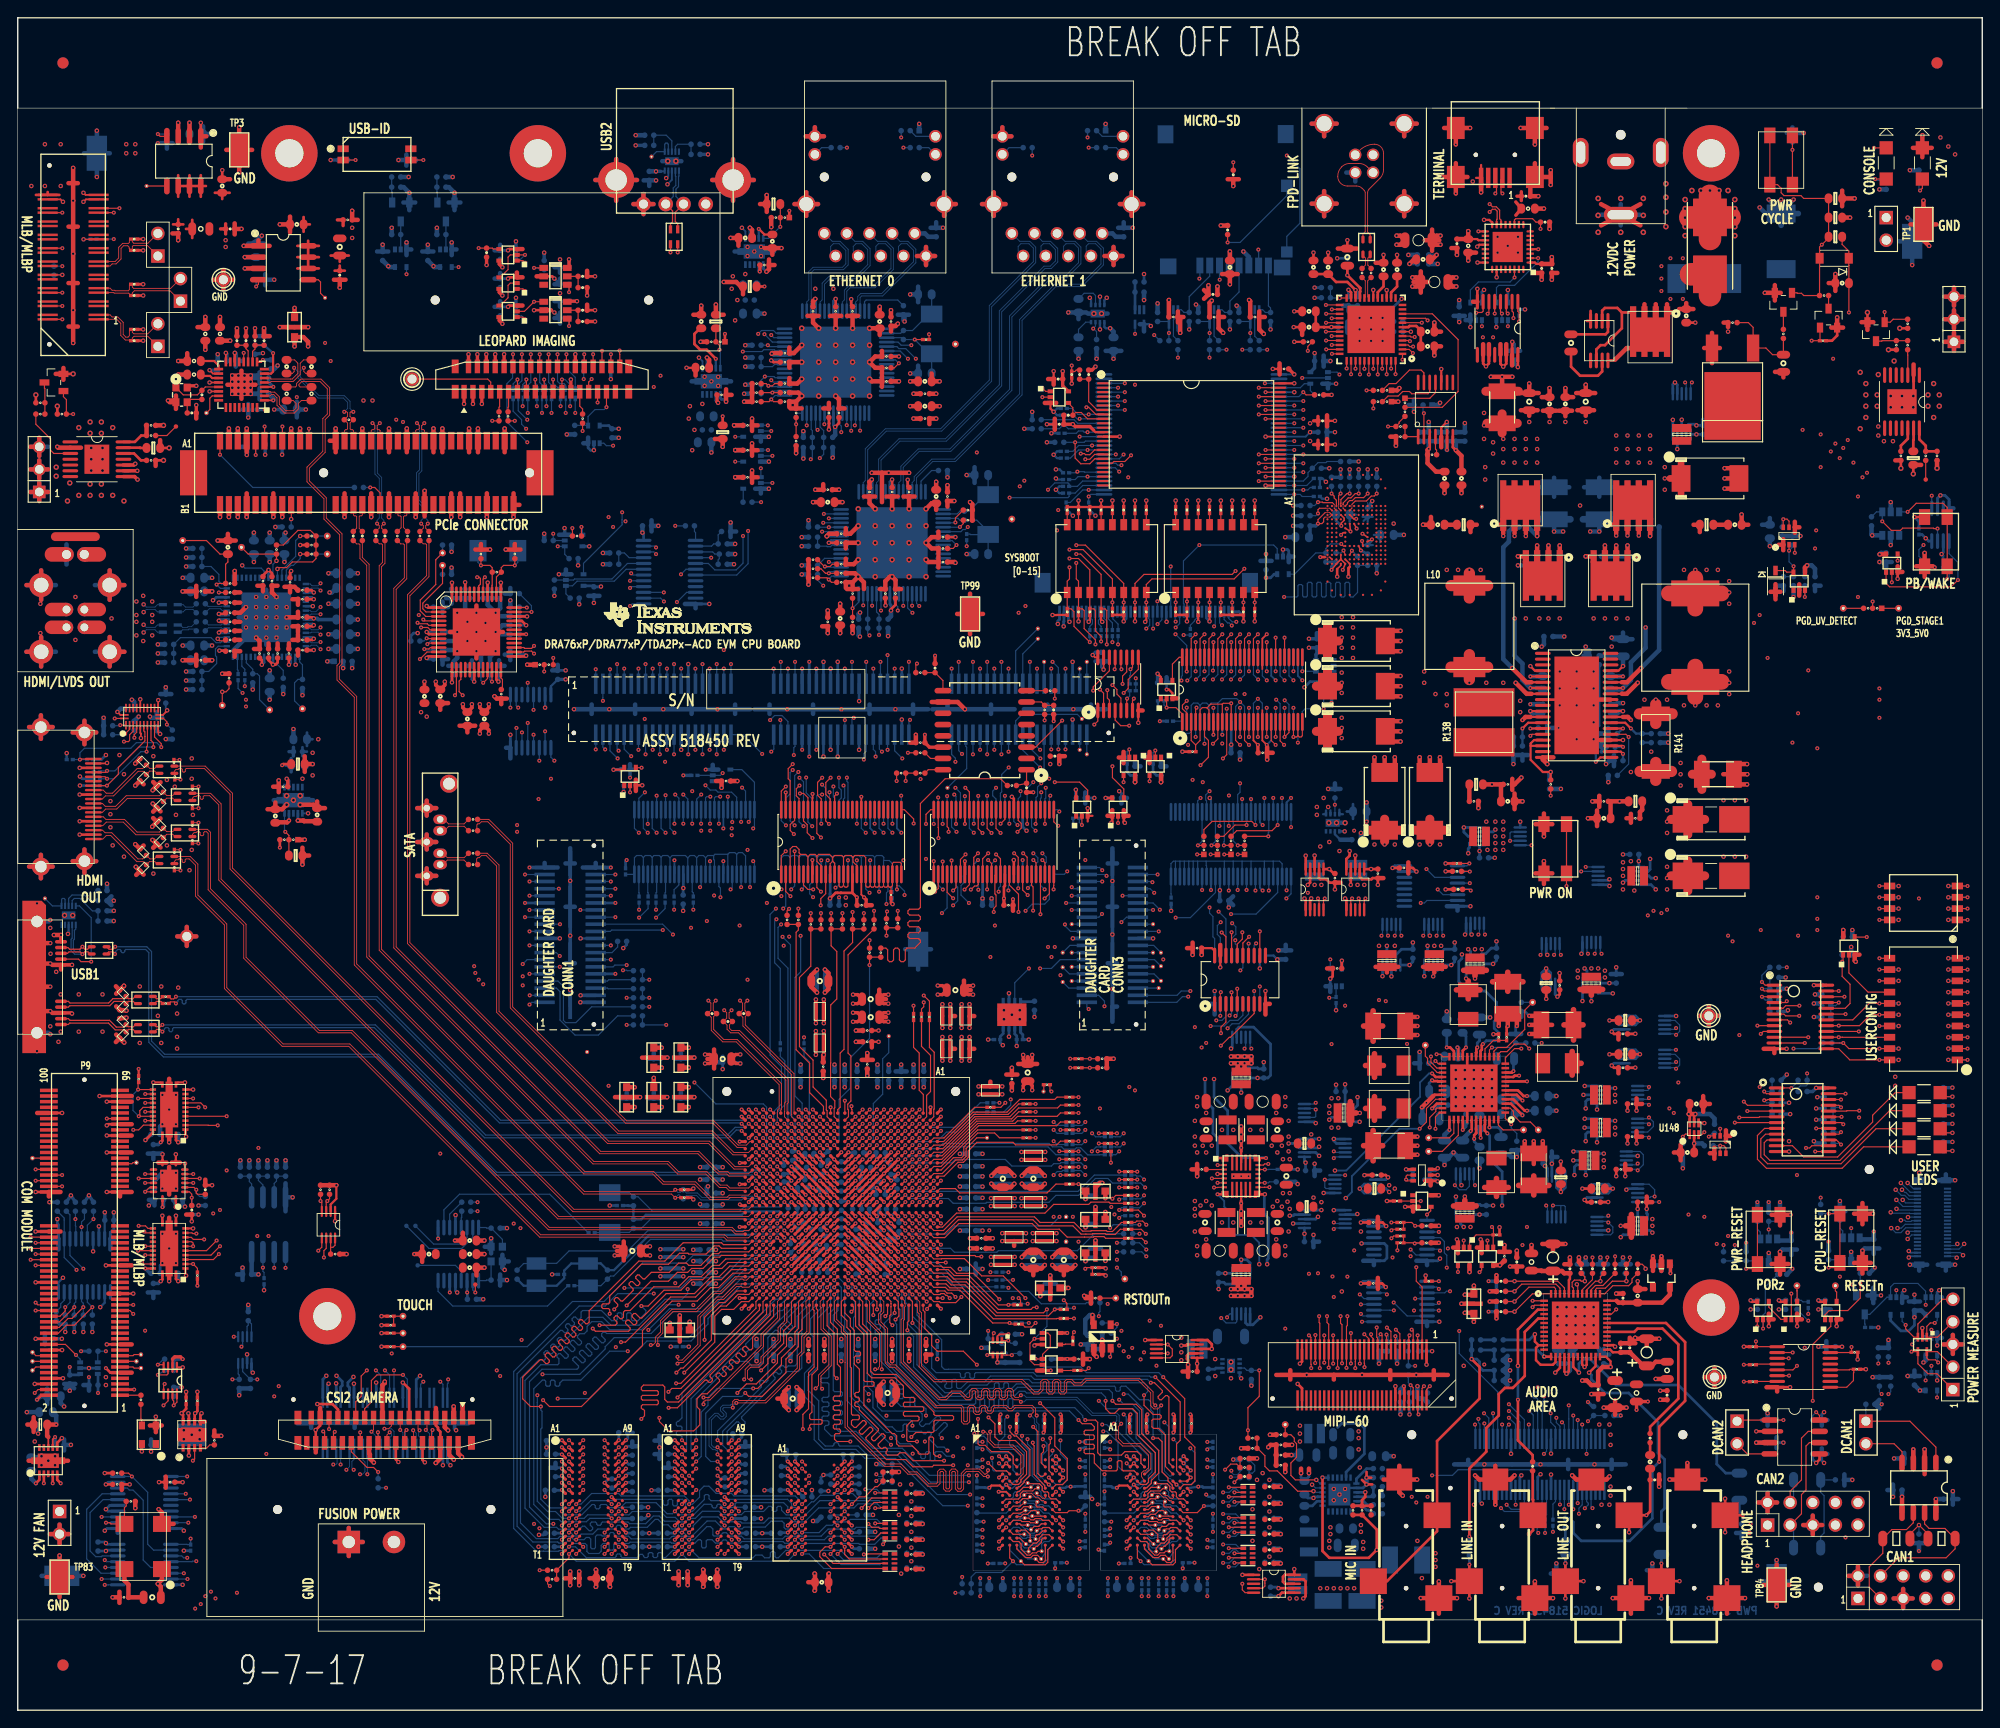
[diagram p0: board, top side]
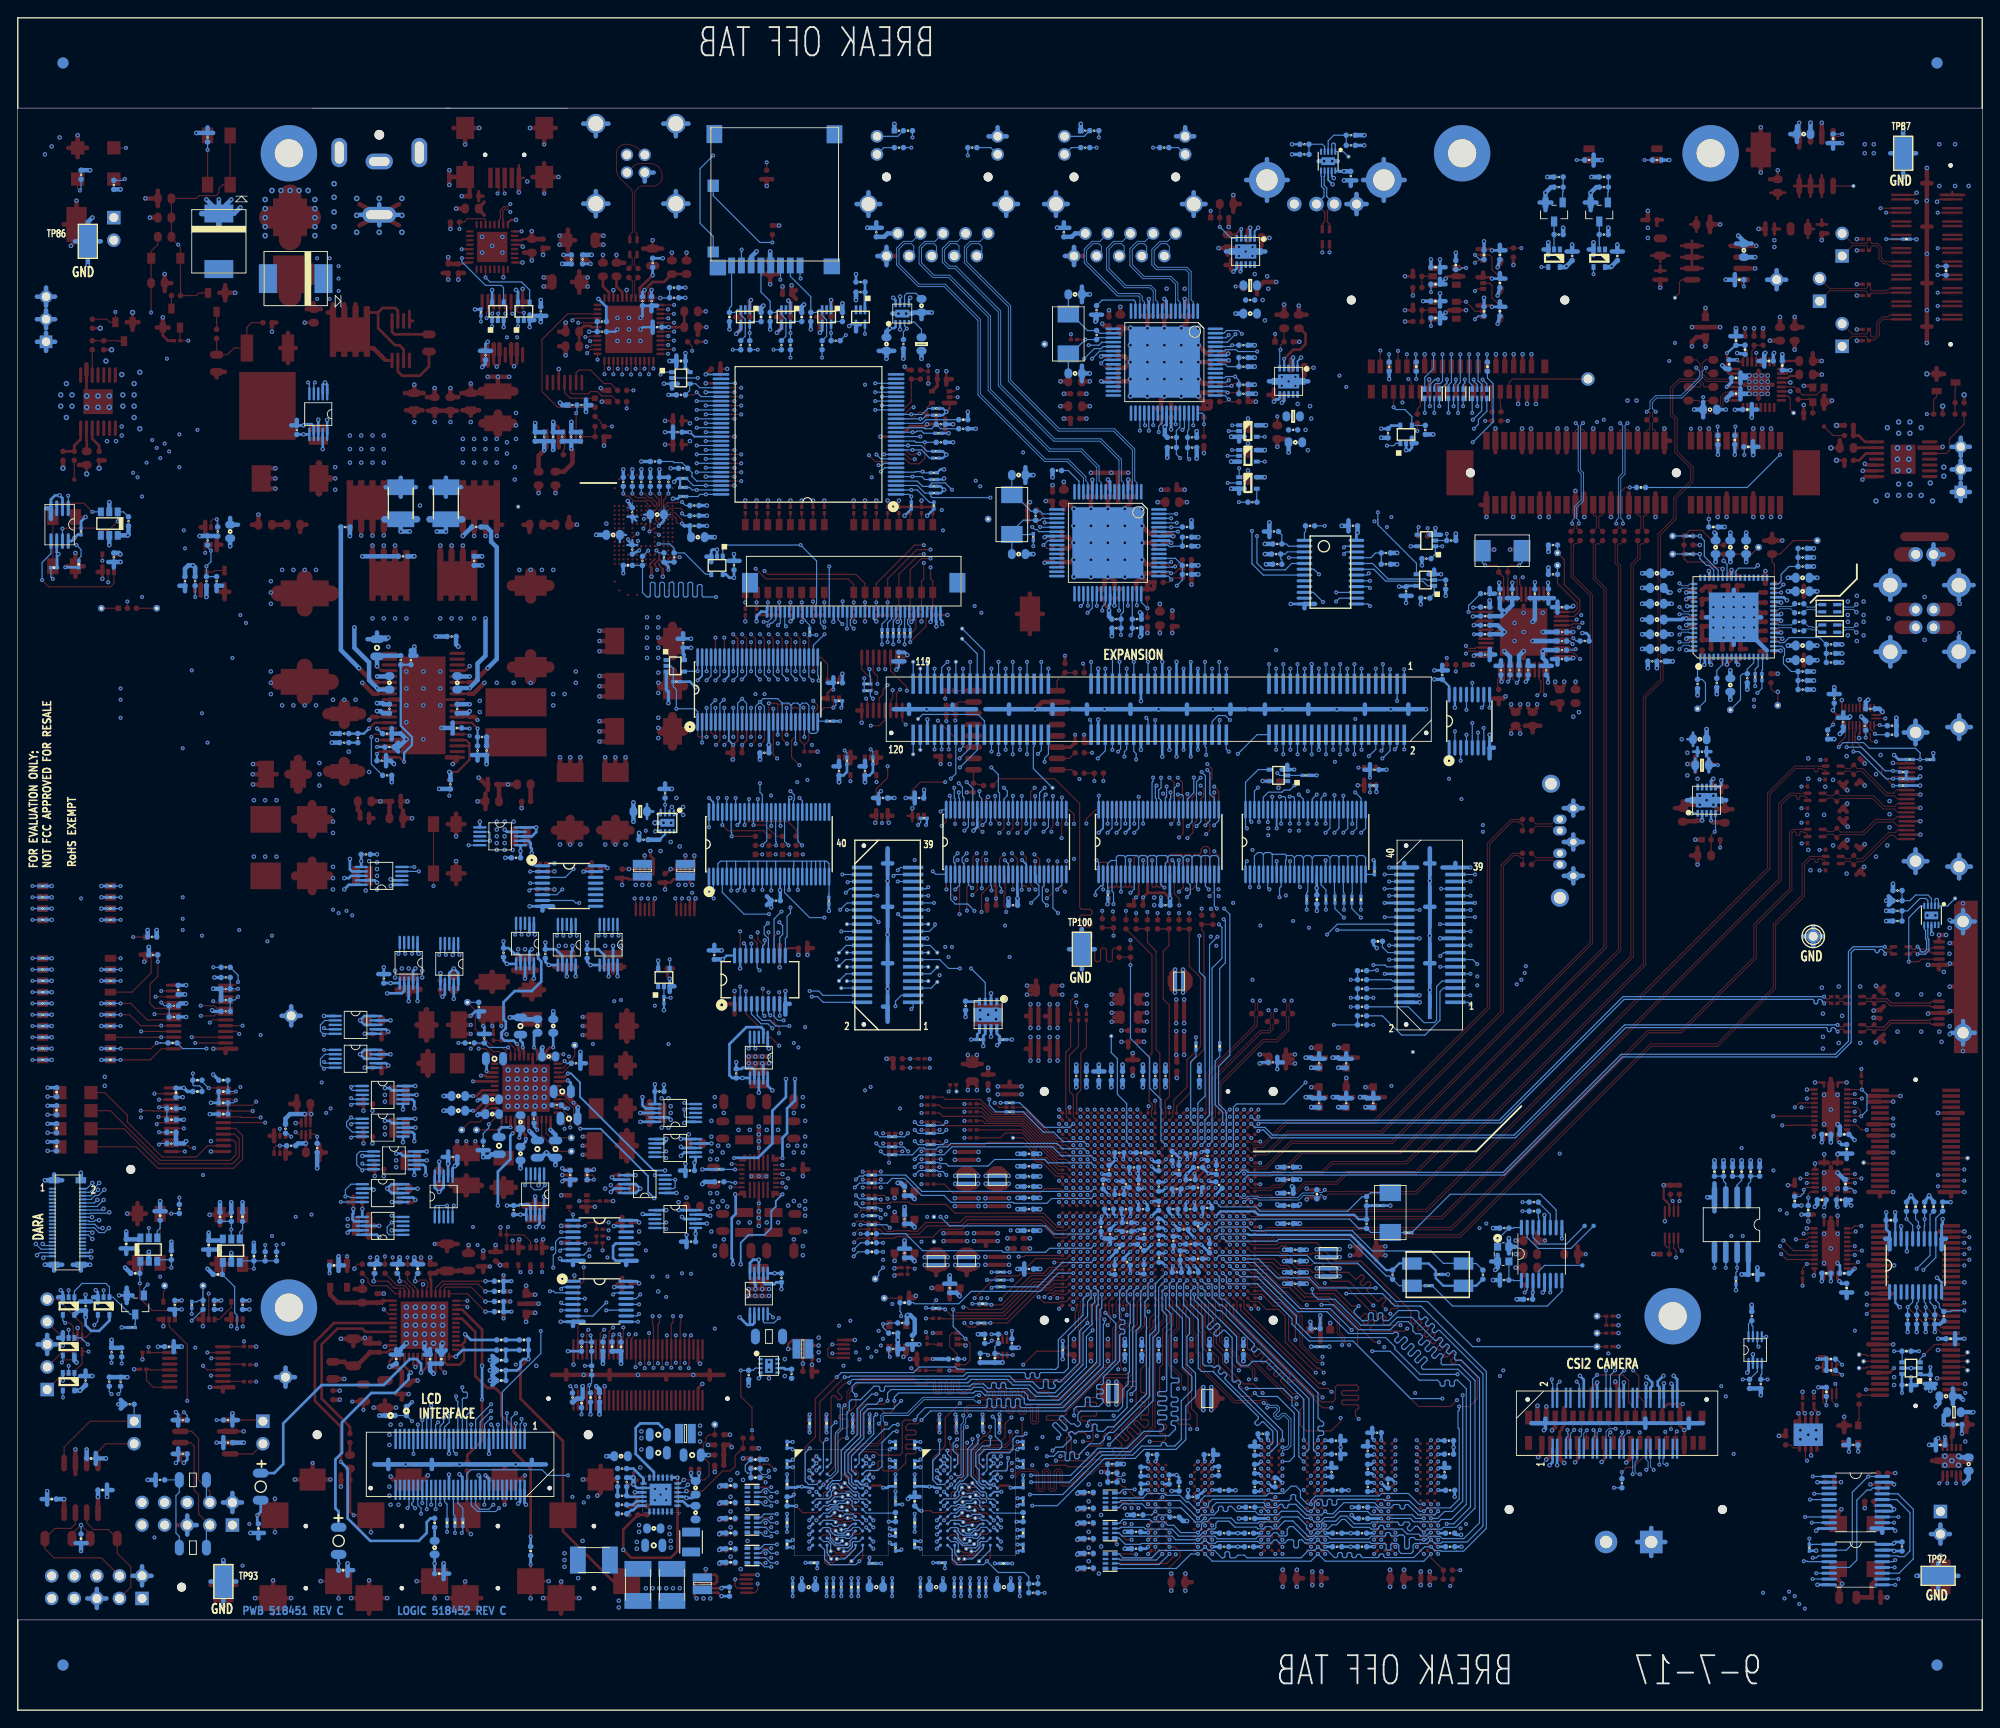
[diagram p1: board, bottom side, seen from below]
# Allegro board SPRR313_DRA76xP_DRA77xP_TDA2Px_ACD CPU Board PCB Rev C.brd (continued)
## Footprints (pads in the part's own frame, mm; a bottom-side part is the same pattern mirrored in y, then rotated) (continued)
JMP402-25
  rect 0.635x0.635 smd: 1(-0.508,0)
  round 0.635 smd: 2(0.508,0) 3(1.524,0)
JUMP1X2-6040
  rect 1.524x1.524 hole 1.016: 1(0,0)
  round 1.524 hole 1.016: 2(0,-2.54)
JUMP1X3-6040
  rect 1.422x1.422 hole 0.965: 1(0,0)
  round 1.422 hole 0.965: 2(2.54,0) 3(5.08,0)
JUMP1X5-6040
  rect 1.524x1.524 hole 1.016: 1(0,0)
  round 1.524 hole 1.016: 2(0,-2.54) 3(0,-5.08) 4(0,-7.62) 5(0,-10.16)
JUMP2X5-6040
  rect 1.524x1.524 hole 1.016: 1(0,0)
  round 1.524 hole 1.016: 2(2.54,0) 3(0,-2.54) 4(2.54,-2.54) 5(0,-5.08) 6(2.54,-5.08) 7(0,-7.62) 8(2.54,-7.62) 9(0,-10.16) 10(2.54,-10.16)
L603-35X45
  oval 0.889x1.143 smd: 1(-0.762,0) 2(0.762,0)
L805-35X60
  oval 0.889x1.524 smd: 1(-0.965,0) 2(0.965,0)
LED1206-59X59
  rect 1.499x1.499 smd: 1(-1.753,0) 2(1.753,0)
MEC6-150-RA1
  round 0.508 hole 1.549 unplated: (0,18.344) (0,-18.344)
  rect 2.007x0.399 smd: 1(-4,17.145) 2(4,17.145) 3(-4,16.51) 4(4,16.51) 5(-4,15.875) 6(4,15.875) 7(-4,15.24) 8(4,15.24) 9(-4,14.605) 10(4,14.605) 11(-4,13.97) 12(4,13.97) 13(-4,13.335) 14(4,13.335) 15(-4,12.7) 16(4,12.7) 17(-4,12.065) 18(4,12.065) 19(-4,11.43) 20(4,11.43) 21(-4,10.795) 22(4,10.795) 23(-4,10.16) 24(4,10.16) 25(-4,9.525) 26(4,9.525) 27(-4,8.89) 28(4,8.89) 29(-4,8.255) 30(4,8.255) 31(-4,7.62) 32(4,7.62) 33(-4,6.985) 34(4,6.985) 35(-4,6.35) 36(4,6.35) 37(-4,5.715) 38(4,5.715) 39(-4,5.08) 40(4,5.08) 41(-4,4.445) 42(4,4.445) 43(-4,3.81) 44(4,3.81) 45(-4,3.175) 46(4,3.175) 47(-4,2.54) 48(4,2.54) 49(-4,1.905) 50(4,1.905) 51(-4,1.27) 52(4,1.27) 53(-4,0.635) 54(4,0.635) 55(-4,0) 56(4,0) 57(-4,-0.635) 58(4,-0.635) 59(-4,-1.27) 60(4,-1.27) 61(-4,-1.905) 62(4,-1.905) 63(-4,-5.715) 64(4,-5.715) 65(-4,-6.35) 66(4,-6.35) 67(-4,-6.985) 68(4,-6.985) 69(-4,-7.62) 70(4,-7.62) 71(-4,-8.255) 72(4,-8.255) 73(-4,-8.89) 74(4,-8.89) 75(-4,-9.525) 76(4,-9.525) 77(-4,-10.16) 78(4,-10.16) 79(-4,-10.795) 80(4,-10.795) 81(-4,-11.43) 82(4,-11.43) 83(-4,-12.065) 84(4,-12.065) 85(-4,-12.7) 86(4,-12.7) 87(-4,-13.335) 88(4,-13.335) 89(-4,-13.97) 90(4,-13.97) 91(-4,-14.605) 92(4,-14.605) 93(-4,-15.24) 94(4,-15.24) 95(-4,-15.875) 96(4,-15.875) 97(-4,-16.51) 98(4,-16.51) 99(-4,-17.145) 100(4,-17.145)
MH62
  round 1.016 hole 2.362 unplated: (0,0)
MH93-125
  round 1.016 hole 2.362 unplated: (0,0)
MHP125-250
  round 6.35 hole 3.175: 1(0,0)
MOLEX-67491-002
  oval 1.067x1.524 hole 0.737: 1(0,0) 2(-1.27,1.508) 3(-2.54,1.508) 4(-3.81,0) 5(-5.08,1.508) 6(-6.35,1.508) 7(-7.62,0)
  round 2.032 hole 1.346: 8(2.464,1.508) 9(-10.363,2.509)
MOLEX-502774-0891
  rect 0.787x1.778 smd: 1(-2.784,7.366) 2(-1.684,7.366) 3(-0.584,7.366) 4(0.516,7.366) 5(1.615,7.366) 6(2.715,7.366) 7(3.815,7.366) 8(4.915,7.366)
  rect 1.295x1.397 smd: 9(6.985,-1.6)
  rect 1.295x1.245 smd: 10(6.985,5.842)
  rect 1.778x2.032 smd: 11(6.858,-7.417) 12(-6.655,-7.391)
  rect 1.854x1.778 smd: 13(-6.35,7.468) 14(6.452,7.595)
OSC4-71X79
  rect 1.803x2.007 smd: 1(-2.54,-2.108) 2(2.54,-2.108) 3(2.54,2.108) 4(-2.54,2.108)
PAP64-12X70
  oval 0.305x1.778 smd: 1(-3.749,-5.74) 2(-3.249,-5.74) 3(-2.749,-5.74) 4(-2.249,-5.74) 5(-1.75,-5.74) 6(-1.25,-5.74) 7(-0.75,-5.74) 8(-0.25,-5.74) 9(0.25,-5.74) 10(0.75,-5.74) 11(1.25,-5.74) 12(1.75,-5.74) 13(2.249,-5.74) 14(2.749,-5.74) 15(3.249,-5.74) 16(3.749,-5.74) 33(3.749,5.74) 34(3.249,5.74) 35(2.749,5.74) 36(2.249,5.74) 37(1.75,5.74) 38(1.25,5.74) 39(0.75,5.74) 40(0.25,5.74) 41(-0.25,5.74) 42(-0.75,5.74) 43(-1.25,5.74) 44(-1.75,5.74) 45(-2.249,5.74) 46(-2.749,5.74) 47(-3.249,5.74) 48(-3.749,5.74)
  oval 1.778x0.305 smd: 17(5.74,-3.749) 18(5.74,-3.249) 19(5.74,-2.749) 20(5.74,-2.249) 21(5.74,-1.75) 22(5.74,-1.25) 23(5.74,-0.75) 24(5.74,-0.25) 25(5.74,0.25) 26(5.74,0.75) 27(5.74,1.25) 28(5.74,1.75) 29(5.74,2.249) 30(5.74,2.749) 31(5.74,3.249) 32(5.74,3.749) 49(-5.74,3.749) 50(-5.74,3.249) 51(-5.74,2.749) 52(-5.74,2.249) 53(-5.74,1.75) 54(-5.74,1.25) 55(-5.74,0.75) 56(-5.74,0.25) 57(-5.74,-0.25) 58(-5.74,-0.75) 59(-5.74,-1.25) 60(-5.74,-1.75) 61(-5.74,-2.249) 62(-5.74,-2.749) 63(-5.74,-3.249) 64(-5.74,-3.749)
  rect 8.001x8.001 smd: 65(0,0)
PCIE_SMT_64
  rect 5.08x3.048 smd: (0,14.622) (0,-24.331)
  round 1.016 hole 1.194 unplated: (0,0) (0,-23.151)
  rect 1.981x0.711 smd: A1(3.607,11.65) A2(3.607,10.65) A3(3.607,9.65) A4(3.607,8.65) A5(3.607,7.65) A6(3.607,6.65) A7(3.607,5.65) A8(3.607,4.65) A9(3.607,3.65) A10(3.607,2.65) A11(3.607,1.65) A12(3.607,-1.35) A13(3.607,-2.35) A14(3.607,-3.35) A15(3.607,-4.35) A16(3.607,-5.35) A17(3.607,-6.35) A18(3.607,-7.35) A19(3.607,-8.35) A20(3.607,-9.35) A21(3.607,-10.35) A22(3.607,-11.35) A23(3.607,-12.35) A24(3.607,-13.35) A25(3.607,-14.35) A26(3.607,-15.35) A27(3.607,-16.35) A28(3.607,-17.35) A29(3.607,-18.35) A30(3.607,-19.35) A31(3.607,-20.35) A32(3.607,-21.35) B1(-3.607,11.65) B2(-3.607,10.65) B3(-3.607,9.65) B4(-3.607,8.65) B5(-3.607,7.65) B6(-3.607,6.65) B7(-3.607,5.65) B8(-3.607,4.65) B9(-3.607,3.65) B10(-3.607,2.65) B11(-3.607,1.65) B12(-3.607,-1.35) B13(-3.607,-2.35) B14(-3.607,-3.35) B15(-3.607,-4.35) B16(-3.607,-5.35) B17(-3.607,-6.35) B18(-3.607,-7.35) B19(-3.607,-8.35) B20(-3.607,-9.35) B21(-3.607,-10.35) B22(-3.607,-11.35) B23(-3.607,-12.35) B24(-3.607,-13.35) B25(-3.607,-14.35) B26(-3.607,-15.35) B27(-3.607,-16.35) B28(-3.607,-17.35) B29(-3.607,-18.35) B30(-3.607,-19.35) B31(-3.607,-20.35) B32(-3.607,-21.35)
PHP48-12X70
  oval 0.305x1.778 smd: 1(-2.748,-4.242) 2(-2.25,-4.242) 3(-1.75,-4.242) 4(-1.25,-4.242) 5(-0.749,-4.242) 6(-0.249,-4.242) 7(0.249,-4.242) 8(0.749,-4.242) 9(1.25,-4.242) 10(1.75,-4.242) 11(2.25,-4.242) 12(2.748,-4.242) 25(2.748,4.242) 26(2.25,4.242) 27(1.75,4.242) 28(1.25,4.242) 29(0.749,4.242) 30(0.249,4.242) 31(-0.249,4.242) 32(-0.749,4.242) 33(-1.25,4.242) 34(-1.75,4.242) 35(-2.25,4.242) 36(-2.748,4.242)
  oval 1.778x0.305 smd: 13(4.242,-2.748) 14(4.242,-2.25) 15(4.242,-1.75) 16(4.242,-1.25) 17(4.242,-0.749) 18(4.242,-0.249) 19(4.242,0.249) 20(4.242,0.749) 21(4.242,1.25) 22(4.242,1.75) 23(4.242,2.25) 24(4.242,2.748) 37(-4.242,2.748) 38(-4.242,2.25) 39(-4.242,1.75) 40(-4.242,1.25) 41(-4.242,0.749) 42(-4.242,0.249) 43(-4.242,-0.249) 44(-4.242,-0.749) 45(-4.242,-1.25) 46(-4.242,-1.75) 47(-4.242,-2.25) 48(-4.242,-2.748)
  rect 5.334x5.334 smd: 49(0,0)
PW14-12X70
  oval 0.305x1.778 smd: 1(-1.951,-3.048) 2(-1.3,-3.048) 3(-0.65,-3.048) 4(0,-3.048) 5(0.65,-3.048) 6(1.3,-3.048) 7(1.951,-3.048) 8(1.951,3.048) 9(1.3,3.048) 10(0.65,3.048) 11(0,3.048) 12(-0.65,3.048) 13(-1.3,3.048) 14(-1.951,3.048)
PW16-14X70
  oval 0.356x1.778 smd: 1(-2.276,-2.987) 2(-1.626,-2.987) 3(-0.975,-2.987) 4(-0.325,-2.987) 5(0.325,-2.987) 6(0.975,-2.987) 7(1.626,-2.987) 8(2.276,-2.987) 9(2.276,2.987) 10(1.626,2.987) 11(0.975,2.987) 12(0.325,2.987) 13(-0.325,2.987) 14(-0.975,2.987) 15(-1.626,2.987) 16(-2.276,2.987)
PW20-14X70
  oval 0.356x1.778 smd: 1(-2.926,-2.987) 2(-2.276,-2.987) 3(-1.626,-2.987) 4(-0.975,-2.987) 5(-0.325,-2.987) 6(0.325,-2.987) 7(0.975,-2.987) 8(1.626,-2.987) 9(2.276,-2.987) 10(2.926,-2.987) 11(2.926,2.987) 12(2.276,2.987) 13(1.626,2.987) 14(0.975,2.987) 15(0.325,2.987) 16(-0.325,2.987) 17(-0.975,2.987) 18(-1.626,2.987) 19(-2.276,2.987) 20(-2.926,2.987)
PW24-14X70
  oval 0.356x1.778 smd: 1(-3.576,-2.921) 2(-2.926,-2.921) 3(-2.276,-2.921) 4(-1.626,-2.921) 5(-0.975,-2.921) 6(-0.325,-2.921) 7(0.325,-2.921) 8(0.975,-2.921) 9(1.626,-2.921) 10(2.276,-2.921) 11(2.926,-2.921) 12(3.576,-2.921) 13(3.576,2.921) 14(2.926,2.921) 15(2.276,2.921) 16(1.626,2.921) 17(0.975,2.921) 18(0.325,2.921) 19(-0.325,2.921) 20(-0.975,2.921) 21(-1.626,2.921) 22(-2.276,2.921) 23(-2.926,2.921) 24(-3.576,2.921)
PWP14-14X70-PAD
  oval 0.356x1.778 smd: 1(-1.951,-2.987) 2(-1.3,-2.987) 3(-0.65,-2.987) 4(0,-2.987) 5(0.65,-2.987) 6(1.3,-2.987) 7(1.951,-2.987) 8(1.951,2.987) 9(1.3,2.987) 10(0.65,2.987) 11(0,2.987) 12(-0.65,2.987) 13(-1.3,2.987) 14(-1.951,2.987)
  rect 3.302x2.794 smd: 15(0,0)
PWR-Q5A-SLPS319
  rect 0.711x1.397 smd: 1(-1.905,0) 2(-0.635,0) 3(0.635,0) 4(1.905,0)
  custom 1.111x1.111 smd: 5(0,2.781)
PWRJACK-CUI-PJ063BH
  round 1.092 hole 1.6 unplated: (0,-3)
  oval 3.81x1.778 hole 2.997x1.016: 1(0,-12)
  oval 3.073x1.778 hole 2.311x1.016: 2(0,-6)
  oval 1.778x3.302 hole 1.016x2.489: MTG1(-4.5,-5) MTG2(4.5,-5)
QFN32_5X5
  oval 0.254x0.838 smd: 1(-1.753,-2.515) 8(1.753,-2.515) 17(1.753,2.515) 24(-1.753,2.515)
  rect 0.254x0.838 smd: 2(-1.252,-2.515) 3(-0.752,-2.515) 4(-0.251,-2.515) 5(0.251,-2.515) 6(0.752,-2.515) 7(1.252,-2.515) 18(1.252,2.515) 19(0.752,2.515) 20(0.251,2.515) 21(-0.251,2.515) 22(-0.752,2.515) 23(-1.252,2.515)
  oval 0.838x0.254 smd: 9(2.515,-1.753) 16(2.515,1.753) 25(-2.515,1.753) 32(-2.515,-1.753)
  rect 0.838x0.254 smd: 10(2.515,-1.252) 11(2.515,-0.752) 12(2.515,-0.251) 13(2.515,0.251) 14(2.515,0.752) 15(2.515,1.252) 26(-2.515,1.252) 27(-2.515,0.752) 28(-2.515,0.251) 29(-2.515,-0.251) 30(-2.515,-0.752) 31(-2.515,-1.252)
  rect 3.404x3.404 smd: 33(0,0)
QFN32_202SQ
  rect 0.305x1.016 smd: 1(-1.753,-2.565) 2(-1.252,-2.565) 3(-0.752,-2.565) 4(-0.251,-2.565) 5(0.251,-2.565) 6(0.752,-2.565) 7(1.252,-2.565) 8(1.753,-2.565) 17(1.753,2.565) 18(1.252,2.565) 19(0.752,2.565) 20(0.251,2.565) 21(-0.251,2.565) 22(-0.752,2.565) 23(-1.252,2.565) 24(-1.753,2.565)
  rect 1.016x0.305 smd: 9(2.565,-1.753) 10(2.565,-1.252) 11(2.565,-0.752) 12(2.565,-0.251) 13(2.565,0.251) 14(2.565,0.752) 15(2.565,1.252) 16(2.565,1.753) 25(-2.565,1.753) 26(-2.565,1.252) 27(-2.565,0.752) 28(-2.565,0.251) 29(-2.565,-0.251) 30(-2.565,-0.752) 31(-2.565,-1.252) 32(-2.565,-1.753)
  rect 2.54x2.54 smd: 33(0,0)
QSE-060-0X-X-D-A
  round 0.508 hole 1.016 unplated: (-30.069,2.667) (30.069,2.667)
  rect 0.406x2.286 smd: 1(-27.605,-2.865) 2(-27.605,2.865) 3(-26.805,-2.865) 4(-26.805,2.865) 5(-26.005,-2.865) 6(-26.005,2.865) 7(-25.204,-2.865) 8(-25.204,2.865) 9(-24.404,-2.865) 10(-24.404,2.865) 11(-23.604,-2.865) 12(-23.604,2.865) 13(-22.804,-2.865) 14(-22.804,2.865) 15(-22.004,-2.865) 16(-22.004,2.865) 17(-21.204,-2.865) 18(-21.204,2.865) 19(-20.404,-2.865) 20(-20.404,2.865) 21(-19.604,-2.865) 22(-19.604,2.865) 23(-18.804,-2.865) 24(-18.804,2.865) 25(-18.004,-2.865) 26(-18.004,2.865) 27(-17.203,-2.865) 28(-17.203,2.865) 29(-16.403,-2.865) 30(-16.403,2.865) 31(-15.603,-2.865) 32(-15.603,2.865) 33(-14.803,-2.865) 34(-14.803,2.865) 35(-14.003,-2.865) 36(-14.003,2.865) 37(-13.203,-2.865) 38(-13.203,2.865) 39(-12.403,-2.865) 40(-12.403,2.865) 41(-7.602,-2.865) 42(-7.602,2.865) 43(-6.802,-2.865) 44(-6.802,2.865) 45(-6.002,-2.865) 46(-6.002,2.865) 47(-5.202,-2.865) 48(-5.202,2.865) 49(-4.402,-2.865) 50(-4.402,2.865) 51(-3.602,-2.865) 52(-3.602,2.865) 53(-2.802,-2.865) 54(-2.802,2.865) 55(-2.002,-2.865) 56(-2.002,2.865) 57(-1.201,-2.865) 58(-1.201,2.865) 59(-0.401,-2.865) 60(-0.401,2.865) 61(0.401,-2.865) 62(0.401,2.865) 63(1.201,-2.865) 64(1.201,2.865) 65(2.002,-2.865) 66(2.002,2.865) 67(2.802,-2.865) 68(2.802,2.865) 69(3.602,-2.865) 70(3.602,2.865) 71(4.402,-2.865) 72(4.402,2.865) 73(5.202,-2.865) 74(5.202,2.865) 75(6.002,-2.865) 76(6.002,2.865) 77(6.802,-2.865) 78(6.802,2.865) 79(7.602,-2.865) 80(7.602,2.865) 81(12.403,-2.865) 82(12.403,2.865) 83(13.203,-2.865) 84(13.203,2.865) 85(14.003,-2.865) 86(14.003,2.865) 87(14.803,-2.865) 88(14.803,2.865) 89(15.603,-2.865) 90(15.603,2.865) 91(16.403,-2.865) 92(16.403,2.865) 93(17.203,-2.865) 94(17.203,2.865) 95(18.004,-2.865) 96(18.004,2.865) 97(18.804,-2.865) 98(18.804,2.865) 99(19.604,-2.865) 100(19.604,2.865) 101(20.404,-2.865) 102(20.404,2.865) 103(21.204,-2.865) 104(21.204,2.865) 105(22.004,-2.865) 106(22.004,2.865) 107(22.804,-2.865) 108(22.804,2.865) 109(23.604,-2.865) 110(23.604,2.865) 111(24.404,-2.865) 112(24.404,2.865) 113(25.204,-2.865) 114(25.204,2.865) 115(26.005,-2.865) 116(26.005,2.865) 117(26.805,-2.865) 118(26.805,2.865) 119(27.605,-2.865) 120(27.605,2.865)
  rect 2.794x0.432 smd: 121(-28.067,0) 124(-11.938,0) 125(-8.065,0) 128(8.067,0) 129(11.941,0) 132(28.07,0)
  rect 4.699x0.432 smd: 122(-23.177,0) 123(-16.828,0) 126(-3.175,0) 127(3.178,0) 130(16.83,0) 131(23.18,0)
QSE_020
  round 0.508 hole 1.041 unplated: (-10.058,-2.667) (10.058,-2.667)
  rect 0.406x2.286 smd: 1(7.569,2.87) 2(7.569,-2.87) 3(6.782,2.87) 4(6.782,-2.87) 5(5.969,2.87) 6(5.969,-2.87) 7(5.182,2.87) 8(5.182,-2.87) 9(4.369,2.87) 10(4.369,-2.87) 11(3.581,2.87) 12(3.581,-2.87) 13(2.769,2.87) 14(2.769,-2.87) 15(1.981,2.87) 16(1.981,-2.87) 17(1.168,2.87) 18(1.168,-2.87) 19(0.381,2.87) 20(0.381,-2.87) 21(-0.406,2.87) 22(-0.406,-2.87) 23(-1.219,2.87) 24(-1.219,-2.87) 25(-2.007,2.87) 26(-2.007,-2.87) 27(-2.819,2.87) 28(-2.819,-2.87) 29(-3.607,2.87) 30(-3.607,-2.87) 31(-4.42,2.87) 32(-4.42,-2.87) 33(-5.207,2.87) 34(-5.207,-2.87) 35(-6.02,2.87) 36(-6.02,-2.87) 37(-6.807,2.87) 38(-6.807,-2.87) 39(-7.595,2.87) 40(-7.595,-2.87)
  rect 2.794x0.432 smd: 41(-8.052,0) 44(8.052,0)
  rect 4.699x0.432 smd: 42(-3.175,0) 43(3.175,0)
QSH-020-DP-A
  round 0.508 hole 1.016 unplated: (-10.061,2.667) (10.061,2.667)
  rect 0.279x2.273 smd: 1(-7.249,-2.865) 2(-7.249,2.865) 3(-6.749,-2.865) 4(-6.749,2.865) 5(-5.748,-2.865) 6(-5.748,2.865) 7(-5.248,-2.865) 8(-5.248,2.865) 9(-4.249,-2.865) 10(-4.249,2.865) 11(-3.749,-2.865) 12(-3.749,2.865) 13(-2.748,-2.865) 14(-2.748,2.865) 15(-2.25,-2.865) 16(-2.25,2.865) 17(-1.25,-2.865) 18(-1.25,2.865) 19(-0.749,-2.865) 20(-0.749,2.865) 21(0.249,-2.865) 22(0.249,2.865) 23(0.749,-2.865) 24(0.749,2.865) 25(1.75,-2.865) 26(1.75,2.865) 27(2.25,-2.865) 28(2.25,2.865) 29(3.249,-2.865) 30(3.249,2.865) 31(3.749,-2.865) 32(3.749,2.865) 33(4.75,-2.865) 34(4.75,2.865) 35(5.248,-2.865) 36(5.248,2.865) 37(6.248,-2.865) 38(6.248,2.865) 39(6.749,-2.865) 40(6.749,2.865)
  rect 2.54x0.432 smd: 41(-8.065,0) 44(8.065,0)
  rect 4.699x0.432 smd: 42(-3.175,0) 43(3.175,0)
QSH-020-DP-A#2
  round 0.508 hole 1.016 unplated: (-10.06,2.667) (10.06,2.667)
  rect 0.279x2.273 smd: 1(-7.248,-2.864) 2(-7.248,2.864) 3(-6.748,-2.864) 4(-6.748,2.864) 5(-5.749,-2.864) 6(-5.749,2.864) 7(-5.249,-2.864) 8(-5.249,2.864) 9(-4.249,-2.864) 10(-4.249,2.864) 11(-3.749,-2.864) 12(-3.749,2.864) 13(-2.749,-2.864) 14(-2.749,2.864) 15(-2.249,-2.864) 16(-2.249,2.864) 17(-1.25,-2.864) 18(-1.25,2.864) 19(-0.75,-2.864) 20(-0.75,2.864) 21(0.25,-2.864) 22(0.25,2.864) 23(0.75,-2.864) 24(0.75,2.864) 25(1.75,-2.864) 26(1.75,2.864) 27(2.249,-2.864) 28(2.249,2.864) 29(3.249,-2.864) 30(3.249,2.864) 31(3.749,-2.864) 32(3.749,2.864) 33(4.749,-2.864) 34(4.749,2.864) 35(5.249,-2.864) 36(5.249,2.864) 37(6.248,-2.864) 38(6.248,2.864) 39(6.748,-2.864) 40(6.748,2.864)
  rect 2.54x0.432 smd: 41(-8.065,0) 44(8.065,0)
  rect 4.699x0.432 smd: 42(-3.175,0) 43(3.175,0)
QSH-030-01-F
  round 0.508 hole 1.016 unplated: (-10.061,2.667) (10.061,2.667)
  rect 0.279x2.273 smd: 1(-7.249,-2.865) 2(-7.249,2.865) 3(-6.749,-2.865) 4(-6.749,2.865) 5(-6.248,-2.865) 6(-6.248,2.865) 7(-5.748,-2.865) 8(-5.748,2.865) 9(-5.248,-2.865) 10(-5.248,2.865) 11(-4.75,-2.865) 12(-4.75,2.865) 13(-4.249,-2.865) 14(-4.249,2.865) 15(-3.749,-2.865) 16(-3.749,2.865) 17(-3.249,-2.865) 18(-3.249,2.865) 19(-2.748,-2.865) 20(-2.748,2.865) 21(-2.25,-2.865) 22(-2.25,2.865) 23(-1.75,-2.865) 24(-1.75,2.865) 25(-1.25,-2.865) 26(-1.25,2.865) 27(-0.749,-2.865) 28(-0.749,2.865) 29(-0.249,-2.865) 30(-0.249,2.865) 31(0.249,-2.865) 32(0.249,2.865) 33(0.749,-2.865) 34(0.749,2.865) 35(1.25,-2.865) 36(1.25,2.865) 37(1.75,-2.865) 38(1.75,2.865) 39(2.25,-2.865) 40(2.25,2.865) 41(2.748,-2.865) 42(2.748,2.865) 43(3.249,-2.865) 44(3.249,2.865) 45(3.749,-2.865) 46(3.749,2.865) 47(4.249,-2.865) 48(4.249,2.865) 49(4.75,-2.865) 50(4.75,2.865) 51(5.248,-2.865) 52(5.248,2.865) 53(5.748,-2.865) 54(5.748,2.865) 55(6.248,-2.865) 56(6.248,2.865) 57(6.749,-2.865) 58(6.749,2.865) 59(7.249,-2.865) 60(7.249,2.865)
  rect 2.54x0.432 smd: 61(-8.065,0) 64(8.065,0)
  rect 4.699x0.432 smd: 62(-3.175,0) 63(3.175,0)
R201-6P6SPC
  rect 0.47x0.381 smd: 1(-0.343,0) 2(0.343,0)
R402-25
  round 0.635 smd: 1(-0.508,0) 2(0.508,0)
R0508
  rect 2.184x0.914 smd: 1(0,0.711) 2(0,-0.711)
R603-35X45
  oval 0.889x1.143 smd: 1(-0.762,0) 2(0.762,0)
R1206-40X70
  oval 1.016x1.778 smd: 1(-1.524,0) 2(1.524,0)
R2512
  rect 1.651x3.175 smd: 1(-3.239,0) 2(3.239,0)
R2725-125X250
  rect 3.175x6.858 smd: 1(-2.248,0) 2(2.248,0)
RGC64-11X28
  rect 0.711x0.279 smd: 1(-4.445,3.749) 2(-4.445,3.249) 3(-4.445,2.749) 4(-4.445,2.249) 5(-4.445,1.75) 6(-4.445,1.25) 7(-4.445,0.75) 8(-4.445,0.25) 9(-4.445,-0.25) 10(-4.445,-0.75) 11(-4.445,-1.25) 12(-4.445,-1.75) 13(-4.445,-2.249) 14(-4.445,-2.749) 15(-4.445,-3.249) 16(-4.445,-3.749) 33(4.445,-3.749) 34(4.445,-3.249) 35(4.445,-2.749) 36(4.445,-2.249) 37(4.445,-1.75) 38(4.445,-1.25) 39(4.445,-0.75) 40(4.445,-0.25) 41(4.445,0.25) 42(4.445,0.75) 43(4.445,1.25) 44(4.445,1.75) 45(4.445,2.249) 46(4.445,2.749) 47(4.445,3.249) 48(4.445,3.749)
  rect 0.279x0.711 smd: 17(-3.749,-4.445) 18(-3.249,-4.445) 19(-2.749,-4.445) 20(-2.249,-4.445) 21(-1.75,-4.445) 22(-1.25,-4.445) 23(-0.75,-4.445) 24(-0.25,-4.445) 25(0.25,-4.445) 26(0.75,-4.445) 27(1.25,-4.445) 28(1.75,-4.445) 29(2.249,-4.445) 30(2.749,-4.445) 31(3.249,-4.445) 32(3.749,-4.445) 49(3.749,4.445) 50(3.249,4.445) 51(2.749,4.445) 52(2.249,4.445) 53(1.75,4.445) 54(1.25,4.445) 55(0.75,4.445) 56(0.25,4.445) 57(-0.25,4.445) 58(-0.75,4.445) 59(-1.25,4.445) 60(-1.75,4.445) 61(-2.249,4.445) 62(-2.749,4.445) 63(-3.249,4.445) 64(-3.749,4.445)
  rect 5.588x5.588 smd: 65(0,0)
RGE24-11X28-4MM
  rect 0.711x0.279 smd: 1(-1.905,1.245) 2(-1.905,0.747) 3(-1.905,0.249) 4(-1.905,-0.249) 5(-1.905,-0.747) 6(-1.905,-1.245) 13(1.905,-1.245) 14(1.905,-0.747) 15(1.905,-0.249) 16(1.905,0.249) 17(1.905,0.747) 18(1.905,1.245)
  rect 0.279x0.711 smd: 7(-1.245,-1.905) 8(-0.747,-1.905) 9(-0.249,-1.905) 10(0.249,-1.905) 11(0.747,-1.905) 12(1.245,-1.905) 19(1.245,1.905) 20(0.747,1.905) 21(0.249,1.905) 22(-0.249,1.905) 23(-0.747,1.905) 24(-1.245,1.905)
  rect 2.464x2.464 smd: 25(0,0)
RGY16-12X34
  oval 0.864x0.305 smd: 1(-2.032,-0.749) 8(2.032,-0.749) 9(2.032,0.749) 16(-2.032,0.749)
  oval 0.305x0.864 smd: 2(-1.252,-1.765) 3(-0.752,-1.765) 4(-0.251,-1.765) 5(0.249,-1.765) 6(0.749,-1.765) 7(1.25,-1.765) 10(1.25,1.765) 11(0.749,1.765) 12(0.249,1.765) 13(-0.251,1.765) 14(-0.752,1.765) 15(-1.252,1.765)
  rect 2.489x2.032 smd: 17(0,0)
RGZ48-11X34
  rect 0.279x0.864 smd: 1(-2.748,-3.531) 2(-2.25,-3.531) 3(-1.75,-3.531) 4(-1.25,-3.531) 5(-0.749,-3.531) 6(-0.249,-3.531) 7(0.249,-3.531) 8(0.749,-3.531) 9(1.25,-3.531) 10(1.75,-3.531) 11(2.25,-3.531) 12(2.748,-3.531) 25(2.748,3.531) 26(2.25,3.531) 27(1.75,3.531) 28(1.25,3.531) 29(0.749,3.531) 30(0.249,3.531) 31(-0.249,3.531) 32(-0.749,3.531) 33(-1.25,3.531) 34(-1.75,3.531) 35(-2.25,3.531) 36(-2.748,3.531)
  rect 0.864x0.279 smd: 13(3.531,-2.748) 14(3.531,-2.25) 15(3.531,-1.75) 16(3.531,-1.25) 17(3.531,-0.749) 18(3.531,-0.249) 19(3.531,0.249) 20(3.531,0.749) 21(3.531,1.25) 22(3.531,1.75) 23(3.531,2.25) 24(3.531,2.748) 37(-3.531,2.748) 38(-3.531,2.25) 39(-3.531,1.75) 40(-3.531,1.25) 41(-3.531,0.749) 42(-3.531,0.249) 43(-3.531,-0.249) 44(-3.531,-0.749) 45(-3.531,-1.25) 46(-3.531,-1.75) 47(-3.531,-2.25) 48(-3.531,-2.748)
  rect 5.334x5.334 smd: 49(0,0)
RHL24-PVQFN-TI
  rect 0.711x0.305 smd: 1(-2.819,-0.762) 12(2.819,-0.762) 13(2.819,0.762) 24(-2.819,0.762)
  rect 0.305x0.711 smd: 2(-2.25,-1.829) 3(-1.75,-1.829) 4(-1.25,-1.829) 5(-0.749,-1.829) 6(-0.249,-1.829) 7(0.249,-1.829) 8(0.749,-1.829) 9(1.25,-1.829) 10(1.75,-1.829) 11(2.25,-1.829) 14(2.25,1.829) 15(1.75,1.829) 16(1.25,1.829) 17(0.749,1.829) 18(0.249,1.829) 19(-0.249,1.829) 20(-0.749,1.829) 21(-1.25,1.829) 22(-1.75,1.829) 23(-2.25,1.829)
  custom 0.508x0.508 smd: 25(0,0)
RHS48-11X34
  rect 0.279x0.864 smd: 1(-2.748,-3.531) 2(-2.25,-3.531) 3(-1.75,-3.531) 4(-1.25,-3.531) 5(-0.749,-3.531) 6(-0.249,-3.531) 7(0.249,-3.531) 8(0.749,-3.531) 9(1.25,-3.531) 10(1.75,-3.531) 11(2.25,-3.531) 12(2.748,-3.531) 25(2.748,3.531) 26(2.25,3.531) 27(1.75,3.531) 28(1.25,3.531) 29(0.749,3.531) 30(0.249,3.531) 31(-0.249,3.531) 32(-0.749,3.531) 33(-1.25,3.531) 34(-1.75,3.531) 35(-2.25,3.531) 36(-2.748,3.531)
  rect 0.864x0.279 smd: 13(3.531,-2.748) 14(3.531,-2.25) 15(3.531,-1.75) 16(3.531,-1.25) 17(3.531,-0.749) 18(3.531,-0.249) 19(3.531,0.249) 20(3.531,0.749) 21(3.531,1.25) 22(3.531,1.75) 23(3.531,2.25) 24(3.531,2.748) 37(-3.531,2.748) 38(-3.531,2.25) 39(-3.531,1.75) 40(-3.531,1.25) 41(-3.531,0.749) 42(-3.531,0.249) 43(-3.531,-0.249) 44(-3.531,-0.749) 45(-3.531,-1.25) 46(-3.531,-1.75) 47(-3.531,-2.25) 48(-3.531,-2.748)
  rect 5.334x5.334 smd: 49(0,0)
RKT24
  rect 0.203x0.965 smd: 1(-1.806,-0.965) 2(-1.405,-0.965) 3(-1.003,-0.965) 4(-0.602,-0.965) 5(-0.201,-0.965) 6(0.201,-0.965) 7(0.602,-0.965) 8(1.003,-0.965) 9(1.405,-0.965) 10(1.806,-0.965) 13(1.806,0.965) 14(1.405,0.965) 15(1.003,0.965) 16(0.602,0.965) 17(0.201,0.965) 18(-0.201,0.965) 19(-0.602,0.965) 20(-1.003,0.965) 21(-1.405,0.965) 22(-1.806,0.965)
  rect 0.965x0.203 smd: 11(1.981,-0.201) 12(1.981,0.201) 23(-1.981,0.201) 24(-1.981,-0.201)
RPAK8-10X25-28V
  rect 0.406x0.635 smd: 1(-0.823,-0.521) 4(0.823,-0.521) 5(0.823,0.521) 8(-0.823,0.521)
  rect 0.254x0.635 smd: 2(-0.249,-0.521) 3(0.249,-0.521) 6(0.249,0.521) 7(-0.249,0.521)
SAMTEC-MUSB
  round 0.508 hole 0.889 unplated: (-2.197,-2.591) (2.197,-2.591)
  rect 0.508x2.286 smd: 1(-1.6,0) 2(-0.8,0) 3(0,0) 4(0.8,0) 5(1.6,0)
  rect 2.007x2.489 smd: 6(-4.445,-0.102) 7(4.445,-0.102) 8(-4.445,-5.613) 9(4.445,-5.613)
SKTBGA-ZKK-6334-P784
  round 1.016 hole 1.753 unplated: (-13.241,12.86) (-13.241,-12.873) (12.492,12.86) (12.492,-12.873)
  round 0.508 hole 0.864 unplated: (-13.241,-7.793) (12.492,10.32)
  round 0.4 smd: A1(-10.803,10.803) A2(-10.003,10.803) A3(-9.202,10.803) A4(-8.402,10.803) A5(-7.602,10.803) A6(-6.802,10.803) A7(-6.002,10.803) A8(-5.202,10.803) A9(-4.402,10.803) A10(-3.602,10.803) A11(-2.802,10.803) A12(-2.002,10.803) A13(-1.201,10.803) A14(-0.401,10.803) A15(0.401,10.803) A16(1.201,10.803) A17(2.002,10.803) A18(2.802,10.803) A19(3.602,10.803) A20(4.402,10.803) A21(5.202,10.803) A22(6.002,10.803) A23(6.802,10.803) A24(7.602,10.803) A25(8.402,10.803) A26(9.202,10.803) A27(10.003,10.803) A28(10.803,10.803) AA1(-10.803,-5.202) AA2(-10.003,-5.202) AA3(-9.202,-5.202) AA4(-8.402,-5.202) AA5(-7.602,-5.202) AA6(-6.802,-5.202) AA7(-6.002,-5.202) AA8(-5.202,-5.202) AA9(-4.402,-5.202) AA10(-3.602,-5.202) AA11(-2.802,-5.202) AA12(-2.002,-5.202) AA13(-1.201,-5.202) AA14(-0.401,-5.202) AA15(0.401,-5.202) AA16(1.201,-5.202) AA17(2.002,-5.202) AA18(2.802,-5.202) AA19(3.602,-5.202) AA20(4.402,-5.202) AA21(5.202,-5.202) AA22(6.002,-5.202) AA23(6.802,-5.202) AA24(7.602,-5.202) AA25(8.402,-5.202) AA26(9.202,-5.202) AA27(10.003,-5.202) AA28(10.803,-5.202) AB1(-10.803,-6.002) AB2(-10.003,-6.002) AB3(-9.202,-6.002) AB4(-8.402,-6.002) AB5(-7.602,-6.002) AB6(-6.802,-6.002) AB7(-6.002,-6.002) AB8(-5.202,-6.002) AB9(-4.402,-6.002) AB10(-3.602,-6.002) AB11(-2.802,-6.002) AB12(-2.002,-6.002) AB13(-1.201,-6.002) AB14(-0.401,-6.002) AB15(0.401,-6.002) AB16(1.201,-6.002) AB17(2.002,-6.002) AB18(2.802,-6.002) AB19(3.602,-6.002) AB20(4.402,-6.002) AB21(5.202,-6.002) AB22(6.002,-6.002) AB23(6.802,-6.002) AB24(7.602,-6.002) AB25(8.402,-6.002) AB26(9.201,-6.001) AB27(10.003,-6.002) AB28(10.803,-6.002) AC1(-10.803,-6.802) AC2(-10.003,-6.802) AC3(-9.202,-6.802) AC4(-8.402,-6.802) AC5(-7.602,-6.802) AC6(-6.802,-6.802) AC7(-6.002,-6.802) AC8(-5.202,-6.802) AC9(-4.402,-6.802) AC10(-3.602,-6.802) AC11(-2.802,-6.802) AC12(-2.002,-6.802) AC13(-1.201,-6.802) AC14(-0.401,-6.802) AC15(0.401,-6.802) AC16(1.201,-6.802) AC17(2.002,-6.802) AC18(2.802,-6.802) AC19(3.602,-6.802) AC20(4.402,-6.802) AC21(5.202,-6.802) AC22(6.002,-6.802) AC23(6.802,-6.802) AC24(7.602,-6.802) AC25(8.402,-6.802) AC26(9.202,-6.802) AC27(10.003,-6.802) AC28(10.803,-6.802) AD1(-10.803,-7.602) AD2(-10.003,-7.602) AD3(-9.202,-7.602) AD4(-8.402,-7.602) AD5(-7.602,-7.602) AD6(-6.802,-7.602) AD7(-6.002,-7.602) AD8(-5.202,-7.602) AD9(-4.402,-7.602) AD10(-3.602,-7.602) AD11(-2.802,-7.602) AD12(-2.002,-7.602) AD13(-1.201,-7.602) AD14(-0.401,-7.602) AD15(0.401,-7.602) AD16(1.201,-7.602) AD17(2.002,-7.602) AD18(2.802,-7.602) AD19(3.602,-7.602) AD20(4.402,-7.602) AD21(5.202,-7.602) AD22(6.002,-7.602) AD23(6.802,-7.602) AD24(7.602,-7.602) AD25(8.402,-7.602) AD26(9.202,-7.602) AD27(10.003,-7.602) AD28(10.803,-7.602) AE1(-10.803,-8.402) AE2(-10.003,-8.402) AE3(-9.202,-8.402) AE4(-8.401,-8.401) AE5(-7.602,-8.402) AE6(-6.802,-8.402) AE7(-6.002,-8.402) AE8(-5.202,-8.402) AE9(-4.402,-8.402) AE10(-3.602,-8.402) AE11(-2.802,-8.402) AE12(-2.002,-8.402) AE13(-1.201,-8.402) AE14(-0.401,-8.402) AE15(0.401,-8.402) AE16(1.201,-8.402) AE17(2.002,-8.402) AE18(2.802,-8.402) AE19(3.602,-8.402) AE20(4.402,-8.402) AE21(5.202,-8.402) AE22(6.002,-8.402) AE23(6.802,-8.402) AE24(7.602,-8.402) AE25(8.401,-8.401) AE26(9.202,-8.402) AE27(10.003,-8.402) AE28(10.803,-8.402) AF1(-10.803,-9.202) AF2(-10.003,-9.202) AF3(-9.202,-9.202) AF4(-8.402,-9.202) AF5(-7.602,-9.202) AF6(-6.802,-9.202) AF7(-6.001,-9.201) AF8(-5.202,-9.202) AF9(-4.402,-9.202) AF10(-3.6,-9.201) AF11(-2.802,-9.202) AF12(-2.002,-9.202) AF13(-1.2,-9.201) AF14(-0.401,-9.202) AF15(0.401,-9.202) AF16(1.2,-9.201) AF17(2.002,-9.202) AF18(2.802,-9.202) AF19(3.6,-9.201) AF20(4.402,-9.202) AF21(5.202,-9.202) AF22(6.002,-9.202) AF23(6.802,-9.202) AF24(7.602,-9.202) AF25(8.402,-9.202) AF26(9.202,-9.202) AF27(10.003,-9.202) AF28(10.803,-9.202) AG1(-10.803,-10.003) AG2(-10.003,-10.003) AG3(-9.202,-10.003) AG4(-8.402,-10.003) AG5(-7.602,-10.003) AG6(-6.802,-10.003) AG7(-6.002,-10.003) AG8(-5.202,-10.003) AG9(-4.402,-10.003) AG10(-3.602,-10.003) AG11(-2.802,-10.003) AG12(-2.002,-10.003) AG13(-1.201,-10.003) AG14(-0.401,-10.003) AG15(0.401,-10.003) AG16(1.201,-10.003) AG17(2.002,-10.003) AG18(2.802,-10.003) AG19(3.602,-10.003) AG20(4.402,-10.003) AG21(5.202,-10.003) AG22(6.002,-10.003) AG23(6.802,-10.003) AG24(7.602,-10.003) AG25(8.402,-10.003) AG26(9.202,-10.003) AG27(10.003,-10.003) AG28(10.803,-10.003) AH1(-10.803,-10.803) AH2(-10.003,-10.803) AH3(-9.202,-10.803) AH4(-8.402,-10.803) AH5(-7.602,-10.803) AH6(-6.802,-10.803) AH7(-6.002,-10.803) AH8(-5.202,-10.803) AH9(-4.402,-10.803) AH10(-3.602,-10.803) AH11(-2.802,-10.803) AH12(-2.002,-10.803) AH13(-1.201,-10.803) AH14(-0.401,-10.803) AH15(0.401,-10.803) AH16(1.201,-10.803) AH17(2.002,-10.803) AH18(2.802,-10.803) AH19(3.602,-10.803) AH20(4.402,-10.803) AH21(5.202,-10.803) AH22(6.002,-10.803) AH23(6.802,-10.803) AH24(7.602,-10.803) AH25(8.402,-10.803) AH26(9.202,-10.803) AH27(10.003,-10.803) AH28(10.803,-10.803) B1(-10.803,10.003) B2(-10.003,10.003) B3(-9.202,10.003) B4(-8.402,10.003) B5(-7.602,10.003) B6(-6.802,10.003) B7(-6.002,10.003) B8(-5.202,10.003) B9(-4.402,10.003) B10(-3.602,10.003) B11(-2.802,10.003) B12(-2.002,10.003) B13(-1.201,10.003) B14(-0.401,10.003) B15(0.401,10.003) B16(1.201,10.003) B17(2.002,10.003) B18(2.802,10.003) B19(3.602,10.003) B20(4.402,10.003) B21(5.202,10.003) B22(6.002,10.003) B23(6.802,10.003) B24(7.602,10.003) B25(8.402,10.003) B26(9.202,10.003) B27(10.003,10.003) B28(10.803,10.003) C1(-10.803,9.202) C2(-10.003,9.202) C3(-9.202,9.202) C4(-8.402,9.202) C5(-7.602,9.202) C6(-6.802,9.202) C7(-6.002,9.202) C8(-5.202,9.202) C9(-4.402,9.202) C10(-3.6,9.201) C11(-2.802,9.202) C12(-2.002,9.202) C13(-1.2,9.201) C14(-0.401,9.202) C15(0.401,9.202) C16(1.2,9.201) C17(2.002,9.202) C18(2.802,9.202) C19(3.6,9.201) C20(4.402,9.202) C21(5.202,9.202) C22(6.001,9.201) C23(6.802,9.202) C24(7.602,9.202) C25(8.402,9.202) C26(9.202,9.202) C27(10.003,9.202) C28(10.803,9.202) D1(-10.803,8.402) D2(-10.003,8.402) D3(-9.202,8.402) D4(-8.401,8.401) D5(-7.602,8.402) D6(-6.802,8.402) D7(-6.002,8.402) D8(-5.202,8.402) D9(-4.402,8.402) D10(-3.602,8.402) D11(-2.802,8.402) D12(-2.002,8.402) D13(-1.201,8.402) D14(-0.401,8.402) D15(0.401,8.402) D16(1.201,8.402) D17(2.002,8.402) D18(2.802,8.402) D19(3.602,8.402) D20(4.402,8.402) D21(5.202,8.402) D22(6.002,8.402) D23(6.802,8.402) D24(7.602,8.402) D25(8.401,8.401) D26(9.202,8.402) D27(10.003,8.402) D28(10.803,8.402) E1(-10.803,7.602) E2(-10.003,7.602) E3(-9.202,7.602) E4(-8.402,7.602) E5(-7.602,7.602) E6(-6.802,7.602) E7(-6.002,7.602) E8(-5.202,7.602) E9(-4.402,7.602) E10(-3.602,7.602) E11(-2.802,7.602) E12(-2.002,7.602) E13(-1.201,7.602) E14(-0.401,7.602) E15(0.401,7.602) E16(1.201,7.602) E17(2.002,7.602) E18(2.802,7.602) E19(3.602,7.602) E20(4.402,7.602) E21(5.202,7.602) E22(6.002,7.602) E23(6.802,7.602) E24(7.602,7.602) E25(8.402,7.602) E26(9.202,7.602) E27(10.003,7.602) E28(10.803,7.602) F1(-10.803,6.802) F2(-10.003,6.802) F3(-9.202,6.802) F4(-8.402,6.802) F5(-7.602,6.802) F6(-6.802,6.802) F7(-6.002,6.802) F8(-5.202,6.802) F9(-4.402,6.802) F10(-3.602,6.802) F11(-2.802,6.802) F12(-2.002,6.802) F13(-1.201,6.802) F14(-0.401,6.802) F15(0.401,6.802) F16(1.201,6.802) F17(2.002,6.802) F18(2.802,6.802) F19(3.602,6.802) F20(4.402,6.802) F21(5.202,6.802) F22(6.002,6.802) F23(6.802,6.802) F24(7.602,6.802) F25(8.402,6.802) F26(9.202,6.802) F27(10.003,6.802) F28(10.803,6.802) G1(-10.803,6.002) G2(-10.003,6.002) G3(-9.201,6.001) G4(-8.402,6.002) G5(-7.602,6.002) G6(-6.802,6.002) G7(-6.002,6.002) G8(-5.202,6.002) G9(-4.402,6.002) G10(-3.602,6.002) G11(-2.802,6.002) G12(-2.002,6.002) G13(-1.201,6.002) G14(-0.401,6.002) G15(0.401,6.002) G16(1.201,6.002) G17(2.002,6.002) G18(2.802,6.002) G19(3.602,6.002) G20(4.402,6.002) G21(5.202,6.002) G22(6.002,6.002) G23(6.802,6.002) G24(7.602,6.002) G25(8.402,6.002) G26(9.202,6.002) G27(10.003,6.002) G28(10.803,6.002) H1(-10.803,5.202) H2(-10.003,5.202) H3(-9.202,5.202) H4(-8.402,5.202) H5(-7.602,5.202) H6(-6.802,5.202) H7(-6.002,5.202) H8(-5.202,5.202) H9(-4.402,5.202) H10(-3.602,5.202) H11(-2.802,5.202) H12(-2.002,5.202) H13(-1.201,5.202) H14(-0.401,5.202) H15(0.401,5.202) H16(1.201,5.202) H17(2.002,5.202) H18(2.802,5.202) H19(3.602,5.202) H20(4.402,5.202) H21(5.202,5.202) H22(6.002,5.202) H23(6.802,5.202) H24(7.602,5.202) H25(8.402,5.202) H26(9.202,5.202) H27(10.003,5.202) H28(10.803,5.202) J1(-10.803,4.402) J2(-10.003,4.402) J3(-9.202,4.402) J4(-8.402,4.402) J5(-7.602,4.402) J6(-6.802,4.402) J7(-6.002,4.402) J8(-5.202,4.402) J9(-4.402,4.402) J10(-3.602,4.402) J11(-2.802,4.402) J12(-2.002,4.402) J13(-1.201,4.402) J14(-0.401,4.402) J15(0.401,4.402) J16(1.201,4.402) J17(2.002,4.402) J18(2.802,4.402) J19(3.602,4.402) J20(4.402,4.402) J21(5.202,4.402) J22(6.002,4.402) J23(6.802,4.402) J24(7.602,4.402) J25(8.402,4.402) J26(9.202,4.402) J27(10.003,4.402) J28(10.803,4.402) K1(-10.803,3.602) K2(-10.003,3.602) K3(-9.201,3.6) K4(-8.402,3.602) K5(-7.602,3.602) K6(-6.802,3.602) K7(-6.002,3.602) K8(-5.202,3.602) K9(-4.402,3.602) K10(-3.602,3.602) K11(-2.802,3.602) K12(-2.002,3.602) K13(-1.201,3.602) K14(-0.401,3.602) K15(0.401,3.602) K16(1.201,3.602) K17(2.002,3.602) K18(2.802,3.602) K19(3.602,3.602) K20(4.402,3.602) K21(5.202,3.602) K22(6.002,3.602) K23(6.802,3.602) K24(7.602,3.602) K25(8.402,3.602) K26(9.201,3.6) K27(10.003,3.602) K28(10.803,3.602) L1(-10.803,2.802) L2(-10.003,2.802) L3(-9.202,2.802) L4(-8.402,2.802) L5(-7.602,2.802) L6(-6.802,2.802) L7(-6.002,2.802) L8(-5.202,2.802) L9(-4.402,2.802) L10(-3.602,2.802) L11(-2.802,2.802) L12(-2.002,2.802) L13(-1.201,2.802) L14(-0.401,2.802) L15(0.401,2.802) L16(1.201,2.802) L17(2.002,2.802) L18(2.802,2.802) L19(3.602,2.802) L20(4.402,2.802) L21(5.202,2.802) L22(6.002,2.802) L23(6.802,2.802) L24(7.602,2.802) L25(8.402,2.802) L26(9.202,2.802) L27(10.003,2.802) L28(10.803,2.802) M1(-10.803,2.002) M2(-10.003,2.002) M3(-9.202,2.002) M4(-8.402,2.002) M5(-7.602,2.002) M6(-6.802,2.002) M7(-6.002,2.002) M8(-5.202,2.002) M9(-4.402,2.002) M10(-3.602,2.002) M11(-2.802,2.002) M12(-2.002,2.002) M13(-1.201,2.002) M14(-0.401,2.002) M15(0.401,2.002) M16(1.201,2.002) M17(2.002,2.002) M18(2.802,2.002) M19(3.602,2.002) M20(4.402,2.002) M21(5.202,2.002) M22(6.002,2.002) M23(6.802,2.002) M24(7.602,2.002) M25(8.402,2.002) M26(9.202,2.002) M27(10.003,2.002) M28(10.803,2.002) N1(-10.803,1.201) N2(-10.003,1.201) N3(-9.201,1.2) N4(-8.402,1.201) N5(-7.602,1.201) N6(-6.802,1.201) N7(-6.002,1.201) N8(-5.202,1.201) N9(-4.402,1.201) N10(-3.602,1.201) N11(-2.802,1.201) N12(-2.002,1.201) N13(-1.201,1.201) N14(-0.401,1.201) N15(0.401,1.201) N16(1.201,1.201) N17(2.002,1.201) N18(2.802,1.201) N19(3.602,1.201) N20(4.402,1.201) N21(5.202,1.201) N22(6.002,1.201) N23(6.802,1.201) N24(7.602,1.201) N25(8.402,1.201) N26(9.201,1.2) N27(10.003,1.201) N28(10.803,1.201) P1(-10.803,0.401) P2(-10.003,0.401) P3(-9.202,0.401) P4(-8.402,0.401) P5(-7.602,0.401) P6(-6.802,0.401) P7(-6.002,0.401) P8(-5.202,0.401) P9(-4.402,0.401) P10(-3.602,0.401) P11(-2.802,0.401) P12(-2.002,0.401) P13(-1.201,0.401) P14(-0.401,0.401) P15(0.401,0.401) P16(1.201,0.401) P17(2.002,0.401) P18(2.802,0.401) P19(3.602,0.401) P20(4.402,0.401) P21(5.202,0.401) P22(6.002,0.401) P23(6.802,0.401) P24(7.602,0.401) P25(8.402,0.401) P26(9.202,0.401) P27(10.003,0.401) P28(10.803,0.401) R1(-10.803,-0.401) R2(-10.003,-0.401) R3(-9.202,-0.401) R4(-8.402,-0.401) R5(-7.602,-0.401) R6(-6.802,-0.401) R7(-6.002,-0.401) R8(-5.202,-0.401) R9(-4.402,-0.401) R10(-3.602,-0.401) R11(-2.802,-0.401) R12(-2.002,-0.401) R13(-1.201,-0.401) R14(-0.401,-0.401) R15(0.401,-0.401) R16(1.201,-0.401) R17(2.002,-0.401) R18(2.802,-0.401) R19(3.602,-0.401) R20(4.402,-0.401) R21(5.202,-0.401) R22(6.002,-0.401) R23(6.802,-0.401) R24(7.602,-0.401) R25(8.402,-0.401) R26(9.202,-0.401) R27(10.003,-0.401) R28(10.803,-0.401) T1(-10.803,-1.201) T2(-10.003,-1.201) T3(-9.201,-1.2) T4(-8.402,-1.201) T5(-7.602,-1.201) T6(-6.802,-1.201) T7(-6.002,-1.201) T8(-5.202,-1.201) T9(-4.402,-1.201) T10(-3.602,-1.201) T11(-2.802,-1.201) T12(-2.002,-1.201) T13(-1.201,-1.201) T14(-0.401,-1.201) T15(0.401,-1.201) T16(1.201,-1.201) T17(2.002,-1.201) T18(2.802,-1.201) T19(3.602,-1.201) T20(4.402,-1.201) T21(5.202,-1.201) T22(6.002,-1.201) T23(6.802,-1.201) T24(7.602,-1.201) T25(8.402,-1.201) T26(9.201,-1.2) T27(10.003,-1.201) T28(10.803,-1.201) U1(-10.803,-2.002) U2(-10.003,-2.002) U3(-9.202,-2.002) U4(-8.402,-2.002) U5(-7.602,-2.002) U6(-6.802,-2.002) U7(-6.002,-2.002) U8(-5.202,-2.002) U9(-4.402,-2.002) U10(-3.602,-2.002) U11(-2.802,-2.002) U12(-2.002,-2.002) U13(-1.201,-2.002) U14(-0.401,-2.002) U15(0.401,-2.002) U16(1.201,-2.002) U17(2.002,-2.002) U18(2.802,-2.002) U19(3.602,-2.002) U20(4.402,-2.002) U21(5.202,-2.002) U22(6.002,-2.002) U23(6.802,-2.002) U24(7.602,-2.002) U25(8.402,-2.002) U26(9.202,-2.002) U27(10.003,-2.002) U28(10.803,-2.002) V1(-10.803,-2.802) V2(-10.003,-2.802) V3(-9.202,-2.802) V4(-8.402,-2.802) V5(-7.602,-2.802) V6(-6.802,-2.802) V7(-6.002,-2.802) V8(-5.202,-2.802) V9(-4.402,-2.802) V10(-3.602,-2.802) V11(-2.802,-2.802) V12(-2.002,-2.802) V13(-1.201,-2.802) V14(-0.401,-2.802) V15(0.401,-2.802) V16(1.201,-2.802) V17(2.002,-2.802) V18(2.802,-2.802) V19(3.602,-2.802) V20(4.402,-2.802) V21(5.202,-2.802) V22(6.002,-2.802) V23(6.802,-2.802) V24(7.602,-2.802) V25(8.402,-2.802) V26(9.202,-2.802) V27(10.003,-2.802) V28(10.803,-2.802) W1(-10.803,-3.602) W2(-10.003,-3.602) W3(-9.201,-3.6) W4(-8.402,-3.602) W5(-7.602,-3.602) W6(-6.802,-3.602) W7(-6.002,-3.602) W8(-5.202,-3.602) W9(-4.402,-3.602) W10(-3.602,-3.602) W11(-2.802,-3.602) W12(-2.002,-3.602) W13(-1.201,-3.602) W14(-0.401,-3.602) W15(0.401,-3.602) W16(1.201,-3.602) W17(2.002,-3.602) W18(2.802,-3.602) W19(3.602,-3.602) W20(4.402,-3.602) W21(5.202,-3.602) W22(6.002,-3.602) W23(6.802,-3.602) W24(7.602,-3.602) W25(8.402,-3.602) W26(9.201,-3.6) W27(10.003,-3.602) W28(10.803,-3.602) Y1(-10.803,-4.402) Y2(-10.003,-4.402) Y3(-9.202,-4.402) Y4(-8.402,-4.402) Y5(-7.602,-4.402) Y6(-6.802,-4.402) Y7(-6.002,-4.402) Y8(-5.202,-4.402) Y9(-4.402,-4.402) Y10(-3.602,-4.402) Y11(-2.802,-4.402) Y12(-2.002,-4.402) Y13(-1.201,-4.402) Y14(-0.401,-4.402) Y15(0.401,-4.402) Y16(1.201,-4.402) Y17(2.002,-4.402) Y18(2.802,-4.402) Y19(3.602,-4.402) Y20(4.402,-4.402) Y21(5.202,-4.402) Y22(6.002,-4.402) Y23(6.802,-4.402) Y24(7.602,-4.402) Y25(8.402,-4.402) Y26(9.202,-4.402) Y27(10.003,-4.402) Y28(10.803,-4.402)
SMC-80X128
  rect 2.032x3.251 smd: 1(-3.124,0) 2(3.124,0)
SO8-25X75
  oval 0.635x1.905 smd: 1(-1.905,-2.794) 2(-0.635,-2.794) 3(0.635,-2.794) 4(1.905,-2.794) 5(1.905,2.794) 6(0.635,2.794) 7(-0.635,2.794) 8(-1.905,2.794)
SO8-25X75-295
  oval 0.635x2.54 smd: 1(-1.905,-3.086) 2(-0.635,-3.086) 3(0.635,-3.086) 4(1.905,-3.086) 5(1.905,3.086) 6(0.635,3.086) 7(-0.635,3.086) 8(-1.905,3.086)
SO16-25X75-300
  oval 0.635x1.905 smd: 1(-4.445,-4.699) 2(-3.175,-4.699) 3(-1.905,-4.699) 4(-0.635,-4.699) 5(0.635,-4.699) 6(1.905,-4.699) 7(3.175,-4.699) 8(4.445,-4.699) 9(4.445,4.699) 10(3.175,4.699) 11(1.905,4.699) 12(0.635,4.699) 13(-0.635,4.699) 14(-1.905,4.699) 15(-3.175,4.699) 16(-4.445,4.699)
SOD123-36X48
  rect 0.914x1.219 smd: 1(-1.638,0) 2(1.638,0)
SOD323
  rect 1.092x0.508 smd: 1(-1.194,0) 2(1.194,0)
SOT23-28X44-GSD
  rect 0.711x1.118 smd: D(0,1.067) G(-0.965,-1.067) S(0.965,-1.067)
SOT363-16X45
  rect 0.406x0.635 smd: 1(-0.65,-0.978) 2(0,-0.978) 3(0.65,-0.978) 4(0.65,0.978) 5(0,0.978) 6(-0.65,0.978)
ST_3500
  round 0.508 hole 1.6 unplated: (0,3.797) (0,-3.188)
  rect 3.048x2.896 smd: 1(-3.683,4.915) 2(-3.48,-4.407) 3(3.683,3.01)
  rect 2.921x2.489 smd: 4(0.762,-8.42)
SW2-30X50-TDA
  rect 0.762x1.27 smd: 1(-0.635,-3.81) 2(0.635,-3.81) 3(0.635,3.81) 4(-0.635,3.81)
SW4-30X50-TDA
  rect 0.762x1.27 smd: 1(-1.905,-3.81) 2(-0.635,-3.81) 3(0.635,-3.81) 4(1.905,-3.81) 5(1.905,3.81) 6(0.635,3.81) 7(-0.635,3.81) 8(-1.905,3.81)
SW4-7914G
  rect 1.27x1.778 smd: 1(1.27,2.769) 2(1.27,-2.769) 3(-1.27,2.769) 4(-1.27,-2.769)
SW8-30X50
  rect 0.762x1.27 smd: 1(-4.445,-3.81) 2(-3.175,-3.81) 3(-1.905,-3.81) 4(-0.635,-3.81) 5(0.635,-3.81) 6(1.905,-3.81) 7(3.175,-3.81) 8(4.445,-3.81) 9(4.445,3.81) 10(3.175,3.81) 11(1.905,3.81) 12(0.635,3.81) 13(-0.635,3.81) 14(-1.905,3.81) 15(-3.175,3.81) 16(-4.445,3.81)
SW10-30X50
  rect 0.762x1.27 smd: 1(-5.715,-3.81) 2(-4.445,-3.81) 3(-3.175,-3.81) 4(-1.905,-3.81) 5(-0.635,-3.81) 6(0.635,-3.81) 7(1.905,-3.81) 8(3.175,-3.81) 9(4.445,-3.81) 10(5.715,-3.81) 11(5.715,3.81) 12(4.445,3.81) 13(3.175,3.81) 14(1.905,3.81) 15(0.635,3.81) 16(-0.635,3.81) 17(-1.905,3.81) 18(-3.175,3.81) 19(-4.445,3.81) 20(-5.715,3.81)
TO-252-D-PAK
  rect 1.397x3.048 smd: 1(-2.311,-6.413) 3(2.311,-6.413)
  rect 6.35x7.62 smd: 4(0,0.102)
TP1-18RD8
  round 0.457 hole 0.203: 1(0,0)
TP1-70X135
  rect 2.286x3.937 smd: 1(0,0)
TP1-6040
  round 1.524 hole 1.016: 1(0,0)
TP20
  round 0.508 smd: 1(0,0)
TP-20RD10
  round 0.508 hole 0.254: 1(0,0)
TP-30RD13
  round 0.762 hole 0.33: 1(0,0)
TSOP48-10X60-MICRON
  oval 0.254x1.524 smd: 1(-5.751,-9.87) 2(-5.251,-9.87) 3(-4.752,-9.87) 4(-4.252,-9.87) 5(-3.752,-9.87) 6(-3.252,-9.87) 7(-2.752,-9.87) 8(-2.252,-9.87) 9(-1.752,-9.87) 10(-1.252,-9.87) 11(-0.753,-9.87) 12(-0.253,-9.87) 13(0.247,-9.87) 14(0.747,-9.87) 15(1.247,-9.87) 16(1.747,-9.87) 17(2.247,-9.87) 18(2.747,-9.87) 19(3.246,-9.87) 20(3.746,-9.87) 21(4.246,-9.87) 22(4.746,-9.87) 23(5.246,-9.87) 24(5.746,-9.87) 25(5.752,9.87) 26(5.252,9.87) 27(4.752,9.87) 28(4.252,9.87) 29(3.752,9.87) 30(3.252,9.87) 31(2.752,9.87) 32(2.252,9.87) 33(1.753,9.87) 34(1.253,9.87) 35(0.753,9.87) 36(0.253,9.87) 37(-0.247,9.87) 38(-0.747,9.87) 39(-1.247,9.87) 40(-1.747,9.87) 41(-2.246,9.87) 42(-2.746,9.87) 43(-3.246,9.87) 44(-3.746,9.87) 45(-4.246,9.87) 46(-4.746,9.87) 47(-5.246,9.87) 48(-5.745,9.87)
TSOP56-12X75
  oval 0.305x1.905 smd: 1(-6.749,-9.842) 2(-6.248,-9.842) 3(-5.748,-9.842) 4(-5.248,-9.842) 5(-4.75,-9.842) 6(-4.249,-9.842) 7(-3.749,-9.842) 8(-3.249,-9.842) 9(-2.748,-9.842) 10(-2.25,-9.842) 11(-1.75,-9.842) 12(-1.25,-9.842) 13(-0.749,-9.842) 14(-0.249,-9.842) 15(0.249,-9.842) 16(0.749,-9.842) 17(1.25,-9.842) 18(1.75,-9.842) 19(2.25,-9.842) 20(2.748,-9.842) 21(3.249,-9.842) 22(3.749,-9.842) 23(4.249,-9.842) 24(4.75,-9.842) 25(5.248,-9.842) 26(5.748,-9.842) 27(6.248,-9.842) 28(6.749,-9.842) 29(6.749,9.842) 30(6.248,9.842) 31(5.748,9.842) 32(5.248,9.842) 33(4.75,9.842) 34(4.249,9.842) 35(3.749,9.842) 36(3.249,9.842) 37(2.748,9.842) 38(2.25,9.842) 39(1.75,9.842) 40(1.25,9.842) 41(0.749,9.842) 42(0.249,9.842) 43(-0.249,9.842) 44(-0.749,9.842) 45(-1.25,9.842) 46(-1.75,9.842) 47(-2.25,9.842) 48(-2.748,9.842) 49(-3.249,9.842) 50(-3.749,9.842) 51(-4.249,9.842) 52(-4.75,9.842) 53(-5.248,9.842) 54(-5.748,9.842) 55(-6.248,9.842) 56(-6.749,9.842)
TSSOP16-14X70
  oval 0.356x1.778 smd: 1(-2.276,-2.987) 2(-1.626,-2.987) 3(-0.975,-2.987) 4(-0.325,-2.987) 5(0.325,-2.987) 6(0.975,-2.987) 7(1.626,-2.987) 8(2.276,-2.987) 9(2.276,2.987) 10(1.626,2.987) 11(0.975,2.987) 12(0.325,2.987) 13(-0.325,2.987) 14(-0.975,2.987) 15(-1.626,2.987) 16(-2.276,2.987)
unnamed#2
  round 1.27 smd: 1(0,0)
unnamed#3
  round 1.016 hole 2.362 unplated: (0,0)
USB-AB-F-10PTH-RDPADS
  oval 0.406x1.346 smd: 1(-4.65,0) 2(-4,0) 3(-3.35,0) 4(-2.7,0) 5(-2.05,0) 6(2.05,0) 7(2.7,0) 8(3.35,0) 9(4,0) 10(4.65,0)
  rect 2.311x1.905 hole 1.295: 11(-6.931,-2.7) 16(5.591,-2.7)
  rect 1.803x1.905 smd: 12(-4.5,-2.7) 13(-2.2,-2.7) 15(3.15,-2.7)
  rect 2.311x1.905 smd: 14(0.4,-2.7)
USB_A_SH
  round 1.651 hole 1.016: 1(0,0) 2(2.499,0) 3(4.501,0) 4(7,0)
  round 4.064 hole 2.413: 5(-3.071,-2.71) 6(10.071,-2.71)
VQFNHR26
  custom 0.194x0.194 smd: 1(-1.816,2.038) 8(-1.816,-2.038) 14(1.81,-2.038) 21(1.81,2.038)
  rect 0.597x0.254 smd: 2(-1.899,1.25) 3(-1.899,0.749) 4(-1.899,0.249) 5(-1.899,-0.249) 6(-1.899,-0.749) 7(-1.899,-1.25) 15(1.899,-1.25) 16(1.899,-0.749) 17(1.899,-0.249) 18(1.899,0.249) 19(1.899,0.749) 20(1.899,1.25)
  rect 0.254x1.816 smd: 9(-1.001,-1.537) 10(-0.5,-1.537) 11(0,-1.537) 12(0.5,-1.537) 13(1.001,-1.537) 22(1.001,1.537) 23(0.5,1.537) 24(0,1.537) 25(-0.5,1.537) 26(-1.001,1.537)
  rect 2.235x0.66 smd: 27(0,0)
XTAL2-75X94
  rect 1.905x2.413 smd: 1(-2.235,0) 2(2.235,0)
XTAL4-32X35-ABM10
  rect 0.889x0.813 smd: 1(-0.826,-0.635) 2(0.826,-0.635) 3(0.826,0.635) 4(-0.826,0.635)
XTAL4-35X28
  rect 0.889x0.711 smd: 1(-1.041,-0.787) 2(1.041,-0.787) 3(1.041,0.787) 4(-1.041,0.787)
XTAL4-55X87
  rect 2.21x1.397 smd: 1(-2.896,-1.25) 2(2.896,-1.25) 3(2.896,1.25) 4(-2.896,1.25)

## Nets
1V8_DISP_SCL: R450.1 R740.2 U146.3(SCL1)
1V8_DISP_SDA: R449.1 R739.2 U146.4(SDA1)
1V8_I2C1_SCL: P9.31 R646.2 RJ5.3 U55.3(SCL1)
1V8_I2C1_SDA: P9.33 R639.2 RJ3.3 U55.4(SDA1)
3V3_REF_CLK: R569.1 U123.3(OUT) U124.12(B8)
3V3_SPI[1]_CS[0]N: R572.1 RU21.2(1B1) U124.20(B1)
3V3_SPI[1]_MISO: RU21.5(2B1) U124.18(B2)
3V3_SPI[1]_MOSI: RU21.14(4B1) U124.16(B4)
3V3_SPI[1]_SCLK: RU21.11(3B1) U124.17(B3)
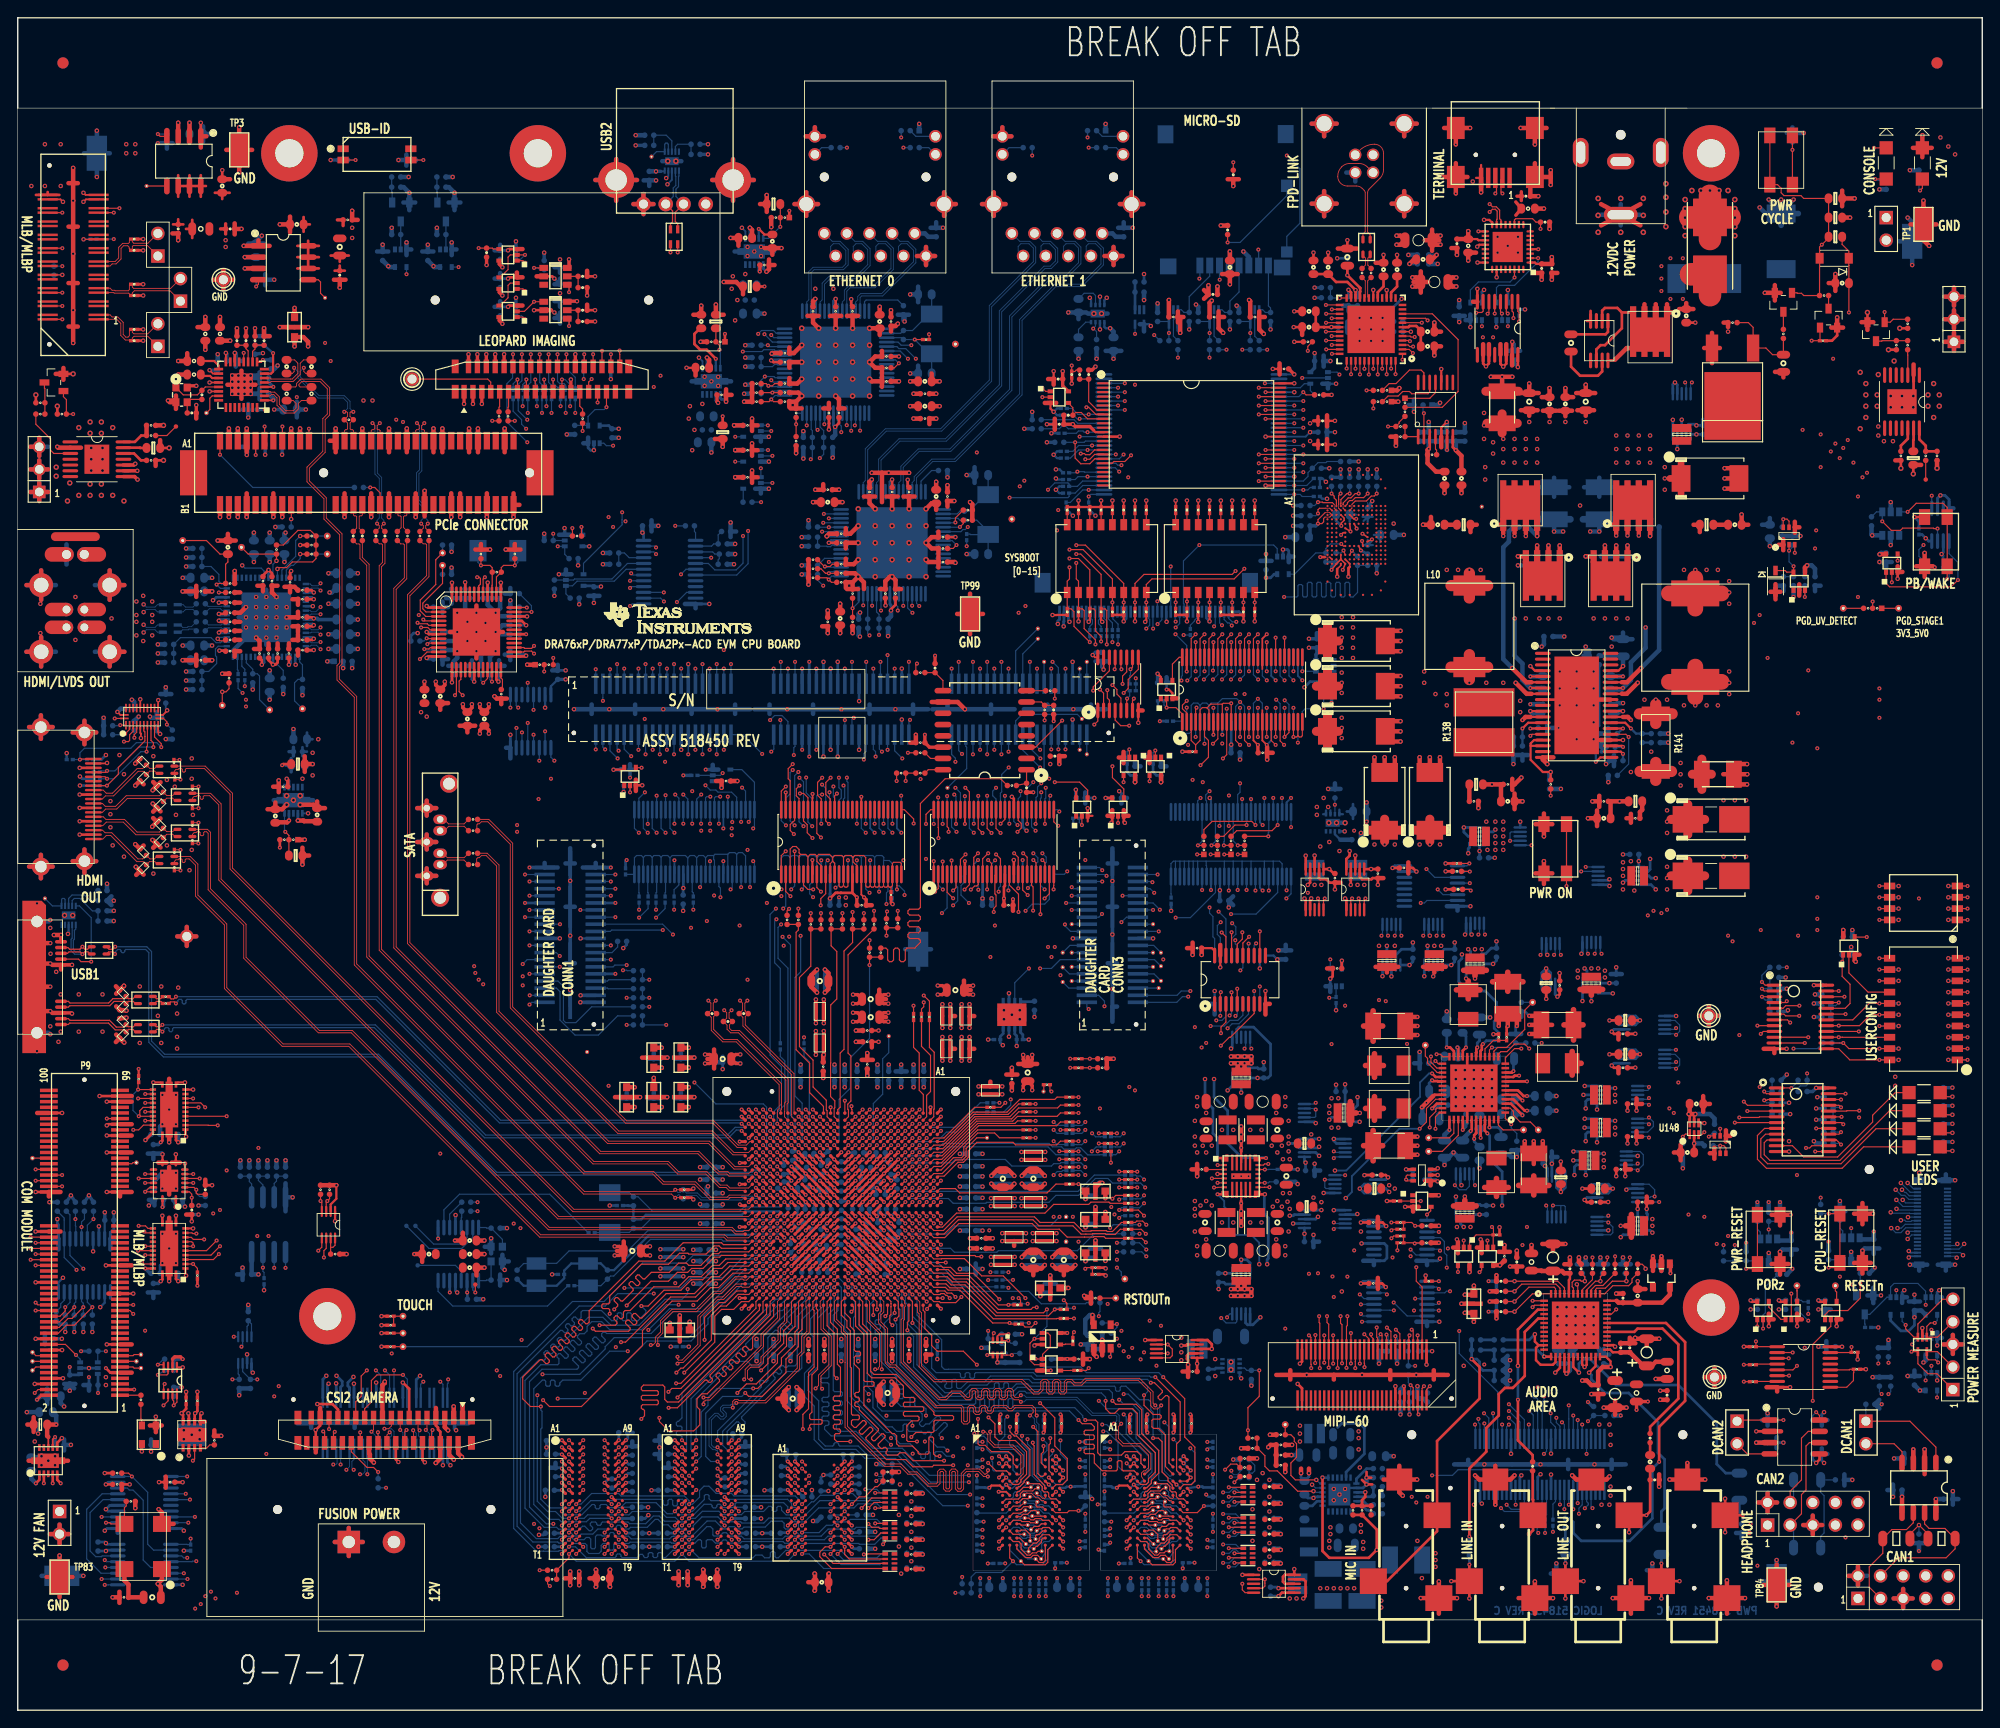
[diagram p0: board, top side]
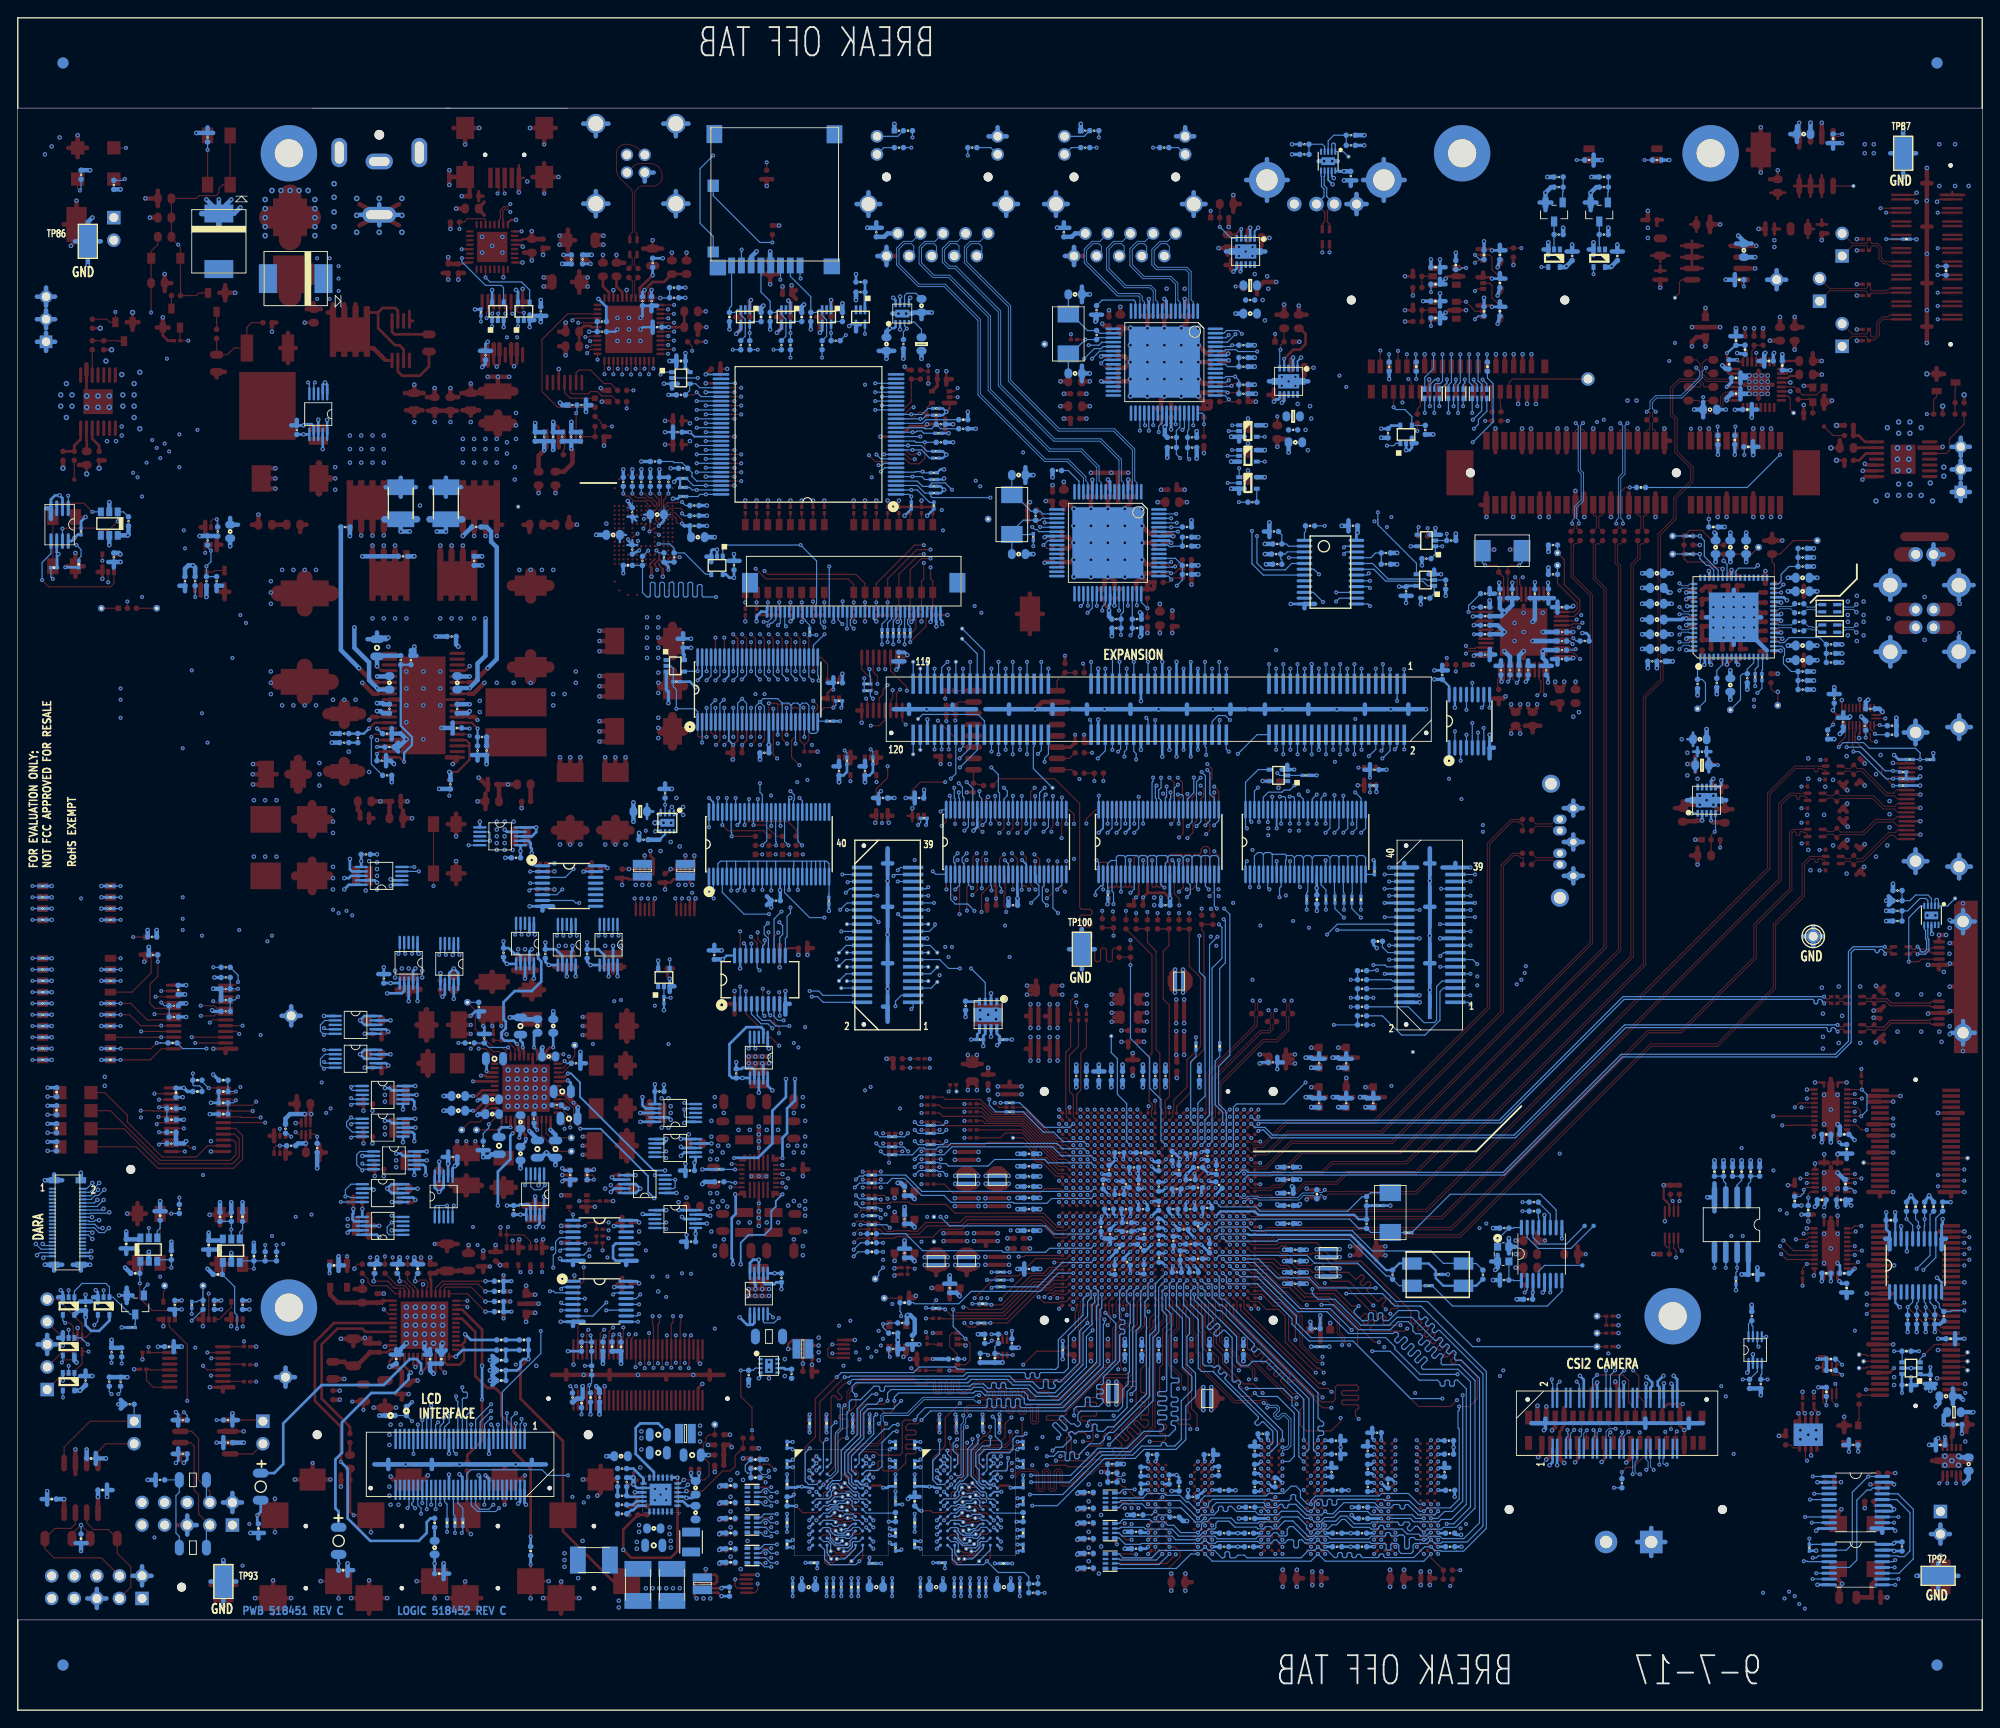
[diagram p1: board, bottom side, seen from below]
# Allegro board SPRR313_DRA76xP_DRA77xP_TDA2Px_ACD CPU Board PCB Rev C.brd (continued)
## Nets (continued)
GND: C1.2 C2.2 C3.2 C4.2 C5.2 C6.2 C7.2 C8.2 C9.2 C10.2 C11.2 C12.2 C13.2 C14.2 C15.2 C16.2 C17.2 C18.2 C21.2 C22.2 C23.2 C24.2 C25.2 C26.2 C27.2 C28.2 C29.2 C30.2 C31.2 C32.2 C33.2 C34.2 C35.2 C36.2 C37.2 C38.2 C39.2 C41.2 C42.2 C45.2 C46.2 C48.2 C49.2 C50.2 C51.2 C54.2 C56.2 C57.2 C58.2 C59.2 C60.2 C61.2 C62.2 C63.2 C64.2 C65.2 C66.2 C67.2 C68.2 C69.2 C70.2 C71.2 C72.2 C73.2 C74.2 C75.2 C76.2 C77.2 C78.2 C79.2 C80.1 C81.1 C83.2 C87.2 C88.2 C89.2 C90.2 C91.2 C92.2 C93.2 C94.2 C95.2 C96.2 C97.2 C98.2 C99.2 C100.2 C101.2 C102.2 C103.2 C104.2 C105.2 C106.2 C107.2 C108.2 C109.2 C110.2 C111.2 C112.2 C113.2 C114.2 C115.2 C116.2 C117.2 C118.2 C119.2 C120.2 C121.2 C122.2 C123.2 C124.2 C125.2 C126.2 C127.2 C128.1 C129.1 C131.2 C135.2 C136.2 C137.2 C138.2 C139.2 C140.2 C141.2 C143.2 C145.2 C146.2 C147.2 C148.2 C149.2 C150.2 C151.2 C152.2 C153.2 C154.2 C155.2 C156.2 C157.2 C158.2 C159.2 C160.2 C161.2 C162.2 C163.2 C164.2 C165.2 C166.2 C167.2 C168.2 C169.2 C170.2 C171.2 C172.2 C173.2 C174.2 C175.2 C176.2 C177.2 C178.2 C179.2 C180.2 C181.2 C182.2 C183.2 C184.2 C185.2 C186.2 C187.2 C188.2 C189.2 C190.2 C191.2 C192.2 C193.2 C194.2 C195.2 C196.2 C197.2 C198.2 C199.2 C201.2 C207.2 C211.1 C214.1 C215.1 C216.2 C217.2 C218.2 C219.2 C220.2 C223.2 C226.1 C227.1 C228.1 C229.1 C230.1 C231.1 C232.1 C233.1 C234.1 C235.1 C236.1 C237.1 C238.1 C239.1 C240.1 C241.1 C242.1 C243.1 C244.1 C245.1 C246.1 C247.1 C248.1 C249.1 C250.1 C251.1 C252.1 C254.2 C255.2 C256.2 C257.2 C258.2 C259.2 C260.2 C261.2 C262.2 C263.2 C264.2 C265.2 C266.2 C267.2 C268.2 C270.2 C271.2 C272.2 C273.2 C274.2 C275.2 C276.2 C277.2 C278.2 C279.2 C280.2 C281.2 C282.2 C283.2 C284.2 C285.2 C286.2 C287.2 C288.2 C290.2 C291.1 C292.2 C293.2 C294.2 C295.2 C296.2 C297.2 C298.2 C299.2 C300.1 C301.1 C302.2 C303.2 C304.2 C305.1 C306.2 C307.2 C308.2 C309.2 C310.2 C311.2 C312.2 C313.1 C314.2 C315.2 C316.1 C317.2 C320.2 C323.2 C324.2 C325.1 C326.2 C327.2 C328.2 C329.2 C330.2 C331.2 C332.2 C335.2 C336.2 C337.2 C340.2 C341.1 C342.2 C343.2 C344.1 C345.2 C346.2 C350.1 C351.2 C352.2 C353.2 C354.2 C355.2 C356.2 C357.1 C358.2 C359.2 C360.2 C361.2 C362.2 C363.2 C364.2 C365.2 C366.2 C367.2 C368.2 C369.2 C370.2 C371.2 C372.2 C373.2 C374.2 C375.1 C376.1 C377.1 C378.2 C379.2 C380.2 C381.2 C382.2 C383.2 C384.2 C385.1 C386.2 C387.2 C388.2 C389.2 C390.1 C391.2 C392.2 C393.2 C394.2 C395.2 C396.2 C397.2 C398.2 C399.2 C400.2 C401.2 C402.1 C403.1 C404.1 C405.2 C406.1 C407.1 C408.2 C409.1 C410.1 C411.2 C412.1 C413.1 C414.2 C415.2 C416.2 C417.2 C418.2 C419.2 C420.1 C421.2 C422.2 C423.2 C424.2 C425.2 C426.2 C427.2 C428.2 C429.2 C430.1 C431.2 C432.2 C433.2 C434.2 C435.2 C436.2 C437.2 C438.2 C439.2 C440.2 C441.2 C442.2 C443.2 C444.2 C445.2 C446.2 C447.2 C448.2 C449.2 C450.2 C451.2 C452.2 C453.2 C454.2 C455.2 C456.2 C458.2 C459.2 C460.2 C461.2 C462.2 C463.2 C464.2 C465.2 C466.2 C467.2 C468.2 C469.2 C470.1 C471.2 C472.2 C473.2 C475.2 C476.2 C477.2 C478.2 C479.2 C480.2 C481.2 C482.2 C483.2 C484.2 C485.2 C486.2 C487.2 C488.2 C489.2 C490.2 C491.2 C492.2 C493.2 C494.2 C495.2 C496.2 C497.2 C498.2 C499.2 C500.2 C501.2 C502.2 C503.2 C504.2 C505.2 C506.2 C507.2 C508.2 C509.2 C510.2 C511.2 C512.2 C513.2 C514.2 C515.2 C516.2 C519.2 C520.2 C521.2 C522.2 C523.2 C524.2 C525.2 C526.2 C529.2 C531.1 C532.2 C533.2 C534.2 C535.2 C536.2 C537.2 C538.2 C539.2 C540.2 C541.2 C542.2 C543.1 C544.2 C545.2 C546.2 C547.2 C548.2 C549.2 C550.2 C551.2 C553.2 C554.2 C555.2 C556.2 C557.2 C558.2 C559.2 C560.2 C561.2 C562.2 C563.2 C564.2 C565.2 C566.2 C567.2 C568.2 C569.2 C570.2 C571.2 C572.2 C573.2 C574.2 C575.2 C576.2 C577.2 C579.2 C580.2 C581.2 C582.2 C583.2 C584.2 C585.2 C586.2 C587.2 C588.2 C589.2 C590.2 C591.2 C592.2 C593.2 C595.2 C596.2 C597.2 C598.2 C599.2 C600.2 C603.2 C605.2 C606.2 C607.2 C608.2 C609.2 C614.2 C615.2 C617.2 C618.2 C619.2 C620.2 C621.2 C622.2 C623.2 C624.2 C626.2 C627.2 C628.2 C629.2 C630.2 C631.2 C632.2 C633.2 C634.2 C636.2 C640.2 C641.2 C646.1 C650.2 C651.2 C652.2 C655.2 C656.2 C657.2 C658.2 C659.2 C660.2 C661.2 C662.2 C663.2 C664.2 C665.2 C666.2 C667.2 C668.2 C669.2 C670.2 C671.2 C673.2 C674.2 C675.2 C676.2 C677.2 C678.2 C679.2 C680.2 C681.2 C682.2 C683.2 C684.2 C686.2 C687.2 C688.2 C689.2 C690.2 C691.2 C692.2 C693.2 C694.2 C695.2 C696.2 C697.2 C698.2 C699.2 C700.2 C701.2 C702.2 C703.2 C704.2 C705.2 C706.2 C707.2 C708.2 C709.2 C710.2 C711.2 C712.2 C713.1 D2.1(CATHODE) D24.2(ANODE) DS1.1(CATHODE) E1.2 E2.2 E3.2 E4.2 E5.2 E6.2 E7.2 E8.2 E9.2 E10.2 E11.2 E12.2 EXP_P1.2 EXP_P1.4 EXP_P1.10 EXP_P1.19 EXP_P1.20 EXP_P1.29 EXP_P1.30 EXP_P1.39 EXP_P1.40 EXP_P1.41(G1) EXP_P1.42(G2) EXP_P1.43(G3) EXP_P1.44(G4) EXP_P2.26 EXP_P2.27 EXP_P2.77 EXP_P2.78 EXP_P2.115 EXP_P2.116 EXP_P2.121(G1) EXP_P2.122(G2) EXP_P2.123(G3) EXP_P2.124(G4) EXP_P2.125(G5) EXP_P2.126(G6) EXP_P2.127(G7) EXP_P2.128(G8) EXP_P2.129(G9) EXP_P2.130(G10) EXP_P2.131(G11) EXP_P2.132(G12) EXP_P3.19 EXP_P3.20 EXP_P3.41(G1) EXP_P3.42(G2) EXP_P3.43(G3) EXP_P3.44(G4) J1.2 J2.2 J2.MTG1 J2.MTG2 J3.5(USBVSS) J3.6(SHIELD1) J3.7(SHIELD2) J3.8(SHIELD3) J3.9(SHIELD4) J8.6 J8.8 J8.10 J8.25 J8.26 J9.1 J9.2 J9.3 J10.1 J10.2 J10.3 J11.6(P2) J11.G1 J11.G2 J11.G3 J11.G4 J12.1 J12.4 J12.7 J13.16(GND16) J13.57(GND57) J13.58(GND58) J13.61(GNDCT1) J13.62(GNDCT2) J13.63(GNDCT3) J13.64(GNDCT4) J14.3 J15.6 J15.7 J15.10 J15.13 J15.16 J15.19 J15.22 J15.29 J15.33 J15.34 J16.1 J17.7 J17.16 J17.25 J17.34 J17.40 J18.38 J18.40 J18.41 J18.42 J18.43 J18.44 J19.17 J19.18 J19.22 J19.30 J19.35 J19.36 J19.61(GNDCT1) J19.62(GNDCT2) J19.63(GNDCT3) J19.64(GNDCT4) J20.2 J20.5 J21.2 J21.5 P1.4 P1.SH1 P1.SH2 P1.SH3 P1.SH4 P2.4(GND) P2.5(S2) P2.6(S1) P3.1(GND) P3.11(SHLD1) P3.12(SHLD2) P3.D4(LED2-KA) P4.1(GND) P4.11(SHLD1) P4.12(SHLD2) P4.D4(LED2-KA) P5.41(SH_GND.1) P5.42(SH_GND.2) P5.43(SH_GND.4) P5.44(SH_GND.3) P6.A4(GND.12) P6.A12(GND.13) P6.A15(GND.14) P6.A18(GND.15) P6.A20(GND.16) P6.A23(GND.17) P6.A24(GND.18) P6.A27(GND.19) P6.A28(GND.20) P6.A31(GND.21) P6.B4(GND.1) P6.B7(GND.2) P6.B13(GND.3) P6.B16(GND.4) P6.B18(GND.5) P6.B21(GND.6) P6.B22(GND.7) P6.B25(GND.8) P6.B26(GND.9) P6.B29(GND.10) P6.B32(GND.11) P7.2(D2 SHIELD) P7.5(D1 SHIELD) P7.8(D0 SHIELD) P7.11(CK SHIELD) P7.17(GND) P7.MTG1 P7.MTG2 P7.MTG3 P7.MTG4 P8.5(USBVSS) P8.8(CON8) P8.11(SHIELD1) P8.12(SHIELD2) P8.13(SHIELD3) P8.14(SHIELD4) P8.15(SHIELD5) P8.16(SHIELD6) P9.2 P9.3 P9.6 P9.9 P9.18 P9.19 P9.22 P9.37 P9.42 P9.47 P9.60 P9.63 P9.64 P9.77 P9.83 P9.87 P9.92 P9.95 P9.97 P10.1(SHIELD) P10.4(TIPB) P11.1(SHIELD) P11.4(TIPB) P12.1(SHIELD) P13.1(SHIELD) P14.6(VSS) P15.12 P15.16 P15.24 P15.41(SH_GND.1) P15.42(SH_GND.2) P15.43(SH_GND.4) P15.44(SH_GND.3) Q3.S Q4.S Q5.S Q6.S Q9.1(S1) Q9.2(S2) Q9.3(S3) Q10.1(S1) Q10.2(S2) Q10.3(S3) Q11.S Q12.S Q13.S Q16.1(S1) Q18.1(S2) Q18.4(S2) Q19.1(S2) Q19.4(S2) R1.2 R2.2 R3.2 R8.2 R10.2 R11.2 R13.1 R14.2 R15.2 R17.2 R18.1 R20.2 R21.1 R22.2 R25.2 R26.2 R29.2 R33.1 R38.2 R41.1 R44.1 R48.2 R49.2 R53.2 R63.1 R65.1 R66.2 R68.1 R95.1 R98.1 R100.1 R104.2 R106.1 R109.1 R111.2 R112.2 R113.2 R114.2 R115.2 R116.2 R117.2 R118.2 R119.2 R120.2 R121.2 R122.2 R123.2 R124.2 R125.2 R126.2 R127.2 R128.2 R140.2 R142.2 R143.1 R149.1 R155.1 R164.1 R193.2 R215.2 R217.2 R222.2 R233.2 R243.2 R244.1 R246.2 R251.2 R253.2 R254.2 R256.2 R259.2 R266.2 R267.1 R270.2 R277.1 R279.2 R283.2 R291.2 R298.1 R305.1 R307.2 R309.1 R310.1 R314.2 R315.2 R326.2 R327.1 R329.2 R337.2 R340.2 R350.2 R351.2 R357.2 R359.1 R360.1 R363.2 R366.1 R372.2 R373.2 R374.1 R375.1 R376.1 R378.2 R379.1 R380.1 R382.1 R383.1 R390.1 R391.1 R392.1 R393.1 R396.1 R397.1 R404.2 R405.2 R407.2 R410.1 R411.2 R412.2 R424.2 R432.2 R433.1 R443.2 R446.1 R447.1 R455.1 R456.1 R459.1 R462.1 R463.2 R465.1 R468.2 R469.1 R471.2 R476.1 R477.1 R479.1 R480.1 R481.1 R484.2 R485.1 R488.1 R490.1 R495.1 R503.2 R505.2 R506.2 R511.2 R515.2 R520.1 R521.1 R523.1 R541.1 R544.1 R546.2 R550.1 R551.1 R573.2 R576.2 R579.2 R595.1 R604.2 R605.2 R606.2 R630.2 R640.1 R645.2 R662.2 R663.2 R666.2 R670.2 R672.2 R673.2 R679.2 R681.2 R683.2 R685.2 R687.2 R688.2 R689.2 R690.2 R691.2 R693.2 R694.2 R695.2 R697.2 R700.2 R701.2 R704.2 R705.2 R706.2 R708.1 R709.1 R710.2 R711.1 R714.1 R716.1 R719.2 R722.1 R725.1 R731.1 R732.1 R744.2 R749.1 R750.1 R751.1 R752.1 RJ12.1 RJ13.1 RJ14.3 RU1.3(GND) RU2.8(GND) RU2.10(3B2) RU2.11(3B1) RU2.13(4B2) RU2.14(4B1) RU2.15(O\E\) RU3.3(GND) RU4.8(GND) RU4.15(O\E\) RU5.8(GND.1) RU5.19(GND.2) RU5.38(GND.3) RU5.49(GND.4) RU5.55(S2) RU6.1(OE) RU6.3(GND) RU7.8(GND.1) RU7.19(GND.2) RU7.38(GND.3) RU7.49(GND.4) RU7.55(S2) RU8.8(GND.1) RU8.19(GND.2) RU8.38(GND.3) RU8.49(GND.4) RU9.10(GND) RU9.19(O\E\) RU10.8(GND) RU11.3(GND) RU12.3(GND) RU13.8(GND.1) RU13.19(GND.2) RU13.38(GND.3) RU13.49(GND.4) RU13.55(S2) RU14.8(GND) RU14.15(O\E\) RU15.8(GND.1) RU15.19(GND.2) RU15.38(GND.3) RU15.49(GND.4) RU16.8(GND.1) RU16.19(GND.2) RU16.38(GND.3) RU16.49(GND.4) RU16.55(S2) RU17.8(GND.1) RU17.19(GND.2) RU17.38(GND.3) RU17.49(GND.4) RU17.55(S2) RU18.8(GND.1) RU18.19(GND.2) RU18.38(GND.3) RU18.49(GND.4) RU18.55(S2) RU19.8(GND) RU19.15(O\E\) RU20.10(GND) RU20.19(O\E\) RU21.8(GND) RU21.15(O\E\) RU22.8(GND) RU22.9(3A) RU22.12(4A) RU22.15(O\E\) RU23.8(GND) RU23.15(O\E\) RU24.3(GND) RU25.3(GND) SW5.1(A) SW5.2(AA) SW7.1(A) SW7.2(AA) SW8.1(A) SW8.2(AA) SW9.1(A) SW9.2(AA) TP1.1 TP2.1(TP) TP3.1 TP12.1(TP) TP83.1 TP84.1 TP85.1(TP) TP86.1 TP87.1 TP91.1(TP) TP92.1 TP93.1 TP99.1 TP100.1 U1.1(GND) U2.1(GND) U3.4(GND.1) U3.17(GND.2) U3.20(GND.3) U3.24(AGND) U3.26(TEST) U3.33(PWRPAD) U4.3(GND) U5.2(GND) U6.2(GND) U7.3(GND) U8.15(FSEL) U8.18(RES1) U8.49(DAP(PWRPAD)) U10.14(GND.1) U10.22(GND.2) U10.33(PWR_PAD) U11.5(GND#5) U11.10(GND#10) U12.13(GND1) U12.25(GND2) U12.36(GND3) U12.48(GND4) U13.2(GND) U13.15(TAB(GND)) U14.2(GND) U14.15(TAB(GND)) U15.C4(VSS.1) U15.E7(VSS.2) U15.G5(VSS.3) U15.H10(VSS.4) U15.K8(VSS.5) U15.N2(VSS.6) U15.N5(VSS.7) U15.P4(VSS.8) U15.P6(VSS.9) U16.3(GND) U17.3(GND) U18.9(PGNDA) U18.19(AGND.1) U18.23(AGND.2) U18.30(PGNDB) U18.39(PWR PAD) U19.5(GND1) U19.13(GND2) U19.18(GND3) U20.10(VSS) U21.12(GND) U22.2(GND) U23.3(GND) U24.2(GND) U25.2(GND) U26.2(GND) U27.3(GND) U28.2(GND) U29.2(GND) U30.12(GND) U31.2(GND) U32.2(GND) U33.2(GND) U34.2(GND) U35.2(GND) U36.2(GND) U37.2(GND) U38.20(VPROG) U38.28(SMPS2_FDBK) U38.41(REFGND) U38.49(PAD) U39.2(DIR) U39.11(GND#11) U39.12(GND#12) U39.13(GND#13) U39.25(PP) U40.4(AGND1) U40.11(PGND_B01) U40.14(FB_B1) U40.17(AGND2) U40.21(FB_B3) U40.24(PGND_B23) U40.27(AGND3) U41.7(2A2) U41.8(GND.1) U41.9(GND.2) U41.17(GND.3) U42.A1(VSS_1) U42.A2(VSS_2) U42.A28(VSS_3) U42.AA8(VSS_116) U42.AA10(VSS_117) U42.AA12(VSS_118) U42.AA16(VSS_119) U42.AA18(VSS_120) U42.AA20(VSS_121) U42.AA22(VSS_122) U42.AB9(VSS_123) U42.AB11(VSS_124) U42.AB13(VSS_125) U42.AB17(VSS_126) U42.AC12(VSS_127) U42.AC15(VSS_128) U42.AD10(VSS_129) U42.AD13(VSS_130) U42.AD16(VSS_131) U42.AD19(VSS_132) U42.AE11(VSS_133) U42.AE14(VSS_134) U42.AE17(VSS_135) U42.AF9(VSS_136) U42.AF12(VSS_137) U42.AF15(VSS_138) U42.AF18(VSS_139) U42.AG1(VSS_140) U42.AG4(VSS_141) U42.AG7(VSS_142) U42.AG10(VSS_143) U42.AG13(VSS_144) U42.AG16(VSS_145) U42.AG28(VSS_146) U42.AH1(VSS_147) U42.AH2(VSS_148) U42.AH5(VSS_149) U42.AH8(VSS_150) U42.AH11(VSS_151) U42.AH14(VSS_152) U42.AH17(VSS_153) U42.AH27(VSS_154) U42.AH28(VSS_155) U42.B1(VSS_4) U42.G8(VSS_5) U42.G12(VSS_6) U42.G16(VSS_7) U42.G18(VSS_8) U42.G20(VSS_9) U42.G22(VSS_10) U42.H7(VSS_11) U42.H9(VSS_12) U42.H13(VSS_13) U42.H15(VSS_14) U42.H17(VSS_15) U42.H19(VSS_16) U42.H21(VSS_17) U42.H23(VSS_18) U42.J8(VSS_19) U42.J10(VSS_20) U42.J12(VSS_21) U42.J14(VSS_22) U42.J18(VSS_23) U42.J20(VSS_24) U42.J22(VSS_25) U42.K7(VSS_26) U42.K9(VSS_27) U42.K11(VSS_28) U42.K13(VSS_29) U42.K15(VSS_30) U42.K17(VSS_31) U42.K19(VSS_32) U42.K21(VSS_33) U42.K23(VSS_34) U42.L8(VSS_35) U42.L10(VSS_36) U42.L12(VSS_37) U42.L14(VSS_38) U42.L16(VSS_39) U42.L18(VSS_40) U42.L20(VSS_41) U42.L22(VSS_42) U42.M7(VSS_43) U42.M9(VSS_44) U42.M11(VSS_45) U42.M13(VSS_46) U42.M15(VSS_47) U42.M17(VSS_48) U42.M19(VSS_49) U42.M21(VSS_50) U42.M23(VSS_51) U42.N8(VSS_52) U42.N10(VSS_53) U42.N12(VSS_54) U42.N14(VSS_55) U42.N16(VSS_56) U42.N18(VSS_57) U42.N20(VSS_58) U42.N22(VSS_59) U42.P7(VSS_60) U42.P9(VSS_61) U42.P11(VSS_62) U42.P13(VSS_63) U42.P15(VSS_64) U42.P17(VSS_65) U42.P19(VSS_66) U42.R8(VSS_67) U42.R10(VSS_68) U42.R12(VSS_69) U42.R16(VSS_70) U42.R18(VSS_71) U42.R22(VSS_72) U42.T7(VSS_73) U42.T9(VSS_74) U42.T11(VSS_75) U42.T13(VSS_76) U42.T15(VSS_77) U42.T17(VSS_78) U42.T19(VSS_79) U42.T21(VSS_80) U42.T23(VSS_81) U42.U8(VSS_82) U42.U10(VSS_83) U42.U12(VSS_84) U42.U14(VSS_85) U42.U16(VSS_86) U42.U18(VSS_87) U42.U20(VSS_88) U42.U22(VSS_89) U42.V7(VSS_90) U42.V9(VSS_91) U42.V11(VSS_92) U42.V13(VSS_93) U42.V15(VSS_94) U42.V17(VSS_95) U42.V19(VSS_96) U42.V21(VSS_97) U42.V23(VSS_98) U42.W8(VSS_99) U42.W10(VSS_100) U42.W12(VSS_101) U42.W14(VSS_102) U42.W16(VSS_103) U42.W18(VSS_104) U42.W20(VSS_105) U42.W22(VSS_106) U42.Y7(VSS_107) U42.Y9(VSS_108) U42.Y11(VSS_109) U42.Y13(VSS_110) U42.Y15(VSS_111) U42.Y17(VSS_112) U42.Y19(VSS_113) U42.Y21(VSS_114) U42.Y23(VSS_115) U43.11(GND#11) U43.12(GND#12) U43.13(GND#13) U43.25(PP) U44.3(GND) U45.2(GND) U45.3(ENN) U46.3(GND) U47.3(GND) U48.3(GND) U50.15(AVSS_ADC) U50.20(DRVSS.1) U50.21(DRVSS.2) U50.26(AVSS_DAC) U50.42(DVSS) U50.49(TPAD) U51.3(GND) U52.2(GND) U53.2(GND) U54.3(GND) U55.1(GND) U56.6(GND) U56.11(PP1) U57.2(GND) U58.2(GND) U59.A9(VSS.1) U59.B1(VSSQ.1) U59.B3(VSS.2) U59.B9(VSSQ.2) U59.D1(VSSQ.3) U59.D8(VSSQ.4) U59.E1(VSS.3) U59.E2(VSSQ.5) U59.E8(VSSQ.6) U59.F9(VSSQ.7) U59.G1(VSSQ.8) U59.G8(VSS.4) U59.G9(VSSQ.9) U59.J2(VSSDL) U59.J8(VSS.5) U59.M1(VSS.6) U59.M9(VSS.7) U59.P1(VSS.8) U59.P9(VSS.9) U59.T1(VSS.10) U59.T9(VSS.11) U60.A9(VSS.1) U60.B1(VSSQ.1) U60.B3(VSS.2) U60.B9(VSSQ.2) U60.D1(VSSQ.3) U60.D8(VSSQ.4) U60.E1(VSS.3) U60.E2(VSSQ.5) U60.E8(VSSQ.6) U60.F9(VSSQ.7) U60.G1(VSSQ.8) U60.G8(VSS.4) U60.G9(VSSQ.9) U60.J2(VSSDL) U60.J8(VSS.5) U60.M1(VSS.6) U60.M9(VSS.7) U60.P1(VSS.8) U60.P9(VSS.9) U60.T1(VSS.10) U60.T9(VSS.11) U61.A1(VSS.1) U61.A8(VSS.2) U61.B1(VSS.3) U61.B2(VSSQ#B2) U61.B8(VSSQ#B8) U61.C9(VSSQ#C9) U61.D1(VSSQ#D1) U61.D8(VSS.4) U61.D9(VSSQ#D9) U61.F2(VSS.5) U61.F8(VSS.6) U61.J1(VSS.7) U61.J9(VSS.8) U61.L1(VSS.9) U61.L9(VSS.10) U61.N1(VSS.11) U61.N9(VSS.12) U62.A1(VSS.1) U62.A8(VSS.2) U62.B1(VSS.3) U62.B2(VSSQ#B2) U62.B8(VSSQ#B8) U62.C9(VSSQ#C9) U62.D1(VSSQ#D1) U62.D8(VSS.4) U62.D9(VSSQ#D9) U62.F2(VSS.5) U62.F8(VSS.6) U62.J1(VSS.7) U62.J9(VSS.8) U62.L1(VSS.9) U62.L9(VSS.10) U62.N1(VSS.11) U62.N9(VSS.12) U63.A1(VSS.1) U63.A8(VSS.2) U63.B1(VSS.3) U63.B2(VSSQ#B2) U63.B8(VSSQ#B8) U63.C9(VSSQ#C9) U63.D1(VSSQ#D1) U63.D8(VSS.4) U63.D9(VSSQ#D9) U63.F2(VSS.5) U63.F8(VSS.6) U63.J1(VSS.7) U63.J9(VSS.8) U63.L1(VSS.9) U63.L9(VSS.10) U63.N1(VSS.11) U63.N9(VSS.12) U65.7(GND) U66.7(GND) U67.2(A0) U67.7(GND) U68.7(GND) U69.7(GND) U70.7(GND) U71.2(A0) U71.7(GND) U72.7(GND) U73.7(GND) U74.2(A0) U74.7(GND) U75.7(GND) U76.7(GND) U77.7(GND) U78.2(A0) U78.7(GND) U79.7(GND) U80.7(GND) U81.7(GND) U82.2(A0) U82.7(GND) U83.1(A1) U83.7(GND) U84.1(A1) U84.7(GND) U85.1(A1) U85.7(GND) U86.1(A1) U86.2(A0) U86.7(GND) U87.1(A1) U87.7(GND) U88.1(A1) U88.7(GND) U89.1(A1) U89.7(GND) U90.1(A1) U90.2(A0) U90.7(GND) U91.7(GND) U92.8(GND) U92.11(PWR_PAD) U93.6(GND) U93.11(PP1) U94.3(GND) U95.3(GND) U96.5(GND) U96.9(PWR_PAD) U97.4(GND) U98.4(GND) U99.4(GND) U100.4(GND) U101.65(GND) U102.6(GND) U102.11(PP1) U103.3(GND) U104.33(VSS1) U104.52(VSS2) U105.2(I) U105.3(GND) U106.3(GND) U107.3(GND) U108.65(GND) U109.2(I) U109.3(GND) U110.12(GND) U111.3(GND) U112.3(GND) U113.2(D) U113.4(GND) U114.2(GND) U115.2(RES0) U115.29(RES1) U115.65(DAP(PWRPAD)) U116.3(GND) U117.6(GND) U117.11(PP1) U118.3(GND) U119.5(GND) U119.9(PWR_PAD) U120.8(GND) U120.11(PWR_PAD) U121.3(GND) U122.2(D0) U122.5(GND) U122.PAD U123.2(GND) U124.11(GND1) U124.14(B6) U124.15(B5) U125.5(GND1) U125.12(GND2) U126.2(GND) U127.2(GND) U128.11(GND1) U128.17(B3) U128.18(B2) U128.20(B1) U129.3(GND) U130.3(GND) U131.3(GND) U132.2(GND) U132.5(DIR) U133.3(GND) U134.5(GND) U134.9(PWR_PAD) U135.1(GND) U136.A1(VSS.1) U136.A8(VSS.2) U136.B1(VSS.3) U136.B2(VSSQ#B2) U136.B8(VSSQ#B8) U136.C9(VSSQ#C9) U136.D1(VSSQ#D1) U136.D8(VSS.4) U136.D9(VSSQ#D9) U136.F2(VSS.5) U136.F8(VSS.6) U136.J1(VSS.7) U136.J9(VSS.8) U136.L1(VSS.9) U136.L9(VSS.10) U136.N1(VSS.11) U136.N9(VSS.12) U137.A1(VSS.1) U137.A8(VSS.2) U137.B1(VSS.3) U137.B2(VSSQ#B2) U137.B8(VSSQ#B8) U137.C9(VSSQ#C9) U137.D1(VSSQ#D1) U137.D8(VSS.4) U137.D9(VSSQ#D9) U137.F2(VSS.5) U137.F8(VSS.6) U137.J1(VSS.7) U137.J9(VSS.8) U137.L1(VSS.9) U137.L9(VSS.10) U137.N1(VSS.11) U137.N9(VSS.12) U138.10(VTTGND) U138.14(AGND) U138.19(PGND1) U138.20(PGND2) U138.25(PAD) U139.4(VSS) U140.2(D0) U140.5(GND) U140.PAD U141.49(GND(PAD)) U142.3(GND) U143.3(GND) U144.3(GND) U145.3(GND) U146.1(GND) U147.2(GND) U148.4(GND) Y1.2(GND1) Y1.4(GND2) Y2.2(GND) Y6.2(GND1) Y6.4(GND2)
VBUS_USB1: C5.1 L3.1 P8.1(USBVDD) R313.1 U120.9(VBUS.2) U120.10(VBUS.1)
VBUS_USB2: C1.1 C256.1 L1.1 P2.1(VBUS) R312.1 U92.9(VBUS.2) U92.10(VBUS.1)
VCC_1V1USB: C699.1 C700.1 C701.1 C702.1 C703.1 C704.1 C708.1 L33.1 RJ16.1 U141.1(VDD#1) U141.12(VDD#12) U141.18(VDD#18) U141.30(VDD#30) U141.34(VDD#34) U141.45(VDD#45)
VCC_1V1VIDEO: C346.1 C347.1 L25.2 L26.2 L29.2 L33.2 R473.1 U117.9(VOUT1) U117.10(VOUT2)
VCC_CSI2_IO: C429.1 R668.1 R669.1 U124.2(VCCA) U124.10(OE) U135.2(VREF1) U140.7(OUT)
VCC_VTERM: L28.2 RJ15.2
VDD18_DISP1: C94.1 C103.1 C110.1 C315.1 C324.1 L27.1 R110.2 R423.2 R442.2 R448.2 R453.2 U115.24(VDD18A) U115.51(VDD18B) U115.64(VDD18C)
VDD33_DSU921: C14.1 C270.1 L5.1 U8.22(VDD33)
VDD_CDCEL925: C159.1 C164.1 C458.1 L19.1 U125.3(VDD) U125.6(VDDOUT1) U125.9(VDDOUT2)
VDD_CDCM9102: C285.1 C286.1 C287.1 C288.1 E1.3 U10.1(VDD2_OUT1) U10.4(VDD1_OUT0)
VDD_CORE_APM: C146.1 J18.6 L14.1 R189.2 U83.8(VBUS) U83.10(VIN+)
VDD_CORE_AVS: C141.1 C372.1 C373.1 C383.1 C384.1 C435.1 C447.1 C459.1 C462.1 C498.1 J18.8 R189.1 U38.9(SMPS3_FDBK) U42.J9(VDD_1) U42.J15(VDD_2) U42.K14(VDD_3) U42.N11(VDD_4) U42.N15(VDD_5) U42.N17(VDD_6) U42.P10(VDD_7) U42.P12(VDD_8) U42.P14(VDD_9) U42.P21(VDD_10) U42.R9(VDD_11) U42.R11(VDD_12) U42.R13(VDD_13) U42.T10(VDD_14) U42.T12(VDD_15) U42.T14(VDD_16) U42.U9(VDD_17) U42.U11(VDD_18) U42.U17(VDD_19) U42.V16(VDD_20) U42.V20(VDD_21) U42.W19(VDD_22) U42.Y18(VDD_23) U42.Y20(VDD_24) U83.9(VIN-)
VDD_CORE_SW3: L14.2 U38.11(SMPS3_SW)
VDD_DSPEVE_APM: C148.1 C158.1 J18.2 L13.1 L17.1 R208.2 U84.8(VBUS) U84.10(VIN+)
VDD_DSPEVE_AVS: C162.1 C163.1 C428.1 C433.1 C438.1 C439.1 C440.1 C444.1 C446.1 C452.1 C455.1 C456.1 C464.1 J18.4 R208.1 U38.33(SMPS1_FDBK) U42.K10(VDD_DSPEVE_1) U42.K12(VDD_DSPEVE_2) U42.L9(VDD_DSPEVE_3) U42.L11(VDD_DSPEVE_4) U42.L13(VDD_DSPEVE_5) U42.M10(VDD_DSPEVE_6) U42.M12(VDD_DSPEVE_7) U42.M14(VDD_DSPEVE_8) U84.9(VIN-)
VDD_DSPEVE_SW1: L17.2 U38.31(SPMS1_SW)
VDD_DSPEVE_SW2: L13.2 U38.30(SPMS2_SW)
VDD_GPU_APM: C153.1 C154.1 J18.10 L15.1(P1) L16.1(P1) R191.2 U85.8(VBUS) U85.10(VIN+)
VDD_GPU_AVS: C140.1 C369.1 C374.1 C382.1 C396.1 C400.1 C434.1 C441.1 C448.1 C466.1 J18.12 R191.1 U40.1(FB_B2) U42.V10(VDD_GPU_1) U42.V12(VDD_GPU_2) U42.V14(VDD_GPU_3) U42.W9(VDD_GPU_4) U42.W11(VDD_GPU_5) U42.W13(VDD_GPU_6) U85.9(VIN-)
VDD_GPU_SW2: L15.2(P2) U40.25(SW_B2)
VDD_GPU_SW3: L16.2(P2) U40.23(SW_B3)
VDD_IVA_APM: C143.1 J18.14 L12.1 R179.2 U82.8(VBUS) U82.10(VIN+)
VDD_IVA_AVS: C172.1 C489.1 C495.1 C497.1 C502.1 C511.1 C516.1 J18.16 R179.1 U38.17(SMPS4_FDBK) U42.T18(VDD_IVA_1) U42.U19(VDD_IVA_2) U42.V18(VDD_IVA_3) U82.9(VIN-)
VDD_IVA_SW4: L12.2 U38.19(SPMS4_SW)
VDD_MPU_APM: C169.1 C170.1 J18.18 L20.1(P1) L21.1(P1) R249.2 U86.8(VBUS) U86.10(VIN+)
VDD_MPU_AVS: C173.1 C174.1 C463.1 C472.1 C482.1 C484.1 C485.1 C491.1 C492.1 C499.1 C503.1 C504.1 C505.1 J18.20 R249.1 R594.1 U40.8(FB_B0) U42.K16(VDD_MPU_1) U42.K18(VDD_MPU_2) U42.K20(VDD_MPU_3) U42.L15(VDD_MPU_4) U42.L17(VDD_MPU_5) U42.L19(VDD_MPU_6) U42.M16(VDD_MPU_7) U42.M18(VDD_MPU_8) U42.M20(VDD_MPU_9) U86.9(VIN-)
VDD_MPU_SW0: L20.2(P2) U40.10(SW_B0)
VDD_MPU_SW1: L21.2(P2) U40.12(SW_B1)
VDD_SDIO_APM: C404.2 R196.2 R753.2 U69.8(VBUS) U69.10(VIN+) U148.5(OUT2) U148.6(OUT1)
VDD_SDIO_DV: C401.1 R9.1 R196.1 R330.1 R331.1 R332.1 R333.1 R334.1 R335.1 U42.U7(VDDSHV8_1) U69.9(VIN-)
VDDA_CDCM9102: C34.1 C281.1 C282.1 C283.1 L7.2 R27.1 R28.1 R349.1 U10.9(VDD3) U10.16(VDD4) U10.18(VDD5) U10.20(VDD6)
VDDHA_DISP1: C98.1 C105.1 C108.1 C314.1 C327.1 L29.1 U115.52(VDDHA11A) U115.54(VDDHA11B) U115.58(VDDHA11C) U115.61(VDDHA11D)
VDDHS_DISP1: C95.1 C99.1 C100.1 C106.1 C111.1 C112.1 C116.1 C317.1 C330.1 L26.1 U115.9(VDDA11) U115.17(VDDP11) U115.21(VDDHS11A) U115.25(VDDS11) U115.28(VDDHS11B)
VDDI_MMC2: C304.1 C306.1 U15.C2(VDDI.1)
VDDIO_DSU921: C32.1 C277.1 L6.2 U8.30(VDDIO)
VDDL_DISP1: C91.1 C92.1 C113.1 C114.1 C309.1 C336.1 L25.1 U115.7(VDDL11A) U115.41(VDDL11B)
VDDR_APM: C575.1 C601.2 C650.1 C651.1 C652.1 J18.33 L31.1(P1) R280.1 R653.2 R692.1 R703.2 U80.8(VBUS) U80.10(VIN+) U134.1(VIN.1) U134.2(VIN.2) U138.7(VDDQSNS) U138.8(LDOIN)
VDDR_MEM_1V35: C194.1 C195.1 C196.1 C198.1 C199.1 C200.2 C202.2 C204.2 C205.2 C207.1 C208.2 C209.2 C210.2 C212.2 C213.2 C217.1 C218.1 C219.1 C220.1 C221.2 C222.2 C223.1 C224.2 C225.2 C553.1 C554.1 C556.1 C557.1 C558.1 C559.1 C560.1 C561.1 C562.1 C565.1 C566.1 C567.1 C568.1 C569.1 C570.1 C571.1 C572.1 C573.1 C574.1 C578.2 C581.1 C582.1 C583.1 C584.1 C585.1 C586.1 C588.1 C589.1 C590.1 C591.1 C592.1 C595.1 C596.1 C597.1 C602.2 C604.2 C607.1 C608.1 C611.2 C612.2 C613.2 C614.1 C615.1 C616.2 C617.1 C618.1 C619.1 C620.1 C621.1 C622.1 C625.2 C627.1 C628.1 C629.1 C630.1 C631.1 C632.1 C633.1 C634.1 C637.2 C640.1 C641.1 C642.2 C643.2 C644.2 C645.2 C647.2 C648.2 C649.2 C653.2 C654.2 C655.1 C656.1 C657.1 C658.1 C659.1 C660.1 C661.1 C662.1 C663.1 C664.1 C665.1 C666.1 C667.1 C668.1 C669.1 C670.1 C671.1 C672.2 C673.1 C674.1 C675.1 C676.1 C677.1 C678.1 C680.1 C681.1 C682.1 C683.1 C684.1 C685.2 C686.1 J18.35 R281.1 R703.1 U59.A1(VDDQ.1) U59.A8(VDDQ.2) U59.B2(VDD.1) U59.C1(VDDQ.3) U59.C9(VDDQ.4) U59.D2(VDDQ.5) U59.D9(VDD.2) U59.E9(VDDQ.6) U59.F1(VDDQ.7) U59.G7(VDD.3) U59.H2(VDDQ.8) U59.H9(VDDQ.9) U59.K2(VDDL) U59.K8(VDD.4) U59.N1(VDD.5) U59.N9(VDD.6) U59.R1(VDD.7) U59.R9(VDD.8) U60.A1(VDDQ.1) U60.A8(VDDQ.2) U60.B2(VDD.1) U60.C1(VDDQ.3) U60.C9(VDDQ.4) U60.D2(VDDQ.5) U60.D9(VDD.2) U60.E9(VDDQ.6) U60.F1(VDDQ.7) U60.G7(VDD.3) U60.H2(VDDQ.8) U60.H9(VDDQ.9) U60.K2(VDDL) U60.K8(VDD.4) U60.N1(VDD.5) U60.N9(VDD.6) U60.R1(VDD.7) U60.R9(VDD.8) U61.A2(VDD.1) U61.A9(VDD.2) U61.B9(VDDQ.1) U61.C1(VDDQ.2) U61.D7(VDD.3) U61.E2(VDDQ.3) U61.E9(VDDQ.4) U61.G2(VDD.4) U61.G8(VDD.5) U61.K1(VDD.6) U61.K9(VDD.7) U61.M1(VDD.8) U61.M9(VDD.9) U62.A2(VDD.1) U62.A9(VDD.2) U62.B9(VDDQ.1) U62.C1(VDDQ.2) U62.D7(VDD.3) U62.E2(VDDQ.3) U62.E9(VDDQ.4) U62.G2(VDD.4) U62.G8(VDD.5) U62.K1(VDD.6) U62.K9(VDD.7) U62.M1(VDD.8) U62.M9(VDD.9) U63.A2(VDD.1) U63.A9(VDD.2) U63.B9(VDDQ.1) U63.C1(VDDQ.2) U63.D7(VDD.3) U63.E2(VDDQ.3) U63.E9(VDDQ.4) U63.G2(VDD.4) U63.G8(VDD.5) U63.K1(VDD.6) U63.K9(VDD.7) U63.M1(VDD.8) U63.M9(VDD.9) U80.9(VIN-) U136.A2(VDD.1) U136.A9(VDD.2) U136.B9(VDDQ.1) U136.C1(VDDQ.2) U136.D7(VDD.3) U136.E2(VDDQ.3) U136.E9(VDDQ.4) U136.G2(VDD.4) U136.G8(VDD.5) U136.K1(VDD.6) U136.K9(VDD.7) U136.M1(VDD.8) U136.M9(VDD.9) U137.A2(VDD.1) U137.A9(VDD.2) U137.B9(VDDQ.1) U137.C1(VDDQ.2) U137.D7(VDD.3) U137.E2(VDDQ.3) U137.E9(VDDQ.4) U137.G2(VDD.4) U137.G8(VDD.5) U137.K1(VDD.6) U137.K9(VDD.7) U137.M1(VDD.8) U137.M9(VDD.9)
VDDR_SOC_1V35: C181.1 C182.1 C186.1 C187.1 C189.1 C193.1 C197.1 C501.1 C506.1 C509.1 C512.1 C513.1 C533.1 C534.1 C535.1 C536.1 C537.1 C538.1 C539.1 C551.1 J18.39 R642.1 U42.AA21(VDDS_DDR1_7) U42.AA23(VDDS_DDR1_8) U42.J23(VDDS_DDR2_1) U42.K22(VDDS_DDR2_2) U42.L21(VDDS_DDR2_3) U42.L23(VDDS_DDR2_4) U42.N21(VDDS_DDR2_5) U42.N23(VDDS_DDR2_6) U42.P22(VDDS_DDR2_7) U42.T22(VDDS_DDR1_1) U42.U23(VDDS_DDR1_2) U42.V22(VDDS_DDR1_3) U42.W21(VDDS_DDR1_4) U42.W23(VDDS_DDR1_5) U42.Y22(VDDS_DDR1_6) U79.9(VIN-)
VDDR_SOC_APM: J18.37 R642.2 R653.1 U79.8(VBUS) U79.10(VIN+) U134.7(VOUT.2) U134.8(VOUT.1)
VDDR_SOC_VREFSTL: C180.1 C216.1 C587.1 R282.2 U42.AB22(DDR1_VREF0) U42.M22(DDR2_VREF0) U138.12(VTTREF)
VDDR_VREFSTL: C201.1 C598.1 C599.1 C600.1 C605.1 C606.1 C612.1 C613.1 C642.1 C643.1 C647.1 C672.1 C679.1 C685.1 R277.2 R280.2 R282.1 U59.H1(VREFDQ) U59.M8(VREFCA) U60.H1(VREFDQ) U60.M8(VREFCA) U61.E1(VREFDQ) U61.J8(VREFCA) U62.E1(VREFDQ) U62.J8(VREFCA) U63.E1(VREFDQ) U63.J8(VREFCA) U136.E1(VREFDQ) U136.J8(VREFCA) U137.E1(VREFDQ) U137.J8(VREFCA)
VDDS_1V8: C150.1 C155.1 C379.1 C391.1 C392.1 C393.1 C394.1 C395.1 C411.1 C426.1 C436.1 C487.1 C493.1 J18.28 R219.1 U38.45(SMPS5_FDBK) U42.AA19(VDDS18V_DDR1_2) U42.AB8(VDDS18V_5) U42.H14(VDDS18V_1) U42.H20(VDDS18V_2) U42.H22(VDDS18V_DDR2_1) U42.M8(VDDS18V_3) U42.R7(VDDS_MLBP_1) U42.R21(VDDS18V_DDR2_2) U42.T8(VDDS_MLBP_2) U42.T20(VDDS18V_4) U42.U21(VDDS18V_DDR1_1) U70.9(VIN-) U122.6(IN2)
VDDS_1V8_APM: C160.1 J18.26 L18.1 R219.2 R220.2 U70.8(VBUS) U70.10(VIN+) U71.8(VBUS) U71.10(VIN+)
VDDS_1V8_SW5: L18.2 U38.47(SMPS5_SW)
VDDSHV11: C424.1 U42.H8(VDDSHV11_1) U122.7(OUT)
VDDSHV_3V3: C145.1 C149.1 C151.1 C152.1 C397.1 C398.1 C399.1 C421.1 C422.1 C425.1 C427.1 C432.1 C460.1 C476.1 J18.24 R514.2 U42.AA7(VDDSHV6_3) U42.AA14(VDDSHV5_1) U42.G7(VDDSHV1_1) U42.G9(VDDSHV1_2) U42.G11(VDDSHV2_1) U42.G13(VDDSHV2_2) U42.G15(VDDSHV3_1) U42.G17(VDDSHV3_2) U42.G19(VDDSHV3_3) U42.G21(VDDSHV4_1) U42.H12(VDDSHV2_3) U42.H16(VDDSHV3_4) U42.H18(VDDSHV3_5) U42.J7(VDDSHV10_1) U42.K8(VDDSHV10_2) U42.L7(VDDSHV10_3) U42.N7(VDDSHV9_1) U42.P8(VDDSHV9_2) U42.V8(VDDSHV7_1) U42.W7(VDDSHV6_1) U42.Y8(VDDSHV6_2) U81.9(VIN-)
VIN2_S0: R501.2 RU8.1(S0) U27.2(I) U110.6(P2)
VIN2_S0N: RU8.56(S1) U27.4(O)
VIN2_S2: R493.2 U23.2(I) U110.10(P6)
VIN2_S2N: RU4.1(S) RU8.55(S2) U23.4(O)
VIN6_SEL_S0: R538.2 RU18.1(S0) U110.5(P1) U121.2(I)
VIN[2]A_CLK: EXP_P2.61 RU4.2(1B1)
VIN[2]A_D[0]: EXP_P2.79 RU8.53(1B2)
VIN[2]A_D[1]: EXP_P2.80 RU8.51(2B2)
VIN[2]A_D[2]: EXP_P2.81 RU8.48(3B2)
VIN[2]A_D[3]: EXP_P2.82 RU8.46(4B2)
VIN[2]A_D[4]: EXP_P2.83 RU8.44(5B2)
VIN[2]A_D[5]: EXP_P2.84 RU8.42(6B2)
VIN[2]A_D[6]: EXP_P2.87 RU8.40(7B2)
VIN[2]A_D[7]: EXP_P2.88 RU8.37(8B2)
VIN[2]A_D[8]: EXP_P2.89 RU8.35(9B2)
VIN[2]A_D[9]: EXP_P2.90 RU8.33(10B2)
VIN[2]A_D[10]: EXP_P2.91 RU8.31(11B2)
VIN[2]A_D[11]: EXP_P2.92 RU8.29(12B2)
VIN[2]A_D[12]: EXP_P2.93 RU15.53(1B2)
VIN[2]A_D[13]: EXP_P2.94 RU15.51(2B2)
VIN[2]A_D[14]: EXP_P2.95 RU15.48(3B2)
VIN[2]A_D[15]: EXP_P2.96 RU15.46(4B2)
VIN[2]A_D[16]: EXP_P2.97 RU15.44(5B2)
VIN[2]A_D[17]: EXP_P2.98 RU15.42(6B2)
VIN[2]A_D[18]: EXP_P2.109 RU15.40(7B2)
VIN[2]A_D[19]: EXP_P2.110 RU15.37(8B2)
VIN[2]A_D[20]: EXP_P2.111 RU15.35(9B2)
VIN[2]A_D[21]: EXP_P2.112 RU15.33(10B2)
VIN[2]A_D[22]: EXP_P2.113 RU15.31(11B2)
VIN[2]A_D[23]: EXP_P2.114 RU15.29(12B2)
VIN[2]A_DE0: EXP_P2.63 RU4.5(2B1)
VIN[2]A_HSYNC: EXP_P2.62 RU4.11(3B1)
VIN[2]A_VSYNC: EXP_P2.64 RU4.14(4B1)
VIN[4]B_CLK1: EXP_P1.37 RU14.3(1B2)
VIN[4]B_D[0]: EXP_P1.27 RU14.6(2B2)
VIN[4]B_D[1]: EXP_P1.28 RU14.13(4B2)
VIN[4]B_D[2]: EXP_P1.25 RU14.10(3B2)
VIN[4]B_D[3]: EXP_P1.26 RU17.29(12B2)
VIN[4]B_D[4]: EXP_P1.23 RU17.31(11B2)
VIN[4]B_D[5]: EXP_P1.24 RU17.53(1B2)
VIN[4]B_D[6]: EXP_P1.21 RU17.51(2B2)
VIN[4]B_D[7]: EXP_P1.22 RU17.42(6B2)
VIN[4]B_HSYNC1: EXP_P1.31 RU17.35(9B2)
VIN[4]B_VSYNC1: EXP_P1.32 RU17.37(8B2)
VIN[6]A_D[0]: EXP_P2.13 RU18.47(4B1)
VIN[6]A_D[1]: EXP_P2.14 RU18.50(3B1)
VIN[6]A_D[2]: EXP_P2.15 RU18.52(2B1)
VIN[6]A_D[3]: EXP_P2.16 RU18.54(1B1)
VIN[6]A_D[7]: EXP_P2.17 RU18.45(5B1)
VIN[6]A_D[8]: EXP_P2.18 RJ10.1
VIN[6]A_D[9]: EXP_P2.19 RJ9.1
VIN[6]A_D[10]: EXP_P2.20 RJ8.1
VIN[6]A_D[11]: EXP_P2.21 RJ7.1
VIN_CONN: F1.2 J2.1 R441.2
VSSA_OSC0: C457.2 C474.2 R233.1 U42.AB15(VSSA_OSC0)
VSSA_OSC1: C517.2 C518.2 R243.1 U42.AC18(VSSA_OSC1) Y7.2(GND) Y7.4(GND1)
AIC_AVDD_DAC3.3: C183.1 C184.1 C185.1 L23.1 U50.25(AVDD_DAC)
AIC_BCLK: R240.2 R604.1 U50.38(BCLK)
AIC_DIN: R238.2 R605.1 U50.40(DIN)
AIC_DOUT: R237.2 U50.41(DOUT)
AIC_DRVDD3.3: C190.1 C191.1 C540.1 C541.1 C542.1 L24.1 U50.16(DRVDD.1) U50.17(DRVDD.2) U50.24(DRVDD.3)
AIC_DVDD3.3: C178.1 C179.1 U45.5(OUT) U50.36(DVDD.1)
AIC_IOVDD3.3: C171.1 C176.1 L22.2 U50.44(IOVDD)
AIC_MCA3_ACLKX: R240.1 RJ9.3 RU18.53(1B2)
AIC_MCA3_AFSX: R239.1 RJ10.3 RU18.51(2B2)
AIC_MCA3_AXR0: R238.1 RJ7.3 RU18.48(3B2)
AIC_MCA3_AXR1: R237.1 RJ8.3 RU18.46(4B2)
AIC_WCLK: R239.2 U50.39(WCLK)
APP_BD_PORZ: EXP_P2.76 R615.2 U141.11(GRSTZ)
AQSPI1_CS[0]: R135.1 R171.1
AQSPI1_D[0]: R144.1 R170.1
AQSPI1_D[1]: R133.2 R175.1
AQSPI1_D[2]: R131.2 R181.1
AQSPI1_D[3]: R151.1 R187.1
AQSPI1_RTCLK: R145.2 R173.1
AQSPI1_SCLK: R145.1 R146.2 R185.1
BT_EN: P9.89 U43.20(B2)
BT_UART_CTS: P9.70 U43.15(B7)
BT_UART_RTS: P9.72 U39.16(B6)
BT_UART_RX: P9.68 U43.14(B8)
BT_UART_TX: P9.66 U39.17(B5)
C_GPMC_A13: R172.1 R380.2 U104.6(A12)
C_GPMC_A14: R186.1 R383.2 U104.5(A13)
C_GPMC_A15: R180.1 R390.2 U104.4(A14)
C_GPMC_A16: R169.1 R392.2 U104.3(A15)
C_GPMC_A17: R174.1 R382.2 U104.54(A16)
C_GPMC_A18: R184.1 R359.2 U104.19(A17)
CAM_SPI[1]_SCLK: R272.1 RU21.9(3A)
CAMERA_CLK: R54.1 RU4.3(1B2)
CAMERA_D0: R355.1 RU8.3(1B3)
CAMERA_D1: R56.1 RU8.5(2B3)
CAMERA_D2: RN7.5(R4B) RU8.7(3B3)
CAMERA_D3: RN7.6(R3B) RU8.10(4B3)
CAMERA_D4: RN7.7(R2B) RU8.12(5B3)
CAMERA_D5: RN7.8(R1B) RU8.14(6B3)
CAMERA_D6: RN8.5(R4B) RU8.16(7B3)
CAMERA_D7: RN8.6(R3B) RU8.20(8B3)
CAMERA_D8: RN8.7(R2B) RU8.22(9B3)
CAMERA_D9: RN8.8(R1B) RU8.24(10B3)
CAMERA_D10: RN9.5(R4B) RU8.26(11B3)
CAMERA_D11: RN9.6(R3B) RU8.28(12B3)
CAMERA_D12: RN9.7(R2B) RU15.3(1B3)
CAMERA_D13: RN9.8(R1B) RU15.5(2B3)
CAMERA_HSYNC: R352.1 R457.2 R458.2
CAMERA_VSYNC: R55.1 RU4.13(4B2)
COMQ_MMC0_CLK: P9.20 U132.3(A)
COMQ_MMC0_CMD: P9.24 R620.2 U128.5(A4)
COMQ_MMC0_DAT0: P9.26 R621.2 U128.6(A5)
COMQ_MMC0_DAT1: P9.28 R622.2 U128.7(A6)
COMQ_MMC0_DAT2: P9.30 R623.2 U128.8(A7)
COMQ_MMC0_DAT3: P9.32 R619.2 U128.9(A8)
CON.PCIE_RXN0: P6.A17(PERN0) R90.2
CON.PCIE_RXN1: P6.A22(PERN1) R94.2
CON.PCIE_RXP0: P6.A16(PERP0) R89.2
CON.PCIE_RXP1: P6.A21(PERP1) R93.2
CON.PCIE_TXN0: C84.2 P6.B15(PETN0)
CON.PCIE_TXN1: C86.2 P6.B20(PETN1)
CON.PCIE_TXP0: C82.2 P6.B14(PETP0)
CON.PCIE_TXP1: C85.2 P6.B19(PETP1)
CON.SATA_RXN0: C132.1 J12.5
CON.SATA_RXP0: C130.1 J12.6
CON.SATA_TXN0: C133.1 J12.3
CON.SATA_TXP0: C134.1 J12.2
CON_LCD_GP0[31]: J19.38 R655.2
CON_LCD_I2C_SCL: J19.32 R657.2
CON_LCD_I2C_SDA: J19.34 R656.2
CON_LCD_PWR_DN: J19.40 R654.2 R666.1 U42.AD9(VIN1A_FLD0/VIN1B_VSYNC1/VOUT3_C)
CON_MMC1_CLK: P14.5(CLK) R332.2 R345.2 U98.3(IO1)
CON_MMC1_CMD: P14.3(CMD) R333.2 R346.2 U98.5(IO2)
CON_MMC1_DAT0: P14.7(DAT0) R331.2 R344.2 U97.5(IO2)
CON_MMC1_DAT1: P14.8(DAT1) R330.2 R343.2 U97.3(IO1)
CON_MMC1_DAT2: P14.1(DAT2) R335.2 R339.2 U99.5(IO2)
CON_MMC1_DAT3: P14.2(DAT3) R334.2 R347.2 U99.3(IO1)
CONN_USB1_DM: FL7.3 P8.2(D-) U120.6(D-)
CONN_USB1_DP: FL7.2 P8.3(D+) U120.7(D+)
CONN_USB2_DM: FL1.3 P2.2(D-) U92.6(D-)
CONN_USB2_DP: FL1.2 P2.3(D+) U92.7(D+)
CONN_USB_D+: J3.3(D+) U3.14(USBDP)
CONN_USB_D-: J3.2(D-) U3.15(USBDM)
CONN_USB_RXN0: FL9.3 P8.9(CON9) U35.1(IO)
CONN_USB_RXP0: FL9.2 P8.10(CON10) U36.1(IO)
CONN_USB_TXN0: FL8.3 P8.6(CON6) U33.1(IO)
CONN_USB_TXP0: FL8.2 P8.7(CON7) U34.1(IO)
CPU_POR_RESETN: R609.1 U46.2(A) U127.1(R\E\S\E\T)
CPU_RESETN: R608.1 U48.1(B) U126.1(R\E\S\E\T)
CSI2_I2C_SCL: J15.25 P15.2 R668.2 U135.3(SCL1)
CSI2_I2C_SDA: J15.24 P15.4 R669.2 U135.4(SDA1)
CSI2_REF_CLK: P15.10 R677.1 U124.9(A8)
CSI2_RESETN: J15.23 P15.14 U124.8(A7)
CSI2_SPI[1]_CS[0]N: J15.32 P15.22 U124.1(A1)
CSI2_SPI[1]_MISO: U124.3(A2)
CSI2_SPI[1]_MOSI: J15.30 P15.18 U124.5(A4)
CSI2_SPI[1]_SCLK: J15.31 P15.20 U124.4(A3)
D1_0N: FL10.3 J11.3
D1_0P: FL10.2 J11.1
D1_1N: FL11.3 J11.4
D1_1P: FL11.2 J11.2
D1_ACOUT0N: C319.2 FL10.4
D1_ACOUT0P: C318.2 FL10.1
D1_ACOUT1N: C322.2 FL11.4
D1_ACOUT1P: C321.2 FL11.1
D1_OUT0N: C319.1 U115.26(DOUT0-)
D1_OUT0P: C318.1 U115.27(DOUT0+)
D1_OUT1N: C322.1 U115.22(DOUT1-)
D1_OUT1P: C321.1 U115.23(DOUT1+)
DCAN2_MCAN_RX: JP1.2 RU22.6(2B2) U57.4(RXD)
DCAN2_MCAN_TX: JP1.1 R673.1 RU22.3(1B2) U57.1(TXD)
DET_USB1_VBUS: U30.20(P17) U95.4(O)
DET_USB2_VBUS: U30.19(P16) U94.4(O)
DISP1_CLK+: TP32.1 U115.50(IN_CLK+)
DISP1_CLK-: TP31.1 U115.49(IN_CLK-)
DISP1_D0+: TP34.1 U115.56(IN_D0+)
DISP1_D0-: TP33.1 U115.55(IN_D0-)
DISP1_D1+: TP36.1 U115.60(IN_D1+)
DISP1_D1-: TP35.1 U115.59(IN_D1-)
DISP1_D2+: TP38.1 U115.63(IN_D2+)
DISP1_D2-: TP37.1 U115.62(IN_D2-)
DISP1_VPOC_ONN: Q3.G R51.2 U110.16(P13)
DISP2_VPOC_ONN: Q5.G R47.2 RU7.44(5B2)
DISP_SCL: R657.1 R736.2 U8.8(SCL) U146.6(SCL2)
DISP_SDA: R656.1 R735.2 U8.9(SDA) U146.5(SDA2)
EMAC[0]_RXC: RU17.54(1B1) U101.43(RX_CLK)
EMAC[0]_RXCTL: R356.1 R357.1 RU17.52(2B1) U101.53(RX_DV/RX_CTRL)
EMAC[0]_RXD0: R367.2 R373.1 RU17.50(3B1) U101.44(RX_D0)
EMAC[0]_RXD1: RU17.47(4B1) U101.45(RX_D1)
EMAC[0]_RXD2: R368.1 R374.2 RU17.45(5B1) U101.46(RX_D2)
EMAC[0]_RXD3: RU17.43(6B1) U101.47(RX_D3)
EMAC[0]_TXC: RU17.30(12B1) U101.40(GTX_CLK)
EMAC[0]_TXCTL: RU17.32(11B1) U101.52(TX_EN/TX_CTRL)
EMAC[0]_TXD0: RU17.41(7B1) U101.38(TX_D0)
EMAC[0]_TXD1: RU17.39(8B1) U101.37(TX_D1)
EMAC[0]_TXD2: RU17.36(9B1) U101.36(TX_D2)
EMAC[0]_TXD3: RU17.34(10B1) U101.35(TX_D3)
EMAC[1]_RXC: RU15.41(7B1) U108.43(RX_CLK)
EMAC[1]_RXCTL: R421.1 R424.1 RU15.39(8B1) U108.53(RX_DV/RX_CTRL)
EMAC[1]_RXD0: R430.2 R432.1 RU15.30(12B1) U108.44(RX_D0)
EMAC[1]_RXD1: RU15.32(11B1) U108.45(RX_D1)
EMAC[1]_RXD2: R431.1 R433.2 RU15.34(10B1) U108.46(RX_D2)
EMAC[1]_RXD3: RU15.36(9B1) U108.47(RX_D3)
EMAC[1]_TXC: RU15.54(1B1) U108.40(GTX_CLK)
EMAC[1]_TXCTL: RU15.52(2B1) U108.52(TX_EN/TX_CTRL)
EMAC[1]_TXD0: RU15.43(6B1) U108.38(TX_D0)
EMAC[1]_TXD1: RU15.45(5B1) U108.37(TX_D1)
EMAC[1]_TXD2: RU15.47(4B1) U108.36(TX_D2)
EMAC[1]_TXD3: RU15.50(3B1) U108.35(TX_D3)
EMU_RSTN: J13.6(NRESET) R659.2 U48.2(A)
EN_TPS43351: R150.2 R492.1 U18.16(ENA) U18.17(ENB)
ENET_INT_P0: R348.2 U101.60(INT/PWDN) U107.1(B)
ENET_INT_P1: R403.2 U107.2(A) U108.60(INT/PWDN)
ENET_PORZ: R616.2 U103.1(B) U106.1(B)
EXP_ETH0_RSTN: U30.13(P10) U103.2(A)
EXP_ETH1_RSTN: U30.14(P11) U106.2(A)
EXVIN2_S0: R730.2 RU15.1(S0) U110.14(P11) U145.2(I)
EXVIN2_S0N: RU15.56(S1) U145.4(O)
EXVIN2_S2: R729.2 U110.15(P12) U144.2(I)
EXVIN2_S2N: RU15.55(S2) U144.4(O)
FLASH_BYTE: R377.2 R378.1 U104.53(B\Y\T\E)
FLASH_WP: R363.1 R364.2 U104.16(W\P\/ACC)
FPD_DOUT+: C19.2 FL2.1
FPD_DOUT-: C20.2 FL2.4
FTDI_ISO_ENN: Q13.D R625.2 U129.1(OE) U130.1(OE) U131.1(OE) U133.1(OE) U142.1(OE) U143.1(OE)
FTDI_UARTIN: U3.2(RXD) U142.4(O)
FTDI_UARTOUT: U3.30(TXD) U143.4(O)
GA1: R402.2 U18.6(GA1)
GA2: R417.2 U18.8(GA2)
GB1: R401.2 U18.33(GB1)
GB2: R414.2 U18.31(GB2)
GP5[22]: EXP_P1.33 RU17.33(10B2)
GP5[25]: EXP_P1.35 RU17.40(7B2)
GP5[29]: EXP_P1.34 RU17.44(5B2)
GP5[30]: EXP_P1.36 RU17.46(4B2)
GP5[31]: EXP_P1.38 RU17.48(3B2)
GPIO1_24: TP97.1 U42.AB7(MMC3_DAT6/SPI4_D0/UART10_CTSN/U)
GPIO_SPARE_EXP1_P15: J17.21 R745.2 SW10.5(B4) U30.18(P15)
GPIO_SPARE_EXP2_P2: J17.22 R748.2 SW10.8(B1) U21.6(P2)
GPIO_SPARE_EXP2_P6: J17.23 R747.2 SW10.7(B2) U21.10(P6)
GPIO_SPARE_EXP2_P7: J17.24 R746.2 SW10.6(B3) U21.11(P7)
GPMC_A1: RU16.43(6B1) U104.31(A0)
GPMC_A2: RU16.41(7B1) U104.26(A1)
GPMC_A3: RU16.39(8B1) U104.25(A2)
GPMC_A4: RU16.36(9B1) U104.24(A3)
GPMC_A5: RU16.34(10B1) U104.23(A4)
GPMC_A6: RU16.32(11B1) U104.22(A5)
GPMC_A7: RU16.30(12B1) U104.21(A6)
GPMC_A8: RU7.54(1B1) U104.20(A7)
GPMC_A9: RU7.52(2B1) U104.10(A8)
GPMC_A10: RU7.50(3B1) U104.9(A9)
GPMC_A11: RU7.47(4B1) U104.8(A10)
GPMC_A12: RU7.45(5B1) U104.7(A11)
GPMC_A19: R360.2 RU5.54(1B1) U104.18(A18)
GPMC_A20: R376.2 RU5.52(2B1) U104.11(A19)
GPMC_A21: R375.2 RU5.50(3B1) U104.12(A20)
GPMC_A22: R366.2 RU5.47(4B1) U104.15(A21)
GPMC_A23: R397.2 RU5.45(5B1) U104.2(A22)
GPMC_A24: R396.2 RU5.43(6B1) U104.1(A23)
GPMC_A25: R393.2 RU5.41(7B1) U104.56(A24)
GPMC_A26: R391.2 RU5.39(8B1) U104.55(A25/NC4)
GPMC_D00: R113.1 R440.2 RU16.47(4B1) SW3.1(A1) U12.29(I/O0) U104.35(DQ0)
GPMC_D01: R114.1 R439.2 RU16.50(3B1) SW3.2(A2) U12.30(I/O1) U104.37(DQ1)
GPMC_D02: R115.1 R438.2 RU16.52(2B1) SW3.3(A3) U12.31(I/O2) U104.39(DQ2)
GPMC_D03: R116.1 R437.2 RU16.54(1B1) SW3.4(A4) U12.32(I/O3) U104.41(DQ3)
GPMC_D04: R117.1 R436.2 RU13.30(12B1) SW3.5(A5) U12.41(I/O4) U104.44(DQ4)
GPMC_D05: R118.1 R435.2 RU13.32(11B1) SW3.6(A6) U12.42(I/O5) U104.46(DQ5)
GPMC_D06: R119.1 RU13.34(10B1) SW3.7(A7) U12.43(I/O6) U104.48(DQ6)
GPMC_D07: R120.1 RU13.36(9B1) SW3.8(A8) U12.44(I/O7) U104.50(DQ7)
GPMC_D08: R121.1 RU13.39(8B1) SW4.1(A1) U12.26(I/O8) U104.36(DQ8)
GPMC_D09: R122.1 RU13.41(7B1) SW4.2(A2) U12.27(I/O9) U104.38(DQ9)
GPMC_D10: R123.1 RU13.43(6B1) SW4.3(A3) U12.28(I/O10) U104.40(DQ10)
GPMC_D11: R124.1 RU13.45(5B1) SW4.4(A4) U12.33(I/O11) U104.42(DQ11)
GPMC_D12: R125.1 RU13.47(4B1) SW4.5(A5) U12.40(I/O12) U104.45(DQ12)
GPMC_D13: R126.1 RU13.50(3B1) SW4.6(A6) U12.45(I/O13) U104.47(DQ13)
GPMC_D14: R127.1 RU13.52(2B1) SW4.7(A7) U12.46(I/O14) U104.49(DQ14)
GPMC_D15: R128.1 RU13.54(1B1) SW4.8(A8) U12.47(I/O15) U104.51(DQ15/A-1)
GPMC_WPN: R134.2 SW6.12 U12.19(\\W\P)
GPS_PPS_OUT: P9.50 U39.19(B3)
GPS_TIME_STAMP: P9.48 U43.18(B4)
H_AIC3106_MCLK: R241.1 R252.2
H_CAM_SPI[1]_CS[0]N: R245.1 RU21.4(1A)
H_CAM_SPI[1]_MISO: R216.1 RU21.7(2A)
H_CAM_SPI[1]_MOSI: R235.1 RU21.12(4A)
H_CSI2_0_DX0: J15.8 P15.5 U42.AD17(CSI2_0_DX0)
H_CSI2_0_DX1: J15.11 P15.9 U42.AF16(CSI2_0_DX1)
H_CSI2_0_DX2: J15.14 P15.13 U42.AF19(CSI2_0_DX2)
H_CSI2_0_DX3: J15.17 P15.17 U42.AE15(CSI2_0_DX3)
H_CSI2_0_DX4: J15.20 P15.21 U42.AE19(CSI2_0_DX4)
H_CSI2_0_DY0: J15.9 P15.7 U42.AD18(CSI2_0_DY0)
H_CSI2_0_DY1: J15.12 P15.11 U42.AF17(CSI2_0_DY1)
H_CSI2_0_DY2: J15.15 P15.15 U42.AF20(CSI2_0_DY2)
H_CSI2_0_DY3: J15.18 P15.19 U42.AE16(CSI2_0_DY3)
H_CSI2_0_DY4: J15.21 P15.23 U42.AE18(CSI2_0_DY4)
H_CSI2_1_DX0: P15.25 U42.AC13(CSI2_1_DX0)
H_CSI2_1_DX1: P15.29 U42.AD15(CSI2_1_DX1)
H_CSI2_1_DX2: P15.33 U42.AC16(CSI2_1_DX2)
H_CSI2_1_DY0: P15.27 U42.AC14(CSI2_1_DY0)
H_CSI2_1_DY1: P15.31 U42.AD14(CSI2_1_DY1)
H_CSI2_1_DY2: P15.35 U42.AC17(CSI2_1_DY2)
H_DCAN1_MCAN_RX: JP2.2 U42.D19(DCAN1(MCAN)_RX/UART8_TXD/MMC2_S) U58.4(RXD)
H_DCAN1_MCAN_TX: JP2.1 R670.1 U42.E19(DCAN1(MCAN)_TX/UART8_RXD/MMC2_S) U58.1(TXD)
H_DDR1_A0: RN13.4(R4A) U42.AE22(DDR1_A0) U59.N3(A0) U60.N3(A0) U63.K3(A0)
H_DDR1_A1: RN4.4(R4A) U42.AD20(DDR1_A1) U59.P7(A1) U60.P7(A1) U63.L7(A1)
H_DDR1_A2: RN13.2(R2A) U42.AE21(DDR1_A2) U59.P3(A2) U60.P3(A2) U63.L3(A2)
H_DDR1_A3: RN13.3(R3A) U42.AD22(DDR1_A3) U59.N2(A3) U60.N2(A3) U63.K2(A3)
H_DDR1_A4: RN6.1(R1A) U42.AE23(DDR1_A4) U59.P8(A4) U60.P8(A4) U63.L8(A4)
H_DDR1_A5: RN13.1(R1A) U42.AH22(DDR1_A5) U59.P2(A5) U60.P2(A5) U63.L2(A5)
H_DDR1_A6: RN6.2(R2A) U42.AD24(DDR1_A6) U59.R8(A6) U60.R8(A6) U63.M8(A6)
H_DDR1_A7: RN15.4(R4A) U42.AC22(DDR1_A7) U59.R2(A7) U60.R2(A7) U63.M2(A7)
H_DDR1_A8: RN15.3(R3A) U42.AG23(DDR1_A8) U59.T8(A8) U60.T8(A8) U63.N8(A8)
H_DDR1_A9: RN6.3(R3A) U42.AF24(DDR1_A9) U59.R3(A9) U60.R3(A9) U63.M3(A9)
H_DDR1_A10: RN2.2(R2A) U42.AD21(DDR1_A10) U59.L7(A10) U60.L7(A10) U63.H7(A10/AP)
H_DDR1_A11: RN6.4(R4A) U42.AE24(DDR1_A11) U59.R7(A11) U60.R7(A11) U63.M7(A11)
H_DDR1_A12: RN4.2(R2A) U42.AG21(DDR1_A12) U59.N7(A12) U60.N7(A12) U63.K7(A12/B\C\)
H_DDR1_A13: RN15.1(R1A) U42.AF21(DDR1_A13) U59.T3(A13) U60.T3(A13) U63.N3(A13)
H_DDR1_A14: RN15.2(R2A) U42.AC23(DDR1_A14) U59.T7(A14) U60.T7(A14) U63.N7(A14/NC)
H_DDR1_A15: RN4.1(R1A) U42.AG20(DDR1_A15) U59.M7(NC.M7/A15) U60.M7(NC.M7/A15) U63.J7(A15/NC)
H_DDR1_BA0: RN2.3(R3A) U42.AE20(DDR1_BA0) U59.M2(BA0) U60.M2(BA0) U63.J2(BA0)
H_DDR1_BA1: RN4.3(R3A) U42.AC21(DDR1_BA1) U59.N8(BA1) U60.N8(BA1) U63.K8(BA1)
H_DDR1_BA2: RN2.4(R4A) U42.AH21(DDR1_BA2) U59.M3(BA2) U60.M3(BA2) U63.J3(BA2)
H_DDR1_CASN: RN11.3(R3A) U42.AG19(DDR1_CASN) U59.K3(CAS#) U60.K3(CAS#) U63.G3(C\A\S\)
H_DDR1_CKE: R685.1 R686.1 U42.AH23(DDR1_CKE) U59.K9(CKE) U60.K9(CKE) U63.G9(CKE)
H_DDR1_CLK_N: R684.1 U42.AH24(DDR1_NCK) U59.K7(CK#) U60.K7(CK#) U63.G7(C\K\)
H_DDR1_CLK_P: R675.1 U42.AG24(DDR1_CK) U59.J7(CK) U60.J7(CK) U63.F7(CK)
H_DDR1_CSN0: RN11.1(R1A) U42.AD23(DDR1_CSN0) U59.L2(CS#) U60.L2(CS#) U63.H2(C\S\)
H_DDR1_D0: U42.AE26(DDR1_D0) U59.H8(DQ5)
H_DDR1_D1: U42.AE27(DDR1_D1) U59.H3(DQ4)
H_DDR1_D2: U42.AF28(DDR1_D2) U59.H7(DQ7)
H_DDR1_D3: U42.AH26(DDR1_D3) U59.E3(DQ0)
H_DDR1_D4: U42.AF25(DDR1_D4) U59.F2(DQ2)
H_DDR1_D5: U42.AG27(DDR1_D5) U59.F7(DQ1)
H_DDR1_D6: U42.AF27(DDR1_D6) U59.F8(DQ3)
H_DDR1_D7: U42.AF26(DDR1_D7) U59.G2(DQ6)
H_DDR1_D8: U42.AB24(DDR1_D8) U59.D7(DQ8)
H_DDR1_D9: U42.AD27(DDR1_D9) U59.B8(DQ14)
H_DDR1_D10: U42.AE28(DDR1_D10) U59.A7(DQ12)
H_DDR1_D11: U42.AD28(DDR1_D11) U59.C8(DQ10)
H_DDR1_D12: U42.AD26(DDR1_D12) U59.C2(DQ11)
H_DDR1_D13: U42.AE25(DDR1_D13) U59.A2(DQ13)
H_DDR1_D14: U42.AD25(DDR1_D14) U59.C3(DQ9)
H_DDR1_D15: U42.AC26(DDR1_D15) U59.A3(DQ15)
H_DDR1_D16: U42.AA25(DDR1_D16) U60.F8(DQ3)
H_DDR1_D17: U42.AB25(DDR1_D17) U60.F2(DQ2)
H_DDR1_D18: U42.AA26(DDR1_D18) U60.H7(DQ7)
H_DDR1_D19: U42.AA28(DDR1_D19) U60.H3(DQ4)
H_DDR1_D20: U42.AA27(DDR1_D20) U60.E3(DQ0)
H_DDR1_D21: U42.AA24(DDR1_D21) U60.F7(DQ1)
H_DDR1_D22: U42.AC25(DDR1_D22) U60.G2(DQ6)
H_DDR1_D23: U42.Y26(DDR1_D23) U60.H8(DQ5)
H_DDR1_D24: U42.W26(DDR1_D24) U60.A7(DQ12)
H_DDR1_D25: U42.AB23(DDR1_D25) U60.A2(DQ13)
H_DDR1_D26: U42.V24(DDR1_D26) U60.B8(DQ14)
H_DDR1_D27: U42.Y24(DDR1_D27) U60.C2(DQ11)
H_DDR1_D28: U42.W25(DDR1_D28) U60.C8(DQ10)
H_DDR1_D29: U42.Y25(DDR1_D29) U60.C3(DQ9)
H_DDR1_D30: U42.W24(DDR1_D30) U60.A3(DQ15)
H_DDR1_D31: U42.Y28(DDR1_D31) U60.D7(DQ8)
H_DDR1_DQM0: U42.AG26(DDR1_DQM0) U59.E7(LDM)
H_DDR1_DQM1: U42.AC24(DDR1_DQM1) U59.D3(UDM)
H_DDR1_DQM2: U42.AB26(DDR1_DQM2) U60.E7(LDM)
H_DDR1_DQM3: U42.Y27(DDR1_DQM3) U60.D3(UDM)
H_DDR1_DQS0_N: U42.AG25(DDR1_DQSN0) U59.G3(LDQS#)
H_DDR1_DQS0_P: U42.AH25(DDR1_DQS0) U59.F3(LDQS)
H_DDR1_DQS1_N: U42.AC28(DDR1_DQSN1) U59.B7(UDQS#)
H_DDR1_DQS1_P: U42.AC27(DDR1_DQS1) U59.C7(UDQS)
H_DDR1_DQS2_N: U42.AB28(DDR1_DQSN2) U60.G3(LDQS#)
H_DDR1_DQS2_P: U42.AB27(DDR1_DQS2) U60.F3(LDQS)
H_DDR1_DQS3_N: U42.W27(DDR1_DQSN3) U60.B7(UDQS#)
H_DDR1_DQS3_P: U42.W28(DDR1_DQS3) U60.C7(UDQS)
H_DDR1_ECC_D0: U42.U25(DDR1_ECC_D0) U63.E8(DQ5)
H_DDR1_ECC_D1: U42.U26(DDR1_ECC_D1) U63.E7(DQ7)
H_DDR1_ECC_D2: U42.V25(DDR1_ECC_D2) U63.C2(DQ2)
H_DDR1_ECC_D3: U42.V26(DDR1_ECC_D3) U63.D2(DQ6)
H_DDR1_ECC_D4: U42.V27(DDR1_ECC_D4) U63.E3(DQ4)
H_DDR1_ECC_D5: U42.T28(DDR1_ECC_D5) U63.C8(DQ3)
H_DDR1_ECC_D6: U42.T26(DDR1_ECC_D6) U63.C7(DQ1)
H_DDR1_ECC_D7: U42.V28(DDR1_ECC_D7) U63.B3(DQ0)
H_DDR1_ECC_DQM: U42.T27(DDR1_DQM_ECC) U63.B7(DM/TDQS)
H_DDR1_ECC_DQS_N: U42.U28(DDR1_DQSN_ECC) U63.D3(D\Q\S\)
H_DDR1_ECC_DQS_P: U42.U27(DDR1_DQS_ECC) U63.C3(DQS)
H_DDR1_ODT0: RN2.1(R1A) U42.AF22(DDR1_ODT0) U59.K1(ODT) U60.K1(ODT) U63.G1(ODT)
H_DDR1_RASN: RN11.4(R4A) U42.AH20(DDR1_RASN) U59.J3(RAS#) U60.J3(RAS#) U63.F3(R\A\S\)
H_DDR1_RST: R292.1 R296.1 U59.T2(RSTN) U60.T2(RSTN) U63.N2(R\E\S\E\T\)
H_DDR1_WEN: RN11.2(R2A) U42.AG22(DDR1_WEN) U59.L3(WE#) U60.L3(WE#) U63.H3(W\E\)
H_DDR2_A0: RN12.1(R1A) TP2MA15.1 TP2MB15.1 U42.P25(DDR2_A0) U61.K3(A0) U62.K3(A0) U136.K3(A0) U137.K3(A0)
H_DDR2_A1: RN14.4(R4A) TP2MA19.1 TP2MB19.1 U42.P26(DDR2_A1) U61.L7(A1) U62.L7(A1) U136.L7(A1) U137.L7(A1)
H_DDR2_A2: RN3.3(R3A) TP2MA20.1 TP2MB20.1 U42.P28(DDR2_A2) U61.L3(A2) U62.L3(A2) U136.L3(A2) U137.L3(A2)
H_DDR2_A3: RN3.1(R1A) TP2MA14.1 TP2MB14.1 U42.P27(DDR2_A3) U61.K2(A3) U62.K2(A3) U136.K2(A3) U137.K2(A3)
H_DDR2_A4: RN3.4(R4A) TP2MA17.1 TP2MB17.1 U42.P24(DDR2_A4) U61.L8(A4) U62.L8(A4) U136.L8(A4) U137.L8(A4)
H_DDR2_A5: RN3.2(R2A) TP2MA18.1 TP2MB18.1 U42.P23(DDR2_A5) U61.L2(A5) U62.L2(A5) U136.L2(A5) U137.L2(A5)
H_DDR2_A6: RN5.3(R3A) TP2MA24.1 TP2MB24.1 U42.N26(DDR2_A6) U61.M8(A6) U62.M8(A6) U136.M8(A6) U137.M8(A6)
H_DDR2_A7: RN14.3(R3A) TP2MA23.1 TP2MB23.1 U42.M25(DDR2_A7) U61.M2(A7) U62.M2(A7) U136.M2(A7) U137.M2(A7)
H_DDR2_A8: RN14.1(R1A) TP2MA27.1 TP2MB27.1 U42.N28(DDR2_A8) U61.N8(A8) U62.N8(A8) U136.N8(A8) U137.N8(A8)
H_DDR2_A9: RN5.1(R1A) TP2MA21.1 TP2MB21.1 U42.M27(DDR2_A9) U61.M3(A9) U62.M3(A9) U136.M3(A9) U137.M3(A9)
H_DDR2_A10: RN1.1(R1A) TP2MA7.1 TP2MB7.1 U42.L25(DDR2_A10) U61.H7(A10/AP) U62.H7(A10/AP) U136.H7(A10/AP) U137.H7(A10/AP)
H_DDR2_A11: RN5.2(R2A) TP2MA22.1 TP2MB22.1 U42.N27(DDR2_A11) U61.M7(A11) U62.M7(A11) U136.M7(A11) U137.M7(A11)
H_DDR2_A12: RN12.3(R3A) TP2MA16.1 TP2MB16.1 U42.M28(DDR2_A12) U61.K7(A12/B\C\) U62.K7(A12/B\C\) U136.K7(A12/B\C\) U137.K7(A12/B\C\)
H_DDR2_A13: RN14.2(R2A) TP2MA26.1 TP2MB26.1 U42.R24(DDR2_A13) U61.N3(A13) U62.N3(A13) U136.N3(A13) U137.N3(A13)
H_DDR2_A14: RN5.4(R4A) TP2MA25.1 TP2MB25.1 U42.N24(DDR2_A14) U61.N7(A14/NC) U62.N7(A14/NC) U136.N7(A14/NC) U137.N7(A14/NC)
H_DDR2_A15: RN1.3(R3A) TP2MA12.1 TP2MB12.1 U42.R23(DDR2_A15) U61.J7(A15/NC) U62.J7(A15/NC) U136.J7(A15/NC) U137.J7(A15/NC)
H_DDR2_BA0: RN10.3(R3A) TP2MA10.1 TP2MB10.1 U42.L24(DDR2_BA0) U61.J2(BA0) U62.J2(BA0) U136.J2(BA0) U137.J2(BA0)
H_DDR2_BA1: RN12.2(R2A) TP2MA13.1 TP2MB13.1 U42.U24(DDR2_BA1) U61.K8(BA1) U62.K8(BA1) U136.K8(BA1) U137.K8(BA1)
H_DDR2_BA2: RN12.4(R4A) TP2MA11.1 TP2MB11.1 U42.M24(DDR2_BA2) U61.J3(BA2) U62.J3(BA2) U136.J3(BA2) U137.J3(BA2)
H_DDR2_CASN: RN10.2(R2A) TP2MA6.1 TP2MB6.1 U42.T25(DDR2_CASN) U61.G3(C\A\S\) U62.G3(C\A\S\) U136.G3(C\A\S\) U137.G3(C\A\S\)
H_DDR2_CKE: R276.1 R672.1 TP2MA1.1 TP2MB1.1 U42.R25(DDR2_CKE) U61.G9(CKE) U62.G9(CKE) U136.G9(CKE) U137.G9(CKE)
H_DDR2_CLK_N: R676.1 TP2MA5.1 TP2MB5.1 U42.R27(DDR2_NCK) U61.G7(C\K\) U62.G7(C\K\) U136.G7(C\K\) U137.G7(C\K\)
H_DDR2_CLK_P: R674.1 TP2MA4.1 TP2MB4.1 U42.R28(DDR2_CK) U61.F7(CK) U62.F7(CK) U136.F7(CK) U137.F7(CK)
H_DDR2_CSN0: RN10.1(R1A) TP2MA8.1 TP2MB8.1 U42.M26(DDR2_CSN0) U61.H2(C\S\) U62.H2(C\S\) U136.H2(C\S\) U137.H2(C\S\)
H_DDR2_D0: U42.C28(DDR2_D0) U136.C8(DQ3)
H_DDR2_D1: U42.A26(DDR2_D1) U136.E7(DQ7)
H_DDR2_D2: U42.E24(DDR2_D2) U136.D2(DQ6)
H_DDR2_D3: U42.D25(DDR2_D3) U136.C2(DQ2)
H_DDR2_D4: U42.D26(DDR2_D4) U136.C7(DQ1)
H_DDR2_D5: U42.B27(DDR2_D5) U136.E3(DQ4)
H_DDR2_D6: U42.B26(DDR2_D6) U136.E8(DQ5)
H_DDR2_D7: U42.C26(DDR2_D7) U136.B3(DQ0)
H_DDR2_D8: U42.F26(DDR2_D8) U62.C7(DQ1)
H_DDR2_D9: U42.E25(DDR2_D9) U62.C8(DQ3)
H_DDR2_D10: U42.E26(DDR2_D10) U62.E8(DQ5)
H_DDR2_D11: U42.G27(DDR2_D11) U62.B3(DQ0)
H_DDR2_D12: U42.E28(DDR2_D12) U62.E7(DQ7)
H_DDR2_D13: U42.G26(DDR2_D13) U62.D2(DQ6)
H_DDR2_D14: U42.G28(DDR2_D14) U62.C2(DQ2)
H_DDR2_D15: U42.F25(DDR2_D15) U62.E3(DQ4)
H_DDR2_D16: U42.G25(DDR2_D16) U137.B3(DQ0)
H_DDR2_D17: U42.G24(DDR2_D17) U137.C8(DQ3)
H_DDR2_D18: U42.F23(DDR2_D18) U137.D2(DQ6)
H_DDR2_D19: U42.F24(DDR2_D19) U137.C2(DQ2)
H_DDR2_D20: U42.H28(DDR2_D20) U137.C7(DQ1)
H_DDR2_D21: U42.H25(DDR2_D21) U137.E8(DQ5)
H_DDR2_D22: U42.H27(DDR2_D22) U137.E7(DQ7)
H_DDR2_D23: U42.H26(DDR2_D23) U137.E3(DQ4)
H_DDR2_D24: U42.K27(DDR2_D24) U61.D2(DQ6)
H_DDR2_D25: U42.K26(DDR2_D25) U61.E3(DQ4)
H_DDR2_D26: U42.J25(DDR2_D26) U61.C7(DQ1)
H_DDR2_D27: U42.K28(DDR2_D27) U61.B3(DQ0)
H_DDR2_D28: U42.H24(DDR2_D28) U61.E8(DQ5)
H_DDR2_D29: U42.J24(DDR2_D29) U61.C8(DQ3)
H_DDR2_D30: U42.K24(DDR2_D30) U61.E7(DQ7)
H_DDR2_D31: U42.L26(DDR2_D31) U61.C2(DQ2)
H_DDR2_DQM0: U42.C27(DDR2_DQM0) U136.B7(DM/TDQS)
H_DDR2_DQM1: U42.E27(DDR2_DQM1) U62.B7(DM/TDQS)
H_DDR2_DQM2: U42.G23(DDR2_DQM2) U137.B7(DM/TDQS)
H_DDR2_DQM3: U42.J26(DDR2_DQM3) U61.B7(DM/TDQS)
H_DDR2_DQS0_N: U42.D27(DDR2_DQSN0) U136.D3(D\Q\S\)
H_DDR2_DQS0_P: U42.D28(DDR2_DQS0) U136.C3(DQS)
H_DDR2_DQS1_N: U42.F28(DDR2_DQSN1) U62.D3(D\Q\S\)
H_DDR2_DQS1_P: U42.F27(DDR2_DQS1) U62.C3(DQS)
H_DDR2_DQS2_N: U42.J28(DDR2_DQSN2) U137.D3(D\Q\S\)
H_DDR2_DQS2_P: U42.J27(DDR2_DQS2) U137.C3(DQS)
H_DDR2_DQS3_N: U42.L27(DDR2_DQSN3) U61.D3(D\Q\S\)
H_DDR2_DQS3_P: U42.L28(DDR2_DQS3) U61.C3(DQS)
H_DDR2_ODT0: RN1.2(R2A) TP2MA3.1 TP2MB3.1 U42.K25(DDR2_ODT0) U61.G1(ODT) U62.G1(ODT) U136.G1(ODT) U137.G1(ODT)
H_DDR2_RASN: R278.1 TP2MA2.1 TP2MB2.1 U42.R26(DDR2_RASN) U61.F3(R\A\S\) U62.F3(R\A\S\) U136.F3(R\A\S\) U137.F3(R\A\S\)
H_DDR2_RST: R698.1 R699.1 U61.N2(R\E\S\E\T\) U62.N2(R\E\S\E\T\) U136.N2(R\E\S\E\T\) U137.N2(R\E\S\E\T\)
H_DDR2_WEN: RN1.4(R4A) TP2MA9.1 TP2MB9.1 U42.T24(DDR2_WEN) U61.H3(W\E\) U62.H3(W\E\) U136.H3(W\E\) U137.H3(W\E\)
H_EMU0: J13.19(TRD0.1) R593.1 R638.2
H_EMU1: J13.21(TRD0.2) R611.1 R637.2
H_ENET_INTSN: R394.1 U42.F18(GPIO6_16/MCASP1_AXR10/VOUT2_FLD)
H_GP1[2]_TOUCH_EVT: EXP_P1.13 R257.2 R259.1 R655.1 TP73.1(TP) U42.AB20(WAKEUP2/SYS_NIRQ2/GPIO1_2)
H_GP1[3]: EXP_P1.14 R253.1 R400.1 R497.1 R498.1 R502.2 TP72.1(TP) U42.AB21(WAKEUP3/SYS_NIRQ1/GPIO1_3)
H_GP2[22]: TP55.1 U42.L6(GPMC_CLK/GPMC_CS7/CLKOUT1/GPMC_)
H_GP2[27]: EXP_P2.108 U42.M4(GPMC_BEN1/GPMC_CS5/VIN1B_DE1/VI)
H_GP5[0]: EXP_P2.34 R434.2 U42.A13(MCASP1_ACLKR/MCASP7_AXR2/VOUT2_)
H_GP5[1]: EXP_P2.36 U42.F14(MCASP1_FSR/MCASP7_AXR3/VOUT2_D1)
H_GP5[4]: U42.E13(MCASP1_AXR2/MCASP6_AXR2/UART6_C) U43.4(A2)
H_GP5[5]: U39.5(A3) U42.E11(MCASP1_AXR3/MCASP6_AXR3/UART6_R)
H_GP5[6]: U42.E12(MCASP1_AXR4/MCASP4_AXR2/VOUT2_D) U43.6(A4)
H_GP5[7]: U39.3(A1) U42.D13(MCASP1_AXR5/MCASP4_AXR3/VOUT2_D)
H_GP5[8]: U42.C11(MCASP1_AXR6/MCASP5_AXR2/VOUT2_D) U43.5(A3)
H_GP5[9]: P5.34 U42.D12(MCASP1_AXR7/MCASP5_AXR3/VOUT2_D)
H_GP5[17]: EXP_P2.32 U42.U2(RMII_MHZ_50_CLK/VIN2A_D11/XX/GP)
H_GP6[17]: EXP_P1.15 U42.D18(XREF_CLK0/MCASP2_AXR8/MCASP1_AX)
H_GP6[20]: EXP_P3.13 U42.A22(XREF_CLK3/MCASP2_AXR11/MCASP1_A)
H_GP6[28]: P5.24 U42.V6(MMC1_SDWP/UART6_TXD/I2C4_SCL/GP)
H_GPMC_A0: RU16.11(5A1) U42.P6(GPMC_A0/VIN3A_D16/VOUT3_D16/VIN)
H_GPMC_A1: RU16.13(6A1) U42.J6(GPMC_A1/VIN3A_D17/VOUT3_D17/VIN)
H_GPMC_A2: RU16.15(7A1) U42.R4(GPMC_A2/VIN3A_D18/VOUT3_D18/VIN)
H_GPMC_A3: RU16.18(8A1) U42.R5(GPMC_A3/QSPI1_CS2/VIN3A_D19/VOU)
H_GPMC_A4: RU16.21(9A1) U42.M6(GPMC_A4/QSPI1_CS3/VIN3A_D20/VOU)
H_GPMC_A5: RU16.23(10A1) U42.K4(GPMC_A5/VIN3A_D21/VOUT3_D21/VIN)
H_GPMC_A6: RU16.25(11A1) U42.P5(GPMC_A6/VIN3A_D22/VOUT3_D22/VIN)
H_GPMC_A7: RU16.27(12A1) U42.N6(GPMC_A7/VIN3A_D23/VOUT3_D23/VIN)
H_GPMC_A8: RU7.2(1A1) U42.N4(GPMC_A8/VIN3A_HSYNC0/VOUT3_HSYN)
H_GPMC_A9: RU7.4(2A1) U42.R3(GPMC_A9/VIN3A_VSYNC0/VOUT3_VSYN)
H_GPMC_A10: RU7.6(3A1) U42.J5(GPMC_A10/VIN3A_DE0/VOUT3_DE/USB)
H_GPMC_A11: RU7.9(4A1) U42.K5(GPMC_A11/VIN3A_FLD0/VOUT3_FLD/V)
H_GPMC_A12: RU7.11(5A1) U42.P4(GPMC_A12/VIN4A_CLK0/GPMC_A0/VIN)
H_GPMC_A13: R172.2 R173.2 U42.R2(GPMC_A13/QSPI1_RTCLK/VIN4A_HSYN)
H_GPMC_A14: R186.2 R187.2 U42.R6(GPMC_A14/QSPI1_D3/VIN4A_VSYNC0/)
H_GPMC_A15: R180.2 R181.2 U42.T2(GPMC_A15/QSPI1_D2/VIN4A_D8/TIME)
H_GPMC_A16: R169.2 R170.2 U42.U1(GPMC_A16/QSPI1_D0/VIN4A_D9/GPIO)
H_GPMC_A17: R174.2 R175.2 U42.P3(GPMC_A17/QSPI1_D1/VIN4A_D10/GPI)
H_GPMC_A18: R184.2 R185.2 U42.R1(GPMC_A18/QSPI1_SCLK/VIN4A_D11/G)
H_GPMC_A19: RU5.2(1A1) U42.H6(GPMC_A19/MMC2_DAT4/GPMC_A13/VIN)
H_GPMC_A20: RU5.4(2A1) U42.G6(GPMC_A20/MMC2_DAT5/GPMC_A14/VIN)
H_GPMC_A21: RU5.6(3A1) U42.J4(GPMC_A21/MMC2_DAT6/GPMC_A15/VIN)
H_GPMC_A22: RU5.9(4A1) U42.F5(GPMC_A22/MMC2_DAT7/GPMC_A16/VIN)
H_GPMC_A23: RU5.11(5A1) U42.G5(GPMC_A23/MMC2_CLK/GPMC_A17/VIN4)
H_GPMC_A24: RU5.13(6A1) U42.J3(GPMC_A24/MMC2_DAT0/GPMC_A18/VIN)
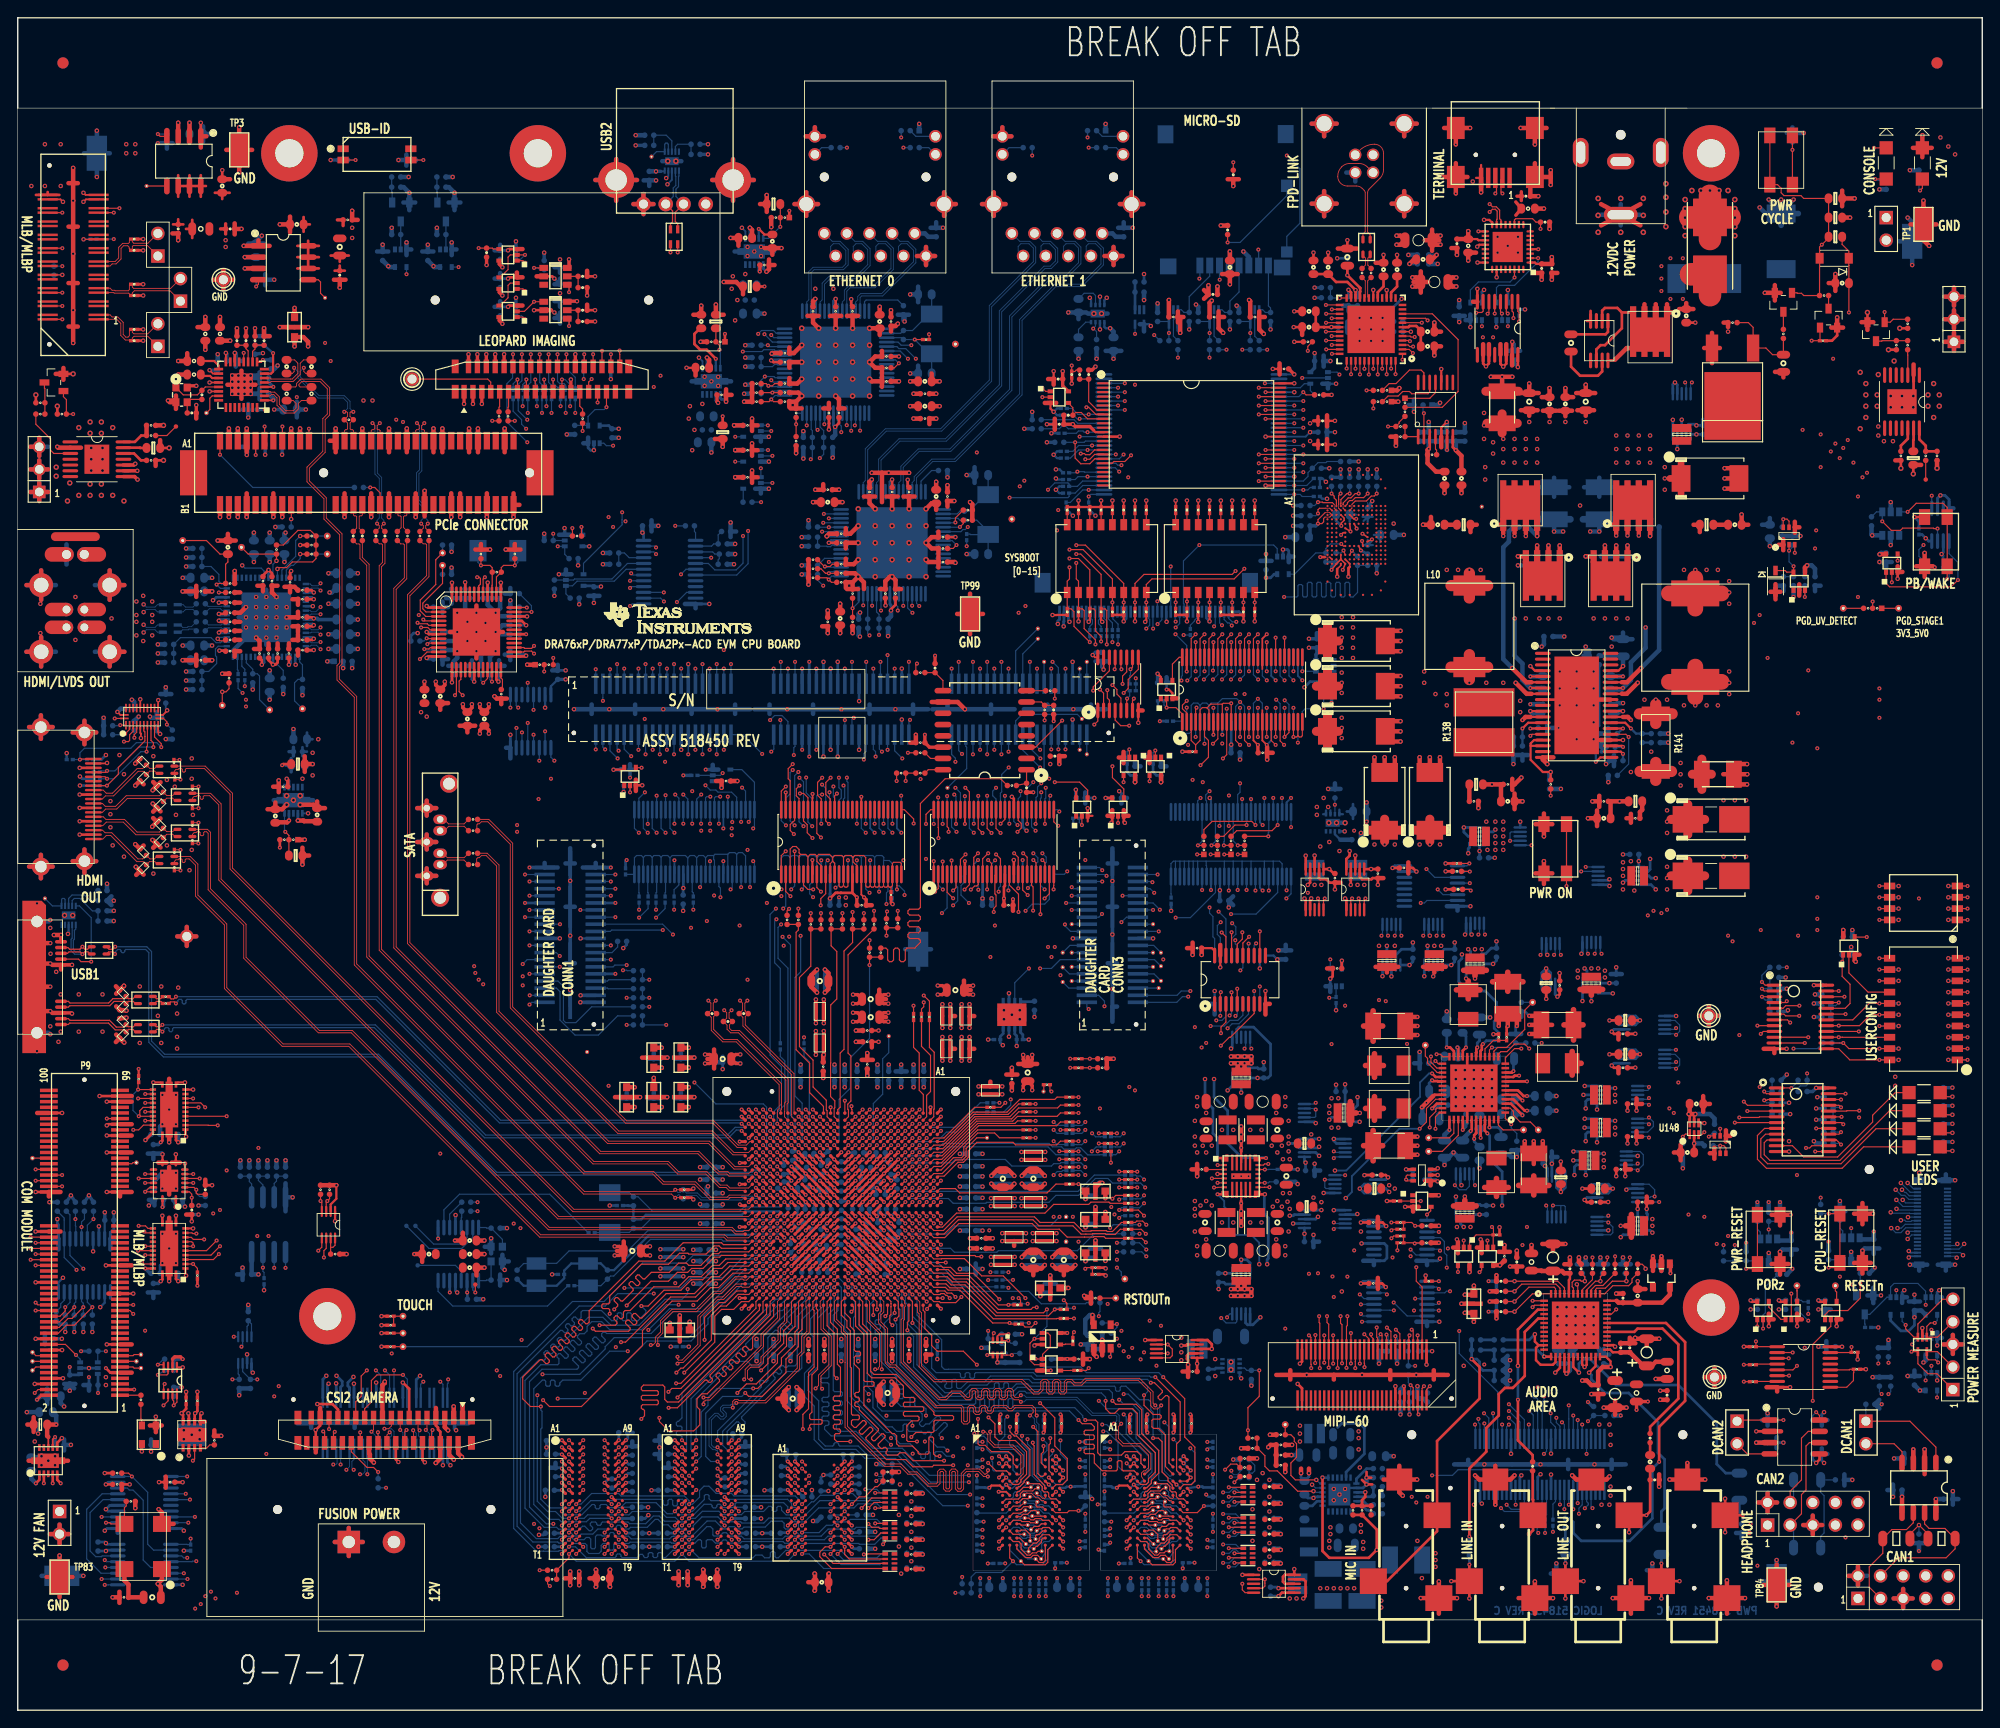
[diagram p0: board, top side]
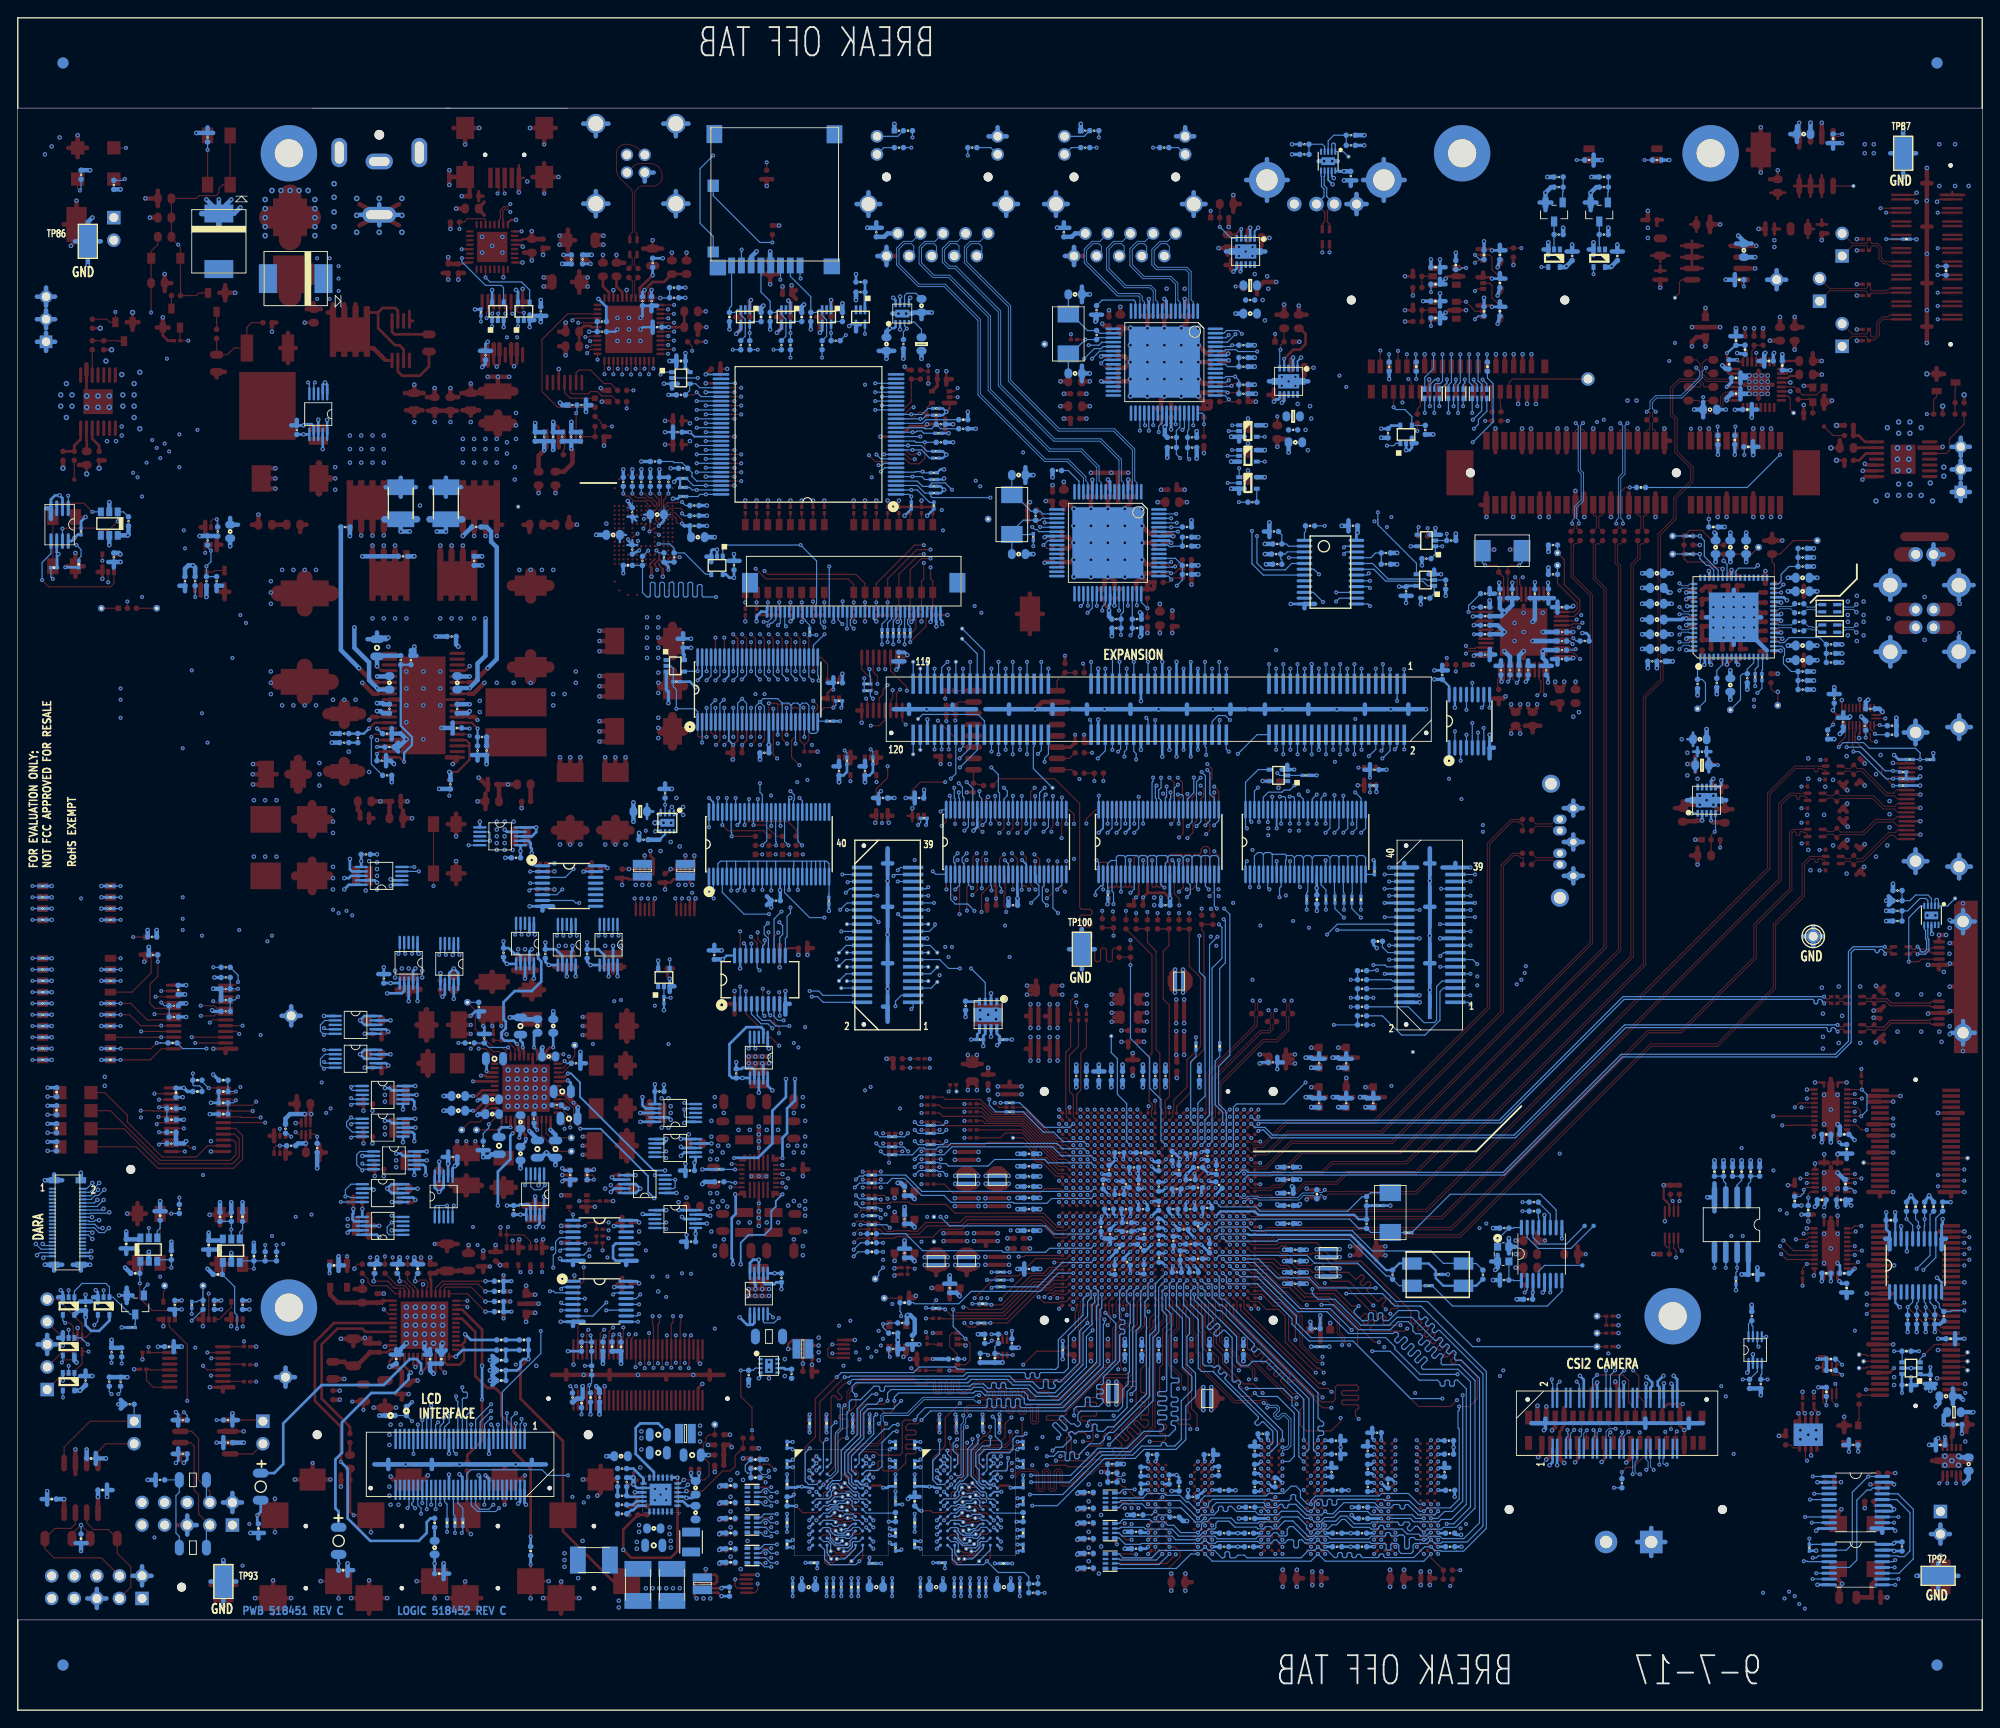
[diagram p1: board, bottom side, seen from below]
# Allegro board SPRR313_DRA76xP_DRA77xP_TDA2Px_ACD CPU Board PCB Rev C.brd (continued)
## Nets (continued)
H_GPMC_A25: RU5.15(7A1) U42.H4(GPMC_A25/MMC2_DAT1/GPMC_A19/VIN)
H_GPMC_A26: RU5.18(8A1) U42.H3(GPMC_A26/MMC2_DAT2/GPMC_A20/VIN)
H_GPMC_A27: RU5.21(9A1) U42.H5(GPMC_A27/MMC2_DAT3/GPMC_A21/VIN)
H_GPMC_AD0: RU16.9(4A1) U42.N5(GPMC_AD0/VIN3A_D0/VOUT3_D0/GPIO)
H_GPMC_AD1: RU16.6(3A1) U42.M2(GPMC_AD1/VIN3A_D1/VOUT3_D1/GPIO)
H_GPMC_AD2: RU16.4(2A1) U42.L5(GPMC_AD2/VIN3A_D2/VOUT3_D2/GPIO)
H_GPMC_AD3: RU16.2(1A1) U42.M1(GPMC_AD3/VIN3A_D3/VOUT3_D3/GPIO)
H_GPMC_AD4: RU13.27(12A1) U42.K6(GPMC_AD4/VIN3A_D4/VOUT3_D4/GPIO)
H_GPMC_AD5: RU13.25(11A1) U42.L4(GPMC_AD5/VIN3A_D5/VOUT3_D5/GPIO)
H_GPMC_AD6: RU13.23(10A1) U42.L3(GPMC_AD6/VIN3A_D6/VOUT3_D6/GPIO)
H_GPMC_AD7: RU13.21(9A1) U42.L2(GPMC_AD7/VIN3A_D7/VOUT3_D7/GPIO)
H_GPMC_AD8: RU13.18(8A1) U42.L1(GPMC_AD8/VIN3A_D8/VOUT3_D8/GPIO)
H_GPMC_AD9: RU13.15(7A1) U42.K1(GPMC_AD9/VIN3A_D9/VOUT3_D9/GPIO)
H_GPMC_AD10: RU13.13(6A1) U42.J1(GPMC_AD10/VIN3A_D10/VOUT3_D10/G)
H_GPMC_AD11: RU13.11(5A1) U42.J2(GPMC_AD11/VIN3A_D11/VOUT3_D11/G)
H_GPMC_AD12: RU13.9(4A1) U42.H1(GPMC_AD12/VIN3A_D12/VOUT3_D12/G)
H_GPMC_AD13: RU13.6(3A1) U42.K2(GPMC_AD13/VIN3A_D13/VOUT3_D13/G)
H_GPMC_AD14: RU13.4(2A1) U42.H2(GPMC_AD14/VIN3A_D14/VOUT3_D14/G)
H_GPMC_AD15: RU13.2(1A1) U42.K3(GPMC_AD15/VIN3A_D15/VOUT3_D15/G)
H_GPMC_ADVN_ALE: U12.17(ALE) U42.N1(GPMC_ADVN_ALE/GPMC_CS6/CLKOUT2/)
H_GPMC_BEN0: U12.16(CLE) U42.N3(GPMC_BEN0/GPMC_CS4/VIN1B_HSYNC1)
H_GPMC_CS0: RU3.2(I) RU12.2(I) U42.T1(GPMC_CS0/GPIO2_19)
H_GPMC_CS1: RU5.23(10A1) U42.G4(GPMC_CS1/MMC2_CMD/GPMC_A22/VIN4)
H_GPMC_CS2: R171.2 U42.P2(GPMC_CS2/QSPI1_CS0/GPIO2_20(GPM)
H_GPMC_CS3: RU7.27(12A1) U42.P1(GPMC_CS3/QSPI1_CS1/VIN3A_CLK0/V)
H_GPMC_OEN_REN: R42.1 U12.8(\\R\E) U42.M5(GPMC_OEN_REN/GPIO2_24) U104.34(O\E\)
H_GPMC_WAIT0: R34.1 R188.2 U42.N2(GPMC_WAIT0/GPIO2_28(GPMC_A25/GP)
H_GPMC_WEN: R371.1 U12.18(\\W\E) U42.M3(GPMC_WEN/GPIO2_25) U104.13(W\E\)
H_HDMI_CLKX: FL3.4 U42.AG14(HDMI1_CLOCKX)
H_HDMI_CLKY: FL3.1 U42.AH15(HDMI1_CLOCKY)
H_HDMI_DX0: FL4.4 U42.AG15(HDMI1_DATA0X)
H_HDMI_DX1: FL5.4 U42.AG17(HDMI1_DATA1X)
H_HDMI_DX2: FL6.4 U42.AG18(HDMI1_DATA2X)
H_HDMI_DY0: FL4.1 U42.AH16(HDMI1_DATA0Y)
H_HDMI_DY1: FL5.1 U42.AH18(HDMI1_DATA1Y)
H_HDMI_DY2: FL6.1 U42.AH19(HDMI1_DATA2Y)
H_I2C1_SCL: EXP_P2.30 P5.33 R618.2 U21.22(SCL) U30.22(SCL) U38.35(I2C1_SCL_SCK) U40.5(SCL) U42.C19(I2C1_SCL) U50.1(SCL) U53.1(SCL) U55.6(SCL2) U110.22(SCL) U139.6(SCL)
H_I2C1_SDA: EXP_P2.28 P5.35 R626.2 U21.23(SDA) U30.23(SDA) U38.36(I2C1_SDA_SDI) U40.6(SDA) U42.C20(I2C1_SDA) U50.2(SDA) U53.6(SDA) U55.5(SDA2) U110.23(SDA) U139.5(SDA)
H_I2C2_SCL: RU19.4(1A) U42.F15(I2C2_SCL/HDMI1_DDC_SDA)
H_I2C2_SDA: RU19.7(2A) U42.C24(I2C2_SDA/HDMI1_DDC_SCL)
H_I2C3_SCL_DCAN2_MCAN_RX: RU22.7(2A) U42.F17(GPIO6_15/MCASP1_AXR9/DCAN2(MCAN)
H_I2C3_SDA_DCAN2_MCAN_TX: RU22.4(1A) U42.E21(GPIO6_14/MCASP1_AXR8/DCAN2(MCAN)
H_I2C5_SCL: R230.1 U42.F11(MCASP1_AXR1/UART6_TXD/I2C5_SCL/)
H_I2C5_SDA: R226.1 U42.F10(MCASP1_AXR0/UART6_RXD/I2C5_SDA/)
H_LCD_B0: J19.51 R567.1
H_LCD_B1: J19.49 R198.1
H_LCD_B2: J13.13(TR_CLK0) J19.47 R206.1
H_LCD_B3: J13.25(TRD0.4) J19.45 R201.1
H_LCD_B4: J13.27(TRD0.5) J19.43 R568.1
H_LCD_B5: J13.29(TRD0.6) J19.41 R562.1
H_LCD_B6: J13.31(TRD0.7) J19.39 R565.1
H_LCD_B7: J13.33(TRD0.8) J19.37 R553.1
H_LCD_DE: J19.28 R210.1
H_LCD_G0: J19.33 R555.1
H_LCD_G1: J19.31 R564.1
H_LCD_G2: J13.17(TRD0.0) J19.29 R561.1
H_LCD_G3: J13.35(TRD0.9) J19.27 R557.1
H_LCD_G4: J13.37(TRD3.0) J19.25 R200.1
H_LCD_G5: J13.39(TRD3.1) J19.23 R559.1
H_LCD_G6: J13.41(TRD3.2) J19.21 R560.1
H_LCD_G7: J13.43(TRD3.3) J19.19 R563.1
H_LCD_HS: J19.26 R577.1
H_LCD_PCLK: J19.20 R574.1
H_LCD_R0: J19.15 R203.1
H_LCD_R1: J19.13 R195.1
H_LCD_R2: J13.23(TRD0.3) J19.11 R199.1
H_LCD_R3: J13.45(TRD3.4) J19.9 R202.1
H_LCD_R4: J13.47(TRD3.5) J19.7 R566.1
H_LCD_R5: J13.49(TRD3.6) J19.5 R197.1
H_LCD_R6: J13.51(TRD3.7) J19.3 R212.1
H_LCD_R7: J13.53(TRD3.8) J19.1 R207.1
H_LCD_VS: J19.24 R570.1
H_LJCB_CLKN: C53.1 R211.2 R576.1 U42.AF14(LJCB_CLKN)
H_LJCB_CLKP: C52.1 R211.1 R573.1 U42.AE13(LJCB_CLKP)
H_MCA2_ACLKX: R231.1 RU18.11(5A1)
H_MCA2_AFSX: R224.2 RU9.8(A7)
H_MCA2_AXR0: RU20.2(A1) U42.B14(MCASP2_AXR0/VOUT2_D10/VIN4A_D10)
H_MCA2_AXR1: RU20.3(A2) U42.A14(MCASP2_AXR1/VOUT2_D11/VIN4A_D11)
H_MCA2_AXR2: RU20.4(A3) U42.C14(MCASP2_AXR2/MCASP3_AXR2/VIN6A_D)
H_MCA2_AXR3: RU20.5(A4) U42.A15(MCASP2_AXR3/MCASP3_AXR3/VIN6A_D)
H_MCA2_AXR4: RU20.6(A5) U42.D15(MCASP2_AXR4/MCASP8_AXR0/VOUT2_D)
H_MCA2_AXR5: RU20.7(A6) U42.B15(MCASP2_AXR5/MCASP8_AXR1/VOUT2_D)
H_MCA2_AXR6: RU20.8(A7) U42.B16(MCASP2_AXR6/MCASP8_ACLKX/MCASP8)
H_MCA2_AXR7: RU20.9(A8) U42.A16(MCASP2_AXR7/MCASP8_FSX/MCASP8_F)
H_MCA3_ACLKX: R221.1 RU18.2(1A1)
H_MCA3_AFSX: R214.2 RU18.4(2A1)
H_MCA3_AXR0: R228.2 RU18.6(3A1)
H_MCA3_AXR1: R586.2 RU18.9(4A1)
H_MCA6_AXR0: RU9.4(A3) U42.B11(MCASP1_AXR8/MCASP6_AXR0/SPI3_SC)
H_MCA6_AXR1: RU9.5(A4) U42.A11(MCASP1_AXR9/MCASP6_AXR1/SPI3_D1)
H_MCA6_CLKX: R209.1 RU9.3(A2)
H_MCA6_FSX: R213.1 RU9.2(A1)
H_MCA7_AXR0: RU18.21(9A1) U42.D14(MCASP1_AXR12/MCASP7_AXR0/SPI3_C)
H_MCA7_AXR1: RU18.18(8A1) U42.B12(MCASP1_AXR13/MCASP7_AXR1/TIMER1)
H_MCA7_CLKX: R583.1 RU18.15(7A1)
H_MCA7_FSX: R218.1 RU18.13(6A1)
H_MDIO_D: RU14.7(2A) U42.U3(MDIO_D/UART3_CTSN/MII0_TXER/VIN)
H_MDIO_MCLK: RU14.4(1A) U42.V1(MDIO_MCLK/UART3_RTSN/MII0_COL/V)
H_MLBP_CLK: P5.2 R535.2
H_MLBP_CLKN: J4.1 P5.17 R11.1 R167.2 U42.AB2(MLBP_CLK_N)
H_MLBP_CLKP: J4.2 P5.19 R10.1 R167.1 U42.AB1(MLBP_CLK_P)
H_MLBP_DAT: P5.10 R190.2
H_MLBP_DN: J5.1 P5.9 R17.1 R166.2 U42.AA2(MLBP_DAT_N)
H_MLBP_DP: J5.2 P5.11 R14.1 R166.1 U42.AA1(MLBP_DAT_P)
H_MLBP_SIG: P5.6 R540.2
H_MLBP_SIGN: J6.1 P5.1 R25.1 R165.2 U42.AC2(MLBP_SIG_N)
H_MLBP_SIGP: J6.2 P5.3 R22.1 R165.1 U42.AC1(MLBP_SIG_P)
H_MMC1_CLK: R345.1 R525.2
H_MMC1_CMD: R346.1 U42.W5(MMC1_CMD/GPIO6_22)
H_MMC1_D0: R344.1 U42.V5(MMC1_DAT0/GPIO6_23)
H_MMC1_D1: R343.1 U42.Y4(MMC1_DAT1/GPIO6_24)
H_MMC1_D2: R339.1 U42.Y5(MMC1_DAT2/GPIO6_25)
H_MMC1_D3: R347.1 U42.Y3(MMC1_DAT3/GPIO6_26)
H_MMC1_SDCD: P14.9(INSERT) R9.2 U42.W4(MMC1_SDCD/UART6_RXD/I2C4_SDA/GP) U100.5(IO2)
H_MMC3_CLK: EXP_P3.25 R527.2
H_MMC3_CMD: EXP_P3.26 U42.AC7(MMC3_CMD/SPI3_SCLK/USB3_ULPI_D4)
H_MMC3_D0: EXP_P3.28 U42.Y6(MMC3_DAT0/SPI3_D1/UART5_RXD/USB)
H_MMC3_D1: EXP_P3.30 U42.W6(MMC3_DAT1/SPI3_D0/UART5_TXD/USB)
H_MMC3_D2: EXP_P3.27 U42.AC6(MMC3_DAT2/SPI3_CS0/UART5_CTSN/U)
H_MMC3_D3: EXP_P3.29 U42.AC4(MMC3_DAT3/SPI3_CS1/UART5_RTSN/U)
H_MMC3_D4: EXP_P3.32 U42.AA6(MMC3_DAT4/SPI4_SCLK/UART10_RXD/)
H_MMC3_D5: EXP_P3.34 U42.AB5(MMC3_DAT5/SPI4_D1/UART10_TXD/US)
H_MMC4_CLK: R624.1 R634.2 U132.4(B)
H_MMC4_CMD: R587.2 U42.E23(UART1_RTSN/UART9_TXD/MMC4_CMD/G) U128.16(B4)
H_MMC4_DAT0: R588.2 U42.D22(UART2_RXD/UART3_CTSN/UART3_RCTX) U128.15(B5)
H_MMC4_DAT1: R589.2 U42.E22(UART2_TXD/UART3_RTSN/UART3_SD/M) U128.14(B6)
H_MMC4_DAT2: R158.2 R590.2 U42.F20(UART2_CTSN/UART3_IRRX/MMC4_DAT2) U128.13(B7)
H_MMC4_DAT3: R157.2 R591.2 U42.C22(UART2_RTSN/UART3_TXD/UART3_IRTX) U128.12(B8)
H_MMC_PWR_ON: R341.2 TP57.1 U42.B10(VOUT1_FLD/VIN4A_CLK0/VIN3A_CLK0) U96.3(ON)
H_NMIN: R266.1 R269.2 U42.D21(NMIN)
H_PCIE_RXN0: R90.1 U42.AG11(PCIE_RXN0)
H_PCIE_RXN1: R94.1 U42.AG8(PCIE_RXN1)
H_PCIE_RXP0: R89.1 U42.AH12(PCIE_RXP0)
H_PCIE_RXP1: R93.1 U42.AH9(PCIE_RXP1)
H_PCIE_TXN0: C84.1 U42.AG12(PCIE_TXN0)
H_PCIE_TXN1: C86.1 U42.AG9(PCIE_TXN1)
H_PCIE_TXP0: C82.1 U42.AH13(PCIE_TXP0)
H_PCIE_TXP1: C85.1 U42.AH10(PCIE_TXP1)
H_PORZ: R615.1 R616.1 TP71.1(TP) U42.C25(PORZ) U47.4(Y)
H_POWERHOLD_CLK: R443.1 R571.1 U113.1(CLK)
H_RESETN: TP70.1(TP) U42.D24(RESETN) U48.4(Y)
H_RGMII0_RXC: RU17.2(1A1) U42.U4(RGMII0_RXC/RMII1_TXEN/MII0_TXCL)
H_RGMII0_RXCTL: RU17.4(2A1) U42.V4(RGMII0_RXCTL/RMII1_TXD1/MII0_TX)
H_RGMII0_RXD0: RU17.6(3A1) U42.W1(RGMII0_RXD0/RMII0_TXD0/MII0_TXD)
H_RGMII0_RXD1: RU17.9(4A1) U42.Y2(RGMII0_RXD1/RMII0_TXD1/MII0_TXD)
H_RGMII0_RXD2: RU17.11(5A1) U42.V3(RGMII0_RXD2/RMII0_TXEN/MII0_TXE)
H_RGMII0_RXD3: RU17.13(6A1) U42.W2(RGMII0_RXD3/RMII1_TXD0/MII0_TXD)
H_RGMII0_TXC: R526.1 RU17.27(12A1)
H_RGMII0_TXCTL: R524.1 RU17.25(11A1)
H_RGMII0_TXD0: R529.1 RU17.15(7A1)
H_RGMII0_TXD1: R530.1 RU17.18(8A1)
H_RGMII0_TXD2: R531.1 RU17.21(9A1)
H_RGMII0_TXD3: R532.1 RU17.23(10A1)
H_RSTOUTN: J17.29 R267.2 R316.1 TP82.1(TP) U10.12(RSTN) U20.3(R\E\S\E\T\/RFU) U38.13(GPIO_1) U42.D23(RSTOUTN) U50.33(R\E\S\E\T\) U104.14(R\E\S\E\T\) U105.1(OE) U109.1(OE) U124.13(B7)
H_RTCK: J13.7(RTCK) R599.1
H_SATA_RXN0: C132.2 U42.AH6(SATA1_RXN0)
H_SATA_RXP0: C130.2 U42.AG5(SATA1_RXP0)
H_SATA_TXN0: C133.2 U42.AG6(SATA1_TXN0)
H_SATA_TXP0: C134.2 U42.AH7(SATA1_TXP0)
H_SPI1_SCLK: U42.A24(SPI1_SCLK/GPIO7_7) U51.2(I) U54.2(I)
H_SPI2_CS0N: RU23.12(4A) U42.B23(SPI2_CS0/UART3_RTSN/UART5_TXD/G)
H_SPI2_MISO: RU23.7(2A) U42.B21(SPI2_D1/UART3_TXD/GPIO7_15)
H_SPI2_MOSI: RU23.9(3A) U42.E16(SPI2_D0/UART3_CTSN/UART5_RXD/GP)
H_SPI2_SCLK: R255.1 RU23.4(1A)
H_SPI[1]_CS[0]N: EXP_P3.36 R607.1
H_SPI[1]_CS[1]N: EXP_P3.39 U42.A21(SPI1_CS1/SATA1_LED/SPI2_CS1/GPI)
H_SPI[1]_MISO: EXP_P3.37 R578.1
H_SPI[1]_MOSI: EXP_P3.38 R603.1
H_TCK: J13.3(TCK) U42.E20(TCLK)
H_TDI: J13.5(TDI) U42.B22(TDI/GPIO8_27)
H_TDO: J13.4(TDO) R598.1
H_TMS: J13.2(TMS) R658.2 U42.F16(TMS)
H_TRSTN: R652.2 R664.2 U42.D20(TRSTN)
H_UART1_RXD: RU2.5(2B1) U42.F22(UART1_RXD/MMC4_SDCD/GPIO7_22)
H_UART1_TXD: RU2.2(1B1) U42.C21(UART1_TXD/MMC4_SDWP/GPIO7_23)
H_UART3_RXD: RU14.12(4A) U42.V2(UART3_RXD/RMII1_CRS/MII0_RXDV/V)
H_UART3_RXD_BOOT: R158.1 RU2.6(2B2)
H_UART3_TXD: RU14.9(3A) U42.Y1(UART3_TXD/RMII1_RXER/MII0_RXCLK)
H_UART3_TXD_BOOT: R157.1 RU2.3(1B2)
H_USB1_DN: FL7.4 U42.AE10(USB1_DM)
H_USB1_DP: FL7.1 U42.AF11(USB1_DP)
H_USB1_DRV_VBUS: R298.2 U1.4(EN) U42.AD12(USB1_DRVVBUS/TIMER16/GPIO6_12)
H_USB2_DN: U42.AF13(USB2_DM) U141.27(USB_DM_UP)
H_USB2_DP: U42.AE12(USB2_DP) U141.26(USB_DP_UP)
H_USB2_DRV_VBUS: RJ16.3 U42.AC11(USB2_DRVVBUS/TIMER15/GPIO6_13)
H_USB3_RXN: FL9.4 U42.AG3(USB_RXN0)
H_USB3_RXP: FL9.1 U42.AH4(USB_RXP0)
H_USB3_TXN: C142.1 U42.AG2(USB_TXN0)
H_USB3_TXP: C144.1 U42.AH3(USB_TXP0)
H_VIN1_D0: EXP_P2.40 U42.AE9(VIN1A_D0/VOUT3_D7/VOUT3_D23/UAR)
H_VIN1_D1: EXP_P2.41 U42.AF10(VIN1A_D1/VOUT3_D6/VOUT3_D22/UAR)
H_VIN1_D2: EXP_P2.42 U42.AE7(VIN1A_D2/VOUT3_D5/VOUT3_D21/UAR)
H_VIN1_D3: EXP_P2.43 U42.AE8(VIN1A_D3/VOUT3_D4/VOUT3_D20/UAR)
H_VIN1_D4: EXP_P2.44 U42.AE6(VIN1A_D4/VOUT3_D3/VOUT3_D19/EHR)
H_VIN1_D5: EXP_P2.45 U42.AF7(VIN1A_D5/VOUT3_D2/VOUT3_D18/EHR)
H_VIN1_D6: EXP_P2.46 U42.AF8(VIN1A_D6/VOUT3_D1/VOUT3_D17/EQE)
H_VIN1_D7: EXP_P2.47 U42.AF6(VIN1A_D7/VOUT3_D0/VOUT3_D16/EQE)
H_VIN1_D8: EXP_P2.68 U42.AF4(VIN1A_D8/VIN1B_D7/VOUT3_D15/KBD)
H_VIN1_D9: EXP_P2.67 U42.AF2(VIN1A_D9/VIN1B_D6/VOUT3_D14/KBD)
H_VIN1_D10: EXP_P2.70 U42.AF3(VIN1A_D10/VIN1B_D5/VOUT3_D13/KB)
H_VIN1_D11: EXP_P2.69 U42.AF5(VIN1A_D11/VIN1B_D4/VOUT3_D12/GP)
H_VIN1_D12: EXP_P2.72 U42.AE5(VIN1A_D12/VIN1B_D3/USB3_ULPI_D7)
H_VIN1_D13: EXP_P2.71 U42.AF1(VIN1A_D13/VIN1B_D2/USB3_ULPI_D6)
H_VIN1_D14: EXP_P2.74 U42.AD6(VIN1A_D14/VIN1B_D1/USB3_ULPI_D5)
H_VIN1_D15: EXP_P2.73 U42.AE3(VIN1A_D15/VIN1B_D0/USB3_ULPI_D4)
H_VIN1_D16: EXP_P2.3 U42.AE4(VIN1A_D16/VIN1B_D7/USB3_ULPI_D3)
H_VIN1_D17: EXP_P2.4 U42.AE1(VIN1A_D17/VIN1B_D6/USB3_ULPI_D2)
H_VIN1_D18: EXP_P2.5 U42.AD5(VIN1A_D18/VIN1B_D5/USB3_ULPI_D1)
H_VIN1_D19: EXP_P2.6 U42.AD3(VIN1A_D19/VIN1B_D4/USB3_ULPI_D0)
H_VIN1_D20: EXP_P2.7 U42.AD4(VIN1A_D20/VIN1B_D3/USB3_ULPI_NX)
H_VIN1_D21: EXP_P2.8 U42.AE2(VIN1A_D21/VIN1B_D2/USB3_ULPI_DI)
H_VIN1_D22: EXP_P2.9 U42.AD1(VIN1A_D22/VIN1B_D1/USB3_ULPI_ST)
H_VIN1_D23: EXP_P2.10 U42.AD2(VIN1A_D23/VIN1B_D0/USB3_ULPI_CL)
H_VIN1_DE: EXP_P2.25 U42.AC9(VIN1A_DE0/VIN1B_HSYNC1/VOUT3_D1)
H_VIN1_HSYNC: EXP_P2.1 U42.AC10(VIN1A_HSYNC0/VIN1B_FLD1/VOUT3_H)
H_VIN1_VSYNC: EXP_P2.2 U42.AD7(VIN1A_VSYNC0/VIN1B_DE1/VOUT3_VS)
H_VIN1A_CLK: EXP_P2.48 U42.AD8(VIN1A_CLK0/VOUT3_D16/VOUT3_FLD/)
H_VIN1B_CLK: EXP_P2.75 U42.AC8(VIN1B_CLK1/VIN3A_CLK0/GPIO2_31)
H_VIN2_CLK: RU4.4(1A) U42.F1(VIN2A_CLK0/VOUT2_FLD/EMU5/KBD_R)
H_VIN2_D0: RU8.2(1A) U42.F2(VIN2A_D0/VOUT2_D23/EMU10/UART9_)
H_VIN2_D1: RU8.4(2A) U42.E3(VIN2A_D1/VOUT2_D22/EMU11/UART9_)
H_VIN2_D2: RU8.6(3A) U42.E1(VIN2A_D2/VOUT2_D21/EMU12/UART10)
H_VIN2_D3: RU8.9(4A) U42.E2(VIN2A_D3/VOUT2_D20/EMU13/UART10)
H_VIN2_D4: RU8.11(5A) U42.D2(VIN2A_D4/VOUT2_D19/EMU14/UART10)
H_VIN2_D5: RU8.13(6A) U42.F3(VIN2A_D5/VOUT2_D18/EMU15/UART10)
H_VIN2_D6: RU8.15(7A) U42.D1(VIN2A_D6/VOUT2_D17/EMU16/MII1_R)
H_VIN2_D7: RU8.18(8A) U42.E4(VIN2A_D7/VOUT2_D16/EMU17/MII1_R)
H_VIN2_D8: RU8.21(9A) U42.G3(VIN2A_D8/VOUT2_D15/EMU18/MII1_R)
H_VIN2_D9: RU8.23(10A) U42.C5(VIN2A_D9/VOUT2_D14/EMU19/MII1_R)
H_VIN2_D10: RU8.25(11A) U42.D3(VIN2A_D10/MDIO_MCLK/VOUT2_D13/K)
H_VIN2_D11: RU8.27(12A) U42.F4(VIN2A_D11/MDIO_D/VOUT2_D12/KBD_)
H_VIN2_D12: R556.1 RU15.2(1A)
H_VIN2_D13: R176.1 RU15.4(2A)
H_VIN2_D14: R178.1 RU15.6(3A)
H_VIN2_D15: R554.1 RU15.9(4A)
H_VIN2_D16: R177.1 RU15.11(5A)
H_VIN2_D17: R558.1 RU15.13(6A)
H_VIN2_D18: RU15.15(7A) U42.D4(VIN2A_D18/VIN2B_D5/RGMII1_RXC/V)
H_VIN2_D19: RU15.18(8A) U42.A3(VIN2A_D19/VIN2B_D4/RGMII1_RXCTL)
H_VIN2_D20: RU15.21(9A) U42.B3(VIN2A_D20/VIN2B_D3/RGMII1_RXD3/)
H_VIN2_D21: RU15.23(10A) U42.B4(VIN2A_D21/VIN2B_D2/RGMII1_RXD2/)
H_VIN2_D22: RU15.25(11A) U42.C4(VIN2A_D22/VIN2B_D1/RGMII1_RXD1/)
H_VIN2_D23: RU15.27(12A) U42.A4(VIN2A_D23/VIN2B_D0/RGMII1_RXD0/)
H_VIN2_DE: RU4.7(2A) U42.G2(VIN2A_DE0/VIN2A_FLD0/VIN2B_FLD1)
H_VIN2_HSYNC: RU4.9(3A) U42.G1(VIN2A_HSYNC0/VIN2B_HSYNC1/VOUT2)
H_VIN2_VSYNC: RU4.12(4A) U42.E5(VIN2A_VSYNC0/VIN2B_VSYNC1/VOUT2)
H_VIN2B_CLK1: EXP_P1.17 U42.AA5(MMC3_DAT7/SPI4_CS0/UART10_RTSN/)
H_VIN2B_HSYNC1: EXP_P3.31 U42.AC5(GPIO6_10/MDIO_MCLK/I2C3_SDA/USB)
H_VIN2B_VSYNC1: EXP_P3.33 U42.AB4(GPIO6_11/MDIO_D/I2C3_SCL/USB3_U)
H_VIN[5]A_D[8]: EXP_P1.5 R543.2
H_VIN[5]A_D[9]: EXP_P1.6 R536.2
H_VIN[5]A_D[10]: EXP_P1.7 R542.2
H_VIN[5]A_D[11]: EXP_P1.8 R539.2
H_VIN[5]A_D[12]: EXP_P1.9 U42.D17(MCASP4_AXR1/SPI3_CS0/UART8_RTSN)
H_VIN[5]A_D[13]: EXP_P1.18 U42.D16(MCASP4_AXR0/SPI3_D0/UART8_CTSN/)
H_VIN[5]A_D[14]: EXP_P1.11 U42.A20(MCASP4_FSX/MCASP4_FSR/SPI3_D1/U)
H_VIN[5]A_D[15]: EXP_P1.12 U42.C17(MCASP4_ACLKX/MCASP4_ACLKR/SPI3_)
H_WKUP_0: R712.1 TP74.1(TP) U40.19(NINT) U42.AB19(WAKEUP0/DCAN1_RX/GPIO1_0)
H_WKUP_1: R242.1 TP69.1(TP) U38.26(INT) U42.AC20(WAKEUP1/DCAN2_RX/GPIO1_1)
H_X0_OSC1: C518.1 U42.AB18(XO_OSC1) Y7.1(X1)
H_XI_OSC0: C474.1 R234.1 U42.AB16(XI_OSC0) Y5.2
H_XI_OSC1: C517.1 R247.1 U42.AC19(XI_OSC1) Y7.3(X2)
H_XO_OSC0: C457.1 U42.AB14(XO_OSC0) Y5.1
H_XREF_CLK1: R596.2 RU6.2(I)
H_XREF_CLK2: R322.2 R613.2
HDMI_CEC_A: U19.24(CEC_A) U42.B19(SPI1_CS3/UART4_TXD/MMC3_SDWP/SP)
HDMI_CEC_B: P7.13(CE REMOTE) R494.1 U19.6(CEC_B)
HDMI_CT_HPD: R470.2 R582.1 U19.11(CT_HPD)
HDMI_DSCL: R467.1 RU19.6(2B2) U19.1(SCL_A)
HDMI_DSDA: R472.1 RU19.3(1B2) U19.2(SDA_A)
HDMI_HPD: U19.3(HPD_A) U42.B20(SPI1_CS2/UART4_RXD/MMC3_SDCD/SP)
HDMI_HPD_B: P7.19(HP DET) R483.2 R484.1 U19.9(HPD_B)
HDMI_LS_OE: R466.2 R580.1 U19.4(LS_OE)
HDMI_SCL_B: P7.15(DDC CLK) R491.1 U19.7(SCL_B)
HDMI_SDA_B: P7.16(DDC DATA) R487.1 U19.8(SDA_B)
HDMI_TX0+: FL4.2 P7.7(D0+) U26.1(IO)
HDMI_TX0-: FL4.3 P7.9(D0-) U25.1(IO)
HDMI_TX1+: FL5.2 P7.4(D1+) U29.1(IO)
HDMI_TX1-: FL5.3 P7.6(D1-) U28.1(IO)
HDMI_TX2+: FL6.2 P7.1(D2+) U32.1(IO)
HDMI_TX2-: FL6.3 P7.3(D2-) U31.1(IO)
HDMI_TXC+: FL3.2 P7.10(CK+) U24.1(IO)
HDMI_TXC-: FL3.3 P7.12(CK-) U22.1(IO)
I2C2_SCL_PM: R163.2 R268.2 RU19.2(1B1)
I2C2_SDA_PM: R168.2 R271.2 RU19.5(2B1)
I2C3_SCL: EXP_P1.1 RU24.4(O)
I2C3_SDA: EXP_P1.3 RU25.4(O)
I2C_EEPROM_WP: R702.2 SW6.11 U139.7(WP)
ISO_FTDI_UARTIN: RU2.4(1A) U142.2(I)
ISO_FTDI_UARTOUT: RU2.7(2A) U143.2(I)
LDO4_OUT: U38.7(LDO4_OUT)
LDOVANA: C423.1 U38.43(LDOVANA_OUT)
LDOVRTC: C414.1 R545.2 U38.44(LDOVRTC_OUT)
LP87565_REGEN_3V3: Q19.2(G2) R711.2 U40.15(EN2/GPIO2) U119.3(ON) U148.3(EN2)
LPD_SPI[1]_CS[0]N: J8.34 R354.1 RU21.3(1B2)
LPD_SPI[1]_MISO: J8.31 RU21.6(2B2)
LPD_SPI[1]_MOSI: J8.36 RU21.13(4B2)
LPD_SPI[1]_SCLK: J8.32 RU21.10(3B2)
MCA2_ACLKX: EXP_P2.29 RU18.44(5B2)
MCA2_AFSX: EXP_P2.31 RU9.12(B7)
MCA2_AXR0: EXP_P2.37 RU20.18(B1)
MCA2_AXR1: EXP_P2.33 RU20.17(B2)
MCA2_AXR2: EXP_P2.39 RU20.16(B3)
MCA2_AXR3: EXP_P2.35 RU20.15(B4)
MCA2_AXR4: EXP_P2.23 RU20.14(B5)
MCA2_AXR5: EXP_P2.24 RU20.13(B6)
MCA2_AXR6: EXP_P2.22 RU20.12(B7)
MCA2_AXR7: EXP_P2.38 RU20.11(B8)
MCA6_ACLKX: EXP_P2.104 RU9.17(B2)
MCA6_AFSX: EXP_P2.102 RU9.18(B1)
MCA6_AHCLKX: EXP_P2.106 RU6.4(O)
MCA6_AXR0: EXP_P2.103 RU9.16(B3)
MCA6_AXR1: EXP_P2.105 RU9.15(B4)
MCA7_AXR0: RU18.35(9B2) U39.9(A7)
MCA7_AXR1: RU18.37(8B2) U41.6(2A1)
MCA7_CLKX: RU18.40(7B2) U41.4(1A1)
MCA7_FSX: RU18.42(6B2) U41.5(1A2)
MCASP1_ENN: R139.2 SW6.15 U21.18(P15) U39.22(OEN) U43.22(OEN)
MDIO_MDCLK: R69.2 RU14.2(1B1) U101.20(MDC) U108.20(MDC)
MDIO_MDIO: R86.2 RU14.5(2B1) U101.21(MDIO) U108.21(MDIO)
MMC2_BOOT_OVR: R426.2 U110.18(P15) U112.2(I)
MMC2_BOOT_OVR_OEN: R428.2 U110.17(P14) U112.1(OE)
MMC2_BOOTN: R107.2 R460.2 RU5.1(S0) SW6.18 U17.2(I) U21.15(P12) U122.3(D1)
MMC2_CLK: R418.1 R420.2 RU5.44(5B2)
MMC2_CMD: R415.2 RU5.33(10B2) U15.M5(CMD)
MMC2_DAT0: R389.2 RU5.42(6B2) U15.A3(DAT0)
MMC2_DAT1: R387.2 RU5.40(7B2) U15.A4(DAT1)
MMC2_DAT2: R385.2 RU5.37(8B2) U15.A5(DAT2)
MMC2_DAT3: R398.2 RU5.35(9B2) U15.B2(DAT3)
MMC2_DAT4: R395.2 RU5.53(1B2) U15.B3(DAT4)
MMC2_DAT5: R388.2 RU5.51(2B2) U15.B4(DAT5)
MMC2_DAT6: R386.2 RU5.48(3B2) U15.B5(DAT6)
MMC2_DAT7: R384.2 RU5.46(4B2) U15.B6(DAT7)
NAND_BOOTN: R153.2 RU3.1(OE) SW6.20 U21.13(P10)
NOR_BOOTN: R147.2 R486.2 RU12.1(OE) SW6.19 U21.14(P11)
NOR_BOOTN_OVR: R425.2 U110.20(P17) U111.2(I)
NOR_BOOTN_OVR_OEN: R427.2 U110.19(P16) U111.1(OE)
NOR_CEN: R358.1 RU12.4(O) U104.32(C\E\)
NTRST: J13.9(NTRST) R651.2 R652.1
OLD_GPMC_NCS0: EXP_P1.16 R528.2
P0_CRS: R351.1 R353.1 U101.56(CRS/GPIO)
P0_LED_ACT: R302.2 U101.63(LED_0)
P0_LED_LINK10_100: RJ13.3 U101.61(LED_2)
P0_LED_LINK1000: R301.2 U101.62(LED_1)
P0_RBIAS: R327.2 U101.15(RBIAS)
P0_RX_D4: R49.1 R64.2 U101.48(RX_D4/GPIO)
P0_RX_D5: R43.1 R44.2 U101.49(RX_D5/GPIO)
P0_RX_D6: R40.1 R41.2 U101.50(RX_D6/GPIO)
P0_RX_D7: R37.1 R38.1 U101.51(RX_D7/GPIO)
P0_TRD[0]N: P3.10(T0-) U101.3(TD_M_A)
P0_TRD[0]P: P3.9(T0+) U101.2(TD_P_A)
P0_TRD[1]N: P3.8(T1-) U101.6(TD_M_B)
P0_TRD[1]P: P3.7(T1+) U101.5(TD_P_B)
P0_TRD[2]N: P3.6(T2-) U101.11(TD_M_C)
P0_TRD[2]P: P3.5(T2+) U101.10(TD_P_C)
P0_TRD[3]N: P3.4(T3-) U101.14(TD_M_D)
P0_TRD[3]P: P3.3(T3+) U101.13(TD_P_D)
P1_CRS: R407.1 R409.1 U108.56(CRS/GPIO)
P1_LED_ACT: R300.2 U108.63(LED_0)
P1_LED_LINK10_100: RJ12.3 U108.61(LED_2)
P1_LED_LINK1000: R299.2 U108.62(LED_1)
P1_RBIAS: R379.2 U108.15(RBIAS)
P1_RX_D4: R112.1 R129.2 U108.48(RX_D4/GPIO)
P1_RX_D5: R108.1 R109.2 U108.49(RX_D5/GPIO)
P1_RX_D6: R105.1 R106.2 U108.50(RX_D6/GPIO)
P1_RX_D7: R103.1 R104.1 U108.51(RX_D7/GPIO)
P1_TRD[0]N: P4.10(T0-) U108.3(TD_M_A)
P1_TRD[0]P: P4.9(T0+) U108.2(TD_P_A)
P1_TRD[1]N: P4.8(T1-) U108.6(TD_M_B)
P1_TRD[1]P: P4.7(T1+) U108.5(TD_P_B)
P1_TRD[2]N: P4.6(T2-) U108.11(TD_M_C)
P1_TRD[2]P: P4.5(T2+) U108.10(TD_P_C)
P1_TRD[3]N: P4.4(T3-) U108.14(TD_M_D)
P1_TRD[3]P: P4.3(T3+) U108.13(TD_P_D)
PB_ON: D1.2(ANODE) J7.2 Q4.G R21.2 R31.2 R39.1 R46.1 SW2.3(B) SW2.4(BB)
PCF_VPP_ENN: R647.2 RU11.1(OE) U21.20(P17)
PCI_CONN_REFN: C44.1 U10.5(OUT0N)
PCI_CONN_REFP: C43.1 U10.6(OUT0P)
PCI_PORZ: R12.1 U4.4(O) U47.2(A)
PCI_RESET_SEL: R137.2 RU1.1(OE) SW6.13 U4.1(OE)
PCI_SW_RESETN: R328.2 U7.1(B) U30.17(P14)
PCM_CLK: P9.52 U41.13(1B1)
PCM_DIN: P9.56 U41.11(2B1)
PCM_DOUT: P9.58 U39.15(B7)
PCM_FSYNC: P9.54 U41.12(1B2)
PGD_3V3_5V0: Q13.G R602.1 RJ17.2 U16.2(A)
PGD_STAGE1_3V3_5V0: R728.1 RJ17.1 TP96.1(TP) U18.15(PGA) U18.24(PGB)
PGD_UV_DETECT: Q18.3(D2) R756.1 RJ17.3 TP98.1(TP) U147.3(RESETN)
PHA: C334.1 L10.1 Q7.1(S1) Q7.2(S2) Q7.3(S3) Q9.5(D1) R87.2 U18.7(PHA)
PHB: C333.1 L11.1 Q8.1(S1) Q8.2(S2) Q8.3(S3) Q10.5(D1) R88.2 U18.32(PHB)
PM1_SCL: J17.36 R635.1 RU10.2(1B1) U65.1(A1) U65.5(SCL) U66.1(A1) U66.5(SCL) U67.1(A1) U67.5(SCL) U68.2(A0) U68.5(SCL) U69.5(SCL) U70.5(SCL) U71.5(SCL) U79.2(A0) U79.5(SCL) U80.5(SCL) U81.5(SCL) U82.5(SCL) U83.2(A0) U83.5(SCL) U84.5(SCL) U85.5(SCL) U86.5(SCL) U133.2(I)
PM1_SDA: J17.38 R636.1 RU10.5(2B1) U65.2(A0) U65.4(SDA) U66.4(SDA) U67.4(SDA) U68.1(A1) U68.4(SDA) U69.1(A1) U69.2(A0) U69.4(SDA) U70.1(A1) U70.4(SDA) U71.1(A1) U71.4(SDA) U79.4(SDA) U80.2(A0) U80.4(SDA) U81.4(SDA) U82.4(SDA) U83.4(SDA) U84.2(A0) U84.4(SDA) U85.4(SDA) U86.4(SDA) U131.2(I)
PM2_SCL: J17.37 R648.2 RU10.3(1B2) U72.5(SCL) U73.5(SCL) U74.5(SCL) U75.2(A0) U75.5(SCL) U76.5(SCL) U77.5(SCL) U78.5(SCL) U87.2(A0) U87.5(SCL) U88.5(SCL) U89.5(SCL) U90.5(SCL) U91.2(A0) U91.5(SCL) U130.2(I)
PM2_SDA: J17.39 R649.2 RU10.6(2B2) U72.1(A1) U72.2(A0) U72.4(SDA) U73.1(A1) U73.4(SDA) U74.1(A1) U74.4(SDA) U75.4(SDA) U76.2(A0) U76.4(SDA) U77.4(SDA) U78.4(SDA) U87.4(SDA) U88.2(A0) U88.4(SDA) U89.4(SDA) U90.4(SDA) U91.1(A1) U91.4(SDA) U129.2(I)
PM_BRD_PWR_OFF: J17.26 Q6.G R66.1
PM_OEN: R161.2 R264.2 RU10.15(O\E\) RU19.1(S) U110.4(P0)
PM_PORN: J17.27 R534.1
PM_RESETN: J17.28 R519.1
PM_SEL: R263.2 RU10.1(S) U110.7(P3)
PMIC2_PG_1V8: R496.2 U40.2(EN3/GPIO3) U40.16(PGOOD)
PMIC_REGEN_DDR: R285.1 R667.2 U38.12(GPIO_0) U134.3(ON) U138.5(ENLDO)
PMIC_REGEN_LP87565: R488.2 U38.1(GPIO_4) U40.7(EN1/GPIO1)
PMIC_RESET_OUT: R710.1 U38.25(RESET_OUT) U46.1(B)
POWERHOLD: R547.1 U16.4(Y)
PWREN#: DS6.1(CATHODE) R7.2 U3.11(CBUS3)
R_QSPI1_CS[0]: R135.2 R136.1 U20.7(C\S\)
R_QSPI1_D[0]: R144.2 U20.15(SI/IO0)
R_QSPI1_D[1]: R133.1 U20.8(SO/IO1)
R_QSPI1_D[2]: R130.2 R131.1 U20.9(W\P\/IO2)
R_QSPI1_D[3]: R151.2 R152.2 U20.1(H\O\L\D\/IO3)
R_QSPI1_SCLK: R146.1 U20.16(SCLK)
REFCLKN: C44.2 P6.A14(REFCLK-) R57.1
REFCLKP: C43.2 P6.A13(REFCLK+) R57.2
REGEN3_GPIO6: R755.1 TP58.1(TP) U38.27(GPIO_6) U148.1(EN1)
SEL_CSI2N: R597.2 RU21.1(S) U110.13(P10)
SEL_ENET_MUX_S0: R489.2 RU17.1(S0) U21.8(P4) U118.2(I)
SEL_ENET_MUX_S1: RU14.1(S) RU17.56(S1) U118.4(O)
SEL_EXP_I2C3_DCAN2: R737.2 RU24.1(OE) RU25.1(OE) U21.9(P5)
SEL_GPMC_AD_VID_S0: R452.2 RU7.1(S0) RU13.1(S0) RU16.1(S0) U21.4(P0) U116.2(I)
SEL_GPMC_AD_VID_S1: RU7.56(S1) RU13.56(S1) RU16.56(S1) U116.4(O)
SEL_I2C3_CAN2: R250.2 U21.7(P3) U44.2(I)
SEL_UART3_SPI2: R248.2 RU23.1(S) U21.19(P16)
SEL_VCC_CSI2_IO: R482.2 SW6.17 U140.3(D1)
SERDES_IN_REFN: C53.2 U10.2(OUT1N)
SERDES_IN_REFP: C52.2 U10.3(OUT1P)
SLEEP_CLK: P9.1 R273.2
SPI[1]_SCLK: EXP_P3.35 R265.1
SPI[2]_CS[0]N: EXP_P3.2 RU23.13(4B2)
SPI[2]_MISO: EXP_P3.3 RU23.6(2B2)
SPI[2]_MOSI: EXP_P3.4 RU23.10(3B2)
SPI[2]_SCLK: EXP_P3.1 RU23.3(1B2)
SW_VPP_EN: RU11.2(I) SW6.14
TMP102_ALERT: U21.16(P13) U53.3(ALERT)
TRSTPD: J13.8(TRSTPD) R663.1 R664.1
TS_LCD_GPIO1: J19.48 U30.4(P0)
TS_LCD_GPIO2: J19.46 U30.5(P1)
TS_LCD_GPIO3: J19.44 U30.6(P2)
TS_LCD_GPIO4: J19.42 U30.7(P3)
UART3_CTS: RU23.11(3B1) U39.8(A6)
UART3_RTS: RU23.14(4B1) U43.9(A7)
UART3_RXD: RU23.2(1B1) U39.7(A5)
UART3_TXD: RU23.5(2B1) U43.10(A8)
UART_SEL1_3: R329.1 R474.2 RU2.1(S) SW6.16 U21.17(P14)
USB1_ID: P8.4(ID) R308.2 SW1.2(A2) U21.5(P1) U120.5(ID)
USB1_VBUS_OCN: R516.1 TP5.1 U1.5(OCN) U30.15(P12)
USB2_VBUS_OCN: R512.1 TP6.1 U2.5(OCN) U30.16(P13) U141.5(OVERCUR1Z)
USB_AC_TXN0: C142.2 FL8.4
USB_AC_TXP0: C144.2 FL8.1
USB_DM_DN1: FL1.4 U141.42(USB_DM_DN1)
USB_DM_DN2: J19.52 U141.15(USB_DM_DN2)
USB_DP_DN1: FL1.1 U141.41(USB_DP_DN1)
USB_DP_DN2: J19.54 U141.14(USB_DP_DN2)
USB_HUB_PWRCLT1: R309.2 U2.4(EN) U141.4(PWRCLT1/BATEN1)
USB_HUB_PWRCLT2: J19.50 U141.6(PWRCTL2/BATEN2)
USER_LED1: DS5.1(CATHODE) U30.8(P4)
USER_LED2: DS4.1(CATHODE) U30.9(P5)
USER_LED3: DS3.1(CATHODE) U30.10(P6)
USER_LED4: DS2.1(CATHODE) U30.11(P7)
VCAP_VBBLDO_DSPEVE: C443.1 U42.J11(CAP_VBBLDO_DSPEVE)
VCAP_VBBLDO_GPU: C449.1 U42.U13(CAP_VBBLDO_GPU)
VCAP_VBBLDO_IVA: C486.1 U42.R19(CAP_VBBLDO_IVA)
VCAP_VBBLDO_MPU: C494.1 U42.J19(CAP_VBBLDO_MPU)
VCAP_VDDRAM_CORE1: C451.1 U42.H11(CAP_VDDRAM_CORE1)
VCAP_VDDRAM_CORE2: C478.1 U42.J17(CAP_VDDRAM_CORE2)
VCAP_VDDRAM_CORE3: C465.1 U42.U15(CAP_VDDRAM_CORE3)
VCAP_VDDRAM_CORE4: C473.1 U42.R17(CAP_VDDRAM_CORE4)
VCAP_VDDRAM_CORE5: C475.1 U42.Y16(CAP_VDDRAM_CORE5)
VCAP_VDDRAM_DSPEVE1: C437.1 U42.G10(CAP_VDDRAM_DSPEVE1)
VCAP_VDDRAM_DSPEVE2: C442.1 U42.H10(CAP_VDDRAM_DSPEVE2)
VCAP_VDDRAM_GPU: C477.1 U42.T16(CAP_VDDRAM_GPU)
VCAP_VDDRAM_IVA: C500.1 U42.R20(CAP_VDDRAM_IVA)
VCAP_VDDRAM_MPU1: C481.1 U42.J16(CAP_VDDRAM_MPU1)
VCAP_VDDRAM_MPU2: C510.1 U42.J21(CAP_VDDRAM_MPU2)
VDA_ABEPERMPU_F1V8: C431.1 C450.1 E7.3 U42.N9(VDDA_ABE_PER_1) U42.P16(VDDA_ABE_PER_2) U42.P18(VDDA_MPU)
VDA_CSI_F1V8: C388.1 C389.1 E5.3 U42.W17(VDDA_CSI)
VDA_DBGDSPEVE_F1V8: C483.1 C496.1 E9.3 U42.J13(VDDA_DSP_EVE) U42.N13(VDDA_DEBUG)
VDA_DDRGCOREVID_F1V8: C461.1 C469.1 E8.3 U42.N19(VDDA_DDR) U42.R14(VDDA_VIDEO) U42.R15(VDDA_GMAC_CORE)
VDA_GPUIVA_F1V8: C508.1 C521.1 E10.3 U42.P20(VDDA_IVA) U42.W15(VDDA_GPU)
VDA_HDMI_F1V8: C386.1 C387.1 E6.3 U42.AA17(VDDA_HDMI)
VDA_OSC_F1V8: C519.1 C526.1 E12.3 U42.AA15(VDDA_OSC)
VDA_PCIE_F1V8: C370.1 C371.1 E4.3 U42.AB12(VDDA_PCIE1) U42.Y12(VDDA_PCIE) U42.Y14(VDDA_PCIE0)
VDA_PHY1_1V8: E4.1 E5.1 R183.1 U65.9(VIN-)
VDA_PHY1_APM: C377.2 R183.2 U38.23(LDO1_OUT) U65.8(VBUS) U65.10(VIN+)
VDA_PHY2_1V8: E2.1 E3.1 E6.1 R182.1 U66.9(VIN-)
VDA_PHY2_APM: C376.2 R182.2 U38.21(LDO2_OUT) U66.8(VBUS) U66.10(VIN+)
VDA_PLL_1V8: E7.1 E8.1 E9.1 E10.1 E12.1 R204.1 U67.9(VIN-)
VDA_PLL_APM: C165.1 C410.2 L19.2 R204.2 U38.4(LDO5_OUT) U67.8(VBUS) U67.10(VIN+)
VDA_SATA_F1V8: C363.1 C364.1 E2.3 U42.AA13(VDDA_SATA)
VDA_USB_3V3: C147.1 C378.1 C445.1 R192.1 U42.AB10(VDDA33V_USB2) U42.AD11(VDDA33V_USB1) U68.9(VIN-)
VDA_USB_APM: C406.2 R192.2 U38.6(LDO3_OUT) U68.8(VBUS) U68.10(VIN+)
VDA_USB_F1V8: C367.1 C368.1 E3.3 U42.AA9(VDDA_USB_2) U42.AA11(VDDA_USB_3) U42.Y10(VDDA_USB_1)
VDAC_3V3: C175.1 C192.1 C507.1 E11.3 L22.1 L23.2 L24.2 R236.1 R610.1 R612.1 R614.1 R617.1 U45.1(IN)
VDISP1_12V0: J11.5(P1) U13.5(OUT5) U13.6(OUT6) U13.7(OUT7)
VDISP2_12V0: C21.1 C260.1 L4.2 U14.5(OUT5) U14.6(OUT6) U14.7(OUT7)
VFTDI_3V3: C15.1 C16.1 R7.1 R713.1 U3.1(VCCIO.1) U3.16(3V3OUT)
VHDMI_5V0: C337.1 P7.18(+5V) U19.12(5V_OUT)
VIDEO_SCL: EXP_P3.22 J8.29 R230.2 R734.2 U135.6(SCL2)
VIDEO_SDA: EXP_P3.21 J8.30 R226.2 R733.2 U135.5(SDA2)
VIO_1V8: C93.1 C115.1 C302.1 C303.1 C308.1 C416.1 C419.1 C454.1 C515.1 C520.1 C529.1 C546.1 C555.1 C688.1 EXP_P2.55 EXP_P2.56 J15.4 J15.5 J19.2 J19.4 L8.2 L27.2 P9.8 P15.38 P15.40 Q16.2(G1) R132.2 R220.1 R384.1 R385.1 R386.1 R387.1 R388.1 R389.1 R395.1 R398.1 R415.1 R416.2 R420.1 R451.2 R496.1 R619.1 R620.1 R621.1 R622.1 R623.1 R639.1 R646.1 R739.1 R740.1 R755.2 RJ1.3 RJ2.3 RJ3.1 RJ5.1 RJ6.3 RJ14.1 RJ15.3 U15.C6(VDD.1) U15.M4(VDD.2) U15.N4(VDD.3) U15.P3(VDD.4) U15.P5(VDD.5) U39.23(VCCB#23) U39.24(VCCB#24) U41.16(VCCB) U43.23(VCCB#23) U43.24(VCCB#24) U55.2(VREF1) U71.9(VIN-) U115.3(VDDIOA) U115.46(VDDIOB) U128.2(VCCA) U128.10(OE) U132.1(VCCA) U140.6(IN2) U146.2(VREF1) Y2.4(VCC)
VIO_3V3: C39.1 C42.1 C46.1 C49.1 C61.1 C64.1 C65.1 C66.1 C67.1 C68.1 C69.1 C70.1 C71.1 C87.1 C88.1 C97.1 C102.1 C104.1 C120.1 C122.1 C123.1 C135.1 C137.1 C139.1 C166.1 C177.1 C188.1 C259.1 C263.1 C265.1 C266.1 C274.1 C278.1 C279.1 C280.1 C290.1 C291.2 C305.2 C307.1 C310.1 C313.2 C316.2 C323.1 C329.1 C331.1 C335.1 C340.1 C341.2 C351.1 C353.1 C354.1 C355.1 C356.1 C357.2 C359.1 C360.1 C361.1 C365.1 C366.1 C380.1 C415.1 C430.2 C453.1 C470.2 C471.1 C514.1 C531.2 C532.1 C543.2 C549.1 C593.1 C609.1 C646.2 C687.1 C706.1 C707.1 C710.1 E1.1 E11.1 EXP_P2.57 EXP_P2.58 EXP_P2.59 EXP_P2.60 J8.1 J8.2 J8.3 J15.1 J15.2 J15.3 J17.1 J17.2 J17.3 J19.56 J19.58 J19.60 L5.2 L6.1 L7.1 L9.2 L30.2 L32.2 P5.37 P5.38 P5.39 P15.30 P15.32 P15.34 P15.36 R12.2 R19.1 R30.1 R35.2 R37.2 R40.2 R42.2 R43.2 R45.1 R47.1 R51.1 R52.2 R58.1 R60.1 R64.1 R69.1 R70.1 R71.1 R72.1 R73.1 R74.1 R75.1 R76.1 R77.1 R78.1 R79.1 R80.1 R81.1 R82.1 R83.1 R84.1 R85.1 R86.1 R97.1 R103.2 R105.2 R108.2 R129.1 R130.1 R134.1 R136.2 R137.1 R139.1 R147.1 R152.1 R153.1 R161.1 R163.1 R168.1 R188.1 R227.1 R232.1 R242.2 R248.1 R250.1 R257.1 R263.1 R264.1 R269.1 R306.2 R308.1 R311.2 R317.2 R318.1 R319.2 R320.1 R321.1 R325.1 R328.1 R336.1 R341.1 R348.1 R353.2 R354.2 R356.2 R358.2 R362.1 R364.1 R365.2 R367.1 R368.2 R369.1 R370.1 R371.2 R377.1 R403.1 R408.1 R409.2 R419.1 R421.2 R422.1 R425.1 R426.1 R427.1 R428.1 R430.1 R431.2 R452.1 R454.2 R460.1 R461.1 R464.1 R466.1 R467.2 R470.1 R472.2 R474.1 R475.1 R478.1 R482.1 R489.1 R493.1 R494.2 R499.1 R501.1 R502.1 R504.1 R507.1 R508.1 R509.1 R510.1 R512.2 R513.2 R516.2 R517.1 R518.2 R522.2 R528.1 R538.1 R569.2 R572.2 R585.1 R587.1 R588.1 R589.1 R590.1 R591.1 R592.1 R597.1 R618.1 R626.1 R634.1 R637.1 R638.1 R641.1 R643.1 R644.1 R647.1 R650.1 R651.1 R654.1 R658.1 R659.1 R665.1 R678.1 R680.1 R682.1 R702.1 R712.2 R724.2 R726.2 R727.2 R729.1 R730.1 R733.1 R734.1 R737.1 R738.1 R745.1 R746.1 R747.1 R748.1 RJ1.1 RJ2.1 RJ6.1 RJ15.1 RU1.5(VCC) RU2.16(VCC) RU3.5(VCC) RU4.16(VCC) RU5.17(VCC.1) RU6.5(VCC) RU7.17(VCC.1) RU9.20(VCC) RU10.16(VCC) RU11.5(VCC) RU12.5(VCC) RU13.17(VCC.1) RU14.16(VCC) RU16.17(VCC.1) RU17.17(VCC.1) RU18.17(VCC.1) RU19.16(VCC) RU20.20(VCC) RU21.16(VCC) RU22.16(VCC) RU23.16(VCC) RU24.5(VCC) RU25.5(VCC) U4.5(VCC) U7.5(VCC) U12.12(VCC) U12.34(VCC2) U12.37(VCC3) U12.39(VCC4) U15.E6(VFF.1) U15.F5(VFF.2) U15.J10(VFF.3) U15.K9(VFF.4) U17.5(VCC) U19.23(VCCA) U20.2(VCC) U20.14(VIO/RFU) U21.24(VDD) U23.5(VCC) U27.5(VCC) U30.24(VDD) U37.1(IN) U39.1(VCCA) U41.1(VCCA) U43.1(VCCA) U43.2(DIR) U44.5(VCC) U51.5(VCC) U53.5(V+) U54.5(VCC) U57.5(VIO/NC) U58.5(VIO/NC) U87.9(VIN-) U94.5(VCC) U95.5(VCC) U96.1(VIN.1) U96.2(VIN.2) U101.23(VDDIO#23) U101.41(VDDIO#41) U101.57(VDDIO#57) U103.5(VCC) U104.29(VIO) U104.43(VCC) U105.5(VCC) U106.5(VCC) U107.5(VCC) U108.23(VDDIO#23) U108.41(VDDIO#41) U108.57(VDDIO#57) U109.5(VCC) U110.24(VDD) U111.5(VCC) U112.5(VCC) U116.5(VCC) U118.5(VCC) U121.5(VCC) U122.8(IN1) U123.1(EN) U124.19(VCCB) U128.19(VCCB) U132.6(VCCB) U139.8(VCC) U140.8(IN1) U144.5(VCC) U145.5(VCC)
VIO_3V3_SD: C13.1 C22.1 C26.1 C27.1 C28.1 P14.4(VDD) R323.1 U96.7(VOUT.2) U96.8(VOUT.1) U97.1(VCC) U98.1(VCC) U99.1(VCC)
VIO_3V3USB: C691.1 C692.1 C693.1 C694.1 C695.1 C696.1 C697.1 C698.1 C709.1 L32.1 U141.7(VDD33#7) U141.13(VDD33#13) U141.23(VDD33#23) U141.25(VDD33#25) U141.33(VDD33#33) U141.37(VDD33#37) U141.40(VDD33#40) U141.48(VDD33#48)
VIO_3V6: C550.1 C552.1 P9.5 P9.7 R274.1 U56.9(VOUT1) U56.10(VOUT2)
VIO_IN_3V3: C408.1 Q16.3(D2) R667.1 R708.2 U38.34(VIO_IN)
VLIM_12V0: Q1.3(S) Q2.5(D1) R23.1 R39.2 U9.8(CATHODE)
VOUT3B_CLK: R59.2 RJ4.3 RU7.29(12B2)
VOUT3B_CLK_CLEANED: RJ4.2 U8.10(PCLK)
VOUT3B_D0: RU16.46(4B2) U8.43(B0/O4)
VOUT3B_D1: RU16.48(3B2) U8.44(B1/O5)
VOUT3B_D2: RU16.51(2B2) U8.45(B2)
VOUT3B_D3: RU16.53(1B2) U8.46(B3)
VOUT3B_D4: RU13.29(12B2) U8.47(B4)
VOUT3B_D5: RU13.31(11B2) U8.48(B5)
VOUT3B_D6: RU13.33(10B2) U8.1(B6)
VOUT3B_D7: RU13.35(9B2) U8.2(B7)
VOUT3B_D8: RU13.37(8B2) U8.35(G0/IO2)
VOUT3B_D9: RU13.40(7B2) U8.36(G1/IO3)
VOUT3B_D10: RU13.42(6B2) U8.37(G2)
VOUT3B_D11: RU13.44(5B2) U8.38(G3)
VOUT3B_D12: RU13.46(4B2) U8.39(G4)
VOUT3B_D13: RU13.48(3B2) U8.40(G5)
VOUT3B_D14: RU13.51(2B2) U8.41(G6)
VOUT3B_D15: RU13.53(1B2) U8.42(G7)
VOUT3B_D16: RU16.44(5B2) U8.25(R0/IO0)
VOUT3B_D17: RU16.42(6B2) U8.26(R1/IO1)
VOUT3B_D18: RU16.40(7B2) U8.27(R2)
VOUT3B_D19: RU16.37(8B2) U8.28(R3)
VOUT3B_D20: RU16.35(9B2) U8.29(R4)
VOUT3B_D21: RU16.33(10B2) U8.32(R5)
VOUT3B_D22: RU16.31(11B2) U8.33(R6)
VOUT3B_D23: RU16.29(12B2) U8.34(R7)
VOUT3B_DE: RU7.48(3B2) U8.5(DE)
VOUT3B_HSYNC: RU7.53(1B2) U8.3(HS)
VOUT3B_INTB: R30.2 RU7.46(4B2) U8.31(INTB)
VOUT3B_VSYNC: RU7.51(2B2) U8.4(VS)
VPHY_1V1: C24.1 C38.1 C50.1 C51.1 C54.1 C63.1 C73.1 C75.1 C79.1 C83.1 C90.1 C96.1 C269.1 C275.1 R324.1 U93.9(VOUT1) U93.10(VOUT2) U101.8(VDD1P1#8) U101.29(VDD1P1#29) U101.42(VDD1P1#42) U101.58(VDD1P1#58) U108.8(VDD1P1#8) U108.29(VDD1P1#29) U108.42(VDD1P1#42) U108.58(VDD1P1#58)
VPHY_2V5: C23.1 C25.1 C30.1 C31.1 C74.1 C76.1 C77.1 C78.1 C289.1 C298.1 R361.1 U101.4(VDDA2P5#4) U101.12(VDDA2P5#12) U102.9(VOUT1) U102.10(VOUT2) U108.4(VDDA2P5#4) U108.12(VDDA2P5#12)
VPIN_B01_3V3: C167.1 C168.1 R225.1 U40.9(VIN_B0) U40.13(VIN_B1) U78.9(VIN-)
VPIN_B23_3V3: C156.1 C157.1 R205.1 U40.22(VIN_B3) U40.26(VIN_B2) U77.9(VIN-)
VPIN_LDO_3V3: C385.2 C412.2 R537.1 U38.3(LDO5_IN) U38.22(LDO12_IN) U72.9(VIN-)
VPIN_LDO_5V0: C407.2 R194.1 U38.5(LDO3_IN) U38.8(LDO4_IN) U91.9(VIN-)
VPIN_S3_3V3: C390.2 R548.1 U38.10(SMPS3_IN) U75.9(VIN-)
VPIN_S4_3V3: C375.2 R533.1 U38.18(SMPS4_IN) U74.9(VIN-)
VPIN_S5_3V3: C420.2 R575.1 U38.46(SMPS5_IN) U73.9(VIN-)
VPIN_S12_3V3: C402.2 C409.2 R549.1 U38.29(SMPS2_IN) U38.32(SMPS1_IN) U76.9(VIN-)
VPO_DDR_SW: C610.1 L31.2(P2) U138.1(SW1) U138.23(SW2) U138.24(SW3)
VPO_DDR_VTT: C563.1 C580.1 R671.2 U138.9(VTT) U138.11(VTTSNS)
VPOC2_12V0: C7.1 C261.1 L4.1 P1.2
VPP: C405.1 R552.2 U37.5(OUT) U42.G14(VPP)
VPP_EN: R550.2 RU11.4(O) U37.3(EN)
VSW_3V3_APM: J18.22 R513.1 R514.1 U81.8(VBUS) U81.10(VIN+) U87.8(VBUS) U87.10(VIN+) U119.7(VOUT.2) U119.8(VOUT.1)
VSYS_3V3: C6.1 C45.1 C118.1 C161.1 C226.2 C227.2 C228.2 C229.2 C230.2 C231.2 C232.2 C233.2 C234.2 C235.2 C236.2 C237.2 C238.2 C239.2 C240.2 C241.2 C242.2 C243.2 C244.2 C245.2 C246.2 C247.2 C248.2 C249.2 C250.2 C251.2 C252.2 C320.1 C326.1 C417.1 C418.1 C488.1 C490.1 C522.1 C523.1 C524.1 C525.1 C547.1 C603.1 C626.1 C636.1 C705.1 C713.2 P6.A9(+3.3V.2) P6.A10(+3.3V.3) P6.B8(+3.3V.1) Q16.4(S2) R160.1 R205.2 R225.2 R284.2 R429.1 R444.1 R533.2 R537.2 R548.2 R549.2 R575.2 R600.1 R601.1 R608.2 R609.2 R625.1 R635.2 R636.2 R648.1 R649.1 R707.2 R728.2 R756.2 U16.5(VCC) U38.37(VCC_SENSE) U38.42(VCCA) U40.18(VANA) U40.20(NRST) U46.5(VCC) U47.5(VCC) U48.5(VCC) U65.6(VS) U66.2(A0) U66.6(VS) U67.6(VS) U68.6(VS) U69.6(VS) U70.2(A0) U70.6(VS) U71.6(VS) U72.6(VS) U72.8(VBUS) U72.10(VIN+) U73.2(A0) U73.6(VS) U73.8(VBUS) U73.10(VIN+) U74.6(VS) U74.8(VBUS) U74.10(VIN+) U75.1(A1) U75.6(VS) U75.8(VBUS) U75.10(VIN+) U76.1(A1) U76.6(VS) U76.8(VBUS) U76.10(VIN+) U77.1(A1) U77.2(A0) U77.6(VS) U77.8(VBUS) U77.10(VIN+) U78.1(A1) U78.6(VS) U78.8(VBUS) U78.10(VIN+) U79.1(A1) U79.6(VS) U80.1(A1) U80.6(VS) U81.1(A1) U81.2(A0) U81.6(VS) U82.1(A1) U82.6(VS) U83.6(VS) U84.6(VS) U85.2(A0) U85.6(VS) U86.6(VS) U87.6(VS) U88.6(VS) U88.9(VIN-) U89.2(A0) U89.6(VS) U90.6(VS) U91.6(VS) U93.1(IN1) U93.2(IN2) U102.1(IN1) U102.2(IN2) U113.6(CLR) U113.8(VCC) U114.5(SENSE1) U114.6(VDD) U117.1(IN1) U117.2(IN2) U119.1(VIN.1) U119.2(VIN.2) U126.6(VDD) U127.6(VDD) U129.5(VCC) U130.5(VCC) U131.5(VCC) U133.5(VCC) U138.3(AVIN) U138.21(PVIN1) U138.22(PVIN2) U142.5(VCC) U143.5(VCC) U147.4(VDD)
VSYS_3V3_APM: C109.1 C117.1 C119.1 C126.1 C127.1 C339.2 R138.1 R154.2 R160.2 U18.11(SA2) U88.8(VBUS) U88.10(VIN+)
VSYS_5V0: C8.1 C29.1 C124.1 C138.1 C254.1 C255.1 C262.1 C272.1 C342.1 C362.1 C403.2 C576.1 C577.1 C579.1 EXP_P2.65 EXP_P2.66 J8.4 J8.5 J19.55 J19.57 J19.59 R99.1 R162.1 R194.2 R342.1 R483.1 R487.2 R491.2 R500.1 R754.2 RU8.17(VCC.1) RU15.17(VCC.1) U1.2(IN1) U1.3(IN2) U2.2(IN1) U2.3(IN2) U5.6(VDD) U6.6(VDD) U19.10(VCC5V) U56.1(IN1) U56.2(IN2) U56.4(BIAS) U56.5(EN) U57.3(VCC) U58.3(VCC) U89.9(VIN-) U91.8(VBUS) U91.10(VIN+) U93.4(BIAS) U102.4(BIAS) U117.4(BIAS) U134.4(VBIAS) U148.2(IN)
VSYS_5V0_APM: C125.1 C131.1 C136.1 C338.2 R141.1 R159.2 R162.2 U18.28(SB2) U89.8(VBUS) U89.10(VIN+)
VSYS_12V0: C57.1 C58.1 C59.1 C60.1 C62.1 C72.1 C300.2 C301.2 C711.1 EXP_P2.49 EXP_P2.50 EXP_P2.51 EXP_P2.52 EXP_P2.53 EXP_P2.54 J1.1 J16.2 P5.40 P6.A2(+12V.4) P6.A3(+12V.5) P6.B1(+12V.1) P6.B2(+12V.2) P6.B3(+12V.3) P15.1 P15.3 Q7.5(D1) Q8.5(D1) R16.1 R32.1 R297.2 R492.2 R742.2 R743.2 U13.8(VS8) U13.9(VS9) U13.10(VS10) U14.8(VS8) U14.9(VS9) U14.10(VS10) U18.38(VIN) U90.9(VIN-)
VSYS_12V0_APM: C40.2 Q1.4(D) R32.2 U90.8(VBUS) U90.10(VIN+)
VTT: C202.1 C204.1 C205.1 C208.1 C209.1 C210.1 C212.1 C213.1 C221.1 C222.1 C224.1 C225.1 C602.1 C604.1 C611.1 C616.1 C625.1 C637.1 C644.1 C645.1 C648.1 C649.1 C653.1 C654.1 R276.2 R278.2 R671.1 R686.2 RN1.5(R4B) RN1.6(R3B) RN1.7(R2B) RN1.8(R1B) RN2.5(R4B) RN2.6(R3B) RN2.7(R2B) RN2.8(R1B) RN3.5(R4B) RN3.6(R3B) RN3.7(R2B) RN3.8(R1B) RN4.5(R4B) RN4.6(R3B) RN4.7(R2B) RN4.8(R1B) RN5.5(R4B) RN5.6(R3B) RN5.7(R2B) RN5.8(R1B) RN6.5(R4B) RN6.6(R3B) RN6.7(R2B) RN6.8(R1B) RN10.5(R4B) RN10.6(R3B) RN10.7(R2B) RN10.8(R1B) RN11.5(R4B) RN11.6(R3B) RN11.7(R2B) RN11.8(R1B) RN12.5(R4B) RN12.6(R3B) RN12.7(R2B) RN12.8(R1B) RN13.5(R4B) RN13.6(R3B) RN13.7(R2B) RN13.8(R1B) RN14.5(R4B) RN14.6(R3B) RN14.7(R2B) RN14.8(R1B) RN15.5(R4B) RN15.6(R3B) RN15.7(R2B) RN15.8(R1B)
WL_EN: P9.4 U43.19(B3)
WLAN_IRQ: P9.34 U39.21(B1)
XI_OSC0: R234.2 U125.10(Y3)
XI_OSC1: R247.2 U125.8(Y5)
XI_PHY0: R24.2 R584.2
XI_PHY1: R91.2 R581.2
XIN_PDIV1_25MHZ: R584.1 U125.13(Y1)
XIN_PDIV2_25MHZ: R581.1 U125.11(Y2)
ZQ_DBYTE1: R694.1 U136.H8(ZQ)
ZQ_DBYTE2: R705.1 U62.H8(ZQ)
ZQ_DBYTE3: R695.1 U137.H8(ZQ)
ZQ_DBYTE4: R704.1 U61.H8(ZQ)
ZQ_DBYTE4_1: R693.1 U63.H8(ZQ)
N16769336: TP9.1 U18.4(GC2)
N16769346: Q7.4(G) R402.1
N16769518: C339.1 L10.2 R138.2 U18.10(SA1)
N16769802: R148.2 R154.1
N16769806: C334.2 U18.5(CBA)
N16769822: C80.2 R87.1
N16769842: Q9.4(G) R417.1
N16769938: C128.2 R148.1 R149.2 U18.12(FBA)
N16769982: R441.1 U18.1(VBAT)
N16770060: C325.2 R445.2 U18.35(VREG)
N16770156: R445.1 R446.2 U18.20(SYNC)
N16770184: C348.2 C350.2 U18.13(COMPA)
N16770362: Q8.4(G) R401.1
N16770396: R479.2 U18.22(RT)
N16770460: C343.1 U18.14(SSA)
N16770544: C338.1 L11.2 R141.2 U18.29(SB1)
N16770796: R156.2 R159.1
N16770800: C333.2 U18.34(CBB)
N16770818: C81.2 R88.1
N16770854: Q10.4(G) R414.1
N16771006: C129.2 R155.2 R156.1 U18.27(FBB)
N16771022: C345.1 U18.25(SSB)
N16771108: C352.1 U18.21(DLYAB)
N16771210: C344.2 C349.2 U18.26(COMPB)
N16772449: Q2.4(G) U9.2(GT PULL DWN) U9.6(GATE DRV)
N16772477: C47.1 U9.1(VCAPL)
N16772485: C47.2 U9.7(VCAPH)
N16772555: C37.1 D3.1(CATHODE) F1.1 Q2.1(S1) Q2.2(S2) Q2.3(S3) U9.4(ANODE)
N16772927: D2.2(ANODE) D3.2(ANODE)
N16772931: DS1.2(ANODE) R297.1
N16773123: J7.1 R350.1 SW2.1(A) SW2.2(AA)
N16789072: C552.2 R274.2 R662.1 U56.8(FB)
N16789078: C564.1 U56.7(SS)
N16791668: EXP_P2.86 TP27.1
N16791764: EXP_P2.99 TP20.1
N16791766: EXP_P2.100 TP28.1
N16791773: EXP_P2.101 TP21.1
N16791815: EXP_P2.107 TP23.1
N16791884: EXP_P2.117 TP25.1
N16791886: EXP_P2.118 TP29.1
N16791893: EXP_P2.119 TP24.1
N16791895: EXP_P2.120 TP30.1
N16793461: EXP_P3.5 TP52.1
N16793463: EXP_P3.6 TP53.1
N16793477: EXP_P3.7 TP50.1
N16793479: EXP_P3.8 TP51.1
N16793493: EXP_P3.9 TP48.1
N16793495: EXP_P3.10 TP49.1
N16793503: EXP_P3.11 TP46.1
N16793510: EXP_P3.12 TP47.1
N16793526: EXP_P3.14 TP88.1
N16793540: EXP_P3.15 TP44.1
N16793542: EXP_P3.16 TP45.1
N16793550: EXP_P3.17 TP42.1
N16793552: EXP_P3.18 TP43.1
N16793588: EXP_P3.23 TP40.1
N16793595: EXP_P3.24 TP41.1
N16805684: J20.4 R290.1 U58.7(CANH)
N16805728: C624.1 R289.1 R290.2
N16805777: J20.3 R289.2 U58.6(CANL)
N16805799: R687.1 U58.8(STB)
N16808389: R273.1 Y2.3(OUT)
N16808436: P9.12 TP81.1(TP)
N16808440: P9.11 TP80.1(TP)
N16808466: P9.14 TP78.1(TP)
N16808470: P9.13 TP79.1(TP)
N16808488: P9.15 TP77.1(TP)
N16808492: P9.16 TP76.1(TP)
N16808754: P9.73 TP64.1(TP)
N16808763: P9.76 TP63.1(TP)
N16808859: R650.2 U55.7(VREF2) U55.8(EN)
N16817374: R244.2 U43.3(A1) U43.7(A5) U43.8(A6)
N16817668: R193.1 U39.14(B8) U39.18(B4) U39.20(B2)
N16817815: R222.1 R592.2 U41.2(1DIR)
N16817915: R579.1 U41.14(2O\E\) U41.15(1O\E\)
N16817953: R217.1 R585.2 U41.3(2DIR)
N16827008: TP4.1 U92.1(VBUS_OUT.1) U92.2(VBUS_OUT.2)
N16827026: R305.2 R306.1 U92.3(ENN)
N16827028: R310.2 R311.1 U92.4(ACKN)
N16827261: TP39.1 U120.1(VBUS_OUT.1) U120.2(VBUS_OUT.2)
N16827295: R518.1 R521.2 U120.3(ENN)
N16827297: R522.1 R523.2 U120.4(ACKN)
N16827351: R307.1 SW1.3(A3)
N16828309: C3.1 L3.2 R8.1 U1.6(OUT3) U1.7(OUT2) U1.8(OUT1)
N16828490: C2.1 L1.2 R1.1 U2.6(OUT3) U2.7(OUT2) U2.8(OUT1)
N16830127: C639.1 P11.3(RING)
N16830174: C206.1 P11.2(TIP)
N16830302: C530.1 C548.1 P10.2(TIP) P10.3(RING) R633.1 R645.1
N16830387: C594.1 U50.18(HPLOUT)
N16830391: C594.2 P13.2(TIP) R697.1
N16830429: C206.2 U50.3(LINE1L+)
N16830431: C638.1 U50.23(HPROUT)
N16830435: C638.2 P13.3(RING) R700.1
N16830493: C530.2 R628.1
N16830497: C639.2 U50.5(LINE1R+)
N16830507: C544.1 R632.1 R633.2
N16830573: R628.2 U50.11(MIC3L) U50.14(MIC3R)
N16830575: R632.2 U50.13(MICBIAS)
N16830603: R275.1 U50.29(LEFT_LO+)
N16830629: C203.1 R275.2
N16830631: C203.2 P12.2(TIP) R279.1
N16830653: R696.1 U50.31(RIGHT_LO+)
N16830655: C635.1 R696.2
N16830657: C635.2 P12.3(RING) R701.1
N16830743: R246.1 R610.2 U50.45(MFP0)
N16830771: R251.1 R612.2 U50.46(MFP1)
N16830784: R254.1 R614.2 U50.47(MFP2)
N16830793: R256.1 R617.2 U50.48(MFP3)
N16830868: R236.2 R606.1 U50.43(SELECT)
N16830872: R241.2 U50.37(MCLK)
N16832179: R13.2 R16.2 U5.5(SENSE1)
N16832191: P6.A11(PERSTN) R317.1 RU1.4(O) U4.2(I)
N16832201: R319.1 U5.1(R\E\S\E\T) U6.1(R\E\S\E\T) U7.2(A)
N16832203: RU1.2(I) U7.4(Y)
N16832211: C264.1 U5.4(CT)
N16832311: R18.2 R19.2 U6.5(SENSE1)
N16832327: C276.1 U6.4(CT)
N16832365: P6.A1(P\R\S\N\T\1\) R381.1
N16832405: P6.A5(TCK) R372.1
N16832557: P6.A6(TDI) R370.2
N16832559: P6.A8(TMS) R369.2
N16832585: P6.B9(TRSTN) R404.1
N16832754: P6.B17(P\R\S\N\T\2\) R381.2
N16833554: R26.1 R27.2 U10.11(OS0)
N16833556: R28.2 R29.1 U10.10(OS1)
N16833743: R340.1 R349.2 U10.7(0E)
N16833769: C55.2 U10.21(XIN) Y1.1(Y1)
N16833803: C41.1 U10.17(REG_CAP2)
N16833813: C48.1 U10.19(REG_CAP1)
N16833855: C55.1 R48.1 Y1.3(C1)
N16833862: TP11.1 U10.23(OSCOUT)
N16846683: R678.2 R679.1 U139.3(NC)
N16846685: R680.2 R681.1 U139.2(A1)
N16846687: R682.2 R683.1 U139.1(A0)
N16846806: R630.1 R641.2 U53.4(ADD0)
N16848026: R70.2 SW3.16(B1)
N16848051: R71.2 SW3.15(B2)
N16848076: R72.2 SW3.14(B3)
N16848101: R73.2 SW3.13(B4)
N16848126: R74.2 SW3.12(B5)
N16848151: R75.2 SW3.11(B6)
N16848176: R76.2 SW3.10(B7)
N16848196: R77.2 SW3.9(B8)
N16848352: R78.2 SW4.16(B1)
N16848377: R79.2 SW4.15(B2)
N16848402: R80.2 SW4.14(B3)
N16848427: R81.2 SW4.13(B4)
N16848452: R82.2 SW4.12(B5)
N16848477: R83.2 SW4.11(B6)
N16848502: R84.2 SW4.10(B7)
N16848522: R85.2 SW4.9(B8)
N16848818: R495.2 SW6.1
N16848841: R490.2 SW6.2
N16848864: R485.2 SW6.3
N16848887: R481.2 SW6.4
N16848910: R477.2 SW6.5
N16848933: R469.2 SW6.6
N16848956: R464.2 SW6.7
N16848979: R462.2 SW6.8
N16849002: R459.2 SW6.9
N16849020: R455.2 SW6.10
N16849958: R52.1 RU3.4(O) U12.9(\\C\E\)
N16849973: R34.2 R35.1 U12.7(R/\B\)
N16852703: R362.2 U104.17(RY/B\Y\)
N16856648: R418.2 U15.M6(CLK)
N16856897: R416.1 U15.K5(RSTN) U109.4(O)
N16868512: R465.2 RU13.3(1A2) RU13.5(2A2) RU13.7(3A2) RU13.10(4A2) RU13.12(5A2) RU13.14(6A2) RU13.16(7A2) RU13.20(8A2) RU13.22(9A2) RU13.24(10A2) RU13.26(11A2) RU13.28(12A2)
N16868523: R520.2 RU16.3(1A2) RU16.5(2A2) RU16.7(3A2) RU16.10(4A2) RU16.12(5A2) RU16.14(6A2) RU16.16(7A2) RU16.20(8A2) RU16.22(9A2) RU16.24(10A2) RU16.26(11A2) RU16.28(12A2)
N16869658: R164.2 RU7.3(1A2) RU7.5(2A2) RU7.7(3A2) RU7.10(4A2) RU7.12(5A2) RU7.13(6A1) RU7.14(6A2) RU7.15(7A1) RU7.16(7A2) RU7.18(8A1) RU7.20(8A2) RU7.21(9A1) RU7.22(9A2) RU7.23(10A1) RU7.24(10A2) RU7.25(11A1) RU7.26(11A2) RU7.28(12A2)
N16874153: RU5.56(S1) U17.4(O)
N16874429: R143.2 RU5.3(1A2) RU5.5(2A2) RU5.7(3A2) RU5.10(4A2) RU5.12(5A2) RU5.14(6A2) RU5.16(7A2) RU5.20(8A2) RU5.22(9A2) RU5.24(10A2) RU5.25(11A1) RU5.26(11A2) RU5.27(12A1) RU5.28(12A2)
N16880764: RU18.56(S1) U121.4(O)
N16880951: RJ10.2 RU18.43(6B1)
N16880965: RJ9.2 RU18.41(7B1)
N16880979: RJ8.2 RU18.39(8B1)
N16880993: RJ7.2 RU18.36(9B1)
N16881018: R511.1 RU18.3(1A2) RU18.5(2A2) RU18.7(3A2) RU18.10(4A2) RU18.12(5A2) RU18.14(6A2) RU18.16(7A2) RU18.20(8A2) RU18.22(9A2) RU18.23(10A1) RU18.24(10A2) RU18.25(11A1) RU18.26(11A2) RU18.27(12A1) RU18.28(12A2)
N16886591: R223.1 R227.2 R735.1 RU22.2(1B1)
N16886593: R229.1 R232.2 R736.1 RU22.5(2B1)
N16886703: RU22.1(S) U44.4(O)
N16888125: R506.1 R509.2 U30.21(A0)
N16888127: R499.2 R503.1 U30.2(A1)
N16888129: R505.1 R508.2 U30.3(A2)
N16888136: R498.2 U30.1(I\N\T\)
N16888524: R471.1 R478.2 U21.21(A0)
N16888526: R461.2 R463.1 U21.2(A1)
N16888528: R468.1 R475.2 U21.3(A2)
N16888536: R497.2 U21.1(I\N\T\)
N16888767: R486.1 U111.4(O)
N16888979: R411.1 R422.2 U110.21(A0)
N16888981: R405.1 R408.2 U110.2(A1)
N16888983: R412.1 R419.2 U110.3(A2)
N16888990: R107.1 U112.4(O)
N16889000: R400.2 U110.1(I\N\T\)
N16891345: P14.10(INSERT_COM) R2.1
N16891485: C267.1 R323.2 U100.1(VCC)
N16892015: C273.1 U96.6(CT)
N16892029: R342.2 U96.4(VBIAS)
N16916626: C578.1 R674.2 R676.2
N17023760: R92.2 R99.2 R101.2 R102.2 U115.43(RX_5V)
N17023786: R101.1 TP16.1(TP) U115.42(HPD)
N17023843: R92.1 R406.2 U115.44(DDC_SDA)
N17023899: R102.1 R413.2 U115.45(DDC_SCL)
N17023921: R454.1 TP26.1(TP) U115.1(CEC)
N17023993: R406.1 TP17.1(TP)
N17024012: R413.1 TP18.1(TP)
N17024054: R449.2 U115.14(SDA)
N17024079: R450.2 U115.15(SCL)
N17024117: C328.1 R442.1 R447.2 U115.19(IDX)
N17024178: R132.1 TP19.1(TP) U115.40(REM_INTB)
N17024186: R451.1 TP22.1(TP) U115.13(INTB)
N17024209: C332.1 R448.1 R456.2 U115.18(MODE_SEL0)
N17024222: C312.1 R410.2 R423.1 U115.32(MODE_SEL1)
N17024263: C89.1 R110.1 TP14.1(TP) U115.31(PDB)
N17024348: C101.1 L28.1 U115.57(VTERM)
N17024432: R453.1 U115.6(SCLK/I2CSEL)
N17024500: R111.1 U115.30(RES2)
N17024526: C107.1 U115.20(LFT)
N17024906: Q3.D R45.2 R50.1
N17025083: R50.2 U13.3(IN)
N17025101: R58.2 R62.2 U13.14(STN)
N17025155: R62.1 TP10.1(TP)
N17025181: R65.2 U13.13(CL)
N17025216: R68.2 U13.12(DIAG_EN)
N17027122: R644.2 U135.7(VREF2) U135.8(EN)
N17027318: J15.26 R677.2
N17029697: C258.1 P3.2(VCC)
N17029975: P3.D1(LED1-AK) R301.1
N17029983: P3.D2(LED1-KA) RJ13.2
N17030002: R33.2 U101.24(JTAG_TRSTN)
N17030015: P3.D3(LED2-AK) R302.1
N17030236: U101.59(RESETN) U103.4(Y)
N17030260: C284.1 R24.1 R338.2 U101.19(XI) Y3.1
N17030273: C268.1 R338.1 U101.18(XO) Y3.2
N17030313: TP7.1(TP) U101.22(CLK_OUT)
N17032286: C257.1 P4.2(VCC)
N17032564: P4.D1(LED1-AK) R299.1
N17032572: P4.D2(LED1-KA) RJ12.2
N17032591: R100.2 U108.24(JTAG_TRSTN)
N17032604: P4.D3(LED2-AK) R300.1
N17032833: U106.4(Y) U108.59(RESETN)
N17032852: C311.1 R91.1 R399.2 U108.19(XI) Y4.1
N17032862: C299.1 R399.1 U108.18(XO) Y4.2
N17032902: TP13.1(TP) U108.22(CLK_OUT)
N17035312: R394.2 U107.4(Y)
N17036157: J13.1(VREF_DBG) J13.12(VREF_TR) R665.2
N17036363: J13.15(TGT_DETECT) R640.2
N17038308: R268.1 RU10.4(1A)
N17038335: R271.1 RU10.7(2A)
N17038428: Q6.D R46.2
N17038575: J17.8 R440.1
N17038592: J17.9 R439.1
N17038609: J17.10 R438.1
N17038626: J17.11 R437.1
N17038643: J17.12 R436.1
N17038647: J17.13 R435.1
N17038700: J17.32 R434.1
N17039732: C269.2 R15.1 R324.2 U93.8(FB)
N17039746: C12.1 U93.7(SS)
N17039774: R3.1 RJ1.2 U93.5(EN)
N17040452: C289.2 R53.1 R361.2 U102.8(FB)
N17040466: C56.1 U102.7(SS)
N17040494: R20.1 RJ2.2 U102.5(EN)
N17127468: Q12.D R321.2 U95.2(I)
N17127513: Q12.G R313.2 R315.1
N17127575: Q11.D R320.2 U94.2(I)
N17127620: Q11.G R312.2 R314.1
N17128348: J14.1 U52.4(IO3) U133.4(O)
N17128443: J14.2 U52.5(IO4) U131.4(O)
N17128562: J14.4 U52.1(IO1) U129.4(O)
N17128571: J14.5 U52.3(IO2) U130.4(O)
N17132279: C18.1 U8.14(CAPP12)
N17132316: C33.1 C36.1 U8.7(CAPL12)
N17132397: C17.1 U8.17(CAPHS12)
N17132449: FL2.2 P1.1
N17132477: C19.1 U8.20(DOUT+)
N17132490: FL2.3 P1.3
N17132501: C20.1 U8.19(DOUT-)
N17132537: C271.1 U8.23(CMF)
N17132610: R325.2 R326.1 U8.24(MODE_SEL)
N17132637: R336.2 R337.1 U8.6(IDX)
N17132743: C11.1 R318.2 U8.21(PDB)
N17139258: Q5.D R60.2 R61.1
N17139366: R61.2 U14.3(IN)
N17139372: R96.2 R97.2 U14.14(STN)
N17139433: R98.2 U14.13(CL)
N17139447: R95.2 U14.12(DIAG_EN)
N17140327: C347.2 R140.1 R473.2 U117.8(FB)
N17140341: C121.1 U117.7(SS)
N17140369: R142.1 RJ6.2 U117.5(EN)
N17208527: J21.4 R288.1 U57.7(CANH)
N17208571: C623.1 R287.1 R288.2
N17208626: J21.3 R287.2 U57.6(CANL)
N17208671: R689.1 U57.8(STB)
N17213075: C292.1 C293.1 C294.1 L9.1 U11.6(VDDOUT#6) U11.7(VDDOUT#7)
N17213086: C295.1 C296.1 C297.1 L8.1 R67.2 U11.3(VDD)
N17213569: R67.1 U11.4(VCTRL)
N17213624: R59.1 R63.2 U11.1(XIN/CLK)
N17213889: RJ3.2 U11.13(SDA)
N17213902: RJ5.2 U11.12(SCL)
N17213969: RJ14.2 U11.2(S0)
N17214102: RJ4.1 U11.11(Y1)
N17240442: R458.1 RU4.6(2B2)
N17240462: R457.1 RU4.10(3B2)
N17269696: R96.1 TP15.1(TP)
N17464210: R596.1 U42.E17(XREF_CLK1/MCASP2_AXR9/MCASP1_AX)
N17464229: R252.1 R613.1 U42.B25(XREF_CLK2/MCASP2_AXR10/MCASP1_A)
N17468373: R567.2 U42.F9(VOUT1_D0/UART5_RXD/VIN4A_D16/VI)
N17468379: R198.2 U42.E10(VOUT1_D1/UART5_TXD/VIN4A_D17/VI)
N17468389: R206.2 U42.D9(VOUT1_D2/EMU2/VIN4A_D18/VIN3A_D)
N17468401: R201.2 U42.C6(VOUT1_D3/EMU5/VIN4A_D19/VIN3A_D)
N17468413: R568.2 U42.E9(VOUT1_D4/EMU6/VIN4A_D20/VIN3A_D)
N17468425: R562.2 U42.F8(VOUT1_D5/EMU7/VIN4A_D21/VIN3A_D)
N17468437: R565.2 U42.F7(VOUT1_D6/EMU8/VIN4A_D22/VIN3A_D)
N17468449: R553.2 U42.E7(VOUT1_D7/EMU9/VIN4A_D23/VIN3A_D)
N17468461: R555.2 U42.E8(VOUT1_D8/UART6_RXD/VIN4A_D8/VIN)
N17468473: R564.2 U42.D8(VOUT1_D9/UART6_TXD/VIN4A_D9/VIN)
N17468485: R561.2 U42.D6(VOUT1_D10/EMU3/VIN4A_D10/VIN3A_)
N17468497: R557.2 U42.D7(VOUT1_D11/EMU10/VIN4A_D11/VIN3A)
N17468509: R200.2 U42.A5(VOUT1_D12/EMU11/VIN4A_D12/VIN3A)
N17468521: R559.2 U42.B6(VOUT1_D13/EMU12/VIN4A_D13/VIN3A)
N17468533: R560.2 U42.C8(VOUT1_D14/EMU13/VIN4A_D14/VIN3A)
N17468545: R563.2 U42.C7(VOUT1_D15/EMU14/VIN4A_D15/VIN3A)
N17468557: R203.2 U42.B7(VOUT1_D16/UART7_RXD/VIN4A_D0/VI)
N17468569: R195.2 U42.B8(VOUT1_D17/UART7_TXD/VIN4A_D1/VI)
N17468581: R199.2 U42.A6(VOUT1_D18/EMU4/VIN4A_D2/VIN3A_D)
N17468593: R202.2 U42.A7(VOUT1_D19/EMU15/VIN4A_D3/VIN3A_)
N17468605: R566.2 U42.C9(VOUT1_D20/EMU16/VIN4A_D4/VIN3A_)
N17468617: R197.2 U42.A8(VOUT1_D21/EMU17/VIN4A_D5/VIN3A_)
N17468629: R212.2 U42.B9(VOUT1_D22/EMU18/VIN4A_D6/VIN3A_)
N17468641: R207.2 U42.A9(VOUT1_D23/EMU19/VIN4A_D7/VIN3A_)
N17468659: R574.2 U42.D11(VOUT1_CLK/VIN4A_FLD0/VIN3A_FLD0)
N17468667: R570.2 U42.D10(VOUT1_VSYNC/VIN4A_VSYNC0/VIN3A_)
N17468677: R577.2 U42.A10(VOUT1_HSYNC/VIN4A_HSYNC0/VIN3A_)
N17468701: R210.2 U42.C10(VOUT1_DE/VIN4A_DE0/VIN3A_DE0/SP)
N17468893: R571.2 TP56.1 U42.D5(VIN2A_FLD0/VIN2B_CLK1/VOUT2_CLK)
N17470760: R526.2 U42.T6(RGMII0_TXC/UART3_CTSN/RMII1_RXD)
N17470772: R524.2 U42.U5(RGMII0_TXCTL/UART3_RTSN/RMII1_R)
N17470784: R529.2 U42.T5(RGMII0_TXD0/RMII0_RXD0/MII0_RXD)
N17470792: R530.2 U42.U6(RGMII0_TXD1/RMII0_RXD1/MII0_RXD)
N17470802: R531.2 U42.T3(RGMII0_TXD2/RMII0_RXER/MII0_RXE)
N17470810: R532.2 U42.T4(RGMII0_TXD3/RMII0_CRS/MII0_CRS/)
N17470942: R245.2 R607.2 U42.A23(SPI1_CS0/GPIO7_10)
N17470980: R235.2 R603.2 U42.B24(SPI1_D0/GPIO7_9)
N17470990: R216.2 R578.2 U42.C15(SPI1_D1/GPIO7_8)
N17484787: R544.2 R545.1 U38.16(BOOT)
N17484833: SW7.3(B) SW7.4(BB) U38.24(PWRON)
N17484968: TP59.1(TP) U38.2(GPIO_2)
N17484976: R706.1 TP54.1(TP) U38.14(GPIO_3)
N17484985: R546.1 R547.2 U38.15(GPIO_5)
N17485041: TP60.1(TP) U38.48(SYNCCLKOUT)
N17485079: TP61.1(TP) U38.38(ADCIN1)
N17485083: TP62.1(TP) U38.39(ADCIN2)
N17485295: C413.2 U38.40(VBG)
N17493600: R691.1 U59.L8(ZQ)
N17493609: R690.1 U60.L8(ZQ)
N17495735: C200.1 R675.2 R684.2
N17514506: R270.1 RU10.9(3A) RU10.12(4A)
N17515494: C358.1 U119.6(CT)
N17515522: R500.2 U119.4(VBIAS)
N17523122: C545.1 U134.6(CT)
N17523181: R281.2 R296.2 R699.2 TP90.1(TP) U138.6(PGOOD)
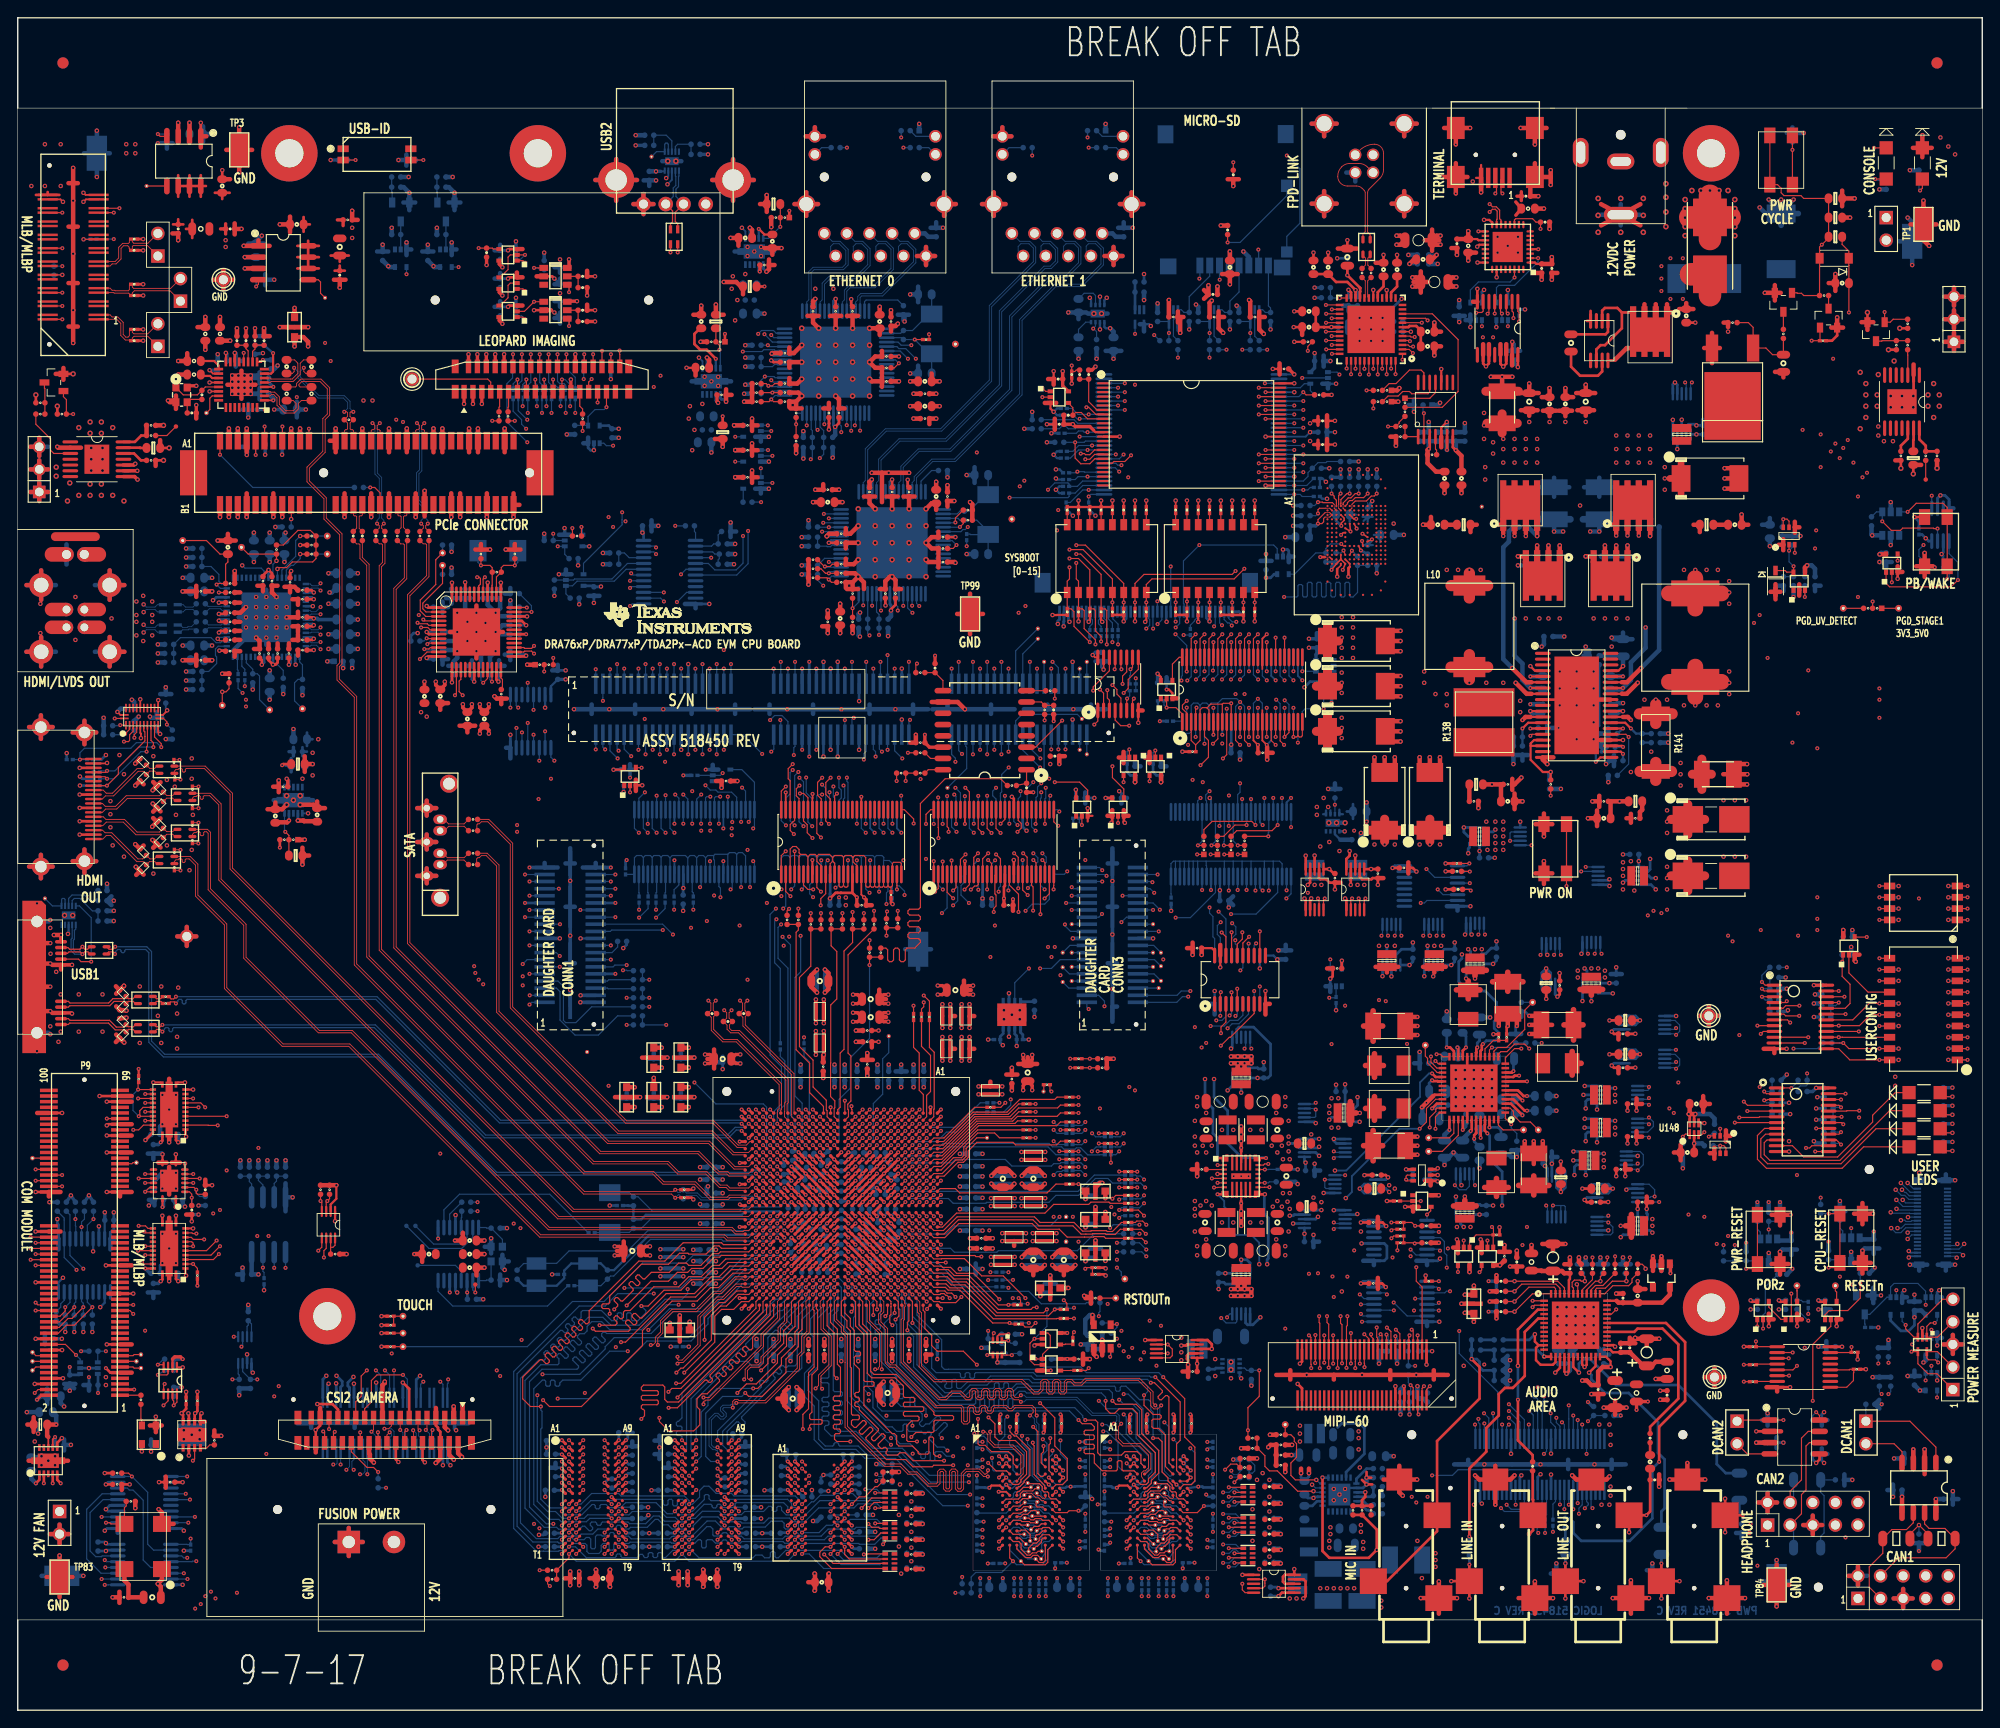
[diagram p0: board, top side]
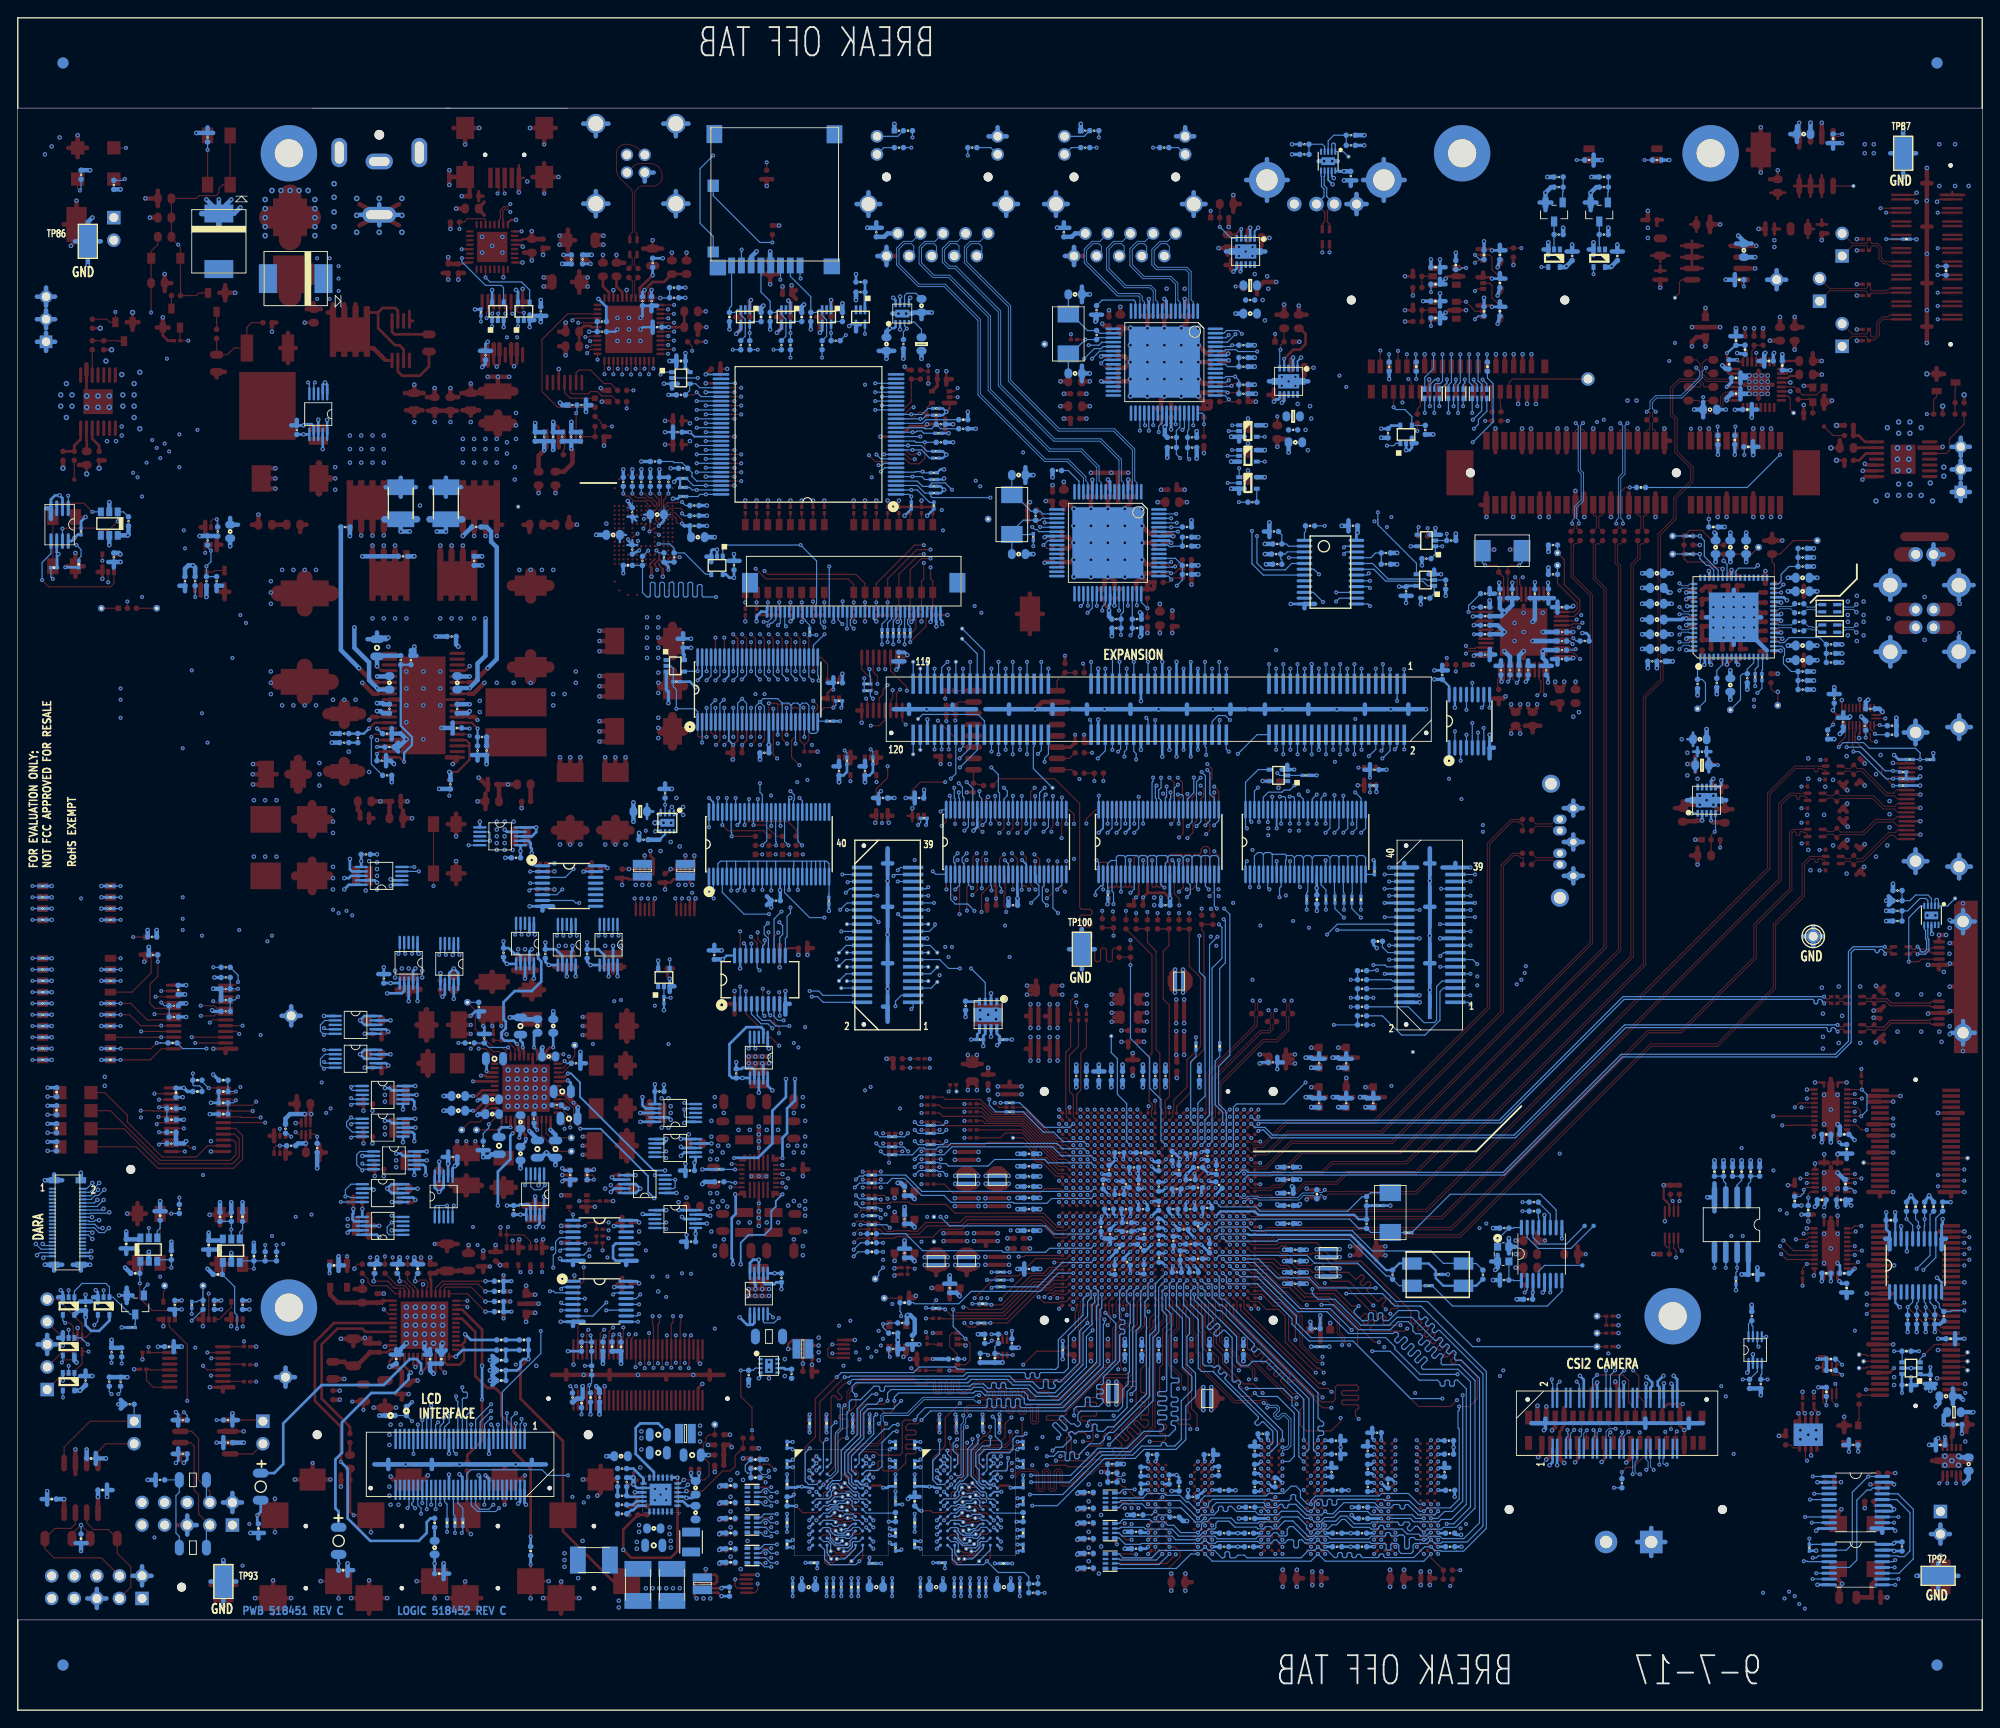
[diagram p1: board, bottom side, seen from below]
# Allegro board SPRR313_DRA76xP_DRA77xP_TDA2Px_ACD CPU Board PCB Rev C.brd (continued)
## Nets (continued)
N17523441: C610.2 U138.2(BOOT)
N17523556: R284.1 R285.2 U138.4(ENSW)
N17523683: R283.1 U138.13(ILIM)
N17523717: C211.2 U138.17(SS/TRK)
N17523739: C214.2 R286.1 U138.16(COMP)
N17523799: C601.1 R688.1 R692.2 U138.15(FB)
N17523845: R291.1 U138.18(RT/SYNC)
N17523889: C215.2 R286.2
N17526209: U46.4(Y) U47.1(B)
N17528197: R551.2 R552.1 U37.4(FB)
N17528796: C480.1 U125.1(XIN/CLK) Y6.3(C1)
N17528834: TP89.1(TP) U125.4(VCTR)
N17528966: C479.1 U125.16(XOUT) Y6.1(Y1)
N17529000: TP66.1(TP) U125.2(S0)
N17529020: TP68.1(TP) U125.15(S1/SDA)
N17529026: TP67.1(TP) U125.14(S2/SCL)
N17533979: C381.1 L30.1 U123.4(VCC)
N17534947: J8.7 TP8.1
N17534968: J8.9 R54.2
N17535002: J8.11 R55.2
N17535025: J8.12 R352.2
N17535034: J8.13 RN9.1(R1A)
N17535043: J8.14 RN9.2(R2A)
N17535052: J8.15 RN9.3(R3A)
N17535075: J8.16 RN9.4(R4A)
N17535084: J8.17 RN8.1(R1A)
N17535093: J8.18 RN8.2(R2A)
N17535102: J8.19 RN8.3(R3A)
N17535125: J8.20 RN8.4(R4A)
N17535134: J8.21 RN7.1(R1A)
N17535143: J8.22 RN7.2(R2A)
N17535152: J8.23 RN7.3(R3A)
N17535156: J8.24 RN7.4(R4A)
N17535194: J8.27 R56.2
N17535203: J8.28 R355.2
N17535228: J8.33 R365.1 U105.4(O)
N18019611: C35.1 D1.1(CATHODE) R31.1 R150.1
N18021291: C40.1 Q1.1(G) R23.2 R36.2
N18025110: Q4.D R36.1
N18135987: R698.2 U42.N25(DDR2_RST)
N18135998: R292.2 U42.AF23(DDR1_RST)
N18162661: R594.2 R595.2 U126.5(SENSE1) U127.5(SENSE1)
N18162692: C468.1 U127.4(CT)
N18162710: R534.2 R601.2 R602.2 SW9.3(B) SW9.4(BB) U127.3(M\R\)
N18162871: C467.1 U126.4(CT)
N18162895: R519.2 R600.2 SW8.3(B) SW8.4(BB) U126.3(M\R\)
N18164113: R541.2 U122.4(ILIM)
N18519231: R598.2 U42.C18(TDO/GPIO8_28)
N18519277: R599.2 U42.E18(RTCK/GPIO8_29)
N18519299: R593.2 U42.F19(EMU0/GPIO8_30)
N18519321: R611.2 U42.C23(EMU1/GPIO8_31)
N18551205: R525.1 U42.W3(MMC1_CLK/GPIO6_21)
N18551238: R527.1 U42.AC3(MMC3_CLK/USB3_ULPI_D5/VIN2B_D7/)
N18580498: R643.2 U51.1(OE) U54.1(OE)
N18580530: R272.2 U54.4(O)
N18580585: R265.2 U51.4(O)
N18582457: R624.2 U42.F21(UART1_CTSN/UART9_RXD/MMC4_CLK/G)
N18586695: R580.2 U42.B13(MCASP1_ACLKX/I2C3_SDA/PR2_MDIO_)
N18586717: R582.2 U42.C13(MCASP1_FSX/I2C3_SCL/PR2_MDIO_DA)
N18586871: R209.2 U42.C12(MCASP1_AXR10/MCASP6_ACLKX/MCASP)
N18586893: R213.2 U42.A12(MCASP1_AXR11/MCASP6_FSX/MCASP6_)
N18586939: R583.2 U42.F12(MCASP1_AXR14/MCASP7_ACLKX/MCASP)
N18586956: R218.2 U42.E14(MCASP1_AXR15/MCASP7_FSX/MCASP7_)
N18587563: TP65.1 U42.E15(MCASP2_ACLKR/MCASP8_AXR2/VOUT2_)
N18587580: R231.2 U42.A18(MCASP2_ACLKX/PR2_MII0_RXD2/XX)
N18587589: TP75.1 U42.A19(MCASP2_FSR/MCASP8_AXR3/VOUT2_D9)
N18587966: R221.2 U42.B17(MCASP3_ACLKX/MCASP3_ACLKR/MCASP)
N18587983: R214.1 U42.F13(MCASP3_FSX/MCASP3_FSR/MCASP2_AX)
N18588000: R228.1 U42.B18(MCASP3_AXR0/MCASP2_AXR14/UART7_)
N18588017: R586.1 U42.C16(MCASP3_AXR1/MCASP2_AXR15/UART7_)
N18588440: R535.1 R539.1 U42.AA3(MCASP5_ACLKX/MCASP5_ACLKR/SPI4_)
N18588483: R542.1 U42.AB6(MCASP5_FSX/MCASP5_FSR/SPI4_D1/U)
N18588505: R536.1 R540.1 U42.AB3(MCASP5_AXR0/SPI4_D0/UART9_CTSN/)
N18588548: R190.1 R543.1 U42.AA4(MCASP5_AXR1/SPI4_CS0/UART9_RTSN)
N18603445: R229.2 RU24.2(I)
N18603451: R223.2 RU25.2(I)
N18608535: R255.2 U42.A25(SPI2_SCLK/UART3_RXD/GPIO7_14)
N18608628: R224.1 U42.A17(MCASP2_FSX/PR2_MII0_RXD1/XX)
N19619900: Q16.5(G2) Q16.6(D1) R707.1
N20276117: R709.2 U140.4(ILIM)
N20585139: R714.2 RJ16.2 U141.9(USB_VBUS)
N20585277: R716.2 U141.24(USB_R1)
N20585453: C689.1 R717.2 U141.38(XI) Y8.1
N20585465: C690.1 R717.1 U141.39(XO) Y8.2
N20587089: R719.1 U141.10(TEST)
N20589015: R722.2 U141.36(FULLPWWRMGMTTZ/SMBA1)
N20589055: R724.1 U141.8(OVERCUR2Z)
N20595711: R726.1 TP94.1(TP) U141.2(SCL/SMBCLK)
N20595725: R727.1 TP95.1(TP) U141.3(SDA/SMBDAT)
N20609618: R725.2 U141.22(SMBUSZ)
N20753097: P5.16 R322.1
N20753149: P5.25 R316.2
N20753966: C9.1 C10.1 L2.2 U3.19(VCC)
N20753978: C4.1 J3.1(USBVDD) L2.1
N21029046: R731.2 U141.21(PWRCTL_POL)
N21030069: R732.2 U141.35(GANGED/SMBA2)
N21067838: R738.2 U146.7(VREF2) U146.8(EN)
N21093937: R515.1 RU17.3(1A2) RU17.5(2A2) RU17.7(3A2) RU17.10(4A2) RU17.12(5A2) RU17.14(6A2) RU17.16(7A2) RU17.20(8A2) RU17.22(9A2) RU17.24(10A2) RU17.26(11A2) RU17.28(12A2)
N21350306: R750.2 SW10.3(A3)
N21350307: R749.2 SW10.4(A4)
N21350308: R752.2 SW10.1(A1)
N21350309: R751.2 SW10.2(A2)
N21412134: Q19.3(D2) R753.1
N21412457: Q19.5(G2) Q19.6(D2) R754.1
N21462852: R215.1 U40.3(CLKIN)
N21464065: R429.2 U113.7(PRE) U114.1(R\E\S\E\T)
N21464089: R444.2 SW5.3(B) SW5.4(BB) U114.3(M\R\)
N21464106: U16.1(B) U113.5(Q)
N21464815: C712.1 D24.1(CATHODE) Q18.2(G2) R742.1 R744.1 U147.5(SENSE)
N21464817: Q18.5(G2) Q18.6(D2) R743.1
N167702540: C348.1 R480.2
N167712620: C349.1 R476.2
N168882401: DS5.2(ANODE) R517.2
N168882481: DS4.2(ANODE) R510.2
N168882561: DS3.2(ANODE) R507.2
N168882641: DS2.2(ANODE) R504.2
N207539901: DS6.2(ANODE) R713.2
N1746820385: R556.2 U42.E6(VIN2A_D12/RGMII1_TXC/VOUT2_D11/)
N1746820386: R176.2 U42.C1(VIN2A_D13/RGMII1_TXCTL/VOUT2_D1)
N1746820387: R178.2 U42.C2(VIN2A_D14/RGMII1_TXD3/VOUT2_D9/)
N1746820388: R554.2 U42.C3(VIN2A_D15/RGMII1_TXD2/VOUT2_D8/)
N1746820389: R177.2 U42.B2(VIN2A_D16/VIN2B_D7/RGMII1_TXD1/)
N1746820390: R558.2 U42.B5(VIN2A_D17/VIN2B_D6/RGMII1_TXD0/)

Pads without a net: EXP_P2 11 12 85; EXP_P3 40; J3 4; J8 35; J12 8 9; J13 10 11 14 18 20 22 24 26 28 30 32 34 36 38 40 42 44 46 48 50 52 54 55 56 59 60; J15 27 28 35 36; J17 4 5 6 14 15 17 18 19 20 30 31 33 35 41 42; J18 1 3 5 7 9 11 13 15 17 19 21 23 25 27 29 30 31 32 34 36; J19 6 8 10 12 14 16 53; J20 1 6 7 8 9 10; J21 1 6 7 8 9 10; NOREF#2 1; NOREF#4 1; NOREF#7 1; NOREF#8 1; NOREF#11 1; NOREF#14 1; NOREF#15 1; NOREF#17 1; NOREF#20 1; P5 4 5 7 8 12 13 14 15 18 20 21 22 23 26 27 28 29 30 31 32 36; P6 A7 A19 A25 A26 A29 A30 A32 B5 B6 B10 B11 B12 B23 B24 B27 B28 B30 B31; P7 14; P9 10 17 21 23 25 27 29 35 36 38 39 40 41 43 44 45 46 49 51 53 55 57 59 61 62 65 67 69 71 74 75 78 79 80 81 82 84 85 86 88 90 91 93 94 96 98 99 100; P12 4; P13 4; P14 11 12 13 14; P15 6 8 26 28 37 39; RN10 4; RU2 9 12; RU5 29 30 31 32 34 36; RU7 30 31 32 33 34 35 36 37 39 40 41 42 43; RU8 30 32 34 36 39 41 43 45 47 50 52 54; RU9 1 6 7 9 11 13 14; RU10 10 11 13 14; RU14 11 14; RU15 7 10 12 14 16 20 22 24 26 28; RU16 45; RU18 29 30 31 32 33 34; RU19 9 10 11 12 13 14; RU20 1; RU22 10 11 13 14; SW1 1 4; U3 3 5 6 7 8 9 10 12 13 18 21 22 23 25 27 28 29 31 32; U5 3; U6 3; U8 11 12 13 16; U9 3 5; U10 8 13 15 24 25 26 27 28 29 30 31 32; U11 8 9 14; U12 1 2 3 4 5 6 10 11 14 15 20 21 22 23 24 35 38; U13 1 4 11; U14 1 4 11; U15 A1 A2 A6 A7 A8 A9 A10 A11 A12 A13 A14 B1 B7 B8 B9 B10 B11 B12 B13 B14 C1 C3 C5 C7 C8 C9 C10 C11 C12 C13 C14 D1 D2 D3 D4 D12 D13 D14 E1 E2 E3 E5 E8 E9 E10 E12 E13 E14 F1 F2 F3 F10 F12 F13 F14 G1 G2 G3 G10 G12 G13 G14 H1 H2 H3 H5 H12 H13 H14 J1 J2 J3 J5 J12 J13 J14 K1 K2 K3 K6 K7 K10 K12 K13 K14 L1 L2 L3 L12 L13 L14 M1 M2 M3 M7 M8 M9 M10 M11 M12 M13 M14 MA4 MA6 MA9 MA11 MAE1 MAE14 MAG2 MAG13 MAH4 MAH6 MAH9 MAH11 MB2 MB13 MD1 MD14 N1 N3 N6 N7 N8 N9 N10 N11 N12 N13 N14 P1 P2 P7 P8 P9 P10 P11 P12 P13 P14; U17 1; U18 2 3 18 36 37; U19 14 15 16 17 19 20 21 22; U20 4 5 6 11 12 13; U23 1; U27 1; U39 4 6 10; U41 10; U42 A27 B28 F6; U43 16 17 21; U44 1; U45 4; U50 4 6 7 8 9 10 12 19 22 27 28 30 32 34 35; U56 3; U59 J1 J9 L1 L9; U60 J1 J9 L1 L9; U61 A3 A7 F1 F9 H1 H9; U62 A3 A7 F1 F9 H1 H9; U63 A3 A7 F1 F9 H1 H9; U65 3; U66 3; U67 3; U68 3; U69 3; U70 3; U71 3; U72 3; U73 3; U74 3; U75 3; U76 3; U77 3; U78 3; U79 3; U80 3; U81 3; U82 3; U83 3; U84 3; U85 3; U86 3; U87 3; U88 3; U89 3; U90 3; U91 3; U92 5; U93 3; U94 1; U95 1; U97 2; U98 2; U99 2; U100 2 3; U101 1 7 9 16 17 25 26 27 28 30 31 32 33 34 39 54 55 64; U102 3; U104 27 28 30; U108 1 7 9 16 17 25 26 27 28 30 31 32 33 34 39 54 55 64; U110 8 9 11; U113 3; U114 4; U115 4 5 8 10 11 12 16 33 34 35 36 37 38 39 47 48 53; U116 1; U117 3; U118 1; U121 1; U122 1; U124 6 7; U125 7; U128 1 3 4; U136 A3 A7 F1 F9 H1 H9; U137 A3 A7 F1 F9 H1 H9; U140 1; U141 16 17 19 20 28 29 31 32 43 44 46 47; U144 1; U145 1; U147 1; Y2 1; ZJ1 1; ZJ2 1; ZJ3 1; ZJ4 1

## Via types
v1: diameter 0.457, hole 0.203, TOP to BOTTOM, 3185 vias
v2: diameter 0.508, hole 0.254, TOP to BOTTOM, 2300 vias
v3: diameter 0.61, hole 0.305, TOP to BOTTOM, 54 vias
v4: diameter 0.635, hole 0.305, TOP to BOTTOM, 161 vias
v5: diameter 0.508, hole 0.305, TOP to BOTTOM, 16 vias

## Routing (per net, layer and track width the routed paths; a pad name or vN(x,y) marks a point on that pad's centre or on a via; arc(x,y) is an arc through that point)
1V8_DISP_SCL: length 66.4
  TOP w0.132: 35.05,58.04 35.05,57.53 v1(34.8,57.28) 34.68,57.16 U146.3
  L12-SIGNAL w0.089: v1(34.8,57.28) 34.29,56.77 33.78,56.77 33.02,57.53 33.02,61.56 26.29,68.3 26.29,113.79 25.65,114.43 v1(25.27,114.43)
  BOTTOM w0.132: R450.1 24.77,114.94 v1(25.27,114.43)
1V8_DISP_SDA: length 64.1
  TOP w0.132: 34.04,58.04 v1(34.04,57.28) 34.18,57.13 U146.4
  L12-SIGNAL w0.089: v1(34.04,57.28) 33.4,57.91 33.4,61.72 26.67,68.45 26.67,113.79 25.53,114.94 v1(25.53,115.19)
  BOTTOM w0.132: R449.1 v1(25.53,115.19)
1V8_I2C1_SCL: length 246.7
  TOP w0.132: RJ5.3 v1(152.4,146.43) ; v1(15.75,37.72) 16.76,37.72 16.9,37.85 U55.3 ; P9.31 12.6,44.96 v1(12.98,44.58)
  L3-SIGNAL w0.109: v1(15.75,37.72) 15.24,38.23 15.24,39.37 12.98,41.63 v1(12.98,44.58)
  L10-SIGNAL w0.089: v1(43.31,144.91) 42.93,144.53 42.93,142.24 40.77,140.08 40.77,134.49 39.75,133.48 39.75,116.97 38.04,115.25 28.77,115.25 26.42,112.9 v1(25.65,112.9)
  L12-SIGNAL w0.089: v1(25.65,112.9) 24.89,112.14 24.89,69.6 21.08,65.79 21.08,63.12 17.27,59.31 17.27,52.96 15.62,51.31 15.62,47.22 v1(12.98,44.58)
  L14-SIGNAL w0.109: v1(43.31,144.91) 43.94,145.54 56.26,145.54 57.04,144.76 57.44,144.76 57.46,144.78 67.94,144.78 68.2,144.53 79.25,144.53 80.64,145.92 104.39,145.92 105.66,147.19 118.49,147.19 120.52,149.22 123.19,149.22 124.84,150.88 139.32,150.88 139.83,150.37 141.99,150.37 142.49,150.88 144.53,150.88 146.81,148.59 148.21,148.59 150.37,146.43 v1(152.4,146.43)
  BOTTOM w0.132: v1(15.75,37.72) R646.2
1V8_I2C1_SDA: length 243.4
  TOP w0.132: P9.33 v1(12.98,45.59) ; v1(15.75,38.86) 16.4,38.86 U55.4 ; RJ3.3 v1(151.64,148.46)
  L3-SIGNAL w0.109: v1(15.75,38.86) 15.75,39.37 13.46,41.66 13.46,45.11 v1(12.98,45.59)
  L10-SIGNAL w0.089: v1(25.65,113.67) 26.54,113.67 28.7,115.82 37.59,115.82 38.99,117.22 38.99,139.06 42.55,142.62 v1(42.55,145.16)
  L12-SIGNAL w0.089: v1(25.65,113.67) 24.51,112.52 24.51,69.85 20.57,65.91 20.57,64.26 16.89,60.58 16.89,53.09 15.11,51.31 15.11,47.73 v1(12.98,45.59)
  L14-SIGNAL w0.109: v1(151.64,148.46) 149.86,148.46 148.59,149.73 146.69,149.73 145.12,151.3 124.63,151.3 123.06,149.73 120.14,149.73 118.73,148.32 104.5,148.32 103.63,147.45 97.66,147.45 96.65,146.43 77.6,146.43 77.09,145.92 68.33,145.92 67.56,145.16 58.93,145.16 57.77,146.32 57.17,146.32 56.78,145.92 43.31,145.92 v1(42.55,145.16)
  BOTTOM w0.132: v1(15.75,38.86) 16.38,39.5 R639.2
3V3_REF_CLK: length 6.1
  TOP w0.132: R569.1 12.19,22.98 11.99,22.78 U123.3 10.47,20.95 10.33,21.09 v1(9.92,21.09)
  BOTTOM w0.132: U124.12 v1(9.92,21.09)
3V3_SPI[1]_CS[0]N: length 14.1
  TOP w0.132: R572.1 12.45,26.67 v1(12.83,26.29)
  BOTTOM w0.132: RU21.2 15.27,18.01 14.61,18.67 14.61,24.51 v1(12.83,26.29) 12.42,26.29 12.41,26.29 U124.20
3V3_SPI[1]_MISO: length 13.6
  BOTTOM w0.132: U124.18 12.31,24.99 12.53,24.77 12.95,24.77 14.1,23.62 14.1,16.89 14.93,16.06 RU21.5
3V3_SPI[1]_MOSI: length 11.4
  BOTTOM w0.132: U124.16 9.6,23.69 8.13,22.23 8.13,17.91 8.76,17.27 9.4,17.27 9.48,17.36 RU21.14
3V3_SPI[1]_SCLK: length 14
  BOTTOM w0.132: RU21.11 9.36,15.41 7.75,17.02 7.75,22.61 9.48,24.34 U124.17
GND: length 4783.8
  TOP w0.076: 146.94,129.71 147.5,129.71
  TOP w0.127: U62.D9 U62.D8
  TOP w0.132: U50.42 175.38,47.8 v2(175.28,47.9)
  TOP w0.178: U15.P4 148.75,128.78 148.34,128.37 ; 149.75,128.61 U15.P6 U15.N5 ; v1(148.77,132.21) 149.02,132.46 U15.G5 ; v1(148.79,133.22) 148.79,133.53 149.12,133.86 149.12,134.08 U15.C4 ; U15.K8 v1(151,130.45) ; v1(151.18,132.33) U15.H10 ; U15.E7 v1(150.52,132.92) ; 147.5,129.71 U15.N2
  TOP w0.203: U62.J1 125.06,21.77 v1(124.66,21.37) ; v2(140.28,143.26) U12.36 ; v1(117.53,19.77) 117.12,20.17 U61.L9 ; v1(117.53,18.17) 117.12,18.57 U61.N9 ; RU7.49 89.33,102.6 89.35,102.62 v1(89.35,103.07) ; v2(119.25,122.48) R114.2 ; U62.D9 v1(131.87,26.17) U62.C9 ; U62.B2 125.87,27.38 v1(125.47,27.77) 125.07,27.37 U62.B1 ; 139.92,112.5 RU5.19 139.92,109.09 v1(140.42,108.58) ; v1(110.31,18.17) 110.71,18.57 U61.N1 ; U61.F2 111.11,24.57 v1(110.28,24.57) ; U62.F8 130.67,24.17 v1(131.07,24.57) ; U53.2 110.13,42.06 110.36,42.29 v1(111.38,42.29) ; U62.L9 131.48,20.17 v1(131.88,19.77) ; U61.J1 110.71,21.77 v1(110.31,21.37) ; U19.13 15.78,113.6 v2(15.79,113.61) ; v1(134.42,109.72) RU5.8 ; U62.A8 v1(131.07,27.77) ; U62.D1 v1(125.47,26.17) ; v1(124.67,28.57) U62.A1 ; RU7.19 94.83,91.75 v1(95.14,91.44) ; U61.D8 v1(115.92,26.17) ; v1(106.48,99.69) RU8.49 ; U62.F2 125.87,24.17 v1(125.47,24.57) ; v1(124.66,18.17) 125.06,18.57 U62.N1 ; U62.N9 131.48,18.57 v1(131.88,18.17) ; 139.92,117.12 RU5.38 139.92,120.53 v1(140.42,121.03) ; U61.B8 v1(116.72,26.97) ; U61.B1 110.72,27.37 v1(111.12,27.77) 111.52,27.38 U61.B2 ; U62.B8 v1(131.07,26.97) ; U61.F8 116.32,24.17 v1(116.72,24.57) ; v1(110.32,28.57) U61.A1 ; U62.J9 131.48,21.77 v1(131.88,21.37) ; U19.5 13.77,109.93 13.84,109.86 13.84,109.82 v2(13.84,109.35) ; v1(134.42,120.14) RU5.49 ; v1(94.83,102.74) RU7.38 ; v2(21.56,148.35) U10.22 ; v1(117.53,21.37) 117.12,21.77 U61.J9 ; RU4.8 v2(125.97,111.07) ; U61.D1 v1(111.12,26.17) ; U19.18 v2(13.77,113.71) ; U61.A8 v1(116.72,27.77) ; U61.C9 v1(117.52,26.17) U61.D9 ; RU4.15 v2(122.07,117.05) ; U61.L1 v1(111.12,20.57) ; U62.L1 v1(125.48,20.57) ; v1(86.33,103.24) RU7.55
  TOP w0.254: R193.2 v1(13.59,72.14) ; v2(120.4,122.43) 120.52,122.56 R115.2 ; U3.20 164.3,164.84 v2(164.08,164.63) ; v2(18.8,70.61) 18.01,70.61 U39.12 ; 35.69,54.99 v2(35.67,55.01) U146.1 ; R119.2 v2(125.6,122.48) ; U40.4 v2(134.88,60.32) ; v2(160.66,144.91) 160.04,144.29 U11.5 ; 137.54,57.28 U40.11 ; R128.2 v2(139.06,122.48) ; R116.2 121.79,122.56 v2(121.92,122.43) ; v2(116.46,146.05) 116.1,146.41 RU3.3 ; v2(17.77,62.53) U41.8 ; RU5.55 v1(131.42,116.84) ; 141.86,150.88 v2(141.1,150.88) ; 120.28,99.97 U27.3 120.82,100.61 ; R127.2 v2(137.79,122.48) ; U12.25 v2(140.28,137.76) ; U59.P1 v1(61.17,19.18) ; RU7.8 v1(89.33,95.63) ; U40.21 v1(140.33,62.11) ; v2(140.27,80.9) RU9.10 ; v1(129.16,114.81) 129.41,114.81 129.81,114.41 U17.3 ; 163.96,172.36 J3.5 164.52,173.81 ; C152.2 v2(96.77,75.18) ; C151.2 v2(96.77,76.45) ; R123.2 v2(132.72,122.43) ; P9.37 v2(12.98,46.86) ; U8.18 v2(152.39,159.76) ; C69.2 v2(148.08,142.37) ; U39.13 16.03,70.61 v2(15.24,70.61) ; U59.J2 v1(61.97,23.18) ; U55.1 17.92,38.56 v2(18.54,38.56) ; v2(126.75,122.43) 126.87,122.56 R120.2 ; U39.11 v2(19.71,69.81) ; C49.2 v2(116.46,150.62) ; U40.24 137.54,62.87 ; U59.B3 v1(63.57,29.58) ; v2(19.71,54.19) U43.11 ; U59.G8 v1(67.57,25.58) ; v2(16.27,62.53) U41.9 ; C67.2 v2(115.7,144.65) ; C66.2 v2(148.08,145.03) ; R124.2 v2(133.99,122.48) ; U8.15 v2(153.9,159.74) ; U3.4 v1(170.94,164.34) ; C45.2 v2(75.18,151) ; v2(116.33,123.19) 116.83,123.19 116.85,123.2 R113.2 ; v2(18.8,61.49) 18.8,60.83 U41.7 ; U12.48 v2(143.51,149.26) ; RU9.19 v2(135.19,83.57) ; R118.2 v2(124.33,122.48) ; U3.26 v2(166.26,161.18) ; U59.T1 v1(61.17,17.58) ; U60.G8 v1(80.27,25.58) ; R122.2 v2(131.44,122.48) ; U3.24 v2(164.11,162.84) ; v2(180.47,109.13) U18.23 ; U11.10 v2(160.04,150.86) ; U3.17 v1(164.21,166.34) ; U42.AH27 v1(81.16,46.36) ; U60.B3 v1(76.27,29.58) ; U59.M1 v1(61.17,20.78)
  TOP w0.279: U50.15 173.38,38.51 v2(172.85,37.97) ; U50.21 176.38,38.84 v2(176.15,38.61) 175.88,38.87 U50.20
  TOP w0.305: U42.P17 v1(93.38,53.96) U42.N18 U42.M19 U42.L20 v1(95.78,51.56) U42.K21 U42.J22 U42.H23 v1(98.18,49.16) ; C673.2 112.27,33.15 v1(112.39,33.27) ; P7.8 v2(6.96,101.5) ; U63.L9 v1(93.77,19.18) ; U42.M17 v1(94.98,53.96) U42.L18 v1(95.78,53.16) U42.K19 U42.J20 U42.H21 v1(98.18,50.76) U42.G22 v1(98.99,49.96) ; U42.R16 v1(91.78,54.76) U42.T17 ; U63.J9 v1(93.77,20.78) ; U42.AF9 v1(82.98,61.16) ; 152.27,25.4 v2(151.64,25.4) 151.13,25.91 ; v1(129.92,33.27) 130.05,33.15 C568.2 ; U60.A9 v1(81.07,30.38) ; R11.2 v2(14.1,164.21) ; 3.49,40.51 v2(4.98,40.51) ; v2(179.58,40.89) 179.42,41.06 U50.26 ; U42.AC12 v1(86.18,57.96) U42.AB13 ; v2(189.61,66.04) 189.59,66.07 U148.4 ; v2(42.79,27.92) 42.8,27.92 42.5,28.22 J15.16 ; v1(159,71.63) 159.41,71.23 U38.28 ; R17.2 v2(14.1,159.13) ; v1(87.78,62.76) U42.Y7 v1(88.58,61.96) U42.W8 v1(89.38,61.16) U42.V9 U42.U10 v1(90.98,59.56) U42.T11 v1(91.78,58.76) U42.R12 ; U42.J14 96.98,56.76 U42.K15 v1(96.58,55.56) ; U63.A1 86.97,27.58 v1(86.57,27.98) ; C243.1 176.4,57.15 v2(176.15,57.4) ; R125.2 R126.2 R127.2 ; v1(110.49,33.27) 110.36,33.15 C195.2 ; U42.AB11 v1(86.98,58.76) U42.AA12 v1(87.78,57.96) U42.Y13 v1(88.58,57.16) U42.W14 ; v1(86.57,25.58) 86.97,25.18 U63.D1 ; U42.U20 U42.V21 v1(89.38,50.76) U42.W22 v1(88.58,49.96) U42.Y23 ; U42.V23 v1(90.18,49.96) U42.U22 v1(90.98,50.76) U42.T21 ; U42.R8 v1(91.78,61.96) U42.T7 ; v2(98.35,90.68) 98.3,90.68 98.17,90.81 R164.1 ; v2(18.92,64.52) 18.85,64.59 U39.2 ; R25.2 v2(14.1,154.05) ; U59.B1 v1(61.17,29.58) ; U42.M7 v1(94.18,61.96) U42.N8 v1(93.38,61.16) U42.P9 ; U12.13 v2(123.88,143.26) ; v2(20.66,33.4) 20.66,33.36 20.53,33.23 U140.5 ; 11.49,58.29 v2(10.01,58.29) ; v1(2.16,34.92) 2.67,35.43 3.49,35.43 ; U52.2 v2(214.12,42.99) ; 11.49,65.91 10.13,65.91 v2(10.01,65.79) ; R143.1 v2(130.94,107.82) ; C14.2 v2(147.32,163.96) ; v1(94.98,49.16) U42.M23 U42.N22 ; U42.R22 v1(91.78,49.96) U42.T23 ; U42.T15 v1(90.98,55.56) U42.U16 v1(90.18,54.76) U42.V17 U42.W18 v1(88.58,53.16) U42.Y19 v1(87.78,52.36) U42.AA20 ; 3.49,58.29 v2(2.01,58.29) ; R266.2 122.21,49.78 v2(122.3,49.7) ; C687.2 v2(18.92,35.81) ; v2(168.02,153.92) 168,153.9 RU2.15 ; C194.2 v1(115.44,33.27) ; U60.D8 v1(80.27,27.98) ; 33.49,31.52 33.99,32.02 J15.33 ; 33.49,31.52 J15.34 ; 33.49,31.52 v2(33.48,31.52) ; U42.P11 v1(93.38,59.56) U42.N10 v1(94.18,60.36) U42.M9 ; R98.1 v3(213.11,139.06) ; J15.6 47.5,31.32 47.24,31.58 47.24,31.79 47,32.03 J15.7 ; U87.7 150.87,93.73 151.13,93.47 152.18,93.47 152.31,93.6 C229.1 v2(152.91,92.84) ; Y2.2 v2(15.52,33.02) ; U42.P13 v1(93.38,57.96) U42.N12 v1(94.18,58.76) U42.M11 U42.L10 v1(95.78,60.36) U42.K9 v1(96.58,61.16) U42.J8 v1(97.38,61.96) U42.H7 v1(98.18,62.76) ; v1(131.83,33.27) 131.95,33.15 C561.2 ; SW5.2 v2(213.23,134.21) ; C177.2 153.39,48.01 v2(153.8,47.6) ; U60.J2 v1(74.67,23.18) ; C429.2 v2(15.88,25.65) ; RU6.1 123.05,99.93 v2(122.94,99.82) ; U59.A9 v1(68.37,30.38) ; v1(9.91,38.48) 10.41,37.97 P9.9 ; U48.3 v2(204.49,43.2) ; U42.AE17 v1(83.78,53.96) ; U42.R18 v1(91.78,53.16) U42.T19 ; U60.F9 v1(81.07,26.38) ; v2(154.05,59.94) 153.8,60.2 153.29,60.2 ; RU10.8 v2(199.25,36.33) ; R121.2 R122.2 ; v1(81.18,56.9) 81.31,56.76 U42.AH14 ; U42.P19 v1(93.38,52.36) U42.N20 U42.M21 v1(94.98,50.76) U42.L22 U42.K23 v1(96.58,49.16) ; U42.H13 v1(98.18,57.96) U42.G12 ; U42.V7 v1(90.18,61.96) U42.U8 ; v2(148.34,127.51) 148.34,128.37 ; U42.P15 v1(93.38,55.56) U42.N16 ; v1(92.97,27.18) 92.57,26.78 U63.B8 ; v2(153.84,54.46) 153.44,54.86 C166.2 ; J15.29 36,33.82 35.37,34.44 v2(33.67,34.44) ; U38.41 162.95,67.45 v4(162.69,67.94) ; RU6.3 124.35,99.93 v2(124.46,99.82) ; C17.2 v2(153.54,163.7) ; v1(92.97,25.58) 92.57,25.18 U63.D8 ; U30.12 v2(199.14,62.84) ; v2(114.3,41.02) 114.41,41.13 U51.3 ; RU2.10 164.74,151.49 v2(165.06,151.17) 165.39,151.5 RU2.11 ; P7.5 v2(6.96,99.99) ; U42.AH1 v1(81.38,67.57) ; C615.2 117.35,33.15 v1(117.22,33.27) ; U60.G1 v1(73.87,25.58) ; U16.3 v2(211.34,127.27) ; R117.2 R118.2 ; U59.F9 v1(68.37,26.38) ; U21.12 v2(198.86,74.4) ; U18.9 174.61,113.68 v2(175.26,113.03) ; U60.P1 v1(73.87,19.18) ; C18.2 v2(155.07,163.7) ; R66.2 203.96,154.05 204.55,154.64 Q6.S ; v2(182.12,48.26) C178.2 ; U23.3 v2(70.21,104.04) ; 152.15,26.16 v2(151.64,26.16) 151.64,26.8 ; RU2.13 166.7,151.44 v2(167,151.13) 167.35,151.47 RU2.14 ; U60.E1 v1(73.87,27.18) ; Q3.S v3(6.22,150.32) ; R222.2 v2(19.56,54.99) ; v2(45.77,27.89) 45.5,28.15 J15.10 ; 156.34,94.74 156.84,94.74 v2(157.25,94.34) ; U42.AG10 v1(82.18,59.56) ; U63.B1 86.97,26.78 v1(86.57,27.18) ; U59.G1 v1(61.17,25.58) ; C365.2 147.83,82.55 v2(147.56,82.28) ; v1(93.77,26.38) 93.37,25.98 U63.C9 ; U42.N14 v1(94.18,57.16) U42.M13 v1(94.98,57.96) U42.L12 U42.K11 U42.J10 v1(97.38,60.36) U42.H9 U42.G8 v1(98.99,61.96) ; C250.1 v2(180.72,60.07) ; U14.2 213.14,148.46 213.11,148.42 v4(213.11,147.83) U14.15 ; R244.1 v1(20.19,47.75) ; U42.AG7 v1(82.18,61.96) ; U42.AB9 v1(86.98,60.36) U42.AA10 ; v2(4.95,30.61) 4.43,30.08 U56.6 ; RU1.3 55.26,161.18 v2(55.12,161.04) ; U42.B1 102.62,67.2 v1(102.62,67.82) ; U59.G9 v1(68.37,25.58) ; RU8.19 v2(111.98,95.63) ; 149.37,90.04 149.37,91.17 v2(149.22,91.31) ; U80.7 v2(141.74,13.72) ; C589.2 124.97,33.15 v1(125.09,33.27) ; U59.T9 v1(68.37,17.58) ; v2(9.91,50.04) P9.47 ; U63.F2 v1(87.37,23.18) ; U42.A28 v1(103.79,45.16) ; J15.13 44,36.15 43.3,36.86 v2(43.29,36.86) ; U42.L14 v1(95.78,57.16) U42.K13 ; v1(87.37,27.18) 87.77,26.78 U63.B2 ; U42.AA18 U42.Y17 U42.W16 v1(89.38,55.56) U42.V15 ; v2(60.33,161.04) 60.07,161.29 U5.2 ; U42.A2 v1(103.79,66.77) ; C32.2 v2(143.45,155.57) ; U42.P7 v1(93.38,62.76) ; U42.AC15 v1(85.38,55.56) ; U42.L8 v1(95.78,61.96) U42.K7 ; U42.AF18 v1(82.98,53.16) ; R65.1 v3(17.02,141.99) ; v2(173.1,80.26) 173.35,80.52 C242.1 ; v4(162.69,72.01) 162.95,72.26 U38.20 ; U42.AH5 v1(81.16,63.96) ; U42.AD10 v1(84.58,60.36) ; U59.D8 v1(67.57,27.98) ; P9.60 v2(2.01,53.85) ; U42.T13 v1(90.98,57.96) U42.U12 U42.V11 U42.W10 v1(88.58,60.36) U42.Y9 U42.AA8 ; U140.2 v2(19.23,28.65) ; P9.92 v2(4.98,67.18) ; U42.AG28 v1(82.18,45.16) ; C249.1 v2(181.99,63.75) ; U42.AE11 v1(83.78,59.56) ; U42.AH11 v1(81.16,59.16) ; R573.2 75.82,58.55 v2(75.95,58.67) ; R253.2 v2(40.89,40.89) ; U59.E2 v1(61.97,27.18) ; v1(92.97,27.98) 92.57,27.58 U63.A8 ; RU2.8 v2(164.09,159.88) ; U42.AD16 v1(84.58,54.76) ; U63.L1 v1(86.57,19.18) ; v2(159.62,59.49) 159.56,59.55 Q16.1 ; C688.2 v2(20.19,35.81) ; C11.2 v2(149.48,165.35) ; P7.11 v2(6.96,103) ; R13.1 v2(64.9,161.29) ; v2(55.12,164.21) 55.26,164.35 U4.3 ; U59.D1 v1(61.17,27.98) ; U81.7 146.3,93.61 146.43,93.47 147.1,93.47 147.49,93.09 C235.1 v2(148.08,92.33) ; U42.AH2 v1(81.38,66.77) ; U59.M9 v1(68.37,20.78) ; U42.AG4 v1(82.18,64.36) ; U60.B1 v1(73.87,29.58) ; U60.E8 v1(80.27,27.18) ; U42.AG16 v1(82.18,54.76) ; J13.57 144.38,39.23 v2(144.15,38.99) ; U42.AF15 v1(82.98,55.56) ; v2(111.76,102.74) 111.98,102.52 RU8.38 ; R217.2 v2(21.84,59.05) ; U63.F8 v1(92.17,23.98) ; P9.83 v2(10.01,64.64) ; P9.3 v1(13.08,36.07) ; P9.22 v2(2.01,41.78) ; v1(86.57,17.58) U63.N1 ; U59.B9 v1(68.37,29.58) ; U42.R10 v1(91.78,60.36) U42.T9 ; U60.M1 v1(73.87,20.78) ; P7.17 v2(6.96,106) ; U63.D9 93.37,25.18 v1(93.77,25.58) ; U47.3 v2(200.04,43.2) ; P9.77 v2(10.01,62.74) ; v2(179.2,76.33) 179.45,76.07 C241.1 ; v1(146.43,129.71) 146.94,129.71 ; P9.97 v2(9.19,69.09) ; U60.T9 v1(81.07,17.58) ; v2(179.2,72.52) 179.45,72.26 C245.1 ; v2(149.61,127.51) 149.61,128.47 149.75,128.61 ; R14.2 v2(14.1,160.4) ; U60.E2 v1(74.67,27.18) ; R270.2 v2(207.77,38.35) ; U59.E8 v1(67.57,27.18) ; U42.AH8 v1(81.17,61.56) ; U59.E1 v1(61.17,27.18) ; U43.13 v2(16.26,55.63) ; U59.J8 v1(66.77,23.98) ; v1(98.99,51.56) U42.G20 v1(98.18,52.36) U42.H19 v1(97.38,53.16) U42.J18 U42.K17 U42.L16 v1(94.98,55.56) U42.M15 ; C430.1 v2(12.57,25.4) ; U40.14 v2(140.2,58.03) ; R18.1 v2(64.9,157.48) ; U42.AF12 v1(82.98,58.76) ; v1(167.51,76.96) 167.39,76.83 R544.1 ; P9.95 v2(10.01,68.45) ; U42.AH28 v1(81.38,45.16) ; U60.G9 v1(81.07,25.58) ; 196.98,31.37 v2(195.45,31.37) ; U10.14 v2(24.39,152.68) ; v1(127,33.27) 126.87,33.15 C199.2 ; U60.P9 v1(81.07,19.18) ; U42.Y11 U42.W12 v1(89.38,57.96) U42.V13 v1(90.18,57.16) U42.U14 ; U42.J12 v1(96.58,58.76) ; U63.N9 v1(93.77,17.58) ; U7.3 55.26,158 v2(55.12,157.86) ; U42.Y15 v1(87.78,55.56) U42.AA16 v1(86.98,54.76) U42.AB17 ; U60.B9 v1(81.07,29.58) ; R576.2 75.75,57.66 v2(75.95,57.46) ; P9.6 v2(1.91,36.7) ; U42.U18 v1(90.18,53.16) U42.V19 U42.W20 v1(88.58,51.56) U42.Y21 U42.AA22 v1(86.98,49.96) ; C37.2 v2(188.59,156.08) ; U42.AD19 v1(84.58,52.36) ; P7.2 v2(6.96,98.49) ; U27.3 v2(120.28,101.46) ; U42.AG13 v1(82.18,57.16) ; RU8.8 v1(106.48,95.5) ; C3.2 v2(22.99,173.23) ; R68.1 v3(16.38,140.59) ; R22.2 v2(14.1,155.32) ; v1(86.57,20.78) U63.J1 ; R10.2 v2(14.1,165.48) ; R95.1 v3(211.71,139.7) ; U42.A1 v1(103.79,67.57) ; U46.3 v2(196.87,43.2) ; U6.2 v2(58.04,157.48) ; U42.G16 v1(98.18,55.56) U42.H15 ; U60.M9 v1(81.07,20.78) ; U43.12 v2(17.78,55.63) ; U1.1 v2(20.57,178.56) ; C246.1 v2(183.13,56.39) ; v1(98.99,53.16) U42.G18 U42.H17 ; P9.19 v2(10.01,41.15) ; v2(143.89,36.7) 144.38,36.21 J13.58 ; v2(131.57,38.86) 131.57,39.39 131.44,39.52 131.44,39.88 131.71,40.14 U79.7 ; P9.42 v2(2.01,48.13) ; C248.1 v2(181.99,67.44) ; Q5.S v3(207.95,157.23) ; U60.T1 v1(73.87,17.58) ; U42.AD13 v1(84.58,57.96) ; U59.P9 v1(68.37,19.18) ; U60.D1 v1(73.87,27.98) ; U42.AH17 v1(81.16,54.36) ; U44.3 v2(155.97,56.63) ; U42.AG1 v1(82.18,67.57) ; U60.J8 v1(79.47,23.98) ; J13.16 v2(154.88,36.45) ; U42.AE14 v1(83.78,57.16) ; R259.2 v2(40.89,43.31)
  TOP w0.356: v2(137.54,64.01) v1(137.54,63.26) 137.54,62.87 ; v2(137.54,56.13) v1(137.54,57.02) 137.54,57.28
  TOP w0.381: v2(52.67,152.53) J8.6 ; v2(54.67,152.53) J8.10 ; v2(97.87,80.49) 97.36,80.49 C145.2 97.36,79.48 v2(97.87,79.48) ; v2(113.03,73.71) 113.03,73.2 C155.2 114.05,73.2 v2(114.05,73.71) ; U54.3 v1(116.13,38.21) ; J8.25 v2(62.18,149.68) ; v2(107.39,80.49) 106.88,80.49 C141.2 106.88,81.51 v2(107.39,81.51) ; v2(77.27,72.75) 77.77,72.75 C147.2 77.77,73.76 v2(77.27,73.76) ; Y1.4 19.05,148.97 v2(20.07,148.97) ; v2(53.67,152.53) J8.8 ; J8.26 v2(62.68,152.53) ; P8.8 6.02,78.44 v2(6.1,78.36) ; v1(111.89,91.22) C138.2 ; v2(67.11,52.17) 67.61,52.17 C172.2 67.61,51.16 v2(67.11,51.16) ; C137.2 95.38,91.19 95.14,91.42 v1(95.14,91.44) ; R48.2 v2(20.07,146.81) ; v2(97.87,78.46) 97.36,78.46 C149.2 97.36,77.44 v2(97.87,77.44)
  TOP w0.406: v2(90.61,79.95) C374.2 v2(90.61,77.28) ; v2(104.84,79.41) C372.2 v2(104.84,76.75) ; v2(112.84,61.91) C428.2 v2(115.51,61.91) ; v2(107,79.41) C373.2 v2(107,76.75) ; v2(112.84,56.71) C455.2 v2(115.51,56.71) ; v2(108.01,70.17) C411.2 v2(110.68,70.17) ; v2(114.11,52.77) C484.2 v2(116.78,52.77) ; v2(104.84,73.06) C383.2 v2(104.84,75.73) ; P8.5 v2(6.1,83.84) ; v2(110.68,52.77) C485.2 v2(113.35,52.77) ; v2(112.08,50.1) C505.2 v2(109.41,50.1) ; v2(90.61,76.39) C382.2 v2(90.61,73.72) ; v2(109.41,56.71) C456.2 v2(112.08,56.71) ; v2(107,73.06) C384.2 v2(107,75.73)
  TOP w0.508: P3.D4 89.61,178.05 ; P3.D4 88.59,177.04 ; P3.D4 90.63,177.04 ; 131.46,85.72 C139.2 ; C139.2 132.08,86.35 ; C139.2 v2(132.08,84.96) ; P2.5 82.75,172.13 ; P2.5 80.41,169.79 ; P2.5 78.08,172.13 ; P2.5 80.41,174.47 ; 124.32,106.53 U145.3 ; U145.3 123.78,107.16 ; U145.3 124.32,107.8 ; v2(11.94,81.48) 11.94,81.47 U33.2 ; 4.7,18.74 J1.2 ; J1.2 4.7,20.88 ; J1.2 3.63,19.81 ; J1.2 5.77,19.81 ; 180.72,61.46 C250.1 181.34,60.83 ; 200.28,125.37 U147.2 200.28,126.64 ; C373.2 107.53,78.08 ; Q4.S v2(196.42,159.44) ; Q4.S 198.2,159.44 ; Q4.S 197.54,158.57 ; Q4.S 197.54,160.3 ; TP91.1 19,88.11 ; TP91.1 20.07,87.04 ; TP91.1 19,85.98 ; TP91.1 17.93,87.04 ; 14.86,32.03 Y2.2 ; Y2.2 15.52,31.28 ; Y2.2 16.18,32.03 ; 7.1,142.02 U13.2 4.54,142.02 v2(4.45,142.11) ; 16.73,61.59 U41.9 15.81,61.59 ; 147.19,142.99 C69.2 147.19,141.74 ; v2(62.1,15.6) 62.1,14.83 ; 62.1,14.83 v2(62.1,14.07) ; 62.1,14.83 61.48,14.83 ; 156.34,95.36 156.34,94.12 ; 6.17,109.98 P7.MTG1 ; P7.MTG1 8.82,109.98 ; P7.MTG1 7.5,108.66 ; P7.MTG1 7.5,111.3 ; v2(145.16,26.67) 145.16,27.18 ; 120.03,46.35 R267.1 ; R267.1 120.65,46.98 ; R267.1 120.65,45.73 ; R267.1 v2(119.89,46.61) ; 97.16,152.9 C39.2 96.39,152.27 v4(95.76,151.64) 96.39,151 R33.1 97.16,150.38 ; v2(73.03,73.41) E5.2 70.19,73.41 ; 174.87,147.7 C60.2 v2(173.99,148.72) ; R254.2 v1(165.48,45.97) ; P3.11 105.46,169.42 ; P3.11 102.82,169.42 ; P3.11 104.14,168.1 ; P3.11 104.14,170.74 ; 5.13,149.66 Q3.S ; Q3.S 4.27,150.32 ; Q3.S 5.13,150.98 ; 39.73,136.88 P6.B16 v2(39.73,134.21) ; 51.56,48.91 C164.2 v2(52.45,49.78) ; C220.2 77.09,13.92 v2(77.05,13.88) ; C220.2 76.34,14.83 ; C220.2 77.09,15.77 v2(77.05,15.8) ; 44.91,97.66 J12.4 ; J12.4 45.97,98.5 ; J12.4 47.04,97.66 ; J12.4 45.97,96.82 ; 158.84,59.04 Q16.1 158.22,59.55 ; J11.G2 10.33,128.21 ; J11.G2 11.98,126.56 ; J11.G2 10.33,124.9 ; 14.14,104.16 U24.2 v2(13.21,104.01) ; 168.53,49.91 v1(167.77,49.91) ; 168.53,49.91 168.53,49.29 ; 168.53,49.91 169.15,49.91 ; P11.4 167.81,25.95 v1(168.28,26.42) ; P11.4 166.12,27.5 ; P11.4 v1(166.12,23.11) ; P11.4 164.3,25.95 v1(163.83,26.42) ; C173.2 115.07,49.68 v2(115.46,50.08) ; C173.2 114.17,48.93 ; C173.2 113.28,49.68 v2(112.88,50.08) ; 79.36,156.97 R20.2 v2(78.49,158.12) ; R13.1 64.01,161.91 ; 49.67,110.74 C709.2 ; C709.2 51.42,110.74 ; C709.2 50.55,109.99 ; v4(91.95,147.83) 92.33,147.45 C64.2 92.95,146.43 ; 23.11,159.84 TP12.1 ; TP12.1 23.11,161.98 ; TP12.1 22.05,160.91 ; TP12.1 24.18,160.91 ; v2(18.03,151.76) C41.2 19.05,152.64 ; 4.7,12.71 TP83.1 ; TP83.1 v2(4.7,17.4) ; TP83.1 6.15,14.99 ; TP83.1 3.25,14.99 ; v2(97.35,34.37) 96.82,34.89 C197.2 96.82,36.43 v2(97.35,36.95) ; C121.2 v2(29.34,104.58) ; C121.2 28.71,103.89 ; C121.2 29.34,103.26 ; v4(95.76,149.73) 96.01,149.48 C50.2 ; 183.13,57.77 C246.1 183.76,57.15 ; v2(155.45,114.05) 153.75,114.05 C117.2 ; C184.2 181.85,41.27 ; C184.2 181.23,41.9 ; C184.2 C183.2 ; C184.2 v2(181.84,41.88) 181.94,41.78 C185.2 ; E2.2 v2(76.05,73.41) ; v2(174.5,50.93) C176.2 173.88,50.16 ; 133.37,159.75 C22.2 ; C22.2 v2(133.86,160.27) ; C22.2 133.37,158.77 ; 211.09,140.59 R95.1 ; C185.2 v2(184.53,41.78) ; C185.2 183.13,40.97 ; 172.59,51.64 C171.2 ; C171.2 171.4,52.45 ; C171.2 v1(173.99,52.45) ; 117.6,48.93 C174.2 ; C174.2 118.5,49.68 v2(118.89,50.08) ; C174.2 116.71,49.68 v2(116.31,50.08) ; 144.4,154.7 C32.2 ; 155.87,168.05 P1.SH3 ; P1.SH3 154.46,169.46 ; P1.SH3 157.28,169.46 ; P1.SH3 155.87,170.87 ; 145.46,178.46 P1.SH1 ; P1.SH1 146.87,177.05 ; P1.SH1 148.28,178.46 ; J3.6 170.56,174.02 ; J3.6 170.05,171.96 C4.2 v2(170.94,170.31) ; J3.6 172.34,172.47 ; 52.73,136.88 P6.B29 v2(52.73,134.21) ; RU2.10 164.74,153.66 ; J15.33 33.99,34 ; 141.49,37.72 J13.64 ; J13.64 143.07,38.24 ; J13.64 v2(144.91,37.72) 147.96,37.72 ; J13.64 143.07,37.2 ; 97.68,136.53 C75.2 ; C75.2 v4(98.3,135.13) ; C75.2 98.92,136.53 ; Q18.4 200.29,133.06 ; Q18.4 199.79,133.68 ; Q18.4 199.79,132.44 ; 3.88,83.84 P8.5 4.86,83.33 ; 217.55,40.08 J14.3 ; J14.3 218.62,41.15 ; J14.3 216.48,41.15 ; J14.3 217.55,42.22 ; SW9.2 v2(198.12,51.56) ; SW9.2 199.06,50.19 ; SW9.2 198.12,49 ; SW9.2 197.18,50.19 ; 74.42,41.46 E12.2 v2(74.42,44.41) ; C57.2 170.99,148.16 ; C57.2 v2(169.93,149.22) ; C57.2 168.86,148.16 ; C70.2 v2(82.55,142.49) ; C70.2 83.17,141.73 ; C70.2 82.55,141.11 ; v2(26.8,120.65) 27.18,120.27 C112.2 26.56,119.38 ; 20.07,125.23 C95.2 ; C95.2 v2(18.54,125.86) ; C95.2 20.07,126.48 ; TP99.1 107.06,125.59 ; TP99.1 107.06,121.04 ; TP99.1 105.61,123.32 ; TP99.1 108.51,123.32 ; v2(106.48,112.6) 105.66,113.41 U20.10 102.76,113.41 ; P6.A12 v2(35.73,144.17) ; P6.A12 35.73,141.5 ; P6.A12 35.07,142.8 ; 147.96,37.72 v2(151.13,37.72) J13.62 ; 147.96,37.72 147.96,37.2 ; C21.2 158.55,160.66 ; C21.2 156.92,160.66 ; C21.2 157.23,161.16 v2(156.79,161.16) ; C21.2 157.73,159.46 ; C21.2 157.73,161.85 ; C21.2 157.23,160.15 v2(156.79,160.15) ; 31.5,123.56 C101.2 v2(30.23,122.94) ; 205.82,15.11 J20.2 ; J20.2 206.88,14.05 ; J20.2 206.88,16.18 ; C117.2 153.75,116.33 v2(155.45,116.33) ; C117.2 v2(155.45,115.19) ; 207.95,155.27 Q5.S ; Q5.S 207.29,156.13 ; Q5.S 208.61,156.13 ; v4(88.14,153.54) 87.25,152.65 C38.2 86.74,153.28 ; 148.41,164.41 C11.2 150.55,164.41 ; R49.2 87.5,147.19 v4(88.14,147.83) 87.76,148.21 R41.1 ; R49.2 86.88,146.43 ; R49.2 88.13,146.43 ; C25.2 v4(93.85,155.45) ; C25.2 93.23,156.84 ; C25.2 94.48,156.84 ; 106.38,82.07 C141.2 107.13,81 ; J11.G3 11.98,119.06 ; J11.G3 10.33,117.4 ; J11.G3 10.33,120.71 ; C107.2 25.01,120.4 ; 1.4,142.11 2.41,142.11 ; 2.41,142.11 2.41,143.13 ; 2.41,142.11 2.41,141.1 ; 27.56,125.87 C91.2 26.94,126.49 ; J11.G4 2.63,120.71 ; J11.G4 2.63,117.4 ; J11.G4 0.97,119.06 ; P4.D4 111.71,177.04 ; P4.D4 109.68,177.04 ; P4.D4 110.69,178.05 ; C23.2 90.03,156.84 ; C23.2 88.79,156.84 ; C23.2 89.41,156.08 v4(90.04,155.45) ; 37.21,17.35 J16.1 ; J16.1 35.64,18.92 ; J16.1 37.21,20.5 ; J16.1 38.79,18.92 ; R1.2 36.84,160.91 ; R1.2 35.55,160.91 ; R1.2 v2(36.2,160.02) ; Y1.2 17.78,147.88 ; Y1.2 17.78,146.38 ; Y1.2 17.59,147.32 v2(16.89,147.32) ; Y1.2 17.07,147.13 ; RU25.3 164.58,52.68 ; RU25.3 164.58,51.41 ; RU25.3 164.04,52.04 ; v2(157.61,107.19) 157.61,105.49 C127.2 ; J9.3 217.68,160.02 ; J9.3 217.68,157.99 ; J9.3 218.69,159 ; J9.3 216.66,159 ; J15.6 47.5,28.32 47,27.81 v2(46.99,27.81) ; C118.2 34.53,101.47 ; C118.2 33.27,101.85 v4(31.75,101.85) ; C118.2 33.66,102.22 ; 17.02,71.02 v2(17.02,67.56) 17.02,64.11 ; C148.2 155.98,77.5 156.47,77.98 v1(157.35,77.98) ; C148.2 v1(157.35,76.96) ; C148.2 155.98,76.43 156.46,75.95 v1(157.35,75.95) ; 5.7,155.64 6.22,155.64 ; 6.22,155.64 6.74,155.64 ; 6.22,155.64 v2(6.22,153.8) ; 6.22,155.64 v2(6.22,157.48) P5.42 ; C126.2 152.53,105.49 v2(152.53,107.19) ; C126.2 154.81,105.49 v2(154.81,107.19) ; C126.2 v2(153.67,107.19) ; 45.97,100.63 J12.7 ; J12.7 47.04,101.47 ; J12.7 44.91,101.47 ; J12.7 45.97,102.31 ; U17.3 130.34,113.82 ; U48.3 205.02,43.97 ; v2(21.08,156.72) C34.2 20.21,155.57 ; C710.2 v2(167.13,52.32) ; C710.2 167.75,51.56 ; C710.2 166.51,51.56 ; 179.96,71.64 C245.1 ; v2(49.73,134.21) P6.B26 49.73,136.88 ; J13.61 159.19,38.24 ; J13.61 v2(157.23,37.72) J13.62 ; J13.61 159.19,37.2 ; J13.61 160.77,37.72 ; 28.73,136.88 P6.B7 v2(28.73,134.21) ; 205.1,169.18 R21.1 ; R21.1 205.1,170.93 ; R21.1 v2(206.5,170.05) ; v2(206.63,84.2) 206.52,84.31 RU11.3 207.05,84.99 ; 213.07,175.74 DS1.1 ; DS1.1 215.18,175.74 ; DS1.1 214.12,174.69 ; DS1.1 v2(214.12,177.16) ; P7.MTG3 3.92,110.59 ; P7.MTG3 2.6,111.91 ; P7.MTG3 2.6,109.27 ; P7.MTG3 1.27,110.59 ; 152.91,48.63 C177.2 152.91,47.38 ; P7.MTG4 3.92,94.89 ; P7.MTG4 2.6,96.22 ; P7.MTG4 1.27,94.89 ; P7.MTG4 2.6,93.57 ; 83.96,164.47 C8.2 ; C8.2 84.84,163.72 ; C8.2 v2(85.85,164.47) ; 38.21,167.64 C1.2 v2(37.59,168.66) ; C56.2 80.25,147.96 ; C56.2 79.63,148.58 ; C56.2 v2(79.63,147.19) ; 109.73,168.1 P4.12 ; P4.12 108.41,169.42 ; P4.12 109.73,170.74 ; P4.12 111.05,169.42 ; J9.1 217.68,154.94 ; J9.1 218.69,153.92 ; J9.1 217.68,152.91 ; J9.1 216.66,153.92 ; 179.96,75.45 C241.1 ; 207.39,49.12 SW8.2 ; SW8.2 v2(207.39,51.69) ; SW8.2 206.45,50.32 ; SW8.2 208.33,50.32 ; v2(51.56,121.28) 51.56,124.26 ; v2(51.56,121.28) 54.53,121.28 ; v2(51.56,121.28) 48.59,121.28 ; v2(51.56,121.28) 51.56,118.31 ; P4.1 124.21,163.58 ; P4.1 122.17,163.58 ; P4.1 123.19,164.59 ; P4.1 123.19,162.56 ; 20.57,175.78 U1.1 21.2,177.04 ; 197.49,73.92 U21.12 196.29,74.4 ; 4.8,58.29 3.49,58.29 3.49,57.79 ; P9.9 12.8,37.97 ; 86.74,151.02 C42.2 v4(88.14,151.64) ; 81.53,159.27 R15.2 81.28,160.15 80.77,160.66 v2(79.38,160.66) ; 194.55,133.35 C81.1 v2(193.8,134.49) ; 177.67,34.94 C190.2 ; C190.2 v2(176.91,35.56) ; C190.2 178.3,35.56 ; 200.74,20.83 J21.5 ; J21.5 201.8,21.9 ; J21.5 201.8,19.76 ; J21.5 202.87,20.83 ; J15.7 47,34 ; 190.23,62.65 Q19.4 ; Q19.4 190.74,63.27 ; Q19.4 190.74,62.03 ; 25.73,136.88 P6.B4 v2(25.73,134.21) ; C58.2 177.34,148.16 ; C58.2 v2(176.28,149.1) ; C58.2 175.21,148.16 ; C143.2 166.98,78.33 166.5,77.85 v1(166.5,76.96) ; C143.2 v1(167.51,76.96) ; C143.2 168.05,78.33 168.53,77.85 v1(168.53,76.97) ; 152.67,162.81 C17.2 ; C690.2 v2(53.09,130.56) ; C690.2 51.45,130.56 ; C690.2 52.07,131.18 ; C128.1 168.28,103.11 ; C128.1 v2(169.16,102.23) ; C128.1 168.28,101.36 ; C12.2 85.08,162.56 ; C12.2 84.45,162.09 v2(84.18,161.81) ; C12.2 84.45,163.18 ; 88.65,168.1 P3.12 ; P3.12 87.32,169.42 ; P3.12 89.97,169.42 ; P3.12 88.65,170.74 ; C403.1 186.94,63.61 ; C403.1 186.19,62.74 ; C403.1 186.94,61.86 ; 90.44,121.92 C104.2 v2(91.06,121.16) ; 73.67,14.83 C219.2 ; C219.2 v2(74.3,14.07) ; C219.2 v2(74.3,15.6) ; P5.44 v2(6.22,173.48) ; P5.44 6.74,171.77 ; P5.44 5.7,171.77 ; P5.44 v2(6.22,169.8) P5.43 ; P2.6 69.61,172.13 ; P2.6 64.93,172.13 ; P2.6 67.27,169.79 ; P2.6 67.27,174.47 ; C537.2 v2(100.2,39.27) ; C137.2 96,90.55 ; v2(64.99,15.8) 65.02,15.77 C218.2 ; v2(157.31,25.95) P10.4 ; P10.4 155.32,24.51 v2(155.7,24.13) ; P10.4 155.32,27.5 ; P10.4 153.56,25.95 ; C155.2 114.61,72.69 ; C155.2 113.54,73.44 ; C155.2 112.47,72.69 ; C160.2 v1(170.43,64.01) ; C160.2 170.97,62.64 171.45,63.12 v1(171.45,64.01) ; C160.2 169.9,62.64 169.41,63.12 v1(169.41,64) ; C160.2 170.43,61.44 ; 50.73,141.5 P6.A27 v2(50.73,144.17) ; R217.2 21.08,59.68 ; 68.12,50.6 C172.2 ; C172.2 68.12,52.73 ; C172.2 67.37,51.66 ; C99.2 25.01,124.59 ; 45.73,134.29 P6.B22 v2(45.73,137.16) ; P9.95 12.8,68.45 ; SW8.1 v2(208.56,55.85) ; SW8.1 207.39,57.05 ; SW8.1 206.45,55.85 ; SW8.1 207.39,54.66 ; v2(12.21,78.69) U34.2 11.07,79.17 ; R251.2 v1(165.48,47.12) ; C122.2 141.08,107.7 ; C122.2 140.46,108.32 ; C122.2 v2(140.46,106.93) ; P6.B32 v2(55.73,134.21) ; P6.B32 55.73,136.88 ; P6.B32 56.4,135.59 ; v2(25.73,144.17) P6.A4 25.73,141.5 ; R2.2 137.27,172.21 ; R2.2 v2(136.65,171.45) ; R2.2 136.03,172.21 ; 116.08,46.19 E10.2 v2(116.08,48.9) ; C150.2 112.38,71.5 ; C150.2 v2(111.76,72.26) ; C150.2 111.14,71.5 ; J3.8 171.87,177.98 ; J3.8 v2(168.96,177.98) ; J3.8 v2(170.56,176.12) ; v2(15.11,99.38) U28.2 ; U28.2 16.05,100.31 ; U28.2 15.22,100.35 ; 2.41,136.02 J10.1 ; J10.1 2.41,138.05 ; J10.1 1.4,137.03 ; J10.1 3.43,137.03 ; 90.55,137.91 C73.2 v2(89.66,137.29) ; v2(161.8,163.7) C9.2 161.18,164.47 ; Q10.2 v2(179.71,131.01) ; 88.87,14.4 C223.2 ; C223.2 89.62,13.48 v2(89.59,13.44) ; C223.2 89.62,15.33 v2(89.59,15.37) ; 168,151.27 RU2.15 ; J13.62 154.31,37.2 ; J13.62 154.31,38.24 ; J9.2 218.69,156.46 ; J9.2 217.68,155.45 ; J9.2 216.66,156.46 ; J9.2 217.68,157.48 ; C71.2 83.17,138.68 ; C71.2 v2(82.55,139.45) ; C71.2 82.55,138.06 ; 17.51,20.95 U123.2 16.21,22.24 v2(15.84,22.61) ; C54.2 v2(103.25,148.08) ; U32.2 v2(13.27,94.87) ; U32.2 13.32,93.96 ; U32.2 14.14,94 ; v2(154.94,142.24) R63.1 154.32,143.26 ; v2(48.73,134.21) P6.B25 48.73,136.88 ; v2(155.45,111.25) 153.75,111.25 C119.2 ; v2(194.18,12.61) 192.15,12.61 ; 192.15,12.61 v2(192.15,14.61) ; 192.15,12.61 192.15,10.86 ; 192.15,12.61 v2(190.12,12.61) ; v2(103.63,149.48) C51.2 102.74,150.36 ; 16.64,26.28 C429.2 16.64,25.03 ; 131.57,37.48 C237.1 ; C237.1 v2(131.57,38.86) ; C237.1 130.95,38.1 ; 103.5,128.54 103.5,129.16 ; 103.5,129.16 102.36,129.16 v4(102.11,129.41) ; 103.5,129.16 103.5,129.78 ; v2(159.77,14.48) P10.1 ; P10.1 v2(157.73,12.61) ; P10.1 159.77,10.86 ; P10.1 v2(161.8,12.61) ; v2(214.88,164.72) 214.25,165.35 TP1.1 ; v2(168.02,149.99) v2(166.88,149.99) ; v2(166.88,149.99) C62.2 ; v2(166.88,149.99) v2(165.61,149.99) ; 30.87,121.92 C105.2 31.5,121.3 ; 86.74,149.85 R38.2 87.63,149.22 v4(88.14,149.73) ; 86.74,146.57 R44.1 87.36,147.19 ; 123.05,101.24 RU6.1 122.51,100.61 ; 33.49,28.99 J15.34 ; 213.44,128.68 SW5.1 ; SW5.1 v2(214.38,130.18) ; SW5.1 215.32,128.68 ; SW5.1 214.38,127.48 ; C26.2 130.43,157.34 ; C26.2 131.05,156.72 ; C26.2 130.43,156.1 ; C26.2 130.68,156.46 v2(130.68,154.94) ; 168.02,104.14 168.02,104.76 ; 168.02,104.14 168.02,103.52 ; 168.02,104.14 168.28,104.14 v2(169.04,104.9) ; C50.2 97.16,148.86 ; C50.2 97.16,150.1 ; U36.2 11.86,75.2 ; U36.2 11.03,75.16 ; U36.2 11.07,75.99 ; U36.2 11.48,75.6 v2(11.96,75.11) ; 192.04,63.98 Q19.1 ; Q19.1 192.55,64.6 ; Q19.1 192.04,65.23 ; 198.12,54.53 SW9.1 ; SW9.1 197.18,55.73 ; SW9.1 v2(199.29,55.73) ; SW7.2 v2(171.58,98.3) ; SW7.2 172.52,99.67 ; SW7.2 171.58,100.86 ; SW7.2 170.64,99.67 ; 171.58,92.94 SW7.1 ; SW7.1 172.52,94.13 ; SW7.1 170.64,94.13 ; SW7.1 v2(171.58,95.5) ; v2(47.73,144.17) P6.A24 47.73,141.5 ; C491.2 v2(109.6,53.09) ; P7.MTG2 7.5,96.83 ; P7.MTG2 8.82,95.5 ; P7.MTG2 7.5,94.18 ; P7.MTG2 6.17,95.5 ; 45.97,93.01 J12.1 ; J12.1 45.97,94.69 ; J12.1 44.91,93.85 ; J12.1 47.04,93.85 ; 76.2,150.13 C45.2 ; 103.5,130.06 103.5,130.68 102.74,130.68 v4(102.11,131.32) 102.74,131.95 103.5,131.95 103.5,132.58 ; TP1.1 v2(214.25,169.8) ; TP1.1 215.7,167.13 ; TP1.1 212.8,167.13 ; C129.1 177.55,101.21 ; C129.1 177.55,99.45 ; C129.1 v2(176.53,100.33) ; C158.2 v1(157.35,63.5) ; C158.2 155.98,64.03 156.47,64.52 v1(157.35,64.52) ; C158.2 155.98,62.97 156.46,62.48 v1(157.35,62.48) ; 94.88,73.15 C396.2 ; C396.2 96.13,73.15 ; C396.2 v2(95.5,73.91) ; v2(18.03,165.35) R8.2 17.39,166.12 ; 30.61,125.74 30.61,126.36 ; 30.61,126.36 29.98,126.36 ; 30.61,126.36 31.11,126.36 C94.2 ; R18.1 64.01,158.1 ; C24.2 92.57,156.84 ; C24.2 91.33,156.84 ; C24.2 v4(91.95,155.45) ; 24.38,118.5 C111.2 25.01,119.13 ; 78.37,143 R53.2 v2(79.25,142.11) ; 96.85,81.05 C145.2 97.6,79.98 ; v2(112.88,59.22) 113.28,58.83 C163.2 115.07,58.83 v2(115.46,59.22) ; U33.2 11.07,80.6 ; U33.2 11.03,81.43 ; v1(184.78,51.07) U45.2 184.78,49.42 ; 157.51,56.63 U44.3 156.87,56.09 ; 197.4,43.97 U46.3 196.87,44.6 ; 211.34,128.68 U16.3 211.88,128.04 ; v2(171.96,106.43) 171.45,106.93 U18.19 172.64,107.18 ; v2(183.39,12.61) P12.1 ; P12.1 v2(181.36,14.61) ; P12.1 v2(179.32,12.61) ; P12.1 181.36,10.86 ; 78.28,72.19 C147.2 ; C147.2 77.53,73.25 ; C147.2 78.28,74.32 ; v1(49.15,52.83) C165.2 50.04,53.71 ; 20.07,145.3 R48.2 ; 163.61,158.44 RU2.8 ; R277.1 v2(143.19,28.7) ; R155.1 177.8,102.86 ; R155.1 v2(177.04,102.23) ; R155.1 177.8,101.61 ; 38.73,141.5 P6.A15 v2(38.73,144.17) ; 177.88,109.13 U18.23 ; 17.02,58.01 U41.17 17.02,61.11 ; 41.25,36.81 41,36.56 J15.19 ; 41.25,36.81 v2(41.26,36.96) ; 41.25,36.81 41.25,36.82 ; 189.69,37.47 TP85.1 ; TP85.1 190.75,36.4 ; TP85.1 190.75,38.53 ; TP85.1 191.82,37.47 ; 82.55,143.9 C68.2 ; C68.2 83.17,144.53 ; C68.2 v2(82.55,145.29) ; v2(40.03,27.86) 39.59,28.31 39.59,28.77 39.5,28.85 J15.22 ; C5.2 24.38,167.25 ; C5.2 v2(25.15,166.62) ; C5.2 24.38,166 ; C372.2 105.37,78.08 ; 54.73,141.5 P6.A31 v2(54.73,144.17) ; C35.2 v2(204.34,161.54) ; C35.2 204.34,159.65 ; C35.2 203.59,160.53 ; 93.85,126.11 93.85,126.87 v4(94.49,127.51) ; 93.85,126.11 93.23,126.11 ; 93.85,126.11 94.48,126.11 ; U2.1 v2(25.4,164.72) ; U2.1 28.31,164.72 ; U2.1 27.05,165.34 ; TP84.1 197.74,16.37 ; TP84.1 199.19,14.1 ; TP84.1 v2(197.74,11.68) ; TP84.1 196.29,14.1 ; 18.94,55.75 R222.2 ; 95.12,126.11 95.12,126.87 v4(94.49,127.51) ; 116.74,147.05 RU3.3 115.47,147.05 ; C7.2 159.51,165.86 v2(159.94,165.86) ; C7.2 158.19,165.35 ; C7.2 159.82,165.35 ; C7.2 159,166.55 ; C7.2 159,164.16 ; C7.2 159.51,164.85 v2(159.94,164.85) ; C127.2 v2(158.75,107.19) ; C127.2 159.89,105.49 v2(159.89,107.19) ; 102.73,40.01 C186.2 v2(102.11,39.27) ; 145.46,169.46 P1.SH2 ; P1.SH2 146.87,168.05 ; P1.SH2 148.28,169.46 ; P1.SH2 146.87,170.87 ; C27.2 135.62,156.72 ; C27.2 135,157.34 ; C27.2 135,155.45 v2(135.51,154.94) ; C499.2 v2(109.6,51.94) ; 203.89,155.52 Q6.S ; Q6.S 205.21,155.52 ; Q6.S v2(204.55,156.67) ; 12.8,58.29 11.49,58.29 11.49,57.79 ; C689.2 v2(54.86,130.56) ; C689.2 56.5,130.56 ; C689.2 55.88,131.18 ; 119.76,38.87 C188.2 ; C188.2 119.76,40.12 ; C188.2 v2(120.52,39.5) ; C411.2 109.35,70.7 ; J21.2 197.79,23.37 ; J21.2 196.72,22.3 ; J21.2 196.72,24.44 ; J21.2 195.66,23.37 ; 181.99,65.14 C249.1 182.61,64.52 ; v4(94.49,127.51) 94.11,127.89 R106.1 ; v2(46.73,144.17) P6.A23 46.73,141.5 ; U29.2 16.05,97.04 ; U29.2 v2(15.14,97.89) ; U29.2 15.26,97.84 ; U29.2 15.22,97.01 ; C79.2 v2(89.41,135.89) ; v4(96.39,135.13) 95.76,135.76 C74.2 ; C89.2 v2(22.48,131.57) ; C89.2 23.62,132.32 ; C89.2 24.5,131.57 ; 69.48,103.4 U23.3 69.48,104.67 ; R685.2 v2(99.06,26.8) ; C119.2 153.75,108.97 v2(155.45,108.97) ; C119.2 v2(155.45,110.11) ; v4(94.49,129.41) 93.98,128.91 R104.2 93.09,129.53 ; v2(41.73,144.17) P6.A18 41.73,141.5 ; 1.4,139.57 J10.2 ; J10.2 2.41,140.59 ; J10.2 2.41,138.56 ; J10.2 3.43,139.57 ; 31.5,118.63 C110.2 ; v2(172.47,160.91) C16.2 173.09,161.67 ; v2(36.73,134.21) P6.B13 36.73,136.88 ; v2(86.68,36.34) 86.16,35.82 C193.2 ; v2(137.54,54.48) v2(137.54,55.37) v2(137.54,56.13) ; 23.44,175.51 TP3.1 ; TP3.1 v2(24.89,172.97) ; TP3.1 v2(24.89,178.05) ; TP3.1 26.34,175.51 ; C116.2 v2(18.54,118.11) ; C116.2 20.07,117.49 ; C116.2 20.07,118.73 ; C229.1 153.53,93.6 ; 155.87,177.05 P1.SH4 ; P1.SH4 154.46,178.46 ; P1.SH4 157.28,178.46 ; v4(94.49,133.22) 93.6,132.33 C83.2 93.09,132.96 ; R111.2 25.01,125.73 ; P3.1 103.12,163.58 ; P3.1 102.11,164.59 ; P3.1 102.11,162.56 ; P3.1 101.09,163.58 ; U35.2 v2(12.21,77.9) ; 170.7,161.67 C15.2 v2(171.32,160.91) ; 100.34,108.84 C120.2 v1(100.97,109.73) ; C235.1 148.7,93.09 ; 171.34,147.7 C59.2 v2(172.21,148.72) ; 11.49,65.91 12.8,65.91 ; 189.48,67.32 C404.1 ; C404.1 189.48,69.08 ; C404.1 190.23,68.2 ; Q9.2 v2(172.09,131.01) ; 29.2,126.49 C92.2 28.57,125.73 v2(29.08,125.22) ; C114.2 29.21,120 ; 18.23,61.59 U41.8 17.31,61.59 ; v1(183.84,51.07) U45.3 183.84,49.42 ; C28.2 139.57,155.32 v2(140.08,154.81) ; C28.2 140.2,156.72 ; C28.2 139.57,157.34 ; 112.01,52.23 C485.2 ; v1(161.67,170.61) J3.7 ; J3.7 161.67,174.02 ; J3.7 v2(160.07,172.47) ; J3.7 162.98,172.47 ; v2(144.27,26.67) 144.27,27.18 ; v2(137.54,64.01) v2(137.54,64.77) v2(137.54,65.66) ; U14.2 213.14,151.37 ; C13.2 137.15,161.54 ; C13.2 135.39,161.54 ; C13.2 v2(136.27,160.4) ; C178.2 182.99,47.37 ; 127.24,106.53 U144.3 ; U144.3 126.7,107.16 ; U144.3 127.24,107.8 ; P5.42 6.74,160.53 ; P5.42 5.7,160.53 ; P5.42 v2(6.22,163.83) P5.43 ; v2(76.83,157.99) C29.2 75.96,156.97 ; C125.2 v2(194.44,105.28) ; C125.2 192.94,106.43 v2(194.41,106.43) ; C125.2 192.94,104.14 v2(194.41,104.14) ; C125.2 191.74,105.28 ; 48.37,113.28 C708.2 47.5,112.53 ; J20.5 213.03,12.57 ; J20.5 210.9,12.57 ; J20.5 211.96,11.51 ; J20.5 211.96,13.64 ; v4(95.76,155.45) C30.2 96.9,154.7 ; R65.1 16,142.86 ; C381.2 11.43,13.32 ; C381.2 v2(10.67,12.7) ; C381.2 11.43,12.08 ; v2(69.95,68.96) E6.2 67.14,68.96 ; v2(25.65,124.08) 25.02,123.44 C100.2 ; C72.2 193.5,139.7 v2(191.9,139.7) ; C72.2 v2(191.9,138.56) ; C72.2 193.5,137.41 v2(191.9,137.41) ; v2(100.2,139.19) v2(97.92,139.19) 97.16,139.19 ; 197.98,131.1 Q18.1 ; Q18.1 198.49,131.72 ; Q18.1 198.49,130.48 ; v2(170.56,14.48) P11.1 ; P11.1 168.73,12.61 ; P11.1 v2(172.59,12.61) ; P11.1 170.56,10.86 ; 98.17,155.08 C31.2 98.68,155.7 v2(98.93,155.96) ; 45.47,50.43 C159.2 ; C159.2 v1(44.58,51.31) ; C159.2 45.47,52.18 ; 197.61,124.95 D24.2 ; D24.2 198.17,125.81 ; D24.2 197.05,125.81 ; D24.2 197.61,126.66 ; 152.91,55.49 C166.2 152.91,54.24 ; 41.73,136.88 P6.B18 v2(41.73,134.21) ; C218.2 65.02,13.92 v2(64.99,13.88) ; C218.2 64.27,14.83 ; P9.97 12.8,69.09 ; 28.08,101.35 C124.2 ; C124.2 29.72,101.35 v4(30.23,101.85) ; C124.2 28.96,102.1 ; 22.1,31.48 R709.1 v2(22.86,30.86) ; 1.22,28.07 v4(3.43,28.07) 5.64,28.07 ; v2(27.69,155.45) R29.2 28.31,154.56 ; 160.01,153.42 C36.2 v2(159.26,152.4) ; v2(175.26,113.03) 175.91,113.68 U18.30 ; J11.G1 2.63,128.21 ; J11.G1 2.63,124.9 ; J11.G1 0.97,126.56 ; 58.33,161.29 U5.2 ; 182.61,68.2 C248.1 181.99,68.82 ; 31.5,121.02 C108.2 30.87,120.4 ; 15.49,139.97 R68.1 ; 32.26,105.55 R140.2 ; R140.2 32.26,107.3 ; R140.2 v2(33.15,106.43) ; P8.12 3.42,86.29 ; RU2.11 165.39,153.66 ; v2(184.53,25.15) R279.2 184.53,26.53 ; R142.2 32.75,96.14 ; R142.2 v2(32,95.12) ; R142.2 32,97.02 ; U10.33 26.72,149.1 ; U10.33 25.15,150.67 ; U10.33 23.57,149.1 ; U10.33 25.15,147.52 ; 70.34,168.29 P2.4 ; P2.4 71.47,169.42 ; P2.4 70.34,170.55 ; P2.4 69.21,169.42 ; 158.88,134.23 C80.1 v2(157.99,133.35) ; 99.3,126.11 98.68,126.11 98.68,127.13 v4(98.3,127.51) 98.04,127.51 97.54,127 97.54,126.11 96.91,126.11 ; C533.2 v2(88.9,39.27) ; 111.89,89.93 C138.2 ; 147.21,83.44 C365.2 ; 96.01,74.56 C152.2 ; P8.14 3.42,81.39 ; C191.2 179.58,34.85 ; C191.2 v2(178.31,34.04) ; C191.2 v2(180.85,34.04) ; C191.2 179.58,33.22 ; C146.2 172.49,77.09 ; C146.2 171.3,77.62 170.81,78.11 v1(169.93,78.11) ; C146.2 v1(169.93,77.09) ; C146.2 171.3,76.56 170.81,76.07 v1(169.93,76.07) ; 78.5,104.52 79.12,104.52 v2(79.12,103.76) ; C48.2 v2(18.03,150.24) ; 85.41,35.05 C193.2 ; C193.2 86.16,34.28 v2(86.68,33.76) ; P8.13 3.42,83.99 ; R26.2 v2(24.64,155.45) ; v2(163.07,163.07) C10.2 163.94,163.96 ; v2(121.16,56.6) E9.2 ; 103.25,135.01 C77.2 102.74,135.76 v4(102.11,135.13) ; 147.19,145.66 C66.2 147.19,144.41 ; v2(121.92,59.31) 121.67,59.31 121.16,58.8 E7.2 ; R3.2 v2(84.2,170.43) ; R3.2 83.45,169.42 ; R3.2 84.2,168.54 ; v1(161.67,176.12) J3.9 ; J3.9 160.36,177.98 ; J3.9 v2(163.27,177.98) ; 115.84,149.73 C49.2 116.46,149.11 ; 114.58,38.21 U54.3 ; 160.04,142.06 U11.5 ; 116.59,145.28 C67.2 116.59,144.03 ; 17.02,55.4 v2(17.02,51.94) 17.02,48.49 ; v2(112.03,59.22) 111.64,58.83 C162.2 109.85,58.83 v2(109.45,59.22) ; 56.11,161.71 RU1.3 56.74,161.18 ; R256.2 v1(166.24,44.07) ; v2(13.21,106.49) U22.2 ; 121.92,39.92 U37.2 v2(121.92,41.66) ; E4.2 v2(73,68.96) ; 196.61,36.33 RU10.8 197.8,35.85 ; v2(43.73,144.17) P6.A20 43.73,141.5 ; C61.2 v2(103.63,146.69) ; v2(214.38,29.34) U58.2 214.38,26.56 ; C2.2 v2(29.46,167.13) ; C2.2 30.61,168.01 ; C2.2 30.61,166.26 ; 2.18,67.18 P9.92 ; 30.87,124.97 C98.2 31.5,124.35 ; 172.34,172.47 v2(172.34,173.23) ; 172.34,172.47 v2(172.34,171.58) ; v2(32.64,155.57) E1.2 v2(29.46,155.57) ; P8.15 3.42,78.64 ; 97.16,139.19 97.16,135.89 ; 97.16,139.19 v2(96.01,139.19) ; 10.18,46.86 P9.37 ; v2(80.14,165.61) C6.2 81.03,164.73 ; R98.1 213.98,140.08 ; C383.2 105.37,74.4 ; 44.73,136.88 P6.B21 v2(44.73,134.21) ; P5.43 6.74,166.88 ; P5.43 5.7,166.88 ; Q9.3 v2(170.81,131.01) ; 140.75,79.45 RU9.10 140.27,78.26 ; R215.2 v2(132.59,60.07) ; R215.2 132.59,61.46 ; R215.2 131.97,60.83 ; U4.3 56.74,164.35 ; P4.11 126.54,169.42 ; P4.11 125.22,168.1 ; P4.11 125.22,170.74 ; P4.11 123.9,169.42 ; v1(117.09,106.43) C123.2 117.72,107.31 ; 93.09,130.7 C88.2 v4(94.49,131.32) ; v2(90.74,83.31) 91.14,82.91 C140.2 91.14,81.12 v2(90.74,80.73) ; P9.77 12.8,62.74 ; C384.2 107.53,74.4 ; U26.2 v2(15.17,101.98) ; U26.2 15.22,101.07 ; U26.2 16.05,101.11 ; P9.60 4.8,53.85 ; 11.68,24.78 C430.1 ; RU9.19 135.19,86.08 ; 196.98,31.37 198.23,31.37 ; C113.2 28.19,120 ; R672.2 v2(139.32,28.32) ; C109.2 153.75,119.13 v2(155.45,119.13) ; C109.2 153.75,121.41 v2(155.45,121.41) ; C109.2 v2(155.45,120.27) ; 141.86,150.25 141.86,151.5 ; C74.2 96.38,136.53 ; C74.2 95.14,136.53 ; 15.26,103.59 U25.2 ; U25.2 15.22,104.41 ; U25.2 16.05,104.38 ; U25.2 v2(15.16,103.48) ; U6.2 59.93,157.48 ; 161.91,51.41 RU24.3 ; RU24.3 161.91,52.68 ; RU24.3 161.37,52.04 ; v2(90.61,73.72) 90.55,73.66 C400.2 ; E11.2 v2(162.31,45.72) ; R716.1 54.98,113.79 ; R716.1 54.36,113.17 ; R716.1 53.85,113.79 v2(53.59,114.05) ; C106.2 25.01,121.41 ; P9.83 12.8,64.64 ; RU4.8 126.46,112.46 ; C115.2 30.48,120 ; TP2.1 191.19,78.11 ; TP2.1 190.12,79.17 ; TP2.1 189.05,78.11 ; TP2.1 190.12,77.04 ; C76.2 100.83,136.53 ; C76.2 99.58,136.53 ; C76.2 v4(100.2,135.13) ; v2(159.26,156.08) C33.2 160.01,155.07 ; v2(179.71,46.86) C179.2 ; RU2.13 166.7,153.66 ; U7.3 56.74,158 ; C192.2 v2(184.66,34.92) ; C102.2 v2(92.46,121.16) ; Q9.1 v2(173.35,131.01) ; RU2.14 167.35,153.66 ; C536.2 v2(90.68,39.27) ; 51.73,141.5 P6.A28 v2(51.73,144.17) ; 124.88,100.61 RU6.3 124.35,101.24 ; 200.04,44.6 U47.3 200.58,43.97 ; v2(103.25,145.29) C65.2 102.49,144.67 ; C149.2 97.6,77.95 ; J3.5 v2(164.52,170.74) ; E8.2 v2(121.16,52.83) ; 3.88,78.44 P8.8 ; P9.19 12.8,41.15 ; 14.14,97.27 U31.2 v2(13.21,97.41) ; v2(105.28,136.02) C78.2 104.52,135.39 ; C538.2 v2(98.3,39.27) ; Q10.1 v2(180.97,131.01) ; 93.09,126.25 R109.1 93.71,126.87 ; 90.56,146.43 C63.2 91.19,147.05 ; C3.2 23.86,172.21 ; Q10.3 v2(178.44,131.01) ; R246.2 v1(166.24,48.93) ; E3.2 v2(76.05,68.96) ; U140.5 21.02,32.46 ; P9.47 12.8,50.04 ; C103.2 25.01,122.43
  TOP w1.016: 168.71,148.36 C62.2 165.05,148.36
  L2-GND1 w0.508: J12.4 45.97,98.37 ; J12.4 45.97,96.95 ; J12.4 46.91,97.66 ; J12.4 45.03,97.66 ; P1.SH3 155.87,170.74 ; P1.SH3 155.87,168.18 ; P1.SH3 157.15,169.46 ; P1.SH3 154.58,169.46 ; 2.41,142.11 3.3,142.11 ; 2.41,142.11 1.52,142.11 ; 2.41,142.11 2.41,141.22 ; 2.41,142.11 2.41,143 ; J11.G2 10.33,128.09 ; J11.G2 11.86,126.56 ; J11.G2 8.8,126.56 ; J11.G2 10.33,125.03 ; J20.2 207.82,15.11 ; J20.2 206.88,16.05 ; J20.2 205.94,15.11 ; J20.2 206.88,14.17 ; P2.6 69.48,172.13 ; P2.6 65.06,172.13 ; P2.6 67.27,169.92 ; P2.6 67.27,174.34 ; 124.03,169.42 P4.11 ; P4.11 126.42,169.42 ; P4.11 125.22,168.22 ; P4.11 125.22,170.61 ; P3.1 102.11,164.47 ; P3.1 102.11,162.69 ; P3.1 103,163.58 ; P3.1 101.22,163.58 ; 178.5,174.21 J2.2 ; J2.2 180.21,173.15 ; J2.2 180.21,175.28 ; J2.2 181.93,174.21 ; 1.52,137.03 J10.1 ; J10.1 3.3,137.03 ; J10.1 2.41,137.92 ; J10.1 2.41,136.14 ; 189.18,78.11 TP2.1 ; TP2.1 191.06,78.11 ; TP2.1 190.12,77.16 ; TP2.1 190.12,79.05 ; 80.41,169.92 P2.5 ; P2.5 78.2,172.13 ; P2.5 82.62,172.13 ; P2.5 80.41,174.34 ; TP91.1 19.94,87.04 ; TP91.1 18.06,87.04 ; TP91.1 19,86.1 ; TP91.1 19,87.98 ; J11.G1 4.16,126.56 ; J11.G1 1.1,126.56 ; J11.G1 2.63,128.09 ; J11.G1 2.63,125.03 ; J12.7 45.97,102.18 ; J12.7 45.03,101.47 ; J12.7 46.91,101.47 ; J12.7 45.97,100.76 ; J2.MTG1 176.78,175.21 ; J2.MTG1 175.71,177.04 ; J2.MTG1 175.71,173.38 ; J2.MTG1 174.65,175.21 ; 217.68,155.57 J9.2 ; J9.2 217.68,157.35 ; J9.2 216.79,156.46 ; J9.2 218.57,156.46 ; J16.1 37.21,20.37 ; J16.1 38.66,18.92 ; J16.1 35.76,18.92 ; J16.1 37.21,17.47 ; TP85.1 191.69,37.47 ; TP85.1 190.75,36.52 ; TP85.1 190.75,38.41 ; TP85.1 189.81,37.47 ; 6.3,95.5 P7.MTG2 ; P7.MTG2 7.5,94.31 ; P7.MTG2 7.5,96.7 ; P7.MTG2 8.69,95.5 ; 104.14,168.22 P3.11 ; P3.11 105.33,169.42 ; P3.11 104.14,170.61 ; P3.11 102.95,169.42 ; P8.11 3.35,88.72 ; P8.11 0.96,88.72 ; P8.11 2.16,89.91 ; P8.11 2.16,87.53 ; P2.4 71.35,169.42 ; P2.4 69.34,169.42 ; P2.4 70.34,170.42 ; P2.4 70.34,168.41 ; 200.86,20.83 J21.5 ; J21.5 201.8,21.77 ; J21.5 201.8,19.89 ; J21.5 202.74,20.83 ; J12.1 46.91,93.85 ; J12.1 45.03,93.85 ; J12.1 45.97,93.14 ; J12.1 45.97,94.56 ; J20.5 211.96,13.51 ; J20.5 211.02,12.57 ; J20.5 212.9,12.57 ; J20.5 211.96,11.63 ; 10.33,117.53 J11.G3 ; J11.G3 10.33,120.59 ; J11.G3 11.86,119.06 ; J11.G3 8.8,119.06 ; P4.D4 110.69,177.93 ; P4.D4 109.8,177.04 ; P4.D4 110.69,176.15 ; P4.D4 111.58,177.04 ; 154.58,178.46 P1.SH4 ; P1.SH4 157.15,178.46 ; P1.SH4 155.87,177.18 ; J9.3 218.57,159 ; J9.3 216.79,159 ; J9.3 217.68,158.11 ; J9.3 217.68,159.89 ; 87.45,169.42 P3.12 ; P3.12 89.84,169.42 ; P3.12 88.65,170.61 ; P3.12 88.65,168.22 ; 1.4,110.59 P7.MTG3 ; P7.MTG3 3.79,110.59 ; P7.MTG3 2.6,111.79 ; P7.MTG3 2.6,109.4 ; 184.71,173.38 J2.MTG2 ; J2.MTG2 185.78,175.21 ; J2.MTG2 183.65,175.21 ; J2.MTG2 184.71,177.04 ; 217.68,153.03 J9.1 ; J9.1 217.68,154.81 ; J9.1 218.57,153.92 ; J9.1 216.79,153.92 ; P7.MTG1 8.69,109.98 ; P7.MTG1 7.5,108.79 ; P7.MTG1 6.3,109.98 ; P7.MTG1 7.5,111.18 ; 217.55,40.21 J14.3 ; J14.3 218.49,41.15 ; J14.3 217.55,42.09 ; J14.3 216.61,41.15 ; J1.2 5.64,19.81 ; J1.2 3.76,19.81 ; J1.2 4.7,18.87 ; J1.2 4.7,20.75 ; P3.D4 89.61,177.93 ; P3.D4 89.61,176.15 ; P3.D4 88.72,177.04 ; P3.D4 90.5,177.04 ; 1.4,94.89 P7.MTG4 ; P7.MTG4 2.6,93.7 ; P7.MTG4 3.79,94.89 ; P7.MTG4 2.6,96.09 ; J10.2 2.41,140.46 ; J10.2 1.52,139.57 ; J10.2 3.3,139.57 ; J10.2 2.41,138.68 ; 1.1,119.06 J11.G4 ; J11.G4 2.63,117.53 ; J11.G4 2.63,120.59 ; J11.G4 4.16,119.06 ; P8.16 3.35,76.2 ; P8.16 2.16,77.39 ; P8.16 2.16,75 ; P8.16 0.96,76.2 ; 109.73,168.22 P4.12 ; P4.12 108.53,169.42 ; P4.12 110.92,169.42 ; P4.12 109.73,170.61 ; 145.58,178.46 P1.SH1 ; P1.SH1 148.15,178.46 ; P1.SH1 146.87,177.18 ; 145.58,169.46 P1.SH2 ; P1.SH2 146.87,170.74 ; P1.SH2 146.87,168.18 ; P1.SH2 148.15,169.46 ; J21.2 196.72,24.31 ; J21.2 197.66,23.37 ; J21.2 195.78,23.37 ; J21.2 196.72,22.43 ; P1.4 150.37,173.84 ; P1.4 151.24,172.96 ; P1.4 149.49,172.96 ; P1.4 150.37,172.08 ; 23.11,159.97 TP12.1 ; TP12.1 22.17,160.91 ; TP12.1 24.05,160.91 ; TP12.1 23.11,161.85 ; 122.3,163.58 P4.1 ; P4.1 123.19,164.47 ; P4.1 123.19,162.69 ; P4.1 124.08,163.58 ; J11.6 5.48,131.01 ; J11.6 5.48,129.01 ; J11.6 4.47,130.01
  L4-GND2 w0.508: 4.47,130.01 J11.6 ; J11.6 5.48,131.01 ; J11.6 5.48,129.01 ; J16.1 38.66,18.92 ; J16.1 37.21,20.37 ; J16.1 37.21,17.47 ; J16.1 35.76,18.92 ; 108.53,169.42 P4.12 ; P4.12 109.73,170.61 ; P4.12 109.73,168.22 ; P4.12 110.92,169.42 ; 1.4,94.89 P7.MTG4 ; P7.MTG4 3.79,94.89 ; P7.MTG4 2.6,96.09 ; P7.MTG4 2.6,93.7 ; TP91.1 19,87.98 ; TP91.1 18.06,87.04 ; TP91.1 19,86.1 ; TP91.1 19.94,87.04 ; 205.94,15.11 J20.2 ; J20.2 206.88,14.17 ; J20.2 206.88,16.05 ; J20.2 207.82,15.11 ; 7.5,94.31 P7.MTG2 ; P7.MTG2 8.69,95.5 ; P7.MTG2 7.5,96.7 ; P7.MTG2 6.3,95.5 ; 1.52,142.11 2.41,142.11 ; 2.41,142.11 2.41,143 ; 2.41,142.11 2.41,141.22 ; 2.41,142.11 3.3,142.11 ; P3.1 103,163.58 ; P3.1 101.22,163.58 ; P3.1 102.11,162.69 ; P3.1 102.11,164.47 ; 217.68,158.11 J9.3 ; J9.3 217.68,159.89 ; J9.3 216.79,159 ; J9.3 218.57,159 ; J10.2 2.41,140.46 ; J10.2 3.3,139.57 ; J10.2 2.41,138.68 ; J10.2 1.52,139.57 ; 201.8,19.89 J21.5 ; J21.5 202.74,20.83 ; J21.5 201.8,21.77 ; J21.5 200.86,20.83 ; P2.5 80.41,174.34 ; P2.5 80.41,169.92 ; P2.5 78.2,172.13 ; P2.5 82.62,172.13 ; 2.41,136.14 J10.1 ; J10.1 3.3,137.03 ; J10.1 2.41,137.92 ; J10.1 1.52,137.03 ; P1.4 150.37,173.84 ; P1.4 151.24,172.96 ; P1.4 150.37,172.08 ; P1.4 149.49,172.96 ; 174.65,175.21 J2.MTG1 ; J2.MTG1 175.71,177.04 ; J2.MTG1 176.78,175.21 ; J2.MTG1 175.71,173.38 ; 183.65,175.21 J2.MTG2 ; J2.MTG2 184.71,177.04 ; J2.MTG2 184.71,173.38 ; J2.MTG2 185.78,175.21 ; P3.D4 90.5,177.04 ; P3.D4 88.72,177.04 ; P3.D4 89.61,176.15 ; P3.D4 89.61,177.93 ; 102.95,169.42 P3.11 ; P3.11 105.33,169.42 ; P3.11 104.14,170.61 ; P3.11 104.14,168.22 ; 45.03,93.85 J12.1 ; J12.1 45.97,93.14 ; J12.1 45.97,94.56 ; J12.1 46.91,93.85 ; TP2.1 191.06,78.11 ; TP2.1 190.12,77.16 ; TP2.1 189.18,78.11 ; TP2.1 190.12,79.05 ; 10.33,117.53 J11.G3 ; J11.G3 11.86,119.06 ; J11.G3 8.8,119.06 ; J11.G3 10.33,120.59 ; P2.6 69.48,172.13 ; P2.6 67.27,169.92 ; P2.6 67.27,174.34 ; P2.6 65.06,172.13 ; 45.03,101.47 J12.7 ; J12.7 45.97,102.18 ; J12.7 46.91,101.47 ; J12.7 45.97,100.76 ; P3.12 89.84,169.42 ; P3.12 88.65,170.61 ; P3.12 88.65,168.22 ; P3.12 87.45,169.42 ; P8.16 3.35,76.2 ; P8.16 2.16,75 ; P8.16 0.96,76.2 ; P8.16 2.16,77.39 ; J9.1 217.68,154.81 ; J9.1 218.57,153.92 ; J9.1 216.79,153.92 ; J9.1 217.68,153.03 ; P7.MTG3 2.6,111.79 ; P7.MTG3 3.79,110.59 ; P7.MTG3 1.4,110.59 ; P7.MTG3 2.6,109.4 ; 123.19,162.69 P4.1 ; P4.1 123.19,164.47 ; P4.1 124.08,163.58 ; P4.1 122.3,163.58 ; 69.34,169.42 P2.4 ; P2.4 70.34,168.41 ; P2.4 70.34,170.42 ; P2.4 71.35,169.42 ; P1.SH1 148.15,178.46 ; P1.SH1 145.58,178.46 ; P1.SH1 146.87,177.18 ; P1.SH3 155.87,170.74 ; P1.SH3 155.87,168.18 ; P1.SH3 154.58,169.46 ; P1.SH3 157.15,169.46 ; P1.SH2 146.87,170.74 ; P1.SH2 146.87,168.18 ; P1.SH2 145.58,169.46 ; P1.SH2 148.15,169.46 ; 154.58,178.46 P1.SH4 ; P1.SH4 155.87,177.18 ; P1.SH4 157.15,178.46 ; 125.22,168.22 P4.11 ; P4.11 126.42,169.42 ; P4.11 124.03,169.42 ; P4.11 125.22,170.61 ; J2.2 181.93,174.21 ; J2.2 180.21,173.15 ; J2.2 180.21,175.28 ; J2.2 178.5,174.21 ; 196.72,22.43 J21.2 ; J21.2 195.78,23.37 ; J21.2 197.66,23.37 ; J21.2 196.72,24.31 ; J9.2 218.57,156.46 ; J9.2 216.79,156.46 ; J9.2 217.68,155.57 ; J9.2 217.68,157.35 ; 10.33,125.03 J11.G2 ; J11.G2 10.33,128.09 ; J11.G2 11.86,126.56 ; J11.G2 8.8,126.56 ; 1.1,126.56 J11.G1 ; J11.G1 2.63,125.03 ; J11.G1 2.63,128.09 ; J11.G1 4.16,126.56 ; J20.5 211.96,13.51 ; J20.5 211.02,12.57 ; J20.5 211.96,11.63 ; J20.5 212.9,12.57 ; TP12.1 23.11,161.85 ; TP12.1 22.17,160.91 ; TP12.1 23.11,159.97 ; TP12.1 24.05,160.91 ; 110.69,176.15 P4.D4 ; P4.D4 109.8,177.04 ; P4.D4 110.69,177.93 ; P4.D4 111.58,177.04 ; 216.61,41.15 J14.3 ; J14.3 217.55,42.09 ; J14.3 218.49,41.15 ; J14.3 217.55,40.21 ; TP85.1 191.69,37.47 ; TP85.1 190.75,36.52 ; TP85.1 189.81,37.47 ; TP85.1 190.75,38.41 ; 1.1,119.06 J11.G4 ; J11.G4 2.63,117.53 ; J11.G4 2.63,120.59 ; J11.G4 4.16,119.06 ; J12.4 46.91,97.66 ; J12.4 45.97,96.95 ; J12.4 45.03,97.66 ; J12.4 45.97,98.37 ; 2.16,87.53 P8.11 ; P8.11 3.35,88.72 ; P8.11 0.96,88.72 ; P8.11 2.16,89.91 ; J1.2 4.7,20.75 ; J1.2 4.7,18.87 ; J1.2 3.76,19.81 ; J1.2 5.64,19.81 ; P7.MTG1 7.5,111.18 ; P7.MTG1 8.69,109.98 ; P7.MTG1 7.5,108.79 ; P7.MTG1 6.3,109.98
  L6-GND3 w0.508: 88.65,168.22 P3.12 ; P3.12 88.65,170.61 ; P3.12 89.84,169.42 ; P3.12 87.45,169.42 ; 2.6,93.7 P7.MTG4 ; P7.MTG4 1.4,94.89 ; P7.MTG4 2.6,96.09 ; P7.MTG4 3.79,94.89 ; 216.61,41.15 J14.3 ; J14.3 218.49,41.15 ; J14.3 217.55,42.09 ; J14.3 217.55,40.21 ; P4.12 110.92,169.42 ; P4.12 109.73,168.22 ; P4.12 108.53,169.42 ; P4.12 109.73,170.61 ; 18.06,87.04 TP91.1 ; TP91.1 19.94,87.04 ; TP91.1 19,86.1 ; TP91.1 19,87.98 ; 45.03,93.85 J12.1 ; J12.1 45.97,93.14 ; J12.1 46.91,93.85 ; J12.1 45.97,94.56 ; J20.5 212.9,12.57 ; J20.5 211.02,12.57 ; J20.5 211.96,13.51 ; J20.5 211.96,11.63 ; 45.97,96.95 J12.4 ; J12.4 45.97,98.37 ; J12.4 46.91,97.66 ; J12.4 45.03,97.66 ; P1.SH3 155.87,170.74 ; P1.SH3 155.87,168.18 ; P1.SH3 157.15,169.46 ; P1.SH3 154.58,169.46 ; P1.SH4 157.15,178.46 ; P1.SH4 155.87,177.18 ; P1.SH4 154.58,178.46 ; 7.5,108.79 P7.MTG1 ; P7.MTG1 7.5,111.18 ; P7.MTG1 8.69,109.98 ; P7.MTG1 6.3,109.98 ; J10.1 3.3,137.03 ; J10.1 2.41,136.14 ; J10.1 2.41,137.92 ; J10.1 1.52,137.03 ; 70.34,168.41 P2.4 ; P2.4 69.34,169.42 ; P2.4 71.35,169.42 ; P2.4 70.34,170.42 ; J9.1 217.68,154.81 ; J9.1 217.68,153.03 ; J9.1 218.57,153.92 ; J9.1 216.79,153.92 ; P1.SH2 146.87,170.74 ; P1.SH2 148.15,169.46 ; P1.SH2 146.87,168.18 ; P1.SH2 145.58,169.46 ; J16.1 38.66,18.92 ; J16.1 37.21,20.37 ; J16.1 35.76,18.92 ; J16.1 37.21,17.47 ; P3.11 104.14,170.61 ; P3.11 105.33,169.42 ; P3.11 102.95,169.42 ; P3.11 104.14,168.22 ; J11.G1 2.63,128.09 ; J11.G1 2.63,125.03 ; J11.G1 4.16,126.56 ; J11.G1 1.1,126.56 ; 180.21,173.15 J2.2 ; J2.2 181.93,174.21 ; J2.2 180.21,175.28 ; J2.2 178.5,174.21 ; 150.37,172.08 P1.4 ; P1.4 151.24,172.96 ; P1.4 149.49,172.96 ; P1.4 150.37,173.84 ; P3.D4 89.61,177.93 ; P3.D4 89.61,176.15 ; P3.D4 88.72,177.04 ; P3.D4 90.5,177.04 ; 80.41,169.92 P2.5 ; P2.5 82.62,172.13 ; P2.5 80.41,174.34 ; P2.5 78.2,172.13 ; 2.63,117.53 J11.G4 ; J11.G4 4.16,119.06 ; J11.G4 1.1,119.06 ; J11.G4 2.63,120.59 ; 2.41,142.11 2.41,143 ; 2.41,142.11 3.3,142.11 ; 2.41,142.11 1.52,142.11 ; 2.41,142.11 2.41,141.22 ; 7.5,94.31 P7.MTG2 ; P7.MTG2 6.3,95.5 ; P7.MTG2 7.5,96.7 ; P7.MTG2 8.69,95.5 ; J20.2 207.82,15.11 ; J20.2 205.94,15.11 ; J20.2 206.88,16.05 ; J20.2 206.88,14.17 ; 45.97,100.76 J12.7 ; J12.7 45.03,101.47 ; J12.7 45.97,102.18 ; J12.7 46.91,101.47 ; P4.1 124.08,163.58 ; P4.1 122.3,163.58 ; P4.1 123.19,162.69 ; P4.1 123.19,164.47 ; TP2.1 190.12,79.05 ; TP2.1 189.18,78.11 ; TP2.1 191.06,78.11 ; TP2.1 190.12,77.16 ; 110.69,176.15 P4.D4 ; P4.D4 109.8,177.04 ; P4.D4 111.58,177.04 ; P4.D4 110.69,177.93 ; P8.16 3.35,76.2 ; P8.16 0.96,76.2 ; P8.16 2.16,77.39 ; P8.16 2.16,75 ; 67.27,169.92 P2.6 ; P2.6 69.48,172.13 ; P2.6 67.27,174.34 ; P2.6 65.06,172.13 ; J21.5 202.74,20.83 ; J21.5 200.86,20.83 ; J21.5 201.8,21.77 ; J21.5 201.8,19.89 ; 183.65,175.21 J2.MTG2 ; J2.MTG2 184.71,177.04 ; J2.MTG2 184.71,173.38 ; J2.MTG2 185.78,175.21 ; 216.79,156.46 J9.2 ; J9.2 217.68,157.35 ; J9.2 217.68,155.57 ; J9.2 218.57,156.46 ; J1.2 5.64,19.81 ; J1.2 3.76,19.81 ; J1.2 4.7,20.75 ; J1.2 4.7,18.87 ; 5.48,129.01 J11.6 ; J11.6 5.48,131.01 ; J11.6 4.47,130.01 ; 175.71,173.38 J2.MTG1 ; J2.MTG1 174.65,175.21 ; J2.MTG1 175.71,177.04 ; J2.MTG1 176.78,175.21 ; TP85.1 190.75,38.41 ; TP85.1 190.75,36.52 ; TP85.1 191.69,37.47 ; TP85.1 189.81,37.47 ; P1.SH1 148.15,178.46 ; P1.SH1 146.87,177.18 ; P1.SH1 145.58,178.46 ; 0.96,88.72 P8.11 ; P8.11 2.16,89.91 ; P8.11 2.16,87.53 ; P8.11 3.35,88.72 ; J11.G2 11.86,126.56 ; J11.G2 10.33,125.03 ; J11.G2 10.33,128.09 ; J11.G2 8.8,126.56 ; 101.22,163.58 P3.1 ; P3.1 102.11,162.69 ; P3.1 102.11,164.47 ; P3.1 103,163.58 ; J21.2 197.66,23.37 ; J21.2 196.72,22.43 ; J21.2 195.78,23.37 ; J21.2 196.72,24.31 ; 23.11,159.97 TP12.1 ; TP12.1 24.05,160.91 ; TP12.1 22.17,160.91 ; TP12.1 23.11,161.85 ; 125.22,168.22 P4.11 ; P4.11 124.03,169.42 ; P4.11 125.22,170.61 ; P4.11 126.42,169.42 ; 8.8,119.06 J11.G3 ; J11.G3 10.33,120.59 ; J11.G3 11.86,119.06 ; J11.G3 10.33,117.53 ; P7.MTG3 2.6,111.79 ; P7.MTG3 2.6,109.4 ; P7.MTG3 3.79,110.59 ; P7.MTG3 1.4,110.59 ; J9.3 218.57,159 ; J9.3 217.68,158.11 ; J9.3 217.68,159.89 ; J9.3 216.79,159 ; 2.41,138.68 J10.2 ; J10.2 2.41,140.46 ; J10.2 3.3,139.57 ; J10.2 1.52,139.57
  L8-PWR1 w0.127: 104.22,45.57 103.97,45.57 103.96,45.58 103.61,45.58 103.6,45.57 102.35,45.57 102.35,45.57 102.02,45.57 102.02,45.57 101.09,45.57 100.18,46.48 100.18,46.92 99.95,47.15 99.63,47.15 99.38,47.41 99.38,47.72 99.14,47.97 98.82,47.97 98.58,48.21 98.58,48.52 98.18,48.92 v1(98.18,49.16) ; 98.86,56.49 98.58,56.77 98.58,57.57 v1(98.18,57.96)
  L8-PWR1 w0.203: v2(148.08,60.71) 146.94,60.71 144.91,58.67 141.6,58.67 140.21,57.28 139.19,57.28 138.56,57.91 137.03,57.91 136.53,57.4 134.9,57.4 134.14,58.17 131.7,58.17 130.05,56.52 125.6,56.52 124.05,58.06 122.07,58.06 121.16,57.15 120.65,57.15 120.14,56.64 116.2,56.64 115.42,55.85 105.28,55.85 104.65,56.49 98.86,56.49 ; 104.22,45.57 106.03,45.57 107.66,43.94 111.28,43.94 111.33,43.99 117.78,43.99 118.29,44.5 119.33,44.5 119.94,43.89 126.31,43.89 126.75,44.32 127.38,44.32 127.89,43.81 134.98,43.81 135.12,43.68 136.05,43.68 136.24,43.87 137.97,43.87 140.46,46.35 v2(140.46,50.16)
  L9-PWR2 w0.203: v2(134.49,70.99) 133.99,71.5 96.9,71.5 96.65,71.75 v2(96.65,72.62)
  L11-GND4 w0.508: TP85.1 190.75,38.41 ; TP85.1 189.81,37.47 ; TP85.1 191.69,37.47 ; TP85.1 190.75,36.52 ; J20.5 211.96,13.51 ; J20.5 212.9,12.57 ; J20.5 211.02,12.57 ; J20.5 211.96,11.63 ; 109.73,168.22 P4.12 ; P4.12 109.73,170.61 ; P4.12 110.92,169.42 ; P4.12 108.53,169.42 ; P4.D4 111.58,177.04 ; P4.D4 110.69,177.93 ; P4.D4 110.69,176.15 ; P4.D4 109.8,177.04 ; 201.8,19.89 J21.5 ; J21.5 202.74,20.83 ; J21.5 200.86,20.83 ; J21.5 201.8,21.77 ; J10.1 3.3,137.03 ; J10.1 2.41,137.92 ; J10.1 1.52,137.03 ; J10.1 2.41,136.14 ; 80.41,169.92 P2.5 ; P2.5 80.41,174.34 ; P2.5 78.2,172.13 ; P2.5 82.62,172.13 ; J9.1 218.57,153.92 ; J9.1 217.68,153.03 ; J9.1 216.79,153.92 ; J9.1 217.68,154.81 ; P7.MTG1 8.69,109.98 ; P7.MTG1 7.5,108.79 ; P7.MTG1 7.5,111.18 ; P7.MTG1 6.3,109.98 ; 45.03,97.66 J12.4 ; J12.4 45.97,98.37 ; J12.4 45.97,96.95 ; J12.4 46.91,97.66 ; P1.SH3 157.15,169.46 ; P1.SH3 155.87,168.18 ; P1.SH3 154.58,169.46 ; P1.SH3 155.87,170.74 ; J16.1 37.21,20.37 ; J16.1 37.21,17.47 ; J16.1 38.66,18.92 ; J16.1 35.76,18.92 ; J9.3 217.68,159.89 ; J9.3 217.68,158.11 ; J9.3 216.79,159 ; J9.3 218.57,159 ; P1.4 151.24,172.96 ; P1.4 149.49,172.96 ; P1.4 150.37,173.84 ; P1.4 150.37,172.08 ; J12.7 46.91,101.47 ; J12.7 45.03,101.47 ; J12.7 45.97,100.76 ; J12.7 45.97,102.18 ; J11.G3 11.86,119.06 ; J11.G3 10.33,117.53 ; J11.G3 8.8,119.06 ; J11.G3 10.33,120.59 ; TP2.1 191.06,78.11 ; TP2.1 190.12,77.16 ; TP2.1 190.12,79.05 ; TP2.1 189.18,78.11 ; 1.4,94.89 P7.MTG4 ; P7.MTG4 2.6,93.7 ; P7.MTG4 3.79,94.89 ; P7.MTG4 2.6,96.09 ; TP91.1 19.94,87.04 ; TP91.1 18.06,87.04 ; TP91.1 19,87.98 ; TP91.1 19,86.1 ; J11.6 5.48,131.01 ; J11.6 4.47,130.01 ; J11.6 5.48,129.01 ; 216.79,156.46 J9.2 ; J9.2 218.57,156.46 ; J9.2 217.68,155.57 ; J9.2 217.68,157.35 ; 88.65,168.22 P3.12 ; P3.12 88.65,170.61 ; P3.12 87.45,169.42 ; P3.12 89.84,169.42 ; 45.97,93.14 J12.1 ; J12.1 45.97,94.56 ; J12.1 45.03,93.85 ; J12.1 46.91,93.85 ; 6.3,95.5 P7.MTG2 ; P7.MTG2 7.5,94.31 ; P7.MTG2 7.5,96.7 ; P7.MTG2 8.69,95.5 ; 175.71,173.38 J2.MTG1 ; J2.MTG1 175.71,177.04 ; J2.MTG1 176.78,175.21 ; J2.MTG1 174.65,175.21 ; P2.6 69.48,172.13 ; P2.6 67.27,169.92 ; P2.6 67.27,174.34 ; P2.6 65.06,172.13 ; 145.58,169.46 P1.SH2 ; P1.SH2 148.15,169.46 ; P1.SH2 146.87,168.18 ; P1.SH2 146.87,170.74 ; J20.2 206.88,16.05 ; J20.2 205.94,15.11 ; J20.2 207.82,15.11 ; J20.2 206.88,14.17 ; 1.52,142.11 2.41,142.11 ; 2.41,142.11 2.41,143 ; 2.41,142.11 3.3,142.11 ; 2.41,142.11 2.41,141.22 ; P4.11 126.42,169.42 ; P4.11 124.03,169.42 ; P4.11 125.22,168.22 ; P4.11 125.22,170.61 ; P3.11 104.14,170.61 ; P3.11 102.95,169.42 ; P3.11 105.33,169.42 ; P3.11 104.14,168.22 ; 184.71,173.38 J2.MTG2 ; J2.MTG2 184.71,177.04 ; J2.MTG2 185.78,175.21 ; J2.MTG2 183.65,175.21 ; 1.1,126.56 J11.G1 ; J11.G1 4.16,126.56 ; J11.G1 2.63,125.03 ; J11.G1 2.63,128.09 ; 154.58,178.46 P1.SH4 ; P1.SH4 157.15,178.46 ; P1.SH4 155.87,177.18 ; 2.16,87.53 P8.11 ; P8.11 3.35,88.72 ; P8.11 2.16,89.91 ; P8.11 0.96,88.72 ; 3.76,19.81 J1.2 ; J1.2 5.64,19.81 ; J1.2 4.7,20.75 ; J1.2 4.7,18.87 ; P3.D4 90.5,177.04 ; P3.D4 89.61,177.93 ; P3.D4 89.61,176.15 ; P3.D4 88.72,177.04 ; J14.3 217.55,42.09 ; J14.3 218.49,41.15 ; J14.3 217.55,40.21 ; J14.3 216.61,41.15 ; P4.1 123.19,164.47 ; P4.1 123.19,162.69 ; P4.1 122.3,163.58 ; P4.1 124.08,163.58 ; 2.16,75 P8.16 ; P8.16 3.35,76.2 ; P8.16 0.96,76.2 ; P8.16 2.16,77.39 ; J2.2 181.93,174.21 ; J2.2 180.21,175.28 ; J2.2 180.21,173.15 ; J2.2 178.5,174.21 ; J10.2 2.41,140.46 ; J10.2 1.52,139.57 ; J10.2 2.41,138.68 ; J10.2 3.3,139.57 ; TP12.1 23.11,161.85 ; TP12.1 23.11,159.97 ; TP12.1 22.17,160.91 ; TP12.1 24.05,160.91 ; P3.1 103,163.58 ; P3.1 102.11,162.69 ; P3.1 101.22,163.58 ; P3.1 102.11,164.47 ; 1.4,110.59 P7.MTG3 ; P7.MTG3 2.6,109.4 ; P7.MTG3 2.6,111.79 ; P7.MTG3 3.79,110.59 ; J11.G2 11.86,126.56 ; J11.G2 8.8,126.56 ; J11.G2 10.33,125.03 ; J11.G2 10.33,128.09 ; 195.78,23.37 J21.2 ; J21.2 196.72,24.31 ; J21.2 196.72,22.43 ; J21.2 197.66,23.37 ; 146.87,177.18 P1.SH1 ; P1.SH1 145.58,178.46 ; P1.SH1 148.15,178.46 ; J11.G4 4.16,119.06 ; J11.G4 1.1,119.06 ; J11.G4 2.63,117.53 ; J11.G4 2.63,120.59 ; P2.4 70.34,170.42 ; P2.4 69.34,169.42 ; P2.4 70.34,168.41 ; P2.4 71.35,169.42
  L13-GND5 w0.508: 2.6,93.7 P7.MTG4 ; P7.MTG4 1.4,94.89 ; P7.MTG4 3.79,94.89 ; P7.MTG4 2.6,96.09 ; 2.16,75 P8.16 ; P8.16 0.96,76.2 ; P8.16 2.16,77.39 ; P8.16 3.35,76.2 ; 108.53,169.42 P4.12 ; P4.12 109.73,170.61 ; P4.12 110.92,169.42 ; P4.12 109.73,168.22 ; 5.48,129.01 J11.6 ; J11.6 5.48,131.01 ; J11.6 4.47,130.01 ; P4.1 123.19,164.47 ; P4.1 123.19,162.69 ; P4.1 122.3,163.58 ; P4.1 124.08,163.58 ; 205.94,15.11 J20.2 ; J20.2 206.88,16.05 ; J20.2 207.82,15.11 ; J20.2 206.88,14.17 ; 217.68,158.11 J9.3 ; J9.3 217.68,159.89 ; J9.3 216.79,159 ; J9.3 218.57,159 ; J21.5 201.8,21.77 ; J21.5 201.8,19.89 ; J21.5 202.74,20.83 ; J21.5 200.86,20.83 ; TP12.1 24.05,160.91 ; TP12.1 23.11,161.85 ; TP12.1 23.11,159.97 ; TP12.1 22.17,160.91 ; 125.22,168.22 P4.11 ; P4.11 124.03,169.42 ; P4.11 125.22,170.61 ; P4.11 126.42,169.42 ; 35.76,18.92 J16.1 ; J16.1 37.21,20.37 ; J16.1 37.21,17.47 ; J16.1 38.66,18.92 ; P2.4 71.35,169.42 ; P2.4 70.34,168.41 ; P2.4 70.34,170.42 ; P2.4 69.34,169.42 ; 217.55,40.21 J14.3 ; J14.3 217.55,42.09 ; J14.3 216.61,41.15 ; J14.3 218.49,41.15 ; J20.5 211.96,13.51 ; J20.5 212.9,12.57 ; J20.5 211.02,12.57 ; J20.5 211.96,11.63 ; 150.37,172.08 P1.4 ; P1.4 149.49,172.96 ; P1.4 150.37,173.84 ; P1.4 151.24,172.96 ; P8.11 3.35,88.72 ; P8.11 0.96,88.72 ; P8.11 2.16,89.91 ; P8.11 2.16,87.53 ; J11.G3 10.33,120.59 ; J11.G3 11.86,119.06 ; J11.G3 10.33,117.53 ; J11.G3 8.8,119.06 ; P4.D4 111.58,177.04 ; P4.D4 109.8,177.04 ; P4.D4 110.69,176.15 ; P4.D4 110.69,177.93 ; TP2.1 190.12,79.05 ; TP2.1 191.06,78.11 ; TP2.1 189.18,78.11 ; TP2.1 190.12,77.16 ; 102.11,162.69 P3.1 ; P3.1 101.22,163.58 ; P3.1 103,163.58 ; P3.1 102.11,164.47 ; J12.1 46.91,93.85 ; J12.1 45.03,93.85 ; J12.1 45.97,93.14 ; J12.1 45.97,94.56 ; 1.1,119.06 J11.G4 ; J11.G4 2.63,117.53 ; J11.G4 2.63,120.59 ; J11.G4 4.16,119.06 ; 2.41,138.68 J10.2 ; J10.2 1.52,139.57 ; J10.2 3.3,139.57 ; J10.2 2.41,140.46 ; P1.SH3 155.87,170.74 ; P1.SH3 155.87,168.18 ; P1.SH3 157.15,169.46 ; P1.SH3 154.58,169.46 ; 145.58,169.46 P1.SH2 ; P1.SH2 146.87,168.18 ; P1.SH2 148.15,169.46 ; P1.SH2 146.87,170.74 ; J10.1 3.3,137.03 ; J10.1 2.41,137.92 ; J10.1 1.52,137.03 ; J10.1 2.41,136.14 ; 78.2,172.13 P2.5 ; P2.5 80.41,174.34 ; P2.5 82.62,172.13 ; P2.5 80.41,169.92 ; 45.97,96.95 J12.4 ; J12.4 46.91,97.66 ; J12.4 45.03,97.66 ; J12.4 45.97,98.37 ; P7.MTG3 2.6,111.79 ; P7.MTG3 2.6,109.4 ; P7.MTG3 1.4,110.59 ; P7.MTG3 3.79,110.59 ; J2.MTG2 184.71,177.04 ; J2.MTG2 184.71,173.38 ; J2.MTG2 185.78,175.21 ; J2.MTG2 183.65,175.21 ; 3.76,19.81 J1.2 ; J1.2 5.64,19.81 ; J1.2 4.7,18.87 ; J1.2 4.7,20.75 ; P3.11 105.33,169.42 ; P3.11 104.14,170.61 ; P3.11 102.95,169.42 ; P3.11 104.14,168.22 ; 216.79,156.46 J9.2 ; J9.2 217.68,155.57 ; J9.2 218.57,156.46 ; J9.2 217.68,157.35 ; 2.63,125.03 J11.G1 ; J11.G1 4.16,126.56 ; J11.G1 1.1,126.56 ; J11.G1 2.63,128.09 ; J9.1 217.68,154.81 ; J9.1 218.57,153.92 ; J9.1 217.68,153.03 ; J9.1 216.79,153.92 ; 18.06,87.04 TP91.1 ; TP91.1 19,87.98 ; TP91.1 19.94,87.04 ; TP91.1 19,86.1 ; P7.MTG2 8.69,95.5 ; P7.MTG2 6.3,95.5 ; P7.MTG2 7.5,96.7 ; P7.MTG2 7.5,94.31 ; 174.65,175.21 J2.MTG1 ; J2.MTG1 175.71,173.38 ; J2.MTG1 176.78,175.21 ; J2.MTG1 175.71,177.04 ; P3.D4 89.61,177.93 ; P3.D4 90.5,177.04 ; P3.D4 89.61,176.15 ; P3.D4 88.72,177.04 ; 180.21,173.15 J2.2 ; J2.2 180.21,175.28 ; J2.2 181.93,174.21 ; J2.2 178.5,174.21 ; 190.75,36.52 TP85.1 ; TP85.1 189.81,37.47 ; TP85.1 190.75,38.41 ; TP85.1 191.69,37.47 ; 6.3,109.98 P7.MTG1 ; P7.MTG1 7.5,108.79 ; P7.MTG1 7.5,111.18 ; P7.MTG1 8.69,109.98 ; P1.SH1 148.15,178.46 ; P1.SH1 146.87,177.18 ; P1.SH1 145.58,178.46 ; 10.33,125.03 J11.G2 ; J11.G2 11.86,126.56 ; J11.G2 10.33,128.09 ; J11.G2 8.8,126.56 ; 45.97,100.76 J12.7 ; J12.7 45.03,101.47 ; J12.7 46.91,101.47 ; J12.7 45.97,102.18 ; 196.72,22.43 J21.2 ; J21.2 195.78,23.37 ; J21.2 197.66,23.37 ; J21.2 196.72,24.31 ; P2.6 69.48,172.13 ; P2.6 67.27,169.92 ; P2.6 67.27,174.34 ; P2.6 65.06,172.13 ; 2.41,141.22 2.41,142.11 ; 2.41,142.11 3.3,142.11 ; 2.41,142.11 2.41,143 ; 2.41,142.11 1.52,142.11 ; P3.12 89.84,169.42 ; P3.12 88.65,170.61 ; P3.12 88.65,168.22 ; P3.12 87.45,169.42 ; P1.SH4 157.15,178.46 ; P1.SH4 154.58,178.46 ; P1.SH4 155.87,177.18
  L15-GND6 w0.508: P7.MTG1 8.69,109.98 ; P7.MTG1 7.5,111.18 ; P7.MTG1 6.3,109.98 ; P7.MTG1 7.5,108.79 ; J21.2 197.66,23.37 ; J21.2 195.78,23.37 ; J21.2 196.72,24.31 ; J21.2 196.72,22.43 ; J12.7 45.97,102.18 ; J12.7 45.03,101.47 ; J12.7 45.97,100.76 ; J12.7 46.91,101.47 ; J10.1 2.41,137.92 ; J10.1 1.52,137.03 ; J10.1 3.3,137.03 ; J10.1 2.41,136.14 ; J11.G3 10.33,120.59 ; J11.G3 8.8,119.06 ; J11.G3 10.33,117.53 ; J11.G3 11.86,119.06 ; 124.03,169.42 P4.11 ; P4.11 126.42,169.42 ; P4.11 125.22,168.22 ; P4.11 125.22,170.61 ; 2.41,138.68 J10.2 ; J10.2 3.3,139.57 ; J10.2 2.41,140.46 ; J10.2 1.52,139.57 ; P3.11 104.14,170.61 ; P3.11 102.95,169.42 ; P3.11 104.14,168.22 ; P3.11 105.33,169.42 ; TP85.1 191.69,37.47 ; TP85.1 189.81,37.47 ; TP85.1 190.75,38.41 ; TP85.1 190.75,36.52 ; 19,86.1 TP91.1 ; TP91.1 19,87.98 ; TP91.1 19.94,87.04 ; TP91.1 18.06,87.04 ; J12.1 46.91,93.85 ; J12.1 45.03,93.85 ; J12.1 45.97,93.14 ; J12.1 45.97,94.56 ; P1.SH3 155.87,170.74 ; P1.SH3 154.58,169.46 ; P1.SH3 157.15,169.46 ; P1.SH3 155.87,168.18 ; 217.68,153.03 J9.1 ; J9.1 217.68,154.81 ; J9.1 216.79,153.92 ; J9.1 218.57,153.92 ; TP2.1 190.12,79.05 ; TP2.1 189.18,78.11 ; TP2.1 190.12,77.16 ; TP2.1 191.06,78.11 ; 146.87,168.18 P1.SH2 ; P1.SH2 146.87,170.74 ; P1.SH2 145.58,169.46 ; P1.SH2 148.15,169.46 ; J20.5 212.9,12.57 ; J20.5 211.96,13.51 ; J20.5 211.02,12.57 ; J20.5 211.96,11.63 ; 175.71,173.38 J2.MTG1 ; J2.MTG1 174.65,175.21 ; J2.MTG1 175.71,177.04 ; J2.MTG1 176.78,175.21 ; 2.41,141.22 2.41,142.11 ; 2.41,142.11 3.3,142.11 ; 2.41,142.11 1.52,142.11 ; 2.41,142.11 2.41,143 ; 88.72,177.04 P3.D4 ; P3.D4 89.61,177.93 ; P3.D4 90.5,177.04 ; P3.D4 89.61,176.15 ; 7.5,94.31 P7.MTG2 ; P7.MTG2 8.69,95.5 ; P7.MTG2 6.3,95.5 ; P7.MTG2 7.5,96.7 ; 155.87,177.18 P1.SH4 ; P1.SH4 157.15,178.46 ; P1.SH4 154.58,178.46 ; 1.1,119.06 J11.G4 ; J11.G4 4.16,119.06 ; J11.G4 2.63,117.53 ; J11.G4 2.63,120.59 ; 205.94,15.11 J20.2 ; J20.2 206.88,16.05 ; J20.2 207.82,15.11 ; J20.2 206.88,14.17 ; 149.49,172.96 P1.4 ; P1.4 150.37,173.84 ; P1.4 151.24,172.96 ; P1.4 150.37,172.08 ; 0.96,76.2 P8.16 ; P8.16 2.16,77.39 ; P8.16 2.16,75 ; P8.16 3.35,76.2 ; 78.2,172.13 P2.5 ; P2.5 80.41,174.34 ; P2.5 82.62,172.13 ; P2.5 80.41,169.92 ; P4.12 110.92,169.42 ; P4.12 109.73,170.61 ; P4.12 109.73,168.22 ; P4.12 108.53,169.42 ; J12.4 46.91,97.66 ; J12.4 45.97,98.37 ; J12.4 45.97,96.95 ; J12.4 45.03,97.66 ; 23.11,159.97 TP12.1 ; TP12.1 24.05,160.91 ; TP12.1 22.17,160.91 ; TP12.1 23.11,161.85 ; J2.2 180.21,175.28 ; J2.2 180.21,173.15 ; J2.2 178.5,174.21 ; J2.2 181.93,174.21 ; P2.6 67.27,174.34 ; P2.6 69.48,172.13 ; P2.6 67.27,169.92 ; P2.6 65.06,172.13 ; J9.2 218.57,156.46 ; J9.2 217.68,155.57 ; J9.2 216.79,156.46 ; J9.2 217.68,157.35 ; P3.12 88.65,170.61 ; P3.12 89.84,169.42 ; P3.12 87.45,169.42 ; P3.12 88.65,168.22 ; P4.1 124.08,163.58 ; P4.1 123.19,162.69 ; P4.1 122.3,163.58 ; P4.1 123.19,164.47 ; P8.11 2.16,89.91 ; P8.11 0.96,88.72 ; P8.11 3.35,88.72 ; P8.11 2.16,87.53 ; J11.G2 11.86,126.56 ; J11.G2 10.33,125.03 ; J11.G2 10.33,128.09 ; J11.G2 8.8,126.56 ; J21.5 202.74,20.83 ; J21.5 201.8,19.89 ; J21.5 200.86,20.83 ; J21.5 201.8,21.77 ; 3.76,19.81 J1.2 ; J1.2 4.7,18.87 ; J1.2 5.64,19.81 ; J1.2 4.7,20.75 ; 1.1,126.56 J11.G1 ; J11.G1 2.63,128.09 ; J11.G1 4.16,126.56 ; J11.G1 2.63,125.03 ; J16.1 38.66,18.92 ; J16.1 37.21,20.37 ; J16.1 35.76,18.92 ; J16.1 37.21,17.47 ; 184.71,173.38 J2.MTG2 ; J2.MTG2 185.78,175.21 ; J2.MTG2 184.71,177.04 ; J2.MTG2 183.65,175.21 ; 110.69,176.15 P4.D4 ; P4.D4 110.69,177.93 ; P4.D4 111.58,177.04 ; P4.D4 109.8,177.04 ; J14.3 217.55,42.09 ; J14.3 217.55,40.21 ; J14.3 218.49,41.15 ; J14.3 216.61,41.15 ; 69.34,169.42 P2.4 ; P2.4 71.35,169.42 ; P2.4 70.34,170.42 ; P2.4 70.34,168.41 ; P7.MTG4 3.79,94.89 ; P7.MTG4 1.4,94.89 ; P7.MTG4 2.6,93.7 ; P7.MTG4 2.6,96.09 ; P7.MTG3 3.79,110.59 ; P7.MTG3 1.4,110.59 ; P7.MTG3 2.6,111.79 ; P7.MTG3 2.6,109.4 ; 102.11,162.69 P3.1 ; P3.1 102.11,164.47 ; P3.1 103,163.58 ; P3.1 101.22,163.58 ; 146.87,177.18 P1.SH1 ; P1.SH1 145.58,178.46 ; P1.SH1 148.15,178.46 ; 4.47,130.01 J11.6 ; J11.6 5.48,131.01 ; J11.6 5.48,129.01 ; 216.79,159 J9.3 ; J9.3 218.57,159 ; J9.3 217.68,159.89 ; J9.3 217.68,158.11
  BOTTOM w0.102: 152.39,135.25 C302.2 151.76,135.88 ; 148.21,135.37 C303.2 147.46,134.49
  BOTTOM w0.203: U62.B8 v1(131.07,26.97) ; U136.A1 v1(131.07,27.77) U136.B1 ; v2(143.51,138.76) U104.52 ; v1(112.98,95.63) RU15.8 ; v1(131.88,18.17) U62.N9 ; RU13.38 v1(135.42,116.87) ; U137.D8 111.52,25.77 v1(111.12,26.17) ; v1(82.18,99.92) 82.32,100.07 RU17.55 ; RU13.19 v1(135.42,109.72) ; U61.L9 v1(117.53,19.77) ; RU16.38 v1(90.33,99.72) ; RU18.49 139.65,99.88 v1(139.95,99.57) ; v1(95.83,95.61) RU16.8 ; v1(110.31,21.37) 110.71,21.77 U61.J1 ; v2(134.01,102.62) 134.15,102.47 RU18.38 ; v1(110.28,24.57) 111.11,24.57 U61.F2 ; v1(99.33,98.7) 98.83,99.2 RU16.55 ; U137.A8 v1(111.12,27.77) 111.52,27.38 U61.B2 ; U61.B8 v1(116.72,27.77) ; v1(116.72,27.77) U137.B1 ; v1(116.72,27.77) U137.A1 ; v1(139.95,92.2) 139.65,92.51 RU18.8 ; U62.J9 v1(131.88,21.37) ; U61.J9 v1(117.53,21.37) ; v1(140.42,108.58) 140.92,109.08 RU13.8 ; v1(96.33,98.7) 95.83,99.2 RU16.49 ; U61.L1 110.72,20.17 v1(111.12,20.57) ; v1(141.42,115.85) 140.92,116.35 RU13.49 ; v1(111.12,26.17) U137.C9 ; v1(111.12,26.17) U61.D1 ; RU18.55 142.65,102.12 v1(143.15,102.62) ; U62.J1 125.06,21.77 v1(124.66,21.37) ; v2(212.6,50.93) 212.74,51.07 J18.40 ; U62.F8 v1(131.07,24.57) ; v2(148.08,60.71) 149.35,60.71 157.65,69 157.65,70.61 158.66,71.63 v1(159,71.63) ; v1(125.48,20.57) 125.07,20.17 U62.L1 ; v1(125.47,24.57) 125.87,24.17 U62.F2 ; RU15.38 v1(107.48,99.72) ; v2(143.51,148.26) U104.33 ; RU17.38 v1(73.82,99.72) ; U92.8 73.53,172.14 v2(73.04,171.64) ; v2(212.6,51.65) 212.64,51.65 212.82,51.47 J18.38 ; U62.B2 125.87,27.38 v1(125.47,27.77) U136.A8 ; U61.N1 v1(110.31,18.17) ; v1(107.95,95.63) 107.48,95.16 RU15.19 ; RU16.19 v1(90.33,95.61) ; U62.N1 v1(124.66,18.17) ; U62.L9 v1(131.88,19.77) ; U62.D9 v1(131.87,26.17) ; RU17.8 v1(79.32,95.5) ; v1(117.53,18.17) U61.N9 ; v1(144.42,115.85) 143.92,116.35 RU13.55 ; U61.F8 v1(116.72,24.57) ; v1(134.15,92.26) RU18.19 ; RU17.49 v1(79.32,99.19) ; RU17.19 v1(73.82,95.61)
  BOTTOM w0.254: v1(122.81,30.19) 122.8,30.19 C569.2 ; v1(115.44,33.27) 115.32,33.15 C562.2 ; C658.2 v1(129.92,12.83) ; C663.2 v1(122.56,12.83) ; v2(116.71,139.57) 117.13,139.57 R380.1 ; C675.2 122.64,28.03 v1(122.81,28.19) ; J17.16 124.62,122.76 v2(124.33,122.48) ; v1(108.46,28.19) 108.29,28.03 C590.2 ; C196.2 v1(125.09,33.27) ; v1(125.47,26.17) 125.47,26.17 U136.D8 ; v1(125.47,26.17) 125.46,26.17 U136.C9 ; v1(125.47,26.17) 125.07,25.78 U62.D1 ; C686.2 v1(127,33.27) ; R390.1 117.09,137.67 v2(116.71,137.29) 117.09,136.91 R392.1 ; v2(153.44,155.32) 153.7,155.07 R337.2 ; R360.1 116.84,145.67 v2(116.46,146.05) 116.84,146.43 R359.1 ; C614.2 v1(131.83,33.27) ; C329.2 121.79,117.33 v2(122.07,117.05) ; v1(133.73,28.19) 133.9,28.03 C683.2 ; v2(129.16,122.43) 129.12,122.47 J17.25 ; v2(8.47,51.62) U128.17 ; C678.2 108.45,23.84 v1(108.46,23.84) ; RU20.19 v2(139.64,83.44) ; U100.4 127.18,155.91 v2(127.38,155.7) ; C682.2 125.11,17.14 v1(125.1,17.14) ; C668.2 v1(112.78,12.83) ; J17.7 120.12,122.7 v2(120.4,122.43) ; C556.2 v1(129.92,33.27) ; C290.2 v2(148.08,143.76) ; R376.1 116.84,140.84 v2(116.46,141.22) 116.84,141.6 R375.1 ; v1(108.46,30.19) 108.45,30.19 C608.2 ; C380.2 v2(109.09,75.44) ; R397.1 117.86,135.12 118.22,134.76 118.23,134.76 v2(118.62,134.37) ; C606.2 v1(120.02,26.54) ; v2(116.71,138.56) 116.84,138.43 R383.1 ; C656.2 v1(133.73,12.83) ; R694.2 v1(122.94,21.21) ; v1(117.52,26.17) 117.12,25.77 U61.D9 ; R378.2 v2(147.45,139.7) ; C679.2 v1(107.82,26.42) ; C641.2 117.94,16.59 v1(117.94,16.59) ; v1(133.73,18.32) 133.74,18.33 C684.2 ; v1(133.73,30.18) 133.74,30.19 C676.2 ; C201.2 v1(122.17,26.54) ; v2(120.52,158.88) 120.66,158.74 U96.5 ; v1(119.38,28.19) 119.55,28.03 C567.2 ; v2(150.85,155.32) 150.6,155.57 C277.2 ; C207.2 v1(117.22,33.27) ; C607.2 v1(122.17,24.62) ; U138.14 149.34,25 v2(149.22,24.89) v2(148.59,24.26) ; R310.1 v2(77.6,176.15) ; v2(121.16,134.37) 120.77,134.76 120.76,134.76 120.4,135.12 R396.1 ; R705.2 133.86,24 v1(133.6,24.26) ; U120.8 5.71,87.4 v2(5.64,87.33) ; R391.1 R382.1 146.69,138.56 v2(147.07,138.18) ; v1(119.38,30.18) 119.39,30.19 C557.2 ; v1(108.46,17.78) 108.29,17.95 C628.2 ; 129.16,115.57 v1(129.16,114.81) ; v1(109.05,16.5) 109.06,16.51 C680.2 ; C669.2 v1(112.01,12.83) ; C664.2 v1(119.38,12.83) ; R366.1 v2(116.2,143.64) ; v2(133.99,122.48) 133.62,122.84 J17.34 ; RU14.15 v2(59.28,112.78) ; v2(147.19,136.27) 146.65,136.27 R393.1 ; R630.2 v1(111.38,42.29) ; v2(159.82,43.7) RU23.8 ; C681.2 v1(128.27,12.83) ; RU20.10 v2(134.56,80.9) ; C666.2 v1(115.57,12.83) ; RU12.3 v2(148.21,149.21) ; C640.2 132.29,16.59 v1(132.3,16.59) ; C677.2 v1(113.79,12.83) ; C198.2 v1(112.39,33.27) ; v2(157.25,94.34) RU19.15 ; C660.2 v1(127.13,12.83) ; C674.2 119.55,18.33 v1(119.38,18.16) ; C671.2 v1(108.2,12.83) ; C605.2 v1(134.37,26.54) ; C570.2 v1(110.49,33.27) ; C659.2 v1(129.16,12.83) ; C531.1 v1(109.09,42.67) ; C667.2 v1(114.81,12.83) ; v2(63.27,86.82) EXP_P1.20 ; C661.2 v1(126.36,12.83)
  BOTTOM w0.305: C555.2 v2(14.99,29.08) ; v2(150.6,55.82) 150.53,55.75 U78.2 ; U117.6 29.56,103.84 29.34,104.06 v2(29.34,104.58) ; U109.2 v2(142.24,130.56) 142.75,130.56 142.89,130.41 U109.3 ; v2(146.3,62.36) 145.92,62.75 U77.7 ; v2(151.07,52.51) RU22.12 153.62,52.51 153.92,52.21 153.92,50.86 153.62,50.56 RU22.9 ; C596.2 68.42,25.63 v1(68.37,25.58) ; v2(43.29,36.86) 43.3,36.86 P15.16 ; v2(156.84,86.36) C252.1 155.57,85.6 154.93,84.96 U65.7 ; U84.1 145.78,66.18 v2(145.92,66.04) ; C444.2 94.3,58.65 v1(94.18,58.76) ; RU14.8 v2(55.38,109.72) ; U68.7 176.51,65.03 176.28,64.8 v2(176.28,64.01) ; v2(20.57,178.56) 20.57,177.55 C254.2 ; v1(89.38,50.76) 89.37,50.77 C501.2 ; C493.2 86.96,51.54 v1(87.78,52.36) 87.85,52.43 C489.2 ; C434.2 87.63,61.01 v1(86.98,60.36) 86.2,60.36 C436.2 ; C588.2 v2(90.58,26.46) 90.3,26.18 C655.2 ; R751.1 v2(217.04,90.17) ; EXP_P1.29 v1(57.02,90.81) ; C487.2 90.31,53.29 v1(90.18,53.16) ; C598.2 v2(83.95,24.74) ; v2(212.09,47.24) 211.85,47.01 U130.3 ; v2(84.18,161.81) 83.8,162.18 U93.6 ; C454.2 v2(14.73,56.77) ; v2(98.35,90.68) 98.3,90.73 R520.1 ; U99.4 130.42,155.2 v2(130.68,154.94) ; C216.2 v2(103.38,39.5) ; U67.2 v2(182.12,62.35) ; v1(90.98,57.96) 90.98,58.55 C449.2 ; C422.2 93.44,62.71 v1(93.38,62.76) ; U88.1 v2(168.91,99.95) ; C279.2 168.28,153.67 v2(168.02,153.92) ; v1(98.99,53.16) 99.06,53.24 C476.2 ; v2(171.2,26.54) 170.88,26.23 J19.30 ; EXP_P2.27 v2(75.38,117.67) ; U70.7 163.19,56.63 163.45,56.9 164.38,56.9 164.51,56.77 v2(165.86,56.77) ; v1(140.33,62.11) 140.3,62.14 137.63,62.14 136.02,63.75 136.02,67.44 134.49,68.96 v2(134.49,70.99) ; C441.2 88.49,60.28 v1(88.58,60.36) ; C447.2 92.15,58.39 v1(91.78,58.76) ; U74.2 171.84,85.08 v2(171.96,84.96) ; C459.2 92.71,56.24 v1(93.38,55.56) ; v2(137.79,122.48) 137.79,123.06 137.29,123.57 J17.40 ; C572.2 v2(59.44,29.57) C560.2 ; U143.3 v2(163.31,155.57) ; C432.2 92.9,60.68 v1(93.38,61.16) ; C515.2 16,50.04 v2(16.26,50.29) ; v2(140.08,154.81) 139.57,155.33 U97.4 ; R689.2 202.82,33.27 v2(203.07,33.53) ; J19.36 v2(172.38,26.5) ; C592.2 66.99,24.99 v1(67.57,25.58) ; C618.2 v2(83.69,19.91) C619.2 ; U128.11 4.57,54.6 4.45,54.72 v2(4.45,55.24) ; v1(98.18,57.96) 98.81,58.59 C442.2 ; v2(216.03,47.24) 215.79,47.01 U129.3 ; v2(173.1,80.26) 172.84,80.53 U74.7 ; U83.7 177.41,80.91 177.67,80.64 179.31,80.64 v2(179.32,80.63) ; v1(67.18,82.83) EXP_P1.10 ; v2(166.24,86.49) C234.1 165.65,85.72 165.02,85.09 164.59,85.09 164.33,84.83 U82.7 ; v1(121.5,18.07) 121.63,17.95 C627.2 ; C313.1 v2(140.34,130.05) ; C227.1 v2(180.47,96.27) ; v1(93.38,52.36) 94.06,51.69 C492.2 ; v2(199.14,68.33) R505.2 R503.2 ; C355.2 v2(121.03,102.62) ; C463.2 96.77,55.75 v1(96.58,55.56) 96.65,55.5 C472.2 ; R469.1 v2(217.04,79.5) ; R490.1 v2(217.04,74.42) ; J19.22 168.88,26.26 v2(169.04,26.42) ; U76.7 153.79,59.68 v2(154.05,59.94) ; v2(183.13,56.39) 183.13,55.87 183.22,55.79 183.22,55.2 183,54.98 U71.7 ; v1(95.78,60.36) 95.89,60.46 C433.2 ; C509.2 94.95,49.12 v1(94.98,49.16) ; U110.12 v2(77.74,124.44) ; v1(93.77,25.58) 93.9,25.45 C597.2 ; v1(91.78,53.16) 92.01,53.39 C486.2 ; C583.2 86.34,27.41 v1(86.57,27.18) ; C465.2 91.44,56.02 v1(90.98,55.56) ; C271.2 C270.2 150.62,156.84 v2(150.85,156.62) ; 93.85,56.36 93.85,56.83 v1(94.18,57.16) ; RU15.49 112.98,99.37 v2(113.41,98.93) ; C512.2 90.04,49.82 v1(90.18,49.96) 90.17,49.97 C498.2 ; C523.2 v2(197.99,45.09) ; 138.56,43.35 138.86,43.35 v2(139.7,44.2) ; 138.56,43.35 138.26,43.35 138.04,43.57 U86.2 ; 138.56,43.35 138.54,43.37 U86.1 ; v1(97.38,53.16) 97.49,53.06 C481.2 ; v2(163.07,96.39) 163.07,96.91 163.19,97.04 163.19,97.54 163.46,97.8 U88.7 ; P15.12 44.8,37.18 45.24,37.62 v2(45.23,37.62) ; RU21.15 10.01,18.01 v2(9.91,17.91) C470.1 ; v2(58.6,19.73) 59.12,19.73 C622.2 ; C558.2 v2(89.28,24.77) ; v1(92.97,27.98) 92.8,28.15 C573.2 ; U86.7 137.04,48.14 136.82,47.92 135.8,47.92 135.59,48.13 C230.1 v2(135,47.37) ; v1(61.17,27.18) 61.07,27.28 C586.2 ; v2(144.27,26.67) 144.27,26.16 C603.2 145.16,26.29 v2(145.16,26.67) ; v1(86.18,57.96) 85.49,58.65 C445.2 ; v1(86.57,27.98) 86.45,28.1 C574.2 ; C357.1 v2(202.31,68.96) ; R243.2 v2(60.07,49.02) ; C526.2 74.45,43.52 74.42,43.54 v2(74.42,44.41) ; RU21.8 v2(18.53,14.11) ; J19.17 v2(167.88,28.84) ; v1(68.37,26.38) 68.64,26.64 C582.2 ; v1(81.07,26.38) 81.34,26.64 C581.2 ; C553.2 68.58,30.59 v1(68.37,30.38) ; C320.2 213.74,133.71 v2(213.23,134.21) ; v1(68.37,29.58) 68.49,29.69 C566.2 ; v1(87.78,57.96) 87.78,58.65 C448.2 ; v2(21.95,124.85) 21.98,124.85 22.32,125.19 U115.29 ; C263.2 v2(55.12,161.04) ; C310.2 v1(151,130.45) ; U124.15 10.34,23.04 v2(9.91,22.61) 10.12,22.39 U124.14 ; C233.1 v2(179.71,83.57) ; v2(175.01,60.2) 175.01,61.11 175.24,61.35 U67.7 ; U78.7 v2(143.38,54.74) ; C631.2 v2(83.69,18.39) C630.2 ; RU23.15 v2(153.8,47.6) ; v2(150.62,68.96) 150.62,68.05 150.26,67.68 U84.7 ; C632.2 v2(70.99,18.39) C633.2 ; U73.7 176.41,57.67 v2(176.15,57.4) ; C356.2 124.08,103.12 v2(123.83,103.38) ; U89.1 178.8,92.85 v2(178.94,92.71) ; C232.1 v2(148.21,70.36) ; C451.2 96.49,58.67 v1(96.58,58.76) 96.55,58.8 C443.2 ; C473.2 92.29,55.27 v1(91.78,54.76) ; v1(148.79,133.22) 148.21,133.81 C303.2 ; EXP_P2.116 v2(118.59,111.43) ; v1(88.58,61.96) 88.58,62.55 C425.2 ; C591.2 79.81,25.12 v1(80.27,25.58) ; C554.2 81.41,30.71 v1(81.07,30.38) ; C599.2 v2(71.25,24.74) ; R506.2 v2(202.18,67.69) ; C529.2 v2(2.01,41.78) ; C600.2 v2(59.31,24) ; R465.1 v1(128.4,111.25) ; v2(161.54,86.36) C251.1 160.37,85.6 159.63,84.86 U66.7 ; v1(81.07,29.58) 81.67,29.58 C565.2 ; U75.7 179.46,76.59 v2(179.2,76.33) ; v1(88.58,53.16) 89.28,53.86 C477.2 ; v2(31.24,117.6) 31.19,117.65 U115.2 ; v1(86.98,54.76) 87.09,54.76 87.78,54.07 ; C331.2 v2(61.59,116.97) ; U83.1 175.91,85.21 v2(175.79,85.09) ; R326.2 v2(145.8,158.88) ; v2(183.51,95.76) 183.51,94.59 183.28,94.35 U89.7 ; v2(40.29,36.86) 40.3,36.86 40.3,35.15 P15.24 ; v1(98.18,50.76) 97.36,51.58 C494.2 ; C620.2 v2(70.99,19.91) C621.2 ; C514.2 v2(17.02,48.26) ; U121.3 v2(147.56,82.28) ; R752.1 v2(217.04,88.9) ; v2(159.89,50.8) 159.65,50.56 RU22.8 ; U138.14 151.24,25 v2(151.64,25.4) ; EXP_P2.26 v2(74.58,108.03) ; C609.2 202.82,28.07 v2(203.07,27.81) ; C226.1 v2(188.72,144.53) 188.59,144.65 187.83,144.65 187.57,144.39 U90.7 ; R750.1 v2(217.04,91.44) ; v1(68.45,95.63) 68.33,95.5 R515.2 ; v2(10.79,56.01) C471.2 10.79,54.11 10.42,53.74 U128.20 ; v2(136.4,74.42) 136.54,74.56 U85.1 ; C506.2 96.5,50.85 v1(95.78,51.56) ; U105.3 64.12,142 64.39,141.73 v2(64.77,141.73) U105.2 ; v1(87.78,55.56) 87.63,55.71 C460.2 ; R690.2 v2(83.57,22.83) ; C180.2 v2(73.41,40.89) ; C421.2 97.54,62.12 v1(97.38,61.96) 98.06,61.29 C437.2 ; C236.1 141.62,13.84 v2(141.74,13.72) ; v2(111.43,80.64) U122.2 ; v1(98.18,55.56) 98.68,56.06 C462.2 ; U85.7 138.04,72 138.3,72.26 139.36,72.26 139.49,72.14 C231.1 v2(140.08,72.9) ; R459.1 v2(217.04,83.31) ; C262.2 v2(60.96,163.19) ; EXP_P2.77 v2(99.39,117.17) ; v2(64.77,124.56) C316.1 ; R477.1 v2(217.04,78.23) ; R443.2 v1(215.52,128.56) ; U119.5 v2(149.17,98.86) ; R462.1 v2(217.04,82.04) ; v2(49.4,46.99) 49.2,47.19 U125.5 ; R695.2 v1(108.58,21.21) ; C500.2 92.21,50.39 v1(91.78,49.96) ; C571.2 v2(72.14,29.57) C559.2 ; U102.6 78.98,147.59 79.12,147.45 79.38,147.45 v2(79.63,147.19) ; R495.1 v2(217.04,73.15) ; U128.18 v2(9.12,54.43) ; C427.2 87.68,62.87 v1(87.78,62.76) ; v2(179.2,72.52) 179.46,72.78 U91.7 ; C510.2 98.05,49.02 v1(98.18,49.16) ; U131.3 v2(215.79,41.02) ; C634.2 v2(58.55,18.39) ; v2(135.51,154.94) 134.99,155.46 U98.4 ; U132.2 v2(8,38.48) U132.5 ; v2(9.78,20.19) 10.03,20.44 U124.11 ; v1(73.87,27.18) 73.77,27.28 C585.2 ; C595.2 81.12,25.63 v1(81.07,25.58) ; U125.12 49.2,55.68 v2(49.22,55.7) ; C228.1 v2(166.05,95.89) ; C524.2 v2(194.82,45.09) ; v2(176.28,67.69) 176.28,68.48 176.51,68.71 U69.7 ; v1(93.77,26.38) 93.81,26.33 C584.2 ; J19.35 v2(172.38,28.87) ; C513.2 88.14,49.52 v1(88.58,49.96) ; v2(140.2,58.03) 140.14,57.98 140.14,55.82 140.59,55.37 140.59,50.81 140.46,50.69 v2(140.46,50.16) ; 54.23,157.86 v2(55.12,157.86) ; v1(168.53,76.97) 168.4,76.83 R546.2 ; v2(163.45,87.25) 163.33,87.37 U82.2 ; U72.7 v2(172.47,61.47) ; C259.2 v2(55.12,164.21) ; U135.1 26.27,38.12 v2(26.42,37.97) ; v2(166.23,155.57) U142.3 ; U113.2 215.83,136.33 v2(216.15,136.65) 216.66,136.65 217.13,136.18 U113.4 ; R485.1 v2(217.04,75.69) ; C264.2 v2(60.33,161.04) ; C238.1 v2(145.67,53.47) ; R481.1 v2(217.04,76.96) ; C466.2 88.52,57.1 v1(88.58,57.16) ; C525.2 v2(213.23,46.74) ; 8,36.58 v1(8,37.47) ; C522.2 v2(202.44,45.09) ; C577.2 v2(198.5,30.1) ; R511.2 v2(129.67,89.92) ; v2(159.62,59.49) 159.62,59.49 159.42,59.69 R708.1 ; U71.2 v2(178.82,53.98) ; v1(67.18,90.81) EXP_P1.30 ; v1(169.93,78.11) 169.42,78.61 R706.2 ; EXP_P2.115 v2(118.59,117.93) ; U122.5 112.74,76.24 112.99,75.98 C379.2 v2(113.67,75.44) ; C426.2 90.86,62.64 90.74,62.64 90.18,62.08 v1(90.18,61.96) 90.3,61.85 C435.2 ; C359.2 v2(74.8,89.92) ; v1(168.28,26.42) 167.88,26.02 J19.18 ; R233.2 v2(66.55,56.77) ; R484.2 v2(5.5,107.66) ; R455.1 v2(217.04,84.58) ; C478.2 95.54,53.96 v1(94.98,53.96) 94.87,54.08 C482.2 ; R749.1 v2(217.04,92.71) ; EXP_P2.78 v2(99.39,111.43) ; RU22.15 v2(153.84,54.46) ; Q13.S v2(209.47,46.66) ; C276.2 v2(60.33,157.23) ; RU19.8 v2(163.31,90.43) ; C378.2 v2(79.25,72.11) ; C239.1 v2(145.8,61.47) ; R329.2 v2(169.46,157.57) ; R663.2 v2(156.46,33.27) ; C272.2 v2(60.96,159.38) ; U90.1 186.07,149.11 v2(186.31,149.35) 186.57,149.09 U90.2 ; R691.2 v2(70.87,22.83) ; U133.3 v2(215.79,37.1)
  BOTTOM w0.381: v2(147.7,113.28) 147.7,114.55 147.93,114.78 U116.3 ; C353.2 v1(68.83,104.9) ; C657.2 v1(132.72,14.86) ; U112.3 61.49,132.94 v2(61.47,132.97) ; v1(92.33,91.44) 92.33,90.56 C361.2 ; C304.2 v2(143.38,133.22) ; C665.2 v1(118.36,14.86) ; R541.1 v2(114.3,77.98) ; C302.2 v2(152.27,136.02) ; C67.2 v2(115.7,144.65) ; v2(60.83,127.78) U111.3 ; v1(77.34,105.81) U118.3 ; v2(145.16,120.52) C323.2 ; C670.2 v1(109.22,14.86) ; C662.2 v1(123.57,14.86)
  BOTTOM w0.406: EXP_P1.40 v1(66.67,94.79) ; v2(97.35,34.37) C551.2 v2(97.35,36.95) ; v2(86.68,33.76) C189.2 v2(86.68,36.34) ; v2(72.24,50.97) C497.2 v2(74.82,50.97) ; v2(49.28,31.5) 49.11,31.66 P15.41 P15.42 P15.43 P15.44 ; v2(112.88,59.22) C439.2 v2(115.46,59.22) ; EXP_P1.39 v1(57.53,94.79) ; v2(90.74,83.31) C369.2 v2(90.74,80.73) ; v2(109.45,59.22) C440.2 v2(112.03,59.22) ; EXP_P3.41 v2(123.06,93.27) EXP_P3.42 v2(123.06,87.25) EXP_P3.43 v2(123.06,81.13) EXP_P3.44 ; v2(116.31,50.08) C503.2 v2(118.89,50.08) ; v2(112.88,50.08) C504.2 v2(115.46,50.08) ; v2(74.82,48.81) C516.2 v2(72.24,48.81) ; EXP_P1.2 v2(63.25,79.63) ; EXP_P3.19 v2(118.62,86.82) ; C360.2 v2(136.14,90.3) ; EXP_P3.20 v2(127.64,86.82) ; EXP_P1.4 v2(63.27,80.42) ; EXP_P1.19 v2(60.93,86.82) ; EXP_P1.44 v2(62.1,81.03) EXP_P1.43 v2(62.1,87.12) EXP_P1.42 v2(62.1,93.29) EXP_P1.41
  BOTTOM w0.508: 217.61,135.19 U113.4 217.13,134 ; 171.96,109.87 C343.2 ; C343.2 171.96,111.11 ; C343.2 v1(173.23,110.49) ; Y6.2 55.19,50.48 ; Y6.2 54.48,51.23 ; Y6.2 54.48,49.78 v2(54.74,49.53) ; v2(53.72,123.44) 54.1,123.06 C699.2 ; v2(53.72,123.44) 54.23,123.95 C698.2 ; v2(53.72,123.44) 52.83,124.33 C697.2 ; C547.2 213.23,38.21 ; C547.2 213.86,37.59 ; C547.2 v2(212.47,37.59) ; 15.24,61.99 C419.2 ; C419.2 14.62,62.61 ; C419.2 16.19,62.61 v2(16.27,62.53) ; EXP_P2.131 v2(118.67,112.6) EXP_P2.132 ; EXP_P2.131 113.11,112.6 ; EXP_P2.131 115.76,113.12 ; v2(165.53,77.93) C375.1 164.13,77.72 C376.1 ; P7.MTG1 7.5,111.3 ; P7.MTG1 7.5,108.66 ; P7.MTG1 8.82,109.98 ; P7.MTG1 6.17,109.98 ; R711.1 148.7,103.63 ; R711.1 v2(147.32,103.63) ; R711.1 148.08,104.25 ; TP85.1 191.82,37.47 ; TP85.1 189.69,37.47 ; TP85.1 190.75,36.4 ; TP85.1 190.75,38.53 ; 27.81,160.29 R309.1 ; R309.1 27.81,161.53 ; R309.1 v2(28.83,160.91) ; 69.46,105.79 C353.2 68.83,106.41 ; R374.1 v2(88.32,140.79) ; C297.2 C296.2 v2(158.62,144.91) ; 168.9,152.91 C279.2 167.65,152.91 ; 122.54,84.02 EXP_P3.43 123.58,84.02 ; v2(173.74,132.59) v2(172.72,132.59) C301.1 ; 160.67,90.43 RU19.8 161.86,89.95 ; P2.5 80.41,174.47 ; P2.5 82.75,172.13 ; P2.5 80.41,169.79 ; P2.5 78.08,172.13 ; 142.54,85.47 v2(141.73,85.47) ; 142.54,85.47 143.17,85.47 ; 142.54,85.47 142.54,86.09 ; 25.92,164.97 C255.2 ; C255.2 26.8,165.23 v2(27.43,165.86) ; C255.2 27.67,164.97 ; v2(27.94,122.94) v2(26.8,121.79) 24.22,119.21 ; v2(27.94,122.94) 31.04,122.94 ; v2(27.94,122.94) 27.94,119.84 ; v2(27.94,122.94) 24.84,122.94 ; v2(27.94,122.94) 27.94,126.04 ; C280.2 v2(147.57,151.76) ; C280.2 146.81,151.14 ; C280.2 146.81,152.39 ; v2(177.93,50.93) 177.93,50.42 R605.2 ; 99.77,85.6 TP100.1 ; TP100.1 101.22,87.87 ; TP100.1 102.67,85.6 ; TP100.1 101.22,83.32 ; EXP_P2.129 104.52,113.12 ; EXP_P2.129 104.52,112.08 ; EXP_P2.129 102.82,112.6 ; EXP_P2.129 v2(106.48,112.6) EXP_P2.130 ; TP87.1 10.34,175.13 ; TP87.1 v2(8.89,177.67) ; TP87.1 7.44,175.13 ; TP87.1 v2(8.89,172.47) ; J9.2 217.68,157.48 ; J9.2 216.66,156.46 ; J9.2 218.69,156.46 ; J9.2 217.68,155.45 ; 1.27,110.59 P7.MTG3 ; P7.MTG3 2.6,111.91 ; P7.MTG3 2.6,109.27 ; P7.MTG3 3.92,110.59 ; P1.SH4 157.28,178.46 ; P1.SH4 154.46,178.46 ; P1.SH4 155.87,177.05 ; C623.2 205.36,26.53 ; C623.2 v2(206.25,25.91) ; C623.2 205.36,25.29 ; R405.2 v2(80.14,133.6) ; R405.2 80.76,132.59 ; R405.2 80.14,131.97 ; 2.16,74.88 P8.16 ; P8.16 2.16,77.52 ; P8.16 3.48,76.2 ; P8.16 0.84,76.2 ; 203.44,32.64 R689.2 202.82,32.02 ; 26.56,148.08 C286.2 ; C286.2 27.17,148.07 v5(26.17,148.07) ; C286.2 27.18,147.46 ; C286.2 27.18,148.7 ; U107.3 v2(84.44,137.4) ; U107.3 82.91,137.4 ; U107.3 83.54,136.86 ; C364.2 75.3,73.28 75.43,73.41 v2(76.05,73.41) ; C364.2 74.55,73.9 ; C364.2 73.93,73.28 ; R471.2 202.56,79.5 v2(201.93,79.5) ; P2.6 67.27,174.47 ; P2.6 64.93,172.13 ; P2.6 67.27,169.79 ; P2.6 69.61,172.13 ; 72.14,30.87 C559.2 71.59,30.33 ; C458.2 v2(52.32,46.23) ; 202.06,125.87 C713.1 202.68,126.49 ; 120.02,101.99 C355.2 120.02,103.24 ; P7.MTG2 8.82,95.5 ; P7.MTG2 6.17,95.5 ; P7.MTG2 7.5,94.18 ; P7.MTG2 7.5,96.83 ; 126.23,106.17 C707.2 125.6,106.79 ; P1.SH3 155.87,170.87 ; P1.SH3 155.87,168.05 ; P1.SH3 154.46,169.46 ; P1.SH3 157.28,169.46 ; 3.05,42.41 C529.2 3.05,41.16 ; J19.64 v2(177.26,27.65) J19.63 ; J19.64 179.19,27.13 ; J19.64 179.19,28.17 ; J19.64 180.77,27.65 ; C420.1 167.6,62.53 167.91,62.23 v2(168.53,62.23) R488.1 ; 178.07,108.82 R479.1 ; R479.1 178.07,107.84 ; R479.1 178.05,108.33 v2(177.16,109.22) 177.8,109.86 C345.2 ; J19.61 v2(164.88,27.65) J19.62 v2(171.2,27.65) J19.63 ; J19.61 163.06,28.17 ; J19.61 161.49,27.65 ; C377.1 v2(160.66,78.61) ; 216.32,41.88 U131.3 215.79,42.52 ; 59.91,27.28 C586.2 60.45,27.83 ; 109.73,168.1 P4.12 ; P4.12 108.41,169.42 ; P4.12 111.05,169.42 ; P4.12 109.73,170.74 ; Q12.S v2(44.02,170.69) 43.38,171.32 43.05,171.32 ; Q12.S 43.36,169.6 ; Q12.S 44.02,168.73 ; Q12.S 44.68,169.6 ; 123.9,169.42 P4.11 ; P4.11 125.22,170.74 ; P4.11 125.22,168.1 ; P4.11 126.54,169.42 ; P4.D4 111.71,177.04 ; P4.D4 109.68,177.04 ; P4.D4 110.69,178.05 ; R432.2 v2(97.84,120.83) ; 48.78,163.68 U94.3 ; U94.3 49.32,164.31 ; U94.3 v2(48.78,165.1) ; R606.2 176.28,50.55 v2(176.28,50.93) ; R606.2 175.27,50.16 ; R606.2 176.52,50.16 ; 14.99,30.47 C555.2 15.61,29.84 ; 64.12,143.15 U105.3 63.58,142.52 ; 120.54,51.92 C469.2 ; C469.2 v2(121.16,52.83) ; C469.2 121.78,51.92 ; 43.69,173.75 R307.2 ; R307.2 v2(42.8,174.37) ; R307.2 43.69,174.99 ; 64.97,95.3 EXP_P1.40 63.52,94.79 ; P1.SH1 148.28,178.46 ; P1.SH1 145.46,178.46 ; P1.SH1 146.87,177.05 ; v2(196.85,169.93) 198.25,168.53 ; 198.25,168.53 v2(198.25,169.93) ; 198.25,168.53 D2.1 196.52,168.35 v2(195.83,169.04) ; 198.25,168.53 v2(199.64,169.93) ; 19.68,115.82 v2(18.92,115.82) ; v2(30.1,132.46) 29.97,132.33 C308.2 ; C295.2 C294.2 v2(160.66,144.91) ; 177.56,50.16 R605.2 ; R605.2 178.8,50.16 ; 146.29,52.7 C238.1 145.67,52.08 ; 69.21,169.42 P2.4 ; P2.4 71.47,169.42 ; P2.4 70.34,170.55 ; P2.4 70.34,168.29 ; C410.1 v2(172.97,67.44) ; U114.2 v2(210.57,135.89) ; 217.55,23.13 R687.2 ; R687.2 218.17,23.75 ; R687.2 v2(217.55,24.64) ; 212.61,45.97 C525.2 213.86,45.97 ; J20.2 206.88,16.18 ; J20.2 207.95,15.11 ; J20.2 206.88,14.05 ; J20.2 205.82,15.11 ; C406.1 v2(172.97,69.09) ; 201.8,19.76 J21.5 ; J21.5 201.8,21.9 ; J21.5 200.74,20.83 ; 101.22,149.49 C284.2 ; C284.2 101.22,151.24 ; C284.2 v2(100.33,150.37) ; 172.35,15.37 R701.2 ; R701.2 v2(172.97,16.51) ; R701.2 172.97,14.74 ; 204.23,56.13 C467.2 ; C467.2 v2(204.85,57.28) ; C467.2 205.47,56.13 ; 45.97,100.63 J12.7 ; J12.7 44.91,101.47 ; J12.7 45.97,102.31 ; J12.7 47.04,101.47 ; C700.2 53.98,121.03 v2(53.72,121.28) 54.48,122.05 C696.2 ; 31.37,145.43 C287.2 ; C287.2 31.37,147.18 ; C287.2 v2(32.38,146.3) ; 1.27,94.89 P7.MTG4 ; P7.MTG4 2.6,96.22 ; P7.MTG4 3.92,94.89 ; P7.MTG4 2.6,93.57 ; J19.63 174.3,27.13 ; J19.63 174.3,28.17 ; R298.1 v1(15.75,176.28) ; R298.1 16.76,175.65 ; R298.1 17.39,176.28 ; 211.96,11.51 J20.5 ; J20.5 211.96,13.64 ; J20.5 210.9,12.57 ; J20.5 213.03,12.57 ; C401.2 v2(88.01,72.62) ; 10.33,124.9 J11.G2 ; J11.G2 10.33,128.21 ; J11.G2 8.67,126.56 ; J11.G2 11.98,126.56 ; 98.69,71.86 C393.2 ; C393.2 v2(99.31,72.62) ; C393.2 99.94,71.86 ; 78.13,106.34 U118.3 78.77,105.81 ; 123.71,166.75 C257.2 ; C257.2 v2(125.35,166.75) ; C257.2 124.33,167.37 ; 0.84,88.72 P8.11 ; P8.11 2.16,90.04 ; P8.11 3.48,88.72 ; P8.11 2.16,87.4 ; v2(69.95,68.96) 69.33,68.96 69.2,68.83 C386.2 ; 142.89,129.13 U109.3 143.43,129.77 ; C388.2 71.5,73.9 ; C388.2 70.88,73.28 ; C388.2 72.28,73.28 72.4,73.41 v2(73.03,73.41) ; P3.1 102.11,164.59 ; P3.1 103.12,163.58 ; P3.1 102.11,162.56 ; 197.74,12.2 TP93.1 ; TP93.1 v2(197.74,16.89) ; TP93.1 196.29,14.48 ; TP93.1 199.19,14.48 ; v2(137.79,164.08) 138.4,163.48 P14.6 138.4,162.48 ; 179.45,106.18 C352.2 ; C352.2 178.94,106.81 v2(178.56,106.43) ; C352.2 179.45,107.43 ; J11.G3 11.98,119.06 ; J11.G3 10.33,117.4 ; J11.G3 8.67,119.06 ; J11.G3 10.33,120.71 ; 122.52,157.1 U96.9 120.31,157.1 ; 1.4,139.57 J10.2 ; J10.2 2.41,140.59 ; J10.2 2.41,138.56 ; J10.2 3.43,139.57 ; C258.2 103.25,167.37 ; C258.2 v2(104.01,166.75) ; C258.2 102.63,166.75 ; 70.99,171.46 C256.2 ; C256.2 70.37,172.09 ; C256.2 v2(71.75,172.09) ; 31.41,32.28 P15.44 ; P15.44 32.98,32.8 ; P15.44 32.98,31.76 ; v2(207.39,51.69) 207.65,51.94 C488.2 ; RJ12.1 v2(122.3,178.44) ; v2(99.69,156.21) 99.69,156.84 R327.1 ; 64.52,112.08 EXP_P2.121 ; EXP_P2.121 64.52,113.12 ; EXP_P2.121 v2(66.5,112.6) EXP_P2.122 ; EXP_P2.121 v2(62.53,112.6) ; 10.03,91.06 10.52,91.55 ; 10.03,91.06 10.52,90.57 ; 10.03,91.06 v2(10.79,91.06) ; 216.76,49.45 J18.44 ; J18.44 215.86,50.11 ; J18.44 v2(217.81,50.11) ; R725.1 53.09,118.49 v2(53.72,119.13) ; J1.2 5.77,19.81 ; J1.2 4.7,18.74 ; J1.2 3.63,19.81 ; J1.2 4.7,20.88 ; v5(26.17,150.13) 26.91,150.13 C285.2 ; C325.1 180.47,121.22 ; C325.1 181.53,120.47 ; C325.1 180.29,120.65 v2(179.2,120.65) ; C325.1 179.4,120.47 ; C565.2 82.33,29.69 ; C565.2 81.79,30.24 ; C565.2 81.24,29.69 ; 84.52,112.08 EXP_P2.125 ; EXP_P2.125 84.52,113.12 ; EXP_P2.125 82.82,112.6 ; EXP_P2.125 v2(86.5,112.6) EXP_P2.126 ; C575.2 v2(143.19,28.7) ; EXP_P2.123 75.76,113.12 ; EXP_P2.123 v2(72.57,112.6) EXP_P2.122 ; EXP_P2.123 75.76,112.08 ; EXP_P2.123 v2(78.66,112.6) EXP_P2.124 ; v4(2.67,28.57) 2.54,28.45 C579.2 ; 86.45,29.29 C574.2 85.9,28.75 ; C350.1 R480.1 v2(168.15,106.43) ; C350.1 169.16,106.82 ; C350.1 169.79,107.44 ; J14.3 218.62,41.15 ; J14.3 216.48,41.15 ; J14.3 217.55,40.08 ; J14.3 217.55,42.22 ; 61.58,90.37 EXP_P1.42 62.62,90.37 ; C702.2 48.37,124.08 ; C702.2 47.75,124.7 ; C702.2 47.75,123.46 ; C367.2 75.3,68.83 75.43,68.96 v2(76.05,68.96) ; C367.2 74.55,69.46 ; C367.2 73.93,68.83 ; R681.2 v2(27.05,61.85) ; R710.2 v2(157.61,74.04) ; R710.2 156.98,72.77 ; R710.2 157.61,72.15 ; 88.59,177.04 P3.D4 ; P3.D4 90.63,177.04 ; P3.D4 89.61,178.05 ; 196.1,133.35 C711.2 196.98,134.1 ; P4.1 123.19,164.59 ; P4.1 124.21,163.58 ; P4.1 123.19,162.56 ; EXP_P2.126 v2(92.59,112.6) EXP_P2.127 ; EXP_P2.126 89.41,112.08 ; EXP_P2.126 89.41,113.12 ; C697.2 53.45,125.09 ; C697.2 52.21,125.09 ; 48.15,125.09 C691.2 ; C691.2 49.39,125.09 ; C691.2 48.77,124.47 ; C541.2 174.5,40.63 ; C541.2 175.12,40.01 ; C541.2 175.13,40.64 v4(175.13,41.27) ; C576.2 212.09,28.94 ; C576.2 212.09,27.7 ; C576.2 v2(210.95,28.32) ; 178.82,109.23 C345.2 ; C345.2 178.82,110.48 ; 167,38.23 167.5,37.74 ; 167,38.23 167.5,38.72 ; 167,38.23 v2(167.77,38.23) ; v2(18.8,56.64) 18.54,56.9 C453.2 ; R433.1 94.54,120.9 v2(94.68,120.76) ; 212.39,46.46 U130.3 211.85,45.82 ; C495.2 v2(75.95,50.52) ; R29.2 28.31,154.56 ; R29.2 27.06,154.56 ; R29.2 v2(27.69,155.45) ; 14.74,57.4 C454.2 15.37,56.78 ; 198.89,177.42 R350.2 ; R350.2 199.52,178.04 ; R350.2 v2(200.79,177.42) ; 121.92,40.02 R550.1 ; R550.1 121.3,40.64 ; R550.1 v2(121.92,41.66) R551.1 ; 25.78,141.49 25.78,142.11 ; 25.78,142.11 25.78,142.74 ; 25.78,142.11 25.16,142.11 ; 25.78,142.11 25.75,142.08 v2(25.75,141.2) ; C266.2 v2(41.02,164.85) ; C266.2 41.64,164.08 ; C266.2 40.4,164.08 ; 62.62,84.02 EXP_P1.43 61.58,84.02 ; v2(198.88,81.15) 197.99,81.15 197.99,79.88 ; C336.2 v2(28.32,113.67) ; 197.88,126.49 C712.2 198.5,125.87 ; 139.71,129.29 C313.1 140.96,129.29 ; J16.1 38.79,18.92 ; J16.1 37.21,20.5 ; J16.1 37.21,17.35 ; J16.1 35.64,18.92 ; 216.66,153.92 J9.1 ; J9.1 218.69,153.92 ; J9.1 217.68,154.94 ; J9.1 217.68,152.91 ; C387.2 v2(76.71,54.74) ; 71.59,28.8 C571.2 72.14,28.26 ; 196.72,32.64 v2(196.72,33.4) ; 196.72,32.64 196.72,32.02 ; 196.72,32.64 196.1,32.64 ; R314.2 48.46,171.32 v2(49.1,170.69) Q11.S ; 24.51,151.14 C281.2 ; C281.2 25.13,151.76 ; C281.2 24.51,152.56 v2(24.39,152.68) ; v4(173.1,41.27) 173.23,41.15 C542.2 ; P3.12 89.97,169.42 ; P3.12 88.65,170.74 ; P3.12 87.32,169.42 ; P3.12 88.65,168.1 ; C479.2 v2(54.99,54.23) ; 207.95,46.66 Q13.S ; Q13.S 208.61,45.8 ; Q13.S 208.61,47.52 ; C617.2 v2(96.39,20.07) ; 215.79,45.82 U129.3 216.32,46.46 ; C405.2 v2(119.51,41.15) ; C405.2 120.89,41.15 ; C405.2 120.27,40.53 ; C450.2 121.56,59.31 v2(121.92,59.31) ; v2(76.71,56.93) 76.87,56.77 C389.2 ; C305.1 v2(72.01,133.22) ; C305.1 71.25,133.85 ; C305.1 71.25,132.6 ; RJ13.1 v2(101.35,178.44) ; 54.23,161.66 C263.2 53.61,161.04 ; C340.2 13.08,113.41 v2(12.83,113.67) ; C182.2 v2(92.58,39.27) ; 2.63,117.4 J11.G4 ; J11.G4 0.97,119.06 ; J11.G4 2.63,120.71 ; J11.G4 4.28,119.06 ; 61.62,128.31 U111.3 62.26,127.78 ; 122.54,95.25 EXP_P3.41 ; EXP_P3.41 123.06,96.95 ; EXP_P3.41 123.58,95.25 ; Y6.4 v2(53.21,53.09) ; Y6.4 53.21,51.38 ; Y6.4 52.5,52.13 ; C391.2 v2(101.85,72.62) ; C254.2 20.83,178.17 ; C254.2 20.83,176.42 ; C254.2 21.58,177.29 ; 147.56,80.8 U121.3 147.02,81.43 ; C692.2 v2(49.4,121.28) ; 28.78,102.36 v4(30.99,102.36) 33.2,102.36 ; 5.48,128.88 J11.6 ; J11.6 4.35,130.01 ; J11.6 5.48,131.14 ; C542.2 173.72,40.5 ; C542.2 172.74,40.5 ; R412.2 v2(80.64,130.05) ; 15.24,46.37 C520.2 ; C520.2 14.62,46.99 ; C520.2 15.86,46.99 ; 80.19,149.48 v2(77.98,149.48) 75.77,149.48 ; J18.41 v2(213.77,60.45) ; U139.4 v2(30.9,57.7) ; U139.4 30.1,56.12 ; U139.4 30.1,59.27 ; R579.2 15.49,59.69 v2(16.26,60.45) ; v2(120.78,23.77) 120.54,24 R704.2 ; 196.72,22.3 J21.2 ; J21.2 195.66,23.37 ; J21.2 196.72,24.44 ; J21.2 197.79,23.37 ; 126.15,155.91 U100.4 126.61,155.09 ; R670.2 209.28,33.93 ; R670.2 209.28,34.91 ; R670.2 v1(209.55,34.42) ; EXP_P2.124 80.64,113.12 ; EXP_P2.124 82.35,112.6 ; EXP_P2.124 80.64,112.08 ; 85.01,164.08 v2(82.8,164.08) 80.59,164.08 ; 54.75,125.6 R732.1 55.37,126.23 ; 19.68,114.81 v2(18.92,114.81) ; C540.2 178.31,40.63 ; C540.2 177.82,40.49 177.82,40.62 v4(177.16,41.27) ; C540.2 177.69,40.01 ; C540.2 178.93,40.01 ; C398.2 v2(92.96,72.62) ; 167,37.08 v2(167.77,37.08) ; 167,37.08 167.5,36.59 ; 167,37.08 167.5,37.58 ; 107.7,49.01 C508.2 ; C508.2 107.7,50.25 ; C508.2 v2(108.46,49.63) ; R704.2 120.02,24.55 ; R704.2 119.47,24 ; C370.2 71.5,69.46 ; C370.2 72.25,68.83 72.38,68.96 v2(73,68.96) ; C370.2 70.88,68.83 ; C480.2 v2(54.99,48.39) ; C480.2 54.23,47.76 ; C480.2 54.23,49.01 ; 12.43,20.44 U124.11 11.24,19.96 ; J9.3 217.68,160.02 ; J9.3 218.69,159 ; J9.3 217.68,157.99 ; J9.3 216.66,159 ; 37.87,31.76 P15.43 37.87,32.8 ; 213.77,49.45 J18.43 ; J18.43 v2(212.72,50.11) ; J18.43 214.67,50.11 ; U106.3 v2(84.44,140.45) ; C309.2 v2(26.54,132.46) ; P1.SH2 146.87,170.87 ; P1.SH2 148.28,169.46 ; P1.SH2 146.87,168.05 ; P1.SH2 145.46,169.46 ; 61.58,95.25 EXP_P1.41 ; EXP_P1.41 62.62,95.25 ; EXP_P1.41 62.1,96.95 ; C535.2 v2(83.06,39.27) ; 60.71,117.59 C331.2 60.08,116.97 ; 83.54,142.71 U103.3 ; U103.3 82.91,143.24 ; U103.3 v2(84.44,143.24) ; C306.2 v2(142.49,131.95) ; EXP_P2.127 95.76,113.12 ; EXP_P2.127 95.76,112.08 ; EXP_P2.127 v2(98.67,112.6) EXP_P2.128 ; C327.2 v2(38.23,119.38) ; R700.2 v2(183.77,16.51) ; R700.2 183.77,15.13 ; R700.2 183.15,15.75 ; TP91.1 20.07,87.04 ; TP91.1 17.93,87.04 ; TP91.1 19,88.11 ; TP91.1 19,85.98 ; v2(96.39,18.16) C629.2 ; C488.2 209.28,51.94 ; C488.2 208.66,51.32 ; C288.2 25.91,146.93 ; C288.2 25.29,146.3 ; C288.2 v2(25.91,145.41) ; C368.2 v2(76.71,61.09) ; J12.1 47.04,93.85 ; J12.1 45.97,94.69 ; J12.1 44.91,93.85 ; J12.1 45.97,93.01 ; 24.65,49.02 C646.1 ; C646.1 25.27,48.4 ; C646.1 v2(25.27,49.78) ; 98.69,53.06 C481.2 98.07,52.44 ; 99.57,156.35 R327.1 ; R327.1 100.19,156.97 ; R327.1 98.95,156.97 ; C624.2 v1(213.74,17.91) ; C624.2 213.12,18.8 ; C624.2 214.36,18.8 ; U95.3 44.24,164.31 ; U95.3 v2(43.7,165.1) ; U95.3 43.7,163.68 ; RJ14.3 v2(156.97,146.05) ; RJ14.3 156.35,146.81 ; RJ14.3 156.97,147.43 ; 5.84,36.7 6.33,36.21 ; 5.84,36.7 5.35,36.21 ; 5.84,36.7 5.22,36.7 ; 5.84,36.7 v2(5.84,35.94) ; 5.84,36.7 6.46,36.7 ; R679.2 v2(29.08,61.85) ; C424.2 v2(108.46,62.59) ; R488.1 167.91,62.99 ; R488.1 169.15,62.99 ; 190.11,144.53 C226.1 189.48,145.15 ; 60.86,132.22 U112.3 62.13,132.22 ; 79.25,73.5 C378.2 78.63,72.87 ; 104.14,168.1 P3.11 ; P3.11 105.46,169.42 ; P3.11 102.82,169.42 ; P3.11 104.14,170.74 ; 54.9,108.26 RU14.8 55.38,107.07 ; 23.11,159.84 TP12.1 ; TP12.1 22.05,160.91 ; TP12.1 24.18,160.91 ; TP12.1 23.11,161.98 ; C363.2 v2(76.71,59.69) ; C268.2 101.22,160.13 ; C268.2 v2(100.33,159.26) ; C268.2 101.22,158.38 ; R407.2 v2(88.14,131.95) ; 122.31,152.91 C278.2 ; C278.2 124.07,152.91 ; C278.2 v2(123.19,152.02) ; 50.43,117.47 C704.2 51.05,118.1 ; 27.18,149.24 C285.2 ; C285.2 26.56,149.86 ; C285.2 27.18,150.48 ; C705.2 162.67,156.84 ; C705.2 v2(162.05,156.15) ; C705.2 161.43,156.84 ; R683.2 v2(25.02,61.85) ; 48.44,169.6 Q11.S ; Q11.S 49.76,169.6 ; Q11.S 49.1,168.73 ; C452.2 v2(108.46,57.63) ; 123.58,79.15 EXP_P3.44 123.06,77.44 ; 2.68,15.11 TP92.1 ; TP92.1 v2(7.37,15.11) ; TP92.1 4.95,13.66 ; TP92.1 4.95,16.56 ; 202.82,29.45 C609.2 203.44,28.83 ; 193.8,19.32 R697.2 ; R697.2 193.18,19.94 ; R697.2 v2(194.69,19.94) ; U127.2 v2(196.85,51.44) ; C362.2 v2(109.47,91.31) ; 4.57,51.83 U128.11 4.08,53.03 ; C358.2 v2(151,98.68) ; C307.2 v2(155.83,132.21) ; 60.68,94.79 EXP_P1.39 59.23,95.3 ; C416.2 16,65.66 v2(16.26,65.91) ; C342.2 16.24,111.63 ; C342.2 15.62,112.26 ; C342.2 14.99,111.63 v2(14.86,111.76) ; 150.37,171.96 P1.4 149.36,172.96 ; C543.1 v2(206.25,87.76) ; 64.15,125.35 C316.1 65.39,125.35 ; 5.21,29.22 C564.2 ; C564.2 5.21,30.47 ; C564.2 v2(5.97,29.84) ; C423.2 v2(164.34,60.96) ; C587.2 v2(154.69,28.57) ; 190.12,77.04 TP2.1 ; TP2.1 191.19,78.11 ; TP2.1 189.05,78.11 ; TP2.1 190.12,79.17 ; 53.61,157.86 54.23,157.86 54.23,158.48 ; R604.2 180.47,50.42 v2(180.47,50.93) ; R604.2 180.1,50.16 ; R604.2 181.34,50.16 ; 167.78,76.07 R546.2 169.02,76.07 ; 179.08,82.8 C233.1 180.33,82.8 ; J11.G1 4.28,126.56 ; J11.G1 2.63,124.9 ; J11.G1 0.97,126.56 ; J11.G1 2.63,128.21 ; C394.2 v2(97.92,72.62) ; 149.48,156.2 C277.2 149.48,154.95 ; R714.1 v2(50.55,120.27) ; R446.1 176.66,119.24 ; R446.1 176.28,119 v2(176.28,119.63) ; R446.1 176.03,118.62 ; 45.97,96.82 J12.4 ; J12.4 44.91,97.66 ; J12.4 47.04,97.66 ; J12.4 45.97,98.5 ; C244.1 172.47,61.48 v2(172.47,61.47) ; C244.1 173.09,62.23 ; C244.1 172.47,62.85 ; 115.46,47.98 C521.2 ; C521.2 116.7,47.98 ; C521.2 v2(116.08,48.9) ; v2(162.69,144.78) C292.2 C293.2 ; EXP_P2.130 112.07,112.6 ; EXP_P2.130 109.41,113.12 ; EXP_P2.130 109.41,112.08 ; C314.2 v2(38.23,127.89) ; R411.2 v2(65.79,130.18) ; 54.75,118.75 C695.2 ; C695.2 55.37,118.12 ; C695.2 55.37,119.37 ; 19.68,130.68 v2(18.92,130.68) ; 10.03,88.77 v2(10.79,88.77) ; 158.62,162.69 v2(159.64,162.69) ; C273.2 120.13,157.23 ; C273.2 v2(118.11,157.23) ; C273.2 119.25,156.48 ; 167,39.37 167.5,38.88 ; 167,39.37 167.5,39.86 ; 167,39.37 v2(167.77,39.37) ; 163.31,157 U143.3 162.77,156.36 ; 147.29,148.67 RU12.3 146.66,149.21 ; C326.2 v2(209.3,129.16) ; C326.2 210.68,129.16 ; C326.2 210.06,128.54 ; v2(77.6,58.93) 77.47,58.8 C371.2 ; 151.27,50.56 RU22.9 152.46,50.07 ; 123.58,90.37 EXP_P3.42 122.54,90.37 ; R379.1 v2(104.52,138.68) ; C291.1 v2(67.56,143.13) ; v2(106.68,130.05) C311.2 ; C330.2 v2(18.54,118.11) ; 203.2,44.46 C522.2 203.82,45.09 ; 1.4,137.03 J10.1 ; J10.1 2.41,136.02 ; J10.1 3.43,137.03 ; J10.1 2.41,138.05 ; 60.34,160.4 C264.2 60.96,161.02 ; R662.2 v2(1.02,33.53) ; 49.11,32.8 P15.41 50.69,32.28 ; C468.2 v1(195.58,57.15) ; C275.2 v2(83.95,157.1) ; R731.1 52.07,118.62 v2(51.56,119.13) ; 146.05,121.15 C323.2 146.67,120.52 ; C386.2 68.45,69.46 ; C386.2 67.83,68.83 ; 122.42,117.98 C329.2 121.17,117.98 ; J18.42 v2(217.81,59.61) ; J18.42 216.76,60.27 ; J18.42 215.86,59.61 ; 158.75,59.07 R708.1 158.13,59.69 ; v2(106.68,138.94) C299.2 ; C299.2 107.57,139.81 ; C299.2 107.57,138.06 ; 134.07,79.45 RU20.10 134.56,78.26 ; 69.41,112.08 EXP_P2.122 ; EXP_P2.122 69.41,113.12 ; 145.8,60.08 C239.1 146.42,60.71 ; C593.2 v2(210.82,24) ; C593.2 210.2,24.77 ; C593.2 210.82,25.39 ; C328.2 v2(15.75,118.87) ; 54.23,164.83 C259.2 53.61,164.21 ; C214.1 v2(151.64,26.16) v2(151.64,25.4) ; 60.96,155.97 C276.2 ; C276.2 60.96,157.21 ; C276.2 60.34,156.59 ; C344.1 v2(185.55,109.86) ; 8,35.95 8,36.58 7.38,36.58 ; 60.96,161.68 C262.2 60.34,162.31 ; C550.2 2.54,35.31 v1(2.16,34.92) ; C550.2 3.3,34.43 ; C550.2 3.3,36.18 ; 75.01,124.44 U110.12 76.2,123.96 ; v2(160.4,61.33) C418.2 160.83,62.15 v2(161.42,62.74) 162,62.15 C417.2 ; 211.53,165.23 TP86.1 ; TP86.1 v2(212.98,162.56) ; TP86.1 212.98,167.39 v2(212.47,167.89) ; TP86.1 214.43,165.23 ; 45.48,164.08 C265.2 ; C265.2 v2(46.1,164.85) ; C265.2 46.72,164.08 ; C300.1 v2(177.8,132.59) v2(176.78,132.59) ; C502.2 v2(75.95,49.25) ; EXP_P2.128 102.35,112.6 ; EXP_P2.128 100.65,113.12 ; EXP_P2.128 100.65,112.08 ; C346.2 v2(30.99,110.36) ; R357.2 v2(81.66,148.08) ; 184.16,50.04 C507.2 ; C507.2 v1(184.78,51.07) ; C507.2 184.78,49.42 ; R476.1 v2(185.55,108.84) ; 74.6,174.24 U92.11 72.47,174.24 ; C446.2 v2(108.46,58.9) ; 1.4,142.11 2.41,142.11 ; 2.41,142.11 2.41,143.13 ; 2.41,142.11 2.41,141.1 ; 2.41,142.11 3.43,142.11 ; R373.2 v2(91.62,140.89) ; C701.2 50.91,125.09 ; C701.2 49.67,125.09 ; C701.2 50.29,122.68 v2(50.55,122.43) ; 68.58,31.76 C553.2 69.13,31.22 ; R719.2 49.28,119.25 v2(49.4,119.13) 49.4,118.36 49.02,117.98 C693.2 ; v3(149.22,99.82) v3(148.26,99.82) U119.9 ; C399.2 v2(91.82,72.62) ; C351.2 v2(137.41,106.93) ; R447.1 v2(15.75,117.86) ; v2(55.37,124.84) R722.1 ; 157.24,43.7 RU23.8 158.44,43.22 ; 16.01,114.3 C337.2 ; C337.2 v2(16.64,115.06) ; C337.2 17.26,114.3 ; C341.1 v2(202.06,80.52) ; C187.2 v2(96.39,39.27) ; C532.2 203.33,41.52 ; C532.2 v2(202.44,40.89) ; C532.2 203.33,40.27 ; 197.74,30.72 C577.2 197.74,29.48 ; C511.2 v2(75.95,47.98) ; R305.1 v2(69.47,177.16) ; EXP_P2.132 120.65,113.12 ; EXP_P2.132 122.35,112.6 ; EXP_P2.132 120.65,112.08 ; 136.64,90.57 C360.2 136.64,91.55 ; R693.2 96.14,21.97 v2(96.14,21.97) ; 60.34,158.5 C272.2 60.96,157.87 ; 147.19,144.39 C290.2 147.19,143.14 ; 168.41,78.61 R706.2 169.04,77.99 ; C693.2 48.4,117.47 ; C693.2 49.64,117.47 ; 72.61,27.28 C585.2 73.15,27.83 ; C315.2 v2(38.23,126.24) ; 48.37,118.24 C703.2 47.75,117.61 ; C431.2 v2(108.46,61.19) ; R351.2 v2(81.79,152.15) ; 10.9,53.03 U128.20 10.42,51.83 ; C483.2 v2(108.46,56.36) ; C324.2 v2(18.54,119.76) ; R424.2 v2(88.14,127.76) ; v2(121.16,56.6) C496.2 ; C438.2 v2(108.46,60.05) ; C539.2 v2(94.49,39.27) ; C395.2 v2(96.65,72.62) ; C490.2 198.37,51.82 v2(198.12,51.56) ; C490.2 200.01,51.82 ; C490.2 199.39,51.19 ; 129.15,106.17 C706.2 128.52,106.79 ; v2(29.21,151.26) 28.83,150.88 C282.2 ; R640.1 v2(155.07,38.99) ; 54.1,118.1 C694.2 54.72,117.47 ; C534.2 v2(84.96,39.27) ; 148.98,157.99 C271.2 149.61,157.37 ; 124.7,102.62 C356.2 124.08,101.99 ; 129.16,116.19 129.16,115.57 129.78,115.57 ; C298.2 v2(77.98,141.48) ; 69.09,30.24 C566.2 69.63,29.69 ; C415.2 v2(17.02,63.88) ; C397.2 v2(94.36,72.62) ; 19.68,129.67 v2(18.92,129.67) ; C519.2 v2(75.95,51.79) ; U126.2 v2(206.12,51.56) ; C267.2 v2(126.62,158.62) ; R404.2 v2(28.96,133.1) ; C261.2 v2(156.34,163.7) ; C392.2 v2(100.71,72.62) ; R666.2 v1(180.21,33.15) ; 22.48,151.76 v2(22.48,152.53) ; C317.2 v2(18.54,125.86) ; 157.24,50.56 RU22.8 158.44,50.07 ; C181.2 v2(86.87,39.27) ; R595.1 v1(196.85,57.15) ; C461.2 v2(108.46,53.95) ; R744.2 v2(199.64,125.22)
  BOTTOM w0.635: 200.18,168.35 D2.1 198.25,167.03
  BOTTOM w0.762: 179.63,133.96 C300.1 175.97,133.96 ; 170.89,133.96 C301.1 174.55,133.96
  vias: v1(31.37,147.7) v1(136.7,60.07) v1(137.54,60.07) v1(138.38,60.07) v2(2.16,90.76) v2(2.16,74.14) v2(2.54,124.46) v2(2.54,121.16) v2(3.65,88.89) v2(3.65,88) v2(3.65,86.29) v2(3.65,83.99) v2(3.65,81.39) v2(3.65,78.64) v2(3.65,76.93) v2(3.65,76.04) v2(3.68,85.09) v2(4.32,83.06) v2(4.57,75.18) v2(4.83,80.52) v2(4.83,76.33) v2(6.48,125.22) v2(6.48,120.4) v2(6.86,80.52) v2(6.86,76.33) v2(9.53,80.52) v2(9.53,76.33) v2(10.41,102.26) v2(10.41,100.79) v2(10.41,99.31) v2(10.54,122.81) v2(10.67,97.28) v2(11.43,107.44) v2(11.94,105.28) v2(11.94,96.01) v2(13.34,124.71) v2(13.34,123.19) v2(13.34,122.43) v2(13.34,120.9) v2(13.72,81.41) v2(13.72,75.06) v2(14.1,125.35) v2(14.1,120.27) v2(15.11,124.71) v2(15.11,123.19) v2(15.11,122.43) v2(15.11,120.9) v2(15.24,107.31) v2(15.24,94.11) v2(15.75,78.11) v2(16.13,81.41) v2(16.13,75.06) v2(16.26,69.22) v2(16.26,58.67) v2(16.26,53.59) v2(16.76,104.65) v2(16.76,97.28) v2(17.65,103.89) v2(17.78,100.71) v2(17.78,69.22) v2(17.78,65.91) v2(17.78,60.45) v2(17.78,58.67) v2(17.78,53.59) v2(17.78,50.29) v2(17.91,78.36) v2(17.91,75.74) v2(17.91,74.42) v2(18.03,81.28) v2(19.3,94.49) v2(19.56,107.06) v2(19.56,104.78) v2(19.56,96.77) v2(19.68,100.71) v2(25.65,122.94) v2(25.65,121.79) v2(26.8,125.22) v2(26.8,124.08) v2(26.8,122.94) v2(27.94,125.22) v2(27.94,124.08) v2(27.94,121.79) v2(27.94,120.65) v2(29.08,124.08) v2(29.08,122.94) v2(29.08,121.79) v2(29.08,120.65) v2(30.23,124.08) v2(30.23,121.79) v2(49.4,123.44) v2(51.56,123.44) v2(52.58,122.3) v2(52.58,120.27) v2(77.22,149.99) v2(77.22,148.97) v2(78.74,149.99) v2(78.74,148.97) v2(82.04,164.59) v2(82.04,163.58) v2(83.57,164.59) v2(83.57,163.58) v2(89.66,159.89) v2(91.69,159.89) v2(132.33,66.29) v2(132.33,53.85) v2(132.59,68.96) v2(132.59,67.94) v2(132.59,52.2) v2(132.59,51.18) v2(133.6,67.18) v2(133.6,52.96) v2(134.62,37.59) v2(135.38,65.28) v2(135.38,54.86) v2(136.4,37.34) v2(136.65,65.28) v2(136.65,54.86) v2(138.56,65.28) v2(138.56,54.86) v2(139.83,65.28) v2(139.83,54.86) v2(141.48,67.18) v2(141.48,52.96) v2(142.24,58.17) v2(142.49,68.96) v2(142.49,67.94) v2(142.49,52.2) v2(142.49,51.18) v2(142.88,66.29) v2(142.88,53.85) v2(143,58.17) v2(146.43,13.72) v2(147.19,13.72) v2(147.96,24.89) v2(147.96,23.62) v2(147.96,13.72) v2(148.72,13.72) v2(149.22,23.62) v2(149.48,13.72) v2(150.24,13.72) v2(150.75,31.37) v2(150.75,30.61) v2(150.75,29.34) v2(150.85,154.03) v2(151,20.83) v2(151,20.07) v2(151.26,18.92) v2(151.26,18.16) v2(152.15,156.62) v2(152.15,155.32) v2(152.15,154.03) v2(153.29,12.32) v2(153.29,11.56) v2(153.44,156.62) v2(153.44,154.03) v2(157.35,19.05) v2(157.86,14.86) v2(159.38,17.65) v2(159.38,16.89) v2(159.38,16.13) v2(161.8,52.96) v2(163.58,171.96) v2(164.47,52.96) v2(166.37,165.74) v2(166.37,163.96) v2(167.51,164.72) v2(168.66,165.74) v2(168.66,163.96) v2(173.35,116.84) v2(173.35,114.94) v2(173.35,113.03) v2(175.26,116.84) v2(175.26,114.94) v2(175.26,109.22) v2(177.16,116.84) v2(177.16,114.94) v2(177.16,113.03) v2(177.16,111.12) v2(191.77,102.36) v2(191.77,96.01) v2(193.04,102.36) v2(193.04,96.01) v2(194.31,102.36) v2(194.31,96.01) v2(199.14,64.01) v3(5.26,89.41) v3(5.59,136.02) v3(6.17,89.41) v3(6.86,144.27) v3(6.86,136.65) v3(8.13,144.91) v3(8.13,143.64) v3(8.13,137.92) v3(8.13,136.65) v3(9.4,144.91) v3(9.4,143.64) v3(9.4,137.92) v3(9.4,136.65) v3(10.67,144.27) v3(10.67,136.65) v3(11.94,136.02) v3(120.98,157.1) v3(121.84,157.1) v3(136.4,39.17) v3(136.4,38.3) v3(147.4,99.82) v3(207.14,150.5) v3(207.14,144.15) v3(207.77,149.22) v3(207.77,147.96) v3(207.77,146.69) v3(207.77,145.41) v3(209.04,147.96) v3(209.04,146.69) v3(214.76,147.96) v3(214.76,146.69) v3(215.39,149.22) v3(215.39,145.41) v3(216.03,147.96) v3(216.03,146.69) v4(2.67,27.56) v4(4.19,28.57) v4(4.19,27.56) v4(8.26,141.99) v4(8.26,140.72) v4(8.26,139.45) v4(9.53,141.99) v4(9.53,140.72) v4(9.53,139.45) v4(18.67,31.5) v4(18.67,30.48) v4(19.56,30.99) v4(20.45,31.5) v4(20.45,30.48) v4(30.23,102.87) v4(31.75,102.87) v4(73.08,174.24) v4(73.99,174.24) v4(88.14,155.45) v4(90.04,153.54) v4(90.04,151.64) v4(90.04,149.73) v4(90.04,147.83) v4(91.95,153.54) v4(91.95,151.64) v4(91.95,149.73) v4(93.85,153.54) v4(93.85,151.64) v4(93.85,149.73) v4(93.85,147.83) v4(94.49,135.13) v4(95.76,153.54) v4(95.76,147.83) v4(96.39,133.22) v4(96.39,131.32) v4(96.39,129.41) v4(96.39,127.51) v4(98.3,133.22) v4(98.3,131.32) v4(98.3,129.41) v4(100.2,133.22) v4(100.2,131.32) v4(100.2,129.41) v4(100.2,127.51) v4(102.11,133.22) v4(102.11,127.51) v4(110.87,78.74) v4(110.87,77.72) v4(111.76,78.23) v4(112.65,78.74) v4(112.65,77.72) v4(161.67,72.01) v4(161.67,70.99) v4(161.67,69.98) v4(161.67,68.96) v4(161.67,67.94) v4(162.69,70.99) v4(162.69,69.98) v4(162.69,68.96) v4(163.7,72.01) v4(163.7,70.99) v4(163.7,69.98) v4(163.7,68.96) v4(163.7,67.94) v4(164.72,72.01) v4(164.72,70.99) v4(164.72,69.98) v4(164.72,68.96) v4(164.72,67.94) v4(165.74,72.01) v4(165.74,70.99) v4(165.74,69.98) v4(165.74,68.96) v4(165.74,67.94) v4(173.1,45.34) v4(173.1,44.32) v4(173.1,43.31) v4(173.1,42.29) v4(174.12,45.34) v4(174.12,44.32) v4(174.12,43.31) v4(174.12,42.29) v4(174.12,41.27) v4(175.13,45.34) v4(175.13,44.32) v4(175.13,43.31) v4(175.13,42.29) v4(176.15,45.34) v4(176.15,44.32) v4(176.15,43.31) v4(176.15,42.29) v4(176.15,41.27) v4(177.16,45.34) v4(177.16,44.32) v4(177.16,43.31) v4(177.16,42.29) v4(210.57,147.83) v4(210.57,146.56) v4(211.84,147.83) v4(211.84,146.56) v4(213.11,146.56) v5(24.12,150.13) v5(24.12,149.44) v5(24.12,148.76) v5(24.12,148.07) v5(24.8,150.13) v5(24.8,149.44) v5(24.8,148.76) v5(24.8,148.07) v5(25.49,150.13) v5(25.49,149.44) v5(25.49,148.76) v5(25.49,148.07) v5(26.17,149.44) v5(26.17,148.76)
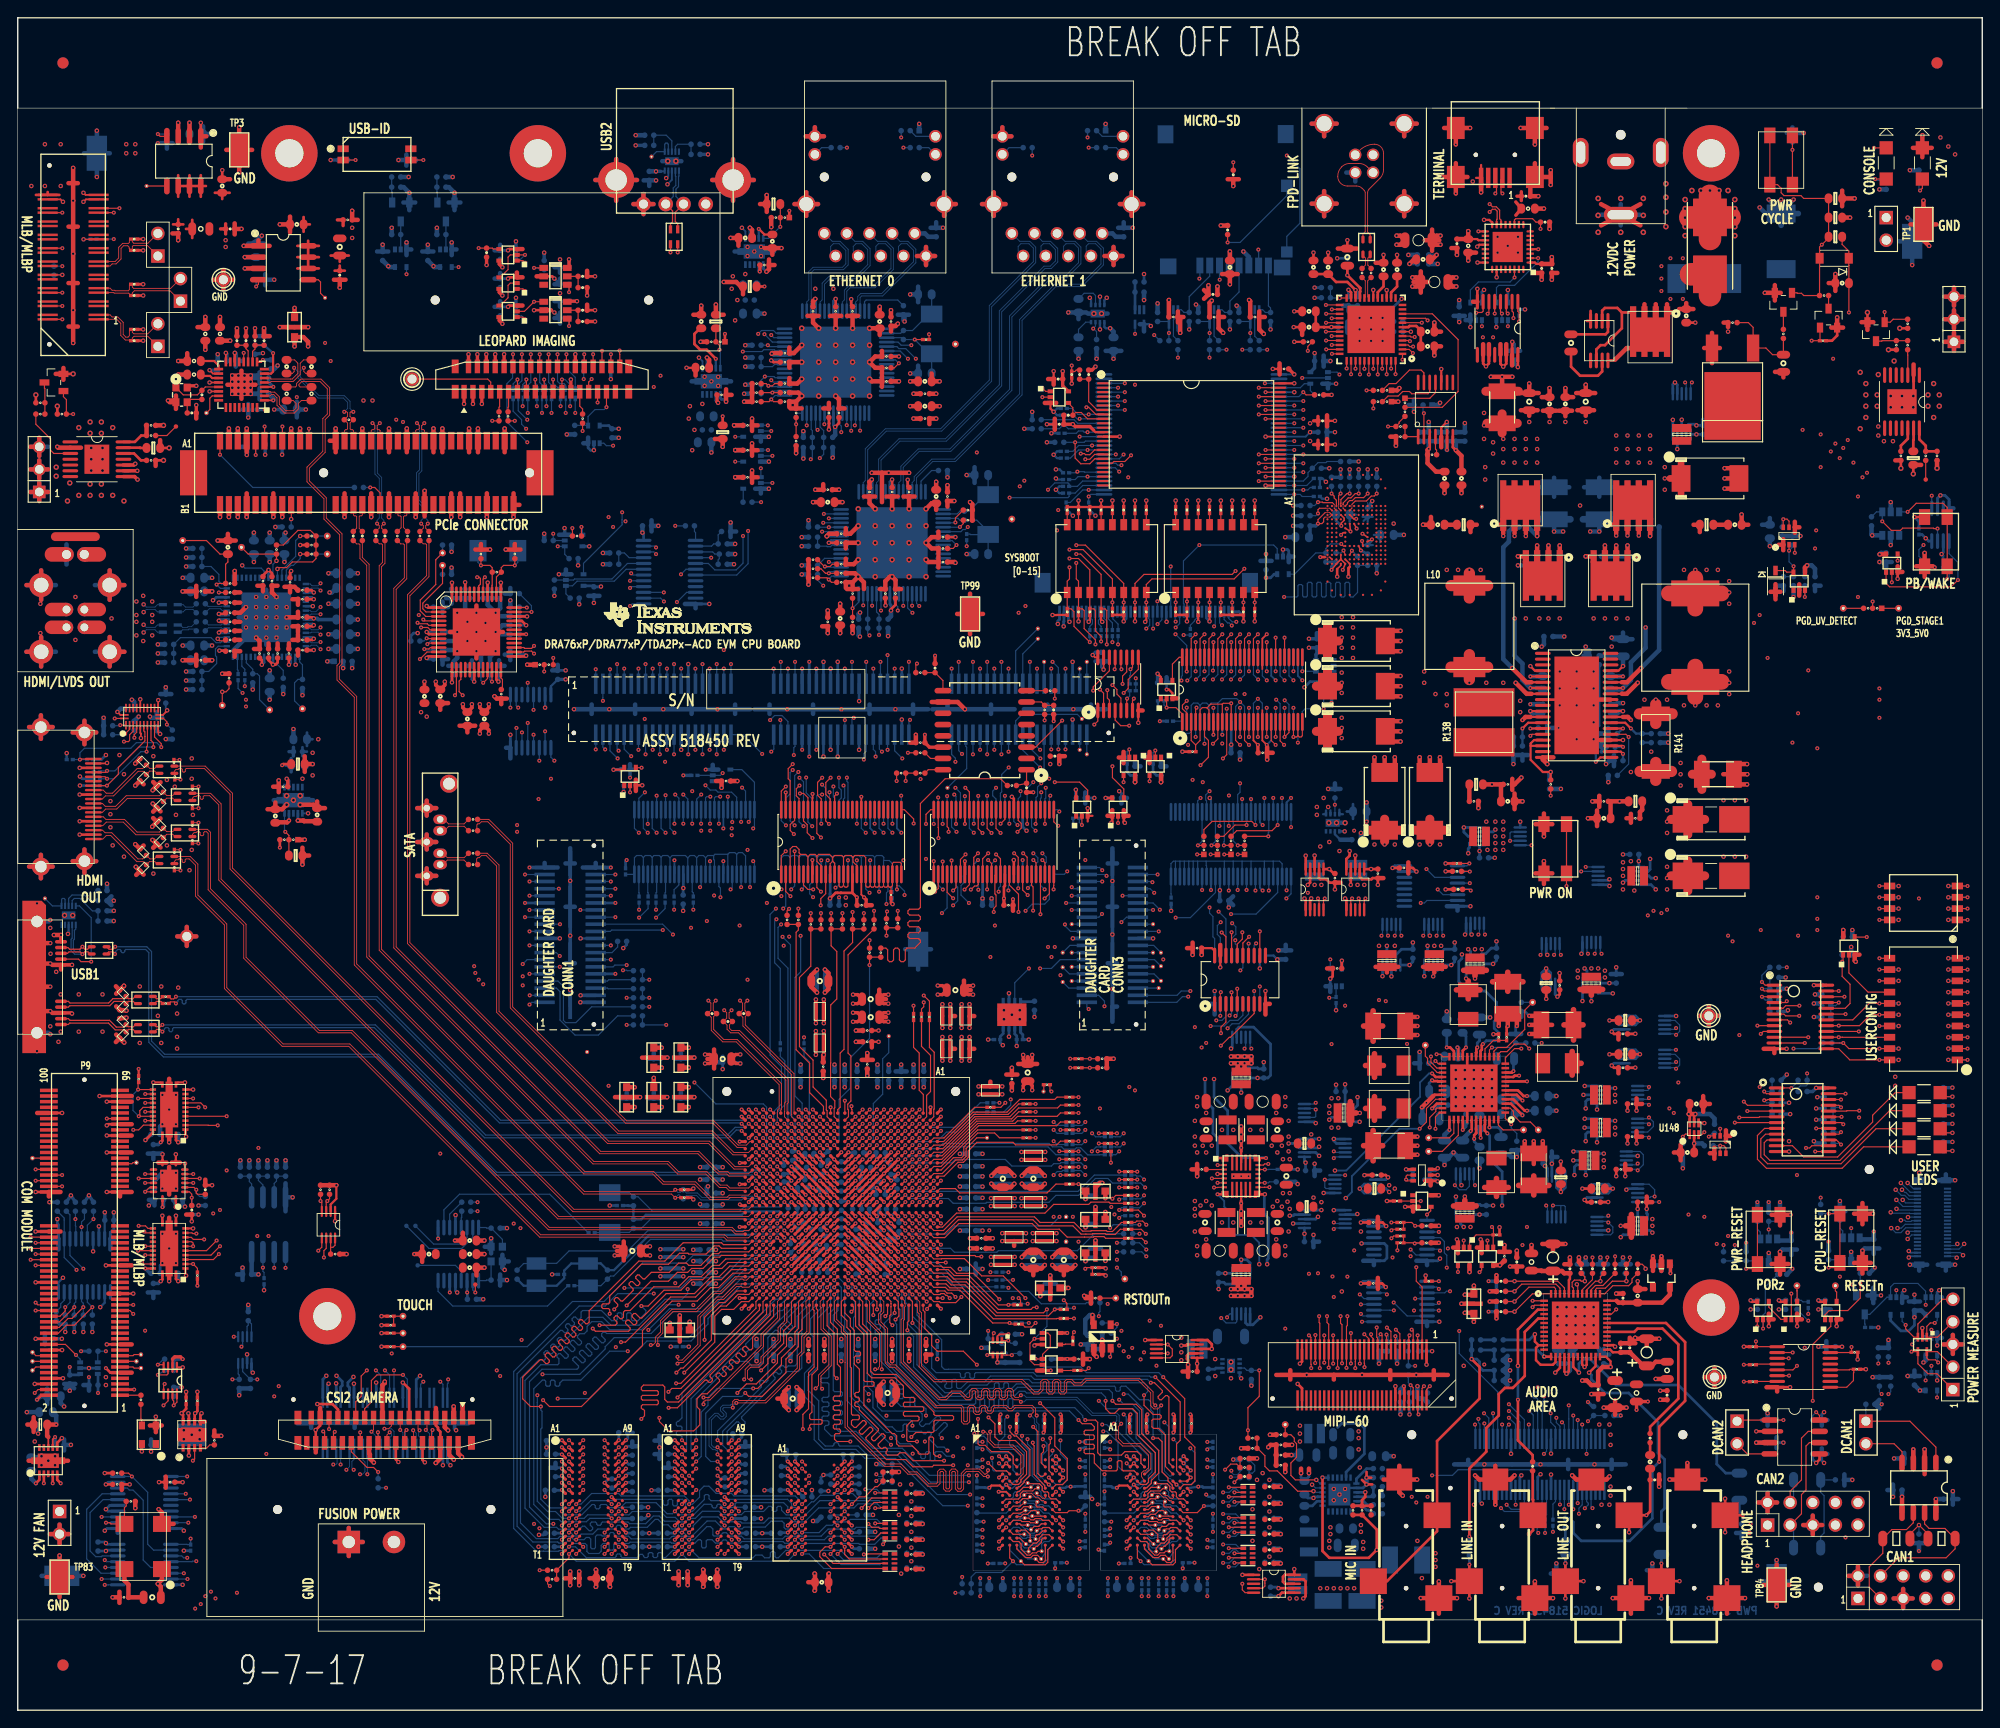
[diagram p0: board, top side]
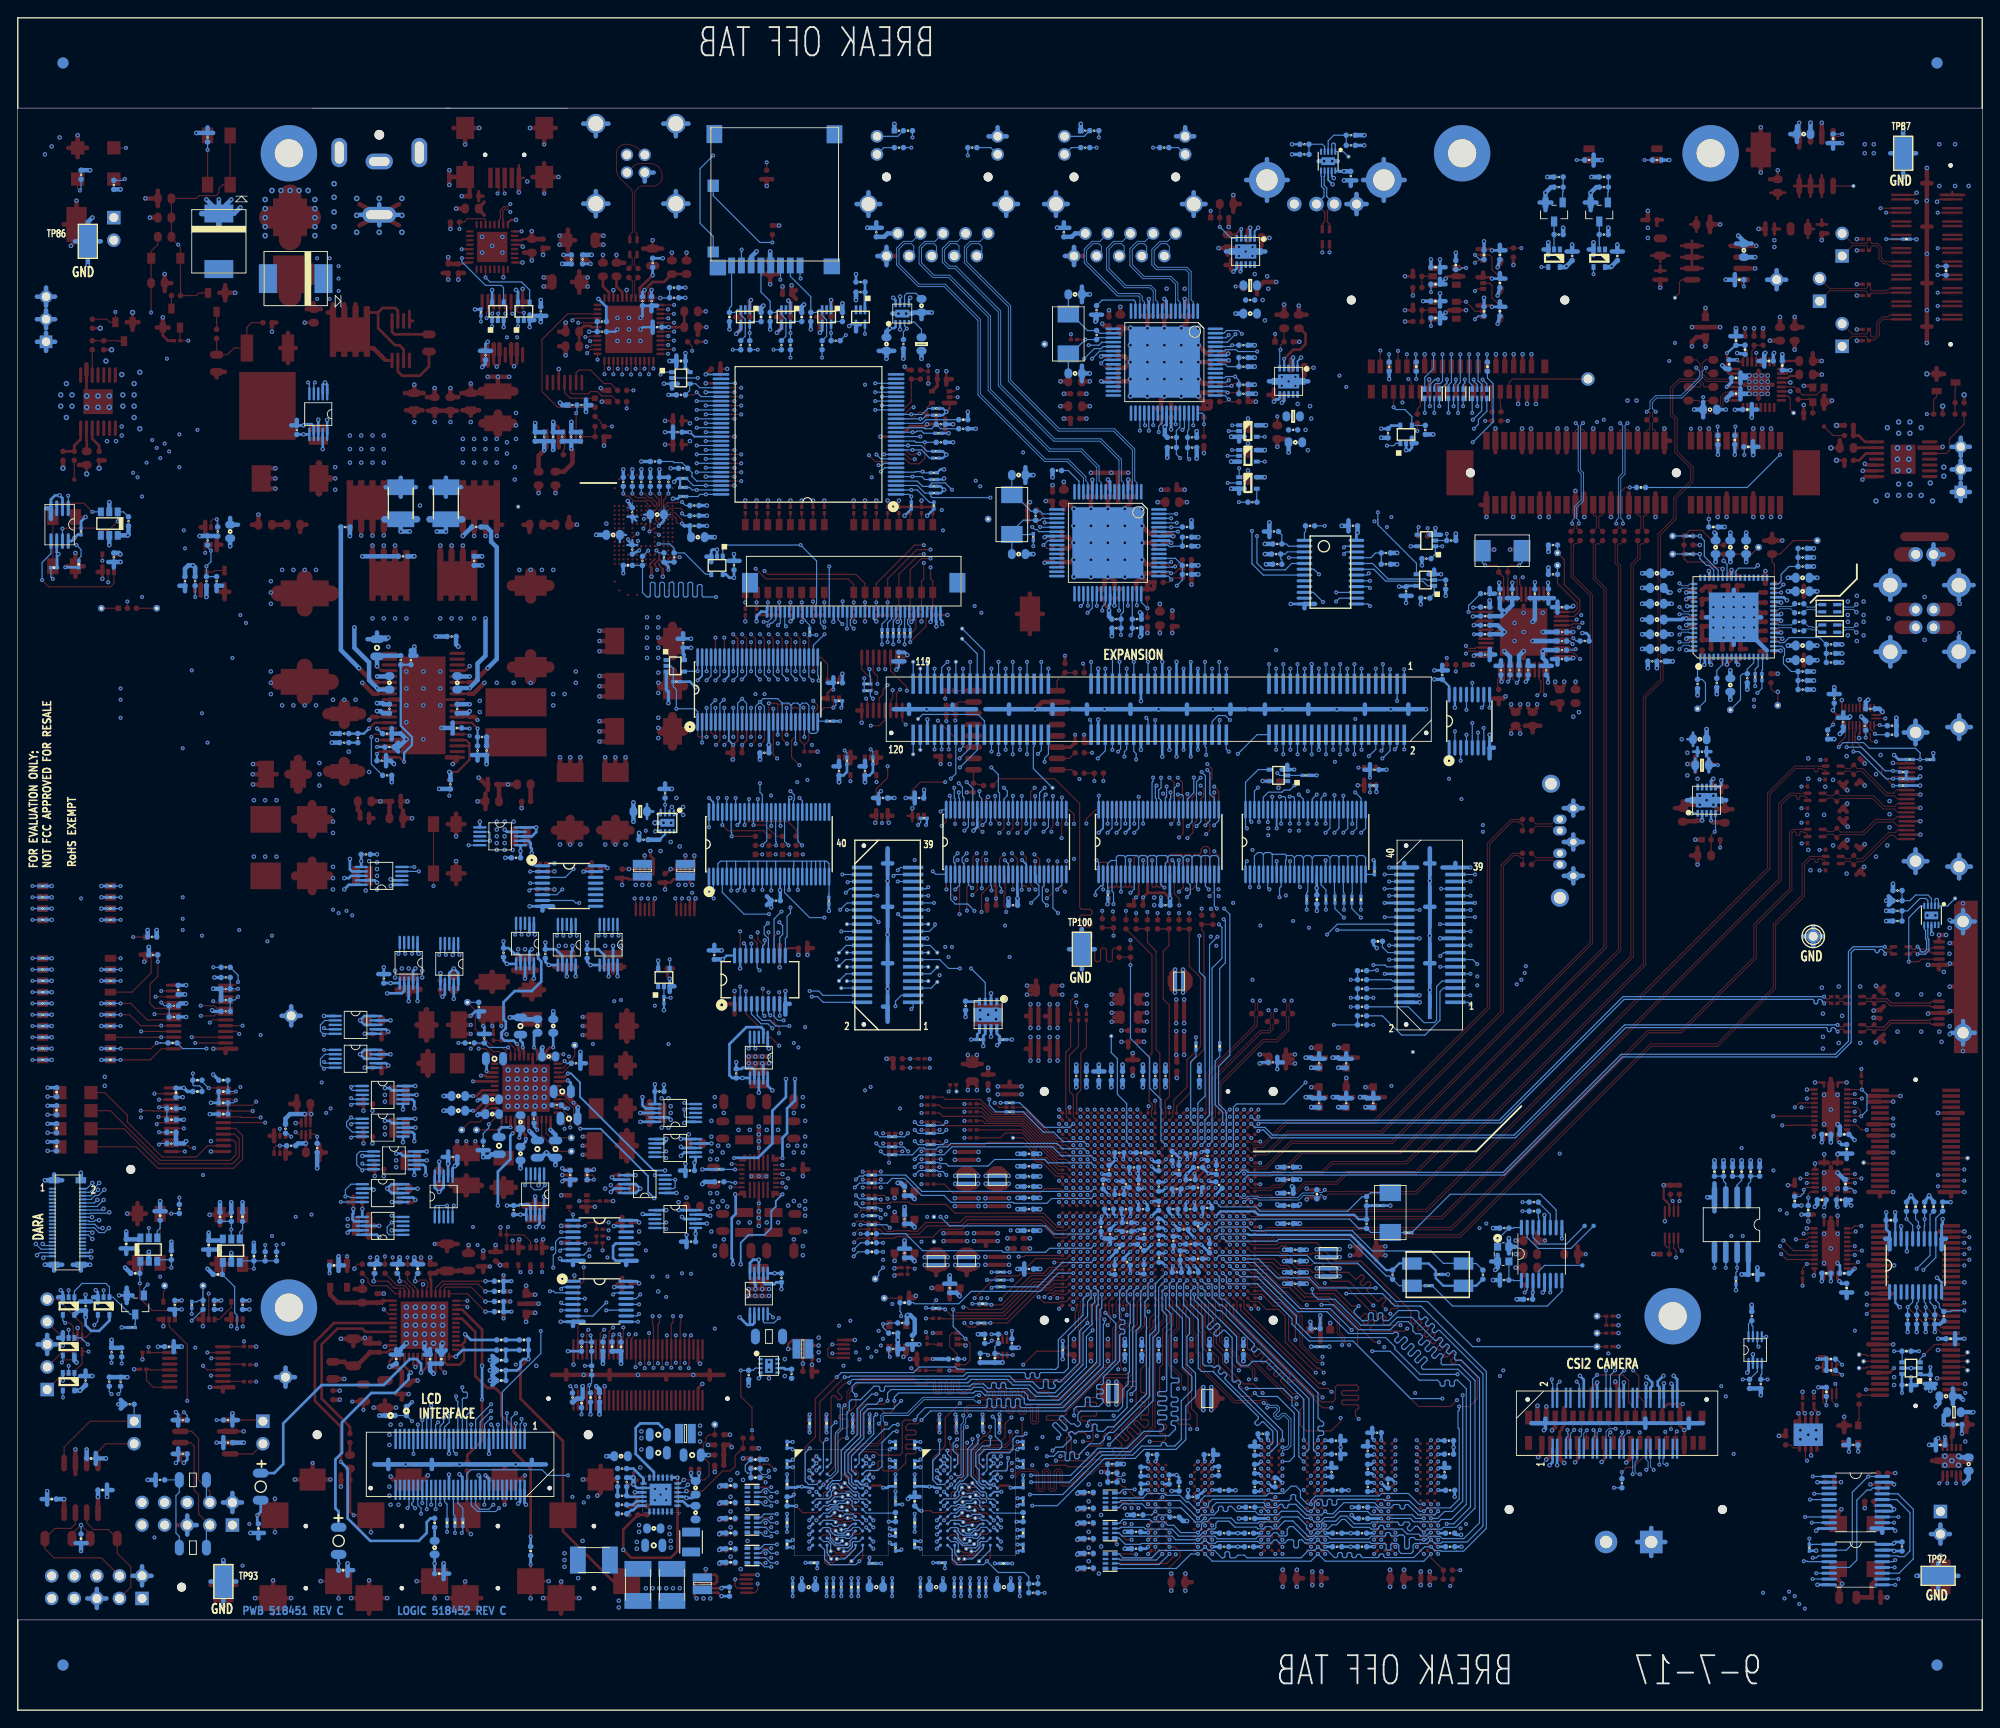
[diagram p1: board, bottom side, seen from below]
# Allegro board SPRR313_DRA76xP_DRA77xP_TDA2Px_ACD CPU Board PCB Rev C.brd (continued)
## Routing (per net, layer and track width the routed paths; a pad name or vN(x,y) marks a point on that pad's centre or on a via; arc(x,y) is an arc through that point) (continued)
VBUS_USB1: length 4.2
  TOP w0.381: C5.1 23.37,167.2 ; C5.1 22.8,166.62 ; C5.1 23.37,166.05
  TOP w0.432: v2(4.86,87.2) P8.1
  TOP w0.508: v2(4.06,87.2) v2(4.86,87.2)
  BOTTOM w0.508: 43.05,172.47 v2(43.94,172.47)
  vias: v2(23.37,165.35) v2(23.37,164.59)
VBUS_USB2: length 6.8
  TOP w0.381: 36.58,166.99 C1.1 35.93,167.64
  L12-SIGNAL w0.508: 76.34,169.42 P2.1 77.34,170.42
  BOTTOM w0.203: v2(72.9,172.34) 73.13,172.58 U92.9 ; 72.29,173.1 72.66,173.1 U92.10
  BOTTOM w0.381: v2(71.75,173.1) 72.29,173.1
  BOTTOM w0.508: R312.1 v2(48.9,172.47) ; C256.1 v2(71.75,173.1)
  vias: v2(37.59,166.75) v2(37.59,165.61)
VCC_1V1USB: length 17.2
  TOP w0.305: v1(57.15,121.03) 57.14,121.04 U141.30 ; v2(45.97,118.36) 46.15,118.54 U141.12 ; v2(45.97,124.21) 46.15,124.03 U141.1 ; U141.18 v2(51.31,115.7) ; U141.34 v2(57.25,123.04) ; U141.45 50.31,126.85 v2(50.29,126.87)
  TOP w0.406: v2(48.01,115.7) 48.01,115.32 C708.1 46.99,115.32 v2(46.99,115.7) ; L33.1 v2(45.72,115.7)
  TOP w0.508: RJ16.1 v2(57.28,117.6)
  BOTTOM w0.305: v2(51.31,115.7) 51.05,115.96 C704.1 ; v2(45.97,118.36) 46.1,118.24 C703.1 ; C699.1 57.22,123.06 v2(57.25,123.04) ; C702.1 46.1,124.08 v2(45.97,124.21) ; C700.1 v1(57.15,121.03) ; 50.29,126.11 v2(50.29,126.87)
VCC_1V1VIDEO: length 7.8
  BOTTOM w0.305: C346.1 33.13,109.22 ; C346.1 32.51,109.97 ; C346.1 32.51,108.47 ; C347.1 32.5,107.82 ; C347.1 32,107.33 ; C347.1 32,108.32 ; 32.26,107.05 R473.1 32.26,105.55
  BOTTOM w0.508: L29.2 v2(38.23,121.03) ; L26.2 v2(18.54,127.38) ; L25.2 v2(28.32,132.46)
  vias: v2(32,104.78) v2(33.15,107.7) v2(33.15,105.16) v2(33.78,109.22) v2(45.34,112.27) v2(45.97,111.76)
VCC_CSI2_IO: length 13.5
  TOP w0.305: U140.7 19.23,33.34 v2(19.17,33.4) ; C429.1 17.66,25.64 v2(18.53,25.64)
  L3-SIGNAL w0.305: v2(18.53,25.64) 18.24,25.35 18.24,20.62 v2(18.67,20.19)
  BOTTOM w0.305: U124.2 v2(18.53,25.64) ; U135.2 v2(25.78,40.03) ; U124.10 18.42,20.44 v2(18.67,20.19)
  BOTTOM w0.508: v2(24.89,35.43) R669.1 R668.1
VCC_VTERM: length 1.7
  BOTTOM w0.508: RJ15.2 v2(36.58,117.22) ; L28.2 v2(38.23,122.68)
VDD18_DISP1: length 12.4
  TOP w0.305: v2(33.27,125.73) 33.02,125.98 C94.1 ; C103.1 22.73,122.43 v2(22.61,122.56) ; v2(33.27,119.25) C110.1
  TOP w0.508: R110.2 v2(24.38,128.14)
  BOTTOM w0.305: 32.38,125.69 32.43,125.73 v2(33.27,125.73) ; 32.38,119.19 33.21,119.19 v2(33.27,119.25) ; U115.24 22.74,122.69 v2(22.61,122.56)
  BOTTOM w0.508: R442.2 v2(15.75,119.89) ; C315.1 35.31,125.73 v2(35.05,125.73) ; R453.2 v2(29.84,114.3) ; 19.68,128.65 v2(18.92,128.65) ; L27.1 v2(34.92,124.46) ; 19.68,116.84 v2(18.92,116.84) ; C324.1 v2(21.84,119.76)
VDD33_DSU921: length 7.2
  TOP w0.305: L5.1 C14.1 148.21,160.66 149.48,160.66 v2(150.4,159.74) U8.22
  BOTTOM w0.305: C270.1 150.62,159.51 v2(150.4,159.74)
VDD_CDCEL925: length 4.7
  BOTTOM w0.305: U125.9 v1(47.25,53.05) ; C458.1 50.55,46.96 v1(50.52,46.99) 50.51,47.01 U125.3 ; U125.6 48.55,47.01 v1(48.57,46.99)
VDD_CDCM9102: length 9.4
  TOP w0.203: v1(28.73,147.35) U10.1 ; v1(28.73,148.85) U10.4
  TOP w0.508: v2(31.11,153.42) E1.3 32.11,154.46 32.64,153.92 v2(32.64,153.42)
  BOTTOM w0.381: C288.1 27.79,146.3 v2(27.81,146.28) ; C287.1 v2(28.83,146.3) ; C285.1 28.19,149.38 v1(28.73,148.85)
  BOTTOM w0.508: C286.1 28.73,147.55 v1(28.73,147.35)
VDD_CORE_APM: length 75.8
  TOP w0.635: 174.9,75.39 C146.1 ; C146.1 175.97,77.09 ; C146.1 173.84,77.09 ; C146.1 174.9,78.79 ; 175.64,81.08 R189.2 ; R189.2 176.91,80.44 ; R189.2 178.18,81.08 ; L14.1 174.75,74.09 ; L14.1 174.75,71.45 ; L14.1 175.76,72.77
  L7-SIGNAL w0.127: v2(175.91,79.77) 175.91,80.53 176.44,81.06 189.7,81.06 198.5,72.26 211.2,72.26 213.36,70.1 213.36,62.36 214.63,61.09 214.63,59.69 213.31,58.37 212.43,58.37 212.26,58.55 v2(211.84,58.55)
  BOTTOM w0.132: J18.6 212.65,57.86 212.27,58.24 212.14,58.24 v2(211.84,58.55)
  BOTTOM w0.305: U83.10 v2(175.91,79.77) ; U83.8 v2(176.91,79.76)
VDD_CORE_AVS: length 178.8
  TOP w0.305: v1(89.38,54.76) U42.V16 ; U42.K14 v1(96.58,57.16) ; v1(87.78,53.16) U42.Y18 ; U42.J15 v1(97.38,55.56) ; U42.P14 v1(93.38,57.16) ; v1(87.78,51.56) U42.Y20 U42.W19 ; v1(90.98,53.96) U42.U17 ; v1(168.78,71.37) 168.28,71.37 168.13,71.23 U38.9 ; U42.T14 v1(90.98,57.16) ; U42.U9 v1(90.98,60.36) U42.T10 v1(91.78,59.56) U42.R11 ; v1(94.18,59.56) U42.N11 v1(93.38,58.76) U42.P12 ; U42.N17 v1(94.18,54.76) ; U42.N15 v1(94.18,55.56) ; U42.J9 v1(97.38,61.16) ; U42.R13 v1(91.78,57.96) U42.T12 U42.U11 v1(90.18,59.56) ; U42.P21 v1(93.38,50.76) ; U42.P10 v1(93.38,60.36) ; U42.V20 v1(89.38,51.56) ; U42.R9 v1(91.78,61.16)
  TOP w0.381: v2(103.43,80.49) 103.94,80.49 C141.1 103.94,81.51 v2(103.43,81.51)
  TOP w0.406: v2(106.11,79.41) C373.1 v2(106.11,76.75) ; v2(103.95,73.06) C383.1 v2(103.95,75.73) ; v2(106.11,75.73) C384.1 v2(106.11,73.06) ; v2(103.95,79.41) C372.1 v2(103.95,76.75)
  L7-SIGNAL w0.127: v2(211.12,58.55) 211.56,58.12 213.4,58.12 213.45,58.17 213.49,58.17 214.88,59.56 214.88,61.17 213.6,62.46 213.6,70.2 211.3,72.5 198.6,72.5 189.8,81.31 176.5,81.31 v2(175.39,82.42)
  L8-PWR1 w0.127: v1(97.38,61.16) 97.94,61.16 98.58,61.8 98.58,62.12 98.82,62.36 99.72,62.36 99.73,62.37 99.95,62.37 100.19,62.61 100.19,62.93 100.42,63.16 100.74,63.16 100.98,63.4 100.98,63.62 100.99,63.63 100.99,63.73 101.22,63.96 101.32,63.96 101.33,63.97 101.55,63.97 101.78,64.2 101.78,64.67 101.88,64.77 103.12,64.77 103.38,64.52 103.89,64.52 104.39,65.02 104.39,66.14 107.06,68.81
  L8-PWR1 w0.203: v1(168.78,71.37) 168.78,72.15 168.29,72.64 161.04,72.64 160.53,72.14 158.62,72.14 157.35,70.87 140.97,70.87 140.46,70.36 132.46,70.36 132.08,70.74 107.77,70.74 107.06,70.03 107.06,68.81
  BOTTOM w0.132: J18.8 212.6,57.46 212.15,57.91 211.76,57.91 v2(211.12,58.55)
  BOTTOM w0.305: C447.1 91.94,59.41 v1(91.78,59.56) ; v1(89.38,51.56) 89.48,51.66 C498.1 ; v1(90.98,60.36) 90.39,60.36 C435.1 ; C462.1 97.66,55.84 v1(97.38,55.56) ; v2(176.15,83.44) 176.41,83.18 U83.9 ; C459.1 93.3,57.25 v1(93.38,57.16)
  vias: v2(175.39,83.19) v2(176.91,83.44) v2(177.67,83.44) v2(178.44,83.19) v2(178.44,82.42)
VDD_DSPEVE_APM: length 96.3
  TOP w0.635: C158.1 153.44,63.5 ; C158.1 152.37,61.8 ; C158.1 152.37,65.2 ; C158.1 151.31,63.5 ; 151.31,76.96 C148.1 ; C148.1 152.37,78.66 ; C148.1 152.37,75.26 ; C148.1 153.44,76.96 ; 152.53,71.2 L13.1 ; L13.1 153.53,72.52 ; L13.1 152.53,73.84 ; L13.1 151.52,72.52 ; R208.2 150.44,67.18 ; R208.2 149.81,65.91 ; R208.2 149.81,68.45 ; 152.53,66.37 L17.1 ; L17.1 153.53,67.69 ; L17.1 152.53,69.01 ; L17.1 151.52,67.69
  L7-SIGNAL w0.127: v2(150.86,66.18) 150.86,65.67 152.53,64.01 157.48,64.01 157.73,63.75 168.66,63.75 169.04,63.37 173.48,63.37 174.88,64.77 178.56,64.77 179.2,64.14 179.96,64.14 180.34,64.52 182.5,64.52 185.29,61.72 205.1,61.72 206.76,63.37 209.17,63.37 212.09,60.45 212.09,59.68 v2(212.47,59.31)
  BOTTOM w0.132: J18.2 213.11,58.66 v2(212.47,59.31)
  BOTTOM w0.305: U84.10 v2(150.86,66.18) ; U84.8 v2(150.88,67.18)
VDD_DSPEVE_AVS: length 181.7
  TOP w0.132: v1(157.61,65.41) 158.37,66.17 158.37,67.69 159.41,68.73 U38.33
  TOP w0.305: U42.K12 v1(95.78,57.96) U42.L13 v1(94.98,57.16) U42.M14 ; U42.M12 U42.L11 v1(95.78,59.56) U42.K10 v1(96.58,60.36) ; U42.L9 v1(94.98,60.36) U42.M10
  TOP w0.406: v2(115.51,57.59) C455.1 v2(112.84,57.59) ; v2(115.51,62.8) C428.1 v2(112.84,62.8) ; v2(109.41,57.59) C456.1 v2(112.08,57.59)
  TOP w0.508: v2(112.88,60.11) 113.53,60.76 C163.1 114.81,60.76 v2(115.46,60.11) ; v2(109.45,60.11) 110.1,60.76 C162.1 111.39,60.76 v2(112.03,60.11)
  L7-SIGNAL w0.127: v2(147.45,66.42) 149.73,66.42 152.4,63.75 156.52,63.75 157.18,63.09 157.52,63.09 157.93,63.5 168.57,63.5 168.94,63.13 173.58,63.13 174.98,64.53 178.46,64.53 179.1,63.89 180.06,63.89 180.44,64.27 182.4,64.27 185.19,61.48 205.21,61.48 206.86,63.13 209.07,63.13 211.84,60.36 211.84,59.69 211.71,59.56 v2(211.71,59.31)
  L8-PWR1 w0.127: v1(95.78,57.96) 96.12,57.63 97.54,57.63 97.78,57.39 97.78,57.33 97.78,56.99 98.04,56.72 98.04,56.62
  L8-PWR1 w0.203: 98.04,56.62 98.55,56.11 104.11,56.11 104.85,55.37 115.57,55.37 116.48,56.28 120.12,56.28 120.4,56.01 121.41,56.01 122.44,57.04 123.43,57.04 123.7,56.77 124.46,56.77 125.09,56.13 130.43,56.13 132.03,57.73 134.04,57.73 134.75,57.02 136.78,57.02 137.29,57.53 138.43,57.53 139.06,56.9 140.46,56.9 141.35,57.78 141.97,57.78 142.1,57.66 144.15,57.66 144.91,56.9 145.67,56.9 146.1,57.33 146.1,57.34 146.37,57.61 146.62,57.61 146.62,57.6 v2(149.3,57.6)
  BOTTOM w0.132: v2(211.71,59.31) 212.76,58.26 J18.4
  BOTTOM w0.203: v2(149.3,57.6) 149.99,58.29 149.99,60.07 155.32,65.41 v1(157.61,65.41)
  BOTTOM w0.305: v2(147.45,66.42) 147.71,66.68 U84.9 ; v1(94.98,57.16) 94.87,57.05 C464.1 ; C433.1 94.87,60.48 v1(94.98,60.36) 94.87,60.25 C444.1
  BOTTOM w0.406: v2(115.46,60.11) C439.1 v2(112.88,60.11) ; v2(112.03,60.11) C440.1 v2(109.45,60.11)
  BOTTOM w0.508: C446.1 v2(105.92,58.9) ; C452.1 v2(105.92,57.63) ; C438.1 v2(105.92,60.05)
  vias: v2(147.45,67.94) v2(147.45,67.18) v2(147.7,68.83) v2(147.7,65.53) v2(148.46,68.83) v2(148.46,65.53)
VDD_GPU_APM: length 92.2
  L7-SIGNAL w0.127: v2(136.02,69.72) 136.53,70.23 145.41,70.23 146.69,68.96 146.69,65.28 147.07,64.9 147.07,61.72 147.45,61.34 158.75,61.34 159.38,61.98 166.12,61.98 167.64,60.45 173.99,60.45 174.5,60.96 177.04,60.96 177.67,60.33 178.82,60.33 179.32,60.83 180.85,60.83 181.99,59.69 198.75,59.69 199.14,59.31 205.99,59.31 207.77,57.53 210.44,57.53 211,56.97 211.48,56.97 v2(211.91,57.4)
  BOTTOM w0.132: v2(211.91,57.4) 212.25,57.06 J18.10
  BOTTOM w0.305: v2(136.02,69.72) 136.54,70.25 U85.10 ; U85.8 v2(137.54,69.47)
VDD_GPU_AVS: length 166.5
  TOP w0.305: U42.V10 v1(89.38,60.36) U42.W9 ; U42.W13 v1(89.38,57.16) U42.V14 ; U40.1 v1(134.88,62.11) ; U42.V12 v1(89.38,58.76) U42.W11
  TOP w0.406: v2(89.73,79.95) C374.1 v2(89.73,77.28) ; v2(89.73,73.72) C382.1 v2(89.73,76.39)
  TOP w0.508: v2(136.4,72.77) v2(137.16,72.77) ; v2(137.16,72.77) 137.16,72.21 R191.1 137.92,72.21 v2(137.92,72.77) ; v2(137.16,72.77) v2(137.92,72.77) ; v2(137.92,72.77) v2(138.68,72.77) v2(138.68,73.53) v2(137.92,73.53) v2(137.16,73.53) v2(136.4,73.53) ; C400.1 v2(90.55,71.12) ; C396.1 v2(95.5,71.37) ; v2(89.85,80.73) 89.2,81.38 C140.1 89.2,82.66 v2(89.85,83.31)
  L7-SIGNAL w0.127: v2(137.16,72.77) 137.16,70.99 137.67,70.48 145.52,70.48 146.94,69.07 146.94,65.38 147.32,65 147.32,61.83 147.55,61.59 158.64,61.59 159.28,62.23 166.22,62.23 167.75,60.71 173.88,60.71 174.39,61.21 177.14,61.21 177.78,60.58 178.71,60.58 179.22,61.09 180.95,61.09 182.1,59.94 198.86,59.94 199.24,59.56 206.1,59.56 207.88,57.78 210.82,57.78 v2(211.2,57.4)
  L9-PWR2 w0.203: v2(95.5,71.37) 95.85,71.03 104.75,71.03 104.82,71.1 106.67,71.1 106.78,70.99 v2(133.48,70.99)
  BOTTOM w0.132: v2(211.2,57.4) 211.94,56.66 J18.12
  BOTTOM w0.305: U85.9 137.04,72.65 v2(137.16,72.77) ; v1(89.38,58.76) 89.37,58.78 C448.1 ; v1(89.38,57.16) 89.53,57.01 C466.1 ; v1(134.88,62.11) 134.88,64.38 134.37,64.9 134.37,67.69 133.48,68.58 v2(133.48,70.99) ; C434.1 89.37,60.36 v1(89.38,60.36) 89.53,60.21 C441.1
  BOTTOM w0.406: v2(89.85,83.31) C369.1 v2(89.85,80.73)
VDD_IVA_APM: length 97.6
  TOP w0.635: 165.81,81.94 C143.1 ; C143.1 167.51,80.87 ; C143.1 167.51,83.01 ; C143.1 169.22,81.94 ; 163.83,82.6 R179.2 ; R179.2 162.56,83.24 ; R179.2 165.1,83.24 ; L12.1 164.39,81.03 ; L12.1 163.07,80.02 ; L12.1 161.75,81.03 ; L12.1 163.07,82.03
  L7-SIGNAL w0.127: v2(211.22,56.4) 211.72,56.4 212.22,56.9 214.63,56.9 215.77,58.04 215.77,61.85 214.5,63.12 214.5,71.63 212.47,73.66 207.14,73.66 206.63,73.15 204.34,73.15 203.58,73.91 203.58,74.42 201.68,76.33 197.87,76.33 190.06,84.14 170.12,84.14 169.8,84.45 163.96,84.45 162.83,83.33 v2(162.83,82.3)
  BOTTOM w0.132: J18.14 211.36,56.26 v2(211.22,56.4)
  BOTTOM w0.305: U82.10 v2(162.83,82.3) ; U82.8 v2(163.83,82.3)
VDD_IVA_AVS: length 267.6
  TOP w0.305: U38.17 164.45,74.17 164.59,74.31 164.59,74.8 v1(164.72,74.93) ; v1(89.38,53.16) U42.V18 ; v1(90.18,52.36) U42.U19 U42.T18
  TOP w0.381: v2(71.07,51.16) 70.56,51.16 C172.1 70.56,52.17 v2(71.07,52.17)
  L7-SIGNAL w0.127: v2(163.07,85.6) 163.96,84.71 169.9,84.71 170.22,84.39 190.16,84.39 197.97,76.58 201.78,76.58 203.84,74.53 203.84,74.02 204.45,73.41 206.52,73.41 207.03,73.91 212.58,73.91 214.76,71.73 214.76,63.22 216.03,61.95 216.03,57.93 214.74,56.64 212.3,56.64 211.67,56.01 211.44,56.01 211.4,55.97 211.04,55.97 211,56.01 v2(210.57,56.01)
  L9-PWR2 w0.127: v1(89.38,53.16) 88.98,53.56 82.56,53.56
  L9-PWR2 w0.203: v2(162.36,85.01) 162.36,85.04 162,85.39 162,86.14 162.02,86.16 162.02,86.67 160.93,87.76 158.83,87.76 154.25,92.33 149.15,92.33 148.16,93.31 144.49,93.31 143.97,92.79 131.75,92.79 131.66,92.69 121.43,92.69 121.03,93.09 72.64,93.09 70.1,90.55 69.72,90.55 69.22,90.04 69.22,83.57 68.65,83 68.65,83 68.39,82.74 68.38,82.74 68.33,82.68 68.33,81.03 68,80.7 68,76.27 68.33,75.95 68.33,57.78 72.55,53.56 82.56,53.56
  BOTTOM w0.132: v2(210.57,56.01) 210.67,55.91 212.69,55.91 212.73,55.86 J18.16
  BOTTOM w0.305: U82.9 163.33,85.34 v2(163.07,85.6) ; v1(90.18,52.36) 90.12,52.43 C489.1 ; v1(164.72,74.93) 165.1,75.31 166.12,75.31 166.46,75.65 166.46,76.24 165.99,76.71 165.99,77.47 166.24,77.72 166.24,79.63 164.97,80.9 163.07,80.9 162,81.97 162,84.21 162.36,84.57 v2(162.36,85.01)
  BOTTOM w0.406: v2(72.24,49.7) C516.1 v2(74.82,49.7) ; v2(72.24,51.85) C497.1 v2(74.82,51.85)
  BOTTOM w0.508: C502.1 v2(78.49,49.25) ; C511.1 v2(78.49,47.98) ; C495.1 v2(78.49,50.52)
  vias: v2(163.83,85.6) v2(164.59,85.6)
VDD_MPU_APM: length 87.2
  L7-SIGNAL w0.127: v2(212.51,55.46) 211.97,55.46 211.89,55.55 211.53,55.55 211.35,55.37 210.27,55.37 208.74,56.91 208.39,56.91 207.04,56.91 205.41,58.53 205.21,58.53 182.23,58.53 181.7,58 177.16,58 177,58.17 175.51,58.17 174.5,59.18 165.82,59.18 165.19,58.55 161.16,58.55 159.37,56.76 158.14,56.76 157.27,55.88 153.92,55.88 151.38,53.34 147.87,53.34 143.68,49.15 138.3,49.15 137.54,49.91 v2(137.54,50.67)
  BOTTOM w0.132: J18.18 v2(212.51,55.46)
  BOTTOM w0.305: U86.10 138.54,50.31 138.18,50.67 v2(137.54,50.67) U86.8
VDD_MPU_AVS: length 257.7
  TOP w0.305: U42.M18 v1(94.98,53.16) U42.L19 v1(95.78,52.36) U42.K20 v1(96.58,51.56) ; U42.L15 v1(95.78,55.56) U42.K16 ; U42.M20 v1(94.98,51.56) ; v1(96.58,53.16) U42.K18 U42.L17 v1(94.98,54.76) U42.M16 ; U40.8 v1(134.88,58.03)
  TOP w0.406: v2(109.41,50.99) C505.1 v2(112.08,50.99) ; v2(114.11,53.66) C484.1 v2(116.78,53.66) ; v2(110.68,53.66) C485.1 v2(113.35,53.66)
  TOP w0.508: v2(136.4,46.61) v2(137.16,46.61) v2(137.92,46.61) v2(138.68,46.61) v2(138.68,47.37) v2(137.92,47.37) ; v2(137.16,47.37) v2(137.92,47.37) ; v2(137.16,47.37) v2(136.4,47.37) ; v2(137.16,47.37) 137.16,47.93 R249.1 137.92,47.93 v2(137.92,47.37) ; v2(116.31,50.97) 116.96,51.61 C174.1 118.24,51.61 v2(118.89,50.97) ; v2(112.88,50.97) 113.53,51.61 C173.1 114.81,51.61 v2(115.46,50.97) ; C499.1 v2(107.06,51.94) ; C491.1 v2(107.06,53.09)
  L7-SIGNAL w0.127: v2(211.71,55.12) 210.19,55.12 208.64,56.67 206.94,56.67 205.31,58.29 182.33,58.29 181.8,57.76 177.06,57.76 176.91,57.91 175.77,57.91 175.76,57.92 175.41,57.92 174.4,58.94 165.92,58.94 165.28,58.29 161.25,58.29 159.47,56.52 158.24,56.52 157.37,55.64 154.06,55.64 151.51,53.09 147.96,53.09 143.76,48.9 139.45,48.9 138.68,48.13 v2(138.68,47.37)
  L8-PWR1 w0.127: v1(96.58,51.56) 96.58,51 98.03,49.55 98.35,49.55 98.59,49.31 98.59,49 98.83,48.75 99.15,48.75 99.39,48.51 99.39,48.2 99.63,47.95 99.95,47.95 100.18,47.72 100.18,47.41 100.43,47.15 100.75,47.15 100.98,46.92 100.98,46.82 100.99,46.81 100.99,46.6 101.22,46.37 102.6,46.37 103,45.97
  L8-PWR1 w0.203: v2(139.57,50.16) 140.08,49.66 140.08,46.61 137.79,44.32 136.63,44.32 136.25,44.7 135.25,44.7 134.75,44.2 128.14,44.2 127.64,44.7 126.49,44.7 126.11,44.32 122.3,44.32 121.72,44.91 120.63,44.91 120.56,44.83 117.86,44.83 117.35,44.33 107.74,44.33 106.17,45.9 103.07,45.9 103,45.97
  L10-SIGNAL w0.305: v2(148.86,47.1) 148.86,51.7 v2(151,53.85)
  L14-SIGNAL w0.305: v2(148.86,47.1) 147.05,47.1 146.56,46.61 v2(138.68,46.61) ; v2(151,53.85) 152.02,53.85 153.8,55.63 157.48,55.63 157.99,55.12 170.18,55.12 170.94,54.36 177.04,54.36 178.05,53.34 179.32,53.34 179.83,53.85 181.48,53.85 184.02,56.39 197.36,56.39 v1(198.12,57.15)
  BOTTOM w0.132: J18.20 212.93,55.06 212.84,54.97 212.29,54.97 212.14,55.12 v2(211.71,55.12)
  BOTTOM w0.203: v1(134.88,58.03) 135.64,57.28 135.64,56.64 136.14,56.13 136.14,54.23 136.91,53.47 138.68,53.47 139.57,52.58 v2(139.57,50.16)
  BOTTOM w0.305: C472.1 95.06,54.84 v1(94.98,54.76) ; C482.1 94.88,53.06 v1(94.98,53.16) ; U86.9 138.04,48.01 137.92,47.89 v2(137.92,47.37) ; C492.1 95.74,52.4 v1(95.78,52.36) ; v1(95.78,55.56) 95.76,55.59 C463.1
  BOTTOM w0.406: v2(112.88,50.97) C504.1 v2(115.46,50.97) ; v2(116.31,50.97) C503.1 v2(118.89,50.97)
  BOTTOM w0.508: R594.1 v1(198.12,57.15)
VDD_SDIO_APM: length 9.9
  TOP w0.305: U148.6 187.97,66.95 v2(187.86,67.06) ; v2(188.59,67.06) 188.47,66.93 U148.5
  TOP w0.508: C404.2 187.96,67.15 v2(187.86,67.06) v2(188.59,67.06)
  BOTTOM w0.305: U69.8 v2(176.02,69.22) ; U69.10 v2(176.16,70.22)
  BOTTOM w0.508: R753.2 190.75,66.55 190.25,67.06 v2(188.59,67.06)
VDD_SDIO_DV: length 9.8
  TOP w0.305: U42.U7 v1(90.18,62.76)
  TOP w0.508: 136.02,167 v2(135.25,167)
  BOTTOM w0.305: v2(179.58,69.98) 179.06,69.98 178.8,69.72 U69.9
  BOTTOM w0.381: R330.1 v2(140.84,155.32) ; R334.1 v2(131.7,155.32) ; R332.1 v2(136.27,155.32)
  BOTTOM w0.508: v2(132.46,158.12) 132.72,157.86 R333.1 ; v2(137.03,157.99) 137.29,157.73 R331.1 ; C401.1 v2(88.01,70.08) ; R335.1 v2(128.14,158.24)
  vias: v2(179.58,69.22) v2(179.58,68.45) v2(211.07,71.25) v2(211.07,70.23)
VDDA_CDCM9102: length 11.6
  TOP w0.203: v2(23.39,152.68) U10.16 ; v2(21.56,150.73) 21.95,150.35 U10.18 ; v2(21.56,149.35) U10.20
  TOP w0.254: U10.9 27.33,151.66 v1(27.56,151.89)
  TOP w0.381: R28.1 v2(26.67,155.45) ; R27.1 v2(25.65,155.45)
  TOP w0.508: C34.1 v2(21.08,153.03) ; L7.2 v2(23.88,154.05)
  BOTTOM w0.381: C282.1 v1(27.56,151.89) ; C281.1 23.5,152.58 v2(23.39,152.68) ; R349.1 v2(27.56,152.65) ; v2(21.56,150.73) 22.46,150.73 C283.1
VDDHA_DISP1: length 8.7
  TOP w0.305: C108.1 33.15,120.4 v2(33.27,120.52) ; v2(33.27,124.97) C98.1 ; C105.1 33.15,121.92 v2(33.27,122.05)
  BOTTOM w0.305: 32.38,120.69 33.11,120.69 v2(33.27,120.52) ; 32.38,124.19 v2(33.17,124.19) ; v2(33.27,124.97) 33.06,125.19 32.38,125.19 ; v2(33.27,122.05) 33.13,122.19 32.38,122.19
  BOTTOM w0.508: C327.1 v2(34.92,119.38) ; C314.1 v2(34.92,127.89) ; L29.1 v2(34.92,121.03)
VDDHS_DISP1: length 12.8
  TOP w0.305: v2(22.61,123.32) 23.24,123.32 C100.1 ; C99.1 v2(22.61,124.59) ; v2(22.67,119.19) 23.31,119.19 C111.1 ; v2(22.61,121.22) 22.8,121.41 C106.1 ; v2(27.44,117.6) 27.44,118.11 C112.1
  TOP w0.508: C95.1 v2(21.84,125.86) ; C116.1 v2(21.84,118.11)
  BOTTOM w0.305: U115.25 22.74,123.19 v2(22.61,123.32) ; U115.17 v2(22.67,119.19) ; v2(27.44,117.6) 27.69,117.86 U115.9 ; U115.28 22.7,124.69 v2(22.61,124.59) ; U115.21 22.65,121.19 v2(22.61,121.22)
  BOTTOM w0.508: C317.1 v2(21.84,125.86) ; L26.1 v2(21.84,127.38) ; C330.1 v2(21.84,118.11)
VDDI_MMC2: length 6.9
  TOP w0.076: 147.5,134.21 147.07,134.21 ; 147.07,134.71 147.5,134.71
  TOP w0.102: 147.07,134.21 146.96,134.21 ; 146.96,134.71 147.07,134.71
  TOP w0.132: 147.5,134.21 U15.C2 147.5,134.71 ; 146.96,134.21 146.81,134.06 146.81,133.68 146.61,133.48 v1(146.18,133.48) 146.18,133.92 146.96,134.71
  BOTTOM w0.381: C306.1 145.29,132.08 C304.1 145.92,133.22 v1(146.18,133.48)
VDDIO_DSU921: length 5.3
  TOP w0.305: U8.30 147.68,155.57 v2(147.68,155.58) 147.67,155.57 146.87,155.57 146.87,155.57 146.84,155.57 146.84,155.57 C32.1 L6.2
  BOTTOM w0.305: v2(147.68,155.58) 148.21,155.58 C277.1
VDDL_DISP1: length 8.4
  TOP w0.305: C91.1 27.56,127.64 v2(28.19,128.27) 28.57,127.88 C92.1 ; C113.1 28.19,118.11 v2(28.69,117.61) 28.97,117.61 29.21,117.86 C114.1
  BOTTOM w0.305: U115.7 v2(28.69,117.61) ; U115.41 v2(28.19,128.27)
  BOTTOM w0.508: C336.1 v2(28.32,116.97) ; C309.1 v2(26.54,129.16) ; L25.1 v2(28.32,129.16)
VDDR_APM: length 139.4
  TOP w0.305: U80.8 142.47,14.22 142.24,14.45 142.24,15.01 142.47,15.24 143.49,15.24 U80.10 v2(143.51,15.88) ; v2(146.69,26.16) 146.69,17.91 147.45,17.14 151.89,17.14 v2(152.78,18.03) 152.78,20.32 R692.1 C601.2
  TOP w0.508: R280.1 v2(142.49,26.8)
  L7-SIGNAL w0.127: v2(143.51,15.88) 143.51,14.99 143.89,14.61 153.16,14.61 154.43,15.88 158.62,15.88 159.13,15.37 163.96,15.37 166.5,17.91 210.69,17.91 211.96,19.18 216.79,19.18 219.58,21.97 219.58,51.69 219.33,51.94 218.57,51.94 v2(218.06,52.45)
  BOTTOM w0.132: v2(218.06,52.45) 217.87,52.27 J18.33
  BOTTOM w0.305: v2(146.69,26.16) U138.7
VDDR_MEM_1V35: length 278.5
  TOP w0.203: v1(131.88,20.57) 131.48,20.97 U62.K9 ; U61.M1 v1(110.31,18.97) ; U62.C1 125.07,26.57 v1(124.67,26.17) ; v1(110.32,26.17) 110.72,26.57 U61.C1 ; v1(116.73,22.97) 116.32,23.37 U61.G8 ; U62.M1 v1(124.66,18.97) ; v1(110.31,20.57) 110.71,20.97 U61.K1 ; U61.E9 v1(117.52,24.56) ; v1(125.47,28.56) U62.A2 ; U61.M9 117.12,19.37 v1(117.53,18.97) ; U62.E9 v1(131.87,24.56) ; v1(131.88,18.97) 131.48,19.37 U62.M9 ; U62.G2 v1(125.47,22.97) ; U62.B9 v1(131.87,26.97) ; U61.B9 v1(117.52,26.97) ; U62.K1 125.06,20.97 v1(124.66,20.57) ; U61.G2 v1(111.12,22.97) ; v1(111.12,25.37) 111.52,24.97 U61.E2 ; U61.A9 v1(116.72,28.57) ; v1(131.07,28.57) U62.A9 ; U62.E2 125.87,24.97 v1(125.47,25.37) ; v1(111.12,28.56) U61.A2 ; U62.D7 v1(130.27,25.37) ; U62.G8 130.68,23.37 v1(131.08,22.97) ; U61.K9 117.12,20.97 v1(117.53,20.57) ; U61.D7 v1(115.92,25.37)
  TOP w0.254: U59.G7 v1(65.97,25.58) ; U59.R1 v1(61.17,18.38) ; U59.K2 v1(61.97,22.38) ; U59.N1 v1(61.17,19.98) ; U60.G7 v1(78.67,25.58)
  TOP w0.305: v1(86.57,26.38) 86.97,25.98 U63.C1 ; U59.H2 v1(61.97,24.78) ; U60.C9 v1(81.07,28.78) ; U59.N9 v1(68.37,19.98) ; U63.K9 v1(93.77,19.98) ; U60.A8 v1(80.27,30.38) ; U59.A1 v1(61.17,30.38) ; U59.C9 v1(68.37,28.78) ; U59.K8 v1(67.57,23.18) ; U63.E9 93.37,24.38 v1(93.77,24.78) ; U60.N9 v1(81.07,19.98) ; v1(86.57,18.38) U63.M1 ; U63.D7 91.77,25.18 v1(92.17,25.58) ; U60.C1 v1(73.87,28.78) ; v1(117.22,31.24) 117.35,31.37 C615.1 ; U60.H9 v1(81.07,24.78) ; U60.K2 v1(74.67,22.38) ; U63.A2 87.77,27.58 v1(87.37,27.98) ; v1(87.37,24.78) 87.77,24.38 U63.E2 ; v1(131.83,31.24) 131.95,31.37 C561.1 ; U59.C1 v1(61.17,28.78) ; C195.1 110.36,31.37 v1(110.49,31.24) ; v2(144.53,12.57) 144.78,12.83 144.78,14.5 144.55,14.72 U80.9 ; U63.A9 93.37,27.58 v1(93.77,27.98) ; v1(127,31.24) 126.87,31.37 C199.1 ; U60.D9 v1(81.07,27.98) ; U63.G8 v1(92.97,23.18) ; U63.K1 v1(86.57,19.98) ; C673.1 v1(112.27,31.26) ; U63.M9 v1(93.77,18.38) ; v1(93.77,27.18) 93.37,26.78 U63.B9 ; v1(129.92,31.24) 130.05,31.37 C568.1 ; U60.K8 v1(80.27,23.18) ; U59.E9 v1(68.37,27.18) ; U59.A8 v1(67.57,30.38) ; U59.F1 v1(61.17,26.38) ; v1(87.37,22.38) U63.G2 ; U60.E9 v1(81.07,27.18) ; U60.F1 v1(73.87,26.38) ; C194.1 115.44,31.37 v1(115.32,31.24) ; U59.R9 v1(68.37,18.38) ; U60.H2 v1(74.67,24.78) ; C589.1 124.97,31.37 v1(125.09,31.24) ; U60.R1 v1(73.87,18.38) ; U60.R9 v1(81.07,18.38) ; U59.B2 v1(61.97,29.58) ; U60.D2 v1(74.67,27.98) ; U60.A1 v1(73.87,30.38) ; U59.H9 v1(68.37,24.78) ; U60.N1 v1(73.87,19.98) ; U60.B2 v1(74.67,29.58) ; U59.D9 v1(68.37,27.98) ; U59.D2 v1(61.97,27.98)
  TOP w0.508: v2(91.19,13.44) 91.15,13.48 C223.1 91.15,15.33 v2(91.19,15.37) ; C212.2 v2(141.99,19.81) ; C202.2 v2(101.73,24.38) ; C225.2 v2(101.73,15.88) ; C213.2 v2(101.73,20.95) ; v2(75.31,14.07) C219.1 v2(75.31,15.6) ; C209.2 v2(101.73,22.61) ; v2(63.12,15.6) C217.1 v2(63.12,14.07) ; v2(66.59,15.8) 66.55,15.77 C218.1 66.55,13.92 v2(66.59,13.88) ; C222.2 v2(141.99,25.15) ; R281.1 v2(140.78,30.99) ; C204.2 v2(141.99,18.03) ; C224.2 v2(101.73,17.53) ; C205.2 v2(141.99,23.24) ; v2(78.65,15.8) 78.61,15.77 C220.1 78.61,13.92 v2(78.65,13.88) ; C221.2 v2(141.99,16.51) ; C210.2 v2(101.73,19.18) ; C208.2 v2(141.99,21.46)
  L7-SIGNAL w0.127: v2(144.53,12.57) 144.53,13.72 145.16,14.35 151.12,14.35 151.13,14.36 153.26,14.36 154.53,15.63 158.48,15.63 158.99,15.13 164.06,15.13 166.6,17.67 210.79,17.67 212.06,18.94 216.89,18.94 219.82,21.87 219.82,51.96 219.33,52.45 v2(218.82,52.45)
  BOTTOM w0.132: v2(218.82,52.45) 218.24,51.87 J18.35
  BOTTOM w0.203: v1(125.47,28.56) U136.A9 ; U136.E9 v1(125.47,25.37) 126.03,25.37 126.43,25.77 U136.D7 ; U137.C1 v1(117.52,26.97) ; U136.C1 v1(131.87,26.97) ; U137.E2 v1(115.92,25.37) ; U61.M1 v1(110.31,18.97) ; U62.M9 v1(131.88,18.97) ; U62.G8 v1(131.08,22.97) ; v1(111.12,28.56) U137.A9 ; v1(124.67,27.77) U136.B9 ; U61.G8 v1(116.73,22.97) ; U62.K9 v1(131.88,20.57) ; v1(125.47,22.97) U62.G2 ; v1(124.66,18.97) U62.M1 ; v1(110.31,20.57) 110.71,20.97 U61.K1 ; U136.E2 v1(130.27,25.37) ; v1(131.07,28.57) U136.A2 ; U137.D7 112.08,25.77 111.68,25.37 v1(111.12,25.37) U137.E9 ; U61.K9 v1(117.53,20.57) ; U61.G2 v1(111.12,22.97) ; U137.B9 v1(110.32,27.77) ; v1(124.66,20.57) 125.06,20.97 U62.K1 ; U137.A2 v1(116.72,28.57) ; U61.M9 v1(117.53,18.97)
  BOTTOM w0.254: C661.1 v1(126.36,14.86) ; C667.1 v1(114.81,14.86) ; C677.1 v1(113.79,14.86) ; C672.2 108.29,19.6 v1(108.46,19.43) ; C567.1 119.39,27.34 v1(119.38,27.34) ; v1(108.46,29.34) 108.29,29.5 C608.1 ; v1(108.46,18.64) 108.45,18.63 C628.1 ; C674.1 119.39,19.01 v1(119.38,19.01) ; C669.1 v1(112.01,14.86) ; C660.1 v1(127.13,14.86) ; C640.1 v1(130.98,15.96) ; C614.1 v1(131.83,31.24) ; v1(112.27,31.26) 112.39,31.39 C198.1 ; v1(119.38,29.34) 119.55,29.5 C557.1 ; C641.1 v1(116.62,15.96) ; C196.1 v1(125.09,31.24) ; v1(123.79,16.5) 123.79,16.51 C682.1 ; v1(108.46,22.99) 108.29,23.15 C678.1 ; v1(133.73,27.34) 133.74,27.34 C683.1 ; C562.1 v1(115.32,31.24) ; C607.1 v1(121.41,23.15) ; C671.1 v1(108.2,14.86) ; v1(122.81,19.68) 122.72,19.6 C685.2 ; C659.1 v1(129.16,14.86) ; C207.1 v1(117.22,31.24) ; C658.1 v1(129.92,14.86) ; C676.1 133.9,29.5 v1(133.73,29.34) ; v1(122.81,27.35) 122.8,27.34 C675.1 ; C570.1 v1(110.49,31.24) ; C642.2 v1(134.37,20.07) ; C663.1 v1(122.56,14.86) ; v1(111.01,16.52) 111,16.51 C680.1 ; C666.1 v1(115.57,14.86) ; v1(133.74,19.17) 133.9,19.01 C684.1 ; v1(108.46,27.35) 108.45,27.34 C590.1 ; C656.1 v1(133.73,14.86) ; C686.1 v1(127,31.24) ; C681.1 v1(128.27,14.86) ; C664.1 v1(119.38,14.86) ; C668.1 v1(112.78,14.86) ; v1(122.81,29.34) 122.64,29.5 C569.1 ; C643.2 v1(120.02,20.07) ; C556.1 v1(129.92,31.24)
  BOTTOM w0.305: v1(81.07,27.98) 81.39,27.66 C581.1 ; v1(73.87,26.38) 73.76,26.26 C585.1 ; v1(87.37,27.98) 87.47,28.07 C574.1 ; C632.1 73.86,18.39 v1(73.87,18.38) ; v1(93.77,27.18) 93.94,27.35 C584.1 ; v1(122.81,18.84) 122.6,18.63 C627.1 ; v1(93.77,27.98) 93.82,28.02 C573.1 ; v1(67.57,30.38) 67.56,30.38 C553.1 ; C621.1 68.43,19.91 v1(68.37,19.98) ; v1(87.37,24.78) 87.75,24.4 87.86,24.4 C558.1 ; C554.1 80.39,30.5 v1(80.27,30.38) ; C572.1 61.14,28.8 v1(61.17,28.78) ; v1(68.37,18.38) 68.38,18.39 C633.1 ; C612.2 v2(83.57,21.56) ; v1(61.17,26.38) 61.06,26.26 C586.1 ; v2(70.89,21.95) 70.51,21.56 C613.2 ; C588.1 92.04,25.45 v1(92.17,25.58) ; C596.1 68.53,24.61 v1(68.37,24.78) ; v1(61.17,18.38) 61.16,18.39 C634.1 ; C591.1 79.23,26.14 v1(78.67,25.58) ; C618.1 85.79,19.98 v1(86.57,19.98) ; C622.1 61.11,19.91 v1(61.17,19.98) ; v1(93.77,19.98) 94.53,19.98 C617.1 ; C565.1 81.17,28.68 v1(81.07,28.78) ; C566.1 68.47,28.68 v1(68.37,28.78) ; v1(81.07,18.38) 81.08,18.39 C631.1 ; C559.1 73.82,30.33 v1(73.87,30.38) ; v1(81.07,24.78) 81.23,24.61 C595.1 ; C629.1 93.99,18.16 v1(93.77,18.38) ; v1(65.97,25.58) 66.4,26.01 C592.1 ; v1(93.77,24.78) 94.23,24.78 C597.1 ; v1(61.17,30.38) 61.12,30.33 C560.1 ; v2(91.14,24.66) C655.1 ; C583.1 85.86,26.38 v1(86.57,26.38) ; C582.1 68.69,27.66 v1(68.37,27.98) ; C630.1 86.56,18.39 v1(86.57,18.38) ; C619.1 81.13,19.91 v1(81.07,19.98) ; C620.1 73.81,19.91 v1(73.87,19.98) ; v1(73.87,28.78) 73.84,28.8 C571.1
  BOTTOM w0.381: C670.1 v1(110.74,14.86) ; C657.1 v1(131.19,14.86) ; C665.1 v1(116.84,14.86) ; C662.1 v1(125.09,14.86)
  BOTTOM w0.508: 90.3,21.72 89.87,21.29 v2(89.41,21.29) ; v2(141.99,21.46) 141.86,21.59 C611.2 ; v2(141.99,19.81) 141.86,19.94 C644.2 ; v2(141.99,23.24) 141.86,23.37 C649.2 ; v2(101.73,20.95) 101.6,21.08 C653.2 ; v2(101.73,15.88) 101.6,16 C637.2 ; C604.2 101.6,24.51 v2(101.73,24.38) ; v2(101.73,17.53) 101.6,17.65 C645.2 ; C602.2 141.86,16.64 v2(141.99,16.51) ; C200.2 v2(96.52,27.69) ; v2(141.99,18.03) 141.86,18.16 C648.2 ; v2(101.73,22.61) 101.6,22.73 C616.2 ; C578.2 v2(136.65,28.19) ; v2(141.99,25.15) 141.86,25.27 C625.2 ; C654.2 101.6,19.3 v2(101.73,19.18)
  vias: v2(143,12.57) v2(143.76,12.57)
VDDR_SOC_1V35: length 134.6
  TOP w0.305: U42.U23 v1(90.98,49.96) U42.T22 ; U42.N21 v1(94.18,50.76) ; U42.P22 v1(93.38,49.96) U42.N23 ; v2(130.81,41.02) 131.34,41.02 131.46,41.14 U79.9 ; v1(86.98,49.16) U42.AA23 v1(87.78,49.96) U42.Y22 U42.W21 ; U42.L21 v1(95.78,50.76) U42.K22 v1(96.58,49.96) U42.J23 ; U42.V22 v1(89.38,49.96) U42.W23 ; U42.AA21 v1(86.98,50.76) ; U42.L23 v1(95.78,49.16)
  TOP w0.508: C533.1 v2(88.9,41.76) ; v2(98.23,34.37) 98.76,34.89 C197.1 98.76,36.43 v2(98.23,36.95) ; v2(87.57,33.76) 88.09,34.28 C193.1 88.09,35.82 v2(87.57,36.34) ; C537.1 v2(100.2,41.76) ; C186.1 v2(102.11,41.76) ; C536.1 v2(90.68,41.76) ; C538.1 v2(98.3,41.76)
  L7-SIGNAL w0.127: v2(217.99,50.9) 218.44,50.44 218.44,49.53 218.19,49.28 216.66,49.28 213.61,52.32 209.55,52.32 209.3,52.58 205.49,52.58 202.95,55.12 191.77,55.12 189.36,52.7 177.55,52.7 176.53,53.72 160.77,53.72 160.44,53.39 155.63,53.39 152.27,50.04 147.96,50.04 140.08,42.16 133.1,42.16 131.95,41.02 v2(130.81,41.02)
  BOTTOM w0.132: v2(217.99,50.9) 217.96,50.93 217.94,50.93 217.81,51.07 J18.39
  BOTTOM w0.305: v1(86.98,50.76) 87,50.77 C501.1 ; C506.1 95.78,49.17 v1(95.78,49.16) ; C509.1 94.23,50.71 v1(94.18,50.76) ; C512.1 91.06,49.88 v1(90.98,49.96) ; v1(89.38,49.96) 89.15,49.73 C513.1
  BOTTOM w0.406: v2(87.57,36.34) C189.1 v2(87.57,33.76) ; v2(98.23,34.37) C551.1 v2(98.23,36.95)
  BOTTOM w0.508: C535.1 v2(83.06,41.76) ; C534.1 v2(84.96,41.76) ; C187.1 v2(96.39,41.76) ; C181.1 v2(86.87,41.76) ; C539.1 v2(94.49,41.76) ; C182.1 v2(92.58,41.76)
  vias: v2(130.81,41.91) v2(130.81,40.26) v2(130.81,39.37)
VDDR_SOC_APM: length 104.3
  TOP w0.305: U79.8 v2(134.24,40.64) 134.24,41.17 133.77,41.64 U79.10
  L7-SIGNAL w0.127: v2(218.69,51.18) 218.69,49.42 218.29,49.02 216.56,49.02 213.5,52.08 209.43,52.08 209.19,52.32 205.38,52.32 202.84,54.86 191.88,54.86 189.46,52.45 177.44,52.45 176.42,53.47 160.86,53.47 160.54,53.15 155.74,53.15 152.38,49.78 148.06,49.78 140.19,41.91 133.35,41.91 132.97,41.53 132.97,40.89 133.22,40.64 v2(134.24,40.64)
  BOTTOM w0.132: J18.37 218.41,51.47 v2(218.69,51.18)
  vias: v2(134.62,39.5)
VDDR_SOC_VREFSTL: length 3.2
  TOP w0.305: U42.AB22 v1(86.18,49.96) ; U42.M22 v1(94.98,49.96)
  TOP w0.508: R282.2 v2(143.26,29.84)
  BOTTOM w0.305: C180.1 v2(75.44,40.89) ; C216.1 v2(103.38,41.53)
  vias: v2(150.88,27.3)
VDDR_VREFSTL: length 31.5
  TOP w0.203: v1(131.08,21.37) 130.68,21.77 U62.J8 ; U61.J8 116.32,21.77 v1(116.73,21.37)
  TOP w0.254: U60.M8 v1(80.27,21.58) ; U63.J8 v1(92.97,21.58) ; U59.M8 v1(67.57,21.57) ; U62.E1 124.76,25.27 123.83,25.27 v1(123.57,25.02) ; v1(109.22,25.02) 109.47,25.27 110.41,25.27 U61.E1
  TOP w0.305: U63.E1 86.97,24.38 v1(86.57,24.78) ; U60.H1 v1(73.87,24.78) ; U59.H1 v1(61.17,24.78)
  TOP w0.508: R280.2 R277.2 R282.1 140.84,29.84 v2(140.59,29.59)
  BOTTOM w0.132: C647.1 91.55,21.96 92.59,21.96 v1(92.97,21.58)
  BOTTOM w0.203: U136.J8 v1(125.46,21.37) ; U137.J8 v1(111.11,21.37)
  BOTTOM w0.254: C643.1 v1(120.02,22.1) ; v1(132.72,25.15) U136.E1 ; v1(118.36,25.15) 117.91,25.15 117.79,25.02 117.17,25.02 U137.E1 ; C642.1 v1(134.37,22.1) ; C672.1 108.45,20.28 v1(108.46,20.29)
  BOTTOM w0.305: C685.1 122.64,20.28 v1(122.81,20.45) ; v1(73.87,24.78) 73.83,24.74 C599.1 ; C201.1 122.93,25.18 123.09,25.02 v1(123.57,25.02) ; C679.1 108.71,25.06 108.74,25.02 v1(109.22,25.02) ; C612.1 80.27,21.56 v1(80.27,21.58) ; v1(118.36,25.15) 118.84,25.15 118.88,25.18 C606.1 ; C600.1 61.13,24.74 v1(61.17,24.78) ; v1(67.57,21.57) 67.57,21.56 C613.1 ; v1(86.57,24.78) 85.76,24.78 C598.1 ; v1(132.72,25.15) 133.19,25.15 133.28,25.06 C605.1
VDDS_1V8: length 162.9
  TOP w0.305: U42.T8 v1(90.98,61.16) ; U42.R7 v1(92.58,62.76) ; U42.AA19 v1(86.98,53.16) ; U42.M8 v1(94.98,61.96) ; U42.T20 v1(90.98,51.56) U42.U21 ; U42.H14 v1(98.18,57.16) ; v1(165.22,64.89) 165.22,64.9 164.92,65.2 164.92,65.84 164.95,65.87 U38.45 ; U42.H22 v1(98.18,49.96) ; U42.R21 v1(91.78,50.76) ; U42.AB8 v1(86.18,61.96) ; U42.H20 v1(98.18,51.56)
  TOP w0.381: v2(113.03,69.75) 113.03,70.26 C155.1 114.05,70.26 v2(114.05,69.75)
  TOP w0.406: v2(110.68,69.28) C411.1 v2(108.01,69.28)
  TOP w0.508: C150.1 v2(111.76,69.72)
  L3-SIGNAL w0.203: v2(166.88,56.77) 166.24,57.4 165.1,57.4 164.34,56.64 158.12,56.64 157.61,56.13 151.89,56.13 151.13,55.37 150.75,55.37 148.59,53.21 147.57,53.21 146.72,54.06 144.46,54.06 143.77,53.38 142.2,53.38 141.86,53.72 137.03,53.72 136.02,54.74 136.02,55.12 135.51,55.63 133.86,55.63 133.35,55.12 125.86,55.12 125.67,54.93 121.09,54.93 119.73,56.29 115.98,56.29 115.82,56.13 113.28,56.13 112.78,55.63 104.78,55.63 104.27,56.13 98.55,56.13 98.18,56.5 v1(98.18,57.16)
  L7-SIGNAL w0.127: v2(212.47,53.01) 212.33,53.15 210.37,53.15 208.91,54.61 207.52,54.61 205.74,56.39 186.27,56.39 185.99,56.11 183.87,56.11 183.39,55.63 181.23,55.63 180.72,56.13 178.05,56.13 177.55,55.63 165.65,55.63 164.89,56.39 163.32,56.39 162.56,55.63 v2(162.56,54.36)
  BOTTOM w0.127: J18.28 212.93,53.46 v2(212.47,53.01)
  BOTTOM w0.305: U122.6 112.09,76.07 112.31,75.85 C379.1 v2(112.31,74.71) ; C487.1 90.93,51.61 v1(90.98,51.56) ; U70.9 162.19,54.73 v2(162.56,54.36) ; v1(90.98,61.16) 90.98,61.75 C426.1 ; C436.1 86.11,61.89 v1(86.18,61.96) ; C493.1 86.87,53.05 v1(86.98,53.16) ; v1(165.22,64.89) 165.48,64.63 165.48,61.98 166.88,60.58 v2(166.88,56.77)
  BOTTOM w0.508: C394.1 v2(97.92,70.08) ; C391.1 v2(101.85,70.08) ; C395.1 v2(96.65,70.08) ; C392.1 v2(100.71,70.08) ; C393.1 v2(99.31,70.08)
  vias: v2(161.8,54.36) v2(163.32,54.36)
VDDS_1V8_APM: length 79.8
  TOP w0.635: L18.1 166.24,59.8 ; L18.1 167.56,58.8 ; L18.1 166.24,57.8 ; L18.1 164.92,58.8 ; R219.2 162.69,57.35 ; R219.2 161.42,56.72 ; R219.2 163.96,56.72 ; 180.77,54.48 R220.2 ; R220.2 181.41,55.75 ; R220.2 181.41,53.21 ; 168.73,59.03 C160.1 ; C160.1 170.43,57.96 ; C160.1 172.14,59.03 ; C160.1 170.43,60.1
  L7-SIGNAL w0.127: v2(212.47,53.72) 212.14,53.39 210.49,53.39 209.02,54.86 207.62,54.86 205.85,56.64 186.18,56.64 185.93,56.39 183.79,56.39 183.28,55.88 181.33,55.88 180.83,56.39 177.95,56.39 177.44,55.88 165.74,55.88 164.97,56.64 162.18,56.64 161.69,57.13 v2(161.69,57.77)
  BOTTOM w0.127: v2(212.47,53.72) 212.47,53.74 212.6,53.87 J18.26
  BOTTOM w0.305: U71.10 180.48,53.48 v2(180.21,53.21) ; U71.8 v2(180.21,54.48) ; U70.8 v2(162.69,57.78) ; U70.10 v2(161.69,57.77)
VDDSHV11: length 2.3
  TOP w0.305: U42.H8 v1(98.18,61.96)
  BOTTOM w0.305: U122.7 v2(111.43,75.76)
  BOTTOM w0.508: C424.1 v2(105.92,62.59)
VDDSHV_3V3: length 138.7
  TOP w0.305: v2(145.03,92.84) 145.3,93.1 U81.9 ; U42.AA7 v1(87.78,61.96) U42.Y8 ; U42.V8 v1(89.38,61.96) U42.W7 ; U42.L7 v1(95.78,62.76) ; U42.AA14 v1(86.98,57.16) ; U42.J7 v1(96.58,61.96) U42.K8 ; U42.G9 v1(98.99,61.16) ; U42.G17 v1(98.18,54.76) U42.H16 ; v1(98.99,52.36) U42.G19 U42.H18 ; U42.P8 v1(93.38,61.96) U42.N7 ; U42.G21 v1(98.99,50.76) ; U42.H12 v1(98.18,58.76) U42.G11 ; U42.G15 v1(98.99,55.56) ; U42.G7 v1(98.99,62.76) ; U42.G13 v1(98.99,57.96)
  TOP w0.381: v2(93.9,78.46) 94.41,78.46 C149.1 94.41,77.44 v2(93.9,77.44) ; v2(93.9,79.48) 94.41,79.48 C145.1 94.41,80.49 v2(93.9,80.49)
  TOP w0.508: C151.1 v2(94.23,76.45) ; C152.1 v2(94.23,75.18)
  L7-SIGNAL w0.127: v2(145.03,92.84) 145.03,93.34 145.54,93.85 155.96,93.85 156.26,93.55 164.01,93.55 170.82,86.74 190.9,86.74 192.93,84.71 201.7,84.71 205.89,80.52 212.75,80.52 215.77,77.49 215.77,63.39 216.92,62.25 216.92,56.87 214.52,54.48 211.84,54.48 211.71,54.61 211.56,54.61 211.51,54.66 211.15,54.66 211.1,54.61 211,54.61 v2(210.62,54.23)
  BOTTOM w0.132: J18.24 212.25,54.26 211.71,53.72 211.12,53.72 v2(210.62,54.23)
  BOTTOM w0.305: v1(98.99,55.56) 99.06,55.49 C476.1 ; C421.1 96.52,62.03 v1(96.58,61.96) ; C425.1 89.38,62.51 v1(89.38,61.96) ; v1(87.78,61.96) 87.21,61.96 C427.1 ; C432.1 93.12,61.7 v1(93.38,61.96) ; C422.1 95.73,62.71 v1(95.78,62.76) ; v1(86.98,57.16) 86.61,56.8 C460.1
  BOTTOM w0.508: C397.1 v2(94.36,70.08) ; C398.1 v2(92.96,70.08) ; C399.1 v2(91.82,70.08)
  vias: v2(93.09,91.41) v2(93.09,90.55) v2(145.8,92.84) v2(146.56,92.84)
VIN2_S0: length 81.6
  TOP w0.132: v1(102.98,95.5) RU8.1 ; U27.2 v1(119.63,99.57)
  L7-SIGNAL w0.089: v1(102.98,95.5) 104.38,96.9 116.97,96.9 v1(119.63,99.57)
  L14-SIGNAL w0.109: v1(74.56,127.77) 76.6,125.73 92.46,125.73 93.22,124.97 93.22,121.03 99.82,114.43 99.82,112.65 98.93,111.76 98.93,107.57 96.9,105.54 96.9,98.17 99.07,96 99.73,96 100.51,95.22 102.7,95.22 v1(102.98,95.5)
  BOTTOM w0.132: v1(74.56,127.77) 75.13,128.34 U110.6 ; R501.2 119.34,99.86 v1(119.63,99.57)
VIN2_S0N: length 27.5
  TOP w0.132: U27.4 120.28,103.49 119.38,104.39 v1(116.59,104.39) ; v1(102.11,99.69) 102.11,100.77 102.63,101.3 RU8.56
  L7-SIGNAL w0.089: v1(102.11,99.69) 102.49,99.31 103.07,99.31 103.08,99.32 105.91,99.32 106.96,98.27 114.78,98.27 115.95,99.44 115.95,100.97 115.7,101.22 115.7,103.25 115.94,103.5 115.94,103.75 v1(116.59,104.39)
VIN2_S2: length 27.7
  TOP w0.132: U23.2 v1(68.83,103.25)
  L7-SIGNAL w0.089: v1(74.1,124.65) 74.1,121.48 71.75,119.13 71.75,111.76 70.2,110.21 70.2,107.42 69.6,106.81 69.6,104.78 68.83,104.01 v1(68.83,103.25)
  BOTTOM w0.132: R493.2 68.83,103.97 v1(68.83,103.25) ; v1(74.1,124.65) 75.19,125.74 U110.10
VIN2_S2N: length 71.5
  TOP w0.132: RU4.1 121.42,111.26 v1(121.03,110.87) ; RU8.55 103.48,99.29 103.5,99.26 v1(103.5,98.1) ; U23.4 v1(70.13,106.02)
  L10-SIGNAL w0.089: v1(103.5,98.1) 100.51,98.1 100.2,97.79 90.55,97.79 90.42,97.66 89.15,97.66 89.03,97.79 83.69,97.79 83.45,98.04 76.21,98.04 75.31,98.93 75.31,100.46 73.41,102.36 73.41,103.76 71.15,106.02 v1(70.13,106.02)
  L14-SIGNAL w0.109: v1(103.5,98.1) 106.24,98.1 106.43,97.92 115.32,97.92 116.33,98.93 116.33,99.69 121.03,104.39 v1(121.03,110.87)
VIN6_SEL_S0: length 126.7
  L10-SIGNAL w0.089: v1(142.62,91.31) 142.62,90.42 146.94,86.11 146.94,82.17 147.45,81.66 v1(147.45,80.14)
  L14-SIGNAL w0.109: v1(142.62,91.31) 142.11,91.82 142.11,95.63 142.52,96.04 142.52,105.89 141.86,106.55 141.86,111.12 140.97,112.01 140.97,117.35 139.57,118.75 133.86,118.75 132.97,119.63 132.97,121.28 132.08,122.17 132.08,128.78 128.65,132.21 118.24,132.21 117.22,133.22 109.22,133.22 108.08,134.36 92.59,134.36 91.98,134.96 85.31,134.96 82.42,132.08 v1(81.53,132.08)
  BOTTOM w0.132: RU18.1 143.15,91.84 v1(142.62,91.31) ; U121.2 R538.2 148.12,80.14 v1(147.45,80.14) ; U110.5 77.64,128.99 78.36,128.27 80.77,128.27 81.53,129.03 v1(81.53,132.08)
VIN[2]A_CLK: length 40.3
  TOP w0.132: RU4.2 122.07,114.4 v1(121.67,114.81)
  L10-SIGNAL w0.089: v1(92.98,117.17) 92.98,116.31 94.11,115.19 111.11,115.19 111.24,115.06 111.24,114.18 111.37,114.05 111.56,114.05 111.69,114.18 111.69,115.06 111.82,115.19 112,115.19 112.13,115.06 112.13,114.18 112.26,114.05 112.45,114.05 112.58,114.18 112.58,115.06 112.71,115.19 112.89,115.19 113.02,115.06 113.02,114.18 113.15,114.05 113.34,114.05 113.47,114.18 113.47,115.06 113.6,115.19 121.28,115.19 v1(121.67,114.81)
  BOTTOM w0.132: EXP_P2.61 v1(92.98,117.17)
VIN[2]A_D[0]: length 76.1
  TOP w0.132: RU8.53 104.48,99.39 104.65,99.22 v1(104.65,98.81)
  L14-SIGNAL w0.109: v1(104.65,98.81) 103.38,98.81 103.11,98.54 103.11,97.81 103.25,97.66 105.79,97.66 106.05,97.41 106.05,96.9 105.41,96.27 104.95,96.27 104.79,96.43 104.79,97.12 104.63,97.28 104.4,97.28 104.24,97.12 104.24,96.43 104.08,96.27 103.86,96.27 103.7,96.43 103.7,97.12 103.54,97.28 103.31,97.28 103.15,97.12 103.15,96.43 102.99,96.27 102.77,96.27 102.61,96.43 102.61,99.03 102.45,99.19 102.22,99.19 102.06,99.03 102.06,96.43 101.9,96.27 101.67,96.27 101.51,96.43 101.51,99.03 101.35,99.19 101.13,99.19 100.97,99.03 100.97,96.43 100.81,96.27 100.58,96.27 99.85,97 99.85,97.22 100.52,97.88 100.52,98.11 100.36,98.27 100.13,98.27 99.47,97.61 99.24,97.61 98.81,98.04 98.81,99.13 98.97,99.29 100.04,99.29 100.2,99.45 100.2,99.68 100.04,99.84 98.97,99.84 98.81,100 98.81,100.26 98.97,100.42 106.14,100.42 106.3,100.58 106.3,100.8 106.14,100.97 98.97,100.97 98.81,101.13 98.81,103.5 98.17,104.14 98.17,105.23 99.84,106.9 99.84,107.37 99.31,107.9 99.31,110.24 99.81,110.73 99.81,111.62 100.19,112 100.19,115.68 100.03,115.84 99.16,115.84 99,116 99,116.23 99.16,116.39 100.03,116.39 100.19,116.55 v1(100.19,117.93)
  BOTTOM w0.132: EXP_P2.79 v1(100.19,117.93)
VIN[2]A_D[1]: length 72.6
  TOP w0.132: v1(105.48,99.69) RU8.51
  L5-SIGNAL w0.089: v1(105.48,99.69) 104.72,100.46 100.8,100.46 100.71,100.55 100.71,100.76 100.84,100.89 102.87,100.89 103,101.02 103,101.21 102.87,101.34 100.84,101.34 100.71,101.47 100.71,101.65 100.84,101.78 102.87,101.78 103,101.91 103,102.1 102.87,102.23 100.84,102.23 100.71,102.36 100.71,102.57 100.84,102.7 102.87,102.7 103,102.83 103,103.02 102.87,103.15 100.84,103.15 100.71,103.28 100.71,103.46 100.84,103.59 102.87,103.59 103,103.72 103,103.91 102.87,104.04 100.84,104.04 100.71,104.17 100.71,105.13 100.84,105.26 104.14,105.26 104.27,105.39 104.27,105.58 104.14,105.71 100.84,105.71 100.71,105.84 100.71,106.02 100.84,106.15 104.14,106.15 104.27,106.28 104.27,106.46 104.14,106.59 100.84,106.59 100.71,106.72 100.71,106.91 100.84,107.04 104.14,107.04 104.27,107.17 104.27,107.35 104.14,107.48 100.84,107.48 100.71,107.61 100.71,107.8 100.84,107.93 104.14,107.93 104.27,108.06 104.27,108.24 104.14,108.37 100.84,108.37 100.71,108.5 100.71,109.34 100.58,109.47 100.44,109.47 100.31,109.6 100.31,109.65 100.18,109.78 95.89,109.78 95.76,109.91 95.76,110.09 95.89,110.22 100.18,110.22 100.31,110.35 v1(100.31,111.4)
  BOTTOM w0.132: EXP_P2.80 100.19,111.23 100.31,111.36 v1(100.31,111.4)
VIN[2]A_D[2]: length 74.9
  TOP w0.132: v1(106.53,103.76) 106.98,103.31 RU8.48
  L5-SIGNAL w0.089: v1(106.53,103.76) 104.9,105.38 104.9,108.75 104.81,108.84 102.75,108.84 102.62,108.97 102.62,109.15 102.75,109.28 104.86,109.28 104.99,109.41 104.99,109.6 104.86,109.73 102.75,109.73 102.62,109.86 102.62,110.04 102.75,110.17 104.86,110.17 104.99,110.3 104.99,110.52 104.86,110.65 101.1,110.65 100.97,110.78 100.97,110.96 101.1,111.09 104.86,111.09 104.99,111.22 104.99,111.44 104.86,111.57 100.97,111.57 100.84,111.7 100.84,111.88 100.97,112.01 104.86,112.01 104.99,112.14 104.99,112.33 104.86,112.46 100.97,112.46 100.84,112.59 100.84,112.77 100.97,112.9 104.86,112.9 104.99,113.03 104.99,113.22 104.86,113.35 100.97,113.35 100.84,113.48 100.84,113.66 100.97,113.79 104.86,113.79 104.99,113.92 104.99,114.11 104.86,114.24 100.97,114.24 100.84,114.37 100.84,114.55 100.97,114.68 104.86,114.68 104.99,114.81 104.99,115 104.86,115.13 100.97,115.13 100.84,115.26 100.84,115.44 100.97,115.57 104.86,115.57 104.99,115.7 v1(104.99,117.17)
  BOTTOM w0.132: EXP_P2.81 v1(104.99,117.17)
VIN[2]A_D[3]: length 74.4
  TOP w0.132: v1(108.46,98.68) 107.98,99.16 RU8.46
  L5-SIGNAL w0.089: v1(108.46,98.68) 110.11,97.03 113.41,97.03 116.59,100.2 116.59,101.6 117.22,102.24 117.22,105.16 116.46,105.92 115.82,105.92 115.57,106.17 115.57,109.6 114.05,111.12 112.44,111.12 112.31,111.26 112.31,112.01 112.18,112.14 112,112.14 111.87,112.01 111.87,111.26 111.73,111.12 111.55,111.12 111.42,111.26 111.42,112.01 111.29,112.14 111.11,112.14 110.98,112.01 110.98,111.26 110.85,111.12 105.66,111.12 105.41,110.87 105.41,107.7 106.05,107.06 106.86,107.06 106.99,106.93 106.99,104.65 107.12,104.52 107.3,104.52 107.43,104.65 107.43,106.93 107.56,107.06 107.75,107.06 107.88,106.93 107.88,104.65 108.01,104.52 108.19,104.52 108.32,104.65 108.32,106.93 108.45,107.06 108.64,107.06 108.77,106.93 108.77,104.65 108.9,104.52 109.08,104.52 109.21,104.65 109.21,106.93 109.34,107.06 110.24,107.06 110.74,106.55 110.74,106.05 110.11,105.41 110.11,104.65 109.47,104.01 109.47,103.39 109.33,103.25 107.82,103.25 105.41,105.66 v1(105.41,106.68)
  BOTTOM w0.132: EXP_P2.82 104.99,107.51 105.41,107.09 v1(105.41,106.68)
VIN[2]A_D[4]: length 73.3
  TOP w0.132: v1(109.47,98.68) 108.98,99.17 RU8.44
  L7-SIGNAL w0.089: v1(105.79,117.93) 105.79,118.3 105.79,118.31 105.79,123.7 105.41,124.08 104.9,124.08 103.5,122.68 103.5,118.78 103.51,118.78 103.51,118.46 103.5,118.45 103.5,107.32 102.36,106.17 102.36,105.97 102.49,105.84 103.54,105.84 103.63,105.75 103.63,105.48 103.54,105.39 102.49,105.39 102.36,105.26 102.36,104.39 101.98,104.01 101.98,103.81 102.11,103.68 103.5,103.68 103.63,103.55 103.63,103.37 103.5,103.24 102.11,103.24 101.98,103.1 101.98,100.58 102.36,100.2 102.56,100.2 102.7,100.33 102.7,102.1 102.83,102.23 103.01,102.23 103.14,102.1 103.14,100.33 103.27,100.2 103.45,100.2 103.58,100.33 103.58,102.1 103.71,102.23 103.9,102.23 104.03,102.1 104.03,100.33 104.16,100.2 104.34,100.2 104.47,100.33 104.47,102.1 104.6,102.23 104.79,102.23 104.92,102.1 104.92,100.33 105.05,100.2 105.23,100.2 105.36,100.33 105.36,102.1 105.49,102.23 105.68,102.23 105.81,102.1 105.81,100.33 105.94,100.2 106.12,100.2 106.25,100.33 106.25,102.1 106.38,102.23 106.57,102.23 106.7,102.1 106.7,100.33 106.83,100.2 107.01,100.2 107.14,100.33 107.14,102.1 107.27,102.23 107.45,102.23 107.58,102.1 107.58,100.33 107.72,100.2 108.58,100.2 108.97,99.82 108.97,99.19 v1(109.47,98.68)
  BOTTOM w0.132: EXP_P2.83 v1(105.79,117.93)
VIN[2]A_D[5]: length 74.2
  TOP w0.132: v1(110.49,98.68) 109.98,99.19 RU8.42
  L5-SIGNAL w0.089: v1(110.49,98.68) 110.49,97.66 110.74,97.41 111.44,97.41 111.57,97.54 111.57,98.04 111.7,98.17 111.89,98.17 112.02,98.04 112.02,97.54 112.15,97.41 112.33,97.41 112.46,97.54 112.46,98.04 112.59,98.17 112.78,98.17 112.91,98.04 112.91,97.54 113.04,97.41 113.22,97.41 113.35,97.54 113.35,98.04 113.48,98.17 113.67,98.17 114.05,98.55 114.05,98.76 114.04,98.77 114.04,99.09 114.04,99.1 114.04,99.86 113.67,100.23 113.67,100.45 113.8,100.58 116.12,100.58 116.2,100.67 116.2,100.93 116.12,101.02 113.8,101.02 113.67,101.15 113.67,101.34 113.8,101.47 116.12,101.47 116.2,101.55 116.2,101.82 116.12,101.91 113.8,101.91 113.67,102.04 113.67,104.78 113.8,104.91 115.35,104.91 115.44,105 115.44,105.27 115.35,105.36 113.8,105.36 113.67,105.49 113.67,105.7 113.8,105.84 114.3,105.84 114.43,105.97 114.43,106.15 114.3,106.28 113.8,106.28 113.67,106.41 113.67,106.59 113.8,106.72 114.3,106.72 114.43,106.85 114.43,107.04 114.3,107.17 113.8,107.17 113.67,107.3 113.67,107.48 113.8,107.61 114.3,107.61 114.43,107.74 114.43,107.93 114.3,108.06 113.8,108.06 113.67,108.19 113.67,108.58 113.28,108.97 112.39,108.97 112.26,109.1 112.26,110.61 112.13,110.74 111.95,110.74 111.82,110.61 111.82,109.1 111.69,108.97 111.5,108.97 111.37,109.1 111.37,110.61 111.24,110.74 111.06,110.74 110.93,110.61 110.93,109.1 110.8,108.97 110.61,108.97 110.48,109.1 110.48,110.61 110.35,110.74 110.17,110.74 110.04,110.61 110.04,109.1 109.91,108.97 109.72,108.97 109.59,109.1 109.59,110.61 109.46,110.74 109.28,110.74 109.15,110.61 109.15,109.1 109.02,108.97 108.84,108.97 108.71,109.1 108.71,110.61 108.57,110.74 108.39,110.74 108.26,110.61 108.26,109.1 108.13,108.97 107.95,108.97 107.82,109.1 107.82,110.61 107.69,110.74 107.5,110.74 107.37,110.61 107.37,109.1 107.24,108.97 107.06,108.97 106.93,109.1 106.93,110.61 106.8,110.74 105.92,110.74 105.79,110.62 105.79,110.4 105.92,110.27 106.3,110.27 106.43,110.14 106.43,109.96 106.3,109.83 105.92,109.83 105.79,109.7 105.79,109.51 105.92,109.38 106.3,109.38 106.43,109.25 106.43,109.07 106.3,108.94 105.92,108.94 105.79,108.81 105.79,107.93 v1(106.16,107.57)
  BOTTOM w0.132: v1(106.16,107.57) 105.79,107.94 EXP_P2.84
VIN[2]A_D[6]: length 74.3
  TOP w0.132: v1(110.49,99.72) 110.98,100.21 RU8.40
  L7-SIGNAL w0.089: v1(107.39,117.93) 107.39,125.15 107.19,125.35 106.55,125.35 106.3,125.09 106.3,117.6 106.17,117.47 105.66,117.47 105.41,117.73 105.41,122.94 105.03,123.32 104.65,123.32 103.89,122.56 103.89,111.61 104.14,111.35 105.53,111.35 105.66,111.22 105.66,111.04 105.53,110.91 104.14,110.91 104.01,110.77 104.01,110.59 104.14,110.46 105.53,110.46 105.66,110.33 105.66,110.15 105.53,110.02 104.14,110.02 104.01,109.89 104.01,109.7 104.14,109.57 105.53,109.57 105.66,109.44 105.66,109.26 105.53,109.13 104.14,109.13 104.01,109 104.01,108.81 104.14,108.68 105.53,108.68 105.66,108.55 105.66,108.37 105.53,108.24 104.14,108.24 104.01,108.11 104.01,107.92 104.14,107.79 105.53,107.79 105.66,107.66 105.66,107.48 105.53,107.35 104.14,107.35 104.01,107.22 104.01,107.02 104.14,106.89 104.77,106.89 104.9,106.75 104.9,106.57 104.77,106.44 104.14,106.44 104.01,106.31 104.01,106.11 104.14,105.98 105.03,105.98 105.16,105.85 105.16,105.66 105.03,105.53 104.14,105.53 104.01,105.4 104.01,104.78 104.52,104.27 105.66,104.27 105.92,104.01 105.92,103.63 106.17,103.38 108.2,103.38 108.46,103.12 108.46,101.75 v1(110.49,99.72)
  BOTTOM w0.132: EXP_P2.87 v1(107.39,117.93)
VIN[2]A_D[7]: length 70.3
  TOP w0.132: RU8.37 112.48,100.09 112.81,99.75 112.81,99.22 v1(112.39,98.81)
  L5-SIGNAL w0.089: v1(112.39,98.81) 112.9,99.31 112.9,100.67 112.77,100.8 104.02,100.8 103.89,100.93 103.89,101.12 104.02,101.25 112.77,101.25 112.9,101.38 112.9,101.56 112.77,101.69 104.02,101.69 103.89,101.82 103.89,102.01 104.02,102.14 112.77,102.14 112.9,102.27 112.9,102.99 113.13,103.22 113.13,103.83 113,103.96 110.62,103.96 110.49,104.09 110.49,104.27 110.62,104.4 113,104.4 113.13,104.53 113.13,104.71 113,104.84 110.62,104.84 110.49,104.97 110.49,105.16 110.62,105.29 113,105.29 113.13,105.42 113.13,105.64 113,105.77 112.14,105.77 112.01,105.9 112.01,106.08 112.14,106.21 113,106.21 113.13,106.34 113.13,106.52 113,106.65 112.14,106.65 112.01,106.78 112.01,106.97 112.14,107.1 113,107.1 113.13,107.23 113.13,107.73 112.39,108.46 107.57,108.46 107.39,108.28 v1(107.39,107.52)
  BOTTOM w0.132: EXP_P2.88 v1(107.39,107.52)
VIN[2]A_D[8]: length 66.5
  TOP w0.132: v1(113.48,99.69) RU8.35
  L7-SIGNAL w0.089: v1(113.48,99.69) 112.97,100.2 110.62,100.2 109.35,101.47 109.35,103.01 108.61,103.76 107.19,103.76 106.3,104.65 104.68,104.65 104.55,104.78 104.55,104.97 104.68,105.1 106.55,105.1 106.68,105.23 106.68,105.43 106.55,105.56 105.67,105.56 105.54,105.69 105.54,105.87 105.67,106 106.55,106 106.68,106.13 106.68,106.34 106.55,106.47 106.05,106.47 105.92,106.6 105.92,106.78 106.05,106.91 106.46,106.91 106.55,107 106.55,107.99 106.46,108.08 106.18,108.08 106.05,108.21 106.05,108.39 106.18,108.52 106.55,108.52 106.68,108.65 106.68,108.83 106.55,108.96 106.18,108.96 106.05,109.1 106.05,109.28 106.18,109.41 106.55,109.41 106.68,109.54 106.68,109.72 106.55,109.85 106.18,109.85 106.05,109.98 106.05,110.17 106.18,110.3 106.55,110.3 106.68,110.43 106.68,110.87 105.66,111.89 104.52,111.89 104.27,112.14 104.27,112.34 104.4,112.47 105.79,112.47 105.92,112.6 105.92,112.79 105.79,112.92 104.4,112.92 104.27,113.05 104.27,113.23 104.4,113.36 105.79,113.36 105.92,113.49 105.92,113.68 105.79,113.81 104.4,113.81 104.27,113.94 104.27,114.12 104.4,114.25 105.79,114.25 105.92,114.38 105.92,114.57 105.79,114.7 104.4,114.7 104.27,114.83 104.27,115.01 104.4,115.14 105.79,115.14 105.92,115.27 105.92,115.46 105.79,115.59 104.4,115.59 104.27,115.72 104.27,115.9 104.4,116.03 105.79,116.03 105.92,116.16 105.92,116.34 105.79,116.48 104.4,116.48 104.27,116.61 104.27,122.43 104.52,122.68 104.78,122.68 105.03,122.43 105.03,117.66 105.52,117.17 v1(108.19,117.17)
  BOTTOM w0.132: EXP_P2.89 v1(108.19,117.17)
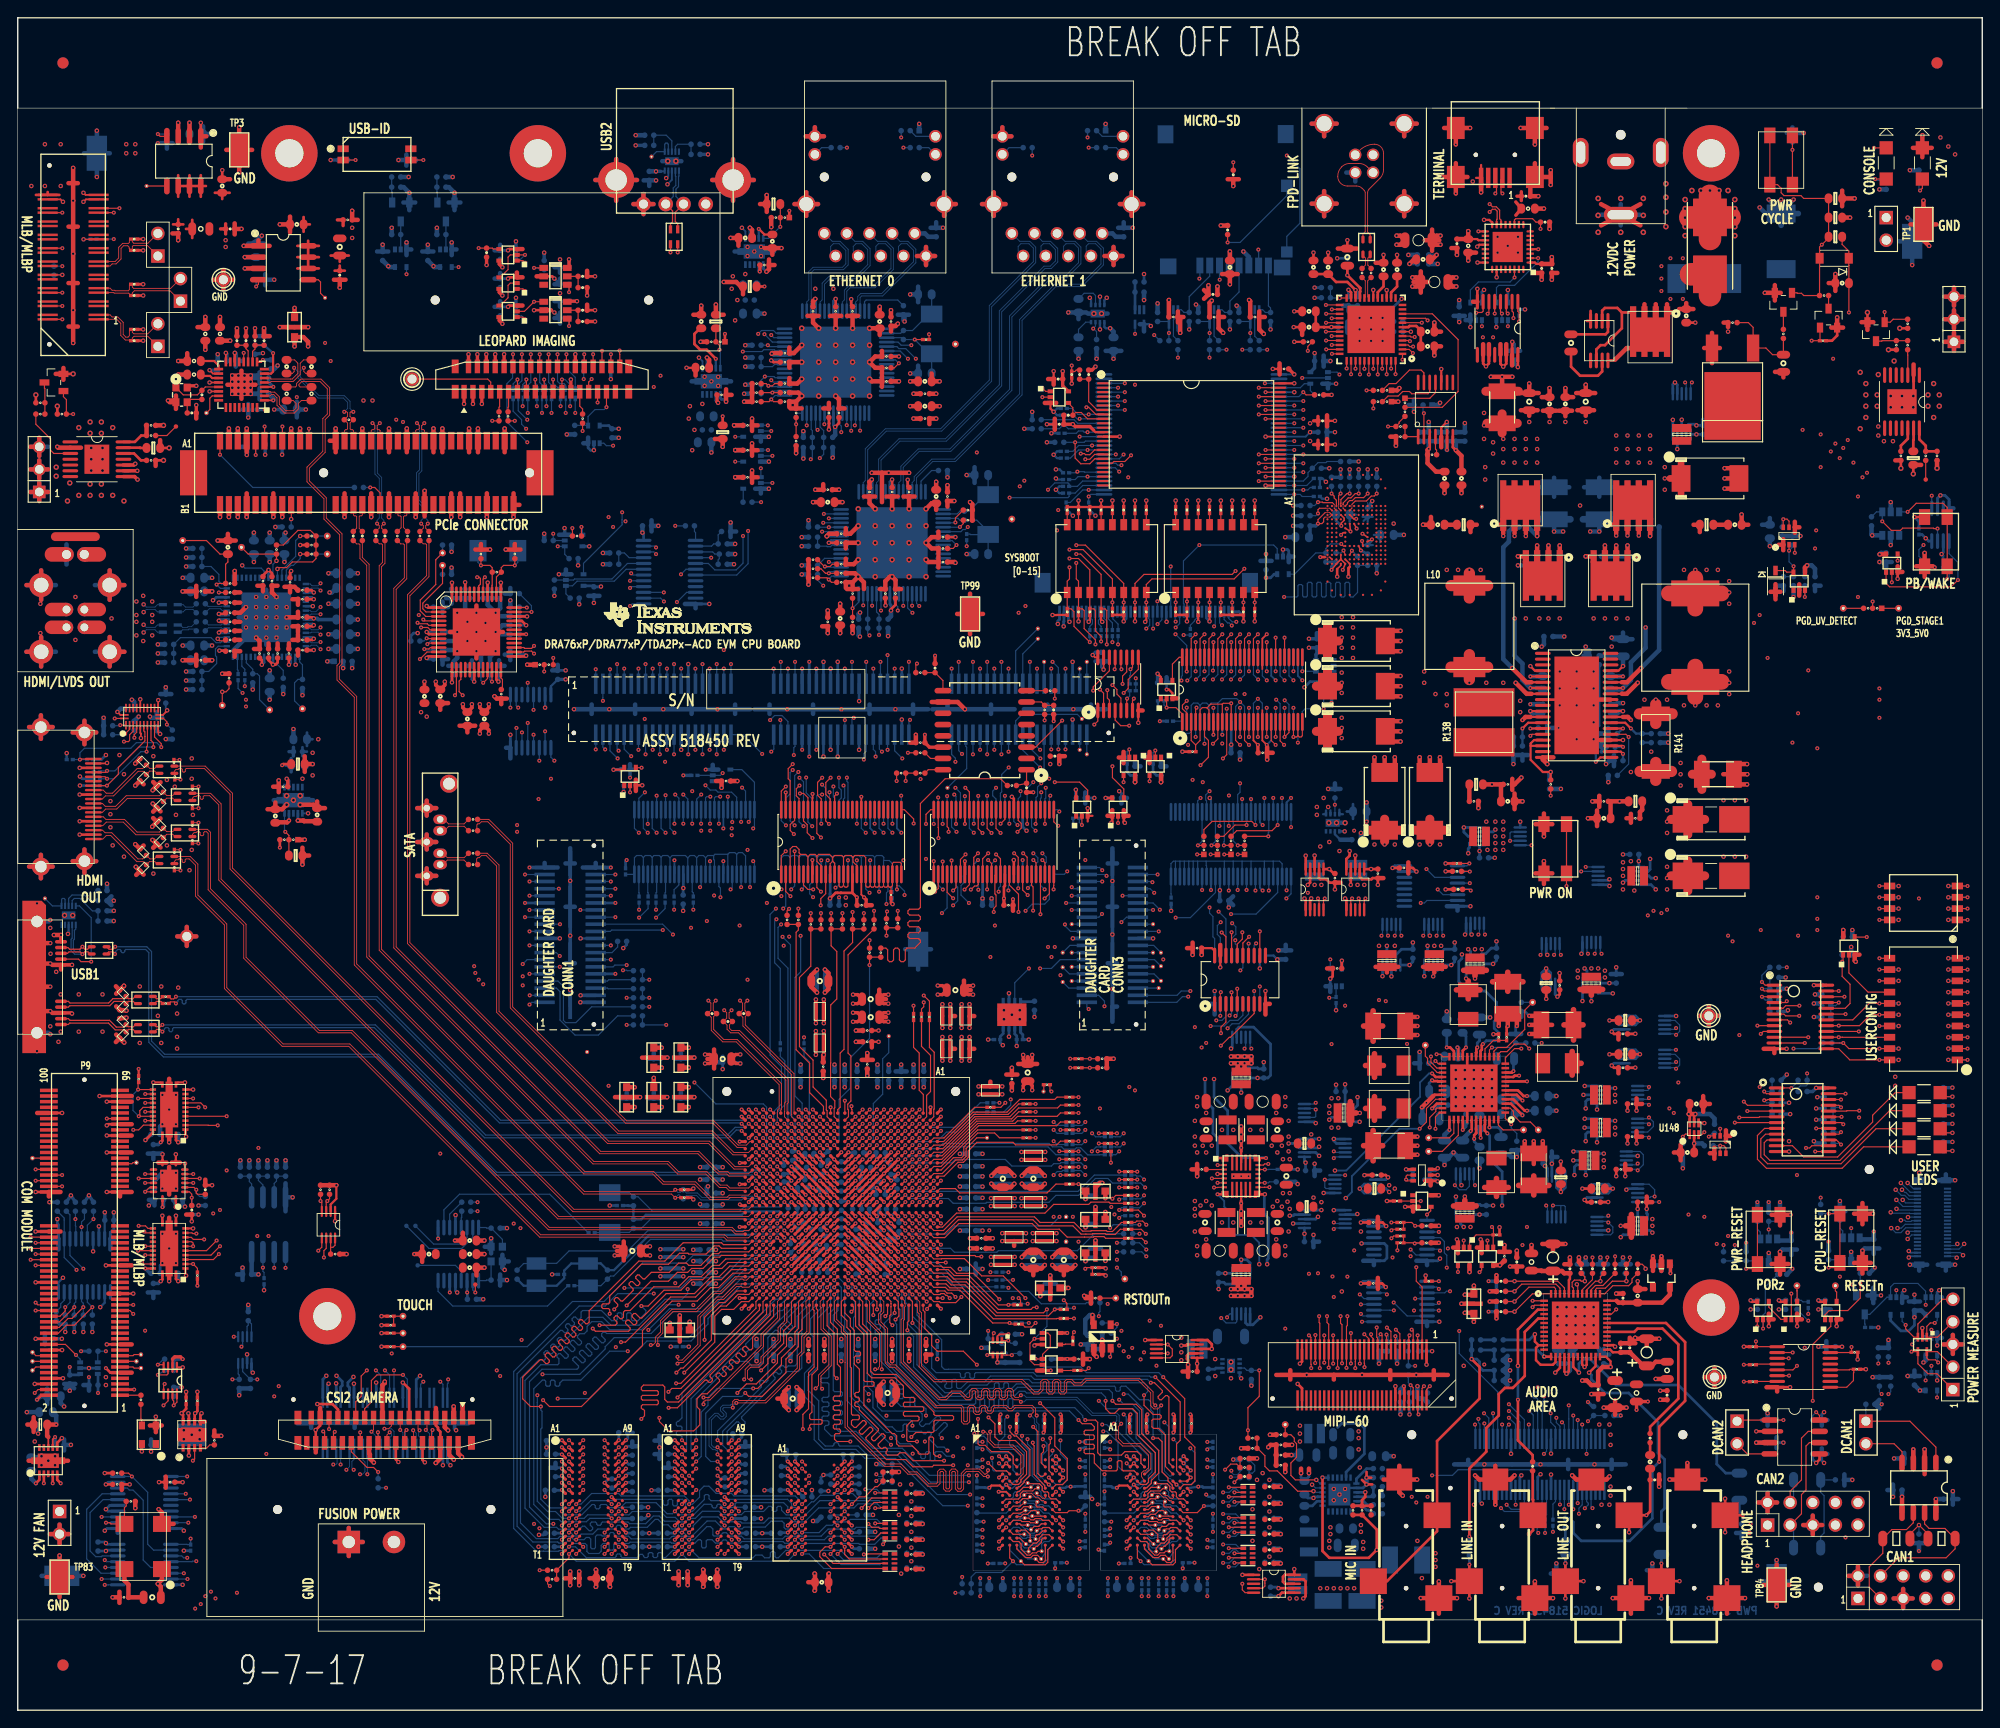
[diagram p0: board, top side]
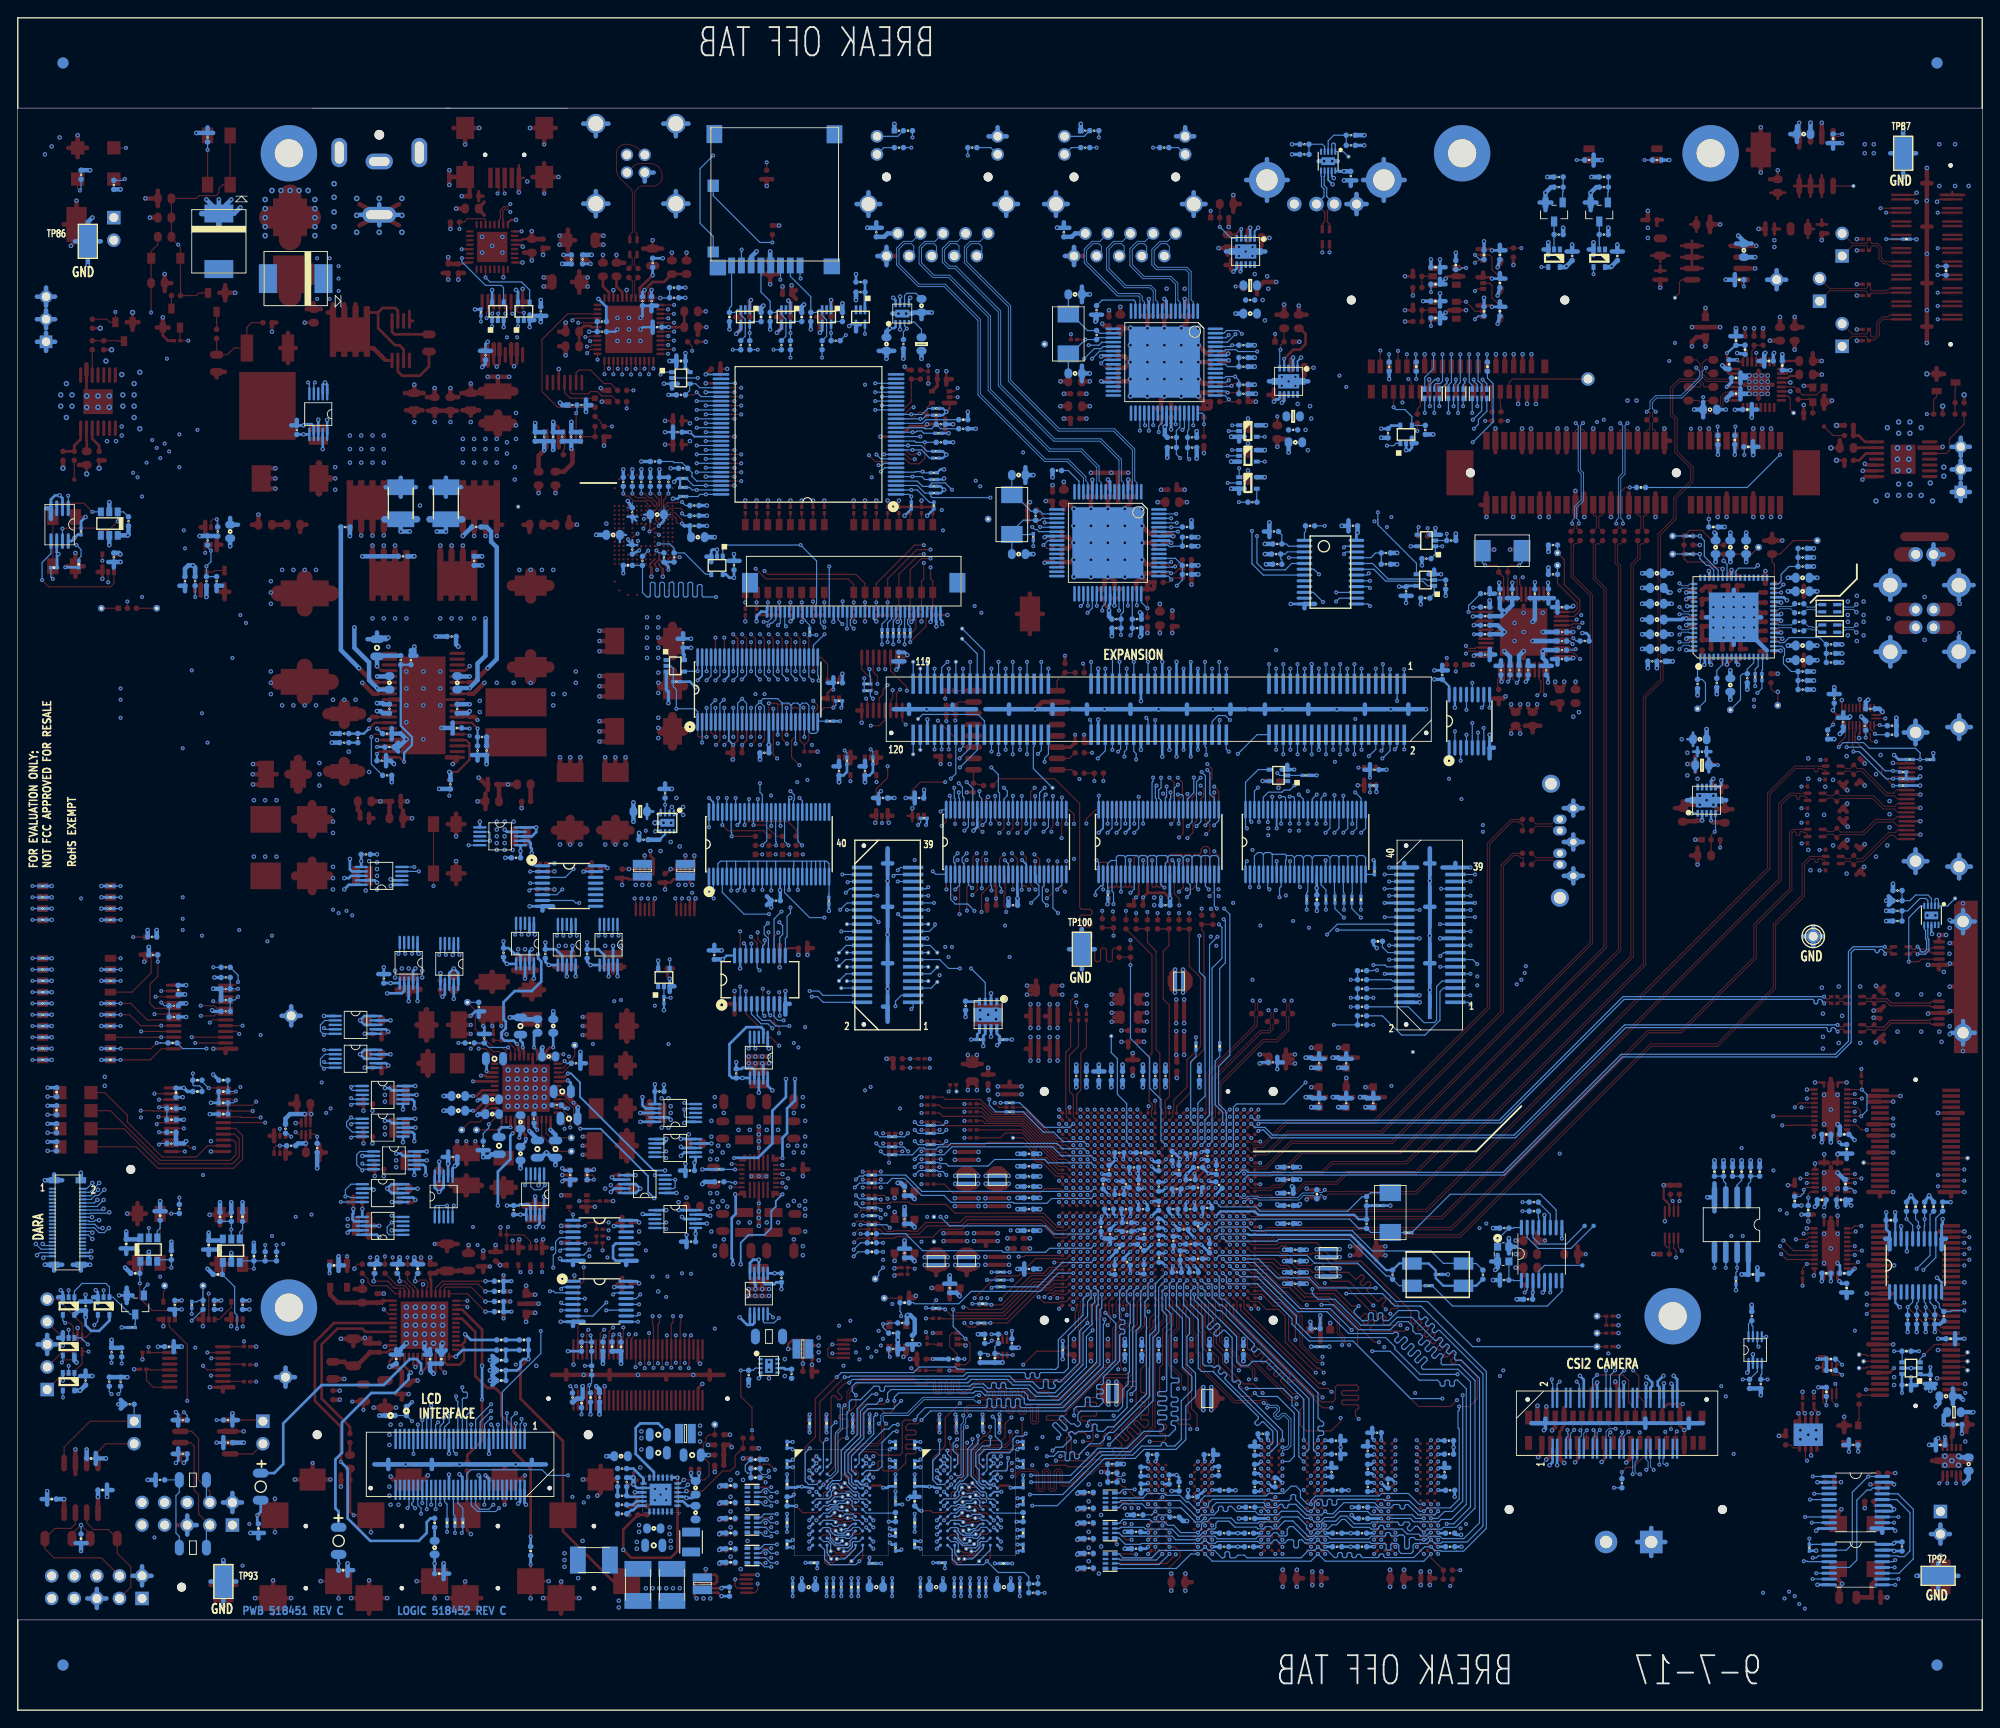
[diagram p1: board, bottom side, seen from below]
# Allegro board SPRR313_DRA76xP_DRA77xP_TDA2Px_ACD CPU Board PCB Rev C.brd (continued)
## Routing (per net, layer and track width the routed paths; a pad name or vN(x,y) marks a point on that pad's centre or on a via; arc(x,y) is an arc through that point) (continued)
VIN[2]A_D[9]: length 64.8
  TOP w0.132: RU8.33 114.48,99.75 v1(114.43,99.69)
  L7-SIGNAL w0.089: v1(114.43,99.69) 113.54,100.58 110.74,100.58 109.7,101.62 109.7,103.28 109.61,103.37 109.61,104.01 109.47,104.14 109.45,104.14 109.32,104.27 109.32,104.77 109.19,104.9 109.01,104.9 108.88,104.77 108.88,104.27 108.75,104.14 108.56,104.14 108.43,104.27 108.43,104.77 108.3,104.9 108.12,104.9 107.99,104.77 107.99,104.27 107.86,104.14 107.31,104.14 106.93,104.52 106.93,105.36 107.06,105.49 108.07,105.49 108.2,105.62 108.2,105.81 108.07,105.94 107.06,105.94 106.93,106.07 106.93,106.25 107.06,106.38 108.07,106.38 108.2,106.51 108.2,106.7 108.07,106.83 107.06,106.83 106.93,106.96 106.93,112.65 106.89,112.69 106.89,112.77 106.65,113.01 106.57,113.01 106.43,113.16 106.43,113.42 106.56,113.55 108.07,113.55 108.2,113.68 108.2,113.86 108.07,113.99 106.56,113.99 106.43,114.12 106.43,114.31 106.56,114.44 108.07,114.44 108.2,114.57 108.2,114.75 108.07,114.88 106.56,114.88 106.43,115.01 106.43,115.2 106.56,115.33 108.07,115.33 108.2,115.46 108.2,115.64 108.07,115.77 106.56,115.77 106.43,115.9 106.43,116.2 106.93,116.71 108.08,116.71 108.58,116.2 108.58,113.24 108.45,113.11 107.45,113.11 107.31,112.98 107.31,112.8 107.45,112.67 108.45,112.67 108.58,112.54 108.58,112.35 108.45,112.22 107.45,112.22 107.31,112.09 107.31,111.91 107.45,111.78 108.45,111.78 108.58,111.65 108.58,111.47 108.45,111.34 107.45,111.34 107.31,111.21 107.31,111.02 107.45,110.89 108.45,110.89 108.58,110.76 108.58,110.58 108.45,110.45 107.45,110.45 107.31,110.32 107.31,110.13 107.45,110 108.45,110 108.58,109.87 108.58,109.69 108.45,109.56 107.45,109.56 107.31,109.43 107.31,109.24 107.45,109.11 108.45,109.11 108.58,108.98 108.58,108.43 v1(108.19,108.03)
  BOTTOM w0.132: EXP_P2.90 v1(108.19,108.03)
VIN[2]A_D[10]: length 70
  TOP w0.132: v1(115.48,99.69) RU8.31
  L7-SIGNAL w0.089: v1(115.48,99.69) 115.2,99.98 115.2,100.16 115.57,100.53 115.57,100.72 115.44,100.85 115.25,100.85 114.88,100.47 114.7,100.47 114.21,100.97 114,100.97 113.87,101.1 113.87,101.98 113.74,102.11 113.56,102.11 113.43,101.98 113.43,101.1 113.3,100.97 113.11,100.97 112.98,101.1 112.98,101.98 112.85,102.11 112.67,102.11 112.54,101.98 112.54,101.1 112.41,100.97 112.22,100.97 112.09,101.1 112.09,101.98 111.96,102.11 111.78,102.11 111.65,101.98 111.65,101.1 111.52,100.97 110.87,100.97 110.49,101.35 110.49,104.9 108.58,106.81 108.58,107.95 108.99,108.35 108.99,117.2 107.82,118.36 107.82,118.73 107.95,118.86 108.71,118.86 108.84,118.99 108.84,119.17 108.71,119.3 107.95,119.3 107.82,119.43 107.82,119.61 107.95,119.74 108.71,119.74 108.84,119.88 108.84,120.06 108.71,120.19 107.95,120.19 107.82,120.32 107.82,120.5 107.95,120.63 108.71,120.63 108.84,120.76 108.84,120.95 108.71,121.08 107.95,121.08 107.82,121.21 107.82,121.39 107.95,121.52 108.71,121.52 108.84,121.65 108.84,121.84 108.71,121.97 107.95,121.97 107.82,122.1 107.82,122.28 107.95,122.41 108.71,122.41 108.84,122.54 108.84,122.73 108.71,122.86 107.95,122.86 107.82,122.99 107.82,123.17 107.95,123.3 108.71,123.3 108.84,123.43 108.84,123.62 108.71,123.75 107.95,123.75 107.82,123.88 107.82,124.06 107.95,124.19 108.71,124.19 108.84,124.32 108.84,124.5 108.71,124.63 107.95,124.63 107.82,124.76 107.82,124.95 107.95,125.08 108.71,125.08 108.84,125.21 108.84,125.39 108.71,125.52 107.95,125.52 107.82,125.65 107.82,125.84 107.95,125.97 108.71,125.97 108.84,126.1 108.84,126.28 108.71,126.41 107.95,126.41 107.82,126.54 107.82,126.75 108.2,127.13 108.97,127.13 109.22,126.87 109.22,118.54 108.99,118.3 v1(108.99,117.93)
  BOTTOM w0.132: EXP_P2.91 v1(108.99,117.93)
VIN[2]A_D[11]: length 66.1
  TOP w0.132: v1(116.97,99.48) 116.92,99.48 116.48,99.93 RU8.29
  L3-SIGNAL w0.109: v1(108.99,107.52) 108.99,107.97 109.44,108.43 110.39,108.43 110.99,107.83 110.99,107.45 111.38,107.06 112.52,107.06 114.05,108.58 129.54,108.58 131.32,106.81 131.32,102.49 130.81,101.98 130.05,101.98 129.89,102.14 129.89,103.47 129.73,103.63 129.5,103.63 129.34,103.47 129.34,102.14 129.18,101.98 128.95,101.98 128.79,102.14 128.79,103.52 128.68,103.63 128.35,103.63 128.24,103.52 128.24,102.14 128.08,101.98 127.86,101.98 127.7,102.14 127.7,103.65 127.59,103.76 127.26,103.76 127.15,103.65 127.15,102.14 126.99,101.98 126.76,101.98 126.6,102.14 126.6,103.65 126.49,103.76 126.17,103.76 126.06,103.65 126.06,102.14 125.9,101.98 125.67,101.98 125.51,102.14 125.51,103.65 125.4,103.76 125.07,103.76 124.97,103.65 124.97,102.14 124.81,101.98 123.99,101.98 123.83,102.14 123.83,102.58 123.67,102.74 123.45,102.74 123.29,102.58 123.29,102.14 123.13,101.98 119.47,101.98 v1(116.97,99.48)
  BOTTOM w0.132: EXP_P2.92 v1(108.99,107.52)
VIN[2]A_D[12]: length 64.5
  L7-SIGNAL w0.089: v1(109.79,117.17) 109.79,128.84 113.79,132.84 115.32,132.84 115.7,132.46 115.7,132.26 115.57,132.13 114.94,132.13 114.81,132 114.81,131.81 114.94,131.68 115.57,131.68 115.7,131.55 115.7,131.37 115.57,131.24 114.94,131.24 114.81,131.11 114.81,130.92 114.94,130.79 115.57,130.79 115.7,130.66 115.7,130.48 115.57,130.35 114.94,130.35 114.81,130.22 114.81,130.04 114.94,129.9 115.57,129.9 115.7,129.77 115.7,129.59 115.57,129.46 114.94,129.46 114.81,129.33 114.81,129.15 114.94,129.02 115.57,129.02 115.7,128.89 115.7,128.7 115.57,128.57 114.94,128.57 114.81,128.44 114.81,128.26 114.94,128.13 115.57,128.13 115.7,128 115.7,127.81 115.57,127.68 114.94,127.68 114.81,127.55 114.81,127.37 114.94,127.24 115.57,127.24 115.7,127.11 115.7,126.92 115.57,126.79 114.94,126.79 114.81,126.66 114.81,126.48 114.94,126.35 115.57,126.35 115.7,126.22 115.7,124.21 115.32,123.83 115.32,122.17 116.71,120.78 116.71,114.55 116.08,113.92 116.08,112.9 114.55,111.38 114.55,103.76 v1(115.06,103.25)
  BOTTOM w0.132: v1(115.06,103.25) 115.06,102.63 114.98,102.54 RU15.53 ; EXP_P2.93 v1(109.79,117.17)
VIN[2]A_D[13]: length 65
  L3-SIGNAL w0.109: v1(114.42,98.93) 115.84,98.93 116.2,99.3 116.2,99.86 115.71,100.35 111.79,100.35 111.63,100.51 111.63,100.73 111.79,100.89 115.28,100.89 115.57,101.18 115.57,101.41 115.41,101.57 111.79,101.57 111.63,101.73 111.63,101.96 111.79,102.12 115.41,102.12 115.57,102.28 115.57,103 116.08,103.5 117.01,103.5 117.17,103.67 117.17,105.12 117.33,105.28 117.55,105.28 117.71,105.12 117.71,103.67 117.87,103.5 118.11,103.5 118.75,104.14 119.63,104.14 121.28,105.79 121.28,106.17 121.03,106.43 120.05,106.43 119.89,106.27 119.89,105.19 119.73,105.03 119.5,105.03 119.34,105.19 119.34,106.27 119.18,106.43 118.96,106.43 118.8,106.27 118.8,105.19 118.64,105.03 118.41,105.03 118.25,105.19 118.25,106.27 118.09,106.43 117.86,106.43 117.35,105.92 115.81,105.92 115.06,106.66 113.84,106.66 113.68,106.5 113.68,104.95 113.52,104.79 113.29,104.79 113.13,104.95 113.13,106.5 112.97,106.66 112.74,106.66 112.58,106.5 112.58,104.95 112.42,104.79 112.2,104.79 112.04,104.95 112.04,106.5 111.88,106.66 110.86,106.66 110.7,106.5 110.7,104.43 110.54,104.27 110.32,104.27 110.16,104.43 110.16,106.5 109.79,106.88 v1(109.79,108.03)
  BOTTOM w0.132: EXP_P2.94 v1(109.79,108.03) ; RU15.51 113.98,99.38 v1(114.42,98.93)
VIN[2]A_D[14]: length 68.9
  L7-SIGNAL w0.089: v1(112.74,103.38) 112.74,104.48 113.54,105.28 113.54,105.49 113.41,105.62 112.14,105.62 112.01,105.75 112.01,105.93 112.14,106.06 113.41,106.06 113.54,106.19 113.54,106.38 113.41,106.51 112.14,106.51 112.01,106.64 112.01,106.82 112.14,106.95 113.41,106.95 113.54,107.08 113.54,107.26 113.41,107.39 112.14,107.39 112.01,107.52 112.01,107.71 112.14,107.84 113.41,107.84 113.54,107.97 113.54,108.15 113.41,108.28 112.14,108.28 112.01,108.41 112.01,108.6 112.14,108.73 113.41,108.73 113.54,108.86 113.54,109.04 113.41,109.17 112.14,109.17 112.01,109.3 112.01,109.49 112.14,109.62 113.41,109.62 113.54,109.75 113.54,109.93 113.41,110.06 112.14,110.06 112.01,110.19 112.01,110.38 112.14,110.51 113.41,110.51 113.54,110.64 113.54,110.82 113.41,110.95 112.14,110.95 112.01,111.08 112.01,111.26 112.14,111.4 113.41,111.4 113.54,111.53 113.54,111.71 113.41,111.84 112.14,111.84 112.01,111.97 112.01,112.15 112.14,112.28 113.41,112.28 113.54,112.41 113.54,112.6 113.41,112.73 112.14,112.73 112.01,112.86 112.01,113.04 112.14,113.17 113.41,113.17 113.54,113.3 113.54,116.97 114.3,117.73 114.3,118.24 113.92,118.62 113.92,128.02 113.16,128.78 111.25,128.78 110.59,128.11 v1(110.59,117.93)
  BOTTOM w0.132: v1(112.74,103.38) 112.74,102.8 112.48,102.54 RU15.48 ; EXP_P2.95 v1(110.59,117.93)
VIN[2]A_D[15]: length 71.7
  L12-SIGNAL w0.089: v1(110.59,107.52) 110.92,107.19 111.63,107.19 112.01,107.57 112.01,108.46 111.63,108.84 111.63,110.11 112.28,110.75 112.46,110.75 113.29,109.92 113.48,109.92 113.61,110.05 113.61,110.24 112.78,111.07 112.78,111.25 112.91,111.38 113.09,111.38 113.92,110.55 114.11,110.55 114.24,110.68 114.24,110.87 113.41,111.7 113.41,111.88 113.54,112.01 113.72,112.01 114.55,111.18 114.74,111.18 114.87,111.31 114.87,111.5 114.03,112.33 114.03,112.51 114.16,112.64 114.35,112.64 115.18,111.81 115.36,111.81 115.49,111.94 115.49,112.12 114.66,112.96 114.66,113.14 114.81,113.28 116.84,113.28 117.47,113.92 117.68,113.92 117.81,113.79 117.81,113.14 117.94,113.01 118.12,113.01 118.25,113.14 118.25,113.79 118.38,113.92 118.57,113.92 118.7,113.79 118.7,113.14 118.83,113.01 119.01,113.01 119.14,113.14 119.14,113.79 119.27,113.92 120.82,113.92 121.03,113.7 121.03,113.12 120.82,112.9 120.4,112.9 119.13,111.63 119.13,111 117.98,109.86 117.98,109.09 117.47,108.58 117.27,108.58 117.14,108.72 117.14,110.61 117.01,110.74 116.83,110.74 116.7,110.61 116.7,108.72 116.57,108.58 116.38,108.58 116.25,108.72 116.25,110.61 116.12,110.74 115.94,110.74 115.81,110.61 115.81,108.72 115.68,108.58 114.68,108.58 114.54,108.44 114.35,108.44 113.39,109.4 113.21,109.4 113.08,109.27 113.08,109.08 114.04,108.13 114.04,107.94 113.91,107.81 113.72,107.81 112.76,108.77 112.58,108.77 112.45,108.64 112.45,108.46 113.41,107.5 113.41,107.31 112.27,106.17 112.27,104.92 112.14,104.79 110.87,104.79 110.74,104.66 110.74,104.48 110.87,104.35 112.14,104.35 112.27,104.22 112.27,104.03 112.14,103.9 110.87,103.9 110.74,103.77 110.74,103.59 110.87,103.46 112.14,103.46 112.27,103.33 112.27,101.85 111.48,101.06 v1(111.48,99.72)
  BOTTOM w0.132: EXP_P2.96 v1(110.59,107.52) ; RU15.46 v1(111.48,99.72)
VIN[2]A_D[16]: length 72.1
  L7-SIGNAL w0.089: v1(111.39,117.17) 110.67,117.17 110.21,117.63 110.21,128.5 111.12,129.41 113.67,129.41 114.43,128.65 114.43,122.47 115.77,121.12 115.77,120.12 115.64,119.99 114.43,119.99 114.3,119.86 114.3,119.67 114.43,119.54 115.64,119.54 115.77,119.41 115.77,119.23 115.64,119.1 114.43,119.1 114.3,118.97 114.3,118.78 114.43,118.65 115.64,118.65 115.77,118.52 115.77,115.92 115.64,115.79 114.18,115.79 114.05,115.66 114.05,115.48 114.18,115.35 115.64,115.35 115.77,115.22 115.77,115.03 115.64,114.9 114.18,114.9 114.05,114.77 114.05,114.59 114.18,114.46 115.64,114.46 115.77,114.33 115.77,114.14 115.64,114.01 114.18,114.01 114.05,113.88 114.05,113.7 114.18,113.57 115.64,113.57 115.77,113.44 115.77,113.23 114.96,112.42 114.78,112.42 114.33,112.87 114.14,112.87 114.01,112.74 114.01,112.56 114.46,112.11 114.46,111.92 114.05,111.51 114.05,105.03 113.67,104.65 113.67,103.12 113.41,102.87 112.39,102.87 111.41,103.86 v1(111.41,106.05)
  BOTTOM w0.132: EXP_P2.97 v1(111.39,117.17) ; RU15.44 110.48,102.83 110.47,102.83 110.47,103.16 110.62,103.3 110.62,105.26 v1(111.41,106.05)
VIN[2]A_D[17]: length 70.8
  L12-SIGNAL w0.089: v1(109.48,99.72) 109,100.2 107.31,100.2 106.93,99.82 106.93,99.44 106.68,99.19 105.7,99.19 105.7,99.19 105.07,99.19 104.94,99.32 104.94,99.82 104.81,99.95 104.63,99.95 104.5,99.82 104.5,99.32 104.37,99.19 104.27,99.19 104.01,98.93 104.01,98.06 102.6,96.65 101.98,96.65 101.22,95.89 101.22,94.61 100.97,94.36 100.69,94.36 100.46,94.59 100.46,96.5 100.59,96.63 101.34,96.63 101.47,96.76 101.47,96.95 101.34,97.08 100.59,97.08 100.46,97.21 100.46,97.41 100.98,97.93 101.16,97.93 101.99,97.1 102.18,97.1 102.31,97.23 102.31,97.41 101.48,98.24 101.48,98.43 101.61,98.56 101.79,98.56 102.62,97.73 102.81,97.73 102.94,97.86 102.94,98.04 102.11,98.87 102.11,99.06 102.5,99.45 102.5,99.86 102.49,99.86 102.49,100.2 102.87,100.58 103.05,100.58 103.44,100.19 103.62,100.19 103.75,100.32 103.75,100.51 103.37,100.9 103.37,101.08 103.89,101.6 104.09,101.6 104.22,101.47 104.22,100.59 104.35,100.46 104.53,100.46 104.66,100.59 104.66,101.47 104.79,101.6 104.98,101.6 105.11,101.47 105.11,100.59 105.24,100.46 105.44,100.46 105.57,100.59 105.57,102.1 105.7,102.23 105.89,102.23 106.02,102.1 106.02,100.59 106.15,100.46 106.71,100.46 107.06,100.81 109.98,100.81 110.11,100.94 110.11,101.12 109.98,101.25 107.06,101.25 106.93,101.38 106.93,101.57 107.06,101.7 109.98,101.7 110.11,101.83 110.11,102.01 109.98,102.14 107.06,102.14 106.93,102.27 106.93,102.47 107.06,102.6 107.44,102.6 107.57,102.73 107.57,102.92 107.44,103.05 107.06,103.05 106.93,103.18 106.93,103.38 107.06,103.51 108.96,103.51 109.09,103.64 109.09,103.83 108.96,103.96 107.06,103.96 106.93,104.09 106.93,104.42 110.61,108.1 111.11,108.1 v1(111.39,107.82)
  BOTTOM w0.132: RU15.42 v1(109.48,99.72) ; EXP_P2.98 v1(111.39,107.82)
VIN[2]A_D[18]: length 65.7
  L3-SIGNAL w0.109: v1(116.19,117.17) 117.27,116.08 125.13,116.08 125.53,115.68 127.65,115.68 128.05,115.28 128.49,115.28 128.65,115.12 128.65,114.9 128.49,114.74 128.05,114.74 127.89,114.58 127.89,114.35 128.05,114.19 128.49,114.19 128.65,114.03 128.65,113.8 128.49,113.64 128.05,113.64 127.87,113.47 127.87,112 127.37,111.5 125.8,111.5 125.57,111.27 120.87,111.27 120.63,111.04 120.63,109.58 120.02,108.97 113.67,108.97 113.13,108.43 111.51,108.43 110.44,109.5 109.75,109.5 108.58,108.33 108.58,107.87 108.48,107.76 108.48,106.95 108.64,106.79 109.19,106.79 109.35,106.63 109.35,106.41 109.19,106.25 108.64,106.25 108.48,106.09 108.48,105.86 108.64,105.7 109.19,105.7 109.35,105.54 109.35,105.31 109.19,105.15 108.64,105.15 108.48,104.99 108.48,104.77 108.64,104.61 109.19,104.61 109.35,104.45 109.35,104.22 108.48,103.35 108.48,102.33 108.64,102.17 110.84,102.17 111,102.01 111,101.79 110.84,101.63 108.64,101.63 108.48,101.47 108.48,101.24 108.64,101.08 110.84,101.08 111,100.92 111,100.69 110.84,100.53 108.64,100.53 108.48,100.37 v1(108.48,99.72)
  BOTTOM w0.132: RU15.40 v1(108.48,99.72) ; EXP_P2.109 v1(116.19,117.17)
VIN[2]A_D[19]: length 78.6
  L14-SIGNAL w0.109: v1(107.48,98.7) 106.98,99.2 102.91,99.2 102.58,99.53 102.58,99.91 102.76,100.09 106.7,100.09 106.93,100.33 106.93,102.11 107.19,102.36 107.41,102.36 107.57,102.2 107.57,100.36 107.73,100.2 107.96,100.2 108.12,100.36 108.12,102.2 108.28,102.36 108.5,102.36 108.66,102.2 108.66,100.36 108.82,100.2 109.05,100.2 109.21,100.36 109.21,102.2 109.37,102.36 109.6,102.36 109.76,102.2 109.76,100.36 109.92,100.2 110.14,100.2 110.3,100.36 110.3,102.2 110.46,102.36 111.51,102.36 111.89,101.98 111.89,98.52 112,98.41 114.79,98.41 115.06,98.68 115.06,100.97 116.31,102.21 116.54,102.21 116.79,101.96 116.94,101.96 117.18,102.19 117.18,102.34 116.92,102.6 116.92,102.83 117.08,102.99 117.31,102.99 117.72,102.58 117.94,102.58 118.11,102.74 118.11,103.38 119.7,104.97 119.7,105.32 119.54,105.48 118.4,105.48 118.24,105.64 118.24,105.86 118.4,106.02 119.54,106.02 119.7,106.18 119.7,106.41 119.54,106.57 118.4,106.57 118.24,106.73 118.24,106.95 118.4,107.11 119.54,107.11 119.7,107.27 119.7,107.63 120.14,108.08 120.14,113.79 119.89,114.05 117.35,114.05 117.09,113.79 117.09,113.28 117.35,113.03 119,113.03 119.25,112.78 119.25,112.27 119,112.01 119,111.62 119.01,111.61 119.01,111.01 118.36,110.36 118.36,107.82 117.98,107.44 116.82,107.44 v1(116.19,108.08)
  BOTTOM w0.132: v1(107.48,98.7) 106.98,99.2 RU15.37 ; EXP_P2.110 v1(116.19,108.08)
VIN[2]A_D[20]: length 74.9
  L3-SIGNAL w0.109: v1(116.33,117.93) 115.57,117.17 115.57,115.95 116.08,115.44 122.63,115.44 122.9,115.71 123.3,115.71 124.08,114.94 126.87,114.94 127.38,114.43 127.38,112.14 127.13,111.89 120.9,111.89 120.14,111.12 120.14,109.98 119.51,109.35 115.72,109.35 115.56,109.51 115.56,110.33 115.4,110.49 115.18,110.49 115.02,110.33 115.02,109.51 114.86,109.35 114.63,109.35 114.47,109.51 114.47,110.33 114.31,110.49 114.08,110.49 113.92,110.33 113.92,109.51 113.76,109.35 113.54,109.35 113.38,109.51 113.38,110.33 113.22,110.49 112.99,110.49 112.83,110.33 112.83,109.51 112.67,109.35 112.45,109.35 112.29,109.51 112.29,110.33 112.13,110.49 111.9,110.49 111.74,110.33 111.74,109.51 111.58,109.35 111.25,109.35 110.62,109.98 109.47,109.98 107.79,108.3 107.79,107.87 107.82,107.83 107.82,106.32 107.66,106.16 106.71,106.16 106.55,106 106.55,105.77 106.71,105.61 107.66,105.61 107.82,105.45 107.82,105.21 107.66,105.05 105.9,105.05 105.74,104.89 105.74,104.67 105.9,104.51 107.66,104.51 107.82,104.35 107.82,103.63 107.31,103.12 107.31,100.58 107.06,100.33 106.17,100.33 105.76,100.74 105.06,100.74 104.9,100.9 104.9,101.13 105.06,101.29 105.76,101.29 105.92,101.45 105.92,101.68 105.76,101.84 105.06,101.84 104.9,102 104.9,102.22 105.06,102.38 105.76,102.38 105.92,102.54 105.92,103.25 v1(105.41,103.76)
  BOTTOM w0.132: v1(105.41,103.76) 105.98,103.19 RU15.35 ; v1(116.33,117.93) 116.99,117.27 EXP_P2.111
VIN[2]A_D[21]: length 79.3
  L14-SIGNAL w0.109: v1(116.99,108.08) 116.99,108.56 116.71,108.84 115.19,108.84 114.94,109.09 114.94,109.32 115.1,109.48 115.66,109.48 115.82,109.64 115.82,109.86 115.66,110.02 115.1,110.02 114.94,110.18 114.94,111.76 115.1,111.92 117.95,111.92 118.11,112.08 118.11,112.3 117.95,112.46 115.1,112.46 114.94,112.62 114.94,112.85 115.1,113.01 116.04,113.01 116.2,113.17 116.2,113.39 116.04,113.55 115.1,113.55 114.94,113.71 114.94,116.2 115.32,116.59 116.11,116.59 116.27,116.43 116.27,114.59 116.43,114.43 116.65,114.43 116.81,114.59 116.81,116.43 116.97,116.59 117.2,116.59 117.36,116.43 117.36,114.59 117.52,114.43 117.74,114.43 117.9,114.59 117.9,116.43 118.06,116.59 118.29,116.59 118.45,116.43 118.45,114.59 118.61,114.43 118.84,114.43 119,114.59 119,116.43 119.16,116.59 120.02,116.59 120.4,116.2 120.4,114.43 120.94,113.89 123.28,113.89 123.44,113.73 123.44,113.5 123.28,113.34 120.94,113.34 120.78,113.18 120.78,112.95 120.94,112.79 121.94,112.79 122.05,112.68 122.05,112.36 121.94,112.25 120.94,112.25 120.78,112.09 120.78,111.51 120.63,111.36 120.63,104.63 119.38,103.37 119.38,103.36 119.13,103.11 119.11,103.11 117.6,101.6 116.97,101.6 115.95,100.58 115.95,99.06 115.06,98.17 107.06,98.17 106.43,98.81 v1(105.54,98.81)
  BOTTOM w0.132: RU15.33 104.98,99.36 v1(105.54,98.81) ; v1(116.99,108.08) EXP_P2.112
VIN[2]A_D[22]: length 74.4
  L3-SIGNAL w0.109: v1(117.79,117.17) 117.79,116.75 118.08,116.46 125.51,116.46 125.53,116.48 127.52,116.48 127.72,116.67 127.72,117.52 127.51,117.73 126.63,117.73 126.47,117.89 126.47,118.71 126.31,118.87 126.08,118.87 125.92,118.71 125.92,117.89 125.76,117.73 125.54,117.73 125.38,117.89 125.38,118.71 125.22,118.87 124.99,118.87 124.83,118.71 124.83,117.89 124.67,117.73 124.44,117.73 124.28,117.89 124.28,118.71 124.12,118.87 123.9,118.87 123.74,118.71 123.74,117.89 123.58,117.73 123.35,117.73 123.19,117.89 123.19,118.71 123.03,118.87 122.81,118.87 122.65,118.71 122.65,117.89 122.49,117.73 122.26,117.73 122.1,117.89 122.1,118.71 121.94,118.87 121.71,118.87 121.55,118.71 121.55,117.89 121.39,117.73 121.16,117.73 120.02,118.87 117.76,118.87 117.6,118.71 117.6,117.76 117.44,117.6 117.22,117.6 117.06,117.76 117.06,118.71 116.9,118.87 115.75,118.87 114.98,118.1 114.98,117.34 114.98,117.33 114.98,117 114.98,116.99 114.98,116.97 114.72,116.71 114.43,116.71 114.26,116.55 114.26,116.32 114.6,115.97 114.6,115.75 114.44,115.59 114.22,115.59 113.87,115.93 113.65,115.93 113.49,115.77 113.49,115.55 113.83,115.2 113.83,114.97 113.67,114.81 113.45,114.81 113.1,115.16 112.87,115.16 112.71,115 112.71,114.77 113.06,114.43 113.06,114.2 112.9,114.04 112.67,114.04 112.33,114.39 112.1,114.39 111.94,114.23 111.94,114 112.29,113.66 112.29,113.43 112.13,113.27 111.9,113.27 111.55,113.61 111.33,113.61 111.17,113.45 111.17,113.23 111.51,112.88 111.51,112.66 111.35,112.5 111.13,112.5 110.78,112.84 110.56,112.84 110.4,112.68 110.4,112.46 110.74,112.11 110.74,111.88 110.58,111.72 110.35,111.72 110.01,112.07 109.78,112.07 109.62,111.91 109.62,111.68 109.97,111.34 109.97,111.11 109.81,110.95 109.58,110.95 109.24,111.3 109.01,111.3 108.85,111.14 108.85,110.91 109.2,110.56 109.2,110.34 109.04,110.18 108.81,110.18 108.46,110.52 108.24,110.52 108.08,110.36 108.08,110.14 108.42,109.79 108.42,109.57 108.26,109.41 108.04,109.41 107.69,109.75 107.47,109.75 106.68,108.97 106.68,106.81 103.98,104.11 v1(103.98,99.69)
  BOTTOM w0.132: RU15.31 v1(103.98,99.69) ; EXP_P2.113 v1(117.79,117.17)
VIN[2]A_D[23]: length 70.2
  L5-SIGNAL w0.089: v1(117.79,108.08) 117.79,107.68 117.73,107.62 117.73,107.39 117.86,107.26 119.63,107.26 119.76,107.13 119.76,106.95 119.63,106.82 117.86,106.82 117.73,106.69 117.73,106.5 117.86,106.37 119.63,106.37 119.76,106.24 119.76,106.06 119.63,105.93 117.86,105.93 117.73,105.8 117.73,105.62 117.86,105.49 119.63,105.49 119.76,105.35 119.76,105.17 119.63,105.04 117.86,105.04 117.73,104.91 117.73,104.73 117.86,104.6 119.63,104.6 119.76,104.47 119.76,104.28 119.63,104.15 117.86,104.15 117.73,104.02 117.73,103.12 117.86,102.99 118.87,102.99 119,102.86 119,102.68 118.87,102.55 117.86,102.55 117.73,102.42 117.73,102.23 117.86,102.1 118.87,102.1 119,101.97 119,101.79 118.87,101.66 117.86,101.66 117.73,101.53 117.73,100.84 113.54,96.65 113.54,95.38 112.9,94.74 111.24,94.74 111.11,94.87 111.11,96.26 110.98,96.39 110.8,96.39 110.67,96.26 110.67,94.87 110.54,94.74 105.82,94.74 105.69,94.61 105.69,93.98 105.56,93.85 105.38,93.85 105.25,93.98 105.25,94.61 105.12,94.74 104.93,94.74 104.8,94.61 104.8,93.98 104.67,93.85 104.49,93.85 104.36,93.98 104.36,94.61 104.23,94.74 104.01,94.74 103.5,95.25 103.5,95.93 103.64,96.06 104.68,96.06 104.81,96.19 104.81,96.38 104.68,96.51 103.64,96.51 103.5,96.64 103.5,96.85 103.64,96.98 108.33,96.98 108.46,97.11 108.46,97.3 108.33,97.43 103.64,97.43 103.35,97.71 103.34,97.71 103.12,97.94 103.12,98.54 102.98,98.68 v1(102.98,99.69)
  BOTTOM w0.132: RU15.29 v1(102.98,99.69) ; EXP_P2.114 v1(117.79,108.08)
VIN[2]A_DE0: length 37.9
  TOP w0.132: v1(123.06,115.32) 123.57,114.81 123.57,114.3 124.02,113.85 RU4.5
  L10-SIGNAL w0.089: v1(93.78,117.93) 93.78,116.53 94.61,115.7 94.82,115.7 94.95,115.83 94.95,116.2 95.08,116.33 95.26,116.33 95.39,116.2 95.39,115.83 95.52,115.7 122.68,115.7 v1(123.06,115.32)
  BOTTOM w0.132: EXP_P2.63 v1(93.78,117.93)
VIN[2]A_HSYNC: length 38
  TOP w0.132: v1(124.21,115.44) 124.21,116.33 124.67,116.8 RU4.11
  L10-SIGNAL w0.089: v1(124.21,115.44) 121.92,113.16 118.36,113.16 118.11,112.9 114.17,112.9 113.14,111.87 99.17,111.87 98.4,111.1 93.26,111.1 v1(92.98,111.38)
  BOTTOM w0.132: EXP_P2.62 v1(92.98,111.38)
VIN[2]A_VSYNC: length 34.7
  TOP w0.132: v1(120.9,114.69) 120.9,115.1 122.72,116.92 RU4.14
  L10-SIGNAL w0.089: v1(93.98,111.63) 98.32,111.63 99.85,113.16 113.67,113.16 114.81,114.3 120.52,114.3 120.63,114.41 120.63,114.41 v1(120.9,114.69)
  BOTTOM w0.132: EXP_P2.64 93.78,111.43 v1(93.98,111.63)
VIN[4]B_CLK1: length 17.1
  L7-SIGNAL w0.089: v1(58.63,106.81) 58.04,106.21 58.04,98.04 57.02,97.03 v1(57.02,94.01)
  BOTTOM w0.132: RU14.3 v1(58.63,106.81) ; EXP_P1.37 v1(57.02,94.01)
VIN[4]B_D[0]: length 25
  L7-SIGNAL w0.089: v1(56.68,109.98) 57.28,109.39 57.28,98.04 56.13,96.9 56.13,90.81 56.92,90.02 v1(57.53,90.02)
  BOTTOM w0.132: EXP_P1.27 v1(57.53,90.02) ; RU14.6 v1(56.68,109.98)
VIN[4]B_D[1]: length 28.1
  L12-SIGNAL w0.089: v1(63.25,90.02) 63.25,93.09 59.31,97.03 59.31,109.35 57.98,110.67 v1(57.98,112.52)
  BOTTOM w0.132: v1(63.25,90.02) EXP_P1.28 ; RU14.13 v1(57.98,112.52)
VIN[4]B_D[2]: length 29.1
  L7-SIGNAL w0.089: v1(57.02,89.2) 55.75,90.47 55.75,97.28 56.9,98.42 56.9,108.97 55.63,110.24 55.63,111.25 56.26,111.89 v1(56.26,112.78)
  BOTTOM w0.132: RU14.10 56.03,113 v1(56.26,112.78) ; EXP_P1.25 v1(57.02,89.2)
VIN[4]B_D[3]: length 49.7
  L7-SIGNAL w0.089: v1(67.18,89.2) 66.64,89.2 66.51,89.07 66.51,87.51 66.38,87.38 66.2,87.38 66.07,87.51 66.07,89.07 65.94,89.2 65.75,89.2 65.62,89.07 65.62,87.51 65.49,87.38 65.31,87.38 65.18,87.51 65.18,89.07 65.05,89.2 64.87,89.2 64.74,89.07 64.74,87.51 64.6,87.38 64.42,87.38 64.29,87.51 64.29,89.07 64.16,89.2 63.98,89.2 63.85,89.07 63.85,87.51 63.72,87.38 63.53,87.38 63.4,87.51 63.4,89.07 63.27,89.2 63.07,89.2 62.61,89.66 62.61,91.19 61.85,91.95 61.85,92.71 61.21,93.34 60.58,93.34 60.2,93.73 60.2,93.93 60.33,94.06 61.21,94.06 61.34,94.19 61.34,94.37 61.21,94.5 60.33,94.5 60.2,94.63 60.2,94.82 60.33,94.95 61.21,94.95 61.34,95.08 61.34,95.26 61.21,95.39 60.33,95.39 60.2,95.52 60.2,95.71 60.33,95.84 61.21,95.84 61.34,95.97 61.34,96.15 61.21,96.28 60.33,96.28 60.2,96.41 60.2,96.94 63.33,100.08 69.22,100.08 69.82,99.47 v1(69.82,98.7)
  BOTTOM w0.132: RU17.29 69.32,99.2 v1(69.82,98.7) ; v1(67.18,89.2) EXP_P1.26
VIN[4]B_D[4]: length 56
  L7-SIGNAL w0.089: v1(60.96,88.42) 61.47,87.91 61.47,86.61 61.72,86.36 61.72,84.58 61.47,84.33 59.82,84.33 59.18,84.96 59.18,85.18 59.31,85.31 59.69,85.31 59.82,85.44 59.82,85.62 59.69,85.75 59.31,85.75 59.18,85.88 59.18,86.07 59.31,86.2 59.69,86.2 59.82,86.33 59.82,86.51 59.69,86.64 59.31,86.64 59.18,86.77 59.18,86.96 59.31,87.09 59.69,87.09 59.82,87.22 59.82,87.4 59.69,87.53 59.31,87.53 59.18,87.66 59.18,87.85 59.31,87.98 59.69,87.98 59.82,88.11 59.82,88.29 59.69,88.42 59.31,88.42 59.18,88.55 59.18,88.73 59.31,88.86 59.69,88.86 59.82,88.99 59.82,89.18 59.69,89.31 59.31,89.31 59.18,89.44 59.18,89.64 59.31,89.77 61.97,89.77 62.1,89.9 62.1,90.09 61.97,90.22 59.31,90.22 59.18,90.35 59.18,90.53 59.31,90.66 61.97,90.66 62.1,90.79 62.1,90.98 61.97,91.11 59.31,91.11 59.18,91.24 59.18,91.44 59.69,91.95 61.11,91.95 61.28,92.12 61.28,92.77 61.09,92.96 60.2,92.96 59.69,93.47 59.69,97.03 63.25,100.58 69.32,100.58 70.83,99.08 v1(70.83,98.7)
  BOTTOM w0.132: RU17.31 70.32,99.2 v1(70.83,98.7) ; EXP_P1.23 v1(60.96,88.42)
VIN[4]B_D[5]: length 67.6
  L12-SIGNAL w0.089: v1(81.32,99.92) 81.32,93.89 80.77,93.34 80.77,90.42 79.1,88.75 79.1,83.82 78.97,83.69 78.78,83.69 78.65,83.82 78.65,86.84 78.52,86.97 78.34,86.97 78.21,86.84 78.21,83.82 78.08,83.69 77.89,83.69 77.76,83.82 77.76,86.84 77.63,86.97 77.45,86.97 77.32,86.84 77.32,83.82 77.19,83.69 77.01,83.69 76.87,83.82 76.87,86.84 76.74,86.97 76.56,86.97 76.43,86.84 76.43,83.82 76.3,83.69 76.12,83.69 75.99,83.82 75.99,86.84 75.86,86.97 75.67,86.97 75.54,86.84 75.54,83.82 75.41,83.69 75.23,83.69 75.1,83.82 75.1,86.84 74.97,86.97 74.78,86.97 74.65,86.84 74.65,83.82 74.52,83.69 74.34,83.69 74.21,83.82 74.21,86.84 74.08,86.97 73.93,86.97 v1(73.66,87.25)
  BOTTOM w0.132: EXP_P1.24 72.49,88.42 v1(73.66,87.25) ; v1(81.32,99.92) RU17.53
VIN[4]B_D[6]: length 63.1
  L3-SIGNAL w0.109: v1(80.32,99.91) 79.72,99.3 79.72,99.02 79.12,98.42 74.93,98.42 74.06,99.3 70.25,99.3 67.06,102.49 66.38,102.49 66.22,102.65 66.22,103.98 66.06,104.14 65.83,104.14 65.67,103.98 65.67,102.65 65.51,102.49 65.28,102.49 65.12,102.65 65.12,103.98 64.96,104.14 64.74,104.14 64.58,103.98 64.58,102.65 64.42,102.49 64.19,102.49 64.03,102.65 64.03,103.98 63.87,104.14 63.65,104.14 63.49,103.98 63.49,102.65 63.33,102.49 63.1,102.49 62.94,102.65 62.94,103.98 62.78,104.14 62.55,104.14 62.39,103.98 62.39,102.65 62.23,102.49 62.01,102.49 61.85,102.65 61.85,103.98 61.69,104.14 61.46,104.14 61.3,103.98 61.3,102.65 61.14,102.49 60.92,102.49 60.76,102.65 60.76,103.98 60.6,104.14 60.37,104.14 60.21,103.98 60.21,102.65 60.05,102.49 59.82,102.49 59.66,102.65 59.66,103.98 59.5,104.14 59.28,104.14 59.12,103.98 59.12,102.65 58.96,102.49 v1(58.55,102.49)
  L12-SIGNAL w0.089: v1(57.53,87.6) 58.55,88.62 v1(58.55,102.49)
  BOTTOM w0.132: EXP_P1.21 v1(57.53,87.6) ; v1(80.32,99.91) RU17.51
VIN[4]B_D[7]: length 61.5
  L12-SIGNAL w0.089: v1(72.52,87.76) 72.52,90.04 71.88,90.68 71.88,90.88 72.01,91.01 75.56,91.01 75.69,91.14 75.69,91.33 75.56,91.46 72.01,91.46 71.88,91.59 71.88,91.79 72.01,91.92 74.16,91.92 74.3,92.05 74.3,92.23 74.16,92.36 72.01,92.36 71.88,92.49 71.88,92.68 72.01,92.81 74.16,92.81 74.3,92.94 74.3,93.12 74.16,93.25 72.01,93.25 71.88,93.38 71.88,93.57 72.01,93.7 74.16,93.7 74.3,93.83 74.3,94.01 74.16,94.14 72.01,94.14 71.88,94.27 71.88,94.46 72.01,94.59 74.16,94.59 74.3,94.72 74.3,94.9 74.16,95.03 72.01,95.03 71.88,95.16 71.88,95.36 72.01,95.5 73.28,95.5 73.41,95.63 73.41,95.81 73.28,95.94 72.01,95.94 71.88,96.07 71.88,96.25 72.01,96.38 73.28,96.38 73.41,96.51 73.41,96.7 73.28,96.83 72.01,96.83 71.88,96.96 71.88,97.79 72.39,98.3 72.39,100.97 73.03,101.6 73.23,101.6 73.36,101.47 73.36,100.97 73.49,100.84 73.67,100.84 73.8,100.97 73.8,101.47 73.93,101.6 74.12,101.6 74.25,101.47 74.25,100.97 74.38,100.84 74.56,100.84 74.69,100.97 74.69,101.47 74.82,101.6 75.31,101.6 75.82,101.09 75.82,99.73 v1(75.82,99.72)
  BOTTOM w0.132: v1(72.52,87.76) 66.77,87.76 66.62,87.6 EXP_P1.22 ; RU17.42 v1(75.82,99.72)
VIN[4]B_HSYNC1: length 58.3
  L7-SIGNAL w0.089: v1(57.53,91.62) 58.04,91.11 58.04,81.41 58.55,80.9 59.82,80.9 60.2,81.28 60.2,81.48 60.33,81.61 61.72,81.61 61.85,81.74 61.85,81.93 61.72,82.06 60.33,82.06 60.2,82.19 60.2,82.37 60.33,82.5 61.72,82.5 61.85,82.63 61.85,82.82 61.72,82.95 59.93,82.95 58.67,84.2 58.67,97.16 62.87,101.35 72.14,101.35 72.82,100.66 v1(72.82,98.7)
  BOTTOM w0.132: RU17.35 72.32,99.2 v1(72.82,98.7) ; EXP_P1.31 v1(57.53,91.62)
VIN[4]B_VSYNC1: length 54.4
  L7-SIGNAL w0.089: v1(66.67,91.62) 71.83,91.62 72.39,91.06 72.39,88.39 71.88,87.88 71.88,86.61 71.63,86.36 71.42,86.36 71.29,86.49 71.29,87.37 71.16,87.5 70.98,87.5 70.85,87.37 70.85,86.49 70.72,86.36 70.54,86.36 70.41,86.49 70.41,87.37 70.28,87.5 70.09,87.5 69.96,87.37 69.96,86.49 69.83,86.36 69.65,86.36 69.52,86.49 69.52,87.37 69.39,87.5 69.2,87.5 69.07,87.37 69.07,86.49 68.94,86.36 67.94,86.36 67.82,86.49 67.82,89.41 67.31,89.92 64.39,89.92 62.74,91.57 62.74,93.47 61.85,94.36 61.85,97.79 63.63,99.57 68.2,99.57 69.72,98.04 73.16,98.04 v1(73.83,98.7)
  BOTTOM w0.132: v1(66.67,91.62) EXP_P1.32 ; RU17.37 73.32,99.2 v1(73.83,98.7)
VIN[6]A_D[0]: length 78.4
  L10-SIGNAL w0.089: v1(69.78,117.17) 71.75,115.19 77.09,115.19 83.06,109.22 91.31,109.22 91.69,108.84 99.44,108.84 100.08,108.2 107.47,108.2 108.86,106.81 113.28,106.81 114.55,105.54 118.75,105.54 122.17,102.11 138.27,102.11 v1(138.65,102.49)
  BOTTOM w0.132: RU18.47 v1(138.65,102.49) ; EXP_P2.13 v1(69.78,117.17)
VIN[6]A_D[1]: length 81.9
  L10-SIGNAL w0.089: v1(140.15,102.62) 139.26,101.73 121.16,101.73 120.4,102.49 120.4,103 119.44,103.95 117.79,103.95 117.73,103.89 116.33,103.89 115.19,102.74 114.05,102.74 112.01,104.78 102.36,104.78 100.07,102.48 98.94,102.48 98.29,103.13 94.24,103.13 93.72,102.61 86.41,102.61 81.15,107.87 81.15,108.46 80.01,109.6 71.35,109.6 v1(69.78,108.03)
  BOTTOM w0.132: EXP_P2.14 v1(69.78,108.03) ; RU18.50 v1(140.15,102.62)
VIN[6]A_D[2]: length 81
  L10-SIGNAL w0.089: v1(141.15,102.62) 140.39,103.38 137.16,103.38 133.73,106.81 121.79,106.81 120.65,107.95 120.01,107.95 119.69,107.63 113.6,107.63 113.4,107.44 111.23,107.44 109.7,108.97 100.46,108.97 99.82,109.6 91.95,109.6 91.57,109.98 83.44,109.98 77.09,116.33 72.77,116.33 71.43,117.67 v1(70.58,117.67)
  BOTTOM w0.132: EXP_P2.15 v1(70.58,117.67) ; RU18.52 v1(141.15,102.62)
VIN[6]A_D[3]: length 82.5
  L10-SIGNAL w0.089: v1(142.12,102.62) 140.85,101.35 121.03,101.35 120.14,102.23 112.9,102.23 110.74,104.39 103.12,104.39 100.97,102.23 98.81,102.23 98.69,102.36 94.67,102.36 94.67,102.36 86.23,102.36 80.77,107.82 80.77,108.33 79.76,109.35 71.63,109.35 70.58,108.3 v1(70.58,107.52)
  BOTTOM w0.132: RU18.54 142.15,102.59 v1(142.12,102.62) ; EXP_P2.16 v1(70.58,107.52)
VIN[6]A_D[7]: length 75.7
  L10-SIGNAL w0.089: v1(71.38,117.17) 72.85,115.7 77.09,115.7 83.19,109.6 91.44,109.6 91.82,109.22 99.57,109.22 100.2,108.58 108.68,108.58 110.21,107.06 114.17,107.06 114.68,106.55 115.44,106.55 115.73,106.84 116.25,106.84 116.26,106.83 119.99,106.83 121.41,105.41 132.59,105.41 132.84,105.16 133.35,105.16 136.01,102.5 v1(137.65,102.5)
  BOTTOM w0.132: v1(137.65,102.5) RU18.45 ; EXP_P2.17 v1(71.38,117.17)
VIN[6]A_D[8]: length 74.6
  TOP w0.132: RJ10.1 v1(137.16,96.27)
  L10-SIGNAL w0.089: v1(137.16,96.27) 136.27,97.16 136.27,97.92 135.64,98.55 132.59,98.55 131.83,99.31 121.54,99.31 118.87,101.98 86.11,101.98 80.39,107.7 80.39,108.2 79.63,108.97 72.31,108.97 v1(71.38,108.03)
  BOTTOM w0.132: EXP_P2.18 v1(71.38,108.03)
VIN[6]A_D[9]: length 86.4
  TOP w0.132: RJ9.1 v1(135.64,96.27)
  L10-SIGNAL w0.089: v1(72.18,117.67) 72.18,118.27 72.95,119.04 78.06,119.04 85.21,111.89 86.23,111.89 87,111.12 92.2,111.12 92.58,110.74 112.78,110.74 114.22,112.19 118.84,112.19 119.22,112.56 126.58,112.56 128.01,111.13 128.01,111.09 128.24,110.86 128.28,110.86 128.78,110.36 132.84,110.36 133.92,109.28 134.87,109.28 v1(135.41,108.74)
  L14-SIGNAL w0.109: v1(135.41,108.74) 135.41,108.1 134.87,107.57 134.87,106.55 135.38,106.05 135.38,102.49 135.7,102.17 135.7,98.74 135.13,98.17 135.13,96.77 v1(135.64,96.27)
  BOTTOM w0.132: EXP_P2.19 v1(72.18,117.67)
VIN[6]A_D[10]: length 71.2
  TOP w0.132: RJ8.1 v1(134.11,96.27)
  L10-SIGNAL w0.089: v1(134.11,96.27) 133.6,96.77 130.56,96.77 128.4,98.93 121.41,98.93 118.62,101.73 85.85,101.73 80.01,107.57 80.01,108.08 79.5,108.58 72.52,108.58 72.18,108.25 v1(72.18,107.52)
  BOTTOM w0.132: EXP_P2.20 v1(72.18,107.52)
VIN[6]A_D[11]: length 80.7
  TOP w0.132: RJ7.1 v1(132.59,96.27)
  L10-SIGNAL w0.089: v1(72.98,117.17) 72.98,117.94 73.28,118.24 77.34,118.24 78.36,117.22 78.36,116.2 83.82,110.74 91.95,110.74 92.33,110.36 113.41,110.36 114.94,111.89 119.13,111.89 119.25,112.01 126.49,112.01 128.65,109.86 130.3,109.86 v1(131.57,108.58)
  L14-SIGNAL w0.109: v1(132.59,96.27) 131.57,97.28 v1(131.57,108.58)
  BOTTOM w0.132: EXP_P2.21 v1(72.98,117.17)
VIN_CONN: length 65.2
  TOP w0.508: J2.1 182.42,167.02 ; J2.1 178,169.41 ; J2.1 182.42,169.41 ; J2.1 178,167.02
  TOP w2.54: F1.2 190.25,170.35 ; F1.2 192.46,167.92 ; F1.2 188.04,167.92 ; F1.2 190.25,165.49
  L3-SIGNAL w0.305: J2.1 182.3,168.21 ; J2.1 178.13,168.21 ; J2.1 180.21,169.28 ; J2.1 180.21,167.15
  L5-SIGNAL w0.305: J2.1 182.3,168.21 ; J2.1 180.21,169.28 ; J2.1 178.13,168.21 ; J2.1 180.21,167.15
  L7-SIGNAL w0.305: J2.1 182.3,168.21 ; J2.1 180.21,167.15 ; J2.1 178.13,168.21 ; J2.1 180.21,169.28
  L8-PWR1 w0.508: J2.1 180.21,169.28 ; J2.1 180.21,167.15 ; J2.1 182.3,168.21 ; J2.1 178.13,168.21
  L12-SIGNAL w0.508: 180.21,167.15 J2.1 ; J2.1 178.13,168.21 ; J2.1 180.21,169.28 ; J2.1 182.3,168.21
  L14-SIGNAL w0.305: 178.13,168.21 J2.1 ; J2.1 182.3,168.21 ; J2.1 180.21,169.28 ; J2.1 180.21,167.15
  BOTTOM w0.508: J2.1 182.42,168.21 ; J2.1 180.21,169.41 ; J2.1 180.21,167.02 ; J2.1 178,168.21 ; 172.59,120.78 v2(173.86,120.78)
  vias: v4(177.67,170.05) v4(177.67,168.15) v4(177.67,166.24) v4(180.21,170.05) v4(180.21,166.24) v4(182.75,170.05) v4(182.75,168.15) v4(182.75,166.24) v4(185.29,171.7) v4(185.29,170.18) v4(185.29,168.53) v4(185.29,166.88) v4(187.45,169.93) v4(187.45,168.91) v4(187.45,167.89) v4(187.45,166.88) v4(187.45,165.86) v4(188.21,170.94) v4(189.23,170.94) v4(190.25,170.94) v4(191.26,170.94) v4(192.28,170.94) v4(193.04,169.93) v4(193.04,168.91) v4(193.04,167.89) v4(193.04,166.88) v4(193.04,165.86)
VSSA_OSC0: length 20.8
  TOP w0.305: U42.AB15 v1(86.18,55.56)
  BOTTOM w0.254: C457.2 C474.2 70.1,55.22 70.61,55.73 81.41,55.73 81.79,56.11 85.63,56.11 v1(86.18,55.56)
  BOTTOM w0.305: C457.2 68.63,56.74 68.61,56.77 R233.1
VSSA_OSC1: length 34.6
  TOP w0.305: U42.AC18 v1(86.18,53.16)
  BOTTOM w0.127: 82.55,53.57 82.82,53.57 82.82,53.57 85.54,53.57 85.55,53.57 85.77,53.57 v1(86.18,53.16)
  BOTTOM w0.254: C518.2 56.88,47.75 Y7.4 60.59,47.75 61.43,48.59 R243.1 61.43,49.45 62.22,50.25 Y7.2 64.13,50.27 65.53,50.27 C517.2 67.03,49.5 70.99,53.47 82.45,53.47 82.55,53.57
AIC_AVDD_DAC3.3: length 7.7
  TOP w0.279: C183.1 179.32,40.26 179.02,40.56 U50.25
  TOP w0.508: C183.1 C184.1 182.75,38.73 C185.1 183.69,38.73 184.15,39.19 L23.1
AIC_BCLK: length 6.1
  TOP w0.132: U50.38 177.38,47.34 177.52,47.47 178.49,47.47 179.27,48.26 v2(180.85,48.26) R240.2
  BOTTOM w0.132: v2(180.85,48.26) R604.1
AIC_DIN: length 4.4
  TOP w0.132: R238.2 177.93,48.77 v2(177.93,48.26) 177.37,48.26 176.38,47.27 U50.40
  BOTTOM w0.132: R605.1 177.93,48.77 v2(177.93,48.26)
AIC_DOUT: length 2.8
  TOP w0.132: U50.41 175.88,47.28 177.04,48.44 R237.2
AIC_DRVDD3.3: length 16.8
  TOP w0.254: U50.24 178.54,39.78 178.81,39.5 179.07,39.25 v2(179.07,38.61)
  TOP w0.279: U50.16 173.88,38.08 v2(174.12,37.85) 174.38,38.11 U50.17
  TOP w0.508: v2(179.07,38.61) 178.18,38.61 177.67,38.1 C190.1 176.91,36.58 176.4,37.08 v2(175.9,37.08)
  L14-SIGNAL w0.508: v2(174.12,37.85) 174.88,37.08 v2(175.9,37.08)
  BOTTOM w0.508: v2(174.12,37.85) 174.5,38.23 C541.1 C542.1 ; C540.1 v2(179.07,38.61)
AIC_DVDD3.3: length 8.4
  TOP w0.279: U50.36 179.75,46.06
  TOP w0.508: U45.5 185.73,46.74 184.85,45.85 C178.1 179.96,45.85 179.75,46.06
AIC_IOVDD3.3: length 6.8
  TOP w0.279: U50.44 174.38,48.39 174.5,48.5 C176.1
  TOP w0.508: C176.1 173.86,49.15 173.61,49.4 C171.1 171.32,49.4 171.27,49.45 L22.2
AIC_MCA3_ACLKX: length 99.3
  TOP w0.132: RJ9.3 137.03,98.93 141.01,98.93 v1(141.65,99.57) ; R240.1 181.23,50.55 v1(181.23,50.93)
  L3-SIGNAL w0.109: v1(181.23,50.93) 181.77,51.46 184.18,51.46 186.18,53.47 186.18,66.29 185.17,67.31 185.17,87.38 185.42,87.63 v1(185.42,90.04)
  L7-SIGNAL w0.089: v1(141.65,99.57) 142.53,98.68 147.96,98.68 148.72,97.92 163.96,97.92 164.72,97.16 164.72,96.85 164.75,96.82 164.75,96.52 170.53,90.74 184.72,90.74 v1(185.42,90.04)
  BOTTOM w0.132: RU18.53 v1(141.65,99.57)
AIC_MCA3_AFSX: length 97.9
  TOP w0.132: RJ10.3 v1(140.59,98.3) ; R239.1 v1(179.58,51.05)
  L3-SIGNAL w0.109: v1(179.58,51.05) 180.36,51.83 184.04,51.83 185.8,53.59 185.8,66.14 184.78,67.15 v1(184.78,89.66)
  L7-SIGNAL w0.089: v1(184.78,89.66) 184.02,90.42 170.43,90.42 164.69,96.16 163.93,96.16 163.3,96.79 163.25,96.79 163.24,96.81 151.35,96.81 150.62,97.54 148.46,97.54 147.7,98.3 v1(140.59,98.3)
  BOTTOM w0.132: RU18.51 140.65,98.77 140.59,98.71 v1(140.59,98.3)
AIC_MCA3_AXR0: length 103.2
  TOP w0.132: RJ7.3 133.35,99.06 134.27,99.98 138.73,99.98 v1(139.15,99.57) ; R238.1 178.7,50.56 v1(178.7,50.93)
  L3-SIGNAL w0.109: v1(183.9,89.92) 183.9,89.28 184.4,88.77 184.4,66.99 185.42,65.98 185.42,53.72 183.9,52.2 179.97,52.2 v1(178.7,50.93)
  L7-SIGNAL w0.089: v1(183.9,89.92) 170.43,89.92 164.59,95.76 163.96,95.76 163.7,96.01 163.27,96.01 163.24,95.98 162.9,95.98 162.61,96.27 151.38,96.27 150.49,97.16 147.31,97.16 146.81,97.66 140.68,97.66 139.15,99.19 v1(139.15,99.57)
  BOTTOM w0.132: v1(139.15,99.57) RU18.48
AIC_MCA3_AXR1: length 101
  TOP w0.132: R237.1 v1(177.04,50.93) ; v1(138.15,99.57) 136.84,99.57 135.57,98.3 RJ8.3
  L3-SIGNAL w0.109: v1(183.26,89.41) 184.02,88.65 184.02,66.84 185.04,65.82 185.04,53.85 183.77,52.58 178.69,52.58 v1(177.04,50.93)
  L7-SIGNAL w0.089: v1(183.26,89.41) 170.43,89.41 164.36,95.48 163.72,95.48 163.45,95.76 160.02,95.76 159.89,95.63 147.37,95.63 145.97,97.03 140.69,97.03 v1(138.15,99.57)
  BOTTOM w0.132: v1(138.15,99.57) RU18.46
AIC_WCLK: length 3.9
  TOP w0.132: R239.2 178.21,47.78 177.37,47.78 176.88,47.29 U50.39
APP_BD_PORZ: length 225.2
  TOP w0.132: v1(45.21,118.24) 46.01,119.03 U141.11
  L3-SIGNAL w0.109: v1(195.96,87.76) 194.94,88.77 188.34,88.77 185.67,91.44 171.45,91.44 169.42,93.47 160.4,93.47 158.62,95.25 125.09,95.25 122.94,97.41 118.62,97.41 115.95,94.74 102.71,94.74 102.11,95.35 v1(102.11,95.76)
  L10-SIGNAL w0.089: v1(70.48,111.51) 71.63,110.36 80.52,110.36 82.42,108.46 90.17,108.46 91.31,107.31 91.64,107.31 92.01,107.68 92.35,107.68 92.71,107.32 95.5,107.32 95.94,106.88 96.6,106.88 96.78,107.06 v1(99.44,107.06) ; v1(201.29,44.58) 200.91,44.96 200.91,56.39 197.61,59.69 197.61,86.11 v1(195.96,87.76)
  L14-SIGNAL w0.109: v1(99.44,107.06) 97.79,105.41 97.79,98.42 100.46,95.76 v1(102.11,95.76) ; v1(45.21,118.24) 46.86,116.59 55.12,116.59 57.02,114.68 61.47,114.68 64.64,111.51 v1(70.48,111.51)
  BOTTOM w0.132: v1(99.44,107.06) 98.59,107.92 EXP_P2.76 ; R615.2 v1(201.29,44.58)
AQSPI1_CS[0]: length 45
  TOP w0.132: v1(115.44,111.34) R135.1 ; R171.1 v1(96.27,89.92)
  L7-SIGNAL w0.089: v1(115.44,111.34) 115.44,106.17 117.22,104.39 117.22,102.49 116.46,101.73 116.46,99.44 114.94,97.92 104.52,97.92 103.76,98.68 101.73,98.68 98.81,95.76 98.81,95.38 100.08,94.11 100.08,90.17 99.19,89.28 96.9,89.28 v1(96.27,89.92)
AQSPI1_D[0]: length 45.6
  TOP w0.132: R170.1 v1(87.76,90.17) ; R144.1 v1(100.08,107.7)
  L7-SIGNAL w0.089: v1(87.76,90.17) 87.76,89.15 87.5,88.9 87.5,83.27 87.72,83.06 88.27,83.06 88.52,83.31 88.52,83.64 88.65,83.77 89.15,83.77 89.28,83.9 89.28,84.08 89.15,84.21 88.65,84.21 88.52,84.34 88.52,84.53 88.65,84.66 89.15,84.66 89.28,84.79 89.28,84.97 89.15,85.1 88.65,85.1 88.52,85.23 88.52,85.41 88.65,85.55 89.15,85.55 89.28,85.68 89.28,85.86 89.15,85.99 88.65,85.99 88.52,86.12 88.52,86.3 88.65,86.43 89.15,86.43 89.28,86.56 89.28,86.75 89.15,86.88 88.65,86.88 88.52,87.01 88.52,87.19 88.65,87.32 89.15,87.32 89.28,87.45 89.28,87.64 89.15,87.77 88.65,87.77 88.52,87.9 88.52,89.92 88.9,90.3 88.9,92.71 91.69,95.5 91.69,100.2 99.19,107.7 v1(100.08,107.7)
AQSPI1_D[1]: length 34.8
  TOP w0.132: R175.1 v1(98.93,89.92) ; R133.2 v1(116.59,113.79)
  L12-SIGNAL w0.089: v1(98.93,89.92) 99.19,90.17 99.19,91.95 99.44,92.2 99.44,94.49 100.08,95.12 100.08,97.79 101.1,98.82 101.1,99.33 103.76,101.98 104.9,101.98 105.92,103 105.92,104.01 108.33,106.43 108.33,107.44 114.68,113.79 v1(116.59,113.79)
AQSPI1_D[2]: length 42.5
  TOP w0.132: R131.2 100.97,117.6 v1(101.09,117.73) ; R181.1 v1(90.3,89.66)
  L7-SIGNAL w0.089: v1(90.3,89.66) 90.68,89.28 90.68,86.74 90.42,86.49 89.92,86.49 89.66,86.74 89.66,90.55 90.42,91.31 90.42,91.57 90.81,91.95 90.81,93.69 92.46,95.34 92.46,98.81 97.92,104.27 97.92,104.77 98.55,105.41 98.93,105.41 100.84,107.31 100.84,108.71 100.33,109.22 100.33,110.36 101.09,111.13 v1(101.09,117.73)
AQSPI1_D[3]: length 43.8
  TOP w0.132: R187.1 97.6,85.72 97.8,85.53 97.8,84.39 97.99,84.2 98.26,84.2 98.46,84.39 98.46,85.53 98.65,85.72 98.92,85.72 99.12,85.53 99.12,84.39 99.31,84.2 99.58,84.2 99.78,84.39 99.78,85.53 99.97,85.72 100.84,85.72 101.47,86.36 101.47,86.61 101.28,86.8 100.27,86.8 100.08,86.99 100.08,87.27 100.27,87.46 101.28,87.46 101.47,87.65 101.47,87.93 101.28,88.12 100.27,88.12 100.08,88.31 100.08,88.59 100.27,88.78 101.28,88.78 101.47,88.97 101.47,89.25 101.28,89.44 100.27,89.44 100.08,89.64 100.08,89.91 100.27,90.1 101.28,90.1 101.47,90.3 101.47,101.98 104.27,104.78 110.49,104.78 R151.1
AQSPI1_RTCLK: length 43.9
  TOP w0.132: R173.1 v1(92.71,89.66) ; R145.2 v1(98.81,104.52)
  L7-SIGNAL w0.089: v1(98.81,104.52) 98.81,103.89 96.9,101.98 96.9,98.55 95,96.65 95,94.87 94.79,94.66 94.79,94.48 94.99,94.28 94.99,94.1 94.86,93.97 94.67,93.97 94.47,94.16 94.29,94.16 94.16,94.03 94.16,93.85 94.36,93.65 94.36,93.47 94.23,93.34 94.04,93.34 93.85,93.53 93.66,93.53 93.53,93.4 93.53,93.22 93.73,93.02 93.73,92.84 93.6,92.71 93.41,92.71 93.22,92.91 93.03,92.91 91.82,91.69 91.82,90.3 92.08,90.04 92.08,88.52 91.74,88.19 91.32,88.19 91.19,88.06 91.19,87.87 91.32,87.74 91.56,87.74 91.69,87.61 91.69,87.43 91.56,87.3 91.32,87.3 91.19,87.17 91.19,86.98 91.32,86.85 91.56,86.85 91.69,86.72 91.69,86.54 91.56,86.41 91.32,86.41 91.19,86.28 91.19,86.09 91.32,85.96 91.56,85.96 91.69,85.83 91.69,85.54 91.56,85.41 89.92,85.41 89.79,85.28 89.79,85.1 89.92,84.97 91.56,84.97 91.69,84.84 91.69,84.65 91.56,84.52 89.92,84.52 89.79,84.39 89.79,84.21 89.92,84.08 91.56,84.08 91.95,83.69 92.46,83.69 92.71,83.95 v1(92.71,89.66)
AQSPI1_SCLK: length 46.2
  TOP w0.132: R146.2 R145.1 v1(99.82,104.52) ; R185.1 v1(95.12,89.66)
  L7-SIGNAL w0.089: v1(95.12,89.66) 95.12,88.52 95.25,88.39 95.25,83.19 95.06,82.99 94.68,82.99 94.49,83.19 94.49,83.48 94.36,83.61 93.22,83.61 93.09,83.74 93.09,83.92 93.22,84.05 94.36,84.05 94.49,84.18 94.49,84.37 94.36,84.5 93.22,84.5 93.09,84.63 93.09,84.81 93.22,84.94 94.36,84.94 94.49,85.07 94.49,85.26 94.36,85.39 93.22,85.39 93.09,85.52 93.09,85.7 93.22,85.83 94.36,85.83 94.49,85.96 94.49,86.14 94.36,86.27 93.22,86.27 93.09,86.4 93.09,86.59 93.22,86.72 94.36,86.72 94.49,86.85 94.49,87.03 94.36,87.16 93.22,87.16 93.09,87.29 93.09,87.48 93.22,87.61 94.36,87.61 94.49,87.74 94.49,89.92 94.74,90.17 94.74,91.82 97.16,94.23 97.16,95.92 99.82,98.58 v1(99.82,104.52)
BT_EN: length 19.5
  TOP w0.132: v1(10.01,66.55) P9.89 ; v1(14.33,51.19) U43.20
  L3-SIGNAL w0.109: v1(10.01,66.55) 12.19,64.36 12.19,54.23 13.84,52.58 13.84,52.07 14.33,51.59 v1(14.33,51.19)
BT_UART_CTS: length 14.8
  TOP w0.132: P9.70 v1(4.98,60.2) ; U43.15 14.38,53.69 v1(14.22,53.85)
  L5-SIGNAL w0.089: v1(4.98,60.2) 8.03,57.15 11.56,57.15 14.22,54.48 v1(14.22,53.85)
BT_UART_RTS: length 18
  TOP w0.132: 3.49,60.83 v1(2.01,60.83) ; v1(13.53,68.81) U39.16
  L14-SIGNAL w0.109: v1(13.53,68.81) 11.54,68.81 10.41,67.69 8.86,67.69 v1(2.01,60.83)
BT_UART_RX: length 16.9
  TOP w0.132: U43.14 14.64,54.19 14.35,54.48 v1(13.59,54.48) ; P9.68 v1(2.01,59.56)
  L5-SIGNAL w0.089: v1(13.59,54.48) 13.19,54.48 11.16,56.52 5.05,56.52 v1(2.01,59.56)
BT_UART_TX: length 18.1
  TOP w0.132: v1(14.33,68.31) U39.17 ; P9.66 v1(4.98,58.93)
  L14-SIGNAL w0.109: v1(14.33,68.31) 13.96,67.94 12.32,67.94 10.67,66.29 10.67,61.98 7.62,58.93 v1(4.98,58.93)
C_GPMC_A13: length 67.5
  TOP w0.132: R172.1 v1(91.44,89.66)
  L7-SIGNAL w0.089: v1(119.13,139.32) 119.13,138.81 117.09,136.78 115.57,136.78 101.47,122.68 101.47,107.44 99.06,105.03 98.78,105.03 98.3,104.54 98.3,104.01 95.89,101.6 95.89,98.3 93.85,96.27 93.85,95.38 91.31,92.84 91.31,92.08 90.81,91.57 90.81,90.3 v1(91.44,89.66)
  BOTTOM w0.132: R380.2 119,139.19 v1(119.13,139.32) 119.87,139.32 119.93,139.26 U104.6
C_GPMC_A14: length 68.8
  TOP w0.132: R186.1 v1(95.76,86.61)
  L7-SIGNAL w0.089: v1(95.76,86.61) 95.76,88.49 95.63,88.61 95.63,90.55 96.27,91.19 96.27,92.2 97.54,93.47 97.54,95.89 100.2,98.55 100.2,99.95 100.84,100.58 100.84,105.66 102.74,107.57 102.74,110.49 102.23,111 102.23,122.43 115.82,136.02 117.53,136.02 v1(120.27,138.76)
  BOTTOM w0.132: R383.2 118.87,138.43 119.2,138.76 v1(120.27,138.76) U104.5
C_GPMC_A15: length 68.6
  TOP w0.132: R180.1 v1(89.15,89.66)
  L7-SIGNAL w0.089: v1(89.15,89.66) 89.15,90.42 89.92,91.19 89.92,93.22 92.08,95.38 92.08,99.19 97.54,104.65 97.54,104.9 98.55,105.92 99.06,105.92 100.45,107.31 100.45,108.21 99.82,108.84 99.82,117.76 99.81,117.77 99.81,118.08 99.82,118.09 99.82,121.54 109.6,131.32 109.6,133.1 113.79,137.29 v1(115.82,137.29)
  BOTTOM w0.132: v1(115.82,137.29) 116.59,138.05 118.07,138.05 118.2,137.92 R390.2 119.13,137.67 119.72,138.26 U104.4
C_GPMC_A16: length 70
  TOP w0.132: v1(86.71,90.14) 86.49,89.92 R169.1
  L7-SIGNAL w0.089: v1(86.71,90.14) 86.74,90.17 86.74,90.55 87.5,91.31 87.5,93.34 88.66,94.5 88.66,95.79 88.52,95.92 88.52,97.92 89.79,99.19 89.79,99.95 90.3,100.46 91.44,100.46 98.81,107.82 98.81,109.22 98.3,109.73 98.3,112.39 98.26,112.43 98.26,112.77 98.3,112.81 98.3,115.32 98.97,115.99 98.97,121.2 109.22,131.44 109.22,134.11 v1(111.51,136.4)
  BOTTOM w0.132: v1(111.51,136.4) 118.06,136.4 118.2,136.54 R392.2 118.87,136.91 119.73,137.76 U104.3
C_GPMC_A17: length 89.8
  TOP w0.132: R174.1 97.66,89.79 v1(97.73,89.85)
  L7-SIGNAL w0.089: v1(97.73,89.85) 97.16,90.42 97.16,90.93 98.3,92.08 98.3,95.76 101.6,99.06 101.6,104.14 101.98,104.52 101.98,106.3 103.12,107.44 103.12,110.87 102.62,111.38 102.62,122.3 115.82,135.51 123.19,135.51 124.33,136.65 124.33,138.18 v1(124.84,138.68)
  L14-SIGNAL w0.109: v1(124.84,138.68) 138.18,138.68 139.57,137.29 143.04,137.29 v1(143.51,137.76)
  BOTTOM w0.132: R382.2 144.91,137.76 v1(143.51,137.76) U104.54
C_GPMC_A18: length 74.6
  TOP w0.132: R184.1 v1(93.85,89.79)
  L7-SIGNAL w0.089: v1(93.85,89.79) 94.12,90.05 94.12,90.79 93.89,91.02 93.89,91.86 96.77,94.74 96.77,96.14 98.81,98.17 98.81,103.25 99.31,103.76 99.31,104.65 102.36,107.7 102.36,109.56 102.37,109.57 102.37,109.89 102.36,109.89 102.36,110.24 101.85,110.74 101.85,122.56 115.7,136.4 117.22,136.4 119.63,138.81 119.63,139.45 121.41,141.22 121.41,144.74 v1(120.4,145.76)
  BOTTOM w0.132: R359.2 118.52,146.43 119.19,145.76 v1(120.4,145.76) U104.19
CAM_SPI[1]_SCLK: length 123.2
  TOP w0.132: R272.1 120.14,38.23 v1(120.4,38.48)
  L10-SIGNAL w0.089: v1(9.78,14.1) 13.34,14.1 15.11,15.88 29.97,15.88 37.08,22.99 42.55,22.99 45.34,25.78 53.98,25.78 59.44,31.24 88.1,31.24 88.1,31.24 89.19,31.24 89.19,31.24 96.52,31.24 99.82,34.54 111.12,34.54 113.16,36.58 116.71,36.58 118.62,38.48 v1(120.4,38.48)
  BOTTOM w0.132: v1(9.78,14.1) 10.16,14.1 10.17,14.11 RU21.9
CAMERA_CLK: length 94.5
  TOP w0.132: v1(122.49,114.74) 122.49,113.86 122.72,113.62 RU4.3 ; R54.1 v1(53.34,145.03)
  L14-SIGNAL w0.109: v1(122.49,114.74) 119.25,117.98 119.25,118.49 118.24,119.51 111.38,119.51 102.74,128.14 93.6,128.14 92.19,129.56 87.9,129.56 86.61,128.27 77.6,128.27 74.68,131.19 69.09,131.19 68.45,131.83 66.17,131.83 64.01,133.99 63.12,133.99 62.03,135.07 61.37,135.07 60.7,134.4 60.54,134.4 60.39,134.56 60.39,134.71 61.06,135.38 61.06,135.54 60.9,135.69 60.75,135.69 60.08,135.02 59.92,135.02 59.77,135.18 59.77,135.33 60.44,136 60.44,136.16 60.28,136.31 60.13,136.31 59.46,135.64 59.3,135.64 59.15,135.8 59.15,136.03 59.62,136.5 59.62,136.72 59.46,136.88 59.23,136.88 58.76,136.41 58.53,136.41 53.34,141.6 v1(53.34,145.03)
CAMERA_D0: length 127.1
  TOP w0.132: RU8.3 v1(103.98,95.47)
  L10-SIGNAL w0.089: v1(103.98,95.47) 103.56,95.89 102.82,95.89 102.15,95.22 97.44,95.22 96.67,95.99 95.69,95.99 95.54,96.14 88.01,96.14 87.76,95.89 86.49,95.89 85.99,96.39 74.56,96.39 72.44,98.51 72.44,100.28 67.56,105.16 67.56,105.79 66.67,106.68 66.67,110.74 66.93,111 66.93,113.79 66.17,114.55 66.17,118.11 70.87,122.81 70.87,126.75 72.77,128.65 72.77,145.29 71.25,146.81 70.76,146.81 70.63,146.68 70.63,146.18 70.5,146.05 70.31,146.05 70.18,146.18 70.18,146.68 70.05,146.81 69.87,146.81 69.74,146.68 69.74,146.18 69.61,146.05 69.43,146.05 69.29,146.18 69.29,146.68 69.16,146.81 68.98,146.81 68.85,146.68 68.85,146.18 68.72,146.05 68.54,146.05 68.41,146.18 68.41,146.68 68.28,146.81 68.09,146.81 67.96,146.68 67.96,146.18 67.83,146.05 67.65,146.05 67.52,146.18 67.52,146.68 67.39,146.81 67.18,146.81 66.42,146.05 64.26,146.05 64.01,145.8 64.01,145.1 64.14,144.97 66.93,144.97 67.06,144.84 67.06,144.66 66.93,144.53 64.14,144.53 64.01,144.4 64.01,144.22 64.14,144.09 66.93,144.09 67.06,143.95 67.06,143.77 66.93,143.64 64.14,143.64 63.75,143.26 63.25,143.26 62.87,143.64 62.87,144.91 62.1,145.67 62.1,146.05 61.47,146.69 61.47,147.57 62.65,148.75 62.83,148.75 63.22,148.36 63.4,148.36 63.53,148.49 63.53,148.68 63.14,149.07 63.14,149.25 v1(63.63,149.73)
  BOTTOM w0.132: R355.1 v1(63.63,149.73)
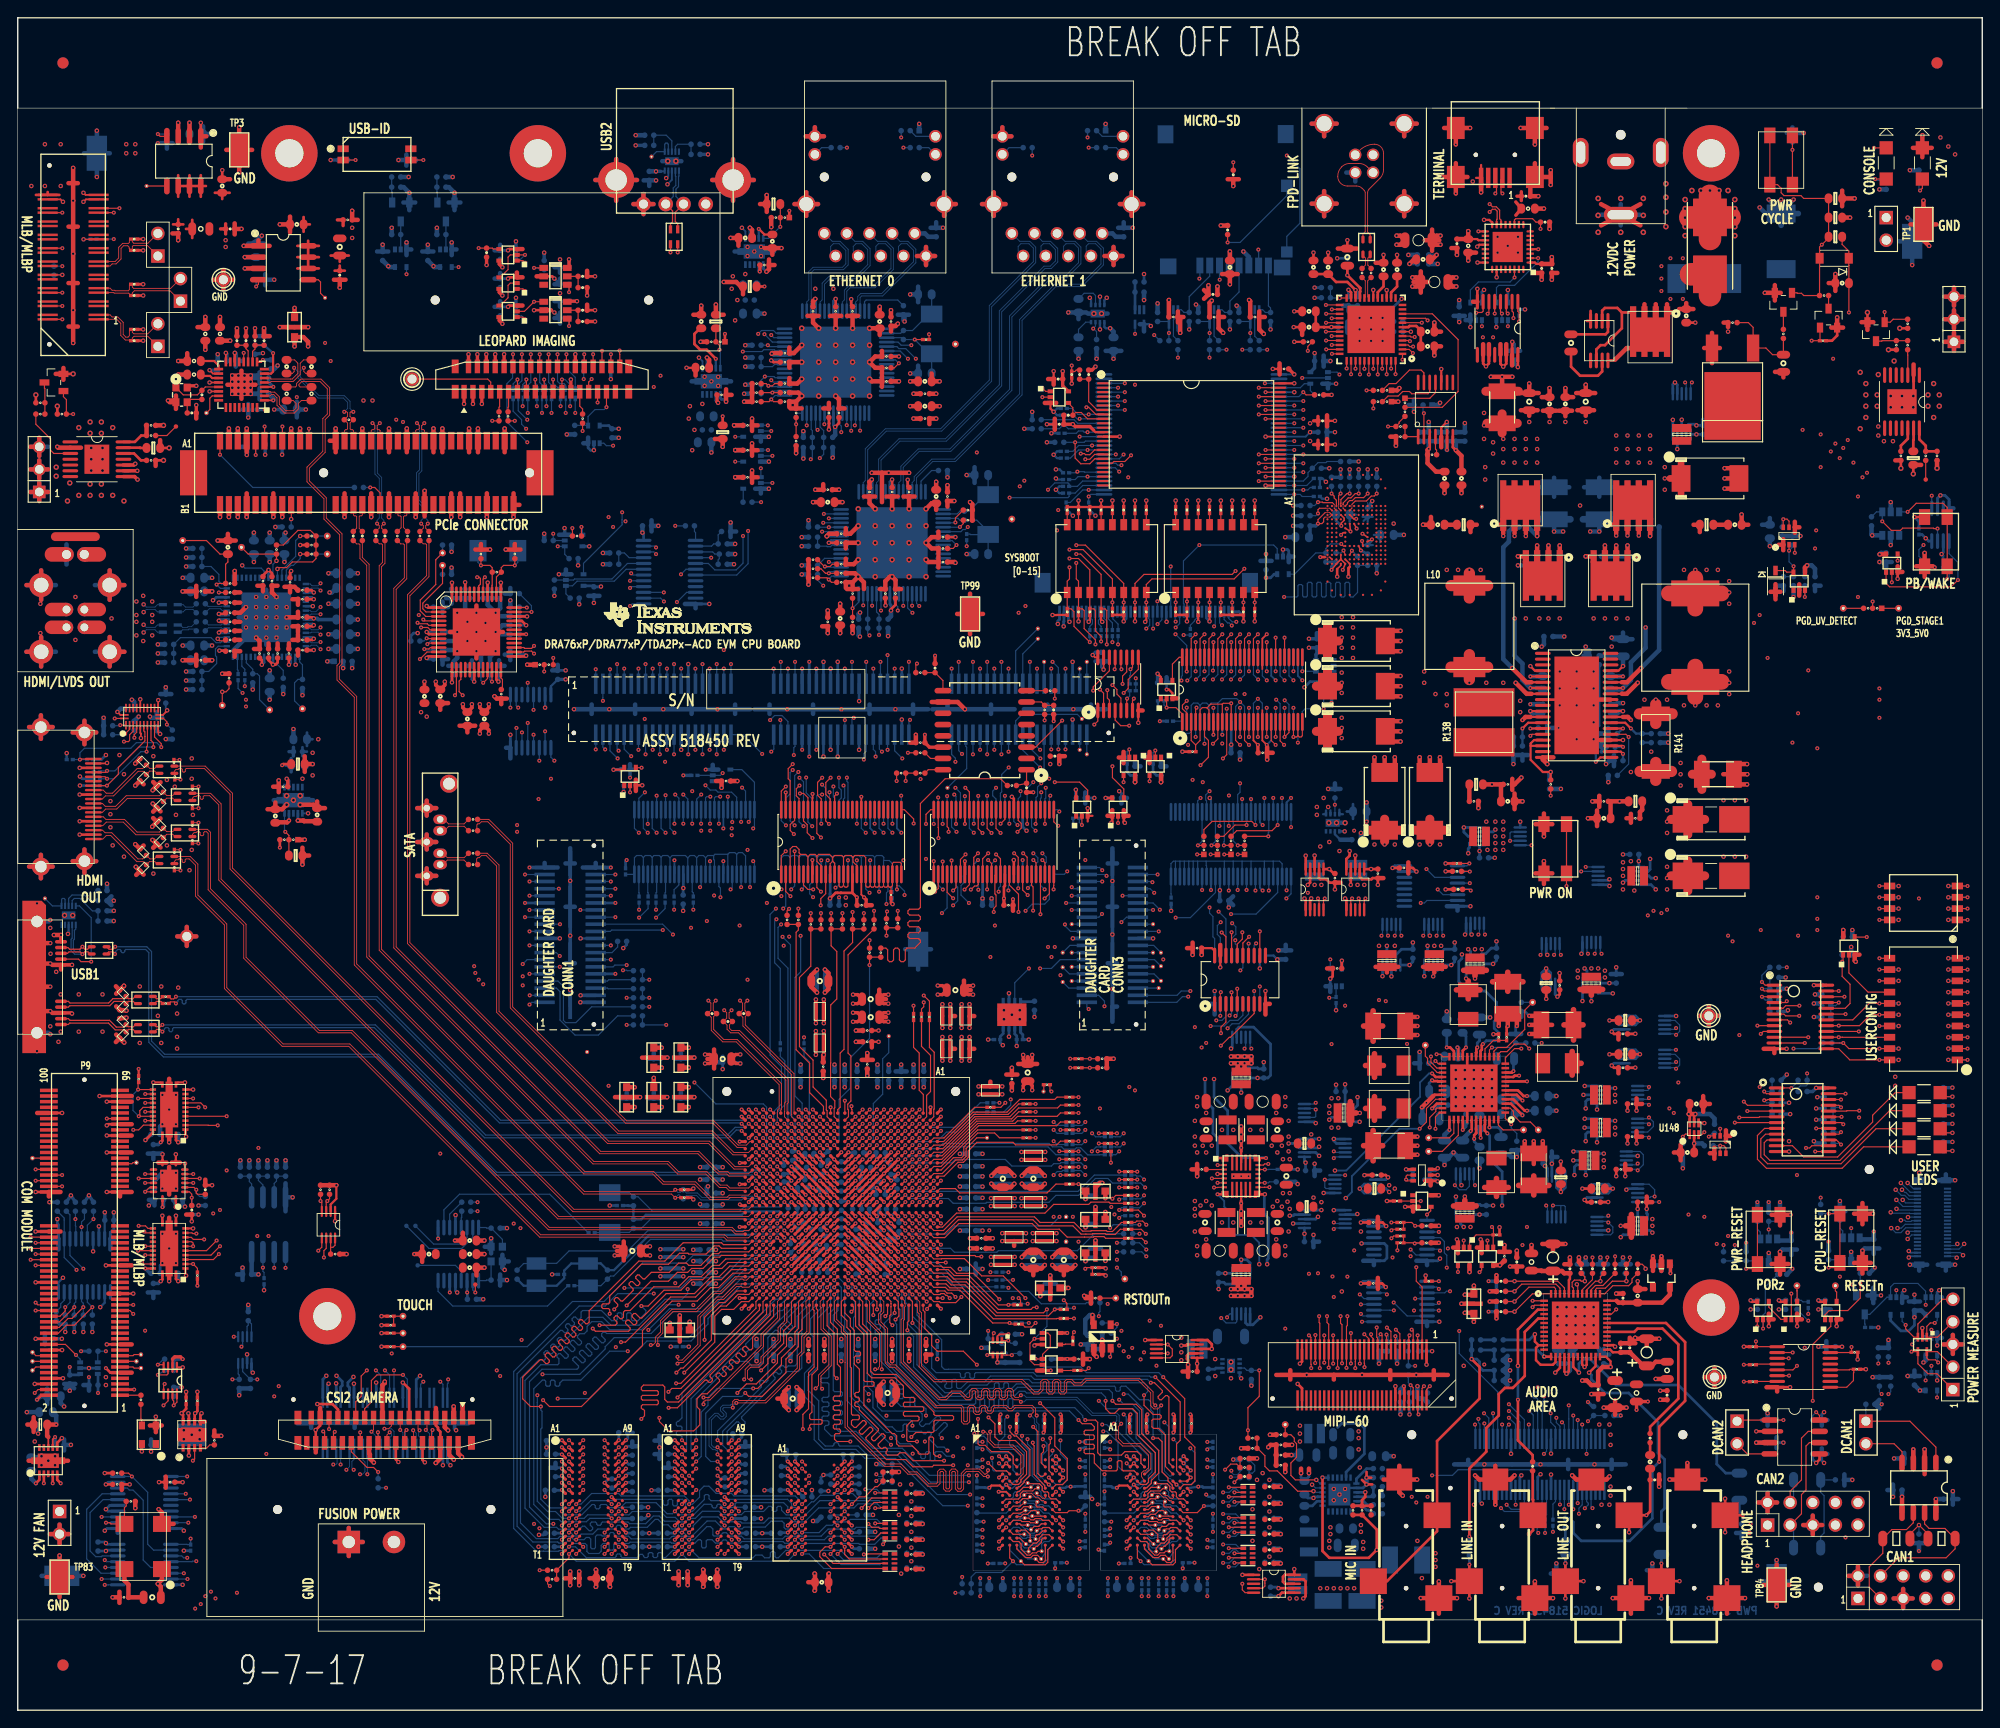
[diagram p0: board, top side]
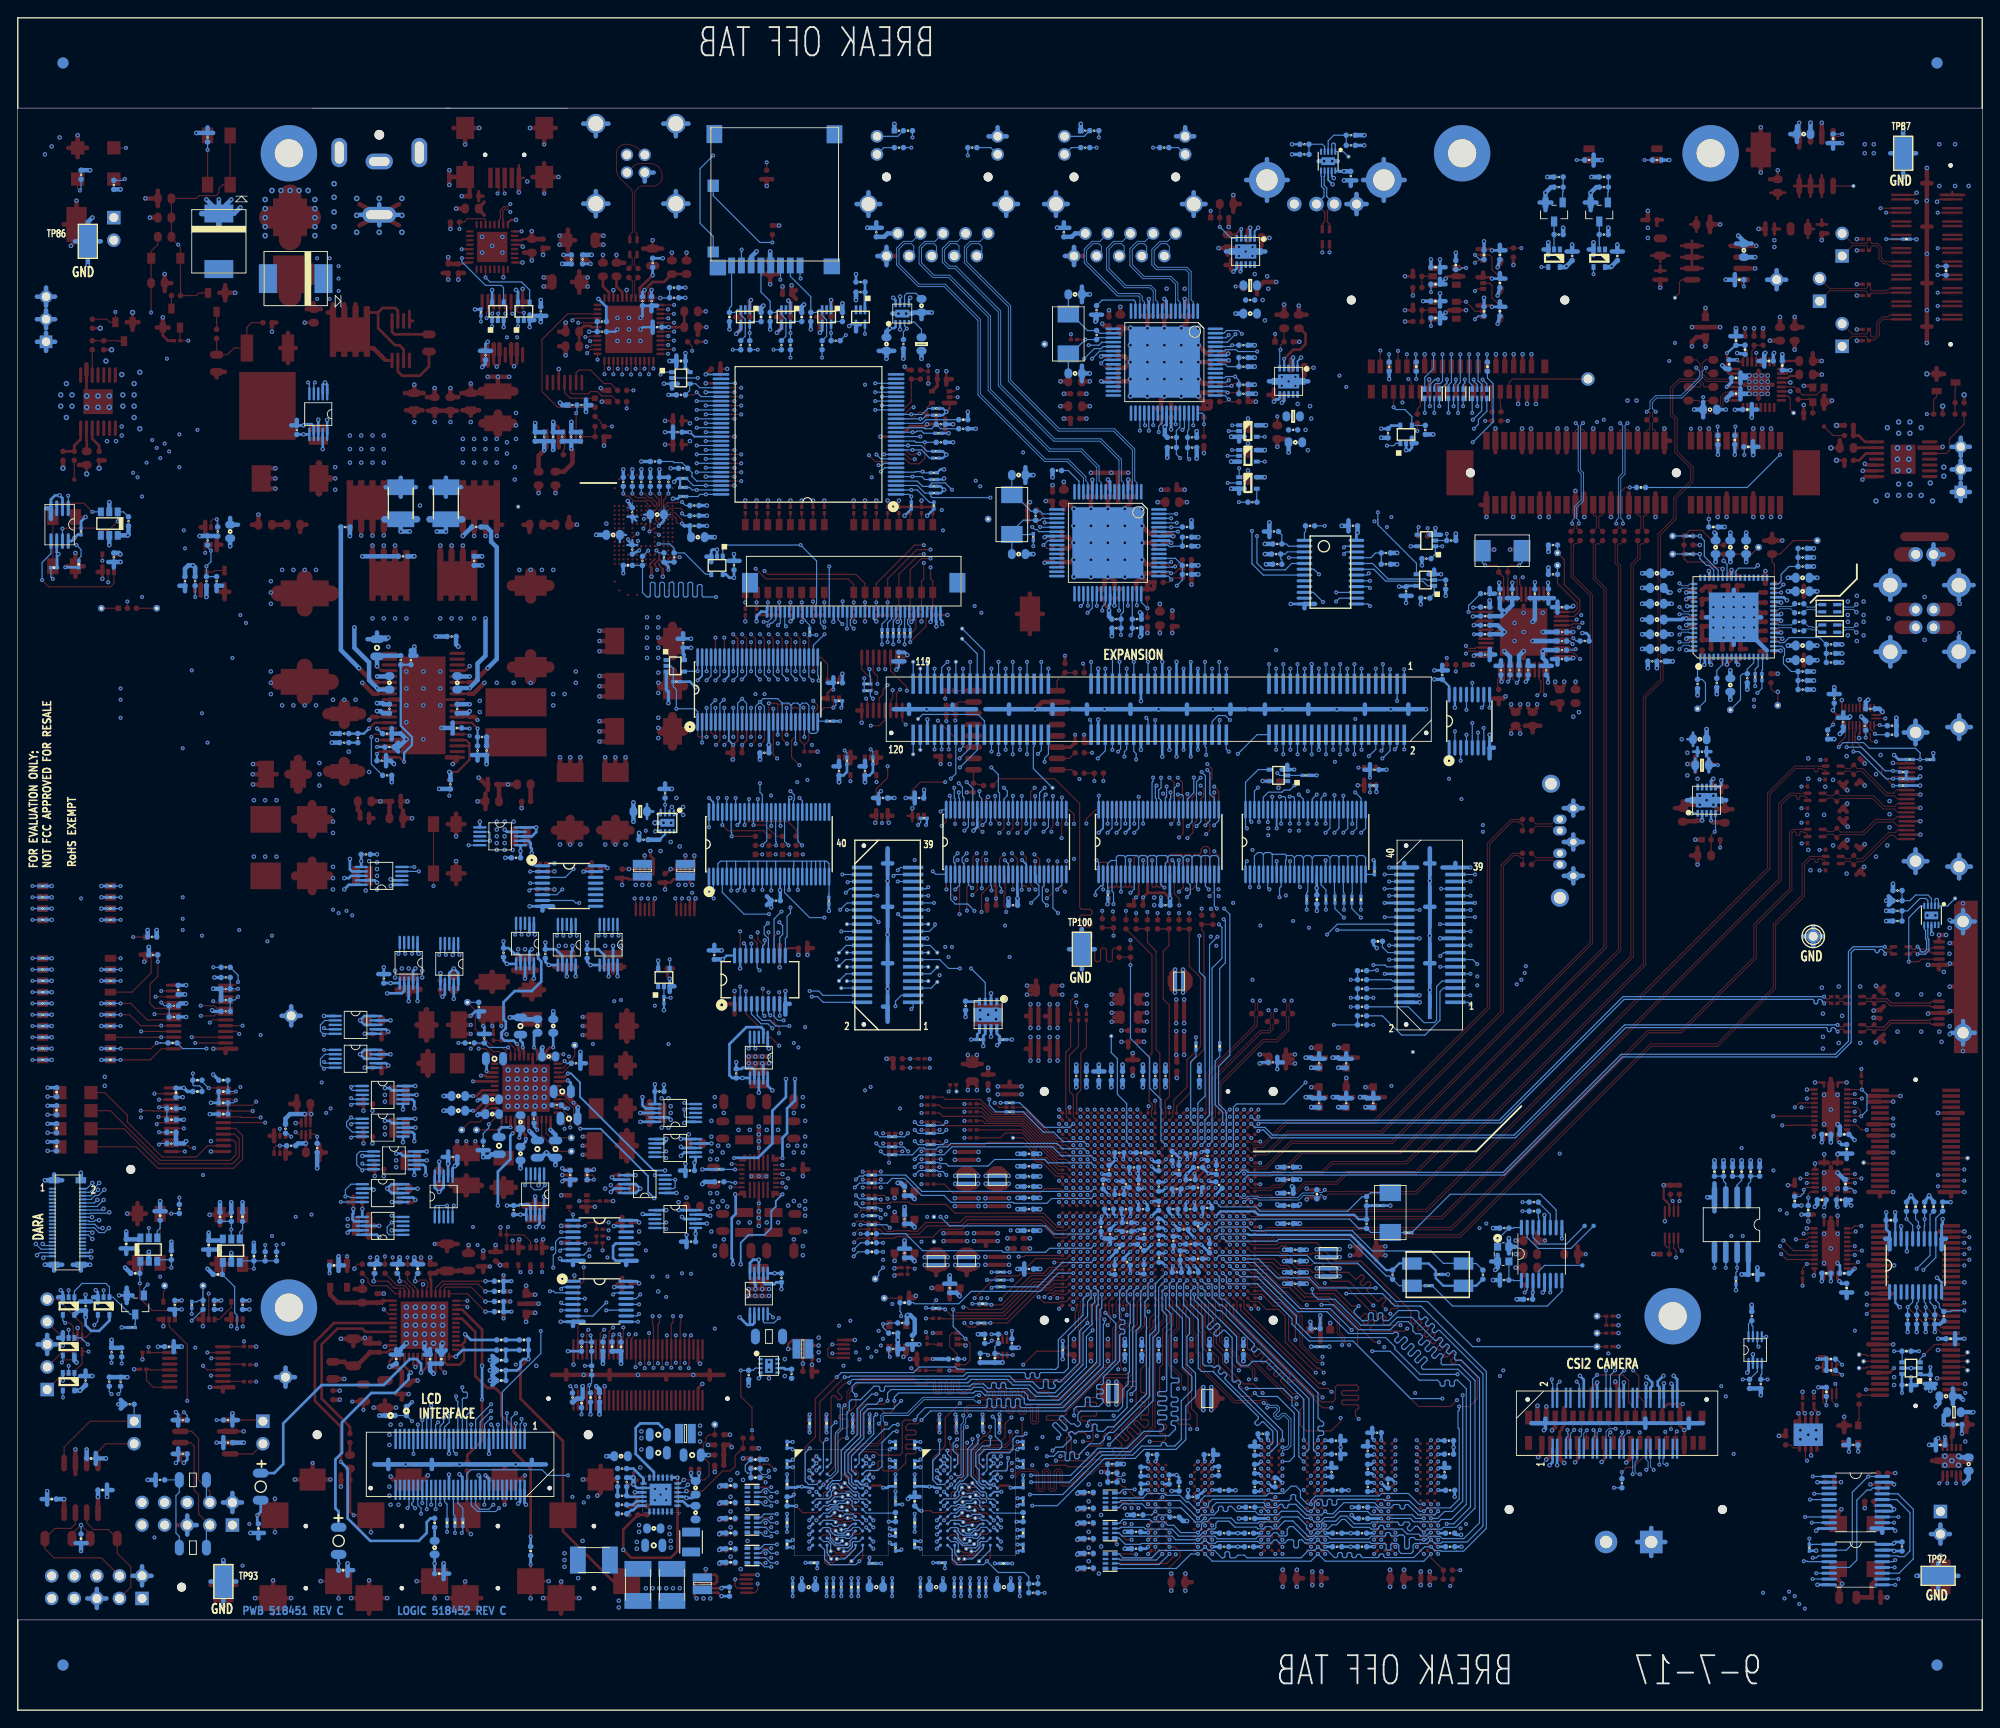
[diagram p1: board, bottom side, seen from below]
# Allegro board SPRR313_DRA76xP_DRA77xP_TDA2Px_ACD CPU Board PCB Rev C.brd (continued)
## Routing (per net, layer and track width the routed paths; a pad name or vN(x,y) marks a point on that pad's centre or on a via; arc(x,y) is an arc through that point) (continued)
CAMERA_D1: length 128.5
  TOP w0.132: R56.1 v1(63.5,143.89) ; RU8.5 v1(104.98,95.58)
  L10-SIGNAL w0.089: v1(63.5,143.89) 63.5,145.92 64.29,146.71 65.43,146.71 65.91,147.19 71.37,147.19 73.15,145.41 73.15,139.24 73.28,139.11 74.8,139.11 74.93,138.98 74.93,138.79 74.8,138.66 73.28,138.66 73.15,138.53 73.15,138.33 73.28,138.2 75.82,138.2 75.95,138.07 75.95,137.88 75.82,137.75 73.28,137.75 73.15,137.62 73.15,137.42 73.28,137.29 76.32,137.29 76.45,137.16 76.45,136.97 76.32,136.84 73.28,136.84 73.15,136.71 73.15,136.53 73.28,136.4 76.32,136.4 76.45,136.27 76.45,136.09 76.32,135.96 73.28,135.96 73.15,135.82 73.15,135.64 73.28,135.51 76.32,135.51 76.45,135.38 76.45,135.2 76.32,135.07 73.28,135.07 73.15,134.94 73.15,128.52 71.25,126.62 71.25,122.3 66.99,118.04 66.99,117.41 67.31,117.09 67.31,108.46 67.05,108.2 67.05,106.9 68.07,105.88 68.07,105.16 68.45,104.78 68.45,104.74 68.67,104.51 68.69,104.51 72.9,100.31 72.9,99.57 73.41,99.06 73.41,98.42 74.55,97.28 82.55,97.28 82.8,97.03 88.52,97.03 88.9,96.65 95.35,96.65 95.72,97.02 96.78,97.02 97.54,96.27 100.71,96.27 101.02,96.57 103.99,96.57 v1(104.98,95.58)
CAMERA_D2: length 123.9
  TOP w0.132: v1(106.55,96.27) 105.98,95.69 RU8.7
  L10-SIGNAL w0.089: v1(106.55,96.27) 104.9,96.27 103.89,97.28 94.87,97.28 94.62,97.03 88.9,97.03 88.65,97.28 83.06,97.28 82.8,97.54 75.69,97.54 73.89,99.33 73.66,99.33 73.28,99.72 73.28,100.71 71.25,102.74 71.25,103.58 68.2,106.63 68.2,115.95 67.79,116.36 67.79,117.96 71.63,121.79 71.63,126.49 73.53,128.4 73.53,130.68 74.42,131.57 76.91,131.57 77.09,131.76 77.09,132.08 76.89,132.28 73.79,132.28 73.66,132.41 73.66,132.59 73.79,132.72 77.21,132.72 77.34,132.85 77.34,133.04 77.21,133.17 74.64,133.17 74.48,133.33 74.48,133.45 74.64,133.61 76.7,133.61 76.83,133.74 76.83,133.93 76.7,134.06 73.79,134.06 73.66,134.19 73.66,134.37 73.79,134.5 76.7,134.5 76.83,134.63 76.83,137.93 73.79,140.97 73.79,145.41 71.63,147.57 64.32,147.57 v1(62.67,145.92)
  BOTTOM w0.132: v1(62.67,145.92) RN7.5
CAMERA_D3: length 125.7
  TOP w0.132: RU8.10 107.48,95.92 v1(107.95,96.39)
  L10-SIGNAL w0.089: v1(62.1,146.69) 63.37,147.96 71.88,147.96 74.17,145.67 74.17,141.22 77.85,137.54 77.85,131.57 77.46,131.18 75.15,131.18 75.06,131.09 75.06,130.82 75.15,130.73 77.09,130.73 77.22,130.6 77.22,130.42 77.09,130.29 74.04,130.29 73.91,130.16 73.91,129.98 74.04,129.85 77.09,129.85 77.22,129.71 77.22,129.53 77.09,129.4 74.04,129.4 73.91,129.27 73.91,129.09 74.04,128.96 77.09,128.96 77.22,128.83 77.22,128.64 77.09,128.51 74.04,128.51 73.91,128.38 73.91,128.14 72.01,126.24 72.01,121.41 68.59,117.99 68.59,116.7 69.85,115.44 69.85,109.98 68.57,108.71 68.57,106.81 72.44,102.95 72.44,102.57 74.3,100.71 74.3,99.31 75.82,97.79 83.06,97.79 83.31,97.54 88.9,97.54 89.03,97.41 93.98,97.41 94.11,97.54 104.39,97.54 105.16,96.77 107.57,96.77 v1(107.95,96.39)
  BOTTOM w0.132: v1(62.1,146.69) RN7.6
CAMERA_D4: length 121.7
  TOP w0.132: v1(109.09,96.39) 108.48,95.78 RU8.12
  L10-SIGNAL w0.089: v1(109.09,96.39) 108.71,96.01 108.71,95.24 108.33,94.87 97.54,94.87 97.39,95.02 97.36,95.02 97.15,95.22 86.77,95.22 85.98,96.01 73.66,96.01 71.44,98.24 71.44,100.52 69.6,102.36 68.45,102.36 66.43,104.39 66.43,109.85 66.04,110.24 66.04,112.78 66.29,113.03 66.29,113.79 65.79,114.3 65.79,118.24 70.48,122.94 70.48,127 72.42,128.94 72.42,142.33 72.14,142.62 71.43,142.62 71.3,142.75 71.3,144.4 71.17,144.53 70.99,144.53 70.86,144.4 70.86,142.75 70.73,142.62 70.54,142.62 70.41,142.75 70.41,144.4 70.28,144.53 70.1,144.53 69.97,144.4 69.97,142.75 69.84,142.62 69.65,142.62 69.52,142.75 69.52,144.4 69.39,144.53 69.21,144.53 69.08,144.4 69.08,142.75 68.95,142.62 68.77,142.62 68.64,142.75 68.64,144.4 68.51,144.53 68.32,144.53 68.19,144.4 68.19,142.75 68.06,142.62 67.31,142.62 67.18,142.75 63.12,142.75 62.23,143.64 62.23,144.4 61.6,145.03 v1(61.6,145.92)
  BOTTOM w0.132: v1(61.6,145.92) RN7.7
CAMERA_D5: length 126.5
  TOP w0.132: RU8.14 109.48,95.24 v1(109.09,95.63)
  L10-SIGNAL w0.089: v1(109.09,95.63) 109.09,95.1 108.61,94.61 97.5,94.61 97.31,94.81 97.27,94.81 97.09,95 73.66,95 70.44,98.22 70.44,99.36 65.53,104.27 65.53,110.36 65.38,110.52 65.38,118.34 70.1,123.06 70.1,127.13 71.25,128.27 71.25,130.94 71.6,131.29 71.6,133.57 72.01,133.98 72.01,134.19 71.88,134.32 70.74,134.32 70.61,134.45 70.61,134.63 70.74,134.76 71.88,134.76 72.01,134.89 72.01,135.08 71.88,135.21 70.74,135.21 70.61,135.34 70.61,135.52 70.74,135.65 71.88,135.65 72.01,135.78 72.01,135.97 71.88,136.1 70.74,136.1 70.61,136.23 70.61,136.41 70.74,136.54 71.88,136.54 72.01,136.67 72.01,136.85 71.88,136.99 70.74,136.99 70.61,137.12 70.61,137.3 70.74,137.43 71.88,137.43 72.01,137.56 72.01,137.74 71.88,137.87 70.74,137.87 70.61,138 70.61,138.19 70.74,138.32 71.88,138.32 72.01,138.45 72.01,138.63 71.88,138.76 70.74,138.76 70.61,138.89 70.61,139.08 70.74,139.21 71.88,139.21 72.01,139.34 72.01,139.52 71.88,139.65 70.74,139.65 70.61,139.78 70.61,139.97 70.74,140.1 71.88,140.1 72.01,140.23 72.01,140.41 71.88,140.54 70.74,140.54 70.61,140.67 70.61,140.86 70.74,140.99 71.88,140.99 72.01,141.12 72.01,141.48 71.76,141.73 66.8,141.73 66.17,142.37 62.28,142.37 61.03,143.62 v1(61.03,146.69)
  BOTTOM w0.132: v1(61.03,146.69) RN7.8
CAMERA_D6: length 125.7
  TOP w0.132: RU8.16 110.48,95.77 v1(109.98,96.27)
  L10-SIGNAL w0.089: v1(109.98,96.27) 109.49,95.78 109.49,95.11 109.12,94.74 109.02,94.74 108.64,94.36 97.47,94.36 97.22,94.61 97.19,94.61 97.05,94.74 73.15,94.74 64.59,103.3 64.59,118.06 69.72,123.19 69.72,127.25 70.87,128.4 70.87,133.6 70.23,134.24 70.23,134.6 70.1,134.73 68.96,134.73 68.83,134.86 68.83,135.05 68.96,135.18 70.1,135.18 70.23,135.31 70.23,135.49 70.1,135.62 68.96,135.62 68.83,135.75 68.83,135.93 68.96,136.06 70.1,136.06 70.23,136.19 70.23,136.38 70.1,136.51 68.96,136.51 68.83,136.64 68.83,136.82 68.96,136.95 70.1,136.95 70.23,137.08 70.23,137.27 70.1,137.4 68.96,137.4 68.83,137.53 68.83,137.71 68.96,137.84 70.1,137.84 70.23,137.97 70.23,138.16 70.1,138.29 68.96,138.29 68.83,138.42 68.83,138.6 68.96,138.73 70.1,138.73 70.23,138.86 70.23,139.05 70.1,139.18 68.96,139.18 68.83,139.31 68.83,139.49 68.96,139.62 70.1,139.62 70.23,139.75 70.23,139.93 70.1,140.06 68.96,140.06 68.83,140.2 68.83,140.38 68.96,140.51 70.1,140.51 70.23,140.64 70.23,140.84 69.75,141.32 64.29,141.32 63.63,141.99 61.85,141.99 60,143.83 v1(60,145.92)
  BOTTOM w0.132: v1(60,145.92) RN8.5
CAMERA_D7: length 122.5
  TOP w0.132: RU8.20 112.48,95.93 v1(112.01,96.39)
  L10-SIGNAL w0.089: v1(59.43,146.69) 59.43,143.52 61.34,141.6 63.37,141.6 64.14,140.84 64.24,140.84 64.37,140.71 64.37,139.32 64.5,139.19 64.69,139.19 64.82,139.32 64.82,140.71 64.95,140.84 65.13,140.84 65.26,140.71 65.26,139.32 65.39,139.19 65.58,139.19 65.71,139.32 65.71,140.71 65.84,140.84 66.02,140.84 66.15,140.71 66.15,139.32 66.28,139.19 66.47,139.19 66.6,139.32 66.6,140.71 66.73,140.84 66.91,140.84 67.04,140.71 67.04,139.32 67.17,139.19 67.35,139.19 67.48,139.32 67.48,140.71 67.62,140.84 67.82,140.84 68.45,140.21 68.45,134.62 69.82,133.26 69.82,132.11 70.48,131.45 70.48,128.52 69.34,127.38 69.34,123.32 64.14,118.11 64.14,103.12 72.77,94.49 96.9,94.49 97.28,94.11 110.36,94.11 111.38,95.12 111.38,95.76 v1(112.01,96.39)
  BOTTOM w0.132: v1(59.43,146.69) RN8.6
CAMERA_D8: length 117.3
  TOP w0.132: RU8.22 113.48,95.95 v1(113.03,96.39)
  L10-SIGNAL w0.089: v1(58.93,145.92) 58.93,143.25 60.96,141.22 62.48,141.22 63.75,139.95 63.75,139.32 64.26,138.81 67.31,138.81 67.82,138.3 67.82,135.38 67.56,135.12 67.56,133.86 68.46,132.97 69.34,132.97 69.47,132.84 69.47,132.65 69.34,132.52 68.46,132.52 68.33,132.39 68.33,132.21 68.46,132.08 69.34,132.08 69.47,131.95 69.47,131.76 69.34,131.63 68.46,131.63 68.33,131.5 68.33,131.3 68.46,131.17 69.85,131.17 69.98,131.04 69.98,130.85 69.85,130.72 68.46,130.72 68.33,130.59 68.33,122.81 63.75,118.24 63.75,102.87 72.39,94.23 96.65,94.23 97.03,93.85 111.12,93.85 112.59,95.32 112.59,95.95 v1(113.03,96.39)
  BOTTOM w0.132: v1(58.93,145.92) RN8.7
CAMERA_D9: length 117.5
  TOP w0.132: RU8.24 114.48,95.33 v1(114.17,95.63)
  L10-SIGNAL w0.089: v1(114.17,95.63) 111.89,93.34 96.52,93.34 96.14,93.73 71.76,93.73 62.99,102.49 62.99,107.06 60.83,109.22 60.83,111.63 62.99,113.79 62.99,118.62 67.44,123.06 67.44,131.95 65.91,133.48 65.91,134.62 65.91,134.8 66.24,135.13 66.24,135.31 66.11,135.44 65.92,135.44 65.6,135.12 65.41,135.12 65.28,135.25 65.28,135.43 65.61,135.76 65.61,135.94 65.48,136.07 65.29,136.07 64.97,135.75 64.79,135.75 64.65,135.88 64.65,136.06 64.98,136.39 64.98,136.57 64.85,136.7 64.66,136.7 64.34,136.38 64.16,136.38 64.03,136.51 64.03,136.69 64.35,137.01 64.35,137.2 64.22,137.33 64.04,137.33 63.71,137.01 63.53,137.01 63.4,137.14 63.4,137.32 63.72,137.64 63.72,137.83 63.59,137.96 63.41,137.96 63.08,137.63 62.9,137.63 56.64,143.89 56.64,144.4 57.02,144.77 57.52,144.77 58.36,145.61 v1(58.36,146.69)
  BOTTOM w0.132: v1(58.36,146.69) RN8.8
CAMERA_D10: length 119.4
  TOP w0.132: RU8.26 115.48,95.34 v1(115.19,95.63)
  L10-SIGNAL w0.089: v1(57.34,145.92) 56.01,145.92 55.49,145.41 55.49,144.66 55.88,144.27 55.88,142.62 56.77,141.73 57.53,141.73 65.15,134.11 65.15,132.97 66.67,131.44 66.67,127.27 66.54,127.14 66.17,127.14 66.04,127.01 66.04,126.82 66.17,126.69 66.54,126.69 66.67,126.56 66.67,126.38 66.54,126.25 66.17,126.25 66.04,126.12 66.04,125.93 66.17,125.8 66.54,125.8 66.67,125.67 66.67,124.23 66.54,124.1 66.04,124.1 65.91,123.96 65.91,123.78 66.04,123.65 66.54,123.65 66.67,123.52 66.67,123.32 62.23,118.87 62.23,114.05 60.07,111.89 60.07,108.97 62.23,106.81 62.23,102.11 67.82,96.52 67.82,95.5 70.1,93.22 95.5,93.22 95.89,92.84 112.31,92.84 113.07,93.6 113.54,93.6 115.19,95.24 v1(115.19,95.63)
  BOTTOM w0.132: v1(57.34,145.92) RN9.5
CAMERA_D11: length 120.9
  TOP w0.132: v1(116.45,92.33) 116.45,92.74 116.48,92.77 RU8.28
  L10-SIGNAL w0.089: v1(116.45,92.33) 115.82,91.7 115.28,91.7 114.42,90.84 107.85,90.84 107.44,90.42 106.56,90.42 106.04,90.93 102.49,90.93 101.25,92.17 99.41,92.17 99.18,91.94 98.43,91.94 97.79,92.58 95.76,92.58 95.38,92.96 83.31,92.96 82.17,91.82 79.63,91.82 79.37,92.08 76.83,92.08 76.58,91.82 70.87,91.82 66.8,95.89 64.13,95.89 61.85,98.17 61.85,106.68 59.69,108.84 59.69,112.01 61.09,113.41 61.09,118.24 65.18,122.33 65.18,126.19 65.15,126.23 65.15,126.57 65.18,126.6 65.18,131.29 64.52,131.95 64.52,132.97 60.07,137.41 57.66,137.41 56.39,138.68 56.39,141.48 55.5,142.37 55.5,144.15 55.12,144.53 55.12,145.67 56.13,146.69 v1(56.76,146.69)
  BOTTOM w0.132: v1(56.76,146.69) RN9.6
CAMERA_D12: length 115.7
  L10-SIGNAL w0.089: v1(57.28,145.16) 56.77,145.16 56.26,144.65 56.26,142.88 57.02,142.11 57.78,142.11 65.53,134.37 65.53,133.22 67.06,131.7 67.06,123.19 62.61,118.75 62.61,113.92 60.45,111.76 60.45,109.09 62.61,106.93 62.61,102.23 71.37,93.47 95.76,93.47 96.11,93.12 112.17,93.12 113.28,94.23 113.67,94.23 114.8,95.37 114.8,96.01 v1(115.19,96.39)
  BOTTOM w0.132: RN9.7 56.27,146.17 v1(57.28,145.16) ; v1(115.19,96.39) 115.63,95.96 115.63,95.38 115.48,95.23 RU15.3
CAMERA_D13: length 120.7
  L10-SIGNAL w0.089: v1(57.15,144.15) 60.45,140.84 61.34,140.84 64.66,137.53 64.84,137.53 65.74,138.42 65.92,138.42 66.05,138.29 66.05,138.11 65.15,137.21 65.15,137.03 65.29,136.9 65.47,136.9 66.36,137.79 66.55,137.79 66.68,137.66 66.68,137.48 65.78,136.58 65.78,136.4 65.91,136.27 66.1,136.27 66.99,137.17 67.18,137.17 67.31,137.03 67.31,136.85 66.41,135.96 66.41,135.77 67.18,135 67.18,133.6 67.82,132.97 67.82,122.94 63.37,118.49 63.37,112.78 61.34,110.74 61.34,109.22 63.37,107.19 63.37,102.74 72.14,93.98 96.39,93.98 96.77,93.6 111.63,93.6 113.79,95.75 113.79,96.01 v1(114.17,96.39)
  BOTTOM w0.132: RN9.8 55.69,146.11 56.64,145.16 56.64,144.65 v1(57.15,144.15) ; v1(114.17,96.39) 114.68,95.89 114.68,95.43 114.48,95.23 RU15.5
CAMERA_HSYNC: length 91.2
  L14-SIGNAL w0.109: v1(125.69,116.08) 125.69,117.39 123.7,119.38 120.14,119.38 118.6,120.92 112.63,120.92 103.38,130.18 84.84,130.18 84.54,130.47 79.46,130.47 77.98,131.95 69.6,131.95 68.96,132.59 66.55,132.59 65.15,133.99 65.15,134.75 v1(57.28,142.63)
  BOTTOM w0.132: R352.1 55.63,149.86 54.99,149.22 54.99,144.91 v1(57.28,142.63) ; v1(125.69,116.08) R457.2 R458.2
CAMERA_VSYNC: length 89
  TOP w0.132: R55.1 v1(55.88,145.03) ; v1(123.32,117.09) 123.32,117.13 123.37,117.18 RU4.13
  L14-SIGNAL w0.109: v1(123.32,117.09) 122.3,118.11 120.65,118.11 118.87,119.89 118.87,119.91 118.76,120.02 111.89,120.02 103.38,128.52 93.85,128.52 92.51,129.87 87.45,129.87 86.99,129.41 79.5,129.41 77.3,131.61 69.3,131.61 68.71,132.21 66.29,132.21 64.64,133.86 64.64,134.62 64.39,134.87 63.93,134.87 63.47,134.42 63.32,134.42 63.17,134.57 63.17,134.73 63.65,135.21 63.65,135.36 63.49,135.52 63.34,135.52 62.86,135.04 62.7,135.04 62.55,135.19 62.55,135.35 63.03,135.83 63.03,135.98 62.87,136.14 62.64,136.14 62.23,135.73 62.01,135.73 61.85,135.89 61.85,136.12 62.26,136.53 62.26,136.75 62.1,136.91 61.87,136.91 61.46,136.5 61.24,136.5 61.08,136.66 61.08,136.89 61.48,137.3 61.48,137.52 55.88,143.13 v1(55.88,145.03)
COMQ_MMC0_CLK: length 4.6
  TOP w0.132: v1(6.54,39.96) 5.35,41.15 P9.20
  BOTTOM w0.132: v1(6.54,39.96) 7.01,39.49 U132.3
COMQ_MMC0_CMD: length 8.9
  TOP w0.132: P9.24 4.57,42.42 5.46,43.31 6.35,43.31 v1(8.38,45.34)
  BOTTOM w0.132: U128.5 7.82,45.9 v1(8.38,45.34) R620.2
COMQ_MMC0_DAT0: length 7.5
  TOP w0.132: v1(7.37,45.34) 6.1,44.07 5.65,44.07 4.64,43.05 3.49,43.05
  BOTTOM w0.132: U128.6 7.17,45.97 7.37,45.78 v1(7.37,45.34) R621.2
COMQ_MMC0_DAT1: length 6.2
  TOP w0.132: P9.28 4.7,43.69 v1(6.35,45.34)
  BOTTOM w0.132: U128.7 6.52,45.92 6.35,45.76 v1(6.35,45.34) R622.2
COMQ_MMC0_DAT2: length 5.3
  TOP w0.132: P9.30 4.75,44.32 5.33,44.91 v1(5.33,45.34)
  BOTTOM w0.132: U128.8 5.87,45.87 v1(5.33,45.34) R623.2
COMQ_MMC0_DAT3: length 6.4
  TOP w0.132: P9.32 v1(2.01,44.96)
  BOTTOM w0.132: v1(2.01,44.96) 3.43,44.96 3.56,44.83 R619.2 4.83,45.34 4.83,45.72 5.22,46.11 U128.9
CON.PCIE_RXN0: length 15.2
  TOP w0.099: R90.2 40.91,132.96 40.91,133.24 v1(41.15,133.48) ; v1(40.7,144.78) 40.4,144.48 40.4,144.1 40.47,144.04 40.64,144.04 40.73,143.94 P6.A17
  BOTTOM w0.099: v1(40.7,144.78) 40.42,144.5 40.42,139.15 40.9,138.67 40.9,134.09 41.15,133.85 v1(41.15,133.48)
CON.PCIE_RXN1: length 15.5
  TOP w0.099: P6.A22 45.73,143.94 45.64,144.04 45.47,144.04 45.4,144.1 45.4,144.48 v1(45.7,144.78) ; R94.2 45.86,132.96 45.86,133.24 v1(46.1,133.48)
  BOTTOM w0.099: v1(45.7,144.78) 45.42,144.5 45.42,139.41 45.1,139.08 45.1,136.13 45.86,135.37 45.86,134.08 46.1,133.84 v1(46.1,133.48)
CON.PCIE_RXP0: length 15.2
  TOP w0.099: v1(39.88,144.78) 39.89,144.78 40.13,144.54 40.13,144.17 40,144.04 39.83,144.04 39.73,143.94 P6.A16 ; R89.2 40.64,132.97 40.64,133.23 v1(40.4,133.48)
  BOTTOM w0.099: v1(40.4,133.48) 40.4,133.85 40.64,134.09 40.64,138.56 40.16,139.04 40.16,144.5 v1(39.88,144.78)
CON.PCIE_RXP1: length 15.5
  TOP w0.099: v1(44.88,144.78) 44.89,144.78 45.13,144.54 45.13,144.17 45,144.04 44.83,144.04 44.73,143.94 P6.A21 ; v1(45.35,133.48) 45.59,133.23 45.59,132.97 R93.2
  BOTTOM w0.099: v1(44.88,144.78) 45.16,144.5 45.16,139.52 44.83,139.19 44.83,136.02 45.59,135.26 45.59,134.08 45.35,133.84 v1(45.35,133.48)
CON.PCIE_TXN0: length 3.4
  TOP w0.099: C84.2 38.39,132.94 38.39,134.27 38.47,134.35 38.64,134.35 38.73,134.45 P6.B15
CON.PCIE_TXN1: length 3.4
  TOP w0.099: P6.B20 43.73,134.45 43.64,134.35 43.47,134.35 43.37,134.25 43.37,133.03 C86.2
CON.PCIE_TXP0: length 3.4
  TOP w0.099: P6.B14 37.73,134.45 37.83,134.35 38,134.35 38.1,134.25 38.1,132.97 C82.2
CON.PCIE_TXP1: length 3.4
  TOP w0.099: C85.2 43.1,133.02 43.1,134.25 43,134.35 42.83,134.35 42.73,134.45 P6.B19
CON.SATA_RXN0: length 3.6
  TOP w0.099: C132.1 50.18,99.43 48.45,99.43 47.96,98.93 J12.5
CON.SATA_RXP0: length 3.6
  TOP w0.099: 47.48,100.2 47.92,100.2 48.43,99.7 50.17,99.7 C130.1
CON.SATA_TXN0: length 3.6
  TOP w0.099: C133.1 50.18,95.9 48.29,95.9 47.79,96.39 J12.3
CON.SATA_TXP0: length 3.6
  TOP w0.099: 47.48,95.12 47.79,95.12 48.3,95.63 50.16,95.63 C134.1
CON_LCD_GP0[31]: length 3.5
  BOTTOM w0.132: R655.2 172.59,23.19 172.88,23.47 J19.38
CON_LCD_I2C_SCL: length 3.6
  BOTTOM w0.132: R657.2 170.81,22.73 171.38,23.29 J19.32
CON_LCD_I2C_SDA: length 3.4
  BOTTOM w0.132: R656.2 171.7,21.84 171.88,22.01 J19.34
CON_LCD_PWR_DN: length 207.8
  TOP w0.132: U42.AD9 v1(84.58,61.16)
  L5-SIGNAL w0.089: v1(55.75,54.74) 61.34,60.33 79.63,60.33 80.08,60.78 84.19,60.78 v1(84.58,61.16)
  L7-SIGNAL w0.089: v1(55.75,54.74) 55.75,53.34 57.91,51.18 57.91,41.15 57.02,40.26 57.02,15.88 58.42,14.48 61.93,14.48 61.93,14.48 75.48,14.48 75.49,14.48 102.49,14.48 103.5,15.49 136.65,15.49 137.79,16.64 141.1,16.64 141.99,17.53 156.97,17.53 160.78,21.34 163.58,21.34 166.12,23.88 169.67,23.88 170.41,23.14 v1(173.38,23.14)
  L10-SIGNAL w0.089: v1(173.38,23.14) 173.38,23.52 173.35,23.55 173.35,28.32 176.53,31.5 v1(176.53,32.51)
  BOTTOM w0.132: v1(176.53,32.51) R654.2 R666.1 ; J19.40 v1(173.38,23.14)
CON_MMC1_CLK: length 11
  BOTTOM w0.132: R345.2 134.49,154.56 134.49,156.46 134.99,156.96 U98.3 135.38,157.53 135.69,157.23 R332.2 136.27,158.5 137.3,159.53 P14.5
CON_MMC1_CMD: length 11.8
  L3-SIGNAL w0.109: v1(135.13,160.91) 135.51,160.53 135.51,157.73 133.99,156.21 133.99,155.33 133.99,155.33 v1(133.99,154.91)
  BOTTOM w0.132: v1(135.13,160.91) 135.1,160.93 P14.3 ; R333.2 133.99,156.21 U98.5 v1(133.99,154.91) 133.99,154.06 R346.2
CON_MMC1_DAT0: length 15
  L3-SIGNAL w0.109: v1(138.56,154.91) 138.56,157.49 139.45,158.37 139.45,163.86 139.47,163.89 v1(139.47,164.3)
  BOTTOM w0.132: R344.2 138.56,154.19 v1(138.56,154.91) U97.5 138.56,156.21 R331.2 ; 139.5,162.48 P14.7 139.5,163.96 139.47,163.99 v1(139.47,164.3)
CON_MMC1_DAT1: length 10.7
  BOTTOM w0.132: P14.8 140.6,157.97 140.84,157.72 R330.2 140.26,157.23 139.95,157.53 U97.3 139.57,156.96 139.06,156.46 139.06,154.56 R343.2
CON_MMC1_DAT2: length 12.5
  L3-SIGNAL w0.109: v1(129.42,154.91) 129.42,157.61 v1(132.84,161.04)
  BOTTOM w0.132: R335.2 129.42,156.21 U99.5 v1(129.42,154.91) 129.42,154.06 R339.2 ; P14.1 132.9,161.1 v1(132.84,161.04)
CON_MMC1_DAT3: length 11.5
  BOTTOM w0.132: P14.2 134,161.31 131.7,159 R334.2 131.11,157.23 130.81,157.53 U99.3 130.42,156.89 129.92,156.39 129.92,154.56 R347.2
CONN_USB1_DM: length 8.3
  TOP w0.137: P8.2 5.63,85.79 5.82,85.6 6.98,85.6 v1(7.27,85.88) 7.55,85.6 7.85,85.6 8.13,85.88 FL7.3
  BOTTOM w0.137: U120.6 6.52,87.87 6.37,87.72 6.37,86.73 6.25,86.61 6.25,85.55 6.5,85.29 6.86,85.29 6.97,85.41 6.97,85.59 v1(7.27,85.88)
CONN_USB1_DP: length 8.2
  TOP w0.137: P8.3 5.59,85.14 5.75,85.29 7.02,85.29 v1(7.27,85.04) 7.52,85.29 7.9,85.29 8.13,85.06 FL7.2
  BOTTOM w0.137: v1(7.27,85.04) 6.4,85.04 5.99,85.45 5.99,86.72 6.11,86.83 U120.7
CONN_USB2_DM: length 7.6
  TOP w0.137: P2.2 73.91,168.49 73.91,167.47 74.19,167.19 FL1.3
  BOTTOM w0.137: P2.2 74,170.27 74,171.1 74.28,171.39 74.28,172.53 74.33,172.58 U92.6
CONN_USB2_DP: length 7.5
  TOP w0.137: FL1.2 73.38,167.19 73.61,167.41 73.61,168.61 73.63,168.63 P2.3
  BOTTOM w0.137: U92.7 73.93,172.58 73.98,172.53 73.98,171.52 73.69,171.23 73.69,170.27 P2.3
CONN_USB_D+: length 7.5
  TOP w0.137: U3.14 166.76,167.6 166.6,167.77 166.6,168.73 166.22,169.11 165.79,169.11 v1(165.48,169.42) ; J3.3 166.24,172.24 166.24,170.74 v1(166.12,170.61)
  L3-SIGNAL w0.127: v1(166.12,170.61) 166.4,170.33 166.4,169.34 166.19,169.14 165.76,169.14 v1(165.48,169.42)
CONN_USB_D-: length 7.5
  TOP w0.137: J3.2 166.75,172.2 166.75,170.78 v1(166.92,170.61) ; U3.15 166.26,167.67 166.32,167.73 166.32,168.62 166.11,168.83 165.79,168.83 v1(165.48,168.53)
  L3-SIGNAL w0.127: v1(165.48,168.53) 165.79,168.83 166.32,168.83 166.7,169.22 166.7,170.4 v1(166.92,170.61)
CONN_USB_RXN0: length 9.4
  TOP w0.137: FL9.3 13.23,77.11 13,76.89 12.4,76.89 U35.1 11.88,76.84 11.09,76.84 10.32,77.6 5.87,77.6 5.68,77.79 P8.9
CONN_USB_RXP0: length 9.4
  TOP w0.137: P8.10 5.68,77.14 5.84,77.29 10.19,77.29 10.96,76.53 11.93,76.53 U36.1 12.44,76.58 12.96,76.58 13.23,76.3 FL9.2
CONN_USB_TXN0: length 9.2
  TOP w0.137: P8.6 5.68,79.74 5.87,79.55 10.21,79.55 10.7,80.04 11.9,80.04 U33.1 12.42,80.04 12.96,80.04 13.21,80.29 FL8.3
CONN_USB_TXP0: length 9.2
  TOP w0.137: P8.7 5.68,79.09 5.84,79.25 10.34,79.25 10.82,79.73 11.9,79.73 U34.1 12.42,79.73 12.98,79.73 13.23,79.48 FL8.2
CPU_POR_RESETN: length 9.2
  TOP w0.132: U46.2 v1(196.22,42.93)
  BOTTOM w0.132: U127.1 197.87,50.3 R609.1 196.47,47.62 196.47,44.7 196.22,44.45 v1(196.22,42.93)
CPU_RESETN: length 9.4
  TOP w0.132: v1(207.14,48.01) 207.14,46.35 205.74,44.96 203.65,44.96 203.18,44.49 U48.1
  BOTTOM w0.132: U126.1 207.14,50.43 R608.1 v1(207.14,48.01)
CSI2_I2C_SCL: length 33.6
  TOP w0.132: v1(39.24,38.23) 38.61,37.59 38.61,35.31 38,34.7 J15.25
  L10-SIGNAL w0.089: v1(48.39,37.21) 46.86,38.73 39.75,38.73 v1(39.24,38.23) 29.72,38.23 28.7,37.21 v1(26.92,37.21)
  BOTTOM w0.132: v1(26.92,37.21) R668.2 25.28,38.09 U135.3 ; P15.2 48.29,36.71 48.39,36.8 v1(48.39,37.21)
CSI2_I2C_SDA: length 38.6
  TOP w0.132: v1(38.5,31.25) J15.24
  L10-SIGNAL w0.089: v1(27.94,28.83) 28.45,29.34 35.69,29.34 37.6,31.25 v1(38.5,31.25) 39.25,32 40.13,32 41.66,33.53 44.07,33.53 v1(47.5,36.96)
  L14-SIGNAL w0.109: v1(27.94,28.83) 27.94,33.4 v1(24.13,37.21)
  BOTTOM w0.132: v1(24.13,37.21) R669.2 24.89,37.71 24.78,37.82 U135.4 ; v1(47.5,36.96) 47.79,36.66 P15.4
CSI2_REF_CLK: length 42.3
  L10-SIGNAL w0.089: v1(41.4,25.02) 26.8,25.02 22.87,21.09 v1(19.17,21.09)
  L14-SIGNAL w0.109: v1(45.59,36.96) 45.59,35.31 42.55,32.26 42.55,29.46 41.78,28.7 41.78,25.4 v1(41.4,25.02)
  BOTTOM w0.132: P15.10 45.3,36.66 v1(45.59,36.96) ; R677.1 v1(41.4,25.02) ; U124.9 v1(19.17,21.09)
CSI2_RESETN: length 44.8
  TOP w0.132: J15.23 39,33.92 39.75,34.67 39.75,37.08 40.39,37.72 v1(43.31,37.72)
  L10-SIGNAL w0.089: v1(43.31,37.72) 42.55,36.96 42.55,35.18 39.75,32.38 37.72,32.38 35.23,29.9 28.07,29.9 v1(19.91,21.74)
  BOTTOM w0.132: v1(43.31,37.72) 43.8,37.23 P15.14 ; U124.8 v1(19.91,21.74)
CSI2_SPI[1]_CS[0]N: length 34.5
  TOP w0.132: v1(34.34,31.36) 34.38,31.36 34.49,31.24 J15.32
  L10-SIGNAL w0.089: v1(19.04,26.29) 20.07,26.29 24.64,30.86 33.84,30.86 v1(34.34,31.36) 34.34,32.05 36.2,33.91 38.35,33.91 39.62,35.18 39.62,37.59 v1(40.26,38.23)
  BOTTOM w0.132: v1(40.26,38.23) 40.8,37.69 P15.22 ; U124.1 v1(19.04,26.29)
CSI2_SPI[1]_MOSI: length 37
  TOP w0.132: v1(35.64,31.31) 35.5,31.17 J15.30
  L10-SIGNAL w0.089: v1(19.36,23.69) 25.77,30.1 34.42,30.1 v1(35.64,31.31) 37.09,32.77 39.37,32.77 41.91,35.31 41.91,37.84 v1(42.3,38.22)
  BOTTOM w0.132: P15.18 v1(42.3,38.22) ; U124.5 v1(19.36,23.69)
CSI2_SPI[1]_SCLK: length 36.3
  TOP w0.132: J15.31 v1(34.99,31.62)
  L10-SIGNAL w0.089: v1(18.88,24.34) 25.02,30.48 34.24,30.48 34.99,31.24 v1(34.99,31.62) 36.65,33.27 39.12,33.27 40.77,34.92 40.77,37.72 v1(41.27,38.23)
  BOTTOM w0.132: P15.20 41.8,37.71 v1(41.27,38.23) ; U124.4 v1(18.88,24.34)
D1_0N: length 13.6
  L12-SIGNAL w0.086: v2(14.15,123.52) 13.75,123.52 13.47,123.79 10.41,123.79 arc(9.7,123.65) 9.1,123.25 arc(8.94,123.02) 8.89,122.75 8.89,121.95 arc(8.79,121.45) 8.51,121.03 8.49,121.01 arc(8.09,120.74) 7.62,120.65 arc(6.71,120.83) 5.94,121.35 J11.3
  BOTTOM w0.095: v2(14.15,123.52) 14.45,123.82 14.6,123.82 14.6,123.82 15.43,123.82 15.7,123.55 FL10.3
D1_0P: length 13.7
  L12-SIGNAL w0.086: v2(14.15,124.39) 13.75,124.39 13.47,124.11 10.64,124.11 arc(8.99,124.44) 7.6,125.37 7.6,125.37 arc(7.09,125.71) 6.5,125.83 6.5,125.83 arc(6.3,125.79) 6.12,125.67 6.12,125.67 arc(6.01,125.5) 5.97,125.3 arc(6.05,124.88) 6.29,124.52 6.66,124.15 arc(7.04,123.9) J11.1
  BOTTOM w0.095: v2(14.15,124.39) 14.45,124.09 15.43,124.09 15.7,124.36 FL10.2
D1_1N: length 13.8
  L14-SIGNAL w0.089: v2(14.15,121.23) 13.83,121.55 9.95,121.55 arc(9.1,121.38) 8.38,120.9 7.82,120.34 arc(7.32,120) 6.73,119.89 6.4,119.89 arc(6.24,119.92) 6.1,120.02 arc(5.94,120.4) 6.1,120.78 6.88,121.56 arc(7.15,121.74) J11.4
  BOTTOM w0.095: v2(14.15,121.23) 14.45,121.54 15.42,121.54 15.7,121.26 FL11.3
D1_1P: length 13.6
  L14-SIGNAL w0.089: J11.2 6.03,124.36 arc(6.77,124.86) 7.65,125.03 arc(8.06,124.97) 8.42,124.78 arc(8.95,124.14) 9.14,123.34 9.14,123.04 arc(9.21,122.71) 9.4,122.43 9.88,121.95 arc(10.06,121.82) 10.29,121.78 13.83,121.78 v2(14.15,122.1)
  BOTTOM w0.095: FL11.2 15.7,122.07 15.44,121.8 14.44,121.8 v2(14.15,122.1)
D1_ACOUT0N: length 2.4
  BOTTOM w0.095: FL10.4 18.59,123.55 18.86,123.82 19.69,123.82 C319.2
D1_ACOUT0P: length 2.4
  BOTTOM w0.095: C318.2 19.69,124.09 18.86,124.09 18.59,124.36 FL10.1
D1_ACOUT1N: length 2.3
  BOTTOM w0.095: FL11.4 18.26,121.26 18.53,121.53 19.16,121.53 19.25,121.62 19.86,121.62 C322.2
D1_ACOUT1P: length 2.5
  BOTTOM w0.095: FL11.1 18.26,122.07 18.54,121.79 19.05,121.79 19.14,121.88 19.52,121.88 C321.2
D1_OUT0N: length 2.7
  BOTTOM w0.095: C319.1 21.54,123.9 22.78,123.9 22.99,123.69 U115.26
D1_OUT0P: length 2.5
  BOTTOM w0.095: C318.1 21.36,124.19 21.41,124.19 21.43,124.17 22.89,124.17 22.91,124.19 U115.27
D1_OUT1N: length 2.6
  BOTTOM w0.095: C322.1 21.43,121.76 22.89,121.76 22.96,121.69 U115.22
D1_OUT1P: length 2.6
  BOTTOM w0.095: U115.23 22.96,122.19 22.85,122.07 21.44,122.07 C321.1
DCAN2_MCAN_RX: length 63
  TOP w0.132: JP1.2 194.44,28.83 U57.4
  L10-SIGNAL w0.089: v1(191.01,52.45) 191.01,51.31 193.93,48.39 193.93,42.16 192.91,41.15 192.91,34.92 192.02,34.04 192.02,31.24 JP1.2
  L14-SIGNAL w0.109: v1(191.01,52.45) 181.86,52.45 181.61,52.2 177.55,52.2 176.66,53.09 168.91,53.09 167.37,51.54 160.04,51.54 v1(159.89,51.69)
  BOTTOM w0.132: RU22.6 159.73,51.86 v1(159.89,51.69)
DCAN2_MCAN_TX: length 62.6
  TOP w0.132: v1(198.5,32.64) U57.1 193.42,32.64 JP1.1
  L10-SIGNAL w0.089: JP1.1 193.29,40.89 194.18,41.78 194.18,48.9 192.28,50.8 v1(192.28,53.34)
  L14-SIGNAL w0.109: v1(159.77,53.8) 176.71,53.8 177.8,52.7 180.85,52.7 181.23,53.09 189.36,53.09 189.61,53.34 v1(192.28,53.34)
  BOTTOM w0.132: v1(159.77,53.8) 159.69,53.8 159.68,53.81 RU22.3 ; v1(198.5,32.64) R673.1
DET_USB1_VBUS: length 257.5
  TOP w0.132: U30.20 205.61,67.4 205.65,67.44 v1(207.03,67.44)
  L3-SIGNAL w0.109: v1(205.74,142.88) 205.74,127.13 207.39,125.48 207.39,67.82 207.03,67.45 v1(207.03,67.44)
  L14-SIGNAL w0.109: v1(43.7,161.53) 47.61,161.53 52.2,166.12 59.31,166.12 59.69,165.74 78.61,165.74 80.77,167.89 85.6,167.89 86.11,167.39 101.35,167.39 102.49,166.24 110.36,166.24 111.38,167.26 122.68,167.26 123.83,166.12 146.69,166.12 148.46,164.34 149.1,164.34 153.16,160.27 155.7,160.27 156.46,159.51 162.31,159.51 163.19,160.4 165.48,160.4 165.61,160.27 169.67,160.27 170.43,159.51 182.5,159.51 199.14,142.88 v1(205.74,142.88)
  BOTTOM w0.132: U95.4 v1(43.7,161.53)
DET_USB2_VBUS: length 247
  TOP w0.132: U30.19 v1(205.03,66.75)
  L3-SIGNAL w0.109: v1(205.03,66.75) 204.22,67.56 204.22,138.68 204.34,138.81 v1(204.34,142.48)
  L14-SIGNAL w0.109: v1(49.56,162.33) 49.56,162.84 52.45,165.74 59.05,165.74 59.44,165.35 78.87,165.35 81.03,167.51 83.06,167.51 84.45,166.12 88.77,166.12 89.92,164.97 123.06,164.97 123.7,165.61 146.56,165.61 148.34,163.83 149.1,163.83 153.8,159.13 154.56,159.13 154.81,159.38 155.96,159.38 156.21,159.13 182.25,159.13 198.9,142.48 v1(204.34,142.48)
  BOTTOM w0.132: U94.4 v1(49.56,162.33)
DISP1_CLK+: length 36.6
  TOP w0.099: TP32.1 v1(18.29,104.69)
  L3-SIGNAL w0.089: v1(34.04,125.95) 33.74,126.24 25.27,126.24 24.51,125.48 24.51,119.51 21.63,116.62 21.63,107.35 20.02,105.74 18.54,105.74 18.28,105.48 v1(18.29,104.69)
  BOTTOM w0.099: v1(34.04,125.95) 33.76,126.22 33.02,126.22 32.99,126.19 32.38,126.19
DISP1_CLK-: length 36.6
  TOP w0.099: TP31.1 v1(18.19,106.9)
  L3-SIGNAL w0.089: v1(18.19,106.9) 18.19,106.3 18.52,105.97 19.92,105.97 21.4,107.45 21.4,116.72 24.28,119.6 24.28,125.57 25.18,126.47 33.74,126.47 v1(34.04,126.76)
  BOTTOM w0.099: 32.38,126.69 32.88,126.69 33.07,126.49 33.76,126.49 v1(34.04,126.76)
DISP1_D0+: length 33.1
  TOP w0.099: TP34.1 v1(20.32,101.46)
  L3-SIGNAL w0.089: v1(20.32,101.46) 20.32,102.44 20.55,102.67 21.64,102.67 24.75,105.77 24.75,116.69 27.56,119.51 29.34,119.51 31.5,121.67 31.5,122.94 32,123.44 33.49,123.44 33.62,123.57 33.74,123.57 v1(34.04,123.28)
  BOTTOM w0.099: 32.38,123.19 32.88,123.19 32.99,123.3 34.01,123.3 v1(34.04,123.28)
DISP1_D0-: length 33.1
  TOP w0.099: TP33.1 v1(20.32,103.9)
  L3-SIGNAL w0.089: v1(20.32,103.9) 20.32,103.12 20.55,102.9 21.55,102.9 24.52,105.87 24.52,116.79 27.46,119.74 29.24,119.74 31.27,121.76 31.27,123.03 31.91,123.67 33.4,123.67 33.52,123.8 33.74,123.8 v1(34.04,124.09)
  BOTTOM w0.099: v1(34.04,124.09) 33.51,123.57 32.99,123.57 32.88,123.69 32.38,123.69
DISP1_D1+: length 34
  TOP w0.099: v1(20.3,97.5) 20.28,97.52 TP36.1
  L3-SIGNAL w0.089: v1(20.3,97.5) 20.31,98.44 20.45,98.58 20.8,98.58 20.9,98.57 27.3,104.98 27.3,116.53 28.28,117.51 28.28,118.35 28.67,118.75 30.23,118.75 32.77,121.28 33.74,121.28 v1(34.04,120.99)
  BOTTOM w0.099: 32.38,121.19 32.94,121.19 33.02,121.27 33.76,121.27 v1(34.04,120.99)
DISP1_D1-: length 34
  TOP w0.099: TP35.1 v1(20.32,99.83)
  L3-SIGNAL w0.089: v1(20.32,99.83) 20.31,98.94 20.45,98.81 20.45,98.81 20.81,98.8 27.08,105.07 27.08,116.63 28.05,117.6 28.05,118.45 28.58,118.97 30.13,118.97 32.67,121.51 33.74,121.51 v1(34.04,121.81)
  BOTTOM w0.099: 32.38,121.69 32.88,121.69 33.03,121.53 33.76,121.53 v1(34.04,121.81)
DISP1_D2+: length 36.4
  TOP w0.099: TP38.1 18.28,94.48 v1(18.29,94.46)
  L3-SIGNAL w0.089: v1(18.29,94.46) 18.29,95.27 18.44,95.43 20.06,95.43 28.45,103.82 28.45,111.12 30.73,113.41 30.73,115.12 32.26,116.64 32.26,119.51 32.51,119.76 33.4,119.76 33.52,119.63 33.74,119.63 v1(34.04,119.34)
  BOTTOM w0.099: 32.38,119.69 32.88,119.69 32.99,119.8 33.57,119.8 v1(34.04,119.34)
DISP1_D2-: length 36.4
  TOP w0.099: v1(18.29,96.77) 18.28,96.79 TP37.1
  L3-SIGNAL w0.089: v1(34.04,120.15) 33.74,119.86 33.62,119.86 33.49,119.99 32.42,119.99 32.03,119.6 32.03,116.74 30.51,115.21 30.51,113.51 28.22,111.22 28.22,103.91 19.96,95.66 18.45,95.66 18.29,95.82 v1(18.29,96.77)
  BOTTOM w0.099: 32.38,120.19 32.88,120.19 32.99,120.07 33.95,120.07 v1(34.04,120.15)
DISP1_VPOC_ONN: length 75.8
  TOP w0.132: Q3.G 5.13,147.75 5.46,147.42 R51.2 v1(6.22,145.8)
  L12-SIGNAL w0.089: v1(6.22,145.8) 10.29,145.8 20.7,135.38 33.27,135.38 36.83,131.83 55.37,131.83 60.2,127 66.29,127 67.06,126.24 v1(68.83,126.24)
  BOTTOM w0.132: v1(68.83,126.24) 68.99,126.39 U110.16
DISP2_VPOC_ONN: length 167.9
  TOP w0.132: RU7.44 91.83,102.85 v1(92.09,103.11) ; v1(209.88,157.28) Q5.G 210.52,156.13 210.85,156.46 R47.2
  L7-SIGNAL w0.089: v1(107.82,141.48) 105.41,139.06 105.41,137.54 103.89,136.02 103.89,128.27 99.95,124.33 99.95,123.32 98.42,121.79 98.42,117.86 95.25,114.68 95.25,107.82 92.84,105.41 92.84,104.65 92.09,103.9 v1(92.09,103.11)
  L10-SIGNAL w0.089: v1(209.88,157.28) 209.17,157.99 173.23,157.99 172.09,159.13 157.23,159.13 156.21,158.12 147.66,158.12 147.15,157.61 146.43,157.61 144.65,155.83 144.65,153.8 143.38,152.53 134.15,152.53 134.15,152.53 126.87,152.53 123.44,155.96 120.4,155.96 120.14,155.7 120.14,151.26 118.75,149.86 115.44,149.86 111.76,146.18 111.76,145.41 v1(107.82,141.48)
DISP_SCL: length 374.5
  TOP w0.132: v1(34.42,50.93) 34.42,51.69 34.68,51.95 U146.6 ; R736.2 v1(155.11,51.73) ; U8.8 v1(157.85,156.07)
  L10-SIGNAL w0.089: v1(164.72,154.43) 163.94,153.65 163.94,141.44 163.43,140.93 163.43,133.77 164.88,132.32 164.88,125.87 161.52,122.52 161.52,97.83 162.72,96.63 162.66,96.56 162.66,96.22 162.9,95.98 163.4,95.98 165.52,93.85 173.78,93.85 174.5,93.13 174.5,92.55 169.54,87.59 169.54,83.61 170.94,82.21 170.94,80.42 170.92,80.4 170.92,78.68 171.96,77.64 171.96,74 171.45,73.49 171.45,66.08 171.96,65.58 171.96,63.46 169.16,60.66 v1(169.16,52.32) 169.16,35.56 170.94,33.78 170.94,31.11 170.05,30.23 170.05,25.4 170.94,24.51 v1(170.94,19.94)
  L12-SIGNAL w0.089: v1(155.11,51.73) 155.49,51.73 155.96,52.2 156.75,52.2 156.98,51.98 158.66,51.98 158.87,52.19 159.93,52.19 160.19,52.45 162.39,52.45 162.4,52.44 165.39,52.44 165.39,52.45 166.12,52.45 166.5,52.83 168.66,52.83 v1(169.16,52.32)
  L14-SIGNAL w0.109: v1(164.72,154.43) 159.49,154.43 v1(157.85,156.07) ; v1(34.42,50.93) 30.35,46.86 30.35,40.13 32.89,37.59 32.89,31.5 26.8,25.4 26.8,18.67 34.2,11.26 152.99,11.26 153.11,11.13 153.63,11.13 154.05,11.56 168.91,11.56 170.98,13.63 170.98,14.65 170.94,14.7 v1(170.94,19.94)
  BOTTOM w0.132: R657.1 170.81,20.07 v1(170.94,19.94)
DISP_SDA: length 378.4
  TOP w0.132: R735.2 154.56,54.1 154.44,53.98 v1(154.43,53.98) ; v1(158.5,156.34) 158.26,156.57 U8.9 ; v1(33.78,51.69) 34.18,52.09 U146.5
  L10-SIGNAL w0.089: v1(165.86,154.43) 164.34,152.91 164.34,141.1 163.96,140.72 163.96,133.99 165.23,132.72 165.23,125.48 162.05,122.3 162.05,98.04 165.74,94.36 173.99,94.36 175.01,93.34 175.01,92.33 170.05,87.38 170.05,83.82 171.45,82.42 171.45,80.21 171.43,80.19 171.43,78.89 172.47,77.85 172.47,73.79 171.96,73.28 171.96,66.29 172.47,65.79 172.47,63.25 169.67,60.45 v1(169.67,54.36) 169.67,51.62 169.93,51.37 169.93,46.22 169.92,46.22 169.92,35.88 171.7,34.1 171.7,30.8 170.78,29.88 170.78,25.75 171.7,24.83 v1(171.7,19.94)
  L12-SIGNAL w0.089: v1(154.43,53.98) 154.44,53.98 156.46,53.98 157.1,53.34 160.66,53.34 161.04,53.72 168.4,53.72 169.04,54.36 v1(169.67,54.36)
  L14-SIGNAL w0.109: v1(171.7,19.94) 171.7,13.27 169.34,10.91 33.92,10.91 26.42,18.41 26.42,25.55 32.51,31.64 32.51,37.32 30,39.83 30,47.15 33.78,50.93 v1(33.78,51.69) ; v1(165.86,154.43) 165.35,154.94 159.38,154.94 158.5,155.83 v1(158.5,156.34)
  BOTTOM w0.132: R656.1 v1(171.7,19.94)
EMAC[0]_RXC: length 55.2
  L3-SIGNAL w0.109: v1(81.43,103.78) 81.43,104.98 81.32,105.08 80.88,105.08 80.77,105.19 80.77,105.41 80.88,105.52 81.32,105.52 81.43,105.63 81.43,122.32 86.23,127.13 86.23,135.64 90.68,140.08 90.68,141.32 90.79,141.43 92.09,141.43 92.2,141.54 92.2,141.75 92.09,141.86 90.79,141.86 90.68,141.97 90.68,142.19 90.79,142.3 92.09,142.3 92.2,142.41 92.2,142.63 92.09,142.74 90.79,142.74 90.68,142.85 v1(90.68,144.65)
  BOTTOM w0.132: v1(81.43,103.78) 81.82,103.39 RU17.54 ; U101.43 90.7,144.67 v1(90.68,144.65)
EMAC[0]_RXCTL: length 60.7
  L3-SIGNAL w0.109: v1(83.99,150.02) 85.06,150.02 85.72,149.35 85.72,140.34 82.55,137.16 82.55,127.13 78.18,122.75 78.18,107.77 77.98,107.57 77.98,104.7 v1(77.31,104.04)
  BOTTOM w0.132: v1(77.31,104.04) 77.84,103.5 78.49,103.5 78.72,103.27 80.25,103.27 80.82,102.69 RU17.52 ; U101.53 85.14,149.89 85.01,150.02 v1(83.99,150.02) 83.57,149.6 R356.1 R357.1
EMAC[0]_RXD0: length 58.4
  L3-SIGNAL w0.109: v1(90.17,140.84) 90.17,140.21 85.72,135.76 85.72,130.95 85.62,130.84 84.56,130.84 84.45,130.73 84.45,130.51 84.56,130.4 85.62,130.4 85.72,130.29 85.72,130.07 85.62,129.96 84.56,129.96 84.45,129.85 84.45,129.63 84.56,129.53 85.62,129.53 85.72,129.42 85.72,129.2 85.62,129.09 84.56,129.09 84.45,128.98 84.45,128.76 84.56,128.65 85.62,128.65 85.72,128.54 85.72,128.32 85.62,128.22 84.56,128.22 84.45,128.11 84.45,127.89 84.56,127.78 85.62,127.78 85.72,127.67 85.72,127.25 81.03,122.56 81.03,107.32 80.26,106.55 80.26,103.2 v1(79.82,102.76)
  BOTTOM w0.132: v1(90.17,140.84) 90.6,141.27 R373.1 R367.2 90.6,143.94 90.2,144.34 U101.44 ; RU17.50 v1(79.82,102.76)
EMAC[0]_RXD1: length 57.9
  L3-SIGNAL w0.109: v1(89.92,144.02) 89.92,141.73 89.66,141.48 89.66,140.34 84.07,134.75 84.07,134.51 84.18,134.4 85.11,134.4 85.22,134.29 85.22,134.07 85.11,133.96 84.18,133.96 84.07,133.86 84.07,133.64 84.18,133.53 85.11,133.53 85.22,133.42 85.22,133.2 85.11,133.09 84.18,133.09 84.07,132.98 84.07,132.75 84.18,132.64 85.11,132.64 85.22,132.53 85.22,132.31 85.11,132.2 84.18,132.2 84.07,132.09 84.07,131.87 84.18,131.76 85.11,131.76 85.22,131.65 85.22,131.43 85.11,131.33 84.18,131.33 84.07,131.22 84.07,126.24 80.64,122.81 80.64,107.82 79.76,106.93 79.76,103.55 v1(78.97,102.76)
  BOTTOM w0.132: RU17.47 78.32,102.63 78.46,102.76 v1(78.97,102.76) ; v1(89.92,144.02) 89.7,144.24 U101.45
EMAC[0]_RXD2: length 52.7
  L3-SIGNAL w0.109: v1(89.15,140.72) 88.11,139.67 87.96,139.67 87.54,140.09 87.38,140.09 87.23,139.93 87.23,139.78 87.65,139.36 87.65,139.21 87.49,139.05 87.34,139.05 86.92,139.47 86.77,139.47 86.61,139.32 86.61,139.16 87.03,138.74 87.03,138.59 83.57,135.13 83.57,126.75 80.26,123.44 80.26,118.87 79.76,118.36 79.76,117.53 79.88,117.41 79.88,107.7 78.85,106.66 78.85,104.38 77.86,103.38 v1(77.86,102.76)
  BOTTOM w0.132: U101.46 89.2,144.07 89.33,143.94 R368.1 R374.2 89.33,140.89 v1(89.15,140.72) ; v1(77.86,102.76) 77.45,102.76 77.32,102.63 RU17.45
EMAC[0]_RXD3: length 54.2
  L3-SIGNAL w0.109: v1(76.83,103) 78.36,104.52 78.36,106.68 78.98,107.3 78.98,108.2 79.25,108.46 79.25,116.73 78.98,117 78.98,119.08 78.98,119.09 78.98,119.42 78.98,119.42 78.98,122.8 83.04,126.85 83.04,137.14 86.11,140.21 86.11,145.67 86.61,146.18 88.27,146.18 88.7,145.74 v1(88.7,144.53)
  BOTTOM w0.132: v1(76.83,103) 76.32,102.48 RU17.43 ; U101.47 v1(88.7,144.53)
EMAC[0]_TXC: length 61.6
  L3-SIGNAL w0.109: v1(92.58,143.76) 92.58,141.1 86.74,135.25 86.74,127 81.92,122.17 81.92,103.63 80.64,102.36 76.2,102.36 75.03,103.53 70.78,103.53 v1(70.5,103.25)
  BOTTOM w0.132: RU17.30 69.82,102.57 v1(70.5,103.25) ; v1(92.58,143.76) 92.58,144.44 92.2,144.83 U101.40
EMAC[0]_TXCTL: length 65.4
  L3-SIGNAL w0.109: v1(84.71,149.61) 85.34,148.97 85.34,140.59 81.03,136.27 79.87,136.27 79.76,136.16 79.76,135.94 79.87,135.84 81.03,135.84 81.14,135.73 81.14,135.51 81.03,135.4 79.87,135.4 79.76,135.29 79.76,135.07 79.87,134.96 81.03,134.96 81.14,134.85 81.14,126.35 77.6,122.81 77.6,117.73 77.09,117.22 77.09,111.58 73.14,107.63 73.09,107.63 69.63,104.17 69.63,100.89 v1(70.83,99.69)
  BOTTOM w0.132: U101.52 84.93,149.39 v1(84.71,149.61) ; RU17.32 v1(70.83,99.69)
EMAC[0]_TXD0: length 69.9
  L3-SIGNAL w0.109: v1(74.82,103) 74.82,101.71 75.06,101.47 75.29,101.47 75.4,101.58 75.4,101.87 75.51,101.98 75.73,101.98 75.84,101.87 75.84,101.58 75.95,101.47 76.17,101.47 76.28,101.58 76.28,101.87 76.39,101.98 76.6,101.98 76.71,101.87 76.71,101.58 76.82,101.47 77.04,101.47 77.15,101.58 77.15,101.87 77.26,101.98 77.48,101.98 77.59,101.87 77.59,101.58 77.7,101.47 77.91,101.47 78.02,101.58 78.02,101.87 78.13,101.98 78.35,101.98 78.46,101.87 78.46,101.58 78.57,101.47 78.79,101.47 78.9,101.58 78.9,101.87 79.01,101.98 79.23,101.98 79.33,101.87 79.33,101.58 79.44,101.47 79.66,101.47 79.77,101.58 79.77,101.87 79.88,101.98 80.1,101.98 80.21,101.87 80.21,101.58 80.32,101.47 80.54,101.47 80.64,101.58 80.64,101.87 80.75,101.98 80.97,101.98 81.08,101.87 81.08,101.58 81.19,101.47 82.04,101.47 82.93,102.36 82.93,102.6 82.82,102.71 82.41,102.71 82.3,102.82 82.3,103.04 82.41,103.14 82.82,103.14 82.93,103.25 82.93,103.47 82.82,103.58 82.41,103.58 82.3,103.69 82.3,103.91 82.41,104.02 82.82,104.02 82.93,104.13 82.93,104.35 82.82,104.45 82.41,104.45 82.3,104.56 82.3,104.78 82.41,104.89 82.82,104.89 82.93,105 82.93,105.22 82.82,105.33 82.41,105.33 82.3,105.44 82.3,105.66 82.41,105.77 82.82,105.77 82.93,105.87 82.93,106.17 82.42,106.68 82.42,121.92 87.25,126.75 87.25,135 88.9,136.65 89.79,136.65 90.3,137.16 90.3,138.18 93.2,141.08 v1(93.2,144.55)
  BOTTOM w0.132: U101.38 v1(93.2,144.55) ; v1(74.82,103) 75.32,102.49 RU17.41
EMAC[0]_TXD1: length 62.9
  L3-SIGNAL w0.109: v1(73.91,103) 73.91,101.47 74.3,101.09 82.55,101.09 83.31,101.85 83.31,106.55 82.8,107.06 82.8,107.95 83.31,108.46 83.31,116.97 89.03,122.68 89.03,125.6 88.48,126.15 88.48,127.08 88.9,127.51 88.9,132.84 88.39,133.35 88.39,134.11 90.68,136.4 90.68,138.05 93.7,141.07 v1(93.7,143.92)
  BOTTOM w0.132: RU17.39 74.32,102.59 v1(73.91,103) ; U101.37 v1(93.7,143.92)
EMAC[0]_TXD2: length 67.8
  L3-SIGNAL w0.109: v1(94.11,144.53) 94.11,140.97 91.06,137.92 91.06,136.27 89.53,134.75 89.53,122.43 83.69,116.59 83.69,116.35 83.85,116.19 84.42,116.19 84.58,116.03 84.58,115.8 84.42,115.64 83.85,115.64 83.69,115.48 83.69,115.26 83.85,115.1 84.42,115.1 84.58,114.94 84.58,114.71 84.42,114.55 83.85,114.55 83.69,114.39 83.69,108.14 83.29,107.73 83.29,107.4 83.69,107 83.69,101.47 82.93,100.71 72.52,100.71 72.01,101.22 72.01,102.11 v1(72.82,102.92)
  BOTTOM w0.132: RU17.36 v1(72.82,102.92) ; v1(94.11,144.53) 94.2,144.62 U101.36
EMAC[0]_TXD3: length 67.3
  L3-SIGNAL w0.109: v1(94.7,143.94) 94.7,141.05 91.44,137.79 91.44,136.14 89.92,134.62 89.92,121.41 85.09,116.59 85.09,114.3 84.18,113.39 84.18,101.08 83.44,100.33 71.25,100.33 70.66,100.92 70.66,101.71 v1(71.82,102.87)
  BOTTOM w0.132: U101.35 v1(94.7,143.94) ; RU17.34 v1(71.82,102.87)
EMAC[1]_RXC: length 31.5
  L14-SIGNAL w0.109: v1(97.05,123.7) 98.57,122.17 102.1,122.17 106.18,118.09 106.18,117.76 106.17,117.75 106.17,117.47 105.92,117.22 105.92,110.11 106.87,109.16 106.87,105.99 108.98,103.87 v1(108.98,102.86)
  BOTTOM w0.132: RU15.41 v1(108.98,102.86) ; U108.43 v1(97.05,123.7)
EMAC[1]_RXCTL: length 42
  L14-SIGNAL w0.109: v1(107.98,102.84) 107.98,104.24 106.55,105.66 106.55,107.95 105.54,108.97 105.54,117.35 101.09,121.79 98.3,121.79 96.65,123.44 96.65,124.46 95.89,125.22 94.61,125.22 93.34,126.49 v1(90.55,126.49)
  BOTTOM w0.132: v1(90.55,126.49) 89.92,127.13 R424.1 R421.1 90.71,129.57 U108.53 ; RU15.39 v1(107.98,102.84)
EMAC[1]_RXD0: length 35.5
  L14-SIGNAL w0.109: v1(103.47,102.67) 103.47,103.06 103.48,103.07 103.48,110.99 103.32,111.15 102.85,111.15 102.69,111.31 102.69,111.53 102.85,111.69 103.32,111.69 103.48,111.85 103.48,112.08 103.32,112.24 102.01,112.24 101.85,112.4 101.85,112.62 102.01,112.78 103.32,112.78 103.48,112.94 103.48,113.17 103.32,113.33 102.01,113.33 101.85,113.49 101.85,113.72 102.01,113.88 103.32,113.88 103.48,114.04 103.48,116.61 99.82,120.27 97.51,120.27 v1(96.82,120.95)
  BOTTOM w0.132: v1(96.82,120.95) R432.1 R430.2 96.82,123.27 96.55,123.54 U108.44 ; v1(103.47,102.67) 103.48,102.66 RU15.30
EMAC[1]_RXD1: length 39.8
  L14-SIGNAL w0.109: v1(96.05,124.24) 96.05,121.76 96.39,121.41 99.31,121.41 99.79,120.93 100.02,120.93 100.43,121.34 100.65,121.34 100.81,121.18 100.81,120.96 100.4,120.55 100.4,120.32 100.56,120.16 100.79,120.16 101.33,120.7 101.55,120.7 101.71,120.54 101.71,120.31 101.18,119.78 101.18,119.55 101.34,119.39 101.56,119.39 102.1,119.93 102.32,119.93 102.48,119.77 102.48,119.54 101.95,119 101.95,118.78 102.92,117.8 103.15,117.8 103.68,118.34 103.91,118.34 104.07,118.18 104.07,117.95 103.53,117.42 103.53,117.19 103.89,116.84 103.89,116.62 104.05,116.46 104.36,116.46 104.52,116.3 104.52,116.07 104.36,115.91 104.05,115.91 103.89,115.75 103.89,115.52 104.05,115.36 104.36,115.36 104.52,115.2 104.52,114.98 104.36,114.82 104.05,114.82 103.89,114.66 103.89,114.43 104.05,114.27 104.36,114.27 104.52,114.11 104.52,113.89 104.36,113.73 104.05,113.73 103.89,113.57 103.89,113.34 104.05,113.18 104.36,113.18 104.52,113.02 104.52,112.79 104.36,112.63 104.05,112.63 103.89,112.47 103.89,103.42 v1(104.48,102.83)
  BOTTOM w0.132: RU15.32 v1(104.48,102.83) ; U108.45 v1(96.05,124.24)
EMAC[1]_RXD2: length 39.8
  L14-SIGNAL w0.109: v1(105.28,103) 105.28,102.49 104.9,102.11 103.38,102.11 103,102.49 103,110.36 101.09,112.27 101.09,115.88 101.29,116.08 102.49,116.08 102.71,116.3 102.71,116.49 102.49,116.71 101.38,116.71 101.22,116.87 101.22,117.09 101.6,117.47 101.6,117.86 100.33,119.13 99.67,119.13 99.51,119.29 99.51,119.73 99.35,119.89 99.12,119.89 98.96,119.73 98.96,119.29 98.8,119.13 98.57,119.13 98.41,119.29 98.41,119.73 98.25,119.89 98.03,119.89 97.87,119.73 97.87,119.29 97.71,119.13 97.48,119.13 97.32,119.29 97.32,119.73 97.16,119.89 96.94,119.89 96.78,119.73 96.78,119.29 96.62,119.13 96.39,119.13 95.76,119.76 v1(95.76,120.9)
  BOTTOM w0.132: v1(105.28,103) 105.48,102.8 RU15.34 ; v1(95.76,120.9) 95.55,121.11 R433.2 R431.1 95.55,125.57 U108.46
EMAC[1]_RXD3: length 40.1
  L14-SIGNAL w0.109: v1(106.48,102.82) 106.48,101.91 106.3,101.73 103.25,101.73 102.49,102.49 102.49,102.71 102.33,102.87 102.05,102.87 101.89,103.03 101.89,103.26 102.05,103.42 102.33,103.42 102.49,103.58 102.49,103.81 102.33,103.97 102.05,103.97 101.89,104.13 101.89,104.35 102.05,104.51 102.33,104.51 102.49,104.67 102.49,110.24 100.69,112.03 100.69,118.13 100.33,118.49 99.95,118.49 99.19,117.73 97.79,117.73 97.03,118.49 96.39,118.49 95.16,119.73 95.16,122.16 95,122.32 93.89,122.32 93.73,122.48 93.73,122.71 93.89,122.87 95,122.87 95.16,123.03 95.16,123.77 95.05,123.88 v1(95.05,124.28)
  BOTTOM w0.132: U108.47 v1(95.05,124.28) ; RU15.36 v1(106.48,102.82)
EMAC[1]_TXC: length 39.1
  L14-SIGNAL w0.109: v1(98.93,123.7) 98.3,124.33 98.3,125.35 99.19,126.24 102.11,126.24 109.98,118.36 109.98,117.86 114.05,113.79 114.05,105.28 114.57,104.76 114.57,104.11 114.92,103.76 v1(115.57,103.76)
  BOTTOM w0.132: U108.40 98.55,124.51 98.93,124.12 v1(98.93,123.7) ; RU15.54 115.48,102.52 115.57,102.62 v1(115.57,103.76)
EMAC[1]_TXCTL: length 44.5
  L14-SIGNAL w0.109: v1(91.19,129.16) 91.95,129.16 94.36,126.75 102.33,126.75 111.51,117.56 111.55,117.56 111.78,117.33 111.78,117.29 114.43,114.65 114.43,105.54 115.06,104.9 v1(115.06,104.27)
  BOTTOM w0.132: v1(91.19,129.16) 91.28,129.07 U108.52 ; RU15.52 114.48,102.67 114.65,102.83 114.65,103.85 v1(115.06,104.27)
EMAC[1]_TXD0: length 43.9
  L14-SIGNAL w0.109: v1(109.98,103.76) 109.98,104.27 108.08,106.17 108.08,107.58 107.79,107.87 107.79,111.5 107.95,111.66 109.57,111.66 109.73,111.82 109.73,112.04 109.57,112.2 107.95,112.2 107.79,112.36 107.79,112.59 107.95,112.75 109.57,112.75 109.73,112.91 109.73,113.13 109.57,113.29 107.95,113.29 107.79,113.45 107.79,113.68 107.95,113.84 109.57,113.84 109.73,114 109.73,114.23 109.57,114.39 107.95,114.39 107.79,114.55 107.79,114.77 107.95,114.93 109.57,114.93 109.73,115.09 109.73,115.32 109.57,115.48 107.95,115.48 107.79,115.64 107.79,116.24 107.06,116.97 107.06,117.35 106.68,117.73 106.68,118.24 102.36,122.56 100.71,122.56 99.55,123.72 v1(99.55,124.23)
  BOTTOM w0.132: RU15.43 109.98,102.49 109.6,102.87 109.6,103.38 v1(109.98,103.76) ; U108.38 v1(99.55,124.23)
EMAC[1]_TXD1: length 46.9
  L14-SIGNAL w0.109: v1(110.98,102.85) 110.98,104.41 110.19,105.2 110.19,106.26 110.03,106.42 108.75,106.42 108.58,106.58 108.58,106.81 108.75,106.97 110.03,106.97 110.19,107.13 110.19,107.78 111.38,108.97 111.38,109.19 111.22,109.35 108.87,109.35 108.71,109.51 108.71,109.74 108.87,109.9 111.22,109.9 111.38,110.06 111.38,110.28 111.22,110.44 108.87,110.44 108.71,110.6 108.71,110.83 108.87,110.99 111.22,110.99 111.38,111.15 111.38,112.37 111.54,112.53 112.62,112.53 112.78,112.69 112.78,112.92 112.62,113.08 111.54,113.08 111.38,113.24 111.38,114.68 110.11,115.95 108.84,115.95 107.79,117 107.79,117 107.7,117.09 107.7,117.47 107.82,117.6 107.82,118.11 102.87,123.06 100.97,123.06 v1(100.58,123.44)
  BOTTOM w0.132: U108.37 100.05,123.98 v1(100.58,123.44) ; RU15.45 v1(110.98,102.85)
EMAC[1]_TXD2: length 44.6
  L14-SIGNAL w0.109: v1(100.55,124.24) 100.97,123.83 101.16,123.83 101.18,123.81 101.51,123.81 101.53,123.83 103.25,123.83 108.46,118.62 108.46,117.47 109.6,116.33 110.36,116.33 113.28,113.41 113.28,112.24 113.12,112.08 112.05,112.08 111.89,111.92 111.89,111.69 112.05,111.53 113.12,111.53 113.28,111.37 113.28,111.15 113.12,110.99 112.05,110.99 111.89,110.83 111.89,110.6 112.05,110.44 113.12,110.44 113.28,110.28 113.28,110.06 113.12,109.9 112.05,109.9 111.89,109.74 111.89,109.51 112.05,109.35 113.12,109.35 113.28,109.19 113.28,108.97 112.78,108.46 112.2,108.46 112.18,108.48 111.85,108.48 111.83,108.46 111.46,108.46 110.99,107.99 110.99,107.66 111,107.65 111,105.16 112.27,103.89 112.27,103 112.39,102.87 v1(112.39,99.57)
  BOTTOM w0.132: RU15.47 111.98,99.98 v1(112.39,99.57) ; U108.36 v1(100.55,124.24)
EMAC[1]_TXD3: length 44.5
  L14-SIGNAL w0.109: v1(114.17,104.39) 113.79,104.39 113.5,104.68 112.05,104.68 111.89,104.84 111.89,105.07 112.05,105.23 113.5,105.23 113.67,105.39 113.67,105.61 113.5,105.77 112.05,105.77 111.89,105.93 111.89,106.16 112.05,106.32 113.5,106.32 113.67,106.48 113.67,106.71 113.5,106.87 112.05,106.87 111.89,107.03 111.89,107.25 112.05,107.41 113.5,107.41 113.67,107.57 113.67,113.67 110.56,116.77 109.62,116.77 109.39,117 109.39,117.33 109.6,117.54 109.6,118.11 101.85,125.86 101.35,125.86 100.84,125.35 100.84,124.71 v1(101.35,124.21)
  BOTTOM w0.132: v1(101.35,124.21) 101.05,124.5 U108.35 ; RU15.50 113.48,103.7 v1(114.17,104.39)
EMU_RSTN: length 59.5
  TOP w0.132: v1(157.48,33.27) 157.38,33.38 J13.6 ; v1(201.8,34.8) 201.8,41.15 203.84,43.18 U48.2
  L14-SIGNAL w0.109: v1(201.8,34.8) 192.15,34.8 191.39,34.04 182.88,34.04 182.63,34.29 181.7,34.29 181.02,33.61 178.9,33.61 178.69,33.4 178.18,33.4 175.77,30.99 159.77,30.99 v1(157.48,33.27)
  BOTTOM w0.132: v1(157.48,33.27) R659.2
EN_TPS43351: length 9.4
  TOP w0.254: 170.08,108.48 170.08,108.74 170.47,109.13 U18.16 ; 170.08,108.48 U18.17 ; 170.08,108.48 170.08,106.91 171.45,105.54 v2(172.34,105.54) R150.2
  BOTTOM w0.508: R492.1 172.21,105.41 v2(172.34,105.54)
ENET_INT_P0: length 17.9
  L3-SIGNAL w0.109: v1(84.33,153.54) 83.54,152.76 v1(83.54,139.7)
  BOTTOM w0.132: R348.2 v1(84.33,153.54) 84.48,153.39 U101.60 ; U107.1 v1(83.54,139.7)
ENET_INT_P1: length 13
  L10-SIGNAL w0.089: v1(91.19,133.07) 88.67,133.07 85.85,135.89 85.85,137.03 v1(84.84,138.05)
  BOTTOM w0.132: U108.60 v1(91.19,133.07) 89.94,133.07 R403.2 ; U107.2 v1(84.84,138.05)
ENET_PORZ: length 222.9
  L3-SIGNAL w0.109: v1(206.88,125.22) 206.88,124.33 207.05,124.16 207.05,78.02 206.12,77.09 206.12,63.25 203.58,60.71 203.58,56.9 203.2,56.52 203.2,53.21 201.93,51.94 201.93,44.45 v1(201.29,43.81) ; v1(84.34,141.75) 83.95,142.14 83.95,144.15 v1(84.33,144.53)
  L14-SIGNAL w0.109: v1(84.34,141.75) 86.38,141.75 86.74,142.11 91.44,142.11 93.09,140.46 111.76,140.46 115.57,136.65 119.51,136.65 120.27,135.89 120.65,135.89 121.41,136.65 139.45,136.65 140.08,136.02 144.53,136.02 145.84,137.33 163.15,137.33 164.21,136.27 182.75,136.27 183.77,135.25 198.75,135.25 202.95,131.06 202.95,129.16 v1(206.88,125.22)
  BOTTOM w0.132: v1(84.33,144.53) 84.31,144.54 U103.1 ; R616.2 v1(201.29,43.81) ; U106.1 v1(84.34,141.75)
EXP_ETH0_RSTN: length 197.1
  TOP w0.132: U30.13 v1(202.08,62.84)
  L3-SIGNAL w0.109: v1(202.18,132.72) 202.82,132.08 202.82,67.73 202.36,67.27 202.02,67.27 201.76,67.01 201.76,65.07 202.44,64.39 202.44,63.21 v1(202.08,62.84)
  L14-SIGNAL w0.109: v1(202.18,132.72) 199.14,135.76 184.28,135.76 183.26,136.78 164.47,136.78 163.58,137.67 145.67,137.67 144.27,136.27 140.46,136.27 139.67,137.06 122.78,137.06 121.92,137.92 115.57,137.92 112.52,140.97 93.34,140.97 91.69,142.62 88.01,142.62 86.74,143.89 v1(84.71,143.89)
  BOTTOM w0.132: U103.2 v1(84.71,143.89)
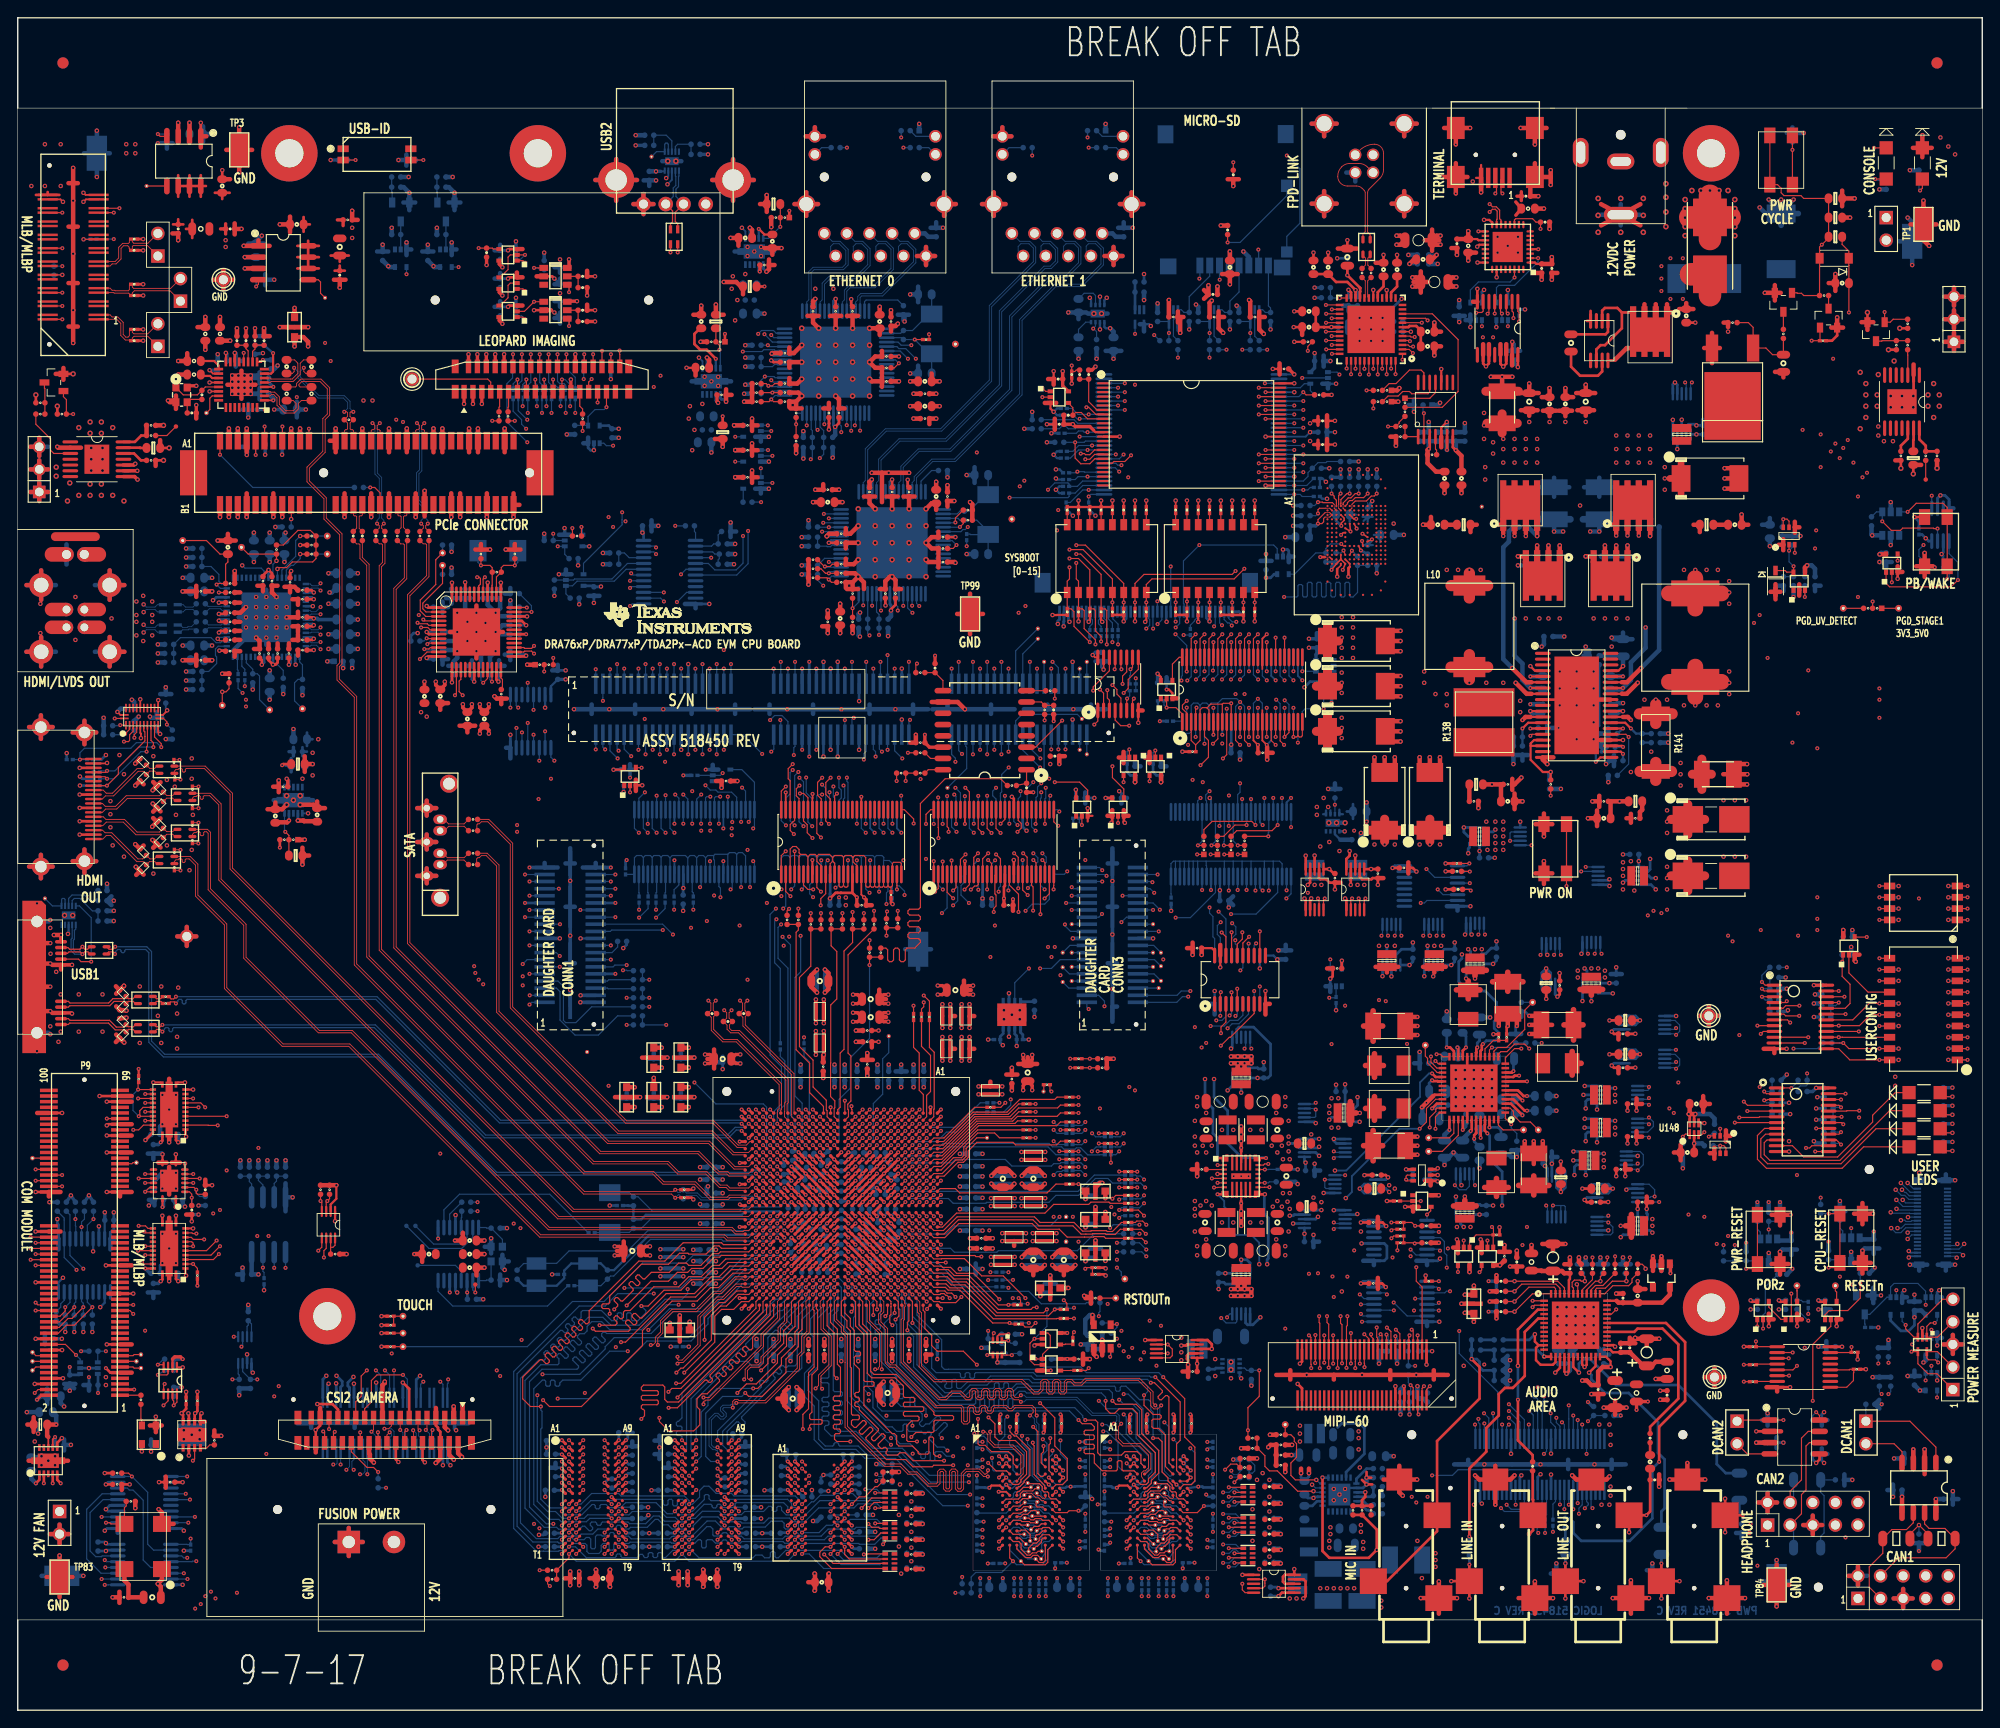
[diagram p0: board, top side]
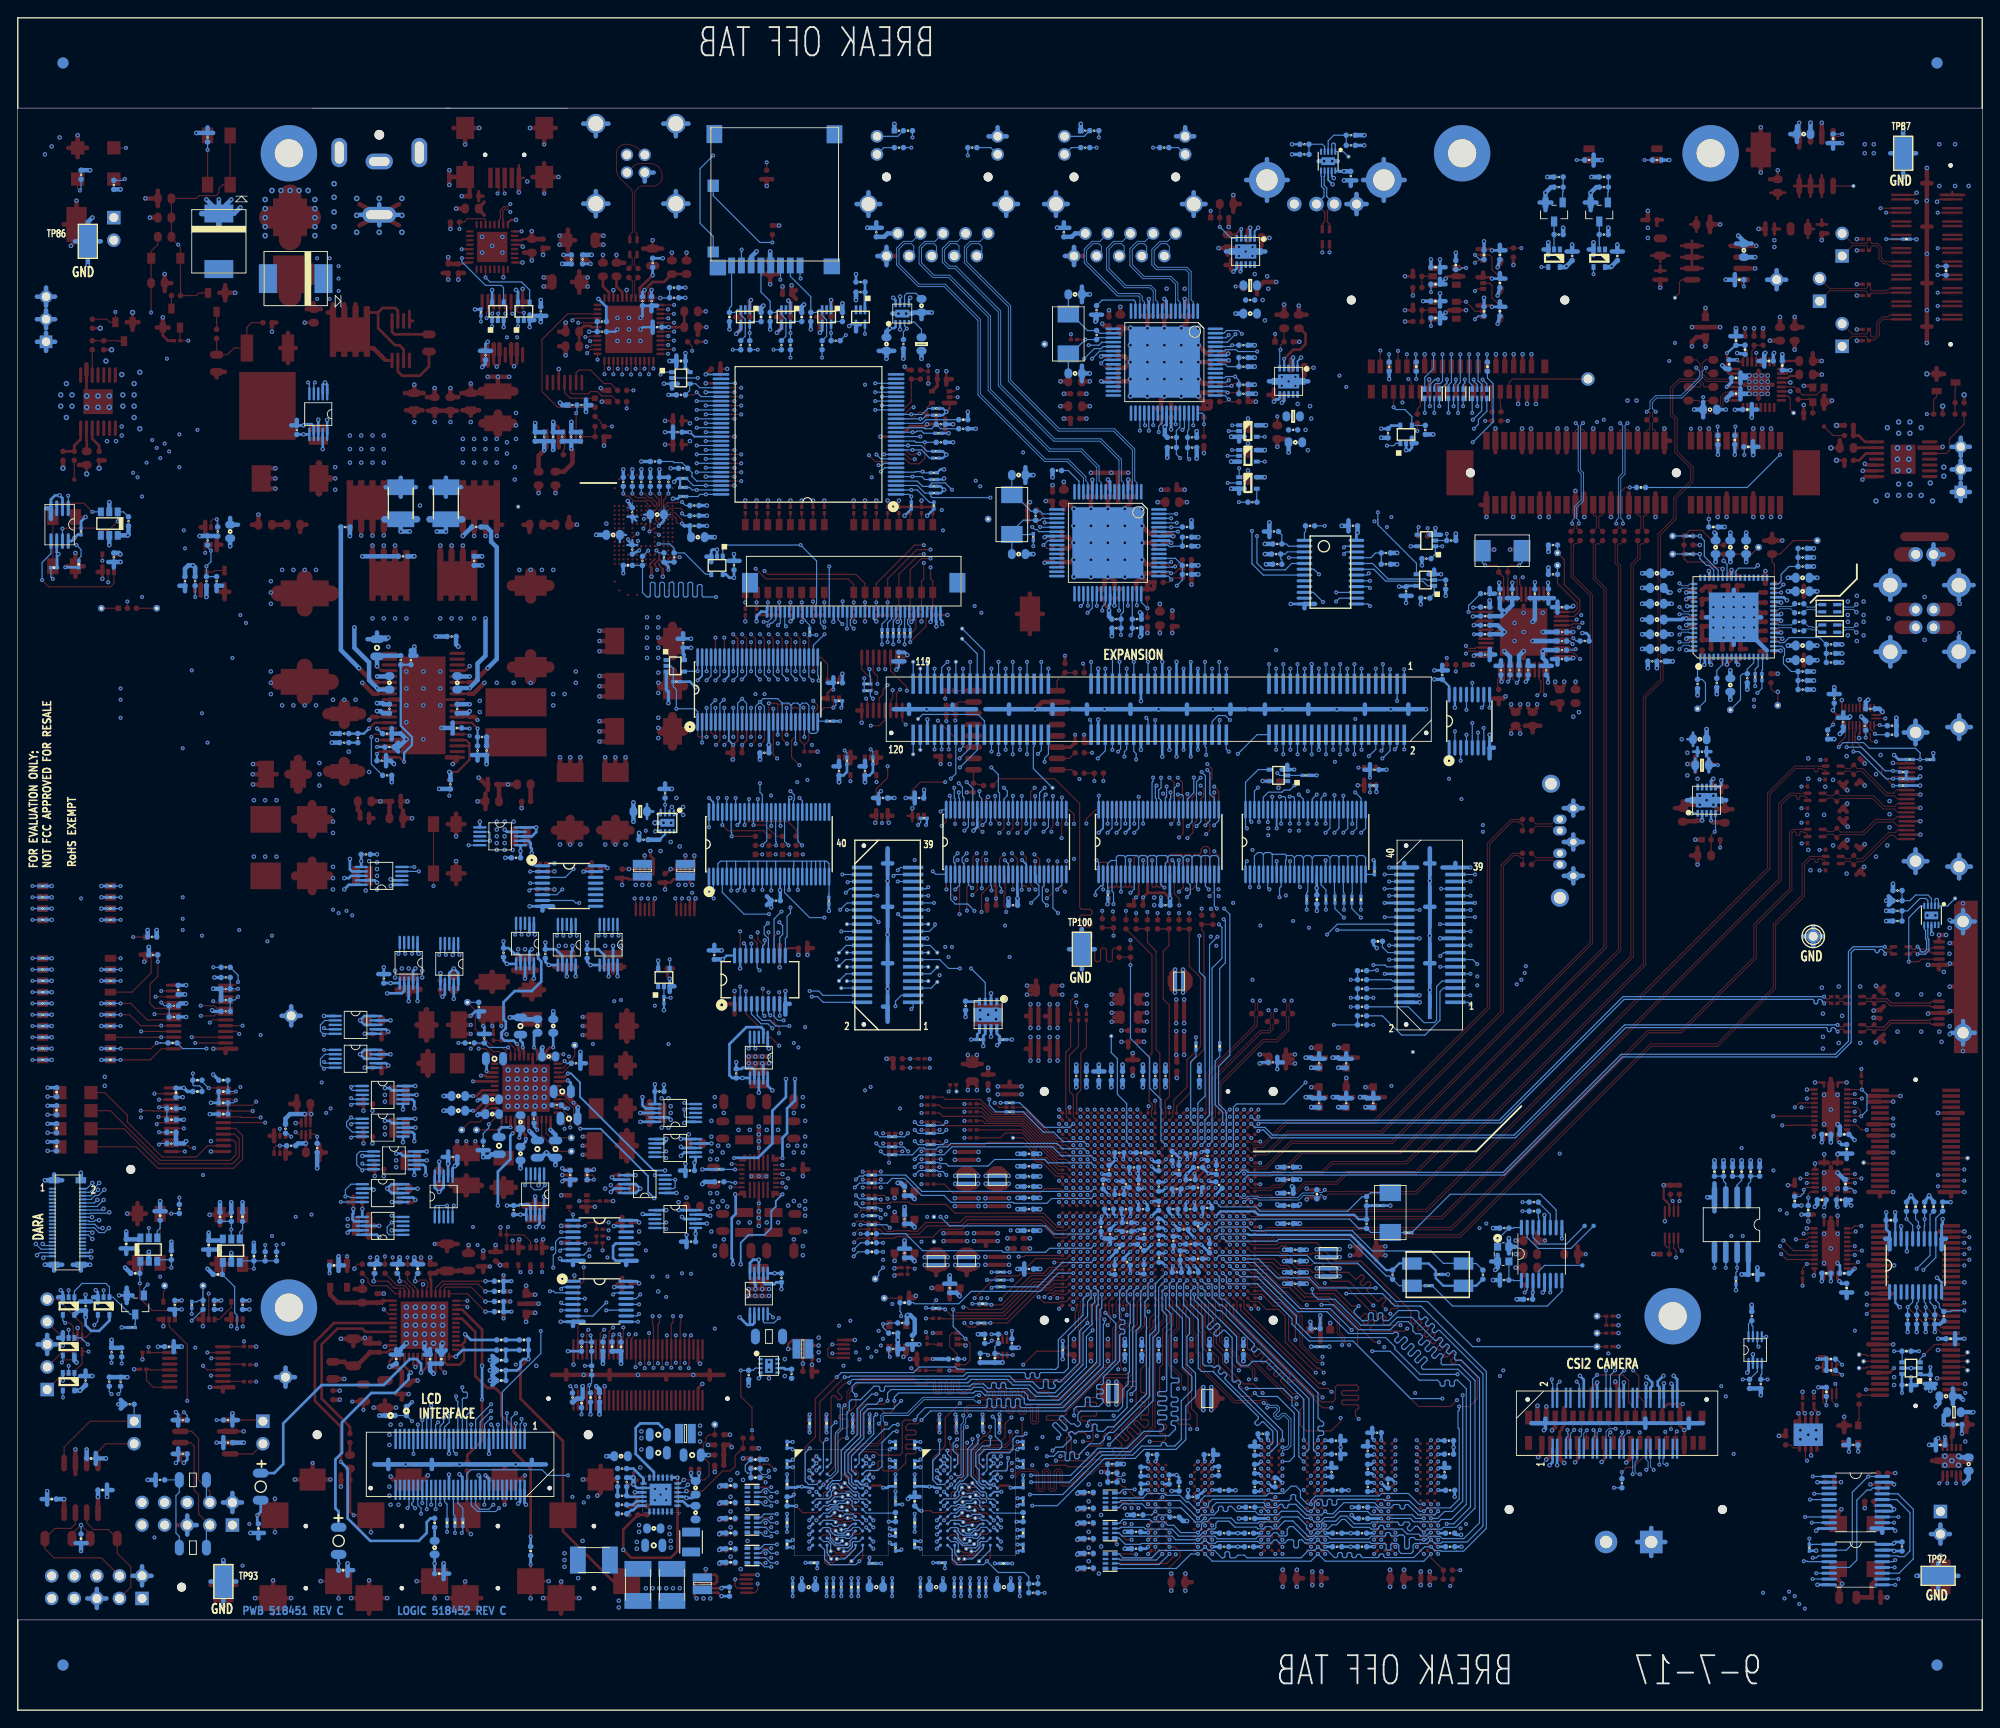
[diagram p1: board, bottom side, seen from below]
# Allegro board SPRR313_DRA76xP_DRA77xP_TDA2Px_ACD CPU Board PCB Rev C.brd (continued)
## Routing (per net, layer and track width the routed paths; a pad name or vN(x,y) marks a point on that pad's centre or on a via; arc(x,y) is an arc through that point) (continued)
EXP_ETH1_RSTN: length 195.5
  TOP w0.132: U30.14 201.71,63.49 201.46,63.25 v1(201.04,63.25)
  L3-SIGNAL w0.109: v1(202.06,130.68) 202.06,109.35 201.8,109.09 201.8,82.68 202.48,82 202.48,71.16 201.44,70.12 201.44,65.66 201.04,65.26 v1(201.04,63.25)
  L14-SIGNAL w0.109: v1(202.06,130.68) 202.06,131.19 200.15,133.1 193.17,133.1 191.9,134.37 163.7,134.37 161.61,136.46 152.62,136.46 152.55,136.53 152.02,136.53 151.34,135.85 146.9,135.85 146.39,135.34 144.74,135.34 144.4,135 143,135 142.6,135.4 116.8,135.4 116.79,135.38 114.17,135.38 109.47,140.08 87,140.08 85.98,141.1 v1(84.84,141.1)
  BOTTOM w0.132: U106.2 v1(84.84,141.1)
EXVIN2_S0: length 91.4
  TOP w0.132: U145.2 v1(124.97,108.08)
  L10-SIGNAL w0.089: v1(72.64,124.71) 73.03,125.09 103.63,125.09 105.28,123.44 v1(112.52,123.44)
  L14-SIGNAL w0.109: v1(112.52,123.44) 114.55,123.44 115.19,124.08 121.41,124.08 126.62,118.87 126.62,109.73 v1(124.97,108.08) 124.97,106.3 122.94,104.27 122.94,100.97 117.98,96.01 v1(117.98,94.36)
  BOTTOM w0.132: U110.14 72.27,125.09 v1(72.64,124.71) ; v1(117.98,94.36) 117.65,94.03 RU15.1 ; R730.2 124.71,107.82 v1(124.97,108.08)
EXVIN2_S0N: length 10.1
  TOP w0.132: U145.4 v1(124.32,104.39)
  L3-SIGNAL w0.109: v1(124.32,104.39) 121.28,104.39 117.98,101.09 v1(117.09,101.09)
  BOTTOM w0.132: RU15.56 116.89,101.3 v1(117.09,101.09)
EXVIN2_S2: length 72.9
  TOP w0.132: U144.2 v1(127.89,107.95)
  L10-SIGNAL w0.089: v1(113.28,124.21) 111.75,125.74 v1(72.63,125.74)
  L14-SIGNAL w0.109: v1(127.89,107.95) 127.89,109.73 127.25,110.36 127.25,118.87 121.54,124.59 113.67,124.59 v1(113.28,124.21)
  BOTTOM w0.132: R729.2 127.64,107.7 v1(127.89,107.95) ; U110.15 v1(72.63,125.74)
EXVIN2_S2N: length 14.6
  TOP w0.132: U144.4 v1(127.24,104.5)
  L3-SIGNAL w0.109: v1(127.24,104.5) 126.71,105.03 121.28,105.03 119.13,102.87 v1(116.08,102.87)
  BOTTOM w0.132: RU15.55 115.98,102.77 v1(116.08,102.87)
FLASH_BYTE: length 8.1
  BOTTOM w0.132: R377.2 147.19,140.46 147.07,140.34 146.18,140.34 R378.1 145.05,139.21 145.05,138.79 144.53,138.26 U104.53
FLASH_WP: length 7.5
  BOTTOM w0.132: R364.2 117.09,144.15 R363.1 118.11,144.15 118.87,144.15 118.99,144.26 U104.16
FPD_DOUT+: length 1.9
  TOP w0.099: C19.2 151.51,162.56 151.51,163.35 151.41,163.45 151.39,163.45 151.23,163.6 FL2.1
FPD_DOUT-: length 1.8
  TOP w0.099: FL2.4 152.04,163.6 151.78,163.33 151.78,162.55 C20.2
FTDI_ISO_ENN: length 178.2
  L4-GND2 w0.102: v1(214.5,45.59) 214.5,87 212.22,89.28 212.22,132.84 211.58,133.48 211.58,138.3 205.23,144.65 205.23,150.88 v1(204.09,152.02)
  L10-SIGNAL w0.089: v1(214.49,37.1) 213.84,37.75 213.84,40.29 v1(212.98,41.15) 212.98,42.8 214.5,44.32 v1(214.5,45.59) ; v1(167.53,155.68) 168.55,155.68 172.21,152.02 v1(204.09,152.02)
  L14-SIGNAL w0.109: v1(164.61,155.68) 165.01,156.08 167.12,156.08 v1(167.53,155.68)
  BOTTOM w0.132: U133.1 v1(214.49,37.1) ; v1(212.98,41.15) 213.72,41.88 U131.1 ; U142.1 v1(167.53,155.68) ; R625.2 207.68,43.43 207.65,43.47 Q13.D 208.21,44.53 210.14,46.46 U130.1 210.55,47.61 210.95,48.01 213.61,48.01 214.49,47.13 U129.1 214.49,45.61 v1(214.5,45.59) ; U143.1 v1(164.61,155.68)
FTDI_UARTIN: length 8.9
  TOP w0.132: U3.2 v1(170.92,163.34)
  BOTTOM w0.132: U142.4 166.24,158.36 166.24,160.02 166.5,160.27 168.28,160.27 170.92,162.92 v1(170.92,163.34)
FTDI_UARTOUT: length 7.9
  TOP w0.132: U3.30 168.26,161.17 v1(168.28,161.16)
  BOTTOM w0.132: U143.4 163.31,159.75 164.21,160.66 167.77,160.66 v1(168.28,161.16)
GA1: length 21.5
  TOP w0.254: 170.18,115.63 U18.6
  TOP w0.508: v2(168.02,117.22) 169.61,115.63 170.18,115.63
  BOTTOM w0.508: R402.2 168.15,133.1 167.64,132.59 167.64,131.44 167,130.81 167,118.24 v2(168.02,117.22)
GA2: length 17.9
  TOP w0.254: 170.18,114.33 U18.8
  TOP w0.508: v2(168.4,115.57) 169.64,114.33 170.18,114.33
  L5-SIGNAL w0.508: v2(168.66,128.78) 168.91,128.4 168.91,116.08 v2(168.4,115.57)
  BOTTOM w0.508: v2(168.66,128.78) R417.2
GB1: length 20.8
  TOP w0.254: 180.34,115.63 U18.33
  TOP w0.508: 180.34,115.63 180.91,115.63 v2(182.5,117.22)
  BOTTOM w0.508: R401.2 184.53,119.25 v2(182.5,117.22)
GB2: length 22.5
  TOP w0.254: 180.34,114.33 U18.31
  TOP w0.508: v2(182.12,115.57) 180.88,114.33 180.34,114.33
  L5-SIGNAL w0.508: v2(182.12,115.57) 181.36,116.33 181.36,121.79 182.12,122.56 v2(182.12,129.79)
  BOTTOM w0.508: v2(182.12,129.79) R414.2
GP5[22]: length 26.6
  L7-SIGNAL w0.089: v1(60.83,92.41) 59.61,92.41 59.18,92.84 59.18,97.16 62.99,100.97 71.12,100.97 71.82,100.26 v1(71.82,98.7)
  BOTTOM w0.132: EXP_P1.33 v1(60.83,92.41) ; v1(71.82,98.7) 71.32,99.2 RU17.33
GP5[25]: length 27
  L7-SIGNAL w0.089: v1(74.82,99.72) 72.69,101.85 62.74,101.85 58.04,97.16 58.04,93.73 v1(57.53,93.22)
  BOTTOM w0.132: RU17.40 v1(74.82,99.72) ; EXP_P1.35 v1(57.53,93.22)
GP5[29]: length 19.9
  L7-SIGNAL w0.089: v1(76.82,99.72) 74.26,97.16 67.94,97.16 66.17,95.38 66.17,93.05 66.81,92.41 v1(67.18,92.41)
  BOTTOM w0.132: v1(67.18,92.41) EXP_P1.34 ; RU17.44 v1(76.82,99.72)
GP5[30]: length 19.1
  L7-SIGNAL w0.089: v1(77.82,99.72) 77.48,99.37 77.48,97.92 76.33,96.77 68.42,96.77 67.44,95.79 67.44,94.87 66.55,93.98 66.55,93.72 66.67,93.59 v1(66.67,93.22)
  BOTTOM w0.132: RU17.46 v1(77.82,99.72) ; v1(66.67,93.22) EXP_P1.36
GP5[31]: length 18.9
  L7-SIGNAL w0.089: v1(78.82,99.72) 78.82,97.74 75.69,94.61 67.79,94.61 v1(67.18,94.01)
  BOTTOM w0.132: RU17.48 v1(78.82,99.72) ; v1(67.18,94.01) EXP_P1.38
GPIO1_24: length 29
  TOP w0.132: U42.AB7 v1(86.18,62.76)
  L5-SIGNAL w0.089: TP97.1 65.41,72.64 65.41,69.85 72.08,63.18 85.77,63.18 v1(86.18,62.76)
GPIO_SPARE_EXP1_P15: length 139.8
  TOP w0.132: U30.18 205.05,66.1 v1(205.23,65.91) ; SW10.5 v1(209.3,92.71)
  L3-SIGNAL w0.109: v1(209.3,92.71) v1(209.3,111.63)
  L7-SIGNAL w0.089: v1(209.3,111.63) 182.88,111.63 182.63,111.89 179.71,111.89 177.55,114.05 169.67,114.05 168.78,114.94 157.61,114.94 156.72,115.82 154.81,115.82 154.43,116.2 148.08,116.2 146.43,117.86 143.89,117.86 143.38,118.36 130.18,118.36 v1(126.87,121.67)
  L10-SIGNAL w0.089: v1(209.3,92.71) 208.53,91.95 208.53,85.34 207.52,84.33 207.52,75.95 207.26,75.69 207.26,69.22 205.99,67.94 205.99,66.67 v1(205.23,65.91)
  BOTTOM w0.132: R745.2 v1(209.3,92.71) ; v1(126.87,121.67) 127.25,122.05 127.25,122.68 127.12,122.82 J17.21
GPIO_SPARE_EXP2_P2: length 127.4
  TOP w0.132: v1(200.28,78.11) 198.75,78.11 198.56,78.3 U21.6 ; SW10.8 v1(209.3,88.9)
  L3-SIGNAL w0.109: v1(200.28,78.11) 199.9,78.49 199.9,80.14 200.15,80.39 v1(200.15,87.12) v1(200.15,112.14)
  L7-SIGNAL w0.089: v1(200.15,87.12) 203.84,87.12 205.61,88.9 v1(209.3,88.9) ; v1(127.64,121.67) 127.64,121.66 130.56,118.75 143.64,118.75 144.15,118.24 147.45,118.24 148.21,117.47 165.99,117.47 167.13,116.33 168.66,116.33 169.62,115.37 178.51,115.37 179.96,113.92 181.61,113.92 183.39,112.14 v1(200.15,112.14)
  BOTTOM w0.132: v1(127.64,121.67) 127.62,121.69 J17.22 ; R748.2 v1(209.3,88.9)
GPIO_SPARE_EXP2_P6: length 139.6
  TOP w0.132: U21.10 v1(201.29,75.7) ; SW10.7 v1(209.3,90.17)
  L3-SIGNAL w0.109: v1(209.3,90.17) 208.41,91.06 208.41,114.05 v1(209.3,114.94)
  L7-SIGNAL w0.089: v1(128.12,124.74) 128.12,123.72 128.65,123.19 128.65,121.67 130.81,119.51 144.15,119.51 144.65,119 154.56,119 154.94,118.62 167.77,118.62 169.42,116.97 172.09,116.97 172.85,116.2 179.58,116.2 180.09,115.7 180.97,115.7 181.74,114.94 v1(209.3,114.94) ; v1(209.3,90.17) 205.99,90.17 203.58,87.76 v1(202.31,87.76)
  L10-SIGNAL w0.089: v1(202.31,87.76) 202.31,83.69 201.29,82.68 v1(201.29,75.7)
  BOTTOM w0.132: R747.2 v1(209.3,90.17) ; J17.23 v1(128.12,124.74)
GPIO_SPARE_EXP2_P7: length 138.7
  TOP w0.132: SW10.6 v1(209.3,91.44) ; U21.11 v1(200.91,75.05)
  L3-SIGNAL w0.109: v1(209.3,113.67) 208.79,113.16 208.79,91.95 v1(209.3,91.44)
  L7-SIGNAL w0.089: v1(128.14,122.17) 128.14,121.67 130.68,119.13 143.89,119.13 144.4,118.62 147.7,118.62 148.46,117.86 166.24,117.86 167.39,116.71 168.78,116.71 169.8,115.7 178.82,115.7 180.09,114.43 189.05,114.43 189.81,113.67 v1(209.3,113.67) ; v1(202.31,91.44) v1(209.3,91.44)
  L10-SIGNAL w0.089: v1(202.31,91.44) 200.91,90.04 200.91,76.33 200.65,76.07 200.65,75.31 v1(200.91,75.05)
  BOTTOM w0.132: J17.24 128.62,122.65 v1(128.14,122.17) ; R746.2 v1(209.3,91.44)
GPMC_A1: length 97.8
  L3-SIGNAL w0.109: v1(125.6,149.1) 124.86,149.1 124.62,148.86 124.16,148.86 123.86,149.16 119.18,149.16 118.49,148.46 117.35,148.46 114.17,145.29 113.67,145.29 108.33,139.95 108.33,130.18 98.04,119.89 94.74,119.89 92.08,117.22 92.08,116.59 85.34,109.86 85.34,103 85.98,102.36 88.27,102.36 88.77,102.87 88.77,103.12 89.37,103.72 90.64,103.72 91.31,104.39 92.45,104.39 v1(92.83,104.01)
  L10-SIGNAL w0.089: v1(140.21,149.26) 139.93,148.98 139.84,148.98 139.68,149.14 139.36,149.14 139.32,149.1 v1(125.6,149.1)
  BOTTOM w0.132: RU16.43 92.83,102.48 92.96,102.62 92.96,103.88 v1(92.83,104.01) ; U104.31 v1(140.21,149.26)
GPMC_A2: length 83.9
  L3-SIGNAL w0.109: v1(91.69,103.9) 91.2,103.9 90.78,103.48 90.15,103.48 89.92,103.25 89.92,102.87 88.77,101.73 85.85,101.73 84.96,102.62 84.96,107.51 85.11,107.66 85.11,107.99 84.96,108.13 84.96,109.98 90.68,115.7 90.68,117.2 93.75,120.27 98.04,120.27 107.86,130.09 107.86,140.63 114.05,146.81 115.19,146.81 118.11,149.73 123.99,149.73 v1(124.46,149.26)
  BOTTOM w0.132: v1(91.69,103.9) 91.69,102.74 91.83,102.6 RU16.41 ; U104.26 v1(124.46,149.26)
GPMC_A3: length 76.7
  L3-SIGNAL w0.109: v1(90.42,104.11) 89.28,104.11 88.33,103.17 88.33,102.96 88.1,102.73 86.12,102.73 85.72,103.12 85.72,109.73 92.46,116.46 92.46,117.2 94.76,119.51 98.04,119.51 108.84,130.3 108.84,139.06 113.79,144.02 113.79,144.4 117.47,148.08 118.62,148.08 119.29,148.76 v1(123.7,148.76)
  BOTTOM w0.132: RU16.39 90.83,103.7 v1(90.42,104.11) ; U104.25 v1(123.7,148.76)
GPMC_A4: length 73.3
  L3-SIGNAL w0.109: v1(124.46,148.26) 119.43,148.26 116.46,145.29 115.7,145.29 109.35,138.94 109.35,130.43 98,119.09 95.51,119.09 86.02,109.6 86.02,105.12 86.71,104.43 88.15,104.43 v1(88.64,104.91)
  BOTTOM w0.132: U104.24 v1(124.46,148.26) ; v1(88.64,104.91) 88.64,103.19 89.33,102.49 RU16.36
GPMC_A5: length 69.3
  L3-SIGNAL w0.109: v1(123.7,147.76) 119.44,147.76 109.86,138.18 109.86,130.43 98.18,118.76 98.18,118.52 97.95,118.29 97.62,118.29 97.55,118.36 95.25,118.36 86.25,109.37 86.25,105.39 86.75,104.89 v1(87.88,104.89)
  BOTTOM w0.132: U104.23 v1(123.7,147.76) ; RU16.34 88.33,104.44 v1(87.88,104.89)
GPMC_A6: length 70.1
  L3-SIGNAL w0.109: v1(124.46,147.26) 119.94,147.26 116.63,143.95 116.63,143.46 116.38,143.21 115.66,143.21 110.24,137.79 110.24,130.3 98.55,118.62 98.55,118.49 97.59,117.53 96.59,117.53 96.52,117.6 95.89,117.6 95.81,117.53 95.3,117.53 86.49,108.71 86.49,105.66 86.9,105.25 87.47,105.25 v1(87.76,105.54)
  BOTTOM w0.132: RU16.32 87.34,105.12 v1(87.76,105.54) ; U104.22 v1(124.46,147.26)
GPMC_A7: length 66.5
  L3-SIGNAL w0.109: v1(123.7,146.76) 121.49,146.76 120.89,146.16 119.36,146.16 117.6,144.4 117.6,143.93 115.66,141.99 115.32,141.99 110.62,137.29 110.62,130.11 97.27,116.77 95.05,116.77 86.72,108.44 86.72,106.16 v1(87.12,105.76)
  BOTTOM w0.132: U104.21 v1(123.7,146.76) ; v1(87.12,105.76) 86.83,105.47 86.83,103.09 86.33,102.59 RU16.30
GPMC_A8: length 67
  TOP w0.132: v1(87.12,106.42) 86.61,105.91 86.61,104.77 86.83,104.55 RU7.54
  L3-SIGNAL w0.109: v1(124.46,146.26) 122.38,146.26 120.35,144.23 118.32,144.23 111,136.91 111,129.92 98.64,117.56 98.42,117.56 97.06,116.2 95,116.2 88.9,110.11 88.9,107.82 87.5,106.42 v1(87.12,106.42)
  BOTTOM w0.132: U104.20 v1(124.46,146.26)
GPMC_A9: length 60.9
  TOP w0.132: v1(87.88,104.01) 87.52,103.65 87.52,102.85 87.83,102.54 RU7.52
  L3-SIGNAL w0.109: v1(87.88,104.01) 88.39,104.01 89.38,105 89.38,110.08 95.09,115.79 98.9,115.79 100.58,117.48 100.58,119 113.79,132.21 113.79,135.13 114.55,135.89 118.07,135.89 v1(123.44,141.26)
  BOTTOM w0.132: U104.10 v1(123.44,141.26)
GPMC_A10: length 63
  TOP w0.132: RU7.50 88.83,102.64 88.35,103.12 v1(87.94,103.12)
  L3-SIGNAL w0.109: v1(87.94,103.12) 89.79,104.98 89.79,107.31 90.55,108.08 90.55,109.6 93.09,112.14 94.49,112.14 97.79,115.44 99.44,115.44 101.49,117.49 101.49,117.89 101.47,117.91 101.47,118.87 114.05,131.44 114.05,134.75 114.94,135.64 120.27,135.64 122.68,138.05 122.68,139.61 v1(124.32,141.24)
  BOTTOM w0.132: v1(124.32,141.24) 123.84,140.76 U104.9
GPMC_A11: length 59.9
  TOP w0.132: RU7.47 90.33,102.5 89.92,102.92 89.92,104.37 v1(90.43,104.89)
  L3-SIGNAL w0.109: v1(124.08,140.05) 123.61,140.05 123.06,139.5 123.06,137.03 122.43,136.4 122.43,135.89 121.94,135.4 115.84,135.4 114.3,133.86 114.3,131.19 101.85,118.75 101.85,117.22 99.69,115.06 98.04,115.06 92.46,109.47 92.46,108.33 91.57,107.44 91.57,106.93 90.43,105.8 v1(90.43,104.89)
  BOTTOM w0.132: v1(124.08,140.05) 123.67,140.05 123.46,140.26 U104.8
GPMC_A12: length 57.5
  TOP w0.132: RU7.45 91.33,102.5 90.84,103 90.84,104.36 v1(91.38,104.9)
  L3-SIGNAL w0.109: v1(123.83,139.32) 123.83,135.64 121.67,133.48 116.84,133.48 116.08,132.72 116.08,132.08 103.89,119.89 103.89,118.75 99.82,114.68 98.3,114.68 92.84,109.22 92.84,106.35 v1(91.38,104.9)
  BOTTOM w0.132: U104.7 123.38,139.76 v1(123.83,139.32)
GPMC_A19: length 37
  TOP w0.132: RU5.54 131.92,120.53 v1(132.42,121.03)
  L12-SIGNAL w0.089: v1(132.42,121.03) 131.95,121.03 130.81,122.17 130.81,126.75 122.26,135.3 122.26,137.33 120.9,138.68 120.9,140.46 119.88,141.48 119.88,143.6 119.38,144.1 v1(119.38,145.26)
  BOTTOM w0.132: U104.18 v1(119.38,145.26) 119.1,145.26 118.69,145.67 R360.2
GPMC_A20: length 33.5
  TOP w0.132: RU5.52 132.92,120.53 v1(133.42,121.03)
  L12-SIGNAL w0.089: v1(120.27,141.76) 121.41,140.62 121.41,139.06 123.76,136.72 123.76,135.19 131.95,127 131.95,122.5 v1(133.42,121.03)
  BOTTOM w0.132: R376.2 118.34,140.84 119.25,141.76 v1(120.27,141.76) U104.11
GPMC_A21: length 34.1
  TOP w0.132: v1(134.42,121.03) 133.92,120.53 RU5.50
  L12-SIGNAL w0.089: v1(134.42,121.03) 133.22,122.23 133.22,127.25 124.97,135.51 124.97,136.4 121.92,139.45 121.92,141.12 v1(120.78,142.26)
  BOTTOM w0.132: R375.2 118.62,141.6 119.27,142.26 v1(120.78,142.26) U104.12
GPMC_A22: length 36.6
  TOP w0.132: v1(135.42,120.14) RU5.47
  L12-SIGNAL w0.089: v1(120.27,143.76) 122.43,141.6 122.43,140.08 126.24,136.27 126.24,135.51 135.89,125.86 135.89,120.61 v1(135.42,120.14)
  BOTTOM w0.132: U104.15 v1(120.27,143.76) 119.89,143.76 119.76,143.89 119.25,143.89 119,143.64 R366.2
GPMC_A23: length 34.3
  TOP w0.132: v1(136.42,120.14) RU5.45
  L12-SIGNAL w0.089: v1(136.42,120.14) 135.91,119.63 130.81,119.63 129.57,120.87 129.57,126.71 121.22,135.06 121.22,136.44 v1(120.4,137.26)
  BOTTOM w0.132: U104.2 v1(120.4,137.26) 119.74,137.26 118.33,135.85 R397.2
GPMC_A24: length 32.9
  TOP w0.132: v1(137.42,120.14) RU5.43
  L12-SIGNAL w0.089: v1(120.4,136.53) 120.4,133.86 128.65,125.6 128.65,121.16 130.56,119.25 136.53,119.25 v1(137.42,120.14)
  BOTTOM w0.132: R396.2 v1(120.4,136.53) 120.63,136.76 U104.1
GPMC_A25: length 25
  TOP w0.132: v1(138.42,120.14) RU5.41
  L10-SIGNAL w0.089: v1(138.42,120.14) 138.43,120.14 138.94,120.65 138.94,121.55 138.56,121.93 138.56,123.66 138.3,123.92 138.3,131.55 v1(143.51,136.76)
  BOTTOM w0.132: U104.56 v1(143.51,136.76) 144.16,136.76 144.4,136.53 R393.2
GPMC_A26: length 26.5
  TOP w0.132: v1(139.42,120.14) RU5.39
  L10-SIGNAL w0.089: v1(139.42,120.14) 139.83,120.55 139.83,123.06 138.56,124.33 138.56,131.32 143.38,136.14 144.15,136.14 144.53,136.53 v1(144.53,137.26)
  BOTTOM w0.132: R391.2 145.31,137.54 145.03,137.26 v1(144.53,137.26) U104.55
GPMC_D00: length 95.8
  TOP w0.132: v1(140.28,139.76) U12.29 ; v1(120.52,120.14) 118.75,121.92 118.75,123.57 118.43,123.89 R113.1 SW3.1 117.98,127 118.24,127.25 v1(118.24,128.55)
  L10-SIGNAL w0.089: v1(118.24,128.55) 119.92,128.55 124.97,133.6 127,133.6 133.15,139.76 v1(140.28,139.76) 140.91,139.76 142.37,138.3 143.89,138.3 144.4,138.81 144.91,138.81 145.8,139.7 145.8,140.69 146.94,141.83 146.94,144.85 v1(144.53,147.26)
  L12-SIGNAL w0.089: v1(120.52,120.14) 119.63,120.14 119.51,120.02 114.17,120.02 112.65,118.49 112.65,117.47 101.22,106.05 100.71,106.05 99.31,104.65 99.31,104.01 98.04,102.74 98.04,102.11 95.94,100.01 95.94,99.32 v1(95.33,98.7)
  BOTTOM w0.132: v1(144.53,147.26) U104.35 ; RU16.47 94.83,99.2 v1(95.33,98.7) ; R440.2 v1(120.52,120.14)
GPMC_D01: length 91.6
  TOP w0.132: v1(139.52,140.26) U12.30 ; v1(119,129.05) 119,127.25 119.25,127 SW3.2 R114.1 119.7,123.89 119.89,123.7 119.89,121.67 121.16,120.4 v1(121.16,119.89)
  L10-SIGNAL w0.089: v1(144.53,146.26) 144.95,146.26 146.56,144.65 146.56,142.06 145.24,140.74 145.24,140.23 144.7,139.7 144.15,139.7 143.64,139.19 142.75,139.19 141.68,140.26 v1(139.52,140.26) 133.11,140.26 126.84,133.99 124.71,133.99 119.78,129.05 v1(119,129.05)
  L12-SIGNAL w0.089: v1(121.16,119.89) 120.88,119.61 114.28,119.61 113.03,118.36 113.03,117.35 100.21,104.53 100.21,104.36 98.55,102.7 98.55,101.94 v1(96.33,99.72)
  BOTTOM w0.132: RU16.50 v1(96.33,99.72) ; v1(144.53,146.26) U104.37 ; R439.2 v1(121.16,119.89)
GPMC_D02: length 90.5
  TOP w0.132: v1(140.28,140.76) U12.31 ; v1(118.24,129.55) 119.24,129.55 120.52,128.27 SW3.3 R115.1 120.97,123.89 121.16,123.7 121.16,121.41 121.79,120.78 v1(121.79,120.22)
  L10-SIGNAL w0.089: v1(118.24,129.55) 118.62,129.55 118.64,129.54 119.63,129.54 124.46,134.37 126.75,134.37 133.14,140.76 v1(140.28,140.76) 142.33,140.76 142.75,140.34 143.85,140.34 144.27,140.76 144.65,140.76 146.18,142.28 146.18,144.53 145.44,145.26 v1(144.53,145.26)
  L12-SIGNAL w0.089: v1(121.79,120.22) 121.79,119.76 121.16,119.13 114.3,119.13 113.4,118.23 113.4,117.21 100.84,104.65 100.84,103.76 97.33,100.25 v1(97.33,99.72)
  BOTTOM w0.132: R438.2 v1(121.79,120.22) ; v1(144.53,145.26) U104.39 ; RU16.52 v1(97.33,99.72)
GPMC_D03: length 88.2
  TOP w0.132: v1(122.43,119.89) 122.43,123.7 122.24,123.89 R116.1 SW3.4 121.79,127.76 119.5,130.05 v1(119,130.05) ; v1(139.52,141.26) U12.32
  L10-SIGNAL w0.089: v1(119,130.05) 119.51,130.05 124.21,134.75 126.49,134.75 133,141.26 v1(139.52,141.26) 143.8,141.26 144.27,141.73 144.98,141.73 145.8,142.54 145.8,143.89 145.43,144.26 v1(144.53,144.26)
  L12-SIGNAL w0.089: v1(122.43,119.89) 122.43,119.51 121.2,118.28 120.68,118.28 120.59,118.36 115.19,118.36 103,106.17 103,105.41 98.33,100.74 v1(98.33,99.72)
  BOTTOM w0.132: R437.2 v1(122.43,119.89) ; RU16.54 v1(98.33,99.72) ; v1(144.53,144.26) U104.41
GPMC_D04: length 65.4
  TOP w0.132: v1(118.24,130.55) 119.77,130.55 123.06,127.25 SW3.5 v1(123.06,124.61) R117.1 ; v1(139.52,145.76) U12.41
  L3-SIGNAL w0.109: v1(123.06,120.14) v1(123.06,124.61)
  L10-SIGNAL w0.089: v1(123.06,120.14) 123.95,121.03 v1(130.16,121.03) ; v1(143.51,142.76) 131.58,142.76 125.09,136.27 125.09,135.89 124.65,135.45 123.63,135.45 119.76,131.57 118.75,131.57 118.24,131.06 v1(118.24,130.55)
  L14-SIGNAL w0.109: v1(139.52,145.76) 140.51,145.76 v1(143.51,142.76)
  BOTTOM w0.132: v1(130.16,121.03) 131.42,119.77 RU13.30 ; R436.2 v1(123.06,120.14) ; U104.44 v1(143.51,142.76)
GPMC_D05: length 70.1
  TOP w0.132: v1(140.28,146.26) U12.42 ; R118.1 v1(124.33,124.61) SW3.6 124.33,126.75 120.03,131.05 v1(119,131.05)
  L3-SIGNAL w0.109: v1(124.33,124.61) 124.33,123.44 123.7,122.81 v1(123.7,119.89)
  L5-SIGNAL w0.089: v1(124.33,124.61) 124.33,123.7 124.97,123.06 124.97,122.05 129.67,117.35 131.94,117.35 v1(132.42,116.87)
  L10-SIGNAL w0.089: v1(140.28,146.26) 141.02,146.26 143,144.27 143.76,144.27 144.02,144.02 144.02,142.27 v1(143.51,141.76) 142.34,141.76 141.86,142.24 131.7,142.24 126.11,136.65 126.11,135.89 125.35,135.13 123.95,135.13 119.88,131.05 v1(119,131.05)
  BOTTOM w0.132: R435.2 v1(123.7,119.89) ; U104.46 v1(143.51,141.76) ; RU13.32 v1(132.42,116.87)
GPMC_D06: length 56.7
  TOP w0.132: v1(136.91,128.14) 136.53,127.76 126.62,127.76 125.6,126.75 SW3.7 v1(125.6,124.61) R119.1 ; v1(139.52,146.76) U12.43
  L3-SIGNAL w0.109: v1(136.91,128.14) 136.91,129.41 142.11,134.62 142.11,140.08 142.79,140.76 v1(143.51,140.76)
  L5-SIGNAL w0.089: v1(125.6,124.61) 125.6,123.7 126.24,123.06 126.24,121.54 130.05,117.73 132.55,117.73 v1(133.42,116.87)
  L14-SIGNAL w0.109: v1(139.52,146.76) 138.94,146.17 138.94,145.36 143.51,140.79 v1(143.51,140.76)
  BOTTOM w0.132: U104.48 v1(143.51,140.76) ; RU13.34 v1(133.42,116.87)
GPMC_D07: length 56.2
  TOP w0.132: R120.1 v1(126.87,124.61) SW3.8 126.87,126.62 127.51,127.25 136.75,127.25 v1(137.9,128.4) ; v1(140.28,147.26) U12.44
  L3-SIGNAL w0.109: v1(143.51,139.76) 142.94,139.76 142.62,139.45 142.62,133.86 137.9,129.13 v1(137.9,128.4)
  L5-SIGNAL w0.089: v1(134.37,116.94) 133.2,118.11 131.95,118.11 128.65,121.41 128.65,122.83 v1(126.87,124.61)
  L14-SIGNAL w0.109: v1(140.28,147.26) 139.13,147.26 138.43,146.56 138.43,144.27 140.08,142.62 140.65,142.62 v1(143.51,139.76)
  BOTTOM w0.132: U104.50 v1(143.51,139.76) ; RU13.36 134.42,116.99 v1(134.37,116.94)
GPMC_D08: length 48.8
  TOP w0.132: SW4.1 v1(130.18,124.61) R121.1 ; v1(139.52,138.26) U12.26
  L3-SIGNAL w0.109: v1(143.51,146.76) 140.64,143.89 140.08,143.89 138.18,141.99 138.18,139.19 139.11,138.26 v1(139.52,138.26) 139.52,135.84 130.18,126.49 v1(130.18,124.61)
  L10-SIGNAL w0.089: v1(130.18,124.61) 130.81,123.98 130.81,122.3 131.95,121.16 131.95,120.06 135.03,116.98 135.03,116.3 v1(135.38,115.94)
  BOTTOM w0.132: RU13.39 135.92,116.48 v1(135.38,115.94) ; U104.36 v1(143.51,146.76)
GPMC_D09: length 47.8
  TOP w0.132: v1(140.28,138.76) U12.27 ; SW4.2 v1(131.44,124.71) R122.1
  L3-SIGNAL w0.109: v1(131.44,124.71) 131.44,127.13 140.28,135.97 140.28,137.14 139.85,137.58 139.85,137.94 140.28,138.38 v1(140.28,138.76) 139.32,138.76 138.56,139.52 138.56,141.73 139.57,142.75 140.5,142.75 v1(143.51,145.76)
  L10-SIGNAL w0.089: v1(131.44,124.71) 132.21,123.95 132.21,122.17 132.97,121.41 132.97,119.63 135.13,117.47 135.51,117.47 135.89,117.09 135.89,116.45 v1(136.4,115.94)
  BOTTOM w0.132: v1(136.4,115.94) 136.69,116.23 136.69,116.24 136.92,116.47 RU13.41 ; U104.38 v1(143.51,145.76)
GPMC_D10: length 47
  TOP w0.132: SW4.3 v1(132.72,124.61) R123.1 ; v1(139.52,139.26) U12.28
  L3-SIGNAL w0.109: v1(132.72,124.61) 132.72,127.76 140.72,135.77 140.72,139.06 140.52,139.26 v1(139.52,139.26) 138.94,139.84 138.94,141.48 139.83,142.37 141.12,142.37 v1(143.51,144.76)
  L10-SIGNAL w0.089: v1(132.72,124.61) 133.35,123.98 133.35,122.17 133.99,121.54 133.99,119.38 136.02,117.35 136.65,117.35 136.91,117.09 136.91,116.45 v1(137.41,115.94)
  BOTTOM w0.132: U104.40 v1(143.51,144.76) ; RU13.43 137.92,116.45 137.7,116.24 137.7,116.23 v1(137.41,115.94)
GPMC_D11: length 43.8
  TOP w0.132: v1(140.28,141.76) U12.33 ; R124.1 v1(133.99,124.61) SW4.4
  L3-SIGNAL w0.109: v1(133.99,124.61) 133.99,128.4 140.97,135.38 140.97,141.07 v1(140.28,141.76) 141.51,141.76 v1(143.51,143.76)
  L10-SIGNAL w0.089: v1(133.99,124.61) 134.49,124.1 134.49,123.57 135.81,122.25 135.81,119.58 137.29,118.11 138.43,118.11 139.03,117.51 139.03,116.36 v1(139.45,115.94)
  BOTTOM w0.132: RU13.45 138.92,116.48 139.16,116.24 139.16,116.23 v1(139.45,115.94) ; U104.42 v1(143.51,143.76)
GPMC_D12: length 48.8
  TOP w0.132: SW4.5 v1(135.25,124.61) R125.1 ; v1(140.28,145.26) U12.40
  L3-SIGNAL w0.109: v1(135.25,124.61) 135.25,129.03 141.35,135.13 141.35,140.84 142.77,142.26 v1(144.53,142.26)
  L10-SIGNAL w0.089: v1(135.25,124.61) 135.25,123.7 136.02,122.94 136.02,119.89 137.54,118.36 138.68,118.36 139.83,117.22 139.83,116.44 v1(140.42,115.85)
  L14-SIGNAL w0.109: v1(144.53,142.26) 142.73,142.26 140.28,144.7 v1(140.28,145.26)
  BOTTOM w0.132: RU13.47 139.92,116.35 v1(140.42,115.85) ; v1(144.53,142.26) U104.45
GPMC_D13: length 50.3
  TOP w0.132: SW4.6 v1(136.53,124.61) R126.1 ; v1(139.52,147.76) U12.45
  L3-SIGNAL w0.109: v1(136.53,124.61) SW4.6 136.27,125.98 136.27,129.41 141.73,134.87 141.73,140.34 142.66,141.26 v1(144.53,141.26)
  L10-SIGNAL w0.089: v1(141.42,116.87) 141.42,117.41 139.57,119.25 138.18,119.25 137.82,119.61 137.82,121.87 137.38,122.31 137.38,123.22 136.53,124.08 v1(136.53,124.61)
  L14-SIGNAL w0.109: v1(144.53,141.26) 145.03,141.77 145.03,142.34 144.4,142.97 144.4,143.51 143.64,144.27 143.26,144.27 142.11,145.41 142.11,146.43 140.79,147.76 v1(139.52,147.76)
  BOTTOM w0.132: v1(144.53,141.26) U104.47 ; RU13.50 v1(141.42,116.87)
GPMC_D14: length 52.2
  TOP w0.132: R127.1 v1(137.79,124.61) SW4.7 ; v1(140.28,148.26) U12.46
  L3-SIGNAL w0.109: v1(137.79,124.61) 137.79,125.86 137.41,126.24 137.41,129.29 142.37,134.24 142.37,139.7 142.93,140.26 v1(144.53,140.26)
  L10-SIGNAL w0.089: v1(142.42,116.87) 139.65,119.63 138.35,119.63 138.02,119.96 138.02,121.89 138.3,122.18 138.3,123.32 137.79,123.83 v1(137.79,124.61)
  L14-SIGNAL w0.109: v1(144.53,140.26) 145.08,140.26 145.36,140.54 145.36,141.35 146.46,142.44 146.46,146.28 145.03,147.7 142.62,147.7 142.07,148.26 v1(140.28,148.26)
  BOTTOM w0.132: RU13.52 v1(142.42,116.87) ; v1(144.53,140.26) U104.49
GPMC_D15: length 52.9
  TOP w0.132: SW4.8 v1(139.06,124.61) R128.1 ; v1(139.52,148.76) U12.47
  L3-SIGNAL w0.109: v1(139.06,124.61) 139.06,129.67 142.96,133.56 142.96,139.02 143.2,139.26 v1(144.53,139.26)
  L10-SIGNAL w0.089: v1(139.06,124.61) 140.84,122.83 140.84,119.44 v1(143.42,116.87)
  L14-SIGNAL w0.109: v1(139.52,148.76) 144.87,148.76 146.94,146.69 146.94,142.21 145.92,141.2 145.92,139.7 145.48,139.26 v1(144.53,139.26)
  BOTTOM w0.132: RU13.54 v1(143.42,116.87) ; v1(144.53,139.26) U104.51
GPMC_WPN: length 143.7
  TOP w0.132: v1(125.16,141.16) 124.46,140.46 123.24,140.46 123.04,140.26 U12.19 ; v1(209.3,83.31) SW6.12
  L3-SIGNAL w0.109: v1(206.88,136.53) 206.88,127.64 209.04,125.48 209.04,122.81 209.8,122.05 209.8,83.82 v1(209.3,83.31)
  L14-SIGNAL w0.109: v1(125.16,141.16) 137.73,141.16 139.06,139.83 139.65,139.83 140.16,139.32 143.91,139.32 144.41,138.81 163.32,138.81 164.59,137.54 183.51,137.54 184.53,136.53 v1(206.88,136.53)
  BOTTOM w0.132: R134.2 v1(209.3,83.31)
GPS_PPS_OUT: length 28.6
  TOP w0.132: P9.50 v1(1.45,50.67) ; v1(14.33,67.32) U39.19
  L14-SIGNAL w0.109: v1(1.45,50.67) 6.48,50.67 10.29,54.48 10.29,56.77 11.05,57.53 11.05,65.41 12.95,67.31 13.92,67.31 13.93,67.32 v1(14.33,67.32)
GPS_TIME_STAMP: length 15.8
  TOP w0.132: P9.48 v1(2.01,50.04) ; v1(14.33,52.19) U43.18
  L12-SIGNAL w0.089: v1(2.01,50.04) 2.67,50.04 4.72,52.1 13.11,52.1 13.46,52.45 14.07,52.45 v1(14.33,52.19)
H_AIC3106_MCLK: length 78.8
  TOP w0.132: R252.2 112.91,43.43 113.24,43.11 113.97,43.11 v1(114.43,43.56) ; v2(183.01,49.66) 183.01,49.78 182.63,50.16 R241.1
  L14-SIGNAL w0.109: v2(183.01,49.66) 183.01,47.37 180.09,44.45 179.32,44.45 177.67,46.1 172.34,46.1 169.29,43.05 163.45,43.05 162.05,44.45 152.27,44.45 152,44.18 150.38,44.18 149.73,44.83 134.11,44.83 133.86,44.58 121.92,44.58 121.62,44.87 120.56,44.87 119.25,43.56 v1(114.43,43.56)
H_CAM_SPI[1]_CS[0]N: length 117.5
  TOP w0.132: R245.1 112.74,46.14 v1(112.52,46.35)
  L10-SIGNAL w0.089: v1(112.52,46.35) 113.03,45.85 113.03,45.46 114.04,44.45 114.68,44.45 115.44,43.69 115.44,38.61 114.17,37.34 112.9,37.34 111,35.43 97.41,35.43 94.87,32.89 91.44,32.89 91.05,32.5 70.39,32.5 70.26,32.38 64.76,32.38 64.39,32 59.18,32 53.59,26.42 44.2,26.42 41.91,24.13 36.7,24.13 29.34,16.76 v1(20.07,16.76)
  BOTTOM w0.132: v1(20.07,16.76) 19.66,16.76 19.6,16.71 RU21.4
H_CAM_SPI[1]_MISO: length 139.6
  TOP w0.132: R216.1 125.98,56.26 v1(126.62,55.63)
  L10-SIGNAL w0.089: v1(126.62,55.63) 126.23,55.24 126.06,55.24 125.71,54.89 125.71,50.94 126.65,50.01 126.65,45.69 127.76,44.58 127.76,40.13 125.22,37.59 118.49,37.59 117.09,36.2 115.32,36.2 113.28,34.16 99.95,34.16 96.65,30.86 59.56,30.86 54.17,25.46 46.04,25.46 42.93,22.35 37.16,22.35 29.57,14.76 v1(19.08,14.76)
  BOTTOM w0.132: RU21.7 v1(19.08,14.76)
H_CAM_SPI[1]_MOSI: length 127.2
  TOP w0.132: R235.1 117.94,45.76 117.9,45.81 117.9,45.82 v1(117.6,46.12)
  L10-SIGNAL w0.089: v1(117.6,46.12) 117.6,45.73 117.47,45.6 117.47,38.48 115.95,36.96 113.03,36.96 111,34.92 99.69,34.92 98.42,33.66 97.41,33.66 96.27,32.52 91.57,32.52 91.19,32.13 70.49,32.13 70.46,32.11 70.46,32.11 69.97,31.62 59.31,31.62 53.78,26.1 44.77,26.1 42.16,23.5 36.83,23.5 29.67,16.34 10.12,16.34 v1(9.84,16.07)
  BOTTOM w0.132: v1(9.84,16.07) 9.85,16.06 RU21.12
H_CSI2_0_DX0: length 70.9
  TOP w0.099: U42.AD17 v1(84.58,53.96) ; v1(46.63,31.52) 46.5,31.4 J15.8
  L3-SIGNAL w0.089: v1(84.58,53.96) 84.25,54.29 83.99,54.29 83.94,54.35 82.82,54.35 82.29,53.82 65.56,53.82 50.2,38.46 50.2,38.09 50.62,37.67 50.62,37.49 50.49,37.35 50.31,37.35 49.89,37.77 49.52,37.77 49.17,37.43 49.17,35.53 48.69,35.05 48.51,35.05 47.11,36.45 46.73,36.45 46.47,36.18 46.47,35.81 47.87,34.41 47.87,34.22 47.65,34 47.65,33.71 47.52,33.58 43.83,33.58 43.56,33.32 43.56,32.94 43.83,32.68 47.52,32.68 47.65,32.55 47.65,30.7 47.2,30.25 46.4,30.25 46.1,30.55 46.1,31.16 46.19,31.25 46.36,31.25 v1(46.63,31.52)
  BOTTOM w0.099: v1(46.63,31.52) 46.63,31.13 46.56,31.06 46.56,30.87 46.79,30.63 P15.5
H_CSI2_0_DX1: length 70
  TOP w0.099: v1(45.17,31.49) 45.17,31.49 ; 45.17,31.49 45.16,31.49 ; 45.17,31.49 45,31.66 J15.11 ; U42.AF16 v1(82.98,54.76)
  L5-SIGNAL w0.086: v1(82.98,54.76) 82.73,54.76 82.56,54.59 82.56,54.41 82.41,54.27 81.7,54.27 81.31,53.87 69.3,53.87 69.3,53.87 65.05,53.87 60.78,49.61 60.78,49.02 60.2,48.44 59.56,48.44 56.68,45.55 56.68,45.12 57.07,44.73 57.07,44.55 56.94,44.42 56.77,44.42 56.37,44.81 55.94,44.81 55.63,44.51 55.63,44.08 56.03,43.68 56.03,43.51 55.9,43.38 55.72,43.38 55.33,43.77 54.9,43.77 54.59,43.47 54.59,43.03 54.99,42.64 54.99,42.46 54.86,42.33 54.68,42.33 54.29,42.73 53.85,42.73 53.55,42.42 53.55,41.99 53.94,41.6 53.94,41.42 53.81,41.29 53.64,41.29 53.24,41.68 52.81,41.68 52.32,41.2 52.32,37.02 52.63,36.71 53.8,36.71 53.92,36.59 53.92,36.41 53.8,36.28 52.63,36.28 52.32,35.98 52.32,35.54 52.63,35.24 53.8,35.24 53.92,35.11 53.92,34.93 53.8,34.81 52.63,34.81 52.32,34.5 52.32,33.4 49.33,30.4 45.03,30.4 44.76,30.68 44.76,31.14 44.84,31.22 44.9,31.22 v1(45.17,31.49)
  BOTTOM w0.099: 45.16,31.49 v1(45.17,31.49) 45.06,31.38 45.06,30.86 45.3,30.62 P15.9
H_CSI2_0_DX2: length 70.6
  TOP w0.099: J15.14 43.5,31.32 v1(43.7,31.52) ; U42.AF19 v1(82.98,52.36)
  L3-SIGNAL w0.089: v1(82.98,52.36) 82.69,52.08 82.57,52.08 79.44,52.08 78.7,52.81 66.46,52.81 52.86,39.21 52.86,32.94 51.91,31.99 51.72,31.99 50.49,33.23 50.12,33.23 49.85,32.96 49.85,32.59 51.09,31.36 51.09,31.17 50.88,30.96 50.69,30.96 50.35,31.31 49.98,31.31 49.71,31.04 49.71,30.67 50.06,30.33 50.06,30.14 49.85,29.93 49.66,29.93 49,30.6 48.63,30.6 48.36,30.33 48.36,29.96 49.03,29.3 49.03,29.11 48.82,28.91 44.6,28.91 44.38,29.12 44.38,29.3 45.33,30.24 45.33,30.62 45.06,30.88 44.69,30.88 43.75,29.94 43.56,29.94 43.22,30.28 43.22,30.6 43.31,30.68 43.31,30.82 43.22,30.91 43.22,31.2 43.38,31.36 43.38,31.37 43.39,31.37 43.56,31.37 v1(43.7,31.52)
  BOTTOM w0.099: P15.13 43.8,30.63 43.56,30.86 43.56,31.34 43.56,31.34 43.56,31.38 v1(43.7,31.52)
H_CSI2_0_DX3: length 71.1
  TOP w0.099: v1(41.22,31.66) 41.69,31.66 42,31.97 J15.17 ; U42.AE15 v1(83.78,55.56)
  L3-SIGNAL w0.089: v1(83.78,55.56) 83.53,55.56 83.14,55.95 82.12,55.95 81.57,55.4 65.23,55.4 51.2,41.36 51.02,41.36 50.88,41.49 50.51,41.49 50.25,41.23 50.25,40.86 50.38,40.72 50.38,40.54 50.25,40.41 50.06,40.41 49.93,40.54 49.56,40.54 49.29,40.28 49.29,39.9 49.42,39.77 49.42,39.59 49.29,39.46 49.11,39.46 48.98,39.59 48.61,39.59 48.34,39.32 48.34,38.95 48.47,38.82 48.47,38.63 48.19,38.35 47.06,38.35 46.8,38.09 46.8,37.7 46.67,37.57 46.48,37.57 46.35,37.7 46.35,38.09 46.09,38.35 44.83,38.35 44.22,37.74 44.22,36.47 43.28,35.52 43.09,35.52 42.16,36.45 41.79,36.45 41.52,36.19 41.52,35.82 42.45,34.89 42.45,34.7 42.25,34.49 42.06,34.49 40.5,36.06 40.12,36.06 39.86,35.79 39.86,35.42 41.43,33.86 41.43,33.67 41.22,33.46 v1(41.22,31.66)
  BOTTOM w0.099: 42.3,29.42 P15.17 42.3,31.37 42,31.66 v1(41.22,31.66)
H_CSI2_0_DX4: length 69.8
  TOP w0.099: J15.20 40.5,31.27 v1(40.49,31.27) ; U42.AE19 v1(83.78,52.36)
  L5-SIGNAL w0.086: v1(40.49,31.27) 40.49,32.2 40.11,32.59 38.56,32.59 37.81,31.84 37.81,30.67 39.59,28.88 49.89,28.88 55.04,34.04 55.04,40.94 66.73,52.63 82.57,52.63 82.72,52.77 83.37,52.77 v1(83.78,52.36)
  BOTTOM w0.099: P15.21 40.8,29.42 40.8,30.68 40.49,30.99 v1(40.49,31.27)
H_CSI2_0_DY0: length 70.9
  TOP w0.099: J15.9 46,31.66 v1(45.87,31.53) ; U42.AD18 v1(84.58,53.16)
  L3-SIGNAL w0.089: v1(45.87,31.53) 45.87,31.26 45.87,30.45 46.3,30.02 47.11,30.02 47.29,30.02 47.88,30.61 47.88,32.64 47.61,32.91 43.92,32.91 43.79,33.04 43.79,33.22 43.92,33.35 47.61,33.35 47.88,33.62 47.88,33.91 48.1,34.13 48.1,34.5 46.7,35.9 46.7,36.09 46.83,36.22 47.01,36.22 48.41,34.82 48.79,34.82 49.4,35.43 49.4,37.34 49.61,37.55 49.79,37.55 50.21,37.13 50.59,37.13 50.85,37.39 50.85,37.76 50.43,38.18 50.43,38.37 65.66,53.59 82.4,53.59 82.5,53.7 82.7,53.7 82.82,53.57 84.17,53.57 v1(84.58,53.16)
  BOTTOM w0.099: v1(45.87,31.53) 46.15,31.25 46.16,31.25 46.29,31.12 46.29,30.76 46.29,30.76 46.29,30.73 46.3,30.73 P15.7
H_CSI2_0_DY1: length 70
  TOP w0.099: v1(44.45,31.5) 44.46,31.5 44.5,31.45 J15.12 ; U42.AF17 v1(82.98,53.96)
  L5-SIGNAL w0.086: v1(44.45,31.5) 44.45,30.56 44.91,30.1 49.45,30.1 52.63,33.27 52.63,34.38 52.76,34.5 53.92,34.5 54.23,34.81 54.23,35.24 53.92,35.54 52.76,35.54 52.63,35.67 52.63,35.85 52.76,35.98 53.92,35.98 54.23,36.28 54.23,36.71 53.92,37.02 52.76,37.02 52.63,37.14 52.63,41.07 52.94,41.38 53.12,41.38 53.51,40.99 53.94,40.99 54.25,41.29 54.25,41.72 53.85,42.12 53.85,42.3 53.98,42.42 54.16,42.42 54.55,42.03 54.98,42.03 55.29,42.34 55.29,42.77 54.9,43.16 54.9,43.34 55.02,43.47 55.2,43.47 55.6,43.07 56.03,43.07 56.33,43.38 56.33,43.81 55.94,44.2 55.94,44.38 56.07,44.51 56.25,44.51 56.64,44.12 57.07,44.12 57.38,44.42 57.38,44.85 56.98,45.25 56.98,45.43 59.69,48.13 60.33,48.13 61.09,48.9 61.09,49.48 65.18,53.57 69.31,53.57 69.31,53.57 72.61,53.57 81.43,53.57 81.82,53.96 v1(82.98,53.96)
  BOTTOM w0.099: v1(44.45,31.5) 44.46,31.5 44.8,31.16 P15.11 44.8,29.42
H_CSI2_0_DY2: length 70.5
  TOP w0.099: U42.AF20 v1(82.98,51.56) ; v1(42.99,31.52) 42.99,32.91 J15.15
  L3-SIGNAL w0.089: v1(82.98,51.56) 82.69,51.85 82.57,51.85 79.34,51.85 78.61,52.58 66.55,52.58 53.09,39.12 53.09,32.85 52,31.77 51.63,31.77 50.4,33 50.21,33 50.08,32.87 50.08,32.68 51.31,31.45 51.31,31.08 50.97,30.74 50.6,30.74 50.26,31.08 50.07,31.08 49.94,30.95 49.94,30.76 50.28,30.42 50.28,30.05 49.94,29.71 49.57,29.71 48.91,30.37 48.72,30.37 48.59,30.24 48.59,30.05 49.25,29.39 49.25,29.02 48.91,28.68 44.5,28.68 44.16,29.02 44.16,29.4 45.1,30.34 45.1,30.52 44.97,30.65 44.78,30.65 43.84,29.71 43.47,29.71 42.99,30.19 v1(42.99,31.52)
  BOTTOM w0.099: P15.15 43.3,31.23 43,31.52 v1(42.99,31.52)
H_CSI2_0_DY3: length 70.6
  TOP w0.099: J15.18 41.5,30.96 v1(41.81,31.26) 41.82,31.25 ; U42.AE16 v1(83.78,54.76)
  L3-SIGNAL w0.089: v1(41.81,31.26) 41.61,31.46 41.61,31.82 41.45,31.98 41.45,32.27 41.52,32.35 41.76,32.35 41.83,32.43 41.83,32.54 41.76,32.62 41.52,32.62 41.45,32.7 41.45,33.37 41.65,33.58 41.65,33.95 40.09,35.52 40.09,35.7 40.22,35.83 40.4,35.83 41.97,34.27 42.34,34.27 42.68,34.61 42.68,34.98 41.75,35.91 41.75,36.1 41.88,36.23 42.07,36.23 43,35.3 43.37,35.3 44.45,36.37 44.45,37.65 44.93,38.13 45.99,38.13 46.12,38 46.12,37.61 46.39,37.34 46.76,37.34 47.03,37.61 47.03,38 47.16,38.13 48.29,38.13 48.7,38.54 48.7,38.91 48.57,39.04 48.57,39.23 48.7,39.36 48.88,39.36 49.01,39.23 49.39,39.23 49.65,39.49 49.65,39.87 49.52,40 49.52,40.18 49.65,40.31 49.84,40.31 49.97,40.18 50.34,40.18 50.61,40.45 50.61,40.82 50.47,40.95 50.47,41.13 50.61,41.26 50.79,41.26 50.92,41.13 51.29,41.13 65.33,55.17 81.66,55.17 82.21,55.72 82.5,55.72 82.59,55.63 82.59,55.4 82.82,55.17 83.37,55.17 v1(83.78,54.76)
  BOTTOM w0.099: 41.82,31.26 41.81,31.26 ; 41.81,31.26 v1(41.81,31.26) ; 41.81,31.26 42.03,31.04 42.03,30.88 41.8,30.65 P15.19
H_CSI2_0_DY4: length 70.3
  TOP w0.099: J15.21 40,31.55 39.78,31.33 v1(39.77,31.33) ; U42.AE18 v1(83.78,53.16)
  L5-SIGNAL w0.086: v1(39.77,31.33) 40.01,31.33 40.19,31.51 40.19,32.08 39.98,32.28 39.69,32.28 39.61,32.21 39.61,31.88 39.54,31.8 39.43,31.8 39.36,31.88 39.36,32.21 39.28,32.28 38.68,32.28 38.11,31.71 38.11,30.8 39.72,29.19 49.76,29.19 54.74,34.16 54.74,41.07 66.6,52.93 82.45,52.93 82.59,53.08 82.59,53.32 82.82,53.55 83.14,53.55 83.53,53.16 v1(83.78,53.16)
  BOTTOM w0.099: v1(39.77,31.33) 40.3,30.8 40.3,29.42 P15.23
H_CSI2_1_DX0: length 85.9
  TOP w0.099: U42.AC13 v1(85.38,57.96)
  L5-SIGNAL w0.086: v1(39.3,26.54) 39.3,25.3 38.89,24.89 33.22,24.89 31.19,26.92 31.19,33.27 33.4,35.48 45.09,35.48 46.43,36.83 46.43,38.48 64.21,56.26 81.2,56.26 81.71,56.77 84.73,56.77 84.97,57 84.97,57.47 84.98,57.48 84.98,57.56 v1(85.38,57.96)
  BOTTOM w0.099: P15.25 v1(39.3,26.54)
H_CSI2_1_DX1: length 86.7
  TOP w0.099: U42.AD15 v1(84.58,55.56)
  L3-SIGNAL w0.089: v1(37.76,27.04) 37.58,27.04 37.17,27.45 37.17,28.81 36.26,29.72 34.29,29.72 32.89,31.11 32.89,32.22 33.02,32.35 35.55,32.35 35.81,32.62 35.81,32.99 35.55,33.25 33.02,33.25 32.89,33.38 32.89,34.9 33.02,35.03 35.17,35.03 35.43,35.29 35.43,35.67 35.17,35.93 33.02,35.93 32.89,36.06 32.89,37.13 35,39.24 47.62,39.24 64.39,56.01 80.47,56.01 80.71,56.25 84.49,56.25 84.58,56.16 v1(84.58,55.56)
  BOTTOM w0.099: v1(37.76,27.04) 37.56,27.24 37.56,27.99 37.8,28.22 P15.29
H_CSI2_1_DX2: length 85.6
  TOP w0.099: U42.AC16 v1(85.38,54.76)
  L5-SIGNAL w0.086: v1(85.38,54.76) 85.38,55 84.97,55.42 84.97,55.72 84.74,55.95 82.06,55.95 81.66,55.55 76.2,55.55 75.69,55.04 64.57,55.04 49.02,39.5 49.02,38.94 49.33,38.64 50.88,38.64 51,38.51 51,38.33 50.88,38.21 49.33,38.21 49.02,37.9 49.02,37.47 49.33,37.17 50.88,37.17 51,37.04 51,36.86 50.88,36.73 49.33,36.73 49.02,36.43 49.02,35.74 46.99,33.71 34.16,33.71 32.33,31.88 32.33,27.53 33.78,26.09 35.97,26.09 36.3,26.42 v1(36.3,27.64)
  BOTTOM w0.099: P15.33 36.3,27.64 v1(36.3,27.64)
H_CSI2_1_DY0: length 85.8
  TOP w0.099: U42.AC14 v1(85.38,57.16)
  L5-SIGNAL w0.086: v1(38.47,26.54) 38.75,26.54 38.99,26.3 38.99,25.43 38.76,25.2 38.52,25.2 38.45,25.27 38.45,25.73 38.37,25.81 38.19,25.81 38.11,25.73 38.11,25.27 38.03,25.2 33.35,25.2 31.5,27.05 31.5,33.15 33.53,35.18 45.21,35.18 46.74,36.7 46.74,38.35 64.34,55.96 81.33,55.96 81.84,56.46 84.86,56.46 85.27,56.88 85.27,57.08 85.36,57.16 v1(85.38,57.16)
  BOTTOM w0.099: P15.27 38.8,28.15 39.03,27.91 39.03,26.81 38.76,26.54 v1(38.47,26.54)
H_CSI2_1_DY1: length 86.7
  TOP w0.099: U42.AD14 v1(84.58,57.16)
  L3-SIGNAL w0.089: v1(84.58,57.16) 84.58,56.57 84.49,56.48 80.61,56.48 80.37,56.24 64.29,56.24 47.53,39.47 34.91,39.47 32.66,37.23 32.66,35.97 32.93,35.7 35.07,35.7 35.2,35.57 35.2,35.39 35.07,35.26 32.93,35.26 32.66,34.99 32.66,33.29 32.93,33.03 35.46,33.03 35.59,32.9 35.59,32.71 35.46,32.58 32.93,32.58 32.66,32.32 32.66,31.02 34.2,29.49 36.17,29.49 36.94,28.72 v1(36.94,27.04)
  BOTTOM w0.099: v1(36.94,27.04) 37.3,27.4 P15.31
H_CSI2_1_DY2: length 85.6
  TOP w0.099: U42.AC17 v1(85.38,53.96)
  L5-SIGNAL w0.086: v1(85.38,53.96) 85.38,54.22 84.99,54.6 84.99,54.96 84.78,55.18 84.74,55.18 82.82,55.18 82.59,55.4 82.59,55.56 82.51,55.64 82.19,55.64 81.79,55.24 76.33,55.24 75.82,54.74 64.69,54.74 49.33,39.37 49.33,39.07 49.45,38.94 51,38.94 51.31,38.64 51.31,38.21 51,37.9 49.45,37.9 49.33,37.78 49.33,37.6 49.45,37.47 51,37.47 51.31,37.17 51.31,36.73 51,36.43 49.45,36.43 49.33,36.3 49.33,35.61 47.12,33.4 34.29,33.4 32.64,31.75 32.64,27.66 33.91,26.39 35.14,26.39 35.22,26.47 35.22,26.62 35.29,26.7 35.4,26.7 35.47,26.62 35.47,26.47 35.55,26.39 35.84,26.39 35.99,26.54 35.99,27.39 35.75,27.64 v1(35.47,27.64)
  BOTTOM w0.099: v1(35.47,27.64) 35.76,27.64 35.89,27.77 35.89,28.32 35.8,28.41 P15.35
H_DCAN1_MCAN_RX: length 136.6
  TOP w0.132: U42.D19 v1(101.39,52.36) ; JP2.2 210.95,29.97 211.84,29.08 U58.4
  L12-SIGNAL w0.089: v1(101.39,52.36) 101.77,51.97 105.57,51.97 105.95,52.36 109.82,52.36 110.36,51.82 122.43,51.82 v1(123.57,50.67)
  L14-SIGNAL w0.109: JP2.2 206.5,31.24 206.5,38.23 207.65,39.37 207.65,48.39 206.76,49.28 202.31,49.28 200.77,50.82 196.54,50.82 195.92,51.44 186.31,51.44 185.93,51.82 182.75,51.82 180.34,49.4 169.54,49.4 168.4,50.55 160.66,50.55 160.4,50.29 157.1,50.29 156.97,50.16 144.27,50.16 143.85,49.74 137.2,49.74 136.65,50.29 125.35,50.29 124.97,50.67 v1(123.57,50.67)
H_DCAN1_MCAN_TX: length 141.4
  TOP w0.132: U58.1 215.65,29.59 212.72,32.51 JP2.1 ; U42.E19 v1(100.59,52.36)
  L14-SIGNAL w0.109: v1(100.59,52.36) 100.98,51.96 106.32,51.96 106.72,52.37 109.94,52.37 110.49,51.82 122.3,51.82 123.05,51.07 125.21,51.07 125.62,50.66 133.33,50.66 133.86,51.18 140.52,51.18 141.41,50.29 143.64,50.29 143.87,50.53 156.7,50.53 157.39,51.22 168.95,51.22 169.29,51.56 181.74,51.56 182.24,52.07 186.56,52.07 186.82,51.82 195.84,51.82 196.09,52.07 203.45,52.07 205.61,49.91 207.01,49.91 208.28,48.64 208.28,37.97 207.77,37.47 JP2.1
  BOTTOM w0.132: R670.1 JP2.1
H_DDR1_A0: length 103.8
  TOP w0.132: U42.AE22 v1(83.78,49.96) ; U59.N3 v1(62.77,19.98) ; U63.K3 v1(88.17,19.98) ; U60.N3 v1(75.47,19.98)
  L12-SIGNAL w0.089: v1(74.3,45.61) 74.79,46.1 77.98,46.1 81.44,49.56 83.38,49.56 v1(83.78,49.96)
  BOTTOM w0.132: RN13.4 97.04,21.02 96.6,21.46 93.6,21.46 93.32,21.18 91.95,21.18 91.57,20.8 90.91,20.8 90.08,19.98 v1(88.17,19.98) 87.77,20.37 87.77,20.91 87.77,20.92 87.77,20.94 87.51,21.2 87.16,21.2 86.74,21.62 84.43,21.62 83.87,21.06 81.41,21.06 81.27,21.2 79.26,21.2 78.71,21.74 76.91,21.74 75.95,20.78 75.95,20.45 v1(75.47,19.98) 75.1,20.35 74.86,20.35 74.83,20.37 74.46,20.37 74.27,20.57 74.27,20.94 73.95,21.26 72.69,21.26 72.11,21.84 71.45,21.84 70.59,20.98 68.78,20.98 68.59,21.17 65.74,21.17 65.6,21.04 65.6,20.93 65.47,20.8 65.21,20.8 65.08,20.93 65.08,21.04 64.94,21.17 64.53,21.17 64.37,21.01 64.37,20.82 64.62,20.56 64.62,20.38 64.44,20.19 64.25,20.19 63.74,20.7 63.49,20.7 v1(62.77,19.98) 62.39,20.36 60.79,20.36 60.58,20.57 59.18,20.57 57.02,22.73 57.02,37.08 58.8,38.86 60.7,38.86 60.83,38.99 60.83,39.53 60.62,39.74 60.62,39.92 60.81,40.11 61,40.11 61.51,39.6 61.7,39.6 61.88,39.78 61.88,39.97 61.37,40.48 61.37,40.67 61.56,40.86 61.74,40.86 62.26,40.34 62.44,40.34 62.63,40.53 62.63,40.72 62.12,41.23 62.12,41.42 62.3,41.6 62.49,41.6 63,41.09 63.19,41.09 63.38,41.28 63.38,41.47 62.93,41.91 62.93,42.1 63.18,42.35 63.69,42.35 64.01,42.67 64.01,43.18 64.53,43.7 65.64,43.7 66.55,42.8 70.1,42.8 72.91,45.61 v1(74.3,45.61)
H_DDR1_A1: length 92.7
  TOP w0.132: v1(97.28,18.67) 97.52,18.91 RN4.4 ; U59.P7 v1(65.97,19.18) ; U42.AD20 v1(84.58,51.56) ; U60.P7 v1(78.67,19.18) ; U63.L7 v1(91.37,19.18)
  L12-SIGNAL w0.089: v1(67.23,40.84) 66.96,41.12 66.96,43.08 70.72,46.85 70.72,46.97 70.6,47.1 70.6,47.23 70.72,47.35 70.85,47.35 70.98,47.23 71.1,47.23 71.25,47.37 74.3,47.37 75.44,48.51 76.2,48.51 76.52,48.84 79.19,48.84 81.53,51.18 82.81,51.18 82.82,51.17 84.19,51.17 v1(84.58,51.56)
  L14-SIGNAL w0.109: v1(67.23,40.84) 66.93,40.54 66.93,40.26 62.61,35.94 62.61,34.42 59.01,30.82 59.01,24.47 58.89,24.34 58.89,23.54 59.18,23.24 59.18,20.45 60.83,18.8 61.34,18.8 61.34,18.8 64.52,18.8 64.9,19.18 v1(65.97,19.18) 67.01,19.18 67.43,19.6 69,19.6 69.85,20.45 72.49,20.45 73.34,19.6 75.86,19.6 76.3,20.04 77.77,20.04 78.03,19.78 78.03,19.43 78.28,19.18 v1(78.67,19.18) 79.53,19.18 79.91,19.56 80.09,19.56 80.1,19.58 81.82,19.58 82.04,19.35 84.02,19.35 84.25,19.58 89.61,19.58 90.02,19.18 v1(91.37,19.18) 92.08,19.18 92.47,19.58 96.38,19.58 v1(97.28,18.67)
H_DDR1_A2: length 103.5
  TOP w0.132: U59.P3 v1(62.77,19.18) ; U42.AE21 v1(83.78,50.76) ; U63.L3 v1(88.17,19.18) ; U60.P3 v1(75.47,19.18)
  L14-SIGNAL w0.109: v1(75.31,47.37) 75.95,47.37 78.36,49.78 79.63,49.78 80.2,50.36 83.38,50.36 v1(83.78,50.76)
  BOTTOM w0.132: RN13.2 97.04,19.94 96.68,19.58 91.08,19.58 90.68,19.18 v1(88.17,19.18) 87.98,19.18 87.59,19.57 86.27,19.57 85.98,19.28 81.66,19.28 81.36,19.58 80.04,19.58 79.65,19.96 79.3,19.96 78.93,19.6 78.28,19.6 78.14,19.73 78.14,20.38 77.88,20.65 77.47,20.65 76,19.18 75.86,19.18 75.86,19.18 v1(75.47,19.18) 75.28,19.18 74.91,19.55 74.86,19.55 74.83,19.57 73.71,19.57 73.68,19.55 73.55,19.55 73.28,19.28 68.96,19.28 68.66,19.58 67.19,19.58 67.05,19.71 67.05,19.86 66.92,19.99 66.66,19.99 66.53,19.86 66.53,19.73 66.39,19.6 65.7,19.6 65.58,19.71 65.13,19.71 64.94,19.53 64.94,18.29 64.81,18.16 64.55,18.16 64.41,18.29 64.41,19.25 64.23,19.43 63.91,19.43 63.66,19.18 v1(62.77,19.18) 62.51,19.18 62.13,19.56 60.96,19.56 60.71,19.3 58.29,19.3 56.52,21.08 56.52,37.34 58.55,39.37 59.18,39.37 59.31,39.5 59.31,39.91 59.16,40.05 59.16,40.24 59.35,40.43 59.54,40.43 59.86,40.11 60.04,40.11 60.23,40.29 60.23,40.48 59.91,40.8 59.91,40.99 60.1,41.17 60.28,41.17 60.6,40.85 60.79,40.85 60.98,41.04 60.98,41.23 60.66,41.55 60.66,41.73 60.84,41.92 61.03,41.92 61.35,41.6 61.54,41.6 64.14,44.2 65.79,44.2 66.67,43.31 69.85,43.31 72.77,46.23 74.68,46.23 75.31,46.86 v1(75.31,47.37)
H_DDR1_A3: length 104.6
  TOP w0.132: U60.N2 v1(74.67,19.98) ; U59.N2 61.97,19.98 v1(61.97,19.98) ; U42.AD22 v1(84.58,49.96) ; U63.K2 v1(87.37,19.98)
  L14-SIGNAL w0.109: v1(61.97,19.98) 61.59,20.36 60.82,20.36 v1(60.21,20.97)
  BOTTOM w0.132: v1(60.21,20.97) 59.43,20.97 57.53,22.86 57.53,36.96 58.93,38.35 62.87,38.35 63.04,38.53 63.04,38.72 62.4,39.35 62.4,39.54 62.59,39.73 62.77,39.73 63.41,39.09 63.6,39.09 63.79,39.28 63.79,39.46 63.15,40.1 63.15,40.29 63.34,40.48 63.52,40.48 64.16,39.84 64.35,39.84 64.53,40.02 64.53,40.21 63.9,40.85 63.9,41.04 64.08,41.22 64.27,41.22 64.91,40.58 65.09,40.58 65.28,40.77 65.28,40.96 64.64,41.6 64.64,41.78 64.83,41.97 65.02,41.97 65.66,41.33 65.84,41.33 66.03,41.52 66.03,41.7 65.64,42.09 65.64,42.35 65.81,42.52 66.07,42.52 66.21,42.38 71.2,42.38 73.66,44.83 76.96,44.83 81.69,49.56 84.18,49.56 v1(84.58,49.96) ; RN13.3 97.03,20.44 96.9,20.57 94.26,20.57 94.06,20.37 91.11,20.37 90.32,19.58 88.04,19.58 88.04,19.58 88.01,19.58 87.61,19.98 v1(87.37,19.98) 86.97,20.38 86.32,20.38 86.16,20.55 86.16,21.03 85.93,21.26 84.68,21.26 84.02,20.6 81.64,20.6 81.43,20.4 80.82,20.4 80.57,20.65 79.98,20.65 79.73,20.4 79.31,20.4 78.42,21.29 77.5,21.29 75.77,19.56 75.28,19.56 74.86,19.98 74.67,19.98 v1(74.67,19.98) 74.43,19.98 74.03,20.37 73.96,20.37 73.95,20.38 73.57,20.38 73.1,20.85 72.59,20.85 71.98,21.46 71.65,21.46 70.76,20.57 68.88,20.57 68.69,20.38 67.96,20.38 67.82,20.51 67.82,20.67 67.69,20.8 67.43,20.8 67.3,20.67 67.3,20.51 67.16,20.38 65.21,20.38 64.64,19.81 63.35,19.81 63.13,19.6 62.54,19.6 62.16,19.98 v1(61.97,19.98)
H_DDR1_A4: length 92.8
  TOP w0.132: RN6.1 95.58,17.59 95.52,17.53 v1(95.12,17.53) ; U60.P8 v1(80.27,19.18) ; U59.P8 v1(67.57,19.18) ; U63.L8 v1(92.97,19.18) ; U42.AE23 v1(83.78,49.16)
  L12-SIGNAL w0.089: v1(95.12,17.53) 95.12,17.9 94.25,18.77 93.38,18.77 v1(92.97,19.18) 92.36,19.18 91.95,18.77 84.45,18.77 84.33,18.89 82.95,18.89 82.83,18.77 80.68,18.77 v1(80.27,19.18) 79.5,19.18 79.08,19.6 78.29,19.6 77.95,19.94 77.27,19.94 76.1,18.77 73.46,18.77 73.08,19.15 68.96,19.15 68.58,18.77 68,18.77 67.86,18.91 67.84,18.91 v1(67.57,19.18) 67.19,19.56 60.58,19.56 57.28,22.86 57.28,36.7 58.36,37.78 v1(58.99,37.78)
  BOTTOM w0.132: v1(83.78,49.16) 83.38,48.76 81.53,48.76 77.09,44.32 77.09,43.56 75.44,41.91 67.06,41.91 66.04,40.89 66.04,40.64 63.18,37.78 v1(58.99,37.78)
H_DDR1_A5: length 106
  TOP w0.132: U60.P2 v1(74.67,19.18) ; v1(61.97,19.18) 61.97,19.18 U59.P2 ; U63.L2 v1(87.37,19.18) ; U42.AH22 79.82,50.36 79.16,49.69 78.27,49.69 77,48.42 75.76,48.42 75.73,48.39 75.69,48.39 74.55,47.24 72.64,47.24 70.87,45.47 v1(70.1,45.47)
  BOTTOM w0.132: RN13.1 97.04,19.37 96.34,18.67 94.62,18.67 94.53,18.76 87.77,18.76 87.65,18.88 87.65,18.9 v1(87.37,19.18) 86.97,18.78 86.22,18.78 86.03,18.97 81.4,18.97 81.23,18.8 79.96,18.8 79.6,19.15 79.32,19.15 78.97,18.8 78.43,18.8 78.05,19.18 77.53,19.18 77.4,19.04 77.4,18.39 77.27,18.26 77,18.26 76.87,18.39 76.87,19.04 76.74,19.18 76.5,19.18 76.12,18.8 75.05,18.8 v1(74.67,19.18) 74.3,18.8 74.06,18.8 74.03,18.78 73.71,18.78 73.68,18.8 73.5,18.8 73.41,18.9 68.83,18.9 68.7,18.76 67.14,18.76 67.01,18.63 67.01,18.14 66.88,18.01 66.62,18.01 66.48,18.14 66.48,18.63 66.35,18.76 65.81,18.76 65.59,18.54 65.59,17.89 65.33,17.63 64.21,17.63 63.98,17.86 63.98,18.57 63.79,18.76 62.39,18.76 v1(61.97,19.18) 61.59,18.8 60.83,18.8 60.71,18.92 57.91,18.92 56.13,20.7 56.13,37.85 61.02,42.73 61.2,42.73 61.46,42.47 61.65,42.47 61.83,42.66 61.83,42.84 61.58,43.1 61.58,43.29 61.76,43.48 61.95,43.48 62.21,43.22 62.39,43.22 62.58,43.4 62.58,43.59 62.32,43.85 62.32,44.04 62.51,44.22 62.7,44.22 62.96,43.97 63.14,43.97 63.33,44.15 63.33,44.79 63.5,44.96 65.62,44.96 66.76,43.81 67.27,43.81 67.4,43.95 67.4,44.57 67.53,44.7 67.8,44.7 67.93,44.57 67.93,43.95 68.06,43.81 68.32,43.81 68.46,43.95 68.46,44.57 68.59,44.7 68.85,44.7 68.98,44.57 68.98,43.95 69.12,43.81 69.72,43.81 70.61,44.7 70.61,44.96 v1(70.1,45.47)
H_DDR1_A6: length 90.2
  TOP w0.132: U63.M8 v1(92.97,18.38) 92.97,17.98 92.96,17.98 92.96,17.53 93.48,17.01 RN6.2 ; U59.R8 v1(67.57,18.38) ; U60.R8 v1(80.27,18.38) ; U42.AD24 v1(84.58,48.36)
  L12-SIGNAL w0.089: v1(58.65,20.46) 59.05,20.05 59.05,19.56 60.66,17.96 64.31,17.96 65.11,18.75 67.2,18.75 v1(67.57,18.38)
  L14-SIGNAL w0.109: v1(58.65,20.46) 58.65,22.25 58.55,22.35 58.55,30.99 62.1,34.54 62.1,36.07 66.42,40.39 66.42,40.77 69.22,43.56 70.61,43.56 71.03,43.98 74.97,43.98 75.31,44.32 77.6,44.32 81.26,47.99 82.79,47.99 82.82,47.96 84.18,47.96 v1(84.58,48.36) ; v1(67.57,18.38) 67.95,18 70.81,18 70.83,17.99 71.16,17.99 71.17,18 76.29,18 77.29,19 77.9,19 78.1,18.8 79.85,18.8 v1(80.27,18.38) 80.69,18.8 82.69,18.8 82.74,18.75 83.48,18.75 83.53,18.79 83.86,18.79 83.9,18.76 91.51,18.76 91.55,18.8 92.55,18.8 v1(92.97,18.38)
H_DDR1_A7: length 104
  TOP w0.132: v1(87.37,18.38) U63.M2 ; U42.AC22 v1(85.38,49.96) ; U60.R2 v1(74.67,18.38) ; U59.R2 v1(61.97,18.38)
  L14-SIGNAL w0.109: v1(85.38,49.96) 84.98,49.56 80.67,49.56 77.98,46.86 v1(71.5,46.86)
  BOTTOM w0.132: RN15.4 97.04,17.59 96.6,17.14 93.34,17.14 92.51,17.98 87.77,17.98 v1(87.37,18.38) 87,18 86.76,18 86.73,17.98 86.33,17.98 85.5,17.14 85.27,17.14 85.14,17.28 85.14,17.7 85.01,17.83 84.74,17.83 84.61,17.7 84.61,17.28 84.48,17.14 83.97,17.14 83.67,17.45 82.96,17.45 82.65,17.14 76.58,17.14 75.75,17.98 75.07,17.98 v1(74.67,18.38) 74.3,18 74.06,18 74.03,17.98 73.63,17.98 72.82,17.17 72.59,17.17 72.46,17.3 72.46,17.6 72.33,17.73 72.07,17.73 71.93,17.6 71.93,17.3 71.8,17.17 71.54,17.17 71.41,17.3 71.41,17.6 71.27,17.73 71.01,17.73 70.88,17.6 70.88,17.3 70.75,17.17 70.48,17.17 70.35,17.3 70.35,17.39 70.22,17.53 69.95,17.53 69.82,17.39 69.82,17.3 69.69,17.17 67.94,17.17 67.81,17.3 67.81,17.44 67.68,17.58 67.41,17.58 67.28,17.44 67.28,17.3 67.15,17.17 63.91,17.17 62.7,18.38 v1(61.97,18.38) 61.55,17.96 60.88,17.96 60.81,17.88 59.1,17.88 59.08,17.89 58.31,17.89 55.75,20.45 55.75,38.1 63.12,45.47 66.04,45.47 67.44,46.86 v1(71.5,46.86)
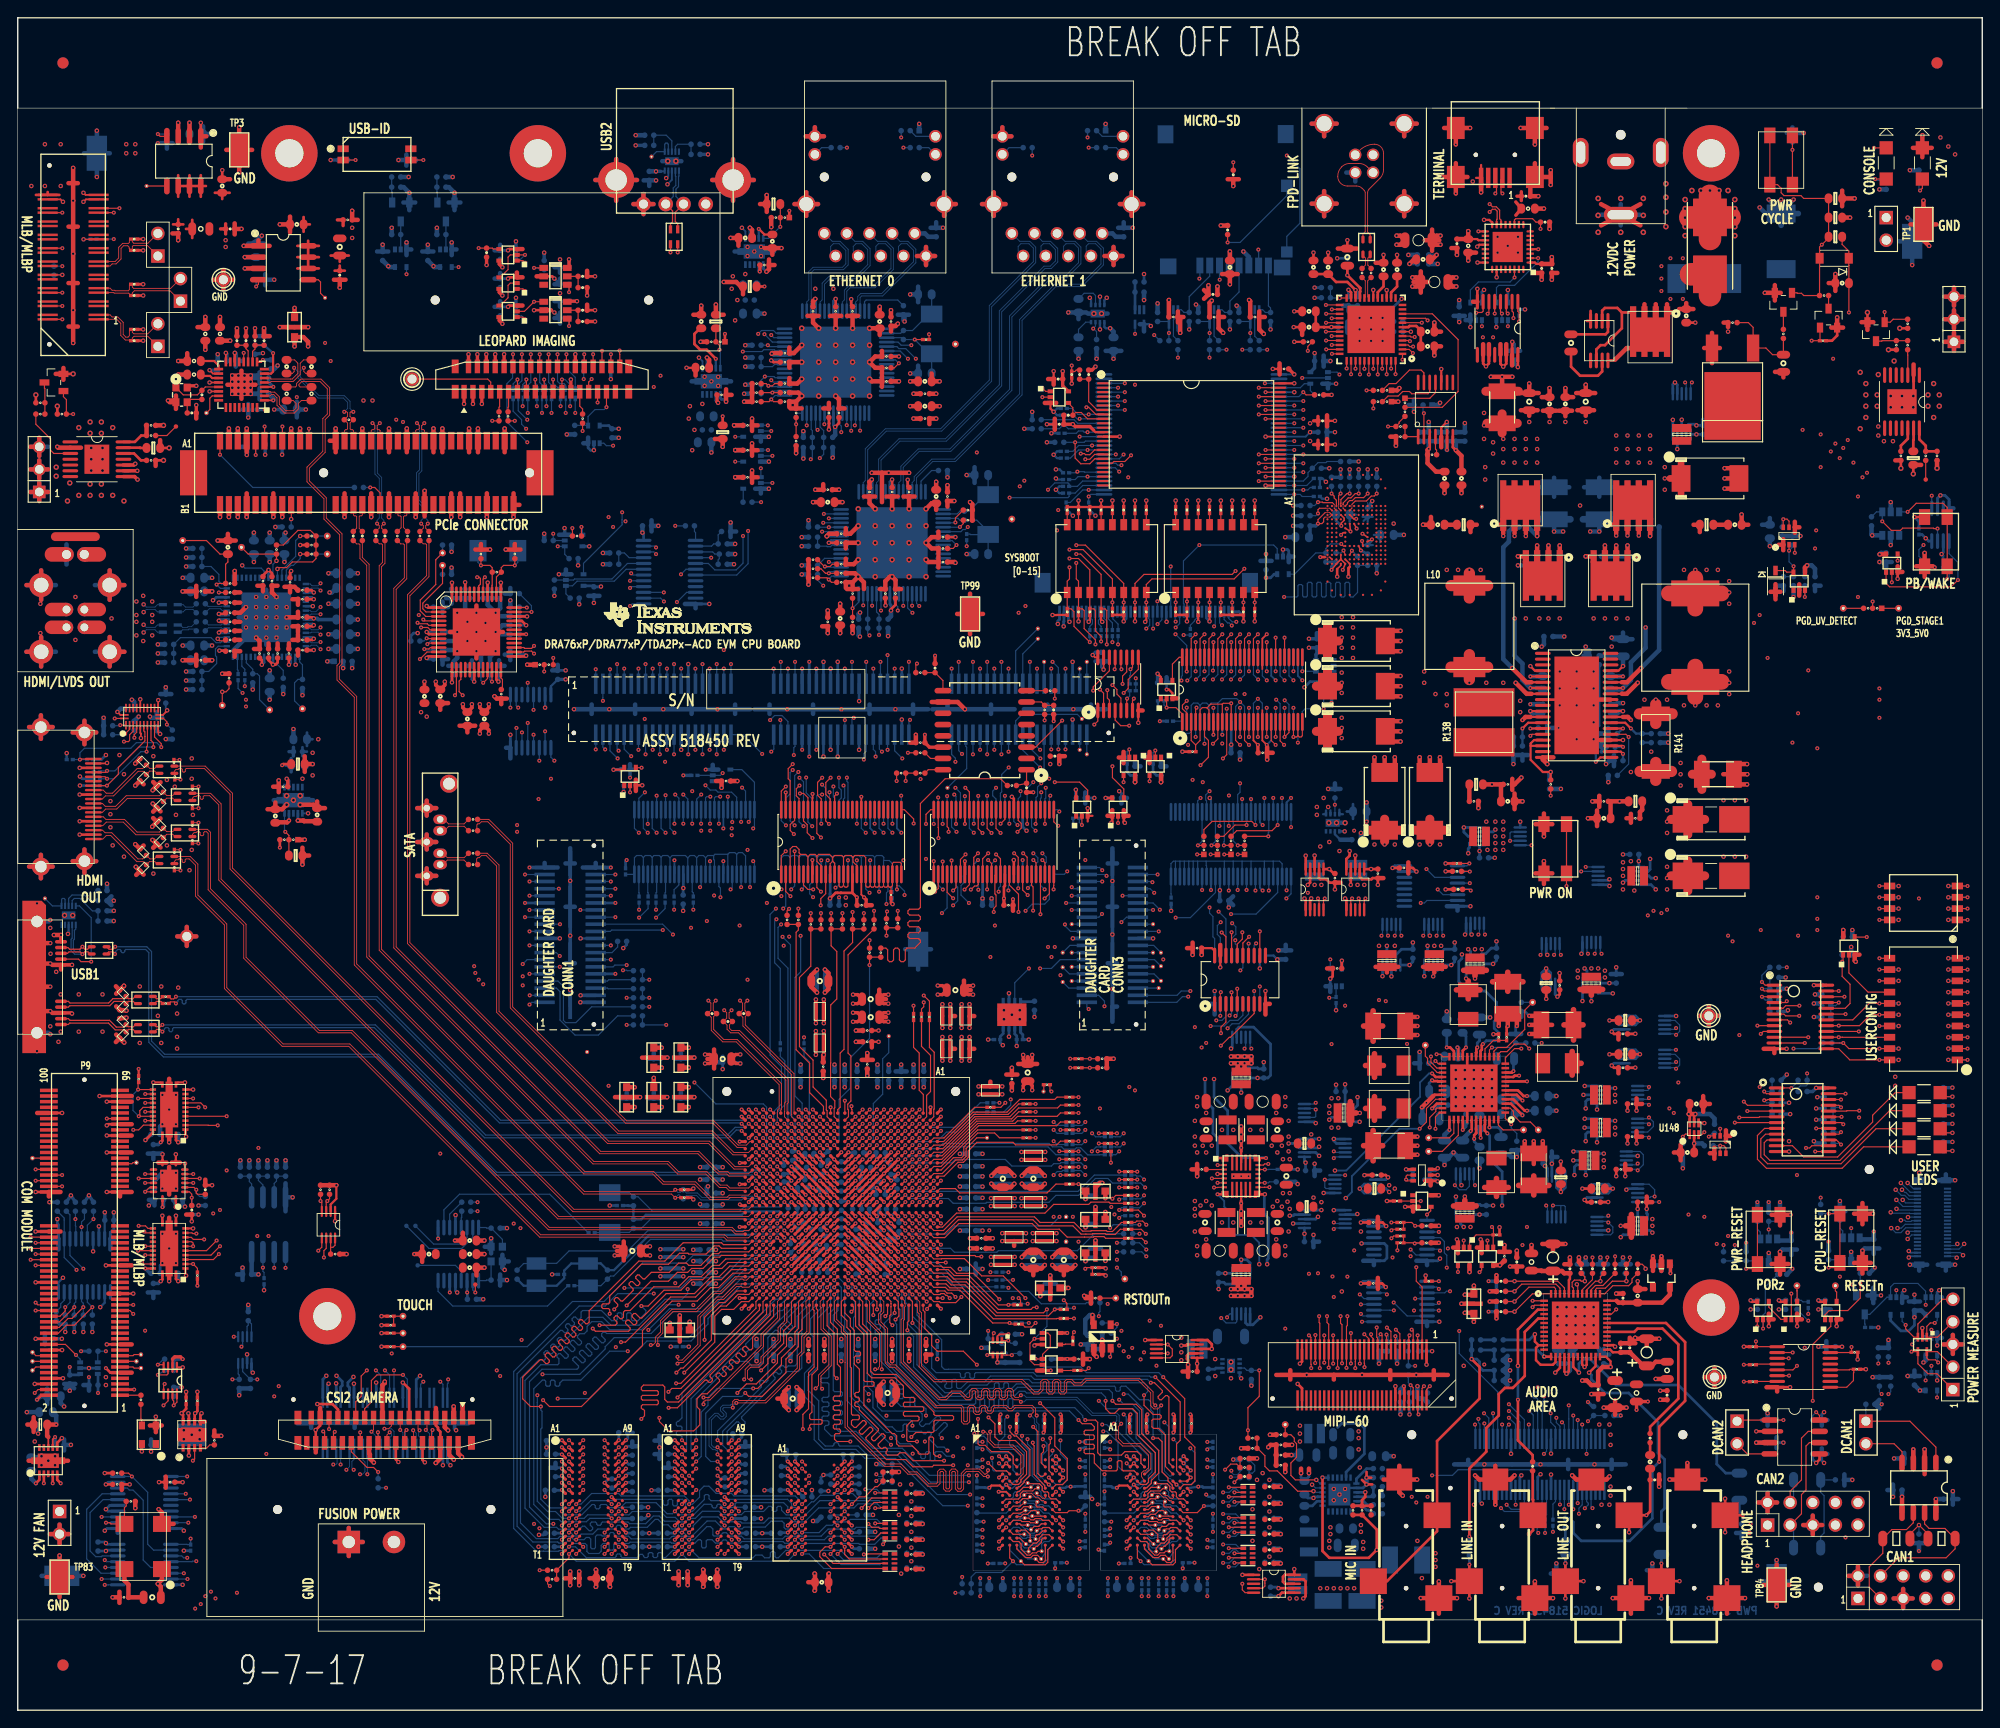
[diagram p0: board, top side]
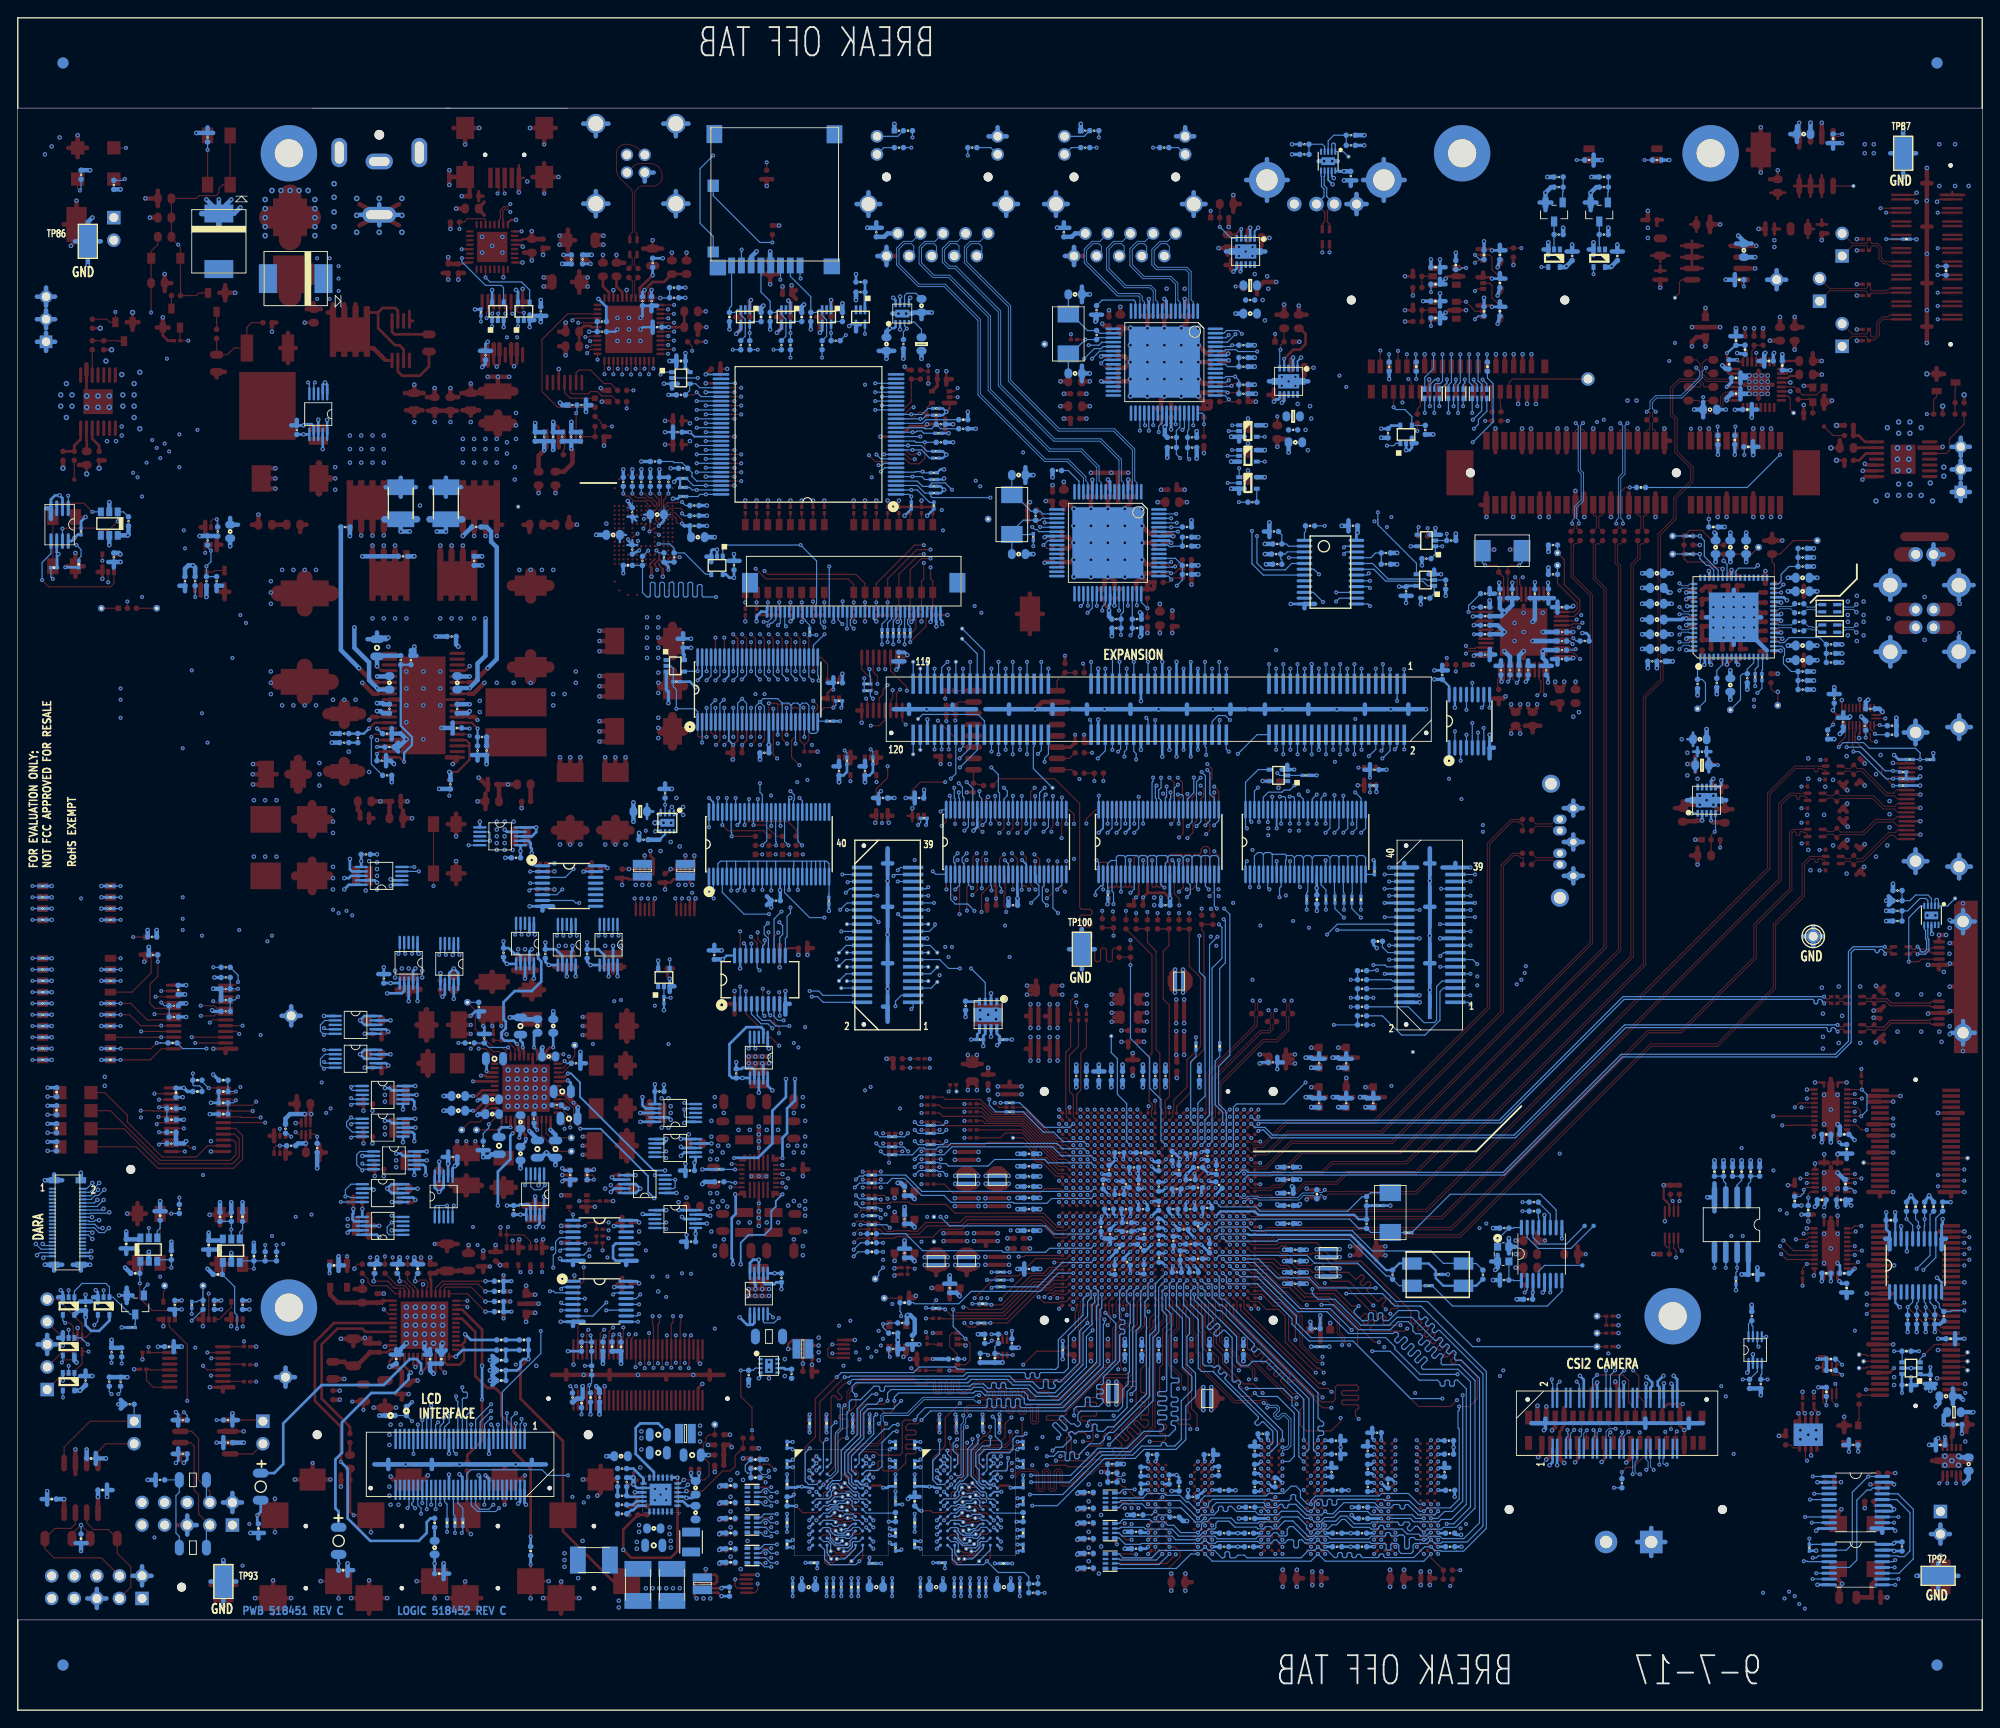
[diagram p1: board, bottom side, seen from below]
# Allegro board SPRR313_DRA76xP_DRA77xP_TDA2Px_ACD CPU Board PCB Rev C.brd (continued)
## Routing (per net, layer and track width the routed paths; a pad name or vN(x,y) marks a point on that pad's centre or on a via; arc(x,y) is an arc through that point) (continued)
H_DDR1_A8: length 94.8
  TOP w0.132: U63.N8 v1(92.17,17.58) ; v1(59.05,34.88) 59.77,34.16 63.37,34.16 70.23,41.02 70.23,42.7 73.56,46.02 76.38,46.02 77.89,47.54 78.78,47.54 80.4,49.16 82.18,49.16 U42.AG23 ; U60.T8 v1(79.47,17.58) ; U59.T8 v1(66.77,17.58)
  L14-SIGNAL w0.109: v1(92.17,17.58) 91.41,16.81 80.23,16.81 v1(79.47,17.58) 78.43,16.54 74.4,16.54 73.69,15.82 68.52,15.82 v1(66.77,17.58) 65.88,16.69 58.75,16.69 56.64,18.8 56.64,32.89 58.63,34.88 v1(59.05,34.88)
  BOTTOM w0.132: RN15.3 97.04,17.01 96.92,16.89 92.86,16.89 v1(92.17,17.58)
H_DDR1_A9: length 94.8
  TOP w0.132: U63.M3 v1(88.17,18.38) ; v1(90.66,17.52) 91.67,16.52 RN6.3 ; U42.AF24 v1(82.98,48.36) ; U59.R3 v1(63.57,18.38) ; U60.R3 v1(75.47,18.38)
  L12-SIGNAL w0.089: v1(58.04,20.95) 58.7,20.95 60.85,18.8 62.35,18.8 62.77,18.38 v1(63.57,18.38) ; v1(90.66,17.52) 89.81,18.38 v1(88.17,18.38) 87.74,17.95 87.21,17.95 80.14,17.95 79.32,18.77 76.84,18.77 76.44,18.38 v1(75.47,18.38)
  L14-SIGNAL w0.109: v1(63.57,18.38) 64.61,18.38 65.01,18.78 68.77,18.78 69.72,19.74 70.46,19.74 70.79,19.41 71.2,19.41 71.58,19.79 72.39,19.79 73.38,18.8 75.05,18.8 v1(75.47,18.38) ; v1(82.98,48.36) 81.13,48.36 77.6,44.83 71.12,44.83 70.74,44.45 68.96,44.45 65.46,40.94 65.46,40.79 65.56,40.69 65.56,40.54 65.4,40.38 65.25,40.38 65.15,40.48 64.99,40.48 64.83,40.32 64.83,40.17 65.12,39.88 65.12,39.72 64.97,39.57 64.81,39.57 64.52,39.86 64.37,39.86 64.22,39.7 64.22,39.55 64.51,39.26 64.51,39.11 64.35,38.95 64.2,38.95 63.91,39.24 63.75,39.24 63.6,39.09 63.6,38.93 63.89,38.64 63.89,38.49 63.73,38.33 63.58,38.33 63.29,38.62 63.13,38.62 62.98,38.47 62.98,38.31 63.27,38.02 63.27,37.87 63.11,37.71 62.96,37.71 62.67,38 62.52,38 62.36,37.85 62.36,37.7 62.65,37.41 62.65,37.25 62.5,37.1 62.34,37.1 62.05,37.39 61.9,37.39 61.72,37.21 61.72,34.8 58.04,31.11 v1(58.04,20.95)
H_DDR1_A10: length 94.5
  TOP w0.132: U60.L7 v1(79.47,21.58) ; v1(94.87,22.73) 96.01,23.87 RN2.2 ; v1(92.17,21.58) U63.H7 ; U42.AD21 v1(84.58,50.76) ; U59.L7 v1(66.77,21.58)
  L12-SIGNAL w0.089: v1(84.58,50.76) 84.17,50.35 81.21,50.35 79.38,48.51 77.22,48.51 75.56,46.86 72.52,46.86 68.58,42.93 v1(68.58,40.39) ; v1(94.87,22.73) 94.09,21.95 92.55,21.95 v1(92.17,21.58) 90.36,21.58 89.99,21.95 88.33,21.95 83.74,21.95 83.73,21.96 83.4,21.96 83.39,21.95 79.84,21.95 v1(79.47,21.58) 79.1,21.58 77.84,22.83 76.73,22.83 75.9,22 73.27,22 72.9,22.38 70.23,22.38 69.8,21.95 67.14,21.95 v1(66.77,21.58)
  BOTTOM w0.132: v1(66.77,21.58) 64.3,21.58 63.92,21.2 61.1,21.2 60.83,21.46 59.69,21.46 58.01,23.14 58.01,36.16 58.97,37.13 59.22,37.13 59.35,37 59.35,36.58 59.48,36.45 59.75,36.45 59.88,36.58 59.88,37 60.01,37.13 60.28,37.13 60.41,37 60.41,36.58 60.54,36.45 60.8,36.45 60.94,36.58 60.94,36.81 61.26,37.13 63.29,37.13 66.55,40.39 v1(68.58,40.39)
H_DDR1_A11: length 95.5
  TOP w0.132: U42.AE24 v1(83.78,48.36) ; RN6.4 91.5,15.94 90.17,17.27 90.17,17.78 90.77,18.38 v1(91.37,18.38) U63.M7 ; U60.R7 v1(78.67,18.38) ; U59.R7 v1(65.97,18.38)
  L12-SIGNAL w0.089: v1(83.78,48.36) 83.39,47.97 80.87,47.97 78.47,45.58 v1(75.95,45.58)
  L14-SIGNAL w0.109: v1(75.95,45.58) 75.58,45.21 70.87,45.21 70.48,44.83 68.71,44.83 62.61,38.73 61.72,38.73 61.21,38.23 61.21,34.92 57.51,31.23 57.51,20.21 59.76,17.97 64.7,17.97 65.11,18.38 v1(65.97,18.38) 66.97,18.38 68.76,16.59 73.56,16.59 73.99,17.02 76.33,17.02 77.69,18.38 v1(78.67,18.38) 79.54,18.38 79.96,17.96 81.54,17.96 81.81,17.68 85.9,17.68 86.18,17.96 87.21,17.96 89.33,17.96 89.75,18.38 v1(91.37,18.38)
H_DDR1_A12: length 94.5
  TOP w0.132: U42.AG21 82.18,50.76 79.59,50.76 78.87,50.04 78.11,50.04 76.83,48.77 75.44,48.77 74.3,47.62 71.5,47.62 68.83,44.96 68.27,44.96 68.09,44.78 68.09,44.22 67.92,44.04 67.73,44.04 67.41,44.36 67.22,44.36 67.04,44.18 67.04,43.99 67.36,43.67 67.36,43.48 67.18,43.31 v1(65.41,43.31) ; U60.N7 v1(78.67,19.98) ; v1(95.63,20.95) 96.01,20.57 96.77,20.57 96.9,20.44 RN4.2 ; U59.N7 v1(65.97,19.98) ; U63.K7 v1(91.37,19.98)
  L12-SIGNAL w0.089: v1(65.41,43.31) 65.41,41.91 63.16,39.67 63.04,39.67 62.53,40.18 62.4,40.18 62.28,40.05 62.28,39.93 62.79,39.42 62.79,39.29 62.66,39.17 62.54,39.17 62.03,39.68 61.9,39.68 61.78,39.55 61.78,39.42 62.29,38.92 62.29,38.79 62.16,38.66 62.03,38.66 61.52,39.17 61.4,39.17 61.27,39.05 61.27,38.92 61.78,38.41 61.78,38.29 59.44,35.95 59.44,34.17 58.8,33.53 58.8,28.83 59.69,27.94 59.69,27.29 59.78,27.2 60.11,27.2 60.2,27.11 60.2,26.94 60.11,26.85 59.78,26.85 59.69,26.76 59.69,26.58 59.78,26.49 60.11,26.49 60.2,26.4 60.2,26.23 60.11,26.14 59.78,26.14 59.69,26.05 59.69,25.87 59.78,25.78 60.11,25.78 60.2,25.69 60.2,25.51 60.11,25.43 59.78,25.43 59.69,25.34 59.69,25.15 60.07,24.77 60.07,23.65 60.93,22.78 63.16,22.78 v1(65.97,19.98)
  L14-SIGNAL w0.109: v1(65.97,19.98) 66.97,19.98 67.39,20.4 68.79,20.4 69.21,20.83 73.03,20.83 73.45,20.4 78.25,20.4 v1(78.67,19.98) 79.57,19.98 79.99,20.4 84.38,20.4 84.61,20.62 85.85,20.62 86.08,20.4 89.66,20.4 90.08,19.98 v1(91.37,19.98) 91.65,20.26 91.69,20.26 91.81,20.38 94.55,20.38 95.12,20.95 v1(95.63,20.95)
H_DDR1_A13: length 95.9
  TOP w0.132: U60.T3 v1(75.47,17.58) ; U63.N3 v1(88.17,17.58) ; U42.AF21 v1(82.98,50.76) ; U59.T3 v1(62.77,17.58)
  L12-SIGNAL w0.089: v1(88.17,17.58) 87.79,17.2 80.39,17.2 79.63,17.96 76.78,17.96 76.4,17.58 v1(75.47,17.58) 75.04,18 73.33,18 72.62,18.72 72.19,18.72 71.3,17.83 70.64,17.83 70,18.47 69.49,18.47 69.01,17.98 65.23,17.98 64.82,17.58 v1(62.77,17.58) 62.33,17.14 60.58,17.14 58.8,18.92 58.17,18.92 56.77,20.32 56.77,36.96 67.31,47.5 v1(68.2,47.5)
  BOTTOM w0.132: RN15.1 90.61,15.94 88.97,17.58 v1(88.17,17.58) ; v1(82.98,50.76) 81.37,50.76 79.25,48.64 75.69,48.64 74.55,47.5 v1(68.2,47.5)
H_DDR1_A14: length 94.5
  TOP w0.132: U59.T7 v1(65.97,17.58) ; U63.N7 v1(91.37,17.58) ; U42.AC23 v1(85.38,49.16) ; U60.T7 v1(78.67,17.58)
  L12-SIGNAL w0.089: v1(91.37,17.58) 90.71,16.92 79.33,16.92 v1(78.67,17.58) 77.27,17.58 75.84,16.15 67.39,16.15 v1(65.97,17.58)
  L14-SIGNAL w0.109: v1(65.97,17.58) 65.33,17.58 64.9,17.14 59.18,17.14 57.15,19.18 57.15,31.5 v1(60.7,35.05)
  BOTTOM w0.132: RN15.2 97.04,16.52 96.91,16.38 92.56,16.38 v1(91.37,17.58) ; v1(85.38,49.16) 84.98,48.76 84.98,48.2 84.74,47.96 81.49,47.96 77.6,44.07 77.6,43.43 75.69,41.53 70.74,41.53 64.26,35.05 v1(60.7,35.05)
H_DDR1_A15: length 94.3
  TOP w0.132: v1(67.06,45.09) 67.44,45.47 67.44,45.66 67.06,46.04 67.06,46.23 67.24,46.42 67.43,46.42 67.82,46.03 68,46.03 69.18,47.21 69.18,47.39 68.73,47.84 68.73,48.03 68.92,48.22 69.1,48.22 69.55,47.77 69.74,47.77 69.93,47.95 69.93,48.14 69.48,48.59 69.48,48.78 69.66,48.96 69.85,48.96 70.3,48.51 70.49,48.51 71.23,49.25 73.26,49.25 74.3,50.29 75.18,50.29 75.44,50.04 76.79,50.04 78.11,51.35 78.78,51.35 78.99,51.56 82.18,51.56 U42.AG20 ; v1(92.17,20.78) U63.J7 ; U59.M7 v1(66.77,20.78) ; RN4.1 v1(96.39,21.02) ; U60.M7 v1(79.47,20.78)
  L12-SIGNAL w0.089: v1(96.39,21.02) 95.78,20.4 92.81,20.4 92.54,20.4 v1(92.17,20.78) 90.86,20.78 90.48,20.4 86.41,20.4 86.04,20.78 81.92,20.78 81.54,20.4 79.84,20.4 v1(79.47,20.78) 76.61,20.78 76.23,20.4 73.55,20.4 72.01,21.95 71.6,21.95 71.07,21.41 68.07,21.41 67.44,20.78 v1(66.77,20.78) 66.09,20.78 62.87,24 61.41,24 60.8,24.62 60.8,26.22 60.8,30.79 60.88,30.87 61.25,30.87 61.34,30.96 61.34,31.14 61.25,31.23 60.88,31.23 60.8,31.32 60.8,31.5 60.88,31.59 61.25,31.59 61.34,31.67 61.34,31.85 61.25,31.94 60.88,31.94 60.8,32.03 60.8,32.22 61.16,32.59 61.16,32.93 61,33.1 59.65,33.1 59.56,33.18 59.56,33.36 59.65,33.45 61,33.45 61.09,33.54 61.09,33.74 61,33.83 60.54,33.83 60.45,33.92 60.45,34.1 60.54,34.19 61,34.19 61.09,34.28 61.09,35.69 62.1,36.7 62.1,37.59 66.42,41.91 66.42,43.05 67.44,44.07 67.44,44.7 v1(67.06,45.09)
H_DDR1_BA0: length 95.6
  TOP w0.132: U60.M2 v1(74.67,20.78) ; U42.AE20 v1(83.78,51.56) ; U59.M2 v1(61.97,20.78) ; RN2.3 96.27,23.37 v1(95.63,22.73) ; v1(87.37,20.78) U63.J2
  L12-SIGNAL w0.089: v1(61.97,20.78) 61.77,20.78 61.59,20.95 61.59,21.03 61.47,21.15 60.64,21.15 60.33,21.46 59.31,21.46 57.66,23.11 57.66,35.9 59.94,38.19 59.94,39.5 67.56,47.11 69.46,47.11 69.99,47.63 69.99,48.55 70.08,48.64 70.25,48.64 70.34,48.55 70.34,48.13 70.43,48.04 70.61,48.04 70.7,48.13 70.7,48.55 70.79,48.64 70.96,48.64 71.05,48.55 71.05,48.13 71.14,48.04 71.32,48.04 71.41,48.13 71.41,48.55 71.5,48.64 71.68,48.64 71.76,48.55 71.76,48.13 71.85,48.04 72.63,48.04 72.72,48.13 72.72,48.17 72.81,48.26 72.98,48.26 73.07,48.17 73.07,48.13 73.16,48.04 v1(73.91,48.04) ; v1(95.63,22.73) 94.1,21.2 90.93,21.2 90.6,20.88 89.03,20.88 88.72,21.18 87.76,21.18 87.64,21.06 87.64,21.04 v1(87.37,20.78) 86.86,21.29 84.1,21.29 83.95,21.13 83.43,21.13 83.36,21.2 75.1,21.2 v1(74.67,20.78)
  L14-SIGNAL w0.109: v1(61.97,20.78) 62.37,20.38 62.94,20.38 62.94,20.38 66.93,20.38 67.36,20.8 67.82,20.8 68.17,21.15 68.18,21.15 68.21,21.18 72.64,21.18 72.64,21.18 74.07,21.18 74.47,20.78 v1(74.67,20.78) ; v1(73.91,48.04) 73.91,48.64 74.55,49.27 75.18,49.27 75.82,49.91 76.83,49.91 78.09,51.16 83.38,51.16 v1(83.78,51.56)
H_DDR1_BA1: length 91.4
  TOP w0.132: v1(95.63,19.18) 96.27,19.18 97.03,19.94 RN4.3 ; U63.K8 v1(92.97,19.98) ; U42.AC21 v1(85.38,50.76) ; U60.N8 v1(80.27,19.98) ; U59.N8 v1(67.57,19.98)
  L12-SIGNAL w0.089: v1(67.57,19.98) 67.94,19.6 68.8,19.6 69.14,19.94 70.08,19.94 70.5,19.51 71.41,19.51 71.98,20.09 72.72,20.09 73.26,19.55 76.25,19.55 77.05,20.35 79.09,20.35 79.46,19.98 v1(80.27,19.98) 80.7,19.55 83.49,19.55 83.53,19.51 83.86,19.51 83.9,19.55 91.92,19.55 92.34,19.98 v1(92.97,19.98) 93.4,19.55 95.26,19.55 v1(95.63,19.18)
  L14-SIGNAL w0.109: v1(67.57,19.98) 67.35,19.98 66.93,19.56 62.93,19.56 62.93,19.56 61.81,19.56 61.81,19.56 60.71,19.56 59.69,20.57 59.69,23.81 59.84,23.96 59.84,30.1 59.71,30.23 59.71,31.01 63.12,34.42 63.12,35.81 68.33,41.02 68.33,42.04 69.06,42.77 69.28,42.77 69.39,42.66 69.39,41.51 69.5,41.4 69.72,41.4 69.83,41.51 69.83,42.66 69.94,42.77 v1(70.89,42.77)
  BOTTOM w0.132: v1(85.38,50.76) 84.98,50.36 81.86,50.36 76.68,45.18 73.3,45.18 v1(70.89,42.77)
H_DDR1_BA2: length 97
  TOP w0.132: RN2.4 97.04,22.8 96.98,22.73 v1(96.39,22.73) ; U60.M3 v1(75.47,20.78) ; U59.M3 v1(62.77,20.78) ; U42.AH21 79.1,51.16 78.9,50.96 78.3,50.96 77.03,49.69 75.75,49.69 75.31,49.25 74.15,49.25 73.15,48.26 71.18,48.26 v1(68.45,45.53) ; U63.J3 v1(88.17,20.78)
  L12-SIGNAL w0.089: v1(68.45,45.53) 68.18,45.8 66.76,45.8 60.33,39.37 60.33,37.97 58.02,35.67 58.02,27.71 58.13,27.6 58.84,27.6 58.93,27.51 58.93,27.33 58.84,27.24 58.13,27.24 58.04,27.15 58.04,26.97 58.13,26.89 58.84,26.89 58.93,26.8 58.93,26.62 58.84,26.53 58.13,26.53 58.04,26.44 58.04,26.26 58.13,26.17 58.84,26.17 58.93,26.09 58.93,25.91 58.84,25.82 58.13,25.82 58.04,25.73 58.04,25.55 58.13,25.46 58.84,25.46 58.93,25.37 58.93,25.2 58.84,25.11 58.13,25.11 58.04,25.02 58.04,24.84 58.13,24.75 58.84,24.75 58.93,24.66 58.93,24.49 58.84,24.4 58.13,24.4 58.04,24.31 58.04,24.1 58.13,24.02 58.71,24.02 58.8,23.93 58.8,23.75 58.71,23.66 58.13,23.66 58.04,23.57 58.04,23.37 59.56,21.84 60.45,21.84 60.83,21.46 61.56,21.46 61.87,21.15 62.4,21.15 v1(62.77,20.78)
  L14-SIGNAL w0.109: v1(62.77,20.78) 63.53,20.78 63.9,21.16 67.77,21.16 68.15,21.54 74.09,21.54 74.47,21.16 75.09,21.16 v1(75.47,20.78) 75.86,20.78 75.86,20.78 76.51,20.78 76.89,21.17 79.3,21.17 79.31,21.18 81.42,21.18 81.76,20.83 83.85,20.83 84.2,21.18 87.77,21.18 v1(88.17,20.78) 91.16,20.78 91.56,21.18 94.58,21.18 95.76,22.35 96.01,22.35 v1(96.39,22.73)
H_DDR1_CASN: length 105.7
  TOP w0.132: U42.AG19 82.19,52.37 79.33,52.37 79.12,52.58 74.8,52.58 72.75,50.52 69.83,50.52 64.24,44.93 64.24,43.66 64.05,43.48 63.86,43.48 63.41,43.92 63.23,43.92 63.04,43.74 63.04,43.55 63.49,43.1 63.49,42.92 63.3,42.73 63.12,42.73 62.67,43.18 62.48,43.18 62.29,42.99 62.29,42.8 62.74,42.36 62.74,42.17 62.56,41.98 62.37,41.98 61.92,42.43 61.73,42.43 61.55,42.24 61.55,42.06 61.99,41.61 61.99,41.42 61.81,41.23 61.62,41.23 61.17,41.68 60.99,41.68 60.8,41.5 60.8,41.31 61.25,40.86 61.25,40.67 61.06,40.49 60.87,40.49 60.43,40.93 60.24,40.93 60.05,40.75 60.05,40.56 60.5,40.11 60.5,39.93 60.31,39.74 60.13,39.74 59.68,40.19 59.49,40.19 59.3,40 59.3,39.81 59.75,39.37 59.75,39.18 59.57,38.99 59.38,38.99 58.93,39.44 58.74,39.44 56.77,37.47 56.77,35.03 57.63,34.16 v1(58.81,34.16) ; U60.K3 v1(75.47,22.38) ; U59.K3 v1(62.77,22.38) ; U63.G3 v1(88.17,22.38)
  BOTTOM w0.132: v1(58.81,34.16) 58.81,33.75 58.93,33.63 58.93,31.76 58.8,31.62 58.8,23.75 59.79,22.76 62.39,22.76 v1(62.77,22.38) 63.22,22.38 64.42,23.58 67.16,23.58 67.31,23.72 72.44,23.72 72.57,23.59 72.57,23.2 72.7,23.06 72.97,23.06 73.1,23.2 73.1,23.59 73.23,23.72 73.5,23.72 73.63,23.59 73.63,23.12 73.76,22.99 74.03,22.99 74.16,23.12 74.16,23.59 74.29,23.72 74.73,23.72 75.09,23.36 75.09,22.76 v1(75.47,22.38) 75.86,22.38 77.19,23.7 77.19,24.12 77.32,24.26 77.58,24.26 77.71,24.12 77.71,23.78 77.93,23.57 79.86,23.57 80.01,23.72 86.54,23.72 86.99,23.27 86.99,23.02 87.21,22.8 87.75,22.8 v1(88.17,22.38) 89.24,23.44 89.48,23.44 90.22,24.18 91.75,24.18 91.94,24.38 93.86,24.38 94.37,23.87 RN11.3
H_DDR1_CKE: length 93.3
  TOP w0.132: U59.K9 v1(68.37,22.38) ; R685.1 R686.1 96.65,25.15 96.39,25.15 95.25,24 94.59,24 v1(93.77,23.18) U63.G9 ; v1(67.82,41.4) 68.33,41.4 73.41,46.48 76.2,46.48 78.14,48.42 79.1,48.42 80.24,49.56 U42.AH23 ; U60.K9 v1(81.07,22.38)
  L12-SIGNAL w0.089: v1(93.77,23.18) 93.4,22.8 85.72,22.8 85.29,22.38 v1(81.07,22.38) 80.64,22.8 79.83,22.8 79.1,22.8 78.16,23.75 76.99,23.75 76.04,22.8 74.51,22.8 74,23.32 70.21,23.32 69.27,22.38 v1(68.37,22.38) 68,22.75 66.61,22.75 65.64,22.75 64.01,24.38 61.68,24.38 61.6,24.47 61.6,30.61 61.72,30.73 61.72,31.52 61.81,31.61 62.14,31.61 62.23,31.7 62.23,31.88 62.14,31.97 61.81,31.97 61.72,32.05 61.72,32.23 61.81,32.32 62.14,32.32 62.23,32.41 62.23,32.59 62.14,32.68 61.81,32.68 61.72,32.77 61.72,32.94 61.81,33.03 62.14,33.03 62.23,33.12 62.23,33.3 62.14,33.39 61.81,33.39 61.72,33.48 61.72,33.66 61.81,33.74 62.14,33.74 62.23,33.83 62.23,34.01 62.14,34.1 61.81,34.1 61.72,34.19 61.72,34.37 61.81,34.46 62.14,34.46 62.23,34.54 62.23,34.72 62.14,34.81 61.81,34.81 61.72,34.9 61.72,35.08 61.81,35.17 62.14,35.17 62.23,35.26 62.23,35.43 62.14,35.52 61.81,35.52 61.72,35.61 61.72,35.81 62.48,36.58 62.48,37.47 62.87,37.85 63,37.85 63.51,37.34 63.63,37.34 63.76,37.47 63.76,37.59 63.25,38.1 63.25,38.23 63.37,38.36 63.5,38.36 64.01,37.85 64.14,37.85 64.26,37.97 64.26,38.1 63.75,38.61 63.75,38.73 63.88,38.86 64,38.86 64.51,38.35 64.64,38.35 64.76,38.48 64.76,38.6 64.25,39.11 64.25,39.24 64.38,39.36 64.51,39.36 65.02,38.85 65.14,38.85 65.27,38.98 65.27,39.1 64.76,39.61 64.76,39.74 64.88,39.86 65.01,39.86 65.52,39.36 65.64,39.36 65.77,39.48 65.77,39.61 65.26,40.12 65.26,40.24 65.41,40.39 67.69,40.39 67.94,40.64 67.94,40.89 67.82,41.01 v1(67.82,41.4)
H_DDR1_CLK_N: length 96.1
  TOP w0.099: U59.K7 v1(66.77,22.38) ; U42.AH24 80.64,48.76 79.01,47.13 78.25,47.13 76.22,45.1 73.55,45.1 72.25,43.8 72.25,42.53 71.68,41.96 71.68,41.36 71.4,41.08 v1(71.17,41.08) ; U60.K7 v1(79.47,22.38) ; U63.G7 v1(91.37,22.38)
  L14-SIGNAL w0.089: v1(96.52,25.78) 96.34,25.96 95.24,25.96 94.59,25.31 94.59,24.54 94.07,24.03 93.29,24.03 92.02,22.76 91.75,22.76 v1(91.37,22.38) 91.14,22.61 89.59,22.61 88.06,24.13 84.22,24.13 84.21,24.12 83.69,24.12 83.68,24.13 81.39,24.13 80.64,23.38 80.64,23.03 80.42,22.81 79.9,22.81 v1(79.47,22.38) 77.63,22.38 76.11,23.9 68.17,23.9 67.94,23.67 67.94,23.03 67.66,22.75 67.14,22.75 v1(66.77,22.38) 66.62,22.53 65.79,22.53 64.52,23.8 60.71,23.8 60.48,24.04 60.48,30.7 65,35.23 65,35.35 64.3,36.05 64.3,36.36 64.57,36.63 64.88,36.63 65.58,35.93 65.7,35.93 65.83,36.05 65.83,36.18 65.13,36.88 65.13,37.19 65.39,37.45 65.71,37.45 66.4,36.75 66.53,36.75 66.66,36.88 66.66,37.01 65.96,37.7 65.96,38.02 66.22,38.28 66.53,38.28 67.23,37.58 67.36,37.58 67.48,37.71 67.48,37.83 66.79,38.53 66.79,38.85 67.05,39.11 67.36,39.11 68.06,38.41 68.18,38.41 68.31,38.53 68.31,38.66 67.61,39.36 67.61,39.67 67.87,39.93 68.19,39.93 69.79,38.33 71.15,38.33 71.4,38.58 71.4,39.03 71.31,39.12 70.86,39.12 70.54,39.44 70.54,39.75 71.41,40.61 71.41,40.84 v1(71.17,41.08)
  BOTTOM w0.099: v1(96.52,25.78) 96.77,26.03 97.18,26.03 97.28,25.93 R684.1
H_DDR1_CLK_P: length 96.1
  TOP w0.099: U60.J7 v1(79.47,23.18) ; v1(71.97,41.08) 71.97,41.22 71.95,41.25 71.95,41.85 72.52,42.42 72.52,43.69 73.66,44.83 76.33,44.83 78.36,46.86 79.12,46.86 80.75,48.49 81.51,48.49 81.62,48.38 81.94,48.38 82.32,48.76 U42.AG24 ; U59.J7 v1(66.77,23.18) ; U63.F7 v1(91.37,23.18)
  L14-SIGNAL w0.089: v1(71.97,41.08) 71.64,40.75 71.64,40.52 70.77,39.66 70.77,39.53 70.95,39.35 71.41,39.35 71.63,39.13 71.63,38.48 71.25,38.1 69.7,38.1 68.09,39.7 67.97,39.7 67.84,39.58 67.84,39.45 68.54,38.75 68.54,38.44 68.28,38.18 67.96,38.18 67.27,38.88 67.14,38.88 67.01,38.75 67.01,38.63 67.71,37.93 67.71,37.61 67.45,37.35 67.14,37.35 66.44,38.05 66.31,38.05 66.19,37.92 66.19,37.8 66.88,37.1 66.88,36.79 66.62,36.53 66.31,36.53 65.61,37.22 65.49,37.22 65.36,37.1 65.36,36.97 66.06,36.27 66.06,35.96 65.8,35.7 65.48,35.7 64.79,36.4 64.66,36.4 64.53,36.27 64.53,36.14 65.23,35.45 65.23,35.13 60.71,30.61 60.71,24.13 60.81,24.03 64.62,24.03 65.89,22.76 66.35,22.76 v1(66.77,23.18) 66.91,23.04 67.11,23.04 67.2,23.13 67.2,23.33 67.42,23.55 67.5,23.55 68.08,24.13 76.2,24.13 77.72,22.61 79.13,22.61 79.47,22.94 v1(79.47,23.18) 79.65,23 79.77,23 79.9,23.13 79.9,23.33 80.12,23.55 80.49,23.55 81.3,24.36 83.77,24.36 83.78,24.35 84.11,24.35 84.12,24.36 88.16,24.36 89.68,22.83 91.28,22.83 91.37,22.92 v1(91.37,23.18) 91.56,22.99 91.93,22.99 93.2,24.26 93.98,24.26 94.36,24.64 94.36,25.4 95.15,26.19 96.16,26.19 v1(96.52,26.54)
  BOTTOM w0.099: v1(96.52,26.54) 96.77,26.3 97.18,26.3 97.28,26.39 R675.1
H_DDR1_CSN0: length 97.6
  TOP w0.132: U63.H2 v1(87.37,21.58) ; U60.L2 v1(74.67,21.58) ; U42.AD23 v1(84.58,49.16) ; U59.L2 v1(61.97,21.58)
  L14-SIGNAL w0.109: v1(58.41,35.43) 58.41,35.45 58.3,35.57 57.89,35.57 57.78,35.68 57.78,35.9 57.89,36 58.3,36 58.4,36.11 58.4,36.33 58.3,36.44 57.89,36.44 57.78,36.55 57.78,36.77 57.89,36.88 58.3,36.88 58.4,36.99 58.4,37.21 58.3,37.32 57.89,37.32 57.78,37.42 57.78,37.64 57.89,37.75 58.3,37.75 58.4,37.86 58.4,38.19 58.62,38.4 59.74,38.4 59.94,38.6 59.94,38.76 59.59,39.11 59.59,39.27 59.74,39.42 59.9,39.42 60.25,39.07 60.4,39.07 60.56,39.22 60.56,39.38 60.21,39.73 60.21,39.89 60.36,40.04 60.51,40.04 60.87,39.69 61.02,39.69 61.18,39.84 61.18,40 60.82,40.35 60.82,40.5 60.98,40.66 61.14,40.66 61.24,40.56 61.39,40.56 61.55,40.72 61.55,40.87 61.45,40.97 61.45,41.13 66.33,46.01 78.27,46.01 81.02,48.76 84.18,48.76 v1(84.58,49.16) ; v1(87.37,21.58) 85.69,21.58 85.14,22.12 82.17,22.12 82.04,22 80.43,22 80.43,22 80.11,22 80.11,22 75.09,22 74.95,21.86 v1(74.67,21.58) 74.28,21.97 73.66,21.97 72.39,23.24 69.88,23.24 68.6,21.96 65.54,21.96 65.1,22.4 63.96,22.4 63.55,22 62.39,22 v1(61.97,21.58)
  BOTTOM w0.132: v1(58.41,35.43) 58.41,34.64 58.4,34.63 58.4,23.51 59.56,22.35 60.45,22.35 61.23,21.58 v1(61.97,21.58) ; v1(87.37,21.58) 87.49,21.58 87.89,21.18 88.46,21.18 90.04,22.76 92.81,22.76 92.81,22.76 94.01,22.76 94.46,23.22 96.63,23.22 97.04,22.8 RN11.1
H_DDR1_D0: length 34.4
  TOP w0.132: U42.AE26 v1(83.78,46.76) ; U59.H8 v1(67.57,24.78)
  L12-SIGNAL w0.089: v1(67.57,24.78) 67.94,25.15 68.75,25.15 68.84,25.24 68.84,25.57 68.92,25.65 69.1,25.65 69.19,25.57 69.19,25.24 69.28,25.15 70.11,25.15 71.63,26.67 71.63,26.86 71.54,26.95 71.39,26.95 71.3,27.04 71.3,27.22 71.39,27.3 71.54,27.3 71.63,27.39 71.63,27.58 71.72,27.67 72.05,27.67 72.14,27.76 72.14,27.94 72.05,28.03 71.72,28.03 71.63,28.12 71.63,28.3 71.72,28.38 72.05,28.38 72.14,28.47 72.14,28.65 72.05,28.74 71.72,28.74 71.63,28.83 71.63,33.02 73.66,35.05 73.66,35.81 77.6,39.75 78.36,39.75 83.78,45.17 v1(83.78,46.76)
H_DDR1_D1: length 36.3
  TOP w0.132: U59.H3 v1(63.57,24.78) ; v1(74.17,35.18) 83.78,44.79 83.78,45.96 U42.AE27
  L12-SIGNAL w0.089: v1(63.57,24.78) 64.73,24.78 65.15,24.36 69.95,24.36 72.54,26.94 72.54,30.02 72.45,30.11 72.1,30.11 72.01,30.2 72.01,30.38 72.1,30.47 72.45,30.47 72.54,30.56 72.54,30.73 72.45,30.82 72.28,30.82 72.19,30.91 72.19,31.42 72.77,32 72.77,32.89 74.17,34.29 v1(74.17,35.18)
H_DDR1_D2: length 36.1
  TOP w0.132: v1(73.15,35.81) 73.53,36.2 74.55,36.2 83.38,45.03 U42.AF28 ; U59.H7 v1(65.97,24.78)
  L12-SIGNAL w0.089: v1(73.15,35.81) 72.88,35.54 72.75,35.54 72.61,35.4 72.61,35.27 72.86,35.01 72.86,34.89 72.74,34.76 72.61,34.76 72.35,35.02 72.23,35.02 71.88,34.67 71.88,33.78 70.87,32.77 70.87,32.23 70.95,32.14 71.09,32.14 71.25,31.98 71.25,28.66 71.16,28.58 70.83,28.58 70.74,28.49 70.74,28.31 70.83,28.22 71.16,28.22 71.25,28.13 71.25,27.69 71.11,27.55 70.99,27.55 70.35,28.19 70.22,28.19 70.1,28.06 70.1,27.94 70.73,27.3 70.73,26.28 70.45,26 70.05,26 69.96,26.09 69.96,26.2 69.87,26.29 69.7,26.29 69.61,26.2 69.61,26.09 69.52,26 69.33,26 69.24,26.09 69.24,26.33 69.15,26.42 68.97,26.42 68.88,26.33 68.88,26.09 68.79,26 67.18,26 66.24,25.06 66.24,25.04 v1(65.97,24.78)
H_DDR1_D3: length 35.4
  TOP w0.132: U59.E3 v1(63.57,27.18) ; U42.AH26 80.82,47.16 79.5,45.85 78.87,45.85 77.22,44.2 v1(77.22,41.66)
  L12-SIGNAL w0.089: v1(63.57,27.18) 64.01,27.62 64.01,33.15 64.15,33.29 64.28,33.29 64.53,33.04 64.66,33.04 64.78,33.16 64.78,33.29 64.53,33.54 64.53,33.67 64.66,33.79 64.78,33.79 65.04,33.54 65.16,33.54 65.29,33.66 65.29,33.79 65.03,34.05 65.03,34.17 65.16,34.3 65.28,34.3 65.67,33.92 65.79,33.92 66.04,34.16 66.04,35.18 71.58,40.72 71.58,41.51 72.36,42.29 76.58,42.29 v1(77.22,41.66)
H_DDR1_D4: length 34.5
  TOP w0.132: U42.AF25 v1(82.98,47.56) ; U59.F2 v1(61.97,26.38)
  L12-SIGNAL w0.089: v1(61.97,26.38) 63.12,27.53 63.12,32.89 70.48,40.26 70.48,41.02 72.26,42.8 76.33,42.8 81.09,47.56 v1(82.98,47.56)
H_DDR1_D5: length 35.9
  TOP w0.132: U59.F7 v1(65.97,26.38) ; v1(74.93,37.97) 78.36,41.4 78.36,44.32 79.12,45.09 80.48,45.09 81.35,45.96 82.18,45.96 U42.AG27
  L12-SIGNAL w0.089: v1(65.97,26.38) 66.27,26.68 66.4,26.68 66.73,26.35 66.86,26.35 66.99,26.47 66.99,26.6 66.78,26.81 66.78,27.18 67.15,27.56 67.82,27.56 68,27.74 68,29.86 68.08,29.95 68.69,29.95 69.26,29.38 69.38,29.38 69.51,29.51 69.51,29.63 68.94,30.2 68.94,30.33 69.06,30.46 69.19,30.46 69.76,29.88 69.89,29.88 70.01,30.01 70.01,30.13 69.44,30.71 69.44,30.83 69.85,31.24 69.85,32.26 69.67,32.44 69.67,32.97 70.23,33.53 70.23,34.16 70.38,34.31 70.5,34.31 70.92,33.88 71.07,33.88 71.19,34 71.19,34.13 70.75,34.56 70.75,34.68 73.53,37.47 74.42,37.47 v1(74.93,37.97)
H_DDR1_D6: length 36.1
  TOP w0.132: v1(74.01,36.77) 74.54,36.77 82.99,45.21 82.99,45.97 U42.AF27 ; U59.F8 v1(67.57,26.38)
  L12-SIGNAL w0.089: v1(67.57,26.38) 67.57,26.4 67.94,26.77 69.57,26.77 69.72,26.92 69.72,27.38 69.63,27.47 68.83,27.47 68.74,27.56 68.74,28.23 68.97,28.46 69.1,28.46 69.55,28.02 69.67,28.02 69.8,28.14 69.8,28.27 69.35,28.71 69.35,28.84 69.48,28.96 69.6,28.96 70.05,28.52 70.17,28.52 70.3,28.64 70.3,28.77 69.85,29.22 69.85,29.34 69.98,29.47 70.11,29.47 70.55,29.02 70.68,29.02 70.8,29.15 70.8,29.27 70.36,29.72 70.36,29.91 70.45,30 70.78,30 70.87,30.09 70.87,30.27 70.78,30.35 70.45,30.35 70.36,30.44 70.36,30.62 70.45,30.71 70.78,30.71 70.87,30.8 70.87,30.98 70.78,31.07 70.45,31.07 70.23,31.28 70.23,31.62 70.49,31.88 70.49,33.13 70.89,33.53 71.12,33.53 71.5,33.91 71.5,34.93 73.34,36.77 v1(74.01,36.77)
H_DDR1_D7: length 34.6
  TOP w0.132: U59.G2 v1(61.97,25.58) ; U42.AF26 v1(82.98,46.76)
  L12-SIGNAL w0.089: v1(82.98,46.76) 82.98,45.01 78.23,40.26 73.41,40.26 71.5,38.35 70.99,38.35 70.23,37.59 70.23,37.08 64.52,31.37 64.52,27.3 63.96,26.75 63.15,26.75 v1(61.97,25.58)
H_DDR1_D8: length 33.8
  TOP w0.132: U42.AB24 v1(86.18,48.36) ; U59.D7 v1(65.97,27.98)
  L14-SIGNAL w0.109: v1(86.18,48.36) 86.58,47.96 86.58,46.57 77.6,37.59 77.6,33.4 75.31,31.11 72.92,31.11 70.21,28.4 67.01,28.4 66.59,27.98 v1(65.97,27.98)
H_DDR1_D9: length 36
  TOP w0.132: v1(73.17,34.02) 74.15,34.02 77.27,37.14 77.46,37.14 77.71,36.88 77.9,36.88 78.09,37.07 78.09,37.25 77.83,37.51 77.83,37.7 84.58,44.45 84.58,45.96 U42.AD27 ; U59.B8 v1(67.57,29.58)
  L14-SIGNAL w0.109: v1(73.17,34.02) 71.45,34.02 71.22,33.79 71.22,33.38 71.36,33.24 71.52,33.24 71.63,33.13 71.63,32.91 71.52,32.8 71.1,32.8 70.99,32.69 70.99,32.47 71.1,32.36 71.52,32.36 71.63,32.25 71.63,31.5 71.48,31.35 71.32,31.35 70.46,32.21 70.31,32.21 70.15,32.05 70.15,31.9 71.01,31.04 71.01,30.88 70.86,30.73 70.71,30.73 69.84,31.59 69.69,31.59 69.54,31.44 69.54,31.28 70.4,30.42 70.4,30.26 70.13,30 69.44,30 69.33,30.11 69.33,30.5 69.22,30.61 69,30.61 68.89,30.5 68.89,30.11 68.78,30 67.99,30 v1(67.57,29.58)
H_DDR1_D10: length 37.5
  TOP w0.132: U59.A7 v1(65.97,30.38) ; U42.AE28 84.18,44.56 74.3,34.67 73.02,34.67 72.74,34.96 72.74,36.36 72.52,36.58 70.36,36.58 70.1,36.32 70.1,36.08 70.24,35.94 71.88,35.94 72.01,35.81 72.01,35.55 71.88,35.42 70.24,35.42 70.1,35.28 70.1,35.02 70.24,34.89 71.88,34.89 72.01,34.75 72.01,34.49 71.88,34.36 70.24,34.36 70.1,34.23 70.1,33.98 70.24,33.85 70.33,33.85 70.46,33.72 70.46,33.12 v1(70.1,32.77)
  L14-SIGNAL w0.109: v1(65.97,30.38) 68.36,32.77 v1(70.1,32.77)
H_DDR1_D11: length 37.5
  TOP w0.132: v1(72.14,32.89) 72.14,32.47 73.19,31.42 76,31.42 76.67,32.1 76.67,33.81 76.37,34.12 76.37,35.04 76.92,35.59 77.5,35.59 78.89,36.98 78.89,37.17 78.51,37.55 78.51,37.74 78.7,37.93 78.88,37.93 79.27,37.54 79.45,37.54 79.64,37.73 79.64,37.92 79.26,38.3 79.26,38.49 79.44,38.68 79.63,38.68 80.01,38.29 80.2,38.29 80.39,38.48 80.39,38.66 80,39.05 80,39.24 80.19,39.42 80.38,39.42 80.76,39.04 80.95,39.04 81.13,39.22 81.13,39.41 80.75,39.8 80.75,39.98 80.94,40.17 81.12,40.17 81.51,39.79 81.7,39.79 81.88,39.97 81.88,40.16 81.5,40.54 81.5,40.73 81.68,40.92 81.87,40.92 82.26,40.53 82.44,40.53 82.62,40.71 82.62,41.94 84.98,44.3 U42.AD28 ; U59.C8 v1(67.57,28.78)
  L14-SIGNAL w0.109: v1(72.14,32.89) 72.14,31.32 69.97,29.16 67.95,29.16 v1(67.57,28.78)
H_DDR1_D12: length 34
  TOP w0.132: U59.C2 v1(61.97,28.78) ; U42.AD26 v1(84.58,46.76)
  L14-SIGNAL w0.109: v1(61.97,28.78) 62.61,29.42 62.61,31.11 68.07,36.58 70.19,36.58 70.3,36.69 70.3,36.72 70.41,36.83 70.63,36.83 70.74,36.72 70.74,36.69 70.85,36.58 72.26,36.58 72.64,36.96 72.64,37.35 72.75,37.46 73.04,37.46 73.15,37.57 73.15,37.78 73.04,37.89 72.75,37.89 72.64,38 72.64,38.23 72.9,38.48 74.8,38.48 78.61,42.29 80.26,42.29 84.3,46.33 84.3,46.48 v1(84.58,46.76)
H_DDR1_D13: length 34
  TOP w0.132: U59.A2 v1(61.97,30.38) ; U42.AE25 v1(83.78,47.56)
  L14-SIGNAL w0.109: v1(61.97,30.38) 61.97,31.11 68.49,37.63 71.29,37.63 74.52,40.86 74.52,41.02 74.17,41.37 74.17,41.53 74.32,41.68 74.47,41.68 74.83,41.33 74.98,41.33 75.14,41.48 75.14,41.64 74.78,41.99 74.78,42.14 74.94,42.3 75.09,42.3 75.45,41.95 75.6,41.95 75.76,42.1 75.76,42.25 75.4,42.61 75.4,42.76 75.56,42.92 75.71,42.92 76.06,42.56 76.22,42.56 77.47,43.81 77.6,43.81 80.94,47.16 83.38,47.16 v1(83.78,47.56)
H_DDR1_D14: length 33.9
  TOP w0.132: U42.AD25 v1(84.58,47.56) ; U59.C3 v1(63.57,28.78)
  L14-SIGNAL w0.109: v1(84.58,47.56) 84.98,47.16 84.98,46.5 80.26,41.78 78.74,41.78 78.58,41.62 78.58,41.47 78.68,41.37 78.68,41.22 78.53,41.06 78.37,41.06 78.27,41.16 78.12,41.16 75.44,38.48 75.44,37.85 75.06,37.47 73.66,37.47 72.39,36.2 68.33,36.2 63.12,30.99 63.12,29.23 v1(63.57,28.78)
H_DDR1_D15: length 33.9
  TOP w0.132: U42.AC26 v1(85.38,46.76) ; U59.A3 v1(63.57,30.38)
  L14-SIGNAL w0.109: v1(63.57,30.38) 63.57,30.8 63.78,31.01 63.93,31.01 64.16,30.79 64.31,30.79 64.47,30.94 64.47,31.1 64.24,31.32 64.24,31.48 64.4,31.63 64.55,31.63 64.78,31.4 64.93,31.4 65.09,31.56 65.09,31.71 64.86,31.94 64.86,32.09 65.02,32.25 65.17,32.25 65.4,32.02 65.55,32.02 65.7,32.18 65.7,32.33 65.48,32.56 65.48,32.71 65.63,32.87 65.79,32.87 66.01,32.64 66.17,32.64 66.32,32.8 66.32,32.95 66.1,33.18 66.1,33.33 66.25,33.49 66.89,33.49 67.18,33.78 67.18,34.42 68.58,35.81 72.57,35.81 73.13,36.37 74.47,36.37 79.5,41.4 80.42,41.4 85.38,46.36 v1(85.38,46.76)
H_DDR1_D16: length 27.7
  TOP w0.132: U60.F8 v1(80.27,26.38) ; U42.AA25 v1(86.98,47.56)
  L12-SIGNAL w0.089: v1(86.98,47.56) 87.38,47.17 87.38,43.05 86.23,41.91 86.23,38.73 85.22,37.72 85.22,35.94 81.92,32.64 81.92,32 82.04,31.88 82.04,31.75 81.92,31.62 81.79,31.62 81.41,32.01 81.28,32.01 81.16,31.88 81.16,31.76 81.54,31.37 81.54,31.25 81.41,31.12 81.29,31.12 80.91,31.5 80.78,31.5 80.64,31.37 80.64,26.75 v1(80.27,26.38)
H_DDR1_D17: length 27.6
  TOP w0.132: U60.F2 v1(74.67,26.38) ; U42.AB25 v1(86.18,47.56)
  L12-SIGNAL w0.089: v1(86.18,47.56) 85.77,47.15 85.77,43.86 83.06,41.15 82.42,41.15 74.96,33.68 74.96,30.96 75.18,30.73 75.18,26.89 v1(74.67,26.38)
H_DDR1_D18: length 27.7
  TOP w0.132: U42.AA26 v1(86.98,46.76) ; U60.H7 v1(78.67,24.78)
  L12-SIGNAL w0.089: v1(86.98,46.76) 86.98,43.29 85.85,42.16 85.85,38.99 84.84,37.97 84.84,36.2 79.76,31.11 79.76,25.74 79.67,25.65 79.44,25.65 79.35,25.57 79.35,25.39 79.44,25.3 79.67,25.3 79.76,25.21 79.76,25.02 79.51,24.78 v1(78.67,24.78)
H_DDR1_D19: length 29.2
  TOP w0.132: v1(80.9,35.69) 81.92,36.7 83.02,36.7 85.4,39.09 85.4,39.94 86.43,40.96 86.43,42.23 87.38,43.19 U42.AA28 ; U60.H3 v1(76.27,24.78)
  L12-SIGNAL w0.089: v1(80.9,35.69) 79.1,33.88 79.1,32.87 78.89,32.66 78.72,32.66 78.36,33.02 78.24,33.02 78.11,32.9 78.11,32.77 78.49,32.39 78.49,32.26 78.37,32.14 78.24,32.14 77.86,32.52 77.73,32.52 77.6,32.38 77.6,25.27 77.1,24.78 v1(76.27,24.78)
H_DDR1_D20: length 28.8
  TOP w0.132: v1(83.57,38.23) 84.33,38.99 84.33,39.5 86.11,41.27 86.11,42.67 86.98,43.55 86.98,45.96 U42.AA27 ; U60.E3 v1(76.27,27.18)
  L12-SIGNAL w0.089: v1(83.57,38.23) 83.18,38.23 82.04,39.37 81.15,39.37 77.6,35.81 77.6,34.29 77.22,33.91 76.17,33.91 75.56,33.3 75.56,27.43 75.82,27.18 v1(76.27,27.18)
H_DDR1_D21: length 27.7
  TOP w0.132: U60.F7 v1(78.67,26.38) ; U42.AA24 v1(86.98,48.36)
  L12-SIGNAL w0.089: v1(86.98,48.36) 86.59,47.97 86.59,43.41 85.47,42.29 85.47,39.12 84.45,38.1 84.45,36.58 81.03,33.15 80.52,33.15 80.18,32.81 80.18,32.68 80.37,32.49 80.37,32.37 80.25,32.24 80.12,32.24 79.93,32.43 79.8,32.43 79.68,32.31 79.68,32.18 79.81,32.05 79.81,31.78 79.12,31.09 79.12,26.83 v1(78.67,26.38)
H_DDR1_D22: length 27.9
  TOP w0.132: U60.G2 v1(74.67,25.58) ; U42.AC25 v1(85.38,47.56)
  L12-SIGNAL w0.089: v1(74.67,25.58) 74.3,25.95 74.3,33.78 84.97,44.46 84.97,47.15 v1(85.38,47.56)
H_DDR1_D23: length 27.7
  TOP w0.132: U42.Y26 v1(87.78,46.76) ; U60.H8 v1(80.27,24.78)
  L12-SIGNAL w0.089: v1(87.78,46.76) 87.78,42.82 87.38,42.42 87.38,39.12 85.6,37.34 85.6,35.69 82.55,32.64 82.55,26.42 82.41,26.28 82.29,26.28 81.97,26.6 81.82,26.6 81.72,26.5 81.72,26.35 82.04,26.03 82.04,25.9 81.34,25.2 81.23,25.2 81.23,25.2 80.91,25.2 80.91,25.2 80.7,25.2 v1(80.27,24.78)
H_DDR1_D24: length 26.4
  TOP w0.132: U60.A7 v1(78.67,30.38) ; U42.W26 v1(88.58,46.76)
  BOTTOM w0.132: v1(88.58,46.76) 88.58,46.16 86.46,44.04 86.46,43.86 87.1,43.22 87.1,43.03 86.91,42.84 86.73,42.84 86.09,43.48 85.9,43.48 85.71,43.3 85.71,43.11 86.35,42.47 86.35,42.28 86.17,42.1 85.98,42.1 85.34,42.74 85.15,42.74 84.33,41.91 84.33,37.08 84.15,36.91 83.97,36.91 83.77,37.1 83.59,37.1 83.4,36.92 83.4,36.73 83.59,36.54 83.59,36.35 78.67,31.43 v1(78.67,30.38)
H_DDR1_D25: length 26.6
  TOP w0.132: U60.A2 v1(74.67,30.38) ; U42.AB23 v1(86.18,49.16)
  BOTTOM w0.132: v1(86.18,49.16) 85.78,48.76 85.78,46.53 85.47,46.23 85.22,46.23 74.67,35.68 74.67,32.89 74.27,32.49 74.17,32.49 74.04,32.35 74.04,32.09 74.17,31.96 74.54,31.96 74.67,31.83 74.67,31.56 74.54,31.43 74.17,31.43 74.04,31.3 74.04,31.03 74.17,30.9 74.54,30.9 74.67,30.77 v1(74.67,30.38)
H_DDR1_D26: length 26.5
  TOP w0.132: U42.V24 v1(89.38,48.36) ; U60.B8 v1(80.27,29.58)
  BOTTOM w0.132: v1(89.38,48.36) 89.78,47.96 89.78,45.58 88.14,43.94 88.14,38.48 87.76,38.1 86.49,38.1 81.38,32.99 81.38,32.8 81.76,32.42 81.76,32.23 81.57,32.04 81.39,32.04 81,32.43 80.81,32.43 79.76,31.37 79.76,30.09 v1(80.27,29.58)
H_DDR1_D27: length 26.7
  TOP w0.132: U60.C2 v1(74.67,28.78) ; U42.Y24 v1(87.78,48.36)
  BOTTOM w0.132: v1(74.67,28.78) 75.18,29.29 75.18,35.31 85.47,45.59 85.73,45.59 86.58,46.45 86.58,47.82 86.71,47.96 87.38,47.96 v1(87.78,48.36)
H_DDR1_D28: length 26.5
  TOP w0.132: U60.C8 v1(80.27,28.78) ; U42.W25 v1(88.58,47.56)
  BOTTOM w0.132: v1(80.27,28.78) 79.25,29.8 79.25,31.37 85.13,37.25 85.13,37.44 84.94,37.63 84.94,37.82 85.12,38.01 85.31,38.01 85.51,37.81 85.69,37.81 85.88,38 85.88,38.19 85.68,38.38 85.68,38.57 85.87,38.75 86.06,38.75 86.25,38.56 86.44,38.56 86.61,38.73 87.38,38.73 87.63,38.99 87.63,44.32 88.99,45.68 88.99,47.16 v1(88.58,47.56)
H_DDR1_D29: length 26.5
  TOP w0.132: U42.Y25 v1(87.78,47.56) ; U60.C3 v1(76.27,28.78)
  BOTTOM w0.132: v1(87.78,47.56) 87.38,47.16 87.38,46.36 85.98,44.96 85.6,44.96 81.83,41.19 81.83,41 82.15,40.68 82.15,40.49 81.96,40.31 81.77,40.31 81.45,40.63 81.27,40.63 75.69,35.05 75.69,29.36 v1(76.27,28.78)
H_DDR1_D30: length 26.6
  TOP w0.132: U60.A3 v1(76.27,30.38) ; U42.W24 v1(88.58,48.36)
  BOTTOM w0.132: v1(88.58,48.36) 88.18,47.96 88.18,46.39 83.82,42.04 83.82,39.24 83.31,38.73 82.55,38.73 82.04,39.24 80.52,39.24 76.27,34.99 v1(76.27,30.38)
H_DDR1_D31: length 26.5
  TOP w0.132: U42.Y28 88.18,42.84 87.76,42.42 87.76,40.89 86.36,39.5 86.36,37.97 83.69,35.31 82.17,35.31 v1(81.79,35.69) ; U60.D7 v1(78.67,27.98)
  BOTTOM w0.132: v1(81.79,35.69) 81.39,35.29 79.23,35.29 77.34,33.4 77.34,28.55 77.92,27.98 v1(78.67,27.98)
H_DDR1_DQM0: length 36.1
  TOP w0.132: U59.E7 v1(65.97,27.18) ; v1(74.04,37.97) 74.55,38.48 74.8,38.48 77.98,41.66 77.98,44.45 78.99,45.47 79.68,45.47 80.74,46.53 80.74,46.54 80.98,46.78 81.6,46.78 81.62,46.77 82.19,46.77 U42.AG26
  L12-SIGNAL w0.089: v1(74.04,37.97) 73.53,37.97 69.74,34.18 69.74,34.05 69.86,33.92 69.86,33.8 69.74,33.67 69.3,33.67 69.22,33.58 69.22,32.26 69.33,32.15 69.33,31.99 69.2,31.86 69.07,31.86 68.82,32.12 68.69,32.12 68.57,31.99 68.57,31.87 68.82,31.61 68.82,31.49 68.7,31.36 68.57,31.36 68.32,31.61 68.19,31.61 68.06,31.49 68.06,31.36 68.32,31.11 68.32,30.98 68.19,30.86 68.07,30.86 67.81,31.11 67.69,31.11 67.56,30.99 66.55,30.99 66.35,30.79 66.35,29.88 66.43,29.79 66.97,29.79 67.06,29.7 67.06,29.52 66.97,29.43 66.43,29.43 66.35,29.35 66.35,29.17 66.43,29.08 66.97,29.08 67.06,28.99 67.06,28.81 66.97,28.72 66.43,28.72 66.35,28.63 66.35,28.46 66.43,28.37 66.97,28.37 67.06,28.28 67.06,28.1 66.97,28.01 66.43,28.01 66.35,27.92 66.35,27.56 66.24,27.45 66.24,27.44 v1(65.97,27.18)
H_DDR1_DQM1: length 34.1
  TOP w0.132: U42.AC24 v1(85.38,48.36) ; U59.D3 v1(63.57,27.98)
  L14-SIGNAL w0.109: v1(85.38,48.36) 85.78,47.96 85.78,46.28 75.31,35.81 74.04,35.81 73.53,35.31 69.34,35.31 64.39,30.35 64.39,28.8 v1(63.57,27.98)
H_DDR1_DQM2: length 27.7
  TOP w0.132: U42.AB26 v1(86.18,46.76) ; U60.E7 v1(78.67,27.18)
  L12-SIGNAL w0.089: v1(86.18,46.76) 86.18,43.64 84.07,41.53 84.07,36.83 80.77,33.53 80.14,33.53 79.79,33.87 79.67,33.87 79.54,33.75 79.54,33.62 79.89,33.28 79.89,33.15 79.12,32.38 79.12,32.26 79.38,32 79.38,31.88 79.25,31.75 79.12,31.75 78.87,32.01 78.74,32.01 78.62,31.88 78.62,31.76 78.87,31.5 78.87,31.37 78.75,31.25 78.62,31.25 78.37,31.5 78.24,31.5 78.11,31.37 78.11,27.37 78.3,27.18 v1(78.67,27.18)
H_DDR1_DQM3: length 26.6
  TOP w0.132: U60.D3 v1(76.27,27.98) ; v1(82.68,36.2) 83.19,36.2 85.85,38.86 85.85,39.62 87.38,41.15 87.38,42.55 87.78,42.95 87.78,45.96 U42.Y27
  BOTTOM w0.132: v1(82.68,36.2) 78.61,36.2 77.6,35.18 77.6,34.29 76.83,33.53 76.83,28.54 v1(76.27,27.98)
H_DDR1_DQS0_N: length 36.2
  TOP w0.099: U42.AG25 82.2,47.58 81.45,47.58 81.36,47.67 80.82,47.67 79.36,46.22 78.72,46.22 76.72,44.21 76.72,41.04 74.8,39.12 74.3,39.12 v1(74.17,38.99) ; U59.G3 v1(63.57,25.58)
  L12-SIGNAL w0.086: v1(63.57,25.58) 64.49,25.58 65.33,26.42 65.33,30.99 66.04,31.7 66.91,31.7 67.15,31.46 67.53,31.46 67.83,31.76 67.83,32.14 67.44,32.52 67.44,32.64 67.56,32.77 67.69,32.77 67.97,32.48 68.35,32.48 68.75,32.88 68.75,34.23 70.96,36.44 70.96,37.25 71.2,37.5 71.84,37.5 73.33,38.99 v1(74.17,38.99)
H_DDR1_DQS0_P: length 36.2
  TOP w0.099: v1(74.17,39.75) 74.17,39.48 74.27,39.38 74.69,39.38 76.45,41.15 76.45,44.32 78.61,46.48 79.25,46.48 80.71,47.94 81.36,47.94 81.38,47.96 U42.AH25 ; U59.F3 v1(63.57,26.38)
  L12-SIGNAL w0.086: v1(74.17,39.75) 74.17,39.47 74.07,39.38 74.01,39.38 73.93,39.29 73.2,39.29 71.71,37.8 71.08,37.8 70.66,37.38 70.66,36.57 68.44,34.36 68.44,33.01 68.22,32.79 68.1,32.79 67.81,33.07 67.44,33.07 67.14,32.77 67.14,32.4 67.52,32.01 67.52,31.89 67.4,31.76 67.28,31.76 67.04,32 65.91,32 65.02,31.11 65.02,26.54 64.36,25.88 63.79,25.88 63.57,26.11 v1(63.57,26.38)
H_DDR1_DQS1_N: length 35.7
  TOP w0.099: U59.B7 v1(65.97,29.58) ; v1(77.09,34.42) 77.06,34.44 77.06,34.68 77.16,34.78 77.25,34.78 77.36,34.88 77.81,34.88 83.83,40.91 83.83,42.18 85.67,44.02 85.67,45.45 U42.AC28
  L14-SIGNAL w0.089: v1(77.09,34.42) 77.09,34.7 77,34.79 76.93,34.79 76.77,34.95 76.35,34.95 75.84,34.44 74.74,34.44 74.65,34.35 74.65,33.7 74.43,33.48 74.06,33.48 73.84,33.7 73.84,34.24 73.63,34.44 70.56,34.44 70.47,34.35 70.47,33.6 70.25,33.38 69.88,33.38 69.66,33.6 69.66,34.35 69.57,34.44 69.37,34.44 65.02,30.1 65.02,29.28 65.3,29.01 65.68,29.01 65.82,29.15 65.88,29.15 65.97,29.23 v1(65.97,29.58)
H_DDR1_DQS1_P: length 35.7
  TOP w0.099: U42.AC27 85.4,45.98 85.4,44.13 83.57,42.29 83.57,41.02 77.73,35.18 v1(77.09,35.18) ; U59.C7 v1(65.97,28.78)
  L14-SIGNAL w0.089: v1(77.09,35.18) 76.26,35.18 75.75,34.67 74.65,34.67 74.43,34.45 74.43,33.79 74.34,33.71 74.16,33.71 74.07,33.79 74.07,34.33 73.73,34.67 70.47,34.67 70.24,34.45 70.24,33.69 70.15,33.6 69.98,33.6 69.89,33.69 69.89,34.45 69.67,34.67 69.27,34.67 64.8,30.19 64.8,29.18 65.2,28.78 v1(65.97,28.78)
H_DDR1_DQS2_N: length 29.1
  TOP w0.099: U60.G3 v1(75.47,25.58) ; U42.AB28 86.47,45.45 86.47,43.68 85.74,42.94 85.74,41.55 83.82,39.63 83.82,39.05 83.34,38.58 82.39,38.58 82.04,38.23 82.04,37.34 82.17,37.21 v1(82.45,37.21)
  L12-SIGNAL w0.086: v1(82.45,37.21) 82.16,36.91 82.16,36.46 81.89,36.2 80.57,36.2 79.49,35.11 79.11,35.11 78.65,35.58 78.53,35.58 78.4,35.45 78.4,35.33 78.89,34.84 78.89,34.42 77.01,32.54 77.01,26.34 76.58,25.91 75.8,25.91 v1(75.47,25.58)
H_DDR1_DQS2_P: length 29.1
  TOP w0.099: U42.AB27 86.2,45.98 86.2,43.79 85.47,43.05 85.47,41.66 83.55,39.74 83.55,39.16 83.23,38.84 82.28,38.84 81.78,38.34 81.78,37.33 81.66,37.21 v1(81.66,37.21) ; U60.F3 v1(75.47,26.38)
  L12-SIGNAL w0.086: v1(81.66,37.21) 81.85,37.02 81.85,36.59 81.77,36.5 80.44,36.5 79.36,35.42 79.24,35.42 78.78,35.88 78.4,35.88 78.1,35.58 78.1,35.2 78.59,34.72 78.59,34.54 76.71,32.66 76.71,26.47 76.45,26.21 75.63,26.21 v1(75.47,26.38)
H_DDR1_DQS3_N: length 26.7
  TOP w0.099: U60.B7 v1(78.67,29.58) ; U42.W27 88.6,45.98 88.6,45.38 88.71,45.27 88.71,42.61 88.13,42.02 88.13,40.37 87.63,39.87 87.63,38.48 83.99,34.84 81.08,34.84 80.95,34.97 80.62,34.97 80.38,34.73 80.38,34.04 v1(80.39,34.04)
  BOTTOM w0.099: v1(80.39,34.04) 79.38,34.04 79.27,33.93 79.27,33.79 79.65,33.41 79.65,33.04 79.35,32.75 78.99,32.75 78.61,33.13 78.47,33.13 77.98,32.64 77.98,29.84 78.25,29.58 v1(78.67,29.58)
H_DDR1_DQS3_P: length 26.7
  TOP w0.099: v1(80.78,34.57) 84.1,34.57 87.9,38.37 87.9,39.76 88.39,40.26 88.39,41.91 88.98,42.5 U42.W28 ; U60.C7 v1(78.67,28.78)
  BOTTOM w0.099: v1(78.67,28.78) 78.67,29.15 78.61,29.21 78.52,29.21 78.42,29.31 78.14,29.31 77.71,29.73 77.71,32.75 78.36,33.4 78.72,33.4 79.1,33.01 79.24,33.01 79.38,33.16 79.38,33.3 79,33.68 79,34.04 79.26,34.3 80.12,34.3 80.23,34.42 80.63,34.42 v1(80.78,34.57)
H_DDR1_ECC_D0: length 25.5
  TOP w0.132: U63.E8 v1(92.97,24.78) ; U42.U25 v1(90.18,47.56)
  L12-SIGNAL w0.089: v1(90.18,47.56) 90.6,47.15 90.6,45.17 91.19,44.58 91.19,25.91 91.94,25.15 92.6,25.15 v1(92.97,24.78)
H_DDR1_ECC_D1: length 25.3
  TOP w0.132: U63.E7 v1(92.17,24.78) ; U42.U26 v1(90.18,46.76)
  L12-SIGNAL w0.089: v1(92.17,24.78) 91.76,24.78 91.24,25.3 90.63,25.3 89.92,26.01 89.92,26.8 90.81,27.69 90.81,37.97 90.18,38.6 v1(90.18,46.76)
H_DDR1_ECC_D2: length 25.3
  TOP w0.132: U42.V25 v1(89.38,47.56) ; U63.C2 v1(87.37,26.38)
  L12-SIGNAL w0.089: v1(87.37,26.38) 86.99,26.75 86.28,26.75 85.98,27.05 85.98,31.37 87.5,32.89 87.93,32.89 88.77,33.73 88.77,38.1 89.41,38.73 89.41,45.85 89.79,46.23 89.79,47.15 v1(89.38,47.56)
H_DDR1_ECC_D3: length 25.3
  TOP w0.132: U63.D2 v1(87.37,25.58) ; U42.V26 v1(89.38,46.76)
  L12-SIGNAL w0.089: v1(89.38,46.76) 88.27,45.64 88.27,36.2 87.76,35.69 87.4,35.69 85.47,33.76 85.47,26.82 86.29,26 86.94,26 v1(87.37,25.58)
H_DDR1_ECC_D4: length 27.2
  TOP w0.132: v1(88.27,31.62) 88.27,33.27 88.9,33.91 88.9,37.97 89.53,38.6 89.53,44.97 89.39,45.1 89.39,45.97 U42.V27 ; U63.E3 v1(88.17,24.78)
  L12-SIGNAL w0.089: v1(88.17,24.78) 88.17,26.38 87.76,26.8 87.76,28.35 87.67,28.44 86.7,28.44 86.61,28.53 86.61,28.71 86.7,28.8 87.67,28.8 87.76,28.89 87.76,29.07 87.67,29.15 86.75,29.15 86.66,29.24 86.66,30.66 87.63,31.62 v1(88.27,31.62)
H_DDR1_ECC_D5: length 28.1
  TOP w0.132: v1(93.6,30.23) 92.07,30.23 91.82,30.48 91.82,30.97 91.95,31.11 92.36,31.11 92.49,31.24 92.49,31.5 92.36,31.63 91.83,31.63 91.69,31.77 91.69,32.03 91.83,32.16 92.36,32.16 92.49,32.29 92.49,32.56 92.36,32.69 91.83,32.69 91.69,32.82 91.69,33.09 91.83,33.22 92.36,33.22 92.49,33.35 92.49,33.62 92.36,33.75 91.83,33.75 91.69,33.88 91.69,34.14 91.83,34.28 92.36,34.28 92.49,34.41 92.49,34.67 92.36,34.8 91.83,34.8 91.69,34.94 91.69,35.2 91.83,35.33 92.36,35.33 92.49,35.46 92.49,38.57 92.14,38.92 92.14,42.86 91.38,43.62 U42.T28 ; U63.C8 v1(92.97,26.38)
  L12-SIGNAL w0.089: v1(92.97,26.38) 93.35,26.75 93.35,28.32 94.03,29.01 94.03,29.79 v1(93.6,30.23)
H_DDR1_ECC_D6: length 25.2
  TOP w0.132: U63.C7 v1(92.17,26.38) ; U42.T26 v1(90.98,46.76)
  L12-SIGNAL w0.089: v1(92.17,26.38) 91.69,26.85 91.69,31.6 92.04,31.94 92.42,31.94 92.51,32.03 92.51,32.21 92.42,32.3 92.04,32.3 91.95,32.39 91.95,32.56 92.04,32.65 92.49,32.65 92.58,32.74 92.58,32.92 92.49,33.01 92.04,33.01 91.95,33.1 91.95,33.27 92.04,33.36 92.49,33.36 92.58,33.45 92.58,33.63 92.49,33.72 92.04,33.72 91.95,33.81 91.95,36.58 91.57,36.96 91.57,44.83 90.98,45.42 v1(90.98,46.76)
H_DDR1_ECC_D7: length 27.3
  TOP w0.132: v1(89.03,31.62) 89.03,32.04 89.16,32.17 90.29,32.17 90.42,32.3 90.42,32.57 90.29,32.7 89.16,32.7 89.03,32.83 89.03,33.27 89.28,33.53 89.28,37.72 89.92,38.35 89.92,45.03 89.78,45.17 U42.V28 ; U63.B3 v1(88.17,27.18)
  L12-SIGNAL w0.089: v1(89.03,31.62) 88.55,31.14 88.55,30.99 88.17,30.61 87.21,30.61 87.12,30.52 87.12,30.34 87.21,30.25 88.46,30.25 88.55,30.17 88.55,29.99 88.46,29.9 87.21,29.9 87.12,29.81 87.12,29.63 87.21,29.54 88.46,29.54 88.55,29.45 88.55,27.56 88.17,27.19 v1(88.17,27.18)
H_DDR1_ECC_DQM: length 26.4
  TOP w0.132: U42.T27 90.99,45.97 90.99,43.25 91.78,42.46 91.78,37.63 v1(92.08,37.34) ; U63.B7 v1(92.17,27.18)
  L12-SIGNAL w0.089: v1(92.17,27.18) 92.6,27.6 92.6,28.13 93.09,28.63 93.09,28.82 93,28.91 92.42,28.91 92.33,29 92.33,29.17 92.42,29.26 93,29.26 93.09,29.35 93.09,29.53 93,29.62 92.42,29.62 92.33,29.71 92.33,29.89 92.42,29.97 93,29.97 93.09,30.06 93.09,30.24 93,30.33 92.42,30.33 92.33,30.42 92.33,30.6 92.42,30.69 93,30.69 93.09,30.77 93.09,30.95 93,31.04 92.52,31.04 92.43,31.13 92.43,31.31 92.52,31.4 93,31.4 93.34,31.74 93.34,36.07 v1(92.08,37.34)
H_DDR1_ECC_DQS_N: length 26.6
  TOP w0.099: U63.D3 88.57,25.18 v1(88.97,25.58) ; v1(90.42,36.16) 90.3,36.28 90.3,37.6 91.45,38.75 91.45,42.08 90.56,42.97 90.56,45.54 U42.U28
  L12-SIGNAL w0.086: v1(90.42,36.16) 90.17,35.9 90.17,33.35 89.6,32.79 89.16,32.79 89.08,32.7 89.08,32.53 89.16,32.44 90.03,32.44 90.3,32.17 90.3,31.5 89.33,30.53 89.33,30.28 89.42,30.19 89.91,30.19 90.17,29.93 90.17,29.5 89.91,29.24 89.37,29.24 89.28,29.15 89.28,28.98 89.37,28.89 89.91,28.89 90.17,28.63 90.17,28.2 89.91,27.94 89.37,27.94 89.28,27.85 89.28,26.6 89.34,26.53 89.34,26.22 89.13,26 89.06,26 88.97,25.92 v1(88.97,25.58)
H_DDR1_ECC_DQS_P: length 26.6
  TOP w0.099: U42.U27 90.2,45.98 90.2,45.4 90.3,45.31 90.3,42.86 91.18,41.97 91.18,38.86 90.03,37.71 90.03,36.53 v1(89.7,36.2) ; U63.C3 v1(88.97,26.38)
  L12-SIGNAL w0.086: v1(88.97,26.38) 88.97,26.38 88.97,26.47 88.98,26.47 88.98,27.98 89.24,28.24 89.78,28.24 89.87,28.33 89.87,28.5 89.78,28.59 89.24,28.59 88.98,28.85 88.98,29.28 89.24,29.54 89.78,29.54 89.87,29.63 89.87,29.8 89.78,29.89 89.29,29.89 89.03,30.15 89.03,30.66 89.99,31.62 89.99,32.05 89.91,32.13 89.04,32.13 88.77,32.4 88.77,32.83 89.04,33.09 89.48,33.09 89.87,33.48 89.87,36.03 v1(89.7,36.2)
H_DDR1_ODT0: length 100
  TOP w0.132: U42.AF22 v1(82.98,49.96) ; RN2.1 v1(96.39,24.44) ; U63.G1 v1(86.57,22.38) ; U59.K1 v1(61.17,22.38) ; U60.K1 v1(73.87,22.38)
  L12-SIGNAL w0.089: v1(82.98,49.96) 81.33,49.96 77.85,46.48 73.41,46.48 69.09,42.16 69.09,40.13 68.83,39.88 66.67,39.88 66.53,39.73 66.53,39.61 67.17,38.97 67.17,38.85 67.04,38.72 66.92,38.72 66.28,39.36 66.15,39.36 66.03,39.23 66.03,39.11 66.66,38.47 66.66,38.34 66.54,38.22 66.41,38.22 65.78,38.85 65.65,38.85 65.52,38.73 65.52,38.6 66.16,37.97 66.16,37.84 66.04,37.71 65.91,37.71 65.27,38.35 65.15,38.35 65.02,38.22 65.02,38.1 65.66,37.46 65.66,37.34 65.53,37.21 65.41,37.21 64.77,37.85 64.64,37.85 64.52,37.72 64.52,37.6 65.16,36.96 65.16,36.83 65.03,36.71 64.9,36.71 64.27,37.34 64.14,37.34 64.02,37.22 64.02,37.09 64.65,36.46 64.65,36.33 64.53,36.21 64.4,36.21 63.76,36.84 63.13,36.84 62.99,36.7 62.99,35.94 63.25,35.69 v1(63.75,35.69)
  L14-SIGNAL w0.109: v1(63.75,35.69) 63.75,34.54 60.07,30.86 60.07,23.48 v1(61.17,22.38) ; v1(86.57,22.38) 86.97,21.98 92.8,21.98 92.81,21.98 93.13,21.98 93.14,21.97 93.98,21.97 94.49,22.48 94.49,22.99 95.95,24.44 v1(96.39,24.44)
  BOTTOM w0.132: v1(86.57,22.38) 86.57,22.88 86.11,23.34 80.77,23.34 80.65,23.22 80.65,23.02 80.43,22.8 79.63,22.8 79.63,22.8 79.31,22.8 78.94,23.16 78.72,23.16 78.58,23.03 78.58,22.89 78.45,22.76 78.19,22.76 78.06,22.89 78.06,23.03 77.92,23.16 77.17,23.16 75.98,21.98 74.27,21.98 v1(73.87,22.38) 73.59,22.1 73,22.1 71.75,23.34 68.33,23.34 67.79,22.8 67.76,22.8 67.73,22.78 66.93,22.78 66.5,22.78 66.14,23.14 65.59,23.14 65.45,23.01 65.45,22.79 65.32,22.66 65.06,22.66 64.93,22.79 64.93,23.01 64.79,23.14 64.57,23.14 63.41,21.98 61.57,21.98 v1(61.17,22.38)
H_DDR1_RASN: length 100
  TOP w0.132: U63.F3 v1(88.17,23.18) ; U59.J3 v1(62.77,23.18) ; v1(66.55,44.59) 66.55,45.05 66.42,45.18 65.79,45.18 65.66,45.31 65.66,45.58 65.79,45.71 66.42,45.71 66.55,45.84 66.55,46.61 70.1,50.16 73.15,50.16 74.39,51.41 75.34,51.41 75.44,51.31 77.38,51.31 78.3,52.23 78.83,52.23 79.1,51.96 U42.AH20 ; U60.J3 v1(75.47,23.18)
  L12-SIGNAL w0.089: v1(88.17,23.18) 89.95,23.18 90.37,23.6 94.04,23.6 v1(95.29,24.84) ; v1(66.55,44.59) 66.04,44.08 66.04,42.04 61.34,37.34 61.34,37.22 61.66,36.9 61.66,36.77 61.54,36.65 61.41,36.65 61.09,36.96 60.97,36.96 60.84,36.84 60.84,36.71 61.16,36.39 61.16,36.27 61.03,36.14 60.91,36.14 60.59,36.46 60.46,36.46 60.34,36.34 60.34,36.21 60.66,35.89 60.66,35.77 60.53,35.64 60.41,35.64 60.09,35.96 59.96,35.96 59.82,35.81 59.82,35.28 59.91,35.19 60.11,35.19 60.2,35.1 60.2,34.93 60.11,34.84 59.91,34.84 59.82,34.75 59.82,34.57 59.91,34.48 60.11,34.48 60.2,34.39 60.2,34.21 60.11,34.13 59.91,34.13 59.18,33.4 59.18,32.77 59.27,32.68 60.36,32.68 60.45,32.59 60.45,32.41 60.36,32.32 59.27,32.32 59.18,32.23 59.18,32.05 59.27,31.97 60.36,31.97 60.45,31.88 60.45,31.7 60.36,31.61 59.27,31.61 59.18,31.52 59.18,31.34 59.27,31.25 60.36,31.25 60.45,31.17 60.45,30.99 60.36,30.9 59.27,30.9 59.18,30.81 59.18,30.61 59.85,29.94 59.85,29.39 59.56,29.11 59.56,28.7 60.45,27.81 60.45,24.51 61.41,23.55 62.4,23.55 v1(62.77,23.18)
  BOTTOM w0.132: v1(95.29,24.84) 96.57,24.84 96.97,24.44 RN11.4 ; v1(62.77,23.18) 63.31,23.18 64.51,24.38 67.54,24.38 67.82,24.1 74.93,24.1 75.47,23.57 v1(75.47,23.18) 75.86,23.18 76.65,23.97 76.65,24.71 77.14,25.2 77.71,25.2 78.51,24.4 80.23,24.4 80.52,24.1 87.4,24.1 87.89,23.61 87.89,23.45 v1(88.17,23.18)
H_DDR1_RST: length 31.9
  TOP w0.132: v1(87.37,17.58) U63.N2 ; U60.T2 v1(74.67,17.58) ; R296.1 R292.1 61.97,17.14 v1(61.97,17.58) U59.T2
  BOTTOM w0.132: v1(87.37,17.58) 86.56,16.76 75.48,16.76 v1(74.67,17.58) 73.86,16.76 62.78,16.76 v1(61.97,17.58)
H_DDR1_WEN: length 100.6
  TOP w0.132: U63.H3 v1(88.17,21.58) ; v1(64.64,42.93) 64.94,42.63 68.67,42.63 68.84,42.81 68.84,42.99 68.33,43.51 68.33,43.69 68.52,43.88 68.7,43.88 69.22,43.37 69.4,43.37 69.59,43.55 69.59,43.74 69.08,44.25 69.08,44.44 69.26,44.63 69.45,44.63 69.96,44.11 70.15,44.11 72.9,46.86 76.07,46.86 77.98,48.77 78.87,48.77 80.06,49.96 82.18,49.96 U42.AG22 ; U60.L3 v1(75.47,21.58) ; U59.L3 v1(62.77,21.58)
  L12-SIGNAL w0.089: v1(64.64,42.93) 64.37,42.65 64.37,42.53 64.88,42.02 64.88,41.89 64.75,41.76 64.63,41.76 64.12,42.27 63.99,42.27 63.87,42.15 63.87,42.02 64.38,41.51 64.38,41.39 64.25,41.26 64.12,41.26 63.61,41.77 63.49,41.77 63.36,41.65 63.36,41.52 63.87,41.01 63.87,40.89 63.75,40.76 63.62,40.76 63.11,41.27 62.99,41.27 62.86,41.14 62.86,41.02 63.37,40.51 63.37,40.38 63.24,40.26 63.12,40.26 62.61,40.77 62.48,40.77 60.71,38.99 60.71,37.85 58.8,35.94 58.8,35.18 58.42,34.8 58.42,28.19 58.67,27.94 59.05,27.94 59.31,27.69 59.31,25.02 59.72,24.61 59.72,23.48 59.63,23.39 58.89,23.39 58.8,23.3 58.8,23.12 58.89,23.03 59.63,23.03 59.72,22.94 59.72,22.45 59.94,22.23 60.58,22.23 60.85,21.95 62.4,21.95 v1(62.77,21.58)
  BOTTOM w0.132: v1(62.77,21.58) 63.67,21.58 64.07,21.98 68.71,21.98 69.09,22.35 72.26,22.35 72.92,21.69 73.91,21.69 74.42,21.18 74.5,21.18 74.51,21.18 74.83,21.18 74.84,21.18 75.08,21.18 v1(75.47,21.58) 76.16,21.58 76.96,22.38 78.82,22.38 79.2,22 80.11,22 81.36,22 81.72,22.36 83.84,22.36 84.42,22.94 84.68,22.94 84.81,22.8 84.81,22.49 84.94,22.36 85.21,22.36 85.34,22.49 85.34,22.8 85.47,22.94 85.74,22.94 85.87,22.8 85.87,22.49 86.38,21.97 87.77,21.97 v1(88.17,21.58) 90.17,23.58 96.84,23.58 97.04,23.37 RN11.2
H_DDR2_A0: length 77
  TOP w0.132: U62.K3 127,20.97 127.14,20.83 TP2MB15.1 ; U42.P25 v1(93.38,47.56) ; U61.K3 112.65,20.97 112.79,20.83 TP2MA15.1
  L12-SIGNAL w0.089: TP2MA15.1 113.16,20.83 113.03,20.7 112.52,20.7 111.38,21.84 106.43,21.84 104.52,23.75 104.52,26.92 103.12,28.32 103.12,29.47 102.37,30.23 v1(101.98,30.23)
  L14-SIGNAL w0.109: v1(101.98,30.23) 100.97,31.24 99.82,31.24 99.57,31.5 97.9,31.5 97.79,31.61 97.79,32.02 97.68,32.13 97.47,32.13 97.36,32.02 97.36,31.57 97.03,31.24 96.39,31.24 93.6,34.04 93.6,44.07 94.23,44.7 94.23,45.09 93.79,45.53 93.79,47.16 v1(93.38,47.56) ; TP2MA15.1 114.17,20.83 114.33,20.68 116.99,20.68 117.27,20.95 122.65,20.95 122.78,20.83 123.7,20.83 124.34,20.19 125.63,20.19 126.27,20.83 TP2MB15.1 128.52,20.83 128.65,20.7 131.19,20.7 131.44,20.95 133.35,20.95 133.74,20.57 134.5,20.57 134.87,20.19 134.87,19.94 135.25,19.56 v1(136.14,19.56)
  BOTTOM w0.132: U137.K3 115.07,20.97 114.78,20.68 114.38,20.68 114.22,20.83 TP2MA15.1 ; U136.K3 129.43,20.97 129.13,20.68 128.73,20.68 128.57,20.83 TP2MB15.1 ; v1(136.14,19.56) 136.91,19.56 137.36,20.01 RN12.1
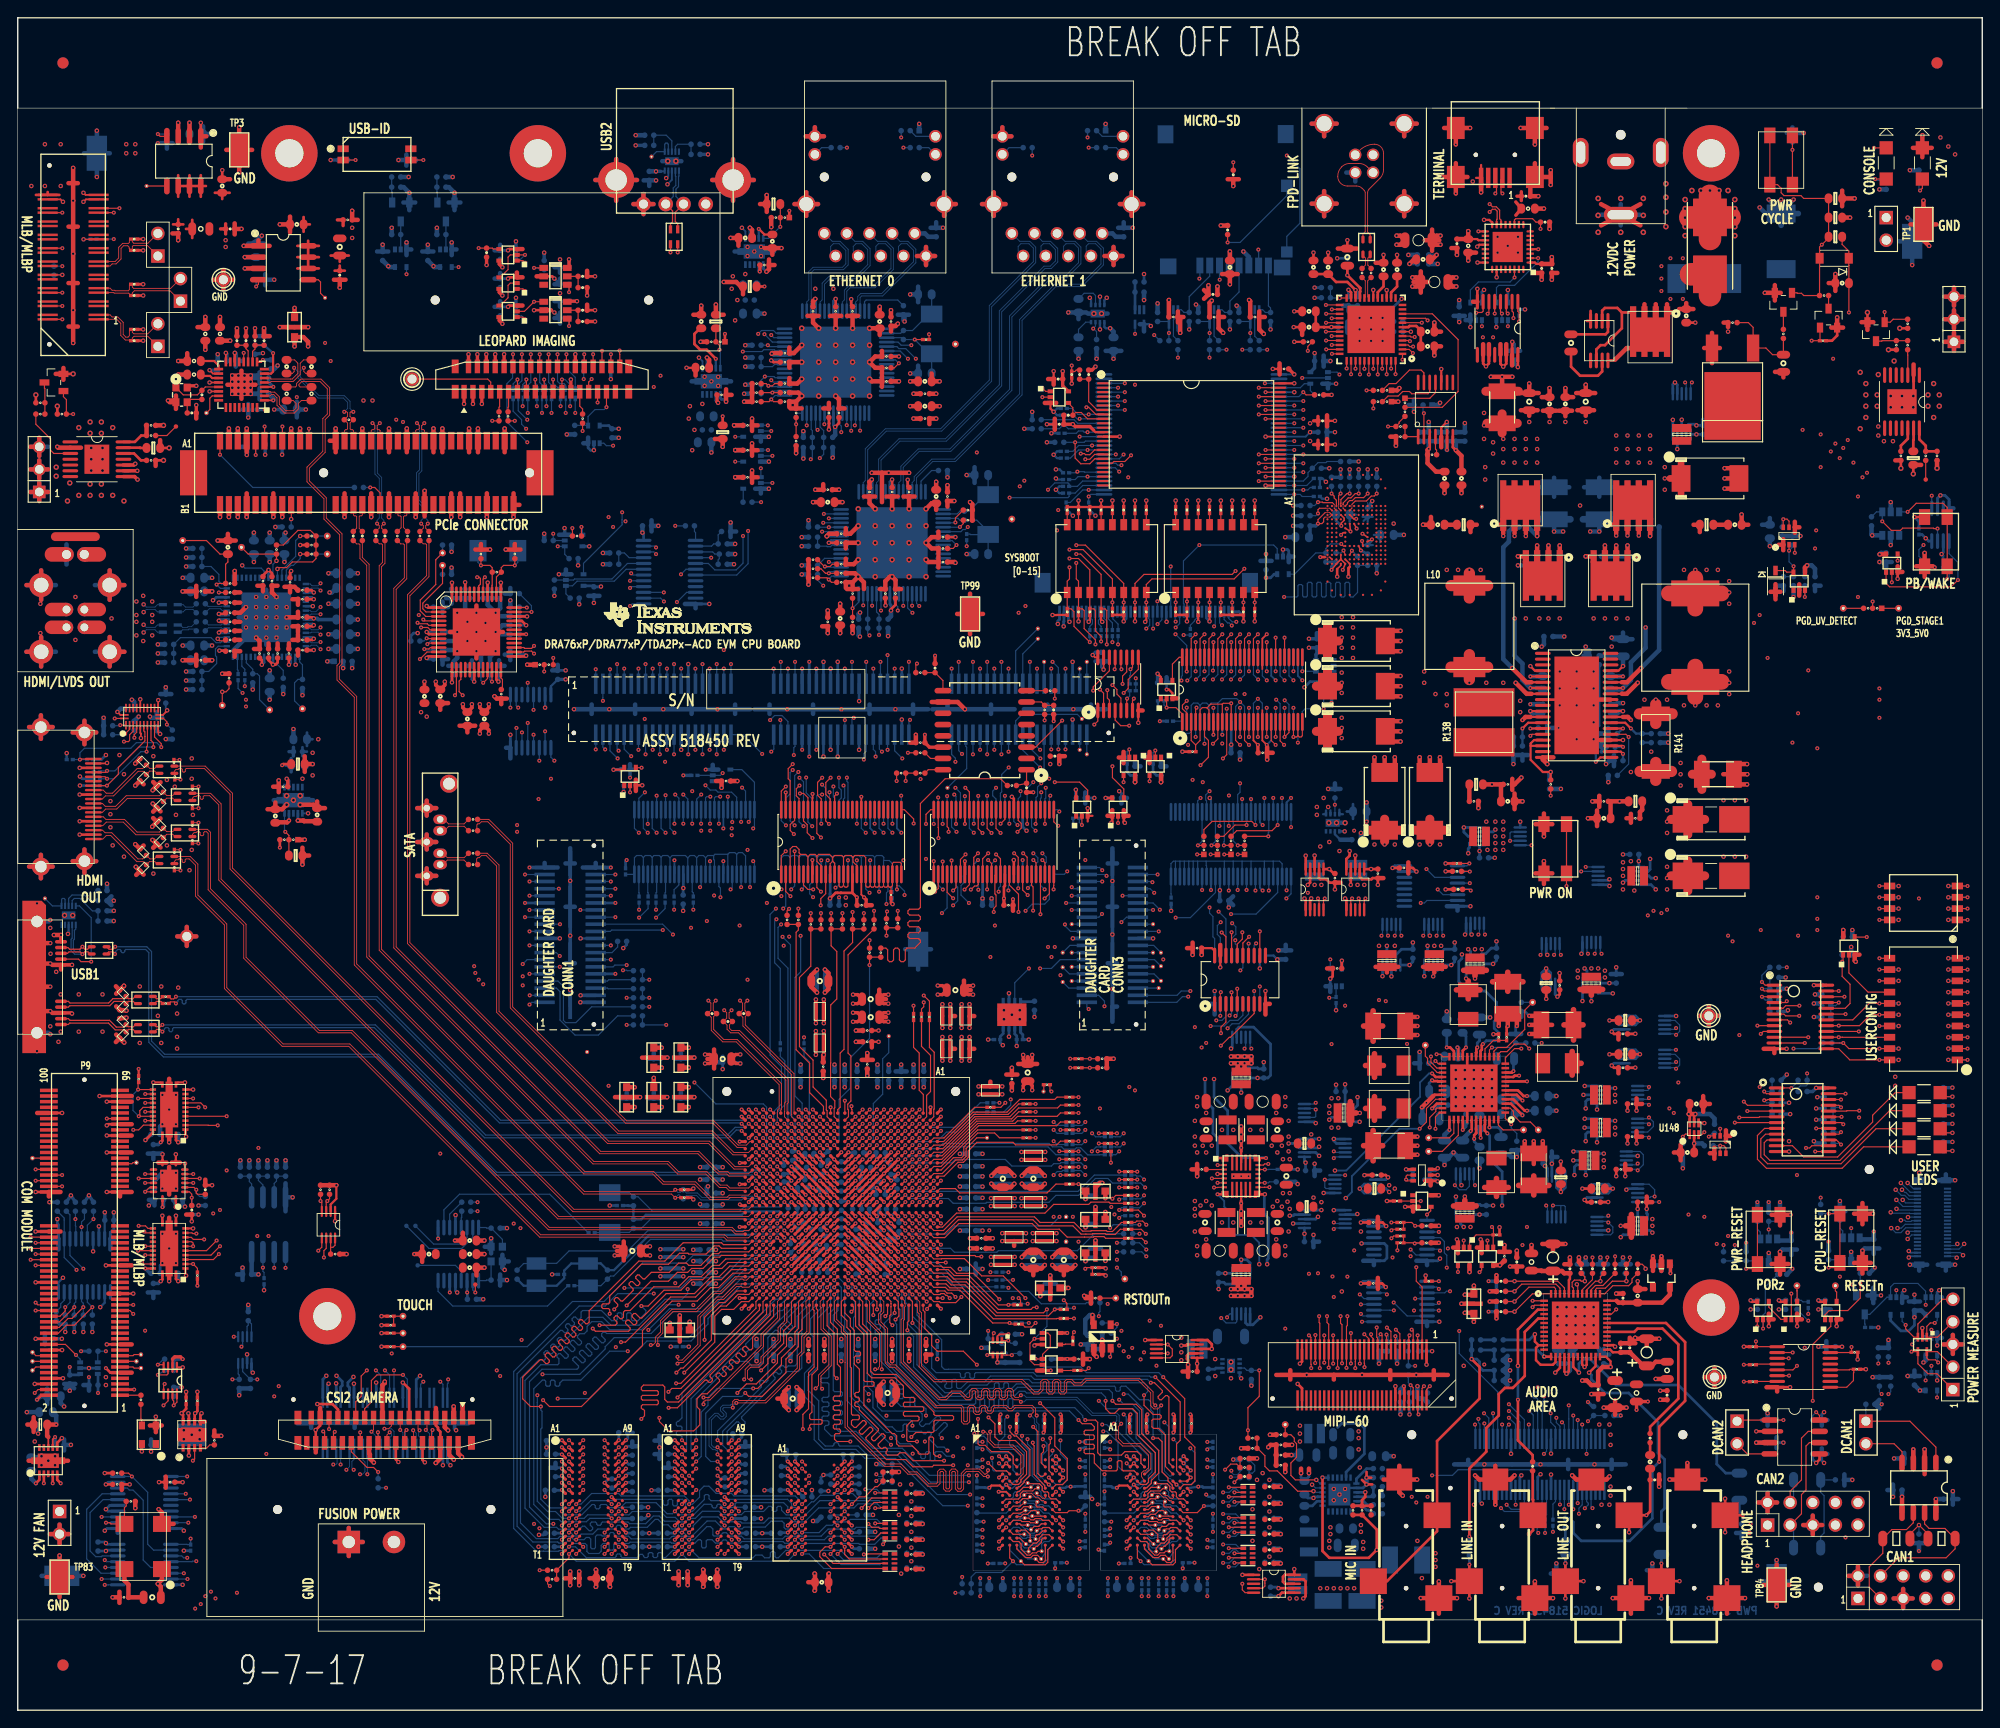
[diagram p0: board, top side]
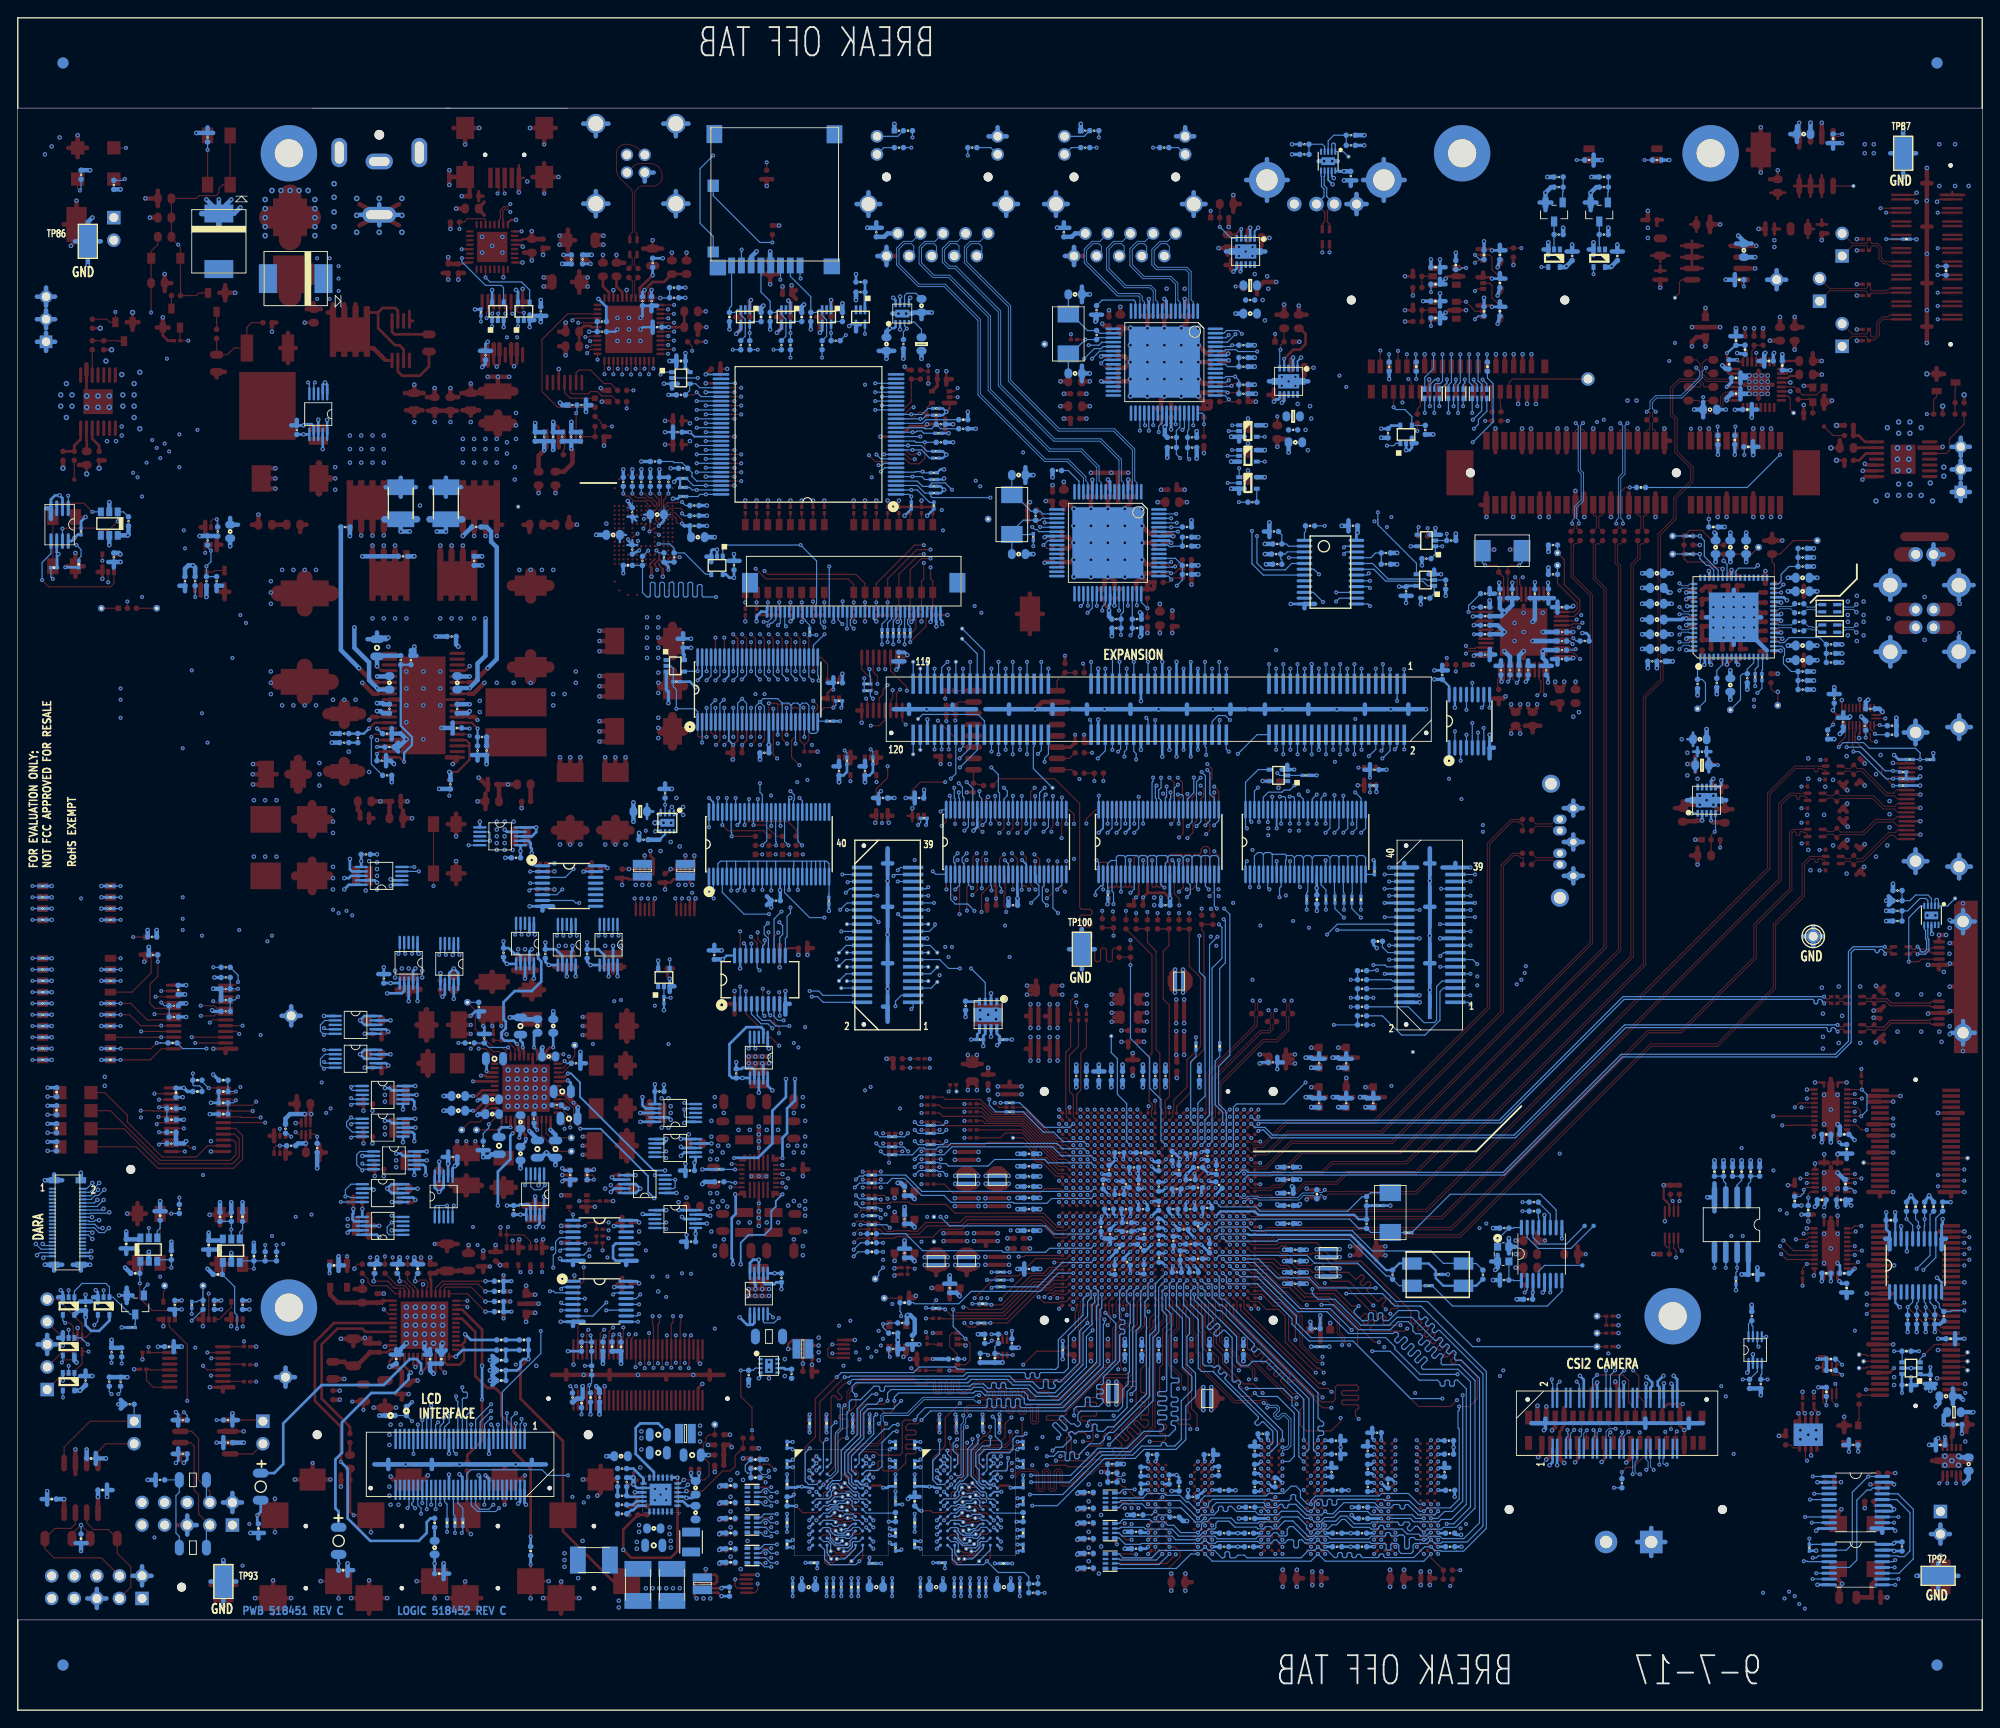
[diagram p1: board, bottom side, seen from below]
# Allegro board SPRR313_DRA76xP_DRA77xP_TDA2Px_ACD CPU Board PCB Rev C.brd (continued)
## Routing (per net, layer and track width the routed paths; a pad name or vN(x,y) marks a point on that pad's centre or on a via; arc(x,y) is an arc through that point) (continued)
H_DDR2_A1: length 77.4
  TOP w0.132: TP2MB19.1 128.78,19.63 128.91,19.76 129.18,19.76 129.58,20.17 U62.L7 ; U42.P26 v1(93.38,46.76) ; TP2MA19.1 114.43,19.63 114.55,19.76 114.82,19.76 115.23,20.17 U61.L7
  L12-SIGNAL w0.089: v1(100.61,28.86) 103.76,25.71 103.76,23.11 107.06,19.81 111.63,19.81 112.06,19.38 113.49,19.38 113.67,19.56 114.12,19.56 TP2MA19.1
  L14-SIGNAL w0.109: v1(135.51,18.64) 133.94,18.64 133.89,18.7 132.88,18.7 132.23,19.35 129.91,19.35 129.82,19.25 TP2MB19.1 128.4,19.43 127.89,19.43 127.76,19.3 127.3,19.3 126.95,19.66 126.59,19.66 126.32,19.39 123.65,19.39 123.49,19.23 119.87,19.23 119.71,19.39 117.14,19.39 116.84,19.68 114.86,19.68 TP2MA19.1 ; v1(93.38,46.76) 93.38,45.38 92.16,44.15 92.16,38.4 92.58,37.97 92.58,33.78 97.79,28.57 100.33,28.57 v1(100.61,28.86)
  BOTTOM w0.132: RN14.4 137.35,18.22 136.93,18.64 v1(135.51,18.64) ; U137.L7 112.65,19.84 112.65,19.68 113,19.33 113.37,19.33 113.5,19.46 114.22,19.46 TP2MA19.1 ; TP2MB19.1 128.57,19.46 127.85,19.46 127.72,19.33 127.36,19.33 127,19.68 127,19.84 U136.L7
H_DDR2_A2: length 84.8
  TOP w0.132: TP2MA20.1 113.82,19.76 113.31,20.27 112.8,20.27 112.7,20.17 U61.L3 ; U42.P28 92.98,44.68 93.6,44.07 93.6,43.18 94.05,42.73 94.05,40.5 94.18,40.37 94.61,40.37 94.74,40.24 94.74,39.97 94.61,39.84 94.18,39.84 94.05,39.71 94.05,38.92 94.61,38.35 94.61,35.88 94.48,35.75 94.24,35.75 94.11,35.61 94.11,35.35 94.24,35.22 94.48,35.22 94.61,35.09 94.61,34.82 94.48,34.69 94.24,34.69 94.11,34.56 94.11,34.29 94.24,34.16 94.48,34.16 94.61,34.03 94.61,33.78 96.75,31.65 96.75,31.46 95.99,30.69 95.99,30.51 96.17,30.32 96.36,30.32 97.12,31.09 97.31,31.09 97.5,30.9 97.5,30.71 96.73,29.95 96.73,29.76 97.05,29.44 97.24,29.44 97.37,29.57 97.56,29.57 97.75,29.38 97.75,29.19 97.62,29.06 97.62,28.88 97.79,28.7 98.91,28.7 99.16,28.96 99.77,28.96 100.66,28.07 v1(104.14,28.07) ; U62.L3 127.05,20.17 127.15,20.27 127.66,20.27 128.17,19.76 TP2MB20.1 ; RN3.3 v1(136.15,20.58)
  L12-SIGNAL w0.089: TP2MA20.1 114.05,18.82 116.56,18.82 117.11,19.37 118,19.37 118.09,19.28 118.09,19.15 118.2,19.05 118.4,19.05 118.5,19.15 118.5,19.28 118.6,19.38 119.96,19.38 120.78,20.19 121.11,20.19 122,19.3 123.85,19.3 124.05,19.51 125.02,19.51 125.32,19.2 127.76,19.2 TP2MB20.1 128.41,18.81 131.32,18.81 131.55,18.58 132.62,18.58 133.6,19.56 135.6,19.56 136.15,20.11 v1(136.15,20.58)
  L14-SIGNAL w0.109: TP2MA20.1 113.59,19.27 112.42,19.27 111.79,19.91 107.98,19.91 104.9,22.99 104.9,26.42 104.14,27.18 v1(104.14,28.07)
  BOTTOM w0.132: U137.L3 115.14,19.79 115.14,19.39 114.54,18.8 114.07,18.8 TP2MA20.1 ; U136.L3 129.49,19.79 129.49,19.39 128.9,18.8 128.42,18.8 TP2MB20.1
H_DDR2_A3: length 84.7
  TOP w0.132: U61.K2 111.91,21.36 112.75,21.36 112.89,21.22 113.72,21.22 113.86,21.08 114.48,21.08 TP2MA14.1 ; U42.P27 92.59,45.97 92.59,44.44 93.22,43.81 93.22,43.05 93.6,42.67 93.6,38.61 93.73,38.48 93.73,33.33 93.86,33.2 94.48,33.2 94.61,33.07 94.61,32.8 94.48,32.67 93.86,32.67 93.73,32.54 93.73,32.13 94.05,31.81 94.23,31.81 95,32.58 95.19,32.58 95.37,32.39 95.37,32.2 94.61,31.44 94.61,31.25 94.79,31.06 94.98,31.06 95.75,31.83 95.93,31.83 96.12,31.64 96.12,31.45 95.35,30.69 95.35,30.5 97.66,28.19 99.83,28.19 100.65,27.38 102.81,27.38 102.98,27.56 v1(105.16,27.56) ; U62.K2 126.26,21.36 127.08,21.36 127.22,21.22 128.07,21.22 128.21,21.08 128.83,21.08 TP2MB14.1 ; RN3.1 v1(136.15,21.65)
  L12-SIGNAL w0.089: v1(105.16,27.56) 105.16,23.87 106.81,22.23 111.51,22.23 112.6,21.13 113.18,21.13 113.26,21.21 113.77,21.21 113.82,21.16 TP2MA14.1 115.39,21.16 116.01,21.77 117.47,21.77 117.67,21.97 118.36,21.97 118.62,21.72 120.4,21.72 120.78,22.1 123.44,22.1 123.72,22.38 124.08,22.38 124.68,21.77 125.72,21.77 126.67,20.83 127.33,20.83 127.75,21.25 128.23,21.25 128.32,21.16 TP2MB14.1 129.46,21.16 129.67,20.95 132.97,20.95 133.66,21.65 v1(136.15,21.65)
  BOTTOM w0.132: U136.K2 130.28,21.36 129.18,21.36 TP2MB14.1 ; TP2MA14.1 114.83,21.36 115.93,21.36 U137.K2
H_DDR2_A4: length 82.9
  TOP w0.132: U62.L8 130.29,20.55 129.62,20.55 129.46,20.4 129.11,20.4 TP2MB17.1 ; TP2MA17.1 114.76,20.4 115.11,20.4 115.27,20.55 115.94,20.55 U61.L8 ; U42.P24 v1(93.38,48.36) ; RN3.4 v1(136.78,20.01)
  L14-SIGNAL w0.109: v1(104.52,29.21) 105.16,29.21 105.66,28.7 105.66,23.37 107.19,21.84 111.51,21.84 113.03,20.32 113.38,20.32 113.78,19.92 114.28,19.92 TP2MA17.1 114.94,20.19 114.96,20.17 118.21,20.17 118.62,20.57 121.54,20.57 122.05,20.07 123.57,20.07 123.83,19.81 125.98,19.81 126.34,20.17 127.67,20.17 127.91,19.92 128.64,19.92 TP2MB17.1 129.29,20.19 129.3,20.19 133.61,20.19 134.67,19.13 136.55,19.13 136.78,19.36 v1(136.78,20.01)
  BOTTOM w0.132: U136.L8 126.28,20.57 126.9,20.57 127.28,20.19 127.69,20.19 127.97,19.91 128.63,19.91 TP2MB17.1 ; U137.L8 111.93,20.57 112.55,20.57 112.93,20.19 113.33,20.19 113.61,19.91 114.27,19.91 TP2MA17.1 ; v1(104.52,29.21) 104.14,29.59 103.38,29.59 102.43,30.54 102.43,30.72 102.69,30.98 102.69,31.17 102.5,31.36 102.32,31.36 102.06,31.1 101.87,31.1 101.6,31.37 100.19,31.37 100.06,31.5 100.06,32.05 99.92,32.18 99.66,32.18 99.53,32.05 99.53,31.5 99.4,31.37 98.81,31.37 98.3,31.88 97.66,31.88 93.96,35.58 93.96,44.18 94.12,44.34 94.12,45.96 93.78,46.3 93.78,47.96 v1(93.38,48.36)
H_DDR2_A5: length 82.4
  TOP w0.132: TP2MA18.1 111.9,19.79 U61.L2 ; RN3.2 v1(136.78,21.08) ; TP2MB18.1 126.25,19.79 U62.L2 ; U42.P23 v1(93.38,49.16)
  L12-SIGNAL w0.089: v1(93.38,49.16) 92.96,48.74 92.96,43.05 93.22,42.8 93.22,38.86 96.9,35.18 96.9,33.89 v1(97.66,33.13) ; v1(136.78,21.08) 136.06,21.08 135.52,20.54 133.85,20.54 132.66,19.35 131.5,19.35 131.22,19.63 128.94,19.63 128.94,19.64 128.62,19.64 128.61,19.63 128.07,19.63 127.91,19.79 TP2MB18.1 125.76,19.79 125.48,20.07 122.53,20.07 121.89,20.7 119.03,20.7 118.93,20.6 118.93,20.42 118.83,20.32 118.62,20.32 118.52,20.42 118.52,20.6 118.42,20.7 118.22,20.7 118.09,20.57 118.09,20.27 118,20.18 117.69,20.18 117.69,20.18 117.37,20.18 117.36,20.18 117.05,20.18 116.43,19.56 114.65,19.56 114.36,19.85 113.54,19.85 113.47,19.79 TP2MA18.1
  L14-SIGNAL w0.109: v1(97.66,33.13) 101.36,33.13 102.36,32.13 102.87,32.13 103.63,31.37 103.63,31.11 103.38,30.86 103.38,29.59 104.76,28.2 104.76,27.19 105.28,26.67 105.28,23.11 107.57,20.83 110.04,20.83 110.16,20.94 110.97,20.94 110.97,20.95 111.51,20.95 112.67,19.79 TP2MA18.1
  BOTTOM w0.132: U136.L2 130.29,20.55 129.62,20.55 129.46,20.4 129.46,20.16 128.99,19.68 127.61,19.68 TP2MB18.1 ; TP2MA18.1 113.26,19.68 114.63,19.68 115.11,20.16 115.11,20.4 115.27,20.55 115.94,20.55 U137.L2
H_DDR2_A6: length 83.6
  TOP w0.132: U62.M8 130.3,19.74 129.57,19.74 129.18,19.35 129.18,19.08 128.9,18.8 128.55,18.8 127.99,18.24 TP2MB24.1 ; TP2MA24.1 113.64,18.24 114.2,18.8 114.54,18.8 114.83,19.08 114.83,19.35 115.21,19.74 115.95,19.74 U61.M8 ; RN5.3 v1(136.15,17.15) ; U42.N26 v1(94.18,46.76)
  L14-SIGNAL w0.109: v1(136.15,17.15) 134.21,17.15 133.86,17.5 131.57,17.5 131.33,17.74 130.14,17.74 129.9,17.5 128.35,17.5 TP2MB24.1 125.07,17.86 124.9,17.69 120.97,17.69 120.62,18.03 120.02,18.03 119.76,17.78 116.84,17.78 116.36,18.26 114.96,18.26 114.39,17.69 114.13,17.69 113.97,17.86 TP2MA24.1 111.07,17.86 110.99,17.77 109.74,17.77 109.27,18.24 108,18.24 104.14,22.1 104.14,25.91 103,27.05 103,30.86 101.35,32.51 96.27,32.51 94.07,34.71 94.07,43.14 94.61,43.69 94.61,46.33 v1(94.18,46.76)
  BOTTOM w0.132: U137.M8 111.91,18.97 112.57,18.97 112.67,18.87 112.67,18.36 113.18,17.86 TP2MA24.1 ; U136.M8 126.26,18.97 126.92,18.97 127.03,18.87 127.03,18.36 127.53,17.86 TP2MB24.1
H_DDR2_A7: length 84.7
  TOP w0.132: TP2MB23.1 129.06,17.88 128.88,17.7 128.41,17.7 128.16,17.45 127.81,17.45 127.15,18.11 127.15,18.69 126.87,18.97 126.26,18.97 U62.M2 ; U61.M2 111.91,18.97 112.52,18.97 112.8,18.69 112.8,18.11 113.46,17.45 113.81,17.45 114.06,17.7 114.53,17.7 114.71,17.88 TP2MA23.1 ; U42.M25 v1(94.98,47.56)
  L12-SIGNAL w0.089: v1(135.51,17.65) 135.12,17.65 134.74,17.27 131.63,17.27 131.01,17.88 TP2MB23.1 129.18,17.6 128.47,17.6 128.34,17.47 127.79,17.47 127.41,17.86 125.07,17.86 124.87,17.65 124.49,17.65 124.1,18.03 122.26,18.03 121.89,17.67 121.12,17.67 121.03,17.75 121.03,18.16 120.78,18.41 120.4,18.41 119.71,17.73 116.97,17.73 116.81,17.88 TP2MA23.1
  L14-SIGNAL w0.109: v1(100.58,32) 101.22,32 102.62,30.61 102.62,26.67 103.76,25.53 103.76,21.94 108.3,17.4 108.33,17.4 108.33,17.4 114.63,17.4 TP2MA23.1
  BOTTOM w0.132: v1(135.51,17.65) 136.21,17.65 136.62,18.05 136.95,18.05 137.36,17.65 RN14.3 ; TP2MB23.1 129.46,18.69 129.74,18.97 130.28,18.97 U136.M2 ; v1(94.98,47.56) 95.39,47.16 95.39,43.17 95.5,43.05 95.5,36.45 96.14,35.81 96.14,34.04 97.54,32.64 100.36,32.64 100.58,32.41 v1(100.58,32) ; U137.M2 115.93,18.97 115.39,18.97 115.11,18.69 TP2MA23.1
H_DDR2_A8: length 86.8
  TOP w0.132: U61.N8 115.8,18.05 115.8,16.64 115.52,16.36 113.18,16.36 TP2MA27.1 ; U62.N8 130.15,18.05 130.15,16.64 129.87,16.36 127.53,16.36 TP2MB27.1 ; U42.N28 93.94,45.41 93.94,45.04 v1(93.73,44.83)
  L12-SIGNAL w0.089: v1(98.17,30.61) 97.66,30.1 97.66,29.72 102.62,24.77 102.62,20.7 107.19,16.13 112.14,16.13 TP2MA27.1 114,15.54 118.92,15.54 119.58,16.21 122.73,16.21 123.32,15.62 125.98,15.62 TP2MB27.1 127.77,16.12 130.49,16.12 130.71,16.35 131.22,16.35 131.7,15.88 133.48,15.88 133.73,16.13 v1(136.14,16.13)
  L14-SIGNAL w0.109: v1(93.73,44.83) 92.58,43.69 92.58,42.71 93.09,42.2 93.09,33.91 97.03,29.97 97.54,29.97 v1(98.17,30.61)
  BOTTOM w0.132: v1(136.14,16.13) 136.91,16.13 137.36,16.58 RN14.1 ; U137.N8 111.52,18.02 TP2MA27.1 ; TP2MB27.1 125.87,18.02 U136.N8
H_DDR2_A9: length 81.3
  TOP w0.132: U42.M27 94.99,45.95 94.99,43.44 95.89,42.55 95.89,38.15 96.26,37.78 98.75,37.78 103,33.53 103,33.28 103.13,33.15 105.07,33.15 105.21,33.02 105.21,32.75 105.07,32.62 103.13,32.62 103,32.49 103,31.37 102.86,31.24 100.97,31.24 v1(100.46,30.73) ; U62.M3 127.01,19.37 TP2MB21.1 ; U61.M3 112.66,19.37 TP2MA21.1 ; RN5.1 v1(136.15,18.22)
  L12-SIGNAL w0.089: TP2MA21.1 111.15,18.69 111.05,18.59 109.42,18.59 108.97,19.05 107.19,19.05 103.38,22.86 103.38,25.27 100.18,28.47 100.18,30.46 v1(100.46,30.73)
  L14-SIGNAL w0.109: TP2MA21.1 113.64,18.69 113.66,18.67 114.56,18.67 114.94,19.05 116.71,19.05 117.18,18.59 117.9,18.59 118.26,18.95 118.67,18.95 119.07,18.55 122.3,18.55 122.38,18.47 123.75,18.47 123.83,18.55 126.8,18.55 126.95,18.69 TP2MB21.1 128.22,18.55 132.03,18.55 132.67,17.91 134.87,17.91 135.13,18.16 135.7,18.16 135.76,18.22 v1(136.15,18.22)
  BOTTOM w0.132: U136.M3 129.79,19.37 128.99,18.57 127.81,18.57 TP2MB21.1 ; U137.M3 115.44,19.37 114.64,18.57 113.46,18.57 TP2MA21.1
H_DDR2_A10: length 81.8
  TOP w0.132: TP2MB7.1 128.84,23.33 128.84,22.97 128.96,22.86 129.58,22.86 U62.H7 ; U42.L25 v1(95.78,47.56) ; U61.H7 115.23,22.86 114.6,22.86 114.49,22.97 114.49,23.33 TP2MA7.1 ; RN1.1 v1(136.15,25.08)
  L12-SIGNAL w0.089: v1(136.15,25.08) 135.32,25.08 133.6,23.36 129.57,23.36 129.46,23.47 TP2MB7.1 128.24,23.47 127.75,22.97 127.34,22.97 126.57,23.75 126.24,23.75 125.98,23.5 124.97,23.5 124.59,23.88 123.06,23.88 122.43,23.24 121.85,23.24 121.57,23.53 121.19,23.53 121.03,23.37 120.52,23.37 120.05,23.84 118.33,23.84 117.93,23.44 TP2MA7.1 114.43,23.65 114.12,23.65 114.05,23.57 113.61,23.57 113.44,23.75 109.22,23.75 108.2,24.77 106.43,24.77 106.05,25.15 106.05,28.45 104.56,29.94 104.43,29.94 104.37,29.87 104.24,29.87 104.11,30 104.11,30.12 104.18,30.19 104.18,30.31 v1(103.89,30.61)
  BOTTOM w0.132: v1(95.78,47.56) 96.19,47.16 96.19,46.02 95.79,45.62 95.79,43.53 95.87,43.45 95.87,38.01 96.01,37.87 96.01,36.7 96.65,36.07 96.65,34.16 97.15,33.66 101.35,33.66 101.67,33.33 101.67,32.63 101.38,32.34 101.38,32.15 101.61,31.92 101.8,31.92 102.08,32.2 102.48,32.2 103.37,33.1 103.55,33.1 103.74,32.91 103.74,32.72 102.85,31.83 102.85,31.64 103.04,31.46 103.22,31.46 104.12,32.35 104.3,32.35 104.49,32.16 104.49,31.98 103.6,31.08 103.6,30.9 v1(103.89,30.61) ; U136.H7 127.05,22.95 127.05,23.55 127.3,23.8 127.79,23.8 128.04,23.55 128.91,23.55 TP2MB7.1 ; U137.H7 112.7,22.95 112.7,23.55 112.95,23.8 113.44,23.8 113.69,23.55 114.53,23.55 TP2MA7.1
H_DDR2_A11: length 82.6
  TOP w0.132: TP2MB22.1 128.85,18.44 128.98,18.44 129.44,18.9 129.44,19.18 129.63,19.37 U62.M7 ; U61.M7 115.28,19.37 115.09,19.18 115.09,18.9 114.63,18.44 114.5,18.44 TP2MA22.1 ; U42.N27 94.19,45.95 94.19,43.22 95.12,42.29 95.12,37.1 95.26,36.97 96.13,36.97 96.27,36.84 96.27,36.58 96.13,36.44 95.26,36.44 95.12,36.31 95.12,34.29 98.3,31.11 98.55,31.11 98.81,30.86 98.81,29.97 99.06,29.72 100.58,29.72 101.22,29.08 101.22,28.94 101.35,28.8 102.3,28.8 102.43,28.94 102.43,30.6 102.56,30.73 102.83,30.73 102.96,30.6 102.96,28.83 103.22,28.57 v1(103.63,28.57) ; RN5.2 v1(136.78,17.65)
  L12-SIGNAL w0.089: v1(136.78,17.65) 136.17,17.65 135.72,18.1 134.43,18.1 134.11,17.78 132.04,17.78 132.04,17.78 131.72,17.78 131.72,17.78 131.67,17.78 131.04,18.41 129.16,18.41 128.91,18.16 TP2MB22.1 128.3,18.44 127.98,18.44 127.83,18.29 127,18.29 126.75,18.54 125.86,18.54 125.61,18.29 125.22,18.29 124.97,18.54 124.33,18.54 124.21,18.41 122.56,18.41 122.12,18.85 121.87,18.85 121.16,19.56 120.73,19.56 119.72,18.55 117.23,18.55 117.03,18.35 114.78,18.35 114.59,18.16 TP2MA22.1
  L14-SIGNAL w0.109: v1(103.63,28.57) 103.63,27.05 104.52,26.16 104.52,22.73 108.2,19.05 109.35,19.05 109.81,18.59 112.88,18.59 113.16,18.31 113.81,18.31 TP2MA22.1
  BOTTOM w0.132: TP2MB22.1 128.47,18.26 127.53,18.26 127.28,18.52 127.28,19.02 126.94,19.37 U136.M7 ; TP2MA22.1 114.12,18.26 113.18,18.26 112.93,18.52 112.93,19.02 112.59,19.37 U137.M7
H_DDR2_A12: length 82.2
  TOP w0.132: TP2MB16.1 128.63,20.68 129.13,20.68 129.43,20.97 U62.K7 ; TP2MA16.1 114.27,20.68 114.78,20.68 115.07,20.97 U61.K7 ; U42.M28 94.58,43.34 95.5,42.42 95.5,37.9 96.01,37.39 98.62,37.39 99.57,36.45 99.57,35.31 99.7,35.18 100.71,35.18 100.84,35.04 100.84,34.78 100.71,34.65 99.7,34.65 99.57,34.51 99.57,34.27 99.7,34.14 101.72,34.14 101.85,34 101.85,33.74 101.72,33.61 99.7,33.61 99.57,33.48 99.57,33.21 99.7,33.08 101.19,33.08 101.32,32.95 101.32,32.68 101.19,32.55 100.5,32.55 99.95,32 99.95,30.36 100.08,30.23 v1(101.09,30.23)
  L12-SIGNAL w0.089: v1(101.09,30.23) 102.62,28.7 102.62,28.19 104.14,26.67 104.14,23.5 106.86,20.78 109.42,20.78 109.63,20.98 111.51,20.98 112.17,20.32 TP2MA16.1 114.18,20.59 114.92,20.59 115.19,20.32 116.57,20.32 117.2,20.95 117.86,20.95 118.11,21.21 120.78,21.21 121.26,21.69 121.82,21.69 122.17,21.34 122.43,21.34 122.68,21.59 123.19,21.59 123.81,20.97 125.74,20.97 126.39,20.32 TP2MB16.1 128.56,20.61 129.25,20.61 129.68,20.18 131.72,20.18 132.73,20.18 133.62,21.08 v1(135.51,21.08)
  BOTTOM w0.132: TP2MA16.1 113.58,20.32 113.48,20.42 113.2,20.42 112.65,20.97 U137.K7 ; RN12.3 137.36,21.08 136.95,21.48 136.62,21.48 136.21,21.08 v1(135.51,21.08) ; TP2MB16.1 127.93,20.32 127.83,20.42 127.55,20.42 127,20.97 U136.K7
H_DDR2_A13: length 80.5
  TOP w0.132: U62.N3 126.67,18.14 127.64,17.17 128.24,17.17 128.5,17.42 129.01,17.42 TP2MB26.1 ; U42.R24 v1(91.78,48.36) ; TP2MA26.1 114.66,17.42 114.15,17.42 113.89,17.17 113.28,17.17 112.32,18.14 U61.N3
  L12-SIGNAL w0.089: TP2MA26.1 114.68,17.4 108.2,17.4 103,22.61 103,25.03 v1(98.17,29.86)
  L14-SIGNAL w0.109: TP2MA26.1 116.46,17.02 116.67,17.23 123.99,17.23 124.46,16.76 125.63,16.76 126.01,17.14 127.51,17.14 128.04,16.61 129.01,16.61 TP2MB26.1 130.3,17.02 130.43,16.89 131.95,16.89 132.08,17.02 132.91,17.02 133.35,16.58 v1(135.51,16.58)
  BOTTOM w0.132: v1(91.78,48.36) 92.58,47.56 92.58,42.55 93.22,41.91 93.22,34.81 v1(98.17,29.86) ; U136.N3 129.87,17.73 TP2MB26.1 ; TP2MA26.1 115.52,17.73 U137.N3 ; v1(135.51,16.58) 136.21,16.58 136.78,17.15 RN14.2
H_DDR2_A14: length 82.2
  TOP w0.132: U62.N7 129.87,16.84 129.64,16.61 129.18,16.61 TP2MB25.1 ; TP2MA25.1 114.83,16.61 115.29,16.61 115.52,16.84 U61.N7 ; RN5.4 v1(136.78,16.58) ; U42.N24 v1(94.18,48.36)
  L12-SIGNAL w0.089: v1(136.78,16.58) 136.43,16.58 136.3,16.71 135.99,16.71 135.71,16.99 135.13,16.99 134.77,16.64 133.22,16.64 132.8,16.22 131.99,16.22 131.32,16.89 129.92,16.89 129.63,16.6 129.2,16.6 TP2MB25.1 127.66,17.02 127.28,17.4 126.05,17.4 125.41,16.76 124.59,16.76 123.85,17.5 123.06,17.5 122.58,17.02 117.35,17.02 116.97,17.4 116.38,17.4 115.61,16.62 114.82,16.62 TP2MA25.1 ; v1(99.53,30.85) 99.53,32.29 97.79,34.04 97.79,35.18 95.12,37.85 95.12,41.91 94.61,42.42 94.61,46.58 94.6,46.6 94.6,47.72 94.61,47.74 94.61,47.93 v1(94.18,48.36)
  L14-SIGNAL w0.109: v1(99.53,30.85) 101.98,28.4 101.98,26.67 102.87,25.78 102.87,22.2 108.05,17.02 111.38,17.02 111.5,17.14 112.93,17.14 113.06,17.02 TP2MA25.1
  BOTTOM w0.132: U137.N7 112.32,18.24 113.54,17.02 TP2MA25.1 ; U136.N7 126.67,18.24 127.89,17.02 TP2MB25.1
H_DDR2_A15: length 79.7
  TOP w0.132: U62.J7 129.81,21.83 128.41,21.83 TP2MB12.1 ; TP2MA12.1 114.06,21.83 115.46,21.83 U61.J7 ; U42.R23 v1(91.78,49.16) ; RN1.3 v1(136.15,24.01)
  L12-SIGNAL w0.089: v1(136.15,24.01) 135.51,24.01 133.29,21.78 128.84,21.78 128.78,21.84 TP2MB12.1 127.89,21.84 127.69,22.05 127.37,22.05 127.04,21.72 126.49,21.72 126.03,22.18 124.94,22.18 124.21,22.91 123.75,22.91 123.32,22.48 119.82,22.48 119.49,22.81 118.59,22.81 118.21,22.43 117.42,22.43 117.17,22.18 115.51,22.18 115,21.67 114.55,21.67 114.38,21.84 TP2MA12.1 113.51,21.84 113.36,21.99 113.14,21.99 111.76,23.37 107.44,23.37 107.31,23.5 106.3,23.5 105.66,24.13 105.66,28.07 v1(105.16,28.57)
  BOTTOM w0.132: TP2MB12.1 128.04,21.84 127.83,22.06 126.96,22.06 U136.J7 ; U137.J7 112.59,22.03 113.5,22.03 113.69,21.84 TP2MA12.1 ; v1(91.78,49.16) 92.96,47.98 92.96,42.8 93.6,42.16 93.6,35.31 97.66,31.24 98.17,31.24 98.68,30.73 98.68,30.48 99.19,29.97 100.33,29.97 101.52,28.78 101.52,28.43 101.65,28.3 101.91,28.3 102.05,28.43 102.05,28.95 102.18,29.08 102.44,29.08 102.58,28.95 102.58,28.2 102.71,28.07 102.97,28.07 103.1,28.2 103.1,28.95 103.24,29.08 103.89,29.08 104.39,28.57 v1(105.16,28.57)
H_DDR2_BA0: length 82.5
  TOP w0.132: TP2MA10.1 112.71,22.16 111.91,22.16 U61.J2 ; U62.J2 126.26,22.16 127.06,22.16 TP2MB10.1 ; U42.L24 v1(95.78,48.36)
  L12-SIGNAL w0.089: v1(95.78,48.36) 96.17,47.97 96.17,45.63 95.8,45.25 95.8,43.88 95.89,43.79 96.56,43.79 96.65,43.7 96.65,43.52 96.56,43.43 95.89,43.43 95.8,43.34 95.8,43.14 96.81,42.13 96.81,41.37 96.95,41.23 96.95,41.1 96.69,40.84 96.69,40.72 96.82,40.59 96.95,40.59 97.2,40.85 97.33,40.85 97.79,40.39 97.79,39.12 98.63,38.28 98.63,38.15 98.25,37.77 98.25,37.64 98.37,37.52 98.5,37.52 98.88,37.9 99.01,37.9 100.58,36.32 100.97,36.32 106.17,31.11 106.17,30.23 106.69,29.71 106.69,29.34 106.9,29.13 107.23,29.13 107.31,29.04 107.31,28.86 107.23,28.77 106.9,28.77 106.81,28.68 106.81,28.48 106.9,28.39 107.86,28.39 107.95,28.3 107.95,28.12 107.86,28.04 106.9,28.04 106.81,27.95 v1(106.81,27.56) ; v1(135.51,24.51) 133.36,22.35 130.35,22.35 130.07,22.63 128.85,22.63 128.66,22.44 127.67,22.44 TP2MB10.1 126.95,22.48 126.86,22.57 125.17,22.57 124.33,23.41 123.1,23.41 122.47,22.78 121.24,22.78 121.16,22.86 120.27,22.86 119.82,23.3 118.43,23.3 118.01,22.89 117.24,22.89 116.92,22.57 116.56,22.57 116.24,22.89 115.65,22.89 115.49,22.73 115.11,22.73 114.96,22.89 114.5,22.89 114.09,22.47 113.29,22.47 TP2MA10.1
  L14-SIGNAL w0.109: v1(106.81,27.56) 106.43,27.18 106.43,24.26 106.93,23.75 107.16,23.75 108.32,22.59 112.15,22.59 112.26,22.48 TP2MA10.1
  BOTTOM w0.132: TP2MB10.1 128.46,22.42 128.68,22.63 129.2,22.63 129.66,22.17 130.26,22.17 U136.J2 ; U137.J2 115.91,22.17 115.31,22.17 114.87,22.61 114.3,22.61 114.11,22.42 TP2MA10.1 ; v1(135.51,24.51) 136.21,24.51 136.62,24.91 136.95,24.91 137.36,24.51 RN10.3
H_DDR2_BA1: length 85.1
  TOP w0.132: U42.U24 v1(90.18,48.36) ; U62.K8 130.28,21.36 129.57,21.36 129.36,21.56 128.74,21.56 128.59,21.41 128.24,21.41 128.04,21.62 TP2MB13.1 ; TP2MA13.1 113.69,21.62 113.89,21.41 114.24,21.41 114.38,21.55 115.02,21.55 115.21,21.36 115.93,21.36 U61.K8
  L12-SIGNAL w0.089: TP2MA13.1 112.75,21.62 111.76,22.61 111.28,22.61 111.27,22.6 110.96,22.6 110.96,22.61 107.2,22.61 v1(106.81,23)
  L14-SIGNAL w0.109: TP2MA13.1 113.49,21.34 114.17,21.34 114.37,21.54 114.86,21.54 115.06,21.34 116.08,21.34 116.49,21.74 118.59,21.74 119,21.34 120.65,21.34 121.06,21.74 125.7,21.74 125.83,21.62 TP2MB13.1 127.84,21.34 128.52,21.34 128.73,21.54 130.71,21.54 130.92,21.75 133.19,21.75 133.99,20.95 134.56,20.95 v1(135.51,20.01)
  BOTTOM w0.132: TP2MB13.1 127,21.59 126.77,21.36 126.26,21.36 U136.K8 ; RN12.2 136.78,20.58 136.21,20.01 v1(135.51,20.01) ; v1(90.18,48.36) 90.58,47.96 90.58,45.49 89.13,44.04 89.13,42.32 89.41,42.04 89.41,38.86 88.44,37.9 88.44,35.31 89.53,34.21 89.53,30.43 90.63,29.34 94.23,29.34 95.25,28.32 98.68,28.32 104,23 v1(106.81,23) ; U137.K8 111.91,21.36 112.42,21.36 112.65,21.59 TP2MA13.1
H_DDR2_BA2: length 76
  TOP w0.132: U42.M24 v1(94.98,48.36) ; TP2MA11.1 114.45,22.45 113.94,22.45 113.53,22.03 113.03,22.03 112.76,21.77 U61.J3 ; TP2MB11.1 128.8,22.45 128.3,22.45 127.88,22.03 127.38,22.03 127.11,21.77 U62.J3
  L12-SIGNAL w0.089: v1(94.98,48.36) 95.38,47.97 95.38,42.93 95.98,42.32 95.98,40.42 96.9,39.5 96.9,39.37 97.92,38.35 97.92,37.59 97.76,37.43 97.76,36.48 98.3,35.94 98.65,35.94 98.74,36.03 98.74,37.12 98.83,37.21 99,37.21 99.09,37.12 99.09,36.03 99.18,35.94 99.38,35.94 99.47,36.03 99.47,36.49 99.56,36.58 99.74,36.58 99.83,36.49 99.83,36.03 99.92,35.94 100.84,35.94 105.66,31.12 105.66,30.75 v1(105.64,30.73)
  L14-SIGNAL w0.109: v1(135.51,22.07) 134.98,22.07 134.62,21.72 134.52,21.72 134.52,21.72 133.96,21.72 133.45,22.23 TP2MB11.1 128.14,22.23 128.02,22.1 124.97,22.1 124.71,22.35 123.7,22.35 123.44,22.1 120.78,22.1 120.4,21.72 119.25,21.72 118.59,22.38 117.63,22.38 117.42,22.17 115.62,22.17 115.57,22.23 TP2MA11.1 114.67,22.23 113.84,22.23 113.64,22.03 111.95,22.03 111.76,22.23 108.15,22.23 106.97,23.4 106.77,23.4 106.03,24.14 106.03,28.97 105.64,29.36 v1(105.64,30.73)
  BOTTOM w0.132: U137.J3 115.14,21.77 TP2MA11.1 ; RN12.4 137.35,21.65 136.93,22.07 v1(135.51,22.07) ; TP2MB11.1 129.49,21.77 U136.J3
H_DDR2_CASN: length 76.7
  TOP w0.132: U62.G3 126.93,23.37 127.35,23.79 127.93,23.79 TP2MB6.1 ; U61.G3 112.55,23.37 112.98,23.8 113.59,23.8 TP2MA6.1 ; U42.T25 v1(90.98,47.56)
  L12-SIGNAL w0.089: v1(95.67,34.84) 94.87,35.64 94.87,35.76 95.15,36.05 95.15,36.17 95.02,36.3 94.9,36.3 94.61,36.02 94.49,36.02 94.36,36.14 94.36,36.27 94.64,36.55 94.64,36.67 94.52,36.8 94.39,36.8 94.11,36.52 93.99,36.52 93.86,36.64 93.86,36.77 94.14,37.05 94.14,37.18 94.02,37.3 93.89,37.3 93.61,37.02 93.48,37.02 93.36,37.15 93.36,37.27 93.64,37.55 93.64,37.68 93.51,37.81 93.39,37.81 93.11,37.52 92.98,37.52 92.08,38.43 92.08,44.96 91.37,45.66 91.37,47.17 v1(90.98,47.56)
  L14-SIGNAL w0.109: v1(135.51,23.43) 135.22,23.72 129.36,23.72 129.08,24 TP2MB6.1 128.02,23.88 127.71,23.88 127.66,23.83 127.35,23.83 127.3,23.88 127.13,23.88 127,24 126.11,24 125.88,23.77 121.77,23.77 121.37,24.17 118.41,24.17 118.01,23.77 116.05,23.77 115.82,24 115.54,24 115.34,23.8 115.09,23.8 114.88,24 TP2MA6.1 113.56,23.77 112.57,23.77 112.45,23.9 112.45,24.08 112.34,24.19 109.42,24.19 108.33,25.27 108.33,26.54 107.57,27.3 107.57,29.59 103.5,33.66 96.85,33.66 v1(95.67,34.84)
  BOTTOM w0.132: TP2MB6.1 129.03,24 129.59,23.44 129.79,23.44 U136.G3 ; U137.G3 115.44,23.44 115.24,23.44 114.68,24 TP2MA6.1 ; RN10.2 136.78,24.01 136.21,23.43 v1(135.51,23.43)
H_DDR2_CKE: length 92.3
  TOP w0.132: U62.G9 131.06,23.77 130.51,23.77 130.25,24.03 130.25,24.43 130.12,24.56 129.72,24.56 129.52,24.76 129.52,25.17 129.21,25.48 127.97,25.48 TP2MB1.1 ; v1(135.73,27.06) 136.36,27.69 137.03,27.69 R276.1 R672.1 ; U61.G9 116.71,23.77 116.15,23.77 115.9,24.03 115.9,24.43 115.77,24.56 115.37,24.56 115.17,24.76 115.17,25.17 114.86,25.48 113.61,25.48 TP2MA1.1 ; U42.R25 v1(91.78,47.56)
  L12-SIGNAL w0.089: TP2MA1.1 111.94,25.55 111.71,25.78 108.58,25.78 108.33,26.04 107.99,26.04 107.98,26.03 107.32,26.03 v1(106.93,26.42)
  L14-SIGNAL w0.109: TP2MA1.1 114.07,25.55 114.3,25.78 116.2,25.78 116.33,25.65 117.6,25.65 117.98,26.04 121.05,26.04 121.34,25.74 122.01,25.74 122.3,26.04 123.95,26.04 124.23,25.76 125.81,25.76 126.01,25.55 TP2MB1.1 128.44,26.1 129.6,26.1 129.92,25.78 134.46,25.78 v1(135.73,27.06)
  BOTTOM w0.132: v1(91.78,47.56) 92.2,47.14 92.2,44.96 91.68,44.43 91.68,35.97 91.81,35.84 92.58,35.84 92.71,35.71 92.71,35.45 92.58,35.31 91.81,35.31 91.68,35.18 91.68,34.92 91.81,34.79 92.58,34.79 92.71,34.65 92.71,34.39 92.58,34.26 91.81,34.26 91.68,34.12 91.68,33.86 91.81,33.73 92.58,33.73 92.71,33.6 92.71,33.33 92.58,33.2 91.81,33.2 91.68,33.07 91.68,32.8 91.81,32.67 92.58,32.67 92.71,32.54 92.71,32.28 92.58,32.14 92.16,32.14 92.02,32.01 92.02,31.62 92.28,31.37 94.23,31.37 96.14,29.46 99.44,29.46 102.49,26.42 v1(106.93,26.42) ; TP2MA1.1 112.55,24.56 112.14,24.56 111.94,24.36 111.94,24 111.68,23.75 111.1,23.75 U137.G9 ; U136.G9 125.45,23.75 126.03,23.75 126.29,24 126.29,24.36 126.49,24.56 126.9,24.56 TP2MB1.1
H_DDR2_CLK_N: length 86.4
  TOP w0.099: U42.R27 91.8,45.98 91.8,43.83 92.58,43.06 92.58,42.55 93.01,42.12 93.01,39.09 93.01,39.09 93.01,31.83 97.41,27.43 99.19,27.43 100.08,26.54 100.97,26.54 102.32,25.2 103.38,25.2 103.68,25.5 103.68,26.75 103.78,26.85 103.98,26.85 104.08,26.75 104.08,24.89 104.34,24.64 104.75,24.64 105.01,24.89 105.01,26.76 105.11,26.86 105.31,26.86 105.41,26.76 105.41,24.89 105.67,24.63 106.07,24.63 106.34,24.89 106.34,26.53 106.67,26.86 108.01,26.86 108.59,26.28 v1(109.06,26.28) ; TP2MB5.1 127.72,24.41 128.31,24.41 128.83,23.89 129.12,23.89 129.44,23.57 129.67,23.57 U62.G7 ; TP2MA5.1 113.37,24.41 113.96,24.41 114.48,23.89 114.77,23.89 115.09,23.57 115.32,23.57 U61.G7
  L12-SIGNAL w0.086: v1(136.38,26.23) 135.24,26.23 134.8,25.78 134.47,25.78 132.56,23.88 130.61,23.88 130.5,23.98 128.8,23.98 128.39,24.38 127.98,24.38 127.81,24.21 TP2MB5.1 127.23,24.49 126.34,24.49 125.75,23.9 125.11,23.9 124.75,24.26 122.81,24.26 122.42,23.87 121.8,23.87 121.28,24.38 120.59,24.38 120.42,24.21 118.24,24.21 117.91,23.88 116.3,23.88 116.03,24.16 115.42,24.16 115.17,23.9 114.53,23.9 114.05,24.38 113.33,24.38 TP2MA5.1
  L14-SIGNAL w0.089: v1(109.06,26.28) 109.48,26.28 109.6,26.16 109.6,25.92 110.83,24.69 111.68,24.69 111.79,24.79 113.26,24.79 113.41,24.64 113.41,24.33 113.28,24.21 TP2MA5.1
  BOTTOM w0.099: U136.G7 126.42,23.37 126.29,23.5 126.29,23.64 126.42,23.77 126.87,23.77 127.17,24.07 127.37,24.07 TP2MB5.1 ; TP2MA5.1 113.02,24.07 112.81,24.07 112.53,23.79 112.09,23.79 111.93,23.64 111.93,23.47 112.03,23.37 U137.G7 ; R676.1 137.35,26.23 v1(136.38,26.23)
H_DDR2_CLK_P: length 84.8
  TOP w0.099: TP2MA4.1 114.55,24.25 114.65,24.16 114.88,24.16 115.2,23.84 115.46,23.84 115.58,23.96 115.58,24.1 U61.F7 ; v1(109.07,26.99) 109.06,26.98 109.06,26.77 108.96,26.66 108.9,26.66 108.79,26.55 108.7,26.55 108.12,27.13 106.56,27.13 106.07,26.64 106.07,25 105.96,24.89 105.78,24.89 105.67,25 105.67,26.87 105.42,27.13 105,27.13 104.74,26.87 104.74,25 104.64,24.9 104.45,24.9 104.35,25 104.35,26.86 104.09,27.11 103.67,27.11 103.42,26.86 103.42,25.61 103.27,25.46 102.43,25.46 101.08,26.81 100.19,26.81 99.3,27.7 97.52,27.7 93.27,31.94 93.27,38.98 93.27,42.24 92.85,42.66 92.85,43.17 92.07,43.95 92.07,45.45 U42.R28 ; TP2MB4.1 128.91,24.25 129,24.16 129.23,24.16 129.55,23.84 129.83,23.84 129.93,23.94 129.93,24.1 U62.F7
  L12-SIGNAL w0.086: v1(136.43,26.94) 136.03,26.53 135.12,26.53 134.67,26.09 134.34,26.09 132.44,24.18 130.73,24.18 130.63,24.28 129.92,24.28 129.82,24.38 129.82,24.63 129.73,24.71 129.56,24.71 129.47,24.63 129.47,24.38 129.37,24.28 129.03,24.28 TP2MB4.1 128.91,24.54 128.75,24.69 127.81,24.69 127.71,24.59 127.56,24.59 127.36,24.79 126.21,24.79 125.62,24.2 125.24,24.2 124.88,24.56 122.68,24.56 122.29,24.17 121.93,24.17 121.41,24.69 120.47,24.69 120.29,24.51 118.11,24.51 117.79,24.19 116.43,24.19 116.15,24.46 115.3,24.46 115.04,24.21 114.76,24.21 TP2MA4.1
  L14-SIGNAL w0.089: v1(109.07,26.99) 109.06,26.98 109.06,26.8 109.35,26.51 109.57,26.51 109.83,26.26 109.83,26.02 110.93,24.92 111.59,24.92 111.69,25.02 113.35,25.02 113.64,24.73 113.67,24.71 113.96,24.41 TP2MA4.1
  BOTTOM w0.099: TP2MA4.1 113.51,24.41 113.35,24.57 112.94,24.57 112.53,24.17 U137.F7 ; TP2MB4.1 127.82,24.41 127.66,24.57 127.29,24.57 126.89,24.17 U136.F7 ; v1(136.43,26.94) 136.5,26.87 136.5,26.7 136.7,26.49 137.09,26.49 137.41,26.82 R674.1
H_DDR2_CSN0: length 80.7
  TOP w0.132: TP2MB8.1 127.08,22.96 126.26,22.96 U62.H2 ; U61.H2 111.91,22.96 112.68,22.96 TP2MA8.1 ; U42.M26 v1(94.98,46.76)
  L12-SIGNAL w0.089: v1(94.98,46.76) 94.98,42.68 95.63,42.04 95.63,37.97 98.04,35.56 99.14,35.56 99.23,35.47 99.23,33.36 99.31,33.27 99.49,33.27 99.58,33.36 99.58,35.47 99.67,35.56 99.85,35.56 99.94,35.47 99.94,33.36 100.03,33.27 100.2,33.27 100.29,33.36 100.29,35.47 100.38,35.56 100.58,35.56 104.9,31.24 104.9,30.86 v1(106.3,29.46)
  L14-SIGNAL w0.109: v1(136.14,22.99) 135.08,22.99 134.7,23.37 130.94,23.37 130.66,23.09 128.82,23.09 128.54,23.37 TP2MB8.1 127.17,23.37 127.16,23.36 121.81,23.36 121.63,23.53 121.19,23.53 121.02,23.36 120.28,23.36 119.89,23.75 118.62,23.75 118.22,23.36 115.44,23.36 115.1,23.01 114.43,23.01 114.07,23.37 TP2MA8.1 112.14,23.37 111.73,23.77 109.19,23.77 107.43,25.54 107.43,26.69 107.2,26.91 107.2,28.56 v1(106.3,29.46)
  BOTTOM w0.132: TP2MA8.1 113.54,23.27 114.2,23.27 114.4,23.06 114.86,23.06 114.94,23.14 115.21,23.14 115.37,22.99 115.9,22.99 U137.H2 ; v1(136.14,22.99) 136.91,22.99 137.36,23.43 RN10.1 ; U136.H2 130.25,22.99 129.72,22.99 129.57,23.14 129.19,23.14 129.14,23.09 128.73,23.09 128.55,23.27 127.89,23.27 TP2MB8.1
H_DDR2_D0: length 48.2
  TOP w0.132: v1(107.82,38.86) 106.3,40.39 103.38,40.39 102.74,41.02 102.74,42.16 101.98,42.93 101.98,44.79 101.79,44.99 U42.C28
  L12-SIGNAL w0.089: v1(107.82,38.86) 108.46,38.86 108.6,38.72 108.6,38.59 108.47,38.46 108.47,38.34 108.6,38.21 108.73,38.21 108.85,38.34 108.98,38.34 111.25,36.07 114.68,36.07 116.46,34.29 117.12,34.29 117.21,34.2 117.21,33.87 117.3,33.78 117.47,33.78 117.56,33.87 117.56,34.2 117.65,34.29 117.86,34.29 117.94,34.2 117.94,33.12 118.03,33.03 118.21,33.03 118.3,33.12 118.3,34.2 118.39,34.29 118.57,34.29 118.66,34.2 118.66,33.12 118.75,33.03 118.92,33.03 119.01,33.12 119.01,34.2 119.1,34.29 119.28,34.29 119.37,34.2 119.37,33.12 119.46,33.03 119.63,33.03 119.72,33.12 119.72,34.2 119.81,34.29 120.02,34.29 120.65,33.66 121.41,33.66 121.53,33.53 121.53,33.14 121.44,33.05 120.74,33.05 120.65,32.96 120.65,32.78 120.74,32.69 121.44,32.69 121.53,32.6 121.53,32.4 121.44,32.31 120.61,32.31 120.52,32.22 120.52,32.05 120.61,31.96 121.44,31.96 v1(122.03,31.37)
  BOTTOM w0.132: v1(122.03,31.37) 122.43,31.37 123.7,30.1 123.7,27.43 124.16,26.97 125.46,26.97 U136.C8
H_DDR2_D1: length 48
  TOP w0.132: v1(105.42,46.48) 104.99,46.92 104.47,46.92 104.22,47.16 U42.A26
  L12-SIGNAL w0.089: v1(123.83,34.92) 123.83,35.69 123.7,35.81 123.04,35.81 122.95,35.73 122.95,35.27 122.87,35.19 122.69,35.19 122.6,35.27 122.6,35.73 122.51,35.81 122.33,35.81 122.24,35.73 122.24,35.27 122.15,35.19 121.98,35.19 121.89,35.27 121.89,35.73 121.8,35.81 121.62,35.81 121.53,35.73 121.53,35.27 121.44,35.19 121.26,35.19 121.18,35.27 121.18,35.73 121.09,35.81 120.43,35.81 120.34,35.9 120.34,36.49 120.25,36.58 120.07,36.58 119.98,36.49 119.98,35.9 119.89,35.81 119.71,35.81 119.63,35.9 119.63,36.49 119.54,36.58 119.36,36.58 119.27,36.49 119.27,35.9 119.18,35.81 119,35.81 118.91,35.9 118.91,36.49 118.83,36.58 118.65,36.58 118.56,36.49 118.56,35.9 118.47,35.81 118.29,35.81 118.2,35.9 118.2,36.49 118.11,36.58 117.91,36.58 117.82,36.49 117.82,36.16 117.73,36.07 117.56,36.07 117.47,36.16 117.47,36.49 117.38,36.58 116.2,36.58 114.43,38.35 112.27,38.35 108.71,41.92 108.71,43.57 106.57,45.71 106.2,45.71 v1(105.42,46.48)
  BOTTOM w0.132: v1(123.83,34.92) 124.33,34.42 125.35,34.42 126.11,33.66 126.11,30.73 127.89,28.96 127.89,26.54 127.43,26.09 127.43,25.58 126.82,24.97 U136.E7
H_DDR2_D2: length 47
  TOP w0.132: U42.E24 v1(100.59,48.36)
  L12-SIGNAL w0.089: v1(131.83,29.46) 130.94,30.35 130.94,32.89 127.51,36.32 127.25,36.32 125.48,38.09 117.86,38.09 115.44,40.51 113.79,40.51 106.68,47.62 103.12,47.62 102.78,47.97 101.13,47.97 100.74,48.36 v1(100.59,48.36)
  BOTTOM w0.132: v1(131.83,29.46) 132.33,28.96 132.33,25.78 131.95,25.4 131.04,25.4 U136.D2
H_DDR2_D3: length 46.7
  TOP w0.132: U42.D25 v1(101.38,47.56)
  L12-SIGNAL w0.089: v1(129.92,30.48) 129.66,30.21 129.04,30.21 128.65,30.61 128.65,30.88 128.87,31.09 129.32,31.09 129.41,31.18 129.41,31.36 129.32,31.45 128.49,31.45 128.4,31.54 128.4,31.72 128.49,31.8 129.32,31.8 129.41,31.89 129.41,33.97 127.45,35.94 127.13,35.94 125.35,37.72 117.73,37.72 115.32,40.13 113.54,40.13 112.65,41.02 111.25,41.02 110.87,41.4 110.87,42.93 106.58,47.22 102.39,47.22 102.35,47.17 101.77,47.17 v1(101.38,47.56)
  BOTTOM w0.132: v1(129.92,30.48) 130.28,30.12 130.28,26.96 U136.C2
H_DDR2_D4: length 47.2
  TOP w0.132: U42.D26 v1(101.39,46.76)
  L12-SIGNAL w0.089: v1(101.39,46.76) 101.76,46.39 102.01,46.39 102.02,46.37 103.36,46.37 104.27,45.47 104.27,44.96 103.9,44.59 103.9,43.29 105.37,41.82 105.5,41.82 106.2,42.52 106.32,42.52 106.45,42.39 106.45,42.27 105.75,41.57 105.75,41.44 106.17,41.02 107.31,41.02 109.07,39.26 109.2,39.26 109.32,39.38 109.45,39.38 109.57,39.26 109.57,39.13 109.45,39.01 109.45,38.89 109.97,38.37 110.1,38.37 110.54,38.81 110.67,38.81 110.79,38.69 110.79,38.56 110.35,38.11 110.35,37.99 110.74,37.59 110.95,37.59 111.04,37.68 111.04,38.14 111.12,38.23 111.3,38.23 111.39,38.14 111.39,37.68 111.48,37.59 114.17,37.59 116.71,35.05 120.27,35.05 120.91,34.41 125.61,34.41 125.86,34.16 125.86,33.91 125.61,33.66 124.93,33.66 124.93,33.66 124.71,33.66 v1(124.33,33.27)
  BOTTOM w0.132: U136.C7 127.13,27.03 127.13,28.57 124.62,31.08 124.62,32.98 v1(124.33,33.27)
H_DDR2_D5: length 48.2
  TOP w0.132: v1(106.08,46.48) 105.45,45.85 103.73,45.85 103.62,45.96 102.99,45.96 U42.B27
  L12-SIGNAL w0.089: v1(124.33,35.56) 124.33,36.77 124.24,36.86 124,36.86 123.91,36.77 123.91,36.28 123.83,36.2 123.65,36.2 123.56,36.28 123.56,36.87 123.47,36.96 123.29,36.96 123.2,36.87 123.2,36.28 123.11,36.2 122.94,36.2 122.85,36.28 122.85,36.87 122.76,36.96 122.58,36.96 122.49,36.87 122.49,36.28 122.4,36.2 122.22,36.2 122.14,36.28 122.14,36.87 122.05,36.96 121.87,36.96 121.78,36.87 121.78,36.28 121.69,36.2 121.51,36.2 121.42,36.28 121.42,36.87 121.34,36.96 121.16,36.96 121.07,36.87 121.07,36.41 120.98,36.32 120.8,36.32 120.71,36.41 120.71,36.87 120.62,36.96 116.33,36.96 114.55,38.73 112.39,38.73 110.11,41.02 110.11,42.25 110.12,42.26 110.12,42.58 109.89,42.81 109.76,42.81 v1(106.08,46.48)
  BOTTOM w0.132: v1(124.33,35.56) 124.84,35.56 126.49,33.91 126.49,30.99 128.27,29.21 128.27,25.98 128.42,25.83 129.24,25.83 129.79,25.27 129.79,25.04 U136.E3
H_DDR2_D6: length 48.2
  TOP w0.132: v1(104.78,46.35) 104.47,46.66 104.34,46.66 104.14,46.86 103.78,46.86 103.68,46.76 102.99,46.76 U42.B26
  L12-SIGNAL w0.089: v1(104.78,46.35) 105.79,45.34 106.43,45.34 107.81,43.96 107.81,43.83 107.73,43.75 107.73,43.63 107.86,43.5 107.98,43.5 108.06,43.58 108.19,43.58 108.33,43.43 108.33,42.7 108.24,42.61 107.02,42.61 106.93,42.53 106.93,42.35 107.02,42.26 108.24,42.26 108.33,42.17 108.33,41.97 108.24,41.88 106.51,41.88 106.43,41.79 106.43,41.61 106.51,41.52 108.24,41.52 108.33,41.43 108.33,41.4 108.46,41.27 108.84,41.27 109.06,41.05 109.06,40.93 108.87,40.74 108.87,40.61 108.99,40.48 109.12,40.48 109.31,40.68 109.44,40.68 109.64,40.48 109.64,40.35 109.45,40.16 109.45,40.03 109.57,39.91 109.7,39.91 109.89,40.1 110.02,40.1 112.14,37.97 114.3,37.97 116.84,35.43 120.4,35.43 121.03,34.8 v1(121.54,34.8)
  BOTTOM w0.132: U136.E8 126.19,24.97 126.59,25.37 126.85,25.37 127.1,25.63 127.1,26.39 127.51,26.8 127.51,28.83 125.73,30.61 125.73,33.4 125.22,33.91 122.43,33.91 v1(121.54,34.8)
H_DDR2_D7: length 46.7
  TOP w0.132: U42.C26 v1(102.19,46.76)
  L12-SIGNAL w0.089: v1(102.19,46.76) 103.66,46.76 103.77,46.87 105.26,46.87 105.26,46.87 106.42,46.87 110.49,42.8 110.49,41.27 111.25,40.51 111.85,40.51 113.24,39.12 115.31,39.12 115.74,38.69 115.74,38.05 116.45,37.34 125.26,37.34 125.71,36.89 125.71,36.77 125.37,36.43 125.37,36.3 125.49,36.18 125.62,36.18 125.96,36.52 126.08,36.52 126.21,36.39 126.21,36.27 125.87,35.93 125.87,35.8 126,35.68 126.12,35.68 126.46,36.01 126.59,36.01 127.5,35.1 127.5,34.45 127.41,34.36 126.71,34.36 126.62,34.27 126.62,34.09 126.71,34 127.41,34 127.76,33.66 128.78,33.66 128.91,33.53 128.91,33.33 128.82,33.24 128.1,33.24 128.02,33.15 128.02,32.6 128.23,32.38 v1(128.91,32.38)
  BOTTOM w0.132: U136.B3 129.41,27.83 129.41,31.88 v1(128.91,32.38)
H_DDR2_D8: length 50.6
  TOP w0.132: U42.F26 v1(99.79,46.76) ; v1(126.62,35.43) 126.62,34.29 127.64,33.27 128.38,33.27 128.55,33.1 128.55,32.91 128.38,32.74 127.64,32.74 127.51,32.61 127.51,31.88 127.68,31.7 128.27,31.7 129.03,30.94 129.03,27.41 U62.C7
  BOTTOM w0.132: v1(126.62,35.43) 127.03,35.85 127.03,36.42 126.62,36.83 114.05,36.83 113.67,37.21 109.6,37.21 108.97,36.58 107.06,36.58 106.2,35.71 104.24,35.71 101.09,38.86 101.09,42.42 100.08,43.43 100.08,45.59 99.79,45.88 v1(99.79,46.76)
H_DDR2_D9: length 50.6
  TOP w0.132: v1(127.89,37.47) 130.68,34.67 130.68,30.35 130.28,29.95 130.28,26.96 U62.C8 ; U42.E25 v1(100.59,47.56)
  BOTTOM w0.132: v1(100.59,47.56) 100.19,47.16 100.19,46.37 100.58,45.97 100.58,44.32 102.74,42.16 102.74,38.48 103.25,37.97 105.85,37.97 105.98,37.84 105.98,37.52 106.12,37.39 106.38,37.39 106.51,37.52 106.51,37.84 106.64,37.97 106.91,37.97 107.04,37.84 107.04,37.47 107.17,37.34 107.44,37.34 107.57,37.47 107.57,37.84 107.7,37.97 114.17,37.97 114.55,37.59 127.25,37.59 127.38,37.47 v1(127.89,37.47)
H_DDR2_D10: length 50.8
  TOP w0.132: U62.E8 130.67,24.97 131.07,25.37 131.93,25.37 132.33,25.78 132.33,29.59 131.19,30.73 131.19,35.05 v1(128.78,37.47) ; U42.E26 v1(100.59,46.76)
  BOTTOM w0.132: v1(128.78,37.47) 128.27,37.97 120.14,37.97 119.51,38.61 115.44,38.61 115.19,38.35 104.63,38.35 104.61,38.34 104.18,38.34 103.87,38.65 103.87,41.67 101.09,44.45 101.09,46.25 v1(100.59,46.76)
H_DDR2_D11: length 50.5
  TOP w0.132: v1(98.68,43.94) 99.06,44.32 99.06,45.09 98.99,45.15 98.99,45.95 U42.G27 ; v1(120.02,32.64) 121.16,32.64 121.41,32.38 121.41,28.96 121.67,28.7 124.08,28.7 124.46,29.08 125.86,29.08 126.26,28.68 126.26,27.77 U62.B3
  BOTTOM w0.132: v1(120.02,32.64) 119.73,32.93 119.73,33.13 118.82,34.04 112,34.04 111.87,34.17 111.87,34.92 111.74,35.05 111.47,35.05 111.34,34.92 111.34,34.17 111.21,34.04 110.94,34.04 110.81,34.17 110.81,34.92 110.68,35.05 110.42,35.05 110.28,34.92 110.28,34.17 110.15,34.04 109.89,34.04 109.75,34.17 109.75,34.92 109.62,35.05 109.36,35.05 109.23,34.92 109.23,34.17 109.09,34.04 108.83,34.04 108.7,34.17 108.7,34.92 108.57,35.05 108.3,35.05 108.17,34.92 108.17,34.17 108.04,34.04 103.38,34.04 98.81,38.61 98.81,43.41 98.68,43.53 v1(98.68,43.94)
H_DDR2_D12: length 50.6
  TOP w0.132: v1(100.01,42.74) 100.01,43.62 100.19,43.8 U42.E28 ; U62.E7 129.79,25.04 129.79,25.32 129.31,25.81 129.31,26.14 128.65,26.8 128.65,30.19 128.24,30.61 v1(127.64,30.61)
  BOTTOM w0.132: v1(100.01,42.74) 100.71,42.04 100.71,38.61 104.01,35.31 106.45,35.31 107.34,36.2 109.66,36.2 109.8,36.33 109.8,36.7 109.93,36.83 110.19,36.83 110.32,36.7 110.32,36.33 110.46,36.2 110.72,36.2 110.85,36.33 110.85,36.7 110.99,36.83 111.25,36.83 111.38,36.7 111.38,36.33 111.51,36.2 111.76,36.2 112.27,36.7 113.54,36.7 113.79,36.45 123.28,36.45 123.41,36.32 123.41,36.01 123.55,35.88 123.81,35.88 123.94,36.01 123.94,36.32 124.07,36.45 124.59,36.45 126.11,34.92 127.13,34.92 127.38,34.67 127.38,33.78 127.64,33.53 v1(127.64,30.61)
H_DDR2_D13: length 50.6
  TOP w0.132: U62.D2 126.24,25.4 126.87,25.4 127.13,25.65 127.13,26.04 127.89,26.8 127.89,28.96 125.86,30.99 125.86,33.4 125.35,33.91 123.83,33.91 123.32,33.4 122.81,33.4 122.3,33.91 v1(122.3,34.8) ; U42.G26 v1(98.99,46.76)
  BOTTOM w0.132: v1(122.3,34.8) 122.3,35.21 121.82,35.69 113.41,35.69 113.22,35.88 112.59,35.88 112.14,35.43 108.1,35.43 107.7,35.03 107.7,34.55 107.56,34.42 103.63,34.42 99.19,38.86 99.19,45.09 98.99,45.29 v1(98.99,46.76)
H_DDR2_D14: length 50.7
  TOP w0.132: v1(119.25,32.64) 119.67,32.22 120.68,32.22 121.03,31.88 121.03,31.63 120.9,31.5 120.02,31.5 119.89,31.37 119.89,31.1 120.02,30.97 120.9,30.97 121.03,30.84 121.03,30.57 120.9,30.44 120.02,30.44 119.89,30.31 119.89,30.05 120.02,29.91 120.9,29.91 121.03,29.78 121.03,29.52 120.9,29.39 120.02,29.39 119.89,29.25 119.89,28.99 120.02,28.86 120.9,28.86 121.03,28.72 121.03,27.81 121.9,26.94 122.34,26.94 122.35,26.92 123.48,26.92 123.61,27.06 123.61,27.93 123.74,28.07 124.01,28.07 124.14,27.93 124.14,27.06 124.27,26.92 125.51,26.92 U62.C2 ; U42.G28 98.59,45.11 98.58,45.1 v1(98.58,44.69)
  BOTTOM w0.132: v1(119.25,32.64) 118.22,33.67 110.33,33.67 110.31,33.66 103.12,33.66 97.41,39.37 97.41,43.52 v1(98.58,44.69)
H_DDR2_D15: length 50.6
  TOP w0.132: U42.F25 v1(99.79,47.56) ; v1(123.06,34.8) 123.44,34.42 125.73,34.42 126.36,33.78 126.36,31.11 128.27,29.21 128.27,26.67 127.44,25.84 127.44,25.53 126.94,25.02 126.72,25.02 U62.E3
  BOTTOM w0.132: v1(99.79,47.56) 99.39,47.16 99.39,45.65 99.57,45.47 99.57,39.12 103.81,34.87 107.13,34.87 107.31,35.06 107.31,35.41 107.72,35.81 111.89,35.81 112.39,36.32 113.41,36.32 113.67,36.07 122.68,36.07 123.06,35.69 v1(123.06,34.8)
H_DDR2_D16: length 35.5
  TOP w0.132: U42.G25 v1(98.99,47.56)
  L12-SIGNAL w0.089: v1(98.99,47.56) 98.57,47.15 98.57,46.46 99.82,45.21 99.82,43.31 99.63,43.11 99.63,42.49 99.82,42.29 100.46,42.29 100.84,41.91 100.84,40.99 101.47,40.35 101.47,39.12 101.85,38.73 102.36,38.73 104.01,37.08 106.81,37.08 108.59,35.3 108.59,35.17 108.47,35.04 108.47,34.92 108.59,34.79 108.72,34.79 108.85,34.92 108.97,34.92 109.1,34.79 109.1,34.67 108.97,34.54 108.97,34.41 109.09,34.29 109.22,34.29 109.35,34.42 110.87,34.42 111.16,34.12 111.16,33.82 111,33.66 110.24,33.66 110.1,33.52 110.1,33.03 110.49,32.64 112.27,32.64 114.05,30.86 114.86,30.86 v1(115.24,30.48)
  BOTTOM w0.132: U137.B3 115.19,27.7 115.19,28.7 115.7,29.21 115.7,30.02 v1(115.24,30.48)
H_DDR2_D17: length 35.5
  TOP w0.132: U42.G24 v1(98.99,48.36)
  L12-SIGNAL w0.089: v1(109.52,28.38) 109.07,28.83 108.2,28.83 107.82,29.21 107.82,30.1 107.68,30.24 107.55,30.24 107.23,29.92 107.11,29.92 106.98,30.05 106.98,30.18 107.3,30.49 107.3,30.62 106.16,31.76 106.16,31.88 106.6,32.32 106.6,32.44 106.47,32.57 106.35,32.57 105.91,32.13 105.79,32.13 103.58,34.34 103.58,34.47 104.07,34.97 104.07,35.09 103.95,35.22 103.82,35.22 103.33,34.72 103.2,34.72 101.22,36.7 100.84,36.7 98.93,38.61 98.93,39.75 97.16,41.53 97.16,43.94 97,44.1 97,47.72 97.22,47.95 97.24,47.95 97.27,47.97 98.6,47.97 v1(98.99,48.36)
  BOTTOM w0.132: U137.C8 111.16,26.92 109.73,26.92 109.6,27.06 109.6,27.91 109.52,27.99 v1(109.52,28.38)
H_DDR2_D18: length 36.2
  TOP w0.132: U42.F23 v1(99.79,49.16)
  L12-SIGNAL w0.089: v1(117.22,30.35) 116.84,30.73 116.84,31.11 114.94,33.01 114.94,33.31 113.96,34.29 112.52,34.29 111.12,35.69 110.36,35.69 107.82,38.23 105.54,38.23 105.03,38.73 105.03,39.12 102.87,41.27 102.87,42.04 101.47,43.43 101.47,46.1 101,46.58 101,47.4 101,47.4 101,47.69 100.97,47.72 100.97,47.72 100.75,47.95 100.74,47.95 100.72,47.97 100.42,47.97 100.2,48.2 100.2,48.52 100.21,48.53 100.21,48.73 v1(99.79,49.16)
  BOTTOM w0.132: v1(117.22,30.35) 117.22,28.83 117.98,28.07 117.98,25.91 117.47,25.4 116.69,25.4 U137.D2
H_DDR2_D19: length 35.6
  TOP w0.132: U42.F24 v1(99.79,48.36)
  L12-SIGNAL w0.089: v1(116.33,29.21) 116.71,29.21 116.95,28.96 117.61,28.96 117.86,29.21 117.86,29.72 117.6,29.98 116.83,29.98 116.59,30.23 116.59,30.86 114.94,32.51 113.79,32.51 111.12,35.18 110.36,35.18 107.7,37.85 104.65,37.85 103.89,38.61 103.89,39.62 103.6,39.91 103,39.91 102.52,40.39 102.52,41.93 101.09,43.36 101.09,45.71 100.2,46.6 100.2,47.73 99.79,48.14 v1(99.79,48.36)
  BOTTOM w0.132: U137.C2 115.95,26.94 115.95,28.44 116.33,28.82 v1(116.33,29.21)
H_DDR2_D20: length 36.4
  TOP w0.132: U42.H28 97.78,44.57 v1(97.54,44.32)
  L12-SIGNAL w0.089: v1(107.53,31.11) 107.06,31.59 107.06,33.02 106.81,33.27 106.42,33.27 105.98,32.83 105.85,32.83 105.73,32.96 105.73,33.08 106.43,33.78 106.43,33.91 106.3,34.03 106.18,34.03 105.48,33.33 105.35,33.33 105.23,33.46 105.23,33.58 105.93,34.28 105.93,34.41 105.8,34.54 105.67,34.54 104.97,33.84 104.85,33.84 104.72,33.96 104.72,34.09 105.42,34.79 105.42,34.91 105.3,35.04 105.17,35.04 104.47,34.34 104.35,34.34 104.22,34.46 104.22,34.59 104.92,35.29 104.92,35.42 104.78,35.56 103.51,35.56 101.85,37.21 100.97,37.21 99.31,38.86 99.31,40.01 97.54,41.78 v1(97.54,44.32)
  BOTTOM w0.132: U137.C7 111.89,27 111.89,28.7 111.63,28.96 109.35,28.96 108.97,29.34 108.97,30.47 108.62,30.83 107.82,30.83 v1(107.53,31.11)
H_DDR2_D21: length 36.2
  TOP w0.132: U42.H25 v1(98.18,47.56)
  L12-SIGNAL w0.089: v1(111.51,30.73) 111.13,30.73 111.04,30.65 111.04,30.19 110.95,30.1 110.77,30.1 110.69,30.19 110.69,30.65 110.6,30.73 110.42,30.73 110.33,30.65 110.33,30.19 110.24,30.1 110.06,30.1 109.43,30.73 109.19,30.73 108.91,31.01 108.91,31.8 108.34,32.38 107.79,32.38 107.56,32.61 107.56,33.28 104.94,35.9 103.67,35.9 101.98,37.59 101.09,37.59 99.69,38.99 99.69,40.51 99.06,41.15 99.06,41.58 97.92,42.72 97.92,43.69 98.17,43.94 98.17,45.59 97.79,45.97 97.79,47.17 v1(98.18,47.56)
  BOTTOM w0.132: U137.E8 111.84,24.97 112.24,25.37 112.5,25.37 112.78,25.65 112.78,27.05 113.16,27.43 113.16,28.96 112.39,29.72 111.64,29.72 111.51,29.85 v1(111.51,30.73)
H_DDR2_D22: length 36.4
  TOP w0.132: v1(98.33,43.31) 98.04,43.6 98.04,44.39 98.17,44.52 98.17,45.39 98.18,45.4 98.18,45.72 98.17,45.73 98.17,45.98 U42.H27
  L12-SIGNAL w0.089: v1(112.9,30.86) 112.01,30.86 111,31.88 109.86,31.88 109.74,31.99 109.62,31.99 109.49,31.86 109.36,31.86 109.24,31.99 109.24,32.11 109.36,32.24 109.36,32.37 109.22,32.51 108.84,32.51 108.71,32.64 108.71,33.02 108.46,33.27 108.08,33.27 107.68,33.67 107.68,33.79 107.94,34.05 107.94,34.18 107.81,34.3 107.69,34.3 107.43,34.05 107.3,34.05 107.18,34.17 107.18,34.3 107.43,34.55 107.43,34.68 107.31,34.8 107.18,34.8 106.93,34.55 106.8,34.55 106.68,34.68 106.68,34.8 106.93,35.06 106.93,35.18 106.81,35.31 106.68,35.31 106.42,35.05 106.3,35.05 106.17,35.18 106.17,35.3 106.43,35.56 106.43,35.68 106.3,35.81 106.18,35.81 105.92,35.56 105.8,35.56 105.67,35.68 105.67,35.81 105.93,36.06 105.93,36.19 105.8,36.31 105.67,36.31 105.42,36.06 105.29,36.06 105.03,36.32 103.76,36.32 102.11,37.97 101.35,37.97 100.71,38.61 100.71,40.01 99.44,41.27 99.44,41.66 98.81,42.29 98.81,42.83 v1(98.33,43.31)
  BOTTOM w0.132: v1(112.9,30.86) 112.9,29.97 113.67,29.21 113.67,26.34 113.03,25.7 113.03,25.53 112.47,24.97 U137.E7
H_DDR2_D23: length 36
  TOP w0.132: U42.H26 v1(98.18,46.76)
  L12-SIGNAL w0.089: v1(98.18,46.76) 98.18,46.34 99.19,45.34 99.19,42.42 99.79,41.81 99.79,41.43 101.09,40.13 101.09,38.99 101.73,38.35 102.23,38.35 103.89,36.7 106.05,36.7 106.56,36.19 106.68,36.19 106.87,36.38 107,36.38 107.12,36.26 107.12,36.13 106.93,35.94 106.93,35.82 107.06,35.69 107.18,35.69 107.38,35.88 107.5,35.88 107.63,35.76 107.63,35.63 107.44,35.44 107.44,35.31 107.56,35.19 107.69,35.19 107.88,35.38 108,35.38 108.13,35.25 108.13,35.13 107.94,34.93 107.94,34.81 108.46,34.29 108.46,34.16 108.14,33.84 108.14,33.72 108.27,33.59 108.39,33.59 108.71,33.91 109.47,33.91 109.73,33.66 109.73,32.51 109.98,32.26 111.71,32.26 111.71,32.26 112.14,32.26 113.52,30.88 v1(113.52,30.49)
  BOTTOM w0.132: U137.E3 115.44,25.04 115.44,25.27 114.94,25.78 114.63,25.78 114.05,26.37 114.05,29.43 113.52,29.96 v1(113.52,30.49)
H_DDR2_D24: length 37.3
  TOP w0.132: v1(109.14,32.94) 109.86,32.22 109.86,30.73 110.25,30.34 112.16,30.34 113.41,29.08 113.41,26.54 112.78,25.91 112.78,25.68 112.5,25.4 111.89,25.4 U61.D2 ; U42.K27 96.58,45.96 96.58,45.1 v1(96.6,45.09)
  L14-SIGNAL w0.109: v1(109.14,32.94) 109.14,34.12 107.52,35.73 107.37,35.73 107.13,35.49 106.97,35.49 106.82,35.65 106.82,35.8 107.06,36.04 107.06,36.2 106.9,36.35 106.75,36.35 106.46,36.06 106.31,36.06 106.15,36.22 106.15,36.37 106.44,36.66 106.44,36.82 106.29,36.97 106.13,36.97 105.84,36.68 105.69,36.68 105.53,36.83 105.53,36.99 105.79,37.25 105.79,37.47 105.66,37.59 100.08,37.59 99.06,38.61 98.3,38.61 97.28,39.62 97.28,42.16 96.6,42.85 v1(96.6,45.09)
H_DDR2_D25: length 36.7
  TOP w0.132: U61.E3 112.5,25.15 112.65,25.15 113.16,25.65 113.16,25.78 113.79,26.42 113.79,29.34 112.28,30.85 112.03,30.85 111.55,31.33 v1(111.55,31.88) ; U42.K26 v1(96.58,46.76)
  L14-SIGNAL w0.109: v1(111.55,31.88) 111.55,32.42 111.65,32.53 111.65,33.64 111.22,34.07 111.07,34.07 110.78,33.78 110.62,33.78 110.47,33.93 110.47,34.08 110.76,34.37 110.76,34.53 110.6,34.68 110.45,34.68 110.16,34.39 110.01,34.39 109.85,34.55 109.85,34.7 110.14,34.99 110.14,35.15 109.98,35.31 109.46,35.31 109.35,35.2 109.35,35.16 109.25,35.05 108.84,35.05 105.92,37.97 100.33,37.97 97.66,40.64 97.66,42.42 97,43.08 97,45.25 96.58,45.66 v1(96.58,46.76)
H_DDR2_D26: length 36.5
  TOP w0.132: U42.J25 v1(97.38,47.56) ; U61.C7 115.24,26.29 115.01,26.29 114.68,26.62 114.68,31.34 v1(114.15,31.87)
  L14-SIGNAL w0.109: v1(114.15,31.87) 115.13,31.87 115.44,32.18 115.44,32.71 115.05,33.11 115.05,33.42 114.68,33.78 114.43,33.78 113.92,34.29 112.61,34.29 112.38,34.52 112.38,35.83 111.25,36.96 109.98,36.96 108.59,38.35 107.7,38.35 107.43,38.62 107.43,39.51 106.81,40.13 101.85,40.13 100.71,41.27 100.71,42.67 100.08,43.31 100.08,44.32 98.04,46.36 98.02,46.36 97.79,46.6 97.79,46.99 97.78,47 97.78,47.16 v1(97.38,47.56)
H_DDR2_D27: length 36.8
  TOP w0.132: v1(96.18,44.45) U42.K28 ; U61.B3 111.92,27.76 111.92,28.54 111.38,29.08 109.47,29.08 108.76,29.8 108.12,29.8 107.95,29.97 v1(107.95,32.77)
  L14-SIGNAL w0.109: v1(107.95,32.77) 108.35,32.77 108.69,33.1 108.69,34.06 108.32,34.43 108.16,34.43 107.81,34.08 107.66,34.08 107.5,34.23 107.5,34.39 107.85,34.74 107.85,34.89 107.7,35.05 106.68,35.05 106.38,35.35 106.23,35.35 105.74,34.87 105.59,34.87 105.44,35.03 105.44,35.18 105.92,35.66 105.92,35.82 105.76,35.97 105.61,35.97 105.13,35.49 104.97,35.49 104.82,35.64 104.82,35.8 105.3,36.28 105.3,36.43 105.14,36.59 104.99,36.59 104.51,36.11 104.35,36.11 104.2,36.26 104.2,36.42 104.68,36.9 104.68,37.05 104.52,37.21 99.82,37.21 98.93,38.1 98.17,38.1 96.9,39.37 96.9,42.04 96.18,42.75 v1(96.18,44.45)
H_DDR2_D28: length 37.3
  TOP w0.132: U61.E8 116.32,24.97 116.72,25.37 117.45,25.37 117.98,25.91 117.98,28.32 116.59,29.72 116.59,32.89 v1(114.94,34.54) ; U42.H24 v1(98.18,48.36)
  L14-SIGNAL w0.109: v1(98.18,48.36) 98.42,48.36 98.82,47.96 99.1,47.96 99.1,47.96 99.15,47.96 99.38,47.73 99.38,46.39 101.6,44.17 101.6,41.53 102.23,40.89 107.31,40.89 110.49,37.72 111.76,37.72 v1(114.94,34.54)
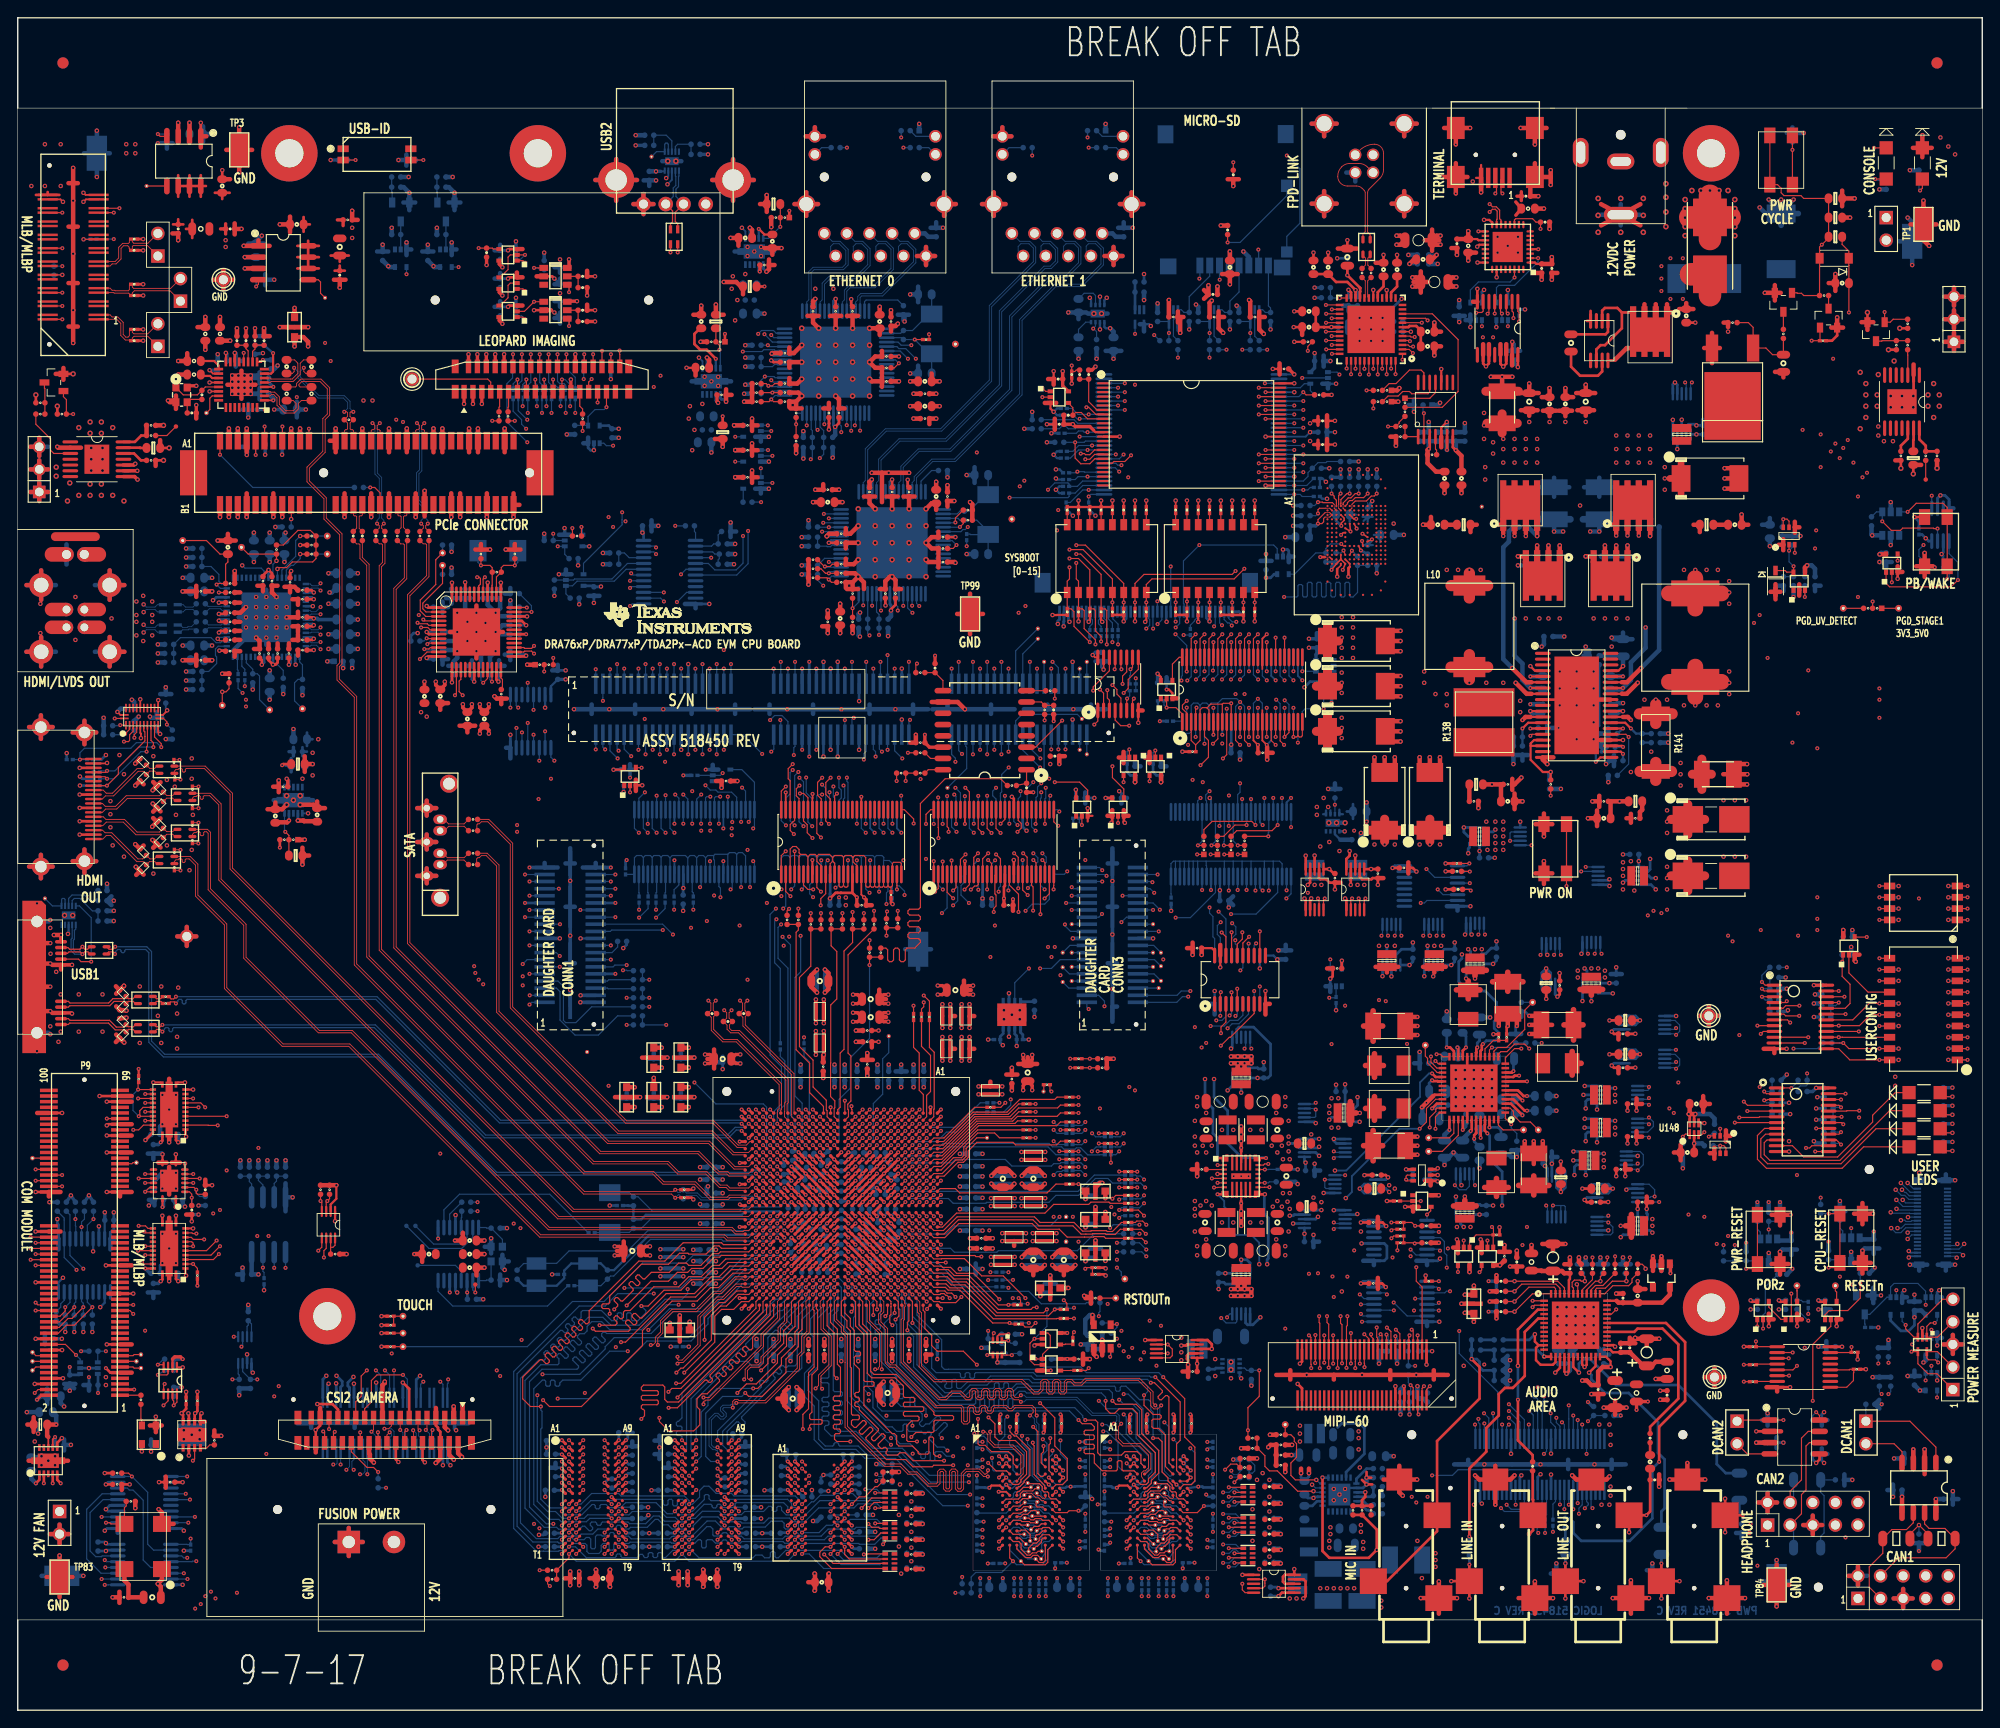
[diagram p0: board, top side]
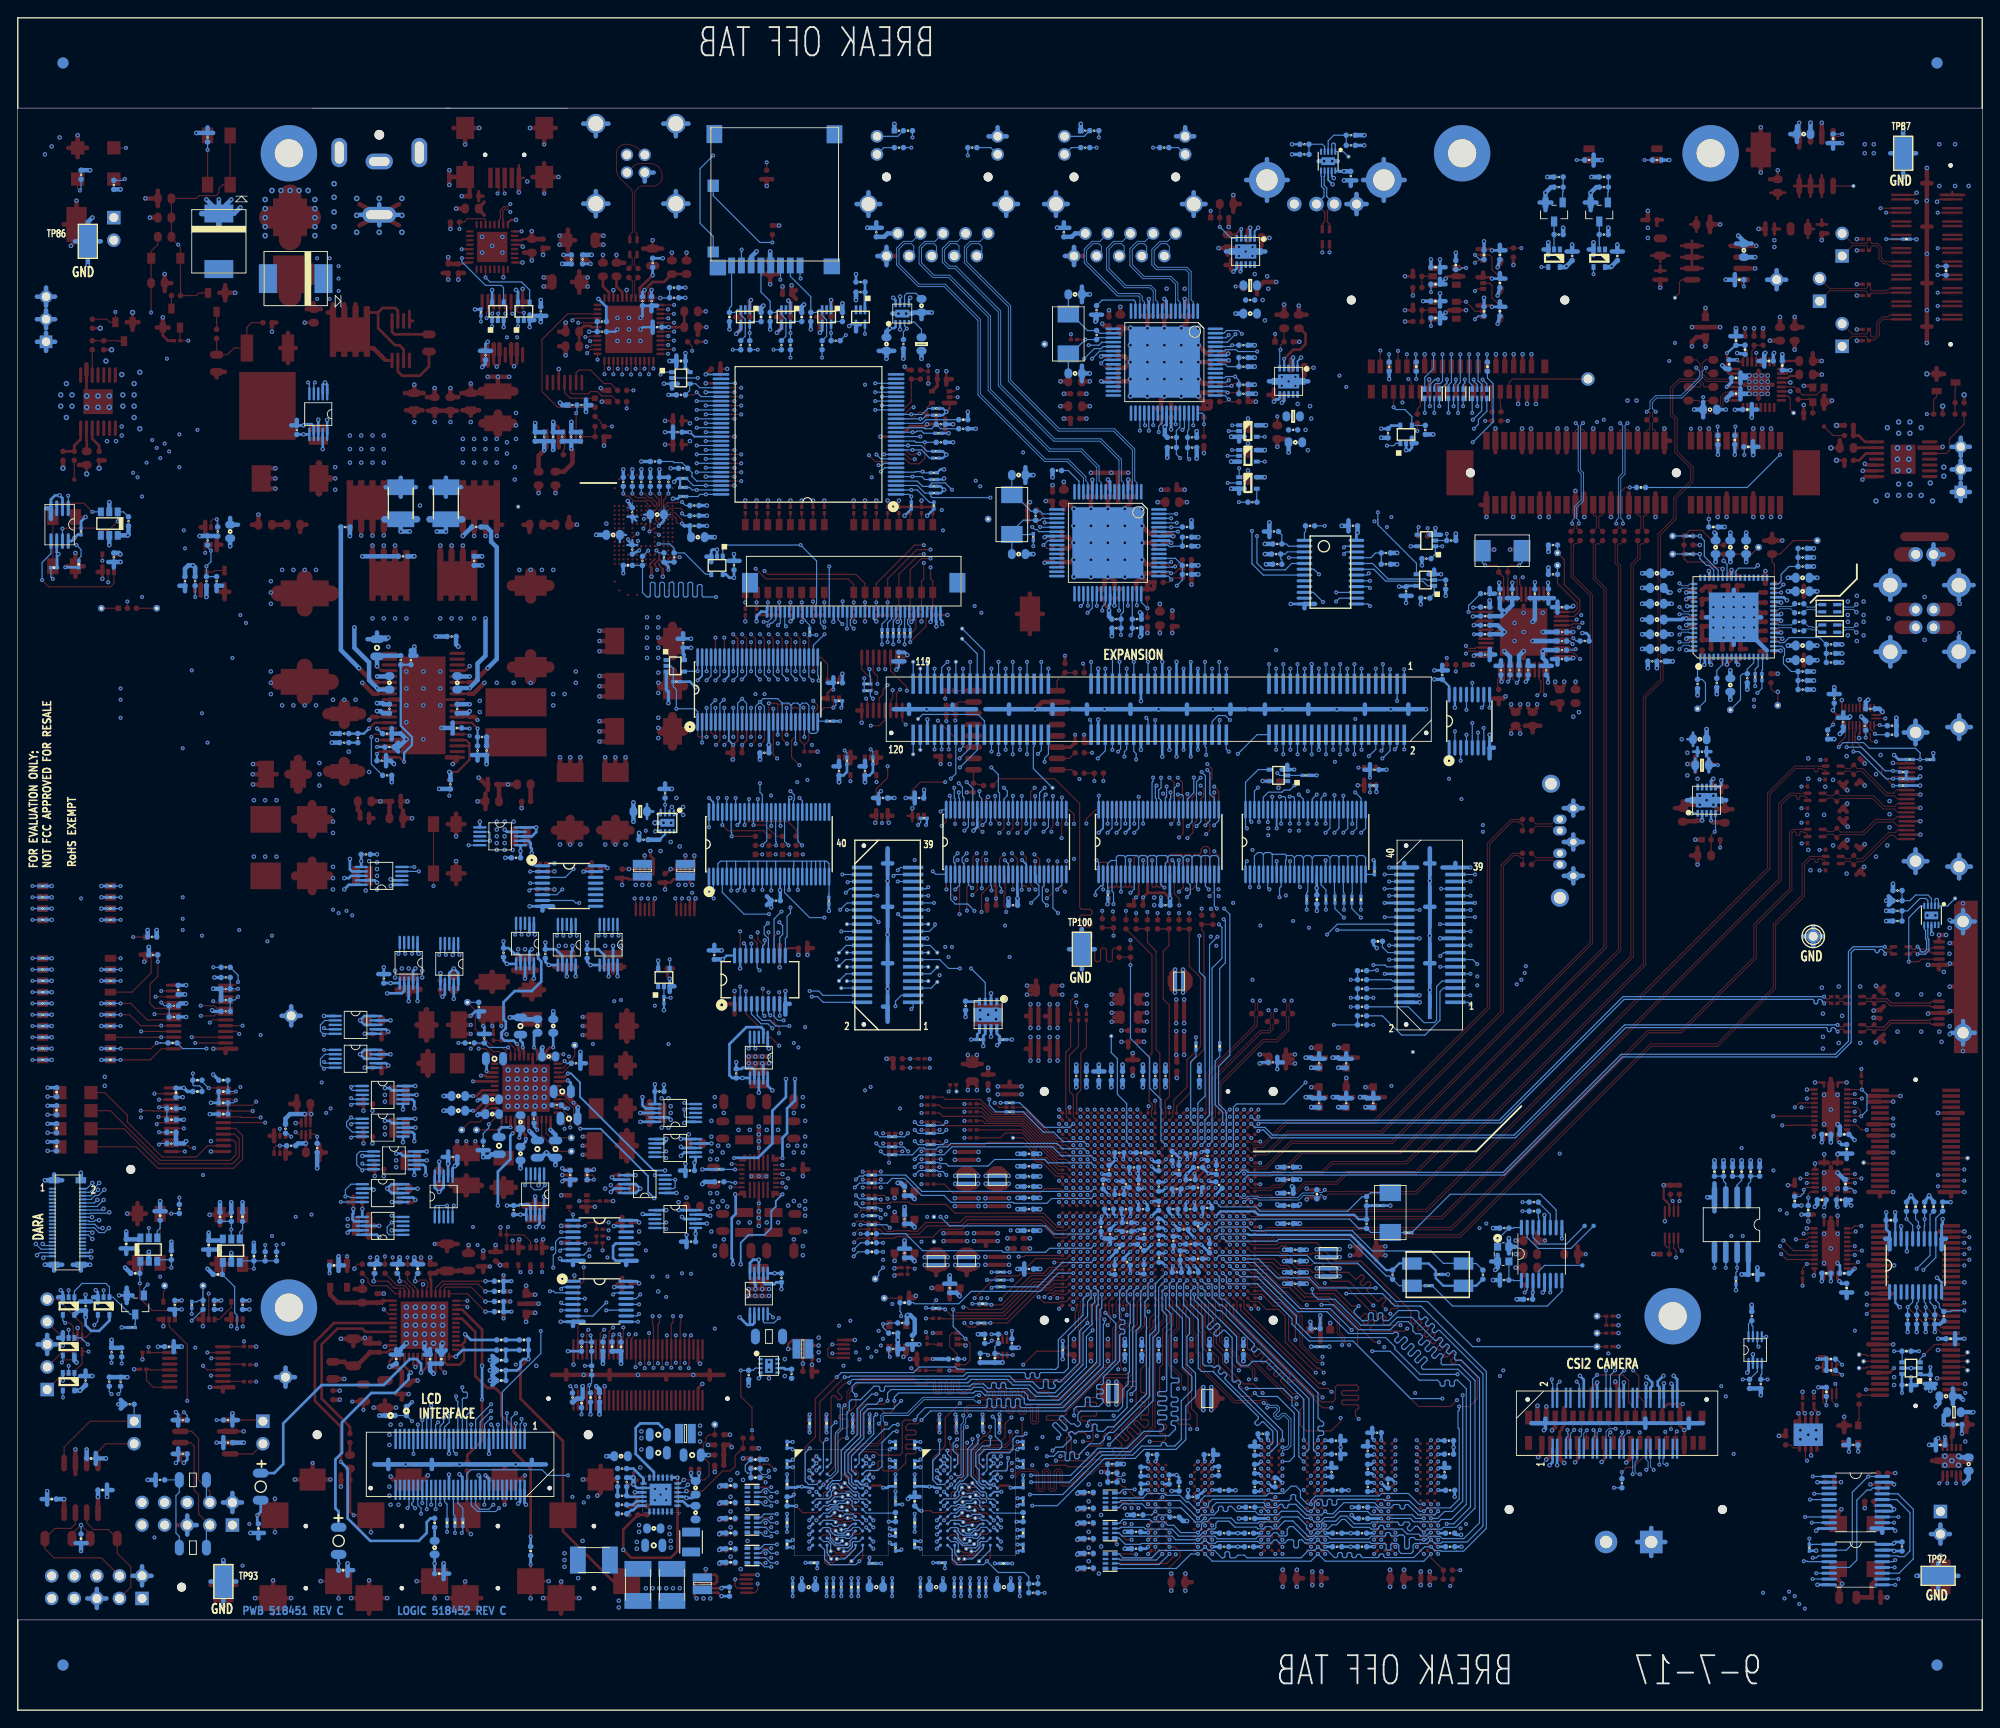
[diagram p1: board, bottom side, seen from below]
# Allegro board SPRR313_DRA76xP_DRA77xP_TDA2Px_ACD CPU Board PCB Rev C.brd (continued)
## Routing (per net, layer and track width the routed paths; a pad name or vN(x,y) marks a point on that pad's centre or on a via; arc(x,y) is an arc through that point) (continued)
H_DDR2_D29: length 36.2
  TOP w0.132: U61.C8 115.93,26.96 115.93,29.84 116.08,30 v1(116.08,30.61) ; U42.J24 v1(97.38,48.36)
  L14-SIGNAL w0.109: v1(116.08,30.61) 116.46,30.61 116.81,30.96 116.81,33.68 116.35,34.15 114.7,34.15 111.51,37.34 110.24,37.34 107.06,40.51 101.98,40.51 101.09,41.4 101.09,43.94 98.58,46.45 98.58,47.73 98.35,47.96 97.96,47.96 97.93,47.98 97.79,47.98 97.41,48.36 v1(97.38,48.36)
H_DDR2_D30: length 36.4
  TOP w0.132: U61.E7 115.44,25.04 115.44,25.27 114.26,26.51 114.26,29.74 114.11,29.9 v1(114.11,30.1) ; U42.K24 v1(96.58,48.36)
  L14-SIGNAL w0.109: v1(96.58,48.36) 96.98,47.96 96.98,47.4 96.98,47.39 96.98,45.89 97.93,44.94 97.93,42.78 101.22,39.5 101.22,38.73 101.6,38.35 106.17,38.35 108.84,35.69 110.37,35.69 110.48,35.58 110.48,35.42 110.62,35.28 110.78,35.28 110.92,35.42 110.92,35.58 111.03,35.69 111.25,35.69 111.63,35.31 111.63,34.16 112,33.8 112,33.11 113.03,32.08 113.03,31.75 114.11,30.67 v1(114.11,30.1)
H_DDR2_D31: length 36.2
  TOP w0.132: v1(109.09,27.81) 109.98,26.92 111.16,26.92 U61.C2 ; U42.L26 v1(95.78,46.76)
  L14-SIGNAL w0.109: v1(109.09,27.81) 109.09,30.23 108.71,30.61 107.19,30.61 106.55,31.24 106.55,32.38 104.27,34.67 103.54,34.67 103.44,34.78 103.44,35.45 103.33,35.56 103.11,35.56 103,35.45 103,34.78 102.89,34.67 102.67,34.67 102.56,34.78 102.56,35.45 102.45,35.56 102.23,35.56 102.13,35.45 102.13,34.78 102.02,34.67 98.81,34.67 98.42,35.06 98.42,35.21 98.64,35.44 98.64,35.59 98.49,35.75 98.34,35.75 98.11,35.52 97.95,35.52 95.5,37.97 95.5,46.48 v1(95.78,46.76)
H_DDR2_DQM0: length 47.1
  TOP w0.132: U42.C27 v1(102.19,45.96)
  L12-SIGNAL w0.089: v1(102.19,45.96) 101.84,45.62 101.84,43.43 102.6,42.67 104.01,42.67 106.05,40.64 107.19,40.64 110.62,37.21 111.89,37.21 111.98,37.12 111.98,36.54 112.06,36.45 112.24,36.45 112.33,36.54 112.33,37.12 112.42,37.21 112.6,37.21 112.69,37.12 112.69,36.54 112.78,36.45 112.95,36.45 113.04,36.54 113.04,37.12 113.13,37.21 113.31,37.21 113.4,37.12 113.4,36.54 113.49,36.45 113.67,36.45 113.75,36.54 113.75,37.12 113.84,37.21 114.05,37.21 116.59,34.67 120.14,34.67 120.78,34.04 123.48,34.04 123.57,33.95 123.57,33.52 123.48,33.43 122.01,33.43 121.92,33.34 121.92,33.17 122.01,33.08 123.74,33.08 123.83,32.99 123.83,32.81 123.74,32.72 122.01,32.72 121.92,32.63 v1(121.92,32.13)
  BOTTOM w0.132: U136.B7 126.26,27.77 126.26,28.8 123.44,31.62 122.94,31.62 122.43,32.13 v1(121.92,32.13)
H_DDR2_DQM1: length 50.6
  TOP w0.132: v1(100.58,43.56) 100.58,45.96 U42.E27 ; v1(127.38,36.84) 127.8,36.84 128.68,35.96 128.68,35.77 128.21,35.3 128.21,35.11 128.4,34.93 128.58,34.93 129.05,35.39 129.24,35.39 129.41,35.22 129.41,27.83 U62.B7
  BOTTOM w0.132: v1(127.38,36.84) 127.01,37.21 114.3,37.21 113.92,37.59 109.35,37.59 108.71,36.96 106.78,36.96 106.02,36.2 105.67,36.2 105.54,36.33 105.54,37.08 105.41,37.21 105.14,37.21 105.01,37.08 105.01,36.33 104.88,36.2 104.39,36.2 104.22,36.37 104.22,36.56 104.41,36.75 104.41,36.94 104.23,37.12 104.04,37.12 103.85,36.93 103.66,36.93 101.47,39.12 101.47,42.67 v1(100.58,43.56)
H_DDR2_DQM2: length 36.3
  TOP w0.132: U42.G23 v1(98.99,49.16)
  L12-SIGNAL w0.089: v1(111.25,33.03) 111.8,33.03 112.01,33.24 112.01,33.79 111,34.8 110.24,34.8 109.6,35.43 109.47,35.43 109.28,35.24 109.16,35.24 109.03,35.37 109.03,35.49 109.22,35.69 109.22,35.81 109.1,35.94 108.97,35.94 108.78,35.75 108.65,35.75 108.53,35.87 108.53,36 108.72,36.19 108.72,36.31 108.59,36.44 108.47,36.44 108.28,36.25 108.15,36.25 108.02,36.37 108.02,36.5 108.22,36.69 108.22,36.82 108.09,36.94 107.96,36.94 107.77,36.75 107.65,36.75 107.52,36.88 107.52,37 107.71,37.19 107.71,37.32 107.57,37.47 104.14,37.47 102.74,38.86 102.74,39.62 101.22,41.15 101.22,42.16 100.2,43.19 100.2,45.6 99.4,46.4 99.4,48.52 99.41,48.53 99.41,48.77 99.02,49.16 v1(98.99,49.16)
  BOTTOM w0.132: U137.B7 112.78,27.83 112.78,28.7 112.14,29.34 110.49,29.34 110.24,29.59 110.24,30.1 110.96,30.83 110.96,32.74 v1(111.25,33.03)
H_DDR2_DQM3: length 36
  TOP w0.132: U61.B7 115.06,27.82 115.06,28.83 115.32,29.08 v1(115.32,29.72) ; U42.J26 v1(97.38,46.76)
  L14-SIGNAL w0.109: v1(97.38,46.76) 97.38,46.25 98.42,45.21 98.72,45.21 99.57,44.36 99.57,41.66 101.53,39.69 102.42,39.69 103.04,39.07 103.72,39.07 104.14,39.5 105.92,39.5 106.3,39.12 106.3,38.73 107.06,37.97 108.33,37.97 108.49,37.81 108.49,37.66 108.07,37.24 108.07,37.09 108.23,36.93 108.38,36.93 108.8,37.35 108.95,37.35 109.11,37.2 109.11,37.04 108.69,36.62 108.69,36.47 108.85,36.32 109,36.32 109.42,36.73 109.57,36.73 109.73,36.58 109.95,36.58 110.06,36.47 110.06,36.18 110.17,36.07 110.39,36.07 110.5,36.18 110.5,36.47 110.61,36.58 111,36.58 112.01,35.56 112.01,34.42 112.52,33.91 113.16,33.91 113.39,33.67 113.39,32.02 114.55,30.86 114.55,30.48 v1(115.32,29.72)
H_DDR2_DQS0_N: length 53
  TOP w0.099: v1(127.89,34.29) 127.64,34.54 127.64,35.81 126.11,37.34 120.01,37.34 119.51,36.83 118.87,36.83 118.49,37.21 117.91,37.21 117.65,36.96 117.65,35.93 117.56,35.83 117.36,35.83 117.26,35.93 117.26,36.96 117,37.21 116.58,37.21 116.33,36.96 116.33,35.93 116.23,35.83 116.03,35.83 115.93,35.93 115.93,36.96 115.68,37.21 115.26,37.21 115,36.96 115,36.14 114.69,35.83 114.31,35.83 112.92,37.21 103.12,37.21 101.6,38.73 101.6,44.7 101.41,44.9 101.41,45.94 U42.D27
  BOTTOM w0.099: U136.D3 129.57,26.07 129.38,26.07 128.64,26.81 128.64,31.13 128.13,31.64 128.13,34.05 v1(127.89,34.29)
H_DDR2_DQS0_P: length 53
  TOP w0.099: U42.D28 101.14,45.4 101.14,44.79 101.33,44.59 101.33,38.62 103.01,36.94 112.81,36.94 114.2,35.56 114.8,35.56 115.27,36.03 115.27,36.85 115.37,36.94 115.57,36.94 115.67,36.85 115.67,35.82 115.92,35.56 116.34,35.56 116.6,35.82 116.6,36.85 116.69,36.94 116.89,36.94 116.99,36.85 116.99,35.82 117.25,35.56 117.67,35.56 117.92,35.82 117.92,36.85 118.02,36.94 118.38,36.94 118.76,36.56 119.62,36.56 120.13,37.07 126,37.07 127.37,35.7 127.37,34.25 127.72,33.89 128.15,33.89 v1(128.55,34.29)
  BOTTOM w0.099: U136.C3 129.64,26.33 129.5,26.33 128.91,26.92 128.91,31.24 128.4,31.75 128.4,34.14 v1(128.55,34.29)
H_DDR2_DQS1_N: length 51.1
  TOP w0.099: U42.F28 99.43,45.52 99.43,44.05 99.3,43.93 99.3,39.13 103.51,34.92 104.39,34.92 105.1,35.64 105.91,35.64 106.62,34.92 107.04,34.92 107.29,35.18 107.29,35.83 107.39,35.93 107.59,35.93 107.69,35.83 107.69,35.18 107.94,34.92 108.36,34.92 108.62,35.18 108.62,35.83 108.72,35.93 108.91,35.93 109.01,35.83 109.01,35.18 109.27,34.92 109.69,34.92 109.94,35.18 109.94,35.83 110.04,35.93 110.24,35.93 110.34,35.83 110.34,35.18 110.59,34.92 111.01,34.92 111.27,35.18 111.27,35.83 111.37,35.93 111.57,35.93 111.66,35.83 111.66,35.28 112.02,34.92 112.54,34.92 v1(112.78,34.69) ; v1(123.22,32.23) 123.47,31.98 123.47,30.45 124.21,29.72 126.11,29.72 127.11,28.71 127.11,27.26 126.78,26.92 126.58,26.92 126.33,26.68 126.33,26.29 U62.D3
  BOTTOM w0.099: v1(123.22,32.23) 123.56,32.56 123.56,33.05 123.46,33.15 120.76,33.15 118.97,34.93 113.37,34.93 113.13,34.69 v1(112.78,34.69)
H_DDR2_DQS1_P: length 51
  TOP w0.099: v1(112.78,35.43) 112.53,35.19 112.13,35.19 111.93,35.39 111.93,35.94 111.68,36.2 111.26,36.2 111,35.94 111,35.29 110.9,35.19 110.7,35.19 110.61,35.29 110.61,35.94 110.35,36.2 109.93,36.2 109.68,35.94 109.68,35.29 109.58,35.19 109.38,35.19 109.28,35.29 109.28,35.94 109.02,36.2 108.61,36.2 108.35,35.94 108.35,35.29 108.25,35.19 108.05,35.19 107.95,35.29 107.95,35.94 107.7,36.2 107.28,36.2 107.02,35.94 107.02,35.29 106.93,35.19 106.73,35.19 106.02,35.9 104.99,35.9 104.28,35.19 103.62,35.19 99.57,39.24 99.57,43.81 99.69,43.94 99.69,45.34 99.76,45.4 99.76,45.72 99.69,45.78 99.69,46.05 U42.F27 ; U62.C3 126.8,26.57 127.38,27.15 127.38,28.83 126.22,29.98 124.32,29.98 123.74,30.57 123.74,31.92 v1(124.05,32.23)
  BOTTOM w0.099: v1(112.78,35.43) 113.13,35.43 113.37,35.19 119.09,35.19 120.87,33.41 123.57,33.41 123.83,33.16 123.83,32.45 v1(124.05,32.23)
H_DDR2_DQS2_N: length 40.4
  TOP w0.099: U42.J28 97.09,45.45 97.09,44.89 96.77,44.57 96.77,43.56 97.52,42.82 97.52,39.06 98.01,38.58 98.59,38.58 103.14,34.02 105.99,34.02 106.09,33.92 106.09,32.45 106.34,32.19 106.76,32.19 107.02,32.45 107.02,33.92 107.12,34.02 107.33,34.02 107.43,33.92 107.43,33.53 107.68,33.27 108.1,33.27 108.36,33.53 108.36,33.92 108.46,34.02 108.67,34.02 108.77,33.92 108.77,33.66 109.02,33.4 109.44,33.4 109.7,33.66 109.7,33.92 109.8,34.02 111.02,34.02 111.37,33.67 111.79,33.67 112.14,34.02 113.94,34.02 114.16,33.8 114.16,33.52 v1(113.79,33.15)
  BOTTOM w0.099: v1(113.79,33.15) 113.92,33.15 114.29,32.78 114.29,32.27 114.54,32.02 114.54,26.41 114.8,26.15 115.14,26.15 U137.D3
H_DDR2_DQS2_P: length 40.4
  TOP w0.099: v1(114.55,33.15) 114.43,33.27 114.43,33.91 114.05,34.29 112.03,34.29 111.68,33.94 111.48,33.94 111.13,34.29 109.69,34.29 109.43,34.03 109.43,33.77 109.33,33.67 109.13,33.67 109.04,33.77 109.04,34.03 108.78,34.29 108.35,34.29 108.09,34.03 108.09,33.64 107.99,33.54 107.79,33.54 107.69,33.64 107.69,34.03 107.44,34.29 107.01,34.29 106.75,34.03 106.75,32.56 106.65,32.46 106.45,32.46 106.35,32.56 106.35,34.03 106.1,34.29 103.25,34.29 98.7,38.84 98.12,38.84 97.79,39.17 97.79,42.93 97.04,43.68 97.04,44.46 97.36,44.78 97.36,45.98 U42.J27
  BOTTOM w0.099: v1(114.55,33.15) 114.55,32.38 114.81,32.13 114.81,26.52 114.91,26.42 115.37,26.42 U137.C3
H_DDR2_DQS3_N: length 38
  TOP w0.099: v1(109.32,31.33) 109.32,30.38 109.86,29.84 111.88,29.84 113.03,28.7 113.03,26.57 112.54,26.09 112.54,25.99 U61.D3 ; v1(97.14,38.35) 97.14,42.49 95.76,43.86 95.76,45.98 U42.L27
  L14-SIGNAL w0.089: v1(97.14,38.35) 97.14,38.02 97.46,37.69 98.65,37.69 99.51,36.83 99.71,36.83 99.94,36.61 99.94,35.37 100.03,35.28 100.2,35.28 100.29,35.37 100.29,36.61 100.51,36.83 100.88,36.83 101.1,36.61 101.1,35.37 101.19,35.28 101.37,35.28 101.46,35.37 101.46,35.85 102.45,36.83 103.07,36.83 107.52,32.38 107.79,32.38 108.85,32.38 109.32,31.9 v1(109.32,31.33)
H_DDR2_DQS3_P: length 38
  TOP w0.099: v1(108.53,31.33) 108.76,31.33 109.06,31.03 109.06,30.27 109.74,29.58 111.77,29.58 112.76,28.59 112.76,26.68 112.55,26.47 112.41,26.47 U61.C3 ; U42.L28 95.4,45.56 95.49,45.46 95.49,43.75 96.87,42.38 96.87,38.65 96.74,38.51 96.74,38.4 96.69,38.35 v1(96.39,38.35)
  L14-SIGNAL w0.089: v1(108.53,31.33) 108.85,31.33 108.93,31.41 108.93,31.49 109.09,31.64 109.09,31.81 108.75,32.15 107.42,32.15 102.97,36.6 102.54,36.6 101.69,35.75 101.69,35.27 101.47,35.05 101.1,35.05 100.88,35.27 100.88,36.51 100.79,36.6 100.61,36.6 100.52,36.51 100.52,35.27 100.3,35.05 99.93,35.05 99.71,35.27 99.71,36.51 99.62,36.6 99.42,36.6 98.55,37.47 97.37,37.47 96.75,38.08 96.75,38.28 96.69,38.35 v1(96.39,38.35)
H_DDR2_ODT0: length 87.1
  TOP w0.132: U61.G1 111.1,23.75 112.5,23.75 112.71,23.96 112.71,24.35 113.03,24.66 114.1,24.66 114.35,24.92 114.58,24.92 TP2MA3.1 ; TP2MB3.1 128.93,24.92 128.7,24.92 128.45,24.66 127.38,24.66 127.06,24.35 127.06,23.96 126.85,23.75 125.45,23.75 U62.G1 ; U42.K25 v1(96.58,47.56) ; RN1.2 v1(136.78,24.51)
  L12-SIGNAL w0.089: TP2MA3.1 114.48,24.82 114.25,24.82 114.13,24.7 113.48,24.7 113.41,24.77 112.8,24.77 112.17,24.13 109.47,24.13 108.46,25.15 106.81,25.15 106.42,25.53 106.42,28.58 104.52,30.48 104.52,30.99 103.4,32.12 103.27,32.12 102.63,31.48 102.51,31.48 102.38,31.6 102.38,31.73 103.02,32.37 103.02,32.49 102.88,32.64 102.62,32.64 v1(102.11,33.15)
  L14-SIGNAL w0.109: TP2MA3.1 115.3,24.45 116.19,24.45 116.46,24.18 117.91,24.18 118.24,24.51 121.67,24.51 121.98,24.19 125.67,24.19 126.06,24.59 128.42,24.59 128.63,24.79 128.8,24.79 TP2MB3.1 129.98,24.12 132.84,24.12 133.6,24.89 135.72,24.89 136.11,24.51 v1(136.78,24.51)
  BOTTOM w0.132: TP2MB3.1 129.18,24.92 129.18,24.74 129.39,24.54 129.39,24.14 129.76,23.77 131.06,23.77 U136.G1 ; TP2MA3.1 114.83,24.92 114.83,24.74 115.04,24.54 115.04,24.16 115.42,23.77 116.71,23.77 U137.G1 ; v1(96.58,47.56) 96.96,47.19 96.96,46.95 96.98,46.93 96.98,45.27 97,45.25 97,44.92 96.98,44.9 96.98,44.04 96.85,43.91 96.53,43.91 96.39,43.78 96.39,43.51 96.53,43.38 96.85,43.38 96.98,43.25 96.98,42.98 96.85,42.85 96.53,42.85 96.39,42.72 96.39,42.46 96.53,42.32 96.85,42.32 96.98,42.19 96.98,39.29 98.81,37.46 98.81,36.77 98.94,36.63 99.44,36.63 99.57,36.5 99.57,36.24 99.44,36.11 98.94,36.11 98.81,35.97 98.81,35.71 98.94,35.58 99.44,35.58 99.57,35.45 99.57,35.18 99.44,35.05 98.94,35.05 98.81,34.92 98.81,34.67 99.31,34.16 100.18,34.16 100.31,34.3 100.31,35.08 100.44,35.21 100.71,35.21 100.84,35.08 100.84,34.3 100.97,34.16 101.83,34.16 102.11,33.88 v1(102.11,33.15)
H_DDR2_RASN: length 82.8
  TOP w0.132: v1(136.78,25.64) 137.08,25.93 137.08,25.95 R278.1 ; TP2MB2.1 127.41,25.07 126.95,24.61 126.8,24.61 126.67,24.49 U62.F3 ; U42.R26 v1(91.78,46.76) ; TP2MA2.1 113.06,25.07 112.6,24.61 112.45,24.61 112.32,24.49 U61.F3
  L12-SIGNAL w0.089: v1(106.93,25.65) 107.95,25.65 108.2,25.4 110.36,25.4 110.87,24.89 111.48,24.89 111.66,25.07 TP2MA2.1
  L14-SIGNAL w0.109: v1(136.78,25.64) 134.96,25.64 134.52,25.2 133.4,25.2 132.94,24.74 132.33,24.74 132.08,24.99 129.87,24.99 129.26,25.6 128.77,25.6 TP2MB2.1 125.91,25.07 125.83,24.99 124.36,24.99 123.83,25.53 122.94,25.53 122.81,25.4 119.63,25.4 119.51,25.53 118.11,25.53 117.73,25.15 116.44,25.15 116.29,24.99 115.36,24.99 114.94,25.42 114.55,25.42 114.2,25.07 TP2MA2.1
  BOTTOM w0.132: U136.F3 129.87,24.41 129.52,24.76 129.52,25.17 129.21,25.48 128.65,25.48 TP2MB2.1 ; v1(106.93,25.65) 102.62,25.65 99.19,29.08 95.76,29.08 93.98,30.86 91.44,30.86 90.7,31.6 90.7,31.9 90.84,32.03 91.05,32.03 91.19,32.16 91.19,32.43 91.05,32.56 90.56,32.56 90.42,32.69 90.42,32.95 90.56,33.09 91.05,33.09 91.19,33.22 91.19,33.48 91.05,33.61 90.56,33.61 90.42,33.75 90.42,34.01 90.56,34.14 91.05,34.14 91.19,34.27 91.19,34.54 91.05,34.67 90.56,34.67 90.42,34.8 90.42,35.07 90.56,35.2 91.05,35.2 91.19,35.33 91.19,36.7 91.05,36.83 90.43,36.83 90.3,36.96 90.3,37.22 90.43,37.36 91.05,37.36 91.19,37.49 91.19,44.58 91.78,45.17 v1(91.78,46.76) ; U137.F3 115.52,24.41 115.17,24.76 115.17,25.17 114.86,25.48 114.3,25.48 TP2MA2.1
H_DDR2_RST: length 39.3
  TOP w0.132: U62.N2 125.87,17.13 v1(126.24,16.76) ; U61.N2 111.52,17.13 v1(111.89,16.76)
  L12-SIGNAL w0.089: v1(111.89,16.76) 112.26,17.14 112.93,17.14 113.94,16.13 116.08,16.13 116.31,16.36 116.87,16.36 117.09,16.13 118.34,16.13 118.87,16.66 122.91,16.66 123.57,16 125.48,16 v1(126.24,16.76)
  BOTTOM w0.132: v1(126.24,16.76) 126.63,16.37 129.53,16.37 130.15,16.99 130.15,18.05 U136.N2 ; R699.1 R698.1 107.19,14.99 107.7,15.49 110.62,15.49 v1(111.89,16.76) 112.28,16.37 115.18,16.37 115.8,16.99 115.8,18.05 U137.N2
H_DDR2_WEN: length 80.3
  TOP w0.132: U42.T24 v1(90.98,48.36) ; RN1.4 v1(136.78,23.43) ; TP2MA9.1 113.82,22.9 113.09,22.9 112.76,22.57 U61.H3 ; U62.H3 127.11,22.57 127.46,22.91 128.16,22.91 TP2MB9.1
  L14-SIGNAL w0.109: v1(136.78,23.43) 136.78,22.83 136.42,22.47 135.88,22.47 135.76,22.59 132.48,22.59 132.26,22.81 131.87,22.81 131.65,22.59 130.63,22.59 130.53,22.68 128.78,22.68 128.6,22.86 TP2MB9.1 126.11,22.86 125.81,22.56 125.15,22.56 124.87,22.83 123.66,22.83 123.39,22.56 120.95,22.56 120.62,22.89 117.37,22.89 117.08,22.59 116.57,22.59 116.55,22.6 114.3,22.6 114.28,22.59 114.13,22.59 TP2MA9.1 113.78,22.94 111.94,22.94 111.51,23.37 108.35,23.37 107.46,24.26 v1(107.06,24.26)
  BOTTOM w0.132: v1(107.06,24.26) 103.38,24.26 98.93,28.7 95.5,28.7 94.49,29.72 92.42,29.72 92.28,29.85 92.28,29.97 92.15,30.1 91.89,30.1 91.76,29.97 91.76,29.85 91.62,29.72 90.78,29.72 90.04,30.45 90.04,34.8 88.85,35.99 88.85,37.54 89.92,38.61 89.92,44.07 91.38,45.53 91.38,47.96 v1(90.98,48.36) ; U136.H3 129.63,22.57 129.34,22.86 TP2MB9.1 ; U137.H3 115.28,22.57 115.01,22.83 114.27,22.83 114.25,22.86 TP2MA9.1
H_EMU0: length 41.6
  TOP w0.132: J13.19 v1(153.88,42.25)
  L10-SIGNAL w0.089: v1(126.11,53.59) 126.11,51.05 127,50.17 127,45.85 128.52,44.32 v1(128.52,43.25)
  L14-SIGNAL w0.109: v1(153.88,42.25) 153.03,41.4 150.11,41.4 148.46,43.05 145.29,43.05 144.53,43.81 141.22,43.81 140.65,43.24 129.73,43.24 129.73,43.25 v1(128.52,43.25)
  BOTTOM w0.132: R638.2 154.05,42.07 v1(153.88,42.25) ; R593.1 v1(126.11,53.59)
H_EMU1: length 38.2
  TOP w0.132: J13.21 153.38,42.14 v1(153.22,42.3)
  L14-SIGNAL w0.109: v1(153.22,42.3) 152.71,41.78 151.26,41.78 149.61,43.43 145.29,43.43 144.53,44.2 141.1,44.2 140.37,43.46 133.95,43.46 133.73,43.69 128.14,43.69 127.76,43.31 124.97,43.31 124.23,44.04 121.82,44.04 v1(121.54,44.32)
  BOTTOM w0.132: R637.2 153.03,42.04 153.22,42.22 v1(153.22,42.3) ; R611.1 121.67,44.86 121.54,44.73 v1(121.54,44.32)
H_ENET_INTSN: length 123.2
  TOP w0.132: U42.F18 v1(99.79,53.16)
  L3-SIGNAL w0.109: v1(109.86,88.27) 98.76,88.27 98.73,88.29 87.02,88.29 86.23,87.5 81.92,87.5 v1(81.15,88.27)
  L12-SIGNAL w0.089: v1(99.79,53.16) 100.17,53.55 100.17,63.7 100.45,63.98 100.75,63.98 101,64.23 101,64.55 101.22,64.77 101.54,64.77 101.8,65.03 101.8,65.35 102,65.55 104.03,65.55 105.54,67.06 107.06,67.06 109.09,69.09 109.09,72.26 108.08,73.28 108.08,86.49 v1(109.86,88.27) ; v1(83.57,135.89) 83.57,125.22 82.17,123.83 82.17,106.68 83.41,105.44 83.41,92.68 81.15,90.42 v1(81.15,88.27)
  BOTTOM w0.132: R394.1 v1(83.57,135.89)
H_GP1[2]_TOUCH_EVT: length 256.5
  TOP w0.132: U42.AB20 v1(86.18,51.56) ; R259.1 R257.2 TP73.1
  L12-SIGNAL w0.089: v1(56.77,83.93) 43.18,70.34 43.18,44.99 43.31,44.86 TP73.1 42.67,43.69 42.67,40.64 44.07,39.24 44.07,35.43 47.01,32.49 47.01,30.5 46.35,29.84 46.35,22.73 57.28,11.81 149.86,11.81 156.34,18.29 157.61,18.29 158.5,19.18 163.03,19.18 163.03,19.17 163.36,19.17 163.36,19.18 171.7,19.18 v1(172.59,20.07)
  L14-SIGNAL w0.109: v1(86.18,51.56) 85.78,51.96 79.11,51.96 78.85,52.21 75.77,52.21 75.24,51.69 75.24,51.68 75,51.43 72.11,51.43 70.46,49.78 66.17,49.78 60.71,44.32 54.04,44.32 53.18,45.18 44.17,45.18 TP73.1
  BOTTOM w0.132: R655.1 v1(172.59,20.07) ; EXP_P1.13 57.27,84.43 v1(56.77,83.93)
H_GP1[3]: length 432.6
  TOP w0.132: U42.AB21 v1(86.18,50.76) ; R253.1 TP72.1
  L3-SIGNAL w0.109: v1(201.17,71.63) 200.03,70.48 200.03,61.72 199.14,60.83 199.14,56.9 198.69,56.45 198.69,41.85 197.61,40.77 197.61,28.19 194.44,25.02 194.44,21.46 194.18,21.21 194.18,17.65 v1(195.58,16.26)
  L7-SIGNAL w0.089: v1(66.67,84.43) 70.84,84.43 73.03,86.61 73.03,91.44 72.39,92.08 67.38,92.08 67.34,92.03 66.47,92.03 65.66,92.84 65.66,95.38 67.94,97.66 73.79,97.66 75.31,99.19 75.31,100.97 74.42,101.85 74.42,107.57 74.04,107.95 74.04,117.35 74.55,117.86 74.55,125.6 70.99,129.16 70.99,130.81 71.75,131.57 72.26,131.57 v1(73.91,133.22) ; TP72.1 46.61,37.59 46.61,35.18 50.16,31.62 50.16,29.59 50.55,29.21 50.55,27.3 50.04,26.8 50.04,17.02 55.91,11.14 190.47,11.14 v1(195.58,16.26)
  L10-SIGNAL w0.089: v1(201.17,71.63) 201.17,74.04 199.77,75.44 199.77,82.68 v1(198.88,83.57)
  L12-SIGNAL w0.089: v1(66.67,84.43) 61.7,84.43 61.47,84.2 60.58,84.2 43.94,67.56 43.94,41.53 TP72.1
  BOTTOM w0.132: v1(201.17,71.63) R498.1 201.17,70.36 201.04,70.23 200.41,70.23 200.15,69.98 R502.2 ; v1(86.18,50.76) 85.78,51.16 75.92,51.16 75.06,50.29 70.23,50.29 65.91,45.97 62.36,45.97 57.28,40.89 TP72.1 ; 197.99,83.57 v1(198.88,83.57) ; v1(66.67,84.43) EXP_P1.14 ; R400.1 v1(73.91,133.22)
H_GP2[22]: length 13.7
  TOP w0.132: U42.L6 v1(95.78,63.56)
  BOTTOM w0.132: v1(95.78,63.56) 96.18,63.96 96.18,68.24 97.23,69.29 97.23,73.28 97.92,73.96 TP55.1
H_GP2[27]: length 63.4
  TOP w0.132: U42.M4 v1(94.98,65.16)
  L7-SIGNAL w0.089: v1(101.49,104.74) 101.22,104.47 101.22,99.06 97.92,95.76 97.92,92.33 95.89,90.3 95.89,88.65 96.27,88.27 96.27,72.82 96.23,72.79 96.23,71.09 94.61,69.47 94.61,67.73 94.61,67.72 94.61,65.81 94.61,65.8 94.61,65.53 v1(94.98,65.16)
  L10-SIGNAL w0.089: v1(101.49,104.74) 101.91,105.16 115.57,105.16 115.94,104.78 v1(115.96,104.78)
  BOTTOM w0.132: EXP_P2.108 115.39,105.35 v1(115.96,104.78)
H_GP5[0]: length 155.2
  TOP w0.132: U42.A13 v1(103.79,57.96)
  L7-SIGNAL w0.089: v1(79.38,119.25) 79.38,117.86 78.74,117.22 78.74,115.95 77.78,114.99 v1(77.78,108.03)
  L10-SIGNAL w0.089: v1(79.38,119.25) 81.79,119.25 81.79,119.26 109.13,119.26 109.13,119.25 129.38,119.25 v1(131.07,120.94)
  L14-SIGNAL w0.109: v1(103.79,57.96) 105.21,57.96 105.41,58.17 118.62,58.17 118.86,58.4 124.19,58.4 124.84,59.05 124.84,67.69 126.24,69.09 126.24,73.15 130.81,77.72 130.81,87.76 131.32,88.27 131.32,91.12 130.43,92.01 130.43,109.47 131.86,110.9 131.86,114.14 130.43,115.57 130.43,120.3 v1(131.07,120.94)
  BOTTOM w0.132: R434.2 v1(131.07,120.94) ; EXP_P2.34 v1(77.78,108.03)
H_GP5[1]: length 115.9
  TOP w0.132: U42.F14 v1(99.79,57.16)
  L3-SIGNAL w0.109: v1(120.02,95.63) 118.11,93.73 86.49,93.73 85.72,94.49 81.79,94.49 80.39,93.09 79.73,93.09 v1(78.28,91.64)
  L7-SIGNAL w0.089: v1(120.02,95.63) 120.02,77.47 114.94,72.39 114.94,69.78 114.92,69.76 114.92,69.32 108.84,63.25 103.5,63.25 102.65,62.39 99.6,62.39 99.37,62.16 99.37,57.58 v1(99.79,57.16)
  L12-SIGNAL w0.089: v1(78.28,91.64) 78.28,92.38 79.76,93.85 79.76,102.28 79.35,102.68 79.35,102.92 78.58,103.69 v1(78.58,107.52)
  BOTTOM w0.132: EXP_P2.36 v1(78.58,107.52)
H_GP5[4]: length 85.4
  TOP w0.132: U43.4 21.99,50.69 v1(22.61,51.31) ; U42.E13 v1(100.59,57.96)
  L10-SIGNAL w0.089: v1(100.59,57.96) 100.17,57.55 81.17,57.55 79.76,56.13 55.39,56.13 53.48,54.23 28.86,54.23 28.79,54.31 27.6,54.31 27.53,54.23 25.53,54.23 v1(22.61,51.31)
H_GP5[5]: length 88.9
  TOP w0.132: U42.E11 v1(100.59,59.56) ; U39.5 v1(23.48,66.81)
  L10-SIGNAL w0.089: v1(23.48,60.72) 43.55,60.72 43.94,60.33 82.47,60.33 82.82,59.98 83.14,59.98 83.14,59.98 100.17,59.98 v1(100.59,59.56)
  L14-SIGNAL w0.109: v1(23.48,66.81) v1(23.48,60.72)
H_GP5[6]: length 88
  TOP w0.132: U43.6 21.21,51.69 v1(22.35,52.83) ; U42.E12 v1(100.59,58.76)
  L10-SIGNAL w0.089: v1(100.59,58.76) 100.17,59.18 82.16,59.18 81.66,58.67 78.36,58.67 77.72,58.04 75.69,58.04 74.55,56.9 70.99,56.9 70.23,57.66 46.99,57.66 45.59,56.26 22.74,56.26 v1(22.73,56.27)
  L14-SIGNAL w0.109: v1(22.73,56.27) 22.73,55.37 22.35,54.99 v1(22.35,52.83)
H_GP5[7]: length 95.6
  TOP w0.132: U42.D13 v1(101.39,57.96) ; U39.3 21.4,65.81 21.43,65.79 v1(22.48,65.79)
  L10-SIGNAL w0.089: v1(21.97,55.88) 47.12,55.88 47.88,56.64 52.58,56.64 53.21,57.28 69.72,57.28 70.49,56.52 78.23,56.52 80.07,58.35 101,58.35 v1(101.39,57.96)
  L14-SIGNAL w0.109: v1(21.97,55.88) 21.97,58.04 22.48,58.55 v1(22.48,65.79)
H_GP5[8]: length 95.2
  TOP w0.132: v1(22.73,52.2) 21.73,51.19 U43.5 ; U42.C11 v1(102.19,59.56)
  L10-SIGNAL w0.089: v1(102.19,59.56) 101.8,59.95 101.8,61.4 101.62,61.58 81.93,61.58 81.28,62.23 50.67,62.23 49.66,63.25 v1(27.05,63.25)
  L14-SIGNAL w0.109: v1(22.73,52.2) 23.11,52.58 23.11,54.74 26.46,58.08 26.46,62.65 v1(27.05,63.25)
H_GP5[9]: length 195.6
  TOP w0.132: v1(5,168.45) P5.34 ; U42.D12 v1(101.39,58.76)
  L10-SIGNAL w0.089: v1(101.39,58.76) 101,59.15 101,60.5 100.75,60.75 82.82,60.75 82.78,60.71 80.9,60.71 80.01,61.59 49.91,61.59 48.9,62.61 v1(47.5,62.61)
  L14-SIGNAL w0.109: v1(5,168.45) 5,166.29 2.41,163.7 2.41,152.65 3.3,151.76 9.65,151.76 14.1,147.32 14.1,136.14 17.53,132.72 17.53,132.7 17.76,132.46 24.38,132.46 26.29,130.56 29.85,130.56 32,128.4 33.53,128.4 34.67,127.25 35.31,127.25 36.32,126.24 36.32,118.75 35.69,118.11 35.69,116.84 37.08,115.44 37.08,90.68 47.5,80.26 v1(47.5,62.61)
H_GP5[17]: length 49.6
  TOP w0.132: U42.U2 v1(90.18,66.77)
  L5-SIGNAL w0.089: v1(90.18,66.77) 90.18,70.6 90.04,70.74 90.04,72.01 88.9,73.15 88.9,80.52 82.93,86.49 82.93,90.04 81.93,91.04 81.93,92.52 80.09,94.36 79.5,94.36 78.21,95.65 78.21,95.66 77.98,95.89 77.97,95.89 77.34,96.52 77.34,100.33 77.47,100.46 77.47,103.12 76.83,103.76 76.83,106.43 76.98,106.57 v1(76.98,107.52)
  BOTTOM w0.132: EXP_P2.32 v1(76.98,107.52)
H_GP6[17]: length 112.5
  TOP w0.132: U42.D18 v1(101.39,53.16)
  L3-SIGNAL w0.109: v1(116.59,85.85) 116.08,85.34 111.63,85.34 111.38,85.6 89.03,85.6 88.77,85.34 87.12,85.34 85.98,84.2 68.96,84.2 68.33,84.84 v1(60.93,84.84)
  L5-SIGNAL w0.089: v1(116.59,85.85) 116.71,85.72 116.71,84.33 116.59,84.2 116.59,79.88 116.97,79.5 116.97,71.12 118.49,69.6 118.49,58.04 119.76,56.77 119.76,54.99 119.25,54.48 v1(119.25,52.7)
  L12-SIGNAL w0.089: v1(119.25,52.7) 119.25,52.67 118.78,52.2 110.49,52.2 110.01,52.67 106.89,52.67 106.81,52.75 102.35,52.75 102.34,52.75 101.8,52.75 v1(101.39,53.16)
  BOTTOM w0.132: EXP_P1.15 60.55,85.22 v1(60.93,84.84)
H_GP6[20]: length 45.6
  TOP w0.132: U42.A22 v1(104.33,50.36)
  L5-SIGNAL w0.089: v1(114.94,83.44) 114.94,69.78 114.92,69.76 114.92,69.43 114.94,69.41 114.94,66.25 114.47,65.79 113.92,65.79 111,62.87 111,54.99 109.6,53.59 109.35,53.59 106.81,51.05 105.02,51.05 v1(104.33,50.36)
  BOTTOM w0.132: v1(114.94,83.44) 116.2,83.44 117.2,84.43 EXP_P3.13
H_GP6[28]: length 164.7
  TOP w0.132: U42.V6 v1(89.38,63.56) ; v1(5,164.45) P5.24
  L10-SIGNAL w0.089: v1(66.42,70.23) 66.42,68.2 71.37,63.25 82.3,63.25 82.36,63.18 88.99,63.18 v1(89.38,63.56)
  L14-SIGNAL w0.109: v1(66.42,70.23) 59.94,70.23 37.47,92.71 37.47,115.7 36.07,117.09 36.07,117.6 36.7,118.24 36.7,127.76 36.07,128.4 34.04,128.4 33.53,128.91 32.13,128.91 29.97,131.06 26.42,131.06 24.64,132.84 18.16,132.84 14.48,136.53 14.48,147.57 7.49,154.56 4.57,154.56 2.92,156.21 2.92,162.37 v1(5,164.45)
H_GPMC_A0: length 35.7
  TOP w0.132: U42.P6 v1(93.38,63.56)
  L14-SIGNAL w0.109: v1(93.38,63.56) 92.84,64.11 92.84,67.94 92.54,68.24 92.54,87.46 94.25,89.17 94.25,90.53 93.73,91.06 93.73,92.71 94.33,93.32 v1(94.33,95.61)
  BOTTOM w0.132: RU16.11 v1(94.33,95.61)
H_GPMC_A1: length 43.4
  TOP w0.132: U42.J6 v1(97.38,63.56)
  L14-SIGNAL w0.109: v1(97.38,63.56) 96.98,63.97 96.98,67.26 96.99,67.27 96.99,68.99 97.41,69.41 97.41,73.79 98.42,74.8 98.42,87.25 100.33,89.15 100.33,93.98 97.41,96.9 93.73,96.9 93.33,96.51 v1(93.33,95.61)
  BOTTOM w0.132: RU16.13 v1(93.33,95.61)
H_GPMC_A2: length 31.4
  TOP w0.132: U42.R4 v1(91.78,65.16)
  L14-SIGNAL w0.109: v1(91.78,65.16) 92.2,65.59 92.2,67.69 91.4,68.49 91.4,74 91.82,74.42 91.82,86.36 90.81,87.38 90.81,91.8 91.53,92.53 v1(91.93,92.53)
  BOTTOM w0.132: v1(91.93,92.53) 92,92.53 92.33,92.86 RU16.15
H_GPMC_A3: length 34.8
  TOP w0.132: U42.R5 v1(91.78,64.36)
  L14-SIGNAL w0.109: v1(91.06,95.61) 91.06,94.61 92.46,93.22 92.46,92.33 91.94,91.81 91.94,88.78 92.24,88.48 92.24,69.9 92.2,69.86 92.2,68.07 92.46,67.82 92.46,65.04 v1(91.78,64.36)
  BOTTOM w0.132: v1(91.06,95.61) 90.83,95.38 RU16.18
H_GPMC_A4: length 34.9
  TOP w0.132: U42.M6 v1(94.98,63.56)
  L10-SIGNAL w0.089: v1(94.98,63.56) 95.38,63.96 95.38,68.96 95.92,69.5 95.92,81.88 91.05,86.75 91.05,90.61 90.21,91.46 v1(89.41,91.46)
  BOTTOM w0.132: v1(89.41,91.46) 89.03,91.84 89.03,92.86 89.33,93.17 RU16.21
H_GPMC_A5: length 35.9
  TOP w0.132: U42.K4 v1(96.58,65.16)
  L7-SIGNAL w0.089: v1(96.58,65.16) 96.19,64.77 94.05,64.77 93.81,65.01 93.81,66.12 93.81,66.12 93.81,66.59 92.33,68.07 92.33,76.45 87.12,81.66 87.12,90.17 88.14,91.19 v1(88.14,92.33)
  BOTTOM w0.132: RU16.23 88.33,92.52 v1(88.14,92.33)
H_GPMC_A6: length 34.1
  TOP w0.132: U42.P5 v1(93.38,64.36)
  L10-SIGNAL w0.089: v1(93.38,64.36) 93,64.75 93,67.85 93.58,68.43 93.58,75.71 93.09,76.2 93.09,77.22 91.31,78.99 91.31,81.03 89.28,83.06 89.28,87.12 87.25,89.15 87.25,90.17 86.36,91.06 86.36,91.81 86.88,92.33 v1(86.95,92.33)
  BOTTOM w0.132: RU16.25 87.34,92.71 v1(86.95,92.33)
H_GPMC_A7: length 36.5
  TOP w0.132: U42.N6 v1(94.18,63.56)
  L10-SIGNAL w0.089: v1(94.18,63.56) 93.77,63.98 93.12,63.98 92.79,64.31 92.79,68.11 92.46,68.45 92.46,68.99 93.38,69.91 93.38,73.5 92.71,74.17 92.71,76.96 90.42,79.25 89.28,79.25 87.25,81.28 87.25,88.02 85.85,89.41 85.85,89.92 86.05,90.12 v1(86.05,90.17)
  BOTTOM w0.132: v1(86.05,90.17) 86.33,90.45 RU16.27
H_GPMC_A8: length 35
  TOP w0.132: U42.N4 v1(94.18,65.16) ; RU7.2 86.33,92.1 v1(86.87,91.57)
  L10-SIGNAL w0.089: v1(86.87,91.57) 87.5,90.93 90.42,90.93 90.73,90.63 90.73,86.66 94.87,82.52 94.87,68 94.6,67.73 94.6,65.58 v1(94.18,65.16)
H_GPMC_A9: length 36.1
  TOP w0.132: U42.R3 v1(91.78,65.97) ; v1(87.34,96.62) RU7.4
  L14-SIGNAL w0.109: v1(91.78,65.97) 91.78,66.46 90.81,67.44 90.81,69.6 91.04,69.83 91.04,74.15 91.31,74.42 91.31,84.45 88.52,87.25 88.52,90.81 87.63,91.69 87.63,92.71 87.34,93 v1(87.34,96.62)
H_GPMC_A10: length 36.8
  TOP w0.132: U42.J5 v1(97.38,64.36) ; v1(89.42,92.33) 88.83,92.33 88.33,92.82 RU7.6
  L10-SIGNAL w0.089: v1(97.38,64.36) 97,64.75 97,68.42 97.41,68.83 97.41,76.83 96.65,77.6 96.65,83.95 94.49,86.11 94.49,90.68 93.34,91.83 92.17,91.83 92.17,91.82 91.57,91.82 90.93,92.46 90.14,92.46 90,92.33 v1(89.42,92.33)
H_GPMC_A11: length 33
  TOP w0.132: RU7.9 89.83,92.54 v1(90.3,92.08) ; U42.K5 v1(96.58,64.36)
  L10-SIGNAL w0.089: v1(90.3,92.08) 90.81,91.57 90.81,91.24 92.08,89.97 92.08,86.11 96.2,81.98 96.2,64.75 v1(96.58,64.36)
H_GPMC_A12: length 31.9
  TOP w0.132: v1(90.27,90.54) 90.28,90.54 90.28,91.29 90.83,91.85 RU7.11 ; U42.P4 v1(93.38,65.16)
  L10-SIGNAL w0.089: v1(93.38,65.16) 93.77,65.55 93.77,66.13 93.73,66.17 93.73,67.06 94.11,67.44 94.11,69.74 93.82,70.03 93.82,76.1 93.34,76.58 93.34,82.42 89.91,85.86 89.91,90.16 90.27,90.52 v1(90.27,90.54)
H_GPMC_A13: length 23.7
  TOP w0.132: U42.R2 91.78,66.77 91.78,67.7 91.86,67.77 91.86,68.55 91.38,69.02 91.38,72.8 91.4,72.82 91.4,79.33 92.08,80.01 92.08,85.34 91.44,85.98 R172.2 R173.2
H_GPMC_A14: length 24.6
  TOP w0.132: R187.2 R186.2 v1(95.76,83.82) ; U42.R6 v1(91.78,63.56)
  BOTTOM w0.132: v1(91.78,63.56) 92.33,64.11 92.33,68.71 93.6,69.98 93.6,73.41 95.76,75.56 v1(95.76,83.82)
H_GPMC_A15: length 24.6
  TOP w0.132: U42.T2 90.99,66.76 90.99,67.43 90.9,67.52 90.9,68.61 89.41,70.1 89.41,73.13 87.88,74.65 87.88,82.42 89.15,83.69 R180.2 R181.2
H_GPMC_A16: length 23.9
  TOP w0.132: U42.U1 90.58,67.91 89.03,69.47 89.03,72.77 87.5,74.3 87.5,87.5 87.76,87.76 R170.2 R169.2
H_GPMC_A17: length 25.7
  TOP w0.132: R175.2 R174.2 v1(97.66,87.12) ; U42.P3 v1(93.38,65.97)
  L12-SIGNAL w0.089: v1(93.38,65.97) 93.38,67.52 93.34,67.57 93.34,68.37 93.37,68.4 93.37,68.45 94.87,69.95 94.87,84.33 v1(97.66,87.12)
H_GPMC_A18: length 22.7
  TOP w0.132: U42.R1 92.18,67.56 92.46,67.83 92.46,73.91 92.89,74.35 92.89,85.39 93.85,86.36 R184.2 R185.2
H_GPMC_A19: length 79.6
  TOP w0.132: RU5.2 131.42,112.17 130.94,112.65 130.94,113.06 v1(131.42,113.54) ; U42.H6 v1(98.18,63.56)
  L10-SIGNAL w0.089: v1(98.18,63.56) 98.57,63.95 107.13,63.95 108.84,65.66 110.87,65.66 114.22,69.01 117.02,69.01 118.11,70.1 v1(124.97,70.1)
  L14-SIGNAL w0.109: v1(131.42,113.54) 131.02,113.14 131.02,110.96 129.79,109.73 129.79,91.57 130.57,90.79 130.57,88.99 130.05,88.46 130.05,78.36 124.97,73.28 v1(124.97,70.1)
H_GPMC_A20: length 73.9
  TOP w0.132: U42.G6 v1(98.99,63.56) ; RU5.4 132.42,112.61 132.52,112.71 v1(132.52,112.78)
  L7-SIGNAL w0.089: v1(98.99,63.56) 99.36,63.19 102.56,63.19 103,63.63 108.84,63.63 114.6,69.39 114.6,72.57 119.51,77.47 119.51,96.01 122.17,98.68 126.11,98.68 v1(132.08,104.65)
  L14-SIGNAL w0.109: v1(132.08,104.65) 132.08,106.55 132.84,107.31 132.84,110.24 132.52,110.56 v1(132.52,112.78)
H_GPMC_A21: length 71.4
  TOP w0.132: U42.J4 v1(97.38,65.16) ; RU5.6 133.42,109.53 133.86,109.09 133.86,107.19 v1(132.97,106.31)
  L7-SIGNAL w0.089: v1(97.38,65.16) 97.78,64.77 108.23,64.77 112.52,69.07 112.52,71.5 116.71,75.69 116.71,85.22 117.09,85.6 117.09,94.87 122.56,100.33 126.62,100.33 131.95,105.66 132.33,105.66 v1(132.97,106.31)
H_GPMC_A22: length 72.8
  TOP w0.132: v1(134.37,108.71) 134.92,109.27 RU5.9 ; U42.F5 v1(99.79,64.36)
  L12-SIGNAL w0.089: v1(134.37,108.71) 132.72,107.06 124.71,107.06 122.43,104.78 121.67,104.78 120.62,103.73 120.62,102.76 118.24,100.38 118.24,95.5 116.46,93.73 106.68,93.73 105.79,92.84 105.79,90.3 105.03,89.53 105.03,84.58 102.74,82.3 102.74,71.75 101.44,70.45 101.44,69.31 100.17,68.04 100.17,64.75 v1(99.79,64.36)
H_GPMC_A23: length 71.8
  TOP w0.132: RU5.11 135.92,107.49 v1(135.49,107.06) ; U42.G5 v1(98.99,64.36)
  L7-SIGNAL w0.089: v1(135.49,107.06) 133.71,105.28 132.08,105.28 125.86,99.06 121.79,99.06 119.12,96.39 119.12,77.59 113.54,72.01 113.54,69.51 108.02,63.99 99.36,63.99 v1(98.99,64.36)
H_GPMC_A24: length 74.8
  TOP w0.132: RU5.13 136.92,109.09 v1(137.42,108.58) ; U42.J3 v1(97.38,65.97)
  L7-SIGNAL w0.089: v1(137.42,108.58) 136.91,108.08 134.24,108.08 133.35,107.19 132.46,107.19 126.36,101.09 122.56,101.09 115.82,94.36 102.36,94.36 101.6,93.6 101.6,89.66 99.31,87.38 99.31,73.79 98.68,73.15 98.68,69.72 97.79,68.83 97.79,66.37 v1(97.38,65.97)
H_GPMC_A25: length 84
  TOP w0.132: RU5.15 137.92,109.09 v1(138.42,108.58) ; U42.H4 v1(98.18,65.16)
  L10-SIGNAL w0.089: v1(133.6,75.06) 132.59,75.06 129.16,71.63 110.87,71.63 110.49,72.01 100.2,72.01 98.68,70.48 98.68,69.09 97.8,68.21 97.8,65.55 v1(98.18,65.16)
  L14-SIGNAL w0.109: v1(133.6,75.06) 135.89,77.34 137.03,77.34 138.18,78.49 138.18,81.53 139.06,82.42 139.06,84.58 140.21,85.72 140.21,89.15 139.56,89.81 139.56,99.73 139.57,99.75 139.57,105.28 138.43,106.43 138.43,108.17 138.42,108.19 v1(138.42,108.58)
H_GPMC_A26: length 76.5
  TOP w0.132: v1(139.42,109.47) RU5.18 ; U42.H3 v1(98.18,65.97)
  L7-SIGNAL w0.089: v1(139.42,109.47) 139.04,109.86 138.18,109.86 137.92,109.6 137.92,108.2 137.41,107.7 134.37,107.7 133.6,106.93 132.72,106.93 126.49,100.71 122.56,100.71 115.82,93.98 102.62,93.98 101.98,93.34 101.98,89.53 99.82,87.38 99.82,69.72 98.61,68.51 98.61,66.39 v1(98.18,65.97)
H_GPMC_A27: length 85.7
  TOP w0.132: RU5.21 140.92,109.09 v1(141.42,108.58) ; U42.H5 v1(98.18,64.36)
  L10-SIGNAL w0.089: v1(98.18,64.36) 98.57,64.75 98.57,67.97 100.08,69.47 100.08,70.61 101.09,71.63 110.11,71.63 111,70.74 129.29,70.74 v1(133.1,74.55)
  L14-SIGNAL w0.109: v1(141.42,108.58) 141.42,105.48 140.59,104.65 140.59,99.19 141.22,98.55 141.22,85.98 140.08,84.84 140.08,82.8 138.56,81.28 138.56,77.85 137.16,76.45 137.16,75.82 135.51,74.17 133.48,74.17 v1(133.1,74.55)
H_GPMC_AD0: length 31.6
  TOP w0.132: U42.N5 v1(94.18,64.36)
  L14-SIGNAL w0.109: v1(94.18,64.36) 93.79,64.76 93.79,65.8 93.79,66.13 93.79,66.13 93.79,67.44 94.12,67.78 94.12,68.11 93.82,68.41 93.82,73.5 95,74.68 95,87.88 95.76,88.65 v1(95.76,91.95)
  BOTTOM w0.132: v1(95.76,91.95) 95.33,92.37 RU16.9
H_GPMC_AD1: length 28.9
  TOP w0.132: U42.M2 v1(94.98,66.77)
  L14-SIGNAL w0.109: v1(96.83,92.08) 96.83,90.86 96.66,90.69 96.66,89.3 96.27,88.9 96.27,82.04 95.5,81.28 95.5,74.68 94.87,74.04 94.87,69.47 94.59,69.19 94.59,67.16 v1(94.98,66.77)
  BOTTOM w0.132: RU16.6 v1(96.83,92.08)
H_GPMC_AD2: length 31.6
  TOP w0.132: U42.L5 v1(95.78,64.36)
  L14-SIGNAL w0.109: v1(97.66,90.68) 97.27,90.28 97.27,88.88 97.03,88.65 97.03,77.15 97.28,76.9 97.28,74.42 96.24,73.38 96.24,72.81 96.22,72.79 96.22,72.44 96.24,72.43 96.24,70.77 95.76,70.3 95.76,68.83 95.38,68.46 95.38,65 95.38,65 95.38,64.77 v1(95.78,64.36)
  BOTTOM w0.132: RU16.4 97.83,92.12 97.66,91.95 v1(97.66,90.68)
H_GPMC_AD3: length 30.4
  TOP w0.132: U42.M1 v1(94.98,67.57)
  L14-SIGNAL w0.109: v1(94.98,67.57) 94.98,68.7 95.25,68.96 95.25,70.36 96.01,71.12 96.01,72.34 96,72.35 96,72.89 96.01,72.9 96.01,81.03 96.65,81.66 96.65,88.77 96.9,89.03 96.9,90.52 98.08,91.69 v1(99.69,91.69)
  BOTTOM w0.132: v1(99.69,91.69) 99.69,92.13 99.1,92.73 98.92,92.73 98.83,92.81 RU16.2
H_GPMC_AD4: length 80.2
  TOP w0.132: U42.K6 v1(96.58,63.56)
  L10-SIGNAL w0.089: v1(125.6,69.72) 125.33,69.45 118.47,69.45 117.73,68.71 114.3,68.71 111,65.41 108.97,65.41 106.68,63.12 102.38,63.12 102.35,63.15 98.02,63.15 97.99,63.12 97.03,63.12 v1(96.58,63.56)
  L14-SIGNAL w0.109: v1(125.6,69.72) 125.6,73.28 130.43,78.11 130.43,88.14 130.94,88.65 130.94,90.93 130.18,91.69 130.18,109.73 131.42,110.97 v1(131.42,112.78)
  BOTTOM w0.132: v1(131.42,112.78) RU13.27
H_GPMC_AD5: length 74.7
  TOP w0.132: U42.L4 v1(95.78,65.16)
  L7-SIGNAL w0.089: v1(132.42,109.47) 132.05,109.1 125.36,109.1 118.36,102.1 118.36,99.05 116.46,97.16 102.49,97.16 100.46,95.12 100.46,90.17 98.55,88.27 97.66,88.27 97.28,87.88 97.28,71.75 95.38,69.85 95.38,65.57 v1(95.78,65.16)
  BOTTOM w0.132: RU13.25 v1(132.42,109.47)
H_GPMC_AD6: length 72
  TOP w0.132: U42.L3 v1(95.78,65.97)
  L7-SIGNAL w0.089: v1(133.42,108.71) 132.66,107.95 132.21,107.95 131.44,107.19 130.56,107.19 125.09,101.73 122.43,101.73 115.8,95.1 101.7,95.1 100.89,94.28 100.89,90.09 98.3,87.51 98.3,75.19 97.54,74.42 97.54,72.82 97.5,72.79 97.5,72.45 97.54,72.42 97.54,71.63 96.21,70.3 96.21,67.41 96.27,67.35 96.27,67.06 96.16,66.95 96.16,66.34 v1(95.78,65.97)
  BOTTOM w0.132: v1(133.42,108.71) RU13.23
H_GPMC_AD7: length 77.6
  TOP w0.132: U42.L2 v1(95.78,66.77)
  L12-SIGNAL w0.089: v1(134.42,112.75) 133.12,114.05 126.49,114.05 125.73,113.28 122.43,113.28 118.87,109.73 118.87,106.93 117.09,105.16 117.09,103.25 113.92,100.08 113.92,98.42 113.28,97.79 104.72,97.79 102.59,95.66 102.59,94.72 100.58,92.71 100.58,84.84 98.68,82.93 98.68,72.14 97.28,70.74 97.28,69.6 96.17,68.49 96.17,67.15 v1(95.78,66.77)
  BOTTOM w0.132: RU13.21 v1(134.42,112.75)
H_GPMC_AD8: length 80.3
  TOP w0.132: U42.L1 v1(95.78,67.57)
  L12-SIGNAL w0.089: v1(135.92,112.65) 133.25,115.32 124.84,115.32 124.46,114.94 123.66,114.94 118.49,109.77 118.49,107.19 116.59,105.28 115.32,105.28 114.56,104.53 114.56,103.09 114.55,103.08 114.55,102.11 112.9,100.46 112.9,98.42 112.65,98.17 104.65,98.17 102.74,96.27 102.07,96.27 101.6,95.8 101.6,94.23 100.2,92.84 100.2,84.96 98.33,83.09 98.33,72.14 97.08,70.89 97.08,69.77 95.78,68.48 v1(95.78,67.57)
  BOTTOM w0.132: v1(135.92,112.65) RU13.18
H_GPMC_AD9: length 78.7
  TOP w0.132: U42.K1 v1(96.58,67.57)
  L12-SIGNAL w0.089: v1(137.42,112.75) 136.81,112.14 121.75,112.14 119.77,110.16 119.77,107.2 117.47,104.9 117.47,103.25 115.06,100.84 115.06,98.08 114.39,97.41 104.77,97.41 103.38,96.01 103.38,94.87 100.97,92.46 100.97,84.71 99.06,82.8 99.06,73.41 98.9,73.25 98.9,71.85 97.5,70.45 97.5,69.31 96.58,68.39 v1(96.58,67.57)
  BOTTOM w0.132: RU13.15 v1(137.42,112.75)
H_GPMC_AD10: length 77.4
  TOP w0.132: U42.J1 v1(97.38,67.57)
  L12-SIGNAL w0.089: v1(97.38,67.57) 97.38,68.3 98.68,69.6 98.68,70.74 99.93,71.99 99.93,82.66 101.73,84.45 101.73,92.2 104.65,95.12 106.31,95.12 106.32,95.12 106.64,95.12 106.65,95.12 115.44,95.12 116.2,95.89 116.2,101.22 118.24,103.25 118.24,104.14 122.17,108.08 122.56,108.08 124.83,110.36 125.11,110.36 125.37,110.62 128.91,110.62 129.41,111.12 136.79,111.12 v1(138.42,112.75)
  BOTTOM w0.132: RU13.13 v1(138.42,112.75)
H_GPMC_AD11: length 79.1
  TOP w0.132: U42.J2 v1(97.38,66.77)
  L12-SIGNAL w0.089: v1(97.38,66.77) 97.79,67.17 97.79,68.33 98.9,69.44 98.9,70.58 100.2,71.88 100.2,82.42 102.11,84.33 102.11,92.08 104.9,94.87 115.57,94.87 116.59,95.89 116.59,101.22 117.98,102.62 118.74,102.62 119.51,103.38 119.51,104.65 124.97,110.11 125.35,110.11 125.6,110.36 129.16,110.36 129.54,110.74 137.41,110.74 v1(139.42,112.75)
  BOTTOM w0.132: RU13.11 v1(139.42,112.75)
H_GPMC_AD12: length 78.4
  TOP w0.132: U42.H1 v1(98.18,67.57)
  L12-SIGNAL w0.089: v1(140.42,112.75) 138.16,110.49 129.79,110.49 129.16,109.86 125.09,109.86 119.76,104.52 119.76,103.12 117.47,100.84 117.47,96.27 115.82,94.61 105.12,94.61 102.49,91.99 102.49,84.2 101.12,82.84 101.12,72.29 99.82,70.99 99.82,69.6 98.18,67.96 v1(98.18,67.57)
  BOTTOM w0.132: RU13.9 v1(140.42,112.75)
H_GPMC_AD13: length 84.2
  TOP w0.132: U42.K2 v1(96.58,66.77)
  L12-SIGNAL w0.089: v1(96.58,66.77) 96.97,67.15 96.97,68.4 98.42,69.85 98.42,70.87 99.73,72.17 99.73,73.5 99.57,73.66 99.57,82.8 101.35,84.58 101.35,92.29 104.37,95.31 104.37,95.6 105.79,97.03 114.55,97.03 115.86,98.34 115.86,101.26 117.86,103.25 117.86,104.52 120.65,107.31 120.65,109.85 122.56,111.76 137.03,111.76 137.92,112.65 137.92,113.03 138.18,113.28 141.1,113.28 v1(141.48,113.67)
  BOTTOM w0.132: RU13.6 141.92,113.23 v1(141.48,113.67)
H_GPMC_AD14: length 82.6
  TOP w0.132: U42.H2 v1(98.18,66.77)
  L12-SIGNAL w0.089: v1(142.43,113.6) 141.99,113.16 141.99,112.52 139.57,110.11 129.92,110.11 129.29,109.47 125.22,109.47 120.02,104.27 120.02,103 117.73,100.71 117.73,96.01 116.08,94.36 105.41,94.36 103.51,92.46 103.51,91.7 102.87,91.06 102.87,84.07 101.44,82.65 101.44,71.72 100.2,70.49 100.2,69.47 98.57,67.84 98.57,67.15 v1(98.18,66.77)
  BOTTOM w0.132: RU13.4 142.92,113.12 v1(142.43,113.6)
H_GPMC_AD15: length 84.2
  TOP w0.132: U42.K3 v1(96.58,65.96)
  L7-SIGNAL w0.089: v1(96.58,65.96) 96.96,66.34 96.96,69.65 97.5,70.2 97.5,70.45 98.35,71.3 98.35,73.33 98.68,73.66 98.68,87.25 101.22,89.79 101.22,93.85 102.11,94.74 115.82,94.74 122.43,101.35 126.11,101.35 132.33,107.57 133.1,107.57 133.86,108.33 133.86,109.73 134.37,110.24 143.64,110.24 143.92,109.96 v1(143.92,108.84)
  BOTTOM w0.132: RU13.2 v1(143.92,108.84)
H_GPMC_ADVN_ALE: length 94.3
  TOP w0.132: U12.17 121.07,141.26 120.52,140.72 v1(120.02,140.72) ; U42.N1 93.78,67.56 93.73,67.62 v1(93.73,67.94)
  L3-SIGNAL w0.109: v1(120.02,140.72) 117.86,140.72 117.47,140.34 115.95,140.34 113.28,137.67 v1(112.65,137.67)
  L12-SIGNAL w0.089: v1(93.73,67.94) 93.73,68.33 95.09,69.7 95.09,74.26 95.38,74.55 95.38,82.68 98.17,85.47 98.17,87.25 97.79,87.63 97.28,87.63 95.51,89.4 95.51,90.29 94.74,91.06 94.74,92.58 92.46,94.87 92.46,100.2 94.36,102.11 94.36,102.87 96.01,104.52 96.01,105.41 99.57,108.97 99.57,109.6 102.62,112.65 102.62,118.91 111.38,127.67 111.38,132.08 112.65,133.35 v1(112.65,137.67)
H_GPMC_BEN0: length 96.8
  TOP w0.132: v1(119.51,141.35) 119.92,141.35 120.05,141.22 120.52,141.22 121.06,141.76 U12.16 ; U42.N3 v1(94.18,65.96)
  L3-SIGNAL w0.109: v1(119.51,141.35) 117.86,141.35 117.22,140.72 115.57,140.72 v1(113.16,138.3)
  L12-SIGNAL w0.089: v1(113.16,138.3) 113.16,133.35 111.76,131.95 111.76,127.51 103.71,119.46 103.71,113.31 100.37,109.97 100.37,109.26 97.03,105.92 97.03,104.27 92.84,100.08 92.84,95.42 96.15,92.11 96.15,90.68 95.88,90.42 95.88,89.54 97.41,88.01 97.92,88.01 98.42,87.5 98.42,85.22 96.01,82.8 96.01,71.25 95.38,70.61 95.38,69.6 94.11,68.33 94.11,67.78 93.73,67.4 93.73,66.42 v1(94.18,65.96)
H_GPMC_CS0: length 125.9
  TOP w0.132: v1(91.38,67.82) U42.T1 ; RU3.2 v1(115.19,147.7)
  L10-SIGNAL w0.089: v1(115.19,147.7) 118.49,147.7 120.46,149.67 143.68,149.67 143.76,149.59 144.12,149.59 v1(144.4,149.86)
  L12-SIGNAL w0.089: v1(91.38,67.82) 91.38,83.62 91.05,83.95 91.05,90.47 91.73,91.14 91.73,91.53 91.38,91.88 91.38,93.16 92.08,93.85 92.08,100.33 93.98,102.23 93.98,103 95.63,104.65 95.63,107.19 98.93,110.49 99.95,110.49 102.29,112.83 102.29,119 111,127.71 111,144.15 114.55,147.7 v1(115.19,147.7)
  BOTTOM w0.132: RU12.2 v1(144.4,149.86)
H_GPMC_CS1: length 82.7
  TOP w0.132: RU5.23 141.92,109.03 v1(142.37,108.58) ; U42.G4 v1(98.99,65.16)
  L12-SIGNAL w0.089: v1(98.99,65.16) 99.37,65.55 99.37,67.88 101.14,69.65 101.14,70.79 102.27,71.91 102.27,82.45 104.65,84.84 104.65,85.33 104.52,85.46 104.14,85.46 104.01,85.59 104.01,85.78 104.14,85.91 104.52,85.91 104.65,86.04 104.65,92.84 105.92,94.11 116.33,94.11 117.98,95.76 117.98,100.58 120.27,102.87 120.27,104.14 125.22,109.09 132.58,109.09 132.71,109.22 136.52,109.22 136.66,109.09 141.58,109.09 141.58,109.09 141.86,109.09 v1(142.37,108.58)
H_GPMC_CS2: length 23.2
  TOP w0.132: R171.2 93.34,84.96 93.34,73.91 93.67,73.59 93.67,68.52 93.31,68.16 93.31,67.6 93.39,67.52 93.39,66.77 U42.P2
H_GPMC_CS3: length 31.7
  TOP w0.132: U42.P1 v1(92.98,68.56) ; RU7.27 98.83,92.75 98.84,92.74 v1(98.84,92.33)
  L14-SIGNAL w0.109: v1(98.84,92.33) 98.46,92.71 95.63,92.71 94.74,91.82 94.74,90.17 94.61,90.04 94.61,88.52 93.47,87.38 93.47,69.47 92.98,68.98 v1(92.98,68.56)
H_GPMC_OEN_REN: length 131.3
  TOP w0.132: U42.M5 v1(94.98,64.36) ; v1(144.53,148.26) 144.83,147.96 R42.1 ; v1(120.14,146.56) 120.4,146.56 121.19,145.76 U12.8
  L10-SIGNAL w0.089: v1(120.14,146.56) 120.9,147.32 123.95,147.32 124.46,147.83 124.97,147.83 125.35,148.21 139.7,148.21 140.08,147.83 144.15,147.83 144.53,148.21 v1(144.53,148.26)
  L12-SIGNAL w0.089: v1(94.98,64.36) 94.57,64.78 94.57,66.63 94.6,66.66 94.6,68.05 95.89,69.34 95.89,70.48 97.19,71.79 97.19,76.8 97.03,76.96 97.03,82.8 99.19,84.96 99.19,87.76 97.22,89.72 97.22,92.9 95,95.12 95,96.27 93.64,97.62 93.64,100.12 97.79,104.27 97.79,104.65 104.39,111.25 104.39,119.13 112.52,127.25 112.52,131.7 114.94,134.11 114.94,143.13 118.36,146.56 v1(120.14,146.56)
  BOTTOM w0.132: U104.34 144.03,147.76 v1(144.53,148.26)
H_GPMC_WAIT0: length 101.4
  TOP w0.132: 119.38,150.75 119,150.75 118.84,150.58 R188.2 v1(118.49,151.26) ; U42.N2 v1(94.18,66.77)
  L12-SIGNAL w0.089: v1(118.49,151.26) 118.49,150.37 116.84,148.72 116.84,147.45 114.55,145.16 114.55,134.24 112.11,131.8 112.11,127.35 104.01,119.25 104.01,112.9 101.47,110.36 101.47,109.69 97.41,105.62 97.41,104.27 93.22,100.08 93.22,97.54 93.92,96.83 93.92,95.31 96.35,92.88 96.35,90.72 96.9,90.17 96.9,89.54 98.81,87.63 98.81,85.09 96.65,82.93 96.65,77.09 96.36,76.8 96.36,72.92 96.23,72.79 96.23,71.18 95.63,70.58 95.63,69.47 94.36,68.2 94.36,67.49 94.18,67.31 v1(94.18,66.77)
H_GPMC_WEN: length 103.2
  TOP w0.132: v1(118.87,142.62) 118.87,140.84 119.51,140.21 120.52,140.21 121.08,140.76 U12.18 ; U42.M3 v1(94.98,65.97)
  L12-SIGNAL w0.089: v1(94.98,65.97) 95.38,66.36 95.38,68.45 96.23,69.31 96.23,70.45 97.39,71.61 97.39,82.66 99.57,84.84 99.57,88.26 98.42,89.41 98.42,90.04 98.76,90.38 98.76,91.1 97.92,91.95 97.92,92.96 95.38,95.5 95.38,96.65 93.95,98.08 93.95,99.88 98.3,104.23 98.3,104.65 104.78,111.12 104.78,116.08 106.43,117.73 106.43,120.65 112.9,127.13 112.9,131.57 115.32,133.99 115.32,140.97 116.97,142.62 v1(118.87,142.62)
  BOTTOM w0.132: U104.13 120.03,142.76 119.89,142.62 v1(118.87,142.62) R371.1
H_HDMI_CLKX: length 90.7
  TOP w0.099: U42.AG14 82.18,56.37 81.79,56.37 81.77,56.34 62.52,56.34 24.13,94.74 24.13,103.15 21.08,106.2 FL3.4
H_HDMI_CLKY: length 90.8
  TOP w0.099: FL3.1 17.6,105.64 17.79,105.82 18.02,105.82 18.13,105.93 18.4,105.93 18.5,105.83 18.5,105.62 18.6,105.52 18.74,105.52 18.83,105.62 18.83,105.83 18.93,105.93 20.97,105.93 23.86,103.04 23.86,94.63 62.41,56.08 81.66,56.08 U42.AH15
H_HDMI_DX0: length 87.8
  TOP w0.099: FL4.4 19.65,103.14 21.68,103.14 22.86,101.95 22.86,93.49 60.82,55.54 82.16,55.54 U42.AG15
H_HDMI_DX1: length 87.8
  TOP w0.099: FL5.4 21.33,99.09 21.67,98.75 21.67,92.4 25.67,88.4 25.67,84.7 33.9,76.47 37.6,76.47 59.75,54.31 80.31,54.31 80.78,53.84 81.52,53.84 81.66,53.98 82.19,53.98 U42.AG17
H_HDMI_DX2: length 89.2
  TOP w0.099: U42.AG18 82.16,53.14 79.83,53.14 79.49,53.48 58.78,53.48 37.32,74.94 29.83,74.94 23.5,81.28 23.5,88.44 20.24,91.69 20.24,95.17 19.38,96.04 FL6.4
H_HDMI_DY0: length 87.8
  TOP w0.099: U42.AH16 81.67,55.27 60.7,55.27 22.59,93.38 22.59,101.84 21.56,102.87 20.95,102.87 20.85,102.77 20.85,102.56 20.75,102.46 20.61,102.46 20.51,102.56 20.51,102.77 20.42,102.87 20.15,102.87 20.06,102.78 19.82,102.78 19.63,102.59 FL4.1
H_HDMI_DY1: length 87.8
  TOP w0.099: U42.AH18 81.77,53.57 80.67,53.57 80.2,54.05 59.64,54.05 37.49,76.2 33.79,76.2 25.4,84.59 25.4,88.29 21.4,92.29 21.4,98.64 21.22,98.82 21,98.82 20.9,98.72 20.9,98.47 20.8,98.37 20.61,98.37 20.51,98.47 20.51,98.72 20.41,98.82 20.15,98.82 20.05,98.72 19.83,98.72 19.63,98.53 FL5.1
H_HDMI_DY2: length 89.2
  TOP w0.099: U42.AH19 81.67,52.87 79.72,52.87 79.37,53.21 58.67,53.21 37.21,74.68 29.72,74.68 23.23,81.17 23.23,88.33 19.98,91.58 19.98,95.06 19.28,95.76 18.92,95.76 18.82,95.66 18.82,95.45 18.72,95.35 18.58,95.35 18.48,95.45 18.48,95.66 18.38,95.76 18.12,95.76 18.02,95.66 17.79,95.66 17.6,95.48 FL6.1
H_I2C1_SCL: length 485.7
  TOP w0.132: U53.1 v1(111.35,41.58) ; U38.35 159.55,67.73 159.42,67.6 159.42,67.34 158.74,66.67 v1(158.74,65.56) ; U21.22 v1(205.36,80.25) ; U42.C19 v1(102.18,52.36) ; U55.6 16.9,34.8 v1(16.38,34.29) ; U50.1 v1(170.31,46.06) ; U40.5 134.67,59.82 134.66,59.82 v1(134.25,59.82) ; v1(204.98,68.69) 204.97,68.7 U30.22 ; v1(10.79,168.45) P5.33
  L7-SIGNAL w0.089: v1(71.75,130.05) 76.2,125.6 76.2,117.73 76.71,117.22 76.71,116.71 76.18,116.18 v1(76.18,108.03) 76.44,107.77 76.44,107.53 80.7,103.28 80.7,95.56 76.38,91.24 76.38,89.59 74.55,87.76 74.55,65.02 80.14,59.44 80.14,56.13 81.92,54.36 92.2,54.36 92.96,53.59 93.2,53.59 93.22,53.57 93.54,53.57 93.57,53.59 93.85,53.59 94.23,53.21 94.23,53.09 94.55,52.77 99.15,52.77 99.16,52.79 101.76,52.79 v1(102.18,52.36) 102.56,52.74 105.63,52.74 105.79,52.58 109.86,52.58 110.49,53.21 118.75,53.21 119.25,53.72 119.38,53.72 119.38,53.72 125.22,53.72 125.48,53.98 127.25,53.98 133.1,59.82 v1(134.25,59.82)
  L10-SIGNAL w0.089: v1(204.98,68.69) 205.47,68.69 206.5,69.72 206.5,79.11 v1(205.36,80.25) ; v1(28.83,49.76) 29.49,50.42 33.53,50.42 33.91,50.04 45.09,50.04 46.81,51.76 71.44,51.76 72.14,52.45 78.87,52.45 79.34,51.97 101.8,51.97 v1(102.18,52.36) 102.58,51.97 102.58,51.4 102.8,51.17 103.95,51.17 104.21,51.44 107.19,51.44 108.05,50.58 110.2,50.58 110.87,49.91 110.87,42.06 v1(111.35,41.58) ; v1(185.68,67.69) 185.17,67.18 185.17,53.21 184.02,52.07 183.26,52.07 181.23,50.04 174.29,50.04 v1(170.31,46.06) ; v1(16.38,34.29) 17.02,34.92 26.16,34.92 26.54,35.31 v1(28.83,35.31)
  L14-SIGNAL w0.109: v1(134.25,59.82) 135.13,59.82 140.84,65.53 146.43,65.53 146.85,65.11 152.23,65.11 153.03,65.91 158.39,65.91 v1(158.74,65.56) 160.11,66.93 168.28,66.93 168.78,66.42 174.24,66.42 174.96,67.14 180.25,67.14 180.59,66.8 182.25,66.8 183.13,67.69 v1(185.68,67.69) 187.08,69.09 200.53,69.09 201.08,68.54 203.41,68.54 203.56,68.69 v1(204.98,68.69) ; v1(10.79,168.45) 15.95,168.45 18.67,165.74 18.67,162.69 24.77,156.59 32.89,156.59 41.27,148.21 41.27,143.76 42.54,142.49 50.67,142.49 60.07,133.1 60.32,133.1 61.72,131.7 64.52,131.7 65.02,131.19 67.82,131.19 68.96,130.05 v1(71.75,130.05) ; v1(28.83,49.76) v1(28.83,35.31)
  BOTTOM w0.132: U110.22 71.51,130.29 v1(71.75,130.05) ; v1(111.35,41.58) 111.66,41.27 R618.2 ; EXP_P2.30 v1(76.18,108.03) ; U139.6 v1(28.83,49.76)
H_I2C1_SDA: length 485.1
  TOP w0.132: U30.23 v1(205.49,69.35) ; v1(16.51,36.7) 16.4,36.59 U55.5 ; U50.2 170.53,45.56 v1(170.31,45.34) ; U38.36 159.88,67.23 159.38,66.73 v1(159.38,65.41) ; v1(11.43,168.95) P5.35 ; U53.6 111.18,39.95 111.19,39.94 v1(111.76,39.94) ; U42.C20 v1(102.19,51.56) ; U21.23 v1(204.72,80.9) ; U40.6 v1(134.89,59.32)
  L7-SIGNAL w0.089: v1(71.75,130.79) 71.37,130.41 71.37,129.67 75.82,125.22 75.82,117.33 75.38,116.9 v1(75.38,107.52) 75.38,107.12 78.49,104.01 78.49,102.36 79.76,101.09 79.76,96.77 75.44,92.46 75.44,89.28 74.17,88.01 74.17,64.64 78.49,60.33 78.49,56.39 81.28,53.59 82.82,53.59 82.83,53.59 83.61,53.59 83.62,53.57 86.32,53.57 86.34,53.59 86.8,53.59 86.82,53.57 87.14,53.57 87.16,53.59 88.4,53.59 88.42,53.57 88.74,53.57 88.76,53.59 90.42,53.59 91.19,52.83 91.56,52.83 91.62,52.77 91.94,52.77 92,52.83 92.2,52.83 93.05,51.99 93.21,51.99 93.22,51.97 95.95,51.97 95.96,51.99 96.98,51.99 97.04,51.94 98.01,51.94 98.02,51.95 99.15,51.95 99.16,51.94 101.81,51.94 v1(102.19,51.56) 102.57,51.18 107.7,51.18 107.95,51.44 118.75,51.44 120.65,53.34 122.05,53.34 122.3,53.09 127,53.09 133.24,59.32 v1(134.89,59.32)
  L10-SIGNAL w0.089: v1(16.51,36.7) 16.89,37.08 22.61,37.08 23.24,36.45 v1(29.34,36.45) ; v1(170.31,45.34) 174.62,49.66 181.36,49.66 183.39,51.69 184.15,51.69 185.67,53.21 185.67,66.67 v1(186.18,67.18) ; v1(204.72,80.9) 204.72,80.34 206.12,78.94 206.12,73.53 205.49,72.9 v1(205.49,69.35) ; v1(30.1,49.76) 30.49,49.76 30.59,49.66 45.97,49.66 46.74,50.42 54.48,50.42 55.12,51.05 66.29,51.05 66.8,50.55 75.06,50.55 75.56,51.05 82.3,51.05 82.39,51.15 101.57,51.15 101.98,51.56 102.18,51.56 v1(102.19,51.56) 102.19,51.31 102.57,50.93 103.99,50.93 104.11,51.05 107.06,51.05 107.82,50.29 108.64,50.29 109.24,49.69 109.57,49.69 109.97,49.29 109.97,45.1 110.49,44.58 110.49,41.21 v1(111.76,39.94)
  L14-SIGNAL w0.109: v1(11.43,168.95) 11.83,168.95 11.87,168.91 16.26,168.91 19.18,165.99 19.18,162.69 24.77,157.1 33.02,157.1 42.04,148.08 42.04,144.65 43.69,143 50.93,143 60.33,133.6 63.88,133.6 65.97,131.51 68.13,131.51 68.85,130.79 v1(71.75,130.79) ; v1(30.1,49.76) 29.34,49 v1(29.34,36.45) ; v1(205.49,69.35) 205.49,68.45 205.25,68.22 200.93,68.22 200.53,67.82 186.82,67.82 v1(186.18,67.18) 183.13,67.18 182.37,66.42 180.34,66.42 179.96,66.8 178.05,66.8 177.29,66.04 168.59,66.04 168.09,66.55 160.53,66.55 v1(159.38,65.41) 158.99,65.01 153.08,65.01 152.89,64.81 146.52,64.81 146.05,65.28 141.24,65.28 135.28,59.32 v1(134.89,59.32)
  BOTTOM w0.132: EXP_P2.28 v1(75.38,107.52) ; U139.5 v1(30.1,49.76) ; v1(111.76,39.94) 111.95,40.13 R626.2 ; v1(71.75,130.79) 71.61,130.94 U110.23
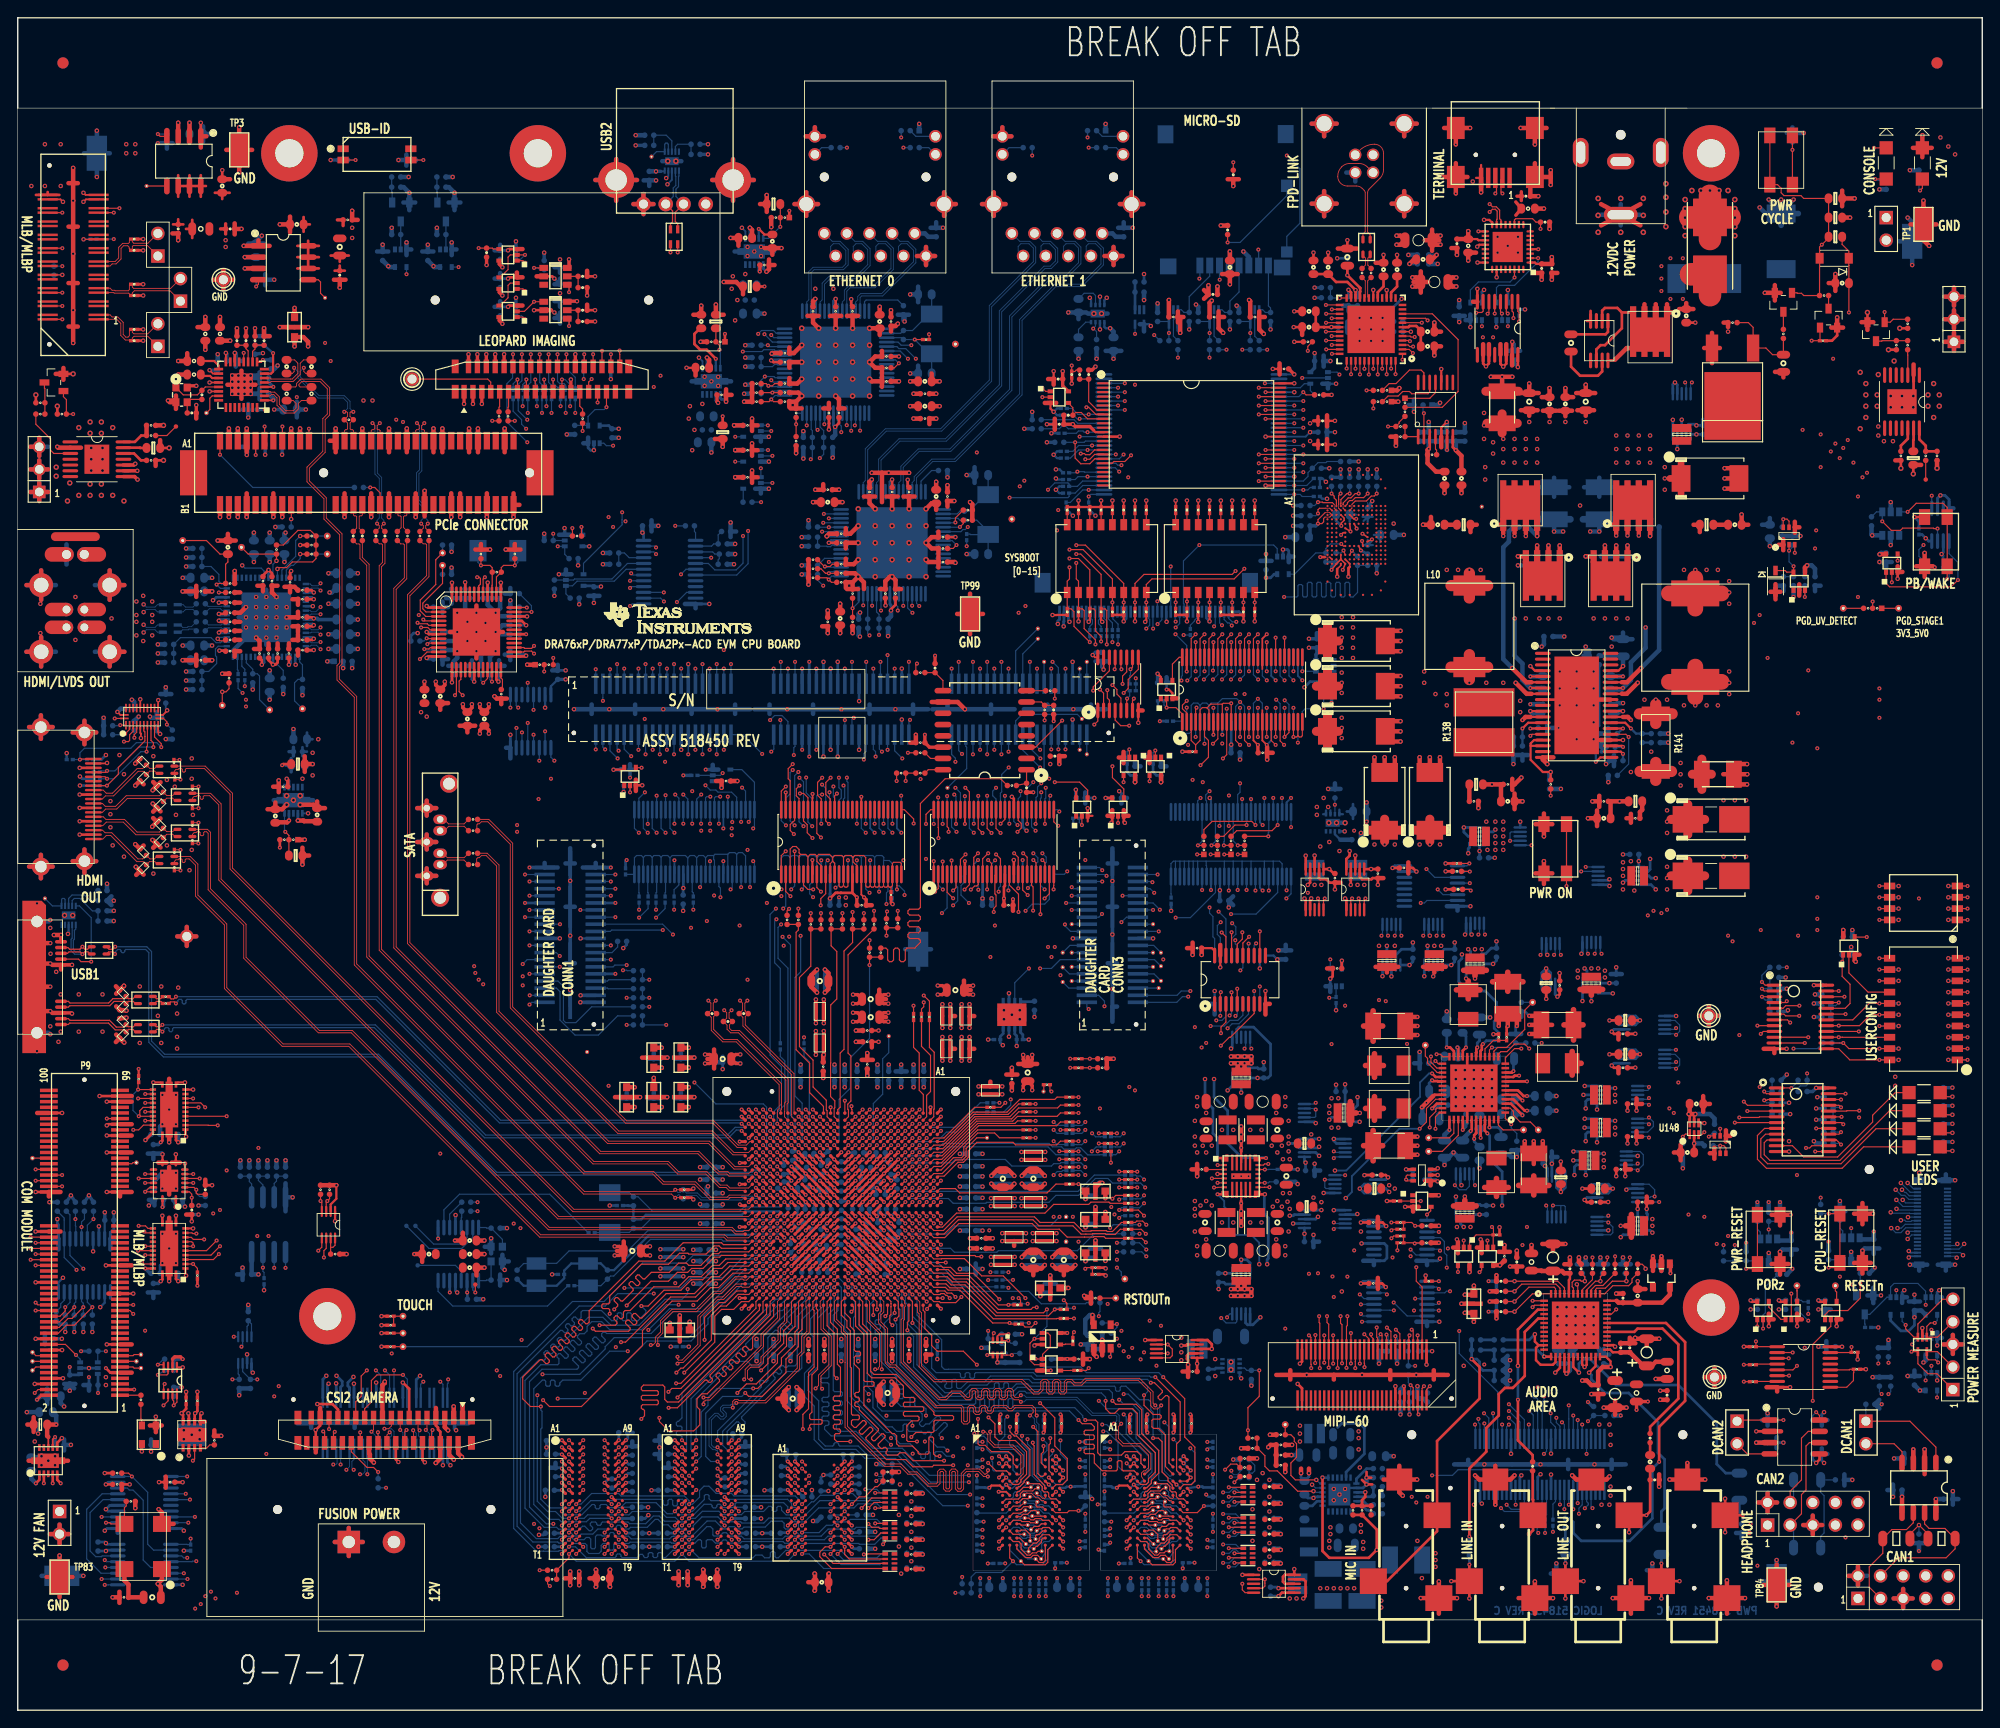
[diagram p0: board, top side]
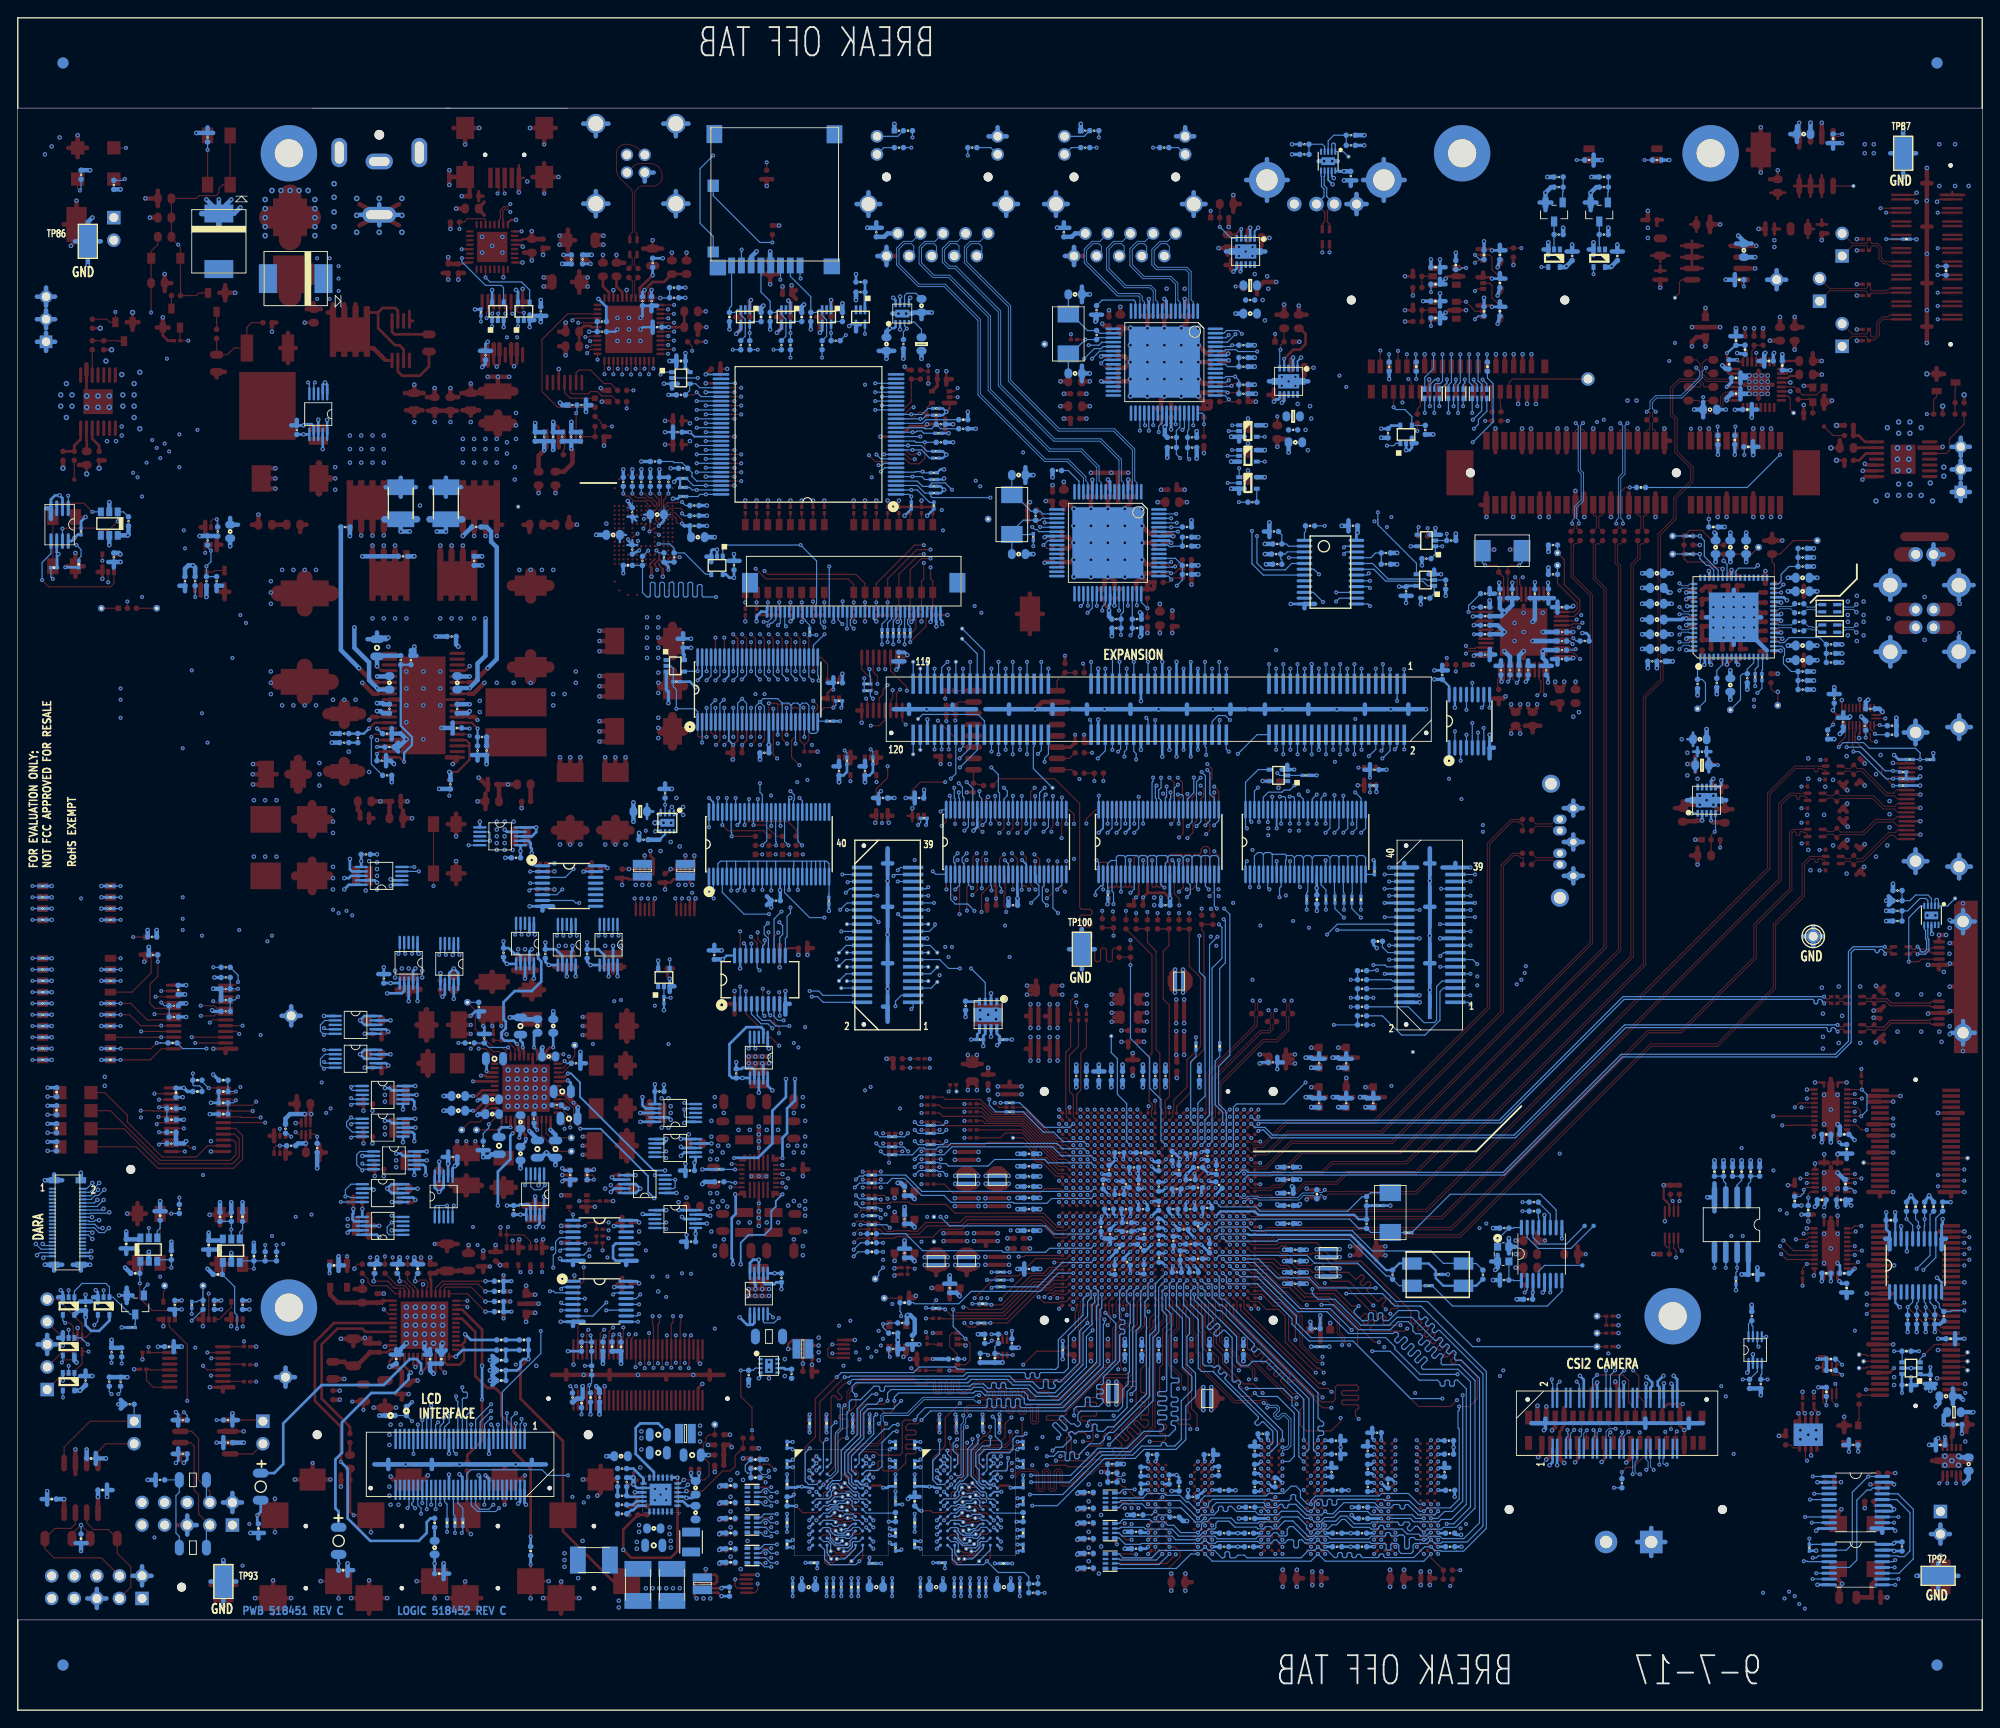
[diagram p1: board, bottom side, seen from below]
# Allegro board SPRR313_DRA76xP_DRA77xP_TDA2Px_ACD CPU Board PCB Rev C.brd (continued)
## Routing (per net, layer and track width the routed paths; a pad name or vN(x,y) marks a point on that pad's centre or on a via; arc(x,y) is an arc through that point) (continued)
H_I2C2_SCL: length 89.4
  TOP w0.132: U42.F15 v1(99.79,55.56)
  L7-SIGNAL w0.089: v1(99.79,55.56) 100.61,56.39 105.38,56.39 105.51,56.52 105.51,56.53 105.75,56.78 108.63,56.78 108.64,56.76 108.72,56.76 109.18,56.31 109.23,56.31 109.24,56.29 109.58,56.29 109.59,56.31 110.28,56.31 111.12,57.15 115.82,57.15 116.59,57.91 119.86,57.91 119.87,57.92 120.21,57.92 120.22,57.91 120.52,57.91 121.41,58.8 122.05,58.8 123.44,60.2 123.82,60.2 123.85,60.22 123.98,60.22 124.2,60.44 124.2,61.08 126.75,63.63 126.75,70.61 135,78.87 143.26,78.87 144.91,80.52 144.91,86.61 148.21,89.92 160.13,89.92 v1(163.25,93.04)
  BOTTOM w0.132: v1(163.25,93.04) RU19.4
H_I2C2_SDA: length 100.2
  TOP w0.132: U42.C24 v1(102.19,48.36)
  L10-SIGNAL w0.089: v1(149.48,48.77) 149.48,51.56 151.51,53.59 151.51,56.9 152.62,58.01 152.62,87.6 155.83,90.81 v1(157.73,90.81)
  L14-SIGNAL w0.109: v1(149.48,48.77) 149.1,48.39 126.24,48.39 125.59,47.74 123.33,47.74 122.82,48.25 121.63,48.25 120.99,48.9 117.6,48.9 116.71,48.01 110.62,48.01 110.49,47.88 108.33,47.88 107.85,48.36 v1(102.19,48.36)
  BOTTOM w0.132: v1(157.73,90.81) 158.14,90.81 158.42,91.08 RU19.7
H_I2C3_SCL_DCAN2_MCAN_RX: length 62.4
  TOP w0.132: U42.F17 v1(99.79,53.96)
  L14-SIGNAL w0.109: v1(117.12,55.5) 117.54,55.08 123.11,55.08 124.08,54.1 131.32,54.1 131.57,54.36 133.99,54.36 134.83,53.51 141.69,53.51 142.11,53.09 143.64,53.09 144.53,52.2 150.62,52.2 150.88,51.94 153.67,51.94 153.92,52.2 156.21,52.2 v1(156.59,51.82)
  BOTTOM w0.132: v1(99.79,53.96) 100.18,53.56 104.39,53.56 105.31,54.48 116.1,54.48 v1(117.12,55.5) ; v1(156.59,51.82) 157.2,51.21 RU22.7
H_I2C3_SDA_DCAN2_MCAN_TX: length 68.2
  TOP w0.132: U42.E21 v1(100.59,50.76)
  L14-SIGNAL w0.109: v1(100.59,50.76) 100.98,50.36 102.94,50.36 103.38,50.8 105.54,50.8 105.82,50.52 109.23,50.52 109.24,50.52 112.25,50.52 112.26,50.52 117.12,50.52 118.11,49.53 119,49.53 119.57,50.1 120.22,50.1 120.24,50.12 122.6,50.12 123.44,49.28 134.49,49.28 134.87,49.66 136.27,49.66 136.91,49.02 144.4,49.02 144.92,49.55 147.81,49.55 148.08,49.28 157.61,49.28 158.12,49.78 v1(160.66,49.78)
  BOTTOM w0.132: RU22.4 159.95,53.16 160.38,52.72 160.38,51.45 160.66,51.18 v1(160.66,49.78)
H_I2C5_SCL: length 26.4
  TOP w0.132: U42.F11 v1(99.79,59.56) ; R230.1 v1(118.32,72.26)
  L7-SIGNAL w0.089: v1(99.79,59.56) 100.16,59.94 103.25,59.94 105.16,61.85 108.84,61.85 113.67,66.67 115.19,66.67 117.09,68.58 117.09,71.04 v1(118.32,72.26)
H_I2C5_SDA: length 26.5
  TOP w0.132: U42.F10 v1(99.79,60.36) ; R226.1 v1(118.32,73.28)
  L7-SIGNAL w0.089: v1(118.32,73.28) 116.71,71.67 116.71,69.22 115.19,67.69 113.79,67.69 109.09,62.99 108.64,62.99 108.63,63 104.65,63 102.4,60.74 100.16,60.74 v1(99.79,60.36)
H_LCD_B0: length 84.2
  L10-SIGNAL w0.089: v1(120.02,61.09) 121.16,61.09 123.06,59.18 123.66,59.18 123.66,59.19 124.2,59.19 124.59,58.8 124.59,49.4 125.09,48.9 125.09,44.07 125.29,43.88 v1(125.29,40.75)
  L14-SIGNAL w0.109: v1(176.38,28.83) 175.23,29.97 158.75,29.97 157.61,28.83 155.83,28.83 152.4,32.26 148.46,32.26 147.32,33.4 137.54,33.4 132.59,38.35 131.06,38.35 129.79,39.62 129.23,39.62 128.11,40.75 v1(125.29,40.75)
  BOTTOM w0.132: J19.51 v1(176.38,28.83) ; v1(120.02,61.09) 119.52,61.58 119.09,61.58 119.07,61.59 R567.1
H_LCD_B1: length 80.1
  TOP w0.132: R198.1 v1(119.23,60.2)
  L10-SIGNAL w0.089: v1(119.23,60.2) 119.66,59.77 119.66,58.07 119.51,57.91 119.51,56.9 119.66,56.74 119.66,55.27 119.51,55.12 119.51,53.47 121.28,51.69 121.28,46.35 124.08,43.56 v1(124.08,42.67)
  L14-SIGNAL w0.109: v1(175.88,32.13) 174.62,32.13 172.72,34.04 172.09,34.04 169.46,36.66 167.59,36.66 167.13,37.12 167.13,37.59 164.08,40.64 163.86,40.64 163.75,40.53 163.75,40.11 163.64,40.01 163.42,40.01 163.31,40.11 163.31,40.53 163.2,40.64 160.02,40.64 159.34,39.96 158.67,39.96 158.37,40.26 145.29,40.26 143.16,42.39 124.36,42.39 v1(124.08,42.67)
  BOTTOM w0.132: v1(175.88,32.13) J19.49
H_LCD_B2: length 80.1
  TOP w0.132: v1(154.93,42.8) 155.38,42.35 J13.13 ; R206.1 v1(123.57,63.75)
  L10-SIGNAL w0.089: v1(123.57,63.75) 124.71,62.61 126.62,62.61 128.52,60.71 128.52,47.12 133.22,42.42 140.21,42.42 141.48,41.15 153.54,41.15 154.31,41.91 154.31,42.17 v1(154.93,42.8)
  L14-SIGNAL w0.109: v1(175.38,32.64) 174.75,32.64 172.59,34.8 172.59,35.56 166.37,41.78 159.13,41.78 157.72,43.2 155.33,43.2 v1(154.93,42.8)
  BOTTOM w0.132: v1(175.38,32.64) J19.47
H_LCD_B3: length 84.1
  TOP w0.132: J13.25 152.38,41.8 152.15,42.04 v1(152.15,42.29) ; R201.1 v1(119.25,65.28)
  L10-SIGNAL w0.089: v1(152.15,42.29) 151.76,42.68 151.01,42.68 150.24,41.91 148.84,41.91 147.45,43.31 145.54,43.31 144.24,44.61 134.08,44.61 132.21,46.48 132.21,50.16 131.44,50.93 131.44,54.23 130.94,54.74 130.94,60.58 125.98,65.53 120.82,65.53 120.18,64.89 119.64,64.89 v1(119.25,65.28)
  L14-SIGNAL w0.109: v1(152.15,42.29) 152.58,42.29 153.84,43.55 157.83,43.55 159.21,42.16 166.5,42.16 173.35,35.31 173.35,34.67 v1(174.88,33.15)
  BOTTOM w0.132: v1(174.88,33.15) J19.45
H_LCD_B4: length 76.9
  TOP w0.132: v1(151.38,42.29) 151.88,41.8 J13.27 ; R568.1 v1(125.86,59.69)
  L10-SIGNAL w0.089: v1(127.25,43.81) 127.25,44.58 126.26,45.57 126.26,49.88 125.47,50.68 125.47,59.3 v1(125.86,59.69)
  L14-SIGNAL w0.109: v1(127.25,43.81) 127.54,44.1 134.47,44.1 134.87,43.69 140.08,43.69 140.91,44.52 144.71,44.52 145.41,43.81 149.86,43.81 v1(151.38,42.29) 153.21,44.12 161.75,44.12 163.32,42.55 166.62,42.55 174.37,34.8 v1(174.37,34.29)
  BOTTOM w0.132: v1(174.37,34.29) 174.37,32.77 174.38,32.76 J19.43
H_LCD_B5: length 109.7
  TOP w0.132: v1(151.41,38.59) 151.41,39 151.38,39.03 J13.29
  L10-SIGNAL w0.089: v1(120.02,61.98) 123.06,61.98 123.44,61.59 125.98,61.59 127.51,60.07 127.51,46.36 132.72,41.15 139.45,41.15 139.59,41 139.59,40.88 138.83,40.11 138.83,39.99 138.95,39.86 139.08,39.86 139.84,40.63 139.97,40.63 140.09,40.5 140.09,40.38 139.33,39.61 139.33,39.49 139.46,39.36 139.58,39.36 140.34,40.12 140.47,40.12 140.6,40 140.6,39.87 139.83,39.11 139.83,38.98 139.96,38.86 140.08,38.86 140.85,39.62 140.97,39.62 141.1,39.49 141.1,39.37 140.34,38.61 140.34,38.48 140.46,38.35 140.59,38.35 141.35,39.12 141.48,39.12 141.6,38.99 141.6,38.87 140.84,38.1 140.84,37.98 140.96,37.85 141.09,37.85 141.85,38.61 141.98,38.61 142.11,38.49 142.11,38.36 141.34,37.6 141.34,37.47 141.47,37.35 141.59,37.35 142.36,38.11 142.48,38.11 142.61,37.99 142.61,37.86 141.84,37.1 141.84,36.97 141.97,36.85 142.1,36.85 142.86,37.61 142.98,37.61 143.38,37.21 144.53,37.21 144.62,37.12 144.62,35.9 144.71,35.81 144.89,35.81 144.98,35.9 144.98,37.12 145.07,37.21 145.24,37.21 145.33,37.12 145.33,35.9 145.42,35.81 145.6,35.81 145.69,35.9 145.69,37.12 145.78,37.21 145.96,37.21 146.04,37.12 146.04,35.9 146.13,35.81 146.31,35.81 146.4,35.9 146.4,37.12 146.49,37.21 146.67,37.21 146.76,37.12 146.76,35.9 146.84,35.81 147.02,35.81 147.11,35.9 147.11,37.12 147.2,37.21 147.38,37.21 147.47,37.12 147.47,35.9 147.56,35.81 147.73,35.81 147.82,35.9 147.82,37.12 147.91,37.21 148.77,37.21 149.05,37.5 150.31,37.5 v1(151.41,38.59)
  L14-SIGNAL w0.109: v1(151.41,38.59) 151.91,38.59 153.29,37.21 162.43,37.21 163.86,35.78 168.81,35.78 172.21,32.38 v1(173.61,32.38)
  BOTTOM w0.132: R562.1 119.07,62.48 119.09,62.47 119.42,62.47 119.43,62.48 119.51,62.48 v1(120.02,61.98) ; v1(173.61,32.38) 173.88,32.12 J19.41
H_LCD_B6: length 81
  TOP w0.132: v1(150.88,38.99) J13.31 ; R565.1 v1(119.25,62.87)
  L10-SIGNAL w0.089: v1(119.25,62.87) 120.02,62.87 120.52,62.36 122.96,62.36 123.47,61.85 126.24,61.85 127.76,60.33 127.76,46.61 132.97,41.4 139.7,41.4 142.37,38.73 142.5,38.73 142.69,38.92 142.82,38.92 142.94,38.79 142.94,38.67 142.75,38.48 142.75,38.35 142.97,38.13 145.08,38.13 145.36,37.85 150.37,37.85 150.88,38.36 v1(150.88,38.99)
  L14-SIGNAL w0.109: v1(172.97,32.89) 172.21,32.89 169.1,36.01 164.02,36.01 161.68,38.34 152.67,38.34 152.02,38.99 v1(150.88,38.99)
  BOTTOM w0.132: J19.39 173.38,31.95 172.97,32.36 v1(172.97,32.89)
H_LCD_B7: length 83
  TOP w0.132: J13.33 150.38,39.21 150.37,39.2 v1(150.37,38.48)
  L10-SIGNAL w0.089: v1(150.37,38.48) 150.37,39.98 150.46,40.07 153.2,40.07 153.29,40.16 153.29,40.34 153.2,40.42 150.46,40.42 150.11,40.77 141.35,40.77 140.08,42.04 133.22,42.04 128.27,46.99 128.27,60.58 126.49,62.36 124.33,62.36 v1(123.83,62.87)
  L14-SIGNAL w0.109: v1(172.34,33.4) 171.83,33.91 171.7,33.91 169.38,36.23 164.3,36.23 161.12,39.41 150.62,39.41 150.37,39.16 v1(150.37,38.48)
  BOTTOM w0.132: J19.37 172.88,31.85 172.34,32.38 v1(172.34,33.4) ; R553.1 123.44,62.48 v1(123.83,62.87)
H_LCD_DE: length 84.7
  TOP w0.132: R210.1 v1(119.25,61.98)
  L10-SIGNAL w0.089: v1(119.25,61.98) 119.64,61.59 120.18,61.59 120.18,61.59 121.28,61.59 121.9,60.98 124.44,60.98 124.97,60.45 124.97,50.16 125.48,49.66 125.48,44.32 125.73,44.07 125.73,39.97 v1(126.24,39.46)
  L14-SIGNAL w0.109: v1(159,26.42) 157.76,26.42 157.6,26.58 157.6,27.53 157.44,27.69 157.21,27.69 157.05,27.53 157.05,26.58 156.89,26.42 156.66,26.42 156.5,26.58 156.5,27.53 156.34,27.69 156.12,27.69 155.96,27.53 155.96,26.58 155.8,26.42 155.57,26.42 152.2,29.79 149.41,29.79 147.66,31.54 141.69,31.54 140.84,32.38 137.03,32.38 132.21,37.21 130.68,37.21 129.41,38.48 129.03,38.48 128.05,39.46 v1(126.24,39.46)
  BOTTOM w0.132: v1(159,26.42) 161.29,26.42 161.93,27.05 169.93,27.05 170.38,26.6 J19.28
H_LCD_G0: length 73.8
  TOP w0.132: R555.1 v1(125.86,60.58)
  L10-SIGNAL w0.089: v1(125.86,60.58) 125.22,59.94 125.22,50.42 125.86,49.78 125.86,44.7 126.11,44.45 126.11,41.53 126.62,41.02 v1(126.62,40.26)
  L14-SIGNAL w0.109: v1(126.62,40.26) 128.14,40.26 129.16,39.24 129.67,39.24 130.94,37.97 132.46,37.97 137.36,33.08 147.2,33.08 148.4,31.88 152.15,31.88 155.58,28.45 166.5,28.45 166.62,28.32 171.07,28.32 v1(171.58,28.83)
  BOTTOM w0.132: v1(171.58,28.83) 171.88,29.13 J19.33
H_LCD_G1: length 77
  TOP w0.132: R564.1 v1(123.57,64.9)
  L10-SIGNAL w0.089: v1(142.49,42.93) 142.49,43.31 142.12,43.69 138.52,43.69 138.43,43.78 138.43,44.11 138.34,44.2 138.16,44.2 138.07,44.11 138.07,43.78 137.99,43.69 137.81,43.69 137.72,43.78 137.72,44.11 137.63,44.2 137.45,44.2 137.36,44.11 137.36,43.78 137.27,43.69 137.1,43.69 137.01,43.78 137.01,44.11 136.92,44.2 136.74,44.2 136.65,44.11 136.65,43.78 136.56,43.69 134.49,43.69 131.95,46.23 131.95,50.04 131.19,50.8 131.19,54.1 130.68,54.61 130.68,60.45 125.85,65.28 123.96,65.28 v1(123.57,64.9)
  L14-SIGNAL w0.109: v1(142.49,42.93) 143.76,42.93 146.05,40.64 157.23,40.64 157.61,41.02 164.34,41.02 167.64,37.72 169.29,37.72 170.48,36.53 170.48,36 171.18,35.31 v1(171.58,35.31)
  BOTTOM w0.132: J19.31 171.38,34.7 171.58,34.9 v1(171.58,35.31)
H_LCD_G2: length 86.2
  TOP w0.132: J13.17 154.38,42.6 154.23,42.74 154.22,42.74 v1(153.92,43.04)
  L10-SIGNAL w0.089: v1(153.92,43.04) 153.4,43.04 153.02,42.66 152.29,42.66 151.89,43.05 150.62,43.05 150.11,43.56 148.21,43.56 147.83,43.94 146.06,43.94 144.65,45.34 134.37,45.34 132.72,46.99 132.72,50.47 131.92,51.26 131.92,54.52 131.44,54.99 131.44,61.09 126.36,66.17 v1(120.02,66.17)
  L14-SIGNAL w0.109: v1(153.92,43.04) 154.28,42.69 154.28,42.07 154.69,41.66 156.59,41.66 156.97,42.04 156.97,42.42 157.12,42.56 157.84,42.56 159,41.4 166.24,41.4 166.64,41.01 166.64,40.85 165.97,40.18 165.97,40.03 166.12,39.87 166.27,39.87 166.95,40.54 167.1,40.54 167.26,40.39 167.26,39.28 167.66,38.88 167.88,38.88 168.53,38.23 169.37,38.23 170.88,36.72 v1(170.88,36.32)
  BOTTOM w0.132: J19.29 170.88,34.99 170.75,35.12 170.44,35.12 170.31,35.25 170.31,35.65 170.44,35.78 170.75,35.78 170.88,35.91 v1(170.88,36.32) ; v1(120.02,66.17) 119.62,65.77 119.09,65.77 119.07,65.79 R561.1
H_LCD_G3: length 79.3
  TOP w0.132: v1(149.88,39.01) J13.35 v1(149.88,42.42)
  L10-SIGNAL w0.089: v1(149.88,42.42) 148.84,42.42 148.69,42.57 148.69,42.69 148.82,42.82 148.82,42.95 148.7,43.07 148.57,43.07 148.44,42.95 148.32,42.95 147.65,43.61 145.84,43.61 144.49,44.96 134.24,44.96 132.46,46.74 132.46,50.29 131.7,51.05 131.7,54.36 131.19,54.86 131.19,60.83 126.16,65.86 120.6,65.86 v1(120.02,65.28)
  L14-SIGNAL w0.109: v1(149.88,39.01) 149.88,38.41 150.31,37.97 150.79,37.97 150.95,38.14 151.72,38.14 152.91,36.96 162.18,36.96 163.58,35.56 168.66,35.56 169.29,34.92 169.29,34.29 169.64,33.94 169.64,33.94 v1(169.92,33.66)
  BOTTOM w0.132: v1(169.92,33.66) 170.21,33.37 170.22,33.37 170.38,33.2 J19.27 ; v1(120.02,65.28) 119.62,64.88 119.09,64.88 119.07,64.9 R557.1
H_LCD_G4: length 86.7
  TOP w0.132: v1(149.48,44.32) 149.48,43.27 149.38,43.17 J13.37 v1(149.38,38.51) ; R200.1 v1(119.25,68.96)
  L10-SIGNAL w0.089: v1(119.25,68.96) 128.14,68.96 128.23,69.05 128.23,69.76 128.32,69.85 128.5,69.85 128.59,69.76 128.59,69.05 128.68,68.96 128.85,68.96 128.94,69.05 128.94,69.76 129.03,69.85 129.21,69.85 129.3,69.76 129.3,69.05 129.39,68.96 129.57,68.96 129.65,69.05 129.65,69.76 129.74,69.85 129.92,69.85 130.01,69.76 130.01,69.05 130.1,68.96 130.28,68.96 130.37,69.05 130.37,69.76 130.45,69.85 130.63,69.85 130.72,69.76 130.72,69.05 132.81,66.96 132.81,63.32 133.19,62.94 133.19,62.39 133.73,61.85 133.73,58.63 136.14,56.22 136.14,50.42 137.92,48.64 145.16,48.64 v1(149.48,44.32)
  L14-SIGNAL w0.109: v1(149.38,38.51) 150.68,37.21 151.89,37.21 153.17,35.93 159.5,35.93 160.12,36.55 162.08,36.55 163.31,35.32 167.5,35.32 169.88,32.94 v1(169.88,32.13)
  BOTTOM w0.132: J19.25 v1(169.88,32.13)
H_LCD_G5: length 90.4
  TOP w0.132: v1(148.72,44.32) 148.72,43.53 148.88,43.36 J13.39 v1(148.88,39.02) ; R559.1 v1(114.43,68.2)
  L10-SIGNAL w0.089: v1(148.72,44.32) 144.78,48.26 137.8,48.26 135.79,50.26 135.79,56.21 133.48,58.53 133.48,61.09 131.92,62.64 131.92,64.42 130.19,66.15 130.19,66.28 130.7,66.79 130.7,66.91 130.57,67.04 130.45,67.04 129.94,66.53 129.81,66.53 129.69,66.65 129.69,66.78 130.2,67.29 130.2,67.41 130.07,67.54 129.95,67.54 129.44,67.03 129.31,67.03 129.19,67.16 129.19,67.28 129.69,67.79 129.69,67.92 129.57,68.04 129.44,68.04 128.93,67.53 128.81,67.53 128.68,67.66 128.68,67.78 129.19,68.29 129.19,68.42 129.07,68.55 128.94,68.55 128.43,68.04 128.31,68.04 127.88,68.46 118.5,68.46 118.24,68.2 v1(114.43,68.2)
  L14-SIGNAL w0.109: v1(148.88,39.02) 148.88,37.43 149.9,36.41 150.06,36.41 150.28,36.63 150.44,36.63 150.67,36.4 150.67,36.25 150.44,36.02 150.44,35.87 150.6,35.71 159.79,35.71 160.4,36.32 161.8,36.32 163.07,35.05 167,35.05 v1(167.64,34.42)
  BOTTOM w0.132: J19.23 169.38,32.68 v1(167.64,34.42)
H_LCD_G6: length 87.1
  TOP w0.132: J13.41 v1(148.38,38.48)
  L10-SIGNAL w0.089: v1(148.38,38.48) 148.38,40.09 148.08,40.39 147.88,40.39 147.79,40.3 147.79,39.71 147.7,39.62 147.52,39.62 147.43,39.71 147.43,40.3 147.35,40.39 147.17,40.39 147.08,40.3 147.08,39.71 146.99,39.62 146.81,39.62 146.72,39.71 146.72,40.3 146.63,40.39 146.46,40.39 146.37,40.3 146.37,39.71 146.28,39.62 146.1,39.62 146.01,39.71 146.01,40.3 145.92,40.39 145.75,40.39 145.66,40.3 145.66,39.71 145.57,39.62 145.39,39.62 145.3,39.71 145.3,40.3 145.21,40.39 145.03,40.39 144.95,40.3 144.95,39.71 144.86,39.62 144.68,39.62 144.59,39.71 144.59,40.3 144.5,40.39 144.32,40.39 144.23,40.3 144.23,39.71 144.15,39.62 143.97,39.62 143.88,39.71 143.88,40.3 143.79,40.39 143.61,40.39 143.52,40.3 143.52,39.71 143.43,39.62 143.26,39.62 143.17,39.71 143.17,40.3 143.08,40.39 141.22,40.39 139.95,41.66 133.17,41.66 128.02,46.81 128.02,60.45 126.36,62.1 123.83,62.1 123.37,62.56 122.48,62.56 121.79,63.25 120.77,63.25 v1(120.02,64.01)
  L14-SIGNAL w0.109: v1(167.64,33.66) 166.62,34.67 163.07,34.67 162.18,33.78 160.78,33.78 159.08,35.49 150.32,35.49 148.38,37.42 v1(148.38,38.48)
  BOTTOM w0.132: v1(120.02,64.01) 119.62,63.61 119.09,63.61 119.07,63.63 R560.1 ; J19.21 168.88,32.42 v1(167.64,33.66)
H_LCD_G7: length 75.8
  TOP w0.132: v1(147.88,42.16) J13.43 v1(147.88,38.99)
  L10-SIGNAL w0.089: v1(124.33,64.9) 125.86,64.9 130.43,60.33 130.43,54.48 130.94,53.98 130.94,50.67 131.7,49.91 131.7,46.1 134.37,43.43 141.22,43.43 142.12,42.54 142.74,42.54 143.09,42.89 143.09,43.73 143.18,43.81 143.36,43.81 143.45,43.73 143.45,42.89 143.54,42.8 143.71,42.8 143.8,42.89 143.8,43.73 143.89,43.81 144.07,43.81 144.16,43.73 144.16,42.89 144.25,42.8 147.25,42.8 v1(147.88,42.16)
  L14-SIGNAL w0.109: v1(167.64,32.89) 166.12,34.42 163.32,34.42 162.43,33.53 160.66,33.53 158.92,35.26 150.03,35.26 147.88,37.41 v1(147.88,38.99)
  BOTTOM w0.132: J19.19 168.38,32.15 v1(167.64,32.89) ; v1(124.33,64.9) 123.94,64.5 123.41,64.5 123.39,64.52 R563.1
H_LCD_HS: length 90.4
  TOP w0.132: R577.1 v1(119.25,64.01)
  L10-SIGNAL w0.089: v1(124.89,39.75) 124.89,40.53 124.9,40.54 124.9,43.76 124.71,43.94 124.71,46.86 123.7,47.88 123.7,48.9 124.21,49.4 124.21,55.21 124.21,55.21 124.21,57.78 123.83,58.17 122.04,58.17 120.65,59.56 120.65,60.33 120.28,60.7 119.01,60.7 118.75,60.96 118.75,63.5 v1(119.25,64.01)
  L14-SIGNAL w0.109: v1(124.89,39.75) 127.41,37.23 127.55,37.23 128.33,36.45 131.57,36.45 137.46,30.57 141.52,30.57 142.75,29.34 143.38,29.34 144.27,28.45 152.27,28.45 155.7,25.02 159.13,25.02 161.8,22.35 162.31,22.35 162.56,22.61 162.56,25.4 162.8,25.64 162.95,25.64 163.19,25.41 163.19,22.61 163.45,22.35 166.37,22.35 v1(166.75,22.73)
  BOTTOM w0.132: J19.26 169.88,23.07 169.16,22.35 167.13,22.35 v1(166.75,22.73)
H_LCD_PCLK: length 84.5
  L10-SIGNAL w0.089: v1(124.33,40.39) 124.61,40.66 124.61,43.54 123.19,44.96 123.19,45.59 121.66,47.12 121.66,53.85 120.45,55.06 120.45,58.36 120.02,58.8 v1(120.02,60.2)
  L14-SIGNAL w0.109: v1(168.4,23.11) 168.4,24.12 168.51,24.23 169.44,24.23 169.54,24.34 169.54,24.56 169.44,24.67 168.51,24.67 168.4,24.78 168.4,25 168.51,25.11 169.44,25.11 169.54,25.22 169.54,25.44 169.44,25.54 168.51,25.54 165.99,28.07 165.06,28.07 165.05,28.08 164.7,28.08 164.69,28.07 154.56,28.07 154.18,28.45 154.18,29.08 153.16,30.1 152.02,30.1 151.91,30.21 151.91,31.2 151.8,31.31 151.58,31.31 151.48,31.2 151.48,30.21 151.37,30.1 149.73,30.1 147.07,32.77 137.16,32.77 132.33,37.59 130.81,37.59 129.47,38.93 129.03,38.93 128.1,39.86 125.49,39.86 124.97,40.39 v1(124.33,40.39)
  BOTTOM w0.132: v1(120.02,60.2) 119.51,60.71 R574.1 ; J19.20 168.38,23.14 v1(168.4,23.11)
H_LCD_R0: length 94.1
  TOP w0.132: R203.1 v1(114.43,67.31)
  L10-SIGNAL w0.089: v1(123.57,41.78) 122.05,43.31 122.05,44.36 120.52,45.89 120.52,47.37 118.27,49.62 118.27,51.4 117.19,52.48 117.19,53.83 116.79,54.23 116.46,54.23 113.54,57.15 113.54,66.42 v1(114.43,67.31)
  L14-SIGNAL w0.109: v1(167.64,32.13) 167.13,32.64 166.62,32.64 165.72,31.73 160.04,31.73 157.85,33.92 148.2,33.92 145.92,36.2 143.32,36.2 143.21,36.3 143.21,37.74 143.1,37.85 142.88,37.85 142.77,37.74 142.77,36.3 142.66,36.2 142.44,36.2 142.34,36.3 142.34,37.74 142.23,37.85 142.01,37.85 141.9,37.74 141.9,36.3 141.79,36.2 141.57,36.2 141.46,36.3 141.46,37.74 141.35,37.85 141.13,37.85 141.03,37.74 141.03,36.3 140.92,36.2 140.7,36.2 140.59,36.3 140.59,37.74 140.48,37.85 140.26,37.85 140.15,37.74 140.15,36.3 140.04,36.2 139.45,36.2 139.19,35.94 137.16,35.94 131.66,41.44 130.01,41.44 129.39,42.06 123.85,42.06 v1(123.57,41.78)
  BOTTOM w0.132: v1(167.64,32.13) 167.38,31.87 J19.15
H_LCD_R1: length 94.4
  TOP w0.132: R195.1 v1(114.43,66.29)
  L10-SIGNAL w0.089: v1(114.43,66.29) 113.92,65.79 113.92,57.4 116.68,54.65 118.45,54.65 119,54.1 119,53.47 118.75,53.21 118.75,52.07 118.74,51.94 119.38,51.31 119.38,49.28 120.9,47.75 120.9,45.97 122.43,44.45 122.43,43.69 124.1,42.02 124.1,41.3 v1(123.83,41.02)
  L14-SIGNAL w0.109: v1(166.88,32.13) 166.12,31.37 160.02,31.37 157.69,33.7 154.81,33.7 154.7,33.59 154.7,32.75 154.6,32.64 154.38,32.64 154.27,32.75 154.27,33.59 154.16,33.7 153.94,33.7 153.83,33.59 153.83,32.75 153.72,32.64 153.5,32.64 153.39,32.75 153.39,33.59 153.28,33.7 153.07,33.7 152.96,33.59 152.96,32.75 152.85,32.64 152.63,32.64 152.52,32.75 152.52,33.59 152.41,33.7 152.19,33.7 152.08,33.59 152.08,32.75 151.97,32.64 151.76,32.64 151.65,32.75 151.65,33.59 151.54,33.7 151.32,33.7 151.21,33.59 151.21,32.75 151.1,32.64 150.88,32.64 150.77,32.75 150.77,33.59 150.66,33.7 150.45,33.7 150.34,33.59 150.34,32.75 150.23,32.64 150.01,32.64 149.9,32.75 149.9,33.59 149.79,33.7 149.57,33.7 149.46,33.59 149.46,32.75 149.35,32.64 149.13,32.64 149.03,32.75 149.03,33.59 148.92,33.7 137.75,33.7 133.99,37.47 133.99,38.35 132.5,39.84 130.34,39.84 129.54,40.64 128.65,40.64 128.14,41.15 124.83,41.15 124.71,41.02 v1(123.83,41.02)
  BOTTOM w0.132: J19.13 v1(166.88,32.13)
H_LCD_R2: length 94.2
  TOP w0.132: v1(152.78,43.05) 152.78,41.96 152.88,41.86 J13.23 ; R199.1 v1(119.25,68.07)
  L10-SIGNAL w0.089: v1(119.25,68.07) 121.5,68.07 121.51,68.08 127.76,68.08 127.9,67.93 127.9,67.81 127.14,67.04 127.14,66.92 127.26,66.79 127.39,66.79 128.15,67.56 128.28,67.56 128.4,67.43 128.4,67.31 127.64,66.54 127.64,66.42 127.77,66.29 127.89,66.29 128.65,67.05 128.78,67.05 128.91,66.93 128.91,66.8 128.14,66.04 128.14,65.91 128.27,65.79 128.39,65.79 129.16,66.55 129.28,66.55 129.41,66.43 129.41,66.3 128.65,65.54 128.65,65.41 128.77,65.28 128.9,65.28 129.66,66.05 129.79,66.05 129.91,65.92 129.91,65.8 129.15,65.03 129.15,64.91 129.27,64.78 129.4,64.78 130.16,65.55 130.29,65.55 130.41,65.42 130.41,65.29 129.65,64.53 129.65,64.4 129.78,64.28 129.9,64.28 130.67,65.04 130.79,65.04 130.92,64.92 130.92,64.79 130.15,64.03 130.15,63.9 130.28,63.78 130.41,63.78 131.17,64.54 131.29,64.54 131.57,64.26 131.57,62.61 133.22,60.96 133.22,58.37 134.87,56.72 134.87,49.02 135.89,48.01 144.27,48.01 148.46,43.81 150.34,43.81 150.84,43.31 152.14,43.31 152.39,43.05 v1(152.78,43.05)
  L14-SIGNAL w0.109: v1(152.78,43.05) 153.57,43.85 157.96,43.85 159.15,42.66 v1(162.05,42.66)
  BOTTOM w0.132: v1(162.05,42.66) 162.05,40.13 166.38,35.81 J19.11
H_LCD_R3: length 86.7
  TOP w0.132: R202.1 v1(119.25,67.18) ; v1(147.38,38.54) J13.45 147.38,43.42 147.19,43.61 v1(147.19,44.32)
  L10-SIGNAL w0.089: v1(147.19,44.32) 145.41,46.1 143.55,46.1 143.46,46.19 143.46,47.03 143.37,47.12 143.19,47.12 143.1,47.03 143.1,46.19 143.02,46.1 142.84,46.1 142.75,46.19 142.75,47.03 142.66,47.12 142.48,47.12 142.39,47.03 142.39,46.19 142.3,46.1 142.13,46.1 142.04,46.19 142.04,47.03 141.95,47.12 141.77,47.12 141.68,47.03 141.68,46.19 141.59,46.1 141.42,46.1 141.33,46.19 141.33,47.03 141.24,47.12 141.06,47.12 140.97,47.03 140.97,46.19 140.88,46.1 140.7,46.1 140.62,46.19 140.62,47.03 140.53,47.12 140.35,47.12 140.26,47.03 140.26,46.19 140.17,46.1 139.99,46.1 139.9,46.19 139.9,47.03 139.82,47.12 139.64,47.12 139.55,47.03 139.55,46.19 139.46,46.1 135.51,46.1 134.49,47.12 134.49,52.83 131.92,55.4 131.92,61.63 126.36,67.18 v1(119.25,67.18)
  L14-SIGNAL w0.109: v1(165.86,33.4) 165.23,34.04 163.45,34.04 162.69,33.27 160.53,33.27 158.76,35.04 149.75,35.04 147.38,37.4 v1(147.38,38.54)
  BOTTOM w0.132: v1(165.86,33.4) 165.86,32.99 165.88,32.97 J19.9
H_LCD_R4: length 76.1
  TOP w0.132: v1(146.88,39.09) J13.47 v1(146.88,42.16)
  L10-SIGNAL w0.089: v1(124.33,63.75) 125.22,62.87 126.75,62.87 128.91,60.71 128.91,51.42 128.99,51.33 129.32,51.33 129.41,51.24 129.41,51.06 129.32,50.97 128.99,50.97 128.91,50.89 128.91,49.65 128.99,49.56 129.83,49.56 129.92,49.47 129.92,49.3 129.83,49.21 128.99,49.21 128.91,49.12 128.91,48.94 128.99,48.85 129.83,48.85 129.92,48.76 129.92,48.58 129.83,48.5 128.99,48.5 128.91,48.41 128.91,48.23 128.99,48.14 129.83,48.14 129.92,48.05 129.92,47.87 129.83,47.78 128.99,47.78 128.91,47.7 128.91,47.24 133.48,42.67 140.46,42.67 141.6,41.53 146.63,41.53 146.88,41.78 v1(146.88,42.16)
  L14-SIGNAL w0.109: v1(146.88,39.09) 146.88,37.4 149.46,34.81 158.61,34.81 160.4,33.02 162.94,33.02 163.6,33.68 164.56,33.68 v1(164.85,33.4)
  BOTTOM w0.132: J19.7 165.38,32.87 v1(164.85,33.4) ; R566.1 123.39,63.37 123.41,63.36 123.94,63.36 v1(124.33,63.75)
H_LCD_R5: length 86.4
  TOP w0.132: v1(146.38,38.48) J13.49 146.38,43.53 146.3,43.61 v1(146.3,44.32) ; R197.1 v1(119.25,66.17)
  L10-SIGNAL w0.089: v1(146.3,44.32) 144.91,45.72 135.38,45.72 134.02,47.08 133.18,47.08 133.1,47.17 133.1,47.35 133.18,47.43 134.02,47.43 134.11,47.52 134.11,47.7 134.02,47.79 133.18,47.79 133.1,47.88 133.1,48.06 133.18,48.15 134.02,48.15 134.11,48.23 134.11,48.41 134.02,48.5 133.18,48.5 133.1,48.59 133.1,48.77 133.18,48.86 134.02,48.86 134.11,48.95 134.11,49.12 134.02,49.21 133.18,49.21 133.1,49.3 133.1,49.48 133.18,49.57 134.02,49.57 134.11,49.66 134.11,49.83 134.02,49.92 133.18,49.92 133.1,50.01 133.1,50.19 133.18,50.28 134.02,50.28 134.11,50.37 134.11,50.55 134.02,50.63 133.18,50.63 133.1,50.72 133.1,50.9 133.18,50.99 134.02,50.99 134.11,51.08 134.11,51.87 133.83,52.15 133.7,52.15 133.36,51.81 133.23,51.81 133.1,51.94 133.1,52.06 133.45,52.41 133.45,52.53 133.19,52.79 133.19,53.63 131.7,55.12 131.7,61.34 126.36,66.67 119.76,66.67 v1(119.25,66.17)
  L14-SIGNAL w0.109: v1(146.38,38.48) 146.38,37.39 149.18,34.59 158.37,34.59 160.32,32.64 163.07,32.64 163.7,33.27 164.34,33.27 164.88,32.73 v1(164.88,32.26)
  BOTTOM w0.132: J19.5 v1(164.88,32.26)
H_LCD_R6: length 90
  TOP w0.132: v1(145.88,42.2) J13.51 145.88,39.08 v1(145.86,39.05) ; R212.1 v1(114.43,65.28)
  L10-SIGNAL w0.089: v1(114.43,65.28) 115.06,64.64 120.48,64.64 120.62,64.51 125.86,64.51 130.18,60.2 130.18,54.36 130.68,53.85 130.68,53.65 130.59,53.56 130.14,53.56 130.05,53.47 130.05,53.29 130.14,53.2 130.59,53.2 130.68,53.11 130.68,52.93 130.59,52.84 130.14,52.84 130.05,52.76 130.05,52.58 130.14,52.49 130.59,52.49 130.68,52.4 130.68,52.22 130.59,52.13 130.14,52.13 130.05,52.04 130.05,51.87 130.14,51.78 130.59,51.78 130.68,51.69 130.68,51.51 130.59,51.42 130.14,51.42 130.05,51.33 130.05,51.16 130.14,51.07 130.59,51.07 130.68,50.98 130.68,50.55 131.44,49.78 131.44,49.58 131.36,49.49 130.52,49.49 130.43,49.4 130.43,49.23 130.52,49.14 131.36,49.14 131.44,49.05 131.44,48.87 131.36,48.78 130.52,48.78 130.43,48.69 130.43,48.51 130.52,48.43 131.36,48.43 131.44,48.34 131.44,48.16 131.36,48.07 130.52,48.07 130.43,47.98 130.43,47.8 130.52,47.71 131.36,47.71 131.44,47.62 131.44,47.45 131.36,47.36 130.64,47.36 130.56,47.27 130.56,47.09 130.64,47 131.36,47 131.44,46.91 131.44,46.74 131.36,46.65 130.77,46.65 130.68,46.56 130.68,46.38 130.77,46.29 131.36,46.29 131.44,46.2 131.44,45.85 134.11,43.18 140.97,43.18 141.99,42.16 142.87,42.16 143.26,42.55 145.54,42.55 v1(145.88,42.2)
  L14-SIGNAL w0.109: v1(164.21,32.77) 163.7,32.77 163.32,32.38 160.15,32.38 158.16,34.37 148.89,34.37 145.86,37.4 v1(145.86,39.05)
  BOTTOM w0.132: J19.3 164.38,32.19 164.21,32.36 v1(164.21,32.77)
H_LCD_R7: length 89.8
  TOP w0.132: v1(145.16,42.16) 145.38,41.94 J13.53 145.38,38.93 145.41,38.9 v1(145.41,38.48) ; R207.1 v1(114.43,64.39)
  L10-SIGNAL w0.089: v1(114.43,64.39) 116.29,64.39 116.3,64.4 120.39,64.4 120.65,64.14 121.37,64.14 121.38,64.14 125.85,64.14 129.79,60.2 129.79,59.99 129.71,59.91 129.25,59.91 129.16,59.82 129.16,59.64 129.25,59.55 129.71,59.55 129.79,59.46 129.79,59.28 129.71,59.19 129.25,59.19 129.16,59.11 129.16,58.93 129.25,58.84 129.71,58.84 129.79,58.75 129.79,58.57 129.71,58.48 129.25,58.48 129.16,58.39 129.16,58.22 129.25,58.13 129.71,58.13 129.79,58.04 129.79,57.86 129.71,57.77 129.25,57.77 129.16,57.68 129.16,57.51 129.25,57.42 129.71,57.42 129.79,57.33 129.79,57.15 129.71,57.06 129.25,57.06 129.16,56.97 129.16,56.79 129.25,56.71 129.71,56.71 129.79,56.62 129.79,56.44 129.71,56.35 129.25,56.35 129.16,56.26 129.16,56.08 129.25,55.99 129.71,55.99 129.79,55.91 129.79,55.73 129.71,55.64 129.25,55.64 129.16,55.55 129.16,55.37 129.25,55.28 129.71,55.28 129.79,55.19 129.79,55.02 129.71,54.93 129.25,54.93 129.16,54.84 129.16,54.66 129.25,54.57 129.71,54.57 129.79,54.48 129.79,54.31 129.71,54.22 129.25,54.22 129.16,54.13 129.16,53.95 129.25,53.86 129.71,53.86 129.79,53.77 129.79,53.59 129.71,53.51 129.25,53.51 129.16,53.42 129.16,53.24 129.25,53.15 129.71,53.15 129.79,53.06 129.79,52.88 129.71,52.79 129.25,52.79 129.16,52.7 129.16,52.53 129.25,52.44 129.71,52.44 129.79,52.35 129.79,52.17 129.71,52.08 129.25,52.08 129.16,51.99 129.16,51.82 129.25,51.73 129.71,51.73 129.79,51.64 129.79,50.93 130.18,50.55 130.18,50.34 130.09,50.25 129.5,50.25 129.41,50.17 129.41,49.99 129.5,49.9 130.09,49.9 130.18,49.81 130.18,46.48 133.73,42.93 140.72,42.93 141.73,41.91 143.13,41.91 143.38,42.16 v1(145.16,42.16)
  L14-SIGNAL w0.109: v1(163.83,32.13) 160.02,32.13 158.01,34.14 148.61,34.14 145.41,37.34 v1(145.41,38.48)
  BOTTOM w0.132: v1(163.83,32.13) 163.88,32.08 J19.1
H_LCD_VS: length 79.3
  TOP w0.132: R570.1 v1(122.9,61.59)
  L10-SIGNAL w0.089: v1(122.9,61.59) 123.2,61.29 125.78,61.29 127.26,59.81 127.26,46.09 129.03,44.32 129.03,41.78 128.4,41.15 128.4,39.13 v1(128.02,38.75)
  L14-SIGNAL w0.109: v1(167.39,23.11) 165.48,25.02 164.34,25.02 163.07,26.29 160.4,26.29 159.51,25.4 155.83,25.4 152.4,28.83 148.84,28.83 146.98,30.69 142.03,30.69 140.72,32 136.65,32 131.83,36.83 130.43,36.83 129.41,37.85 128.92,37.85 v1(128.02,38.75)
  BOTTOM w0.132: v1(167.39,23.11) 167.89,22.61 168.91,22.61 169.38,23.07 J19.24
H_LJCB_CLKN: length 131.7
  TOP w0.099: R576.1 73.94,57.66 v1(73.91,57.63) 73.48,58.06 63.61,58.06 37.83,83.84 37.83,113.93 35.89,115.88 35.89,117.51 36.18,117.8 36.18,132.22 34.42,133.99 34.42,136.27 32.51,138.18 32.51,139.83 34.29,141.6 34.29,145.29 34.8,145.8 34.8,148.64 33.97,149.47 31.94,149.47 31.61,149.14 31.61,148.98 31.75,148.84 C53.1 ; U42.AF14 v1(82.98,57.16)
  BOTTOM w0.099: v1(82.98,57.16) 82.92,57.16 82.76,57.32 82.71,57.32 82.48,57.55 81.55,57.55 81.39,57.39 76.82,57.39 76.3,57.91 75.18,57.91 R211.2 74.36,57.98 74.26,57.98 v1(73.91,57.63)
H_LJCB_CLKP: length 132.5
  TOP w0.099: U42.AE13 v1(83.78,57.96) ; R573.1 73.92,58.55 v1(73.91,58.54) 73.88,58.54 73.67,58.33 63.72,58.33 38.1,83.95 38.1,114.04 36.15,115.99 36.15,117.4 36.45,117.69 36.45,132.33 34.68,134.1 34.68,136.38 32.78,138.29 32.78,139.72 34.56,141.49 34.56,145.18 35.06,145.69 35.06,148.75 34.08,149.73 31.83,149.73 31.34,149.25 31.34,148.97 31.22,148.84 C52.1
  BOTTOM w0.099: v1(73.91,58.54) 74.21,58.24 74.5,58.24 R211.1 75.17,58.18 76.41,58.18 76.93,57.66 81.28,57.66 81.44,57.81 82.59,57.81 82.82,57.58 83.14,57.58 83.37,57.81 83.63,57.81 v1(83.78,57.96)
H_MCA2_ACLKX: length 48.4
  TOP w0.132: v1(126.82,53.58) 126.3,54.1 R231.1
  L12-SIGNAL w0.089: v1(126.82,53.58) 130.3,57.06 130.3,85.34 133.99,89.03 136.78,89.03 138.15,90.4 v1(138.15,92.26)
  BOTTOM w0.132: RU18.11 v1(138.15,92.26)
H_MCA2_AFSX: length 29.1
  TOP w0.132: RU9.8 139,78.37 136.32,75.69 136.2,75.69 v1(135.25,74.75) ; R224.2 v1(125.86,57.02)
  L7-SIGNAL w0.089: v1(125.86,57.02) 126.23,57.4 126.99,57.4 129.41,59.82 129.41,68.91 v1(135.25,74.75)
H_MCA2_AXR0: length 54.7
  TOP w0.132: U42.B14 v1(102.99,57.16)
  L7-SIGNAL w0.089: v1(102.99,57.16) 103.36,57.54 104.78,57.54 105.73,58.49 108.63,58.49 108.81,58.67 119.63,58.67 120.73,59.77 120.73,60.27 122.43,61.98 123.7,61.98 124.84,63.12 124.84,65.02 124.08,65.79 124.08,70.1 133.6,79.63 137.16,79.63 138.94,81.41 v1(139.64,81.41)
  BOTTOM w0.132: RU20.2 v1(139.64,81.41)
H_MCA2_AXR1: length 51.6
  TOP w0.132: U42.A14 v1(103.79,57.16)
  L7-SIGNAL w0.089: v1(103.79,57.16) 104.79,57.16 105.79,58.17 108.71,58.17 108.97,58.42 119.76,58.42 122.43,61.09 123.19,61.09 123.82,61.72 123.95,61.72 125.22,62.99 125.22,68.71 125.98,69.46 125.98,71.49 133.73,79.25 137.35,79.25 v1(139,80.9)
  BOTTOM w0.132: v1(139,80.9) RU20.3
H_MCA2_AXR2: length 54.2
  TOP w0.132: U42.C14 v1(102.19,57.16)
  L7-SIGNAL w0.089: v1(122.94,56.61) 122.96,56.63 123,56.63 123.01,56.64 123.98,56.64 124.11,56.52 127,56.52 129.79,59.31 129.79,68.58 135.64,74.42 135.64,76 135.64,76.01 135.64,76.34 v1(136.02,76.71)
  L12-SIGNAL w0.089: v1(102.19,57.16) 102.71,56.64 104.65,56.64 105.19,57.18 119.6,57.18 119.69,57.09 121.6,57.09 122.08,56.61 v1(122.94,56.61)
  BOTTOM w0.132: RU20.4 138.37,78.3 137.29,77.22 136.53,77.22 v1(136.02,76.71)
H_MCA2_AXR3: length 50.1
  TOP w0.132: U42.A15 v1(103.79,55.56)
  L7-SIGNAL w0.089: v1(134.11,76.96) 127.51,70.36 127.51,63.5 124.71,60.71 124.71,59.16 123.85,58.29 121.7,58.29 120.21,56.8 116.75,56.8 115.51,55.56 v1(103.79,55.56)
  BOTTOM w0.132: RU20.5 137.73,78.17 137.16,77.6 136.27,77.6 135.64,76.96 v1(134.11,76.96)
H_MCA2_AXR4: length 55.3
  TOP w0.132: U42.D15 v1(101.39,55.56)
  L7-SIGNAL w0.089: v1(136.9,78.09) 136.9,76.58 136.02,75.69 136.02,74.62 135.99,74.59 135.99,74.26 130.18,68.45 130.18,59.18 127.13,56.13 125.35,56.13 124.97,55.75 123.69,55.75 123.67,55.77 v1(123.3,55.77)
  L12-SIGNAL w0.089: v1(123.3,55.77) 122.83,55.3 121.1,55.3 119.96,56.44 116.26,56.44 115.44,55.63 104.65,55.63 104.17,55.15 101.8,55.15 v1(101.39,55.56)
  BOTTOM w0.132: RU20.6 137.1,78.29 v1(136.9,78.09)
H_MCA2_AXR5: length 55.4
  TOP w0.132: U42.B15 v1(102.99,55.56)
  L7-SIGNAL w0.089: v1(102.99,55.56) 103.36,55.94 103.94,55.94 104.01,55.87 113.43,55.87 113.61,56.05 113.61,56.81 113.7,56.9 113.96,56.9 114.05,56.81 114.05,56.05 114.14,55.96 114.41,55.96 114.5,56.05 114.5,56.81 114.59,56.9 114.85,56.9 114.94,56.81 114.94,56.05 115.03,55.96 115.43,55.96 117,57.53 117.27,57.53 117.35,57.44 117.35,57.09 117.44,57 117.71,57 117.8,57.09 117.8,57.44 117.89,57.53 118.15,57.53 118.24,57.44 118.24,57.09 118.33,57 118.6,57 118.69,57.09 118.69,57.44 118.78,57.53 119.04,57.53 119.13,57.44 119.13,57.09 119.22,57 120.12,57 121.72,58.6 122.35,58.6 122.93,59.18 123.95,59.18 124.46,59.69 124.46,60.96 127.13,63.63 127.13,70.61 135,78.49 135.91,78.49 v1(136.24,78.15)
  BOTTOM w0.132: v1(136.24,78.15) 136.24,78.16 136.46,78.38 RU20.7
H_MCA2_AXR6: length 54.8
  TOP w0.132: U42.B16 v1(102.99,54.76)
  L7-SIGNAL w0.089: v1(134.75,77.6) 134.75,76.96 127.89,70.1 127.89,63.31 127.56,62.98 127.56,62.85 127.97,62.44 127.97,62.31 127.78,62.12 127.66,62.12 127.24,62.54 127.12,62.54 126.93,62.35 126.93,62.22 127.47,61.68 127.47,61.56 127.28,61.37 127.15,61.37 126.62,61.91 126.49,61.91 126.3,61.72 126.3,61.59 126.84,61.05 126.84,60.93 126.65,60.74 126.53,60.74 125.99,61.28 125.86,61.28 125.09,60.51 125.09,59.18 123.95,58.04 121.92,58.04 120.52,56.64 120.52,56.01 119.38,54.86 104.27,54.86 103.99,55.14 103.36,55.14 v1(102.99,54.76)
  BOTTOM w0.132: v1(134.75,77.6) 135.38,77.6 135.83,78.04 RU20.8
H_MCA2_AXR7: length 61.6
  TOP w0.132: U42.A16 v1(103.79,54.76)
  L7-SIGNAL w0.089: v1(135.19,78.11) 135.19,76.77 134.3,75.88 134.3,75.24 133.98,74.92 133.98,74.9 132.77,73.7 132.65,73.7 132.38,73.96 132.26,73.96 132.07,73.77 132.07,73.65 132.33,73.38 132.33,73.26 132.15,73.07 132.02,73.07 131.75,73.33 131.63,73.33 131.44,73.15 131.44,73.02 131.71,72.75 131.71,72.63 131.52,72.44 131.39,72.44 131.12,72.71 131,72.71 130.81,72.52 130.81,72.39 131.08,72.13 131.08,72 130.89,71.81 130.76,71.81 130.5,72.08 130.37,72.08 130.18,71.89 130.18,71.76 130.45,71.5 130.45,71.37 130.26,71.18 130.13,71.18 129.87,71.45 129.74,71.45 129.55,71.26 129.55,71.13 129.82,70.87 129.82,70.74 129.63,70.55 129.5,70.55 129.24,70.82 129.11,70.82 128.92,70.63 128.92,70.5 129.19,70.24 129.19,70.11 129,69.92 128.88,69.92 128.61,70.19 128.48,70.19 128.29,70 128.29,69.88 128.56,69.61 128.56,69.48 128.27,69.19 128.27,61.85 126.63,60.2 125.74,60.2 125.35,59.82 125.35,58.23 125.26,58.14 124.55,58.14 124.46,58.05 124.46,57.78 124.55,57.7 125.26,57.7 125.35,57.61 125.35,57.4 124.97,57.02 122.56,57.02 121.65,56.11 121.65,55.08 121.56,54.99 121.29,54.99 121.2,55.08 121.2,56.05 121.11,56.13 120.85,56.13 120.76,56.05 120.76,55.08 120.54,54.86 119.89,54.86 119.52,54.5 118.12,54.5 117.99,54.37 117.99,53.98 117.86,53.85 117.67,53.85 117.54,53.98 117.54,54.37 117.41,54.5 104.05,54.5 v1(103.79,54.76)
  BOTTOM w0.132: v1(135.19,78.11) RU20.9
H_MCA3_ACLKX: length 52.4
  TOP w0.132: v1(126.87,54.61) 126.46,55.03 125.81,55.03 125.65,54.86 R221.1
  L12-SIGNAL w0.089: v1(126.87,54.61) 129.92,57.66 129.92,85.6 135.73,91.41 135.73,92.42 136.27,92.96 141.91,92.96 v1(142.65,92.23)
  BOTTOM w0.132: RU18.2 v1(142.65,92.23)
H_MCA3_AFSX: length 44.6
  L14-SIGNAL w0.109: v1(126.75,58.8) 127.28,59.34 127.28,70.58 133.1,76.39 133.1,82.68 135.99,85.57 135.99,87.12 136.06,87.19 136.06,87.78 135.99,87.85 135.99,89.14 v1(136.4,89.55)
  BOTTOM w0.132: R214.2 125.68,59.31 125.69,59.29 126.24,59.29 126.44,59.09 126.46,59.09 v1(126.75,58.8) ; v1(136.4,89.55) 139.21,89.55 141.65,91.99 RU18.4
H_MCA3_AXR0: length 51.2
  TOP w0.132: v1(126.82,52.63) 126.36,53.09 R228.2
  L12-SIGNAL w0.089: v1(126.82,52.63) 130.2,56.01 130.21,56.01 130.68,56.48 130.68,85.09 133.73,88.14 137.92,88.14 140.65,90.86 v1(140.65,92.2)
  BOTTOM w0.132: v1(140.65,92.2) RU18.6
H_MCA3_AXR1: length 44.3
  L14-SIGNAL w0.109: v1(125.86,55.63) 128.02,57.78 128.02,70.1 135.76,77.85 135.76,82.17 138.82,85.23 138.82,86.63 139.15,86.95 v1(139.15,92.2)
  BOTTOM w0.132: R586.2 v1(125.86,55.63) ; RU18.9 v1(139.15,92.2)
H_MCA6_AXR0: length 45.5
  TOP w0.132: U42.B11 v1(102.99,59.56) ; RU9.4 136.46,80.75 v1(136.45,80.76)
  L7-SIGNAL w0.089: v1(102.99,59.56) 103.36,59.19 104.91,59.19 105.28,59.57 105.28,59.99 105.87,60.58 108.97,60.58 112.14,63.75 114.43,63.75 115.82,65.15 115.82,65.28 116.33,65.79 116.84,65.79 118.75,67.7 120.15,67.7 134.11,81.66 135.55,81.66 v1(136.45,80.76)
H_MCA6_AXR1: length 45.4
  TOP w0.132: RU9.5 v1(137.1,81.15) ; U42.A11 v1(103.79,59.56)
  L7-SIGNAL w0.089: v1(137.1,81.15) 136.33,81.92 133.86,81.92 120.52,68.58 118.11,68.58 115.06,65.53 115.06,65.15 114.68,64.77 112.65,64.77 109.47,61.59 108.64,61.59 108.63,61.6 105.75,61.6 105.51,61.36 105.51,61.28 v1(103.79,59.56)
H_MCA6_CLKX: length 25.8
  TOP w0.132: RU9.3 135.83,77.41 135.27,76.85 v1(135.27,76.16) ; R209.1 v1(125.86,58.8)
  L7-SIGNAL w0.089: v1(125.86,58.8) 126.36,59.31 127,59.31 128.65,60.96 128.65,69.09 134.59,75.02 134.59,75.48 v1(135.27,76.16)
H_MCA6_FSX: length 31.1
  TOP w0.132: R213.1 v1(119.25,59.18) ; RU9.2 135.19,80.71 v1(135.25,80.77)
  L7-SIGNAL w0.089: v1(119.25,59.18) 119.76,59.18 120.52,59.94 120.52,60.58 122.81,62.87 122.81,65.02 123.7,65.91 123.7,70.23 133.48,80.01 134.49,80.01 v1(135.25,80.77)
H_MCA7_AXR0: length 63.9
  TOP w0.132: U42.D14 v1(101.39,57.16)
  L7-SIGNAL w0.089: v1(101.39,57.16) 101.85,56.7 105.21,56.7 105.66,57.15 106.32,57.15 106.41,57.24 106.41,57.7 106.5,57.78 106.76,57.78 106.85,57.7 106.85,57.24 106.94,57.15 107.21,57.15 107.3,57.24 107.3,57.7 107.38,57.78 107.65,57.78 107.74,57.7 107.74,57.24 107.83,57.15 109.98,57.15 111,58.17 120.02,58.17 122.56,60.71 123.32,60.71 125.6,62.99 125.6,68.45 126.36,69.22 126.36,71.37 131.83,76.83 v1(132.33,76.83)
  L14-SIGNAL w0.109: v1(133.15,92.26) 133.15,89.59 132.59,89.03 132.59,84.58 132.33,84.33 v1(132.33,76.83)
  BOTTOM w0.132: RU18.21 v1(133.15,92.26)
H_MCA7_AXR1: length 63.1
  TOP w0.132: U42.B12 v1(102.99,58.76)
  L14-SIGNAL w0.109: v1(130.18,89.15) 129.67,88.65 129.67,78.61 123.17,72.12 123.17,62.5 124.46,61.21 124.46,59.56 124.1,59.2 123.21,59.2 122.79,58.78 118.47,58.78 118.17,58.48 103.27,58.48 v1(102.99,58.76)
  BOTTOM w0.132: RU18.18 134.65,91.98 131.83,89.15 v1(130.18,89.15)
H_MCA7_CLKX: length 39.8
  L14-SIGNAL w0.109: v1(136.15,92.2) 135.64,91.69 135.64,88.27 135.67,88.23 135.67,87.72 135.74,87.65 135.74,87.32 135.67,87.25 135.67,85.7 132.75,82.78 132.75,76.62 126.62,70.48 v1(126.62,59.69)
  BOTTOM w0.132: RU18.15 v1(136.15,92.2) ; R583.1 125.68,60.2 125.79,60.09 126.22,60.09 v1(126.62,59.69)
H_MCA7_FSX: length 41.7
  TOP w0.132: v1(125.86,57.92) 125.86,57.92 125.85,57.91 R218.1
  L14-SIGNAL w0.109: v1(137.15,92.26) 137.15,91.86 137.27,91.74 137.27,86.78 137.27,86.78 137.27,86.45 137.27,86.45 137.27,86.22 135.89,84.84 135.89,83.57 133.48,81.15 133.48,76.33 127.64,70.48 127.64,59.05 126.98,58.4 126.34,58.4 v1(125.86,57.92)
  BOTTOM w0.132: RU18.13 v1(137.15,92.26)
H_MDIO_D: length 72.7
  TOP w0.132: U42.U3 v1(90.18,65.97)
  L10-SIGNAL w0.089: v1(56.06,110.49) 58.08,110.49 58.42,110.15 58.42,108.97 57.02,107.57 57.02,107.21 57.15,107.08 57.53,107.08 57.66,106.95 57.66,106.76 57.53,106.63 57.15,106.63 57.02,106.5 57.02,106.32 57.15,106.19 57.53,106.19 57.66,106.06 57.66,105.88 57.53,105.75 57.15,105.75 57.02,105.61 57.02,105.43 57.15,105.3 57.53,105.3 57.66,105.17 57.66,104.99 57.53,104.86 57.15,104.86 57.02,104.73 57.02,104.54 57.15,104.41 57.53,104.41 57.66,104.28 57.66,104.1 57.53,103.97 57.15,103.97 57.02,103.84 57.02,103.65 57.15,103.52 57.53,103.52 57.66,103.39 57.66,103.21 57.53,103.08 57.15,103.08 57.02,102.95 57.02,100.08 64.39,92.71 64.39,89.79 66.17,88.01 67.82,88.01 80.35,75.48 84.32,75.48 84.36,75.44 85.09,75.44 87.25,73.28 87.93,73.28 89.77,71.44 89.77,66.38 v1(90.18,65.97)
  BOTTOM w0.132: v1(56.06,110.49) 56.03,110.46 RU14.7
H_MDIO_MCLK: length 80.8
  TOP w0.132: U42.V1 v1(89.38,67.57)
  L10-SIGNAL w0.089: v1(57.98,109.73) 55.26,107.01 55.26,106.71 55.39,106.58 56.51,106.58 56.64,106.45 56.64,106.27 56.51,106.14 55.39,106.14 55.26,106.01 55.26,105.83 55.39,105.69 56.51,105.69 56.64,105.56 56.64,105.38 56.51,105.25 55.39,105.25 55.26,105.12 55.26,104.94 55.39,104.81 56.51,104.81 56.64,104.68 56.64,104.49 56.51,104.36 55.39,104.36 55.26,104.23 55.26,104.05 55.39,103.92 56.51,103.92 56.64,103.79 56.64,103.6 56.51,103.47 55.39,103.47 55.26,103.34 55.26,103.16 55.39,103.03 56.51,103.03 56.64,102.9 56.64,102.71 56.51,102.58 55.39,102.58 55.26,102.45 55.26,102.27 55.39,102.14 56.51,102.14 56.64,102.01 56.64,101.82 56.51,101.69 55.39,101.69 55.26,101.56 55.26,101.38 55.39,101.25 56.51,101.25 56.64,101.12 56.64,100.94 56.51,100.81 55.39,100.81 55.26,100.68 55.26,98.92 59.31,94.87 59.31,92.96 65.02,87.25 67.94,87.25 80.01,75.18 84.2,75.18 89.38,70 v1(89.38,67.57)
  BOTTOM w0.132: RU14.4 v1(57.98,109.73)
H_MLBP_CLK: length 122.2
  TOP w0.132: v1(5,156.45) P5.2
  L14-SIGNAL w0.109: v1(68.04,83.24) 67.71,83.57 62.36,83.57 61.59,84.33 59.18,84.33 58.42,85.09 48.39,85.09 39.31,94.17 39.31,128.08 36.07,131.32 34.67,131.32 30.86,135.13 18.41,135.13 15.62,137.92 15.62,148.34 7.49,156.46 5.41,156.46 5.4,156.45 v1(5,156.45)
  BOTTOM w0.132: R535.2 68.52,83.19 68.46,83.24 v1(68.04,83.24)
H_MLBP_CLKN: length 154.3
  TOP w0.099: v1(79.42,78.74) 79.7,78.46 79.7,77.84 R167.2 79.74,77.05 79.74,76.59 80.14,76.2 81.03,76.2 86.35,70.88 86.35,68.44 86.22,68.31 86.22,67.34 86.2,67.32 86.2,67.13 86.2,66.74 U42.AB2 ; P5.17 10.38,162.45 10.61,162.69 11.05,162.69 11.61,163.25 11.61,164.44 11.9,164.73 12.36,164.73 12.52,164.57 12.52,164.43 R11.1 12.88,164.35 12.88,164.65 12.98,164.74 14.58,164.74 J4.1
  L14-SIGNAL w0.089: J4.1 14.69,164.64 14.69,164.64 14.59,164.74 13.74,164.74 13.34,164.34 13.34,153.03 17.91,148.46 17.91,143.51 25.17,136.25 32.61,136.25 40.49,128.36 40.49,115.92 55.72,100.69 64.23,100.69 67.94,96.97 67.94,87.5 77.62,77.83 79.41,77.83 79.72,78.14 79.72,78.44 v1(79.42,78.74)
H_MLBP_CLKP: length 154.3
  TOP w0.099: 80.34,77.44 80.34,77.48 79.97,77.86 79.97,78.46 v1(80.24,78.74) ; 80.34,77.44 80.01,77.11 80.01,76.7 80.25,76.47 81.14,76.47 86.62,70.99 86.62,68.33 86.49,68.2 86.49,67.26 U42.AB1 ; 80.34,77.44 R167.1 ; J4.2 15.74,166.12 14.63,165.01 13.04,165.01 12.88,165.18 12.88,165.34 R10.1 12.62,165.48 12.55,165.4 12.55,165.1 12.45,165 11.79,165 11.34,164.55 11.34,163.36 10.94,162.95 P5.19
  L14-SIGNAL w0.089: J4.2 14.61,164.97 13.65,164.97 13.11,164.43 13.11,152.94 17.68,148.37 17.68,143.42 25.08,136.02 32.51,136.02 40.26,128.27 40.26,115.82 55.63,100.46 64.14,100.46 67.72,96.88 67.72,87.41 77.53,77.6 79.5,77.6 79.95,78.04 79.95,78.44 v1(80.24,78.74)
H_MLBP_DAT: length 131.2
  TOP w0.132: v1(5,159.45) P5.10
  L14-SIGNAL w0.109: v1(5,159.45) 3.81,158.26 3.81,156.34 4.83,155.32 7.37,155.32 14.86,147.83 14.86,137.16 18.41,133.6 29.84,133.6 30.86,132.59 32,132.59 34.04,130.56 34.04,129.67 34.42,129.29 36.7,129.29 37.59,128.4 37.59,118.87 38.35,118.11 38.35,93.73 47.75,84.33 57.78,84.33 59.69,82.42 64.9,82.42 68.45,78.87 v1(68.45,77.09)
  BOTTOM w0.132: R190.2 v1(68.45,77.09)
H_MLBP_DN: length 144.1
  TOP w0.099: J5.1 17.12,159.67 13.11,159.67 12.88,159.44 12.88,159.27 R17.1 12.47,159.4 10.85,159.4 10.79,159.45 P5.9 ; v1(81.2,79.82) 81.48,79.54 81.48,78.73 R166.2 81.52,77.94 81.52,76.97 87,71.49 87,67.01 87.01,67 87.01,66.73 U42.AA2
  L14-SIGNAL w0.089: v1(81.2,79.82) 81.53,80.16 81.53,80.64 80.14,82.04 77.02,82.04 70.64,88.42 70.64,96.62 64.14,103.12 56.7,103.12 42.8,117.02 42.8,129.16 34.26,137.69 27.66,137.69 22.1,143.26 22.1,146.43 20.7,147.83 20.7,149.48 19.94,150.24 19.94,159.55 19.85,159.64 19.43,159.64 J5.1
H_MLBP_DP: length 144.1
  TOP w0.099: U42.AA1 87.27,67.28 87.27,71.6 81.79,77.09 81.79,78.03 R166.1 82.03,78.36 81.79,78.6 81.79,78.69 81.74,78.73 81.74,79.54 v1(82.02,79.82) ; P5.11 10.38,159.95 10.61,159.72 10.9,159.72 10.96,159.66 12.42,159.66 12.55,159.79 12.55,160.32 12.62,160.4 R14.1 12.88,160.26 12.88,160.08 13.02,159.93 17.19,159.93 J5.2
  L14-SIGNAL w0.089: J5.2 19.46,159.87 19.94,159.87 20.17,159.64 20.17,150.34 20.93,149.57 20.93,147.92 22.33,146.53 22.33,143.35 27.76,137.92 34.36,137.92 43.03,129.25 43.03,117.12 56.79,103.35 64.23,103.35 70.87,96.72 70.87,88.52 77.11,82.27 80.23,82.27 81.76,80.74 81.76,80.08 81.79,80.06 81.79,80.05 v1(82.02,79.82)
H_MLBP_SIG: length 126.1
  TOP w0.132: v1(5,157.95) P5.6
  L14-SIGNAL w0.109: v1(68.45,80.14) 65.53,83.06 59.82,83.06 58.17,84.71 48.01,84.71 38.86,93.85 38.86,127.89 35.94,130.81 34.67,130.81 30.73,134.75 18.03,134.75 15.24,137.54 15.24,148.08 7.49,155.83 4.83,155.83 4.32,156.34 4.32,157.27 v1(5,157.95)
  BOTTOM w0.132: v1(68.45,80.14) R540.2
H_MLBP_SIGN: length 138.9
  TOP w0.099: P5.1 11.13,156.45 11.58,156 11.58,154.64 12.09,154.13 12.66,154.13 R25.1 12.88,154.19 12.88,154.36 13.07,154.55 14.61,154.55 J6.1 ; U42.AC2 85.4,66.74 85.4,67.5 85.6,67.69 85.6,70.36 80.77,75.18 79.25,75.18 77.97,76.47 77.97,77.94 R165.2 77.92,78.73 77.92,79.54 v1(77.64,79.82)
  L14-SIGNAL w0.089: v1(77.64,79.82) 77.66,79.82 77.98,80.14 77.98,80.39 77.34,81.03 76.26,81.03 68.98,88.31 68.98,97.01 64.52,101.47 57.02,101.47 41.55,116.94 41.55,128.18 32.93,136.8 25.69,136.8 18.67,143.82 18.67,153.35 17.33,154.69 17.02,154.69 J6.1
H_MLBP_SIGP: length 138.9
  TOP w0.099: v1(78.47,79.82) 78.19,79.54 78.19,78.73 R165.1 78.23,78.03 78.23,76.58 79.36,75.45 80.88,75.45 85.86,70.47 85.86,67.58 85.78,67.5 U42.AC1 ; P5.3 10.38,156.95 10.61,156.72 11.24,156.72 11.85,156.11 11.85,154.75 12.15,154.45 12.39,154.45 12.55,154.61 12.55,155.24 12.62,155.32 R22.1 12.88,155.18 12.88,155 13.06,154.82 14.61,154.82 J6.2
  L14-SIGNAL w0.089: v1(78.47,79.82) 78.21,80.08 78.21,80.49 77.44,81.25 76.35,81.25 69.21,88.4 69.21,97.11 64.61,101.7 57.12,101.7 41.78,117.04 41.78,128.27 33.02,137.03 25.78,137.03 18.9,143.92 18.9,153.44 17.42,154.91 16.79,154.91 J6.2
H_MMC1_CLK: length 115.4
  L12-SIGNAL w0.089: v1(88.39,75.69) 88.39,84.29 88.4,84.29 88.4,91.45 88.72,91.77 88.72,100.28 90.81,102.37 90.81,103.51 91.19,103.89 91.19,104.14 91.93,104.89 91.93,105.39 93.34,106.81 93.34,108.84 96.39,111.89 96.39,114.17 98.97,116.75 98.97,117.77 109.47,128.27 109.47,145.92 117.22,153.67 123.7,153.67 125.35,155.32 126.11,155.32 128.35,153.08 128.48,153.08 128.86,153.46 128.99,153.46 129.18,153.27 129.18,153.15 128.79,152.76 128.79,152.64 128.98,152.45 129.11,152.45 129.49,152.83 129.62,152.83 129.8,152.64 129.8,152.52 129.42,152.14 129.42,152.01 129.79,151.64 131.95,151.64 133.35,153.03 v1(135.89,153.03)
  BOTTOM w0.132: R345.1 v1(135.89,153.03) ; R525.2 v1(88.39,75.69)
H_MMC1_CMD: length 120.3
  TOP w0.132: U42.W5 v1(88.58,64.36)
  L12-SIGNAL w0.089: v1(88.58,64.36) 88.99,64.77 89.53,64.77 89.79,65.02 89.79,68.33 89.28,68.83 89.28,86.49 89.87,87.07 89.87,96.34 90.72,97.2 90.72,99.99 93.22,102.49 93.22,103.25 94.11,104.14 94.11,108.58 97.16,111.63 97.16,113.16 101.6,117.6 101.6,119.38 110.24,128.02 110.24,145.67 117.47,152.91 127.64,152.91 129.29,151.26 133.1,151.26 v1(133.99,152.15)
  BOTTOM w0.132: R346.1 v1(133.99,152.15)
H_MMC1_D0: length 123.6
  TOP w0.132: U42.V5 v1(89.38,64.36)
  L12-SIGNAL w0.089: v1(137.67,153.03) 135.51,150.88 128.65,150.88 127,152.53 117.6,152.53 110.62,145.54 110.62,127.87 101.96,119.21 101.96,114.78 94.49,107.31 94.49,104.01 93.6,103.12 93.6,102.36 91.69,100.46 91.69,94.23 90.68,93.22 90.68,89.5 90.3,89.11 90.3,80.59 90.14,80.43 90.14,68.87 90.57,68.43 90.57,65 90.33,64.77 90.04,64.77 89.63,64.36 v1(89.38,64.36)
  BOTTOM w0.132: R344.1 v1(137.67,153.03)
H_MMC1_D1: length 130.9
  TOP w0.132: U42.Y4 v1(87.78,65.16)
  L12-SIGNAL w0.089: v1(140.46,153.03) R343.1 135.97,156.64 118.54,156.64 108.33,146.43 108.33,128.65 95.25,115.57 95.25,112.14 92.33,109.22 92.33,108.08 89.15,104.9 89.15,104.52 88.39,103.76 88.39,102.49 85.95,100.04 85.95,95.92 86.36,95.5 86.36,91.19 87.11,90.43 87.11,86.58 87.05,86.51 87.05,73.96 86.74,73.66 86.74,66.93 87.38,66.29 87.38,65.57 v1(87.78,65.16)
  BOTTOM w0.132: R343.1 v1(140.46,153.03)
H_MMC1_D2: length 119.6
  TOP w0.132: U42.Y5 v1(87.78,64.36)
  L12-SIGNAL w0.089: v1(87.78,64.36) 88.17,64.75 88.17,67.73 87.38,68.52 87.38,72.77 87.62,73.02 87.62,88.39 88.14,88.91 88.14,90.67 87.72,91.09 87.72,100.3 89.79,102.36 89.79,102.91 90.82,103.94 90.82,105.05 92.08,106.3 92.46,106.3 92.96,106.81 92.96,108.97 96.01,112.01 96.01,115.32 109.09,128.4 109.09,146.05 119,155.96 123.42,155.96 123.51,155.87 123.51,154.39 123.6,154.31 123.87,154.31 123.96,154.39 123.96,155.87 124.05,155.96 126.49,155.96 v1(127.76,154.69)
  BOTTOM w0.132: R339.1 v1(127.76,154.69)
H_MMC1_D3: length 125.9
  TOP w0.132: U42.Y3 v1(87.78,65.97)
  L12-SIGNAL w0.089: v1(87.78,65.97) 87.78,66.22 87,67 87,73.15 87.34,73.5 87.34,95.67 86.86,96.15 86.86,100.2 88.77,102.11 88.77,103.38 89.53,104.14 89.53,104.65 91.44,106.55 92.2,106.55 92.71,107.06 92.71,109.09 95.63,112.01 95.63,115.44 108.71,128.52 108.71,146.18 118.87,156.34 129.16,156.34 130.15,155.34 130.15,154.83 130.43,154.56 130.43,154.36 130.52,154.27 131.61,154.27 131.7,154.18 131.7,153.91 131.61,153.82 130.52,153.82 130.43,153.73 130.43,153.47 130.52,153.38 131.61,153.38 131.7,153.29 131.7,153.02 131.61,152.93 130.52,152.93 130.43,152.84 v1(130.43,152.15)
  BOTTOM w0.132: R347.1 v1(130.43,152.15)
H_MMC1_SDCD: length 137
  TOP w0.132: v1(136.02,165.1) R9.2 ; U42.W4 v1(88.58,65.16)
  L3-SIGNAL w0.109: v1(136.02,165.1) 129.84,158.93 129.84,158.45 129.6,158.2 129,158.2 v1(125.61,154.81)
  L12-SIGNAL w0.089: v1(125.61,154.81) 124.09,153.29 117.35,153.29 109.86,145.8 109.86,128.14 100.58,118.87 100.58,117.48 96.77,113.67 96.77,111.76 93.73,108.71 93.73,104.27 92.84,103.38 92.84,102.74 90.3,100.2 89.53,100.2 88.92,99.6 88.92,89.98 88.77,89.82 88.77,89.5 88.92,89.34 88.92,68.17 88.97,68.13 88.97,65.55 v1(88.58,65.16)
  BOTTOM w0.132: v1(136.02,165.1) 137.41,165.1 142.67,170.36 P14.9 ; U100.5 v1(125.61,154.81)
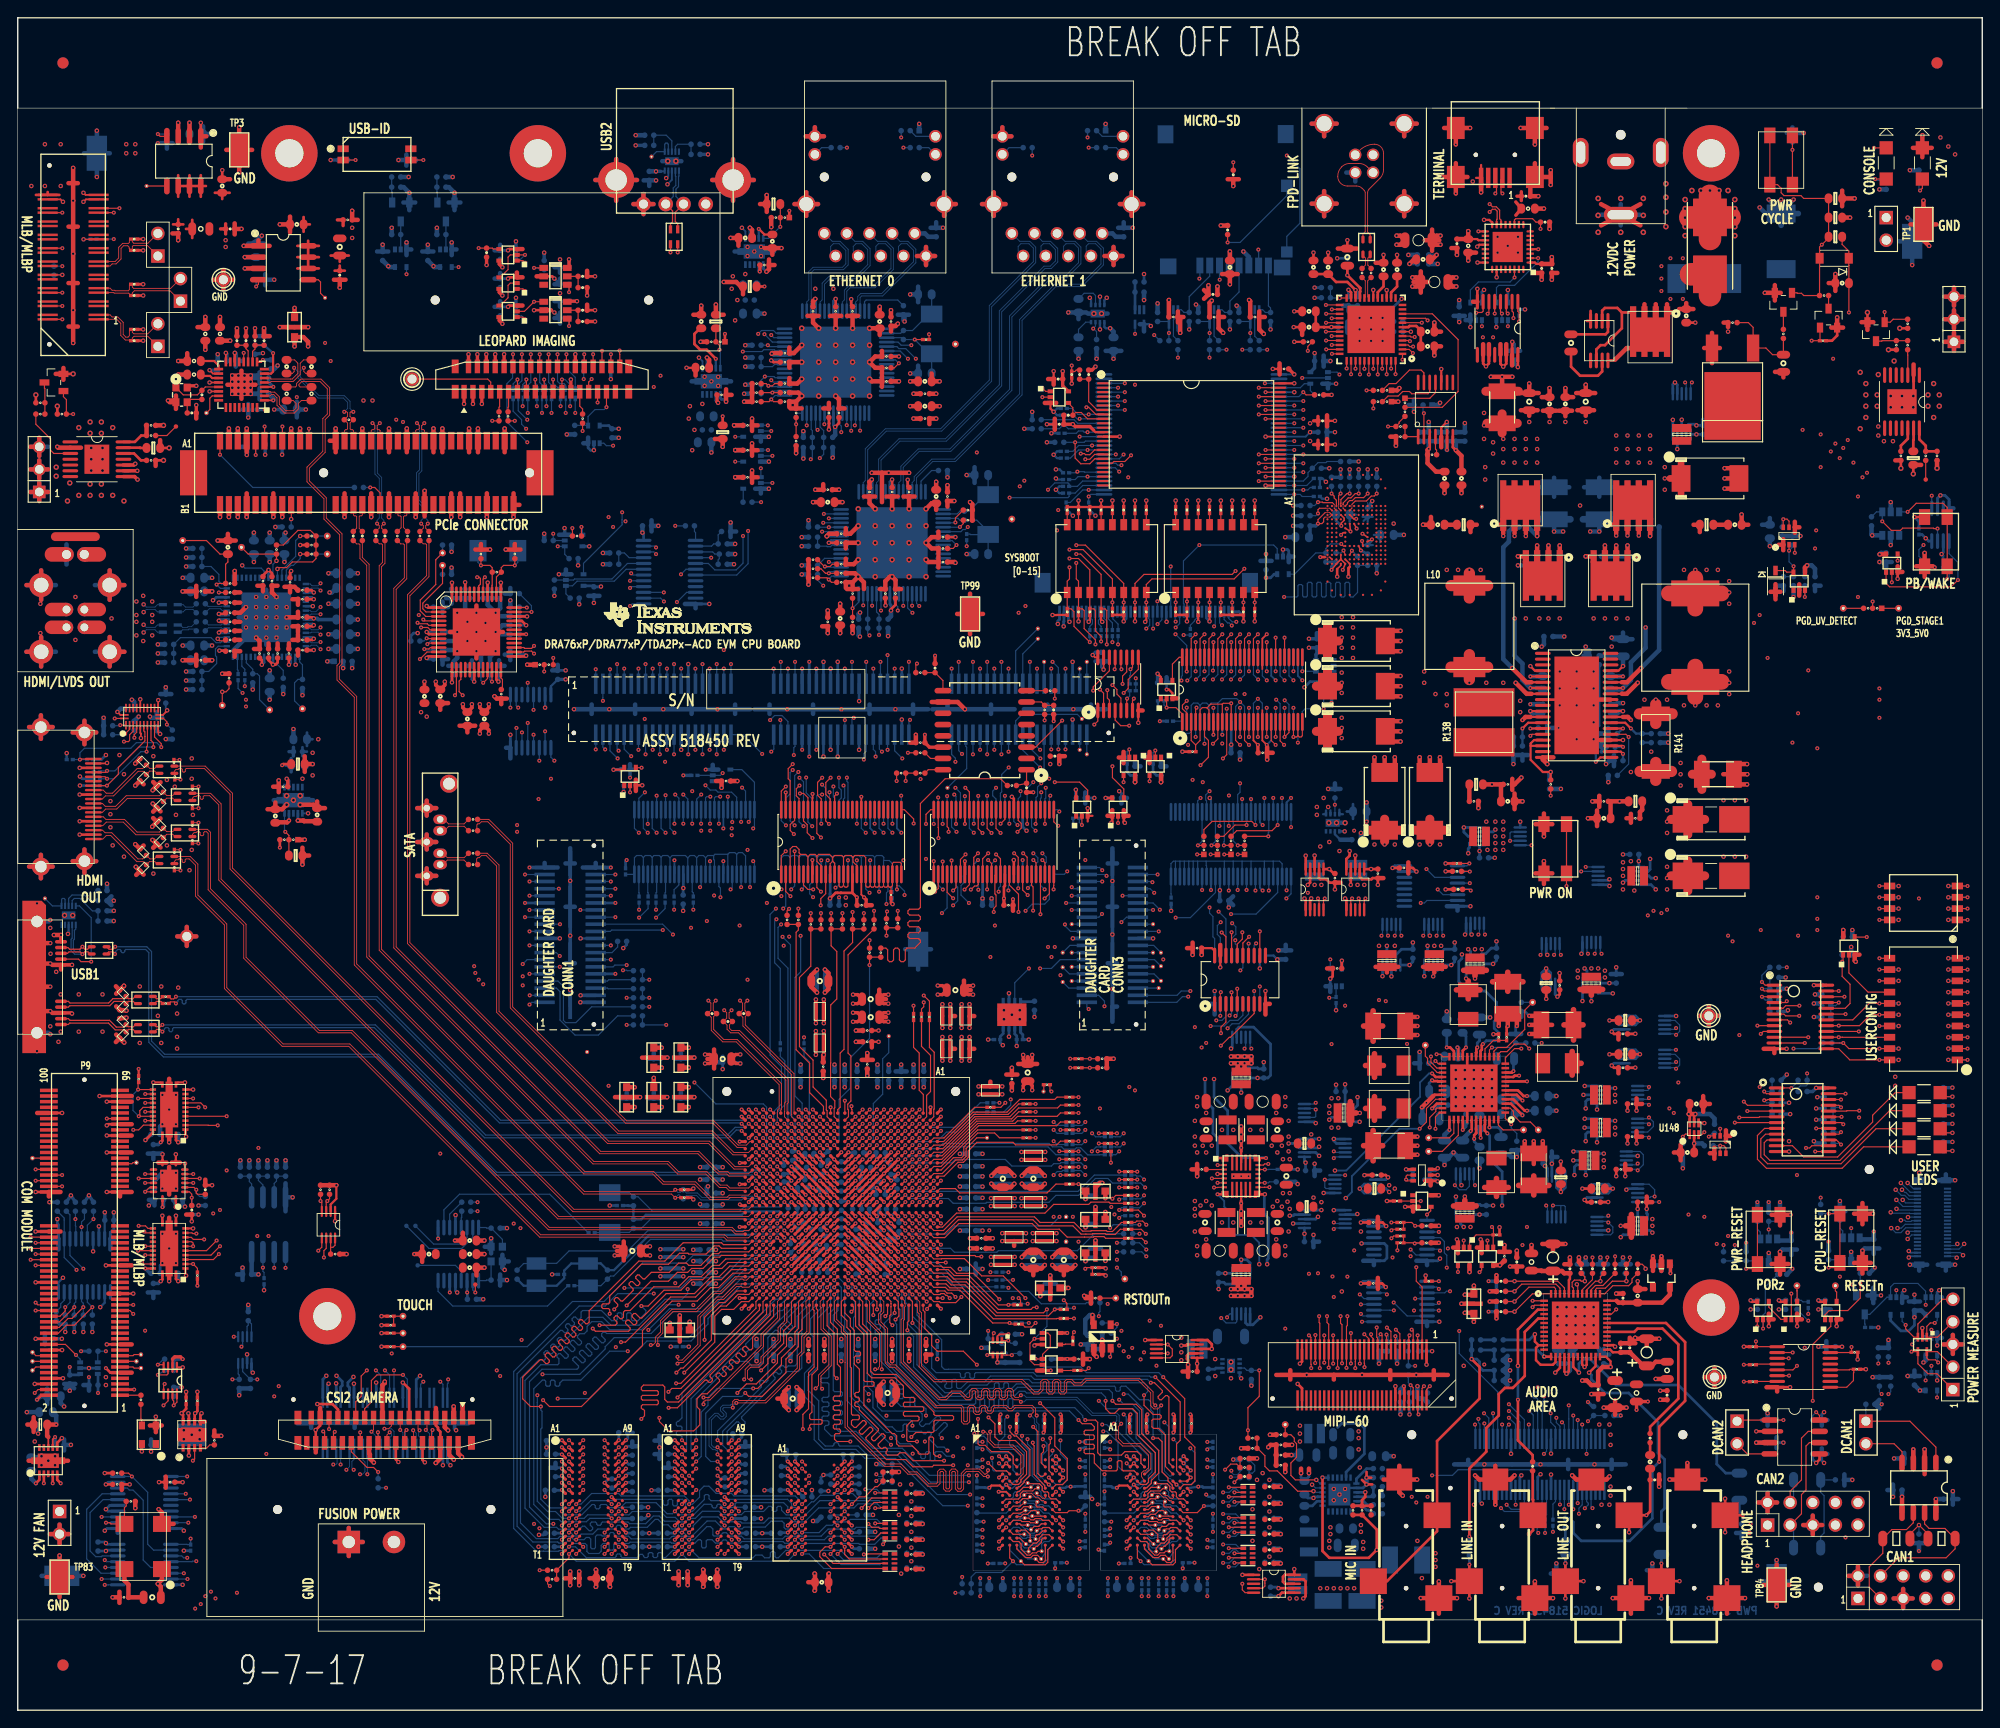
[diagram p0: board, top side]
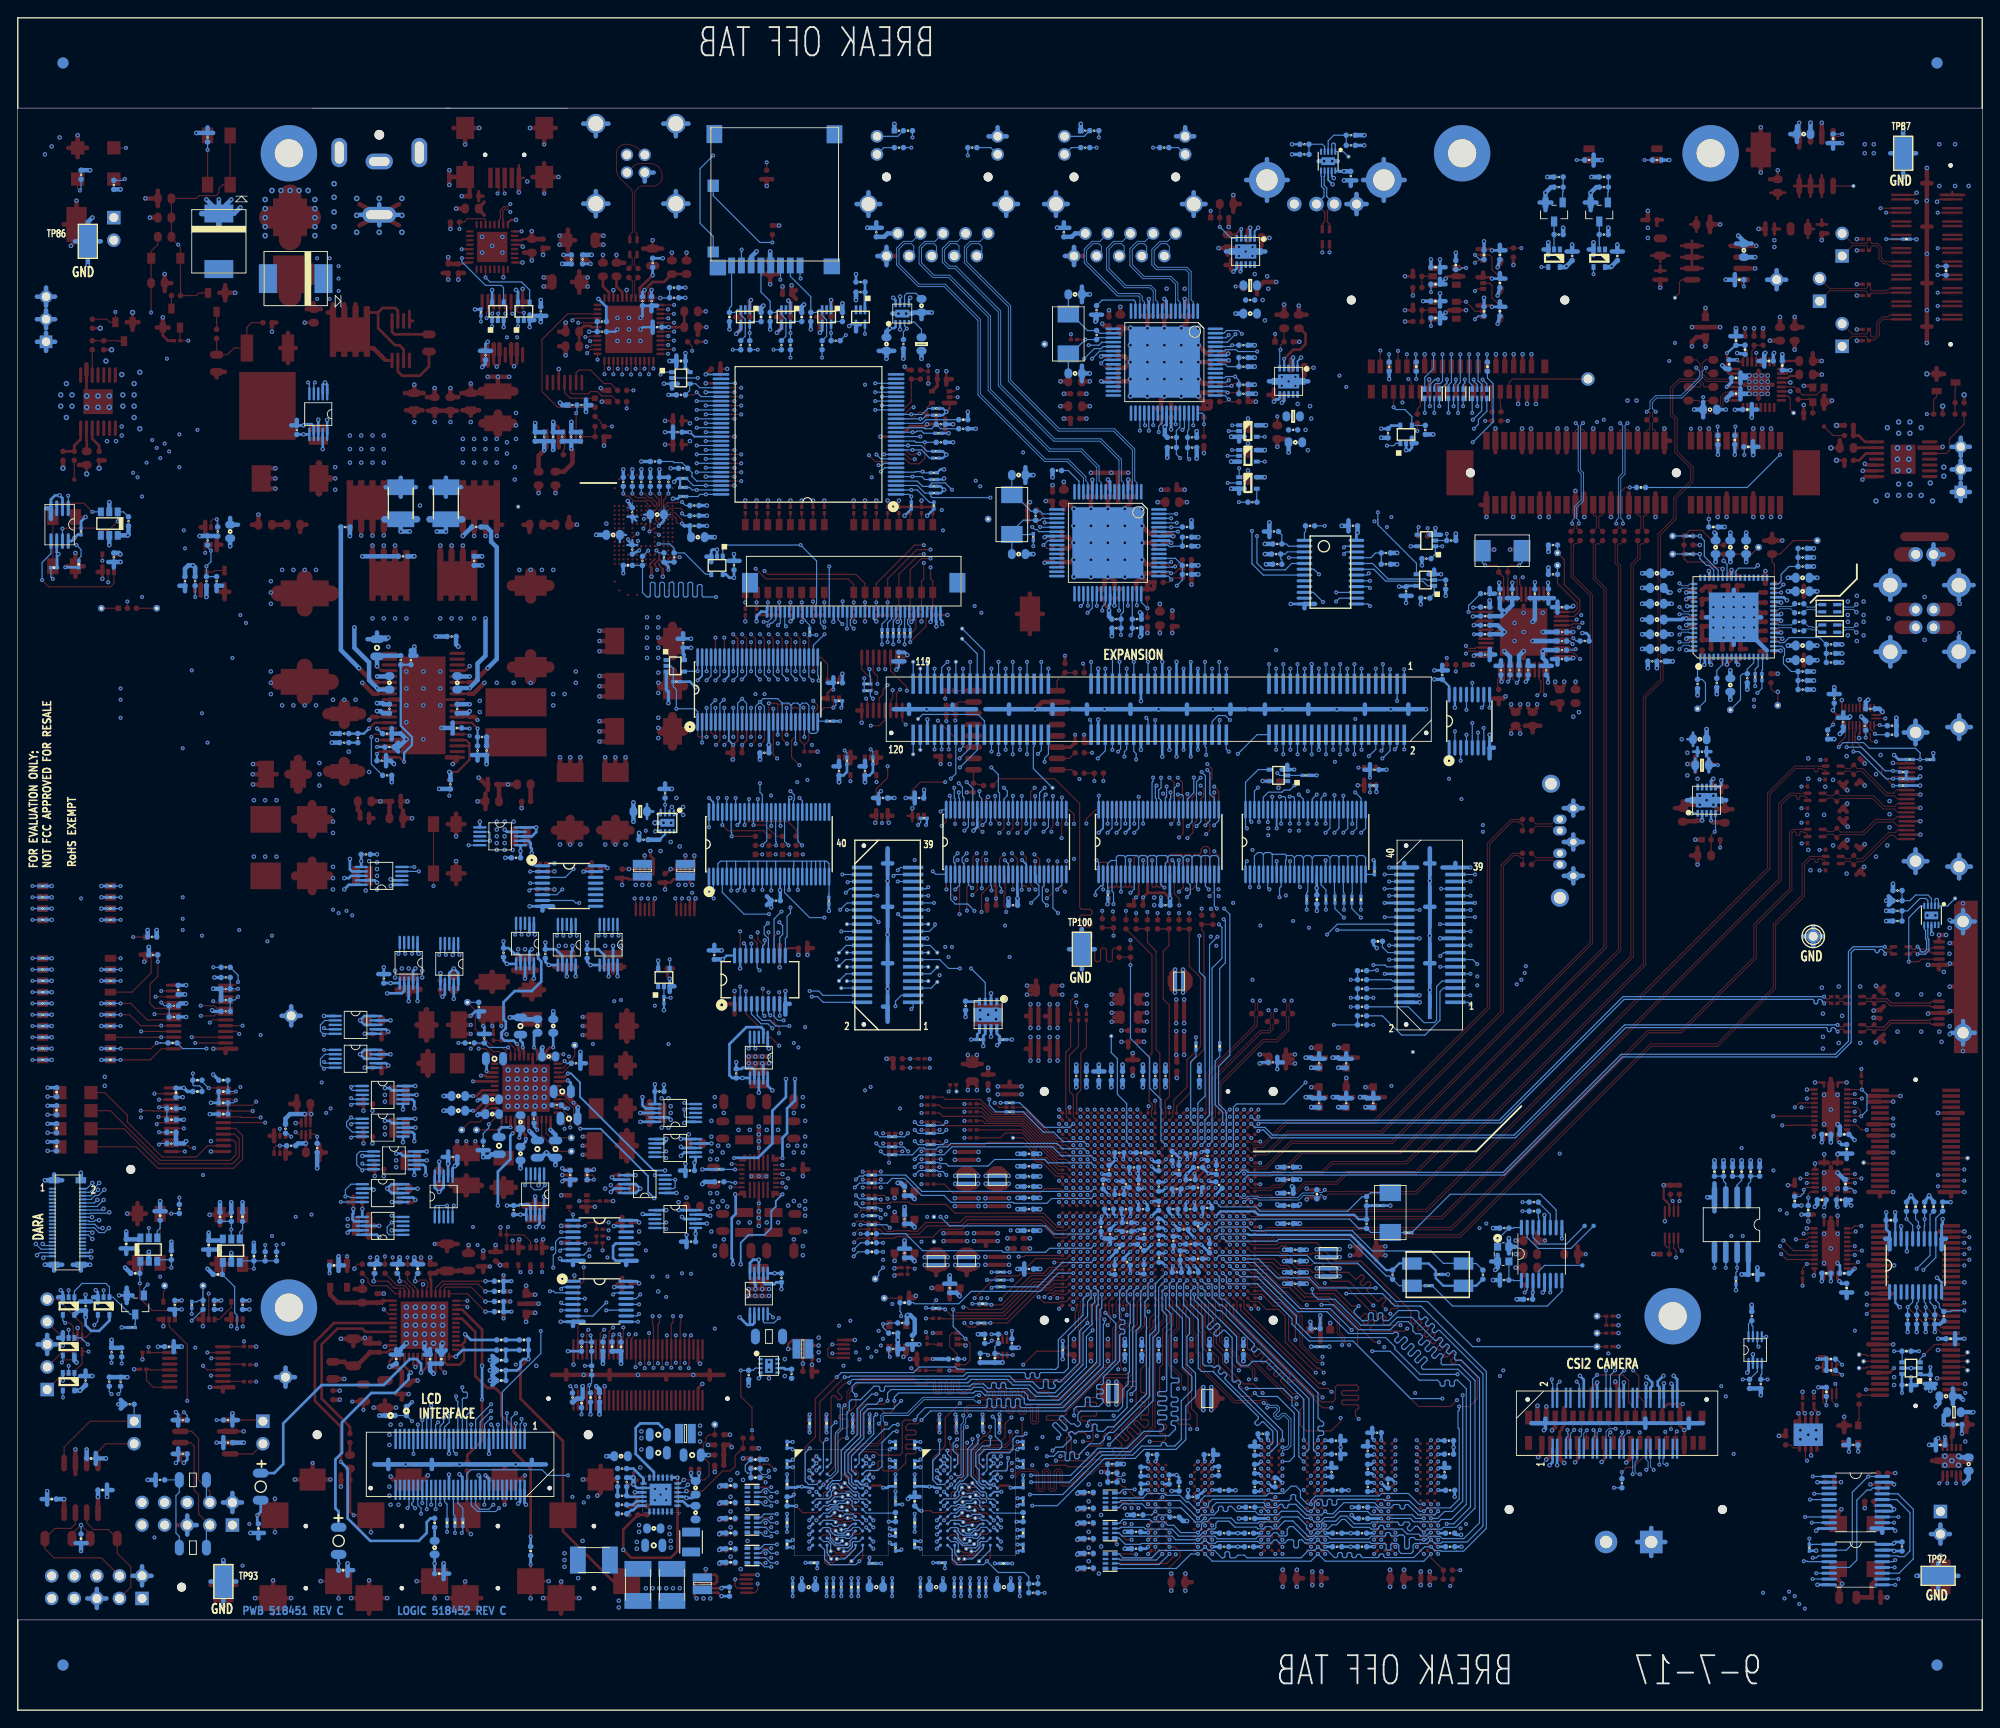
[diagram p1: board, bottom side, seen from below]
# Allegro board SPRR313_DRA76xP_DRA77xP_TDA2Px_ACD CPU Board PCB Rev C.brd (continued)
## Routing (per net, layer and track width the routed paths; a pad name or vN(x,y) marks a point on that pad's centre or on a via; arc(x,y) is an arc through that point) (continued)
H_MMC3_CLK: length 54.8
  L3-SIGNAL w0.109: v1(121.89,89.56) 121.31,89.56 121.15,89.72 121.15,90.26 120.99,90.42 120.77,90.42 120.61,90.26 120.61,89.77 120.45,89.62 115.99,89.62 115.47,90.15 114.91,90.15 114.16,89.39 104.89,89.39 104.76,89.26 86.09,89.26 85.8,88.97 v1(85.29,88.97)
  BOTTOM w0.132: v1(85.29,88.97) 85.09,88.77 85.09,84.07 85.72,83.44 R527.2 ; v1(121.89,89.56) 121.54,89.2 EXP_P3.25
H_MMC3_CMD: length 66.2
  TOP w0.132: U42.AC7 v1(85.38,62.76)
  L3-SIGNAL w0.109: v1(124.08,88.65) 123.44,88.01 122.94,88.01 122.17,87.24 115.69,87.24 115.17,86.72 97.3,86.72 96.67,87.35 89.25,87.35 88.27,86.36 86.49,86.36 86.12,86 v1(86.11,86)
  L14-SIGNAL w0.109: v1(86.11,86) 86.61,85.49 86.61,67.82 85.78,66.98 85.78,63.16 v1(85.38,62.76)
  BOTTOM w0.132: v1(124.08,88.65) 124.64,89.2 EXP_P3.26
H_MMC3_D0: length 69.9
  TOP w0.132: U42.Y6 v1(87.78,63.56)
  L3-SIGNAL w0.109: v1(127.64,90.02) 124.56,90.02 122.02,87.48 115.42,87.48 115.19,87.25 98.42,87.25 98.09,87.58 89.11,87.58 88.14,86.61 86.36,86.61 v1(85.98,87)
  BOTTOM w0.132: EXP_P3.28 v1(127.64,90.02) ; v1(85.98,87) 86.87,86.11 86.87,66.93 87.38,66.41 87.38,63.96 v1(87.78,63.56)
H_MMC3_D1: length 70
  TOP w0.132: U42.W6 v1(88.58,63.56)
  L3-SIGNAL w0.109: v1(88.01,87.11) 88.73,87.82 98.36,87.82 98.7,87.49 114.92,87.49 115.14,87.71 121.88,87.71 124.79,90.63 127.81,90.63 v1(128.4,90.04)
  BOTTOM w0.132: EXP_P3.30 127.64,90.81 v1(128.4,90.04) ; v1(88.01,87.11) 88.01,83.06 87.38,82.42 87.38,69.09 88.18,68.28 88.18,63.96 v1(88.58,63.56)
H_MMC3_D2: length 66.4
  TOP w0.132: U42.AC6 v1(85.38,63.56)
  L3-SIGNAL w0.109: v1(118.49,90.02) 117.75,90.02 116.97,90.81 107.82,90.81 107.43,90.41 106.44,90.41 105.92,90.93 102.23,90.93 100.97,92.2 99.44,92.2 99.17,91.93 98.67,91.93 98.13,92.47 93.87,92.47 93.24,91.84 91.2,91.84 90.68,91.31 90.3,91.31 89.41,90.42 88.77,90.42 88.01,89.66 85.72,89.66 85.23,90.15 v1(85.23,90.17)
  BOTTOM w0.132: EXP_P3.27 v1(118.49,90.02) ; v1(85.38,63.56) 84.98,63.96 84.98,67.2 85.05,67.27 85.05,67.39 85.85,68.2 85.85,72.39 84.58,73.66 84.58,89.52 v1(85.23,90.17)
H_MMC3_D3: length 65.5
  TOP w0.132: U42.AC4 v1(85.38,65.16)
  L3-SIGNAL w0.109: v1(84.22,90.81) 85.67,90.81 85.67,90.81 89.32,90.81 90.19,91.68 90.53,91.68 90.93,92.08 92.46,92.08 93.26,92.88 114.13,92.88 115.19,91.82 116.84,91.82 v1(117.86,90.81)
  L12-SIGNAL w0.089: v1(85.38,65.16) 84.98,65.56 84.98,67.93 84.71,68.2 84.2,68.2 83.22,69.18 83.22,72.05 84.22,73.04 v1(84.22,90.81)
  BOTTOM w0.132: EXP_P3.29 v1(117.86,90.81)
H_MMC3_D4: length 68
  TOP w0.132: U42.AA6 v1(86.98,63.56)
  L3-SIGNAL w0.109: v1(124.21,91.62) 123.92,91.33 123.92,90.9 122.18,89.16 121.27,89.16 121.15,89.28 115.44,89.28 115.24,89.08 105.08,89.08 104.95,88.95 86.37,88.95 v1(85.81,88.39)
  BOTTOM w0.132: EXP_P3.32 v1(124.21,91.62) ; v1(85.81,88.39) 85.47,88.05 85.47,84.58 86.58,83.47 86.58,63.96 v1(86.98,63.56)
H_MMC3_D5: length 69
  TOP w0.132: U42.AB5 v1(86.18,64.36)
  L3-SIGNAL w0.109: v1(86.72,87.01) 86.76,87.01 87.8,88.06 98.63,88.06 98.93,87.76 114.68,87.76 114.87,87.95 121.73,87.95 124.71,90.93 125.86,90.93 126.87,91.95 v1(127.76,91.95)
  L14-SIGNAL w0.109: v1(86.72,87.01) 87.01,86.73 87.01,66.81 86.58,66.39 86.58,64.77 v1(86.18,64.36)
  BOTTOM w0.132: EXP_P3.34 127.3,92.41 v1(127.76,91.95)
H_MMC4_CLK: length 116
  L10-SIGNAL w0.089: v1(111.38,47.51) 111.38,46.19 112.15,45.42 112.15,39.63 110.24,37.72 96.01,37.72 95.89,37.85 91.06,37.85 90.93,37.72 81.03,37.72 80.77,37.47 73.66,37.47 72.9,38.23 65.79,38.23 63.88,40.13 43.05,40.13 42.42,40.77 41.66,40.77 41.33,40.44 25.05,40.44 24.85,40.64 19.94,40.64 19.72,40.42 13.67,40.42 13.64,40.39 v1(9.91,40.39)
  BOTTOM w0.132: R624.1 111.25,47.62 111.36,47.51 v1(111.38,47.51) ; U132.4 8.99,40.36 R634.2 v1(9.91,40.39)
H_MMC4_CMD: length 121.3
  TOP w0.132: U42.E23 v1(100.59,49.16)
  L10-SIGNAL w0.089: v1(100.59,49.16) 100.2,48.77 100.2,48.2 100.42,47.97 105.25,47.97 107.19,46.04 107.19,43.31 104.78,40.89 78.99,40.89 77.6,42.29 69.85,42.29 68.45,43.69 65.57,43.69 65.57,43.69 65.24,43.69 65.24,43.69 49.15,43.69 43.56,49.28 28.7,49.28 27.18,50.8 20.83,50.8 20.19,51.44 18.67,51.44 17.4,52.7 15.88,52.7 15.24,53.34 11.05,53.34 9.14,55.24 v1(8.51,55.24)
  BOTTOM w0.132: U128.16 7.82,54.55 v1(8.51,55.24) R587.2
H_MMC4_DAT0: length 122.9
  TOP w0.132: U42.D22 v1(101.39,49.96)
  L10-SIGNAL w0.089: v1(7.17,54.36) 8.82,52.7 10.16,52.7 13.56,49.31 14.49,49.31 14.49,49.31 26,49.31 26.8,48.51 43.18,48.51 48.9,42.8 63.63,42.8 64.52,41.91 69.09,41.91 69.47,41.53 76.07,41.53 77.34,40.26 105.28,40.26 107.95,42.93 107.95,46.1 104.5,49.55 101.8,49.55 v1(101.39,49.96)
  BOTTOM w0.132: U128.15 v1(7.17,54.36) 7.17,54.92 7.49,55.24 R588.2
H_MMC4_DAT1: length 124
  TOP w0.132: U42.E22 v1(100.59,49.96)
  L10-SIGNAL w0.089: v1(100.59,49.96) 100.97,49.57 100.97,48.9 101.11,48.77 104.9,48.77 107.57,46.1 107.57,43.05 105.03,40.51 77.72,40.51 76.33,41.91 69.72,41.91 69.34,42.29 64.64,42.29 63.75,43.18 49.15,43.18 43.43,48.9 27.81,48.9 26.29,50.42 20.7,50.42 20.07,51.05 16.89,51.05 14.86,53.09 9.27,53.09 7.51,54.85 6.88,54.85 v1(6.48,55.24)
  BOTTOM w0.132: R589.2 v1(6.48,55.24) 6.48,54.48 6.52,54.44 U128.14
H_MMC4_DAT2: length 133.1
  TOP w0.132: U42.F20 v1(99.79,51.56)
  L10-SIGNAL w0.089: v1(7.37,49.66) 8.13,48.9 14.48,48.9 15.62,47.75 19.05,47.75 19.56,48.26 42.93,48.26 48.77,42.42 63.37,42.42 65.91,39.88 70.99,39.88 71.37,40.26 76.58,40.26 76.96,39.88 103.18,39.88 103.21,39.91 103.55,39.91 103.58,39.88 105.54,39.88 108.26,42.6 108.26,47.55 v1(109.09,48.39)
  L12-SIGNAL w0.089: v1(99.79,51.56) 100.2,51.15 100.2,49.79 100.44,49.55 102.85,49.55 104.01,48.39 v1(109.09,48.39)
  BOTTOM w0.132: R158.2 v1(109.09,48.39) ; v1(7.37,49.66) 5.87,51.16 U128.13 5.87,55.73 R590.2
H_MMC4_DAT3: length 133.1
  TOP w0.132: U42.C22 v1(102.18,49.96)
  L10-SIGNAL w0.089: v1(102.18,49.96) 103.31,49.96 104.1,50.75 106.48,50.75 108.2,49.02 109.09,49.02 109.34,49.27 ; 109.34,49.27 v1(109.35,49.27) ; 109.34,49.27 109.6,49.01 109.6,43.73 108.71,42.83 108.71,42.41 105.66,39.37 104.14,39.37 103.5,38.73 74.75,38.73 74.5,38.48 73.84,38.48 73.69,38.63 66.53,38.63 63.1,42.06 48.62,42.06 42.8,47.88 21.46,47.88 20.95,47.36 15.5,47.36 14.35,48.51 7.62,48.51 v1(6.6,49.53)
  BOTTOM w0.132: R157.2 109.35,49.28 v1(109.35,49.27) ; v1(6.6,49.53) 5.22,50.92 U128.12 5.22,55.14 5.21,55.14 5.21,55.36 R591.2
H_MMC_PWR_ON: length 130.3
  TOP w0.132: U42.B10 102.99,60.36 103.93,60.36 105.45,61.89 106.21,61.89 106.61,62.3 106.61,63.18 107.82,64.39 TP57.1
  L10-SIGNAL w0.089: v1(120.9,155.41) 120.9,153.42 120.52,153.03 120.52,150.37 118.36,148.21 114.81,148.21 114.46,147.86 114.46,145.88 114.43,145.85 114.43,136.53 116.84,134.11 v1(116.84,132.72) ; v1(121.67,67.69) 121.28,67.69 121.27,67.68 119.09,67.68 119.08,67.7 114.18,67.7 110.87,64.39 TP57.1
  L14-SIGNAL w0.109: v1(121.67,67.69) 121.67,75.95 125.86,80.14 125.86,92.71 129.57,96.42 129.57,109.82 129.79,110.04 129.79,119.76 128.65,120.9 128.65,126.11 123.06,131.7 117.86,131.7 v1(116.84,132.72)
  BOTTOM w0.132: R341.2 121.28,155.07 120.94,155.41 v1(120.9,155.41) 120.9,155.45 121.16,155.71 U96.3
H_NMIN: length 21.4
  TOP w0.132: R269.2 R266.1 120.14,49.78 v1(120.02,49.66) ; U42.D21 v1(101.39,50.76)
  L12-SIGNAL w0.089: v1(120.02,49.66) 109.09,49.66 108.58,50.16 105.54,50.16 105.35,49.97 103.95,49.97 103.57,50.35 101.8,50.35 v1(101.39,50.76)
H_PCIE_RXN0: length 99.1
  TOP w0.099: U42.AG11 82.16,58.74 80.07,58.74 79.74,59.07 78.98,59.07 77.47,60.58 74.3,60.58 73.15,61.72 64.77,61.72 40.9,85.59 40.9,128.63 41.27,129.01 R90.1
H_PCIE_RXN1: length 95.2
  TOP w0.099: R94.1 46.23,127.51 44.08,125.36 44.08,86.35 66.42,64.01 77.77,64.01 80.64,61.14 82.16,61.14 U42.AG8
H_PCIE_RXP0: length 99.1
  TOP w0.099: U42.AH12 81.67,58.47 79.96,58.47 79.63,58.8 78.87,58.8 77.36,60.31 74.18,60.31 73.04,61.46 64.66,61.46 40.63,85.48 40.63,128.74 41.01,129.12 41.01,131.1 40.91,131.2 40.63,131.2 R89.1
H_PCIE_RXP1: length 95.2
  TOP w0.099: U42.AH9 81.67,60.87 80.53,60.87 77.66,63.74 66.31,63.74 43.81,86.24 43.81,125.47 45.96,127.62 45.96,131.1 45.86,131.2 45.58,131.2 R93.1
H_PCIE_TXN0: length 101.6
  TOP w0.099: C84.1 38.73,129.66 39.5,128.9 39.5,84.84 63.74,60.59 71.49,60.59 72.64,59.44 76.2,59.44 77.92,57.71 79.76,57.71 79.99,57.94 82.16,57.94 U42.AG12
H_PCIE_TXN1: length 97
  TOP w0.099: U42.AG9 82.16,60.34 80.07,60.34 79.83,60.58 78.86,60.58 76.58,62.87 65.53,62.87 42.54,85.86 42.54,126.08 43.73,127.27 43.73,131.48 C86.1
H_PCIE_TXP0: length 101.6
  TOP w0.099: C82.1 38.1,131.19 38.37,131.19 38.47,131.09 38.47,129.55 39.23,128.79 39.23,84.73 63.63,60.33 71.38,60.33 72.53,59.17 76.09,59.17 77.81,57.44 79.87,57.44 80.1,57.67 81.68,57.67 81.78,57.57 U42.AH13
H_PCIE_TXP1: length 97
  TOP w0.099: C85.1 43.05,131.19 43.36,131.19 43.46,131.09 43.46,127.38 42.27,126.19 42.27,85.75 65.42,62.6 76.47,62.6 78.75,60.31 79.72,60.31 79.96,60.07 81.67,60.07 U42.AH10
H_PORZ: length 108.4
  TOP w0.132: TP71.1 200.03,47.18 200.04,47.16 U47.4 ; U42.C25 v1(102.19,47.56)
  L14-SIGNAL w0.109: v1(102.19,47.56) 105.86,47.56 106.55,46.86 114.43,46.86 114.57,47.01 119.4,47.01 119.42,47.03 126.07,47.03 126.24,46.86 135.26,46.86 136.19,47.79 149.06,47.79 149.61,47.24 153.55,47.24 153.62,47.18 159.07,47.18 159.64,46.61 161.93,46.61 162.31,46.23 163.45,46.23 164.21,45.47 168.91,45.47 170.43,46.99 179.07,46.99 179.58,47.5 180.85,47.5 181.48,48.13 181.48,48.89 182.75,50.16 192.66,50.16 195.07,47.75 TP71.1
  BOTTOM w0.132: R615.1 200.69,45.94 200.52,46.1 200.03,46.1 TP71.1
H_POWERHOLD_CLK: length 172.4
  TOP w0.132: R571.1 116.04,69.68 116.13,69.6 v1(116.21,69.6)
  L7-SIGNAL w0.089: v1(116.21,69.6) 116.21,72.14 118.62,74.55 124.97,74.55 129.54,79.12 129.54,89.15 130.18,89.79 130.18,91.69 131.57,93.09 140.21,93.09 143.76,96.65 145.92,96.65 147.32,95.25 158.62,95.25 159.1,94.77 163.93,94.77 170.43,88.27 202.95,88.27 205.49,90.81 213.23,90.81 v1(213.74,91.31)
  L10-SIGNAL w0.089: v1(215.18,136.61) 214.09,135.52 214.09,131.65 214.25,131.5 v1(214.25,131.06) 213.74,130.56 v1(213.74,91.31)
  BOTTOM w0.132: R443.1 214,129.54 213.74,129.79 213.74,130.56 v1(214.25,131.06) ; U113.1 v1(215.18,136.61)
H_RESETN: length 110.8
  TOP w0.132: U42.D24 v1(101.39,48.36) ; TP70.1 204.34,47.18 204.49,47.04 U48.4
  L14-SIGNAL w0.109: TP70.1 202.44,47.75 201.68,48.51 194.82,48.51 192.79,50.55 182.5,50.55 179.83,47.88 179.32,47.88 178.82,47.37 169.54,47.37 168.66,46.48 164.08,46.48 162.7,47.86 158.39,47.86 158.12,48.13 152.78,48.13 152.22,47.57 149.79,47.57 149.22,48.13 126.49,48.13 125.73,47.37 123.19,47.37 122.57,47.99 117.33,47.99 116.71,47.37 114.43,47.37 114.17,47.12 107.44,47.12 106.6,47.96 101.78,47.96 v1(101.39,48.36)
H_RGMII0_RXC: length 33.3
  TOP w0.132: U42.U4 v1(90.18,65.16)
  L5-SIGNAL w0.089: v1(90.18,65.16) 90.57,65.55 90.57,69.11 90.96,69.5 90.96,71.72 89.19,73.49 89.19,80.86 84.2,85.85 84.2,89.53 82.32,91.41 v1(82.32,92.58)
  BOTTOM w0.132: RU17.2 v1(82.32,92.58)
H_RGMII0_RXCTL: length 33.1
  TOP w0.132: U42.V4 v1(89.38,65.16)
  L5-SIGNAL w0.089: v1(89.38,65.16) 89.79,65.57 89.79,68.58 89.53,68.83 89.53,72.01 87.88,73.66 87.88,80.52 82.55,85.85 82.55,89.79 81.32,91.02 v1(81.32,92.58)
  BOTTOM w0.132: RU17.4 v1(81.32,92.58)
H_RGMII0_RXD0: length 30.6
  TOP w0.132: U42.W1 v1(88.58,67.57)
  L5-SIGNAL w0.089: v1(80.14,92.33) 80.14,86.11 87.25,78.99 87.25,72.26 88.58,70.93 v1(88.58,67.57)
  BOTTOM w0.132: v1(80.14,92.33) 80.32,92.51 RU17.6
H_RGMII0_RXD1: length 31.5
  TOP w0.132: U42.Y2 v1(87.78,66.77)
  L5-SIGNAL w0.089: v1(78.99,91.45) 78.99,83.44 86.61,75.82 86.61,67.93 v1(87.78,66.77)
  BOTTOM w0.132: RU17.9 78.82,92.66 78.99,92.48 v1(78.99,91.45)
H_RGMII0_RXD2: length 36.4
  TOP w0.132: U42.V3 v1(89.38,65.97)
  L5-SIGNAL w0.089: v1(77.82,95.5) 80.64,92.68 80.64,86.61 87.5,79.76 87.5,72.52 88.97,71.05 88.97,66.38 v1(89.38,65.97)
  BOTTOM w0.132: RU17.11 v1(77.82,95.5)
H_RGMII0_RXD3: length 39
  TOP w0.132: U42.W2 v1(88.58,66.77)
  L5-SIGNAL w0.089: v1(88.58,66.77) 88.19,67.15 88.19,68.65 87,69.85 87,78.74 81.64,84.1 81.46,84.1 80.97,83.61 80.78,83.61 80.65,83.74 80.65,83.92 81.14,84.41 81.14,84.59 81.01,84.72 80.83,84.72 80.34,84.24 80.15,84.24 80.02,84.37 80.02,84.55 80.51,85.04 80.51,85.22 80.38,85.35 80.2,85.35 79.71,84.86 79.52,84.86 79.39,85 79.39,85.18 79.88,85.67 79.88,91.82 79.12,92.58 v1(76.71,92.58)
  BOTTOM w0.132: RU17.13 76.82,92.7 v1(76.71,92.58)
H_RGMII0_TXC: length 2.5
  BOTTOM w0.132: R526.1 69.85,91.94 69.82,91.97 RU17.27
H_RGMII0_TXCTL: length 2.5
  BOTTOM w0.132: RU17.25 70.83,91.98 70.87,91.94 R524.1
H_RGMII0_TXD0: length 2.6
  BOTTOM w0.132: R529.1 75.95,91.94 75.82,92.07 RU17.15
H_RGMII0_TXD1: length 2.7
  BOTTOM w0.132: R530.1 73.79,92.3 74.32,92.83 RU17.18
H_RGMII0_TXD2: length 2.5
  BOTTOM w0.132: RU17.21 72.82,92 72.77,91.94 R531.1
H_RGMII0_TXD3: length 2.5
  BOTTOM w0.132: R532.1 71.75,91.94 71.82,92.01 RU17.23
H_RSTOUTN: length 549.8
  TOP w0.132: R267.2 TP82.1 ; v1(179.71,45.09) 179.18,44.56 U50.33 ; v1(25.4,152.68) U10.12 ; U38.13 166.45,73.8 166.73,74.08 167.42,74.08 168.28,74.93 169.42,74.93 v1(169.93,74.42) ; U20.3 114.43,108.33 v1(117.41,111.32) ; U42.D23 v1(101.39,49.16)
  L7-SIGNAL w0.089: v1(116.97,135) 116.08,134.11 116.08,123.95 115.7,123.57 115.7,122.56 117.09,121.16 117.09,111.63 v1(117.41,111.32)
  L10-SIGNAL w0.089: v1(149.22,79.25) 149.73,79.76 149.73,85.6 145.16,90.17 144.53,90.17 143.76,90.93 143.76,100.97 142.76,101.97 142.76,102.99 141.99,103.76 139.57,103.76 135.67,107.66 134.97,107.66 134.72,107.41 122.59,107.41 120.27,109.73 119,109.73 v1(117.41,111.32) ; v1(111.86,46.35) 112.65,45.57 112.65,45.09 113.67,44.07 114.55,44.07 114.94,43.69 114.94,38.73 114.05,37.85 112.9,37.85 111,35.94 95.83,35.94 95.83,35.95 91.83,35.95 90.3,34.42 85.85,34.42 84.71,33.27 64.9,33.27 64.01,32.38 59.05,32.38 53.47,26.8 43.94,26.8 41.66,24.51 36.58,24.51 32.51,20.45 19.18,20.45 17.88,21.74 v1(9.42,21.74) ; v1(186.69,70.61) 186.69,66.93 186.06,66.29 186.06,53.09 184.28,51.31 184.28,50.29 182.63,48.64 182.63,48.01 v1(179.71,45.09)
  L12-SIGNAL w0.089: v1(101.39,49.16) 101.8,48.75 102.89,48.75 103.63,48.01 107.06,48.01 108.2,46.86 110.62,46.86 111.12,46.35 v1(111.86,46.35) 112.62,47.12 117.09,47.12 117.6,46.61 118.49,46.61 119,46.1 121.03,46.1 121.28,46.35 TP82.1 ; v1(119.38,143.26) 119.38,142.11 117.73,140.46 117.73,135.76 v1(116.97,135) ; v1(66.93,142.24) 50.8,142.24 47.62,145.41 44.32,145.41 35.31,154.43 27.15,154.43 v1(25.4,152.68) 25.4,154.31 25.15,154.56 25.15,161.04 23.88,162.31 13.97,162.31 v1(10.79,165.48)
  L14-SIGNAL w0.109: TP82.1 125.6,46.35 125.87,46.08 149.84,46.08 150.13,46.37 154.32,46.37 154.69,46.74 158.75,46.74 159.26,46.23 161.04,46.23 162.05,45.21 163.45,45.21 165.1,43.56 169.16,43.56 172.09,46.48 178.31,46.48 v1(179.71,45.09) ; v1(186.69,70.61) 185.17,70.61 184.15,71.63 178.94,71.63 176.15,74.42 v1(169.93,74.42) 168.53,75.82 166.88,75.82 165.99,76.71 157.66,76.71 157.52,76.56 151.91,76.56 v1(149.22,79.25) ; v1(132.84,131.06) 129.03,134.87 129.03,134.89 128.92,135 v1(116.97,135) 113.92,135 109.22,139.7 84.33,139.7 83.06,140.97 75.31,140.97 74.04,142.24 v1(66.93,142.24)
  BOTTOM w0.132: U109.1 141.59,130.67 141.19,131.06 v1(132.84,131.06) 131.05,129.27 131.05,124.5 131.12,124.42 J17.29 ; v1(66.93,142.24) 66.17,142.24 65.89,142.52 U105.1 ; v1(10.79,165.48) R316.1 ; U104.14 v1(119.38,143.26) ; U124.13 v1(9.42,21.74)
H_RTCK: length 41.5
  TOP w0.132: J13.7 156.88,42.67 156.75,42.8 v1(156.71,42.8)
  L10-SIGNAL w0.089: v1(154.56,50.93) 154.56,49.02 155.96,47.62 155.96,44.83 156.71,44.08 v1(156.71,42.8)
  L14-SIGNAL w0.109: v1(154.56,50.93) 143.76,50.93 143.51,50.67 141.73,50.67 140.72,51.69 132.08,51.69 131.45,51.05 v1(126.87,51.05)
  BOTTOM w0.132: R599.1 126.36,51.56 v1(126.87,51.05)
H_SATA_RXN0: length 57
  TOP w0.099: C132.2 51.61,99.01 51.61,99.59 51.73,99.71 51.89,99.71 52.12,99.94 52.85,99.94 55.37,97.41 55.37,79 68.34,66.03 78.15,66.03 80.88,63.3 81.65,63.3 U42.AH6
H_SATA_RXP0: length 57
  TOP w0.099: U42.AG5 82.31,63.96 81.91,63.57 80.99,63.57 78.26,66.29 68.45,66.29 55.64,79.11 55.64,97.52 52.96,100.2 C130.2
H_SATA_TXN0: length 54.6
  TOP w0.099: C133.2 52.78,96.39 54.1,95.07 54.1,78.61 67.56,65.15 78.11,65.15 80.51,62.74 82.16,62.74 U42.AG6
H_SATA_TXP0: length 54.6
  TOP w0.099: C134.2 51.59,95.22 51.59,95.76 51.73,95.9 51.89,95.9 52.12,96.13 52.67,96.13 53.84,94.96 53.84,78.5 67.45,64.88 77.99,64.88 80.4,62.47 81.67,62.47 U42.AH7
H_SPI1_SCLK: length 23.2
  TOP w0.132: U54.2 114.3,38.86 113.79,39.37 113.79,41.27 v1(114.3,41.78) U51.2 ; U42.A24 104.49,48.76 105.07,48.17 106.64,48.17 110.11,44.7 115.32,44.7 v1(115.7,45.09)
  BOTTOM w0.132: v1(114.3,41.78) 115.7,43.18 v1(115.7,45.09)
H_SPI2_CS0N: length 52.7
  TOP w0.132: v1(114.55,45.32) 114.14,45.32 113.9,45.09 110.24,45.09 106.81,48.51 105.21,48.51 104.56,49.16 102.99,49.16 U42.B23
  L14-SIGNAL w0.109: v1(151,45.65) 150.61,45.65 150.38,45.42 123.02,45.42 122.84,45.24 122.15,45.24 121.95,45.44 119.8,45.44 118.94,44.58 115.3,44.58 v1(114.55,45.32)
  BOTTOM w0.132: v1(151,45.65) RU23.12
H_SPI2_MISO: length 59.4
  TOP w0.132: U42.B21 102.98,50.77 103.85,50.77 103.89,50.8 106.43,50.8 108.37,48.85 110.78,48.85 v1(113.28,46.35)
  L14-SIGNAL w0.109: v1(154.69,45.86) 151.88,45.86 151.64,46.1 150.37,46.1 149.99,45.72 123.19,45.72 122.72,46.19 119.3,46.19 118.97,46.52 116.49,46.52 116.08,46.1 114.05,46.1 113.79,46.35 v1(113.28,46.35)
  BOTTOM w0.132: RU23.7 156.2,44.35 v1(154.69,45.86)
H_SPI2_MOSI: length 61.8
  TOP w0.132: U42.E16 v1(100.59,54.76)
  L10-SIGNAL w0.089: v1(151.13,43.7) 150.24,44.59 v1(150.24,51.72)
  L14-SIGNAL w0.109: v1(100.59,54.76) 100.99,55.16 104.19,55.16 104.39,55.37 112.65,55.37 113.28,54.74 119.86,54.74 119.87,54.75 122.92,54.75 124.49,53.18 132.78,53.18 133.43,52.54 142.23,52.54 142.32,52.62 143.47,52.62 144.37,51.72 v1(150.24,51.72)
  BOTTOM w0.132: v1(151.13,43.7) RU23.9
H_SPI2_SCLK: length 41.6
  TOP w0.132: R255.1 v1(118.75,44.07)
  L14-SIGNAL w0.109: v1(118.75,44.07) 119.14,44.07 120.2,45.12 121.82,45.12 122.02,44.93 123.16,44.93 123.29,45.05 152.88,45.05 153.29,45.47 155.07,45.47 155.9,46.3 v1(157.1,46.3)
  BOTTOM w0.132: v1(157.1,46.3) RU23.4
H_SPI[1]_CS[0]N: length 63.8
  L5-SIGNAL w0.089: v1(122.53,45.7) 123.93,45.7 129.29,51.05 129.29,89.71 129.25,89.74 129.25,90.09 129.29,90.12 129.29,91.81 127.96,93.14 v1(127.56,93.14)
  L14-SIGNAL w0.109: v1(113.54,45.72) 116.84,45.72 117.09,45.47 117.98,45.47 118.36,45.85 121.99,45.85 122.14,45.7 v1(122.53,45.7)
  BOTTOM w0.132: R607.1 v1(113.54,45.72) ; EXP_P3.36 127.48,93.22 v1(127.56,93.14)
H_SPI[1]_CS[1]N: length 57.9
  TOP w0.132: U42.A21 103.6,51.16 103.61,51.15 107.6,51.15 107.73,51.02 v1(108.33,51.02)
  L5-SIGNAL w0.089: v1(121.92,94.49) 119.25,91.82 119.25,91.44 114.94,87.12 114.94,84.33 115.44,83.82 115.44,70.36 115.82,69.98 115.82,67.56 115.7,67.44 115.7,64.39 113.67,62.36 113.67,54.99 110.87,52.2 110.24,52.2 109.98,52.45 109.35,52.45 108.33,51.44 v1(108.33,51.02)
  BOTTOM w0.132: EXP_P3.39 121.62,94.79 v1(121.92,94.49)
H_SPI[1]_MISO: length 43.8
  L12-SIGNAL w0.089: v1(122.4,93.85) 122.4,91.85 126.11,88.14 126.11,80.9 128.14,78.87 128.14,58.55 v1(126.62,57.02)
  BOTTOM w0.132: EXP_P3.37 122.25,94.01 v1(122.4,93.85) ; R578.1 126.11,56.52 v1(126.62,57.02)
H_SPI[1]_MOSI: length 60.8
  L5-SIGNAL w0.089: v1(118.75,45.27) 119.06,44.96 123.95,44.96 129.67,50.67 129.67,89.28 130.18,89.79 130.18,91.97 v1(128.14,94.01)
  BOTTOM w0.132: v1(118.75,45.27) 118.69,45.21 R603.1 ; v1(128.14,94.01) EXP_P3.38
H_TCK: length 68
  TOP w0.132: U42.E20 v1(100.59,51.56) ; v1(157.23,49.83) 157.23,48.26 157.88,47.61 J13.3
  L14-SIGNAL w0.109: v1(157.23,49.83) 144.7,49.83 144.27,49.4 137.03,49.4 136.53,49.91 124.84,49.91 124.49,50.26 123.32,50.26 122.14,51.44 104.52,51.44 104.25,51.16 100.98,51.16 v1(100.59,51.56)
H_TDI: length 62
  TOP w0.132: J13.5 v1(157.38,42.16) ; v1(110.36,46.23) 110.36,46.23 107.44,49.15 105.54,49.15 104.87,49.81 103.98,49.81 103.84,49.95 102.99,49.95 U42.B22
  L14-SIGNAL w0.109: v1(157.38,42.16) 157.38,41.55 156.84,41.02 149.99,41.02 148.34,42.67 145.16,42.67 144.4,43.43 141.73,43.43 141.1,42.8 124.51,42.8 124.24,43.07 123.91,43.07 123.77,42.93 123.19,42.93 122.97,43.15 113.51,43.15 113.48,43.18 112.9,43.18 110.36,45.72 110.36,46.22 v1(110.36,46.23)
H_TDO: length 49.6
  TOP w0.132: v1(158.09,36.45) 158.09,36.42 157.88,36.21 J13.4
  L10-SIGNAL w0.089: v1(156.59,51.07) 157.86,49.8 157.86,37.21 158.09,36.98 v1(158.09,36.45)
  L14-SIGNAL w0.109: v1(156.59,51.07) 155.18,51.07 154.81,51.44 153.67,51.44 153.54,51.31 144.02,51.31 143.64,51.69 141.35,51.69 140.97,52.07 133.35,52.07 132.8,52.62 131.87,52.62 131.06,51.82 v1(126.87,51.82)
  BOTTOM w0.132: R598.1 126.11,52.58 v1(126.87,51.82)
H_TMS: length 84.6
  TOP w0.132: v1(158.75,36.45) 158.38,36.08 J13.2 ; U42.F16 v1(99.79,54.76)
  L12-SIGNAL w0.089: v1(160.78,51.94) 161.16,51.56 161.16,48.9 160.4,48.13 160.4,39.75 158.75,38.1 v1(158.75,36.45)
  L14-SIGNAL w0.109: v1(160.78,51.94) 160.54,52.18 158.35,52.18 158.24,52.07 156.93,52.07 156.31,52.69 154.07,52.69 153.8,52.96 150.11,52.96 149.73,52.58 144.78,52.58 143.93,53.43 142.54,53.43 141.86,54.1 137.76,54.1 137.72,54.06 135.3,54.06 134.24,55.12 125.22,55.12 125.08,54.97 123.66,54.97 123.26,55.37 121.29,55.37 120.37,56.28 109.24,56.28 108.73,56.79 105.3,56.79 104.9,56.39 100.71,56.39 100.19,55.86 100.19,55.16 v1(99.79,54.76)
  BOTTOM w0.132: v1(158.75,36.45) 158.5,36.2 R658.2
H_TRSTN: length 68.9
  TOP w0.132: U42.D20 v1(101.39,51.56)
  L10-SIGNAL w0.089: v1(157.1,38.73) 157.1,39.88 156.97,40.01 156.97,42.42 157.1,42.55 157.1,44.2 156.97,44.32 v1(156.97,44.96)
  L12-SIGNAL w0.089: v1(156.97,44.96) 156.46,45.47 153.92,45.47 153.54,45.09 149.99,45.09 148.08,46.99 147.32,46.99 146.43,46.1 134.24,46.1 130.68,49.66 124.59,49.66 124.07,50.17 123.44,50.17 122.2,51.41 104.5,51.41 104.25,51.16 101.78,51.16 v1(101.39,51.56)
  BOTTOM w0.132: v1(157.1,38.73) R664.2 R652.2
H_UART1_RXD: length 168.2
  TOP w0.132: v1(166.04,157.1) RU2.5 ; U42.F22 v1(99.79,49.96)
  L10-SIGNAL w0.089: v1(147.81,48.79) 147.81,51.92 149.61,53.72 149.61,56.13 151.89,58.42 151.89,87.88 156.34,92.33 156.34,107.19 157.35,108.2 157.35,136.02 163.19,141.86 163.19,154.88 164.53,156.21 165.16,156.21 v1(166.04,157.1)
  L14-SIGNAL w0.109: v1(99.79,49.96) 100.18,49.56 104.61,49.56 105.28,48.9 108.33,48.9 109.11,49.68 112.25,49.68 112.36,49.78 112.58,49.78 112.71,49.65 115.64,49.65 115.64,49.66 116.2,49.66 116.6,49.26 121.17,49.26 121.96,48.47 123.23,48.47 123.74,47.96 124.8,47.96 125.6,48.77 133.6,48.77 133.73,48.64 147.19,48.64 147.34,48.79 v1(147.81,48.79)
H_UART1_TXD: length 170.4
  TOP w0.132: v1(168.15,156.59) 168.15,157.23 168,157.38 RU2.2 ; U42.C21 v1(102.19,50.76)
  L10-SIGNAL w0.089: v1(147.96,46.48) 147.96,48.01 148.34,48.39 148.34,51.94 150.11,53.72 150.11,56.13 152.27,58.29 152.27,87.76 156.72,92.2 156.72,107.06 157.61,107.95 157.61,133.15 157.58,133.18 157.58,133.52 157.61,133.55 157.61,135.76 163.45,141.6 163.45,153.92 166.12,156.59 v1(168.15,156.59)
  L12-SIGNAL w0.089: v1(147.96,46.48) 147.07,45.59 133.99,45.59 130.3,49.28 123.44,49.28 122.61,50.11 119.87,50.11 119.46,50.51 108.11,50.51 107.86,50.76 v1(102.19,50.76)
H_UART3_RXD: length 72.2
  TOP w0.132: U42.V2 v1(89.38,66.77)
  L10-SIGNAL w0.089: v1(57.33,115.57) 57.33,112.58 54.97,110.21 54.97,98.07 58.42,94.61 58.42,93.09 66.42,85.09 69.47,85.09 79.76,74.8 84.07,74.8 89.09,69.79 89.09,69 88.96,68.87 88.14,68.87 88.01,68.74 88.01,68.56 88.14,68.43 88.96,68.43 89.09,68.3 89.09,67.88 88.99,67.78 88.99,67.15 v1(89.38,66.77)
  BOTTOM w0.132: RU14.12 v1(57.33,115.57)
H_UART3_RXD_BOOT: length 159.7
  TOP w0.132: RU2.6 165.39,157.23 v1(165.25,157.08)
  L7-SIGNAL w0.089: v1(111.89,48.4) 118.22,48.4 118.62,48.01 121.67,48.01 122.43,47.24 130.43,47.24 134.49,43.18 140.21,43.18 145.16,48.13 v1(145.16,49.09)
  L10-SIGNAL w0.089: v1(165.25,157.08) 164.76,156.59 163.19,156.59 161.8,155.19 161.8,143.73 160.27,142.21 160.27,139.54 157.1,136.37 157.1,108.3 155.96,107.16 155.96,92.55 151.64,88.23 151.64,62.07 150.37,60.8 150.37,57.53 149.22,56.39 149.22,53.85 146.94,51.56 146.94,49.02 146.56,48.64 145.61,48.64 v1(145.16,49.09)
  BOTTOM w0.132: R158.1 111.87,48.39 v1(111.89,48.4)
H_UART3_TXD: length 67.8
  TOP w0.132: U42.Y1 v1(87.78,67.57)
  L10-SIGNAL w0.089: v1(87.78,67.57) 87.78,68.3 87.38,68.71 87.38,70.23 83.19,74.42 79.5,74.42 69.72,84.21 67.19,84.21 66.93,83.95 62.99,83.95 54.61,92.33 54.61,110.74 55.38,111.52 v1(55.38,112.78)
  BOTTOM w0.132: RU14.9 v1(55.38,112.78)
H_UART3_TXD_BOOT: length 162.9
  TOP w0.132: RU2.3 167.35,157.27 v1(167.51,157.1)
  L7-SIGNAL w0.089: v1(111.38,49.27) 111.39,49.28 115.88,49.28 115.91,49.31 117.82,49.31 118.75,48.39 121.79,48.39 122.56,47.62 130.68,47.62 134.75,43.56 140.08,43.56 144.65,48.13 144.65,49.15 145.16,49.66 145.67,49.66 v1(146.18,49.15)
  L10-SIGNAL w0.089: v1(146.18,49.15) 146.18,51.31 148.84,53.98 148.84,56.52 149.99,57.66 149.99,60.96 151.29,62.26 151.29,88.42 155.57,92.71 155.57,107.31 156.72,108.46 156.72,136.53 159.89,139.7 159.89,142.37 161.42,143.89 161.42,156.34 162.69,157.61 167,157.61 v1(167.51,157.1)
  BOTTOM w0.132: R157.1 111.37,49.28 v1(111.38,49.27)
H_USB1_DN: length 91.3
  TOP w0.137: FL7.4 10.26,85.6 10.67,85.6 v1(10.95,85.88) ; U42.AE10 v1(83.78,60.36)
  BOTTOM w0.137: v1(10.95,85.88) 14.5,85.88 15.04,85.34 15.04,75.26 16.51,73.79 40.56,73.79 53.85,60.5 82.56,60.5 82.81,60.76 83.15,60.76 83.54,60.36 v1(83.78,60.36)
H_USB1_DP: length 91.3
  TOP w0.137: v1(10.92,85.06) 10.69,85.29 10.21,85.29 FL7.1 ; U42.AF11 v1(82.98,59.56)
  BOTTOM w0.137: v1(10.92,85.06) 10.92,85.26 11.24,85.57 11.49,85.57 11.61,85.45 11.61,85.34 11.73,85.22 11.9,85.22 12.02,85.34 12.02,85.45 12.14,85.57 14.38,85.57 14.73,85.22 14.73,75.13 16.38,73.48 40.44,73.48 53.72,60.2 82.55,60.2 82.98,59.77 v1(82.98,59.56)
H_USB1_DRV_VBUS: length 203.7
  TOP w0.132: U42.AD12 v1(84.58,58.76) ; U1.4 16,177.04 v1(15.75,177.29)
  L14-SIGNAL w0.109: v1(84.58,58.76) 84.18,58.37 80.32,58.37 79.76,58.93 78.99,58.93 77.6,60.33 44.83,60.33 22.48,82.68 8.51,82.68 6.6,84.58 6.6,86.36 6.99,86.74 6.99,90.04 4.57,92.46 2.65,92.46 0.75,94.36 0.75,176.14 3.17,178.56 14.48,178.56 v1(15.75,177.29)
  BOTTOM w0.132: R298.2 v1(15.75,177.29)
H_USB2_DN: length 92
  TOP w0.137: U141.27 56.89,119.53 56.99,119.44 57.76,119.44 v1(58.04,119.72) ; U42.AF13 v1(82.98,57.96)
  L12-SIGNAL w0.102: v1(82.98,57.96) 82.55,58.39 81.13,58.39 80.09,57.35 77.98,57.35 76.2,59.13 68.6,59.13 64.97,62.75 64.97,72.39 69.16,76.58 69.16,83.87 68.2,84.84 65.86,84.84 64.14,86.56 64.14,93.98 60.83,97.28 60.83,112.78 58.85,114.76 57.02,114.76 55.83,115.95 55.83,118.49 56.83,119.49 57.81,119.49 v1(58.04,119.72)
H_USB2_DP: length 92
  TOP w0.137: v1(58.04,118.85) 57.76,119.13 56.99,119.13 56.89,119.03 U141.26 ; U42.AE12 v1(83.78,58.76)
  L12-SIGNAL w0.102: v1(58.04,118.85) 58.04,118.86 57.71,119.18 56.95,119.18 56.13,118.36 56.13,116.08 57.15,115.06 58.98,115.06 61.14,112.9 61.14,97.41 64.44,94.11 64.44,86.69 65.99,85.14 68.33,85.14 69.47,84 69.47,76.45 65.28,72.26 65.28,62.88 68.72,59.44 76.33,59.44 78.11,57.66 79.96,57.66 81,58.7 82.32,58.7 82.79,59.17 83.37,59.17 v1(83.78,58.76)
H_USB2_DRV_VBUS: length 72.7
  TOP w0.132: v1(60.2,118.36) RJ16.3 ; U42.AC11 v1(85.38,59.56)
  L12-SIGNAL w0.089: v1(85.38,59.56) 84.99,59.95 81.4,59.95 73.79,67.56 73.79,69.85 71.75,71.88 71.75,83.69 69.34,86.11 69.34,90.17 68.07,91.44 68.07,94.61 67.18,95.5 67.18,97.79 64.26,100.71 64.26,112.01 60.2,116.08 v1(60.2,118.36)
H_USB3_RXN: length 73.4
  TOP w0.137: U42.AG3 v1(82.18,65.97) ; FL9.4 15.34,77.11 15.57,76.89 16.05,76.89 v1(16.26,77.09)
  BOTTOM w0.137: v1(16.26,77.09) 40.21,77.09 52.6,64.69 79.78,64.69 80.65,65.57 81.78,65.57 v1(82.18,65.97)
H_USB3_RXP: length 73.4
  TOP w0.137: v1(16.26,76.33) 16,76.58 15.62,76.58 15.34,76.3 FL9.1 ; U42.AH4 v1(81.38,65.16)
  BOTTOM w0.137: v1(16.26,76.33) 16.48,76.56 16.48,76.65 16.62,76.78 16.87,76.78 16.99,76.66 16.99,76.45 17.11,76.33 17.28,76.33 17.41,76.45 17.41,76.66 17.53,76.78 40.08,76.78 52.48,64.39 79.91,64.39 80.78,65.26 81.28,65.26 v1(81.38,65.16)
H_USB3_TXN: length 71.9
  TOP w0.137: U42.AG2 v1(82.18,66.77) ; C142.1 17.23,80.01 17.53,80.01 v1(17.78,80.26)
  BOTTOM w0.137: v1(17.78,80.26) 40.39,80.26 54.29,66.36 81.47,66.36 81.48,66.37 81.78,66.37 v1(82.18,66.77)
H_USB3_TXP: length 71.9
  TOP w0.137: v1(17.78,79.5) 17.61,79.68 17.15,79.68 C144.1 ; U42.AH3 v1(81.38,65.97)
  BOTTOM w0.137: v1(17.78,79.5) 17.98,79.71 17.98,79.82 18.12,79.96 18.37,79.96 18.49,79.84 18.49,79.57 18.61,79.45 18.78,79.45 18.9,79.57 18.9,79.84 19.02,79.96 40.26,79.96 54.16,66.06 81.29,66.06 v1(81.38,65.97)
H_VIN1_D0: length 70.5
  TOP w0.132: U42.AE9 v1(83.78,61.16)
  L7-SIGNAL w0.089: v1(83.78,61.16) 83.35,61.59 83.14,61.59 83.14,61.59 82.35,61.59 82.34,61.58 82.02,61.58 82,61.59 81.92,61.59 81.41,62.1 79.5,62.1 76.58,65.02 76.58,65.69 76.45,65.82 75.7,65.82 75.56,65.95 75.56,66.14 75.7,66.27 76.45,66.27 76.58,66.4 76.58,66.58 76.45,66.71 75.7,66.71 75.56,66.84 75.56,67.03 75.7,67.16 76.45,67.16 76.58,67.29 76.58,71.2 76.45,71.33 76.08,71.33 75.95,71.46 75.95,71.65 76.08,71.78 76.45,71.78 76.58,71.91 76.58,72.09 76.45,72.22 76.08,72.22 75.95,72.35 75.95,72.54 76.08,72.67 76.45,72.67 76.58,72.8 76.58,73.97 76.45,74.1 75.97,74.1 75.84,74.23 75.84,74.42 75.97,74.55 76.45,74.55 76.58,74.68 76.58,74.86 76.45,74.99 75.97,74.99 75.84,75.12 75.84,75.31 75.97,75.44 76.45,75.44 76.58,75.57 76.58,75.77 76.45,75.9 75.57,75.9 75.44,76.03 75.44,76.22 75.57,76.35 76.45,76.35 76.58,76.48 76.58,76.66 76.45,76.79 75.57,76.79 75.44,76.92 75.44,85.98 79.5,90.04 79.5,93.22 83.44,97.15 83.44,101.73 83.34,101.83 83.34,107.22 v1(83.69,107.57)
  BOTTOM w0.132: v1(83.69,107.57) 81.52,109.73 EXP_P2.40
H_VIN1_D1: length 70.8
  TOP w0.132: U42.AF10 v1(82.98,60.36)
  L7-SIGNAL w0.089: v1(82.98,60.36) 80.61,60.36 74.93,66.04 74.93,86.49 76.83,88.39 76.83,90.97 83.06,97.19 83.06,101.22 82.55,101.73 82.55,117.6 83.06,118.11 84.04,118.11 v1(84.98,117.17)
  BOTTOM w0.132: EXP_P2.41 v1(84.98,117.17)
H_VIN1_D2: length 70.3
  TOP w0.132: U42.AE7 v1(83.78,62.76)
  L12-SIGNAL w0.089: v1(84.71,107.82) 84.71,92.84 83.44,91.57 83.44,87.12 82.95,86.63 80.65,86.63 80.52,86.5 80.52,86.32 80.65,86.19 81.78,86.19 81.92,86.06 81.92,85.87 81.78,85.74 80.65,85.74 80.52,85.61 80.52,85.43 80.65,85.3 81.78,85.3 81.92,85.17 81.92,84.98 81.78,84.85 80.65,84.85 80.52,84.72 80.52,84.54 80.65,84.41 81.78,84.41 81.92,84.28 81.92,84.09 81.78,83.96 80.65,83.96 80.52,83.83 80.52,83.65 80.65,83.52 81.78,83.52 81.92,83.39 81.92,83.19 81.41,82.68 81.41,81.41 81.26,81.26 81.08,81.26 80.37,81.97 80.19,81.97 80.06,81.84 80.06,81.65 80.76,80.95 80.76,80.76 80.63,80.63 80.45,80.63 79.75,81.34 79.56,81.34 79.43,81.21 79.43,81.02 80.14,80.32 80.14,80.13 79.99,79.99 79.99,79.8 80.25,79.54 80.25,79.36 80.12,79.23 79.93,79.23 79.67,79.49 79.49,79.49 77.98,77.98 77.98,66.04 80.85,63.16 83.38,63.16 v1(83.78,62.76)
  BOTTOM w0.132: v1(84.71,107.82) 85,108.11 85,109.72 EXP_P2.42
H_VIN1_D3: length 71.2
  TOP w0.132: U42.AE8 v1(83.78,61.96)
  L12-SIGNAL w0.089: v1(83.78,61.96) 83.37,62.38 81.13,62.38 77.72,65.79 77.72,78.36 78.99,79.63 78.99,82.8 80.01,83.82 80.01,86.49 81.79,88.27 81.79,90.42 84.07,92.71 84.07,114.65 83.94,114.78 83.32,114.78 83.19,114.91 83.19,115.1 83.32,115.23 83.94,115.23 84.07,115.36 84.07,115.54 83.94,115.67 83.32,115.67 83.19,115.8 83.19,115.99 83.32,116.12 83.94,116.12 84.07,116.25 84.07,116.43 83.94,116.56 83.32,116.56 83.19,116.69 83.19,116.88 83.32,117.01 83.94,117.01 84.07,117.14 84.07,117.35 84.65,117.93 v1(85.78,117.93)
  BOTTOM w0.132: EXP_P2.43 v1(85.78,117.93)
H_VIN1_D4: length 71.2
  TOP w0.132: U42.AE6 v1(83.78,63.56)
  L7-SIGNAL w0.089: v1(85.72,111.38) 85.72,110.94 85.86,110.81 86.74,110.81 86.87,110.68 86.87,110.5 86.74,110.37 85.86,110.37 85.72,110.24 85.72,110.05 85.86,109.92 86.74,109.92 86.87,109.79 86.87,109.61 86.74,109.48 85.86,109.48 85.72,109.35 85.72,109.16 85.86,109.03 86.74,109.03 86.87,108.9 86.87,108.72 86.74,108.59 85.86,108.59 85.72,108.46 85.72,108.27 85.86,108.14 86.74,108.14 86.87,108.01 86.87,107.83 86.74,107.7 85.86,107.7 84.61,106.45 84.61,95.53 82.8,93.73 82.8,92.08 78.99,88.27 78.99,87.25 76.58,84.84 76.58,84.35 76.71,84.22 77.34,84.22 77.47,84.09 77.47,83.9 77.34,83.77 76.71,83.77 76.58,83.64 76.58,83.46 76.71,83.33 77.34,83.33 77.47,83.2 77.47,83.01 77.34,82.88 76.71,82.88 76.58,82.75 76.58,82.57 76.71,82.44 77.34,82.44 77.47,82.31 77.47,82.13 77.34,81.99 76.71,81.99 76.58,81.86 76.58,81.66 78.02,80.23 78.02,77.3 78.23,77.09 78.23,65.79 79.76,64.26 80.91,64.26 81,64.35 81.32,64.35 81.41,64.26 81.53,64.26 81.81,63.99 82.01,63.99 82.02,63.98 82.34,63.98 82.35,63.99 83.36,63.99 v1(83.78,63.56)
  BOTTOM w0.132: v1(85.72,111.38) 85.78,111.32 EXP_P2.44
H_VIN1_D5: length 71.1
  TOP w0.132: U42.AF7 v1(82.98,62.76)
  L7-SIGNAL w0.089: v1(86.58,117.17) 85.62,116.2 84.81,116.2 84.45,115.85 84.45,115.11 84.54,115.02 85.09,115.02 85.22,114.89 85.22,114.71 85.09,114.58 84.08,114.58 83.95,114.45 83.95,114.26 84.08,114.13 85.09,114.13 85.22,114 85.22,113.82 85.09,113.69 84.08,113.69 83.95,113.56 83.95,113.38 84.08,113.25 85.09,113.25 85.22,113.11 85.22,107.57 84.2,106.55 84.2,95.63 81.79,93.22 81.79,91.44 76.2,85.85 76.2,80.77 77.22,79.76 77.22,77.34 77.72,76.84 77.72,65.53 80.49,62.76 v1(82.98,62.76)
  BOTTOM w0.132: EXP_P2.45 v1(86.58,117.17)
H_VIN1_D6: length 71.5
  TOP w0.132: U42.AF8 v1(82.98,61.96)
  L7-SIGNAL w0.089: v1(84.58,111.38) 83.93,110.73 83.06,110.73 82.93,110.6 82.93,110.41 83.06,110.28 83.93,110.28 84.06,110.15 84.06,109.97 83.93,109.84 83.06,109.84 82.93,109.71 82.93,109.52 83.06,109.39 83.93,109.39 84.06,109.26 84.06,109.08 83.93,108.95 83.06,108.95 82.93,108.82 82.93,108.64 83.06,108.51 83.93,108.51 84.06,108.38 84.06,107.41 83.81,107.16 83.81,97.14 82.54,95.88 82.52,95.88 82.3,95.66 82.3,95.64 80.64,93.98 80.64,90.68 75.82,85.85 75.82,79.78 75.95,79.65 76.7,79.65 76.83,79.51 76.83,79.33 76.7,79.2 75.95,79.2 75.82,79.07 75.82,78.89 75.95,78.76 76.7,78.76 76.83,78.63 76.83,78.44 76.7,78.31 75.95,78.31 75.82,78.18 75.82,77.98 76.96,76.83 76.96,74.04 76.85,73.93 76.85,72.57 77.09,72.34 77.09,65.28 80.01,62.36 82.59,62.36 v1(82.98,61.96)
  BOTTOM w0.132: EXP_P2.46 86.58,111.22 85.91,111.89 85.09,111.89 v1(84.58,111.38)
H_VIN1_D7: length 70.2
  TOP w0.132: U42.AF6 v1(82.98,63.56)
  L12-SIGNAL w0.089: v1(87.38,117.93) 87.38,116.85 86.66,116.13 84.59,116.13 84.45,116 84.45,115.81 84.59,115.68 85.09,115.68 85.22,115.55 85.22,115.37 85.09,115.24 84.59,115.24 84.45,115.11 84.45,114.92 84.59,114.79 85.09,114.79 85.22,114.66 85.22,114.48 85.09,114.35 84.59,114.35 84.45,114.22 84.45,114.03 84.59,113.9 85.09,113.9 85.22,113.77 85.22,113.59 85.09,113.46 84.59,113.46 84.45,113.33 84.45,113.14 84.59,113.01 85.09,113.01 85.22,112.88 85.22,112.7 85.09,112.57 84.59,112.57 84.45,112.44 84.45,112.26 84.59,112.13 85.09,112.13 85.22,111.99 85.22,110.9 85.09,110.77 84.59,110.77 84.45,110.64 84.45,110.46 84.59,110.33 85.09,110.33 85.22,110.2 85.22,110.01 85.09,109.88 84.59,109.88 84.45,109.75 84.45,109.57 84.59,109.44 85.09,109.44 85.22,109.31 85.22,109.13 85.09,109 84.59,109 84.45,108.87 84.45,108.68 84.59,108.55 85.09,108.55 85.22,108.42 85.22,92.84 83.83,91.45 83.83,73.8 82.57,72.54 82.57,63.98 v1(82.98,63.56)
  BOTTOM w0.132: EXP_P2.47 v1(87.38,117.93)
H_VIN1_D8: length 72.1
  TOP w0.132: U42.AF4 v1(82.98,65.16)
  L14-SIGNAL w0.109: v1(82.98,65.16) 82.41,65.16 81.78,65.79 81.78,71.75 82.17,72.14 82.17,78.68 82.99,79.5 82.99,82.68 82.17,83.5 82.17,91.57 82.72,92.12 82.72,93.3 81.92,94.11 81.92,96.01 82.68,96.77 82.68,97.54 83.95,98.81 83.95,101.93 84.11,102.09 85.56,102.09 85.72,102.25 85.72,102.48 85.56,102.64 84.11,102.64 83.95,102.8 83.95,103.02 84.11,103.18 85.56,103.18 85.72,103.34 85.72,103.57 85.56,103.73 84.11,103.73 83.95,103.89 83.95,104.12 84.11,104.28 85.56,104.28 85.72,104.44 85.72,104.66 85.56,104.82 84.11,104.82 83.95,104.98 83.95,105.21 84.11,105.37 85.56,105.37 85.72,105.53 85.72,105.76 85.56,105.92 84.11,105.92 83.95,106.08 83.95,106.3 84.58,106.93 88.39,106.93 88.67,106.65 94.84,106.65 v1(95.12,106.93)
  BOTTOM w0.132: v1(95.12,106.93) 95.12,107.6 95.38,107.86 EXP_P2.68
H_VIN1_D9: length 70.9
  TOP w0.132: U42.AF2 v1(82.98,66.77)
  L7-SIGNAL w0.089: v1(95.38,117.93) 91.82,114.36 91.82,108.2 91.79,108.18 91.79,107.86 91.55,107.62 91.51,107.62 90.75,106.86 90.73,106.86 89.92,106.05 88.79,106.05 88.26,105.51 88.26,104.73 88.04,104.51 87.73,104.51 87.72,104.52 85.3,104.52 84.96,104.18 84.96,95.38 83.19,93.6 83.19,91.95 79.38,88.14 79.38,87 78.87,86.49 78.87,84.17 78.74,84.04 78.11,84.04 77.98,83.91 77.98,83.72 78.11,83.59 78.74,83.59 78.87,83.46 78.87,83.28 78.74,83.15 78.11,83.15 77.98,83.02 77.98,82.83 78.11,82.7 78.74,82.7 78.87,82.57 78.87,82.39 78.74,82.26 78.11,82.26 77.98,82.13 77.98,81.95 78.11,81.81 78.74,81.81 78.87,81.68 78.87,81.5 78.74,81.37 78.11,81.37 77.98,81.24 77.98,81.06 78.11,80.93 78.74,80.93 78.87,80.8 78.87,73.28 82.55,69.6 82.55,67.74 82.57,67.73 82.57,67.4 82.55,67.39 82.55,67.2 v1(82.98,66.77)
  BOTTOM w0.132: EXP_P2.67 v1(95.38,117.93)
H_VIN1_D10: length 71.2
  TOP w0.132: U42.AF3 v1(82.98,65.97)
  L14-SIGNAL w0.109: v1(96.44,107.27) 95.47,106.3 95.04,106.3 94.88,106.14 94.88,105.57 94.72,105.41 94.5,105.41 94.34,105.57 94.34,106.14 94.18,106.3 93.95,106.3 93.79,106.14 93.79,105.57 93.63,105.41 93.41,105.41 93.25,105.57 93.25,106.14 93.09,106.3 92.86,106.3 92.7,106.14 92.7,105.57 92.54,105.41 92.31,105.41 92.15,105.57 92.15,106.14 91.99,106.3 91.77,106.3 91.61,106.14 91.61,105.57 91.45,105.41 91.22,105.41 91.06,105.57 91.06,106.14 90.9,106.3 90.68,106.3 89.92,105.54 89.69,105.54 89.03,106.2 88.8,106.2 88.64,106.04 88.64,105.82 89.31,105.15 89.31,104.93 88.79,104.41 87.39,104.41 86.87,103.89 86.87,102.74 86.71,102.58 86.71,102.36 87.18,101.89 87.18,101.66 87.02,101.5 86.8,101.5 86.32,101.97 86.1,101.97 85.94,101.81 85.94,101.59 86.41,101.11 86.41,100.89 86.25,100.73 86.02,100.73 85.55,101.2 85.32,101.2 85.16,101.04 85.16,100.81 85.64,100.34 85.64,100.11 85.48,99.95 85.25,99.95 84.78,100.43 84.55,100.43 84.33,100.2 84.33,98.68 83.06,97.41 83.06,96.52 82.28,95.74 82.28,94.38 83.06,93.6 83.06,91.82 82.55,91.31 82.55,89.99 82.71,89.83 83.15,89.83 83.31,89.67 83.31,89.45 83.15,89.29 82.71,89.29 82.55,89.13 82.55,88.9 82.71,88.74 83.15,88.74 83.31,88.58 83.31,88.35 83.15,88.19 82.71,88.19 82.55,88.03 82.55,87.81 82.71,87.65 83.15,87.65 83.31,87.49 83.31,87.26 83.15,87.1 82.71,87.1 82.55,86.94 82.55,83.57 83.31,82.8 83.31,79.37 82.58,78.64 82.58,66.37 v1(82.98,65.97)
  BOTTOM w0.132: v1(96.44,107.27) 96.44,107.82 96.18,108.08 EXP_P2.70
H_VIN1_D11: length 71.6
  TOP w0.132: U42.AF5 v1(82.98,64.36)
  L7-SIGNAL w0.089: v1(96.18,117.17) 93.09,114.07 93.09,112.39 92.61,111.91 92.61,111.22 92.71,111.12 92.71,107.19 92.2,106.68 91.57,106.68 88.9,104.01 88.9,102.74 88.27,102.11 86.61,102.11 85.72,101.22 85.72,95.12 83.95,93.34 83.95,91.71 82.94,90.71 82.94,90.69 80.64,88.39 80.64,78.67 80.78,78.54 81.4,78.54 81.53,78.41 81.53,78.22 81.4,78.09 80.78,78.09 80.64,77.96 80.64,77.78 80.78,77.65 81.4,77.65 81.53,77.52 81.53,77.33 81.4,77.2 80.78,77.2 80.64,77.07 80.64,76.89 80.78,76.76 81.4,76.76 81.53,76.63 81.53,76.45 81.4,76.31 80.78,76.31 80.64,76.18 80.64,76 80.78,75.87 81.4,75.87 81.53,75.74 81.53,75.56 81.4,75.43 80.78,75.43 80.64,75.3 80.64,75.11 80.78,74.98 81.4,74.98 81.53,74.85 81.53,74.67 81.4,74.54 80.78,74.54 80.64,74.41 80.64,72.52 83.36,69.81 83.36,64.74 v1(82.98,64.36)
  BOTTOM w0.132: EXP_P2.69 v1(96.18,117.17)
H_VIN1_D12: length 71.4
  TOP w0.132: U42.AE5 v1(83.78,64.36)
  L14-SIGNAL w0.109: v1(83.78,64.36) 83.38,64.77 83.38,67.88 83.06,68.2 83.06,70.99 83.22,71.15 84.17,71.15 84.33,71.31 84.33,71.53 84.17,71.69 83.22,71.69 83.06,71.85 83.06,72.08 83.22,72.24 84.17,72.24 84.33,72.4 84.33,72.62 84.17,72.78 83.22,72.78 83.06,72.94 83.06,73.17 83.22,73.33 84.17,73.33 84.33,73.49 84.33,73.72 84.17,73.88 83.22,73.88 83.06,74.04 83.06,74.26 83.22,74.42 84.17,74.42 84.33,74.58 84.33,74.81 84.17,74.97 83.22,74.97 83.06,75.13 83.06,75.36 83.22,75.52 84.17,75.52 84.33,75.68 84.33,75.9 84.17,76.06 83.22,76.06 83.06,76.22 83.06,76.45 83.22,76.61 84.17,76.61 84.33,76.77 84.33,76.99 84.17,77.15 83.22,77.15 83.06,77.31 83.06,78.49 83.98,79.41 84.29,79.41 84.45,79.57 84.45,79.79 84.29,79.95 83.98,79.95 83.82,80.11 83.82,80.34 83.98,80.5 84.29,80.5 84.45,80.66 84.45,80.89 84.29,81.05 83.98,81.05 83.82,81.21 83.82,81.43 83.98,81.59 84.29,81.59 84.45,81.75 84.45,81.98 84.29,82.14 83.98,82.14 83.82,82.3 83.82,82.52 83.98,82.68 84.29,82.68 84.45,82.84 84.45,83.07 84.29,83.23 83.98,83.23 83.82,83.39 83.82,97.66 88.52,102.36 88.52,103 89.03,103.5 90.38,103.5 91.28,104.41 94.38,104.41 97.16,107.19 v1(97.16,107.82)
  BOTTOM w0.132: EXP_P2.72 96.87,109.61 96.87,108.11 v1(97.16,107.82)
H_VIN1_D13: length 71.1
  TOP w0.132: U42.AF1 v1(82.98,67.57)
  L7-SIGNAL w0.089: v1(96.98,117.93) 96.21,117.93 92.2,113.92 92.2,112.79 92.18,112.77 92.18,107.89 91.57,107.28 91.57,107.06 88.52,104.01 88.52,102.84 88.17,102.49 86.23,102.49 85.34,101.6 85.34,95.25 83.57,93.47 83.57,91.82 79.88,88.14 79.88,87 79.25,86.36 79.25,86.16 79.38,86.03 79.75,86.03 79.88,85.9 79.88,85.71 79.75,85.58 79.38,85.58 79.25,85.45 79.25,85.27 79.38,85.14 79.75,85.14 79.88,85.01 79.88,84.82 79.75,84.69 79.38,84.69 79.25,84.56 79.25,84.38 79.38,84.25 79.75,84.25 79.88,84.12 79.88,83.93 79.75,83.8 79.38,83.8 79.25,83.67 79.25,83.49 79.38,83.36 79.75,83.36 79.88,83.23 79.88,83.05 79.75,82.92 79.38,82.92 79.25,82.78 79.25,82.6 79.38,82.47 79.75,82.47 79.88,82.34 79.88,82.16 79.75,82.03 79.38,82.03 79.25,81.9 79.25,81.71 79.38,81.58 79.75,81.58 79.88,81.45 79.88,81.27 79.75,81.14 79.38,81.14 79.25,81.01 79.25,80.82 79.38,80.69 79.75,80.69 79.88,80.56 79.88,80.38 79.75,80.25 79.38,80.25 79.25,80.12 79.25,79.76 79.79,79.21 79.79,78.27 79.25,77.72 79.25,73.41 82.98,69.67 v1(82.98,67.57)
  BOTTOM w0.132: EXP_P2.71 v1(96.98,117.93)
H_VIN1_D14: length 70.5
  TOP w0.132: U42.AD6 v1(84.58,63.56)
  L7-SIGNAL w0.089: v1(84.58,63.56) 84.96,63.95 84.96,68.33 85.77,69.14 85.77,70.18 83.06,72.9 83.06,73.11 83.19,73.24 84.2,73.24 84.33,73.37 84.33,73.55 84.2,73.68 83.19,73.68 83.06,73.81 83.06,74 83.19,74.13 84.2,74.13 84.33,74.26 84.33,74.44 84.2,74.57 83.19,74.57 83.06,74.7 83.06,74.89 83.19,75.02 84.2,75.02 84.33,75.15 84.33,75.33 84.2,75.46 83.19,75.46 83.06,75.59 83.06,75.78 83.19,75.91 84.2,75.91 84.33,76.04 84.33,76.22 84.2,76.35 83.19,76.35 83.06,76.48 83.06,76.67 83.19,76.8 84.2,76.8 84.33,76.93 84.33,77.11 84.2,77.24 83.19,77.24 83.06,77.37 83.06,77.55 83.19,77.68 84.2,77.68 84.33,77.81 84.33,78 84.2,78.13 83.19,78.13 83.06,78.26 83.06,89.03 84.84,90.81 84.84,93.22 87.71,96.09 87.71,99.9 89.41,101.6 91.57,101.6 95.76,105.79 95.76,107.7 96.52,108.46 97.36,108.46 v1(97.78,108.03)
  BOTTOM w0.132: EXP_P2.74 v1(97.78,108.03)
H_VIN1_D15: length 71.7
  TOP w0.132: U42.AE3 v1(83.78,65.97)
  L7-SIGNAL w0.089: v1(83.78,65.97) 84.16,66.34 84.16,68.12 83.69,68.58 83.69,69.98 82.55,71.12 82.55,84.56 82.42,84.69 81.79,84.69 81.66,84.82 81.66,85.01 81.79,85.14 82.42,85.14 82.55,85.27 82.55,85.45 82.42,85.58 81.79,85.58 81.66,85.71 81.66,85.9 81.79,86.03 82.42,86.03 82.55,86.16 82.55,86.34 82.42,86.47 81.79,86.47 81.66,86.6 81.66,86.79 81.79,86.92 82.42,86.92 82.55,87.05 82.55,87.23 82.42,87.36 81.79,87.36 81.66,87.49 81.66,87.67 81.79,87.8 82.42,87.8 82.55,87.93 82.55,88.12 82.42,88.25 81.79,88.25 81.66,88.38 81.66,88.56 82.76,89.66 83.19,89.66 83.31,89.79 83.31,90.57 84.33,91.59 84.33,93.22 86.87,95.76 86.87,100.84 87.76,101.73 88.77,101.73 89.92,102.87 89.92,103.25 90.17,103.5 90.55,103.5 90.93,103.89 90.93,104.98 93.47,107.52 93.47,113.41 97.78,117.72 v1(97.78,118.69)
  BOTTOM w0.132: EXP_P2.73 v1(97.78,118.69)
H_VIN1_D16: length 70.7
  TOP w0.132: U42.AE4 v1(83.78,65.16)
  L5-SIGNAL w0.089: v1(65.79,113.54) 64.9,112.65 64.9,108.97 65.37,108.5 65.37,107.66 64.9,107.19 64.9,106.97 65.03,106.84 65.78,106.84 65.91,106.71 65.91,106.53 65.78,106.4 65.03,106.4 64.9,106.27 64.9,106.08 65.03,105.95 65.78,105.95 65.91,105.82 65.91,105.64 65.78,105.51 65.03,105.51 64.9,105.38 64.9,105.19 65.03,105.06 65.78,105.06 65.91,104.93 65.91,104.75 65.78,104.62 65.03,104.62 64.9,104.49 64.9,99.44 67.66,96.68 67.66,83.41 67.65,83.4 67.65,83.08 67.66,83.07 67.66,82.84 68.07,82.43 68.07,76.93 68.07,76.92 68.07,72.9 70.48,70.48 70.48,68.2 73.13,65.55 83.39,65.55 v1(83.78,65.16)
  BOTTOM w0.132: v1(65.79,113.54) 65.77,113.56 65.77,113.9 65.78,113.91 EXP_P2.3
H_VIN1_D17: length 70.9
  TOP w0.132: U42.AE1 v1(83.78,67.57)
  L5-SIGNAL w0.089: v1(66.04,108.08) 66.42,108.46 67.69,108.46 68.33,107.82 68.33,104.65 69.22,103.75 69.22,103.09 69.22,103.08 69.22,102.86 69.08,102.73 68.33,102.73 68.2,102.6 68.2,102.42 68.33,102.29 69.08,102.29 69.22,102.16 69.22,101.97 69.08,101.84 68.33,101.84 68.2,101.71 68.2,101.53 68.33,101.4 69.08,101.4 69.22,101.27 69.22,101.09 69.08,100.96 68.33,100.96 68.2,100.83 68.2,100.64 68.33,100.51 69.08,100.51 69.22,100.38 69.22,100.2 69.08,100.07 68.33,100.07 68.2,99.94 68.2,99.75 68.33,99.62 69.08,99.62 69.22,99.49 69.22,99.31 69.08,99.18 68.33,99.18 68.2,99.05 68.2,98.86 68.33,98.73 69.08,98.73 69.22,98.6 69.22,98.42 69.08,98.29 68.33,98.29 68.2,98.16 68.2,97.97 68.33,97.84 69.08,97.84 69.22,97.71 69.22,87.38 69.72,86.87 69.72,76.45 71.37,74.8 71.37,72.14 72.14,71.37 72.14,70.68 72.01,70.55 71.63,70.55 71.5,70.42 71.5,70.24 71.63,70.11 72.01,70.11 72.14,69.98 72.14,69.79 72.01,69.66 71.63,69.66 71.5,69.53 71.5,69.35 71.63,69.22 72.01,69.22 72.68,68.54 73.06,68.54 74.8,66.8 79.76,66.8 80.91,67.95 83.39,67.95 v1(83.78,67.57)
  BOTTOM w0.132: EXP_P2.4 65.78,108.34 v1(66.04,108.08)
H_VIN1_D18: length 71.9
  TOP w0.132: U42.AD5 v1(84.58,64.36)
  L5-SIGNAL w0.089: v1(84.58,64.36) 84.19,63.98 81.82,63.98 81.41,64.39 73.41,64.39 67.31,70.48 67.31,80.64 64.01,83.95 64.01,92.71 63.37,93.34 63.37,98.55 63.88,99.06 63.88,113.28 66.58,115.98 v1(66.58,117.09)
  BOTTOM w0.132: EXP_P2.5 v1(66.58,117.09)
H_VIN1_D19: length 70.6
  TOP w0.132: U42.AD3 v1(84.58,65.97)
  L5-SIGNAL w0.089: v1(84.58,65.97) 84.19,66.35 81.22,66.35 81.12,66.25 72.94,66.25 70.74,68.45 70.74,74.42 68.96,76.2 68.96,85.72 68.07,86.62 68.07,96.91 65.28,99.69 65.28,102.24 65.41,102.37 67.31,102.37 67.44,102.5 67.44,102.69 67.31,102.82 65.41,102.82 65.28,102.95 65.28,103.13 65.41,103.26 67.31,103.26 67.44,103.39 67.44,103.58 67.31,103.71 65.41,103.71 65.28,103.84 65.28,104.02 65.41,104.15 66.21,104.15 66.29,104.24 66.29,104.35 66.42,104.48 66.93,104.48 67.06,104.61 67.06,104.79 66.93,104.92 66.42,104.92 66.29,105.05 66.29,106.93 66.42,107.06 v1(67.44,107.06)
  BOTTOM w0.132: EXP_P2.6 66.58,107.92 v1(67.44,107.06)
H_VIN1_D20: length 71.9
  TOP w0.132: U42.AD4 v1(84.58,65.16)
  L5-SIGNAL w0.089: v1(84.58,65.16) 84.19,64.78 83.62,64.78 83.62,64.78 73.4,64.78 67.69,70.48 67.69,81.53 66.17,83.06 66.17,97.66 64.52,99.31 64.52,113.03 67.38,115.89 v1(67.38,117.67)
  BOTTOM w0.132: EXP_P2.7 v1(67.38,117.67)
H_VIN1_D21: length 70.4
  TOP w0.132: U42.AE2 v1(83.78,66.77)
  L5-SIGNAL w0.089: v1(83.78,66.77) 83.39,67.15 81.22,67.15 80.64,66.58 74.52,66.58 72.77,68.33 71.63,68.33 70.99,68.96 70.99,74.68 69.34,76.33 69.34,86.23 68.85,86.72 68.85,96.63 67.69,97.79 67.69,98.6 67.56,98.73 66.93,98.73 66.8,98.86 66.8,99.04 66.93,99.17 67.56,99.17 67.69,99.3 67.69,99.52 67.56,99.65 65.92,99.65 65.79,99.78 65.79,99.96 65.92,100.09 67.56,100.09 67.69,100.22 67.69,100.44 67.56,100.57 65.79,100.57 65.66,100.7 65.66,100.88 65.79,101.01 67.56,101.01 67.69,101.15 67.69,101.33 67.56,101.46 65.79,101.46 65.66,101.59 65.66,101.77 65.79,101.9 67.56,101.9 67.69,102.03 67.69,104.52 67.94,104.77 67.94,104.99 67.81,105.12 67.57,105.12 67.44,105.25 67.44,105.44 67.57,105.57 67.81,105.57 67.94,105.7 67.94,107.53 v1(67.54,107.93)
  BOTTOM w0.132: v1(67.54,107.93) 67.54,107.97 67.38,108.14 EXP_P2.8
H_VIN1_D22: length 70.8
  TOP w0.132: U42.AD1 v1(84.58,67.57)
  L5-SIGNAL w0.089: v1(84.58,67.57) 84.58,67.97 81.17,71.37 78.19,71.37 78.06,71.24 78.06,70.23 77.93,70.1 77.75,70.1 77.62,70.23 77.62,71.24 77.49,71.37 77.3,71.37 77.17,71.24 77.17,70.23 77.04,70.1 76.86,70.1 76.73,70.23 76.73,71.24 76.6,71.37 76.56,71.37 76.43,71.5 76.43,72.64 76.3,72.77 76.11,72.77 75.98,72.64 75.98,71.5 75.85,71.37 74.8,71.37 73.53,72.64 73.53,74.42 72.64,75.31 72.01,75.31 70.48,76.83 70.48,87.63 70.99,88.14 70.99,97.03 71.44,97.47 71.44,103.44 71.75,103.76 71.75,107.86 71.77,107.87 71.77,108.19 71.75,108.2 71.75,111.25 68.2,114.81 68.2,116.74 68.18,116.76 v1(68.18,117.17)
  BOTTOM w0.132: EXP_P2.9 v1(68.18,117.17)
H_VIN1_D23: length 70.7
  TOP w0.132: U42.AD2 v1(84.58,66.77)
  L5-SIGNAL w0.089: v1(84.58,66.77) 84.17,67.18 84.17,67.73 83.57,68.33 80.77,68.33 79.63,67.18 79.33,67.18 79.2,67.31 79.2,68.07 79.07,68.2 78.88,68.2 78.75,68.07 78.75,67.31 78.62,67.18 78.44,67.18 78.31,67.31 78.31,68.07 78.18,68.2 77.99,68.2 77.86,68.07 77.86,67.31 77.73,67.18 77.52,67.18 77.39,67.31 77.39,68.32 77.26,68.45 77.07,68.45 76.94,68.32 76.94,67.31 76.81,67.18 76.6,67.18 76.47,67.31 76.47,68.32 76.34,68.45 76.15,68.45 76.02,68.32 76.02,67.31 75.89,67.18 75.06,67.18 73.41,68.83 73.41,69.34 72.9,69.85 72.9,70.07 73.03,70.2 74.8,70.2 74.93,70.33 74.93,70.51 74.8,70.64 73.03,70.64 72.9,70.77 72.9,70.99 73.03,71.12 73.66,71.12 73.79,71.25 73.79,71.43 73.66,71.56 73.03,71.56 72.9,71.69 72.9,72.39 71.75,73.53 71.75,75.06 70.1,76.71 70.1,88.26 70.36,88.52 70.36,90.55 69.72,91.19 69.72,97.28 70.21,97.77 70.21,99.84 69.6,100.46 69.6,106.68 v1(68.96,107.31)
  BOTTOM w0.132: v1(68.96,107.31) 68.18,108.1 EXP_P2.10
H_VIN1_DE: length 70.9
  TOP w0.132: U42.AC9 v1(85.38,61.16)
  L12-SIGNAL w0.089: v1(74.58,117.17) 74.58,116.78 74.55,116.75 74.55,113.79 73.28,112.52 73.28,108.84 73.37,108.75 73.37,105.62 73.24,105.49 72.52,105.49 72.39,105.36 72.39,105.18 72.52,105.05 73.24,105.05 73.37,104.91 73.37,104.73 73.24,104.6 72.52,104.6 72.39,104.47 72.39,104.29 72.52,104.16 73.24,104.16 73.37,104.03 73.37,102.58 71.37,100.58 71.37,85.73 76.83,80.26 76.83,72.59 77.34,72.09 77.34,65.53 80.9,61.98 81.41,61.98 81.83,61.55 84.99,61.55 v1(85.38,61.16)
  BOTTOM w0.132: EXP_P2.25 v1(74.58,117.17)
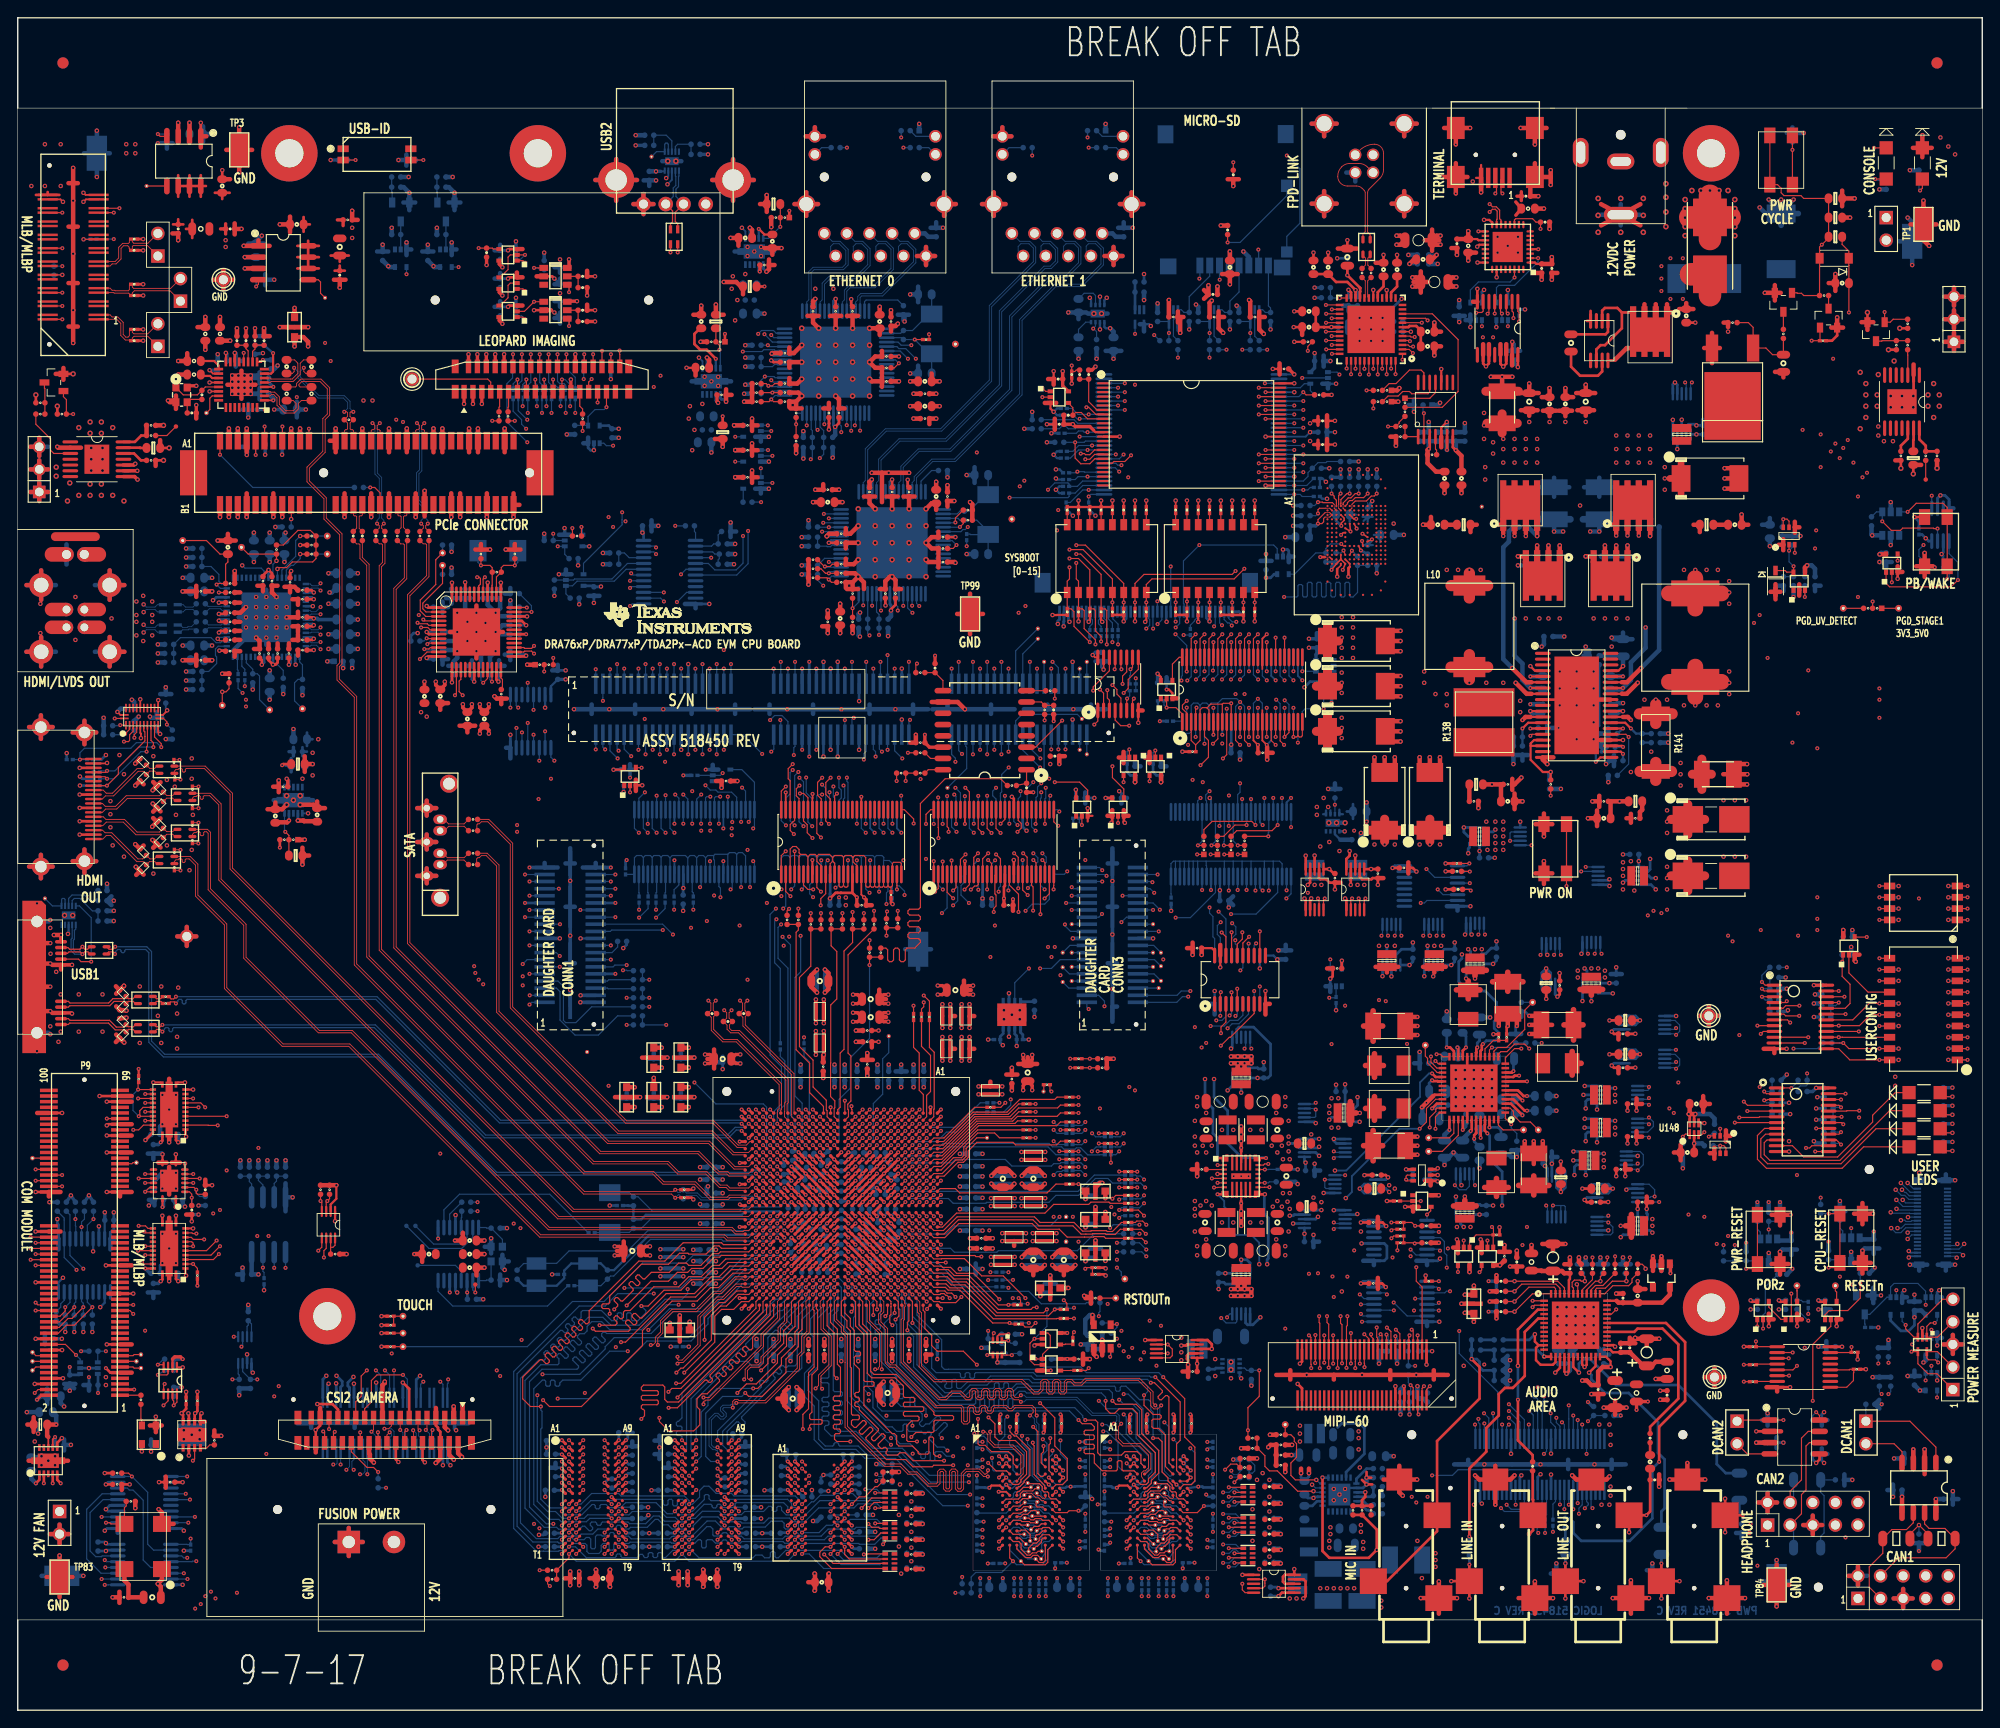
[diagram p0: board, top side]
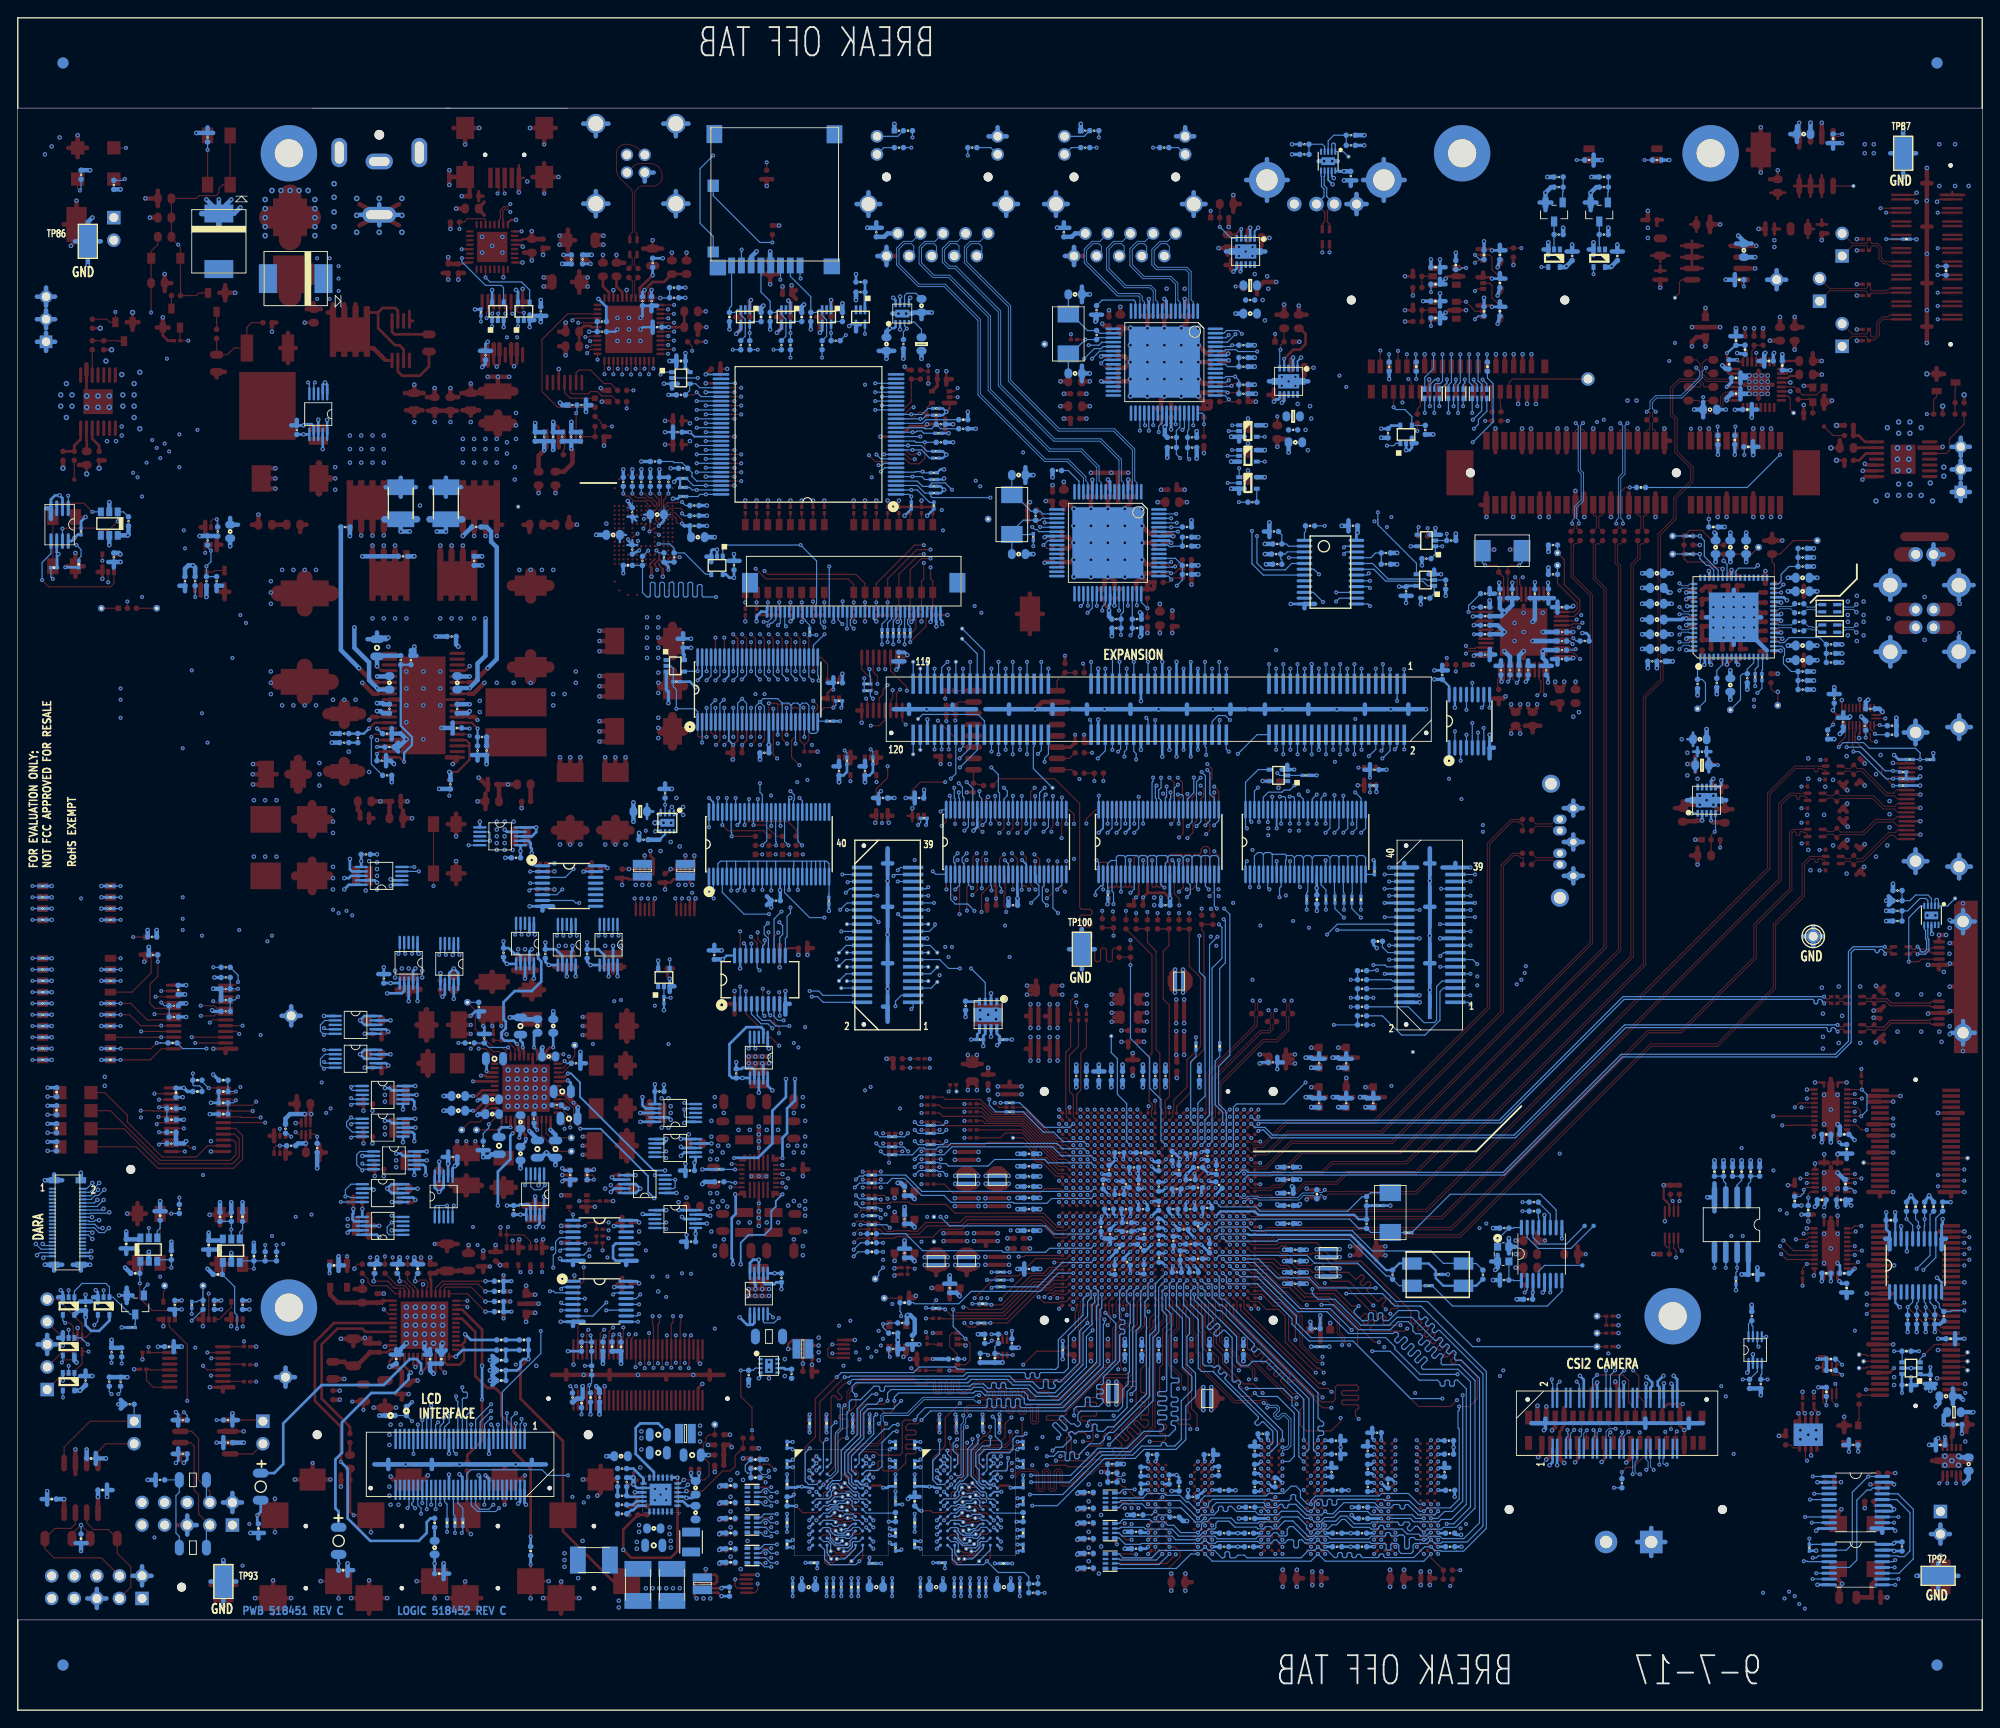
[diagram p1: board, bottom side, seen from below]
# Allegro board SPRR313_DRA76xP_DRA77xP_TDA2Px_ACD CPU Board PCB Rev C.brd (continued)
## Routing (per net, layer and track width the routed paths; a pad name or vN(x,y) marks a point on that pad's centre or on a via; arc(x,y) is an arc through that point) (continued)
H_VIN1_HSYNC: length 69.9
  TOP w0.132: U42.AC10 v1(85.38,60.36)
  L12-SIGNAL w0.089: v1(64.98,117.09) 64.98,116.78 64.9,116.7 64.9,111.76 65.41,111.25 65.41,106.3 67.18,104.52 67.18,103 69.72,100.46 69.72,99.44 69.44,99.16 69.44,97.69 70.87,96.27 70.87,85.6 74.3,82.17 74.3,74.04 76.83,71.5 76.83,65.15 81.21,60.78 84.97,60.78 v1(85.38,60.36)
  BOTTOM w0.132: EXP_P2.1 v1(64.98,117.09)
H_VIN1_VSYNC: length 69.8
  TOP w0.132: U42.AD7 v1(84.58,62.76)
  L12-SIGNAL w0.089: v1(76.07,70.61) 73.66,73.03 73.66,74.93 72.26,76.33 72.26,83.91 69.98,86.2 69.98,88.39 70.48,88.9 70.48,90.17 68.83,91.82 68.83,93.85 69.98,95 69.98,96.01 66.42,99.57 66.42,100.16 66.29,100.29 66.04,100.29 65.91,100.42 65.91,100.61 66.04,100.74 66.29,100.74 66.42,100.87 66.42,101.07 66.29,101.2 65.28,101.2 65.15,101.33 65.15,101.52 65.28,101.65 66.29,101.65 66.42,101.78 66.42,101.96 66.29,102.09 65.28,102.09 65.15,102.22 65.15,102.41 65.28,102.54 66.29,102.54 66.42,102.67 66.42,102.85 66.29,102.98 65.28,102.98 65.15,103.11 65.15,103.3 65.28,103.43 66.29,103.43 66.42,103.56 66.42,103.74 66.29,103.87 65.28,103.87 65.15,104 65.15,104.18 65.28,104.31 66.29,104.31 66.42,104.44 66.42,104.65 64.98,106.09 v1(64.98,108.08)
  BOTTOM w0.132: v1(76.07,70.61) 78.49,68.2 83.82,68.2 84.18,67.83 84.18,63.16 v1(84.58,62.76) ; EXP_P2.2 v1(64.98,108.08)
H_VIN1A_CLK: length 71
  TOP w0.132: U42.AD8 v1(84.58,61.96)
  L14-SIGNAL w0.109: v1(87.25,107.44) 86.85,107.44 86.72,107.31 84.2,107.31 83.28,106.39 82.08,106.39 81.92,106.23 81.92,106.01 82.08,105.85 83.28,105.85 83.44,105.69 83.44,105.46 83.28,105.3 82.08,105.3 81.92,105.14 81.92,104.91 82.08,104.75 83.28,104.75 83.44,104.59 83.44,104.37 83.28,104.21 82.08,104.21 81.92,104.05 81.92,103.82 82.08,103.66 83.28,103.66 83.44,103.5 83.44,103.28 83.28,103.12 82.08,103.12 81.92,102.96 81.92,102.73 82.08,102.57 83.28,102.57 83.44,102.41 83.44,102.18 83.28,102.02 82.08,102.02 81.92,101.86 81.92,101.64 82.08,101.48 83.28,101.48 83.44,101.32 83.44,99.06 81.53,97.16 81.53,93.22 81.79,92.96 81.79,83.44 82.68,82.55 82.68,79.63 81.79,78.74 81.79,72.39 81.28,71.88 81.28,68.58 80.14,67.44 80.14,63.37 81.15,62.36 84.18,62.36 v1(84.58,61.96)
  BOTTOM w0.132: v1(87.25,107.44) 87.25,108.28 87.38,108.41 EXP_P2.48
H_VIN1B_CLK: length 70.3
  TOP w0.132: U42.AC8 v1(85.38,61.96)
  L7-SIGNAL w0.089: v1(98.59,117.17) 97.79,116.37 97.79,112.58 97.66,112.45 97.16,112.45 97.03,112.32 97.03,112.14 97.16,112.01 97.66,112.01 97.79,111.88 97.79,111.69 97.66,111.56 97.16,111.56 97.03,111.43 97.03,111.25 97.16,111.12 97.66,111.12 97.79,110.99 97.79,110.8 97.66,110.67 97.16,110.67 97.03,110.54 97.03,110.36 97.16,110.23 97.66,110.23 97.79,110.1 97.79,109.47 98.3,108.97 98.3,107.82 91.44,100.97 89.53,100.97 88.9,100.33 88.9,98.93 88,98.04 88,95.97 85.22,93.19 85.22,90.81 83.57,89.15 83.57,79.38 84.71,78.23 84.71,71.88 86.23,70.36 86.23,68.83 85.76,68.36 85.76,62.34 v1(85.38,61.96)
  BOTTOM w0.132: EXP_P2.75 v1(98.59,117.17)
H_VIN2_CLK: length 64.5
  TOP w0.132: RU4.4 123.37,111.37 124,110.74 v1(124.95,110.74) ; U42.F1 v1(99.79,67.57)
  L14-SIGNAL w0.109: v1(124.95,110.74) 124.95,109.97 122.17,107.19 122.17,103.89 121.54,103.25 121.54,101.35 120.78,100.58 119,100.58 118.17,99.75 118.17,98.48 116.59,96.9 108.84,96.9 108.57,96.63 108.57,94.98 107.44,93.85 107.42,93.85 107.37,93.79 104.28,93.79 101.6,91.11 101.6,87.88 99.79,86.07 v1(99.79,67.57)
H_VIN2_D0: length 29.4
  TOP w0.132: RU8.2 103.48,92.43 v1(103.12,92.08) ; U42.F2 v1(99.79,66.77)
  L14-SIGNAL w0.109: v1(99.79,66.77) 100.18,67.16 100.18,85.96 101.98,87.76 101.98,90.93 v1(103.12,92.08)
H_VIN2_D1: length 31.3
  TOP w0.132: U42.E3 v1(100.59,65.97) ; v1(105.16,91.33) 104.48,92.01 RU8.4
  L14-SIGNAL w0.109: v1(100.59,65.97) 100.98,66.36 100.98,69.11 101.36,69.48 101.36,85.23 102.87,86.74 102.87,89.92 104.28,91.33 v1(105.16,91.33)
H_VIN2_D2: length 29.4
  TOP w0.132: v1(105.16,92.2) 105.48,92.52 RU8.6 ; U42.E1 v1(100.59,67.57)
  L14-SIGNAL w0.109: v1(100.59,67.57) 100.59,69.22 101.13,69.76 101.13,86.4 102.36,87.63 102.36,89.92 104.65,92.2 v1(105.16,92.2)
H_VIN2_D3: length 30.5
  TOP w0.132: v1(106.44,92.31) 106.98,92.85 RU8.9 ; U42.E2 v1(100.59,66.77)
  L12-SIGNAL w0.089: v1(106.44,92.31) 106.44,90.31 105.41,89.28 105.41,84.45 103.89,82.93 103.89,80.14 103.12,79.38 103.12,70.61 100.97,68.46 100.97,67.19 100.59,66.8 v1(100.59,66.77)
H_VIN2_D4: length 31.5
  TOP w0.132: U42.D2 v1(101.39,66.77) ; RU8.11 107.98,92.86 107.82,92.71 107.57,92.71 107.17,92.31 v1(107.15,92.31)
  L14-SIGNAL w0.109: v1(107.15,92.31) 105.77,90.93 104.39,90.93 103.22,89.76 103.22,86.2 102.36,85.34 102.36,69.72 101.78,69.14 101.78,67.16 v1(101.39,66.77)
H_VIN2_D5: length 32.4
  TOP w0.132: U42.F3 v1(99.79,65.97) ; v1(108.98,92.33) RU8.13
  L7-SIGNAL w0.089: v1(99.79,65.97) 100.2,66.38 100.2,67.69 100.21,67.7 100.21,67.72 105.41,72.92 105.41,87.25 108.98,90.82 v1(108.98,92.33)
H_VIN2_D6: length 31.4
  TOP w0.132: RU8.15 109.86,93.91 109.86,91.82 109.98,91.69 109.98,90.46 109.73,90.2 v1(109.73,89.79) ; U42.D1 v1(101.39,67.57)
  L12-SIGNAL w0.089: v1(109.73,89.79) 108.46,89.79 105.79,87.12 105.79,84.33 104.39,82.93 104.39,78.99 103.5,78.11 103.5,70.61 101.39,68.49 v1(101.39,67.57)
H_VIN2_D7: length 36.6
  TOP w0.132: U42.E4 v1(100.59,65.16) ; RU8.18 111.48,92.82 112.51,91.79 v1(112.51,89.79)
  L12-SIGNAL w0.089: v1(112.51,89.79) 112.12,89.4 109.34,89.4 106.17,86.23 106.17,84.2 105.25,83.28 105.25,79.09 104.39,78.23 104.39,71.12 101.85,68.58 101.85,67.44 101.57,67.15 101.22,67.15 100.97,66.9 100.97,65.55 v1(100.59,65.16)
H_VIN2_D8: length 40.5
  TOP w0.132: v1(113.54,91.69) 112.98,92.26 RU8.21 ; U42.G3 v1(98.98,65.96)
  L7-SIGNAL w0.089: v1(98.98,65.96) 99.36,66.34 99.36,68.63 100.2,69.47 100.2,72.9 102.49,75.18 102.49,85.47 107.6,90.58 107.6,91.09 108.46,91.95 108.46,92.46 108.84,92.84 110.11,92.84 111.38,91.57 111.38,90.93 111.63,90.68 112.52,90.68 v1(113.54,91.69)
H_VIN2_D9: length 40.4
  TOP w0.132: RU8.23 113.98,92.78 114.15,92.61 v1(114.15,89.94) ; U42.C5 v1(102.19,64.36)
  L14-SIGNAL w0.109: v1(102.19,64.36) 105.39,64.36 107.31,66.29 110.24,66.29 112.18,68.24 112.18,71.2 110.32,73.07 110.32,83.65 114.15,87.48 v1(114.15,89.94)
H_VIN2_D10: length 37
  TOP w0.132: U42.D3 v1(101.39,65.97) ; RU8.25 v1(114.98,89.53)
  L12-SIGNAL w0.089: v1(114.98,89.53) 114.47,89.03 109.86,89.03 106.55,85.72 106.55,84.07 105.54,83.06 105.54,71.88 102.23,68.57 102.23,66.81 v1(101.39,65.97)
H_VIN2_D11: length 41.2
  TOP w0.132: v1(115.44,91.31) 115.98,91.85 RU8.27 ; U42.F4 v1(99.79,65.16)
  L7-SIGNAL w0.089: v1(99.79,65.16) 100.16,65.54 107.05,65.54 110.34,68.83 110.99,68.83 111.37,69.22 112.01,69.22 112.27,69.47 112.27,73.66 113.54,74.93 113.92,74.93 115.44,76.45 v1(115.44,91.31)
H_VIN2_D12: length 32.2
  L14-SIGNAL w0.109: v1(111.63,68.71) 111.25,69.09 111.25,71.25 109.98,72.52 109.98,84.07 113.3,87.39 v1(113.3,89.92)
  BOTTOM w0.132: v1(111.63,68.71) 111.63,68.07 110.87,67.31 R556.1 ; v1(113.3,89.92) 113.3,89.93 114.05,90.68 115.44,90.68 115.98,91.21 RU15.2
H_VIN2_D13: length 29.4
  TOP w0.132: v1(100.7,79.25) 100.7,78.83 100.71,78.82 R176.1
  L7-SIGNAL w0.089: v1(115.44,92.33) 114.17,93.6 105.92,93.6 102.36,90.04 102.36,89.28 100.7,87.62 v1(100.7,79.25)
  BOTTOM w0.132: RU15.4 114.98,92.8 v1(115.44,92.33)
H_VIN2_D14: length 26.5
  TOP w0.132: R178.1 101.6,78.87 101.85,79.13 v1(101.85,79.63)
  L7-SIGNAL w0.089: v1(101.85,79.63) 101.47,80.01 101.47,85.72 105.79,90.04 105.79,92.58 106.55,93.34 112.7,93.34 v1(113.56,92.48)
  BOTTOM w0.132: v1(113.56,92.48) 113.85,92.77 113.85,92.77 113.98,92.9 RU15.6
H_VIN2_D15: length 28.1
  L14-SIGNAL w0.109: v1(110.36,68.33) 109.73,68.96 109.73,84.45 112.9,87.63 112.9,92.03 v1(112.48,92.46)
  BOTTOM w0.132: R554.1 v1(110.36,68.33) ; v1(112.48,92.46) RU15.9
H_VIN2_D16: length 24.2
  TOP w0.132: R177.1 102.49,79.76 v1(101.85,80.39)
  L7-SIGNAL w0.089: v1(101.85,80.39) 101.85,85.47 106.05,89.66 106.05,92.46 106.68,93.09 111,93.09 111.37,92.72 v1(111.37,92.21)
  BOTTOM w0.132: RU15.11 111.48,92.83 111.37,92.73 v1(111.37,92.21)
H_VIN2_D17: length 30.5
  TOP w0.132: v1(111.02,68.33) 110.52,67.82 R558.1
  L14-SIGNAL w0.109: v1(111.02,68.33) 110.52,67.82 109.86,67.82 108.67,69 108.67,85.94 110.37,87.64 110.37,91.94 110.27,92.04 v1(110.27,92.08)
  BOTTOM w0.132: v1(110.27,92.08) 110.27,92.49 110.48,92.7 RU15.13
H_VIN2_D18: length 38.9
  TOP w0.132: U42.D4 v1(101.38,65.16)
  L14-SIGNAL w0.109: v1(109.88,95.61) 109.88,92.48 108.97,91.57 108.97,87.12 108.2,86.36 108.2,71.5 107.57,70.87 107.57,67.44 104.9,64.77 101.78,64.77 v1(101.38,65.16)
  BOTTOM w0.132: v1(109.88,95.61) 109.48,95.21 RU15.15
H_VIN2_D19: length 30.6
  TOP w0.132: v1(103.79,65.97) U42.A3
  L14-SIGNAL w0.109: v1(103.79,65.97) 104.18,65.97 107.06,68.84 107.06,71.75 107.82,72.52 107.82,89.01 107.98,89.16 107.98,92.27 v1(107.99,92.29)
  BOTTOM w0.132: RU15.18 107.98,92.3 v1(107.99,92.29)
H_VIN2_D20: length 30.8
  TOP w0.132: v1(102.99,65.97) U42.B3
  L14-SIGNAL w0.109: v1(102.99,65.97) 102.99,67.31 103.24,67.56 103.24,67.88 103.5,68.14 103.5,79.76 106.3,82.55 106.3,90.17 v1(106.93,90.81)
  BOTTOM w0.132: v1(106.93,90.81) 106.05,91.69 106.05,92.76 106.31,93.03 106.31,93.86 RU15.21
H_VIN2_D21: length 31.1
  TOP w0.132: v1(102.99,65.16) U42.B4
  L14-SIGNAL w0.109: v1(105.16,90.53) 105.16,86.36 102.87,84.07 102.87,68.58 103.01,68.44 103.01,67.65 102.59,67.23 102.59,65.56 v1(102.99,65.16)
  BOTTOM w0.132: v1(105.16,90.53) 105.66,91.04 105.66,92.58 105.48,92.77 RU15.23
H_VIN2_D22: length 30.7
  TOP w0.132: U42.C4 v1(102.19,65.16)
  L14-SIGNAL w0.109: v1(103.9,89.66) 103.9,86.37 102.62,85.09 102.62,69.66 102.01,69.05 102.01,66.45 101.79,66.23 101.79,65.56 v1(102.19,65.16)
  BOTTOM w0.132: RU15.25 104.48,90.24 v1(103.9,89.66)
H_VIN2_D23: length 36
  TOP w0.132: v1(103.79,65.16) U42.A4
  L14-SIGNAL w0.109: v1(104,92.32) 104.39,92.71 107.31,92.71 107.57,92.46 107.57,90.55 106.81,89.79 106.81,82.3 105.54,81.03 105.54,78.49 104.39,77.34 104.39,72.26 103.89,71.76 103.89,68.33 104.18,68.03 104.18,67.4 103.95,67.17 103.63,67.17 103.39,66.93 103.39,65.56 v1(103.79,65.16)
  BOTTOM w0.132: RU15.27 103.48,92.83 v1(104,92.32)
H_VIN2_DE: length 66.4
  TOP w0.132: RU4.7 125.32,113.54 125.48,113.69 v1(125.48,113.79) ; U42.G2 v1(98.99,66.77)
  L14-SIGNAL w0.109: v1(125.48,113.79) 125.48,112.52 124.46,111.51 124.46,109.98 121.79,107.31 121.79,104.14 117.86,100.2 117.86,98.81 116.33,97.28 108.2,97.28 107.44,96.52 107.44,95.38 106.17,94.11 104.14,94.11 101.29,91.25 101.29,88.08 99.31,86.11 99.31,73.66 98.81,73.15 98.81,68.71 99.38,68.13 99.38,67.16 v1(98.99,66.77)
H_VIN2_HSYNC: length 68.1
  TOP w0.132: U42.G1 v1(98.99,67.57) ; v1(124.33,114.43) 124.84,114.94 124.84,115.95 125.97,117.08 RU4.9
  L14-SIGNAL w0.109: v1(124.33,114.43) 123.97,114.07 123.97,113.43 121.43,110.89 121.43,104.28 117.47,100.33 117.47,99.42 115.71,97.66 107.39,97.66 106.05,96.32 106.05,96.01 104.52,94.49 104.01,94.49 100.97,91.44 100.97,88.39 98.93,86.36 98.93,74.04 98.56,73.67 98.56,68.44 98.99,68.02 v1(98.99,67.57)
H_VIN2_VSYNC: length 71.1
  TOP w0.132: U42.E5 v1(100.59,64.36) ; v1(124.08,117.09) 124.02,117.15 RU4.12
  L14-SIGNAL w0.109: v1(124.08,117.09) 124.08,116.33 125.92,114.49 125.92,112.2 125.48,111.76 125.48,109.98 122.49,106.99 122.49,103.76 121.88,103.15 121.88,100.67 117.09,95.89 117.09,89.79 113.28,85.98 113.28,76.2 113.03,75.95 113.03,74.42 112.52,73.91 112.52,67.94 110.36,65.79 107.57,65.79 105.75,63.97 100.98,63.97 v1(100.59,64.36)
H_VIN2B_CLK1: length 46.7
  TOP w0.132: U42.AA5 v1(86.98,64.36)
  L10-SIGNAL w0.089: v1(86.98,64.36) 86.58,64.77 71.12,64.77 68.2,67.69 68.2,69.98 66.93,71.25 64.39,71.25 61.09,74.55 61.09,80.52 59.56,82.04 59.56,84 v1(57.53,86.03)
  BOTTOM w0.132: EXP_P1.17 v1(57.53,86.03)
H_VIN2B_HSYNC1: length 65.5
  TOP w0.132: U42.AC5 v1(85.38,64.36)
  L3-SIGNAL w0.109: v1(85.84,91.58) 86.25,91.17 87.87,91.17 88.77,92.08 88.77,92.58 89.41,93.22 116.33,93.22 117.93,91.62 v1(118.49,91.62)
  L12-SIGNAL w0.089: v1(85.84,91.58) 84.58,90.31 84.58,72.64 85.98,71.25 85.98,68.45 85.79,68.27 85.79,64.77 85.39,64.36 v1(85.38,64.36)
  BOTTOM w0.132: EXP_P3.31 v1(118.49,91.62)
H_VIN2B_VSYNC1: length 64.7
  TOP w0.132: U42.AB4 v1(86.18,65.16)
  L3-SIGNAL w0.109: v1(118.49,92.58) 117.6,93.47 87.09,93.47 85.96,92.34 v1(85.86,92.34)
  L7-SIGNAL w0.089: v1(86.18,65.16) 86.61,65.59 86.61,66.12 86.61,66.13 86.61,70.87 85.34,72.14 85.34,78.99 84.75,79.59 84.75,89.15 85.61,90.01 85.61,90.26 86.22,90.87 86.22,91.98 v1(85.86,92.34)
  BOTTOM w0.132: v1(118.49,92.58) 118.67,92.41 EXP_P3.33
H_VIN[5]A_D[8]: length 14.9
  BOTTOM w0.132: EXP_P1.5 60.56,81.23 60.96,80.83 60.96,77.63 62.64,75.95 65.28,75.95 67.44,78.11 R543.2
H_VIN[5]A_D[9]: length 4.3
  BOTTOM w0.132: R536.2 66.37,81.15 66.3,81.23 EXP_P1.6
H_VIN[5]A_D[10]: length 14.9
  BOTTOM w0.132: EXP_P1.7 60.73,82.02 61.34,81.41 61.34,77.6 61.59,77.34 62.74,77.34 64.52,79.12 R542.2
H_VIN[5]A_D[11]: length 4.3
  BOTTOM w0.132: R539.2 66.45,82.17 66.3,82.02 EXP_P1.8
H_VIN[5]A_D[12]: length 99
  TOP w0.132: U42.D17 v1(101.39,53.96)
  L3-SIGNAL w0.109: v1(109.35,84.73) 96.63,84.73 96.51,84.84 89.42,84.84 89.41,84.84 89.41,84.84 89.03,84.45 87.38,84.45 86.36,83.44 69.6,83.44 68.91,82.76 67.82,82.76 67.35,83.23 67.02,83.23 66.62,82.83 v1(57.53,82.83)
  L5-SIGNAL w0.089: v1(109.35,84.73) 113.54,80.53 113.54,77.47 114.55,76.45 114.55,69.22 110.62,65.28 110.62,55.37 v1(109.22,53.98)
  L12-SIGNAL w0.089: v1(101.39,53.96) 101.78,53.56 104.49,53.56 105.29,54.36 108.63,54.36 108.64,54.36 108.84,54.36 v1(109.22,53.98)
  BOTTOM w0.132: EXP_P1.9 v1(57.53,82.83)
H_VIN[5]A_D[13]: length 100.2
  TOP w0.132: U42.D16 v1(101.39,54.76)
  L3-SIGNAL w0.109: v1(115.82,85.85) 115.7,85.98 88.9,85.98 88.65,85.72 86.99,85.72 85.85,84.58 69.22,84.58 68.58,85.22 67.49,85.22 v1(66.67,86.03)
  L5-SIGNAL w0.089: v1(115.82,85.85) 115.83,85.85 115.83,70.99 117.73,69.09 117.73,58.8 116.46,57.53 v1(116.46,55.5)
  L12-SIGNAL w0.089: v1(116.46,55.5) 116.08,55.12 105.16,55.12 104.2,54.16 102.53,54.16 102.35,54.35 101.8,54.35 v1(101.39,54.76)
  BOTTOM w0.132: v1(66.67,86.03) EXP_P1.18
H_VIN[5]A_D[14]: length 101.3
  TOP w0.132: U42.A20 v1(103.79,51.56)
  L10-SIGNAL w0.089: v1(103.79,51.56) 104.17,51.95 104.17,52.93 102.75,54.35 81.91,54.35 81.41,53.85 56.9,53.85 v1(56.52,54.23)
  L12-SIGNAL w0.089: v1(60.93,83.62) 58.67,81.36 58.67,80.08 58.8,79.95 60.45,79.95 60.58,79.82 60.58,79.64 60.45,79.51 58.8,79.51 58.67,79.38 58.67,79.19 58.8,79.06 60.45,79.06 60.58,78.93 60.58,78.75 60.45,78.62 58.8,78.62 58.67,78.49 58.67,78.3 58.8,78.17 60.45,78.17 60.58,78.04 60.58,77.86 60.45,77.73 58.8,77.73 58.66,77.58 58.66,77.4 59.43,76.63 59.43,76.45 59.3,76.32 59.11,76.32 58.35,77.08 58.16,77.08 58.03,76.95 58.03,76.77 58.8,76 58.8,75.82 58.67,75.69 58.49,75.69 57.72,76.46 57.53,76.46 57.4,76.33 57.4,76.14 58.17,75.37 58.17,75.19 58.04,75.06 57.86,75.06 57.09,75.83 56.9,75.83 56.52,75.44 v1(56.52,54.23)
  BOTTOM w0.132: EXP_P1.11 v1(60.93,83.62)
H_VIN[5]A_D[15]: length 100
  TOP w0.132: U42.C17 v1(102.19,53.96)
  L3-SIGNAL w0.109: v1(68.45,83.82) 86.11,83.82 87.25,84.96 89.03,84.96 89.28,85.22 110.49,85.22 110.98,84.73 v1(116.22,84.73)
  L5-SIGNAL w0.089: v1(116.22,84.73) 116.22,79.62 116.58,79.26 116.58,70.88 118.11,69.34 118.11,57.4 118.62,56.9 v1(118.62,55.5)
  L12-SIGNAL w0.089: v1(102.19,53.96) 104.51,53.96 105.28,54.74 117.86,54.74 v1(118.62,55.5)
  BOTTOM w0.132: v1(68.45,83.82) 67.13,83.82 66.93,83.62 EXP_P1.12
H_WKUP_0: length 65.4
  TOP w0.132: U42.AB19 v1(86.18,52.36) ; U40.19 v1(140.21,60.82)
  L7-SIGNAL w0.089: v1(140.21,60.82) 134.12,54.74 131.57,54.74 126.62,49.78 v1(123.57,49.78) 123.25,50.11 121.74,50.11 120.78,49.15 118.75,49.15 118.24,49.66 109.07,49.66 108.63,49.22 105.75,49.22 105.73,49.23 104.44,49.23 103.34,50.34 102.34,50.34 100.03,50.34 99.98,50.39 99.63,50.39 99.41,50.61 99.41,50.96 99.19,51.17 87.62,51.17 87.61,51.18 87.36,51.18 v1(86.18,52.36)
  BOTTOM w0.132: v1(140.21,60.82) 140.62,60.82 140.63,60.83 R712.1 ; v1(123.57,49.78) 124.06,49.29 124.06,48.91 TP74.1
H_WKUP_1: length 249.4
  TOP w0.132: U38.26 159.55,72.23 158.88,72.9 v1(158.88,73.53) ; R242.1 TP69.1 ; U42.AC20 v1(85.38,51.56)
  L3-SIGNAL w0.109: v1(85.38,51.56) 85.34,51.56 84.94,51.16 80.75,51.16 80.64,51.05 75.82,51.05 75.18,50.42 65.41,50.42 v1(56.64,41.66)
  L10-SIGNAL w0.089: v1(56.64,41.66) 46.61,41.66 45.85,42.42 TP69.1 ; v1(158.5,24) 158.5,28.45 159.64,29.59 159.64,35.81 160.66,36.83 160.66,45.85 161.42,46.61 161.42,48.13 158.12,51.44 158.12,54.23 156.97,55.37 156.97,61.85 156.72,62.1 156.72,71.37 v1(158.88,73.53)
  L14-SIGNAL w0.109: v1(158.5,24) 158.5,19.56 150.5,11.56 57.02,11.56 49.4,19.18 49.4,24.89 53.09,28.57 53.09,38.1 v1(56.64,41.66)
H_X0_OSC1: length 32.8
  TOP w0.132: U42.AB18 v1(86.18,53.96)
  BOTTOM w0.132: C518.1 56.88,50.25 Y7.1 58.34,50.27 60.58,50.27 61.98,51.66 68.55,51.66 70.83,53.94 82.16,53.94 82.58,54.36 82.81,54.36 82.82,54.36 85.55,54.36 85.6,54.31 85.84,54.31 v1(86.18,53.96)
H_XI_OSC0: length 22.7
  TOP w0.132: U42.AB16 v1(86.18,54.76)
  BOTTOM w0.132: R234.1 66.52,53.72 Y5.2 68.76,53.75 C474.1 70.1,54.2 71.15,55.24 82.65,55.24 82.73,55.16 85.78,55.16 v1(86.18,54.76)
H_XI_OSC1: length 25.8
  TOP w0.132: U42.AC19 v1(85.38,53.16)
  BOTTOM w0.132: v1(85.38,53.16) 84.98,52.76 79.32,52.76 79.12,52.96 71.12,52.96 67,48.84 66.65,48.84 C517.1 65.55,47.75 Y7.3 64.1,47.75 R247.1
H_XO_OSC0: length 21.5
  TOP w0.132: U42.AB14 v1(86.18,57.16)
  BOTTOM w0.132: Y5.1 68.76,58.22 C457.1 69.72,57.76 71.35,56.13 81.18,56.13 81.66,56.62 85.63,56.62 v1(86.18,57.16)
H_XREF_CLK1: length 52.3
  TOP w0.132: RU6.2 v1(123.7,99.8)
  L12-SIGNAL w0.089: v1(123.7,99.8) 124.43,99.06 127,99.06 129.16,96.9 129.16,88.77 129.41,88.52 129.41,57.66 126.75,55 126.49,55 v1(126.1,54.61)
  BOTTOM w0.132: R596.2 v1(126.1,54.61)
H_XREF_CLK2: length 222.8
  L10-SIGNAL w0.089: v1(42.04,40.13) 42.93,39.24 49.28,39.24 52.32,36.2 65.15,36.2 66.17,35.18 73.41,35.18 73.91,35.69 77.6,35.69 78.23,35.05 90.17,35.05 91.57,36.45 111,36.45 113.67,39.12 v1(113.67,43.56)
  L12-SIGNAL w0.089: v1(42.04,40.13) 42.04,45.47 39.75,47.75 39.75,57.66 27.56,69.85 27.56,115.32 26.92,115.95 21.97,115.95 20.32,117.6 20.32,122.17 6.22,136.27 6.22,137.16 6.48,137.41 6.48,138.81 5.71,139.57 5.71,161.72 v1(5,162.43)
  BOTTOM w0.132: R613.2 v1(113.67,43.56) ; 4.06,162.43 v1(5,162.43)
HDMI_CEC_A: length 151.2
  TOP w0.132: U19.24 10.9,111.56 v1(10.9,111.56) ; U42.B19 v1(102.99,52.36)
  L7-SIGNAL w0.089: v1(28.19,53.34) 27.43,52.58 26.54,52.58 23.24,55.88 23.24,58.42 22.61,59.05 22.61,59.82 22.1,60.32 22.1,67.06 22.61,67.56 22.61,106.93 21.97,107.57 15.75,107.57 15.59,107.73 15.02,107.73 14.73,107.44 12.32,107.44 10.67,109.09 10.67,110.95 10.9,111.18 v1(10.9,111.56)
  L10-SIGNAL w0.089: v1(28.19,53.34) 29.21,52.32 54.1,52.32 54.55,52.77 102.57,52.77 v1(102.99,52.36)
HDMI_CEC_B: length 10.9
  TOP w0.132: P7.13 v1(10.02,104) 11.3,105.28 11.3,106.05 14.29,109.03 14.29,109.53 14.29,109.53 14.29,110.04 14.17,110.16 U19.6
  BOTTOM w0.132: R494.1 9.25,104 v1(10.02,104)
HDMI_CT_HPD: length 162.1
  TOP w0.132: U19.11 16.38,111.56 16.76,111.18 v1(16.76,110.87)
  L3-SIGNAL w0.109: v1(128.78,84.45) 116.71,84.45 116.46,84.2 96.52,84.2 96.14,84.58 89.53,84.58 89.03,84.07 88.01,84.07 86.97,83.04 74.02,83.04 72.5,81.51 63.52,81.51 62.89,82.15 57.17,82.15 v1(56.77,82.55)
  L5-SIGNAL w0.089: v1(126.62,57.91) 127.89,59.18 127.89,79.38 129.03,80.52 129.03,84.2 v1(128.78,84.45) ; v1(16.76,110.87) 20.57,110.87 27.81,103.63 27.81,95.12 36.58,86.36 52.96,86.36 v1(56.77,82.55)
  BOTTOM w0.132: R582.1 125.69,57.53 125.69,57.53 126.23,57.53 v1(126.62,57.91) ; R470.2 17.35,110.3 16.77,110.87 v1(16.76,110.87)
HDMI_DSCL: length 176
  TOP w0.132: v1(11.52,110.81) 12.15,110.81 U19.1
  L3-SIGNAL w0.109: v1(56.13,98.81) 59.56,95.38 66.8,95.38 67.94,94.23 80.65,94.23 82.42,96.01 83.82,96.01 84.63,95.2 86.01,95.2 86.98,94.23 116.22,94.23 118.65,96.66 122.28,96.66 124.46,94.49 143.64,94.49 144.27,93.85 153.51,93.85 155.03,92.33 v1(159.64,92.33)
  L7-SIGNAL w0.089: v1(56.13,98.81) 55.24,99.69 55.24,108.46 54.23,109.47 54.23,112.65 52.32,114.55 44.23,114.55 40.25,110.57 31.96,110.57 31.24,109.86 18.67,109.86 17.4,108.58 16.42,108.58 16.24,108.76 15.14,108.76 14.96,108.58 12.95,108.58 12.21,109.33 11.83,109.33 11.56,109.6 11.56,110.4 11.52,110.44 v1(11.52,110.81)
  BOTTOM w0.132: R467.1 11.45,110.74 v1(11.52,110.81) ; v1(159.64,92.33) 160.23,91.73 RU19.6
HDMI_DSDA: length 175.9
  TOP w0.132: v1(12.06,109.83) 12.57,110.33 U19.2
  L3-SIGNAL w0.109: v1(158.37,94.61) 158.12,94.87 156.59,94.87 155.91,94.19 145.2,94.19 144.53,94.87 139.83,94.87 139.81,94.85 139.48,94.85 139.47,94.87 124.71,94.87 122.56,97.03 118.62,97.03 116.08,94.49 87.06,94.49 86.11,95.44 84.9,95.44 84.07,96.27 82.17,96.27 80.64,94.74 67.94,94.74 66.93,95.76 60.35,95.76 56.54,99.57 v1(56.13,99.57)
  L7-SIGNAL w0.089: v1(56.13,99.57) 56.13,108.2 54.61,109.73 54.61,114.17 53.85,114.94 44.2,114.94 40.04,110.78 19.08,110.78 17.13,108.83 16.47,108.83 16.32,108.97 14.1,108.97 13.97,108.84 13.06,108.84 v1(12.06,109.83)
  BOTTOM w0.132: R472.1 11.96,109.73 v1(12.06,109.83) ; v1(158.37,94.61) 159.3,93.69 RU19.3
HDMI_HPD: length 149.8
  TOP w0.132: U42.B20 v1(102.99,51.56) ; U19.3 12.97,110.12 12.57,109.73 12.57,109.09 12.44,108.95 v1(11.94,108.95)
  L7-SIGNAL w0.089: v1(11.94,108.95) 12.81,108.08 14.2,108.08 14.32,108.2 14.84,108.2 15.08,107.96 22.09,107.96 22.99,107.06 22.99,66.55 23.75,65.79 23.75,62.36 22.99,61.59 22.99,59.31 26.92,55.37 v1(26.92,53.34)
  L10-SIGNAL w0.089: v1(26.92,53.34) 27.69,54.1 28.7,54.1 29.26,53.55 102.66,53.55 103.38,52.83 103.38,51.95 v1(102.99,51.56)
HDMI_HPD_B: length 16.5
  TOP w0.132: U19.9 15.37,109.47 16.13,108.72 v1(16.13,108.33) ; v1(6.99,106.93) 7.05,107 P7.19
  BOTTOM w0.132: v1(16.13,108.33) 15.62,108.84 13.34,108.84 12.7,108.2 7.49,108.2 6.99,107.7 v1(6.99,106.93) ; v1(6.99,106.93) R484.1 ; v1(6.99,106.93) R483.2
HDMI_LS_OE: length 149.5
  TOP w0.132: v1(13.11,109.39) 13.09,109.41 13.09,109.73 13.37,110.01 U19.4 ; v1(119.25,61.1) 119.24,61.09 R580.1
  L3-SIGNAL w0.109: v1(117.22,82.68) 116.06,83.84 96.38,83.84 96,84.22 89.68,84.22 89.15,83.69 88.14,83.69 87.12,82.68 74.17,82.68 72.64,81.15 63.37,81.15 62.74,81.79 57.02,81.79 v1(56.77,81.53)
  L5-SIGNAL w0.089: v1(13.11,109.39) 13.13,109.39 14.1,110.36 20.19,110.36 27.05,103.5 27.05,94.87 36.2,85.72 52.58,85.72 v1(56.77,81.53) ; v1(117.22,82.68) 116.97,82.42 116.97,80.64 117.47,80.14 117.47,71.37 118.87,69.98 118.87,61.49 v1(119.25,61.1)
  BOTTOM w0.132: R466.2 13.09,110.22 13.09,109.41 v1(13.11,109.39)
HDMI_SCL_B: length 11.1
  TOP w0.132: v1(14.48,107.82) 14.48,108.36 14.57,108.46 U19.7 ; P7.15 9.81,105 v1(10.03,104.78)
  BOTTOM w0.132: v1(14.48,107.82) 13.84,107.82 10.79,104.78 v1(10.03,104.78) R491.1
HDMI_SDA_B: length 11.3
  TOP w0.132: U19.8 14.97,109.09 15.24,108.83 v1(15.24,108.33) ; P7.16 9.87,105.5 v1(10.03,105.66)
  BOTTOM w0.132: R487.1 9.36,105.66 v1(10.03,105.66) 10.92,105.66 13.59,108.33 v1(15.24,108.33)
HDMI_TX0+: length 10.5
  TOP w0.099: P7.7 9.5,101 9.88,101.37 11.12,101.37 12.32,102.57 15.99,102.57 U26.1 16.74,102.59 17.42,102.59 17.68,102.34 FL4.2
HDMI_TX0-: length 10.5
  TOP w0.099: FL4.3 17.68,103.15 17.42,102.9 16.74,102.9 U25.1 15.94,102.87 12.19,102.87 11,101.67 9.83,101.67 9.51,102 P7.9
HDMI_TX1+: length 10.6
  TOP w0.099: P7.4 9.55,99.49 9.95,99.9 11.86,99.9 13.28,98.48 16.02,98.48 U29.1 16.74,98.53 17.42,98.53 17.68,98.27 FL5.2
HDMI_TX1-: length 10.6
  TOP w0.099: FL5.3 17.68,99.09 17.42,98.83 16.74,98.83 U28.1 15.92,98.78 13.41,98.78 11.99,100.2 9.91,100.2 9.61,100.5 P7.6
HDMI_TX2+: length 9.2
  TOP w0.099: P7.1 9.55,97.99 9.96,98.4 10.44,98.4 13.39,95.45 14.09,95.45 U32.1 14.81,95.45 15.42,95.45 15.65,95.22 FL6.2
HDMI_TX2-: length 9.2
  TOP w0.099: FL6.3 15.65,96.04 15.37,95.76 14.86,95.76 U31.1 14.04,95.76 13.51,95.76 10.57,98.7 9.81,98.7 9.53,98.99 P7.3
HDMI_TXC+: length 9.1
  TOP w0.099: FL3.2 15.65,105.38 15.39,105.64 14.83,105.64 U24.1 14.09,105.61 13.54,105.61 10.77,102.84 9.85,102.84 9.5,102.5 P7.10
HDMI_TXC-: length 9.2
  TOP w0.099: P7.12 9.6,103.5 9.95,103.15 10.64,103.15 13.41,105.92 14.04,105.92 U22.1 14.83,105.94 15.39,105.94 15.65,106.2 FL3.3
I2C2_SCL_PM: length 85.5
  TOP w0.132: R163.2 163.22,94.36 v1(163.25,94.34) ; R268.2 v1(194.06,38.86)
  L10-SIGNAL w0.089: v1(194.06,38.86) 194.56,39.37 194.56,43.56 195.58,44.58 195.58,54.99 194.56,56.01 194.56,57.4 194.83,57.67 194.83,71.36 192.28,73.91 v1(192.28,87.12)
  L14-SIGNAL w0.109: v1(163.25,94.34) 168.17,94.34 173.48,89.03 179.32,89.03 181.23,87.12 v1(192.28,87.12)
  BOTTOM w0.132: v1(163.25,94.34) RU19.2
I2C2_SDA_PM: length 86.7
  TOP w0.132: 162.43,92.33 163.22,92.33 v1(163.35,92.2) ; R271.2 v1(194.06,36.96)
  L10-SIGNAL w0.089: v1(192.79,86.49) 192.79,74.17 195.2,71.75 195.2,57.66 194.94,57.4 194.94,56.26 195.83,55.37 195.83,44.2 194.94,43.31 194.94,37.85 v1(194.06,36.96)
  L14-SIGNAL w0.109: v1(163.35,92.2) 168.91,92.2 172.85,88.27 179.07,88.27 180.85,86.49 v1(192.79,86.49)
  BOTTOM w0.132: RU19.5 163.16,92.38 v1(163.35,92.2)
I2C3_SCL: length 211
  TOP w0.132: RU24.4 v1(161.91,49.29)
  L10-SIGNAL w0.089: v1(161.91,49.29) 161.91,46.59 161.04,45.72 161.04,36.7 160.02,35.69 160.02,29.21 159.51,28.7 159.51,26.16 159.13,25.78 159.13,24 158.5,23.37 158.12,23.37 157.48,24 v1(156.72,24)
  L12-SIGNAL w0.089: v1(54.23,37.59) 54.23,38.06 54.24,38.07 54.24,76.08 v1(57.53,79.38)
  L14-SIGNAL w0.109: v1(54.23,37.59) 54.23,28.19 50.67,24.64 50.67,20.07 58.42,12.32 141.99,12.32 142.75,13.08 150.5,13.08 154.31,16.89 154.31,21.59 v1(156.72,24)
  BOTTOM w0.132: v1(57.53,79.38) 57.78,79.63 EXP_P1.1
I2C3_SDA: length 215.1
  TOP w0.132: v1(164.34,49.28) 164.58,49.51 RU25.4
  L10-SIGNAL w0.089: v1(157.23,23.37) 157.48,23.37 157.99,22.86 158.75,22.86 159.38,23.5 159.38,25.53 159.89,26.04 159.89,28.57 160.4,29.08 160.4,32.13 163.96,35.69 163.96,42.42 164.34,42.8 v1(164.34,49.28)
  L12-SIGNAL w0.089: v1(57.56,80.42) 53.85,76.71 v1(53.85,38.23)
  L14-SIGNAL w0.109: v1(53.85,38.23) 53.57,37.95 53.57,28.29 50.04,24.77 50.04,19.68 57.78,11.94 142.72,11.94 142.73,11.93 144.79,11.93 144.81,11.94 149.86,11.94 155.07,17.14 155.07,17.53 158.12,20.57 158.12,22.48 v1(157.23,23.37)
  BOTTOM w0.132: EXP_P1.3 v1(57.56,80.42)
I2C_EEPROM_WP: length 305.8
  TOP w0.132: SW6.11 v1(209.3,84.58)
  L3-SIGNAL w0.109: v1(27.56,49.78) 26.8,49.78 23.37,46.35 23.37,33.4 22.1,32.13 22.1,15.75 20.57,14.22 v1(20.57,11.94)
  L10-SIGNAL w0.089: v1(209.3,84.58) 207.9,83.19 207.9,64.26 205.87,62.23 205.87,55.88 206.63,55.12 206.63,50.67 205.86,49.9 205.86,44.71 207.65,42.93 207.65,39.5 205.99,37.85 205.99,27.56 208.28,25.27 208.28,20.07 207.14,18.92 157.99,18.92 157.48,18.41 156.72,18.41 149.61,11.3 21.97,11.3 21.34,11.94 v1(20.57,11.94)
  BOTTOM w0.132: 27.56,51.52 v1(27.56,49.78) 27.56,49.38 27.69,49.25 R702.2
ISO_FTDI_UARTIN: length 2.1
  TOP w0.132: RU2.4 166.7,157.28 166.85,157.12 v1(166.85,157.1)
  BOTTOM w0.132: U142.2 166.88,156.59 166.85,156.62 v1(166.85,157.1)
ISO_FTDI_UARTOUT: length 2.7
  TOP w0.132: RU2.7 164.74,157.38 164.59,157.23 163.99,157.23 v1(163.96,157.19)
  BOTTOM w0.132: U143.2 v1(163.96,157.19)
LDOVANA: length 3.4
  TOP w0.305: U38.43 163.95,65.37 163.96,65.36 163.96,64.94 163.95,64.93 163.95,64.9 163.74,64.68 v1(163.74,64.26)
  BOTTOM w0.305: v1(163.74,64.26) 163.74,63.97 C423.1
LDOVRTC: length 3.7
  TOP w0.305: v1(164.47,64.39) 164.47,64.89 164.45,64.9 U38.44 ; R545.2 v2(165.9,76.03)
  BOTTOM w0.305: v1(164.47,64.39) 164.47,64.64 164.34,64.77 C414.1
LP87565_REGEN_3V3: length 110.9
  TOP w0.132: U40.15 140.16,58.82 140.17,58.83 v1(140.72,58.83) ; v1(189.61,65.02) 189.36,64.77 188.99,64.76 U148.3 ; Q19.2 v1(191.39,65.41)
  L7-SIGNAL w0.089: v1(189.61,65.02) 189.99,65.41 v1(191.39,65.41) ; v1(150.24,98.93) 150.24,101.09 149.48,101.85 v1(148.08,101.85)
  L10-SIGNAL w0.089: v1(140.72,58.83) 142.08,60.2 144.27,60.2 145.29,61.21 145.29,63.88 146.43,65.02 146.43,69.72 150.11,73.41 150.11,89.03 152.02,90.93 152.02,93.47 151.26,94.23 151.26,97.92 150.91,98.27 150.83,98.27 150.59,98.51 150.59,98.58 v1(150.24,98.93)
  L14-SIGNAL w0.109: v1(189.61,65.02) 185.17,65.02 183.26,63.12 179.45,63.12 179.2,63.37 173.99,63.37 173.74,63.12 167.26,63.12 165.99,61.85 159.39,61.85 157.73,60.2 155.57,60.2 154.56,61.21 147.07,61.21 146.81,60.96 144.65,60.96 144.27,61.34 143.64,61.34 143.13,60.83 142.75,60.83 140.75,58.83 v1(140.72,58.83)
  BOTTOM w0.132: U119.3 v1(148.08,101.85) 148.08,102.49 R711.2
LPD_SPI[1]_CS[0]N: length 165
  TOP w0.132: J8.34 v1(66.68,152.53)
  L3-SIGNAL w0.109: v1(19.05,17.14) 18.29,17.14 17.4,18.03 17.4,31.37 18.54,32.51 20.7,32.51 22.61,34.42 22.61,48.39 25.27,51.05 25.27,59.18 26.54,60.45 26.54,85.98 42.55,101.98 42.55,127.38 49.15,133.99 49.15,134.03 49.16,134.04 49.16,134.39 49.15,134.4 49.15,134.62 56.64,142.11 58.55,142.11 60.83,144.4 63.37,144.4 65.79,146.81 65.79,151.63 v1(66.68,152.53)
  BOTTOM w0.132: R354.1 66.67,152.52 v1(66.68,152.53) ; v1(19.05,17.14) 18.64,17.14 18.43,17.36 RU21.3
LPD_SPI[1]_MISO: length 158.8
  TOP w0.132: J8.31 v1(65.18,147.1)
  L3-SIGNAL w0.109: v1(18.67,15.41) 16.76,17.31 16.76,32.77 18.67,34.67 20.57,34.67 22.1,36.2 22.1,48.51 24.77,51.18 24.77,60.51 25.44,61.19 25.44,85.77 42.04,102.36 42.04,128.14 58.8,144.91 62.99,144.91 v1(65.18,147.1)
  BOTTOM w0.132: RU21.6 v1(18.67,15.41)
LPD_SPI[1]_MOSI: length 172
  TOP w0.132: v1(67.66,152.94) 67.66,152.52 67.68,152.5 J8.36
  L3-SIGNAL w0.109: v1(9.78,16.89) 11.3,18.41 11.3,29.97 16.51,35.18 20.32,35.18 21.59,36.45 21.59,48.51 24.38,51.31 24.38,85.72 41.53,102.87 41.53,130.3 52.7,141.48 52.7,148.97 54.36,150.62 64.14,150.62 66.45,152.94 v1(67.66,152.94)
  BOTTOM w0.132: RU21.13 9.96,16.71 v1(9.78,16.89)
LPD_SPI[1]_SCLK: length 171.6
  TOP w0.132: J8.32 v1(65.68,152.91)
  L3-SIGNAL w0.109: v1(9.42,14.76) 8.76,15.42 8.76,28.07 17.65,36.96 18.29,36.96 21.21,39.88 21.21,48.64 24,51.44 24,86.36 41.02,103.38 41.02,131.44 51.31,141.74 51.31,144.91 51.69,145.29 51.69,148.59 54.23,151.13 63.91,151.13 v1(65.68,152.91)
  BOTTOM w0.132: RU21.10 v1(9.42,14.76)
MCA2_ACLKX: length 71.6
  L10-SIGNAL w0.089: v1(76.18,117.17) 76.77,117.17 83.48,110.45 91.61,110.45 92.08,109.98 99.95,109.98 100.59,109.34 102.14,109.34 102.15,109.35 119.89,109.35 122.14,107.1 134.58,107.1 v1(137.41,104.27)
  BOTTOM w0.132: EXP_P2.29 v1(76.18,117.17) ; RU18.44 137.15,102.98 137.41,103.25 v1(137.41,104.27)
MCA2_AFSX: length 93
  TOP w0.132: RU9.12 v1(139.64,87.61)
  L10-SIGNAL w0.089: v1(75.82,103.38) 77.22,101.98 82.04,101.98 83.57,100.46 111.51,100.46 111.89,100.08 111.89,98.68 112.52,98.04 115.7,98.04 116.97,96.77 122.81,96.77 124.71,94.87 129.92,94.87 130.94,93.85 130.94,90.3 133.3,87.93 139.32,87.93 v1(139.64,87.61)
  L14-SIGNAL w0.109: v1(75.82,103.38) 75.82,107.07 76.98,108.22 v1(76.98,117.67)
  BOTTOM w0.132: EXP_P2.31 v1(76.98,117.67)
MCA2_AXR0: length 88.3
  L10-SIGNAL w0.089: v1(80.26,99.19) 80.54,99.46 82.4,99.46 82.52,99.57 84.45,99.57 84.97,99.05 89.79,99.05 89.91,98.93 94.49,98.93 95.1,98.32 99.71,98.32 100.33,98.93 103.97,98.93 105.62,97.28 115.32,97.28 117.35,95.24 122.56,95.24 125.22,92.58 127.89,92.58 128.91,91.57 128.91,89.88 132.52,86.26 136.5,86.26 136.92,85.84 138.8,85.84 v1(139.22,86.26)
  L14-SIGNAL w0.109: v1(80.26,99.19) 79.38,100.08 79.38,103.38 79.78,103.78 79.78,113.64 79.38,114.04 v1(79.38,117.17)
  BOTTOM w0.132: v1(139.22,86.26) 139.19,86.23 139.19,86.23 139,86.04 RU20.18 ; EXP_P2.37 v1(79.38,117.17)
MCA2_AXR1: length 93
  L10-SIGNAL w0.089: v1(76.83,98.93) 77.44,99.53 77.44,100.04 78.11,100.71 82.93,100.71 83.44,100.2 110.74,100.2 111,99.95 111,99.06 112.27,97.79 115.57,97.79 116.97,96.39 122.56,96.39 124.46,94.49 129.29,94.49 130.43,93.34 130.43,90.04 133.37,87.1 137.51,87.1 v1(138.38,86.23)
  L14-SIGNAL w0.109: v1(76.83,98.93) 77.34,99.44 77.34,103.38 78.18,104.21 78.18,108.64 77.78,109.04 v1(77.78,117.17)
  BOTTOM w0.132: v1(138.38,86.23) 138.37,86.22 RU20.17 ; EXP_P2.33 v1(77.78,117.17)
MCA2_AXR2: length 88.2
  L10-SIGNAL w0.089: v1(80.26,98.42) 86.61,98.42 86.87,98.16 87.88,98.16 88.27,98.56 91.18,98.56 91.69,98.04 99.95,98.04 100.46,98.55 103.89,98.55 105.41,97.03 115.19,97.03 117.34,94.88 122.42,94.88 126.62,90.68 126.62,90.17 130.81,85.98 134.69,85.98 v1(137.45,83.22)
  L14-SIGNAL w0.109: v1(80.18,117.67) 80.18,104.1 80.77,103.5 80.77,98.93 v1(80.26,98.42)
  BOTTOM w0.132: RU20.16 137.73,83.5 v1(137.45,83.22) ; EXP_P2.39 v1(80.18,117.67)
MCA2_AXR3: length 91.1
  L10-SIGNAL w0.089: v1(136.88,86.61) 133.48,86.61 130.08,90.01 130.08,93.06 129.54,93.6 124.84,93.6 122.42,96.02 116.96,96.02 115.44,97.54 107.57,97.54 105.91,99.19 90.16,99.19 89.41,99.95 83.06,99.95 82.7,100.31 81.16,100.31 81.14,100.29 78.85,100.29 78.43,99.88 78.43,99.52 v1(77.85,98.93)
  L14-SIGNAL w0.109: v1(78.58,117.67) 78.58,113.83 79.25,113.16 79.25,110.24 78.87,109.86 78.87,107.82 79.12,107.57 79.12,106.43 78.61,105.92 78.61,104.01 78.42,103.82 78.42,99.51 v1(77.85,98.93)
  BOTTOM w0.132: v1(136.88,86.61) 136.88,86.21 137.1,85.99 RU20.15 ; EXP_P2.35 v1(78.58,117.67)
MCA2_AXR4: length 92.2
  L10-SIGNAL w0.089: v1(136.53,88.53) 136.25,88.25 133.49,88.25 131.32,90.42 131.32,93.98 130.05,95.25 124.84,95.25 122.94,97.16 116.97,97.16 115.82,98.3 113.28,98.3 112.9,98.68 112.9,99.82 112.01,100.71 83.82,100.71 79.63,104.9 77.6,104.9 76.33,106.17 73.28,106.17 v1(72.77,106.68)
  L14-SIGNAL w0.109: v1(72.77,106.68) 72.77,107.57 72.39,107.95 72.39,109.86 73.78,111.24 v1(73.78,117.67)
  BOTTOM w0.132: EXP_P2.23 v1(73.78,117.67) ; RU20.14 136.46,86.8 136.94,87.28 136.94,88.11 v1(136.53,88.53)
MCA2_AXR5: length 77.8
  L10-SIGNAL w0.089: v1(135,89.83) 133.44,89.83 132.59,90.68 132.59,93.73 130.3,96.01 125.22,96.01 123.32,97.92 119.25,97.92 115.95,101.22 85.34,101.22 79.63,106.93 74.37,106.93 v1(73.78,107.52)
  BOTTOM w0.132: RU20.13 135.83,89 v1(135,89.83) ; EXP_P2.24 v1(73.78,107.52)
MCA2_AXR6: length 79
  L10-SIGNAL w0.089: v1(135.24,88.64) 134.47,89.41 133.1,89.41 131.69,90.81 131.69,94.11 130.18,95.63 124.97,95.63 123.06,97.54 116.97,97.54 115.96,98.55 114.18,98.55 113.92,98.81 113.92,99.95 112.9,100.97 85.09,100.97 79.5,106.55 73.79,106.55 72.98,107.36 v1(72.98,108.03)
  BOTTOM w0.132: RU20.12 135.19,86.93 134.86,87.26 134.86,88.26 v1(135.24,88.64) ; EXP_P2.22 v1(72.98,108.03)
MCA2_AXR7: length 71
  L10-SIGNAL w0.089: v1(133.99,90.3) 133.54,90.75 133.54,93.29 128.27,98.55 119,98.55 116.08,101.47 85.55,101.47 79.38,107.64 v1(79.38,108.03)
  BOTTOM w0.132: EXP_P2.38 v1(79.38,108.03) ; RU20.11 134.56,86.8 134.37,87 134.37,89.28 133.99,89.66 v1(133.99,90.3)
MCA6_ACLKX: length 44.9
  TOP w0.132: RU9.17 v1(136.46,87.5)
  L10-SIGNAL w0.089: v1(114.97,107.06) 115.24,107.34 116.18,107.34 116.4,107.12 120.33,107.12 121.67,105.79 132.72,105.79 132.97,105.54 133.52,105.54 v1(136.16,102.89)
  L14-SIGNAL w0.109: v1(136.46,87.5) 136.96,88 136.96,91.26 136.65,91.57 136.65,100.46 136.16,100.94 v1(136.16,102.89)
  BOTTOM w0.132: EXP_P2.104 113.79,108.24 v1(114.97,107.06)
MCA6_AFSX: length 45.4
  TOP w0.132: v1(135.35,87.48) 135.83,87 RU9.18
  L10-SIGNAL w0.089: v1(133.22,104.39) 131.57,102.74 123.32,102.74 120.05,106.01 115.91,106.01 115.88,106.05 v1(114.94,106.05)
  L14-SIGNAL w0.109: v1(135.35,87.48) 133.58,89.25 133.58,104.03 v1(133.22,104.39)
  BOTTOM w0.132: EXP_P2.102 112.99,107.99 v1(114.94,106.05)
MCA6_AHCLKX: length 15
  TOP w0.132: RU6.4 124.35,103.62 123.06,104.9 v1(123.06,106.18)
  L3-SIGNAL w0.109: v1(123.06,106.18) 123.06,106.43 122.56,106.93 116.03,106.93 v1(114.94,108.03)
  BOTTOM w0.132: EXP_P2.106 114.59,108.38 v1(114.94,108.03)
MCA6_AXR0: length 58.7
  TOP w0.132: v1(137.67,87.5) 137.67,86.74 137.1,86.17 RU9.16
  L10-SIGNAL w0.089: v1(113.79,117.93) 113.79,116.59 114.3,116.08 124.71,116.08 125.35,115.44 129.54,115.44 130.18,114.81 136.4,114.81 v1(136.91,114.3)
  L14-SIGNAL w0.109: v1(137.67,87.5) 137.67,100.46 137.16,100.97 137.16,103.63 136.91,103.89 136.91,105.28 135.89,106.3 135.89,111.25 136.91,112.27 v1(136.91,114.3)
  BOTTOM w0.132: EXP_P2.103 v1(113.79,117.93)
MCA6_AXR1: length 58.1
  TOP w0.132: RU9.15 137.73,86.3 v1(138.43,87)
  L10-SIGNAL w0.089: v1(114.59,117.17) 115.17,116.59 119.89,116.59 121.12,117.82 128.05,117.82 130.68,115.19 137.03,115.19 v1(137.92,114.3)
  L14-SIGNAL w0.109: v1(137.92,114.3) 137.92,112.27 136.99,111.34 136.99,106.21 138.18,105.03 138.18,100.58 138.68,100.08 138.68,91.19 138.43,90.93 v1(138.43,87)
  BOTTOM w0.132: EXP_P2.105 v1(114.59,117.17)
MCA7_AXR0: length 142.9
  TOP w0.132: U39.9 v1(19.71,68.81)
  L3-SIGNAL w0.109: v1(51.31,83.69) 52.45,84.84 52.45,98.68 55.5,101.73 64.77,101.73 68.81,97.68 80.54,97.68 81.28,98.42 86.14,98.42 86.77,97.79 88.14,97.79 88.9,97.03 99.82,97.03 101.35,98.55 103.76,98.55 104.27,98.04 116.46,98.04 118.87,100.46 120.9,100.46 121.67,101.22 131.57,101.22 v1(132.97,102.62)
  L10-SIGNAL w0.089: v1(51.31,83.69) 47.37,83.69 32.51,68.83 20.12,68.83 20.1,68.81 v1(19.71,68.81)
  BOTTOM w0.132: v1(132.97,102.62) 132.65,102.3 RU18.35
MCA7_AXR1: length 149
  TOP w0.132: v1(19.72,60.31) U41.6
  L3-SIGNAL w0.109: v1(133.99,103.38) 133.48,102.87 133.48,101.85 132.42,100.79 122.64,100.79 120.9,99.06 118.11,99.06 116.71,97.66 100.97,97.66 100.08,96.77 88.77,96.77 88.01,97.54 86.69,97.54 86.06,98.17 81.41,98.17 80.52,97.28 68.45,97.28 64.39,101.35 55.63,101.35 53.09,98.81 53.09,84.58 v1(51.44,82.93)
  L10-SIGNAL w0.089: v1(51.44,82.93) 51.16,82.66 47.73,82.66 30.73,65.66 25.65,65.66 20.31,60.31 v1(19.72,60.31)
  BOTTOM w0.132: v1(133.99,103.38) 133.55,102.95 133.55,102.38 133.65,102.29 RU18.37
MCA7_CLKX: length 148.5
  TOP w0.132: v1(19.72,59.31) U41.4
  L3-SIGNAL w0.109: v1(52.32,81.66) 54.23,83.57 54.23,98.93 56.01,100.71 63.88,100.71 68.07,96.52 80.64,96.52 81.66,97.54 84.33,97.54 85.64,96.22 86.61,96.22 86.63,96.21 100.72,96.21 101.61,97.1 117.11,97.1 118.36,98.36 122.81,98.36 123.7,99.25 128.96,99.25 129.67,99.95 134.61,99.95 v1(135.1,99.47)
  L10-SIGNAL w0.089: v1(52.32,81.66) 48.01,81.66 31.11,64.77 26.29,64.77 20.83,59.31 20.11,59.31 20.11,59.31 v1(19.72,59.31)
  BOTTOM w0.132: RU18.40 135.15,99.52 v1(135.1,99.47)
MCA7_FSX: length 149.3
  TOP w0.132: v1(20.45,59.81) U41.5
  L3-SIGNAL w0.109: v1(136.15,99.47) 135.29,100.33 122.68,100.33 121.09,98.74 118.3,98.74 116.97,97.42 101.35,97.42 100.46,96.52 88.39,96.52 87.76,97.16 86.36,97.16 85.67,97.85 81.53,97.85 80.58,96.9 68.2,96.9 64.08,101.02 55.81,101.02 53.72,98.93 53.72,84.07 v1(51.82,82.17)
  L10-SIGNAL w0.089: v1(51.82,82.17) 47.88,82.17 30.86,65.15 25.79,65.15 v1(20.45,59.81)
  BOTTOM w0.132: RU18.42 v1(136.15,99.47)
MCASP1_ENN: length 302.9
  TOP w0.132: U43.22 14.2,50.19 v1(13.97,50.42) ; v1(12.98,65.28) 13.59,65.28 14.12,65.81 U39.22 ; SW6.15 v1(209.3,79.5) 208.15,79.5 206.3,77.65 U21.18
  L3-SIGNAL w0.109: v1(12.98,65.28) 12.57,64.87 12.57,54.48 13.84,53.21 14.35,53.21 14.78,52.78 14.78,50.72 14.48,50.42 v1(13.97,50.42) 13.59,50.04 13.59,47.5 13.89,47.19 13.89,43.11 v1(14.31,42.69) ; v1(209.3,79.5) 208.53,78.74 208.53,64.39 205.61,61.47 205.61,50.42 203.78,48.59 203.78,38.81 199.14,34.16 199.14,28.7 194.82,24.38 v1(194.82,20.95)
  L12-SIGNAL w0.089: v1(14.31,42.69) 14.31,40.55 14.86,40.01 14.86,36.7 16.38,35.18 23.75,35.18 35.05,23.88 43.69,23.88 56.52,11.05 150.62,11.05 156.72,17.14 157.86,17.14 158.88,18.16 192.02,18.16 v1(194.82,20.95)
  BOTTOM w0.132: R139.2 v1(209.3,79.5)
MDIO_MDCLK: length 98.2
  TOP w0.132: R69.2 105.41,134.11 v1(105.41,133.6)
  L3-SIGNAL w0.109: v1(59.28,110.11) 60.2,111.02 60.2,116.46 68.33,124.59 v1(68.33,133.73)
  L12-SIGNAL w0.089: v1(100.46,153.54) 101.6,153.54 106.17,148.97 106.17,135 105.41,134.24 v1(105.41,133.6)
  L14-SIGNAL w0.109: v1(105.41,133.6) 104.39,132.59 93.34,132.59 91.65,130.9 90.72,130.9 90.17,131.44 83.44,131.44 83.19,131.19 81.24,131.19 78.7,133.73 v1(68.33,133.73)
  BOTTOM w0.132: U108.20 105.37,133.57 v1(105.41,133.6) ; v1(100.46,153.54) 99.31,153.54 98.97,153.89 U101.20 ; RU14.2 v1(59.28,110.11)
MDIO_MDIO: length 99.5
  TOP w0.132: v1(105.92,133.1) 106.3,133.48 R86.2
  L3-SIGNAL w0.109: v1(66.93,133.1) 66.93,123.95 58.17,115.19 58.17,114.55 57.33,113.72 v1(57.33,111.05)
  L12-SIGNAL w0.089: v1(100.97,152.02) 102.49,152.02 105.7,148.81 105.7,135.03 105.02,134.36 105.02,133.36 105.28,133.1 v1(105.92,133.1)
  L14-SIGNAL w0.109: v1(105.92,133.1) 105.52,133.1 104.63,132.21 94.23,132.21 92.46,130.43 87.12,130.43 86.78,130.77 80.05,130.77 78.36,132.46 71.37,132.46 70.74,133.1 v1(66.93,133.1)
  BOTTOM w0.132: v1(100.97,152.02) 99.82,153.16 99.06,153.16 98.83,153.39 U101.21 ; RU14.5 v1(57.33,111.05) ; U108.21 105.89,133.07 v1(105.92,133.1)
MMC2_BOOT_OVR: length 14.1
  L7-SIGNAL w0.089: v1(60.2,132.33) 64.52,132.33 v1(68.96,127.89)
  BOTTOM w0.132: v1(60.2,132.33) R426.2 U112.2 ; v1(68.96,127.89) 69.16,127.69 U110.18
MMC2_BOOT_OVR_OEN: length 13.6
  L7-SIGNAL w0.089: v1(68.83,127.04) 66.33,129.54 64.64,129.54 63.26,130.92 v1(60.71,130.92)
  BOTTOM w0.132: v1(60.71,130.92) U112.1 61.49,130.02 R428.2 ; v1(68.83,127.04) U110.17
MMC2_BOOTN: length 263.5
  TOP w0.132: SW6.18 205.15,75.69 205.14,75.7 v1(204.72,75.7) U21.15 ; U17.2 v1(129.16,112.78) 130.2,112.78 130.92,112.06 RU5.1 ; v1(62.34,132.97) 62.34,132.72 62.36,132.7 R107.2
  L3-SIGNAL w0.109: v1(82.04,82.17) 87.12,82.17 88.27,83.31 89.15,83.31 89.66,83.82 91.44,83.82 91.84,83.42 95.92,83.42 95.94,83.44 v1(113.68,83.44)
  L7-SIGNAL w0.089: v1(202.31,108.2) 187.58,108.2 185.93,106.55 179.58,106.55 177.93,108.2 148.84,108.2 146.18,110.87 131.06,110.87 v1(129.16,112.78)
  L10-SIGNAL w0.089: v1(204.72,75.7) 203.71,76.72 203.71,103.62 202.31,105.01 v1(202.31,108.2) ; v1(59.94,104.78) 59.49,105.23 59.49,107.65 58.8,108.33 58.8,111.63 60.71,113.54 60.71,118.49 62.34,120.13 v1(62.34,132.97)
  L14-SIGNAL w0.109: v1(129.16,112.78) 129.16,100.97 127.13,98.93 125.09,98.93 119.51,93.34 119.51,91.69 117.47,89.66 117.47,89.41 113.68,85.61 v1(113.68,83.44) ; v1(82.04,82.17) 81.03,82.17 80.33,82.87 79.44,82.87 72.43,89.88 72.43,98.9 69.22,102.11 67.69,102.11 65.02,104.78 v1(59.94,104.78)
  BOTTOM w0.132: R460.2 128.87,113.07 v1(129.16,112.78) ; U122.3 112.09,81.84 v1(113.68,83.44)
MMC2_CLK: length 40.4
  TOP w0.132: v1(137.42,121.03) 136.92,120.53 RU5.44
  L3-SIGNAL w0.109: v1(142.37,125.22) 142.08,124.93 142.08,123.53 140.34,121.79 138.99,121.79 138.74,121.55 137.94,121.55 v1(137.42,121.03)
  BOTTOM w0.132: v1(142.37,125.22) 143.79,125.22 143.92,125.35 143.92,126.49 144.06,126.62 144.32,126.62 144.45,126.49 144.45,125.35 144.58,125.22 144.85,125.22 144.98,125.35 144.98,126.74 145.11,126.87 145.38,126.87 145.51,126.74 145.51,125.35 145.64,125.22 145.91,125.22 146.04,125.35 146.04,126.74 146.17,126.87 146.43,126.87 146.57,126.74 146.57,125.35 146.7,125.22 146.96,125.22 147.09,125.35 147.09,126.74 147.23,126.87 147.49,126.87 147.62,126.74 147.62,125.35 147.75,125.22 148.02,125.22 148.15,125.35 148.15,126.74 148.28,126.87 148.55,126.87 148.68,126.74 148.68,125.35 148.81,125.22 149.08,125.22 149.21,125.35 149.21,126.74 149.34,126.87 149.6,126.87 149.74,126.74 149.74,125.35 149.87,125.22 150.11,125.22 150.62,125.73 R418.1 R420.2
MMC2_CMD: length 29.4
  TOP w0.132: U15.M5 v1(149.05,130.45) ; RU5.33 v1(142.42,120.65)
  L3-SIGNAL w0.109: v1(142.42,120.65) 142.42,121.06 145.41,124.06 145.41,125.16 145.52,125.27 146.58,125.27 146.69,125.38 146.69,125.6 146.58,125.7 145.52,125.7 145.41,125.81 145.41,126.03 145.52,126.14 146.58,126.14 146.69,126.25 146.69,126.47 146.58,126.58 145.52,126.58 145.41,126.69 145.41,126.91 145.52,127.02 146.58,127.02 146.69,127.12 146.69,127.34 146.58,127.45 145.52,127.45 145.41,127.56 145.41,127.78 145.52,127.89 146.58,127.89 146.69,128 146.69,128.22 146.58,128.33 145.52,128.33 145.41,128.44 145.41,128.65 145.52,128.76 146.58,128.76 146.69,128.87 146.69,129.09 146.58,129.2 145.52,129.2 145.41,129.31 145.41,129.79 146.08,130.45 v1(149.05,130.45)
  BOTTOM w0.127: v1(149.05,130.45) 148.77,130.18 R415.2
MMC2_DAT0: length 40.8
  TOP w0.132: U15.A3 148.25,136.11 147.99,136.36 147.99,136.56 v1(147.7,136.86) ; v1(138.42,121.03) 137.92,120.53 RU5.42
  L3-SIGNAL w0.109: v1(147.7,136.86) 147.7,135.38 147.4,135.08 145.89,135.08 145.67,134.85 145.67,131.95 144.76,131.04 144.76,130.89 144.86,130.79 144.86,130.64 144.7,130.48 144.55,130.48 144.45,130.58 144.3,130.58 144.14,130.43 144.14,130.27 144.24,130.17 144.24,130.02 144.09,129.86 143.93,129.86 143.83,129.96 143.68,129.96 143.51,129.79 143.51,128.78 142.76,128.03 142.76,127.74 142.87,127.63 143.78,127.63 143.89,127.52 143.89,127.3 143.78,127.19 142.87,127.19 142.76,127.08 142.76,126.86 142.87,126.75 143.78,126.75 143.89,126.65 143.89,126.43 143.78,126.32 142.87,126.32 142.76,126.21 142.76,125.99 142.87,125.88 143.78,125.88 143.89,125.77 143.89,125.55 143.78,125.44 142.87,125.44 142.76,125.33 142.76,125.12 142.87,125.01 143.78,125.01 143.89,124.9 143.89,124.68 143.78,124.57 142.87,124.57 142.76,124.46 142.76,124.24 142.87,124.13 143.78,124.13 143.89,124.02 143.89,123.81 143.78,123.7 142.87,123.7 142.6,123.42 142.6,123.27 142.89,122.98 142.89,122.82 142.73,122.67 142.58,122.67 142.29,122.96 142.13,122.96 141.98,122.8 141.98,122.65 142.27,122.36 142.27,122.2 142.11,122.05 141.96,122.05 141.67,122.34 141.51,122.34 141.36,122.18 141.36,122.03 141.65,121.74 141.65,121.58 141.5,121.43 141.34,121.43 141.05,121.72 140.9,121.72 140.61,121.43 139.25,121.43 139.24,121.41 139.21,121.41 138.83,121.03 v1(138.42,121.03)
  BOTTOM w0.132: R389.2 v1(147.7,136.86)
MMC2_DAT1: length 29
  TOP w0.132: RU5.40 138.92,120.53 v1(139.42,121.03) ; v1(149.73,136.86) 149.43,136.86 148.75,136.18 148.75,135.76 148.75,135.75 U15.A4
  L3-SIGNAL w0.109: v1(139.42,121.03) 139.88,120.57 140.79,120.57 141.22,120.14 142.62,120.14 143,120.52 143,120.9 149.18,127.09 149.18,127.72 149.53,128.07 149.53,131.57 149.35,131.75 149.35,133.83 149.73,134.21 v1(149.73,136.86)
  BOTTOM w0.132: R387.2 v1(149.73,136.86)
MMC2_DAT2: length 38.6
  TOP w0.132: U15.A5 149.49,135.7 149.49,135.83 149.73,136.07 150.04,136.07 150.37,136.4 151.31,136.4 v1(151.76,136.86) ; v1(140.42,120.14) RU5.37
  L3-SIGNAL w0.109: v1(151.76,136.86) 152.18,136.44 152.45,136.44 152.78,136.11 152.78,130.08 143.64,120.94 143.64,119.13 143.13,118.62 142.35,118.62 142.25,118.73 142.25,119.02 142.14,119.13 141.92,119.13 141.81,119.02 141.81,118.73 141.7,118.62 141.48,118.62 141.37,118.73 141.37,119.02 141.26,119.13 141.04,119.13 140.93,119.02 140.93,118.73 140.83,118.62 140.59,118.62 140.31,118.9 138.16,118.9 138.05,119.01 138.05,119.23 138.16,119.34 140.31,119.34 140.42,119.45 v1(140.42,120.14)
  BOTTOM w0.132: R385.2 v1(151.76,136.86)
MMC2_DAT3: length 26.5
  TOP w0.076: 147.07,135.21 147.5,135.21
  TOP w0.132: 147.5,135.21 U15.B2 ; v1(146.18,134.62) 146.18,135.04 146.35,135.21 147.07,135.21 ; v1(141.42,120.65) RU5.35
  L3-SIGNAL w0.109: v1(141.42,120.65) 144.91,124.14 144.91,124.72 144.8,124.83 144.51,124.83 144.4,124.93 144.4,125.15 144.51,125.26 144.8,125.26 144.91,125.37 144.91,125.59 144.8,125.7 144.51,125.7 144.4,125.81 144.4,126.03 144.51,126.14 144.8,126.14 144.91,126.25 144.91,126.46 144.8,126.57 144.51,126.57 144.4,126.68 144.4,126.9 144.51,127.01 144.8,127.01 144.91,127.12 144.91,127.34 144.8,127.45 144.51,127.45 144.4,127.56 144.4,127.77 144.51,127.88 144.8,127.88 144.91,127.99 144.91,128.21 144.8,128.32 144.51,128.32 144.4,128.43 144.4,128.65 144.51,128.76 144.8,128.76 144.91,128.87 144.91,129.09 144.8,129.19 144.51,129.19 144.4,129.3 144.4,129.54 146.81,131.95 146.81,134.51 146.7,134.62 v1(146.18,134.62)
  BOTTOM w0.132: R398.2 145.92,134.37 v1(146.18,134.62)
MMC2_DAT4: length 32.3
  TOP w0.076: 148,135.64 148,135.21
  TOP w0.132: 148,135.21 U15.B3 ; v1(146.18,135.89) 146.69,135.89 146.74,135.83 147.8,135.83 148,135.64 ; v1(132.42,120.14) RU5.53
  L3-SIGNAL w0.109: v1(146.18,135.89) 145.59,135.89 144.91,135.2 144.91,132.33 142.24,129.66 142.24,129.51 142.59,129.16 142.59,129 142.44,128.85 142.28,128.85 141.93,129.2 141.77,129.2 141.6,129.03 141.6,126.75 141.22,126.37 141.22,123.95 140.21,122.94 133.6,122.94 133.35,122.68 133.35,122.3 132.97,121.92 132.97,120.69 v1(132.42,120.14)
  BOTTOM w0.132: v1(146.18,135.89) 145.8,135.51 R395.2
MMC2_DAT5: length 38.8
  TOP w0.076: 148.5,135.64 148.5,135.21
  TOP w0.132: v1(133.42,120.14) RU5.51 ; 148.5,135.64 148.5,135.65 148.5,135.66 148.5,136.21 148.5,136.22 148.5,136.63 v1(148.72,136.86) ; 148.5,135.21 U15.B4
  L3-SIGNAL w0.109: v1(133.42,120.14) 133.86,120.58 133.86,121.16 134.19,121.49 136.02,121.49 136.03,121.48 136.36,121.48 136.36,121.49 136.73,121.49 137.2,121.96 138.22,121.96 138.31,122.06 139.33,122.06 139.7,122.43 140.32,122.43 141.6,123.71 141.6,126.11 141.99,126.49 141.99,127.89 143,128.91 143,129.92 145.29,132.21 145.29,135.08 145.67,135.46 146.51,135.46 146.69,135.64 146.69,137.03 147.7,138.05 147.7,138.68 148.08,139.06 150.11,139.06 150.48,138.7 150.48,137.78 150.11,137.41 149.28,137.41 v1(148.72,136.86)
  BOTTOM w0.132: R388.2 v1(148.72,136.86)
MMC2_DAT6: length 45
  TOP w0.076: 149,135.21 149,135.64
  TOP w0.132: v1(150.75,136.86) 150.37,136.86 149.89,136.37 149.58,136.37 149.01,135.8 149.01,135.66 149,135.65 149,135.64 ; v1(135.42,121.03) 134.92,120.53 RU5.48 ; U15.B5 149,135.21
  L3-SIGNAL w0.109: v1(150.75,136.86) 151.31,137.41 152.98,137.41 153.8,136.59 153.8,129.03 153.08,128.31 152.19,128.31 144.65,120.78 144.65,118.24 143.89,117.47 137.29,117.47 135.97,118.8 135.97,120.48 v1(135.42,121.03)
  BOTTOM w0.132: R386.2 v1(150.75,136.86)
MMC2_DAT7: length 39.6
  TOP w0.076: 149.99,135.64 149.99,135.21
  TOP w0.132: 149.99,135.64 150.37,136.02 151.61,136.02 152.17,136.58 152.5,136.58 v1(152.78,136.86) ; 149.99,135.21 U15.B6 ; RU5.46 135.92,120.53 v1(136.42,121.03)
  L3-SIGNAL w0.109: v1(152.78,136.86) 153.16,136.47 153.16,129.92 144.15,120.9 144.15,118.87 143.38,118.11 138.05,118.11 136.97,119.19 136.97,120.48 v1(136.42,121.03)
  BOTTOM w0.132: R384.2 v1(152.78,136.86)
NAND_BOOTN: length 176.6
  TOP w0.132: U21.13 204.72,74.4 205.97,73.15 v1(209.3,73.15) SW6.20 ; v1(115.19,148.72) 115.55,148.35 RU3.1
  L3-SIGNAL w0.109: v1(209.3,73.15) 210.95,74.8 210.95,122.43 210.19,123.19 210.19,125.86 207.9,128.14 v1(207.9,139.19)
  L14-SIGNAL w0.109: v1(115.19,148.72) 116.71,148.72 118.11,150.11 122.68,150.11 124.21,151.64 145.41,151.64 146.05,151 148.59,151 149.86,149.73 164.47,149.73 166.5,147.7 189.87,147.7 198.37,139.19 v1(207.9,139.19)
  BOTTOM w0.132: R153.2 v1(209.3,73.15)
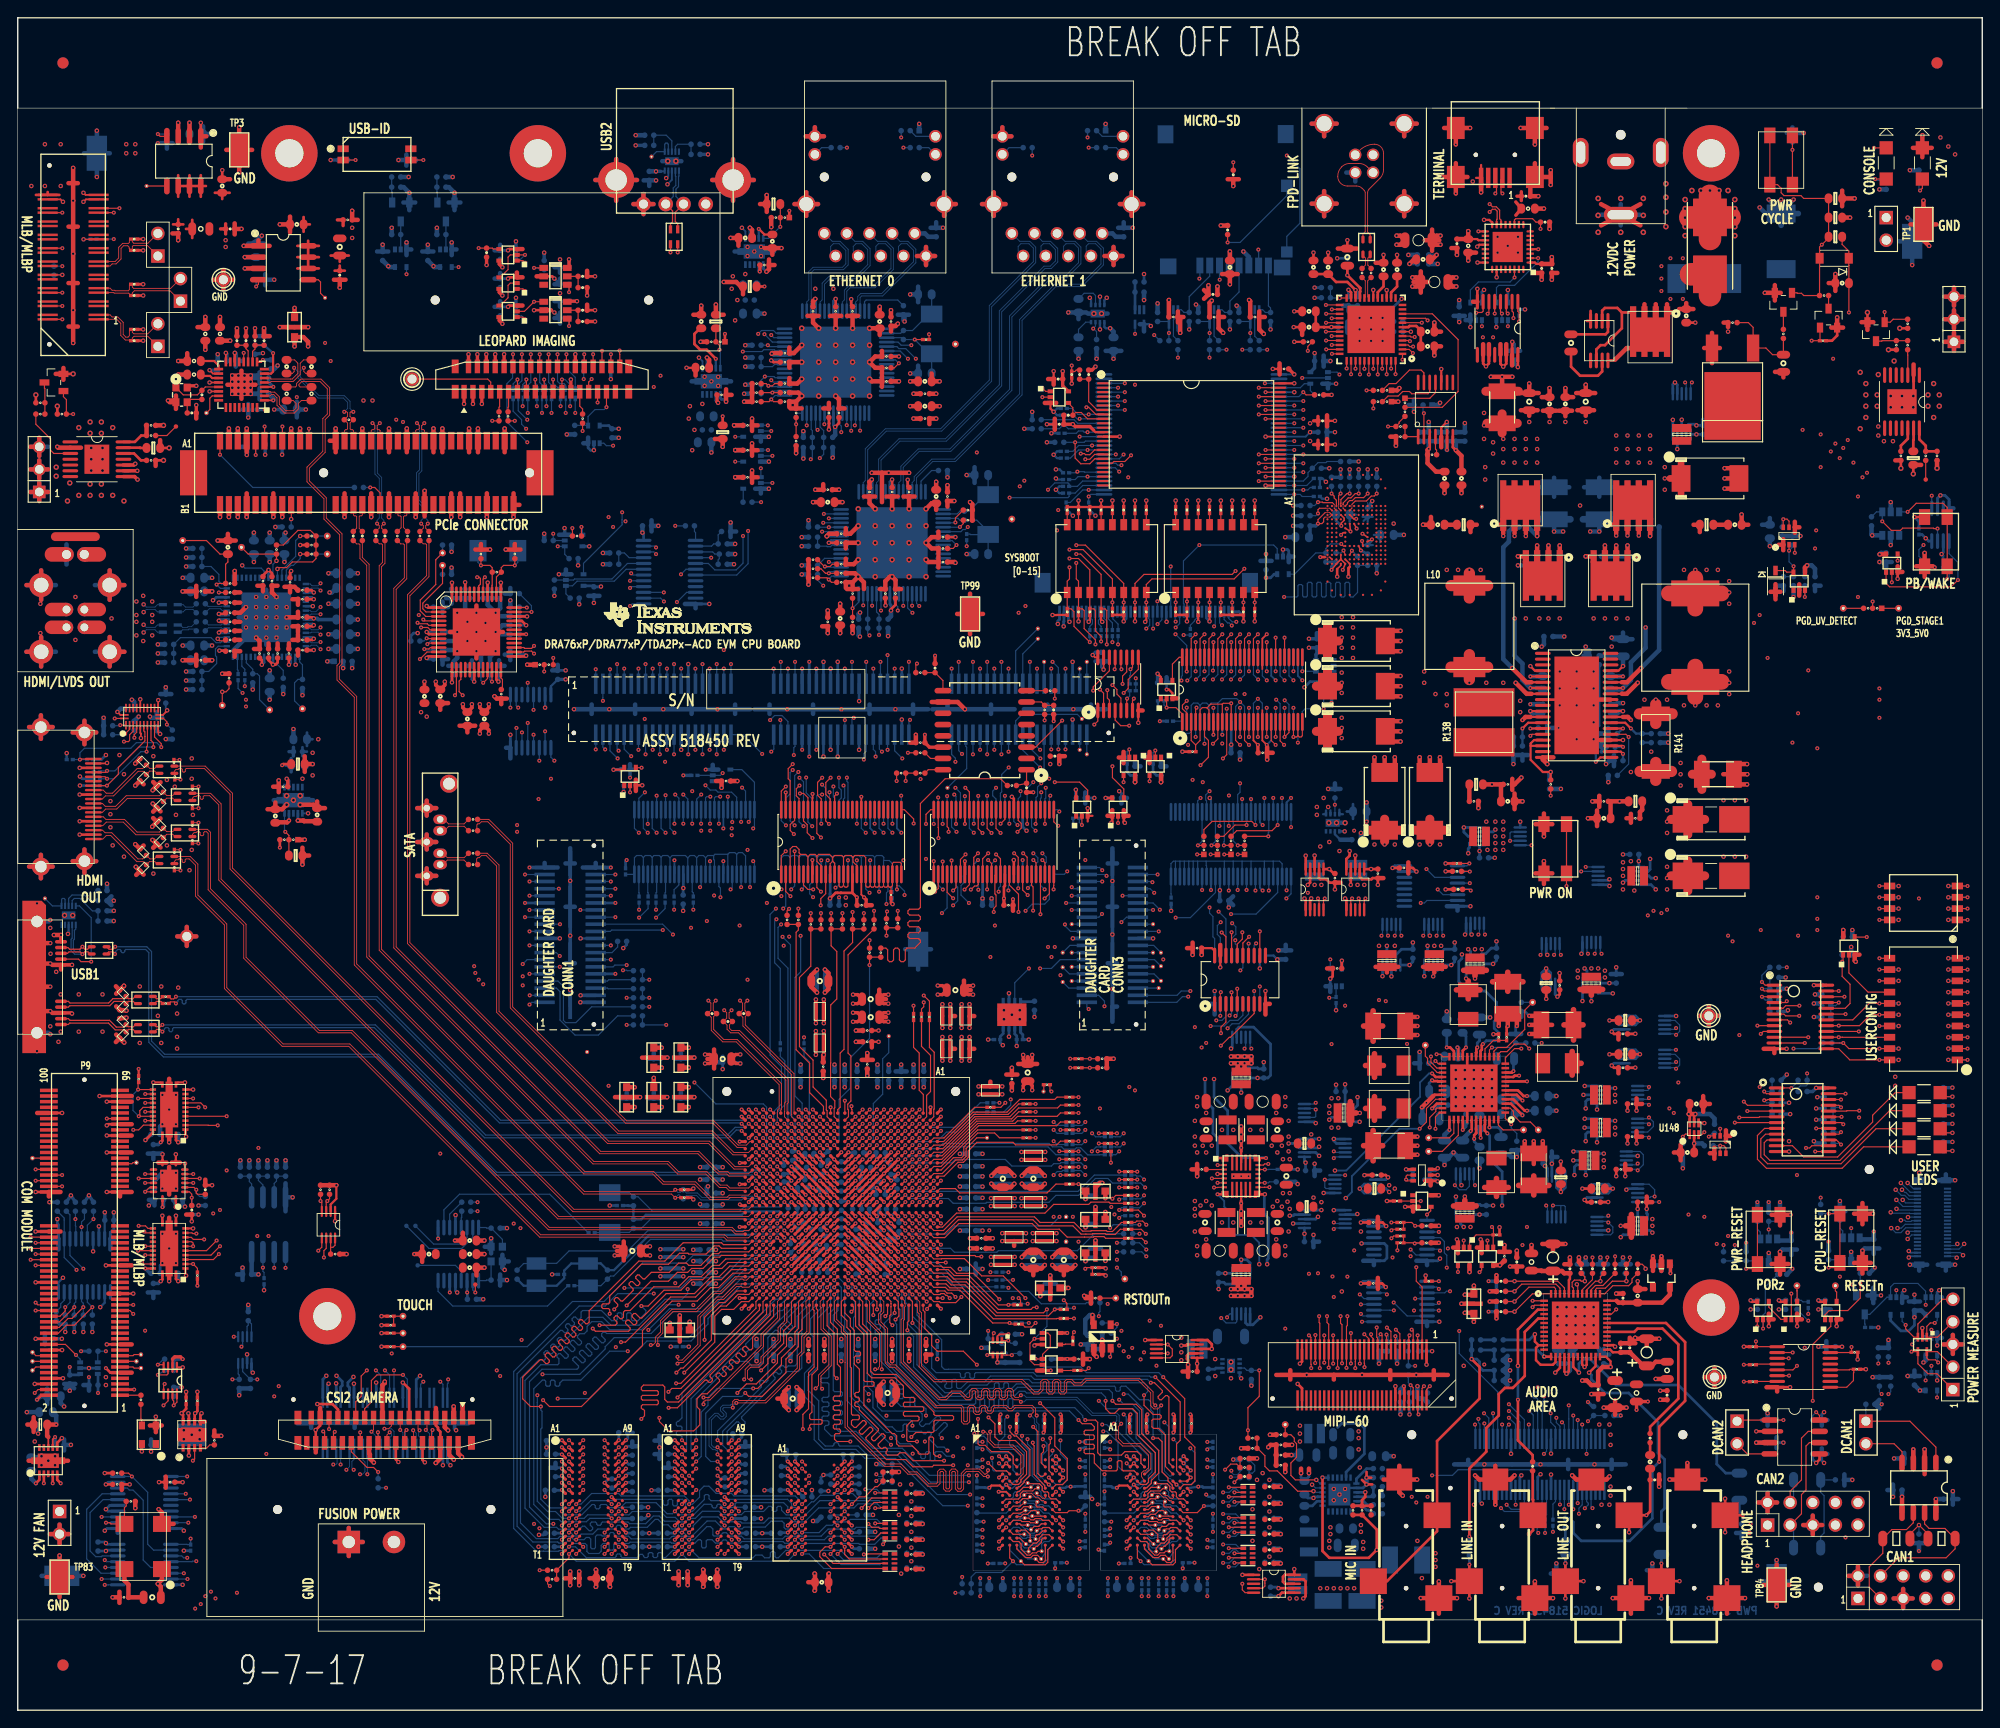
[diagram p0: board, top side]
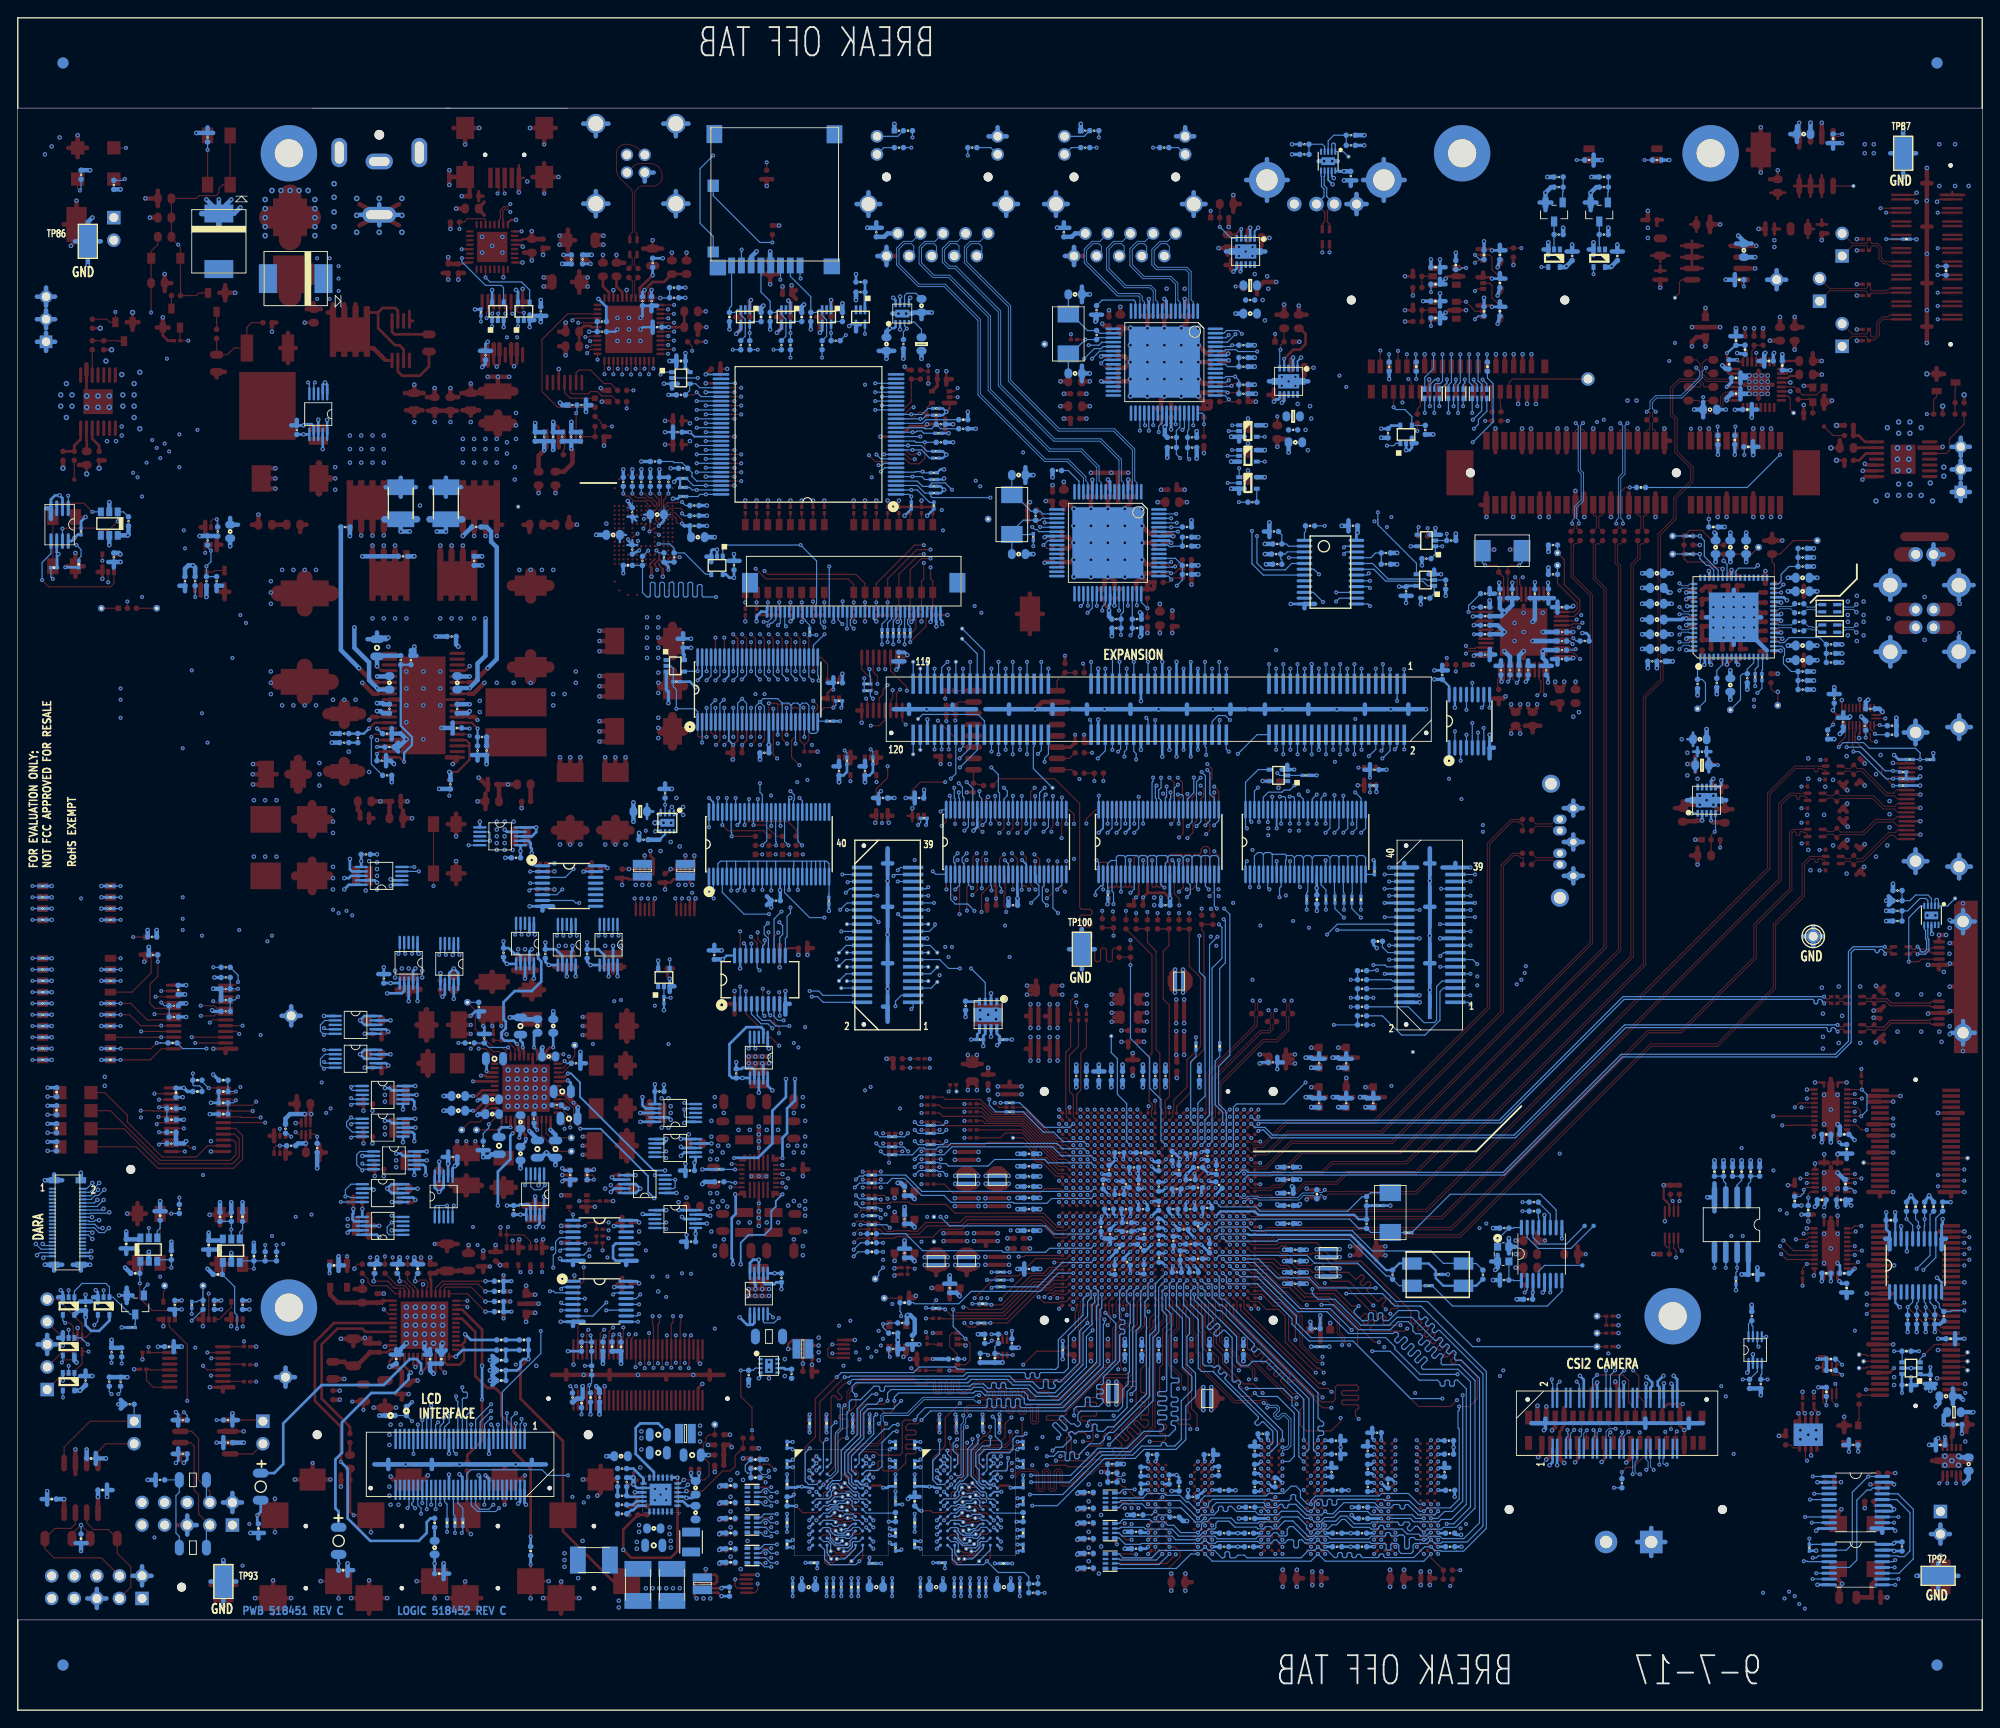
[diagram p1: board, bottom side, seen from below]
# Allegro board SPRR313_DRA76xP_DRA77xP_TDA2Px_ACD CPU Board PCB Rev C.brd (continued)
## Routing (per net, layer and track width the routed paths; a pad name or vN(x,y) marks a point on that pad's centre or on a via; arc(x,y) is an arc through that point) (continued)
Net_1831: length 5.9
  TOP w0.508: 187.71,25.95 v2(189.7,25.95) ; 187.71,25.95 v1(187.71,27.81) ; 187.71,25.95 v2(185.71,25.95)
Net_1838: length 4.5
  TOP w0.508: v2(178.94,26.29) 178.6,25.95 176.91,25.95 175.22,25.95 v2(174.75,26.42)
Net_2245: length 0.6
  TOP w0.132: 88.57,27.58 v1(88.17,27.98)
Net_2253: length 0.6
  TOP w0.132: 61.57,23.58 61.17,23.18 v1(61.17,23.18)
Net_2254: length 0.6
  TOP w0.132: 103.39,46.36 v1(103.98,46.36)
Net_2255: length 0.6
  TOP w0.132: 102.59,45.56 102.24,45.22 102.24,45.14 v1(102.23,45.13)
Net_2256: length 0.6
  TOP w0.132: 99.39,63.16 v1(99.79,63.56)
NOR_BOOTN: length 140.4
  TOP w0.132: SW6.19 v1(209.3,74.42) 205.86,74.42 v1(205.23,75.05) U21.14
  L3-SIGNAL w0.109: v1(209.3,74.42) 210.38,75.5 210.38,122.11 209.55,122.94 209.55,125.73 207.39,127.89 v1(207.39,138.68)
  L14-SIGNAL w0.109: v1(207.39,138.68) 198.25,138.68 189.61,147.32 166.37,147.32 164.34,149.35 149.48,149.35 v1(148.59,150.24)
  BOTTOM w0.132: R486.2 204.82,75.06 204.82,75.05 v1(205.23,75.05) ; v1(148.59,150.24) 148.32,150.51 RU12.1 ; v1(209.3,74.42) R147.2
NOR_BOOTN_OVR: length 10.8
  BOTTOM w0.132: R425.2 U111.2 62.48,127.13 62.6,127.25 66.79,127.25 68.54,128.99 U110.20
NOR_BOOTN_OVR_OEN: length 11.1
  BOTTOM w0.132: 62.1,125.09 61.62,125.58 U111.1 62.36,126.48 62.88,127 67.06,127 68.4,128.34 U110.19
NOR_CEN: length 5.2
  BOTTOM w0.132: U104.32 144.19,148.76 144.64,149.21 RU12.4 145.31,148.44 R358.1
NTRST: length 3.6
  TOP w0.132: v1(156.46,42.16) 156.46,42.04 156.38,41.95 J13.9
  BOTTOM w0.132: v1(156.46,42.16) 156.46,42.04 156.38,41.95 156.38,41.44 R652.1 R651.2
OLD_GPMC_NCS0: length 3.4
  BOTTOM w0.132: R528.2 67.44,85.85 66.8,85.22 EXP_P1.16
P0_CRS: length 3.8
  BOTTOM w0.132: R351.1 R353.1 84.84,151.13 85.09,151.39 U101.56
P0_LED_ACT: length 29.1
  L3-SIGNAL w0.109: v1(93.22,175.77) 93.22,170.81 87.88,165.48 87.88,161.8 83.24,157.15 v1(83.24,154.82)
  BOTTOM w0.132: v1(83.24,154.82) 83.61,155.19 84.96,155.19 85.27,154.89 U101.63 ; R302.2 v1(93.22,175.77)
P0_LED_LINK10_100: length 31.9
  L3-SIGNAL w0.109: v1(83.95,154.78) 83.95,155.7 88.39,160.15 88.39,165.35 94.61,171.58 94.61,172.21 v1(99.31,176.91)
  BOTTOM w0.132: U101.61 84.84,153.89 v1(83.95,154.78) ; RJ13.3 v1(99.31,176.91)
P0_LED_LINK1000: length 29.6
  L3-SIGNAL w0.109: v1(84.71,154.69) 84.71,155.45 89.03,159.77 89.03,162.56 91.95,165.48 91.95,168.15 v1(99.57,175.77)
  BOTTOM w0.132: R301.2 v1(99.57,175.77) ; v1(84.71,154.69) 85.01,154.39 U101.62
P0_RBIAS: length 5.8
  BOTTOM w0.132: R327.2 98.93,158.62 95.38,158.62 95.2,158.44 U101.15
P0_RX_D4: length 4
  TOP w0.132: R64.2 v1(87.5,144.65) R49.1
  BOTTOM w0.132: v1(87.5,144.65) 87.5,145.72 87.68,145.9 U101.48
P0_RX_D5: length 4.1
  TOP w0.132: R43.1 84.45,147.19 v1(84.71,147.45) 84.96,147.19 85.72,147.19
  BOTTOM w0.132: U101.49 85.15,147.89 v1(84.71,147.45)
P0_RX_D6: length 3.6
  TOP w0.132: 85.72,148.21 v1(84.84,148.21) R40.1
  BOTTOM w0.132: v1(84.84,148.21) 85.02,148.39 U101.50
P0_RX_D7: length 4.2
  TOP w0.132: R37.1 84.14,149.22 84.39,148.97 v1(84.39,148.97) 84.83,148.97 85.09,149.22 85.72,149.22
  BOTTOM w0.132: U101.51 84.66,148.89 84.58,148.97 v1(84.39,148.97)
P0_TRD[0]N: length 14
  BOTTOM w0.099: U101.3 89.2,161.72 89.52,162.04 92.82,162.04 93.36,162.57 93.36,164.32 92.45,165.23 91.57,165.23 P3.10
P0_TRD[0]P: length 14
  BOTTOM w0.099: P3.9 91.39,164.13 91.39,164.66 91.69,164.96 92.34,164.96 93.09,164.21 93.09,162.68 92.71,162.31 89.41,162.31 88.93,161.83 88.93,158.64 88.7,158.4 U101.2
P0_TRD[1]N: length 14.2
  BOTTOM w0.099: P3.8 94.11,165.23 95,165.23 95.82,164.4 95.82,162.5 94.35,161.02 91.31,161.02 90.7,160.41 U101.6
P0_TRD[1]P: length 14.2
  BOTTOM w0.099: U101.5 90.2,158.4 90.43,158.64 90.43,160.52 91.2,161.29 94.24,161.29 95.55,162.61 95.55,164.29 94.89,164.96 94.23,164.96 93.93,164.66 93.93,164.13 P3.7
P0_TRD[2]N: length 14.2
  BOTTOM w0.099: P3.6 96.65,165.23 97.66,165.23 98.44,164.45 98.44,162.06 96.38,160.01 93.58,160.01 93.2,159.62 U101.11
P0_TRD[2]P: length 14.3
  BOTTOM w0.099: U101.10 92.7,158.4 92.93,158.64 92.93,159.73 93.47,160.27 96.27,160.27 98.17,162.18 98.17,164.34 97.55,164.96 96.76,164.96 96.47,164.67 96.47,164.13 P3.5
P0_TRD[3]N: length 14.3
  BOTTOM w0.099: U101.14 94.7,158.91 94.87,159.08 97.23,159.08 100.97,162.81 100.97,164.34 100.08,165.23 99.19,165.23 P3.4
P0_TRD[3]P: length 14.4
  BOTTOM w0.099: P3.3 99.01,164.13 99.01,164.66 99.31,164.96 99.97,164.96 100.7,164.23 100.7,162.92 97.12,159.35 94.76,159.35 94.43,159.02 94.43,158.64 94.2,158.4 U101.13
P1_CRS: length 3.8
  BOTTOM w0.132: R407.1 R409.1 90.95,130.94 91,130.88 91.37,130.88 91.56,131.07 U108.56
P1_LED_ACT: length 54.9
  L3-SIGNAL w0.109: v1(114.05,174.88) 115.06,173.86 115.06,171.07 108.84,164.85 108.84,152.65 100.46,144.27 98.42,144.27 91.82,137.67 91.82,135.76 v1(90.63,134.57)
  BOTTOM w0.132: R300.2 v1(114.05,174.88) ; v1(90.63,134.57) U108.63
P1_LED_LINK10_100: length 65.3
  L3-SIGNAL w0.109: v1(120.27,176.91) 121.16,176.02 121.16,174.5 120.65,173.99 120.65,170.18 123.19,167.64 123.19,165.35 121.92,164.08 121.92,162.18 119.76,160.02 117.35,160.02 110.62,153.29 110.62,151.76 101.85,143 98.3,143 93.73,138.43 93.73,136.14 92.08,134.49 92.08,134.11 91.53,133.57 v1(90.55,133.57)
  BOTTOM w0.132: RJ12.3 v1(120.27,176.91) ; U108.61 v1(90.55,133.57)
P1_LED_LINK1000: length 57.8
  L3-SIGNAL w0.109: v1(120.4,175.77) 118.11,173.48 118.11,165.48 116.84,164.21 116.84,162.56 109.86,155.57 109.86,152.78 104.65,147.57 104.65,146.94 103.76,146.05 102.87,146.05 100.46,143.64 98.42,143.64 93.09,138.3 93.09,137.16 92.2,136.27 92.2,135.08 v1(91.19,134.07)
  BOTTOM w0.132: 121.28,175.77 v1(120.4,175.77) ; U108.62 v1(91.19,134.07)
P1_RBIAS: length 3.6
  BOTTOM w0.132: U108.15 101.55,138.25 102.74,139.45 103.5,139.45
P1_RX_D4: length 4.1
  TOP w0.132: R112.1 v1(93.85,123.95) R129.2
  BOTTOM w0.132: U108.48 94.55,124.65 v1(93.85,123.95)
P1_RX_D5: length 4
  TOP w0.132: R108.1 90.97,127.38 v1(91.17,127.18) 91.48,126.87 R109.2
  BOTTOM w0.132: v1(91.17,127.18) 91.17,127.19 91.19,127.2 91.19,127.25 91.5,127.57 U108.49
P1_RX_D6: length 3.8
  TOP w0.132: R105.1 90.3,128.4 90.81,127.89 v1(91.19,127.89) R106.2
  BOTTOM w0.132: U108.50 91.37,128.07 v1(91.19,127.89)
P1_RX_D7: length 4.4
  TOP w0.132: R103.1 90.68,128.65 v1(90.74,128.65) 90.74,128.65 91.31,128.65 91.57,128.91 R104.1
  BOTTOM w0.132: U108.51 91.01,128.57 90.93,128.65 v1(90.74,128.65)
P1_TRD[0]N: length 42.3
  BOTTOM w0.099: U108.3 95.55,141.78 97.65,143.88 103.87,143.88 109.49,149.5 109.49,157.87 112.84,161.23 112.84,161.23 114.44,162.83 114.44,164.58 113.79,165.23 112.65,165.23 P4.10
P1_TRD[0]P: length 42.3
  BOTTOM w0.099: U108.2 95.05,138.08 95.28,138.32 95.28,141.89 97.54,144.15 103.76,144.15 109.22,149.61 109.22,157.98 112.57,161.34 112.57,161.34 114.17,162.94 114.17,164.47 113.68,164.96 112.78,164.96 112.47,164.66 112.47,164.13 P4.9
P1_TRD[1]N: length 42.4
  BOTTOM w0.099: P4.8 115.19,165.23 116.11,165.23 116.82,164.52 116.82,164.51 116.92,164.41 116.92,162.9 116.19,162.17 115.48,162.17 110.62,157.3 110.62,148.97 104.39,142.75 99.18,142.75 97.05,140.61 U108.6
P1_TRD[1]P: length 42.4
  BOTTOM w0.099: U108.5 96.55,138.08 96.78,138.32 96.78,140.72 99.07,143.01 104.28,143.01 110.35,149.08 110.35,157.41 115.37,162.43 116.08,162.43 116.65,163.01 116.65,164.3 116.55,164.4 116.55,164.41 116,164.96 115.3,164.96 115.04,164.69 115.04,164.11 P4.7
P1_TRD[2]N: length 42.2
  BOTTOM w0.099: U108.11 99.55,139.81 101.34,141.6 104.9,141.6 111.76,148.46 111.76,156.72 116.19,161.15 117.97,161.15 119.52,162.7 119.52,164.58 118.87,165.23 117.73,165.23 P4.6
P1_TRD[2]P: length 42.2
  BOTTOM w0.099: P4.5 117.58,164.11 117.58,164.68 117.86,164.96 118.76,164.96 119.25,164.47 119.25,162.81 117.86,161.42 116.08,161.42 111.49,156.83 111.49,148.57 104.79,141.87 101.23,141.87 99.28,139.92 99.28,138.32 99.05,138.08 U108.10
P1_TRD[3]N: length 42.7
  BOTTOM w0.099: U108.14 101.05,138.64 102.87,140.46 105.41,140.46 112.9,147.96 112.9,156.34 116.7,160.13 119.62,160.13 122.05,162.56 122.05,164.47 121.28,165.23 120.27,165.23 P4.4
P1_TRD[3]P: length 42.7
  BOTTOM w0.099: P4.3 120.12,164.11 120.12,164.69 120.38,164.96 121.17,164.96 121.78,164.35 121.78,162.67 119.51,160.4 116.59,160.4 112.64,156.45 112.64,148.07 105.3,140.73 102.76,140.73 100.78,138.75 100.78,138.32 100.55,138.08 U108.13
PB_ON: length 35.1
  TOP w0.132: Q4.G 200.01,159.44 200.07,159.38 200.53,159.38 200.79,159.13 R46.1 202.56,162.51 202.58,162.52 D1.2 202.58,164.12 202.56,164.14 202.56,164.59 v1(202.82,164.85) 203.58,165.61 R31.2 R39.1 R21.2 200.79,170.05 200.47,170.37 198.57,170.37 198.25,170.69 198.25,171.2 197.84,171.6 SW2.4 SW2.3
  L3-SIGNAL w0.109: v1(202.82,164.85) 209.55,164.85 J7.2
PCF_VPP_ENN: length 9.6
  TOP w0.132: U21.20 205.45,78.95 205.99,79.5 205.99,81.66 205.1,82.55 v1(205.1,84.2) 205.22,84.31 RU11.1
  BOTTOM w0.132: v1(205.1,84.2) R647.2
PCI_CONN_REFN: length 7.1
  TOP w0.099: U10.5 28.37,149.35 28.49,149.47 30.75,149.47 30.97,149.47 31.75,150.25 31.75,151.51 32.13,151.89 C44.1
PCI_CONN_REFP: length 6.6
  TOP w0.099: C43.1 31.11,151.89 31.48,151.52 31.48,150.36 30.86,149.74 30.64,149.74 28.48,149.74 28.37,149.85 U10.6
PCI_PORZ: length 268.6
  TOP w0.132: U4.4 53.47,164.35 53.36,164.47 R12.1 v1(51.82,164.47) ; U47.2 v1(199.39,46.86)
  L3-SIGNAL w0.109: v1(199.39,46.86) 199.39,48.39 200.79,49.78 200.79,54.86 203.2,57.28 203.2,60.96 205.87,63.63 205.87,69.17 205.88,69.18 205.88,69.51 205.87,69.53 205.87,77.47 206.63,78.23 206.63,83.6 206.21,84.03 206.21,84.38 206.67,84.84 206.67,88.86 206.12,89.41 206.12,126.24 205.23,127.13 v1(205.23,141.99)
  L14-SIGNAL w0.109: v1(51.82,164.47) 52.07,164.72 60.07,164.72 60.32,164.97 80.9,164.97 81.41,165.48 88.77,165.48 89.66,164.59 132.97,164.59 134.11,163.45 144.65,163.45 145.42,162.69 149.48,162.69 151.64,160.53 151.64,159.38 152.91,158.12 182.63,158.12 198.76,141.99 v1(205.23,141.99)
PCI_RESET_SEL: length 227.7
  TOP w0.132: v1(57.02,162.81) 56.78,163.05 U4.1 ; SW6.13 v1(209.3,82.04) ; v1(57.02,159.64) 56.78,159.88 RU1.1
  L3-SIGNAL w0.109: v1(206.38,140.34) 206.38,127.38 207.9,125.86 207.9,87.88 208.66,87.12 208.66,82.68 v1(209.3,82.04) ; v1(57.02,159.64) v1(57.02,162.81)
  L14-SIGNAL w0.109: v1(206.38,140.34) 198.5,140.34 184.91,153.92 169.16,153.92 168.66,154.43 167.39,154.43 166.88,153.92 159,153.92 155.83,157.1 151.38,157.1 147.32,161.16 145.16,161.16 144.15,162.18 124.97,162.18 124.21,161.42 88.27,161.42 86.87,162.81 63.37,162.81 60.2,159.64 v1(57.02,159.64)
  BOTTOM w0.132: v1(209.3,82.04) R137.2
PCI_SW_RESETN: length 236.7
  TOP w0.132: U7.1 56.78,156.7 v1(57.02,156.46) ; U30.17 v1(202.18,65.45)
  L3-SIGNAL w0.109: v1(202.69,139.83) 203.11,139.41 203.11,66.37 v1(202.18,65.45)
  L14-SIGNAL w0.109: v1(57.02,156.46) 62.48,156.46 68.45,162.43 86.36,162.43 87.88,160.91 129.03,160.91 129.79,161.67 143.89,161.67 144.91,160.66 145.92,160.66 150.75,155.83 156.59,155.83 159,153.42 184.78,153.42 198.37,139.83 v1(202.69,139.83)
  BOTTOM w0.132: v1(57.02,156.46) 56.64,156.84 R328.2
PCM_CLK: length 20.1
  TOP w0.132: P9.52 v1(2.01,51.31) ; v1(14.31,59.31) U41.13
  L12-SIGNAL w0.089: v1(14.31,59.31) 14.23,59.31 13.72,58.8 13.72,55.37 10.79,52.45 4.45,52.45 3.3,51.31 v1(2.01,51.31)
PCM_DIN: length 20.2
  TOP w0.132: P9.56 v1(2.01,52.58) ; v1(14.31,60.31) U41.11
  L12-SIGNAL w0.089: v1(14.31,60.31) 13.32,60.31 12.7,59.69 12.7,55.88 10.03,53.21 3.94,53.21 3.3,52.58 v1(2.01,52.58)
PCM_DOUT: length 26.3
  TOP w0.132: P9.58 v1(1.45,53.21) ; v1(14.33,69.31) U39.15
  L14-SIGNAL w0.109: v1(14.33,69.31) 14.33,68.92 13.74,68.33 11.81,68.33 10.67,67.18 9.27,67.18 3.81,61.72 3.81,58.55 1.45,56.18 v1(1.45,53.21)
PCM_FSYNC: length 21.3
  TOP w0.132: P9.54 v1(1.45,51.94) ; v1(13.59,59.81) U41.12
  L12-SIGNAL w0.089: v1(13.59,59.81) 13.21,59.43 13.21,55.63 10.41,52.83 4.19,52.83 3.3,51.94 v1(1.45,51.94)
PGD_3V3_5V0: length 126.8
  TOP w0.132: RJ17.2 v1(208.53,124.71) ; U16.2 v1(210.69,126.87)
  L10-SIGNAL w0.089: v1(187.83,55.75) 187.83,65.79 187.45,66.17 187.45,81.79 179.67,89.57 179.67,102.41 179.83,102.56 179.83,105.92 180.21,106.3 184.66,106.3 187.83,109.47 198.37,109.47 212.34,123.44 212.34,125.22 v1(210.69,126.87) v1(208.53,124.71)
  L12-SIGNAL w0.089: v1(187.83,55.75) 190.5,53.09 191.52,53.09 191.77,52.83 192.53,52.83 v1(193.04,52.32) 193.29,52.07 202.95,52.07 206.25,48.77 v1(206.25,47.88)
  BOTTOM w0.132: v1(206.25,47.88) 206.68,47.45 Q13.G ; R602.1 v1(193.04,52.32)
PGD_STAGE1_3V3_5V0: length 58.1
  TOP w0.132: RJ17.1 TP96.1 ; U18.15 170.23,109.78 v1(170.05,109.6) ; v1(181.1,109.47) 180.8,109.78 U18.24
  L3-SIGNAL w0.109: v1(170.05,109.6) 173.74,109.6 174.12,109.98 180.59,109.98 v1(181.1,109.47)
  L10-SIGNAL w0.089: v1(181.1,109.47) 183.64,109.47 185.42,111.25 197.61,111.25 210.31,123.95 TP96.1
  BOTTOM w0.132: R728.1 181.1,106.43 v1(181.1,109.47)
PGD_UV_DETECT: length 15.5
  TOP w0.132: v1(200.91,125.22) 200.91,125.99 U147.3 ; RJ17.3 TP98.1 ; Q18.3 v1(199.79,130.19)
  L3-SIGNAL w0.109: v1(200.91,125.22) 200.91,127.25 200.41,127.76 200.41,129.57 v1(199.79,130.19)
  L10-SIGNAL w0.089: TP98.1 203.96,125.22 v1(200.91,125.22)
  BOTTOM w0.132: R756.1 v1(200.91,125.22)
PHA: length 23.3
  TOP w0.254: v1(170.05,114.98) U18.7
  TOP w0.508: 168.28,132.4 Q7.2 ; 164.02,133.35 R87.2 163.32,132.52 ; 167,132.4 Q7.1 166.39,133.35 ; 169.54,132.4 Q7.3
  TOP w1.27: L10.1 165.25,126.5 ; L10.1 161.14,126.5 ; L10.1 163.19,125.11 ; L10.1 163.19,127.9
  BOTTOM w0.508: v2(168.28,122.81) 168.28,118.62 169.16,117.73 169.16,115.87 v1(170.05,114.98) 171.28,114.98 C334.1
  vias: v2(160.66,128.27) v2(161.93,128.27) v2(163.19,128.27) v2(164.47,128.27) v2(167,132.08) v2(168.28,132.08) v2(169.54,132.08) v2(169.54,122.81) v2(171.07,122.81) v2(172.09,122.81) v2(173.35,122.81)
PHB: length 25.1
  TOP w0.254: v1(180.47,114.98) U18.32
  TOP w0.508: 188.4,133.35 R88.2 189.1,132.52 ; 179.09,133.35 Q8.1 179.71,132.4 ; 180.97,132.4 Q8.2 ; 182.25,132.4 Q8.3
  TOP w1.778: L11.1 188.59,127.34 ; L11.1 191.55,125.63 ; L11.1 188.59,123.91 ; L11.1 185.64,125.63
  BOTTOM w0.508: C333.1 180.29,114.81 v1(180.47,114.98) 181.36,115.87 181.36,117.86 183.01,119.51 v2(183.01,121.79)
  vias: v2(177.16,122.81) v2(178.44,122.81) v2(179.71,132.13) v2(179.71,122.81) v2(180.97,132.13) v2(180.97,122.81) v2(182.25,132.13) v2(187.32,128.27) v2(188.59,128.27) v2(189.87,128.27) v2(191.13,128.27) v2(192.41,127) v2(192.41,125.73) v2(192.41,124.46)
PM1_SCL: length 315.8
  TOP w0.132: v1(146.94,91.31) 146.8,91.17 146.8,90.04 ; RU10.2 v1(199.54,40.23) ; U79.5 129.56,39.64 129.79,39.88 129.79,40.62 v1(129.28,41.14) U79.2 ; v1(137.67,14.22) 137.67,13.54 137.98,13.22 U80.5
  L7-SIGNAL w0.089: v1(135.95,44.19) 135.5,44.64 135.5,47.99 136.27,48.77 136.27,50.55 140.34,54.61 140.34,57.11 141.35,58.13 141.35,59.69 144.15,62.48 144.15,66.55 v1(145.92,68.33)
  L10-SIGNAL w0.089: v1(146.94,91.31) 146.3,90.68 144.53,90.68 144.15,91.06 144.15,98.93 144.53,99.31 144.53,112.78 143.13,114.17 139.83,114.17 137.81,116.19 137.81,117.21 137.41,117.6 136.27,117.6 134.81,119.07 134.81,121.61 v1(134.49,121.92) ; v1(178.05,85.09) 179.32,85.09 182.88,81.53 182.88,68.6 v1(183.39,68.09) 182.88,67.59 182.88,66.42 v1(183.39,65.91) 182.88,65.41 182.88,64.92 v1(183.39,64.41) 183.39,63.75 182.75,63.12 182.25,63.12 181.61,62.48 181.61,61.24 v1(182.12,60.73) 181.36,59.97 181.36,58.17 v1(178.82,55.63) ; v1(137.67,14.22) 137.14,14.75 137.14,15.98 137.54,16.38 137.54,28.19 136.14,29.59 136.14,31.75 128.84,39.05 128.84,40.7 v1(129.28,41.14) ; v1(138.68,74.42) 142.24,74.42 145.92,70.74 v1(145.92,68.33)
  L12-SIGNAL w0.089: v1(182.12,60.73) 185.04,57.81 185.04,57.28 192.02,50.29 192.91,50.29 197.1,46.1 197.1,44.7 199.54,42.27 v1(199.54,40.23) 199.54,38.58 200.28,37.85 208.03,37.85 208.66,38.48 209.69,38.48 210.28,39.08 v1(210.32,39.08) 212.38,39.08 212.85,38.61 214.62,38.61 214.75,38.73 v1(215.14,38.73) ; v1(129.28,41.14) 132.75,44.61 135.54,44.61 v1(135.95,44.19)
  L14-SIGNAL w0.109: v1(145.92,68.33) 146.94,69.34 v1(146.94,91.31) 151.13,87.12 v1(153.31,87.12) 153.8,86.64 155.07,86.64 v1(155.55,87.12) v1(158.01,87.12) 158.5,86.64 159.77,86.64 v1(160.25,87.12) 161.8,87.12 162.16,86.76 164.47,86.76 v1(164.95,87.25) 172.59,87.25 175.26,84.58 176.02,84.58 v1(176.53,85.09) 177.04,84.58 177.55,84.58 v1(178.05,85.09) ; v1(163.83,59.05) 168.53,59.05 171.96,55.63 v1(178.82,55.63)
  BOTTOM w0.132: v1(183.39,68.09) 183.27,68.21 U69.5 ; U67.5 182,60.85 v1(182.12,60.73) 182.75,61.36 182.75,62.48 182.39,62.85 U67.1 ; U82.5 164.83,87.37 v1(164.95,87.25) ; U66.5 160.13,87.24 v1(160.25,87.12) ; U66.1 158.13,87.24 v1(158.01,87.12) ; U68.2 183.27,66.03 v1(183.39,65.91) ; U83.5 177.91,85.23 v1(178.05,85.09) ; v1(210.32,39.08) 210.32,39.11 210.31,39.12 R635.1 ; U85.5 138.54,74.56 v1(138.68,74.42) ; U133.2 v1(215.14,38.73) ; v1(135.95,44.19) 135.95,44.26 136.27,44.58 U86.5 ; v1(134.49,121.92) 134.63,122.05 J17.36 ; v1(176.53,85.09) 176.41,85.21 U83.2 ; v1(163.83,59.05) 163.69,59.2 U70.5 ; v1(145.92,68.33) 145.78,68.18 U84.5 ; U65.1 153.43,87.24 v1(153.31,87.12) ; U71.5 178.67,55.48 v1(178.82,55.63) ; U68.5 183.27,64.53 v1(183.39,64.41) ; v1(155.55,87.12) 155.43,87.24 U65.5
PM1_SDA: length 328.1
  TOP w0.132: U80.2 v1(140.2,14.72) 140.2,14.31 140.21,14.3 140.21,13.97 139.96,13.72 U80.4 ; v1(146.18,91.31) 146.3,91.19 146.3,90.04 ; U79.4 v1(129.28,40.14) ; v1(200.03,38.73) 199.57,38.28 RU10.5
  L7-SIGNAL w0.089: v1(145.92,67.56) 145.92,66.8 144.35,65.23 144.35,62.4 141.55,59.61 141.55,58.05 140.59,57.08 140.59,54.61 140.54,54.56 140.54,54.53 136.47,50.46 136.47,48.68 135.76,47.97 135.76,45.47 136.53,44.7 136.53,44.2 136.14,43.81 135.59,43.81 v1(135.3,44.11)
  L10-SIGNAL w0.089: v1(177.29,85.09) 177.8,85.6 179.71,85.6 183.39,81.92 v1(183.39,70.1) v1(183.39,68.86) 183.9,68.35 183.9,67.18 v1(183.39,66.67) 183.9,66.17 183.9,63.27 v1(182.12,61.49) 182.63,60.98 182.63,60.45 181.71,59.53 181.71,57.75 v1(178.82,54.86) ; v1(145.92,67.56) 144.78,68.71 144.78,71.25 141.99,74.03 138.31,74.03 v1(137.92,74.42) ; v1(146.18,91.31) 147.19,92.33 147.19,93.47 146.69,93.98 146.69,96.27 145.29,97.66 145.29,113.03 143.59,114.73 141.39,114.73 140.8,115.32 140.8,115.69 140.81,115.69 140.81,117.19 139.38,118.62 137.73,118.62 136.81,119.54 136.81,121.69 v1(136.48,122.01) ; v1(129.28,40.14) 129.28,39.25 136.65,31.88 136.65,29.72 137.92,28.45 137.92,16.29 139.49,14.72 v1(140.2,14.72)
  L12-SIGNAL w0.089: v1(135.3,44.11) 134.19,44.11 131.58,41.5 130.64,41.5 v1(129.28,40.14) ; v1(182.12,61.49) 185.42,58.19 185.42,57.4 191.64,51.18 193.55,51.18 197.49,47.24 197.49,44.83 200.03,42.29 v1(200.03,38.73) 203.84,38.73 204.1,39 v1(209.17,39) 209.42,39 212.34,41.91 214.25,41.91 v1(215.14,42.8)
  L14-SIGNAL w0.109: v1(161.57,59.05) 162.07,58.55 168.4,58.55 172.09,54.86 v1(178.82,54.86) ; v1(177.29,85.09) 174.74,87.65 164.61,87.65 v1(164.21,87.25) 163.79,87.67 160.06,87.67 v1(159.51,87.12) 159,87.63 155.32,87.63 v1(154.81,87.12) v1(154.05,87.12) 153.29,87.88 151.26,87.88 147.32,91.82 146.69,91.82 v1(146.18,91.31) 146.18,84.13 146.45,83.86 146.45,70.37 145.53,69.45 145.53,67.96 v1(145.92,67.56)
  BOTTOM w0.132: U86.4 137.04,43.7 136.91,43.57 135.84,43.57 v1(135.3,44.11) ; U67.4 181.98,61.35 v1(182.12,61.49) ; U70.1 161.69,59.17 v1(161.57,59.05) 162.07,58.55 162.81,58.55 163.19,58.92 U70.4 ; v1(136.48,122.01) 136.19,122.3 136.02,122.3 135.63,122.69 J17.38 ; v1(183.39,68.86) 183.25,68.71 U69.4 ; U71.1 179.09,53.48 179.32,53.72 179.32,54.36 v1(178.82,54.86) 178.7,54.98 U71.4 ; v1(164.21,87.25) 164.33,87.37 U82.4 ; U65.4 154.93,87.24 v1(154.81,87.12) ; U66.4 159.63,87.24 v1(159.51,87.12) ; R636.1 v1(209.17,39) ; U69.2 183.25,69.72 183.39,69.85 v1(183.39,70.1) 183.28,70.22 U69.1 ; v1(154.05,87.12) 153.93,87.24 U65.2 ; v1(177.29,85.09) 177.41,85.21 U83.4 ; U68.4 183.25,65.03 183.88,65.67 183.88,66.18 v1(183.39,66.67) 183.25,66.53 U68.1 ; U131.2 v1(215.14,42.8) ; v1(137.92,74.42) 138.04,74.54 U85.4 ; U84.2 145.8,66.68 145.92,66.8 v1(145.92,67.56) 145.8,67.68 U84.4
PM2_SCL: length 314.6
  TOP w0.132: RU10.3 v1(199.1,39.58) ; 149.87,90.04 149.87,91.17 v1(150.01,91.31) ; 151.37,90.04 151.37,91.17 v1(151.51,91.31)
  L10-SIGNAL w0.089: v1(211.2,47.24) 211.2,36.45 v1(210.31,35.56) ; v1(135.38,122.05) 135.01,121.67 135.01,119.5 136.65,117.86 137.67,117.86 138.03,117.49 138.03,116.61 140.21,114.43 143.38,114.43 144.91,112.9 144.91,97.28 145.29,96.9 145.29,95.5 144.53,94.74 144.53,92.46 v1(145.03,91.95) ; v1(147.96,62.1) 149.22,60.83 v1(149.22,60.18) 149.22,58.8 148.46,58.04 148.46,54.63 v1(147.96,54.12) ; v1(188.21,149.35) 184.66,145.8 184.66,130.3 182.12,127.76 182.12,120.78 178.94,117.6 178.94,108.97 177.8,107.82 172.21,107.82 170.81,106.43 170.81,99.69 170.18,99.06 v1(170.18,97.3) 170.32,97.16 173.97,97.16 v1(176.28,94.85) 176.28,92.33 173.48,89.53 v1(173.48,84.96) 175.26,86.74 180.34,86.74 186.92,80.16 186.92,76.45 v1(186.44,75.97) 186.94,75.46 186.94,72.67 v1(186.44,72.16) 184.66,70.38 184.66,59.69 184.53,59.56 v1(184.53,57.17)
  L12-SIGNAL w0.089: v1(184.53,57.17) 191.79,49.91 192.53,49.91 196.6,45.85 196.6,44.7 199.1,42.2 v1(199.1,39.58) 199.1,38.52 201.29,36.32 209.55,36.32 v1(210.31,35.56) ; v1(147.96,54.12) 148.23,54.4 151.55,54.4 152.53,55.37 156.59,55.37 156.97,54.99 170.05,54.99 v1(171.83,56.77)
  L14-SIGNAL w0.109: v1(145.03,91.95) 146.18,91.95 146.43,92.2 147.61,92.2 148.08,91.74 149.59,91.74 v1(150.01,91.31) 150.5,90.83 151.03,90.83 v1(151.51,91.31) 156.59,91.31 160.06,94.78 167.67,94.78 v1(170.18,97.3) ; v1(184.53,57.17) 181.75,57.17 180.85,56.26 172.34,56.26 v1(171.83,56.77)
  BOTTOM w0.132: 171.97,55.5 171.97,56.63 v1(171.83,56.77) ; v1(210.31,35.56) 210.57,35.81 R648.2 ; J17.37 135.13,122.3 v1(135.38,122.05) ; U91.5 186.32,72.28 v1(186.44,72.16) 186.83,72.56 186.83,73.26 186.32,73.78 U91.2 ; U76.5 v1(149.22,60.18) ; U78.5 148.07,54.24 v1(147.96,54.12) ; U130.2 v1(211.2,47.24) ; U90.5 188.07,149.21 v1(188.21,149.35) ; U89.5 v1(176.28,94.85) ; U73.5 v1(184.53,57.17) ; U75.5 186.32,76.09 v1(186.44,75.97) 186.83,76.37 186.83,77.07 186.32,77.59 U75.2 ; U74.5 173.34,85.11 v1(173.48,84.96) ; v1(147.96,62.1) 148.1,62.25 U77.5 ; U88.5 v1(170.18,97.3)
PM2_SDA: length 322
  TOP w0.132: RU10.6 v1(199.14,37.63) ; v1(150.75,91.31) 150.87,91.19 150.87,90.04
  L10-SIGNAL w0.089: v1(171.2,84.96) 171.7,84.45 172.21,84.45 v1(172.72,84.96) ; v1(136.99,122.43) 136.99,122.04 137.03,122 137.03,119.64 137.79,118.87 139.45,118.87 141.01,117.31 141.01,115.53 141.48,115.06 143.76,115.06 145.67,113.16 145.67,103 146.56,102.11 146.56,97.79 147.45,96.9 147.45,96.52 149.1,94.87 149.1,92.96 v1(150.75,91.31) ; v1(147.96,62.87) 147.57,62.48 147.57,61.21 146.95,60.59 v1(146.95,59.68) 146.95,58.67 147.45,58.17 147.45,55.37 v1(147.96,54.86) ; v1(209.54,35.57) 210.19,34.92 210.82,34.92 211.71,35.81 211.71,43.81 v1(215.14,47.24) ; 186.41,74.27 186.41,73.56 186.44,73.53 v1(186.44,72.92) 184.28,70.76 184.28,59.82 184.02,59.56 v1(184.02,57.78) ; 186.41,74.27 185.93,74.75 185.93,76.22 v1(186.44,76.73) 185.93,77.24 185.93,80.39 180.09,86.23 176.02,86.23 174.24,84.45 173.23,84.45 v1(172.72,84.96) ; 186.41,74.27 v1(186.42,74.28) ; v1(187.45,149.35) 184.15,146.05 184.15,130.56 181.61,128.02 181.61,121.16 178.44,117.98 178.44,109.35 177.55,108.46 172.09,108.46 170.31,106.68 170.31,100.33 v1(167.77,97.79) 169.29,96.27 173.86,96.27 v1(175.77,94.35) 175.77,92.58 172.72,89.53 v1(172.72,84.96)
  L12-SIGNAL w0.089: v1(172.59,56.77) 171.96,57.4 171.2,57.4 169.13,55.34 157.26,55.34 156.84,55.75 151.13,55.75 150.24,54.86 v1(147.96,54.86) ; v1(209.54,35.57) 201.2,35.57 v1(199.14,37.63) 198.63,38.14 198.63,42.16 196.22,44.58 196.22,45.72 192.79,49.15 191.77,49.15 184.02,56.9 v1(184.02,57.78)
  L14-SIGNAL w0.109: v1(184.02,57.78) 180.45,57.78 180.32,57.91 174.37,57.91 173.23,56.77 v1(172.59,56.77) ; v1(167.77,97.79) 167.77,96.01 167.13,95.38 165.1,95.38 164.72,95.76 160.4,95.76 156.59,91.95 151.38,91.95 v1(150.75,91.31)
  BOTTOM w0.132: 173.47,56.77 173.86,56.77 173.97,56.66 173.97,55.5 ; 173.47,56.77 173.47,55.5 ; 173.47,56.77 v1(172.59,56.77) 172.47,56.65 172.47,55.5 ; U129.2 v1(215.14,47.24) ; U73.4 183.49,57.67 183.61,57.78 v1(184.02,57.78) 184.02,58.55 183.4,59.17 U73.1 ; v1(186.44,76.73) 186.29,76.59 U75.4 ; v1(171.2,84.96) 171.34,85.11 U74.1 ; R649.2 209.3,35.81 v1(209.54,35.57) ; v1(136.99,122.43) 136.53,122.43 136.13,122.83 J17.39 ; U77.4 148.07,62.75 v1(147.96,62.87) ; v1(187.45,149.35) 187.57,149.23 U90.4 ; v1(147.96,54.86) 148.07,54.74 U78.4 ; U91.4 186.29,72.78 v1(186.44,72.92) ; U89.4 v1(175.77,94.35) ; U74.4 172.84,85.08 v1(172.72,84.96) ; U91.1 v1(186.42,74.28) ; U76.4 v1(146.95,59.68) 146.95,58.81 147.08,58.68 U76.2 ; U88.4 167.77,97.8 v1(167.77,97.79) 167.77,98.67 167.9,98.8 U88.2
PM_BRD_PWR_OFF: length 100.9
  TOP w0.132: v1(201.68,154.05) R66.1 202.62,154.06 Q6.G
  L10-SIGNAL w0.089: v1(201.68,154.05) 198.63,157.1 172.21,157.1 171.2,158.12 157.61,158.12 155.96,156.46 155.96,152.65 156.21,152.4 156.21,145.29 152.27,141.35 147.57,141.35 146.56,140.34 146.56,139.32 144.91,137.67 144.27,137.67 143.89,137.29 142.75,137.29 134.11,128.65 v1(129.62,128.65)
  BOTTOM w0.132: J17.26 v1(129.62,128.65)
PM_OEN: length 220.2
  TOP w0.132: RU10.15 206.13,40.23 R264.2 v1(206.16,40.86) ; R161.2 v1(163.19,95.25)
  L3-SIGNAL w0.109: v1(163.19,95.25) 161.67,95.25 161.2,95.72 147.23,95.72 146.18,96.77 129.29,96.77 127.51,98.55 123.95,98.55 123.06,97.66 118.49,97.66 115.9,95.07 103.82,95.07 103.77,95.12 103.76,95.12 103.5,95.38 103.5,95.76 103.11,96.16 101.74,96.16 100.33,94.74 87.25,94.74 86.32,95.68 85.17,95.68 84.07,96.77 v1(82.04,96.77)
  L7-SIGNAL w0.089: v1(82.04,96.77) 82.04,97.8 81.79,98.05 81.79,102.74 82.04,103 82.04,125.55 v1(77.95,129.64) ; v1(163.19,95.25) 164.08,95.25 170.69,88.65 190.12,88.65 190.49,89.02 v1(202.31,89.02)
  L10-SIGNAL w0.089: v1(206.16,40.86) 206.16,42.76 205.04,43.88 205.04,46.04 202.95,48.13 202.95,56.26 203.33,56.64 203.33,88 v1(202.31,89.02)
  BOTTOM w0.132: RU19.1 162.93,94.99 v1(163.19,95.25) ; U110.4 v1(77.95,129.64)
PM_PORN: length 138.7
  L3-SIGNAL w0.109: v1(196.72,118.36) 196.72,75.56 192.53,71.37 192.53,54.86 191.77,54.1 v1(191.77,52.32)
  L7-SIGNAL w0.089: v1(130.18,122.45) 130.78,123.06 144.53,123.06 145.16,122.43 167,122.43 171.07,118.36 v1(196.72,118.36)
  BOTTOM w0.132: R534.1 v1(191.77,52.32) ; v1(130.18,122.45) 130.12,122.51 J17.27
PM_RESETN: length 136.9
  L3-SIGNAL w0.109: v1(202.69,57.66) 202.69,60.07 200.41,62.36 200.41,69.6 201.8,70.99 201.8,76.83 201.29,77.34 v1(201.29,116.97)
  L7-SIGNAL w0.089: v1(201.29,116.97) 198.25,116.97 197.61,117.6 187.83,117.6 187.45,117.98 170.43,117.98 167.51,120.9 154.69,120.9 154.43,121.16 145.29,121.16 144.91,121.54 134.11,121.54 133.86,121.79 v1(130.18,121.79)
  BOTTOM w0.132: v1(130.18,121.79) 130.62,122.24 J17.28 ; R519.1 v1(202.69,57.66)
PM_SEL: length 216.7
  TOP w0.132: RU10.1 197.79,40.89 R263.2 v1(195.41,41.49)
  L3-SIGNAL w0.109: v1(195.2,122.3) 197.49,120.02 197.49,62.61 194.82,59.94 194.82,54.74 195.58,53.98 195.58,44.32 194.94,43.69 194.94,41.96 v1(195.41,41.49)
  L14-SIGNAL w0.109: v1(82.11,132.65) 84.84,135.38 93.34,135.38 93.73,135.76 103.89,135.76 104.78,134.87 112.65,134.87 113.79,133.73 117.48,133.73 118.49,132.72 129.67,132.72 136.53,125.86 187.96,125.86 191.52,122.3 v1(195.2,122.3)
  BOTTOM w0.132: U110.7 80.83,127.69 82.11,128.97 v1(82.11,132.65)
PMIC2_PG_1V8: length 9.1
  TOP w0.132: U40.16 v1(140.2,59.32) ; U40.2 v1(134.89,61.32)
  L10-SIGNAL w0.089: v1(134.89,61.32) 135.89,60.33 135.89,60.07 136.64,59.32 v1(140.2,59.32)
  BOTTOM w0.132: R496.2 140.72,59.44 140.6,59.32 v1(140.2,59.32)
PMIC_REGEN_DDR: length 90
  TOP w0.132: v1(169.04,74.42) 168.28,74.42 167.23,73.38 U38.12 ; R285.1 v1(138.3,31.5) 138.3,34.04 139.57,35.31 v1(139.57,38.23)
  L10-SIGNAL w0.089: v1(169.04,74.42) 169.04,73.03 170.56,71.5 170.56,65.66 169.93,65.03 169.93,62.36 167.64,60.07 167.64,51.56 167.13,51.05 167.13,43.81 164.87,41.55 v1(164.87,38.89) ; v2(145.52,25.37) 144.55,25.37 142.24,27.69 141.35,27.69 139.7,29.34 139.7,30.1 v1(138.3,31.5)
  L14-SIGNAL w0.109: v1(164.87,38.89) 163.43,38.89 162.43,39.88 159.77,39.88 159.52,39.64 158.61,39.64 158.37,39.88 141.22,39.88 v1(139.57,38.23)
  BOTTOM w0.132: v2(145.52,25.37) 145.89,25 U138.5 ; U134.3 137.93,38.49 138.19,38.23 R667.2 v1(139.57,38.23)
PMIC_REGEN_LP87565: length 41.6
  TOP w0.132: U38.1 167.23,66.57 v1(167.89,65.91) ; U40.7 134.93,58.82 134.9,58.79 v1(134.49,58.79)
  L14-SIGNAL w0.109: v1(134.49,58.79) 138.8,58.79 140.08,60.07 140.97,60.07 142.24,61.34 143,61.34 143.68,62.02 145.88,62.02 146.3,61.59 158.37,61.59 159,62.23 164.21,62.23 v1(167.89,65.91)
  BOTTOM w0.132: v1(167.89,65.91) 167.89,65.5 168.53,64.87 R488.2
PMIC_RESET_OUT: length 67.5
  TOP w0.132: v1(159.38,73.03) 159.68,72.73 U38.25 ; U46.1 v1(195.56,43.16)
  L10-SIGNAL w0.089: v1(195.83,70.1) 195.83,68.33 196.09,68.07 196.09,43.69 v1(195.56,43.16)
  L14-SIGNAL w0.109: v1(159.38,73.03) 159.67,72.74 177.07,72.74 178.69,71.12 183.9,71.12 184.91,70.1 v1(195.83,70.1)
  BOTTOM w0.132: R710.1 159.13,72.77 v1(159.38,73.03)
POWERHOLD: length 86.1
  TOP w0.132: U16.4 v1(211.34,129.3)
  L10-SIGNAL w0.089: v1(211.34,129.3) 211.34,128.38 212.85,126.87 212.85,123.06 196.09,106.3 196.09,92.84 193.55,90.3 v1(193.55,75.95)
  L14-SIGNAL w0.109: v1(171.32,75.06) 181.86,75.06 182.25,75.44 193.04,75.44 v1(193.55,75.95)
  BOTTOM w0.132: R547.1 v1(171.32,75.06)
PWREN#: length 54.2
  TOP w0.132: DS6.1 v1(208.69,175.74) ; v1(171.2,166.62) R7.2 170.69,167.39 170.31,167.77 168.4,167.77 168.26,167.63 U3.11
  L12-SIGNAL w0.089: v1(208.69,175.74) 206.65,175.74 203.58,178.82 175.51,178.82 173.48,176.78 173.48,168.91 v1(171.2,166.62)
R_QSPI1_CS[0]: length 3.2
  TOP w0.132: R136.1 R135.2 115.06,113.41 U20.7
R_QSPI1_D[0]: length 2.3
  TOP w0.132: R144.2 102.62,107.06 U20.15
R_QSPI1_D[1]: length 2.2
  TOP w0.132: R133.1 113.41,114.68
R_QSPI1_D[2]: length 3.5
  TOP w0.132: R131.1 103.12,116.71 104.01,115.82 104.01,114.68
R_QSPI1_D[3]: length 2.7
  TOP w0.132: U20.1 R152.2 R151.2
R_QSPI1_SCLK: length 2.2
  TOP w0.132: R146.1 102.36,105.79 U20.16
REFCLKN: length 14.7
  TOP w0.099: C44.2 32.38,150.37 32.16,150.6 v1(32.16,151) ; v1(37.72,146.05) 37.44,146.05 37.34,145.95 37.34,145.54 R57.1 37.36,144.81 37.36,144.14 37.46,144.04 37.64,144.04 37.73,143.94 P6.A14
  BOTTOM w0.099: v1(32.16,151) 31.75,150.6 31.75,149.99 33.87,147.87 36.71,147.87 37.35,147.23 37.35,146.42 v1(37.72,146.05)
REFCLKP: length 14.7
  TOP w0.099: v1(36.7,146.05) 36.98,146.05 37.08,145.95 37.08,145.54 36.7,145.16 37.08,144.79 37.08,144.14 36.98,144.04 36.83,144.04 36.73,143.94 P6.A13 ; C43.2 30.86,150.37 31.07,150.57 v1(31.07,151)
  BOTTOM w0.099: v1(36.7,146.05) 37.08,146.43 37.08,147.12 36.6,147.6 33.76,147.6 31.48,149.88 31.48,150.58 v1(31.07,151)
REGEN3_GPIO6: length 42.6
  TOP w0.132: v1(187.2,64.52) 187.49,64.81 U148.1 ; U38.27 159.58,71.73 158.5,72.81 158.5,73.33 158.24,73.58 TP58.1
  L7-SIGNAL w0.089: v1(187.2,64.52) 186.56,65.15 182.88,65.15 181.23,66.8 178.82,66.8 178.05,66.04 175.13,66.04 175.01,66.17 168.78,66.17 168.28,66.67 161.42,66.67 160.15,67.94 160.15,71.5 158.24,73.41 TP58.1
  BOTTOM w0.132: R755.1 v1(187.2,64.52)
SEL_CSI2N: length 148.4
  L3-SIGNAL w0.109: v1(45.09,123.19) 44.7,123.19 43.05,121.54 43.05,101.6 27.56,86.11 27.56,60.33 25.65,58.42 25.65,50.93 22.99,48.26 22.99,33.91 21.46,32.38 21.46,30.48 20.45,29.46 19.05,29.46 17.78,28.19 17.78,20.19 18.67,19.3 v1(19.43,19.3)
  L12-SIGNAL w0.089: v1(45.09,123.19) 44.83,123.44 44.83,124.71 45.47,125.35 57.28,125.35 57.78,124.84 60.96,124.84 61.09,124.97 65.41,124.97 65.66,124.71 67.06,124.71 67.56,124.21 v1(68.83,124.21)
  BOTTOM w0.132: v1(68.83,124.21) 69.07,124.44 U110.13 ; v1(19.43,19.3) R597.2 19.06,18.63 19.03,18.66 RU21.1
SEL_ENET_MUX_S0: length 142.6
  TOP w0.132: U21.8 v1(195.58,77)
  L3-SIGNAL w0.109: v1(195.58,77) 188.21,84.37 188.21,88.01 185.55,90.68 171.2,90.68 170.18,91.69 155.07,91.69 153.14,93.62 144.17,93.62 143.68,94.11 129.06,94.11 128.56,93.61 124.58,93.61 122.05,96.14 118.75,96.14 116.59,93.98 86.57,93.98 85.82,94.73 83.45,94.73 v1(82.68,95.5)
  L12-SIGNAL w0.089: v1(79.25,105.41) 80.39,104.27 80.39,103.89 81.79,102.49 81.79,99.31 82.68,98.42 82.68,97.19 82.68,97.19 82.68,96.87 82.68,96.86 v1(82.68,95.5)
  BOTTOM w0.132: v1(79.25,105.41) 78.99,105.16 U118.2 R489.2 ; RU17.1 82.82,95.36 v1(82.68,95.5)
SEL_ENET_MUX_S1: length 36.8
  L14-SIGNAL w0.109: v1(60.33,106.81) 63.88,106.81 68.07,102.62 69.72,102.62 73.24,99.1 74.25,99.1 75.56,97.79 81.28,97.79 v1(82.68,99.19)
  BOTTOM w0.132: U118.4 81.39,105.81 82.82,104.38 RU17.56 82.82,99.33 v1(82.68,99.19) ; RU14.1 59.93,107.2 v1(60.33,106.81)
SEL_EXP_I2C3_DCAN2: length 57.1
  TOP w0.132: R737.2 165.9,54.19 v1(165.74,54.36) ; R737.2 163.96,53.47 163.21,52.72 RU24.1 ; R737.2 165.88,53.44 RU25.1 ; U21.9 196.24,76.35 v1(195.96,76.07)
  L3-SIGNAL w0.109: v1(195.96,76.07) 192.15,72.26 192.15,58.04 v1(189.61,55.5)
  L7-SIGNAL w0.089: v1(189.61,55.5) 187.42,53.31 182.53,53.31 180.85,54.99 179.96,54.99 179.45,54.48 177.55,54.48 177.04,54.99 166.37,54.99 v1(165.74,54.36)
SEL_GPMC_AD_VID_S0: length 173.7
  TOP w0.132: U21.4 198.73,79.6 v1(198.88,79.76) ; RU7.1 85.83,96.12 v1(86.33,96.62)
  L3-SIGNAL w0.109: v1(198.88,79.76) 199.52,80.39 v1(199.52,108.84)
  L7-SIGNAL w0.089: v1(199.52,108.84) 187.45,108.84 185.55,106.93 179.96,106.93 178.31,108.58 160.78,108.58 156.72,112.65 v1(146.81,112.65) 144.65,112.65 142.49,114.81 129.79,114.81 128.27,113.28 128.02,113.28 127.51,112.78 127.51,111.89 124.21,108.58 122.43,108.58 117.98,104.14 117.98,99.31 116.2,97.54 101.5,97.54 v1(99.57,95.61)
  L10-SIGNAL w0.089: v1(86.33,96.62) 86.82,96.14 87.4,96.14 87.65,96.39 95.57,96.39 95.72,96.24 96.92,96.24 97.56,95.61 v1(99.57,95.61)
  BOTTOM w0.132: U116.2 147.45,117.47 147.15,117.18 R452.2 147.15,115.15 146.81,114.81 v1(146.81,112.65) 144.73,112.65 144.42,112.33 RU13.1 ; v1(99.57,95.61) 99.33,95.37 RU16.1
SEL_GPMC_AD_VID_S1: length 77.6
  TOP w0.132: v1(86.34,103.9) 85.83,103.39 RU7.56
  L3-SIGNAL w0.109: v1(99.31,102.87) 101.98,102.87 102.87,103.76 102.87,105.66 114.19,116.98 114.19,117.33 114.74,117.88 114.74,118.3 115.7,119.25 126.62,119.25 130.56,115.32 142.87,115.32 143.02,115.47 143.02,116.01 143.25,116.25 143.8,116.25 v1(144.42,116.87)
  L10-SIGNAL w0.089: v1(86.34,103.9) 86.98,103.9 87.26,103.63 90.54,103.63 91.32,104.4 97.78,104.4 v1(99.31,102.87)
  BOTTOM w0.132: U116.4 145.91,116.87 v1(144.42,116.87) RU13.56 ; RU16.56 99.33,102.85 v1(99.31,102.87)
SEL_I2C3_CAN2: length 65.7
  TOP w0.132: R250.2 U44.2 v1(157.73,57.28) ; v1(199.26,77.34) 198.95,77.65 U21.7
  L10-SIGNAL w0.089: v1(200.03,60.2) 200.28,60.45 200.28,74.42 199.26,75.44 v1(199.26,77.34)
  L14-SIGNAL w0.109: v1(157.73,57.28) 158.5,57.28 160.91,59.69 178.31,59.69 179.2,60.58 181.36,60.58 181.74,60.2 v1(200.03,60.2)
SEL_UART3_SPI2: length 82.9
  TOP w0.132: R248.2 v1(159.77,48.26) ; v1(205.49,78.3) U21.19
  L10-SIGNAL w0.089: v1(204.85,48.77) 204.85,53.47 204.22,54.1 204.22,61.85 204.09,61.98 204.09,72.01 205.74,73.66 205.74,78.05 v1(205.49,78.3)
  L14-SIGNAL w0.109: v1(159.77,48.26) 164.47,48.26 165.61,49.4 166.75,49.4 167.13,49.02 180.47,49.02 183.01,51.56 185.42,51.56 185.93,51.05 194.94,51.05 195.83,50.16 200.79,50.16 202.18,48.77 v1(204.85,48.77)
  BOTTOM w0.132: RU23.1 158.45,48.23 159.74,48.23 v1(159.77,48.26)
SEL_VCC_CSI2_IO: length 274.4
  TOP w0.132: SW6.17 v1(209.3,76.96) ; v1(19.68,28.07) 19.88,28.27 U140.3
  L3-SIGNAL w0.109: v1(19.68,28.07) 19.68,26.54 20.46,25.76 20.46,15.38 19.94,14.86 v1(19.94,11.43)
  L10-SIGNAL w0.089: v1(19.94,11.43) 20.32,11.05 149.86,11.05 154.31,15.49 160.02,15.49 163.07,18.54 207.26,18.54 208.66,19.94 208.66,25.65 206.63,27.69 206.63,37.97 208.03,39.37 208.03,50.16 209.17,51.31 209.17,58.29 210.95,60.07 210.95,62.48 208.28,65.15 208.28,75.95 v1(209.3,76.96)
  BOTTOM w0.132: R482.2 v1(209.3,76.96)
SERDES_IN_REFN: length 7.7
  TOP w0.099: U10.2 28.37,147.85 28.52,147.99 28.77,147.99 29.14,147.63 29.14,146.79 30.01,145.91 31.07,145.91 31.55,146.38 31.55,146.99 31.88,147.32 C53.2
SERDES_IN_REFP: length 6.8
  TOP w0.099: U10.3 28.37,148.35 28.45,148.26 28.88,148.26 29.41,147.74 29.41,146.9 30.12,146.18 30.96,146.18 31.28,146.49 31.28,147 30.96,147.32 C52.2
SLEEP_CLK: length 2.3
  TOP w0.132: R273.2 11.49,35.43
SPI[1]_SCLK: length 58.2
  TOP w0.132: R265.1 118.62,42.42 118.73,42.53 v1(118.75,42.53)
  L5-SIGNAL w0.089: v1(121.92,93.22) 119.63,90.93 119.63,69.85 120.78,68.71 120.78,66.8 122.43,65.15 122.43,58.55 121.79,57.91 121.79,54.36 122.68,53.47 122.68,52.45 121.28,51.05 121.28,48.9 120.37,47.98 119.85,47.98 118.24,46.36 118.24,43.04 v1(118.75,42.53)
  BOTTOM w0.132: EXP_P3.35 v1(121.92,93.22)
SPI[2]_CS[0]N: length 63.9
  L10-SIGNAL w0.089: v1(150.88,46.77) 151.64,47.53 151.64,53.09 151.89,53.34 151.89,56.77 153.03,57.91 v1(153.03,79.88)
  L12-SIGNAL w0.089: v1(153.03,79.88) 148.21,79.88 147.45,79.12 134.24,79.12 133.1,80.26 v1(131.59,80.26)
  BOTTOM w0.132: RU23.13 151.35,46.3 v1(150.88,46.77) ; v1(131.59,80.26) 130.94,80.26 130.3,79.63 EXP_P3.2
SPI[2]_MISO: length 70.6
  L12-SIGNAL w0.089: v1(122.17,79.18) 122.17,70.1 125.22,67.06 125.22,51.18 126.36,50.04 131.57,50.04 133.35,48.26 148.97,48.26 149.99,47.24 151.89,47.24 152.78,46.35 156.34,46.35 156.97,45.72 159,45.72 v1(159.77,44.96)
  BOTTOM w0.132: RU23.6 159.73,45 v1(159.77,44.96) ; EXP_P3.3 121.52,80.42 122.17,79.76 v1(122.17,79.18)
SPI[2]_MOSI: length 67.3
  L10-SIGNAL w0.089: v1(151,44.58) 152.27,45.85 152.27,56.64 153.52,57.89 153.52,79.48 v1(153.8,79.76)
  L12-SIGNAL w0.089: v1(153.8,79.76) 152.78,80.77 147.07,80.77 146.05,79.76 134.11,79.76 132.97,80.9 v1(131.83,80.9)
  BOTTOM w0.132: RU23.10 151.23,44.35 v1(151,44.58) ; EXP_P3.4 130.33,80.42 130.81,80.9 v1(131.83,80.9)
SPI[2]_SCLK: length 71.1
  L10-SIGNAL w0.089: v1(161.02,47.13) 160.53,47.62 160.53,48.26 157.73,51.05 157.73,52.83 156.59,53.97 156.59,61.47 156.19,61.87 v1(156.19,74.95) ; v1(120.4,78.87) 120.78,78.87 120.91,78.74 136.91,78.74 140.72,74.93 v1(147.7,74.93)
  L12-SIGNAL w0.089: v1(156.19,74.95) 155.83,75.31 148.08,75.31 v1(147.7,74.93)
  BOTTOM w0.132: EXP_P3.1 120.19,79.07 v1(120.4,78.87) ; RU23.3 160.43,46.95 160.61,47.13 v1(161.02,47.13)
SW_VPP_EN: length 7.5
  TOP w0.132: RU11.2 205.87,82.93 208.03,80.77 SW6.14
TMP102_ALERT: length 172
  TOP w0.132: U53.3 109.63,42.32 v1(109.73,42.42) ; U21.16 v1(206.98,76.35)
  L3-SIGNAL w0.109: v1(206.98,76.35) 206.98,69.32 206.63,68.96 206.63,67.06 v1(207.01,66.67)
  L10-SIGNAL w0.089: v1(205.49,19.43) 205.49,38.99 206.76,40.26 206.76,43.05 205.49,44.32 205.49,62.36 207.01,63.88 v1(207.01,66.67)
  L14-SIGNAL w0.109: v1(205.49,19.43) 204.85,18.8 175.9,18.8 172.85,21.84 171.07,21.84 168.15,18.92 164.47,18.92 158.75,24.64 155.57,24.64 152.15,28.07 143.13,28.07 140.95,30.24 137.27,30.24 131.44,36.07 127.51,36.07 123.06,40.51 113.79,40.51 111.51,42.8 110.11,42.8 v1(109.73,42.42)
TRSTPD: length 4
  TOP w0.132: J13.8 156.88,36.29 156.61,36.56 v1(156.59,36.56)
  BOTTOM w0.132: R663.1 156.59,35.81 v1(156.59,36.56) 156.59,36.58 156.34,36.83 156.34,37.72
TS_LCD_GPIO1: length 58.7
  TOP w0.132: v1(194.06,68.45) 194.46,68.05 U30.4
  L10-SIGNAL w0.089: v1(175.38,23.3) 175.38,28.44 178.44,31.5 179.2,31.5 179.83,32.13 179.83,32.98 179.83,32.99 179.83,35.43 185.04,40.64 185.04,49.02 194.06,58.04 v1(194.06,68.45)
  BOTTOM w0.132: J19.48 v1(175.38,23.3)
TS_LCD_GPIO2: length 59
  TOP w0.132: U30.5 v1(194.44,67.4)
  L10-SIGNAL w0.089: v1(174.88,22.61) 175.26,22.61 175.9,23.24 175.9,27.56 178.69,30.35 179.32,30.35 181.36,32.38 181.36,36.45 185.42,40.51 185.42,47.88 186.44,48.9 186.44,49.78 194.44,57.79 v1(194.44,67.4)
  BOTTOM w0.132: J19.46 v1(174.88,22.61)
TS_LCD_GPIO3: length 57.5
  TOP w0.132: v1(193.55,66.67) 195.74,66.67 195.81,66.75 U30.6
  L10-SIGNAL w0.089: v1(193.55,66.67) 193.55,58.04 183.9,48.39 183.9,40.01 179.45,35.56 179.45,34.16 178.31,33.02 178.31,31.75 174.24,27.69 174.24,25.78 174.38,25.65 v1(174.38,23.12)
  BOTTOM w0.132: J19.44 v1(174.38,23.12)
TS_LCD_GPIO4: length 58.4
  TOP w0.132: U30.7 v1(193.04,66.1)
  L10-SIGNAL w0.089: v1(173.88,22.62) 173.88,28.08 177.16,31.37 177.16,33.78 183.51,40.13 183.51,48.51 193.17,58.17 193.17,65.97 v1(193.04,66.1)
  BOTTOM w0.132: J19.42 v1(173.88,22.62)
UART3_CTS: length 218.1
  TOP w0.132: v1(21.06,67.82) 20.57,68.31 U39.8
  L10-SIGNAL w0.089: v1(154.71,44.98) 155.83,43.86 155.83,38.73 153.67,36.58 153.67,24.26 149.35,19.94 149.35,18.41 145.54,14.61 141.73,14.61 140.21,13.08 136.14,13.08 135.89,13.34 107.44,13.34 106.68,12.57 25.27,12.57 v1(24.64,13.21)
  L14-SIGNAL w0.109: v1(21.06,67.82) 21.06,60.6 21.34,60.33 21.34,54.23 21.84,53.72 21.84,50.42 22.24,50.02 22.24,15.6 v1(24.64,13.21)
  BOTTOM w0.132: v1(154.71,44.98) 154.3,44.98 154.28,45 RU23.11
UART3_RTS: length 213.4
  TOP w0.132: U43.9 19.5,53.19 19.73,52.96 v1(20.95,52.96)
  L10-SIGNAL w0.089: v1(153.92,46.77) 154.91,46.77 155.57,46.1 155.57,44.7 156.08,44.2 156.08,42.33 156.08,42.32 156.08,42 156.08,42 156.08,38.61 154.05,36.58 154.05,16.96 153.91,16.81 153.72,16.81 153.3,17.23 153.12,17.23 152.99,17.1 152.99,16.92 153.41,16.5 153.41,16.31 153.28,16.18 153.09,16.18 152.68,16.6 152.49,16.6 152.36,16.47 152.36,16.29 152.78,15.87 152.78,15.68 150.65,13.56 150.65,13.54 150.41,13.3 150.4,13.3 149.24,12.14 24.94,12.14 23.75,13.34 v1(21.72,13.34)
  L14-SIGNAL w0.109: v1(21.72,13.34) 21.44,13.62 21.44,49.68 20.95,50.17 v1(20.95,52.96)
  BOTTOM w0.132: RU23.14 153.71,46.95 153.89,46.77 v1(153.92,46.77)
UART3_RXD: length 226.5
  TOP w0.132: U39.7 v1(20.32,67.81)
  L10-SIGNAL w0.089: v1(159.77,47.39) 159.13,46.75 159.13,41.4 159.51,41.02 159.51,36.61 158.97,36.06 158.97,30.06 154.34,25.44 154.34,16.83 150.95,13.44 150.95,13.42 150.53,13.01 150.52,13.01 149.36,11.85 22.95,11.85 v1(22.23,12.57)
  L14-SIGNAL w0.109: v1(22.23,12.57) 22.23,13.59 21.84,13.97 21.84,49.91 21.46,50.29 21.46,53.47 20.95,53.98 20.95,60.2 20.32,60.83 v1(20.32,67.81)
  BOTTOM w0.132: RU23.2 159.54,47.6 159.75,47.39 v1(159.77,47.39)
UART3_TXD: length 211.8
  TOP w0.132: U43.10 19.58,53.69 19.66,53.61 v1(20.08,53.61)
  L10-SIGNAL w0.089: v1(21.08,12.83) 22.35,11.56 149.48,11.56 150.64,12.72 150.65,12.72 151.24,13.3 151.24,13.32 154.64,16.71 154.64,25.22 159.26,29.84 159.26,35.94 160.27,36.96 160.27,45.32 v1(159.77,45.83)
  L14-SIGNAL w0.109: v1(20.08,53.61) 20.36,53.33 20.36,50.25 21.08,49.53 v1(21.08,12.83)
  BOTTOM w0.132: RU23.5 159.57,45.65 159.75,45.83 v1(159.77,45.83)
UART_SEL1_3: length 118.7
  TOP w0.132: U21.17 v1(204.72,77) 207.05,77 208.28,78.23 v1(209.3,78.23) SW6.16 ; RU2.1 168.65,157.35 168.78,157.21 v1(168.78,156.21)
  L3-SIGNAL w0.109: v1(204.72,77) 204.72,78.36 205.87,79.5 205.87,84.71 204.6,85.98 204.6,138.3 204.83,138.54 v1(204.83,140.84)
  L14-SIGNAL w0.109: v1(168.78,156.21) 183.26,156.21 198.63,140.84 v1(204.83,140.84)
  BOTTOM w0.132: R329.1 v1(168.78,156.21) ; v1(209.3,78.23) R474.2
USB1_ID: length 386.3
  TOP w0.132: U21.5 198.46,78.95 198.75,79.25 v1(200.3,79.25) ; v1(8.26,84.2) 7.11,84.2 6.82,84.49 P8.4 ; SW1.2 v1(37.97,174.37)
  L3-SIGNAL w0.109: v1(200.66,144.02) 201.17,143.51 201.17,130.68 201.68,130.18 201.68,121.54 200.66,120.52 200.66,79.63 200.3,79.26 v1(200.3,79.25)
  L14-SIGNAL w0.109: v1(8.26,84.2) 8.26,91.19 5.08,94.36 5.08,104.14 4.32,104.9 4.32,128.27 3.68,128.91 3.68,150.11 1.91,151.89 1.91,168.4 4.06,170.56 5.46,170.56 8.64,173.74 25.78,173.74 28.19,171.32 34.92,171.32 v1(37.97,174.37) 40.77,174.37 41.27,174.88 52.32,174.88 59.69,167.51 79.25,167.51 80.39,168.66 85.85,168.66 86.36,168.15 101.98,168.15 102.49,167.64 110.49,167.64 110.87,168.02 123.57,168.02 123.95,167.64 133.86,167.64 134.11,167.89 136.27,167.89 137.29,166.88 148.59,166.88 153.86,161.6 181.61,161.6 199.2,144.02 v1(200.66,144.02)
  BOTTOM w0.132: v1(8.26,84.2) 8.26,89.15 6.93,90.47 U120.5 ; v1(37.97,174.37) R308.2
USB1_VBUS_OCN: length 290.3
  TOP w0.132: U1.5 TP5.1 ; U30.15 204.46,64.15 v1(204.98,63.63)
  L3-SIGNAL w0.109: v1(202.69,143.51) 202.69,140.84 203.45,140.08 203.45,65.15 v1(204.98,63.63)
  L14-SIGNAL w0.109: v1(202.69,143.51) 199.14,143.51 182.37,160.27 170.94,160.27 170.56,160.66 165.86,160.66 165.74,160.78 162.69,160.78 162.56,160.66 153.42,160.66 149.35,164.72 148.72,164.72 146.94,166.5 136.91,166.5 135.89,167.51 134.37,167.51 134.11,167.26 123.57,167.26 123.19,167.64 111,167.64 110.62,167.26 102.23,167.26 101.73,167.77 86.23,167.77 85.76,168.24 80.49,168.24 78.36,166.12 60.07,166.12 52.45,173.74 38.1,173.74 35.18,170.81 27.94,170.81 27.3,171.45 TP5.1
  BOTTOM w0.132: v1(204.98,63.63) 204.85,63.75 R516.1
USB2_VBUS_OCN: length 310.8
  TOP w0.132: U30.16 204.75,64.8 v1(204.98,65.02) ; v1(44.94,122.32) 44.96,122.31 44.96,122.3 45.05,122.21 46.03,122.21 46.21,122.03 U141.5 ; TP6.1 34.04,159.38 34.04,160.66 33.78,160.91 32.64,160.91
  L3-SIGNAL w0.109: v1(34.54,153.8) TP6.1 ; v1(203.84,141.59) 203.84,66.17 v1(204.98,65.02)
  L14-SIGNAL w0.109: v1(203.84,141.59) 198.52,141.59 183.13,156.97 169.29,156.97 168.53,157.73 152.4,157.73 151,159.13 151,160.02 150.24,160.78 149.1,160.78 148.21,161.67 145.29,161.67 144.27,162.69 124.71,162.69 123.83,161.8 89.41,161.8 86.11,165.1 81.79,165.1 81.28,164.59 61.47,164.59 58.42,161.54 54.23,161.54 53.72,161.04 44.7,161.04 42.55,158.88 TP6.1 ; v1(44.94,122.32) 44.32,122.94 44.32,132.59 42.16,134.75 39.37,134.75 36.07,138.05 36.07,140.08 34.67,141.48 34.67,153.67 v1(34.54,153.8)
  BOTTOM w0.132: v1(204.98,65.02) R512.1
USB_AC_TXN0: length 1.3
  TOP w0.137: FL8.4 15.34,80.29 15.6,80.04 16.07,80.04 C142.2
USB_AC_TXP0: length 1.3
  TOP w0.137: C144.2 16.14,79.66 16.07,79.73 15.59,79.73 15.34,79.48 FL8.1
USB_DM_DN1: length 58.3
  TOP w0.137: v1(51.65,127.44) 51.87,127.44 52.01,127.31 52.01,126.66 51.81,126.46 U141.42 ; FL1.4 v1(74.19,163.98)
  L3-SIGNAL w0.127: v1(51.65,127.44) 51.8,127.44 52.21,127.85 52.21,128.33 53.72,129.84 61.09,129.84 63.88,132.64 63.88,135.69 70.56,142.37 70.56,154.05 75.77,159.26 75.77,164.44 74.96,165.25 74.22,165.25 73.69,164.72 73.69,164.25 73.96,163.98 v1(74.19,163.98)
USB_DM_DN2: length 234.3
  TOP w0.137: U141.15 49.81,115.96 49.62,115.76 49.62,114.57 v1(50.02,114.17)
  L7-SIGNAL w0.102: v1(176.18,22.72) 176.36,22.72 176.69,22.4 176.69,22.25 173.28,18.85 159.13,18.85 157.23,16.94 143.38,16.94 140.21,13.77 137.03,13.77 136.52,14.27 104.27,14.27 102.62,12.62 58.8,12.62 55.93,15.49 55.93,52.2 53.14,54.99 53.14,106.5 49.45,110.19 49.45,113.79 49.56,113.89 49.74,113.89 v1(50.02,114.17)
  BOTTOM w0.137: J19.52 176.38,23.47 176.57,23.27 176.57,23.12 v1(176.18,22.72)
USB_DP_DN1: length 58.4
  TOP w0.137: v1(52.51,127.44) 52.31,127.24 U141.41 ; FL1.1 v1(73.38,163.98)
  L3-SIGNAL w0.127: v1(52.51,127.44) 52.51,128.21 53.85,129.54 61.21,129.54 64.19,132.51 64.19,135.56 70.87,142.24 70.87,153.92 76.07,159.13 76.07,164.57 75.08,165.56 74.09,165.56 73.38,164.85 v1(73.38,163.98)
USB_DP_DN2: length 234.3
  TOP w0.137: v1(49.15,114.17) 49.31,114.34 U141.14
  L7-SIGNAL w0.102: v1(49.15,114.17) 49.15,110.06 52.83,106.38 52.83,54.86 55.63,52.07 55.63,15.37 58.67,12.32 102.74,12.32 104.39,13.97 136.4,13.97 136.91,13.46 140.34,13.46 143.51,16.64 157.35,16.64 159.26,18.54 173.41,18.54 176.99,22.13 176.99,22.52 177,22.54 177,22.7 v1(177.04,22.73)
  BOTTOM w0.137: J19.54 176.88,22.9 v1(177.04,22.73)
USB_HUB_PWRCLT1: length 50.2
  TOP w0.132: U2.4 27.05,160.4 v1(26.8,160.15) ; U141.4 45.74,122.53 v1(45.59,122.68)
  L3-SIGNAL w0.109: v1(35.18,151.76) v1(26.8,160.15)
  L14-SIGNAL w0.109: v1(35.18,151.76) 35.18,141.73 36.58,140.34 36.58,138.3 39.75,135.13 42.42,135.13 44.96,132.59 44.96,124.08 45.59,123.44 v1(45.59,122.68)
  BOTTOM w0.132: R309.2 v1(26.8,160.15)
USB_HUB_PWRCLT2: length 246.5
  TOP w0.132: U141.6 46.35,121.53 46.09,121.79 v1(45.34,121.79)
  L12-SIGNAL w0.089: v1(45.34,121.79) 45.47,121.67 45.47,120.78 42.42,117.73 42.42,40.39 42.8,40.01 42.8,34.42 42.42,34.04 42.42,30.23 44.2,28.45 44.2,24.16 56.93,11.43 150.24,11.43 156.34,17.53 157.61,17.53 158.62,18.54 172.97,18.54 174.62,20.19 174.62,21.21 v1(175.51,22.1)
  BOTTOM w0.132: v1(175.51,22.1) 175.51,22.73 175.88,23.1 J19.50
USER_LED1: length 23.6
  TOP w0.132: U30.8 196.38,65.45 195.58,64.64 195.58,61.98 196.6,60.96 205.1,60.96 207.52,63.37 DS5.1
USER_LED2: length 22.6
  TOP w0.132: DS4.1 208.91,65.41 204.98,61.47 196.72,61.47 195.96,62.23 195.96,64.26 196.49,64.8 U30.9
USER_LED3: length 21.7
  TOP w0.132: DS3.1 210.44,67.44 204.85,61.85 196.98,61.85 196.34,62.48 196.34,63.83 196.66,64.15 U30.10
USER_LED4: length 18.9
  TOP w0.132: DS2.1 211.07,69.47 208.53,66.93 208.53,66.17 204.6,62.23 200.79,62.23 199.52,63.49 U30.11
VCAP_VBBLDO_DSPEVE: length 1.3
  TOP w0.305: U42.J11 v1(97.38,59.56)
  BOTTOM w0.305: v1(97.38,59.56) 97.34,59.52 C443.1
VCAP_VBBLDO_GPU: length 1.3
  TOP w0.305: U42.U13 v1(90.18,57.96)
  BOTTOM w0.305: C449.1 90.18,58.54 v1(90.18,57.96)
VCAP_VBBLDO_IVA: length 1.3
  TOP w0.305: U42.R19 v1(91.78,52.36)
  BOTTOM w0.305: C486.1 91.8,52.37 v1(91.78,52.36)
VCAP_VBBLDO_MPU: length 1.3
  TOP w0.305: U42.J19 v1(97.38,52.36)
  BOTTOM w0.305: 96.64,52.35 97.38,52.35 v1(97.38,52.36)
VCAP_VDDRAM_CORE1: length 1.4
  TOP w0.305: U42.H11 v1(97.38,58.76)
  BOTTOM w0.305: C451.1 97.52,58.62 v1(97.38,58.76)
VCAP_VDDRAM_CORE2: length 1.3
  TOP w0.305: U42.J17 v1(97.38,53.96)
  BOTTOM w0.305: C478.1 96.79,53.96 v1(97.38,53.96)
VCAP_VDDRAM_CORE3: length 1.5
  TOP w0.305: U42.U15 v1(90.18,55.56)
  BOTTOM w0.305: v1(90.18,55.56) 90.42,55.8 C465.1
VCAP_VDDRAM_CORE4: length 1.5
  TOP w0.305: U42.R17 v1(91.78,53.96)
  BOTTOM w0.305: C473.1 92.08,54.25 v1(91.78,53.96)
VCAP_VDDRAM_CORE5: length 1.3
  TOP w0.305: U42.Y16 v1(87.78,54.76)
  BOTTOM w0.305: C475.1 88.1,54.79 88.07,54.76 v1(87.78,54.76)
VCAP_VDDRAM_DSPEVE1: length 1.4
  TOP w0.305: U42.G10 v1(98.99,60.36)
  BOTTOM w0.305: C437.1 98.89,60.27 v1(98.99,60.36)
VCAP_VDDRAM_DSPEVE2: length 1.3
  TOP w0.305: U42.H10 v1(98.18,59.56)
  BOTTOM w0.305: v1(98.18,59.56) 98.29,59.66 C442.1
VCAP_VDDRAM_GPU: length 1.5
  TOP w0.305: U42.T16 v1(90.98,54.76)
  BOTTOM w0.305: C477.1 v1(90.98,54.76)
VCAP_VDDRAM_IVA: length 1.4
  TOP w0.305: U42.R20 v1(91.78,51.56)
  BOTTOM w0.305: v1(91.78,51.56) 91.93,51.41 C500.1
VCAP_VDDRAM_MPU1: length 1.5
  TOP w0.305: U42.J16 v1(97.38,54.76)
  BOTTOM w0.305: C481.1 v1(97.38,54.76)
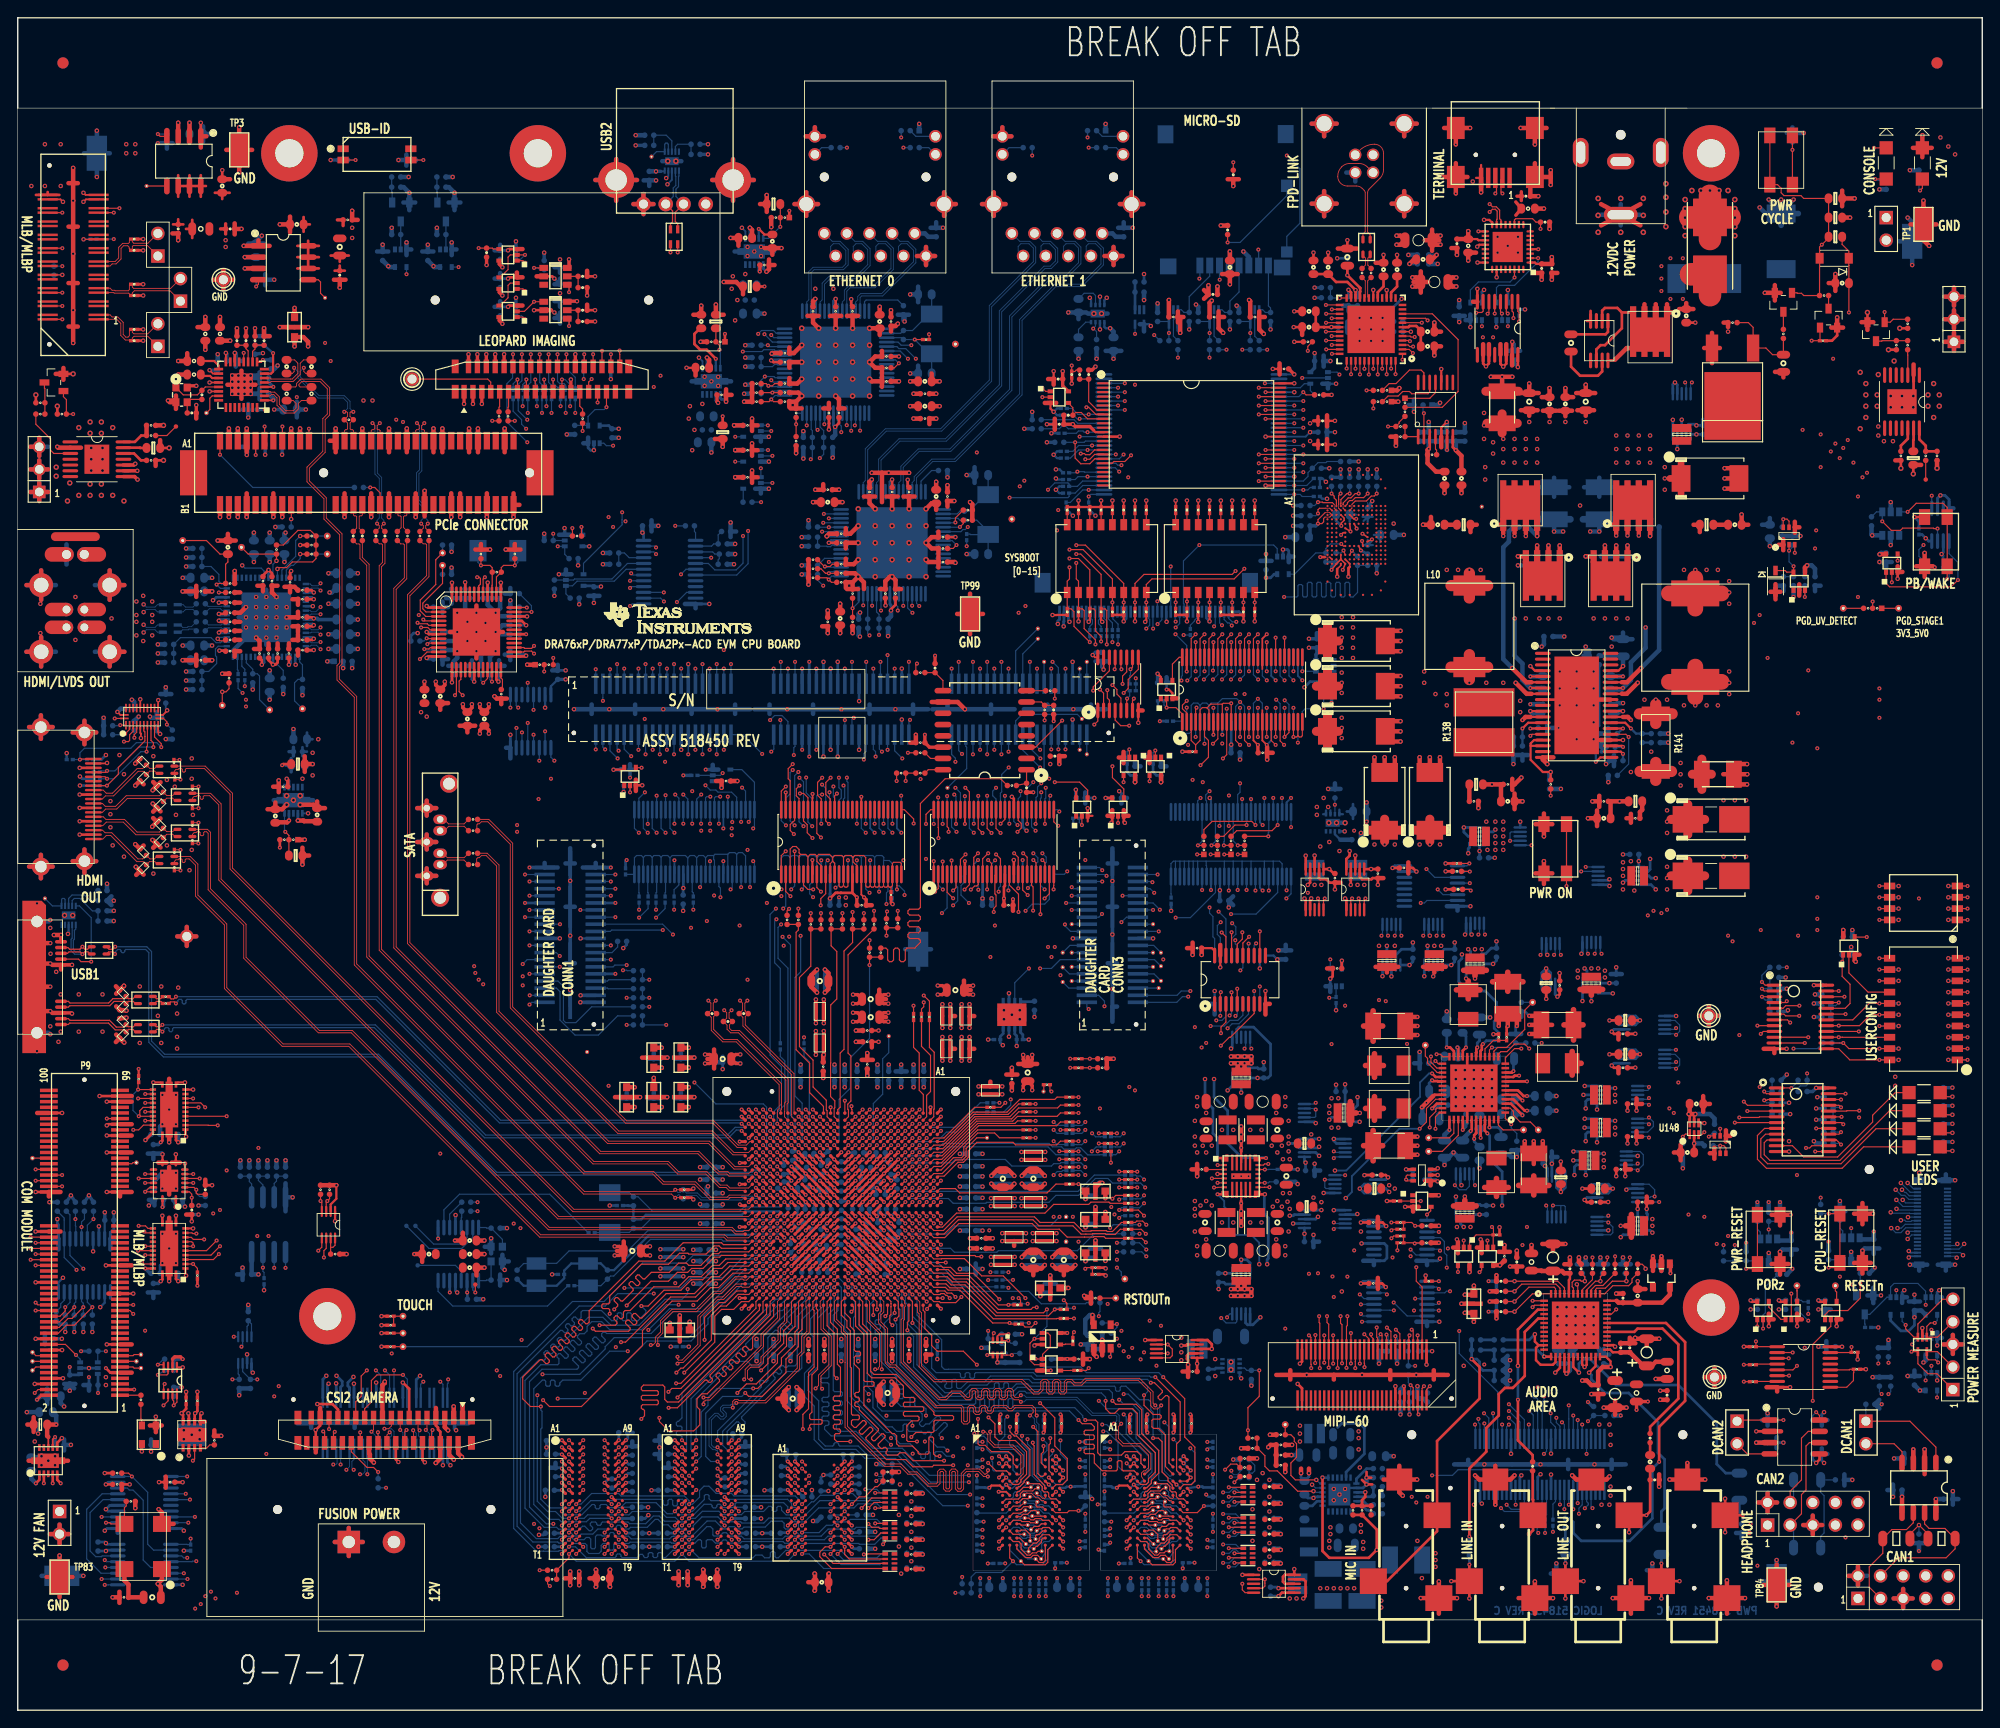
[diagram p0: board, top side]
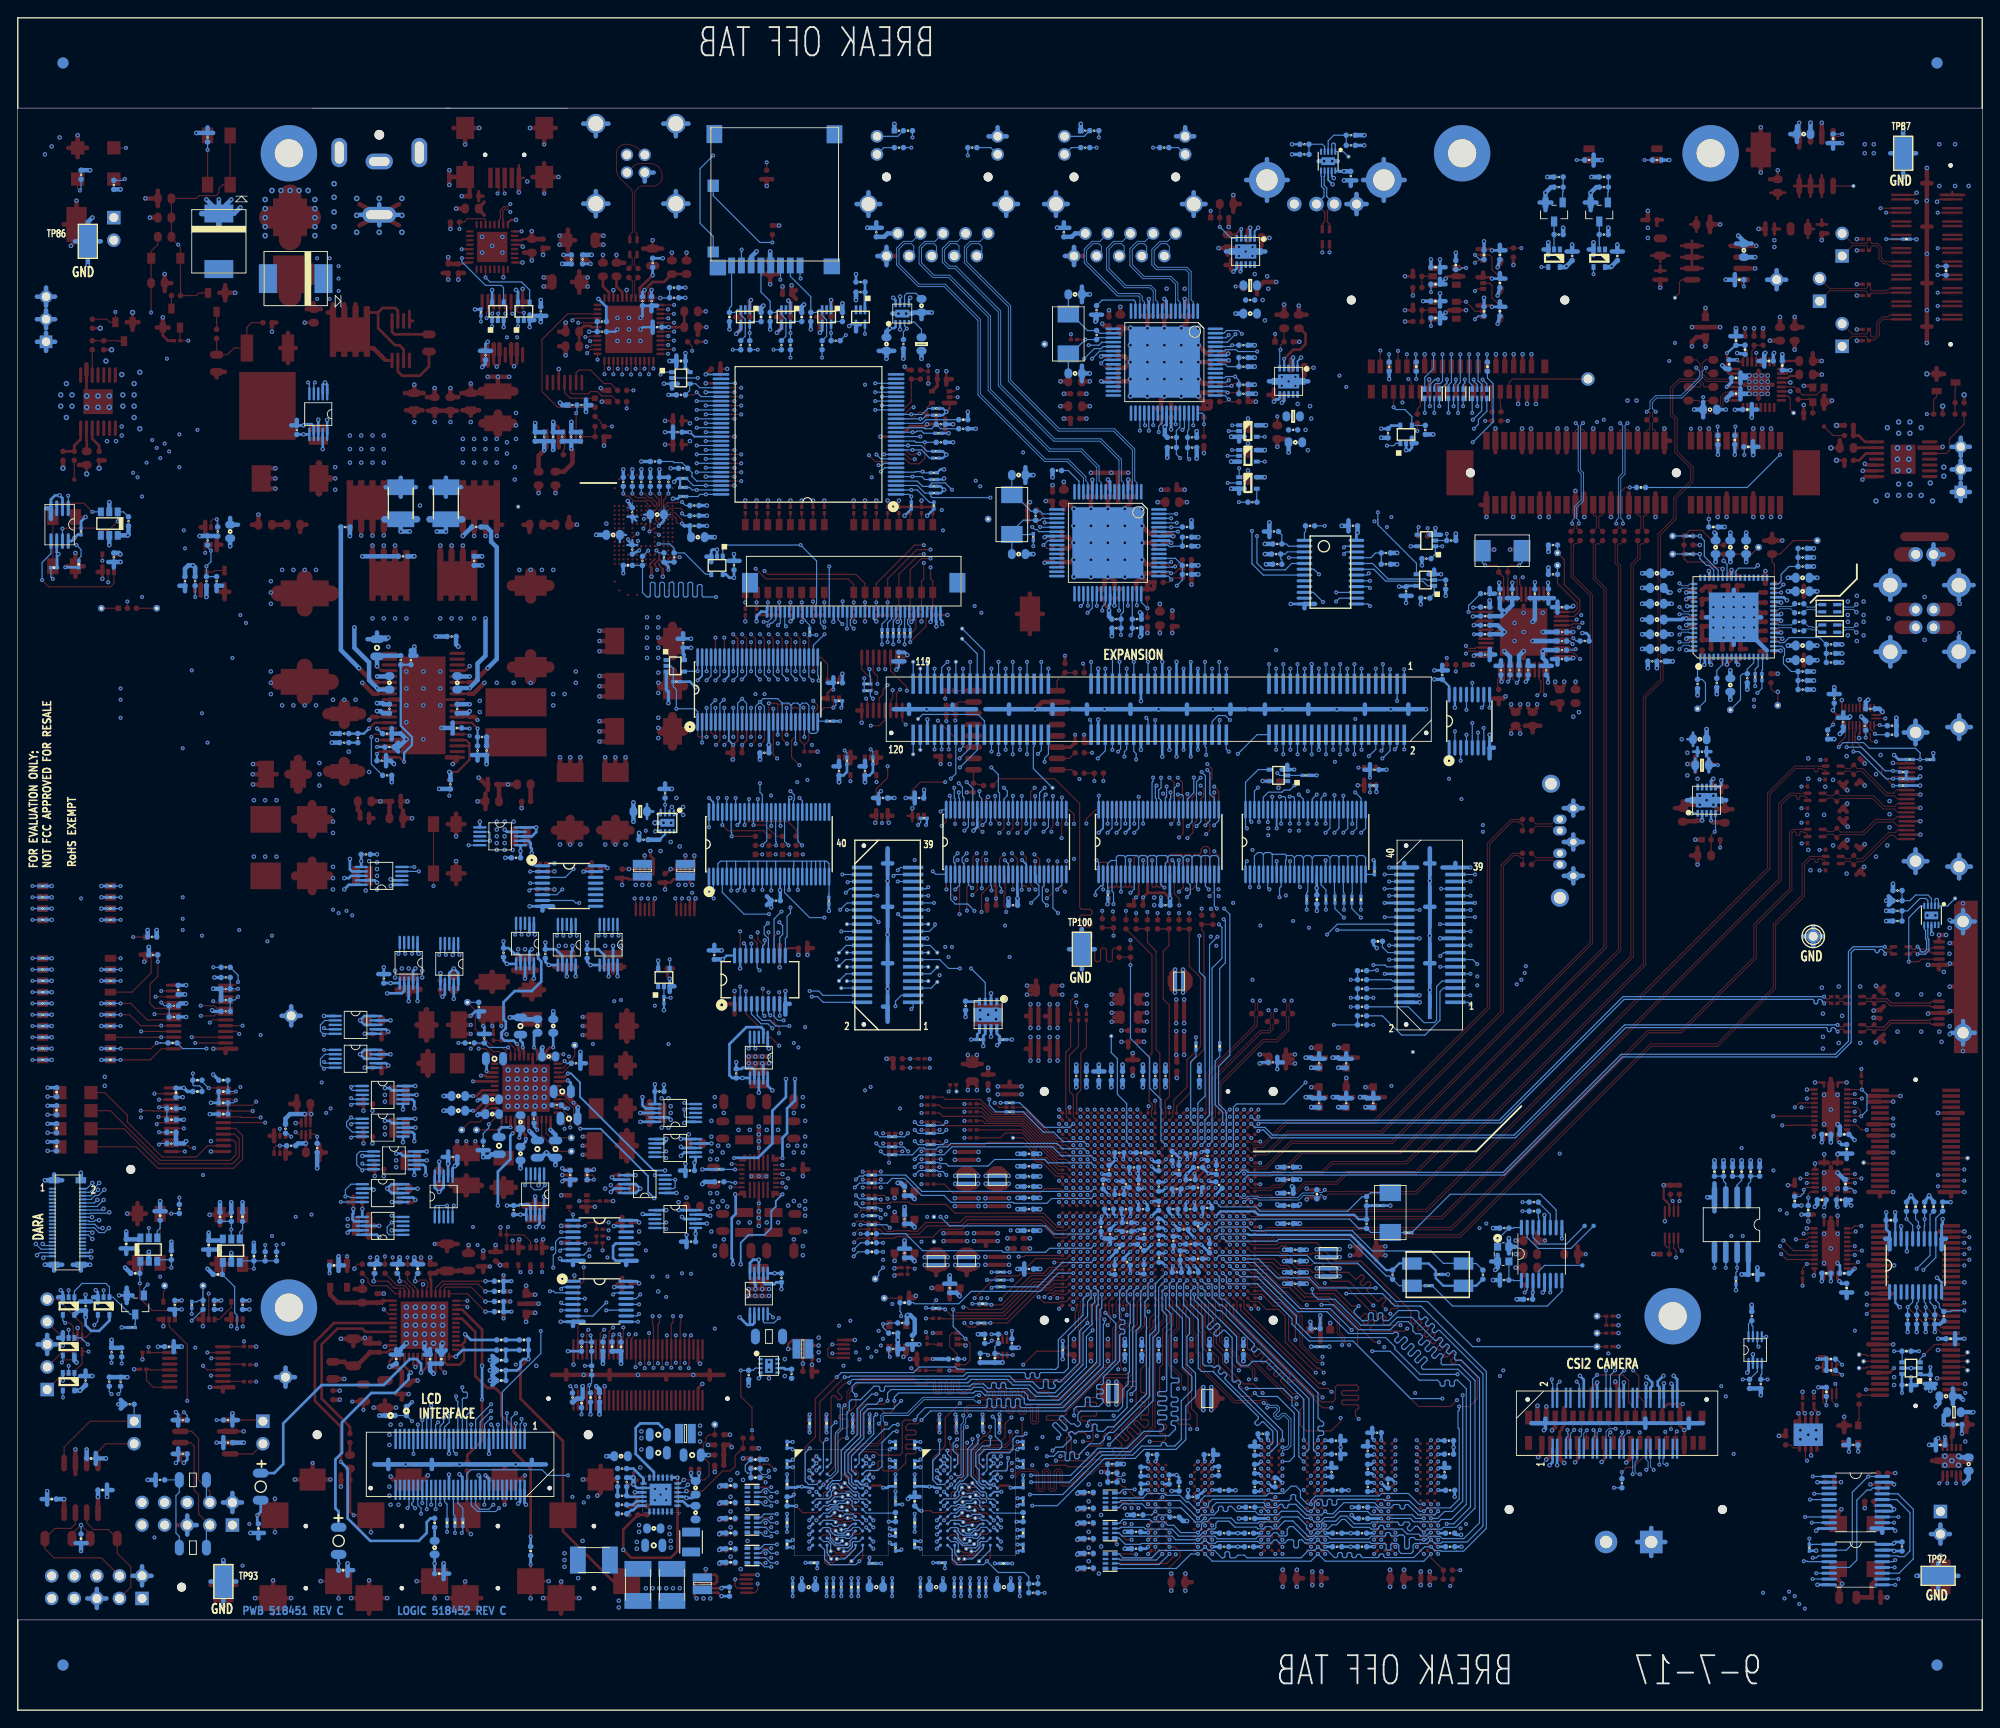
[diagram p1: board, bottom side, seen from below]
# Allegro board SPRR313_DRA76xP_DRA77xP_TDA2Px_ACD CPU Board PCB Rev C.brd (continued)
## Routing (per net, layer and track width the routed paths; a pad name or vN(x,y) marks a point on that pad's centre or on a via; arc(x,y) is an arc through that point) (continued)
VCAP_VDDRAM_MPU2: length 1.3
  TOP w0.305: U42.J21 v1(97.38,50.76)
  BOTTOM w0.305: v1(97.38,50.76) 97.51,50.63 C510.1
VDA_ABEPERMPU_F1V8: length 4.6
  TOP w0.305: U42.N9 v1(94.18,61.16) ; U42.P18 v1(93.38,53.16) ; U42.P16 v1(93.38,54.76)
  TOP w0.508: E7.3 v2(120.04,57.51)
  BOTTOM w0.508: C450.1 120.42,57.89 v2(120.04,57.51) ; C431.1 v2(105.92,61.19)
VDA_CSI_F1V8: length 3.2
  TOP w0.305: v1(88.58,53.96) U42.W17
  TOP w0.508: v2(72.39,72.26) 72.36,72.29 E5.3
  BOTTOM w0.508: C389.1 79.12,56.77 v2(79.25,56.9) ; C388.1 v2(72.39,72.26)
VDA_DBGDSPEVE_F1V8: length 4.1
  TOP w0.305: U42.N13 v1(94.18,57.96) ; U42.J13 v1(97.38,57.16)
  TOP w0.508: E9.3 v2(120.04,54.33)
  BOTTOM w0.508: C483.1 v2(105.92,56.36) ; v2(120.04,54.33) 120.42,54.71 C496.1
VDA_DDRGCOREVID_F1V8: length 4.6
  TOP w0.305: U42.R15 v1(91.78,55.56) ; U42.R14 v1(91.78,57.16) ; U42.N19 v1(94.18,52.36)
  TOP w0.508: E8.3 v2(120.04,50.52)
  BOTTOM w0.508: C469.1 120.42,50.9 v2(120.04,50.52) ; C461.1 v2(105.92,53.95)
VDA_GPUIVA_F1V8: length 4.1
  TOP w0.305: U42.W15 v1(88.58,55.56) ; U42.P20 v1(93.38,51.56)
  TOP w0.508: E10.3 v2(114.96,46.58)
  BOTTOM w0.508: v2(114.96,46.58) 115.34,46.96 C521.1 ; C508.1 v2(105.92,49.63)
VDA_HDMI_F1V8: length 3.1
  TOP w0.305: U42.AA17 v1(86.98,53.96)
  TOP w0.508: E6.3 v2(69.34,67.84)
  BOTTOM w0.508: C386.1 69.32,67.82 v2(69.34,67.84) ; C387.1 v2(79.25,54.74)
VDA_OSC_F1V8: length 3
  TOP w0.305: U42.AA15 v1(86.98,55.56)
  TOP w0.508: E12.3 v2(75.54,43.69)
  BOTTOM w0.305: v2(75.54,43.69) 75.46,43.61 C526.1
  BOTTOM w0.508: C519.1 v2(78.49,51.79)
VDA_PCIE_F1V8: length 4.2
  TOP w0.305: U42.Y14 v1(87.78,57.16) ; U42.AB12 v1(86.18,58.76) ; U42.Y12 v1(88.58,57.96)
  TOP w0.508: E4.3 v2(72.39,67.84)
  BOTTOM w0.508: C371.1 v2(79.25,58.17) ; C370.1 72.36,67.82 v2(72.39,67.84)
VDA_PHY1_1V8: length 4.1
  TOP w0.508: E4.1 v2(71.5,71.12) ; E5.1 v2(72.39,74.52)
  BOTTOM w0.305: U65.9 153.93,85.45 153.92,85.46 v2(153.92,85.98)
  vias: v2(153.03,85.98) v2(154.81,85.98)
VDA_PHY1_APM: length 8.9
  TOP w0.305: v1(160.66,74.55) 161.04,74.55 161.45,74.13 U38.23
  TOP w0.508: 153.92,82.98 R183.2 ; R183.2 155.19,83.62 ; R183.2 152.65,83.62
  BOTTOM w0.305: U65.8 v2(154.43,82.55) ; C377.2 v1(160.66,74.55) ; U65.10 v2(153.43,82.57)
VDA_PHY2_1V8: length 4.9
  TOP w0.508: E3.1 v2(75.44,70.08) ; E2.1 v2(75.44,74.52) ; E6.1 v2(69.34,70.08)
  BOTTOM w0.305: U66.9 158.63,85.32 158.5,85.46 v2(158.5,85.98)
  vias: v2(159.26,85.98) v2(160.02,85.98)
VDA_PHY2_APM: length 8.7
  TOP w0.305: v1(162.81,74.55) 162.45,74.19 U38.21
  TOP w0.508: 157.99,83.62 R182.2 ; R182.2 160.53,83.62 ; R182.2 159.26,82.98
  BOTTOM w0.305: C376.2 162.81,75.82 v1(162.81,74.55) ; U66.10 v2(158.13,82.57) ; U66.8 v2(159.13,82.55)
VDA_PLL_1V8: length 6.3
  TOP w0.508: E12.1 v2(73.3,43.56) ; E8.1 v2(122.28,50.55) ; E7.1 v2(122.28,57.61) ; E9.1 v2(122.28,56.04) ; v2(118.11,47.5) E10.1
  BOTTOM w0.305: U67.9 177.53,62.35 177.79,62.61 v2(178.31,62.61)
  vias: v2(178.31,61.85) v2(178.31,61.09)
VDA_PLL_APM: length 8.4
  TOP w0.305: v1(169.67,67.44) 169.42,67.44 168.13,68.73 U38.4
  TOP w0.508: L19.2 v2(52.45,51.31) ; C165.1 v2(52.45,52.83)
  BOTTOM w0.305: U67.8 v2(174.88,61.85) ; U67.10 v2(174.89,62.85) ; v1(169.67,67.44) C410.2
VDA_SATA_F1V8: length 3.1
  TOP w0.305: U42.AA13 v1(86.98,57.96)
  TOP w0.508: E2.3 v2(75.44,72.29)
  BOTTOM w0.508: C364.1 75.41,72.26 v2(75.44,72.29) ; C363.1 v2(79.25,59.69)
VDA_USB_3V3: length 7.6
  TOP w0.305: U42.AD11 v1(84.58,59.56) ; U42.AB10 v1(86.98,59.56)
  TOP w0.381: v2(81.23,73.76) 80.72,73.76 C147.1 80.72,72.75 v2(81.23,72.75)
  BOTTOM w0.305: C378.1 81.1,72.87 v2(81.23,72.75) ; v1(86.98,59.56) 86.86,59.44 C445.1 ; U68.9 178.8,66.03 179.06,66.29 v2(179.58,66.29)
  vias: v2(179.58,65.53) v2(179.58,64.77)
VDA_USB_APM: length 6.4
  TOP w0.305: U38.6 168.65,69.73 169.29,69.09 v1(169.67,69.09)
  BOTTOM w0.305: U68.10 v2(176.16,66.53) ; U68.8 v2(176.15,65.53) ; v1(169.67,69.09) C406.2
VDA_USB_F1V8: length 5.4
  TOP w0.305: U42.AA11 v1(87.78,59.56) U42.Y10 U42.AA9 v1(86.98,61.16)
  TOP w0.508: E3.3 v2(75.44,67.84)
  BOTTOM w0.508: C367.1 75.41,67.82 v2(75.44,67.84) ; C368.1 v2(79.25,61.09)
VDAC_3V3: length 14.9
  TOP w0.305: v2(184.66,35.94) C192.1
  TOP w0.381: v1(185.8,49.15) 185.8,50.15 U45.1 ; v1(181.99,33.78) L24.2 v1(183.26,34.72)
  TOP w0.508: R236.1 175.51,50.42 v2(175.51,50.93) ; v2(162.69,46.74) 163.7,46.74 E11.3 v2(163.7,47.75) ; v2(170.18,52.32) L22.1 ; v2(184.15,37.26) L23.2 ; v2(168.53,51.69) C175.1
  BOTTOM w0.381: R612.1 R610.1 v1(165.35,48.26) ; v1(165.35,44.83) R617.1 R614.1 ; 185.8,50.04 v1(185.8,49.15)
VDISP1_12V0: length 3
  L3-SIGNAL w0.508: J11.5 8.48,130.01 ; J11.5 7.48,129.01 ; J11.5 7.48,131.01
  vias: v3(4.32,139.83) v3(4.32,138.81) v3(5.84,138.05)
VDISP2_12V0: length 4.2
  TOP w0.508: L4.2 159,163.19 v2(159.51,163.7) ; v2(161.72,160.15) 161.29,160.15 C21.1 161.29,161.16 v2(161.72,161.16)
  BOTTOM w0.305: C260.1 v2(159.51,163.7)
  vias: v3(209.17,150.24) v3(210.95,151.76)
VFTDI_3V3: length 6
  TOP w0.254: C15.1 170.73,162.69 170.57,162.84 U3.1 ; U3.16 165.76,167.31 165.43,167.64 v2(164.85,167.64)
  TOP w0.508: C15.1 C16.1 v2(172.47,163.45) ; R7.1 v2(172.21,166.62)
  BOTTOM w0.508: R713.1 v2(209.3,171.07)
VHDMI_5V0: length 16.9
  TOP w0.203: P7.18 9.98,106.5 v2(10.03,106.55) ; U19.12 16.33,111.96 16.64,112.27 16.64,112.32 v2(16.79,112.47)
  L14-SIGNAL w0.508: v2(10.03,106.55) 10.67,107.19 10.67,110.94 10.3,111.31 10.3,112.53 10.92,113.16 11.81,113.16 12.32,112.65 15.99,112.65 16.17,112.47 v2(16.79,112.47)
  BOTTOM w0.203: v2(16.79,112.47) 16.64,112.62 C337.1
VIDEO_SCL: length 239.1
  TOP w0.132: R734.2 v1(120.52,72.26) R230.2 ; v1(64.51,149.73) 64.18,149.4 J8.29
  L3-SIGNAL w0.109: v1(25.15,40.89) 25.15,45.43 33.69,53.98 51.31,53.98 53.21,55.88 53.21,77.09 56.01,79.88 56.01,84.58 56.9,85.47 64.9,85.47 66.29,86.87 73.48,86.87 73.5,86.85 74.53,86.85 v1(75.69,88.01) 79.63,88.01 82.04,85.6 86.36,85.6 86.87,86.11 88.39,86.11 89.4,87.11 95.9,87.11 96.61,86.39 123.61,86.39 124.82,87.6 v1(128.27,87.6)
  L5-SIGNAL w0.089: v1(128.27,87.6) 128.27,86.74 126.49,84.96 126.49,81.66 121.41,76.58 121.41,73.15 v1(120.52,72.26)
  L10-SIGNAL w0.089: v1(64.51,149.73) 65.4,148.84 v1(71.5,148.84)
  L12-SIGNAL w0.089: v1(71.5,148.84) 71.5,140.72 75.56,136.65 75.56,119.25 75.79,119.03 75.79,117.5 75.77,117.48 75.77,106.5 75.44,106.17 75.44,104.52 76.33,103.63 76.33,92.76 76.32,92.74 76.32,92.42 76.33,92.41 76.33,88.65 v1(75.69,88.01)
  BOTTOM w0.132: U135.6 25.28,41.03 v1(25.15,40.89) ; EXP_P3.22 v1(128.27,87.6)
VIDEO_SDA: length 228.2
  TOP w0.132: R733.2 v1(120.52,73.28) R226.2 ; J8.30 v1(64.68,152.53)
  L3-SIGNAL w0.109: v1(24.28,42.01) 24.28,45.36 28.07,49.15 28.07,51.82 30.73,54.48 51.18,54.48 52.7,56.01 52.7,77.85 55.24,80.39 55.24,85.47 56.64,86.87 59.05,86.87 60.07,87.88 71.37,87.88 72.26,88.77 v1(77.47,88.77) 82.8,88.77 83.69,87.88 86.11,87.88 86.87,88.65 104.98,88.65 105.18,88.84 117.28,88.84 v1(117.73,88.39)
  L10-SIGNAL w0.089: v1(72.26,150.11) 67.1,150.11 v1(64.68,152.53)
  L12-SIGNAL w0.089: v1(77.47,88.77) 77.47,95.31 77.44,95.34 77.44,95.66 77.47,95.7 77.47,98.77 77.46,98.77 77.46,99.09 77.47,99.1 77.47,99.53 77.44,99.56 77.44,99.88 77.47,99.92 77.47,103.12 76.33,104.27 76.33,106.3 76.57,106.54 76.57,136.79 72.26,141.1 v1(72.26,150.11)
  L14-SIGNAL w0.109: v1(120.52,73.28) 120.52,76.33 119.51,77.34 119.51,85.09 117.73,86.87 v1(117.73,88.39)
  BOTTOM w0.132: EXP_P3.21 118.36,87.6 117.73,88.24 v1(117.73,88.39) ; U135.5 v1(24.28,42.01)
VIO_1V8: length 90.5
  TOP w0.178: v1(150.47,134.01) 150.19,134.01 U15.C6 ; v1(147.7,128.27) U15.P3 U15.N4 ; U15.N4 U15.M4 ; U15.N4 U15.P5 v1(148.97,128.27)
  TOP w0.254: v1(16.27,56.59) U41.16 ; v2(35.81,59.05) 35.81,57.53 35.17,56.89 U146.2 ; U55.2 17.39,39.5 ; v1(14.33,49.69) U43.23
  TOP w0.305: Q16.2 v2(159.64,60.2) ; P9.8 v2(5.08,37.34) ; C93.1 30.61,128.02 v2(30.73,128.14) ; v1(16.07,63.88) 16.26,64.07 U39.24 ; U39.23 15.19,64.97 v2(14.35,64.14) ; C688.1 20.19,33.66 v2(19.94,33.4) 19.88,33.35 U140.6 ; Y2.4 v2(13.94,29.11) ; v2(16.07,48.26) 16.26,48.45 U43.24 ; RJ6.3 v1(29.46,97.03) ; v2(30.48,117.6) C115.1
  TOP w0.381: v1(18.54,39.5) 18.29,39.75 17.65,39.75 17.39,39.5
  TOP w0.508: v2(49.02,28.19) 48.51,28.71 J15.4 ; RJ5.1 v2(155.19,147.19) ; v2(48.37,31.48) 48,31.84 J15.5 ; R132.2 v2(22.99,116.59) ; v2(35.81,59.05) R740.1 R739.1 ; L8.2 v2(160.4,136.91) ; RJ2.3 v2(76.77,153.92) ; RJ1.3 v2(84.71,166.83) ; v2(155.32,148.72) 155.07,148.46 RJ3.1
  BOTTOM w0.254: U128.2 9.77,45.84 v2(9.27,45.34) ; U128.10 4.57,48.13 v2(5.08,48.64) ; 149.73,133.67 C303.1 150.43,134.49 ; 151.31,133.78 C302.1 ; C302.1 151.76,133.67 ; C302.1 152.34,134.24 ; C302.1 151.19,134.24
  BOTTOM w0.305: C555.1 13.97,29.13 v2(13.94,29.11) ; R416.2 R415.1 147.7,128.65 v1(147.7,128.27) ; P15.40 34.3,37.22 34.7,37.62 v2(34.69,37.62) ; v1(5.84,38.61) C546.1 6.9,37.72 U132.1 ; v2(34.94,36.73) 34.95,36.73 34.8,36.58 P15.38 ; v2(163.72,23.11) 163.72,23.13 163.88,23.29 J19.2 ; v2(30.48,117.6) 30.69,117.81 U115.3 ; J19.4 164.38,23.45 v2(164.59,23.24) ; U115.46 30.69,128.1 v2(30.73,128.14) ; U71.9 183.51,53.98 v2(183.77,53.72) ; EXP_P2.55 v2(90.58,117.93) ; EXP_P2.56 v2(90.58,107.27)
  BOTTOM w0.381: v2(16.07,48.26) 15.81,48.01 C520.1 ; v1(18.54,39.5) R639.1 R646.1 ; v2(151.76,139.57) R385.1 ; v2(150.75,139.57) R386.1 ; v2(149.73,139.57) R387.1 ; R398.1 v2(143.38,134.37) ; R389.1 R388.1 v2(148.72,139.57) ; v1(14.33,49.69) 14.87,49.15 C515.1 ; R395.1 v2(143.38,135.51) ; R621.1 v2(7.37,42.55) ; v2(152.78,139.57) R384.1 ; C529.1 v2(4.95,41.78) ; R622.1 v2(6.35,42.55) ; C454.1 16.38,56.71 v1(16.27,56.59) ; R420.1 v2(152.78,127.89) ; R620.1 v2(8.38,42.55) ; C419.1 15.81,63.63 v1(16.07,63.88) ; R619.1 4.7,43.43 R623.1 v2(5.33,42.55) ; v2(14.35,64.14) C416.1
  BOTTOM w0.508: L27.2 v2(38.23,124.46) ; RJ15.3 v2(37.59,117.22) ; R755.2 v2(187.2,60.96) ; C308.1 v2(29.97,129.16) ; v2(143.89,59.18) 143.64,59.44 R496.1 ; R451.2 v2(26.42,114.81) ; v2(159.89,147.07) 159.64,146.81 RJ14.1
  vias: v2(154.69,133.48) v2(183.77,55.24) v2(183.77,54.48)
VIO_3V3: length 418.4
  TOP w0.178: U15.E6 v1(149.83,132.59) U15.F5 ; U15.J10 v1(152.25,131.7) ; U15.K9 v1(151.13,131.52)
  TOP w0.203: v2(135.25,136.07) R82.1 ; P5.39 7.62,170.45 v2(7.38,170.69) ; U19.23 11.53,111.96 v2(11.2,112.29) ; v2(121.79,136.07) R73.1 ; v2(119.25,136.07) R71.1 ; v2(123.06,136.07) R74.1 ; P5.37 7.66,169.95 v2(7.38,169.67) ; v2(137.79,136.07) R84.1 ; U53.5 v2(110.13,39.12) ; v2(139.06,136.07) R85.1 ; v2(131.44,136.07) R79.1 ; RU5.17 138.92,109.09 v1(139.42,108.58) ; v2(136.53,136.07) R83.1 ; v2(124.33,136.07) R75.1 ; v2(133.99,136.07) R81.1 ; P5.38 4.8,169.95 v2(5.08,169.67) ; RU4.16 121.1,118.43 v2(120.85,118.69) ; v2(130.18,136.07) R78.1 ; v2(125.6,136.07) R76.1 ; v2(132.72,136.07) R80.1 ; v2(126.87,136.07) R77.1
  TOP w0.254: R70.1 R71.1 R72.1 R73.1 R74.1 ; U12.12 121.16,143.76 120.94,143.99 ; v2(66.98,105.79) 67.96,105.79 U23.5 ; v2(18.92,48.9) 18.85,48.97 U43.2 ; RU9.20 134.56,85.41 134.24,85.72 C139.1 ; v2(118.95,103.54) 118.98,103.5 U27.5 ; R30.1 v2(143.51,153.92) ; U17.5 128.51,116.22 v2(128.14,116.59) ; v2(17.77,56.59) U41.1
  TOP w0.305: U39.1 17.78,64.14 v2(18.03,63.88) ; C365.1 148.84,84.3 v2(148.86,84.31) ; 93.83,91.94 v1(94.33,91.44) ; 93.83,91.94 RU7.17 ; 93.83,91.94 92.54,91.94 92.54,91.94 92.13,91.94 92.12,91.94 91.94,91.94 v2(91.31,91.31) ; R168.1 v2(160.53,92.33) ; C166.1 v2(151,54.86) ; C87.1 v2(105.41,131.95) ; v2(84.7,151.84) 84.76,151.84 84.96,151.64 85.72,151.64 ; v2(202.18,27.81) 202.56,28.19 U57.5 ; R257.1 v2(40.89,44.32) ; RU10.16 v2(205.09,40.88) ; R161.1 v2(160.53,95.25) ; RJ2.1 v1(79.5,154.81) ; C177.1 v2(151,48.01) ; U87.9 149.87,93.37 149.86,93.36 v2(149.86,92.84) ; R250.1 v2(153.92,57.28) ; v2(122.3,48.9) 122.17,49.02 R269.1 ; R737.1 v2(166.59,54.32) ; L5.2 v2(145.67,163.96) ; R45.1 v3(2.03,147.96) ; R188.1 v2(118.49,149.22) ; v2(18.03,48.26) 17.78,48.51 U43.1 ; v2(122.3,102.62) 123.05,102.62 RU6.5 ; C97.1 98.68,124.35 98.17,123.84 v2(98.17,123.7) ; L6.1 v2(143.51,157.35) ; R248.1 v2(158.28,48.9) ; U140.8 18.58,33.23 v2(18.41,33.4) 18.92,33.91 C687.1 ; R60.1 v3(210.31,153.03) ; RU2.16 v2(168.65,151.08) ; RJ1.1 v1(86.74,168.66) ; R572.2 v2(9.78,26.67) ; R242.2 v2(40.89,42.42) ; R163.1 v2(160.53,94.36) ; R263.1 v2(194.06,40.89) ; C88.1 v2(91.19,131.32) ; C64.1 92.33,144.79 v2(91.89,144.35) ; R47.1 v3(211.58,155.45) ; 98.17,152.27 v2(99.06,152.27) ; R51.1 v3(4.45,146.69) ; C135.1 v2(154.56,94.74) ; C430.2 v2(9.91,25.4) ; R264.1 v2(206.84,39.46)
  TOP w0.356: v2(201.93,81.55) U21.24 ; v2(202.18,70) U30.24
  TOP w0.381: v2(143.51,150.26) 142.89,150.88 C46.1 ; 146.18,141.87 C69.1 ; C69.1 146.18,142.86 ; C69.1 145.68,142.37 ; U20.14 102.49,108.33 C120.1 v1(101.98,109.73) ; RU1.5 54.13,159.49 v2(54.48,159.13) ; v2(50.67,152.53) J8.2 ; R52.2 C67.1 v2(118.62,144.65) 118.87,144.4 120.53,144.4 120.94,143.99 ; v1(94.33,91.44) 94.33,90.58 C137.1 ; v2(54.48,155.96) 54.13,156.31 U7.5 ; v2(54.48,162.31) 54.13,162.66 U4.5 ; v2(50.17,146.94) J8.1 ; R42.2 v2(147.7,147.96) ; R152.1 v1(114.17,103.25) ; R130.1 v1(103.12,118.62) ; R136.2 v1(116.46,111.25) ; v2(51.17,146.94) J8.3 ; 120.4,150.75 120.78,150.75 v2(121.16,151.13) ; 146.18,144.54 C66.1 ; C66.1 145.68,145.03 ; C66.1 146.18,145.53 ; R19.1 v2(64.9,156.21) ; v1(139.42,108.58) 139.42,107.72 C122.1 ; U51.5 v1(117.98,42.43) ; RU3.5 117.47,148.96 C49.1 v2(117.47,150.62) ; R12.2 v2(52.7,162.56) ; C188.1 118.74,39.5 118.73,39.51 v1(117.98,39.51) U54.5
  TOP w0.406: v2(52.96,109.86) 52.96,110.24 L32.2 51.94,110.24 v2(51.94,109.86)
  TOP w0.508: R103.2 R105.2 R108.2 v2(88.9,126.62) ; C71.1 80.68,138.68 v2(80.66,138.7) ; R734.1 R733.1 v2(123.19,73.28) ; L9.2 v2(162.31,136.91) ; RU11.5 205.23,86.98 v2(205.23,87.76) ; R58.1 v3(16.38,144.53) ; v2(128.52,104.39) 128.54,104.41 U144.5 ; R86.1 R69.1 107.31,135.64 v2(107.06,135.89) ; v2(125.6,104.39) 125.62,104.41 U145.5 ; U44.5 v2(159.75,57.93) ; v2(133.1,84.96) C139.1 ; RU25.5 v2(166.62,50.06) 167.11,50.55 C710.1 ; C61.1 v2(100.33,146.69) ; C68.1 80.55,144.53 v2(80.53,144.54) ; R129.1 v2(93.85,121.16) ; R569.2 v2(13.21,22.73) ; L7.1 v2(22.73,156.72) ; R232.1 v1(159.77,52.58) ; R738.1 v2(36.96,51.31) ; v2(49.01,34.16) J15.3 ; R64.1 v2(87.5,141.4) ; v2(80.66,141.75) 80.68,141.73 C70.1 ; R37.2 R40.2 R43.2 v2(81.66,147.19) ; v2(31.11,157.73) E1.1 ; L30.2 16.08,13.89 v2(15.75,14.22) 16.21,14.68 U123.1 ; v2(163.7,43.69) E11.1 163.7,44.7 v2(162.69,44.7) ; U37.1 120.97,40.07 v2(121.28,39.75) ; C102.1 v2(92.46,124.46) ; C65.1 v2(100.71,145.29) ; v2(211.84,24) U58.5 ; RJ6.1 v2(32.26,97.92) ; v2(50,34.25) 50.01,34.25 J15.1 ; J15.2 49.51,28.9 49.94,28.47 v2(49.93,28.47) ; R97.1 v3(215.77,139.7) ; C104.1 v2(91.06,123.7) ; RU24.5 v2(163.21,49.29) ; C354.1 v2(80.9,104.52) ; R227.1 v2(159.77,54.48)
  L14-SIGNAL w0.508: v2(143.89,60.83) 144.78,59.94 144.78,55.63 147.07,53.34 148.46,53.34 149.99,54.86 v2(151,54.86) ; v2(108.33,40.77) 109.22,40.77 110.11,39.88 110.11,39.76 110.13,39.74 v2(110.13,39.12) 110.87,38.38 115.45,38.38 116.58,39.51 v1(117.98,39.51)
  BOTTOM w0.203: U104.43 144.79,143.26 v2(145.29,143.76) ; RU18.17 v2(135.15,92.24) ; v2(143.51,150.26) U104.29
  BOTTOM w0.254: 153.16,131.38 C307.1 152.46,132.21 ; v2(122.81,155.45) 122.31,155.45 122.16,155.6 U96.1 ; v2(121.67,155.32) 121.66,155.33 U96.2 ; v1(118.75,99.57) 118.66,99.66 R501.1 ; C310.1 151.76,131.64 ; C310.1 151.19,131.06 ; C310.1 152.22,131.52 ; C310.1 152.34,131.06 ; v2(141.6,84.45) 141.17,84.89 RU20.20 ; R460.1 128.18,112.86 v1(128.27,112.78) ; R538.1 v2(148.21,78.74) ; R702.1 v2(27.69,47.24) ; C331.1 59.93,115.18 RU14.16 ; U128.19 9.77,55.11 C471.1
  BOTTOM w0.305: U108.57 91.44,131.57 v2(91.19,131.32) ; v2(9.91,25.4) 10.15,25.64 U124.19 ; U105.5 66.45,144.5 C291.2 v2(67.56,144.15) ; R597.1 v2(18.67,17.95) ; v2(37.74,37.49) 37.74,37.49 37.11,36.86 37.11,36.47 37.3,36.29 P15.32 ; U109.5 141.25,127.79 140.84,127.38 v2(140.34,127.38) C313.2 ; P15.34 36.3,35.15 36.3,36.35 36.47,36.53 36.47,36.98 35.84,37.62 v2(35.83,37.62) ; v2(151,54.86) 151.25,55.11 RU22.16 ; U108.23 105.3,132.07 v2(105.41,131.95) ; R452.1 145.29,115.7 v2(144.65,115.06) ; v2(98.17,123.7) 98.17,124.29 98.13,124.33 98.13,124.34 98.05,124.42 U108.41 ; EXP_P2.58 v2(91.38,108.03) ; R325.1 v2(145.8,160.02) ; RU13.17 v2(136.42,108.61) ; R729.1 127.64,105.54 128.02,105.16 C706.1 ; R318.1 v2(148.34,163.32) ; C470.2 9.78,18.92 v2(9.91,18.8) 10.04,18.66 RU21.16 ; R745.1 v2(211.46,92.71) ; R474.1 v2(211.46,78.23) ; U132.6 9.02,37.81 C549.1 v1(9.02,35.69) ; P15.36 35.8,36.77 v2(35.79,36.77) ; R746.1 v2(211.46,91.44) ; U118.5 80.88,104.51 v2(80.9,104.52) ; U121.5 v2(148.86,84.31) ; v2(99.06,152.27) 98.95,152.39 U101.23 ; R139.1 v2(211.46,79.5) ; R482.1 v2(211.46,76.96) ; v2(65.56,126.4) 65.53,126.36 C316.2 64.66,126.48 U111.5 ; v2(70.23,132.46) 70.36,132.33 U110.24 ; R336.1 154.69,157.86 v2(155.57,158.75) ; RU17.17 v2(74.82,92.48) 74.8,92.46 C359.1 ; EXP_P2.57 v2(91.38,117.17) ; C707.1 125.09,105.16 124.71,105.54 R730.1 ; C532.1 205.08,40.89 v2(205.09,40.88) ; R651.1 v2(159,40.39) ; v2(117.59,121.92) 117.59,122.44 117.62,122.47 J17.2 ; U101.41 91.7,144.55 v2(91.89,144.35) ; RU16.17 91.33,91.85 91.31,91.83 v2(91.31,91.31) ; v2(116.93,122.19) 116.93,122.52 117.12,122.71 J17.1 ; R494.2 v2(6.99,104.01) ; v2(68.07,85.72) 68.45,86.11 R528.1 ; J17.3 118.12,122.54 v2(118.24,122.43) ; R712.2 v2(143.89,60.83) ; U101.57 84.76,151.89 v2(84.7,151.84) ; v2(151,48.01) 151.25,48.25 RU23.16 ; R137.1 v2(211.46,82.04) ; v2(202.18,27.81) 201.8,28.19 C609.1 ; v2(37.79,36.73) 37.8,36.73 P15.30 ; R134.1 v2(211.46,83.31) ; R724.2 44.2,120.85 44.5,121.16 v2(44.96,121.16) ; EXP_P2.60 v2(92.18,107.27) ; U122.8 110.78,76.11 110.45,75.78 C380.1 110.45,75.1 v2(110.74,74.8) ; 8,40.39 v1(7.11,40.39) ; RU19.16 154.8,94.99 v2(154.56,94.74) ; U112.5 v2(64.25,130.92) ; EXP_P2.59 v2(92.18,117.93) ; R464.1 v2(217.04,80.77) ; R493.1 v2(68.11,103.29) ; R747.1 v2(211.46,90.17) ; R153.1 v2(211.46,73.15) ; R147.1 v2(211.46,74.42) ; R748.1 v2(211.46,88.9)
  BOTTOM w0.381: R585.1 v2(20.32,56.77) ; R317.2 v2(56.01,165.23) ; 56.01,157.86 v2(56.01,158.88) ; R499.1 v2(198.88,71.5) ; R427.1 v2(63.12,124.4) ; R369.1 v2(29.72,141.22) ; v2(145.29,143.76) 145.29,143.76 C290.1 ; v2(168.65,151.08) 168.28,151.45 C279.1 ; C259.1 v2(54.48,162.31) ; v2(201.93,81.55) 201.95,81.53 C341.2 ; C329.1 121.16,119 v2(120.85,118.69) ; R354.2 v2(66.67,149.73) ; R643.1 116.83,39.5 116.84,39.51 v1(117.98,39.51) ; C263.1 v2(54.48,159.13) ; R308.1 v2(35.18,174.37) ; R592.1 v2(20.32,55.75) ; C353.1 v2(66.98,105.79) ; R362.1 v2(114.05,146.05) ; v2(118.95,103.54) 118.95,102.71 C355.1 ; R311.2 v2(77.6,175.01) ; R425.1 v2(60.33,125.35) ; v2(217.5,63.93) R517.1 ; R428.1 v2(62.99,128.78) ; R489.1 v1(74.82,105.16) ; v2(199.01,78.74) 198.88,78.61 197.99,78.61 ; R502.1 201.78,69.6 v2(202.18,70) 202.2,69.98 C357.2 ; C453.1 v2(17.77,56.59) ; C331.1 v2(61.59,115.95) ; R509.1 v2(202.18,66.42) ; C274.1 v2(54.48,155.96) ; v2(199.26,67.06) R508.1 ; R319.2 v2(59.18,163.96) ; R371.2 v2(115.7,142.62) ; v1(176.53,34.67) 177.04,34.16 R654.1 ; v2(135.15,92.24) 135.13,92.21 C360.1 ; R589.1 v2(5.97,57.91) R590.1 ; v2(217.5,70.03) R504.1 ; U116.5 145.95,118.75 146.05,118.85 C323.1 v2(145.16,119.51) ; R587.1 v2(8,57.91) R588.1 ; C415.1 v2(18.03,63.88) ; 197.99,82.42 v2(198.75,82.42) ; R364.1 v2(113.16,144.15) ; R478.1 v2(201.93,77.98) ; C356.1 v2(122.3,102.62) ; R370.1 v2(27.81,141.22) ; R591.1 v2(3.56,57.15) ; C335.1 v2(128.14,116.59) ; R42.2 v2(147.7,147.96) ; RU12.5 145.8,150.99 C280.1 v2(145.8,152.65) ; C514.1 v2(18.03,48.26) ; R377.1 v2(150.75,140.46) ; R306.2 v2(69.47,176.02) ; C471.1 v2(9.78,56.01) ; v2(217.5,68) R507.1 ; R650.1 v2(18.41,36.32) ; v2(217.5,65.96) R510.1
  BOTTOM w0.508: C278.1 123.19,155.07 v2(122.81,155.45) ; R647.1 v2(206.12,85.85) ; R403.1 v2(88.9,133.86) ; R367.1 91.89,143.45 v2(91.89,144.35) ; R356.2 v2(81.79,149.1) ; R618.1 v2(112.9,42.29) ; 12.06,112.65 11.56,112.65 v2(11.2,112.29) ; v2(110.13,39.12) R641.1 R626.1 ; R421.2 v2(88.14,128.78) ; C543.2 v2(205.23,87.76) ; v2(201.93,64.01) 202.18,63.75 R516.2 R512.2 ; 109.09,40.77 v2(108.33,40.77) ; U94.5 46.84,162.33 v2(46.74,162.43) C265.1 ; R644.1 v2(25.91,45.59) ; C707.1 v2(125.6,104.39) ; v2(27.05,49.02) C646.2 U139.8 ; C706.1 v2(128.52,104.39) ; v2(157.35,36.45) 157.35,35.18 R659.1 158.01,35.05 158.39,34.67 R658.1 ; U103.5 v2(80.53,144.54) ; R419.1 v2(80.52,128.91) ; C305.2 v2(70.23,132.46) ; v2(98.17,123.7) 98.17,123.06 R430.1 ; R321.1 v2(42.04,166.75) ; R365.2 v2(61.72,143.51) ; C593.1 v2(211.84,24) ; v2(9.65,111.63) R467.2 R472.2 ; R408.1 v2(80.64,131.19) ; R470.1 v2(16.64,109.24) ; 10.03,92.2 v2(10.03,92.96) ; R466.1 v2(13.59,111.76) ; U107.5 v2(80.66,138.7) ; R422.1 v2(65.79,128.91) ; R727.2 v2(48.77,130.3) ; C361.1 v2(91.31,91.31) ; R348.1 v2(81.79,153.54) ; v2(141.6,84.45) C366.1 ; v2(153.03,38.99) R637.1 R638.1 ; C351.1 136.4,108.58 v2(136.42,108.61) ; U106.5 v2(80.66,141.75) ; v2(88.32,143.88) R368.2 ; R682.1 v2(26.04,61.85) ; R426.1 v2(59.18,132.33) ; R409.2 v2(88.14,130.94) ; RJ15.1 v2(34.8,117.98) ; R678.1 v2(30.1,61.85) ; R431.2 94.54,123.32 v2(94.69,123.47) ; R454.2 v2(32,114.17) ; U95.5 41.76,162.33 v2(41.66,162.43) C266.1 ; R320.1 v2(47.12,166.75) ; R680.1 v2(28.07,61.85) ; R665.1 v2(155.45,33.27) ; 10.03,89.92 v2(10.79,89.92) ; R726.2 v2(48.77,128.52) ; R353.2 v2(81.79,151.13) ; R341.1 v2(121.28,152.02)
  vias: v2(116.08,106.43) v2(145.29,144.76) v2(145.29,142.76) v2(150.62,92.84) v2(151.38,92.84) v2(178.05,23.11) v2(178.94,23.11) v2(179.07,25.15) v2(179.07,24.13)
VIO_3V3_SD: length 15.5
  TOP w0.508: v2(138.43,158.62) 138.56,158.5 C28.1 ; 129.41,156.72 129.41,158.62 v2(129.42,158.62) ; C13.1 v2(136.27,164.08) ; C27.1 133.99,158.31 v2(134.23,158.55) ; C22.1 v2(134.87,160.15)
  BOTTOM w0.254: U96.7 121.66,159 v2(121.67,159) ; v2(122.43,158.88) 122.16,158.61 U96.8 ; U97.1 138.56,158.49 v2(138.43,158.62) ; U99.1 v2(129.42,158.62) ; v2(134.23,158.55) 133.99,158.31 U98.1
  BOTTOM w0.305: R323.1 v2(126.62,161.54)
  BOTTOM w0.508: P14.4 136.2,162.48 136.27,162.55 v2(136.27,164.08)
VIO_3V3USB: length 21.8
  TOP w0.305: U141.48 v2(48.81,126.83) ; U141.25 57.07,118.54 v2(57.15,118.62) ; v2(57.15,122.05) 56.66,122.53 U141.33 ; U141.37 v2(54.31,126.83) ; U141.13 v2(48.81,115.62) ; U141.23 53.81,115.93 v2(54.04,115.7) ; v2(52.83,126.84) 52.81,126.82 U141.40 ; v2(45.97,121.28) 46.22,121.04 U141.7
  TOP w0.406: v2(52.96,113.16) 52.96,112.78 L32.1 51.94,112.78 v2(51.94,113.16) ; v2(50.04,113.16) 50.04,112.78 C709.1 51.05,112.78 v2(51.05,113.16)
  BOTTOM w0.305: C694.1 54.1,115.76 v2(54.04,115.7) ; v2(45.97,121.28) C692.1 ; v2(57.15,122.05) C696.1 ; v2(57.15,118.62) 57.02,118.75 C695.1 ; 48.77,126.11 48.81,126.16 v2(48.81,126.83) ; 54.23,126.11 54.31,126.19 v2(54.31,126.83) ; 52.83,126.11 52.83,126.11 v2(52.83,126.84) ; C693.1 48.81,116.25 v2(48.81,115.62)
VIO_3V6: length 4.7
  TOP w0.508: 1.78,31.3 R274.1 ; R274.1 1.08,32.13 ; R274.1 1.78,32.96
  BOTTOM w0.381: C552.1 v2(2.29,31.11)
  BOTTOM w0.508: v2(5.21,34.16) 4.83,34.54 C550.1
  vias: v2(1.91,30.23) v2(9.91,37.47) v2(9.91,36.58)
VIO_IN_3V3: length 64.2
  TOP w0.305: Q16.3 159.53,60.85 v2(159.64,60.96) ; v1(159,67.69) 159.54,68.23 U38.34
  L7-SIGNAL w0.508: v2(162.56,38.73) 158.88,35.05 144.02,35.05 142.56,36.51 v2(138.68,36.51)
  L10-SIGNAL w0.508: v2(162.56,38.73) 162.56,41.27 162.94,41.66 162.94,43.94 163.45,44.45 163.45,47.13 162.59,47.99 162.59,51.34 163.7,52.45 163.7,53.47 164.04,53.8 164.04,54.86 163.53,55.37 162.56,55.37 160.66,57.28 160.66,60.06 159.76,60.96 v2(159.64,60.96) 159.64,62.2 160.02,62.58 160.02,66.67 v1(159,67.69)
  BOTTOM w0.305: C408.1 159.38,67.69 v1(159,67.69) ; v2(159.64,60.96) 159.38,60.71 R708.2
  BOTTOM w0.508: R667.1 v2(138.68,36.51)
VLIM_12V0: length 33.7
  TOP w0.305: 179.58,151.92 179.49,151.83 U9.8
  TOP w0.508: 192.28,155.59 R23.1 191.78,156.08 ; 179.58,151.92 180.87,153.21 182.28,153.21 Q2.5 ; 190.47,151.52 Q1.3 ; Q1.3 191.35,153.23 ; Q1.3 189.6,153.23 ; Q1.3 190.47,154.93 ; R39.2 v2(205.99,167.89)
  L12-SIGNAL w0.508: v2(205.99,167.89) 205.99,164.85 196.22,155.07 v2(192.28,155.07)
VOUT3B_CLK: length 86
  TOP w0.132: RU7.29 99.68,101.3 100.72,100.26 v1(100.72,99.74) ; RJ4.3 155.3,144.89 155.3,144.76 R59.2 v1(154.05,144.4)
  L12-SIGNAL w0.089: v1(154.05,144.4) 152.53,142.88 151.38,142.88 147.32,138.81 146.94,138.81 145.16,137.03 145.16,125.48 141.99,122.3 141.99,120.14 139.19,117.35 125.98,117.35 124.97,116.33 121.67,116.33 119.63,114.3 113.67,114.3 107.77,108.41 107.77,106.88 105.92,105.03 105.23,105.03 100.72,100.52 v1(100.72,99.74)
VOUT3B_CLK_CLEANED: length 20
  TOP w0.132: U8.10 159.03,157.07 161.93,154.18 161.93,148.34 160.15,146.56 RJ4.2
VOUT3B_D0: length 105
  TOP w0.132: U8.43 v1(152.39,150.88)
  L12-SIGNAL w0.089: v1(94.33,99.72) 94.33,98.73 95.53,97.54 99.31,97.54 100.2,98.42 100.2,100.46 105.28,105.54 105.79,105.54 106.93,106.68 106.93,108.08 114.43,115.57 120.27,115.57 121.33,116.64 122.24,116.64 123.34,117.73 138.81,117.73 140.97,119.89 140.97,133.48 142.88,135.38 142.88,145.03 143.13,145.29 143.89,145.29 144.25,145.65 150.35,145.65 150.49,145.8 150.49,145.98 150.17,146.3 150.17,146.49 150.3,146.62 150.48,146.62 150.81,146.29 150.99,146.29 151.12,146.42 151.12,146.61 150.8,146.93 150.8,147.12 150.93,147.25 151.11,147.25 151.44,146.92 151.62,146.92 151.75,147.05 151.75,147.24 151.43,147.56 151.43,147.74 151.56,147.88 151.74,147.88 152.07,147.55 152.25,147.55 152.39,147.7 v1(152.39,150.88)
  BOTTOM w0.132: RU16.46 v1(94.33,99.72)
VOUT3B_D1: length 106.7
  TOP w0.132: U8.44 v1(152.9,150.25)
  L12-SIGNAL w0.089: v1(95.33,99.72) 94.87,99.26 94.87,98.62 95.57,97.92 99.19,97.92 99.82,98.55 99.82,100.58 105.16,105.92 105.54,105.92 106.55,106.93 106.55,108.2 114.3,115.95 120.14,115.95 122.3,118.11 138.3,118.11 139.92,119.73 139.92,133.06 141.83,134.97 141.83,144.88 143.13,146.18 143.76,146.18 144.27,146.69 147.7,146.69 147.75,146.74 147.94,146.74 148.26,146.41 148.45,146.41 148.58,146.54 148.58,146.73 148.25,147.05 148.25,147.24 148.38,147.37 148.57,147.37 148.89,147.04 149.07,147.04 149.2,147.17 149.2,147.36 148.88,147.68 148.88,147.86 149.01,148 149.2,148 149.52,147.67 149.7,147.67 149.83,147.8 149.83,147.99 149.51,148.31 149.51,148.49 149.64,148.62 149.82,148.62 150.15,148.3 150.33,148.3 150.46,148.43 150.46,148.61 150.14,148.94 150.14,149.12 150.28,149.27 150.28,150.24 151.01,150.97 151.01,151.14 151.38,151.51 152.53,151.51 152.9,151.14 v1(152.9,150.25)
  BOTTOM w0.132: RU16.48 v1(95.33,99.72)
VOUT3B_D2: length 105
  TOP w0.132: U8.45 v1(153.4,150.9)
  L12-SIGNAL w0.089: v1(153.4,150.9) 153.4,151.28 152.91,151.76 150.5,151.76 149.86,151.13 149.86,150.79 149.35,150.28 149.35,149.35 148.72,148.72 147.77,148.72 147.64,148.85 147.64,149.6 147.51,149.73 147.33,149.73 147.2,149.6 147.2,148.85 147.07,148.72 146.88,148.72 146.75,148.85 146.75,149.6 146.62,149.73 146.44,149.73 146.31,149.6 146.31,148.85 146.18,148.72 145.99,148.72 145.86,148.85 145.86,149.6 145.73,149.73 145.55,149.73 145.42,149.6 145.42,148.85 145.29,148.72 142.62,148.72 141.35,147.45 141.35,135.38 139.57,133.6 139.57,122.05 138.94,121.41 138.94,119.63 137.79,118.49 122.3,118.49 120.14,116.33 114.17,116.33 104.01,106.17 104.01,105.41 99.06,100.46 99.06,99.44 98.81,99.19 98.81,98.41 98.7,98.3 97.74,98.3 v1(97.33,98.7)
  BOTTOM w0.132: v1(97.33,98.7) 96.83,99.2 RU16.51
VOUT3B_D3: length 106.2
  TOP w0.132: U8.46 v1(153.9,150.27)
  L12-SIGNAL w0.089: v1(98.33,98.7) 98.33,99.09 98.72,99.48 98.72,100.62 103.5,105.41 103.5,106.17 114.05,116.71 119.89,116.71 121.16,117.98 121.41,117.98 122.3,118.87 137.16,118.87 137.92,119.63 137.92,121.41 138.43,121.92 138.43,133.48 140.84,135.89 140.84,148.97 143,151.13 143.67,151.13 143.8,151.26 143.8,151.89 143.93,152.02 144.12,152.02 144.25,151.89 144.25,151.26 144.38,151.13 144.56,151.13 144.69,151.26 144.69,151.89 144.82,152.02 145.01,152.02 145.14,151.89 145.14,151.26 145.27,151.13 145.45,151.13 145.58,151.26 145.58,151.89 145.71,152.02 145.9,152.02 146.03,151.89 146.03,151.26 146.16,151.13 146.34,151.13 146.47,151.26 146.47,151.89 146.6,152.02 146.79,152.02 146.92,151.89 146.92,151.26 147.05,151.13 148.59,151.13 149.61,152.15 153.16,152.15 153.9,151.41 v1(153.9,150.27)
  BOTTOM w0.132: v1(98.33,98.7) 97.83,99.2 RU16.53
VOUT3B_D4: length 56.5
  TOP w0.132: U8.47 v1(154.4,150.91)
  L3-SIGNAL w0.109: v1(130.83,115.82) 128.65,118 128.65,128.91 133.47,133.72 133.47,133.95 133.12,134.29 133.12,134.52 133.28,134.68 133.51,134.68 133.85,134.34 134.08,134.34 134.62,134.87 134.62,139.06 139.95,144.4 140.46,144.4 143.93,147.86 145.2,147.86 146.97,149.63 153.82,149.63 154.4,150.21 v1(154.4,150.91)
  BOTTOM w0.132: v1(130.83,115.82) 130.83,116.29 130.92,116.38 RU13.29
VOUT3B_D5: length 63.3
  TOP w0.132: U8.48 v1(154.89,150.29)
  L3-SIGNAL w0.109: v1(154.89,150.29) 153.83,149.22 149.1,149.22 148.66,148.79 146.88,148.79 145.92,147.83 145.92,147.59 146.08,147.43 146.65,147.43 146.81,147.27 146.81,147.05 146.65,146.89 146.08,146.89 145.92,146.73 145.92,146.5 146.08,146.34 146.65,146.34 146.81,146.18 146.81,145.95 146.65,145.79 146.08,145.79 145.92,145.63 145.92,145.41 146.08,145.25 146.65,145.25 146.81,145.09 146.81,144.86 146.65,144.7 146.08,144.7 145.92,144.54 145.92,142.49 145.16,141.73 145.16,137.29 143.81,135.93 143.81,133.05 143.56,132.8 142.74,132.8 140.76,130.82 140.76,129.87 139.7,128.81 139.7,124.59 139.24,124.13 130.99,124.13 129.67,122.81 129.67,118.55 130.88,117.33 130.88,116.43 v1(131.49,115.82)
  BOTTOM w0.132: v1(131.49,115.82) 131.92,116.26 RU13.31
VOUT3B_D6: length 66.2
  TOP w0.132: U8.1 v1(155.68,151.92)
  L3-SIGNAL w0.109: v1(155.68,151.92) 155.68,150.34 154.19,148.86 153,148.86 152.84,148.7 152.84,147.1 152.68,146.94 152.45,146.94 152.29,147.1 152.29,148.7 152.13,148.86 150.47,148.86 150.31,148.7 150.31,147.86 150.15,147.7 149.92,147.7 149.76,147.86 149.76,148.7 149.6,148.86 149.37,148.86 148.87,148.37 148.87,148.14 149.09,147.92 149.09,147.7 148.93,147.54 148.71,147.54 148.49,147.75 148.26,147.75 148.1,147.59 148.1,147.37 148.32,147.15 148.32,146.92 148.16,146.76 147.93,146.76 147.72,146.98 147.49,146.98 147.32,146.81 147.32,143 145.67,141.35 145.67,137.16 144.15,135.64 144.15,132.84 142.75,131.44 142.05,131.44 141.22,130.62 141.22,129.79 140.21,128.78 140.21,128.11 140.76,127.56 140.76,127.21 140.21,126.66 140.21,124.21 139.7,123.7 131.22,123.7 130.68,123.16 130.68,121.12 130.67,121.11 130.67,120.78 130.68,120.77 130.68,118.75 131.91,117.52 131.91,116.49 v1(132.46,115.94)
  BOTTOM w0.132: RU13.33 132.92,116.41 132.75,116.24 132.75,116.23 v1(132.46,115.94)
VOUT3B_D7: length 59.3
  TOP w0.132: v1(156.84,152.65) 156.43,153.07 U8.2
  L3-SIGNAL w0.109: v1(133.35,115.94) 132.84,116.45 132.84,117.98 131.95,118.87 131.95,123.06 132.21,123.32 139.95,123.32 140.72,124.08 140.72,126.49 141.1,126.87 141.1,129.16 141.82,129.88 141.82,130.73 142.06,130.98 142.79,130.98 144.53,132.72 144.53,135.38 146.05,136.91 146.05,140.48 147.18,141.6 149.95,141.6 150.12,141.77 150.12,142 149.85,142.26 149.85,142.49 150.01,142.65 150.24,142.65 150.5,142.39 150.73,142.39 153.8,145.45 153.8,147.83 156.84,150.88 v1(156.84,152.65)
  BOTTOM w0.132: RU13.35 133.92,116.52 133.64,116.24 133.64,116.23 v1(133.35,115.94)
VOUT3B_D8: length 58.5
  TOP w0.132: U8.35 v1(147.1,153.07)
  L5-SIGNAL w0.089: v1(134.37,115.94) 134.87,116.45 134.87,121.75 134.88,121.76 134.88,122.08 134.87,122.09 134.87,122.68 133.35,124.21 133.35,125.48 132.08,126.75 132.08,146.68 132.35,146.95 132.35,147.14 131.83,147.65 131.83,147.84 131.96,147.97 132.15,147.97 132.66,147.45 132.85,147.45 132.98,147.58 132.98,147.77 132.46,148.28 132.46,148.46 132.59,148.59 132.78,148.59 133.29,148.08 133.48,148.08 139.45,154.05 140.97,154.05 141.35,154.43 144.78,154.43 146.14,153.07 v1(147.1,153.07)
  BOTTOM w0.132: v1(134.37,115.94) 134.92,116.5 RU13.37
VOUT3B_D9: length 61.2
  TOP w0.132: U8.36 v1(147.75,152.57)
  L5-SIGNAL w0.089: v1(136.42,116.87) 136.42,117.53 135.89,118.06 135.89,123.06 134.62,124.33 134.62,125.48 133.35,126.75 133.35,138.4 133.22,138.53 132.72,138.53 132.59,138.66 132.59,138.84 132.72,138.97 133.22,138.97 133.35,139.1 133.35,139.29 133.22,139.42 132.72,139.42 132.59,139.55 132.59,139.73 132.72,139.86 133.22,139.86 133.35,139.99 133.35,140.18 133.22,140.31 132.72,140.31 132.59,140.44 132.59,140.62 132.72,140.75 133.22,140.75 133.35,140.88 133.35,141.06 133.22,141.2 132.72,141.2 132.59,141.33 132.59,141.51 132.72,141.64 133.22,141.64 133.35,141.77 133.35,141.95 133.22,142.08 132.72,142.08 132.59,142.21 132.59,142.4 132.72,142.53 133.22,142.53 133.35,142.66 133.35,142.84 133.22,142.97 132.72,142.97 132.59,143.1 132.59,143.29 132.72,143.42 133.22,143.42 133.35,143.55 133.35,143.73 133.22,143.86 132.72,143.86 132.59,143.99 132.59,144.18 132.72,144.31 133.22,144.31 133.35,144.44 133.35,144.62 133.22,144.75 132.72,144.75 132.59,144.88 132.59,145.07 132.72,145.2 133.22,145.2 133.35,145.33 133.35,145.51 133.22,145.64 132.72,145.64 132.59,145.77 132.59,145.95 132.72,146.08 133.22,146.08 133.35,146.21 133.35,146.43 139.07,152.15 147.32,152.15 v1(147.75,152.57)
  BOTTOM w0.132: RU13.40 v1(136.42,116.87)
VOUT3B_D10: length 59.4
  TOP w0.132: U8.37 v1(149.4,150.92)
  L5-SIGNAL w0.089: v1(137.42,116.87) 137.92,117.37 137.92,121.54 138.3,121.92 138.3,122.94 137.92,123.32 136.78,123.32 135.89,124.21 135.89,125.35 134.62,126.62 134.62,126.99 134.49,127.12 133.99,127.12 133.86,127.25 133.86,127.43 133.99,127.57 134.49,127.57 134.62,127.7 134.62,127.88 134.49,128.01 133.99,128.01 133.86,128.14 133.86,128.32 133.99,128.45 134.49,128.45 134.62,128.58 134.62,128.77 134.49,128.9 133.99,128.9 133.86,129.03 133.86,129.21 133.99,129.34 134.49,129.34 134.62,129.47 134.62,129.66 134.49,129.79 133.99,129.79 133.86,129.92 133.86,130.1 133.99,130.23 134.49,130.23 134.62,130.36 134.62,130.55 134.49,130.68 133.99,130.68 133.86,130.81 133.86,130.99 133.99,131.12 134.49,131.12 134.62,131.25 134.62,131.44 134.49,131.57 133.99,131.57 133.86,131.7 133.86,131.88 133.99,132.01 134.49,132.01 134.62,132.14 134.62,146.94 139.32,151.64 145.8,151.64 146.23,151.2 149.11,151.2 v1(149.4,150.92)
  BOTTOM w0.132: RU13.42 v1(137.42,116.87)
VOUT3B_D11: length 59.5
  TOP w0.132: U8.38 v1(149.9,150.28)
  L5-SIGNAL w0.089: v1(138.42,116.87) 138.42,118.22 138.94,118.75 138.94,121.54 138.65,121.83 138.65,124.62 135.89,127.38 135.89,140.94 135.76,141.07 135.26,141.07 135.13,141.2 135.13,141.38 135.26,141.51 135.76,141.51 135.89,141.64 135.89,141.83 135.76,141.96 135.26,141.96 135.13,142.09 135.13,142.27 135.26,142.4 135.76,142.4 135.89,142.53 135.89,142.72 135.76,142.85 135.26,142.85 135.13,142.98 135.13,143.16 135.26,143.29 135.76,143.29 135.89,143.42 135.89,143.61 135.76,143.74 135.26,143.74 135.13,143.87 135.13,144.05 135.26,144.18 135.76,144.18 135.89,144.31 135.89,144.49 135.76,144.62 135.26,144.62 135.13,144.75 135.13,144.94 135.26,145.07 135.76,145.07 135.89,145.2 135.89,145.38 135.76,145.51 135.26,145.51 135.13,145.64 135.13,145.83 135.26,145.96 135.76,145.96 135.89,146.09 135.89,146.27 135.76,146.4 135.26,146.4 135.13,146.53 135.13,146.72 135.26,146.85 135.76,146.85 135.89,146.98 135.89,147.19 139.99,151.29 145,151.29 145.45,150.84 148.84,150.84 149.41,150.28 v1(149.9,150.28)
  BOTTOM w0.132: RU13.44 v1(138.42,116.87)
VOUT3B_D12: length 59.6
  TOP w0.132: U8.39 v1(150.4,150.9)
  L5-SIGNAL w0.089: v1(139.42,116.87) 139.42,118.44 139.95,118.97 139.95,124.59 137.41,127.13 137.41,128.4 137.16,128.65 137.16,128.87 137.03,129 136.4,129 136.27,129.13 136.27,129.31 136.4,129.44 137.03,129.44 137.16,129.57 137.16,129.76 137.03,129.89 136.4,129.89 136.27,130.02 136.27,130.2 136.4,130.33 137.03,130.33 137.16,130.46 137.16,130.65 137.03,130.78 136.4,130.78 136.27,130.91 136.27,131.09 136.4,131.22 137.03,131.22 137.16,131.35 137.16,131.53 137.03,131.66 136.4,131.66 136.27,131.79 136.27,131.98 136.4,132.11 137.03,132.11 137.16,132.24 137.16,132.42 137.03,132.55 136.4,132.55 136.27,132.68 136.27,132.87 136.4,133 137.03,133 137.16,133.13 137.16,133.31 137.03,133.44 136.4,133.44 136.27,133.57 136.27,133.76 136.4,133.89 137.03,133.89 137.16,134.02 137.16,147.7 139.92,150.46 141.7,150.46 142.14,150.9 144.63,150.9 145.8,149.73 150.15,149.73 150.4,149.98 v1(150.4,150.9)
  BOTTOM w0.132: RU13.46 v1(139.42,116.87)
VOUT3B_D13: length 55.2
  TOP w0.132: U8.40 v1(150.9,150.26)
  L5-SIGNAL w0.089: v1(150.9,150.26) 150.9,149.63 149.99,148.72 143,148.72 141.99,149.73 139.83,149.73 138.43,148.34 138.43,147.48 138.3,147.35 137.93,147.35 137.79,147.22 137.79,147.04 137.93,146.91 138.3,146.91 138.43,146.78 138.43,146.59 138.3,146.46 137.93,146.46 137.79,146.33 137.79,146.15 137.93,146.02 138.3,146.02 138.43,145.89 138.43,145.7 138.3,145.57 137.93,145.57 137.79,145.44 137.79,145.26 137.93,145.13 138.3,145.13 138.43,145 138.43,144.82 138.3,144.69 137.93,144.69 137.79,144.55 137.79,144.37 137.93,144.24 138.3,144.24 138.43,144.11 138.43,143.93 138.3,143.8 137.93,143.8 137.79,143.67 137.79,143.48 137.93,143.35 138.3,143.35 138.43,143.22 138.43,127.13 140.97,124.59 140.97,117.42 v1(140.42,116.87)
  BOTTOM w0.132: RU13.48 v1(140.42,116.87)
VOUT3B_D14: length 54.9
  TOP w0.132: U8.41 v1(151.4,150.89)
  L5-SIGNAL w0.089: v1(142.42,115.85) 142.13,116.13 142.13,116.18 141.99,116.33 141.99,124.34 139.57,126.76 139.57,135.76 141.48,137.67 141.48,141.6 143.13,143.26 145.42,143.26 146.3,144.14 146.3,144.33 145.91,144.71 145.91,144.9 146.04,145.03 146.23,145.03 146.61,144.64 146.8,144.64 146.95,144.79 146.95,144.98 146.37,145.56 146.37,145.74 146.51,145.87 146.69,145.87 147.27,145.29 147.45,145.29 147.58,145.42 147.58,145.61 147,146.18 147,146.37 147.13,146.5 147.32,146.5 147.9,145.92 148.08,145.92 148.21,146.05 148.21,146.23 147.63,146.81 147.63,147 147.76,147.13 147.95,147.13 148.52,146.55 148.71,146.55 148.84,146.68 148.84,146.86 148.26,147.44 148.26,147.63 148.39,147.76 148.58,147.76 149.15,147.18 149.34,147.18 151.4,149.24 v1(151.4,150.89)
  BOTTOM w0.132: RU13.51 141.92,116.35 v1(142.42,115.85)
VOUT3B_D15: length 56.2
  TOP w0.132: U8.42 v1(151.9,150.25)
  L5-SIGNAL w0.089: v1(151.9,150.25) 151.9,149.35 152.05,149.19 152.05,147.35 151.9,147.2 151.71,147.2 151.01,147.9 150.82,147.9 150.69,147.77 150.69,147.59 151.4,146.88 151.4,146.7 151.27,146.57 151.08,146.57 150.38,147.27 150.2,147.27 150.06,147.14 150.06,146.96 150.77,146.25 150.77,146.07 150.64,145.94 150.46,145.94 149.75,146.65 149.57,146.65 149.44,146.52 149.44,146.33 150.14,145.63 150.14,145.44 150.01,145.31 149.83,145.31 149.12,146.02 148.94,146.02 148.81,145.89 148.81,145.7 149.51,145 149.51,144.81 149.1,144.4 147.83,144.4 147.03,143.61 147.03,143.31 146.9,143.18 146.31,143.18 146.18,143.05 146.18,142.86 146.31,142.73 146.9,142.73 147.03,142.6 147.03,142.42 146.9,142.29 146.31,142.29 146.18,142.16 146.18,141.97 146.31,141.84 146.9,141.84 147.03,141.71 147.03,141.53 146.9,141.4 146.31,141.4 146.18,141.27 146.18,141.09 146.31,140.95 146.9,140.95 147.03,140.82 147.03,139.22 145.03,137.22 145.03,121.29 143.89,120.14 143.89,116.32 v1(143.42,115.85)
  BOTTOM w0.132: RU13.53 142.92,116.35 v1(143.42,115.85)
VOUT3B_D16: length 105.4
  TOP w0.132: U8.25 v1(147.07,158.07)
  L3-SIGNAL w0.109: v1(93.21,104.9) 93.21,109.09 98.42,114.3 100.08,114.3 118.74,132.97 121.92,132.97 124.71,135.76 124.71,135.85 124.76,135.89 124.76,138.04 125.73,139.01 125.73,142.11 125.73,142.34 124.5,143.57 124.5,143.8 124.66,143.96 124.88,143.96 126.12,142.73 126.34,142.73 126.5,142.89 126.5,143.11 125.27,144.35 125.27,144.57 125.43,144.73 125.66,144.73 126.89,143.5 127.12,143.5 127.28,143.66 127.28,143.88 126.04,145.12 126.04,145.34 126.2,145.51 126.43,145.51 127.66,144.27 127.89,144.27 128.05,144.43 128.05,144.66 126.81,145.89 126.81,146.12 126.97,146.28 127.2,146.28 128.43,145.04 128.66,145.04 128.82,145.2 128.82,145.43 127.59,146.66 127.59,146.89 127.75,147.05 127.97,147.05 129.21,145.82 129.43,145.82 137.92,154.31 141.35,154.31 145.12,158.07 v1(147.07,158.07)
  BOTTOM w0.132: RU16.44 93.33,104.37 93.21,104.49 v1(93.21,104.9)
VOUT3B_D17: length 95.1
  TOP w0.132: U8.26 v1(147.74,157.57)
  L3-SIGNAL w0.109: v1(147.74,157.57) 146.27,157.57 143.64,154.94 142.62,154.94 141.61,153.92 139.45,153.92 138.05,152.53 136.78,152.53 136.61,152.36 136.61,152.13 137.4,151.34 137.4,151.12 137.24,150.96 137.01,150.96 136.22,151.75 136,151.75 135.84,151.59 135.84,151.36 136.63,150.57 136.63,150.34 136.47,150.18 136.24,150.18 135.45,150.97 135.23,150.97 135.07,150.81 135.07,150.59 135.86,149.8 135.86,149.57 135.7,149.41 135.47,149.41 134.68,150.2 134.45,150.2 126.11,141.86 126.11,138.81 125.18,137.88 125.18,135.67 121.97,132.46 118.87,132.46 100.2,113.79 98.93,113.79 93.85,108.71 93.85,104.78 93.58,104.5 92.71,104.5 v1(92.32,104.89)
  BOTTOM w0.132: v1(92.32,104.89) 92.32,103.77 92.58,103.51 92.58,102.62 92.33,102.37 RU16.42
VOUT3B_D18: length 108.5
  TOP w0.132: U8.27 v1(147.09,157.07)
  L3-SIGNAL w0.109: v1(147.09,157.07) 146.4,157.07 143.89,154.56 142.88,154.56 141.88,153.56 140.4,153.56 135.81,148.97 133.86,148.97 133.45,148.57 133.45,148.34 134.31,147.49 134.31,147.26 134.15,147.1 133.92,147.1 133.07,147.95 132.84,147.95 132.68,147.79 132.68,147.57 133.53,146.71 133.53,146.49 133.37,146.33 133.15,146.33 132.29,147.18 132.07,147.18 131.91,147.02 131.91,146.79 132.76,145.94 132.76,145.72 132.6,145.56 132.38,145.56 131.52,146.41 131.3,146.41 131.14,146.25 131.14,146.02 131.99,145.17 131.99,144.94 131.83,144.78 131.6,144.78 130.75,145.64 130.52,145.64 130.36,145.48 130.36,145.25 131.22,144.4 131.22,144.17 131.06,144.01 130.83,144.01 129.98,144.86 129.75,144.86 129.59,144.7 129.59,144.48 130.44,143.62 130.44,143.4 130.28,143.24 130.06,143.24 129.2,144.09 128.98,144.09 128.82,143.93 128.82,143.7 129.67,142.85 129.67,142.63 129.51,142.46 129.28,142.46 128.43,143.32 128.2,143.32 128.04,143.16 128.04,142.93 128.9,142.08 128.9,141.85 128.74,141.69 128.51,141.69 127.66,142.55 127.43,142.55 127.27,142.39 127.27,142.16 128.13,141.31 128.13,141.08 126.49,139.45 126.49,138.68 126.21,138.41 126.21,135.87 122.3,131.95 119,131.95 95.12,108.08 95.12,107.7 94.36,106.93 94.36,104.78 93.09,103.5 91.51,103.5 v1(91.26,103.25)
  BOTTOM w0.132: RU16.40 91.33,102.47 91.25,102.56 v1(91.26,103.25)
VOUT3B_D19: length 106.2
  TOP w0.132: U8.28 v1(147.72,156.57)
  L3-SIGNAL w0.109: v1(147.72,156.57) 146.79,156.57 143.64,153.42 142.24,153.42 141.46,152.64 140.32,152.64 132.29,144.61 132.29,144.38 133.14,143.53 133.14,143.3 132.98,143.14 132.76,143.14 131.9,144 131.68,144 131.52,143.84 131.52,143.61 132.37,142.76 132.37,142.53 132.21,142.37 131.98,142.37 131.13,143.22 130.9,143.22 130.74,143.06 130.74,142.84 131.6,141.98 131.6,141.76 131.44,141.6 131.21,141.6 130.36,142.45 130.13,142.45 129.97,142.29 129.97,142.06 130.82,141.21 130.82,140.98 130.66,140.82 130.44,140.82 129.58,141.68 129.36,141.68 129.2,141.52 129.2,141.29 130.05,140.44 130.05,140.21 129.89,140.05 129.67,140.05 128.81,140.91 128.59,140.91 128.43,140.74 128.43,140.52 129.28,139.67 129.28,139.44 129.12,139.28 128.89,139.28 128.04,140.13 127.81,140.13 127.65,139.97 127.65,139.75 128.51,138.89 128.51,138.67 128.35,138.51 128.12,138.51 127.27,139.36 127.04,139.36 126.87,139.19 126.87,138.56 126.45,138.13 126.45,135.61 118.73,127.89 115.57,127.89 106.3,118.62 106.3,117.88 105.19,116.77 104.45,116.77 99.82,112.14 99.82,111.12 99.44,110.74 98.55,110.74 95.76,107.95 95.76,105.54 92.58,102.36 91.06,102.36 v1(90.43,103)
  BOTTOM w0.132: RU16.37 89.83,102.87 89.97,103 v1(90.43,103)
VOUT3B_D20: length 103.8
  TOP w0.132: U8.29 v1(147.08,156.07)
  L3-SIGNAL w0.109: v1(89.31,99.44) 89.31,100.49 89.92,101.09 91.82,101.09 98.3,107.57 98.3,108.83 100.71,111.23 100.71,111.76 106.81,117.86 106.81,118.49 114.16,125.84 114.38,125.84 114.6,125.62 114.83,125.62 114.99,125.78 114.99,126.01 114.77,126.23 114.77,126.45 114.93,126.61 115.16,126.61 115.37,126.39 115.6,126.39 115.76,126.55 115.76,126.78 115.54,127 115.54,127.23 115.7,127.39 115.93,127.39 116.15,127.17 116.37,127.17 116.59,127.38 118.87,127.38 127.3,135.8 127.3,136.82 127.6,137.12 127.6,137.35 127,137.95 127,138.17 127.16,138.34 127.39,138.34 127.98,137.74 128.21,137.74 133.6,143.13 133.6,144.15 133.17,144.58 133.17,144.73 133.77,145.33 134,145.33 134.91,144.41 135.14,144.41 135.3,144.57 135.3,144.8 134.38,145.72 134.38,145.94 134.54,146.1 134.77,146.1 135.69,145.18 135.91,145.18 136.07,145.34 136.07,145.57 135.16,146.49 135.16,146.71 135.32,146.87 135.54,146.87 136.46,145.96 136.69,145.96 136.85,146.12 136.85,146.34 135.93,147.26 135.93,147.49 136.1,147.65 136.32,147.65 136.8,147.18 137.02,147.18 137.18,147.34 137.18,147.57 136.71,148.04 136.71,148.27 140.72,152.27 142.1,152.27 142.21,152.38 142.21,152.62 142.37,152.78 142.6,152.78 142.76,152.62 142.76,152.38 142.87,152.27 143.28,152.27 v1(147.08,156.07)
  BOTTOM w0.132: v1(89.31,99.44) 88.83,99.92 RU16.35
VOUT3B_D21: length 103.1
  TOP w0.132: U8.32 v1(147.71,154.57)
  L3-SIGNAL w0.109: v1(147.71,154.57) 147.02,154.57 146.22,153.77 146.22,152.48 145.97,152.23 145.12,152.23 144.53,151.64 142.75,151.64 141.35,150.24 139.83,150.24 137.92,148.34 137.92,146.3 128.4,136.78 128.4,135.89 118.87,126.36 116.97,126.36 116.8,126.2 116.8,125.97 117.21,125.56 117.21,125.34 117.05,125.18 116.82,125.18 116.41,125.58 116.19,125.58 116.03,125.42 116.03,125.2 116.44,124.79 116.44,124.56 116.28,124.4 116.05,124.4 115.64,124.81 115.41,124.81 115.25,124.65 115.25,124.43 115.66,124.02 115.66,123.79 115.5,123.63 115.28,123.63 114.87,124.04 114.64,124.04 114.48,123.88 114.48,123.65 114.89,123.24 114.89,123.02 114.73,122.86 114.5,122.86 114.09,123.27 113.87,123.27 113.71,123.11 113.71,122.88 114.12,122.47 114.12,122.25 113.96,122.09 113.73,122.09 113.32,122.49 113.1,122.49 112.94,122.33 112.94,122.11 113.34,121.7 113.34,121.47 113.18,121.31 112.96,121.31 112.55,121.72 112.32,121.72 112.16,121.56 112.16,121.34 112.57,120.93 112.57,120.7 112.41,120.54 112.19,120.54 111.78,120.95 111.55,120.95 111.39,120.79 111.39,120.56 111.8,120.15 111.8,119.93 111.64,119.77 111.41,119.77 111,120.18 110.78,120.18 110.62,120.02 110.62,119.79 111.03,119.38 111.03,119.15 110.87,118.99 110.64,118.99 110.23,119.4 110.01,119.4 109.6,119 109.6,117.86 109.09,117.35 109.09,116.71 108.46,116.08 106.68,116.08 99.04,108.44 99.04,107.04 95.23,103.23 95.23,102.58 95,102.35 94.34,102.35 91.59,99.59 91.59,99.41 91.23,99.04 88.73,99.04 v1(88.33,99.44)
  BOTTOM w0.132: v1(88.33,99.44) 87.83,99.94 RU16.33
VOUT3B_D22: length 105.2
  TOP w0.132: U8.33 v1(147.09,154.07)
  L3-SIGNAL w0.109: v1(87.34,99.54) 87.83,99.04 88.4,99.04 88.63,98.81 92.08,98.81 92.65,99.38 92.65,99.61 92.5,99.76 92.5,99.99 92.66,100.15 92.88,100.15 93.04,99.99 93.26,99.99 93.42,100.15 93.42,100.38 93.27,100.54 93.27,100.76 93.43,100.92 93.66,100.92 93.81,100.77 94.04,100.77 94.2,100.93 94.2,101.15 94.04,101.31 94.04,101.53 94.2,101.69 94.43,101.69 94.58,101.54 94.81,101.54 95.76,102.49 95.76,103.25 99.17,106.66 99.61,106.66 100.47,107.53 100.47,107.86 100.08,108.26 100.08,108.84 100.57,109.33 101.13,109.33 101.36,109.56 101.36,110.13 101.88,110.64 102.1,110.64 102.7,110.04 102.93,110.04 103.09,110.2 103.09,110.42 102.49,111.02 102.49,111.25 102.65,111.41 102.87,111.41 103.47,110.81 103.7,110.81 103.86,110.97 103.86,111.2 103.26,111.8 103.26,112.02 103.42,112.18 103.65,112.18 104.25,111.58 104.47,111.58 104.63,111.74 104.63,111.97 104.03,112.57 104.03,112.8 104.19,112.96 104.42,112.96 105.02,112.36 105.24,112.36 105.4,112.52 105.4,112.74 104.81,113.34 104.81,113.57 104.97,113.73 105.19,113.73 105.76,113.16 105.92,113.16 106.15,113.39 106.15,113.54 105.58,114.11 105.58,114.34 105.74,114.5 105.96,114.5 106.56,113.9 106.79,113.9 106.95,114.06 106.95,114.29 106.35,114.89 106.35,115.11 106.81,115.57 108.84,115.57 111.38,118.11 111.38,119 118.24,125.86 118.93,125.86 128.91,135.83 128.91,136.78 138.3,146.18 138.3,148.1 139.86,149.66 141.27,149.66 142.87,151.26 145.41,151.26 146.7,152.55 146.7,153.24 147.09,153.62 v1(147.09,154.07)
  BOTTOM w0.132: v1(87.34,99.54) 86.83,100.04 RU16.31
VOUT3B_D23: length 102.6
  TOP w0.132: U8.34 v1(147.73,153.57)
  L3-SIGNAL w0.109: v1(147.73,153.57) 147.73,153.14 145.51,150.92 143.04,150.92 140.78,148.65 140.12,148.65 139.62,148.15 139.36,148.15 138.68,147.48 138.68,145.92 129.41,136.65 129.41,135.84 117.22,123.64 117.22,123.19 115.06,121.03 114.05,121.03 112.01,119 112.01,117.09 111.51,116.59 110.36,116.59 108.29,114.51 108.06,114.51 107.59,114.98 107.36,114.98 107.2,114.82 107.2,114.6 107.68,114.12 107.68,113.9 106.93,113.16 106.44,113.16 106.05,112.77 106.05,112.28 102.62,108.84 102.39,108.84 102.11,109.12 101.88,109.12 101.72,108.96 101.72,108.74 102,108.45 102,108.23 101.84,108.06 101.61,108.06 101.01,108.66 100.78,108.66 100.62,108.5 100.62,108.27 101.22,107.67 101.22,107.45 99.95,106.17 99.19,106.17 97.3,104.29 97.3,104.06 97.71,103.65 97.71,103.42 97.55,103.26 97.32,103.26 96.91,103.67 96.69,103.67 96.52,103.5 96.52,101.57 96.36,101.41 95.41,101.41 95.25,101.25 95.25,101.03 95.41,100.87 96.36,100.87 96.52,100.71 96.52,100.47 95.93,99.89 95.93,99.49 95.55,99.1 95.04,99.1 94.51,98.57 93.97,98.57 93.81,98.73 93.81,99.41 93.65,99.57 93.42,99.57 93.26,99.41 93.26,98.73 93.1,98.57 88.54,98.57 88.3,98.81 87.73,98.81 87.48,99.06 86.84,99.06 v1(86.36,99.54)
  BOTTOM w0.132: v1(86.36,99.54) 85.83,100.06 RU16.29
VOUT3B_DE: length 103.9
  TOP w0.132: U8.5 156.53,154.57 156.63,154.47 v1(157.05,154.47) ; v1(90.3,98.17) 89.83,98.63 RU7.48
  L3-SIGNAL w0.109: v1(157.05,154.47) 150.69,154.47 148.14,151.92 148.14,151.74 147.75,151.34 146.48,151.34 145.82,150.68 143.33,150.68 140.31,147.65 140.12,147.65 139.62,147.15 139.36,147.15 139.06,146.86 139.06,145.54 130.81,137.29 130.81,135.89 129.96,135.04 129.73,135.04 129.58,135.2 129.35,135.2 129.19,135.04 129.19,134.81 129.35,134.65 129.35,134.43 129.19,134.27 128.96,134.27 128.81,134.42 128.58,134.42 128.42,134.26 128.42,134.04 128.58,133.88 128.58,133.66 128.42,133.5 128.19,133.5 128.03,133.65 127.81,133.65 127.65,133.49 127.65,133.26 127.8,133.11 127.8,132.88 127.64,132.72 127.42,132.72 127.26,132.88 127.04,132.88 126.88,132.72 126.88,132.49 127.03,132.34 127.03,132.11 126.87,131.95 126.64,131.95 126.49,132.1 126.26,132.1 126.1,131.94 126.1,131.72 126.26,131.56 126.26,131.34 118.75,123.83 118.75,121.79 117.46,120.51 115.3,120.51 112.39,117.6 112.39,116.92 111.7,116.22 111.03,116.22 99.98,105.17 99.71,105.17 99.2,104.66 99.2,104.28 96.9,101.98 96.9,98.42 96.65,98.17 v1(90.3,98.17)
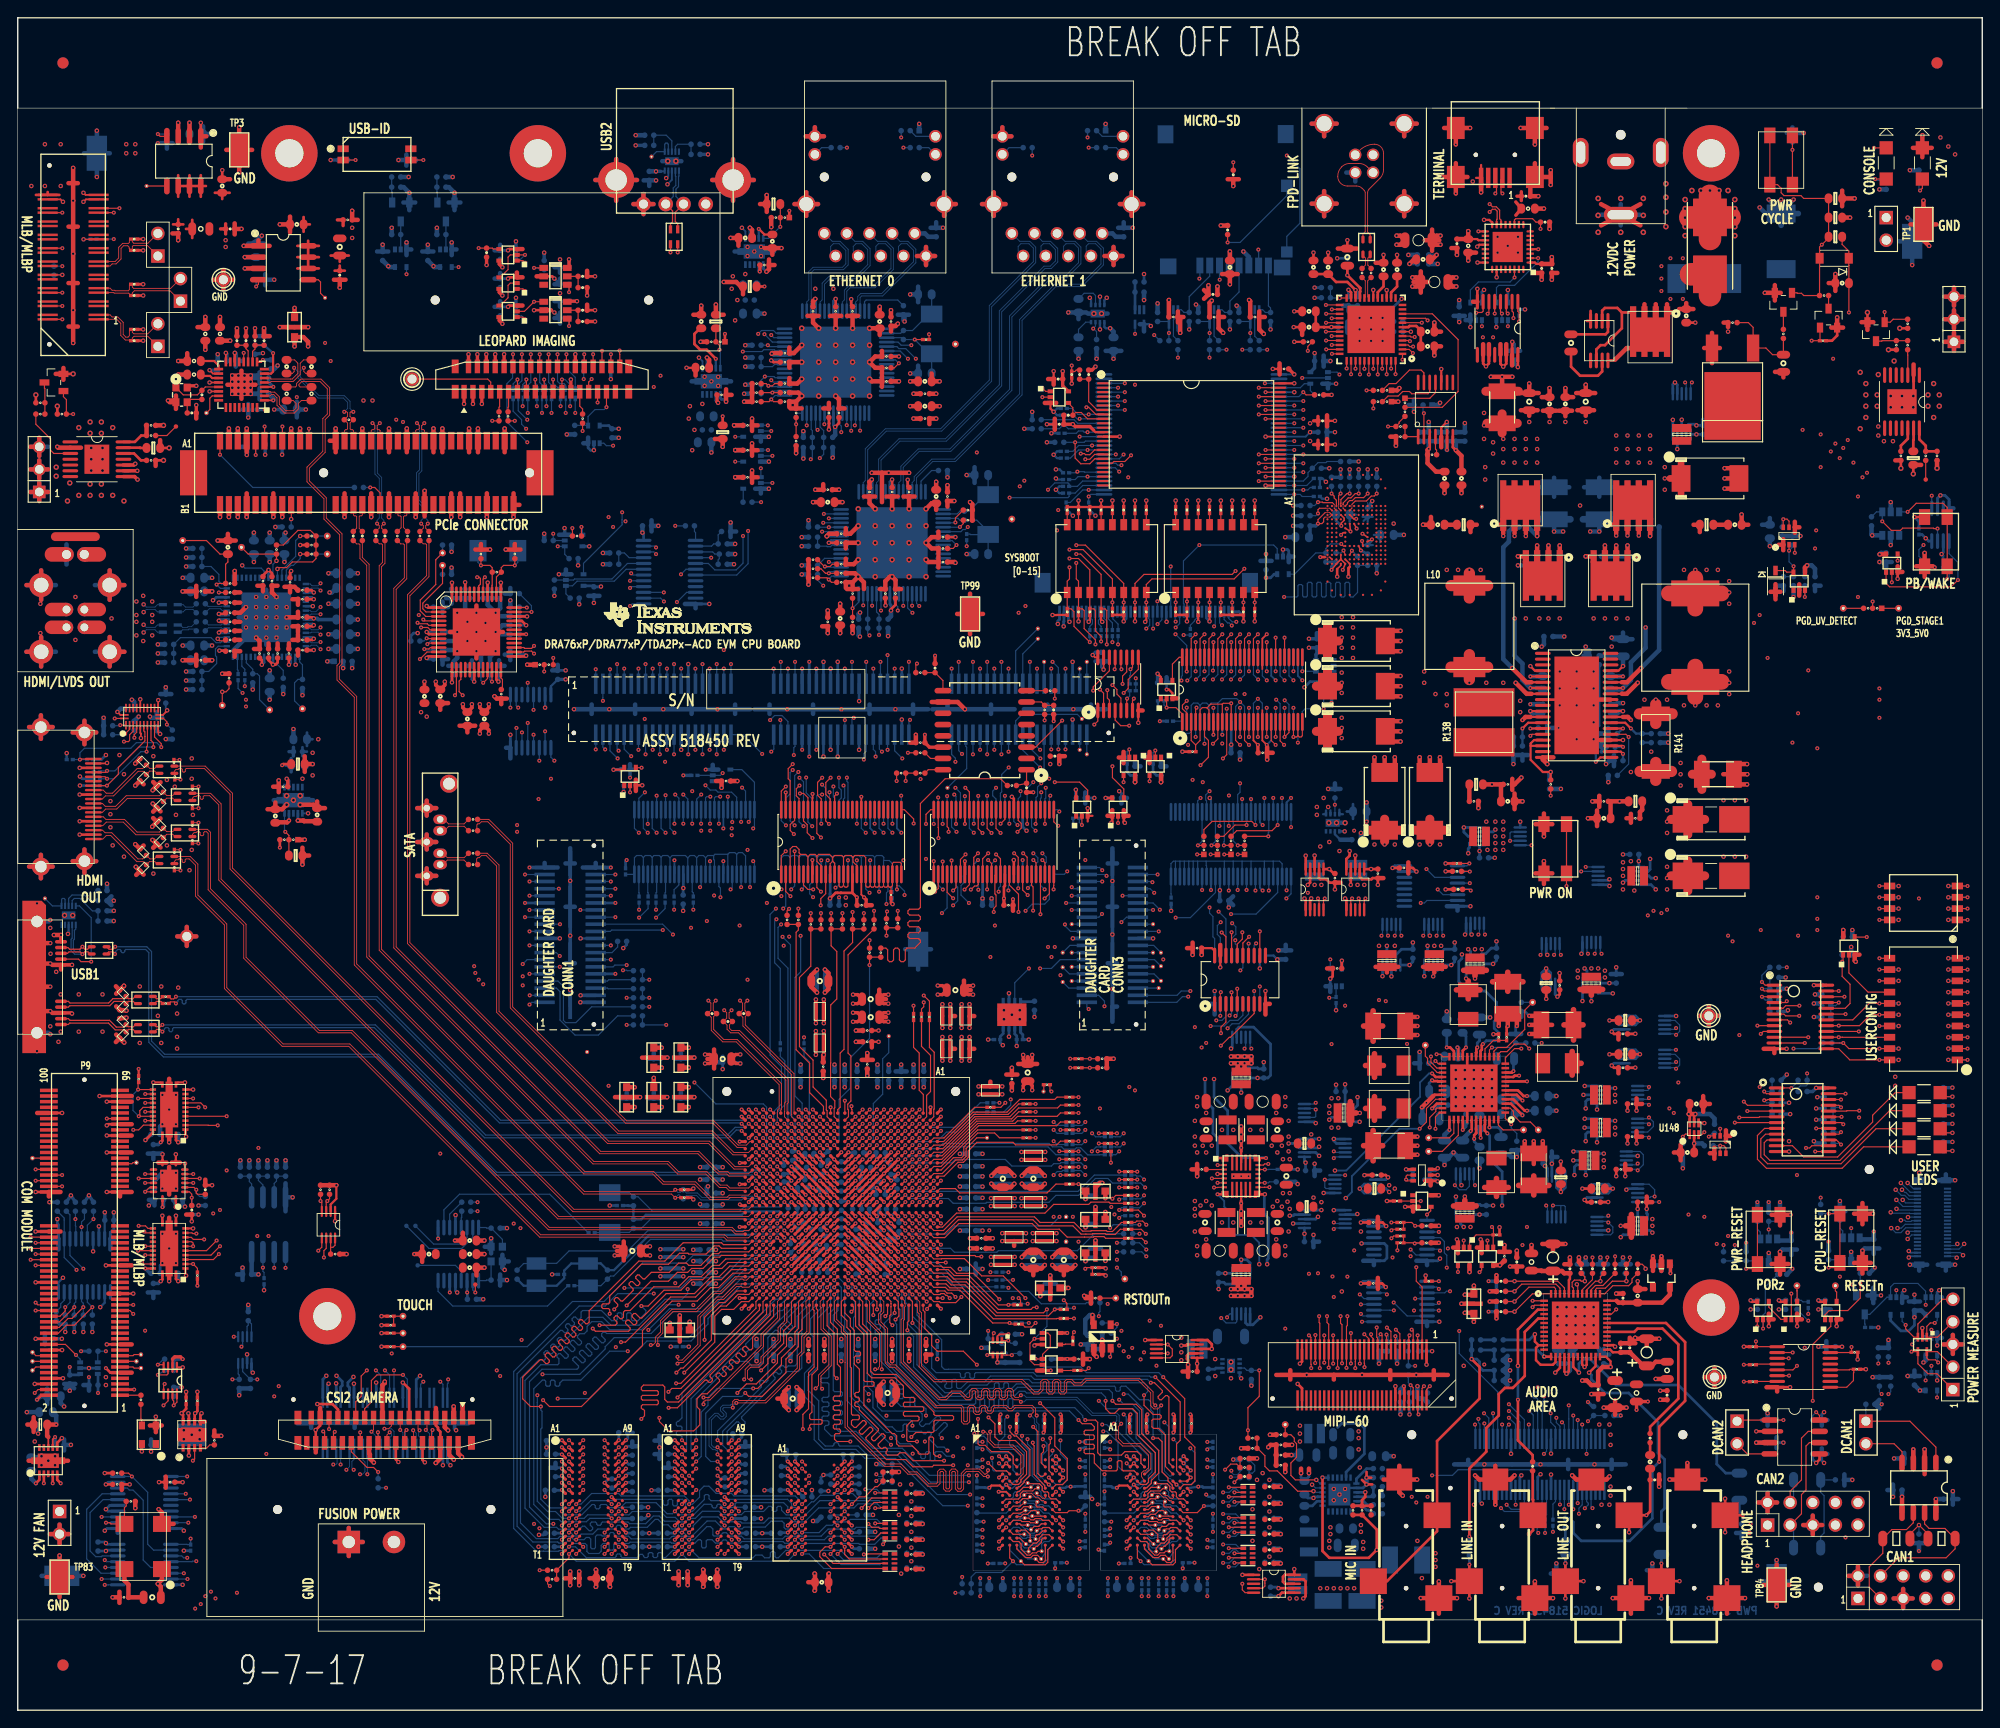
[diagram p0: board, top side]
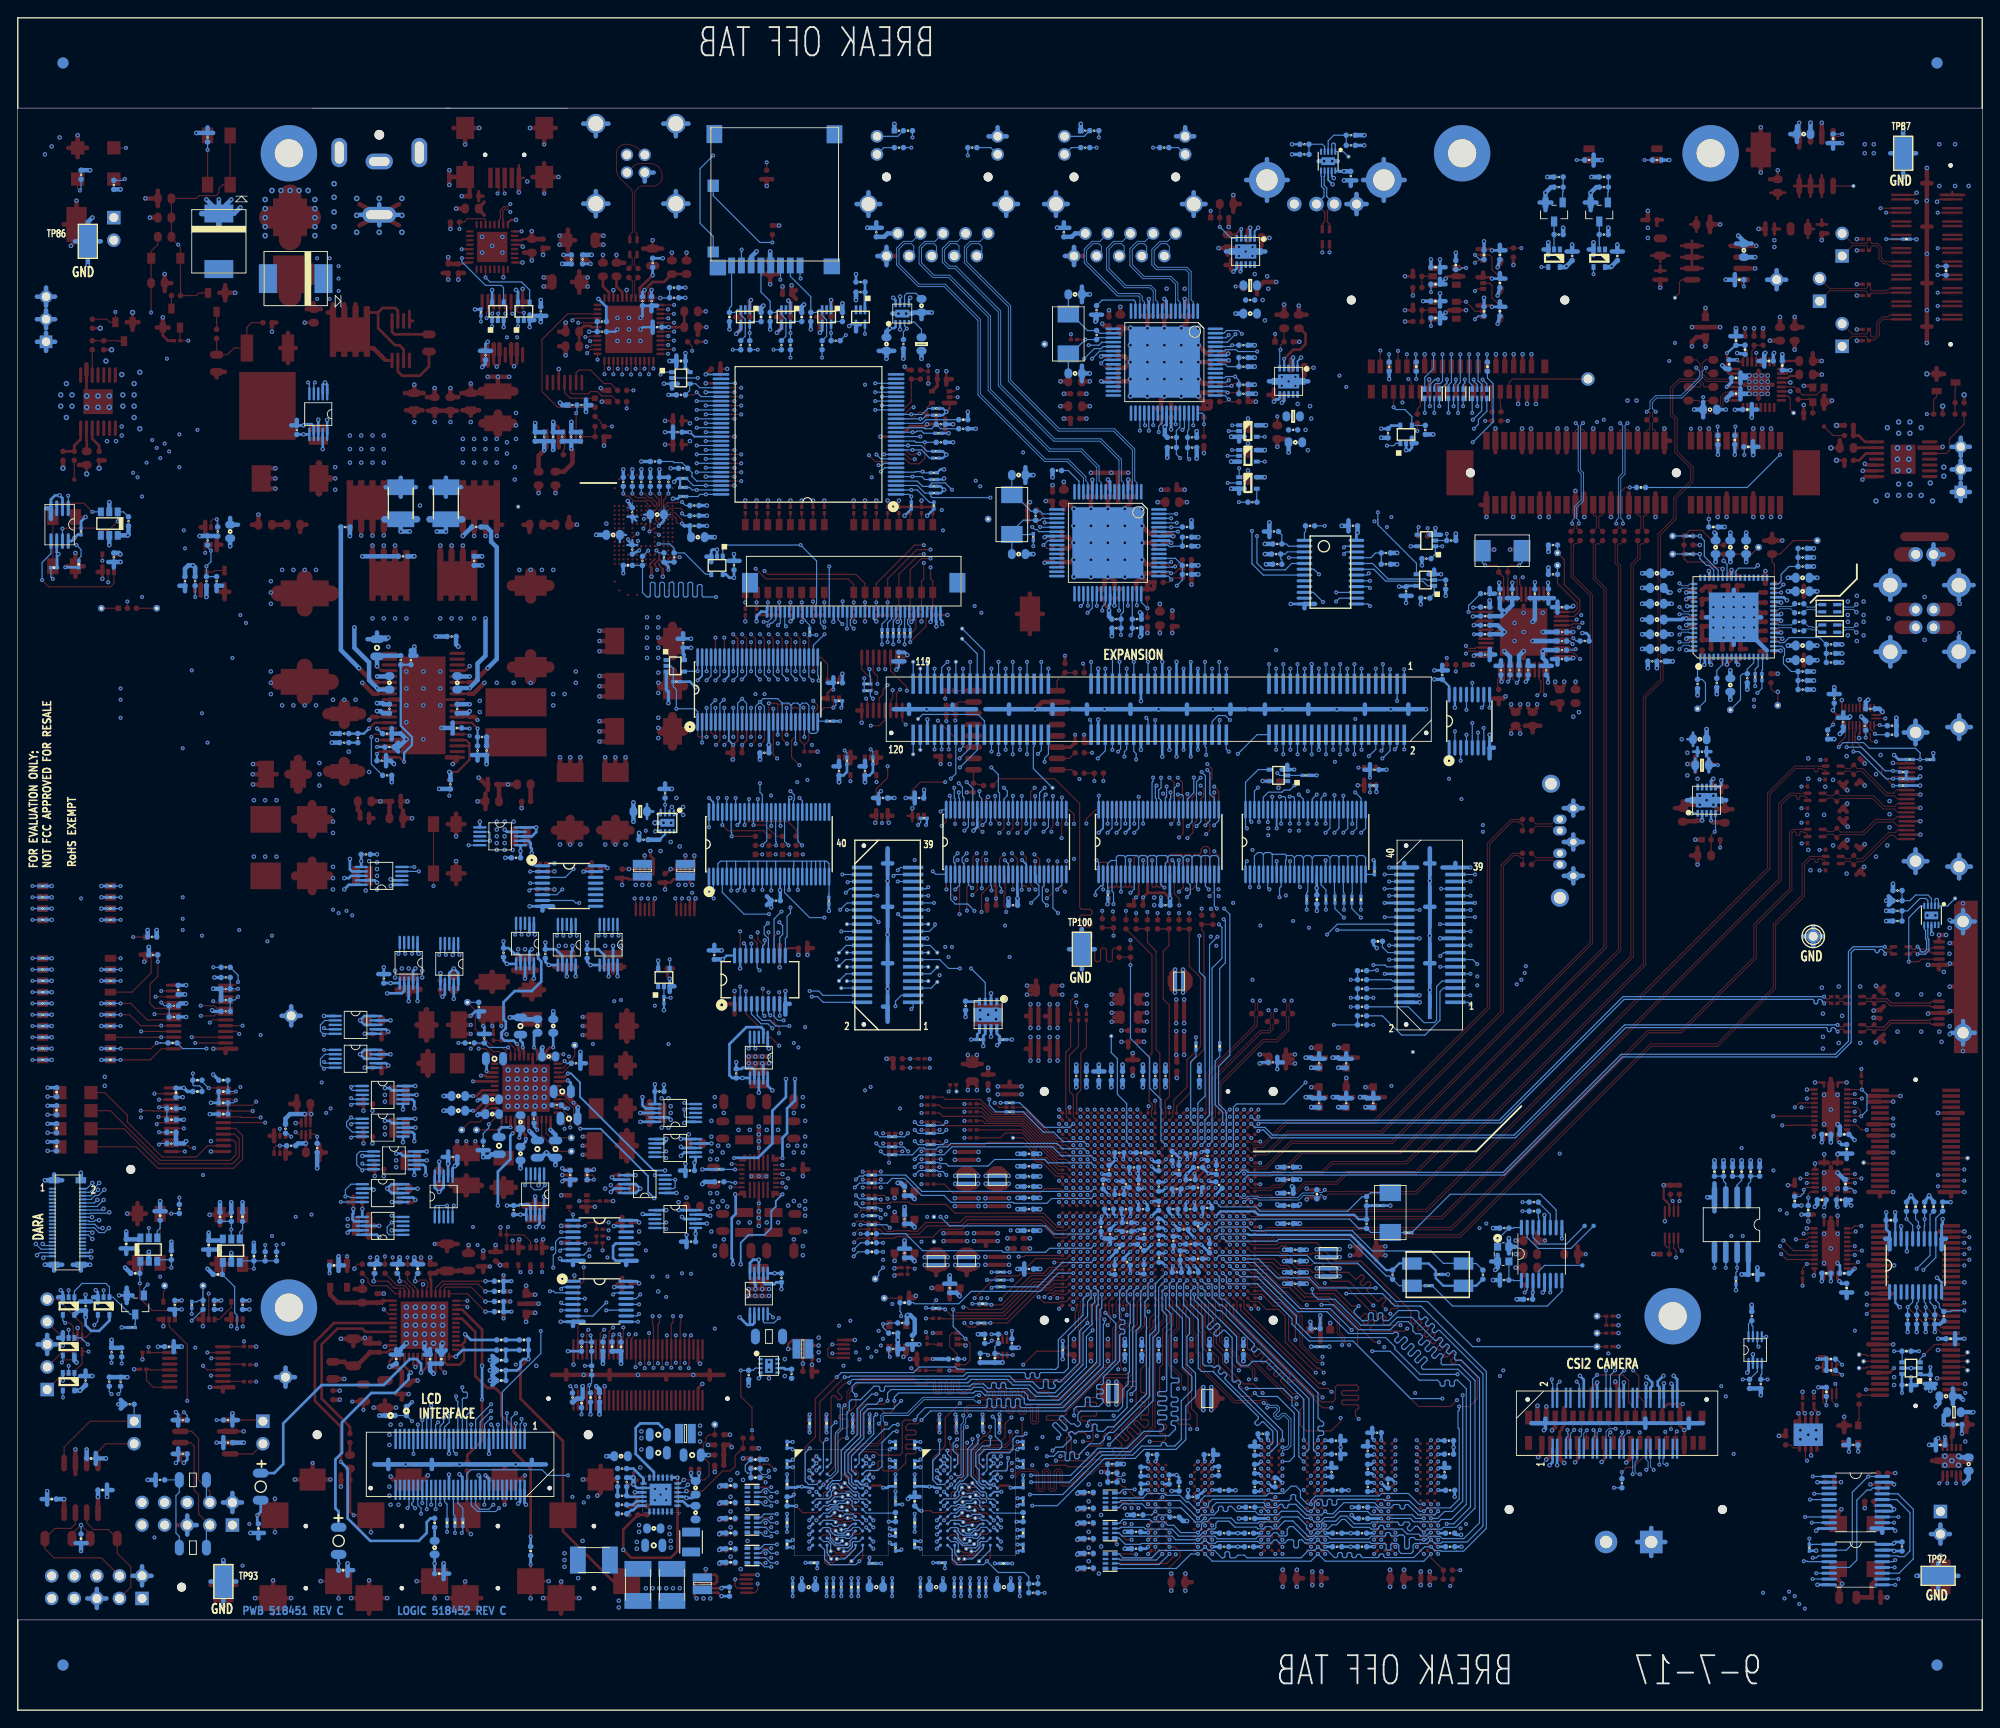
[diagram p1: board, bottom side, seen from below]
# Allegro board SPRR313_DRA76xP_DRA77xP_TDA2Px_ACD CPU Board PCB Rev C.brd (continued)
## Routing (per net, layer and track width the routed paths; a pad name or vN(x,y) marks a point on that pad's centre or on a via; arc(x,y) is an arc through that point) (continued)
VOUT3B_HSYNC: length 107.1
  TOP w0.132: U8.3 156.31,153.57 156.49,153.39 v1(156.87,153.39) ; v1(87.25,98.55) 86.84,98.96 86.84,99.63 87.16,99.95 87.2,99.95 87.34,100.09 RU7.53
  L3-SIGNAL w0.109: v1(156.87,153.39) 154.4,153.39 153.54,152.53 150.11,152.53 148.21,150.62 146.81,150.62 145.02,148.83 143.37,148.83 143.09,148.55 143.09,147.5 140.45,144.86 139.91,144.86 133.6,138.56 133.6,136.27 121.03,123.7 121.03,122.05 118.62,119.63 115.57,119.63 114.3,118.36 114.3,117.77 102.23,105.71 102.23,104.39 101.22,103.38 99.26,103.38 98.81,102.92 98.81,102.07 98.97,101.91 99.53,101.91 99.69,101.75 99.69,101.53 99.53,101.37 98.97,101.37 98.81,101.21 98.81,100.98 98.97,100.82 99.53,100.82 99.69,100.66 99.69,100.44 99.53,100.28 98.97,100.28 98.81,100.12 98.81,98.3 98.04,97.54 89.15,97.54 88.14,98.55 v1(87.25,98.55)
VOUT3B_INTB: length 87.4
  TOP w0.132: RU7.46 90.83,100.03 91.17,99.69 v1(91.19,99.69) ; U8.31 147.49,155.07 147.48,155.07 v1(147.07,155.07) ; v1(145.03,152.91) 145.03,153.42 R30.2
  L3-SIGNAL w0.109: v1(147.07,155.07) 145.03,153.03 v1(145.03,152.91) 144.15,152.02 140.97,152.02 137.54,148.59 137.54,146.43 127.76,136.65 127.76,135.76 118.87,126.87 116.71,126.87 108.58,118.74 108.58,116.84 108.33,116.59 106.17,116.59 102.62,113.03 102.62,112.52 98.68,108.58 98.68,107.31 91.82,100.46 91.82,100.32 v1(91.19,99.69)
VOUT3B_VSYNC: length 102.9
  TOP w0.132: v1(89.34,98.11) 88.75,98.7 88.75,99.61 88.33,100.03 RU7.51 ; v1(156.51,154) 156.44,154.07 U8.4
  L3-SIGNAL w0.109: v1(89.34,98.11) 89.68,97.77 97.52,97.77 97.79,98.04 97.79,99.95 98.3,100.46 98.3,100.69 98.14,100.85 97.44,100.85 97.28,101.01 97.28,101.24 97.44,101.4 98.14,101.4 98.3,101.56 98.3,102.87 99.55,104.12 99.99,104.12 100.33,104.47 100.33,104.87 111.29,115.82 111.76,115.82 112.78,116.84 112.78,117.48 115.31,120.02 118.04,120.02 119.89,121.86 119.89,123.32 132.08,135.51 132.08,137.61 140.26,145.8 140.72,145.8 142.49,147.57 142.49,148.97 143.2,149.68 143.69,149.68 143.9,149.46 145.14,149.46 146.69,151 148.08,151 150.24,153.16 153.42,153.16 154.26,154 v1(156.51,154)
VPHY_1V1: length 23.3
  TOP w0.305: C63.1 91.2,145.3 91.2,144.76 91.2,144.75 91.2,144.34 91.2,144.34 91.2,144.07 v2(91.19,144.06) ; C96.1 97.54,124.33 97.56,124.31 v2(97.56,124.27) ; C75.1 v2(98.3,138.43) ; 91.95,157.86 v2(91.95,158.75)
  TOP w0.508: C73.1 v2(92.33,137.29) ; C51.1 v2(100.33,149.48) ; C90.1 105.32,129.16 v2(105.41,129.07) ; v2(99.06,149.48) 98.17,149.48 ; C54.1 v2(100.71,148.08) ; 85.72,152.65 84.82,152.65 v2(84.77,152.6) ; C83.1 91.22,132.33 90.97,132.08 90.97,132.07 v2(90.95,132.05) ; C79.1 v2(92.71,135.89)
  BOTTOM w0.305: U108.8 98.05,138.18 v2(98.3,138.43) ; U108.42 97.55,124.32 97.56,124.31 v2(97.56,124.27) ; U108.29 v2(105.41,129.07) ; U101.29 98.84,149.39 98.93,149.48 v2(99.06,149.48) ; v2(84.77,152.6) 84.98,152.39 U101.58 ; U101.8 91.7,158.5 v2(91.95,158.75) ; v2(91.19,144.06) 91.19,144.77 91.2,144.77 U101.42 ; v2(90.95,132.05) 90.97,132.07 U108.58
  vias: v2(80.26,159.89) v2(80.39,161.29) v2(80.64,156.34) v2(80.9,158.62) v2(81.79,161.54)
VPHY_2V5: length 12.6
  TOP w0.305: v2(93.7,158.72) 93.7,158.02 93.85,157.86 ; v2(100.05,138.4) 100.05,137.7 C76.1
  TOP w0.508: 89.41,157.86 89.41,158.5 v2(89.66,158.75) ; 104.52,137.03 v2(104.52,137.79) ; C30.1 v2(96.9,157.86) ; v2(96.01,138.43) 95.76,138.18 C74.1 ; C31.1 v2(98.17,157.48) ; C77.1 v2(103.25,138.18)
  BOTTOM w0.305: U101.12 v2(93.7,158.72) ; v2(96.01,138.43) 96.05,138.39 U108.4 ; U101.4 89.7,158.71 v2(89.66,158.75) ; U108.12 v2(100.05,138.4)
  vias: v2(75.44,145.29) v2(75.56,146.69) v2(75.82,141.73) v2(76.07,144.02) v2(76.96,146.94)
VPIN_B01_3V3: length 1.7
  BOTTOM w0.305: U78.9 143.52,55.75 143.4,55.63 v2(143,55.63)
  vias: v2(132.33,57.28) v2(132.33,56.39) v2(132.33,55.63) v2(132.97,56.77) v2(133.6,57.28) v2(134.24,56.77) v2(141.1,56.64) v2(141.6,57.28) v2(142.11,56.64) v2(142.75,57.2) v2(143,56.39)
VPIN_B23_3V3: length 1.8
  BOTTOM w0.305: v2(142.88,63.75) 143.4,63.75 143.4,63.75 U77.9
  vias: v2(132.33,64.52) v2(132.33,63.5) v2(132.59,62.74) v2(133.22,63.49) v2(133.6,62.74) v2(134.24,63.5) v2(140.97,63.5) v2(141.6,62.74) v2(142.11,63.5) v2(142.88,64.52) v2(142.88,62.87)
VPIN_LDO_3V3: length 8.2
  TOP w0.254: U38.22 161.95,74.45 v1(161.85,74.55)
  TOP w0.305: v2(173.47,61.71) 173.48,61.71 R537.1 ; U38.3 167.87,68.23 v1(169.16,66.93)
  BOTTOM w0.305: U72.9 v2(173.47,61.71)
  BOTTOM w0.508: C385.2 161.93,74.48 v1(161.85,74.55) ; C412.2 169.04,67.06 v1(169.16,66.93)
VPIN_LDO_5V0: length 8.2
  TOP w0.305: v2(178.95,73.78) 178.96,73.79 R194.1 ; U38.5 168.53,69.23 v1(169.17,68.59) ; v1(169.67,70.74) 169.66,70.73 U38.8
  BOTTOM w0.305: C407.2 169.05,68.71 v1(169.17,68.59) ; U91.9 v2(178.95,73.78)
VPIN_S3_3V3: length 5.1
  TOP w0.305: v1(168.15,71.88) 167.99,71.73 U38.10 ; v2(178.95,77.59) 178.96,77.6 R548.1
  BOTTOM w0.305: C390.2 168.15,73.2 v1(168.15,71.88) ; U75.9 v2(178.95,77.59)
VPIN_S4_3V3: length 5.3
  TOP w0.305: v1(164.08,74.55) 163.98,74.45 163.98,74.04 163.96,73.98 163.95,73.97 U38.18 ; R533.1 171.83,80.03 v2(171.84,80.02)
  BOTTOM w0.305: v1(164.08,74.55) 164.08,75.06 164.34,75.31 C375.2 ; U74.9 v2(171.84,80.02)
VPIN_S5_3V3: length 5.8
  TOP w0.305: R575.1 175.91,58.67 v2(175.9,58.67) ; U38.46 v1(165.45,65.56)
  BOTTOM w0.305: U73.9 v2(175.9,58.67) ; C420.2 166.75,65.26 166.45,65.56 v1(165.45,65.56)
VPIN_S12_3V3: length 8.5
  TOP w0.305: U38.32 159.27,69.23 159.13,69.09 ; U38.29 159.67,70.73 159.63,70.76 159.11,70.76 v1(159,70.87)
  TOP w0.508: v1(157.86,67.82) v1(158.37,68.33) 159.13,69.09
  BOTTOM w0.305: C402.2 158.67,70.54 v1(159,70.87) ; U76.9 153.79,58.68 v2(154.18,58.29)
  BOTTOM w0.508: C409.2 157.91,67.77 v1(157.86,67.82)
  vias: v2(154.18,59.05) v2(154.81,58.67)
VPO_DDR_VTT: length 9.8
  BOTTOM w0.305: 148.39,31.8 148.84,32.26 150.88,32.26 151.38,31.75 151.38,28.83 149.34,26.78 U138.11
VPOC2_12V0: length 7.7
  TOP w0.508: v2(155.02,165.86) 155.45,165.86 C7.1 155.45,164.85 v2(155.02,164.85) ; L4.1 156.97,163.19 v2(156.46,162.69)
  L14-SIGNAL w0.508: 151.49,174.96 P1.2 ; P1.2 153.24,174.96 ; P1.2 152.37,175.84 ; P1.2 152.37,174.08
  BOTTOM w0.305: 157.35,162.69 v2(156.46,162.69)
VPP: length 35.4
  TOP w0.305: U42.G14 v1(98.99,57.16)
  TOP w0.508: v2(120.82,44.45) 120.82,43.5 U37.5
  L10-SIGNAL w0.406: v1(98.99,57.16) 98.99,56.72 99.31,56.39
  L10-SIGNAL w0.508: v2(120.82,44.45) 119,46.27 119,47.75 117.22,49.53 117.22,51.18 115.32,53.09 115.32,54.28 114.22,55.37 105.66,55.37 104.65,56.39 99.31,56.39
  BOTTOM w0.508: C405.1 120.02,42.42 120.02,43.94 120.52,44.45 v2(120.82,44.45) 120.9,44.37 R552.2
VPP_EN: length 133.2
  TOP w0.132: v1(122.81,39.75) 122.87,39.81 U37.3 ; RU11.4 v1(207.87,86.97)
  L3-SIGNAL w0.109: v1(200.9,40.78) 203.2,43.09 203.2,48.64 204.22,49.66 204.22,60.71 207.87,64.36 v1(207.87,86.97)
  L7-SIGNAL w0.089: v1(200.9,40.78) 198.77,40.78 197.99,40.01 172.72,40.01 171.45,41.27 137.29,41.27 134.24,38.23 125.6,38.23 124.08,39.75 v1(122.81,39.75)
  BOTTOM w0.132: v1(122.81,39.75) 122.94,39.88 R550.2
VSW_3V3_APM: length 116.9
  TOP w0.305: v2(149.73,96.65) 149.73,96.12 149.37,95.75 U87.10 ; U81.8 v2(145.8,96.14) ; U81.10 v2(144.8,96.12) ; U87.8 v2(150.37,96.14)
  L7-SIGNAL w0.127: v2(211.33,54.23) 214.63,54.23 217.17,56.77 217.17,62.36 216.03,63.5 216.03,77.6 212.85,80.77 205.99,80.77 201.8,84.96 193.04,84.96 191.01,87 171.07,87 164.27,93.79 156.4,93.79 156.08,94.11 145.67,94.11 144.8,94.98 v2(144.8,96.12)
  BOTTOM w0.132: v2(211.33,54.23) 211.76,54.23 212.2,54.66 J18.22
  vias: v2(146.43,97.16) v2(147.45,97.66) v2(148.59,96.65)
VSYS_3V3: length 183
  TOP w0.132: v1(140.59,61.45) 140.17,61.45 140.05,61.32 U40.20
  TOP w0.305: C248.2 v2(180.97,67.44) ; v2(156.08,60.83) 156.87,60.83 Q16.4 ; R533.2 v2(171.83,83.44) ; R537.2 v2(173.48,58.29) ; C249.2 v2(180.97,63.75) ; v2(173.34,82.92) 173.35,82.9 C242.2 ; C229.2 v2(152.15,94.61) U87.6 ; U46.5 194.97,45.95 v2(194.82,46.1) ; C245.2 181.83,72.26 v2(181.85,72.28) ; v2(197.99,46.1) 198.15,45.95 U47.5 ; v2(151.4,60.18) 151.41,60.2 C240.2 ; U80.1 v2(137.68,15.22) ; C237.2 v2(132.59,38.99) U79.6 ; R548.2 v2(182.37,77.6) ; U79.1 v2(126.75,41.64) ; U48.5 202.59,45.95 v2(202.44,46.1) ; v2(181.85,76.09) 181.83,76.07 C241.2 ; v2(145.41,91.31) 145.3,91.19 145.3,90.04 ; v2(178.8,57.17) 178.79,57.15 C243.2 ; C250.2 v2(179.71,60.07) ; 144.8,90.04 144.8,91.17 v2(144.65,91.31) ; C246.2 v2(182.12,56.39) ; U38.42 163.45,65.27 v1(163.33,65.15) ; C235.2 147.96,94.11 v2(147.45,94.61) U81.6 ; U80.6 142.13,13.22 v2(141.73,12.83) ; U38.37 v1(160.95,65.28) ; R575.2 v2(179.32,58.67)
  TOP w0.508: R284.2 v2(137.54,29.46) ; P6.A10 v2(31.73,144.17) ; P6.B8 v2(29.73,134.21) ; C45.1 77.72,151.9 v2(77.48,152.15) ; v2(82.3,166.75) 82.55,166.5 C6.1 ; v2(31.49,100.08) 32.12,100.08 32.19,100 33.66,100 C118.1 ; v2(201.17,128.78) 200.93,128.54 U147.4 ; P6.A9 v2(30.73,144.17) ; U16.5 v2(209.32,130.02)
  BOTTOM w0.203: U93.1 81.8,166.35 v2(81.41,166.75) ; U102.1 76.98,151.75 v2(76.58,152.15) ; v2(32.64,100.89) U117.1
  BOTTOM w0.254: 147.08,101.22 U119.1 146.76,100.79 ; U119.2 147.58,101.22
  BOTTOM w0.305: v2(162.71,87.25) 162.83,87.37 U82.1 ; U76.8 151.38,59.18 v2(150.88,58.67) 151.37,58.18 U76.10 ; U77.10 145.77,64.25 145.78,64.26 v2(146.3,64.26) ; v2(202.44,46.1) 203.2,46.1 ; U73.2 180.97,58.67 v2(180.85,58.55) ; v2(164.85,159.77) 164.61,159.53 U143.5 ; U142.5 v2(167.53,159.75) ; U88.9 165.85,98.8 v2(166.12,99.06) ; U69.6 v2(177.55,67.56) ; C251.2 161.54,84.2 v2(161.16,83.82) U66.6 ; v2(178.94,93.47) 178.82,93.35 U89.2 ; U74.10 171.34,82.95 v2(171.83,83.44) 172.34,82.93 U74.8 ; v2(146.56,56.26) 146.04,56.26 146.02,56.25 U78.10 ; U76.6 v2(151.4,60.18) ; C228.2 v2(164.34,96.65) U88.6 ; U72.10 173.97,58.79 v2(173.48,58.29) 172.97,58.8 U72.8 ; C603.1 145.03,23.88 v2(145.67,23.88) 145.79,24 146.14,24 146.15,24.01 U138.3 ; U75.1 v2(186.44,78.09) ; 195.58,46.1 v2(194.82,46.1) ; C247.2 v2(164.34,55.75) U70.6 ; R707.2 156.21,60.71 v2(156.08,60.83) ; U86.6 v2(135.76,49.15) C230.2 ; U85.6 v2(139.38,71.12) C231.2 140.54,71.12 140.84,71.42 140.84,74.93 138.94,76.83 137.28,76.83 137.04,76.59 U85.2 ; v2(158.75,87.12) 158.63,87.24 U66.2 ; U113.8 214.82,131.51 v2(214.5,131.83) 214.08,132.25 C320.1 ; U78.1 v2(147.96,56.25) ; v2(213.23,44.2) 213.23,43.31 212.6,42.67 211.71,42.67 210.55,43.83 U130.5 ; C238.2 v2(144.65,53.59) U78.6 ; U102.2 v2(77.48,152.15) ; U71.6 v2(182.12,56.39) ; U65.6 v2(156.46,83.82) 156.84,84.2 C252.2 ; U75.10 181.88,78.09 v2(182.37,77.6) 181.86,77.09 U75.8 ; C239.2 v2(144.78,61.59) 144.65,61.72 U77.6 ; U73.8 178.82,58.17 v2(179.32,58.67) 178.83,59.17 U73.10 ; U72.6 171.97,60.94 v2(171.7,61.21) ; R625.1 v2(209.17,43.05) ; 198.75,46.1 v2(197.99,46.1) ; U77.2 148.26,63.75 147.96,64.05 v2(147.96,64.26) 148.08,64.26 148.1,64.25 U77.1 ; C233.2 v2(178.94,81.79) U83.6 ; U67.6 v2(176.28,60.2) ; U90.6 v2(188.72,143.51) C226.2 ; v2(146.3,63.37) 146.18,63.25 U77.8 ; C236.2 v2(141.73,12.83) ; v2(149.22,70.41) U84.6 ; R444.1 216.45,129.88 v2(216.28,130.05) 216.48,130.25 U113.6 ; U93.2 v2(82.3,166.75) ; U76.1 v2(146.81,58.18) ; v2(162.31,59.05) 162.19,59.17 U70.2 ; v2(146.18,55.5) 145.92,55.24 U78.8 ; U91.6 v2(181.85,72.28) ; U82.6 v2(165.86,83.95) 166.24,84.33 C234.2 ; C227.2 v2(182.25,95.5) U89.6 ; U73.6 v2(178.8,57.17) ; U75.6 v2(181.85,76.09) ; U74.6 v2(173.34,82.92) ; U68.6 v2(177.55,63.88) ; U117.2 v2(31.49,100.08)
  BOTTOM w0.508: R636.2 R635.2 v2(210.31,41.66) ; U131.5 214.49,39.35 v2(214.25,39.12) ; 162.05,157.86 v2(162.05,158.62) ; U114.5 v2(210.57,131.06) ; R756.2 200.91,128.52 v2(201.17,128.78) 201.68,128.78 202.06,128.4 C713.2 ; C417.1 162.43,64.25 v1(163.33,65.15) ; C326.1 209.47,130.18 v2(209.32,130.02) ; R728.2 v2(178.82,104.39) ; 208.41,133.22 208.41,132.23 v2(208.48,132.16) U114.6 ; v2(208.53,37.47) R649.1 R648.1 ; U126.6 207.25,52.96 C488.1 v1(208.66,53.85) ; v1(160.95,65.28) 160.4,64.72 C418.1 ; v1(199.39,53.72) C490.1 197.98,52.83 U127.6 ; v2(213.23,44.2) C525.1 214.01,44.96 U129.5 ; R609.2 v1(199.52,49.66) ; v2(171.7,61.21) 171.45,61.47 C244.2 ; R601.1 v1(194.31,52.58) ; U133.5 v2(213.85,35.97) 213.84,35.97 C547.1 ; R600.1 v1(203.58,52.7) ; 208.15,49.15 v1(208.79,49.78)
  vias: v2(142.24,61.98) v2(143,61.98) v2(145.41,64.77) v2(145.67,57.66) v2(146.05,101.6) v2(146.05,100.71) v2(146.56,57.15) v2(146.81,102.62) v2(147.32,101.6) v2(147.45,19.05) v2(147.45,18.29) v2(147.57,20.57) v2(147.57,19.81) v2(165.1,99.95) v2(165.23,96.77) v2(166.12,99.95) v2(166.12,98.3) v2(166.12,97.54) v2(166.12,96.77) v2(167,99.95) v2(167,99.06) v2(167,98.3) v2(167,97.54) v2(167,96.77)
VSYS_3V3_APM: length 34.2
  TOP w0.254: v2(170.05,112.38) U18.11
  TOP w0.508: R154.2 v2(164.21,101.47)
  TOP w1.016: 153.67,97.74 C126.1 ; C126.1 155.35,98.98 ; C126.1 153.67,100.23 ; C126.1 151.99,98.98 ; C119.1 148.49,110.11 ; C119.1 147.24,108.43 ; C119.1 146,110.11 ; C119.1 147.24,111.79 ; C127.1 158.75,100.23 ; C127.1 157.07,98.98 ; C127.1 158.75,97.74 ; C127.1 160.43,98.98 ; 146,115.19 C117.1 ; C117.1 147.24,116.87 ; C117.1 148.49,115.19 ; 147.24,118.59 C109.1 ; C109.1 148.49,120.27 ; C109.1 147.24,121.95
  BOTTOM w0.305: U88.10 v2(162.58,99.3) 162.58,98.78 163.06,98.3 U88.8
  BOTTOM w0.508: C339.2 170.29,112.14 v2(170.05,112.38)
  vias: v2(148.84,122.94) v2(148.84,121.79) v2(148.84,120.65) v2(148.84,119.51) v2(148.84,118.36) v2(148.84,116.71) v2(148.84,115.57) v2(148.84,114.43) v2(148.84,111.63) v2(148.84,110.49) v2(148.84,109.35) v2(150.11,122.94) v2(150.11,121.79) v2(150.11,120.65) v2(150.11,119.51) v2(150.11,118.36) v2(152.53,97.38) v2(153.67,97.38) v2(154.81,97.38) v2(157.61,97.38) v2(158.75,97.38) v2(159.89,97.38)
VSYS_5V0: length 69.8
  TOP w0.203: U19.10 15.78,110.04 v2(16,109.81)
  TOP w0.254: v1(83.3,166.62) 83.32,166.62 83.95,165.99 C8.1
  TOP w0.305: R194.2 v2(182.37,73.79) ; C403.2 v2(188.47,63.75) U148.2 ; v1(78.48,152.01) 77.45,153.03 76.71,153.03 76.07,153.67 76.07,154.81 76.71,155.45 C29.1 ; U56.4 v1(3.93,25.53) ; v1(2.03,25.53) 2.43,25.92 U56.1 ; U56.2 v1(2.93,25.53) ; U56.5 4.43,25.92 v1(4.83,25.53) ; RU8.17 110.98,92.74 110.87,92.63 v1(110.87,91.31) ; R99.1 v2(31.75,131.06)
  TOP w0.381: U6.6 61.84,158.5 v2(62.87,158.5) ; v2(61.98,163.19) 61.98,162.44 U5.6 ; C138.1 v1(110.87,91.31) ; v2(52.17,146.94) J8.5 ; v2(51.67,152.53) J8.4
  TOP w0.508: U1.2 v2(19.3,178.56) ; C124.1 28.96,99.87 30.28,99.87 v1(30.49,100.08) ; v1(213.11,29.34) U58.3 ; U2.3 v2(25.53,162.18) ; U1.3 v2(18.03,178.56) ; U2.2 v2(25.53,163.45) ; U57.3 v2(195.45,30.1)
  BOTTOM w0.254: U117.4 v1(30.49,100.08) ; U134.4 137.36,37.52 v2(137.54,37.34) ; U102.4 v1(78.48,152.01) ; U93.4 v1(83.3,166.62)
  BOTTOM w0.305: U89.9 180.73,93.35 v2(180.47,93.09) ; RU15.17 108.48,91.98 108.46,91.96 v2(108.46,91.31) ; EXP_P2.65 v2(94.58,113.51) ; v2(6.99,105.03) 7.24,104.78 R491.2 R487.2 ; EXP_P2.66 v2(94.58,108.03) ; U91.10 181.88,74.28 v2(182.37,73.79) 181.86,73.28 U91.8 ; R483.1 9.4,106.93 v2(9.91,107.44)
  BOTTOM w0.381: C262.1 v2(61.98,163.19) ; C272.1 v2(62.87,158.5)
  BOTTOM w0.508: C342.1 15.62,110.19 v2(16,109.81) ; C255.1 v2(25.53,163.45) ; v2(188.47,63.75) 189.36,63.75 R754.2 ; C254.1 v2(19.3,178.56) ; R342.1 v2(119.25,152.02) ; v1(213.11,29.34) C576.1 ; C362.1 v2(108.46,91.31) ; v2(195.45,30.1) 196.72,30.1 ; C579.1 1.52,26.04 v1(2.03,25.53) ; v2(151.64,102.11) R500.1 v2(151.64,99.95)
  vias: v2(38.86,147.32) v2(39.88,147.32) v2(177.8,32.13) v2(178.94,32.13) v2(179.07,30.99) v2(179.07,29.84) v2(180.47,95.38) v2(180.47,94.61) v2(180.47,93.85) v2(180.47,92.33) v2(181.36,95.5) v2(181.74,92.2) v2(216.15,176.91) v2(217.04,175.9) v2(217.81,175.01)
VSYS_5V0_APM: length 41
  TOP w0.254: v2(180.47,112.38) U18.28
  TOP w0.508: 180.86,100.33 R159.2 ; R159.2 181.36,99.83 ; R159.2 181.36,100.83
  TOP w1.016: 188.26,105.28 C125.1 ; C125.1 189.33,103.58 ; C125.1 189.33,106.99 ; C125.1 190.4,105.28 ; 185.86,93.85 C136.1 ; C136.1 189.65,93.85 ; C136.1 187.76,92.18 ; C136.1 187.76,95.53 ; 187.76,98.53 C131.1 ; C131.1 185.86,100.2 ; C131.1 189.65,100.2 ; C131.1 187.76,101.88
  TOP w1.27: 184.15,104.6 R141.1 ; R141.1 185.92,105.6 ; R141.1 182.38,105.6 ; R141.1 184.15,106.6
  L5-SIGNAL w0.508: v2(180.47,112.38) 180.74,112.65 181.99,112.65 183.64,111 v2(183.64,107.82)
  BOTTOM w0.305: v2(184.15,93.6) 183.63,93.6 183.38,93.85 U89.8 ; v2(184.15,92.33) 183.63,92.85 U89.10
  BOTTOM w0.508: C338.2 179.83,112.14 180.07,112.38 v2(180.47,112.38)
  vias: v2(181.36,105.54) v2(185.42,101.22) v2(185.42,99.95) v2(185.42,98.68) v2(185.42,94.87) v2(185.42,93.6) v2(185.42,92.33) v2(186.94,106.55) v2(186.94,105.28) v2(186.94,104.01)
VSYS_12V0: length 114.3
  TOP w0.305: P5.40 4.67,170.45 ; P5.40 2.04,170.45 ; P5.40 3.36,170.77
  TOP w0.381: R16.1 v2(64.01,159.13)
  TOP w0.406: U13.10 13.07,140.07 v2(13.21,140.21) ; U13.9 v2(13.43,139.42) ; U13.8 13.13,138.77 v2(13.46,138.43)
  TOP w0.508: C58.1 177.22,146.23 ; C58.1 175.34,146.23 ; C58.1 176.28,145.6 ; 173.24,146.18 C60.1 ; C60.1 174.74,146.18 ; C60.1 173.99,145.55 ; P6.B3 v2(24.73,134.21) ; 169.93,145.6 C57.1 ; C57.1 168.99,146.23 ; C57.1 170.87,146.23 ; 172.21,145.55 C59.1 ; C59.1 172.96,146.18 ; C59.1 171.46,146.18 ; P6.A3 v2(24.73,144.17) ; P6.A2 v2(23.73,144.17) ; P6.B1 v2(22.73,134.21) ; P6.B2 v2(23.73,134.21)
  TOP w0.762: C72.1 186.99,140.23 ; C72.1 185.75,138.56 ; C72.1 186.99,136.88
  TOP w1.016: C62.1 166.88,145.82 ; C62.1 166.88,143.69 ; C62.1 165.18,144.75 ; C62.1 168.58,144.75
  L5-SIGNAL w0.508: v2(175.64,135.51) 175.64,121.92 177.93,119.63 v2(179.2,119.63) 179.2,109.98 173.48,104.27 v2(173.48,103.63)
  L7-SIGNAL w0.508: J1.1 4.7,23.29 ; J1.1 4.7,21.41 ; J1.1 3.76,22.35 ; J1.1 5.64,22.35 ; J16.2 42.29,20.37 ; J16.2 40.84,18.92 ; J16.2 42.29,17.47 ; J16.2 43.74,18.92
  BOTTOM w0.305: EXP_P2.53 v1(89.78,117.17) ; P15.1 48.29,27.91 v2(48.64,27.56) ; EXP_P2.52 v1(88.98,107.27) ; EXP_P2.50 v1(88.18,108.03) ; EXP_P2.54 v1(89.78,108.03) ; EXP_P2.49 v1(88.18,117.17) ; P15.3 v2(47.79,27.56) ; EXP_P2.51 v1(88.98,117.93) ; U90.9 v2(186.57,141.86)
  BOTTOM w0.508: C301.2 174.42,137.57 ; C301.2 172.72,136.5 ; C301.2 172.72,138.63 ; C301.2 171.02,137.57 ; R297.2 v2(212.72,173.23) ; C300.2 177.8,138.63 ; C300.2 176.1,137.57 ; C300.2 179.5,137.57 ; C300.2 177.8,136.5 ; R743.2 R742.2 v2(200.41,132.08) ; C711.1 v2(196.98,130.94) ; R492.2 v2(173.48,103.63)
  vias: v2(1.52,171.45) v2(3.05,176.15) v2(3.05,171.45) v2(4.83,176.15) v2(4.83,171.45) v2(12.19,176.15) v2(12.19,175.13) v2(13.21,176.15) v2(13.21,175.13) v2(164.85,145.92) v2(164.85,144.53) v2(164.85,143) v2(164.97,139.83) v2(164.97,138.43) v2(165.86,142.62) v2(165.86,141.35) v2(167,143) v2(167,141.86) v2(167,140.34) v2(168.28,143) v2(168.28,141.86) v2(168.28,140.34) v2(169.54,143) v2(169.54,141.86) v2(169.54,140.34) v2(169.93,144.91) v2(170.81,143) v2(170.81,141.86) v2(170.81,140.34) v2(172.21,144.91) v2(173.99,144.91) v2(176.28,144.91) v2(179.71,143.38) v2(179.71,141.86) v2(179.71,140.34) v2(180.97,143.38) v2(180.97,141.86) v2(180.97,140.34) v2(182.25,143.38) v2(182.25,141.86) v2(182.25,140.34) v2(183.51,143.38) v2(183.51,141.86) v2(183.51,140.34) v2(185.17,139.83) v2(185.17,138.56) v2(185.17,137.29) v2(209.17,144.4) v2(209.17,143.38) v2(209.8,142.75) v2(210.82,142.75)
VSYS_12V0_APM: length 4.8
  TOP w0.508: 198.5,149.92 C40.2 197.56,150.55
  BOTTOM w0.305: U90.8 v2(187.07,145.16) ; U90.10 v2(186.07,145.15)
VTT:
  vias: v2(99.06,21.97) v2(99.06,18.41) v2(99.19,25.4) v2(99.31,15.37) v2(100.46,25.4) v2(100.46,23.5) v2(100.46,21.84) v2(100.46,20.07) v2(100.46,18.29) v2(100.46,16.76) v2(138.81,22.61) v2(138.81,19.05) v2(139.32,25.91) v2(139.57,15.88) v2(139.95,26.67) v2(140.72,25.91) v2(140.72,24) v2(140.72,22.35) v2(140.72,20.57) v2(140.72,18.8) v2(140.72,17.27) v2(144.15,32) v2(144.15,31.11) v2(144.15,30.23)
WL_EN: length 28.7
  TOP w0.132: P9.4 2.29,36.07 v1(1.91,35.69) ; v1(13.53,51.69) U43.19
  L12-SIGNAL w0.089: v1(13.53,51.69) 11.23,51.69 10.41,50.88 5.03,50.88 3.68,49.53 3.68,37.47 v1(1.91,35.69)
WLAN_IRQ: length 30.8
  TOP w0.132: v1(2.01,45.85) 2.26,45.59 P9.34 ; v1(14.33,66.31) U39.21
  L14-SIGNAL w0.109: v1(2.01,45.85) 5.08,45.85 9.14,49.91 9.14,52.32 11.68,54.86 11.68,65.28 12.7,66.29 13.91,66.29 13.93,66.31 v1(14.33,66.31)
XI_OSC0: length 20.8
  BOTTOM w0.132: R234.2 64.13,53.72 59.81,58.04 49.66,58.04 47.9,56.29 U125.10
XI_OSC1: length 17.5
  BOTTOM w0.132: U125.8 47.25,47.11 48.9,45.47 59.56,45.47 61.84,47.75 R247.2
XI_PHY0: length 137.1
  TOP w0.132: R24.2 v1(102.45,154.77)
  L3-SIGNAL w0.109: v1(51.69,56.13) 49.4,58.42 49.4,86.36 49.78,86.74 49.78,109.22 58.67,118.11 58.67,118.92 63.54,123.79 63.54,127.8 64.77,129.03 64.77,133.6 74.04,142.88 74.04,150.62 76.45,153.03 77.85,153.03 78.87,154.05 99.19,154.05 99.91,154.77 v1(102.45,154.77)
  BOTTOM w0.132: R584.2 v1(51.69,56.13)
XI_PHY1: length 132
  L3-SIGNAL w0.109: v1(51.69,57.15) 51.69,80.39 50.42,81.66 50.42,83 50.4,83.02 50.4,85.45 51.05,86.11 51.05,109.98 66.42,125.35 v1(66.42,134.21)
  L14-SIGNAL w0.109: v1(66.42,134.21) 78.77,134.21 81.41,131.57 82.68,131.57 84.07,132.97 90.52,132.97 91.02,133.47 93.59,133.47 94.17,134.05 107.13,134.05 107.44,133.73 107.44,132.59 106.68,131.83 v1(106.68,130.94)
  BOTTOM w0.132: R581.2 v1(51.69,57.15) ; R91.2 v1(106.68,130.94)
XIN_PDIV1_25MHZ: length 1.9
  BOTTOM w0.132: U125.13 49.86,55.37 49.91,55.42 49.91,56.13
XIN_PDIV2_25MHZ: length 3.4
  BOTTOM w0.132: 49.91,57.15 48.55,55.79 U125.11
ZQ_DBYTE1: length 3.9
  BOTTOM w0.132: U136.H8 125.48,22.17 122.45,22.17 R694.1
ZQ_DBYTE2: length 4.2
  TOP w0.132: v1(133.35,22.97) 132.61,22.23 131.01,22.23 U62.H8
  BOTTOM w0.254: R705.1 133.82,22.99 133.8,22.97 v1(133.35,22.97)
ZQ_DBYTE3: length 3.9
  BOTTOM w0.132: R695.1 108.1,22.17 111.12,22.17 U137.H8
ZQ_DBYTE4: length 4.2
  TOP w0.132: v1(119.25,22.43) 118.19,22.43 117.98,22.23 116.66,22.23 U61.H8
  BOTTOM w0.305: R704.1 119.46,22.43 v1(119.25,22.43)
ZQ_DBYTE4_1: length 2.1
  TOP w0.127: U63.H8 v1(92.97,22.38)
  BOTTOM w0.132: v1(92.97,22.38) 93.36,21.97 R693.1
N16769336: length 24
  TOP w0.254: U18.4 170.56,116.93 v2(170.05,117.44)
  L5-SIGNAL w0.508: TP9.1 164.59,132.08 165.73,130.94 169.16,130.94 170.31,129.79 170.31,121.54 170.05,121.28 v2(170.05,117.44)
N16769346: length 2.7
  TOP w0.508: Q7.4 v2(170.81,132.08)
  BOTTOM w0.508: R402.1 v2(170.81,132.08)
N16769518: length 8.3
  TOP w1.27: L10.2 163.19,118.73 ; L10.2 165.25,117.34 ; L10.2 161.14,117.34 ; L10.2 163.19,115.94
  BOTTOM w0.508: v1(170.05,113.16) C339.1
  vias: v2(158.12,116.84) v2(158.12,115.57) v2(159.38,114.3) v2(160.66,114.3) v2(160.66,113.03) v2(163.19,115.57) v2(165.1,115.57) v2(167,115.57) v2(168.91,113.54) v2(168.91,112.27)
N16769802: length 1.9
  TOP w0.508: R154.1 R148.2
N16769806: length 2.8
  TOP w0.254: v1(170.05,116.28) U18.5
  BOTTOM w0.508: C334.2 171.4,116.28 v1(170.05,116.28)
N16769822: length 1.4
  TOP w0.508: R87.1 C80.2
N16769842: length 1.8
  TOP w0.508: Q9.4 v2(168.66,129.79)
  BOTTOM w0.508: Q9.4 v2(168.66,129.79)
N16769938: length 16.5
  TOP w0.254: U18.12 170.05,111.73
  TOP w0.508: 166.75,104.14 v2(165.74,104.14) R148.1 ; 166.75,104.14 R149.2 ; 166.75,104.14 C128.2 ; v1(169.16,111.38) 169.51,111.73 170.05,111.73
  L5-SIGNAL w0.508: v2(165.74,104.14) 167.26,105.66 168.4,105.66 169.04,106.3 169.04,108.97 168.4,109.6 168.4,110.62 v1(169.16,111.38)
N16769982: length 1.2
  BOTTOM w0.508: v2(171.32,119.63) 171.58,119.89 R441.1
N16770060: length 5.4
  TOP w0.254: U18.35 179.96,116.93 v2(180.47,117.44)
  BOTTOM w0.508: v2(180.47,117.44) C325.2 180.39,118.62 R445.2
N16770156: length 14.8
  TOP w0.254: v1(177.42,106.68) 177.43,106.68 177.93,107.18 U18.20
  BOTTOM w0.254: v1(177.42,106.68) 177.42,107.7 176.53,108.58 176.53,109.47 177.8,110.74 R445.1 R446.2
N16770184: length 4.5
  TOP w0.254: U18.13 169.81,111.08 v1(169.16,110.43)
  BOTTOM w0.254: C350.2 C348.2 v1(169.16,110.43)
N16770362: length 2.3
  TOP w0.508: Q8.4 v2(183.51,132.08)
  BOTTOM w0.508: R401.1 v2(183.51,132.08)
N16770396: length 2.3
  TOP w0.254: v1(180.47,108.35) 180.34,108.48 U18.22
  BOTTOM w0.254: R479.2 179.6,108.35 v1(180.47,108.35)
N16770460: length 2.3
  TOP w0.254: v1(170.05,110.43) U18.14
  BOTTOM w0.254: C343.1 170.88,110.43 v1(170.05,110.43)
N16770544: length 16.6
  TOP w1.27: 182.31,112.08 R141.2 ; R141.2 184.15,113.16 ; R141.2 185.99,112.08 ; R141.2 184.15,111
  TOP w1.778: 188.59,113.96 L11.2 ; L11.2 185.64,115.67 ; L11.2 188.59,117.39 ; L11.2 191.55,115.67
  BOTTOM w0.508: v2(180.47,113.28) 179.83,113.28 179.71,113.16 C338.1
  vias: v2(182.88,113.67) v2(184.15,113.67) v2(185.42,113.67) v2(187.32,113.03) v2(188.59,113.03) v2(189.87,113.03) v2(191.13,113.03) v2(192.41,116.84) v2(192.41,115.57) v2(192.41,114.3)
N16770796: length 2
  TOP w0.508: R156.2 182.63,101.28 182.37,101.03 R159.1
N16770800: length 2.8
  TOP w0.254: U18.34 v1(180.47,116.28)
  BOTTOM w0.508: C333.2 179.12,116.28 v1(180.47,116.28)
N16770818: length 1.7
  TOP w0.508: R88.1 C81.2
N16770854: length 1.7
  TOP w0.508: Q10.4 v2(176.28,129.79)
  BOTTOM w0.508: R414.1 v2(176.28,129.79)
N16771006: length 17.1
  TOP w0.254: U18.27 180.47,111.73
  TOP w0.508: R156.1 v2(180.09,102.23) 179.07,102.23 ; 179.07,102.23 C129.2 ; 179.07,102.23 R155.2 ; v1(181.36,111.38) 181.01,111.73 180.47,111.73
  L5-SIGNAL w0.508: v2(180.09,102.23) 180.09,103.12 182.37,105.41 182.37,110.36 v1(181.36,111.38)
N16771022: length 2.3
  TOP w0.254: v1(180.47,110.43) U18.25
  BOTTOM w0.254: C345.1 v1(180.47,110.43)
N16771108: length 2.3
  TOP w0.254: v1(180.47,107.58) 180.21,107.83 U18.21
  BOTTOM w0.254: C352.1 v1(180.47,107.58)
N16771210: length 5.1
  TOP w0.254: v1(181.36,110.43) 180.71,111.08 U18.26
  BOTTOM w0.254: C344.2 181.93,109.86 v1(181.36,110.43)
N16772449: length 11.8
  TOP w0.305: 180.34,157.23 180.34,155.45 178.44,153.54 177.94,153.54 177.47,153.07 U9.6 ; 180.34,157.23 179.83,157.73 178.43,157.73 178.13,157.43 U9.2 ; 180.34,157.23 Q2.4
N16772477: length 5.5
  TOP w0.305: C47.1 178.51,154.76 178.78,155.03 U9.1
N16772485: length 7.1
  TOP w0.305: U9.7 178.13,150.58 177.66,150.11 175.64,150.11 174.62,151.13 C47.2
N16772555: length 14.4
  TOP w0.305: 176.82,157.39 U9.4 176.42,156.28
  TOP w0.508: 184.15,156.3 Q2.2 184.15,158.15 ; Q2.1 185.42,158.15 ; Q2.1 185.42,156.3 ; Q2.1 186,157.23 ; 182.88,158.15 Q2.3 182.88,156.3 ; 186.78,157.61 C37.1 ; C37.1 187.58,158.28 ; C37.1 188.38,157.61
  TOP w2.54: 190.25,159.17 F1.1 188.11,161.52
  vias: v1(184.78,162.43) v1(184.78,161.04) v1(184.78,159.64) v1(185.8,163.32) v1(185.8,158.75) v1(187.2,163.32) v1(187.2,158.75)
N16772931: length 2.7
  TOP w0.132: DS1.2 214.12,171.2 v1(213.87,170.94)
  BOTTOM w0.132: v1(213.87,170.94) 213.74,171.07 R297.1
N16773123: length 20.1
  TOP w0.132: 199.52,171.6 v1(199.52,175.51) 199.52,177.14
  L3-SIGNAL w0.109: v1(199.52,175.51) 202.44,175.51 J7.1
  BOTTOM w0.132: R350.1 v1(199.52,175.51)
N16789072: length 6.2
  TOP w0.203: 3.43,30.73 U56.8
  TOP w0.508: v1(4.32,32.13) R274.2 3.3,30.86 3.43,30.73
  BOTTOM w0.381: R274.2 v1(4.32,32.13)
  BOTTOM w0.508: R662.1 4.32,33.15 v1(4.32,32.13)
N16789078: length 2.2
  TOP w0.203: U56.7 3.93,30.46 v1(4.19,30.73)
  BOTTOM w0.381: C564.1 v1(4.19,30.73)
N16791668: length 6.9
  BOTTOM w0.132: TP27.1 106.68,105.92 106.68,108.32 106.59,108.41 EXP_P2.86
N16791764: length 7.2
  BOTTOM w0.132: TP20.1 112.19,119.17 EXP_P2.99
N16791766: length 9.5
  BOTTOM w0.132: EXP_P2.100 112.19,111.3 112.9,112.01 119.13,112.01 TP28.1
N16791773: length 5.8
  BOTTOM w0.132: EXP_P2.101 112.99,118.83 TP21.1
N16791815: length 2.5
  BOTTOM w0.132: EXP_P2.107 TP23.1
N16791884: length 1.7
  BOTTOM w0.132: EXP_P2.117 TP25.1
N16791886: length 1.7
  BOTTOM w0.132: EXP_P2.118 TP29.1
N16791893: length 2.5
  BOTTOM w0.132: EXP_P2.119 TP24.1
N16791895: length 2.2
  BOTTOM w0.132: EXP_P2.120 TP30.1
N16793461: length 3
  BOTTOM w0.132: EXP_P3.5 118.16,81.23 TP52.1
N16793463: length 2.3
  BOTTOM w0.132: EXP_P3.6 TP53.1
N16793477: length 1.7
  BOTTOM w0.132: EXP_P3.7 TP50.1
N16793479: length 1.7
  BOTTOM w0.132: EXP_P3.8 TP51.1
N16793493: length 3
  BOTTOM w0.132: EXP_P3.9 118.22,82.83 117.49,83.56 TP48.1
N16793495: length 2.9
  BOTTOM w0.132: TP49.1 127.74,82.83 EXP_P3.10
N16793503: length 1.7
  BOTTOM w0.132: EXP_P3.11 TP46.1
N16793510: length 1.7
  BOTTOM w0.132: EXP_P3.12 TP47.1
N16793526: length 2.9
  BOTTOM w0.132: TP88.1 127.79,84.43 EXP_P3.14
N16793540: length 1.7
  BOTTOM w0.132: EXP_P3.15 TP44.1
N16793542: length 1.7
  BOTTOM w0.132: EXP_P3.16 TP45.1
N16793550: length 3.1
  BOTTOM w0.132: TP42.1 118.29,86.03 EXP_P3.17
N16793552: length 2.9
  BOTTOM w0.132: EXP_P3.18 127.71,86.03 TP43.1
N16793588: length 1.7
  BOTTOM w0.132: EXP_P3.23 TP40.1
N16793595: length 1.7
  BOTTOM w0.132: EXP_P3.24 TP41.1
N16805684: length 16.2
  TOP w0.132: J20.4 211.46,17.14 216.79,17.14 217.81,18.16 R290.1 216.66,20.45 214.88,20.45 214.38,20.95 U58.7
N16805728: length 4.9
  TOP w0.132: R290.2 214.76,19.81 v2(213.74,20.83) 212.72,19.81 R289.1
  BOTTOM w0.132: C624.1 v2(213.74,20.83)
N16805777: length 13.2
  TOP w0.132: J20.3 208.15,13.84 208.15,16.13 209.68,17.65 R289.2 210.69,20.32 212.34,20.32 213.11,21.08 U58.6
N16805799: length 2.4
  TOP w0.508: U58.8 v2(215.65,23.75)
  BOTTOM w0.508: R687.1 v2(215.65,23.75)
N16808389: length 2.4
  TOP w0.132: R273.1 13.84,32.77 13.94,32.67 Y2.3
N16808436: length 2
  TOP w0.132: P9.12 2.03,38.61 TP81.1
N16808440: length 2.4
  TOP w0.132: P9.11 12.95,38.61 13.08,38.48 TP80.1
N16808466: length 1.8
  TOP w0.132: P9.14 TP78.1
N16808470: length 1.8
  TOP w0.132: P9.13 TP79.1
N16808488: length 2.4
  TOP w0.132: P9.15 12.95,39.88 13.08,40.01 TP77.1
N16808492: length 2
  TOP w0.132: TP76.1 2.03,39.88 P9.16
N16808754: length 1.9
  TOP w0.132: TP64.1 12.95,61.59 12.83,61.47 P9.73
N16808763: length 1.8
  TOP w0.132: P9.76 TP63.1
N16808859: length 3.8
  TOP w0.132: U55.7 17.39,34.91 17.53,34.78 v1(17.53,34.29) 17.89,34.66 U55.8
  BOTTOM w0.132: v1(17.53,34.29) R650.2
N16817374: length 6.2
  TOP w0.132: U43.3 v1(19.71,50.19) 20.19,49.71 R244.2 ; U43.8 19.56,52.69 19.71,52.54 v1(19.71,52.19) U43.7
  L3-SIGNAL w0.109: v1(19.71,52.19) v1(19.71,50.19)
N16817668: length 9.9
  TOP w0.132: U39.18 14.09,67.81 13.72,67.44 13.72,66.93 v1(13.6,66.81) U39.20 ; U39.14 v1(13.53,69.81) 13.53,70.59 R193.1
  BOTTOM w0.132: v1(13.53,69.81) 12.95,69.24 12.95,67.46 v1(13.6,66.81)
N16817815: length 3.1
  TOP w0.132: 19.56,56.77 v1(19.56,57.66) 19.56,58.06 19.3,58.31 U41.2
  BOTTOM w0.132: 19.56,56.77 v1(19.56,57.66)
N16817915: length 3.3
  TOP w0.132: U41.14 14.81,58.81 v1(14.31,58.31) U41.15
  BOTTOM w0.132: R579.1 14.68,58.67 v1(14.31,58.31)
N16817953: length 4.4
  TOP w0.132: U41.3 19.8,58.81 v1(20.07,58.55) 20.07,58.17 20.2,58.04 21.08,58.04
  BOTTOM w0.132: 21.08,57.78 20.45,57.78 20.07,58.17 v1(20.07,58.55)
N16827008: length 3.9
  BOTTOM w0.132: TP4.1 71.81,175.31 U92.1 72.73,176.15 72.86,176.28 73.01,176.28 73.13,176.15 U92.2
N16827026: length 4.7
  BOTTOM w0.132: U92.3 73.53,176.53 72.9,177.16 R305.2 R306.1
N16827028: length 3.6
  BOTTOM w0.132: R311.1 R310.2 74.19,176.15 73.93,175.9 U92.4
N16827261: length 4.2
  BOTTOM w0.132: TP39.1 3.89,90.47 U120.1 4.93,90.49 4.93,91.21 5.03,91.31 5.21,91.31 5.32,91.2 U120.2
N16827295: length 5.7
  BOTTOM w0.132: U120.3 5.71,91.31 6.1,91.69 7.49,91.69 8.13,91.06 R521.2 R518.1
N16827297: length 5.3
  BOTTOM w0.132: R523.2 R522.1 8.38,89.92 6.99,91.31 6.35,91.31 6.11,91.08 U120.4
N16827351: length 2.3
  TOP w0.132: v1(45.59,174.37) SW1.3
  BOTTOM w0.132: R307.1 v1(45.59,174.37)
N16828309: length 16.9
  TOP w0.305: U1.7 19.3,172.66 ; U1.7 18.73,171.45 ; U1.7 19.3,170.24 ; U1.7 19.88,171.45 ; U1.8 20.57,172.66 ; U1.8 20,171.45 ; U1.8 20.57,170.24 ; U1.8 21.15,171.45 ; 22.16,170.69 C3.1 ; C3.1 23.81,170.69 ; C3.1 22.99,169.99 ; 17.46,167.13 R8.1 ; R8.1 18.61,167.13 ; R8.1 18.03,167.7 ; U1.6 18.03,172.66 ; U1.6 18.61,171.45 ; U1.6 18.03,170.24 ; 19.61,165.61 L3.2 ; L3.2 18.91,166.62 ; L3.2 19.61,167.64
N16828490: length 16.9
  TOP w0.305: L1.2 37.21,163.63 ; L1.2 35.18,163.63 ; L1.2 36.2,162.93 ; 32.64,164.72 33.85,164.72 ; 32.64,164.72 31.43,164.72 ; 32.64,164.72 32.64,165.29 ; 32.64,164.72 32.64,164.15 ; C2.1 32.13,167.96 ; C2.1 32.83,167.13 ; C2.1 32.13,166.31 ; 32.64,162.18 32.64,162.75 ; 32.64,162.18 33.85,162.18 ; 32.64,162.18 31.43,162.18 ; 31.43,163.45 32.64,163.45 ; 32.64,163.45 32.64,162.88 ; 32.64,163.45 32.64,164.02 ; 32.64,163.45 33.85,163.45 ; R1.1 36.2,162.5 ; R1.1 35.62,161.93 ; R1.1 36.77,161.93
N16830127: length 6.9
  TOP w0.305: P11.3 v2(161.16,14.52) ; P11.3 v1(163.19,16.38) ; P11.3 v2(163.19,12.57)
  BOTTOM w0.305: C639.1 v1(163.19,16.38)
N16830174: length 7.3
  TOP w0.305: v2(169.91,19.81) 169.93,19.81 170.36,20.24 P11.2 170.36,23.66 170.31,23.71 C206.1
N16830302: length 37.9
  TOP w0.305: v2(163.45,39.5) 164.34,38.61 164.34,35.05 159.56,30.28 P10.2 159.56,20.14 153.94,14.52 P10.3
  BOTTOM w0.305: C548.1 R645.1 164.72,38.23 164.34,38.61 164.34,39.19 164.03,39.5 v2(163.45,39.5) R633.1 C530.1
N16830387: length 29.3
  TOP w0.279: v2(175.51,37.97) 174.88,38.6 U50.18
  BOTTOM w0.305: v2(175.51,37.97) 175.51,38.99 176.02,39.5 176.78,39.5 179.71,36.58 186.69,36.58 191.01,32.26 191.01,27.69 192.02,26.67 C594.1
N16830391: length 8.6
  TOP w0.305: v2(191.95,20.02) P13.2 ; P13.2 v1(193.93,21.93) ; P13.2 v2(191.95,23.8)
  BOTTOM w0.305: C594.2 193.55,22.31 v1(193.93,21.93) 193.93,21.08 R697.1
N16830429: length 19.4
  TOP w0.305: C206.2 170.31,28.7 168.66,30.35 v1(168.66,34.92) ; U50.3 170.89,45.06 168.66,42.82 v2(168.66,38.73)
  BOTTOM w0.305: v1(168.66,34.92) v2(168.66,38.73)
N16830431: length 24.7
  TOP w0.279: v2(176.66,37.97) 177.38,38.7 U50.23
  BOTTOM w0.305: v2(176.66,37.97) 176.91,37.72 176.91,37.21 178.44,35.69 181.1,35.69 184.4,32.38 184.4,28.96 185.14,28.22 185.14,22.71 184.78,22.35 C638.1
N16830435: length 7.7
  TOP w0.305: v2(186.82,14.52) P13.3 ; P13.3 v1(184.78,16.51) ; P13.3 v2(184.78,12.57)
  BOTTOM w0.305: R700.1 v1(184.78,16.51) C638.2
N16830493: length 1.5
  BOTTOM w0.305: C530.2 R628.1
N16830497: length 30
  TOP w0.305: v1(163.19,19.56) 163.19,27.18 165.1,29.08 165.1,31.75 166.5,33.15 166.5,35.56 167.2,36.26 168.08,36.26 169.42,37.59 169.42,42.55 170.93,44.06 U50.5
  BOTTOM w0.305: C639.2 v1(163.19,19.56)
N16830507: length 2.7
  BOTTOM w0.305: C544.1 R632.1 R633.2
N16830573: length 10.8
  TOP w0.279: 170.98,41.06 170.56,41.47 v2(170.56,42.29) ; 170.98,41.06 170.69,40.77 170.69,39.37 171.2,38.86 172.59,38.86 172.88,39.15 U50.14 ; 170.98,41.06 U50.11
  BOTTOM w0.305: 167,41.66 169.93,41.66 v2(170.56,42.29)
N16830575: length 5.7
  TOP w0.305: U50.13 v2(171.6,39.78)
  BOTTOM w0.305: v2(171.6,39.78) 170.87,40.51 167,40.51
N16830603: length 20.3
  TOP w0.305: R275.1 183.51,31.88 186.69,35.05 186.69,41.15 184.91,42.93 182.11,42.93 181.74,42.56 U50.29
N16830629: length 1.4
  TOP w0.305: C203.1 R275.2
N16830631: length 9.3
  TOP w0.305: v2(181.15,20.02) P12.2 v1(183.1,21.93) 183.51,22.35 R279.1 C203.2
N16830653: length 43.6
  TOP w0.305: U50.31 185.3,43.56 187.45,41.4 187.45,34.8 184.53,31.88 v1(184.53,27.94)
  BOTTOM w0.305: R696.1 174.45,21.59 174.88,21.16 174.88,19.94 175.77,19.05 181.23,19.05 183.77,21.59 183.77,27.18 v1(184.53,27.94)
N16830655: length 1.5
  BOTTOM w0.305: C635.1 R696.2
N16830657: length 8.1
  TOP w0.305: P12.3 v2(173.99,12.57) ; P12.3 v2(173.99,16.51) ; P12.3 v2(176.02,14.52)
  BOTTOM w0.305: C635.2 v2(173.99,16.51) R701.1
N16830743: length 8.6
  TOP w0.132: R246.1 v2(168.28,48.26) 173.13,48.26 173.88,47.51 U50.45
  BOTTOM w0.132: R246.1 v2(168.28,48.26)
N16830771: length 8.3
  TOP w0.132: R251.1 v2(168.28,47.12) 169.09,47.93 172.92,47.93 173.38,47.47 U50.46
  BOTTOM w0.132: R251.1 v2(168.28,47.12)
N16830784: length 8
  TOP w0.132: R254.1 v2(168.28,45.97) 169.89,47.59 172.72,47.59 172.88,47.42 U50.47
  BOTTOM w0.132: R254.1 v2(168.28,45.97)
N16830793: length 7
  TOP w0.132: R256.1 v2(168.28,44.83) 170.28,46.84 U50.48
  BOTTOM w0.132: R256.1 v2(168.28,44.83)
N16830868: length 5
  TOP w0.132: U50.43 174.88,47.5 174.75,47.63 174.75,48.13 175.01,48.39 175.64,48.39 175.77,48.26 v2(176.17,48.26) 176.17,48.74 R236.2
  BOTTOM w0.132: v2(176.17,48.26) 176.17,48.74 R606.1
N16830872: length 5.4
  TOP w0.132: U50.37 178.41,46.84 179.32,47.75 181.1,47.75 181.48,48.13 181.48,48.51 R241.2
N16832179: length 2.5
  TOP w0.132: U5.5 R13.2 R16.2
N16832191: length 39.7
  TOP w0.132: P6.A11 v1(32.73,144.15) ; v1(57.02,163.7) U4.2 55.37,163.7 55.12,163.45 55.12,162.05 54.24,161.18 RU1.4
  L3-SIGNAL w0.109: v1(57.02,163.7) 49.28,155.96 44.55,155.96 v1(32.73,144.15)
  BOTTOM w0.132: R317.1 56.52,163.19 v1(57.02,163.7)
N16832201: length 9.6
  TOP w0.132: U7.2 56.96,157.35 v1(58.04,158.43) U6.1 ; v1(58.04,162.24) U5.1
  L3-SIGNAL w0.109: v1(58.04,158.43) v1(58.04,162.24)
  BOTTOM w0.132: v1(58.04,162.24) 58.49,162.24 58.67,162.05 R319.1
N16832203: length 3.8
  TOP w0.132: RU1.2 55.37,160.53 55.12,160.27 55.12,158.88 54.24,158 U7.4
N16832211: length 1.9
  TOP w0.132: U5.4 61.98,160.34 v1(61.98,159.51)
  BOTTOM w0.132: v1(61.98,159.51) C264.1
N16832311: length 2.5
  TOP w0.132: R19.2 R18.2 U6.5
N16832327: length 1.9
  TOP w0.132: v1(61.98,155.7) 61.98,156.53 U6.4
  BOTTOM w0.132: v1(61.98,155.7) C276.1
N16832365: length 18.2
  TOP w0.132: v1(22.73,141.22) P6.A1
  BOTTOM w0.132: R381.1 26.42,137.54 v1(22.73,141.22)
N16832405: length 2.5
  TOP w0.132: P6.A5 26.75,142.8 v1(26.75,141.2)
  BOTTOM w0.132: R372.1 26.75,142.06 v1(26.75,141.2)
N16832557: length 2.7
  TOP w0.132: v1(27.75,144.4) 27.75,142.8 P6.A6
  BOTTOM w0.132: v1(27.75,144.4) 27.75,143.45 R370.2
N16832559: length 2.6
  TOP w0.132: v1(29.75,144.4) 29.75,142.8 P6.A8
  BOTTOM w0.132: v1(29.75,144.4) 29.75,143.41 R369.2
N16832585: length 2.5
  TOP w0.132: v2(30.73,133.99) 30.75,134 30.75,135.59 P6.B9
  BOTTOM w0.132: R404.1 v2(30.73,133.99)
N16832754: length 3.5
  TOP w0.132: P6.B17 40.73,136.94 40.13,137.54 v1(39.62,137.54)
  BOTTOM w0.132: R381.2 v1(39.62,137.54)
N16833554: length 3
  TOP w0.132: 24.64,153.54 25.65,153.54 25.65,153.15 25.9,152.91 U10.11
N16833556: length 3
  TOP w0.132: U10.10 26.4,152.85 26.67,153.12 26.67,153.54 27.69,153.54
N16833743: length 5.5
  TOP w0.254: v1(28.7,152.65) 28.7,150.57 28.48,150.35 U10.7
  BOTTOM w0.254: v1(28.7,152.65) 27.69,153.54 R349.2
N16833769: length 5.5
  TOP w0.132: Y1.1 18.61,147.96 20.19,147.96 C55.2 21.08,148.85 U10.21
N16833803: length 2.6
  TOP w0.254: U10.17 22.58,151.26 22.07,151.76 C41.1
N16833813: length 2.2
  TOP w0.254: U10.19 21.85,149.85 21.62,150.09 20.73,150.09 C48.1
N16833855: length 3
  TOP w0.132: R48.1 Y1.3 19.37,147.45 C55.1
N16833862: length 2.9
  TOP w0.132: U10.23 21.86,147.85 21.59,147.57 21.59,146.3 TP11.1
N16846683: length 3.5
  BOTTOM w0.132: U139.3 28.83,59.26 29.08,59.51 R679.1 R678.2
N16846685: length 3.6
  BOTTOM w0.132: R680.2 R681.1 27.05,59.59 27.56,59.08 27.56,57.7
N16846687: length 3.5
  BOTTOM w0.132: U139.1 26.29,59.21 26.04,59.46 R682.2 R683.1
N16846806: length 4
  TOP w0.132: U53.4 v1(108.99,39.95)
  BOTTOM w0.132: R630.1 111,40.89 R641.2 110.49,40.13 110.31,39.95 v1(108.99,39.95)
N16848026: length 1.3
  TOP w0.132: SW3.16 R70.2
N16848051: length 1.3
  TOP w0.132: SW3.15 R71.2
N16848076: length 1.3
  TOP w0.132: SW3.14 R72.2
N16848101: length 1.3
  TOP w0.132: SW3.13 R73.2
N16848126: length 1.3
  TOP w0.132: SW3.12 R74.2
N16848151: length 1.3
  TOP w0.132: SW3.11 R75.2
N16848176: length 1.3
  TOP w0.132: SW3.10 R76.2
N16848196: length 1.3
  TOP w0.132: SW3.9 R77.2
N16848352: length 1.3
  TOP w0.132: SW4.16 R78.2
N16848377: length 1.3
  TOP w0.132: SW4.15 R79.2
N16848402: length 1.3
  TOP w0.132: SW4.14 R80.2
N16848427: length 1.3
  TOP w0.132: SW4.13 R81.2
N16848452: length 1.3
  TOP w0.132: SW4.12 R82.2
N16848477: length 1.3
  TOP w0.132: SW4.11 R83.2
N16848502: length 1.3
  TOP w0.132: SW4.10 R84.2
N16848522: length 1.3
  TOP w0.132: SW4.9 R85.2
N16848818: length 1.9
  TOP w0.132: SW6.1 v1(219.2,73.15)
  BOTTOM w0.132: R495.2 v1(219.2,73.15)
N16848841: length 1.9
  TOP w0.132: SW6.2 v1(219.2,74.42)
  BOTTOM w0.132: R490.2 v1(219.2,74.42)
N16848864: length 1.9
  TOP w0.132: SW6.3 v1(219.2,75.69)
  BOTTOM w0.132: R485.2 v1(219.2,75.69)
N16848887: length 1.9
  TOP w0.132: SW6.4 v1(219.2,76.96)
  BOTTOM w0.132: R481.2 v1(219.2,76.96)
N16848910: length 1.9
  TOP w0.132: SW6.5 v1(219.2,78.23)
  BOTTOM w0.132: R477.2 v1(219.2,78.23)
N16848933: length 1.9
  TOP w0.132: SW6.6 v1(219.2,79.5)
  BOTTOM w0.132: R469.2 v1(219.2,79.5)
N16848956: length 1.9
  TOP w0.132: SW6.7 v1(219.2,80.77)
  BOTTOM w0.132: R464.2 v1(219.2,80.77)
N16848979: length 1.9
  TOP w0.132: SW6.8 v1(219.2,82.04)
  BOTTOM w0.132: R462.2 v1(219.2,82.04)
N16849002: length 1.9
  TOP w0.132: SW6.9 v1(219.2,83.31)
  BOTTOM w0.132: R459.2 v1(219.2,83.31)
N16849020: length 1.9
  TOP w0.132: SW6.10 v1(219.2,84.58)
  BOTTOM w0.132: R455.2 v1(219.2,84.58)
N16849958: length 5.5
  TOP w0.132: RU3.4 118.62,146.52 R52.1 118.92,145.97 119.56,145.97 120.27,145.26 U12.9
N16849973: length 5.6
  TOP w0.132: U12.7 121.33,146.26 120.4,147.19 R35.1 R34.2
N16852703: length 7.2
  BOTTOM w0.132: R362.2 118.75,145.16 119.15,144.76 U104.17
N16856648: length 1.4
  TOP w0.132: U15.M6 v1(149.99,130.43)
  BOTTOM w0.127: R418.2 v1(149.99,130.43)
N16856897: length 8.2
  TOP w0.132: v1(148.79,131.19) 149.03,130.96 U15.K5
  BOTTOM w0.132: U109.4 143.54,127.79 145.92,130.18 R416.1 147.07,130.68 147.57,131.19 v1(148.79,131.19)
N16868512: length 40.3
  L7-SIGNAL w0.089: v1(143.42,112.75) v1(142.42,112.75) v1(141.42,112.75) 140.4,113.77 v1(139.42,113.77) 137.77,113.77 v1(137.42,113.41)
  BOTTOM w0.132: 132.92,113.03 133.17,113.28 133.66,113.28 133.92,113.03 ; 132.92,113.03 RU13.24 ; 132.92,113.03 132.66,113.28 132.17,113.28 131.92,113.03 RU13.26 131.92,110.08 131.72,109.87 131.15,109.87 130.92,110.11 RU13.28 130.84,111.25 R465.2 ; v1(137.42,113.41) 137.92,112.91 RU13.14 ; v1(137.42,113.41) 136.92,112.91 RU13.16 ; v1(137.42,113.41) 137.04,113.79 135.43,113.79 134.92,113.28 ; RU13.7 v1(141.42,112.75) ; 134.92,113.28 RU13.20 ; 134.92,113.28 134.17,113.28 133.92,113.03 ; 133.92,113.03 RU13.22 ; RU13.10 139.92,113.27 v1(139.42,113.77) 138.92,113.27 RU13.12 ; RU13.5 v1(142.42,112.75) ; RU13.3 v1(143.42,112.75)
N16868523: length 38.6
  BOTTOM w0.132: 97.36,95.58 97.33,95.55 RU16.5 ; 97.36,95.58 97.36,95.94 97.16,96.14 96.54,96.14 96.33,95.94 ; 97.36,95.58 97.98,95.58 98.33,95.23 RU16.3 98.33,92.49 98.3,92.45 R520.2 ; 91.57,95.96 91.57,95.5 91.83,95.24 RU16.16 ; 91.57,95.96 91.74,96.14 92.65,96.14 92.83,95.96 ; 91.57,95.96 91.39,96.14 90.09,96.14 89.83,95.89 ; 92.83,95.96 RU16.14 ; 92.83,95.96 93.01,96.14 93.6,96.14 93.83,95.91 ; 89.83,95.89 RU16.20 ; 89.83,95.89 89.58,96.14 89.02,96.14 88.83,95.95 ; 87.83,95.94 88.04,96.14 88.65,96.14 88.83,95.95 ; 87.83,95.94 RU16.24 ; 87.83,95.94 87.63,96.14 87.06,96.14 86.83,95.92 ; 88.83,95.95 RU16.22 ; 94.83,95.91 95.06,96.14 96.13,96.14 96.33,95.94 ; 94.83,95.91 RU16.10 ; 94.83,95.91 94.6,96.14 94.06,96.14 93.83,95.91 ; RU16.26 86.83,95.92 ; 86.83,95.92 86.61,96.14 86.11,96.14 85.83,95.87 RU16.28 ; RU16.7 96.33,95.94 ; 93.83,95.91 RU16.12
N16869658: length 51.1
  TOP w0.132: RU7.18 94.33,95 93.9,95.43 93.9,95.94 ; 88.83,96.01 88.58,96.27 88.01,96.27 ; 88.83,96.01 89.09,96.27 89.64,96.27 89.84,96.06 ; 88.83,96.01 RU7.7 ; RU7.24 97.33,92.73 ; 97.33,92.73 97.19,92.58 96.98,92.58 96.83,92.73 ; 97.33,92.73 97.48,92.58 97.68,92.58 97.83,92.73 ; RU7.5 87.83,96.09 88.01,96.27 ; 93.9,95.94 93.7,96.14 93.04,96.14 92.83,95.94 ; 93.9,95.94 94.11,96.14 95.1,96.14 95.33,95.91 RU7.20 95.33,92.73 95.48,92.58 95.69,92.58 95.83,92.73 ; 95.83,92.73 95.98,92.58 96.19,92.58 96.33,92.73 ; 95.83,92.73 RU7.21 ; 88.01,96.27 87.83,96.44 87.83,96.82 87.5,97.16 87.12,97.16 86.83,96.87 RU7.3 ; 92.83,92.77 RU7.15 92.83,95.94 ; 92.83,92.77 93.02,92.58 93.21,92.58 93.33,92.71 RU7.16 ; 92.83,92.77 92.65,92.58 92.46,92.58 92.33,92.71 RU7.14 ; 97.83,92.73 RU7.25 ; 97.83,92.73 97.98,92.58 98.17,92.58 ; 98.17,92.58 R164.2 ; 98.17,92.58 98.33,92.74 RU7.26 98.33,95.24 98.46,95.38 99.19,95.38 99.33,95.24 RU7.28 ; 92.83,95.94 92.63,96.14 91.85,96.14 91.62,95.91 ; 89.84,96.06 89.84,95.48 90.33,94.99 RU7.10 ; 89.84,96.06 90.04,96.27 91.26,96.27 91.62,95.91 ; 91.62,95.5 91.33,95.22 RU7.12 ; 91.62,95.5 91.83,95.29 RU7.13 ; 91.62,95.5 91.62,95.91 ; 96.83,92.73 96.69,92.58 96.48,92.58 96.33,92.73 ; 96.83,92.73 RU7.23 ; 96.33,92.73 RU7.22
N16874153: length 3.3
  TOP w0.132: U17.4 129.81,117.68 130.57,118.44 RU5.56
N16874429: length 44.3
  TOP w0.132: v1(140.42,109.47) RU5.20 ; 143.92,109.63 143.76,109.47 v1(143.42,109.47) RU5.26 ; 143.92,109.63 RU5.27 ; 143.92,109.63 144.07,109.47 144.27,109.47 144.42,109.62 RU5.28 ; v1(138.42,109.47) RU5.16 ; 132.42,108.58 132.42,108.58 R143.2 ; 132.42,108.58 131.92,109.09 RU5.3 ; 132.42,108.58 132.92,109.08 RU5.5 132.92,112.52 133.17,112.78 133.66,112.78 133.7,112.74 ; 135.42,113.16 135.52,113.26 v1(136.42,113.26) RU5.12 ; 135.42,113.16 RU5.10 ; 135.42,113.16 135.41,113.17 134.12,113.17 133.7,112.74 ; RU5.7 133.92,112.52 133.7,112.74 ; v1(141.42,109.47) RU5.22 ; v1(137.42,109.47) RU5.14 ; RU5.24 v1(142.42,109.47) 142.92,109.97 RU5.25
  L3-SIGNAL w0.109: v1(138.42,109.47) v1(137.42,109.47) 136.42,110.47 v1(136.42,113.26)
  L7-SIGNAL w0.089: v1(143.42,109.47) v1(142.42,109.47) v1(141.42,109.47) v1(140.42,109.47) 139.95,109.01 138.88,109.01 v1(138.42,109.47)
N16880764: length 19.5
  L10-SIGNAL w0.089: v1(147.56,84.45) 147.56,86.38 143.15,90.79 v1(143.15,99.33)
  BOTTOM w0.132: RU18.56 v1(143.15,99.33) ; U121.4 v1(147.56,84.45)
N16880951: length 4.7
  TOP w0.132: RJ10.2 v1(137.16,97.28)
  BOTTOM w0.132: RU18.43 136.65,97.8 v1(137.16,97.28)
N16880965: length 4.6
  TOP w0.132: RJ9.2 v1(135.6,97.28)
  BOTTOM w0.132: RU18.41 135.65,97.74 135.6,97.69 v1(135.6,97.28)
N16880979: length 4.6
  TOP w0.132: RJ8.2 v1(134.2,97.28)
  BOTTOM w0.132: RU18.39 134.65,97.73 v1(134.2,97.28)
N16880993: length 4.6
  TOP w0.132: RJ7.2 v1(132.68,97.28)
  BOTTOM w0.132: RU18.36 133.15,97.75 v1(132.68,97.28)
N16881018: length 40.5
  BOTTOM w0.132: 136.65,95.5 RU18.14 ; 136.65,95.5 135.65,95.5 ; 136.65,95.5 137.65,95.5 ; RU18.20 133.65,94.97 133.6,95.02 133.6,95.5 ; 140.15,95.5 138.65,95.5 ; 140.15,95.5 RU18.7 ; 140.15,95.5 141.15,95.5 ; 138.65,95.5 137.65,95.5 ; 138.65,95.5 RU18.10 ; 132.15,95.5 131.65,95.5 ; 132.15,95.5 RU18.23 ; 132.15,95.5 132.65,95.5 ; 131.65,95.5 131.15,95.5 ; 131.65,95.5 RU18.24 ; 131.15,95.5 130.65,95.5 ; 131.15,95.5 RU18.25 ; 132.65,95.5 133.6,95.5 ; 132.65,95.5 RU18.22 ; R511.1 129.67,91.82 129.65,91.83 RU18.28 129.65,95.23 129.92,95.5 130.15,95.5 ; 137.65,95.5 RU18.12 ; 135.65,95.5 RU18.16 ; 135.65,95.5 133.6,95.5 ; 130.15,95.5 130.65,95.5 ; 130.15,95.5 RU18.27 ; 130.65,95.5 RU18.26 ; RU18.3 142.15,95.22 141.86,95.5 141.15,95.5 ; 141.15,95.5 RU18.5
N16886591: length 4.3
  TOP w0.132: R227.2 v1(157.1,54.48) 156.72,54.86 R223.1 R735.1
  BOTTOM w0.132: v1(157.1,54.48) 157.12,54.46 RU22.2
N16886593: length 4.3
  TOP w0.132: R229.1 R736.1 156.98,52.58 v1(157.05,52.51) 157.12,52.58 R232.2
  BOTTOM w0.132: v1(157.05,52.51) RU22.5
N16886703: length 1.7
  TOP w0.132: v1(158.44,55.75) 158.85,56.17 U44.4
  BOTTOM w0.132: RU22.1 v1(158.44,55.75)
N16888125: length 3.7
  TOP w0.132: U30.21 204.75,68.05 v1(204.98,67.82)
  BOTTOM w0.132: v1(204.98,67.82) 204.22,67.82 R506.1 R509.2
N16888127: length 3.7
  TOP w0.132: U30.2 196.59,69.35 v1(196.34,69.6)
  BOTTOM w0.132: v1(196.34,69.6) R503.1 R499.2
N16888129: length 3.7
  TOP w0.132: v1(196.34,68.61) 196.62,68.61 196.71,68.7 U30.3
  BOTTOM w0.132: v1(196.34,68.61) 196.62,68.33 R505.1 R508.2
N16888136: length 2.9
  TOP w0.132: v1(199.39,69.98) 199.37,70 U30.1
  BOTTOM w0.132: R498.2 200.15,70.74 v1(199.39,69.98)
N16888524: length 3.7
  TOP w0.132: U21.21 v1(204.72,79.6)
  BOTTOM w0.132: R478.2 R471.1 204.37,79.25 v1(204.72,79.6)
N16888526: length 3.7
  TOP w0.132: v1(196.09,81.15) 196.34,80.9 U21.2
  BOTTOM w0.132: R461.2 R463.1 v1(196.09,81.15)
N16888528: length 3.7
  TOP w0.132: U21.3 v1(196.09,80.25)
  BOTTOM w0.132: v1(196.09,80.25) 196.46,79.88 R468.1 R475.2
N16888536: length 3.6
  TOP w0.132: v1(196.09,81.92) 196.45,81.55 U21.1
  BOTTOM w0.132: R497.2 196.09,82.68 v1(196.09,81.92)
N16888767: length 196.8
  L3-SIGNAL w0.109: v1(199.64,74.42) 199.64,74.43 198.25,75.83 198.25,120.78 v1(195.83,123.19)
  L14-SIGNAL w0.109: v1(195.83,123.19) 191.52,123.19 188.47,126.24 136.91,126.24 130.05,133.1 118.87,133.1 117.73,134.24 113.92,134.24 112.9,135.25 105.03,135.25 103.76,136.53 85.34,136.53 83.57,134.75 v1(67.94,134.75)
  BOTTOM w0.132: U111.4 63.6,129.01 67.94,133.35 67.94,133.55 67.93,133.57 67.93,133.9 67.94,133.91 v1(67.94,134.75) ; R486.1 202.31,74.42 v1(199.64,74.42)
N16888979: length 4.3
  BOTTOM w0.132: U110.21 68.73,129.64 68.2,130.18 R411.1 R422.2
N16888981: length 4.2
  BOTTOM w0.132: U110.2 77.99,130.94 78.24,131.19 R408.2 78.74,132.21 79.12,132.59
N16888983: length 4
  BOTTOM w0.132: R419.2 78.74,129.4 78.87,129.53 R412.1 78.37,130.05 78.13,130.29 U110.3
N16888990: length 1.9
  TOP w0.132: v1(63.37,133.1) 63.37,132.6 63.37,132.59 63.37,132.08
  BOTTOM w0.132: v1(63.37,133.1) 63.47,132.99 U112.4
N16889000: length 1.7
  BOTTOM w0.132: U110.1 76.2,132.46 76.07,132.59 R400.2
N16891345: length 19.3
  TOP w0.132: R2.1 v1(136.65,174.12)
  L12-SIGNAL w0.089: v1(142.67,174.88) 137.41,174.88 v1(136.65,174.12)
  BOTTOM w0.132: P14.10 142.67,165.79 144.15,167.26 144.15,173.41 v1(142.67,174.88)
N16891485: length 3.1
  BOTTOM w0.305: R323.2 C267.1 125.61,159.5 U100.1
N16892015: length 3.3
  BOTTOM w0.132: C273.1 119.89,159.38 120.9,159.38 121.16,159.13 U96.6
N16892029: length 2.6
  BOTTOM w0.132: R342.2 119.25,155.32 120.07,156.13 U96.4
N16916626: length 3.3
  BOTTOM w0.132: 138.43,26.67 138.81,26.67 139.06,26.92 139.06,27.56 C578.1 ; 138.43,26.67 R676.2 ; 138.43,26.67 R674.2
N17023760: length 13.7
  TOP w0.132: v2(29.19,128.38) 29.34,128.52 30.23,128.52 30.86,129.16 33.15,129.16 33.53,129.54 R102.2 R99.2 R92.2 32.89,132.72 31.5,132.72 29.84,131.06 R101.2
  BOTTOM w0.132: U115.43 v2(29.19,128.38)
N17023786: length 7.1
  TOP w0.132: v2(29.08,129.29) R101.1 25.91,130.05 TP16.1
  BOTTOM w0.132: v2(29.08,129.29) 28.69,128.89 U115.42
N17023843: length 7.1
  TOP w0.132: v2(31.75,132.08) R92.1
  BOTTOM w0.132: U115.44 29.69,128.24 31.24,129.79 31.24,131.57 v2(31.75,132.08) R406.2
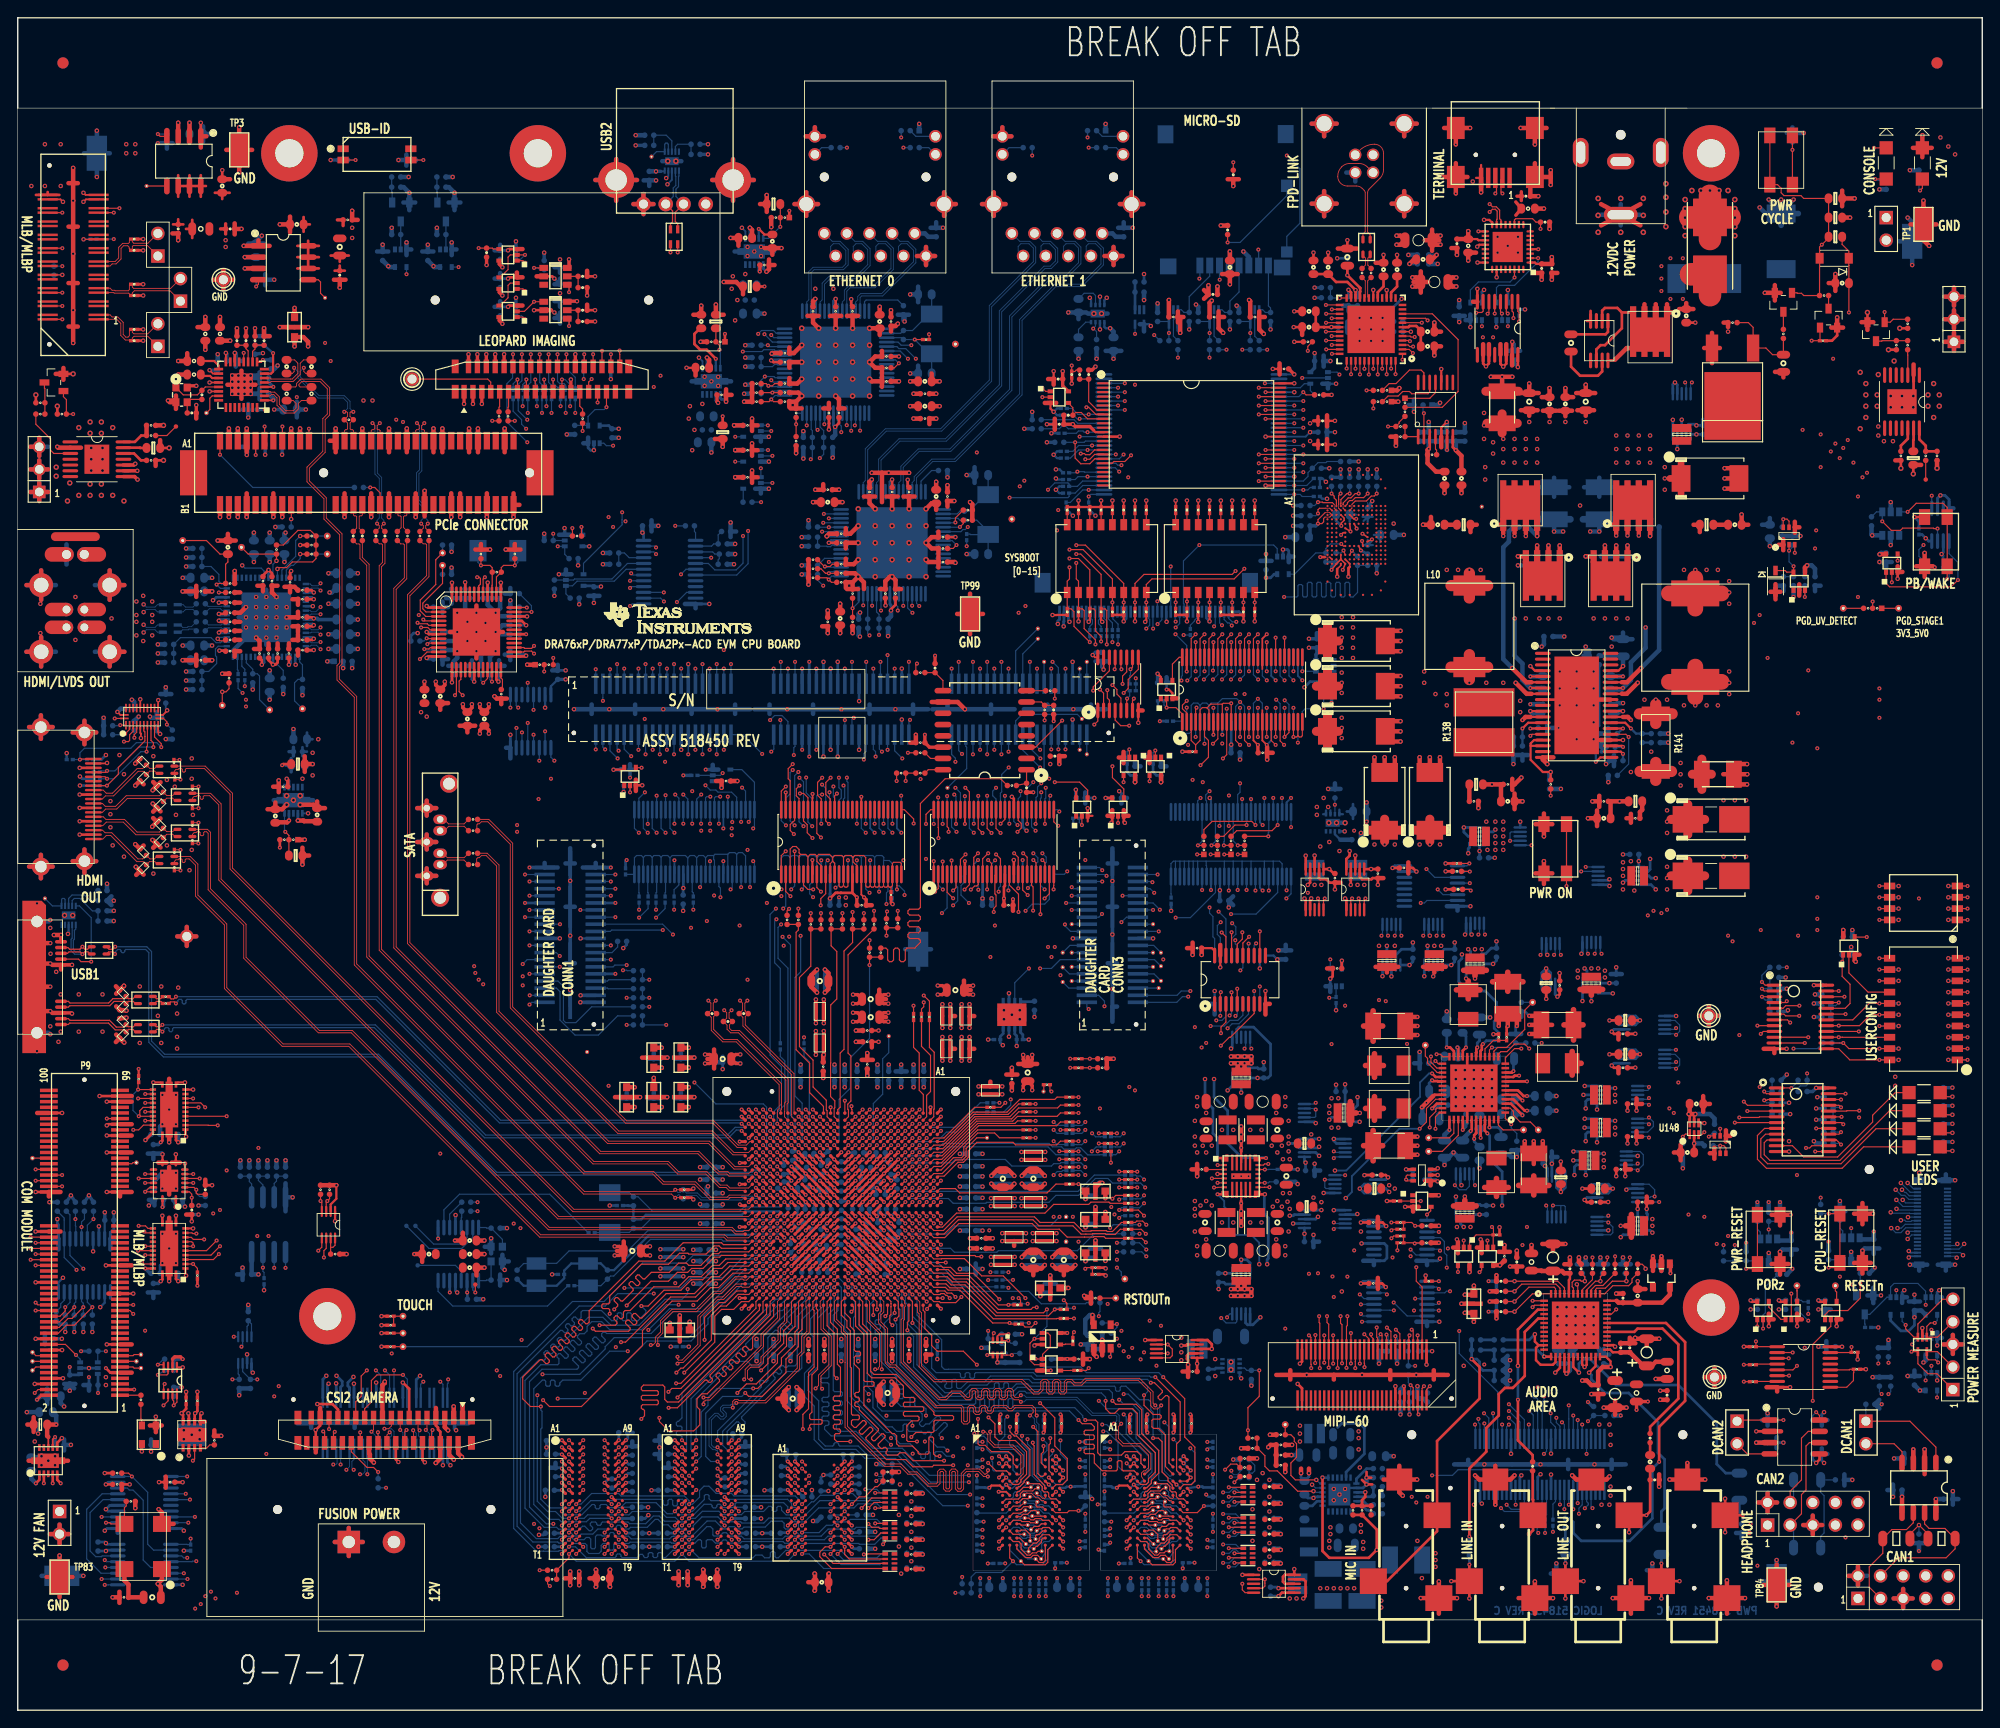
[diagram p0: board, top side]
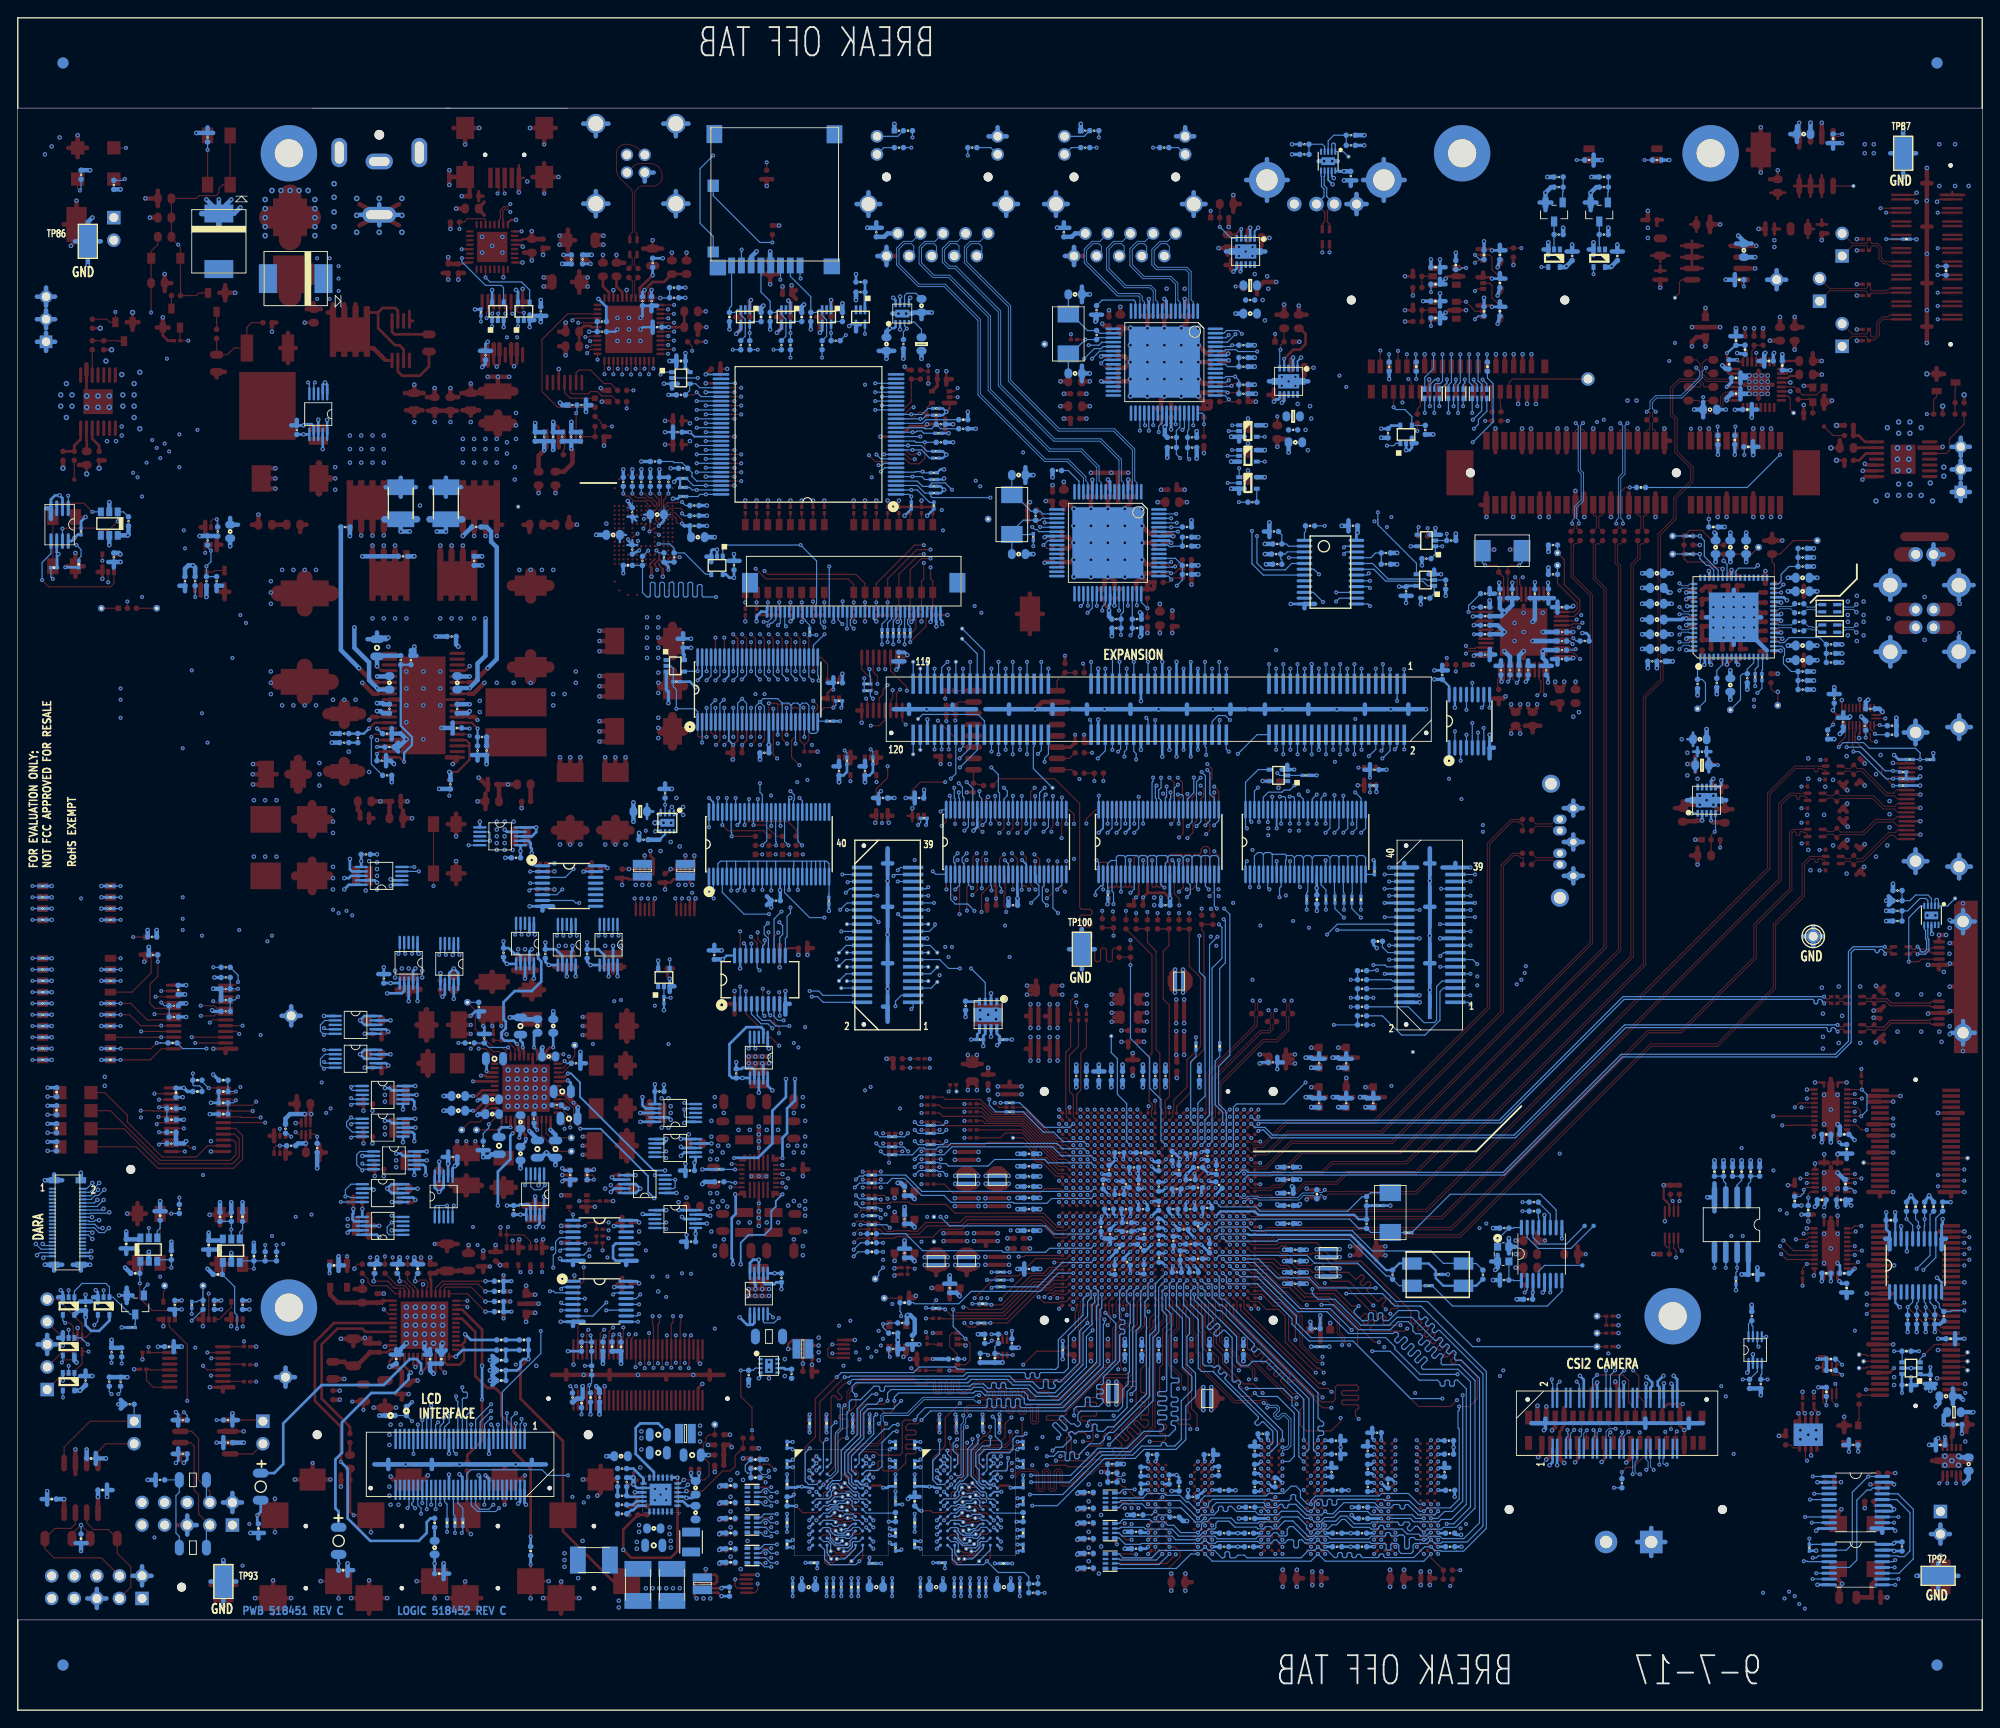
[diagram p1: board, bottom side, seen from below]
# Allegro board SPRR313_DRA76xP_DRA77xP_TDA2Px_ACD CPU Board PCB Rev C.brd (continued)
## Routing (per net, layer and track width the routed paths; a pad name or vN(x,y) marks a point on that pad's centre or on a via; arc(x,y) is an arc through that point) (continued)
N17023899: length 5
  TOP w0.132: v2(31.75,130.05) R102.1
  BOTTOM w0.132: R413.2 v2(31.75,130.05) 31.75,129.54 30.99,128.78 30.71,128.78 30.19,128.26 U115.45
N17023921: length 7
  BOTTOM w0.132: TP26.1 31.11,113.54 31.11,115.57 31.5,115.95 R454.1 32,117.6 31.69,117.92 U115.1
N17023993: length 1.6
  BOTTOM w0.132: R406.1 TP17.1
N17024012: length 1.6
  BOTTOM w0.132: R413.1 TP18.1
N17024054: length 2.1
  BOTTOM w0.132: R449.2 25.53,117.09 25.19,117.43 U115.14
N17024079: length 2
  BOTTOM w0.132: U115.15 24.69,117.05 24.77,116.97 R450.2
N17024117: length 8.6
  BOTTOM w0.132: U115.19 22.9,120.19 22.8,120.08 22.29,120.08 21.72,120.65 18.29,120.65 R442.1 C328.1 R447.2
N17024178: length 25.1
  TOP w0.132: TP19.1 v2(22.99,114.55) 23.41,114.55 23.75,114.9 R132.1
  L14-SIGNAL w0.109: v2(25.23,128.78) 22.23,128.78 21.08,127.64 21.08,116.46 v2(22.99,114.55)
  BOTTOM w0.132: v2(25.23,128.78) 25.54,128.47 27.36,128.47 27.69,128.14 U115.40
N17024186: length 7.4
  BOTTOM w0.132: TP22.1 27.18,113.67 27.18,116.33 26.92,116.59 R451.1 26.42,117.09 25.69,117.82 U115.13
N17024209: length 7.2
  BOTTOM w0.132: U115.18 22.53,119.69 22.23,119.38 22.23,118.62 22.35,118.49 22.35,117.73 21.46,116.84 R448.1 C332.1 R456.2
N17024222: length 6.1
  BOTTOM w0.132: U115.32 22.92,126.69 22.61,127 22.61,127.76 21.72,128.65 R423.1 C312.1 R410.2
N17024263: length 11.5
  TOP w0.132: TP14.1 21.21,131.57 22.73,130.05 C89.1 23.62,129.16 23.37,128.91 R110.1 22.48,126.75 v1(22.35,126.62)
  BOTTOM w0.132: v1(22.35,126.62) 22.79,126.19 U115.31
N17024348: length 4.3
  TOP w0.305: C101.1 33.15,122.94 v2(33.27,122.81)
  BOTTOM w0.305: v2(33.27,122.81) 33.15,122.69 32.38,122.69
  BOTTOM w0.406: v2(33.27,122.81) 33.66,122.81 33.78,122.68 L28.1
N17024432: length 2.7
  BOTTOM w0.132: R453.1 29.84,116.97 29.19,117.62 U115.6
N17024500: length 1.7
  TOP w0.132: R111.1 v1(22.61,125.73)
  BOTTOM w0.132: v1(22.61,125.73) 22.73,125.73 22.78,125.69 U115.30
N17024526: length 2.1
  TOP w0.132: C107.1 23.27,120.3 22.71,120.3 v2(22.48,120.52)
  BOTTOM w0.132: U115.20 22.64,120.69 v2(22.48,120.52)
N17024906: length 3.6
  TOP w0.132: Q3.D 3,148.72 3.05,148.67 R45.2 R50.1
N17025083: length 7.1
  TOP w0.132: U13.3 4.05,141.37 3.68,141.73 3.68,143 2.03,144.65 R50.2
N17025101: length 4
  TOP w0.305: R62.2 13.88,143.38 13.16,142.67 U13.14
  TOP w0.508: R58.2 R62.2
N17025155: length 2.7
  TOP w0.132: R62.1 16.76,143.38 TP10.1
N17025181: length 2.6
  TOP w0.305: R65.2 13.75,141.99 13.72,142.02 U13.13
N17025216: length 2.9
  TOP w0.305: R68.2 13.84,140.59 13.07,141.37 U13.12
N17027122: length 3.8
  BOTTOM w0.132: U135.8 26.27,43.45 R644.2 25.91,43.32 25.78,43.19 U135.7
N17027318: length 5.7
  TOP w0.132: v1(40.51,26.8) 40.01,27.3 39.27,27.3 37.5,29.08 J15.26
  BOTTOM w0.132: v1(40.51,26.8) R677.2
N17029697: length 2.6
  BOTTOM w0.508: 103.25,165.74 102.36,165.74 101.98,166.12 P3.2
N17029975: length 2.1
  BOTTOM w0.132: P3.D1 102.41,175.77 R301.1
N17029983: length 3.1
  BOTTOM w0.132: P3.D2 100.97,177.04 RJ13.2
N17030002: length 2.6
  TOP w0.132: v1(99.06,151.51) 98.55,151 98.17,151
  BOTTOM w0.132: v1(99.06,151.51) 98.68,151.89 U101.24
N17030015: length 2.1
  BOTTOM w0.132: R302.1 90.37,175.77 P3.D3
N17030236: length 15.7
  L3-SIGNAL w0.109: v1(81.51,152.83) 81.51,152.82 81.15,152.46 81.15,143.76 80.66,143.27 v1(80.66,143.24)
  BOTTOM w0.132: v1(81.51,152.83) 83.66,152.83 83.87,153.03 85.07,153.03 85.22,152.89 U101.59 ; U103.4 v1(80.66,143.24)
N17030260: length 8.9
  TOP w0.132: R24.1 v1(100.84,154.18)
  BOTTOM w0.132: U101.19 99.36,154.39 R338.2 v1(100.84,154.18) 102.44,152.58 Y3.1 C284.1
N17030273: length 8.2
  BOTTOM w0.132: C268.1 Y3.2 102.44,157.05 100.58,155.19 R338.1 99.26,154.89 U101.18
N17030313: length 8.8
  L7-SIGNAL w0.089: v1(100.08,152.02) 101.73,153.67 TP7.1
  BOTTOM w0.132: v1(100.08,152.02) 99.21,152.89 U101.22
N17032286: length 2.6
  BOTTOM w0.508: 124.33,165.74 123.44,165.74 123.06,166.12 P4.2
N17032564: length 2.3
  BOTTOM w0.132: P4.D1 123.49,175.77 R299.1
N17032572: length 3.2
  BOTTOM w0.132: P4.D2 121.92,177.04 121.28,177.67
N17032591: length 2.9
  TOP w0.132: R100.2 105.16,130.68 v1(105.54,131.06)
  BOTTOM w0.132: v1(105.54,131.06) 105.03,131.57 U108.24
N17032604: length 2.7
  BOTTOM w0.132: P4.D3 111.46,175.77 R300.1
N17032833: length 16.3
  L10-SIGNAL w0.089: v1(90.42,132.57) 88.16,132.57 82.55,138.18 82.55,138.56 v1(80.66,140.45)
  BOTTOM w0.132: U108.59 v1(90.42,132.57) ; U106.4 v1(80.66,140.45)
N17032852: length 10.7
  BOTTOM w0.132: Y4.1 109.09,132.59 107.82,133.86 R399.2 105.92,133.86 105.71,134.07 U108.19 ; Y4.1 109.08,132.24 107.11,132.24 107.05,132.3 R91.1 ; Y4.1 C311.1
N17032862: length 8.2
  BOTTOM w0.132: C299.1 Y4.2 108.79,136.73 106.93,134.87 R399.1 105.92,134.87 105.61,134.57 U108.18
N17032902: length 8.3
  L10-SIGNAL w0.089: TP13.1 107.7,133.99 v1(106.81,133.1)
  BOTTOM w0.132: v1(106.81,133.1) 106.52,132.81 106.26,132.81 106.02,132.57 U108.22
N17035312: length 1.5
  BOTTOM w0.132: U107.4 81.56,135.92 R394.2
N17036157: length 8.2
  TOP w0.305: J13.12 155.88,36.4 v1(155.83,36.45) ; J13.1 v2(158.38,38.87)
  L12-SIGNAL w0.305: v2(158.38,38.87) 157.75,38.24 156.86,38.24 155.83,37.21 v1(155.83,36.45)
  BOTTOM w0.508: R665.2 155.45,36.07 v1(155.83,36.45)
N17036363: length 2.2
  TOP w0.132: J13.15 154.88,42.07 v1(154.88,42.08)
  BOTTOM w0.132: v1(154.88,42.08) 154.88,42.07 154.88,42.04 155.07,41.85 R640.2
N17038308: length 2.4
  TOP w0.132: R268.1 195.49,38.93 RU10.4
N17038335: length 2.4
  TOP w0.132: R271.1 195.44,36.98 RU10.7
N17038428: length 1.5
  TOP w0.132: Q6.D 203.58,159.13
N17038575: length 2.3
  BOTTOM w0.132: J17.8 120.62,122.84 120.82,122.64 120.82,122.21 120.52,121.92 R440.1
N17038592: length 2.1
  BOTTOM w0.132: R439.1 121.16,122.68 121.12,122.72 J17.9
N17038609: length 2.2
  BOTTOM w0.132: J17.10 121.62,122.72 121.5,122.6 121.5,122.21 121.79,121.92 R438.1
N17038626: length 2.2
  BOTTOM w0.132: J17.11 122.12,122.83 122.43,122.52 R437.1
N17038643: length 2.3
  BOTTOM w0.132: R436.1 123.06,122.3 122.62,122.75 J17.12
N17038647: length 2.3
  BOTTOM w0.132: R435.1 123.7,122.17 123.12,122.75 J17.13
N17038700: length 2.3
  BOTTOM w0.132: J17.32 132.62,122.85 132.54,122.85 132.29,122.6 132.29,122.51 131.83,122.05 R434.1
N17039732: length 0.9
  TOP w0.305: R15.1 v1(83.95,160.15)
N17039746: length 1.6
  TOP w0.381: v1(83.41,161.83) 83.44,161.86 C12.1
  BOTTOM w0.305: v1(83.41,161.83) 83.3,161.93 U93.7
N17039774: length 5
  TOP w0.132: v1(85.72,166.86) R3.1
  BOTTOM w0.132: U93.5 84.4,165.56 85.7,166.86 v1(85.72,166.86)
N17040452: length 1
  TOP w0.305: R53.1 v1(79.25,145.54)
N17040466: length 2
  TOP w0.381: v2(78.73,147.07) 78.61,147.19 C56.1
  BOTTOM w0.305: U102.7 78.48,147.32 v2(78.73,147.07)
N17040494: length 4.7
  TOP w0.132: v1(78.89,153.03) 78.89,153.52 RJ2.2 R20.1
  BOTTOM w0.132: U102.5 78.98,152.95 v1(78.89,153.03)
N17127468: length 3.1
  BOTTOM w0.132: Q12.D U95.2
N17127513: length 2.9
  BOTTOM w0.132: Q12.G 42.09,170.77 42.04,170.82 R315.1 R313.2
N17127575: length 3.1
  BOTTOM w0.132: Q11.D R320.2 U94.2
N17127620: length 2.9
  BOTTOM w0.132: Q11.G 47.17,170.77 47.12,170.82 R314.1 R312.2
N17128348: length 14.3
  TOP w0.132: v1(212.9,40.34) U52.4 213.62,38.98 214.76,37.85 215.77,37.85 J14.1
  L10-SIGNAL w0.089: v1(215.77,35.18) 213.49,37.47 213.49,39.75 v1(212.9,40.34)
  BOTTOM w0.132: U133.4 215.79,35.19 v1(215.77,35.18)
N17128443: length 6.7
  TOP w0.132: J14.2 215.82,40.34 U52.5 214.62,39.63 214.84,39.41 215.6,39.41 v1(215.9,39.12)
  BOTTOM w0.132: v1(215.9,39.12) 215.79,39.23 U131.4
N17128562: length 6.9
  TOP w0.132: J14.4 215.82,41.96 U52.1 214.62,43.17 215.01,43.56 v1(215.52,43.56)
  BOTTOM w0.132: U129.4 215.79,43.83 v1(215.52,43.56)
N17128571: length 10.1
  TOP w0.132: J14.5 216.41,46.23 213.62,43.44 U52.3 213.18,41.96 212.25,42.9 v1(212.25,43.34)
  BOTTOM w0.132: U130.4 211.85,43.73 v1(212.25,43.34)
N17132279: length 2.7
  TOP w0.305: U8.14 154.4,159.48 155.07,160.15 C18.1
N17132316: length 4.1
  TOP w0.305: U8.7 156.33,155.57 156.47,155.71 157.22,155.71 157.73,155.19 C33.1 C36.1
N17132397: length 2.7
  TOP w0.305: U8.17 152.9,159.5 153.54,160.15 C17.1
N17132449: length 14.6
  TOP w0.099: P1.1 151.75,173.58 arc(151.3,173.88) 150.76,173.99 149.76,173.99 arc(149.27,173.89) 148.84,173.61 arc(148.51,173.11) 148.4,172.53 arc(148.71,171.77) 149.48,171.45 150.52,171.45 arc(150.85,171.38) 151.13,171.2 151.4,170.93 arc(151.46,170.83) 151.49,170.71 151.49,166.31 151.23,166.05 FL2.2
N17132477: length 2.5
  TOP w0.099: 151.13,161.16 151.5,160.8 151.5,158.95 U8.20
N17132490: length 14.6
  TOP w0.099: FL2.3 152.04,165.96 151.75,166.25 151.75,170.68 arc(151.8,170.91) 151.93,171.11 153.15,172.32 arc(153.44,172.76) 153.54,173.28 153.54,175.13 arc(153.25,175.85) 152.53,176.15 arc(151.63,175.97) 150.87,175.46 P1.3
N17132501: length 2.5
  TOP w0.099: U8.19 151.76,158.99 151.76,160.65 151.77,160.65 151.77,160.78 152.15,161.16
N17132537: length 1.8
  TOP w0.305: U8.23 149.9,159.48 v2(149.61,159.77)
  BOTTOM w0.305: C271.1 v2(149.61,159.77)
N17132610: length 3
  TOP w0.132: U8.24 v2(148.62,158.85)
  BOTTOM w0.132: R325.2 R326.1 147.6,158.85 v2(148.62,158.85)
N17132637: length 3
  TOP w0.132: U8.6 156.46,155.07 156.46,155.07 156.62,155.07 v2(156.62,155.06)
  BOTTOM w0.132: v2(156.62,155.06) 156.62,155.07 R337.1 R336.2
N17132743: length 5.1
  TOP w0.305: C11.1 v2(149.48,161.42) 150.9,159.99 150.9,159.98 150.92,159.96 150.92,159.59 150.9,159.56 U8.21
  BOTTOM w0.305: R318.2 v2(149.48,161.42)
N17139258: length 3.6
  TOP w0.132: R61.1 R60.2 209.6,154.05 209.55,154 Q5.D
N17139366: length 2.9
  TOP w0.132: R61.2 212.47,152.44 212.49,152.42 U14.3
N17139372: length 4.2
  TOP w0.305: U14.14 213.79,142.96 214.5,142.24 214.5,141.6 215.77,141.6
N17139433: length 2.6
  TOP w0.305: R98.2 213.11,142.88 213.14,142.91 U14.13
N17139447: length 2.9
  TOP w0.305: U14.12 212.49,143.02 211.71,142.24 211.71,141.6
N17140327: length 4.7
  TOP w0.305: R140.1 29.84,106.43 v1(29.72,106.3)
  BOTTOM w0.381: 30.49,107.82 C347.2 ; C347.2 30.99,107.33 ; C347.2 30.99,108.32 ; R473.2 30.73,107.05 ; R473.2 30.73,105.55 ; R473.2 30.11,106.3
N17140341: length 2
  TOP w0.381: v2(30.23,104.78) 30.35,104.66 C121.1
  BOTTOM w0.305: U117.7 30.49,104.52 v2(30.23,104.78)
N17140369: length 5
  TOP w0.132: R142.1 RJ6.2 30.48,98.4 v1(30.07,98.81)
  BOTTOM w0.132: v1(30.07,98.81) 29.99,98.89 U117.5
N17208527: length 12.8
  TOP w0.132: 202.56,31.37 201.29,31.37 200.53,30.61 200.53,25.91 199.26,24.64 J21.4
  BOTTOM w0.132: J21.4 199.64,23.75 R288.1
N17208571: length 9.6
  BOTTOM w0.132: R287.1 202.69,19.56 203.07,19.94 203.07,24.13 202.69,24.51 R288.2 C623.1
N17208626: length 14
  TOP w0.132: J21.3 200.53,22.1 200.53,24.26 201.04,24.77 201.04,29.72 201.42,30.1 U57.6
  BOTTOM w0.132: J21.3 199.64,20.45 R287.2
N17208671: length 2.1
  TOP w0.132: v1(202.18,33.53) 202.56,33.15 U57.8
  BOTTOM w0.132: v1(202.18,33.53) 201.8,33.15 R689.1
N17213075: length 9.9
  TOP w0.305: U11.6 v1(160.69,141.76) ; v1(161.67,141.73) 161.34,142.07 U11.7
  TOP w0.508: L9.1 162.31,141.1 v1(161.67,141.73)
  BOTTOM w0.508: v1(160.69,141.76) 160.66,141.79 C294.1 C293.1 ; C292.1 C293.1 ; C293.1 v1(161.67,141.73)
N17213086: length 8.3
  TOP w0.305: v1(158.63,141.88) 158.73,141.99 U11.3
  TOP w0.508: v1(158.63,141.88) 158.5,141.75 R67.2 158.5,140.27 159.45,139.32 L8.1
  BOTTOM w0.508: v1(158.63,141.88) 158.63,142.74 C296.1 ; C295.1 C296.1 ; C296.1 C297.1
N17213569: length 2.1
  TOP w0.132: R67.1 159.51,141.73 159.38,141.86 U11.4
N17213624: length 2.6
  TOP w0.132: R59.1 R63.2 U11.1
N17213889: length 6.8
  TOP w0.132: RJ3.2 154.18,149.22 154.94,149.22 156.46,150.75 157.77,150.75 158.08,150.43 U11.13
N17213902: length 7.1
  TOP w0.132: RJ5.2 154.05,147.83 155.19,147.83 155.7,148.34 156.46,148.34 156.72,148.08 158.55,148.08 158.73,148.27 U11.12
N17213969: length 3.6
  TOP w0.132: U11.2 v1(158.08,145.89)
  BOTTOM w0.132: v1(158.08,145.89) 157.99,145.99 RJ14.2
N17214102: length 4.8
  TOP w0.132: RJ4.1 158.75,147.57 159.38,148.21 U11.11
N17240442: length 2.4
  TOP w0.132: RU4.6 124.67,113.59 124.71,113.63 v1(124.71,113.79)
  BOTTOM w0.132: R458.1 125.01,114.08 v1(124.71,113.79)
N17240462: length 3.1
  TOP w0.132: v1(125.09,117.09) 125.32,117.32 RU4.10
  BOTTOM w0.132: v1(125.09,117.09) 125.09,116.46 125.01,116.37 R457.1
N17269696: length 2.2
  TOP w0.132: R96.1 TP15.1
N17464210: length 25.7
  TOP w0.132: U42.E17 v1(100.59,53.96)
  L14-SIGNAL w0.109: v1(122.81,54.26) 122.39,53.85 119.76,53.85 119.18,54.43 112.57,54.43 112.01,54.99 104.78,54.99 104.15,54.36 100.99,54.36 v1(100.59,53.96)
  BOTTOM w0.132: v1(122.81,54.26) 123.16,54.61 R596.1
N17464229: length 12.1
  TOP w0.132: U42.B25 102.98,47.57 104.29,47.57 104.61,47.25 105.91,47.25 109.6,43.56 v1(111.51,43.56) 111.63,43.43 R252.1
  BOTTOM w0.132: R613.1 v1(111.51,43.56)
N17468373: length 19.5
  TOP w0.132: U42.F9 v1(99.79,61.16)
  BOTTOM w0.132: v1(99.79,61.16) 100.21,61.59 100.4,61.59 100.42,61.57 105,61.57 105.38,61.95 111.02,61.95 111.76,61.21 116.2,61.21 116.47,61.48 117.16,61.48 117.27,61.59 R567.2
N17468379: length 18.3
  TOP w0.132: U42.E10 v1(100.59,60.36) ; R198.2 v1(117.22,60.2)
  L14-SIGNAL w0.109: v1(117.22,60.2) 116.73,60.69 116.67,60.69 116.59,60.77 100.99,60.77 v1(100.59,60.36)
N17468389: length 22.5
  TOP w0.132: R206.2 v1(121.54,63.75) ; U42.D9 v1(101.39,61.16)
  L12-SIGNAL w0.089: v1(121.54,63.75) 120.52,63.75 120.39,63.62 116.83,63.62 116.71,63.5 106.17,63.5 104.24,61.56 101.78,61.56 v1(101.39,61.16)
N17468401: length 17.5
  TOP w0.132: U42.C6 v1(102.19,63.56) ; R201.2 v1(117.22,65.28)
  L12-SIGNAL w0.089: v1(102.19,63.56) 103.82,63.56 106.17,65.91 115.7,65.91 115.83,65.78 116.72,65.78 v1(117.22,65.28)
N17468413: length 25.6
  TOP w0.132: R568.2 v1(123.83,59.69) ; U42.E9 v1(100.59,61.16)
  L14-SIGNAL w0.109: v1(100.59,61.16) 100.99,61.57 104.87,61.57 105.03,61.72 111.61,61.72 112.24,61.09 116.59,61.09 116.76,60.91 116.82,60.91 117.05,60.69 121.43,60.69 122.43,59.69 v1(123.83,59.69)
N17468425: length 19.6
  TOP w0.132: U42.F8 v1(99.79,61.96)
  BOTTOM w0.132: v1(99.79,61.96) 100.18,62.36 103.5,62.36 104.51,63.37 115.82,63.37 116.71,62.48 R562.2
N17468437: length 19.2
  TOP w0.132: R565.2 117.11,62.87 v1(117.09,62.88) ; U42.F7 v1(99.79,62.76)
  L14-SIGNAL w0.109: v1(117.09,62.88) 116.7,62.88 116.08,63.5 102.68,63.5 102.35,63.17 100.19,63.17 v1(99.79,62.76)
N17468449: length 23.3
  TOP w0.132: U42.E7 v1(100.59,62.76)
  BOTTOM w0.132: R553.2 121.59,62.48 121.58,62.47 120.28,62.47 119.49,63.26 119.01,63.26 118.87,63.12 117.6,63.12 117.35,63.37 116.33,63.37 115.95,63.75 104.01,63.75 103.42,63.16 100.98,63.16 v1(100.59,62.76)
N17468461: length 25.6
  TOP w0.132: R555.2 123.84,60.58 v1(123.83,60.59) ; U42.E8 v1(100.59,61.96)
  L14-SIGNAL w0.109: v1(100.59,61.96) 100.98,62.36 104.62,62.36 104.88,62.1 110.36,62.1 110.63,62.37 117.84,62.37 118.63,61.58 121.43,61.58 122.41,60.59 v1(123.83,60.59)
N17468473: length 22.6
  TOP w0.132: R564.2 v1(121.54,64.9) ; U42.D8 v1(101.39,61.96)
  L12-SIGNAL w0.089: v1(121.54,64.9) 121.15,64.51 115.44,64.51 114.93,64.01 114.59,64.01 114.59,64 108.81,64 108.8,64.01 105.66,64.01 104.02,62.36 101.78,62.36 v1(101.39,61.96)
N17468485: length 18.8
  TOP w0.132: U42.D6 v1(101.39,63.56)
  L12-SIGNAL w0.089: v1(101.39,63.56) 101.78,63.96 103.71,63.96 106.05,66.29 113.28,66.29 113.79,66.8 115.82,66.8 v1(116.46,66.17)
  BOTTOM w0.132: R561.2 116.84,65.79 v1(116.46,66.17)
N17468497: length 18.6
  TOP w0.132: U42.D7 v1(101.39,62.76)
  L12-SIGNAL w0.089: v1(101.39,62.76) 101.78,63.16 103.8,63.16 106.04,65.41 113.54,65.41 113.8,65.67 115.18,65.67 115.57,65.28 v1(116.46,65.28)
  BOTTOM w0.132: v1(116.46,65.28) 116.86,64.88 117.39,64.88 117.4,64.9 R557.2
N17468509: length 16.6
  TOP w0.132: R200.2 116.84,68.96 116.59,68.71 112.65,68.71 111.22,67.28 107.39,67.28 104.08,63.96 U42.A5
N17468521: length 12.6
  TOP w0.132: R559.2 112.52,68.2 111.34,67.02 107.5,67.02 104.04,63.56 102.99,63.56 U42.B6
N17468533: length 17.3
  TOP w0.132: U42.C8 v1(102.19,61.96)
  L12-SIGNAL w0.089: v1(102.19,61.96) 104.13,61.96 105.9,63.73 115.04,63.73 115.32,64.01 v1(116.46,64.01)
  BOTTOM w0.132: v1(116.46,64.01) 116.84,63.63 R560.2
N17468545: length 21.6
  TOP w0.132: U42.C7 v1(102.19,62.76)
  L12-SIGNAL w0.089: v1(120.78,64.9) 120.4,64.9 120.28,64.78 108.81,64.78 108.8,64.77 105.92,64.77 103.91,62.76 v1(102.19,62.76)
  BOTTOM w0.132: R563.2 121.72,64.52 121.7,64.5 121.17,64.5 v1(120.78,64.9)
N17468557: length 12.5
  TOP w0.132: U42.B7 102.99,62.76 103.96,62.76 107.71,66.51 111.73,66.51 112.52,67.31 R203.2
N17468569: length 12.4
  TOP w0.132: R195.2 112.39,66.29 112.11,66.01 107.92,66.01 103.88,61.96 102.99,61.96 U42.B8
N17468581: length 16.5
  TOP w0.132: U42.A6 104,63.16 107.6,66.77 111.54,66.77 112.52,67.74 116.89,67.74 117.22,68.07 R199.2
N17468593: length 16.5
  TOP w0.132: U42.A7 103.92,62.36 107.81,66.26 111.85,66.26 112.39,66.8 116.84,66.8 117.22,67.18 R202.2
N17468605: length 21.9
  TOP w0.132: U42.C9 v1(102.19,61.16)
  L12-SIGNAL w0.089: v1(102.19,61.16) 104.47,61.16 105.41,62.1 111,62.1 112.19,63.3 116.8,63.3 116.87,63.37 120.24,63.37 v1(120.75,62.87)
  BOTTOM w0.132: R566.2 121.72,63.37 121.7,63.36 121.24,63.36 v1(120.75,62.87)
N17468617: length 16.4
  TOP w0.132: R197.2 117.22,66.17 116.81,65.75 108.02,65.75 103.84,61.56 U42.A8
N17468629: length 12.4
  TOP w0.132: R212.2 107.91,65.28 103.8,61.16 102.99,61.16 U42.B9
N17468641: length 12.2
  TOP w0.132: R207.2 110.36,64.39 109.82,64.93 107.92,64.93 106.36,63.37 106.36,62.4 106.1,62.14 105.19,62.14 103.81,60.76 U42.A9
N17468659: length 17.9
  TOP w0.132: U42.D11 v1(101.39,59.56)
  L12-SIGNAL w0.089: v1(101.39,59.56) 101.78,59.96 105.18,59.96 105.67,60.46 109.22,60.46 109.34,60.58 116.08,60.58 v1(116.46,60.2)
  BOTTOM w0.132: v1(116.46,60.2) 116.86,60.59 117.37,60.59 117.48,60.71 R574.2
N17468667: length 22.4
  TOP w0.132: R570.2 v1(121.41,62.87) ; U42.D10 v1(101.39,60.36)
  L12-SIGNAL w0.089: v1(101.39,60.36) 101.78,60.76 104.58,60.76 105.54,61.72 111.89,61.72 112.53,62.36 120.91,62.36 v1(121.41,62.87)
N17468677: length 16.9
  TOP w0.132: U42.A10 103.49,60.07 104.14,60.07 105.71,61.64 106.31,61.64 106.87,62.19 106.87,62.92 107.82,63.88 111.89,63.88 112.18,63.59 116.81,63.59 117.22,64.01 R577.2
N17468701: length 16.9
  TOP w0.132: U42.C10 v1(102.18,60.36) ; R210.2 v1(117.09,61.98)
  L12-SIGNAL w0.089: v1(102.18,60.36) 104.91,60.36 105.3,60.75 109.01,60.75 109.35,61.09 116.2,61.09 v1(117.09,61.98)
N17468893: length 17.4
  TOP w0.132: U42.D5 v1(101.39,64.36) ; TP56.1 115.35,69.63 R571.2
  L12-SIGNAL w0.089: v1(101.39,64.36) 101.64,64.36 102.02,64.75 103.99,64.75 105.92,66.68 111.89,66.68 114.05,68.83 114.55,68.83 TP56.1
N17470760: length 45.5
  TOP w0.132: U42.T6 v1(90.98,63.56)
  L10-SIGNAL w0.089: v1(69.85,90.04) 70.87,91.06 76.45,91.06 81.92,85.6 82.42,85.6 89.15,78.87 90.17,78.87 92.44,76.6 92.44,69.45 92.2,69.22 92.2,68.33 92.58,67.94 92.58,63.82 91.88,63.12 91.43,63.12 v1(90.98,63.56)
  BOTTOM w0.132: R526.2 v1(69.85,90.04)
N17470772: length 39.2
  TOP w0.132: U42.U5 v1(90.18,64.36)
  L10-SIGNAL w0.089: v1(90.18,64.36) 90.57,64.75 90.57,67.29 90.04,67.82 90.04,72.14 83.95,78.23 83.95,79.25 81.79,81.41 76.71,81.41 69.85,88.27 v1(69.85,89.15)
  BOTTOM w0.132: R524.2 70.87,90.17 v1(69.85,89.15)
N17470784: length 35.2
  TOP w0.132: U42.T5 v1(90.98,64.36)
  L10-SIGNAL w0.089: v1(90.98,64.36) 91.39,64.78 91.94,64.78 92.17,65 92.17,66.13 91.95,66.35 91.95,67.82 91.31,68.45 91.31,70.36 91.57,70.61 91.57,72.01 91.19,72.39 91.19,74.17 81.53,83.82 80.9,83.82 75.95,88.77 v1(75.95,90.04)
  BOTTOM w0.132: R529.2 v1(75.95,90.04)
N17470792: length 41.5
  TOP w0.132: U42.U6 v1(90.18,63.56)
  L10-SIGNAL w0.089: v1(73.79,90.04) 74.3,90.55 76.2,90.55 76.71,90.04 76.71,88.65 81.28,84.07 82.42,84.07 88.01,78.49 90.04,78.49 92.23,76.3 92.23,69.88 91.95,69.6 91.95,68.2 92.37,67.77 92.37,64.41 91.94,63.98 90.59,63.98 v1(90.18,63.56)
  BOTTOM w0.132: R530.2 v1(73.79,90.04)
N17470802: length 37
  TOP w0.132: U42.T3 v1(90.98,65.96)
  L10-SIGNAL w0.089: v1(90.98,65.96) 90.98,67.26 90.3,67.94 90.3,70.1 91.06,70.87 91.06,71.63 84.2,78.49 84.2,79.5 81.92,81.79 77.6,81.79 71.75,87.63 v1(71.75,89.15)
  BOTTOM w0.132: R531.2 72.77,90.17 v1(71.75,89.15)
N17470810: length 36.9
  TOP w0.132: U42.T4 v1(90.98,65.16)
  L10-SIGNAL w0.089: v1(90.98,65.16) 91.37,65.55 91.37,67.25 90.68,67.94 90.68,70.1 91.31,70.74 91.31,71.88 90.17,73.03 90.17,74.8 81.53,83.44 78.36,83.44 v1(71.75,90.04)
  BOTTOM w0.132: R532.2 v1(71.75,90.04)
N17470942: length 11
  TOP w0.132: U42.A23 104.62,49.56 105.28,48.9 106.93,48.9 110.24,45.59 v1(111.38,45.59) R245.2
  BOTTOM w0.132: R607.2 111.51,45.72 v1(111.38,45.59)
N17470980: length 17.5
  TOP w0.132: R235.2 v1(116.59,45.09) 115.87,44.37 109.97,44.37 106.5,47.84 104.93,47.84 104.41,48.37 102.98,48.37 U42.B24
  BOTTOM w0.132: v1(116.59,45.09) 116.71,45.21 R603.2
N17470990: length 24.9
  TOP w0.132: U42.C15 v1(102.19,55.56) ; R216.2 123.83,56.26 v1(123.83,56.27)
  L12-SIGNAL w0.089: v1(102.19,55.56) 102.57,55.95 115.38,55.95 116.2,56.77 120.14,56.77 121.35,55.56 122.44,55.56 123.14,56.27 v1(123.83,56.27)
  BOTTOM w0.132: v1(123.83,56.27) 123.83,56.27 124.08,56.52 R578.2
N17484787: length 3.7
  TOP w0.132: U38.16 164.95,74.4 165.9,75.35 R545.1 R544.2
N17484833: length 35.2
  TOP w0.132: v1(159.51,73.79) 159.93,73.79 160.21,73.51 U38.24 ; 174.12,99.67 v1(174.12,92.71)
  L10-SIGNAL w0.089: v1(159.51,73.79) 159.51,79.63 165.23,85.34 165.23,86.74 171.2,92.71 v1(174.12,92.71)
N17484968: length 5
  TOP w0.132: TP59.1 170.05,66.17 168.91,66.17 168.15,66.93 168.15,67.35 167.77,67.73 U38.2
N17484976: length 9.8
  TOP w0.132: TP54.1 169.42,78.74 169.42,76.58 167.39,74.55 166.37,74.55 165.95,74.13 U38.14
  BOTTOM w0.132: R706.1 TP54.1
N17484985: length 5.2
  TOP w0.132: U38.15 165.45,74.27 v1(165.74,74.55)
  BOTTOM w0.132: R547.2 R546.1 167.89,74.55 v1(165.74,74.55)
N17485041: length 3.7
  TOP w0.132: U38.48 166.45,65.82 166.99,65.28 TP60.1
N17485079: length 4.6
  TOP w0.132: U38.38 161.45,64.9 160.94,64.39 TP61.1
N17485083: length 5.9
  TOP w0.132: TP62.1 160.15,62.87 161.95,64.67 U38.39
N17485295: length 2.1
  TOP w0.305: U38.40 v1(162.45,65.28)
  BOTTOM w0.305: C413.2 162.81,65.64 v1(162.45,65.28)
N17493600: length 2.3
  TOP w0.132: U59.L8 v1(67.57,22.38)
  BOTTOM w0.132: R691.1 68.2,22.83 67.74,22.38 v1(67.57,22.38)
N17493609: length 2.3
  TOP w0.127: U60.L8 v1(80.27,22.38)
  BOTTOM w0.127: v1(80.27,22.38) 80.44,22.38 80.9,22.83 R690.1
N17495735: length 2
  BOTTOM w0.132: C200.1 R675.2 R684.2
N17514506: length 6.9
  TOP w0.132: RU10.12 205.91,38.28 205.99,38.35 R270.1 206.41,37.97 206.38,37.93 206.38,37.08 205.62,36.33 RU10.9
N17515494: length 2.5
  BOTTOM w0.254: U119.6 148.08,98.53 148.69,97.92
  BOTTOM w0.508: C358.1 148.69,97.92
N17515522: length 3.3
  BOTTOM w0.254: 148.97,100.79 U119.4 148.58,101.3
  BOTTOM w0.305: R500.2 150.11,101.92 ; R500.2 150.11,100.27 ; R500.2 149.41,101.09
N17523122: length 1.6
  BOTTOM w0.305: C545.1 134.57,38.35 134.7,38.49 U134.6
N17523181: length 109.1
  TOP w0.132: TP90.1 R281.2 143.13,30.99 143.51,30.61 143.51,30.24 143.76,29.98 143.76,28.45 143.13,27.81 143.13,26.42 143.64,25.91 v2(145.99,25.91) ; v1(59.82,13.97) 59.56,14.22 59.56,14.73
  L14-SIGNAL w0.109: v1(59.82,13.97) 60.58,13.97 61.34,14.73 103.89,14.73 v1(105.41,13.21) 107.06,13.21 107.57,13.72 140.34,13.72 143.13,16.51 143.13,23.88 145.16,25.91 145.56,25.91 145.56,25.91 v2(145.99,25.91)
  BOTTOM w0.132: R699.2 v1(105.41,13.21) ; U138.6 146.39,25.5 v2(145.99,25.91)
N17523441: length 2.2
  BOTTOM w0.305: U138.2 146.07,23.51 145.54,22.99 C610.2
N17523556: length 11.3
  TOP w0.132: R285.2 R284.1 139.37,29.46 140.21,28.63 140.21,27.43 140.72,26.92 141.6,26.92 143.89,24.64 v2(145.67,24.64)
  BOTTOM w0.132: v2(145.67,24.64) 145.8,24.51 U138.4
N17523683: length 2.9
  BOTTOM w0.305: U138.13 150.5,26.04 151.64,27.18 R283.1
N17523717: length 2.1
  BOTTOM w0.305: C211.2 151.69,23.11 151.29,23.51 U138.17
N17523739: length 2.9
  BOTTOM w0.305: U138.16 152.15,24.01 R286.1 C214.2
N17523799: length 4.7
  TOP w0.305: R692.2 R688.1 ; R692.2 C601.1 ; R692.2 151.13,23.64 151.49,24 v2(151.49,24.52)
  BOTTOM w0.305: v2(151.49,24.52) 151.47,24.51 U138.15
N17523845: length 2.3
  BOTTOM w0.305: U138.18 151.16,23.01 151.66,22.51 151.86,22.51 R291.1
N17523889: length 1
  BOTTOM w0.305: R286.2 C215.2
N17526209: length 3.1
  TOP w0.132: U46.4 196.87,45.32 198.22,43.97 U47.1
N17528197: length 3.7
  TOP w0.132: U37.4 123.49,43.36 v1(123.57,43.44)
  BOTTOM w0.132: R552.1 122.92,43.56 123.04,43.44 v1(123.57,43.44) 123.57,43.16 123.57,43.16 123.57,43.05 R551.2
N17528796: length 3.5
  BOTTOM w0.132: Y6.3 C480.1 52.71,48.39 52.65,48.32 U125.1
N17528834: length 6.2
  BOTTOM w0.132: U125.4 49.86,49.39 49.21,50.04 TP89.1
N17528966: length 4.1
  BOTTOM w0.132: Y6.1 54.48,52.96 C479.1 52.71,54.23 52.65,54.3 U125.16
N17529000: length 2.3
  TOP w0.132: TP66.1 v1(51.44,46.99)
  BOTTOM w0.132: U125.2 51.16,47.27 v1(51.44,46.99)
N17529020: length 10.1
  BOTTOM w0.132: U125.15 51.16,53.19 49.91,51.94 46.23,51.94 TP68.1
N17529026: length 8.1
  BOTTOM w0.132: TP67.1 46.75,52.44 49.77,52.44 50.51,53.17 U125.14
N17533979: length 5.1
  TOP w0.508: L30.1 C381.1 12.45,14.14 11.99,14.59 U123.4
N17534947: length 10.1
  TOP w0.132: TP8.1 52.83,149.73 53.17,149.39 J8.7
N17534968: length 2.3
  TOP w0.132: J8.9 54.17,146.63 54.1,146.56 R54.2
N17535002: length 2.3
  TOP w0.132: J8.11 55.18,146.62 55.12,146.56 R55.2
N17535025: length 2.3
  TOP w0.132: J8.12 v1(55.68,152.53)
  BOTTOM w0.132: R352.2 55.68,151.69 v1(55.68,152.53)
N17535034: length 2.7
  TOP w0.132: v1(56.18,149.68) J8.13
  BOTTOM w0.132: RN9.1 55.69,149.2 v1(56.18,149.68)
N17535043: length 5.5
  TOP w0.132: J8.14 v1(56.68,152.53)
  BOTTOM w0.132: v1(56.68,152.53) 56.68,152.53 56.68,149.55 56.27,149.14 RN9.2
N17535052: length 2.6
  TOP w0.132: v1(57.18,149.68) J8.15
  BOTTOM w0.132: RN9.3 56.76,149.11 57.18,149.52 v1(57.18,149.68)
N17535075: length 5.4
  TOP w0.132: J8.16 v1(57.68,152.53)
  BOTTOM w0.132: RN9.4 57.34,149.03 57.68,149.37 57.68,152.53 v1(57.68,152.53)
N17535084: length 2.5
  TOP w0.132: v1(58.18,149.68) J8.17
  BOTTOM w0.132: v1(58.18,149.68) 58.18,149.28 58.18,149.28 58.36,149.1 RN8.1
N17535093: length 5.4
  TOP w0.132: J8.18 v1(58.68,152.53)
  BOTTOM w0.132: RN8.2 58.93,149.09 58.67,149.35 58.68,149.36 v1(58.68,152.53)
N17535102: length 2.6
  TOP w0.132: v1(59.18,149.68) J8.19
  BOTTOM w0.132: v1(59.18,149.68) 59.18,149.35 59.43,149.1 RN8.3
N17535125: length 5.4
  TOP w0.132: J8.20 v1(59.68,152.53)
  BOTTOM w0.132: v1(59.68,152.53) 59.68,149.36 60,149.04 RN8.4
N17535134: length 3
  TOP w0.132: v1(60.18,149.68) J8.21
  BOTTOM w0.132: v1(60.18,149.68) 60.18,149.29 60.68,148.79 61.03,148.79 RN7.1
N17535143: length 6
  TOP w0.132: J8.22 v1(60.68,152.53)
  BOTTOM w0.132: v1(60.68,152.53) 60.68,149.48 60.93,149.22 61.42,149.22 61.6,149.04 RN7.2
N17535152: length 3
  TOP w0.132: v1(61.18,149.68) J8.23
  BOTTOM w0.132: v1(61.18,149.68) 61.52,149.68 62.1,149.1 RN7.3
N17535156: length 5.7
  TOP w0.132: J8.24 v1(61.68,152.53)
  BOTTOM w0.132: RN7.4 62.67,149.93 61.68,150.92 v1(61.68,152.53)
N17535194: length 2.6
  TOP w0.132: J8.27 63.18,146.69 63.5,146.37 R56.2
N17535203: length 2.3
  TOP w0.132: J8.28 v1(63.68,152.53)
  BOTTOM w0.132: v1(63.68,152.53) 63.68,151.69 R355.2
N17535228: length 6.8
  TOP w0.132: J8.33 v1(66.18,146.57)
  BOTTOM w0.132: R365.1 64.09,144.53 U105.4 64.12,145.53 64.9,146.3 65.91,146.3 v1(66.18,146.57)
N18019611: length 85.6
  TOP w0.132: R150.1 v1(172.34,102.87) ; R31.1 205.1,164.87 205.85,164.12 D1.1 205.85,162.52 205.87,162.51 C35.1 v1(205.87,157.23)
  L10-SIGNAL w0.089: v1(205.87,157.23) 205.87,152.4 194.56,141.1 194.56,114.05 192.66,112.14 181.36,112.14 179.45,110.24 179.45,108.08 174.24,102.87 v1(172.34,102.87)
N18021291: length 9.9
  TOP w0.132: R23.2 194.56,156.08 195.1,155.55 Q1.1 196.53,153.23 197.28,152.48 C40.1 R36.2
N18025110: length 2
  TOP w0.132: Q4.D R36.1
N18135987: length 40.4
  TOP w0.132: U42.N25 v1(94.18,47.56)
  L12-SIGNAL w0.089: v1(106.17,14.99) 104.27,14.99 102.62,16.64 101.85,16.64 101.09,17.4 101.09,25.65 96.27,30.48 96.27,34.96 v1(95.67,35.56)
  BOTTOM w0.132: v1(94.18,47.56) 94.59,47.16 94.59,46.6 94.61,46.57 94.61,43.18 95.12,42.67 95.12,36.1 v1(95.67,35.56) ; R698.2 v1(106.17,14.99)
N18135998: length 55.8
  TOP w0.132: U42.AF23 v1(82.98,49.16) ; 59.56,15.75 v1(58.67,15.75)
  L14-SIGNAL w0.109: v1(58.67,15.75) 56.13,18.29 56.13,29.46 55.63,29.97 55.63,32.51 57.02,33.91 57.02,37.47 65.91,46.35 78.11,46.35 80.91,49.16 v1(82.98,49.16)
N18162661: length 13.7
  L14-SIGNAL w0.109: v1(206.12,54.23) 198.75,54.23 198.6,54.08 v1(196.85,54.08)
  BOTTOM w0.132: U126.5 v1(206.12,54.23) ; U127.5 v1(196.85,54.08) R595.2 R594.2
N18162692: length 2.1
  BOTTOM w0.132: C468.1 195.58,54.1 195.9,53.78 U127.4
N18162710: length 12.4
  TOP w0.132: v1(194.31,49.66) 195.58,49.66 SW9.4 SW9.3
  BOTTOM w0.132: R601.2 v1(194.31,49.66) ; R601.2 195.72,50.55 U127.3 ; R601.2 R602.2 R534.2
N18162871: length 2.1
  BOTTOM w0.132: C467.1 204.85,54.23 205.17,53.91 U126.4
N18162895: length 12.1
  TOP w0.132: v1(203.61,55.85) SW8.3 SW8.4 204.85,49.78 v1(203.58,49.78)
  BOTTOM w0.132: U126.3 204.99,50.67 R600.2 v1(203.58,49.78) ; v1(203.61,55.85) 203.58,55.88 R519.2
N18164113: length 1.6
  BOTTOM w0.305: R541.2 114.25,79.71 U122.4
N18519231: length 23.2
  TOP w0.132: U42.C18 v1(102.19,53.16)
  L12-SIGNAL w0.089: v1(102.19,53.16) 104.38,53.16 104.71,53.5 110.08,53.5 110.33,53.24 122.27,53.24 122.94,52.58 v1(123.57,52.58)
  BOTTOM w0.132: R598.2 v1(123.57,52.58)
N18519277: length 25.6
  TOP w0.132: U42.E18 v1(100.59,53.16)
  L14-SIGNAL w0.109: v1(123.57,51.56) 123.17,51.56 122.54,52.2 119.13,52.2 118.11,53.21 110.24,53.21 109.94,53.51 106.47,53.51 105.72,52.76 102.02,52.76 102.02,52.76 100.99,52.76 v1(100.59,53.16)
  BOTTOM w0.132: v1(123.57,51.56) R599.2
N18519299: length 26.3
  TOP w0.132: U42.F19 v1(99.79,52.36)
  BOTTOM w0.132: R593.2 121.03,53.59 119.13,51.69 110.24,51.69 110.07,51.52 105.3,51.52 104.86,51.96 100.18,51.96 v1(99.79,52.36)
N18519321: length 20.5
  TOP w0.132: U42.C23 v1(102.19,49.16)
  BOTTOM w0.132: v1(102.19,49.16) 103.87,49.16 105.92,47.12 113.67,47.12 115.06,45.72 120.03,45.72 120.15,45.85 R611.2
N18551205: length 9.3
  TOP w0.132: U42.W3 v1(88.58,65.96)
  BOTTOM w0.132: v1(88.58,65.96) 88.99,66.37 88.99,72.94 88.39,73.53 R525.1
N18551238: length 9.5
  TOP w0.132: U42.AC3 v1(85.38,65.97)
  BOTTOM w0.132: v1(85.38,65.97) 85.38,67.25 86.23,68.1 86.23,73.03 85.72,73.53 R527.1
N18580498: length 5.5
  TOP w0.132: U51.1 115.81,42.43 116.08,42.16 116.08,40.89 115.21,40.03 U54.1 v1(114.43,39.51)
  BOTTOM w0.132: R643.2 114.44,39.5 v1(114.43,39.51)
N18580530: length 1.6
  TOP w0.132: R272.2 118.36,38.23 118.34,38.21 U54.4
N18580585: length 1.4
  TOP w0.132: R265.2 117.77,41.19 117.72,41.13 U51.4
N18582457: length 12.1
  TOP w0.132: U42.F21 v1(99.79,50.76)
  BOTTOM w0.132: R624.2 106.17,47.62 103.44,50.36 100.18,50.36 v1(99.79,50.76)
N18586695: length 16.8
  TOP w0.132: R580.2 v1(117.22,61.09) ; U42.B13 v1(102.99,57.96)
  L7-SIGNAL w0.089: v1(102.99,57.96) 103.44,58.42 104.78,58.42 105.71,59.35 107.87,59.35 108.15,59.63 110.18,59.63 111.12,60.58 116.71,60.58 v1(117.22,61.09)
N18586717: length 26.4
  TOP w0.132: U42.C13 v1(102.18,57.96)
  L12-SIGNAL w0.089: v1(102.18,57.96) 102.6,57.55 104.69,57.55 105.28,58.13 106.33,58.13 106.42,58.22 106.42,58.84 106.51,58.93 106.78,58.93 106.86,58.84 106.86,58.22 106.95,58.13 107.22,58.13 107.31,58.22 107.31,58.84 107.4,58.93 107.66,58.93 107.75,58.84 107.75,58.22 107.84,58.13 123.13,58.13 v1(123.83,57.44)
  BOTTOM w0.132: R582.2 123.95,57.53 123.86,57.44 v1(123.83,57.44)
N18586871: length 23.7
  TOP w0.132: U42.C12 v1(102.19,58.76) ; R209.2 v1(123.83,58.8)
  L12-SIGNAL w0.089: v1(123.83,58.8) 123.44,58.8 123.31,58.67 109.32,58.67 108.69,59.31 108.64,59.31 108.63,59.32 104.88,59.32 103.95,58.38 102.57,58.38 v1(102.19,58.76)
N18586893: length 15.2
  TOP w0.132: U42.A12 103.7,58.67 105.41,58.67 105.9,58.19 115.72,58.19 116.71,59.18 R213.2
N18586939: length 26.2
  TOP w0.132: U42.F12 v1(99.79,58.76)
  BOTTOM w0.132: v1(99.79,58.76) 100.19,58.36 119.19,58.36 121.03,60.2 R583.2
N18586956: length 25.6
  TOP w0.132: v1(123.06,57.53) 123.44,57.91 R218.2 ; U42.E14 v1(100.59,57.16)
  L14-SIGNAL w0.109: v1(100.59,57.16) 100.98,57.56 105,57.56 105.41,57.15 118.75,57.15 119.63,58.04 122.56,58.04 v1(123.06,57.53)
N18587563: length 18.2
  TOP w0.132: U42.E15 v1(100.59,55.56)
  L14-SIGNAL w0.109: v1(100.59,55.56) 101.03,56.01 105.41,56.01 105.54,55.88 116.28,55.88 116.29,55.9 117.46,55.9 TP65.1
N18587580: length 22.7
  TOP w0.132: U42.A18 104.14,53.56 105.74,55.16 114.13,55.16 114.81,54.48 118.62,54.48 119.55,53.55 120.08,53.55 120.78,53.55 120.84,53.61 122.25,53.61 122.35,53.51 123.36,53.51 123.95,54.1 R231.2
N18587589: length 15.1
  TOP w0.132: U42.A19 v1(103.79,52.36)
  L14-SIGNAL w0.109: TP75.1 117.47,52.32 110.49,52.32 110.15,52.66 106.38,52.66 106.08,52.36 v1(103.79,52.36)
N18587966: length 23.9
  TOP w0.132: R221.2 124.08,54.86 123.06,53.85 122.49,53.85 122.39,53.94 120.7,53.94 120.64,53.89 119.72,53.89 118.75,54.86 114.93,54.86 114.3,55.5 105.6,55.5 104.07,53.96 102.99,53.96 U42.B17
N18587983: length 27
  TOP w0.132: U42.F13 v1(99.79,57.96)
  BOTTOM w0.132: R214.1 124,59.31 123.99,59.29 123.08,59.29 122.55,59.82 121.16,59.82 119.25,57.91 116.71,57.91 115.93,57.13 108.94,57.13 108.84,57.02 105.16,57.02 104.62,57.56 100.19,57.56 v1(99.79,57.96)
N18588000: length 23.5
  TOP w0.132: R228.1 122.3,53.09 122.11,53.27 120.98,53.27 120.92,53.22 119.95,53.22 117.98,53.22 117.09,54.1 114.68,54.1 114.05,54.74 105.79,54.74 104.21,53.16 102.99,53.16 U42.B18
N18588017: length 24.6
  TOP w0.132: U42.C16 v1(102.18,54.76)
  L12-SIGNAL w0.089: v1(102.18,54.76) 102.4,54.55 102.55,54.55 102.73,54.37 104.02,54.37 105.03,55.37 115.7,55.37 116.56,56.24 119.66,56.24 120.9,54.99 123.44,54.99 v1(123.83,55.37)
  BOTTOM w0.132: R586.1 124.08,55.63 v1(123.83,55.37)
N18588440: length 98.1
  TOP w0.132: U42.AA3 v1(86.98,65.97)
  L10-SIGNAL w0.089: v1(86.98,65.97) 86.98,69.99 85.72,71.25 83.69,71.25 83.56,71.12 83.56,68.2 83.43,68.07 83.24,68.07 83.11,68.2 83.11,71.12 82.98,71.25 82.8,71.25 82.67,71.12 82.67,68.2 82.54,68.07 82.36,68.07 82.23,68.2 82.23,71.12 82.1,71.25 81.91,71.25 81.78,71.12 81.78,68.2 81.65,68.07 81.47,68.07 81.34,68.2 81.34,71.12 81.21,71.25 80.41,71.25 80.28,71.38 80.28,73.02 80.15,73.15 79.97,73.15 79.84,73.02 79.84,71.38 79.71,71.25 78.35,71.25 78.22,71.38 78.22,72.13 78.09,72.26 77.91,72.26 77.78,72.13 77.78,71.38 77.65,71.25 77.46,71.25 77.33,71.38 77.33,72.13 77.2,72.26 77.02,72.26 76.89,72.13 76.89,71.38 76.76,71.25 76.56,71.25 76.43,71.38 76.43,72.77 76.3,72.9 76.11,72.9 75.98,72.77 75.98,71.38 75.85,71.25 75.59,71.25 75.46,71.38 75.46,71.62 75.33,71.75 75.14,71.75 75.01,71.62 75.01,71.38 74.88,71.25 74.52,71.25 74.39,71.38 74.39,72.77 74.26,72.9 74.08,72.9 73.95,72.77 73.95,71.38 73.82,71.25 73.63,71.25 73.5,71.38 73.5,72.77 73.37,72.9 73.19,72.9 73.06,72.77 73.06,71.38 72.93,71.25 72.14,71.25 71.63,71.75 71.63,72.83 71.5,72.96 69.09,72.96 68.96,73.09 68.96,73.28 69.09,73.41 71.5,73.41 71.63,73.54 71.63,73.72 71.5,73.85 69.09,73.85 68.96,73.98 68.96,74.16 69.09,74.3 71.5,74.3 71.63,74.43 71.63,74.61 71.5,74.74 69.09,74.74 68.96,74.87 68.96,75.05 69.09,75.18 71.5,75.18 71.63,75.31 71.63,75.5 71.5,75.63 69.09,75.63 68.96,75.76 68.96,75.94 69.09,76.07 71.5,76.07 71.63,76.2 71.63,76.39 71.5,76.52 69.09,76.52 68.96,76.65 68.96,76.83 69.09,76.96 71.5,76.96 71.63,77.09 71.63,77.28 71.5,77.41 69.09,77.41 68.96,77.54 68.96,77.72 69.09,77.85 71.5,77.85 71.63,77.98 71.63,81.53 v1(70.99,82.17)
  BOTTOM w0.132: v1(70.99,82.17) R539.1 R535.1
N18588483: length 88.8
  TOP w0.132: U42.AB6 v1(86.18,63.56)
  L5-SIGNAL w0.089: v1(70.99,79.12) 70.99,77.22 72.01,76.2 73.44,76.2 73.57,76.33 73.57,81.91 73.7,82.04 73.88,82.04 74.02,81.91 74.02,76.33 74.15,76.2 74.33,76.2 74.46,76.33 74.46,81.91 74.59,82.04 74.77,82.04 74.9,81.91 74.9,76.33 75.03,76.2 75.22,76.2 75.35,76.33 75.35,81.91 75.48,82.04 75.66,82.04 75.79,81.91 75.79,76.33 75.92,76.2 76.11,76.2 76.24,76.33 76.24,81.91 76.37,82.04 76.55,82.04 76.68,81.91 76.68,76.33 76.81,76.2 77.03,76.2 77.16,76.33 77.16,79.12 77.29,79.25 77.47,79.25 77.6,79.12 77.6,76.33 77.73,76.2 77.92,76.2 78.05,76.33 78.05,79.12 78.18,79.25 78.36,79.25 78.49,79.12 78.49,76.33 78.62,76.2 78.84,76.2 78.97,76.33 78.97,77.34 79.1,77.47 79.28,77.47 79.41,77.34 79.41,76.33 79.54,76.2 82.8,76.2 85.79,73.21 85.79,63.95 v1(86.18,63.56)
  BOTTOM w0.132: R542.1 v1(70.99,79.12)
N18588505: length 99.1
  TOP w0.132: U42.AB3 v1(86.18,65.97)
  L10-SIGNAL w0.089: v1(70.99,80.14) 69.34,80.14 67.82,78.61 67.82,78.41 67.69,78.28 66.17,78.28 66.04,78.15 66.04,77.97 66.17,77.83 67.69,77.83 67.82,77.7 67.82,77.52 67.69,77.39 66.17,77.39 66.04,77.26 66.04,77.08 66.17,76.95 67.69,76.95 67.82,76.82 67.82,76.63 67.69,76.5 66.17,76.5 66.04,76.37 66.04,76.19 66.17,76.06 67.69,76.06 67.82,75.93 67.82,75.74 67.69,75.61 66.17,75.61 66.04,75.48 66.04,75.3 66.17,75.17 67.69,75.17 67.82,75.04 67.82,74.85 67.69,74.72 66.17,74.72 66.04,74.59 66.04,74.41 66.17,74.28 67.69,74.28 67.82,74.15 67.82,73.96 67.69,73.83 66.17,73.83 66.04,73.7 66.04,73.52 66.17,73.39 67.69,73.39 67.82,73.26 67.82,73.08 67.69,72.95 66.17,72.95 66.04,72.82 66.04,72.63 66.17,72.5 70.37,72.5 70.74,72.14 70.74,67.94 73.53,65.15 73.77,65.15 73.9,65.28 73.9,67.18 74.03,67.31 74.22,67.31 74.35,67.18 74.35,65.28 74.48,65.15 74.66,65.15 74.79,65.28 74.79,67.18 74.92,67.31 75.11,67.31 75.24,67.18 75.24,65.28 75.37,65.15 75.55,65.15 75.68,65.28 75.68,67.18 75.81,67.31 75.99,67.31 76.12,67.18 76.12,65.28 76.26,65.15 76.44,65.15 76.57,65.28 76.57,70.1 76.7,70.23 76.88,70.23 77.01,70.1 77.01,65.28 77.14,65.15 77.33,65.15 77.46,65.28 77.46,70.1 77.59,70.23 77.77,70.23 77.9,70.1 77.9,65.28 78.03,65.15 78.22,65.15 78.35,65.28 78.35,67.18 78.48,67.31 78.66,67.31 78.79,67.18 78.79,65.28 78.92,65.15 79.11,65.15 79.24,65.28 79.24,67.18 79.37,67.31 79.55,67.31 79.68,67.18 79.68,65.28 79.81,65.15 80.52,65.15 80.92,65.55 85.77,65.55 v1(86.18,65.97)
  BOTTOM w0.132: R536.1 R540.1 v1(70.99,80.14)
N18588548: length 88.9
  TOP w0.132: U42.AA4 v1(86.98,65.16)
  L5-SIGNAL w0.089: v1(72.9,77.09) 71.88,77.09 71.63,77.34 71.63,80.45 71.76,80.58 72.39,80.58 72.52,80.71 72.52,80.9 72.39,81.03 71.76,81.03 71.63,81.16 71.63,81.34 71.76,81.47 72.39,81.47 72.52,81.6 72.52,81.78 72.39,81.92 71.76,81.92 71.63,82.05 71.63,82.23 71.76,82.36 72.39,82.36 72.52,82.49 72.52,82.67 72.39,82.8 71.76,82.8 71.63,82.93 71.63,83.19 72.01,83.57 72.57,83.57 72.7,83.7 72.7,86.73 72.83,86.86 73.01,86.86 73.14,86.73 73.14,83.7 73.27,83.57 73.45,83.57 73.59,83.7 73.59,86.73 73.72,86.86 73.9,86.86 74.03,86.73 74.03,83.7 74.16,83.57 74.34,83.57 74.47,83.7 74.47,86.73 74.6,86.86 74.79,86.86 74.92,86.73 74.92,83.7 75.05,83.57 75.23,83.57 75.36,83.7 75.36,86.73 75.49,86.86 75.68,86.86 75.81,86.73 75.81,83.7 75.94,83.57 76.12,83.57 76.25,83.7 76.25,86.73 76.38,86.86 76.57,86.86 76.7,86.73 76.7,83.7 76.83,83.57 77.01,83.57 77.14,83.7 77.14,86.73 77.27,86.86 77.46,86.86 77.59,86.73 77.59,83.7 77.72,83.57 77.9,83.57 78.03,83.7 78.03,86.73 78.16,86.86 78.34,86.86 78.47,86.73 78.47,81.55 86.23,73.79 86.23,67.31 86.59,66.95 86.59,65.55 v1(86.98,65.16)
  BOTTOM w0.132: R543.1 R190.1 v1(72.9,77.09)
N18603445: length 10.1
  TOP w0.132: RU24.2 v1(162.56,52.83) ; v1(154.43,53.09) 154.69,53.34 R229.2
  L14-SIGNAL w0.109: v1(162.56,52.83) 162.18,52.45 161.67,52.45 161.04,53.09 v1(154.43,53.09)
N18603451: length 13.1
  TOP w0.132: R223.2 v1(154.43,54.86) ; RU25.2 v1(165.23,52.83)
  L14-SIGNAL w0.109: v1(154.43,54.86) 155.32,54.86 156.79,53.4 164.66,53.4 v1(165.23,52.83)
N18608535: length 15.5
  TOP w0.132: U42.A25 104.34,47.96 104.8,47.5 106.2,47.5 109.68,44.03 116.79,44.03 116.83,44.07 R255.2
N18608628: length 22.3
  TOP w0.132: U42.A17 103.6,54.36 103.61,54.35 103.96,54.35 105.53,55.92 115.48,55.92 116.46,56.9 120.4,56.9 120.65,57.15 122.68,57.15 122.81,57.02 R224.1
N19619900: length 2.9
  TOP w0.132: Q16.5 156.21,60.2 156.08,60.07 v1(156.08,59.69) 156.23,59.55 Q16.6
  BOTTOM w0.132: R707.1 v1(156.08,59.69)
N20276117: length 1.7
  TOP w0.132: U140.4 21.26,29.51 21.59,29.84 22.1,29.84
N20585139: length 17.3
  TOP w0.132: U141.9 46.16,120.04 v1(46.05,119.92) ; RJ16.2 v1(59.18,116.84)
  L14-SIGNAL w0.109: v1(46.05,119.92) 46.07,119.92 48.01,117.98 55.63,117.98 56.77,116.84 v1(59.18,116.84)
  BOTTOM w0.132: R714.2 46.4,120.27 v1(46.05,119.92)
N20585277: length 2.4
  TOP w0.132: R716.2 54.48,114.94 54.48,115.95 54.31,116.12 U141.24
N20585453: length 7.4
  TOP w0.132: U141.38 53.81,127.47 R717.2 54.36,128.52 54.61,128.78 v1(55.88,128.78) C689.1
  BOTTOM w0.132: Y8.1 56.21,129.11 v1(55.88,128.78)
N20585465: length 6.9
  TOP w0.132: C690.1 v1(52.07,128.78) 53.09,128.78 53.34,128.52 R717.1 53.34,126.56 53.31,126.54 U141.39
  BOTTOM w0.132: Y8.2 51.74,129.11 v1(52.07,128.78)
N20587089: length 2.8
  TOP w0.132: U141.10 46.38,119.53 46.23,119.38 45.73,119.38 v1(45.7,119.36)
  BOTTOM w0.132: R719.1 45.81,119.25 v1(45.7,119.36)
N20589015: length 2.3
  TOP w0.132: U141.36 v1(57.23,124.03)
  BOTTOM w0.132: R722.2 57.19,124.08 v1(57.23,124.03)
N20589055: length 2.3
  TOP w0.132: U141.8 46.01,120.54 v1(45.97,120.58)
  BOTTOM w0.132: v1(45.97,120.58) 45.66,120.27 R724.1
N20595711: length 8.8
  TOP w0.132: TP94.1 47.75,126.75 45.53,124.53 45.53,123.9 45.89,123.54 U141.2
  BOTTOM w0.132: R726.1 TP94.1
N20595725: length 10.8
  TOP w0.132: U141.3 45.87,123.04 45.25,123.66 45.25,124.88 46.99,126.62 46.99,129.41 TP95.1
  BOTTOM w0.132: R727.1 TP95.1
N20609618: length 2.2
  TOP w0.132: U141.22 v1(53.31,115.7)
  BOTTOM w0.132: v1(53.31,115.7) 53.09,115.92 R725.2
N20753097: length 2.6
  TOP w0.132: v2(5,161.45) P5.16
  BOTTOM w0.132: R322.1 4.1,161.45 v2(5,161.45)
N20753149: length 2.5
  TOP w0.132: P5.25 v2(7.39,165.45)
  BOTTOM w0.132: v2(7.39,165.45) 7.42,165.48 R316.2
N20753966: length 5.2
  TOP w0.254: U3.19 164.22,165.34 164.08,165.48 C10.1
  TOP w0.508: v2(163.07,166.37) C10.1 161.8,165.48 ; L2.2 v2(171.58,168.91)
N20753978: length 3.4
  TOP w0.381: 168.54,170.31 C4.1 ; C4.1 169.04,169.81 ; C4.1 169.04,170.8 ; 168.41,169.66 L2.1 168.41,168.16
N21029046: length 2.7
  TOP w0.132: v1(52.32,115.57) 52.81,116.06 U141.21
  BOTTOM w0.132: v1(52.32,115.57) 52.07,115.82 R731.2
N21030069: length 4.6
  TOP w0.132: U141.35 v1(57.75,123.54)
  BOTTOM w0.132: v1(57.75,123.54) 57.75,124.24 R732.2
N21067838: length 3.2
  TOP w0.132: 35.18,51.31 35.17,51.31 35.17,52.07 ; 35.17,52.07 35.43,52.07 35.67,52.31 U146.8 ; 35.17,52.07 U146.7
N21093937: length 39.1
  BOTTOM w0.132: 71.32,95.94 71.53,96.14 72.14,96.14 72.32,95.95 ; 71.32,95.94 RU17.24 ; 71.32,95.94 71.12,96.14 70.55,96.14 70.32,95.92 ; 79.82,96.28 78.37,96.28 78.23,96.14 ; 79.82,96.28 80.01,96.47 80.62,96.47 80.82,96.27 ; 79.82,96.28 RU17.7 ; RU17.26 70.32,95.92 ; 70.32,95.92 70.1,96.14 69.57,96.14 69.32,95.89 RU17.28 69.31,94.02 R515.1 ; 76.32,95.89 76.57,96.14 77.07,96.14 77.32,95.89 ; 76.32,95.89 RU17.14 ; 76.32,95.89 76.07,96.14 75.59,96.14 75.32,95.87 ; 80.82,96.27 81.03,96.47 81.46,96.47 81.82,96.11 RU17.3 ; 80.82,96.27 RU17.5 ; RU17.12 77.32,95.89 ; 77.32,95.89 77.57,96.14 78.23,96.14 ; 78.23,96.14 78.23,95.69 78.32,95.6 RU17.10 ; 72.32,95.95 RU17.22 ; 72.32,95.95 72.51,96.14 73.07,96.14 73.32,95.89 ; 75.32,95.87 75.06,96.14 73.58,96.14 73.32,95.89 ; 75.32,95.87 RU17.16 ; 73.32,95.89 RU17.20
N21350306: length 1.9
  TOP w0.132: SW10.3 v1(219.2,91.44)
  BOTTOM w0.132: R750.2 v1(219.2,91.44)
N21350307: length 1.9
  TOP w0.132: SW10.4 v1(219.2,92.71)
  BOTTOM w0.132: R749.2 v1(219.2,92.71)
N21350308: length 1.9
  TOP w0.132: SW10.1 v1(219.2,88.9)
  BOTTOM w0.132: R752.2 v1(219.2,88.9)
N21350309: length 1.9
  TOP w0.132: SW10.2 v1(219.2,90.17)
  BOTTOM w0.132: R751.2 v1(219.2,90.17)
N21412134: length 1.4
  TOP w0.132: Q19.3 190.21,64.6 v1(190.12,64.52)
  BOTTOM w0.132: v1(190.12,64.52) 190.5,64.9 R753.1
N21412457: length 3
  TOP w0.132: Q19.6 192.04,63.27 191.8,63.5 v1(191.39,63.5) Q19.5
  BOTTOM w0.132: R754.1 v1(191.39,63.5)
N21462852: length 2
  TOP w0.132: R215.1 133.61,60.83 133.62,60.82 U40.3
N21464065: length 10.7
  TOP w0.132: v1(215.83,132.91) 215.41,132.91 215.36,132.97 211.92,132.97 211.66,132.72 210.63,132.72 v1(209.62,133.73)
  BOTTOM w0.132: U113.7 v1(215.83,132.91) ; v1(209.62,133.73) U114.1 208.97,134.8 R429.2
N21464089: length 15.4
  TOP w0.132: v1(212.47,134.8) 213.44,135.76 216.45,135.76 216.92,135.3 SW5.4 SW5.3 v1(216.92,127.25)
  BOTTOM w0.132: v1(216.92,127.25) 217.13,127.47 R444.2 ; U114.3 v1(212.47,134.8)
N21464106: length 14.6
  TOP w0.132: U16.1 210.04,126.76 210.44,126.36 217.36,126.36 v1(218.12,127.13)
  BOTTOM w0.132: v1(218.12,127.13) 218.12,129.1 217.13,130.09 U113.5
N21464815: length 8.5
  TOP w0.132: D24.1 198.7,128.19 198.88,128.02 199.6,128.02 U147.5 199.64,128.01 v1(199.64,128.68) ; Q18.2 v1(199.14,130.43)
  BOTTOM w0.132: R742.1 199.52,130.81 v1(199.14,130.43) 199.14,129.18 v1(199.64,128.68) R744.1 C712.1
N21464817: length 3.3
  TOP w0.132: Q18.5 199.14,133.75 198.9,133.99 198.5,133.99 v1(198.49,133.97) Q18.6
  BOTTOM w0.132: R743.1 198.37,133.86 v1(198.49,133.97)
N167702540: length 1
  BOTTOM w0.508: R480.2 C348.1
N167712620: length 1
  BOTTOM w0.254: R476.2 C349.1
N168882401: length 2.6
  TOP w0.132: v2(217.5,62.92) 216.59,62.92 DS5.2
  BOTTOM w0.132: R517.2 v2(217.5,62.92)
N168882481: length 2.6
  TOP w0.132: DS4.2 216.59,64.95 v2(217.5,64.95)
  BOTTOM w0.132: R510.2 v2(217.5,64.95)
N168882561: length 2.6
  TOP w0.132: DS3.2 216.59,66.98 v2(217.5,66.98)
  BOTTOM w0.132: R507.2 v2(217.5,66.98)
N168882641: length 2.6
  TOP w0.132: v2(217.5,69.01) 216.59,69.01 DS2.2
  BOTTOM w0.132: R504.2 v2(217.5,69.01)
N207539901: length 2.6
  TOP w0.132: DS6.2 v1(208.81,172.24)
  BOTTOM w0.132: v1(208.81,172.24) 208.97,172.09 R713.2
N1746820385: length 10.5
  TOP w0.132: U42.E6 v1(100.59,63.56)
  BOTTOM w0.132: v1(100.59,63.56) 100.98,63.96 103.33,63.96 104.39,65.02 105.54,65.02 107.82,67.31 R556.2
N1746820386: length 10.9
  TOP w0.132: U42.C1 101.8,67.18 101.8,69.27 101.35,69.72 101.35,73.91 100.71,74.55 R176.2
N1746820387: length 12
  TOP w0.132: U42.C2 102.18,66.76 102.18,69.16 102.62,69.6 102.62,73.66 101.6,74.68 R178.2
N1746820388: length 8.7
  TOP w0.132: U42.C3 v1(102.19,65.97)
  BOTTOM w0.132: R554.2 108.2,68.33 105.45,65.57 102.58,65.57 v1(102.19,65.97)
N1746820389: length 11.7
  TOP w0.132: R177.2 102.49,74.55 103.03,74.01 103.03,67.65 102.98,67.59 102.98,66.76 U42.B2
N1746820390: length 8
  TOP w0.132: R558.2 107.57,67.82 104.12,64.36 102.99,64.36 U42.B5

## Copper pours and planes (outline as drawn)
GND on TOP (solid shape): 21.21,30.23 17.91,30.23 17.91,31.75 21.21,31.75
GND on TOP (solid shape): 113.41,76.96 110.11,76.96 110.11,79.5 113.41,79.5
GND on TOP (solid shape): 3.17,90.55 3.17,73.91 0.51,73.91 0.51,91.06 2.67,91.06
GND on BOTTOM (solid shape): 21.21,29.72 17.91,29.72 17.91,32.26 21.21,32.26
GND on BOTTOM (solid shape): 113.41,77.47 110.11,77.47 110.11,78.99 113.41,78.99
GND on TOP: 131.95,68.96 132.97,69.98 134.37,69.98 134.62,69.72 134.62,65.53 137.16,65.53 137.41,65.79 137.67,65.79 137.92,65.53 140.46,65.53 140.59,65.66 140.59,69.72 140.84,69.98 142.62,69.98 143.26,69.34 143.26,65.28 143,65.02 140.72,65.02 140.59,64.9 137.92,64.9 137.67,64.64 137.41,64.64 137.16,64.9 132.72,64.9 131.95,65.66
GND on TOP: 131.95,51.18 132.97,50.16 134.37,50.16 134.62,50.42 134.62,54.61 137.16,54.61 137.41,54.36 137.67,54.36 137.92,54.61 140.59,54.61 140.59,50.42 140.84,50.16 142.62,50.16 143.26,50.8 143.26,54.86 142.88,55.24 137.92,55.24 137.67,55.5 137.41,55.5 137.16,55.24 132.72,55.24 131.95,54.48
GND on TOP: 191.26,98.81 194.69,98.81 194.69,102.36 194.31,102.74 191.64,102.74 191.26,102.36
GND on TOP: 191.26,92.46 194.69,92.46 194.69,96.01 194.31,96.39 191.64,96.39 191.26,96.01
GND on TOP: 138.68,59.94 143.26,59.94 143.64,59.56 143.64,58.29 143.13,57.78 141.86,57.78 141.35,58.29 141.35,59.18 140.84,59.69 136.4,59.69 136.4,60.07 136.27,60.2 135.38,60.2 135.38,60.45 138.68,60.45
GND on BOTTOM: 149.1,21.46 149.48,21.08 149.48,18.67 149.35,18.54 149.35,18.03 149.73,17.65 151.26,17.65 152.53,18.92 155.19,18.92 155.57,18.54 155.57,15.24 154.31,13.97 145.8,13.97 145.41,13.59 145.41,10.79 158.24,10.79 160.4,12.95 160.4,21.21 159.38,22.23 155.57,22.23 154.69,21.34 152.02,21.34 150.62,22.73 149.86,22.73 149.86,25.53 148.97,25.53 148.97,26.8 151,28.83 151,31.62 150.75,31.88 149.48,31.88 149.22,31.62 149.22,27.69 148.72,27.18 148.72,25.53 147.32,25.53 147.32,22.99 149.1,22.99
GND on BOTTOM: 152.4,25.27 153.42,25.27 153.8,24.89 153.8,23.75 153.54,23.5 153.03,23.5 152.91,23.37 152.91,21.72 153.03,21.59 154.05,21.59 155.32,22.86 155.32,27.18 154.81,27.69 153.42,27.69 152.4,26.67
GND on BOTTOM: 160.4,67.44 160.4,68.71 160.15,68.96 160.15,70.87 159.64,71.37 159.64,74.17 159.77,74.3 160.66,74.3 160.91,74.04 160.91,73.03 161.16,72.77 162.43,72.77 162.69,73.03 162.69,73.66 165.35,73.66 165.86,74.17 166.5,74.17 166.88,73.79 166.88,66.67 162.31,66.67 161.42,65.79 159.77,65.79 159.38,66.17 159.38,67.06 159.77,67.44
GND on BOTTOM: 136.02,40.01 136.02,38.1 134.87,38.1 134.62,37.85 133.48,37.85 133.22,37.59 133.22,36.58 133.6,36.2 136.14,36.2 136.78,36.83 136.78,40.01
GND on L2-GND1, L4-GND2: 0.69,10.84 0.69,179.58 220.22,179.58 220.22,10.84
GND on L6-GND3, L11-GND4, L13-GND5: 0.69,10.84 220.22,10.84 220.22,179.58 0.69,179.58
GND on L15-GND6: 0.56,10.72 0.56,179.7 220.34,179.7 220.34,10.72
VBUS_USB1 on TOP: 23.62,167.13 23.37,167.39 21.34,167.39 21.08,167.13 21.08,164.34 21.72,163.7 24,163.7 24.51,164.21 24.51,165.1 23.62,165.99
VBUS_USB1 on BOTTOM: 5.46,88.77 5.46,86.61 3.81,86.61 3.81,87.5 4.45,88.14 4.45,88.77
